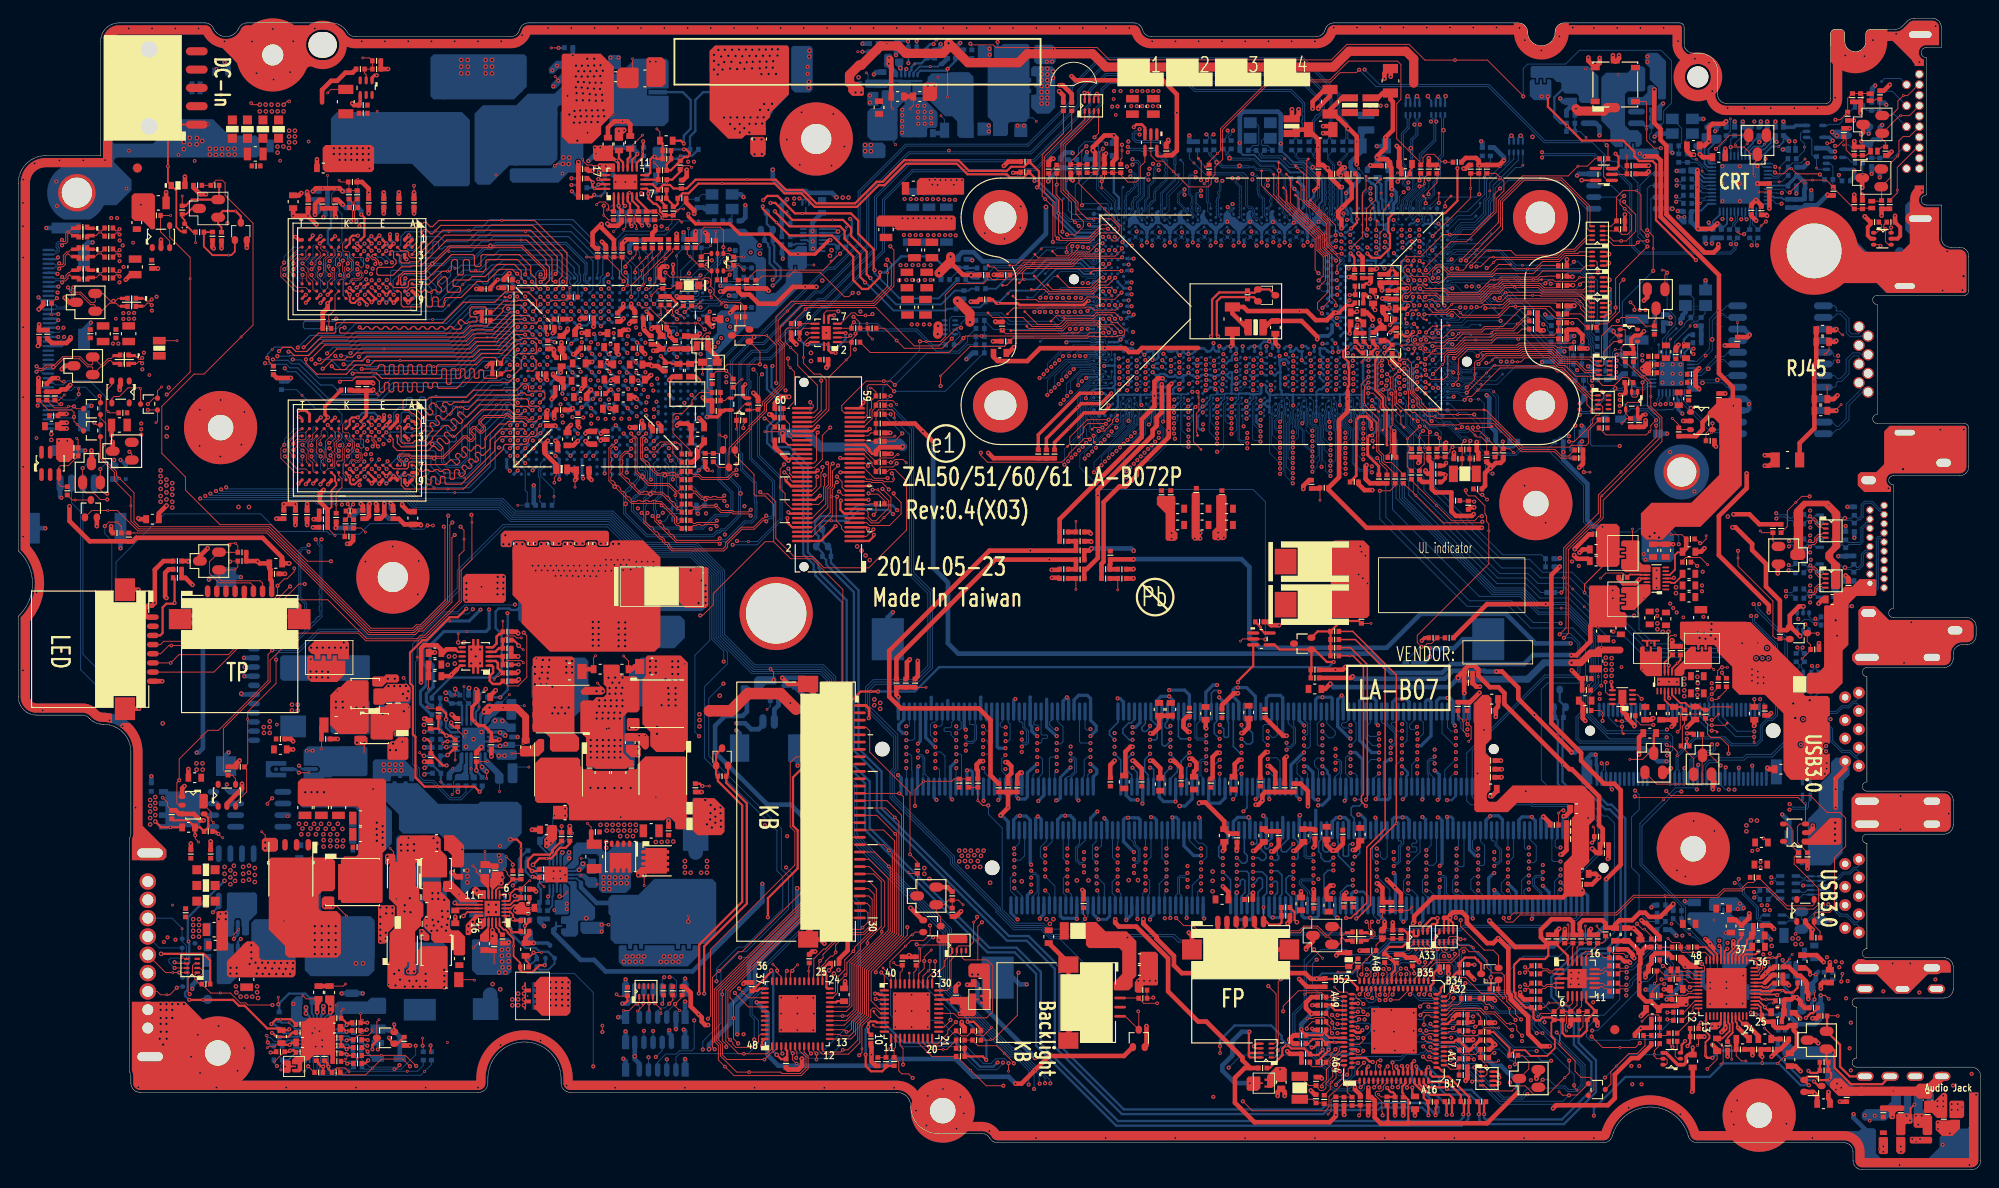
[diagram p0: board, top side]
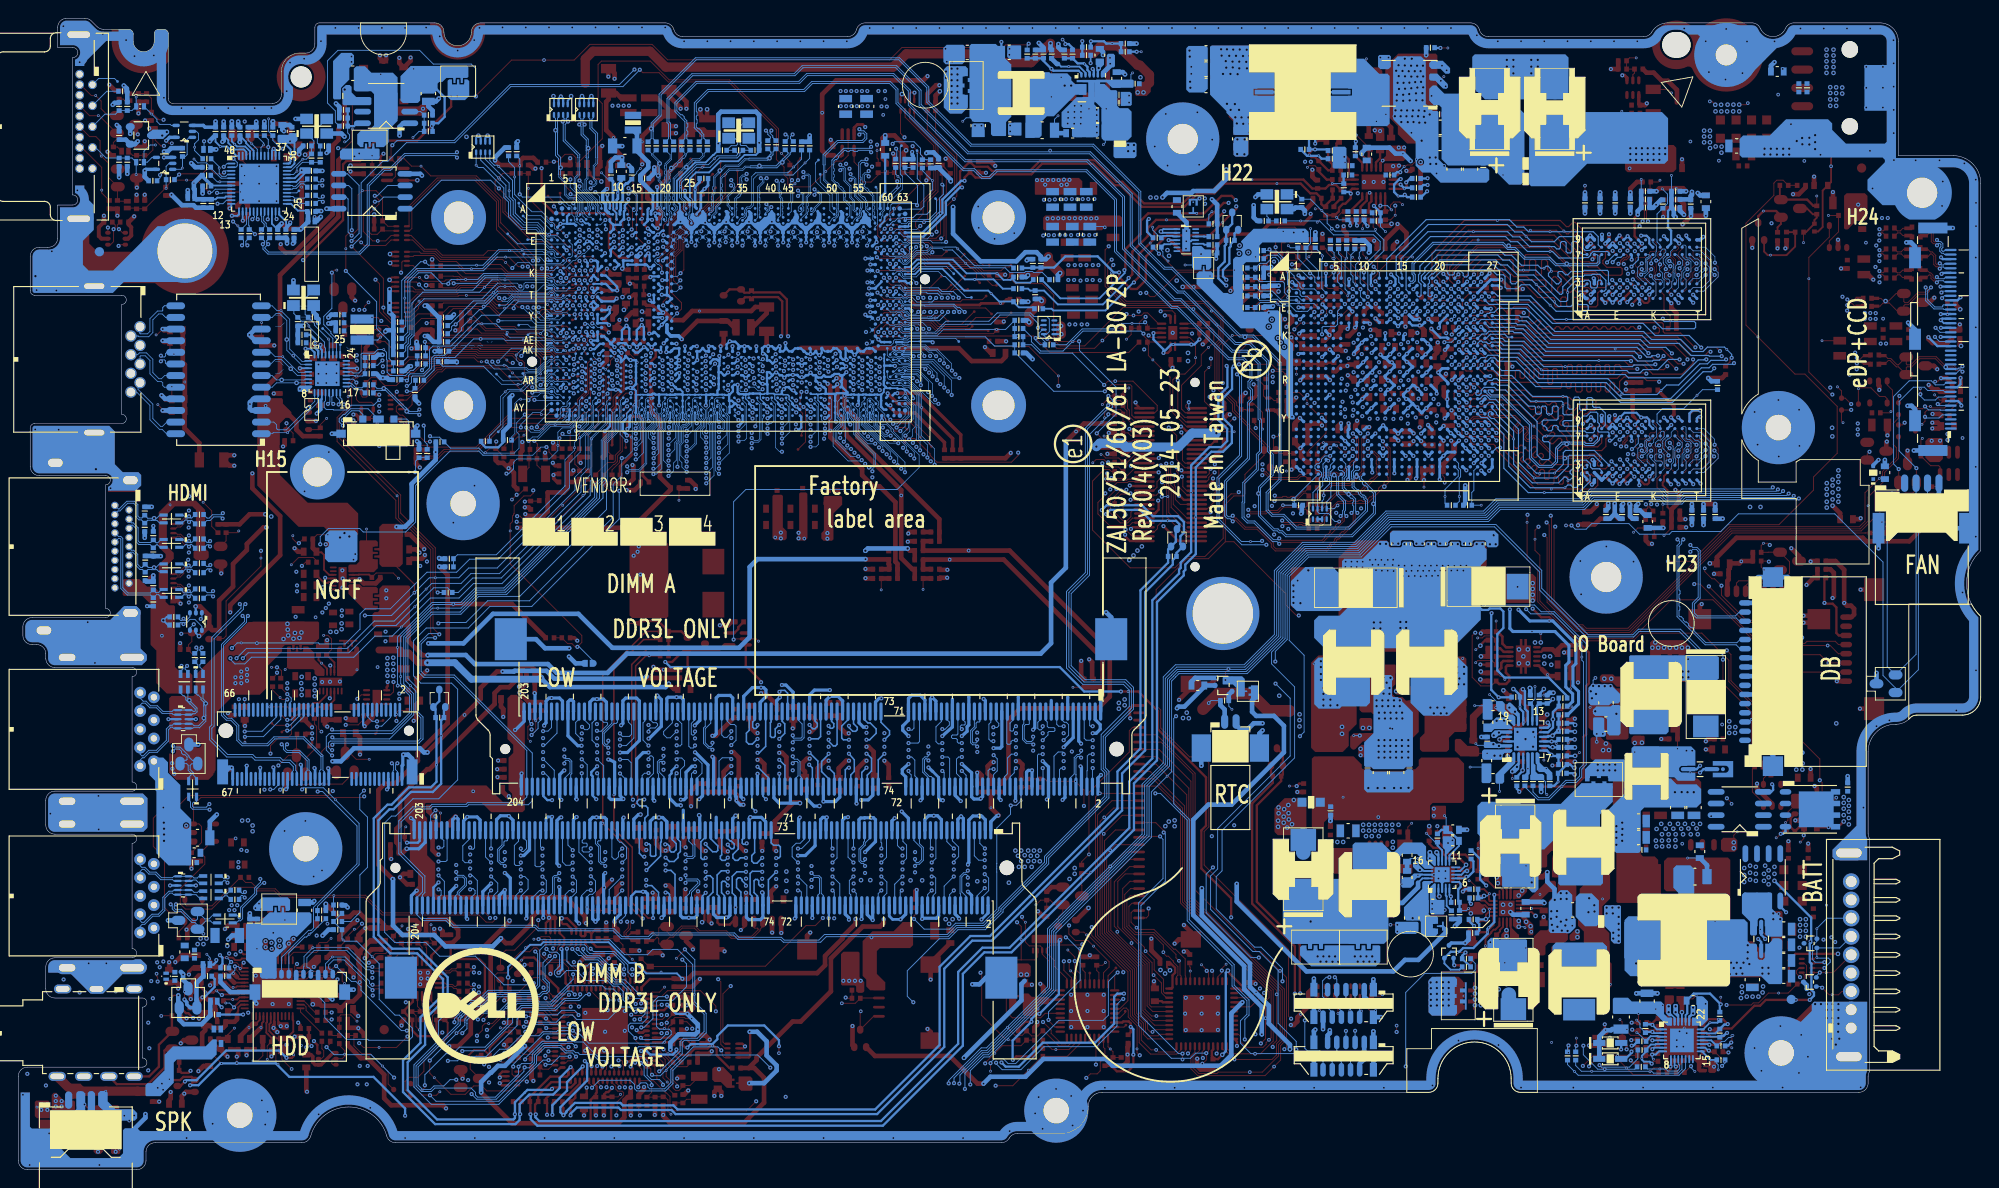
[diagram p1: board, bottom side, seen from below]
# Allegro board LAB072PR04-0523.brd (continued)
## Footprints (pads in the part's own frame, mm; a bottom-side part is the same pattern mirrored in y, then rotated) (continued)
IP4292CZ10-TBR_XSON10_2P5X1
  oval 0.254x0.889 smd: 1(0,0)
  oval 0.254x0.838 smd: 2(0.5,-0.025) 3(1,-0.025) 4(1.5,-0.025) 5(2,-0.025) 6(2,1.125) 7(1.5,1.125) 8(1,1.125) 9(0.5,1.125) 10(0,1.125)
ISL95813HRZ-T_QFN20_3X4
  oval 0.254x0.889 smd: 1(0,0) 2(0.5,0) 3(1,0) 4(1.5,0) 5(2,0) 6(2.5,0) 11(2.5,3.1) 12(2,3.1) 13(1.5,3.1) 14(1,3.1) 15(0.5,3.1) 16(0,3.1)
  oval 0.889x0.254 smd: 7(3.3,0.8) 8(3.3,1.3) 9(3.3,1.8) 10(3.3,2.3) 17(-0.8,2.3) 18(-0.8,1.8) 19(-0.8,1.3) 20(-0.8,0.8)
  rect 2.642x1.651 smd: 21(1.25,1.55)
IT6513FN_QFN48_6X6
  oval 0.203x0.914 smd: 1(0,0) 2(0.4,0) 3(0.8,0) 4(1.2,0) 5(1.6,0) 6(2,0) 7(2.4,0) 8(2.8,0) 9(3.2,0) 10(3.6,0) 11(4,0) 12(4.4,0) 25(4.4,6.075) 26(4,6.075) 27(3.6,6.075) 28(3.2,6.075) 29(2.8,6.075) 30(2.4,6.075) 31(2,6.075) 32(1.6,6.075) 33(1.2,6.075) 34(0.8,6.075) 35(0.4,6.075) 36(0,6.075)
  oval 0.914x0.203 smd: 13(5.237,0.837) 14(5.237,1.237) 15(5.237,1.638) 16(5.237,2.038) 17(5.237,2.437) 18(5.237,2.837) 19(5.237,3.237) 20(5.237,3.638) 21(5.237,4.038) 22(5.237,4.437) 23(5.237,4.837) 24(5.237,5.237) 37(-0.837,5.237) 38(-0.837,4.837) 39(-0.837,4.437) 40(-0.837,4.038) 41(-0.837,3.638) 42(-0.837,3.237) 43(-0.837,2.837) 44(-0.837,2.437) 45(-0.837,2.038) 46(-0.837,1.638) 47(-0.837,1.237) 48(-0.837,0.837)
  rect 4.369x4.369 smd: 49(2.2,3.038)
J-L_TNBNRAC80015008_8P
  round 1.245 hole 0.94: 1(0,0) 2(1.02,-1) 3(2.04,0) 4(3.06,-1) 5(4.08,0) 6(5.1,-1) 7(6.12,0) 8(7.14,-1)
  oval 1.372x2.972 hole 0.61x2.21: 9(-4.43,-5) 10(11.57,-5)
JUMP_43X39
  custom 0.191x0.191 smd: 1(0,0) 2(0.914,0)
JUMP_43X79
  custom 0.188x0.188 smd: 1(0,0) 2(1.1,0)
JUMP_43X118
  custom 0.187x0.187 smd: 1(0,0) 2(1.1,0)
KC_FBMA-L11-201209-221LMA30_2P
  rect 0.838x1.397 smd: 1(0,0) 2(1.65,0)
L2N7002WT1G_SC-70-3
  oval 0.711x0.889 smd: 1(0,0) 2(-0.65,-1.9) 3(0.65,-1.9)
L_5X5X3_M_2P
  rect 2.159x2.794 smd: 1(0,0) 2(4.35,0)
L_7X7X3_M_2P
  rect 2.362x3.505 smd: 1(0,0) 2(6.05,0)
L_10X10X4_M_2P
  rect 3.81x3.988 smd: 1(0,0) 2(9.2,0)
LOTES_APCI0019-P009A_67P
  round 1.092 hole 1.092 unplated: (-0.75,-5.275)
  round 1.6 hole 1.6 unplated: (19.25,-5.275)
  oval 0.305x1.549 smd: 1(0,0) 2(0.25,-7.55) 3(0.5,0) 4(0.75,-7.55) 5(1,0) 6(1.25,-7.55) 7(1.5,0) 8(1.75,-7.55) 9(2,0) 10(2.25,-7.55) 11(2.5,0) 12(2.75,-7.55) 13(3,0) 14(3.25,-7.55) 15(3.5,0) 16(3.75,-7.55) 17(4,0) 18(4.25,-7.55) 19(4.5,0) 20(4.75,-7.55) 21(5,0) 22(5.25,-7.55) 23(5.5,0) 24(7.75,-7.55) 25(8,0) 26(8.25,-7.55) 27(8.5,0) 28(8.75,-7.55) 29(9,0) 30(9.25,-7.55) 31(9.5,0) 32(9.75,-7.55) 33(10,0) 34(10.25,-7.55) 35(10.5,0) 36(10.75,-7.55) 37(11,0) 38(11.25,-7.55) 39(11.5,0) 40(11.75,-7.55) 41(12,0) 42(12.25,-7.55) 43(12.5,0) 44(12.75,-7.55) 45(13,0) 46(13.25,-7.55) 47(13.5,0) 48(13.75,-7.55) 49(14,0) 50(14.25,-7.55) 51(14.5,0) 52(14.75,-7.55) 53(15,0) 54(15.25,-7.55) 55(15.5,0) 56(15.75,-7.55) 57(16,0) 58(16.25,-7.55) 59(16.5,0) 60(16.75,-7.55) 61(17,0) 62(17.25,-7.55) 63(17.5,0) 64(17.75,-7.55) 65(18,0) 66(18.25,-7.55) 67(18.5,0)
  rect 1.194x2.743 smd: 68(-1.1,-0.775) 69(19.6,-0.775)
MC74VHC1G08DFT2G_SC70-5
  oval 0.381x0.711 smd: 1(0,0) 2(0.65,0) 3(1.3,0) 4(1.3,1.9) 5(0,1.9)
MDS1525URH_SO8
  oval 0.635x1.854 smd: 1(0,0) 2(1.27,0) 3(2.54,0) 4(3.81,0) 5(3.81,5.165) 6(2.54,5.165) 7(1.27,5.165) 8(0,5.165)
MDU1511RH_POWERDFN56-8-5
  oval 0.61x1.27 smd: 1(0,0) 2(1.27,0) 3(2.54,0) 4(3.81,0)
  custom 1.105x1.105 smd: 5(1.905,3.715)
MDU1516URH_POWERDFN56-8-5
  oval 0.61x1.27 smd: 1(0,0) 2(1.27,0) 3(2.54,0) 4(3.81,0)
  custom 1.105x1.105 smd: 5(1.905,3.715)
MDV1526URH_PDFN33-8-5
  oval 0.406x0.991 smd: 1(0,0) 2(0.66,0) 3(1.32,0) 4(1.98,0)
  custom 0.559x0.559 smd: 5(0.99,2.248)
MDV1528URH_PDFN33-8-5
  oval 0.406x0.61 smd: 1(0,0) 2(0.65,0) 3(1.3,0) 4(1.95,0)
  custom 0.65x0.65 smd: 5(0.975,1.475)
MEC5085-LZY_DQFN132_11X11
  oval 0.279x0.711 smd: A1(0,0) A2(0.5,0) A3(1,0) A4(1.5,0) A5(2,0) A6(2.5,0) A7(3,0) A8(3.5,0) A9(4,0) A10(4.5,0) A11(5,0) A12(5.5,0) A13(6,0) A14(6.5,0) A15(7,0) A16(7.5,0) A33(7.5,10.9) A34(7,10.9) A35(6.5,10.9) A36(6,10.9) A37(5.5,10.9) A38(5,10.9) A39(4.5,10.9) A40(4,10.9) A41(3.5,10.9) A42(3,10.9) A43(2.5,10.9) A44(2,10.9) A45(1.5,10.9) A46(1,10.9) A47(0.5,10.9) A48(0,10.9)
  oval 0.711x0.279 smd: A17(9.2,1.7) A18(9.2,2.2) A19(9.2,2.7) A20(9.2,3.2) A21(9.2,3.7) A22(9.2,4.2) A23(9.2,4.7) A24(9.2,5.2) A25(9.2,5.7) A26(9.2,6.2) A27(9.2,6.7) A28(9.2,7.2) A29(9.2,7.7) A30(9.2,8.2) A31(9.2,8.7) A32(9.2,9.2) A49(-1.7,9.2) A50(-1.7,8.7) A51(-1.7,8.2) A52(-1.7,7.7) A53(-1.7,7.2) A54(-1.7,6.7) A55(-1.7,6.2) A56(-1.7,5.7) A57(-1.7,5.2) A58(-1.7,4.7) A59(-1.7,4.2) A60(-1.7,3.7) A61(-1.7,3.2) A62(-1.7,2.7) A63(-1.7,2.2) A64(-1.7,1.7)
  oval 0.305x0.61 smd: B1(-0.25,0.85) B2(0.25,0.85) B3(0.75,0.85) B4(1.25,0.85) B5(1.75,0.85) B6(2.25,0.85) B7(2.75,0.85) B8(3.25,0.85) B9(3.75,0.85) B10(4.25,0.85) B11(4.75,0.85) B12(5.25,0.85) B13(5.75,0.85) B14(6.25,0.85) B15(6.75,0.85) B16(7.25,0.85) B17(7.75,0.85) B35(7.75,10.05) B36(7.25,10.05) B37(6.75,10.05) B38(6.25,10.05) B39(5.75,10.05) B40(5.25,10.05) B41(4.75,10.05) B42(4.25,10.05) B43(3.75,10.05) B44(3.25,10.05) B45(2.75,10.05) B46(2.25,10.05) B47(1.75,10.05) B48(1.25,10.05) B49(0.75,10.05) B50(0.25,10.05) B51(-0.25,10.05)
  oval 0.61x0.305 smd: B18(8.35,1.45) B19(8.35,1.95) B20(8.35,2.45) B21(8.35,2.95) B22(8.35,3.45) B23(8.35,3.95) B24(8.35,4.45) B25(8.35,4.95) B26(8.35,5.45) B27(8.35,5.95) B28(8.35,6.45) B29(8.35,6.95) B30(8.35,7.45) B31(8.35,7.95) B32(8.35,8.45) B33(8.35,8.95) B34(8.35,9.45) B52(-0.85,9.45) B53(-0.85,8.95) B54(-0.85,8.45) B55(-0.85,7.95) B56(-0.85,7.45) B57(-0.85,6.95) B58(-0.85,6.45) B59(-0.85,5.95) B60(-0.85,5.45) B61(-0.85,4.95) B62(-0.85,4.45) B63(-0.85,3.95) B64(-0.85,3.45) B65(-0.85,2.95) B66(-0.85,2.45) B67(-0.85,1.95) B68(-0.85,1.45)
  rect 5.004x5.004 smd: C1(3.75,5.45)
MMST3904-7-F_SOT323-3
  oval 0.711x0.889 smd: 1(0,0) 2(0.65,1.9) 3(-0.65,1.9)
MURAT_BLM15AG102SN1D_2P
  rect 0.457x0.508 smd: 1(0,0) 2(0.85,0)
MURAT_BLM15AG121SN1D_L0402_2P
  rect 0.457x0.711 smd: 1(0,0) 2(0.85,0)
MURAT_BLM15BB221SN1D_2P
  rect 0.508x0.762 smd: 1(0,0) 2(0.75,0)
MURAT_BLM15BB470SN1D_2P
  rect 0.508x0.762 smd: 1(0,0) 2(0.75,0)
MURAT_BLM15PD600SN1D_2P
  rect 0.508x0.762 smd: 1(0,0) 2(0.75,0)
MURAT_BLM15PX330SN1D_2P
  rect 0.508x0.762 smd: 1(0,0) 2(0.75,0)
MURAT_BLM18PG300SN1D_2P
  rect 0.66x1.041 smd: 1(0,0) 2(1.2,0)
MURAT_DLW21HN900HQ2L_4P
  rect 0.889x0.356 smd: 1(0,0) 2(1.7,0) 3(1.7,0.85) 4(0,0.85)
MURAT_DLW21SN670HQ2L_4P
  rect 0.889x0.406 smd: 1(0,0) 2(1.7,0) 3(1.7,0.8) 4(0,0.8)
MURAT_LQM2MPN2R2NG0L_2P
  rect 0.787x1.803 smd: 1(0,0) 2(1.6,0)
PANAS_ETQP3W2R2WFN_2P
  rect 2.362x3.505 smd: 1(0,0) 2(-6.05,0)
PI3EQX6741STZDEX_TQFN20_4X4
  oval 0.254x1.143 smd: 1(0,0) 2(0.5,0) 3(1,0) 4(1.5,0) 5(2,0) 11(2,3.851) 12(1.5,3.851) 13(1,3.851) 14(0.5,3.851) 15(0,3.851)
  oval 1.143x0.254 smd: 6(2.925,0.925) 7(2.925,1.425) 8(2.925,1.925) 9(2.925,2.425) 10(2.925,2.925) 16(-0.925,2.925) 17(-0.925,2.425) 18(-0.925,1.925) 19(-0.925,1.425) 20(-0.925,0.925)
  rect 2.108x2.108 smd: 21(1,1.925)
PJDLC05C_SOT23-3
  oval 1.016x1.524 smd: 1(0,0) 2(0.965,2.083) 3(-0.965,2.083)
R0402_0OHM
  rect 0.508x0.559 smd: 1(0,0) 2(0.914,0)
R0603_0OHM
  rect 0.635x0.889 smd: 1(0,0) 2(1.397,0)
R0805_0OHM
  rect 0.813x1.397 smd: 1(0,0) 2(1.702,0)
R_0402
  rect 0.508x0.559 smd: 1(0,0) 2(0.914,0)
R_0603
  rect 0.635x0.889 smd: 1(0,0) 2(1.397,0)
R_0805
  rect 0.813x1.397 smd: 1(0,0) 2(1.702,0)
R_1206
  rect 1.016x1.651 smd: 1(0,0) 2(2.667,0)
R_1206_4P-D
  custom 0.445x0.445 smd: 1(0,0) 4(5.004,0)
  custom 0.114x0.114 smd: 2(1.194,0) 3(3.81,0)
RB751S40T1G_SOD523-2
  rect 0.406x0.406 smd: 1(0,0) 2(1.4,0)
RB751V-40_SOD323-2
  rect 0.787x0.889 smd: 1(0,0) 2(2.14,0)
RP_0804_8P4R
  oval 0.66x0.254 smd: 1(0,0) 2(0,-0.5) 3(0,-1) 4(0,-1.5) 5(1.15,-1.5) 6(1.15,-1) 7(1.15,-0.5) 8(1.15,0)
RT8813AGQW_WQFN24_4X4
  oval 0.254x1.041 smd: 1(0,0) 2(0.5,0) 3(1,0) 4(1.5,0) 5(2,0) 6(2.5,0) 13(2.5,3.95) 14(2,3.95) 15(1.5,3.95) 16(1,3.95) 17(0.5,3.95) 18(0,3.95)
  oval 1.041x0.254 smd: 7(3.225,0.725) 8(3.225,1.225) 9(3.225,1.725) 10(3.225,2.225) 11(3.225,2.725) 12(3.225,3.225) 19(-0.725,3.225) 20(-0.725,2.725) 21(-0.725,2.225) 22(-0.725,1.725) 23(-0.725,1.225) 24(-0.725,0.725)
  rect 2.515x2.515 smd: 25(1.25,1.975)
RTL8106E-CG_QFN32_4X4
  oval 0.203x0.838 smd: 1(0,0) 2(0.4,0) 3(0.8,0) 4(1.2,0) 5(1.6,0) 6(2,0) 7(2.4,0) 8(2.8,0) 17(2.8,4.15) 18(2.4,4.15) 19(2,4.15) 20(1.6,4.15) 21(1.2,4.15) 22(0.8,4.15) 23(0.4,4.15) 24(0,4.15)
  oval 0.838x0.203 smd: 9(3.475,0.675) 10(3.475,1.075) 11(3.475,1.475) 12(3.475,1.875) 13(3.475,2.275) 14(3.475,2.675) 15(3.475,3.075) 16(3.475,3.475) 25(-0.675,3.475) 26(-0.675,3.075) 27(-0.675,2.675) 28(-0.675,2.275) 29(-0.675,1.875) 30(-0.675,1.475) 31(-0.675,1.075) 32(-0.675,0.675)
  rect 2.692x2.692 smd: 33(1.4,2.075)
SAMTE_BSH-030-01-L-D-A_60P
  round 1.016 hole 1.016 unplated: (-2.81,5.53) (17.316,5.53)
  oval 0.279x2.261 smd: 1(0,0) 2(0,5.728) 3(0.5,0) 4(0.5,5.728) 5(1,0) 6(1,5.728) 7(1.5,0) 8(1.5,5.728) 9(2,0) 10(2,5.728) 11(2.5,0) 12(2.5,5.728) 13(3,0) 14(3,5.728) 15(3.5,0) 16(3.5,5.728) 17(4,0) 18(4,5.728) 19(4.5,0) 20(4.5,5.728) 21(5,0) 22(5,5.728) 23(5.5,0) 24(5.5,5.728) 25(6,0) 26(6,5.728) 27(6.5,0) 28(6.5,5.728) 29(7,0) 30(7,5.728) 31(7.5,0) 32(7.5,5.728) 33(8,0) 34(8,5.728) 35(8.5,0) 36(8.5,5.728) 37(9,0) 38(9,5.728) 39(9.5,0) 40(9.5,5.728) 41(10,0) 42(10,5.728) 43(10.5,0) 44(10.5,5.728) 45(11,0) 46(11,5.728) 47(11.5,0) 48(11.5,5.728) 49(12,0) 50(12,5.728) 51(12.5,0) 52(12.5,5.728) 53(13,0) 54(13,5.728) 55(13.5,0) 56(13.5,5.728) 57(14,0) 58(14,5.728) 59(14.5,0) 60(14.5,5.728)
SDMK0340L-7-F_SOD323-2
  rect 1.346x0.66 smd: 1(0,0) 2(2.4,0)
SHORTPADS
  custom 0.19x0.19 smd: 1(-0.483,0) 2(0.483,0)
SI3457CDV-T1-GE3_TSOP6
  oval 0.508x1.422 smd: 1(0,0) 2(0.95,0) 3(1.9,0) 4(1.9,2.44) 5(0.95,2.44) 6(0,2.44)
SINGA_2SJ3080-001111F_6P
  oval 0.991x1.905 hole 0.61x1.499: 1(0,0) 2(-9.55,5.5) 3(0,7.8) 4(-9.55,8.4) 5(-9.55,0) 6(-9.55,2.75) 7(0,4.1)
SIR472DP-T1-GE3_POWERPAK8-5
  oval 0.61x1.27 smd: 1(0,0) 2(1.27,0) 3(2.54,0) 4(3.81,0)
  custom 1.105x1.105 smd: 5(1.905,3.36)
SIRA06DP-T1-GE_POWERPAKSO-8-5
  oval 0.61x1.27 smd: 1(0,0) 2(1.27,0) 3(2.54,0) 4(3.81,0)
  custom 1.105x1.105 smd: 5(1.905,3.715)
SIS412DN-T1-GE3_POWERPAK8-5
  oval 0.406x0.991 smd: 1(0,0) 2(0.66,0) 3(1.32,0) 4(1.98,0)
  custom 0.559x0.559 smd: 5(0.99,2.247)
SW_SMT1-05-A_4P
  rect 0.61x0.991 smd: 1(0,0) 2(0,-4.4) 3(3.7,0) 4(3.7,-4.4)
  rect 0.457x0.991 smd: 5(-0.675,-2.2) 6(4.375,-2.2)
SW_SSAL120100_3P
  rect 0.787x0.787 smd: 1(0,0) 3(3.4,0)
  rect 1.194x0.787 smd: 2(1.7,0)
  rect 1.041x0.889 smd: 4(-2.375,-1.6) 5(5.775,-1.6)
SY6288C20AAC_SOT23-5
  oval 0.559x0.787 smd: 1(0,0) 2(0.95,0) 3(1.9,0) 4(1.9,2.4) 5(0,2.4)
SY6288D20AAC_SOT23-5
  oval 0.559x0.787 smd: 1(0,0) 2(0.95,0) 3(1.9,0) 4(1.9,2.4) 5(0,2.4)
SY8206DQNC_QFN10_3X3
  oval 0.254x0.61 smd: 1(0,0) 2(0.45,0) 3(0.9,0) 4(1.35,0) 5(1.8,0) 6(2.25,0)
  rect 1.168x0.254 smd: 7(2.19,-0.675)
  rect 0.914x2.007 smd: 8(2.065,-2)
  custom 0.482x0.482 smd: 9(1.077,-1.775)
  rect 0.813x1.168 smd: 10(0.137,-1.587)
TAI-T_HCB1608KF-121T3_L0603_2P
  rect 0.991x0.787 smd: 1(0,0) 2(1.6,0)
TAI-T_HCB2012KF-121T50_2P
  rect 0.991x0.991 smd: 1(0,0) 2(2,0)
TAIMA_IH-115-F_24P
  oval 0.762x2.057 smd: 1(0,0) 2(1.27,0) 3(2.54,0) 4(3.81,0) 5(5.08,0) 6(6.35,0) 7(7.62,0) 8(8.89,0) 9(10.16,0) 10(11.43,0) 11(12.7,0) 12(13.97,0) 13(13.97,9.365) 14(12.7,9.365) 15(11.43,9.365) 16(10.16,9.365) 17(8.89,9.365) 18(7.62,9.365) 19(6.35,9.365) 20(5.08,9.365) 21(3.81,9.365) 22(2.54,9.365) 23(1.27,9.365) 24(0,9.365)
TAITW_PUBAU6-09FLBS1NN4H0_9P
  round 1.295 hole 0.711: 1(0,0) 2(-2.5,0) 3(-4.5,0) 4(-7,0) 5(-7.5,-1.5) 6(-5.5,-1.5) 7(-3.5,-1.5) 8(-1.5,-1.5) 9(0.5,-1.5)
  oval 1.397x3.2 hole 0.787x2.591: 10(4.35,-2.38) 12(-11.35,-2.38)
  oval 1.397x2.388 hole 0.787x1.803: 11(4.35,-9.48) 13(-11.35,-9.48)
TPC12
  round 0.305 smd: 1(0,0)
TPS22966DPUR_SON14_2X3
  oval 0.203x0.762 smd: 1(0,0) 2(0.4,0) 3(0.8,0) 4(1.2,0) 5(1.6,0) 6(2,0) 7(2.4,0) 8(2.4,2.05) 9(2,2.05) 10(1.6,2.05) 11(1.2,2.05) 12(0.8,2.05) 13(0.4,2.05) 14(0,2.05)
  rect 2.489x0.889 smd: 15(1.2,1.025)
TPS22967DSGR_SON8_2X2
  oval 0.254x0.787 smd: 1(0,0) 2(0.5,0) 3(1,0) 4(1.5,0) 5(1.5,2.2) 6(1,2.2) 7(0.5,2.2) 8(0,2.2)
  rect 1.6x0.889 smd: 9(0.75,1.1)
TPS51212DSCR_SON10_3X3
  oval 0.279x0.838 smd: 1(0,0) 2(0.5,0) 3(1,0) 4(1.5,0) 5(2,0) 6(2,2.95) 7(1.5,2.95) 8(1,2.95) 9(0.5,2.95) 10(0,2.95)
  custom 0.413x0.413 smd: 11(1,1.475)
TPS51285BRUKR_QFN20_3X3
  oval 0.203x1.016 smd: 1(0,0) 2(0.4,0) 3(0.8,0) 4(1.2,0) 5(1.6,0) 11(1.6,2.975) 12(1.2,2.975) 13(0.8,2.975) 14(0.4,2.975) 15(0,2.975)
  oval 1.016x0.203 smd: 6(2.288,0.688) 7(2.288,1.088) 8(2.288,1.488) 9(2.288,1.888) 10(2.288,2.288) 16(-0.688,2.288) 17(-0.688,1.888) 18(-0.688,1.488) 19(-0.688,1.088) 20(-0.688,0.688)
  rect 1.702x1.702 smd: 21(0.8,1.488)
TVNST52302AB0_SOT523-3
  oval 0.508x0.559 smd: 1(0,0) 2(-0.5,-1.4) 3(0.5,-1.4)
W25Q64FVSSIQ_SO8
  oval 0.635x1.676 smd: 1(0,0) 2(1.27,0) 3(2.54,0) 4(3.81,0) 5(3.81,7.25) 6(2.54,7.25) 7(1.27,7.25) 8(0,7.25)
Y_7V25000014_4P
  rect 1.397x1.194 smd: 1(0,0) 2(2.2,0) 3(2.2,1.7) 4(0,1.7)
Y_9H03220008_2P
  rect 0.991x1.803 smd: 1(0,0) 2(2.5,0)
Y_Q13FC135000040_2P
  rect 0.991x1.803 smd: 1(0,0) 2(2.5,0)
Y_X1E000021042600_4P
  rect 1.397x1.143 smd: 1(0,0) 2(2.2,0) 3(2.2,1.6) 4(0,1.6)
Y_X3G024000DC1H_4P
  rect 1.397x1.194 smd: 1(0,0) 2(2.2,0) 3(2.2,1.7) 4(0,1.7)

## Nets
0.675V_DDR_VTT_ON: PR202.1 QD2.2 R2347.2 R2351.2 U2303.4
1.35V_B+: PC201.1 PC206.1 PC208.1 PC212.1 PL201.2 PQ200.5 PR208.1
3/5V_B+: PC105.1 PC112.1 PC113.1 PC114.1 PC115.1 PL102.2 PL103.2 PQ101.5 PQ103.5 PU100.12
3V3_MAIN_EN: PR608.2 RV185.1 RV188.2 UV1.A3
3V3_MAIN_EN_R: RV185.2 UV15.3
3V_DSW: PJP512.2 U2304.8 U2304.9
3V_EN: PD101.2 PR100.1 PU100.6
3VALW_PCH: PJP513.2 U2304.13 U2304.14
3VS: PJP511.2 U2301.13 U2301.14
3VS_GATE: C2322.1 R2318.2 U2301.3
5V_EN: PD101.3 PR101.1 PU100.20
5VS: PJP510.2 U2301.8 U2301.9
5VS_GATE: C2309.1 R2313.2 U2301.5
+0.675VS: CD24.1 CD25.1 CD26.1 CD27.1 CD28.1 CD29.1 CD54.1 CD55.1 CD56.1 CD57.1 CD58.1 CD59.1 JDIMM1.203 JDIMM1.204 JDIMM2.203 JDIMM2.204 PJP203.2 R2314.1
+0.675VSP: PC205.1 PC211.1 PJP203.1 PU200.2 PU200.20
+1.05V_LDO_3V: PC312.1 PR304.1 PU300.5
+1.05V_PEX_VDD: CV16.1 CV36.1 CV63.1 CV65.1 CV135.1 CV205.1 CV211.1 LV8.1 LV10.1 LV26.1 PJP31.1 UV1.AA10 UV1.AA12 UV1.AA13 UV1.AA14 UV1.AA15 UV1.AA16 UV1.AA18 UV1.AA19 UV1.AA20 UV1.AA21 UV1.AA22 UV1.AB22 UV1.AB23 UV1.AC23 UV1.AC24 UV1.AD24 UV1.AD25 UV1.AE25 UV1.AE26 UV1.AE27 UV1.AF26 UV1.AF27
+1.05V_PEX_VDD_UV15: CV139.1 PJP31.2 UV15.13 UV15.14
+1.05V_PGOOD: PR308.2 PU300.2
+1.05VS: C43.1 C44.1 C50.1 C53.1 C57.1 C60.1 C61.1 C62.1 C66.1 C67.1 C76.1 C87.1 C88.1 CC14.1 CC15.1 CC28.1 CE50.1 JXDP.43 JXDP.44 L1.1 L2.1 L3.1 L4.1 L5.1 PC548.2 PJP300.2 PR500.1 PR504.1 R245.1 R252.1 R253.2 R256.1 R267.1 R2353.1 RC58.1 RC60.1 RC130.2 RC363.1 RC365.2 RC366.2 RE70.1 RP44.5 RP44.6 RP44.7 RP44.8 RP48.1 RP48.2 RP48.3 UC1.AC22 UC1.AE8 UC1.AE9 UC1.AE22 UC1.AE23 UC1.AF9 UC1.AF22 UC1.AG8 UC1.AG13 UC1.AG14 UC1.AG16 UC1.AG17 UC1.H11 UC1.H15 UC1.J11 UC1.J17 UC1.K9 UC1.L10 UC1.M9 UC1.N8 UC1.P9 UC1.R21 UC1.T21 UE5.B51 UV15.1 UV15.2
+1.5VS: PJP401.2 RA8.1 UC1.J15
+1.05VS_APLLOPI: C69.1 C70.1 L3.2 R267.2 UC1.AA21 UC1.W21
+1.05VS_ASATA3PLL: C63.1 C65.1 L2.2 RC126.2 RC131.2 UC1.B11
+1.05VS_AUSB3PLL: C58.1 C59.1 L1.2 RC91.1 UC1.B18 UC1.B27
+1.05VSP: PC307.1 PC308.1 PC309.1 PC310.1 PC311.1 PJP300.1 PL301.2 PR305.1
+1.5VSP: PC403.1 PC404.1 PJP401.1 PR400.1 PU400.3 PU400.4
+1.8V_VGA: CV361.1 LV14.1 LV15.1 LV21.1 UV6.38 UV6.39
+1.8V_VGA_IVDD: CV336.1 CV337.1 CV343.1 CV355.1 CV359.1 LV15.2 UV6.12 UV6.14 UV6.24 UV6.44 UV6.46
+1.8V_VGA_PVCC: CV351.1 CV352.1 CV353.1 CV354.1 LV14.2 UV6.22 UV6.25 UV6.31 UV6.32
+1.8V_VGA_VDD: CV338.1 CV339.1 CV341.2 CV360.1 LV21.2 UV6.7 UV6.10
+1.35V: C35.1 C36.1 C37.1 C38.1 C39.1 C40.2 C41.1 C42.1 C43.2 C45.1 C72.1 C74.1 CD4.1 CD5.1 CD6.1 CD7.1 CD8.1 CD9.1 CD10.1 CD11.1 CD12.1 CD13.1 CD14.1 CD15.1 CD16.1 CD17.1 CD18.1 CD19.1 CD20.1 CD23.1 CD35.1 CD36.1 CD37.1 CD38.1 CD39.1 CD40.1 CD41.1 CD42.1 CD43.1 CD44.1 CD45.1 CD46.1 CD47.1 CD48.1 CD49.1 CD50.1 CD51.1 CD62.2 JDIMM1.75 JDIMM1.76 JDIMM1.81 JDIMM1.82 JDIMM1.87 JDIMM1.88 JDIMM1.93 JDIMM1.94 JDIMM1.99 JDIMM1.100 JDIMM1.105 JDIMM1.106 JDIMM1.111 JDIMM1.112 JDIMM1.117 JDIMM1.118 JDIMM1.123 JDIMM1.124 JDIMM2.75 JDIMM2.76 JDIMM2.81 JDIMM2.82 JDIMM2.87 JDIMM2.88 JDIMM2.93 JDIMM2.94 JDIMM2.99 JDIMM2.100 JDIMM2.105 JDIMM2.106 JDIMM2.111 JDIMM2.112 JDIMM2.117 JDIMM2.118 JDIMM2.123 JDIMM2.124 PJP200.2 PJP201.2 QD2.1 RC14.1 RC15.1 RC16.1 RD3.1 U2303.5 UC1.AH26 UC1.AJ31 UC1.AJ33 UC1.AJ37 UC1.AN33 UC1.AP43 UC1.AR48 UC1.AY35 UC1.AY40 UC1.AY44 UC1.AY50
+1.35VGPUP: PC1008.1 PJP1000.1 PL1001.2 PR1006.2
+1.35VP: PC214.1 PC299.1 PJP200.1 PJP201.1 PL200.1 PR207.2 PU200.5 PU200.19
+1.35VS_VGA: CV15.1 CV24.1 CV39.1 CV42.1 CV43.1 CV47.1 CV131.1 CV132.1 CV136.1 CV143.1 CV151.1 CV158.1 CV161.1 CV163.1 CV165.1 CV168.1 CV170.1 CV172.1 CV173.1 CV174.1 CV178.1 CV179.1 CV180.1 CV181.1 CV183.1 CV184.1 CV186.1 CV187.1 CV196.1 CV197.1 CV203.1 CV204.1 CV208.1 CV209.1 CV210.1 CV215.1 PJP1000.2 RV42.2 RV46.2 RV130.2 RV139.1 RV144.1 RV149.1 RV150.1 UV1.B26 UV1.C25 UV1.E23 UV1.E26 UV1.F14 UV1.F21 UV1.G13 UV1.G14 UV1.G15 UV1.G16 UV1.G18 UV1.G19 UV1.G20 UV1.G21 UV1.H24 UV1.H26 UV1.J21 UV1.K21 UV1.L22 UV1.L24 UV1.L26 UV1.M21 UV1.N21 UV1.R21 UV1.T21 UV1.V21 UV1.W21 UV17.A1 UV17.A8 UV17.B2 UV17.C1 UV17.C9 UV17.D2 UV17.D9 UV17.E9 UV17.F1 UV17.G7 UV17.H2 UV17.H9 UV17.K2 UV17.K8 UV17.N1 UV17.N9 UV17.R1 UV17.R9 UV18.A1 UV18.A8 UV18.B2 UV18.C1 UV18.C9 UV18.D2 UV18.D9 UV18.E9 UV18.F1 UV18.G7 UV18.H2 UV18.H9 UV18.K2 UV18.K8 UV18.N1 UV18.N9 UV18.R1 UV18.R9 UV19.A1 UV19.A8 UV19.B2 UV19.C1 UV19.C9 UV19.D2 UV19.D9 UV19.E9 UV19.F1 UV19.G7 UV19.H2 UV19.H9 UV19.K2 UV19.K8 UV19.N1 UV19.N9 UV19.R1 UV19.R9 UV20.A1 UV20.A8 UV20.B2 UV20.C1 UV20.C9 UV20.D2 UV20.D9 UV20.E9 UV20.F1 UV20.G7 UV20.H2 UV20.H9 UV20.K2 UV20.K8 UV20.N1 UV20.N9 UV20.R1 UV20.R9
+3.3V_ALW_DEG: JDEG.1 RE76.2
+3.3V_BIO: CS28.1 JFP.6 RS39.2
+3.3V_RUN_GFX: CV30.1 CV40.1 CV64.1 CV68.1 CV129.1 CV130.1 CV159.1 CV160.1 CV164.1 CV198.1 CV199.1 PJP30.2 PR600.2 PR621.1 RPV3.1 RPV3.2 RPV3.3 RPV3.4 RV47.2 RV49.2 RV51.1 RV94.2 RV97.2 RV98.2 RV103.1 RV104.2 RV122.2 RV123.2 RV124.2 RV125.2 RV188.1 RV189.1 RV190.1 RV191.2 RV192.2 RV195.1 RV253.2 UV1.AA8 UV1.AA9 UV1.AB8 UV1.G8 UV1.G9 UV1.G10 UV1.G12 UV14.5
+3.3V_RUN_GFX_UV15: CV142.2 PJP30.1 UV15.8 UV15.9
+3V_DSW: C1313.1 C2328.1 C2329.1 PJP512.1 RC32.1 RC34.1 RC39.1 RC153.1 UC1.AH10
+3V_DSW_GATE: C2325.1 R2451.2 U2304.5
+3VA: CA57.1 CA58.1 CA59.1 CA60.1 CA77.1 RA10.2 RA1120.2 RA1125.2 RA1130.1 UA1.1 UA1.9 UA1.36
+3VALW: C2311.1 C2313.1 C2315.1 C2316.1 C2317.1 C2318.1 C5254.1 C5255.1 C5256.1 CC41.1 CE4.1 CE42.1 CL39.1 CX7.1 CZ49.1 JLED.3 PJP14.1 PJP15.1 PJP100.2 PJP400.1 PR2.1 PR4.2 PR310.2 QX5.3 RL41.2 RX30.2 U2301.1 U2301.2 U2304.1 U2304.2 U2304.4 U2304.6 U2304.7 U2412.4 U2412.24 U2412.37 UC6.5 UL2.5 UM1.1 UM1.2 UM1.4 UV15.6 UV15.7 UX1.5
+3VALW_1099: CE3.1 CE10.1 PJP14.2 RE13.1 RE14.1 RE35.1 RE89.2 RE279.2 RPE9.5 RPE9.6 RPE9.7 RPE9.8 UE4.8 UE4.28
+3VALW_5085: CE14.1 CE17.1 CE38.1 CE40.1 CE41.1 CE43.1 CE44.1 CE46.1 CE63.1 CE64.1 PJP15.2 RE25.1 RE38.1 RE39.1 RE45.1 RE65.1 RE69.1 RE72.1 RE74.1 RE75.1 RE76.1 RE79.1 RE81.1 RPE3.7 RPE3.8 RPE5.8 RPE6.7 RPE6.8 RPE7.5 RPE7.6 RPE7.7 RPE7.8 UE5.A11 UE5.A22 UE5.A26 UE5.A41 UE5.A52 UE5.A58 UE5.B3 UE5.B35
+3VALW_PCH: C78.1 C81.1 C2310.1 C2312.1 PJP513.1 R264.1 R2329.1 R2330.1 R2527.2 R2528.2 RC9.1 RC27.1 RC28.1 RC29.1 RC64.2 RC103.2 RC105.2 RC109.2 RC117.2 RC120.1 RC127.1 RP40.5 RP40.6 RP40.7 RP40.8 RP55.5 RP55.6 RP55.7 RP55.8 UC1.AA9 UC1.AC9 UC1.AE20 UC1.AE21
+3VALW_PCH_GATE: C2314.1 R416.2 U2304.3
+3VALWP: PC101.1 PC102.1 PC116.1 PJP100.1 PL100.1 PR109.1 PR115.2
+3VLP: PC109.1 PJP12.1 PU100.3 RE57.2
+3VS: C44.2 C68.1 C71.1 C73.1 C82.1 C2323.1 C2324.1 C2327.1 CC11.1 CC13.1 CD30.1 CD31.1 CD60.1 CD61.1 CD62.1 CI50.1 CS27.1 CS29.1 CX10.1 JDIMM1.199 JDIMM2.199 JIO.6 JLPDE.1 JLPDE.2 PJP511.1 PR308.1 PR519.1 PR624.2 PR1000.1 Q327.2 QC1.2 QC1.5 QV5.2 QX4.2 QX4.5 R246.2 R2331.1 R2332.1 R2334.1 R2335.1 R2340.1 R2341.1 R2342.1 R2343.1 R2344.1 R2345.1 RA1125.1 RC36.1 RC75.1 RC95.1 RC98.1 RC102.1 RC106.1 RC108.1 RC111.1 RC116.2 RC118.1 RC119.1 RC121.1 RC362.1 RC370.1 RC372.2 RC373.1 RD12.2 RE48.1 RE50.1 RE67.1 RL33.1 RM7.1 RN5.2 RP37.5 RP37.6 RP37.7 RP37.8 RP43.1 RP43.2 RP43.3 RP43.4 RP51.5 RP51.8 RP52.5 RP52.6 RP52.7 RP52.8 RP53.5 RP53.6 RP53.7 RP53.8 RP60.1 RP60.2 RP60.3 RP60.4 RPE3.5 RPE3.6 RS19.1 RS21.1 RS22.1 RS24.1 RS30.1 RS36.1 RS39.1 RS41.1 RS43.1 RV18.2 RV214.1 RX12.1 RX13.1 U2302.8 UC1.K14 UC1.K16 UC1.T9 UC1.U8 UC1.V8 UC1.W9 UC1.Y8 UC3.5 UC4.14 UC5.5 US2.10 US2.20
+3VS_CAM: CX20.1 JEDP.12 QX5.1
+3VS_TP: CE68.1 JTP.8 R246.1 R2521.1 R2522.1
+3VS_VGA: CV340.1 CV356.1 CV357.1 CV358.1 QV89.2 QV89.5 RV161.1 RV162.1 RV214.2 RV215.2 RV516.1 RV517.1 RV518.1 UV6.13 UV6.35 UV6.36 UV6.48
+3VS_WLAN_NGFF: CM3.2 CM4.1 CM5.1 CM6.1 CM7.1 JNGFF.2 JNGFF.4 JNGFF.64 JNGFF.66 RM7.2 UM1.7 UM1.8
+5V_HDD: CS5.1 CS6.1 CS7.1 JHDD.1 JHDD.2 PJP13.1
+5V_PVDD: CA53.1 CA54.1 CA55.1 CA56.1 RA1110.2 UA1.41 UA1.46
+5V_USB_PWR1: CI1.1 CI2.1 CI40.1 JUSB1.1 UI3.1
+5V_USB_PWR2: CI8.1 CI9.1 CI43.1 JUSB2.1 UI2.1
+5V_USB_PWR3: CI48.1 CI49.1 JIO.1 JIO.2 JIO.3 JIO.4 UI4.1
+5VA: CA51.1 CA71.1 RA1111.2 UA1.26
+5VALW: C2305.1 C2306.1 CI6.1 CI12.1 CI44.1 CZ51.1 JLED.1 PC204.2 PC400.1 PC1006.1 PJP101.2 PJP103.2 PR7.2 PR206.1 PU200.12 PU400.6 PU1000.7 R10.1 R2347.1 U2301.4 U2301.6 U2301.7 UI2.5 UI3.5 UI4.5 UV15.4
+5VALWP: PC107.1 PC108.2 PC117.1 PJP101.1 PJP103.1 PL101.1 PR104.2 PU100.14
+5VS: C7.1 C2307.1 C2308.1 C5261.1 CX51.1 CZ50.1 D1.1 F1.1 FX1.2 JFAN.1 PC528.1 PJP13.2 PJP510.1 PR623.2 PU501.12 Q330.3 Q2416.2 R990.2 RA1110.1 RA1111.1 RX28.2 RX31.2 UV4.1 UX3.5
+5VS_KBL: C5262.1 C5263.1 F1.2 JKBBL.1
+5VS_TOUCH: CX6.1 CX49.1 CX50.1 JEDP.19 RX28.1 UX3.1
+VCC_PWR_SRC: PC516.1 PC517.1 PC518.1 PC519.1 PC521.1 PC524.1 PC532.1 PC534.1 PL501.1 PL504.1 PQ501.1
+VCCHDA: C77.1 RC127.2 UC1.AH14
+VCCIO_OUT: R245.2 UC1.A59
+VCCIOA_OUT: RC71.1 UC1.E20
+VCCRTCEXT: C52.1 UC1.AE7
GND: C7.2 C35.2 C36.2 C37.2 C38.2 C39.2 C41.2 C42.2 C45.2 C50.2 C51.2 C52.2 C53.2 C54.2 C55.2 C56.2 C57.2 C58.2 C59.2 C60.2 C61.2 C62.2 C63.2 C64.2 C65.2 C66.2 C67.2 C68.2 C69.2 C70.2 C71.2 C72.2 C73.2 C74.2 C76.2 C77.2 C78.2 C80.2 C81.2 C82.2 C83.2 C84.2 C85.2 C86.2 C87.2 C88.2 C1160.2 C2305.2 C2306.2 C2307.2 C2308.2 C2309.2 C2310.2 C2311.2 C2312.2 C2313.2 C2314.2 C2315.2 C2316.2 C2317.2 C2318.2 C2322.2 C2323.2 C2324.2 C2325.2 C2326.2 C2327.2 C2328.2 C2329.2 C5212.2 C5254.2 C5255.2 C5256.2 C5259.2 C5261.2 C5262.2 C5263.2 C5291.2 C5292.2 C5293.2 CA21.2 CA22.2 CA25.1 CA26.2 CA29.2 CA30.2 CA31.2 CA32.2 CA38.2 CA40.2 CA53.2 CA54.2 CA55.2 CA56.2 CA57.2 CA58.2 CA59.2 CA60.2 CA64.1 CA69.2 CA76.2 CA77.2 CC1.1 CC2.1 CC3.1 CC4.1 CC5.2 CC6.1 CC7.1 CC11.2 CC13.2 CC14.2 CC15.2 CC16.2 CC17.2 CC26.2 CC27.2 CC28.2 CC29.2 CC31.2 CC33.2 CC34.2 CC35.2 CC41.2 CC42.2 CD1.2 CD2.2 CD3.2 CD4.2 CD5.2 CD6.2 CD7.2 CD8.2 CD9.2 CD10.2 CD11.2 CD12.2 CD13.2 CD14.2 CD15.2 CD16.2 CD17.2 CD18.2 CD19.2 CD20.2 CD21.2 CD22.2 CD23.2 CD24.2 CD25.2 CD26.2 CD27.2 CD28.2 CD29.2 CD30.2 CD31.2 CD32.2 CD33.2 CD34.2 CD35.2 CD36.2 CD37.2 CD38.2 CD39.2 CD40.2 CD41.2 CD42.2 CD43.2 CD44.2 CD45.2 CD46.2 CD47.2 CD48.2 CD49.2 CD50.2 CD51.2 CD52.2 CD53.2 CD54.2 CD55.2 CD56.2 CD57.2 CD58.2 CD59.2 CD60.2 CD61.2 CD64.2 CE3.2 CE4.2 CE10.2 CE13.2 CE14.2 CE17.2 CE21.2 CE24.2 CE38.2 CE40.2 CE41.2 CE42.2 CE43.2 CE44.2 CE45.2 CE46.2 CE49.2 CE50.2 CE52.2 CE53.2 CE54.2 CE55.2 CE59.2 CE61.2 CE62.2 CE63.2 CE64.2 CE65.2 CE68.2 CI1.2 CI2.2 CI6.2 CI8.2 CI9.2 CI12.2 CI13.2 CI15.2 CI17.2 CI26.2 CI40.2 CI43.2 CI44.2 CI46.2 CI47.2 CI48.2 CI49.2 CI50.2 CL15.2 CL19.2 CL20.2 CL21.2 CL22.2 CL24.2 CL25.2 CL26.2 CL33.2 CL34.2 CL35.2 CL36.1 CL37.1 CL39.2 CL41.1 CL42.2 CL43.2 CL44.2 CL45.2 CM3.1 CM4.2 CM5.2 CM6.2 CM7.2 CM8.2 CMOS1.1 CS5.2 CS6.2 CS7.2 CS27.2 CS28.2 CS29.2 CV15.2 CV16.2 CV24.2 CV30.2 CV32.2 CV33.2 CV34.2 CV35.2 CV36.2 CV39.2 CV40.2 CV42.2 CV43.2 CV45.2 CV46.2 CV47.2 CV48.2 CV49.2 CV50.2 CV51.2 CV52.2 CV53.2 CV54.2 CV55.2 CV56.2 CV57.2 CV58.2 CV59.2 CV60.2 CV61.2 CV62.2 CV63.2 CV64.2 CV65.2 CV68.2 CV112.2 CV129.2 CV130.2 CV131.2 CV132.2 CV133.2 CV134.2 CV135.2 CV136.2 CV139.2 CV140.2 CV141.2 CV142.1 CV143.2 CV151.2 CV158.2 CV159.2 CV160.2 CV161.2 CV163.2 CV164.2 CV165.2 CV168.2 CV170.2 CV172.2 CV173.2 CV174.2 CV178.2 CV179.2 CV180.2 CV181.2 CV183.2 CV184.2 CV186.2 CV187.2 CV196.2 CV197.2 CV198.2 CV199.2 CV203.2 CV204.2 CV205.2 CV208.2 CV209.2 CV210.2 CV211.2 CV215.2 CV216.2 CV217.2 CV218.2 CV326.2 CV334.2 CV335.2 CV336.2 CV337.2 CV338.2 CV339.2 CV340.2 CV343.2 CV344.1 CV345.2 CV351.2 CV352.2 CV353.2 CV354.2 CV355.2 CV356.2 CV357.2 CV358.2 CV359.2 CV360.2 CV361.2 CX2.2 CX3.2 CX5.2 CX6.2 CX7.2 CX8.2 CX10.2 CX11.2 CX20.2 CX21.2 CX22.2 CX23.2 CX24.2 CX25.2 CX26.2 CX27.2 CX28.2 CX29.2 CX30.2 CX31.2 CX49.2 CX50.2 CX51.2 CZ49.2 CZ50.2 CZ51.2 D1.2 DA10.1 DA12.2 DA13.1 DA14.2 DE1.1 DE2.2 DE3.1 DI1.3 DI1.8 DI2.1 DI4.3 DI4.8 DI5.1 DS1.1 DV5.1 DV6.1 DX2.1 DX3.1 DX4.1 H1.1(TP-1) H3.1(TP-1) H4.1(TP-1) H5.1(TP-1) H6.1(TP-1) H7.1(TP-1) H8.1(TP-1) H9.1(TP-1) H10.1(TP-1) H11.1(TP-1) H14.1(TP-1) H15.1(TP-1) H17.1(TP-1) H19.1(TP-1) H22.1(TP-1) H23.1(TP-1) H24.1(TP-1) JBATT.1 JBATT.2 JBATT.4 JBATT.10 JBATT.11 JCRT.5 JCRT.6 JCRT.7 JCRT.8 JCRT.10 JCRT.16 JCRT.17 JDEG.10 JDEG.11 JDEG.12 JDEG.13 JDEG.14 JDIMM1.2 JDIMM1.3 JDIMM1.8 JDIMM1.9 JDIMM1.11 JDIMM1.13 JDIMM1.14 JDIMM1.19 JDIMM1.20 JDIMM1.25 JDIMM1.26 JDIMM1.28 JDIMM1.31 JDIMM1.32 JDIMM1.37 JDIMM1.38 JDIMM1.43 JDIMM1.44 JDIMM1.46 JDIMM1.48 JDIMM1.49 JDIMM1.54 JDIMM1.55 JDIMM1.60 JDIMM1.61 JDIMM1.63 JDIMM1.65 JDIMM1.66 JDIMM1.71 JDIMM1.72 JDIMM1.127 JDIMM1.128 JDIMM1.133 JDIMM1.134 JDIMM1.136 JDIMM1.138 JDIMM1.139 JDIMM1.144 JDIMM1.145 JDIMM1.150 JDIMM1.151 JDIMM1.153 JDIMM1.155 JDIMM1.156 JDIMM1.161 JDIMM1.162 JDIMM1.167 JDIMM1.168 JDIMM1.170 JDIMM1.172 JDIMM1.173 JDIMM1.178 JDIMM1.179 JDIMM1.184 JDIMM1.185 JDIMM1.187 JDIMM1.189 JDIMM1.190 JDIMM1.195 JDIMM1.196 JDIMM1.205 JDIMM1.206 JDIMM2.2 JDIMM2.3 JDIMM2.8 JDIMM2.9 JDIMM2.11 JDIMM2.13 JDIMM2.14 JDIMM2.19 JDIMM2.20 JDIMM2.25 JDIMM2.26 JDIMM2.28 JDIMM2.31 JDIMM2.32 JDIMM2.37 JDIMM2.38 JDIMM2.43 JDIMM2.44 JDIMM2.46 JDIMM2.48 JDIMM2.49 JDIMM2.54 JDIMM2.55 JDIMM2.60 JDIMM2.61 JDIMM2.63 JDIMM2.65 JDIMM2.66 JDIMM2.71 JDIMM2.72 JDIMM2.127 JDIMM2.128 JDIMM2.133 JDIMM2.134 JDIMM2.136 JDIMM2.138 JDIMM2.139 JDIMM2.144 JDIMM2.145 JDIMM2.150 JDIMM2.151 JDIMM2.153 JDIMM2.155 JDIMM2.156 JDIMM2.161 JDIMM2.162 JDIMM2.167 JDIMM2.168 JDIMM2.170 JDIMM2.172 JDIMM2.173 JDIMM2.178 JDIMM2.179 JDIMM2.184 JDIMM2.185 JDIMM2.187 JDIMM2.189 JDIMM2.190 JDIMM2.195 JDIMM2.196 JDIMM2.205 JDIMM2.206 JEDP.7 JEDP.10 JEDP.21 JEDP.23 JEDP.24 JEDP.25 JEDP.26 JEDP.29 JEDP.32 JEDP.35 JEDP.38 JEDP.41 JEDP.42 JEDP.43 JEDP.44 JEDP.45 JFAN.4 JFAN.5 JFAN.6 JFP.1 JFP.2 JFP.5 JFP.7 JFP.8 JHDD.5 JHDD.8 JHDD.11 JHDD.12 JHDMI.2 JHDMI.5 JHDMI.8 JHDMI.11 JHDMI.17 JHDMI.20 JHDMI.21 JHDMI.22 JHDMI.23 JHP.7 JIO.8 JIO.9 JIO.10 JIO.13 JIO.16 JIO.17 JIO.18 JKB.1 JKB.31 JKB.32 JKBBL.5 JKBBL.6 JLAN.9 JLAN.10 JLED.8 JLED.9 JLED.10 JLPDE.9 JLPDE.11 JLPDE.12 JLPDE.13 JLPDE.14 JNGFF.1 JNGFF.7 JNGFF.18 JNGFF.25 JNGFF.31 JNGFF.37 JNGFF.43 JNGFF.49 JNGFF.55 JNGFF.61 JNGFF.67 JNGFF.68 JNGFF.69 JRTC.2 JRTC.3 JRTC.4 JSPK.5 JSPK.6 JTAG1.2 JTP.5 JTP.9 JTP.10 JUSB1.4 JUSB1.7 JUSB1.10 JUSB1.11 JUSB1.12 JUSB1.13 JUSB2.4 JUSB2.7 JUSB2.10 JUSB2.11 JUSB2.12 JUSB2.13 JXDP.1 JXDP.2 JXDP.7 JXDP.8 JXDP.13 JXDP.14 JXDP.19 JXDP.20 JXDP.25 JXDP.26 JXDP.31 JXDP.32 JXDP.37 JXDP.38 JXDP.49 JXDP.50 JXDP.59 PC1.2 PC2.1 PC3.2 PC5.2 PC11.2 PC16.2 PC17.2 PC18.2 PC100.2 PC101.2 PC103.2 PC105.2 PC106.2 PC107.2 PC109.2 PC111.2 PC112.2 PC113.2 PC114.2 PC115.2 PC116.2 PC117.2 PC201.2 PC202.2 PC203.2 PC204.1 PC205.2 PC206.2 PC207.2 PC208.2 PC209.2 PC210.2 PC211.2 PC212.2 PC214.2 PC299.2 PC300.2 PC301.2 PC303.2 PC304.2 PC305.2 PC306.2 PC308.2 PC309.2 PC310.2 PC311.2 PC312.2 PC313.2 PC400.2 PC401.2 PC402.2 PC404.2 PC500.1 PC510.2 PC515.2 PC516.2 PC517.2 PC518.2 PC519.2 PC520.2 PC521.2 PC524.2 PC526.2 PC527.2 PC528.2 PC531.2 PC532.2 PC533.2 PC534.2 PC541.1 PC546.1 PC548.1 PC600.2 PC601.2 PC602.2 PC603.2 PC604.2 PC608.2 PC610.2 PC612.2 PC613.2 PC614.2 PC616.1 PC618.2 PC619.2 PC620.2 PC621.2 PC622.2 PC623.2 PC625.2 PC626.2 PC627.2 PC702.2 PC703.2 PC704.2 PC705.2 PC706.2 PC707.2 PC708.2 PC709.2 PC710.2 PC711.2 PC716.2 PC717.2 PC720.2 PC721.2 PC722.2 PC723.2 PC724.2 PC725.2 PC730.2 PC731.2 PC732.2 PC734.2 PC748.1 PC751.2 PC752.2 PC901.2 PC902.2 PC903.2 PC904.2 PC905.2 PC906.2 PC907.2 PC908.2 PC909.2 PC910.2 PC911.2 PC912.2 PC913.2 PC914.2 PC915.2 PC916.2 PC917.2 PC918.2 PC919.2 PC920.2 PC921.2 PC922.2 PC923.2 PC924.2 PC925.2 PC926.2 PC927.2 PC928.2 PC929.2 PC930.2 PC931.2 PC932.2 PC933.2 PC934.2 PC935.2 PC936.2 PC937.2 PC938.2 PC939.2 PC940.2 PC941.2 PC942.2 PC949.2 PC950.2 PC951.2 PC952.2 PC953.2 PC1000.2 PC1001.2 PC1002.2 PC1003.2 PC1005.2 PC1006.2 PC1008.2 PC1009.2 PD1.1 PD2.1 PD3.2 PD101.1 PH500.1 PH600.2 PJP701.2 PL6.2 PL7.2 PQ2.3 PQ3.1 PQ3.4 PQ102.1 PQ102.2 PQ102.3 PQ104.1 PQ104.2 PQ104.3 PQ201.1 PQ201.2 PQ201.3 PQ501.8 PQ601.1 PQ601.2 PQ601.3 PQ603.1 PQ603.2 PQ603.3 PQ705.1 PQ705.2 PQ705.3 PQ708.6 PQ1001.1 PQ1001.2 PQ1001.3 PR8.1 PR11.2 PR13.2 PR16.2 PR105.2 PR106.2 PR107.1 PR108.2 PR114.2 PR204.2 PR301.2 PR306.2 PR307.2 PR401.2 PR403.2 PR507.2 PR512.2 PR521.1 PR528.1 PR558.2 PR614.1 PR615.2 PR741.2 PR1002.1 PR1005.2 PR1007.2 PU100.21 PU200.1 PU200.3 PU200.14 PU200.21 PU300.9 PU400.1 PU501.21 PU600.22 PU600.25 PU700.22 PU1000.11 Q8.3 Q9.3 Q10.3 Q2307.3 QA7.3 QE11.3 QX1.3 QX3.3 R2.2 R16.2 R159.2 R255.1 R2338.2 R2351.1 R2484.2 R2495.2 R2517.1 R2523.2 R2524.2 R2525.2 R2526.2 RA19.2 RA81.1 RA1113.1 RA1114.2 RA1115.2 RA1116.2 RA1117.2 RC2.2 RC20.2 RC21.2 RC22.2 RC23.2 RC24.2 RC25.2 RC66.2 RC68.2 RC69.2 RC70.2 RC80.2 RC84.1 RC87.1 RC89.2 RC90.2 RC92.1 RC101.2 RC129.1 RC132.2 RC133.1 RC134.2 RC135.2 RC183.2 RC191.2 RC368.1 RC369.1 RC371.2 RC374.2 RD6.1 RD7.1 RD13.2 RE24.2 RE55.1 RE56.1 RE63.2 RE66.2 RE77.2 RE78.2 RE82.1 RE87.1 RE90.2 RE280.2 RL27.1 RL30.2 RL31.1 RM8.2 RP51.6 RP51.7 RPE6.5 RPE6.6 RPE10.5 RPE10.6 RPE10.7 RPE10.8 RS25.2 RS32.2 RS33.2 RS35.2 RS38.2 RS40.2 RS42.2 RV20.2 RV23.2 RV25.2 RV31.2 RV32.2 RV33.2 RV34.2 RV39.2 RV41.1 RV43.2 RV44.2 RV45.1 RV48.2 RV59.1 RV92.2 RV93.2 RV95.2 RV96.2 RV99.1 RV107.2 RV108.2 RV110.2 RV112.2 RV114.2 RV117.2 RV118.2 RV119.2 RV126.1 RV127.1 RV128.1 RV129.1 RV132.2 RV142.2 RV143.2 RV148.2 RV152.2 RV155.2 RV156.2 RV157.1 RV160.2 RV169.2 RV187.2 RV510.2 RV511.2 RV512.2 RV513.2 RV514.2 RV515.2 RX9.2 RX26.2 RX29.2 SW1.3 SW1.5 SW1.6 SW3.4 SW3.5 U2301.11 U2301.15 U2302.4 U2303.3 U2304.11 U2304.15 U2412.48 U2412.49 UA1.49 UC1.A11 UC1.A14 UC1.A18 UC1.A24 UC1.A28 UC1.A32 UC1.A36 UC1.A40 UC1.A44 UC1.A48 UC1.A52 UC1.A56 UC1.AA1 UC1.AA58 UC1.AB7 UC1.AB10 UC1.AB20 UC1.AB22 UC1.AC61 UC1.AD3 UC1.AD21 UC1.AD63 UC1.AE5 UC1.AE10 UC1.AE58 UC1.AF11 UC1.AF12 UC1.AF14 UC1.AF15 UC1.AF17 UC1.AF18 UC1.AG1 UC1.AG11 UC1.AG21 UC1.AG23 UC1.AG60 UC1.AG61 UC1.AG62 UC1.AG63 UC1.AH16 UC1.AH17 UC1.AH19 UC1.AH20 UC1.AH22 UC1.AH24 UC1.AH28 UC1.AH30 UC1.AH32 UC1.AH34 UC1.AH36 UC1.AH38 UC1.AH40 UC1.AH42 UC1.AH44 UC1.AH46 UC1.AH49 UC1.AH51 UC1.AH53 UC1.AH55 UC1.AH57 UC1.AJ13 UC1.AJ14 UC1.AJ23 UC1.AJ25 UC1.AJ27 UC1.AJ29 UC1.AJ35 UC1.AJ39 UC1.AJ41 UC1.AJ43 UC1.AJ45 UC1.AJ47 UC1.AJ50 UC1.AJ52 UC1.AJ54 UC1.AJ56 UC1.AJ58 UC1.AJ60 UC1.AJ63 UC1.AK3 UC1.AK23 UC1.AK52 UC1.AL10 UC1.AL13 UC1.AL17 UC1.AL20 UC1.AL22 UC1.AL23 UC1.AL26 UC1.AL29 UC1.AL31 UC1.AL33 UC1.AL36 UC1.AL39 UC1.AL40 UC1.AL45 UC1.AL46 UC1.AL51 UC1.AL52 UC1.AL54 UC1.AL57 UC1.AL60 UC1.AL61 UC1.AM1 UC1.AM17 UC1.AM23 UC1.AM31 UC1.AM52 UC1.AN7 UC1.AN17 UC1.AN23 UC1.AN31 UC1.AN32 UC1.AN35 UC1.AN36 UC1.AN39 UC1.AN40 UC1.AN42 UC1.AN43 UC1.AN45 UC1.AN46 UC1.AN48 UC1.AN49 UC1.AN51 UC1.AN52 UC1.AN60 UC1.AN63 UC1.AP3 UC1.AP10 UC1.AP17 UC1.AP20 UC1.AP22 UC1.AP23 UC1.AP26 UC1.AP29 UC1.AP31 UC1.AP38 UC1.AP39 UC1.AP48 UC1.AP52 UC1.AP54 UC1.AP57 UC1.AR5 UC1.AR11 UC1.AR15 UC1.AR17 UC1.AR23 UC1.AR31 UC1.AR33 UC1.AR39 UC1.AR43 UC1.AR49 UC1.AR52 UC1.AT13 UC1.AT35 UC1.AT37 UC1.AT40 UC1.AT42 UC1.AT43 UC1.AT46 UC1.AT49 UC1.AT61 UC1.AT62 UC1.AT63 UC1.AU1 UC1.AU16 UC1.AU18 UC1.AU20 UC1.AU22 UC1.AU24 UC1.AU26 UC1.AU28 UC1.AU30 UC1.AU33 UC1.AU51 UC1.AU53 UC1.AU55 UC1.AU57 UC1.AU59 UC1.AV8 UC1.AV14 UC1.AV16 UC1.AV20 UC1.AV24 UC1.AV28 UC1.AV33 UC1.AV34 UC1.AV36 UC1.AV39 UC1.AV41 UC1.AV43 UC1.AV46 UC1.AV49 UC1.AV51 UC1.AV55 UC1.AV59 UC1.AW4 UC1.AW16 UC1.AW24 UC1.AW33 UC1.AW35 UC1.AW37 UC1.AW40 UC1.AW42 UC1.AW44 UC1.AW47 UC1.AW50 UC1.AW51 UC1.AW59 UC1.AW60 UC1.AY4 UC1.AY6 UC1.AY11 UC1.AY16 UC1.AY18 UC1.AY22 UC1.AY24 UC1.AY26 UC1.AY30 UC1.AY33 UC1.AY51 UC1.AY53 UC1.AY57 UC1.AY59 UC1.B4 UC1.B20 UC1.B24 UC1.B26 UC1.B28 UC1.B32 UC1.B36 UC1.B40 UC1.B44 UC1.B48 UC1.B52 UC1.B56 UC1.B60 UC1.C11 UC1.C14 UC1.C18 UC1.C20 UC1.C25 UC1.C27 UC1.C38 UC1.C39 UC1.C57 UC1.D2 UC1.D5 UC1.D8 UC1.D12 UC1.D14 UC1.D18 UC1.D21 UC1.D23 UC1.D25 UC1.D26 UC1.D27 UC1.D29 UC1.D30 UC1.D31 UC1.D33 UC1.D34 UC1.D35 UC1.D37 UC1.D38 UC1.D39 UC1.D41 UC1.D42 UC1.D43 UC1.D45 UC1.D46 UC1.D47 UC1.D49 UC1.D50 UC1.D51 UC1.D53 UC1.D54 UC1.D55 UC1.D57 UC1.D59 UC1.D62 UC1.D63 UC1.E11 UC1.E17 UC1.F20 UC1.F26 UC1.F30 UC1.F34 UC1.F38 UC1.F42 UC1.F46 UC1.F50 UC1.F54 UC1.F58 UC1.F61 UC1.G3 UC1.G5 UC1.G6 UC1.G8 UC1.G18 UC1.G22 UC1.H13 UC1.H17 UC1.H57 UC1.J10 UC1.J22 UC1.J59 UC1.J63 UC1.K1 UC1.K12 UC1.L7 UC1.L13 UC1.L15 UC1.L17 UC1.L18 UC1.L20 UC1.L58 UC1.L61 UC1.M22 UC1.N3 UC1.N10 UC1.N21 UC1.P22 UC1.P59 UC1.P62 UC1.P63 UC1.R8 UC1.R10 UC1.R22 UC1.T1 UC1.T58 UC1.U9 UC1.U20 UC1.U22 UC1.U61 UC1.V3 UC1.V7 UC1.V10 UC1.V23 UC1.V58 UC1.W20 UC1.W22 UC1.Y10 UC1.Y59 UC1.Y63 UC3.3 UC4.7 UC4.15 UC5.3 UC6.3 UE4.41 UE5.B11 UE5.B18 UE5.B54 UE5.B60 UE5.B66 UE5.C1 UI2.2 UI3.2 UI4.2 UL1.33 UL2.2 UM1.5 UM1.9 US2.3 US2.13 US2.21 UV1.A2 UV1.A26 UV1.AA7 UV1.AB7 UV1.AB11 UV1.AB14 UV1.AB17 UV1.AB20 UV1.AB24 UV1.AC2 UV1.AC5 UV1.AC8 UV1.AC22 UV1.AC26 UV1.AD12 UV1.AD13 UV1.AD15 UV1.AD16 UV1.AD18 UV1.AD19 UV1.AD21 UV1.AD22 UV1.AE11 UV1.AE14 UV1.AE17 UV1.AE20 UV1.AF1 UV1.AF5 UV1.AF8 UV1.AF11 UV1.AF14 UV1.AF17 UV1.AF20 UV1.AF23 UV1.AG2 UV1.AG26 UV1.B1 UV1.B5 UV1.B8 UV1.B11 UV1.B14 UV1.B17 UV1.B20 UV1.B23 UV1.B27 UV1.E2 UV1.E5 UV1.E8 UV1.E11 UV1.E14 UV1.E17 UV1.E20 UV1.E22 UV1.E25 UV1.H2 UV1.H5 UV1.H23 UV1.H25 UV1.K11 UV1.K13 UV1.K15 UV1.K17 UV1.L2 UV1.L5 UV1.L10 UV1.L12 UV1.L14 UV1.L16 UV1.L18 UV1.L23 UV1.L25 UV1.M11 UV1.M13 UV1.M15 UV1.M17 UV1.N10 UV1.N12 UV1.N14 UV1.N16 UV1.N18 UV1.P2 UV1.P5 UV1.P11 UV1.P13 UV1.P15 UV1.P17 UV1.P23 UV1.P26 UV1.R10 UV1.R12 UV1.R14 UV1.R16 UV1.R18 UV1.T11 UV1.T13 UV1.T15 UV1.T17 UV1.U2 UV1.U5 UV1.U10 UV1.U12 UV1.U14 UV1.U16 UV1.U18 UV1.U23 UV1.U26 UV1.V11 UV1.V13 UV1.V15 UV1.V17 UV1.Y2 UV1.Y5 UV1.Y23 UV1.Y26 UV3.3 UV4.2 UV5.3 UV6.49 UV14.3 UV15.11 UV15.15 UV17.A9 UV17.B1 UV17.B3 UV17.B9 UV17.D1 UV17.D8 UV17.E1 UV17.E2 UV17.E8 UV17.F9 UV17.G1 UV17.G8 UV17.G9 UV17.J2 UV17.J8 UV17.M1 UV17.M9 UV17.P1 UV17.P9 UV17.T1 UV17.T9 UV18.A9 UV18.B1 UV18.B3 UV18.B9 UV18.D1 UV18.D8 UV18.E1 UV18.E2 UV18.E8 UV18.F9 UV18.G1 UV18.G8 UV18.G9 UV18.J2 UV18.J8 UV18.M1 UV18.M9 UV18.P1 UV18.P9 UV18.T1 UV18.T9 UV19.A9 UV19.B1 UV19.B3 UV19.B9 UV19.D1 UV19.D8 UV19.E1 UV19.E2 UV19.E8 UV19.F9 UV19.G1 UV19.G8 UV19.G9 UV19.J2 UV19.J8 UV19.M1 UV19.M9 UV19.P1 UV19.P9 UV19.T1 UV19.T9 UV20.A9 UV20.B1 UV20.B3 UV20.B9 UV20.D1 UV20.D8 UV20.E1 UV20.E2 UV20.E8 UV20.F9 UV20.G1 UV20.G8 UV20.G9 UV20.J2 UV20.J8 UV20.M1 UV20.M9 UV20.P1 UV20.P9 UV20.T1 UV20.T9 UX1.2 UX3.2 YL2.2 YL2.4 YV1.2 YV1.4 YV3.2 YV3.4
GNDA: CA23.1 CA33.2 CA39.2 CA51.2 CA61.2 CA62.1 CA63.1 CA71.2 CA74.2 CA75.2 QA6.1 QA6.4 RA83.2 RA84.2 RA1114.1 RA1115.1 RA1116.1 RA1117.1 RA1128.2 RA1129.1 UA1.25 UA1.38
GNDA_CHG: PC718.2 PC719.2 PC726.1 PC728.2 PC729.2 PC745.1 PC747.2 PC750.1 PJP701.1 PQ709.3 PR715.2 PR729.2 PR732.2 PR740.1 PU700.29
VCCSENSE: PC541.2 PC545.1 PR533.1 PR537.1 R1.2 UC1.E63
VDD_1.35V: PC209.1 PR205.1 PR206.2 PU200.11
VSSSENSE: PC545.2 PC546.2 PU501.8 R2.1 UC1.E62
6513_27M_IN: CV345.1 RV210.1 UV6.34 YV3.1
6513_27M_OUT: RV159.1 RV210.2 UV6.33
+1.35DGPU_B+: PC1000.1 PC1001.1 PC1002.1 PC1003.1 PL1000.1 PQ1000.5
+CHGRTC: DC1.3 PJP12.2
+CODEC_AVDD2: CA61.1 RA8.2 UA1.40
+CORE_PLLVDD: CV46.1 CV134.1 LV10.2 UV1.L6
+CPU_CORE: C40.1 PC901.1 PC902.1 PC903.1 PC904.1 PC905.1 PC906.1 PC907.1 PC908.1 PC909.1 PC910.1 PC911.1 PC912.1 PC913.1 PC914.1 PC915.1 PC916.1 PC917.1 PC918.1 PC919.1 PC920.1 PC921.1 PC922.1 PC923.1 PL502.4 R1.1 UC1.AB57 UC1.AD57 UC1.AG57 UC1.C24 UC1.C28 UC1.C32 UC1.C36 UC1.C40 UC1.C44 UC1.C48 UC1.C52 UC1.C56 UC1.E23 UC1.E25 UC1.E27 UC1.E29 UC1.E31 UC1.E33 UC1.E35 UC1.E37 UC1.E39 UC1.E41 UC1.E43 UC1.E45 UC1.E47 UC1.E49 UC1.E51 UC1.E53 UC1.E55 UC1.E57 UC1.F24 UC1.F28 UC1.F32 UC1.F36 UC1.F40 UC1.F44 UC1.F48 UC1.F52 UC1.F56 UC1.F59 UC1.G23 UC1.G25 UC1.G27 UC1.G29 UC1.G31 UC1.G33 UC1.G35 UC1.G37 UC1.G39 UC1.G41 UC1.G43 UC1.G45 UC1.G47 UC1.G49 UC1.G51 UC1.G53 UC1.G55 UC1.G57 UC1.H23 UC1.J23 UC1.K23 UC1.K57 UC1.L22 UC1.M23 UC1.M57 UC1.P57 UC1.U57 UC1.W57
+CRT_VCC: CV50.1 JCRT.9 RV35.1 RV36.1 RV37.1 RV38.1 UV3.5 UV4.3 UV5.5
+DC_IN: PC16.1 PC17.1 PC18.1 PC700.1 PD703.2 PL4.2 PL5.2 PQ701.5 PR9.1 PR10.1 PR12.1 PR16.1 PR739.1
+DC_IN_SS: PC701.1 PQ701.1 PQ701.2 PQ701.3 PQ702.1 PQ702.2 PQ702.3 PQ708.4 PR730.1
+DCIN: PC748.2 PR708.2 PU700.28
+DCIN_JACK: JDCIN.4 JDCIN.5 PC5.1 PC9.1 PC10.1 PL4.1 PL5.1
+DIMM1_VREF_DQ: CD1.1 CD2.1 JDIMM1.1 RD1.2
+DIMM2_VREF_DQ: CD32.1 CD33.1 JDIMM2.1 RD8.2
+FB_PLLAVDD: CV32.1 CV45.1 CV48.1 CV133.1 LV26.2 UV1.F16 UV1.H22 UV1.P22
+FBA_VREF_CA0: CV326.1 RV110.1 RV139.2 UV17.M8 UV18.M8
+FBA_VREF_CA1: CV216.1 RV142.1 RV149.2 UV19.M8 UV20.M8
+FBA_VREF_DQ0: CV334.1 RV112.1 RV144.2 UV17.H1 UV18.H1
+FBA_VREF_DQ1: CV217.1 RV143.1 RV150.2 UV19.H1 UV20.H1
+GPU_CORE: PC610.1 PC613.1 PC623.1 PC924.1 PC925.1 PC926.1 PC927.1 PC928.1 PC929.1 PC930.1 PC931.1 PC932.1 PC933.1 PC934.1 PC935.1 PC936.1 PC937.1 PC938.1 PC939.1 PC940.1 PC941.1 PC942.1 PC949.1 PC950.1 PC951.1 PC952.1 PC953.1 PL601.2 PL602.2 PR617.1 UV1.K10 UV1.K12 UV1.K14 UV1.K16 UV1.K18 UV1.L11 UV1.L13 UV1.L15 UV1.L17 UV1.M10 UV1.M12 UV1.M14 UV1.M16 UV1.M18 UV1.N11 UV1.N13 UV1.N15 UV1.N17 UV1.P10 UV1.P12 UV1.P14 UV1.P16 UV1.P18 UV1.R11 UV1.R13 UV1.R15 UV1.R17 UV1.T10 UV1.T12 UV1.T14 UV1.T16 UV1.T18 UV1.U11 UV1.U13 UV1.U15 UV1.U17 UV1.V10 UV1.V12 UV1.V14 UV1.V16 UV1.V18
+INV_PWR_SRC: CX5.1 CX31.1 JEDP.1 JEDP.2 QX2.1 QX2.2 QX2.5 QX2.6
+LAN_IO: CL15.1 CL19.1 CL21.1 CL43.1 CL44.1 CL45.1 R11.1 UL1.11 UL1.23 UL1.32 UL2.1
+LAN_VDD: CL20.1 CL22.1 CL24.1 CL25.1 CL26.1 CL34.1 CL35.1 L18.1 UL1.3 UL1.8 UL1.22 UL1.30
+LCDVDD: LX1.1 UX1.1
+LCDVDD_CONN: CX2.1 CX3.1 CX8.1 CX11.1 JEDP.16 JEDP.17 LX1.2
+MIC2-VREFO: RA53.2 RA1109.2 UA1.29
+PBATT: PC3.1 PD702.2 PL1.1 PL2.1 PL8.1 PQ703.5 PQ703.6 PQ703.7 PQ703.8 PR723.2
+PCH_VCC1P05: C83.1 C84.1 L4.2 UC1.J18 UC1.K19
+PCH_VCCACLKPLL: C85.1 C86.1 L5.2 RC13.2 UC1.A20
+PCH_VCCDSW: C1313.2 R265.1 UC1.AG19 UC1.AG20
+PCH_VCCDSW_R: C64.1 R265.2
+PLLVDD: CV33.1 CV49.1 CV112.1 LV8.2 UV1.M6
+PWR_SRC_AC: PL700.1 PR702.4
+RTC_CELL_VBAT: CE65.1 RE32.2 UE5.B64
+RTCBATT: JRTC.1 RC10.2
+RTCVCC: C54.1 C55.1 C56.1 CC26.1 DC1.1 R2337.2 RA5.1 RC1.1 RC5.1 RC6.1 RC7.1 RE31.1 RE32.1 RPE5.5 RPE5.6 RPE5.7 UC1.AG10
+SDC_IN: PQ702.5 PQ702.6 PQ702.7 PQ702.8 PR702.1
+SM_VREF_CA: CC8.1 RC17.2 UC1.AP49
+SM_VREF_CA_DIMM: RC14.2 RC17.1 RC20.1 RD4.2 RD10.2
+SM_VREF_DQ0: CC10.1 RC19.2 UC1.AR51
+SM_VREF_DQ0_DIMM1: RC16.2 RC19.1 RC22.1 RD1.1
+SM_VREF_DQ1: CC9.1 RC18.2 UC1.AP51
+SM_VREF_DQ1_DIMM2: RC15.2 RC18.1 RC21.1 RD8.1
+V_DAC: CL41.2 TL2.3 TL2.4 TL2.9 TL2.10
+VDISPLAY_VCC: CX21.1 CX22.1 FX1.1 JHDMI.18 RX16.2 RX17.2
+VR_CAP: CE45.1 UE5.B12
-DCIN_JACK: JDCIN.2 JDCIN.3 PC9.2 PC10.2 PL6.1 PL7.1
A_EM: RS30.2 RS32.1 US2.9
A_EQ: RS21.2 RS25.1 US2.17
A_EQ2: RS24.2 RS33.1 US2.18
AC_DIS: PQ708.5 PQ709.2 PR741.1 UE5.A10
AC_PRESENT: RC32.2 UC1.AJ8 UE5.A54
ACAV_IN: PR714.1 RE278.2 UE5.A64
ACAV_IN_NB: RE278.1 UE5.B20
ACDET: PC750.2 PQ709.1 PR739.2 PR740.2 PU700.6
ALERT#: PR506.2 PU501.19
ALW_PWRGD_3V_5V: PR110.1 UE5.A1
ALWON: PR102.1 R2451.1 UE5.A60
AUD_HP_NB_SENSE: CA75.1 DA13.2 JHP.6 QA7.2 RA1128.1 UE4.2
AUD_HP_OUT_L_CN: CA39.1 DA10.3 JHP.1 LA8.1
AUD_HP_OUT_R_CN: CA33.1 DA10.2 JHP.2 LA9.1
AUX_EN_WOWL: RM8.1 UE4.6 UM1.3
B+: CX4.1 PC515.1 PC533.1 PC716.1 PC717.1 PC723.1 PC724.1 PC725.1 PC730.1 PC731.1 PC732.1 PL102.1 PL103.1 PL201.1 PL302.1 PL501.2 PL504.2 PL600.2 PL603.2 PL701.2 PL1000.2 PR710.1 QX2.4 RX2.1
B+_1.05V: PC303.1 PC304.1 PC305.1 PC306.1 PL302.2 PU300.8
B_EM: RS35.1 RS36.2 US2.8
B_EQ: RS19.2 RS38.1 US2.19
BAT1_LED#: JLED.5 UE5.B1
BAT2_LED#: JLED.6 UE5.A55
BAT_ALERT: JBATT.3 PD1.2
BAT_B+: PC720.1 PC721.1 PC752.1 PQ703.1 PQ703.2 PQ703.3 PR710.4
BATDRV#: PQ703.4 PR704.2
BATT_PRS: JBATT.5 PD1.3 PRP1.8
BBS_BIT: RC119.2 UC1.L8
BC_CLK_ECE1099: UE4.33 UE5.A43
BC_CLK_ECE1117: U2412.33 UE5.A20
BC_DAT_ECE1099: RE39.2 UE4.32 UE5.B45
BC_DAT_ECE1117: RPE5.1 U2412.34 UE5.B21
BC_INT#_ECE1099: UE4.34 UE5.A42
BC_INT#_ECE1117: U2412.32 UE5.A19
BEEP: DA8.2 UE5.B19
BIA_PWM_EC: DV1.2 UE5.B25
BKLGT_DET: R2517.2 R2518.1 U2412.39
BKLT_PWM: QE11.2 U2412.40
BLUE: CV56.1 DV6.2 JCRT.3 LV18.2
BLUE_CRT: CV53.1 CV60.1 LV18.1 RV34.1 UV6.8
BOARD_ID: CE54.1 RE79.2 UE5.B10
BOOT_1.35V: PR200.2 PU200.18
BQ24777_REGN: PC751.1 PR706.2 PR713.1 PR725.1 PU700.24
BREATH_LED#: JLED.7 UE5.B57
BST_1.05V: PR303.1 PU300.6
BST_1.35V: PC200.1 PR200.1
BST_3V: PR103.2 PU100.9
BST_5V: PR111.1 PU100.17
BST_+1.35DGPU: PR1001.1 PU1000.10
BT_RADIO_DIS#: JNGFF.46 RE13.2 UE4.12
CAM_MIC_CBL_DET#: JEDP.20 RP60.5 UC1.F4
CAP_LED#: Q327.3 U2412.41
CAPS_LED: JKB.4 R944.2
CBL_LOOP_BACK: JEDP.6 RX29.1
CFD_PWRBTN#_XDP: JXDP.41 RC49.2
CFG0: JXDP.9 RC183.1 UC1.AC60
CFG1: JXDP.11 UC1.AC62
CFG2: JXDP.15 UC1.AC63
CFG3: JXDP.17 RC56.2 UC1.AA63
CFG3_R: JXDP.60 RC56.1
CFG4: JXDP.27 RC191.1 UC1.AA60
CFG5: JXDP.29 UC1.Y62
CFG6: JXDP.33 UC1.Y61
CFG7: JXDP.35 UC1.Y60
CFG8: JXDP.10 UC1.V62
CFG9: JXDP.12 UC1.V61
CFG10: JXDP.16 UC1.V60
CFG11: JXDP.18 UC1.U60
CFG12: JXDP.28 UC1.T63
CFG13: JXDP.30 UC1.T62
CFG14: JXDP.34 UC1.T61
CFG15: JXDP.36 UC1.T60
CFG16: JXDP.6 UC1.AA62
CFG17: JXDP.4 UC1.AA61
CFG18: JXDP.24 UC1.U63
CFG19: JXDP.22 UC1.U62
CFG_RCOMP: RC132.1 UC1.V63
CHAGER_SRC: PC702.1 PC703.1 PC704.1 PC705.1 PC706.1 PC707.1 PC708.1 PC709.1 PC710.1 PC711.1 PC734.1 PL700.2 PQ704.5
CHARGER_SMBCLK: PR721.1 RPE3.2 UE5.B50
CHARGER_SMBDAT: PR719.1 RPE3.1 UE5.A47
CHG_BTS: PR712.1 PU700.25
CHG_BTS_C: PC712.1 PR712.2
CHG_LGATE: PQ705.4 PU700.23
CHG_SNUB: PC722.1 PR711.1
CHG_SW: PC712.2 PL701.1 PQ704.1 PQ704.2 PQ704.3 PQ705.5 PR711.2 PU700.27
CHG_UGATE: PQ704.4 PU700.26
CLK_BIASREF: RC13.1 UC1.C26
CLK_DDC2_CRT: JCRT.15 QV89.3 RV36.2
CLK_DDC2_CRT_R: QV89.4 RV163.2 RV517.2 UV6.23
CLK_PCI_LPDEBUG: JLPDE.10 R2339.1
CLK_PCI_MEC: R2336.1 RE80.1 UE5.A29
CLK_PCIE_GFX: UC1.B39 UV1.AE8
CLK_PCIE_GFX#: UC1.A39 UV1.AD8
CLK_PCIE_LAN: UC1.B42 UL1.15
CLK_PCIE_LAN#: UC1.C41 UL1.16
CLK_PCIE_WLAN: JNGFF.39 UC1.C37
CLK_PCIE_WLAN#: JNGFF.41 UC1.B38
CLK_SMB: JBATT.7 PD2.3 PRP1.6
CLK_TP_SIO: DE1.3 JTP.6 R2522.2 UE5.A37
CLKA0: RV145.1 RV146.1 UV1.D24 UV17.J7 UV18.J7
CLKA0#: RV145.2 RV147.1 UV1.D25 UV17.K7 UV18.K7
CLKA0_C: CV335.1 RV146.2 RV147.2
CLKA1: RV151.1 RV153.1 UV1.N22 UV19.J7 UV20.J7
CLKA1#: RV151.2 RV154.1 UV1.M22 UV19.K7 UV20.K7
CLKA1_C: CV218.1 RV153.2 RV154.2
CLKOUT_LPC0: R2336.2 UC1.AN15
CLKOUT_LPC1: R2339.2 UC1.AP15
CLKRUN#: RC36.2 UC1.V5 UE5.A32
COMP: PC531.1 PR539.1 PU501.6
CPPE#: RC108.2 UC1.J1
CPU_DPB_AUX: RP51.2 UC1.B5
CPU_DPB_AUX#: RP51.1 UC1.C5
CPU_DPB_CTRLCLK: QX4.1 RP52.2 UC1.B9
CPU_DPB_CTRLCLK_R: JHDMI.15 QX4.6 RX16.1
CPU_DPB_CTRLDAT: QX4.4 RP52.1 UC1.C9
CPU_DPB_CTRLDAT_R: JHDMI.16 QX4.3 RX17.1
CPU_DPC_AUX: CV349.1 RP51.3 UC1.A6 UV6.18
CPU_DPC_AUX#: CV350.1 RP51.4 UC1.B6 UV6.17
CPU_DPC_CTRLCLK: RP52.3 UC1.D9
CPU_DPC_CTRLDAT: RP52.4 UC1.D11
CPU_EDP_HPD: JEDP.31 RC89.1 UC1.D6
CPU_ID: RE279.1 RE280.1 UE4.11
CPU_PWR_DEBUG#: R253.1 R255.2 RC50.1 UC1.H59
CPU_PWR_DEBUG#_R: JXDP.45 RC50.2
CPUSB#: RC111.2 UC1.K3
CS1: PR105.1 PU100.1
CS2: PR108.1 PU100.5
CS_1.35V: PR205.2 PU200.13
CSSN_1: PR702.3 PR705.1
CSSP_1: PR702.2 PR738.1
DAT_DDC2_CRT: JCRT.12 QV89.6 RV35.2
DAT_DDC2_CRT_R: QV89.1 RV164.2 RV516.2 UV6.21
DAT_SMB: JBATT.6 PD2.2 PRP1.7
DAT_TP_SIO: DE1.2 JTP.7 R2521.2 UE5.B40
DC_TEST_A3_B3: UC1.A3 UC1.B3
DC_TEST_A4: T168.1(TP-1) UC1.A4
DC_TEST_A60: T169.1(TP-1) UC1.A60
DC_TEST_A61_B61: UC1.A61 UC1.B61
DC_TEST_A62: T170.1(TP-1) UC1.A62
DC_TEST_AV1: T171.1(TP-1) UC1.AV1
DC_TEST_AW1: T172.1(TP-1) UC1.AW1
DC_TEST_AW63: T173.1(TP-1) UC1.AW63
DC_TEST_AY2_AW2: UC1.AW2 UC1.AY2
DC_TEST_AY3_AW3: UC1.AW3 UC1.AY3
DC_TEST_AY60: T166.1(TP-1) UC1.AY60
DC_TEST_AY61_AW61: UC1.AW61 UC1.AY61
DC_TEST_AY62_AW62: UC1.AW62 UC1.AY62
DC_TEST_B62_B63: UC1.B62 UC1.B63
DC_TEST_C1_C2: UC1.C1 UC1.C2
DDI1_LANE_N0: CX18.2 UC1.C54
DDI1_LANE_N1: CX16.2 UC1.B58
DDI1_LANE_N2: CX14.2 UC1.B55
DDI1_LANE_N3: CX12.2 UC1.A57
DDI1_LANE_P0: CX19.2 UC1.C55
DDI1_LANE_P1: CX17.2 UC1.C58
DDI1_LANE_P2: CX15.2 UC1.A55
DDI1_LANE_P3: CX13.2 UC1.B57
DDI2_LANE_N0: CV346.1 UC1.C51
DDI2_LANE_N1: CV348.1 UC1.C53
DDI2_LANE_P0: CV342.1 UC1.C50
DDI2_LANE_P1: CV347.1 UC1.B54
DDR3_DRAMRST#: CD3.1 CD34.1 JDIMM1.30 JDIMM2.30 RD5.1
DDR3_DRAMRST#_CPU: CC35.1 RD3.2 RD5.2 UC1.AV15
DDR_A_BS0: JDIMM1.109 UC1.AU35
DDR_A_BS1: JDIMM1.108 UC1.AV35
DDR_A_BS2: JDIMM1.79 UC1.AY41
DDR_A_CAS#: JDIMM1.115 UC1.AU34
DDR_A_D0: JDIMM1.5 UC1.AH63
DDR_A_D1: JDIMM1.7 UC1.AH62
DDR_A_D2: JDIMM1.15 UC1.AK63
DDR_A_D3: JDIMM1.17 UC1.AK62
DDR_A_D4: JDIMM1.4 UC1.AH61
DDR_A_D5: JDIMM1.6 UC1.AH60
DDR_A_D6: JDIMM1.16 UC1.AK61
DDR_A_D7: JDIMM1.18 UC1.AK60
DDR_A_D8: JDIMM1.21 UC1.AM63
DDR_A_D9: JDIMM1.23 UC1.AM62
DDR_A_D10: JDIMM1.33 UC1.AP63
DDR_A_D11: JDIMM1.35 UC1.AP62
DDR_A_D12: JDIMM1.22 UC1.AM61
DDR_A_D13: JDIMM1.24 UC1.AM60
DDR_A_D14: JDIMM1.34 UC1.AP61
DDR_A_D15: JDIMM1.36 UC1.AP60
DDR_A_D16: JDIMM1.39 UC1.AY58
DDR_A_D17: JDIMM1.41 UC1.AW58
DDR_A_D18: JDIMM1.51 UC1.AY56
DDR_A_D19: JDIMM1.53 UC1.AW56
DDR_A_D20: JDIMM1.40 UC1.AV58
DDR_A_D21: JDIMM1.42 UC1.AU58
DDR_A_D22: JDIMM1.50 UC1.AV56
DDR_A_D23: JDIMM1.52 UC1.AU56
DDR_A_D24: JDIMM1.57 UC1.AY54
DDR_A_D25: JDIMM1.59 UC1.AW54
DDR_A_D26: JDIMM1.67 UC1.AY52
DDR_A_D27: JDIMM1.69 UC1.AW52
DDR_A_D28: JDIMM1.56 UC1.AV54
DDR_A_D29: JDIMM1.58 UC1.AU54
DDR_A_D30: JDIMM1.68 UC1.AV52
DDR_A_D31: JDIMM1.70 UC1.AU52
DDR_A_D32: JDIMM1.129 UC1.AY31
DDR_A_D33: JDIMM1.131 UC1.AW31
DDR_A_D34: JDIMM1.141 UC1.AY29
DDR_A_D35: JDIMM1.143 UC1.AW29
DDR_A_D36: JDIMM1.130 UC1.AV31
DDR_A_D37: JDIMM1.132 UC1.AU31
DDR_A_D38: JDIMM1.140 UC1.AV29
DDR_A_D39: JDIMM1.142 UC1.AU29
DDR_A_D40: JDIMM1.147 UC1.AY27
DDR_A_D41: JDIMM1.149 UC1.AW27
DDR_A_D42: JDIMM1.157 UC1.AY25
DDR_A_D43: JDIMM1.159 UC1.AW25
DDR_A_D44: JDIMM1.146 UC1.AV27
DDR_A_D45: JDIMM1.148 UC1.AU27
DDR_A_D46: JDIMM1.158 UC1.AV25
DDR_A_D47: JDIMM1.160 UC1.AU25
DDR_A_D48: JDIMM1.163 UC1.AY23
DDR_A_D49: JDIMM1.165 UC1.AW23
DDR_A_D50: JDIMM1.175 UC1.AY21
DDR_A_D51: JDIMM1.177 UC1.AW21
DDR_A_D52: JDIMM1.164 UC1.AV23
DDR_A_D53: JDIMM1.166 UC1.AU23
DDR_A_D54: JDIMM1.174 UC1.AV21
DDR_A_D55: JDIMM1.176 UC1.AU21
DDR_A_D56: JDIMM1.181 UC1.AY19
DDR_A_D57: JDIMM1.183 UC1.AW19
DDR_A_D58: JDIMM1.191 UC1.AY17
DDR_A_D59: JDIMM1.193 UC1.AW17
DDR_A_D60: JDIMM1.180 UC1.AV19
DDR_A_D61: JDIMM1.182 UC1.AU19
DDR_A_D62: JDIMM1.192 UC1.AV17
DDR_A_D63: JDIMM1.194 UC1.AU17
DDR_A_DQS0: JDIMM1.12 UC1.AJ62
DDR_A_DQS1: JDIMM1.29 UC1.AN61
DDR_A_DQS2: JDIMM1.47 UC1.AW57
DDR_A_DQS3: JDIMM1.64 UC1.AW53
DDR_A_DQS4: JDIMM1.137 UC1.AV30
DDR_A_DQS5: JDIMM1.154 UC1.AW26
DDR_A_DQS6: JDIMM1.171 UC1.AV22
DDR_A_DQS7: JDIMM1.188 UC1.AW18
DDR_A_DQS#0: JDIMM1.10 UC1.AJ61
DDR_A_DQS#1: JDIMM1.27 UC1.AN62
DDR_A_DQS#2: JDIMM1.45 UC1.AV57
DDR_A_DQS#3: JDIMM1.62 UC1.AV53
DDR_A_DQS#4: JDIMM1.135 UC1.AW30
DDR_A_DQS#5: JDIMM1.152 UC1.AV26
DDR_A_DQS#6: JDIMM1.169 UC1.AW22
DDR_A_DQS#7: JDIMM1.186 UC1.AV18
DDR_A_MA0: JDIMM1.98 UC1.AU36
DDR_A_MA1: JDIMM1.97 UC1.AY37
DDR_A_MA2: JDIMM1.96 UC1.AR38
DDR_A_MA3: JDIMM1.95 UC1.AP36
DDR_A_MA4: JDIMM1.92 UC1.AU39
DDR_A_MA5: JDIMM1.91 UC1.AR36
DDR_A_MA6: JDIMM1.90 UC1.AV40
DDR_A_MA7: JDIMM1.86 UC1.AW39
DDR_A_MA8: JDIMM1.89 UC1.AY39
DDR_A_MA9: JDIMM1.85 UC1.AU40
DDR_A_MA10: JDIMM1.107 UC1.AP35
DDR_A_MA11: JDIMM1.84 UC1.AW41
DDR_A_MA12: JDIMM1.83 UC1.AU41
DDR_A_MA13: JDIMM1.119 UC1.AR35
DDR_A_MA14: JDIMM1.80 UC1.AV42
DDR_A_MA15: JDIMM1.78 UC1.AU42
DDR_A_RAS#: JDIMM1.110 UC1.AY34
DDR_A_WE#: JDIMM1.113 UC1.AW34
DDR_B_BS0: JDIMM2.109 UC1.AL35
DDR_B_BS1: JDIMM2.108 UC1.AM36
DDR_B_BS2: JDIMM2.79 UC1.AU49
DDR_B_CAS#: JDIMM2.115 UC1.AM33
DDR_B_D0: JDIMM2.33 UC1.AP58
DDR_B_D1: JDIMM2.35 UC1.AR58
DDR_B_D2: JDIMM2.23 UC1.AM57
DDR_B_D3: JDIMM2.21 UC1.AK57
DDR_B_D4: JDIMM2.22 UC1.AL58
DDR_B_D5: JDIMM2.24 UC1.AK58
DDR_B_D6: JDIMM2.34 UC1.AR57
DDR_B_D7: JDIMM2.36 UC1.AN57
DDR_B_D8: JDIMM2.41 UC1.AP55
DDR_B_D9: JDIMM2.42 UC1.AR55
DDR_B_D10: JDIMM2.52 UC1.AM54
DDR_B_D11: JDIMM2.50 UC1.AK54
DDR_B_D12: JDIMM2.39 UC1.AL55
DDR_B_D13: JDIMM2.40 UC1.AK55
DDR_B_D14: JDIMM2.51 UC1.AR54
DDR_B_D15: JDIMM2.53 UC1.AN54
DDR_B_D16: JDIMM2.6 UC1.AK40
DDR_B_D17: JDIMM2.7 UC1.AK42
DDR_B_D18: JDIMM2.17 UC1.AM43
DDR_B_D19: JDIMM2.16 UC1.AM45
DDR_B_D20: JDIMM2.18 UC1.AK45
DDR_B_D21: JDIMM2.15 UC1.AK43
DDR_B_D22: JDIMM2.4 UC1.AM40
DDR_B_D23: JDIMM2.5 UC1.AM42
DDR_B_D24: JDIMM2.69 UC1.AM46
DDR_B_D25: JDIMM2.59 UC1.AK46
DDR_B_D26: JDIMM2.58 UC1.AM49
DDR_B_D27: JDIMM2.67 UC1.AK49
DDR_B_D28: JDIMM2.70 UC1.AM48
DDR_B_D29: JDIMM2.68 UC1.AK48
DDR_B_D30: JDIMM2.56 UC1.AM51
DDR_B_D31: JDIMM2.57 UC1.AK51
DDR_B_D32: JDIMM2.129 UC1.AM29
DDR_B_D33: JDIMM2.130 UC1.AK29
DDR_B_D34: JDIMM2.132 UC1.AL28
DDR_B_D35: JDIMM2.131 UC1.AK28
DDR_B_D36: JDIMM2.141 UC1.AR29
DDR_B_D37: JDIMM2.142 UC1.AN29
DDR_B_D38: JDIMM2.143 UC1.AR28
DDR_B_D39: JDIMM2.140 UC1.AP28
DDR_B_D40: JDIMM2.147 UC1.AN26
DDR_B_D41: JDIMM2.148 UC1.AR26
DDR_B_D42: JDIMM2.159 UC1.AR25
DDR_B_D43: JDIMM2.157 UC1.AP25
DDR_B_D44: JDIMM2.146 UC1.AK26
DDR_B_D45: JDIMM2.149 UC1.AM26
DDR_B_D46: JDIMM2.160 UC1.AK25
DDR_B_D47: JDIMM2.158 UC1.AL25
DDR_B_D48: JDIMM2.174 UC1.AR21
DDR_B_D49: JDIMM2.165 UC1.AR22
DDR_B_D50: JDIMM2.175 UC1.AL21
DDR_B_D51: JDIMM2.164 UC1.AM22
DDR_B_D52: JDIMM2.163 UC1.AN22
DDR_B_D53: JDIMM2.177 UC1.AP21
DDR_B_D54: JDIMM2.176 UC1.AK21
DDR_B_D55: JDIMM2.166 UC1.AK22
DDR_B_D56: JDIMM2.180 UC1.AN20
DDR_B_D57: JDIMM2.182 UC1.AR20
DDR_B_D58: JDIMM2.191 UC1.AK18
DDR_B_D59: JDIMM2.193 UC1.AL18
DDR_B_D60: JDIMM2.192 UC1.AK20
DDR_B_D61: JDIMM2.194 UC1.AM20
DDR_B_D62: JDIMM2.183 UC1.AR18
DDR_B_D63: JDIMM2.181 UC1.AP18
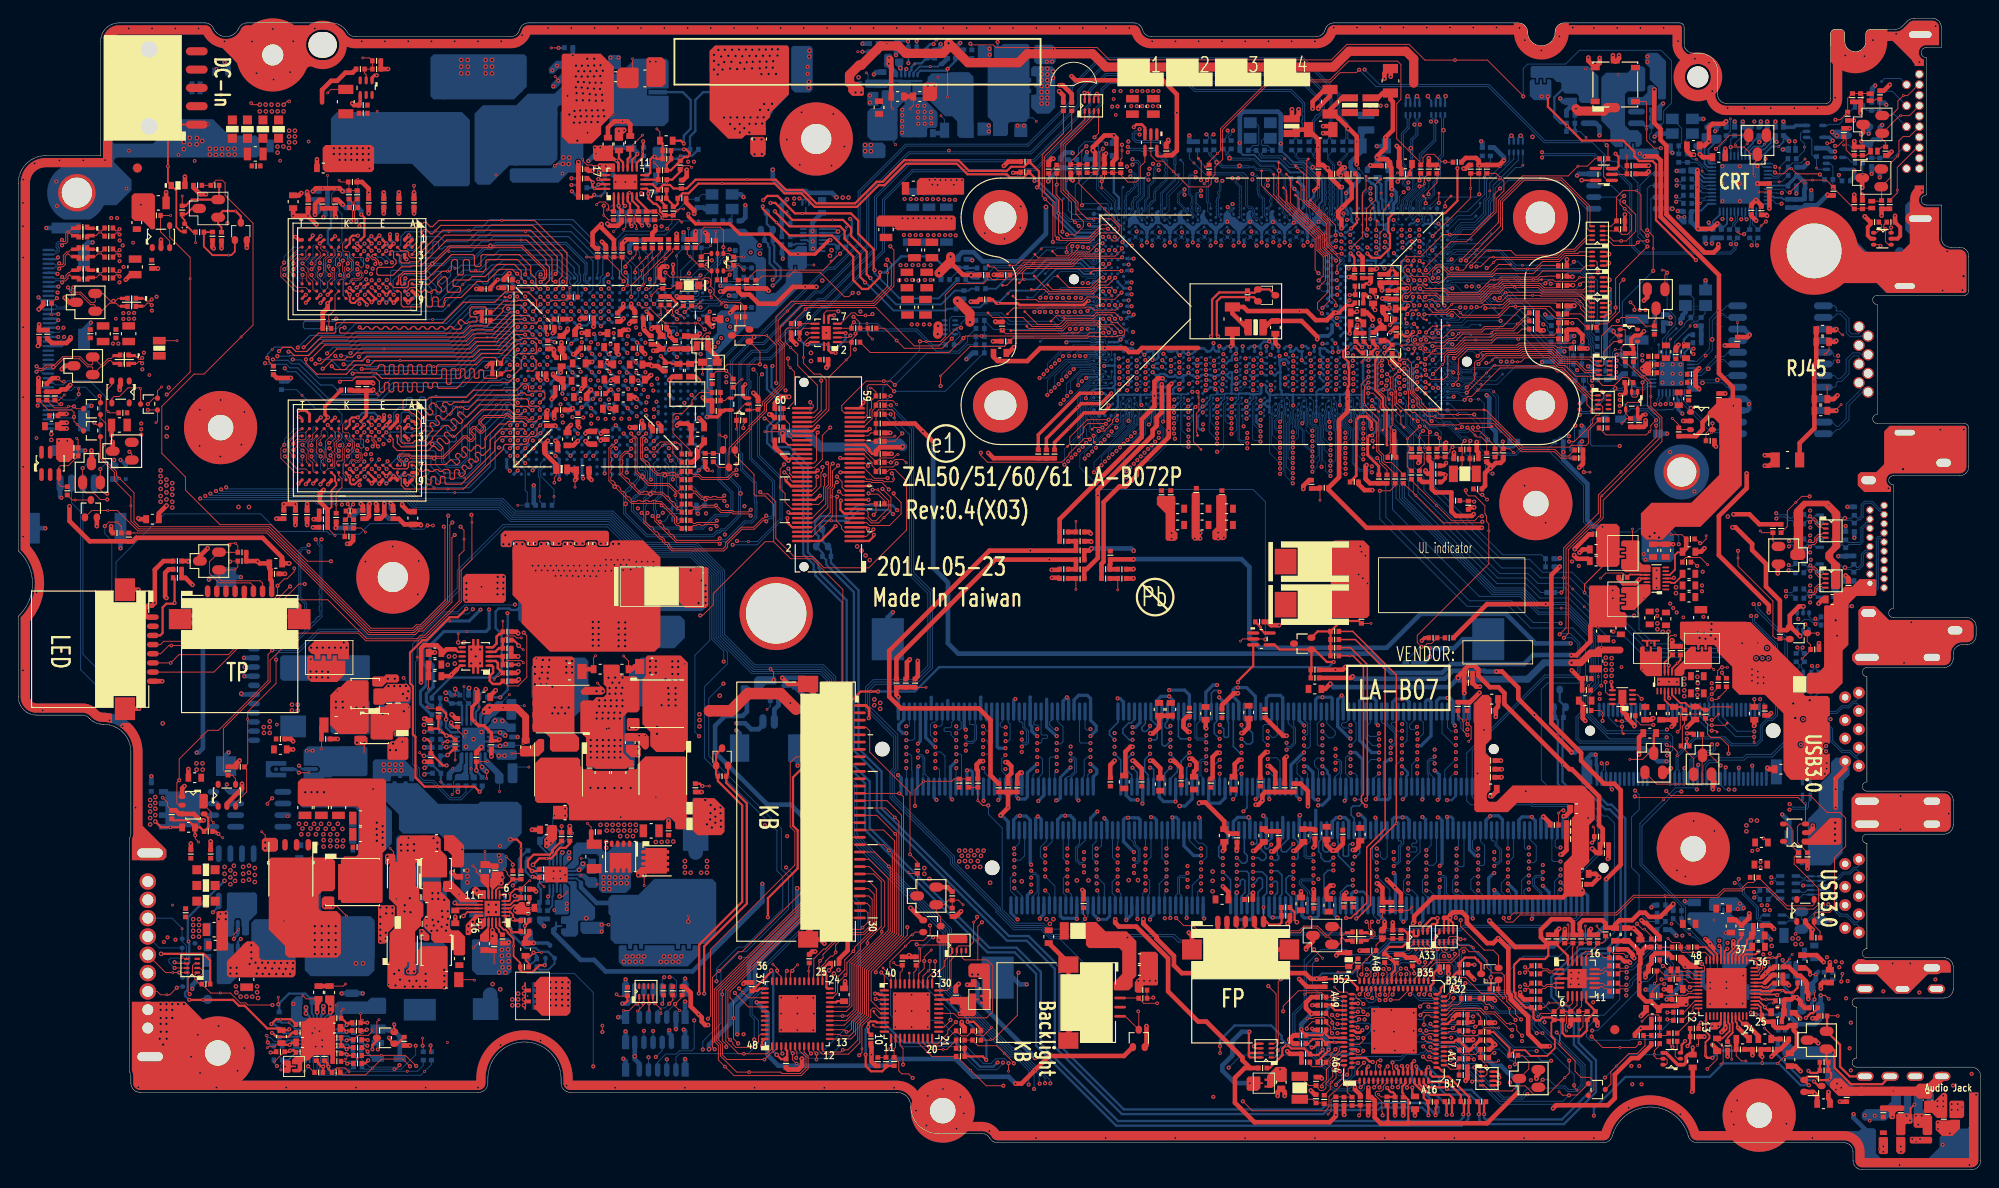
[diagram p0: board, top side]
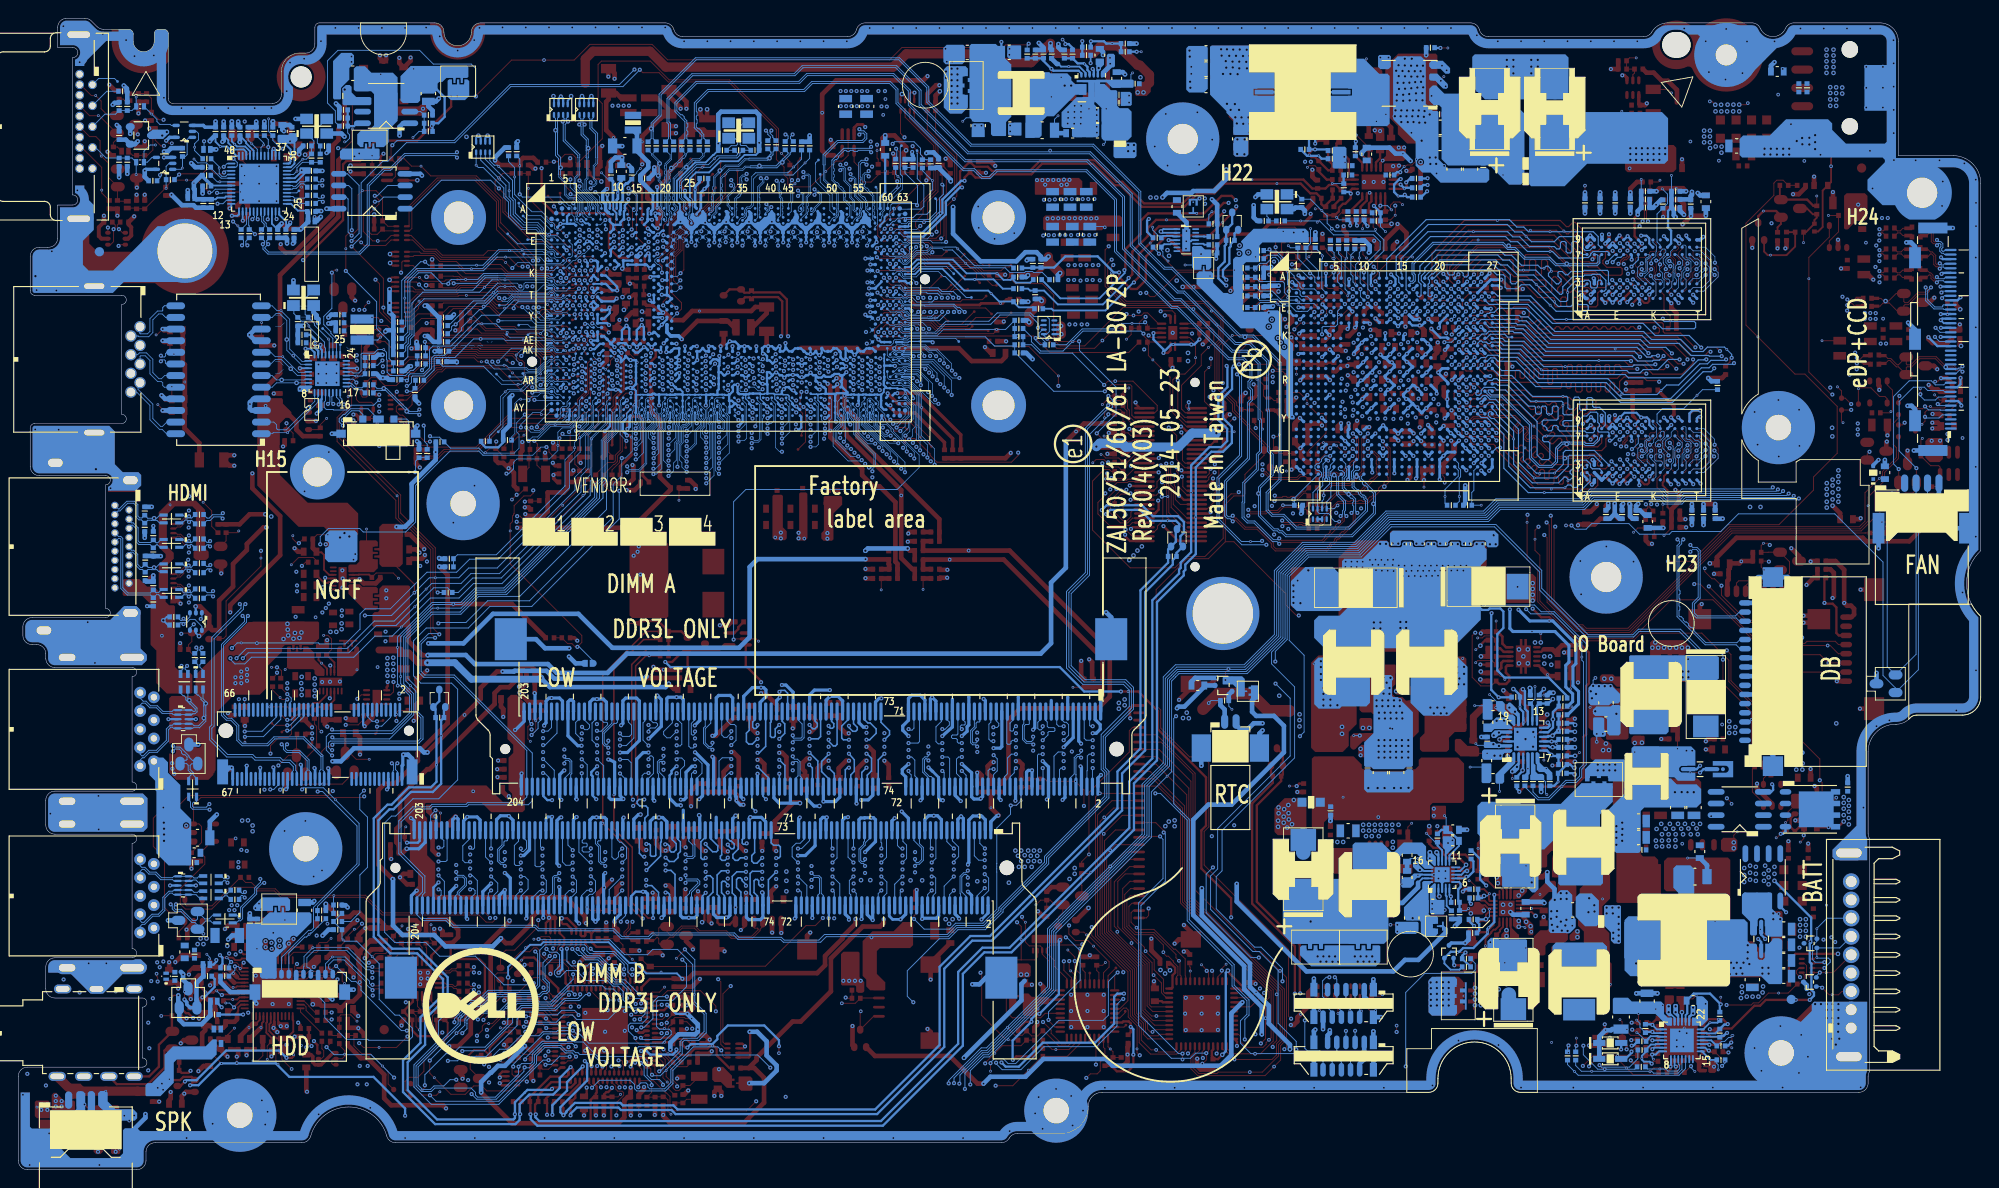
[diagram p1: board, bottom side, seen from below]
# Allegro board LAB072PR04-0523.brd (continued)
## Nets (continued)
DDR_B_DQS0: JDIMM2.29 UC1.AN58
DDR_B_DQS1: JDIMM2.47 UC1.AN55
DDR_B_DQS2: JDIMM2.12 UC1.AL42
DDR_B_DQS3: JDIMM2.64 UC1.AL49
DDR_B_DQS4: JDIMM2.137 UC1.AM28
DDR_B_DQS5: JDIMM2.154 UC1.AM25
DDR_B_DQS6: JDIMM2.171 UC1.AM21
DDR_B_DQS7: JDIMM2.188 UC1.AM18
DDR_B_DQS#0: JDIMM2.27 UC1.AM58
DDR_B_DQS#1: JDIMM2.45 UC1.AM55
DDR_B_DQS#2: JDIMM2.10 UC1.AL43
DDR_B_DQS#3: JDIMM2.62 UC1.AL48
DDR_B_DQS#4: JDIMM2.135 UC1.AN28
DDR_B_DQS#5: JDIMM2.152 UC1.AN25
DDR_B_DQS#6: JDIMM2.169 UC1.AN21
DDR_B_DQS#7: JDIMM2.186 UC1.AN18
DDR_B_MA0: JDIMM2.98 UC1.AP40
DDR_B_MA1: JDIMM2.97 UC1.AR40
DDR_B_MA2: JDIMM2.96 UC1.AP42
DDR_B_MA3: JDIMM2.95 UC1.AR42
DDR_B_MA4: JDIMM2.92 UC1.AR45
DDR_B_MA5: JDIMM2.91 UC1.AP45
DDR_B_MA6: JDIMM2.90 UC1.AW46
DDR_B_MA7: JDIMM2.86 UC1.AY46
DDR_B_MA8: JDIMM2.89 UC1.AY47
DDR_B_MA9: JDIMM2.85 UC1.AU46
DDR_B_MA10: JDIMM2.107 UC1.AK36
DDR_B_MA11: JDIMM2.84 UC1.AV47
DDR_B_MA12: JDIMM2.83 UC1.AU47
DDR_B_MA13: JDIMM2.119 UC1.AK33
DDR_B_MA14: JDIMM2.80 UC1.AR46
DDR_B_MA15: JDIMM2.78 UC1.AP46
DDR_B_RAS#: JDIMM2.110 UC1.AM35
DDR_B_WE#: JDIMM2.113 UC1.AK35
DDR_CKE0_DIMMA: JDIMM1.73 UC1.AU43
DDR_CKE1_DIMMA: JDIMM1.74 UC1.AW43
DDR_CKE2_DIMMB: JDIMM2.73 UC1.AY49
DDR_CKE3_DIMMB: JDIMM2.74 UC1.AU50
DDR_CS0_DIMMA#: JDIMM1.114 UC1.AP33
DDR_CS1_DIMMA#: JDIMM1.121 UC1.AR32
DDR_CS2_DIMMB#: JDIMM2.114 UC1.AM32
DDR_CS3_DIMMB#: JDIMM2.121 UC1.AK32
DDR_PG_CTRL: U2303.2 UC1.AV61
DDR_XDP_SMBCLK_R1: JXDP.53 RC54.2
DDR_XDP_SMBDAT_R1: JXDP.51 RC53.2
DDR_XDP_WLAN_TP_SMBCLK: JDIMM1.202 JDIMM2.202 QC1.1 R2332.2 RC54.1
DDR_XDP_WLAN_TP_SMBDAT: JDIMM1.200 JDIMM2.200 QC1.4 R2331.2 RC53.1
DEW1: RS42.1 RS43.2 US2.16
DEW2_REXT: RS40.1 RS41.2 US2.6
DGPU_CORE_EN: RC369.2 UC1.R5
DGPU_HOLD_RST#: RV45.2 UC1.Y3 UV14.1
DGPU_PEX_RST#: QV78.2 RV40.1 RV208.2 RV252.2
DGPU_PEX_RST_R#: RV40.2 UV1.AC7
DGPU_PWR_EN: RC368.2 RC370.2 RV193.1 UC1.L3
DGPU_PWROK: PR1000.2 PU1000.1 QV88.2 RP43.6 UC1.P4 UE4.20
DH_1.35V: PQ200.4 PU200.17
DISPOFF#: DV2.1 JEDP.4 RX9.1
DL_1.35V: PQ201.4 PU200.15
DP_HPD: Q2416.1 R2495.1 UV6.40
DPB_HPD: QV5.3 RV18.1 UC1.C8
DPC_HPD: Q2416.3 RC84.2 UC1.A8
DSWODVREN: R2337.1 R2338.1 UC1.AW7
EC_MUTE#: CA76.1 RA6.1 RA10.1 RC38.1 UE4.3
EDP_AUX: C4321.2 UC1.B45
EDP_AUX#: C4322.2 UC1.A45
EDP_AUX#_C: JEDP.33 LX10.3 RX37.2
EDP_AUX#_R: C4322.1 LX10.4 RX37.1
EDP_AUX_C: JEDP.34 LX10.2 RX36.2
EDP_AUX_R: C4321.1 LX10.1 RX36.1
EDP_BIA_PWM: DV1.3 RC72.2 RC75.2 RC81.1
EDP_BKLCTL: RC81.2 UC1.B8
EDP_COMP: RC71.2 UC1.D20
EDP_DISP_UTIL: RC72.1 UC1.A43
EDP_TX0: C4312.2 UC1.B46
EDP_TX0#: C4311.2 UC1.C45
EDP_TX0#_C: JEDP.39 LX8.3 RX33.2
EDP_TX0#_R: C4311.1 LX8.4 RX33.1
EDP_TX0_C: JEDP.40 LX8.2 RX32.2
EDP_TX0_R: C4312.1 LX8.1 RX32.1
EDP_TX1: C4314.2 UC1.B47
EDP_TX1#: C4313.2 UC1.A47
EDP_TX1#_C: JEDP.36 LX9.3 RX35.2
EDP_TX1#_R: C4313.1 LX9.4 RX35.1
EDP_TX1_C: JEDP.37 LX9.2 RX34.2
EDP_TX1_R: C4314.1 LX9.1 RX34.1
EN_0.675VSP: PC203.1 PR202.2 PU200.7
EN_1.35V: PC202.1 PR201.2 PU200.8
EN_+1.35DGPU: PC1005.1 PR1003.2 PU1000.3
EN_INVPWR: QX1.2 RE55.2 UE5.A25
ENVDD_PCH: DV7.3 RC87.2 UC1.C6 UE5.A7
ENVDD_R: DV7.1 UX1.4
EXPRESS_DET#: T100.1(TP-1) UE4.40
FAN1_PWM: RE48.2 RE58.1 UE5.A24
FAN1_TACH: CE24.1 DE3.3 JFAN.2 RE50.2 UE5.B22
FB_1.35V: PR204.1 PR207.1 PU200.6
FB_3V: PC102.2 PR107.2 PR109.2 PU100.4
FB_5V: PC108.1 PR104.1 PR106.1 PU100.2
FB_+1.35DGPU: PR1006.1 PR1007.1 PU1000.4
FB_CLAMP_GPU: RV48.1 UV1.F3
FBA_CMD0: UV1.C27 UV17.L2 UV18.L2
FBA_CMD1: T110.1(TP-1) UV1.C26
FBA_CMD2: RV132.1 UV1.E24 UV17.K1 UV18.K1
FBA_CMD3: RV118.1 UV1.F24 UV17.K9 UV18.K9
FBA_CMD4: UV1.D27 UV17.T7 UV18.T7 UV19.T7 UV20.T7
FBA_CMD5: RV114.1 UV1.D26 UV17.T2 UV18.T2 UV19.T2 UV20.T2
FBA_CMD6: UV1.F25 UV17.R3 UV18.R3 UV19.R3 UV20.R3
FBA_CMD7: UV1.F26 UV17.R2 UV18.R2 UV19.R2 UV20.R2
FBA_CMD8: UV1.F23 UV17.P3 UV18.P3 UV19.P3 UV20.P3
FBA_CMD9: UV1.G22 UV17.N3 UV18.N3 UV19.N3 UV20.N3
FBA_CMD10: UV1.G23 UV17.P8 UV18.P8 UV19.P8 UV20.P8
FBA_CMD11: UV1.G24 UV17.P7 UV18.P7 UV19.P7 UV20.P7
FBA_CMD12: UV1.F27 UV17.M2 UV18.M2 UV19.M2 UV20.M2
FBA_CMD13: UV1.G25 UV17.L3 UV18.L3 UV19.L3 UV20.L3
FBA_CMD14: UV1.G27 UV17.M7 UV18.M7 UV19.M7 UV20.M7
FBA_CMD15: UV1.G26 UV17.K3 UV18.K3 UV19.K3 UV20.K3
FBA_CMD16: UV1.M24 UV19.L2 UV20.L2
FBA_CMD17: T183.1(TP-1) UV1.M23
FBA_CMD18: RV117.1 UV1.K24 UV19.K1 UV20.K1
FBA_CMD19: RV119.1 UV1.K23 UV19.K9 UV20.K9
FBA_CMD20: UV1.M27 UV17.T3 UV18.T3 UV19.T3 UV20.T3
FBA_CMD21: UV1.M26 UV17.T8 UV18.T8 UV19.T8 UV20.T8
FBA_CMD22: UV1.M25 UV17.R8 UV18.R8 UV19.R8 UV20.R8
FBA_CMD23: UV1.K26 UV17.R7 UV18.R7 UV19.R7 UV20.R7
FBA_CMD24: UV1.K22 UV17.P2 UV18.P2 UV19.P2 UV20.P2
FBA_CMD25: UV1.J23 UV17.N2 UV18.N2 UV19.N2 UV20.N2
FBA_CMD26: UV1.J25 UV17.M3 UV18.M3 UV19.M3 UV20.M3
FBA_CMD27: UV1.J24 UV17.N8 UV18.N8 UV19.N8 UV20.N8
FBA_CMD28: UV1.K27 UV17.N7 UV18.N7 UV19.N7 UV20.N7
FBA_CMD29: UV1.K25 UV17.L7 UV18.L7 UV19.L7 UV20.L7
FBA_CMD30: UV1.J27 UV17.J3 UV18.J3 UV19.J3 UV20.J3
FBA_CMD31: T184.1(TP-1) UV1.J26
FBA_D0: UV1.E18 UV18.H3
FBA_D1: UV1.F18 UV18.E3
FBA_D2: UV1.E16 UV18.G2
FBA_D3: UV1.F17 UV18.F2
FBA_D4: UV1.D20 UV18.F7
FBA_D5: UV1.D21 UV18.H7
FBA_D6: UV1.F20 UV18.F8
FBA_D7: UV1.E21 UV18.H8
FBA_D8: UV1.E15 UV17.G2
FBA_D9: UV1.D15 UV17.H3
FBA_D10: UV1.F15 UV17.F2
FBA_D11: UV1.F13 UV17.E3
FBA_D12: UV1.C13 UV17.H7
FBA_D13: UV1.B13 UV17.F7
FBA_D14: UV1.E13 UV17.H8
FBA_D15: UV1.D13 UV17.F8
FBA_D16: UV1.B15 UV17.B8
FBA_D17: UV1.C16 UV17.D7
FBA_D18: UV1.A13 UV17.C8
FBA_D19: UV1.A15 UV17.A7
FBA_D20: UV1.B18 UV17.C2
FBA_D21: UV1.A18 UV17.C3
FBA_D22: UV1.A19 UV17.A2
FBA_D23: UV1.C19 UV17.A3
FBA_D24: UV1.B24 UV18.B8
FBA_D25: UV1.C23 UV18.D7
FBA_D26: UV1.A25 UV18.C8
FBA_D27: UV1.A24 UV18.A7
FBA_D28: UV1.A21 UV18.C2
FBA_D29: UV1.B21 UV18.C3
FBA_D30: UV1.C20 UV18.A2
FBA_D31: UV1.C21 UV18.A3
FBA_D32: UV1.R22 UV20.G2
FBA_D33: UV1.R24 UV20.H3
FBA_D34: UV1.T22 UV20.F2
FBA_D35: UV1.R23 UV20.E3
FBA_D36: UV1.N25 UV20.H7
FBA_D37: UV1.N26 UV20.F7
FBA_D38: UV1.N23 UV20.H8
FBA_D39: UV1.N24 UV20.F8
FBA_D40: UV1.V23 UV19.C3
FBA_D41: UV1.V22 UV19.C2
FBA_D42: UV1.T23 UV19.A3
FBA_D43: UV1.U22 UV19.A2
FBA_D44: UV1.Y24 UV19.D7
FBA_D45: UV1.AA24 UV19.A7
FBA_D46: UV1.Y22 UV19.C8
FBA_D47: UV1.AA23 UV19.B8
FBA_D48: UV1.AD27 UV19.H8
FBA_D49: UV1.AB25 UV19.F7
FBA_D50: UV1.AD26 UV19.F8
FBA_D51: UV1.AC25 UV19.H7
FBA_D52: UV1.AA27 UV19.E3
FBA_D53: UV1.AA26 UV19.F2
FBA_D54: UV1.W26 UV19.H3
FBA_D55: UV1.Y25 UV19.G2
FBA_D56: UV1.R26 UV20.D7
FBA_D57: UV1.T25 UV20.A7
FBA_D58: UV1.N27 UV20.C8
FBA_D59: UV1.R27 UV20.B8
FBA_D60: UV1.V26 UV20.C3
FBA_D61: UV1.V27 UV20.C2
FBA_D62: UV1.W27 UV20.A3
FBA_D63: UV1.W25 UV20.A2
FBA_DQM0: UV1.D19 UV18.E7
FBA_DQM1: UV1.D14 UV17.E7
FBA_DQM2: UV1.C17 UV17.D3
FBA_DQM3: UV1.C22 UV18.D3
FBA_DQM4: UV1.P24 UV20.E7
FBA_DQM5: UV1.W24 UV19.D3
FBA_DQM6: UV1.AA25 UV19.E7
FBA_DQM7: UV1.U25 UV20.D3
FBA_RN0: UV1.F19 UV18.G3
FBA_RN1: UV1.C14 UV17.G3
FBA_RN2: UV1.A16 UV17.B7
FBA_RN3: UV1.A22 UV18.B7
FBA_RN4: UV1.P25 UV20.G3
FBA_RN5: UV1.W22 UV19.B7
FBA_RN6: UV1.AB27 UV19.G3
FBA_RN7: UV1.T27 UV20.B7
FBA_WP0: UV1.E19 UV18.F3
FBA_WP1: UV1.C15 UV17.F3
FBA_WP2: UV1.B16 UV17.C7
FBA_WP3: UV1.B22 UV18.C7
FBA_WP4: UV1.R25 UV20.F3
FBA_WP5: UV1.W23 UV19.C7
FBA_WP6: UV1.AB26 UV19.F3
FBA_WP7: UV1.T26 UV20.C7
FBA_ZQ0: RV148.1 UV17.L8
FBA_ZQ1: RV152.1 UV18.L8
FBA_ZQ2: RV155.1 UV19.L8
FBA_ZQ3: RV156.1 UV20.L8
FBVREF_ALTV: RV92.1 UV1.C5
FWP#: RE81.2 RE82.2 UE5.B65
GC6_EVENT#: T177.1(TP-1) UC1.R6
GC6_EVENT#_D: RV190.2 UV1.A4
GFX_CORE_PG: PR621.2 PR1003.1 PU600.16
GFXCLK_REQ#: QV88.1 R2345.2 RV196.2 UC1.U5
GFXCLK_REQ_Q#: QV88.3 RV195.2 RV196.1 UV1.AC6
GPU_B+: PC601.1 PC602.1 PC603.1 PC604.1 PC612.1 PC618.1 PC619.1 PC620.1 PC621.1 PC627.1 PL600.1 PL603.1 PQ600.5 PQ602.5 PR611.1
GPU_CLK_27M_IN: CV34.1 UV1.C11 YV1.1
GPU_CLK_27M_OUT: RV519.2 UV1.B10
GPU_CLK_27M_OUT_R: CV35.1 RV519.1 YV1.3
GPU_COMP: PC616.2 PU600.12
GPU_DSBL/ISEN1: PC626.1 PR623.1 PU600.15 PU600.21
GPU_EN: PC608.1 PR608.1 PU600.3
GPU_FB: PC615.2 PR616.2 PR617.2 PU600.11
GPU_FBRTN: PC606.2 PC607.2 PC615.1 PR610.2 PR612.2 PR614.2 PU600.10
GPU_GC6_FB_EN: T176.1(TP-1) UC1.L6
GPU_HOT#: DV3.2 RV104.1 UV1.D7
GPU_JTAG_TCK: RPV3.7 UV1.AE5
GPU_JTAG_TDI: RPV3.6 UV1.AE6
GPU_JTAG_TDO: RPV3.5 UV1.AF6
GPU_JTAG_TMS: RPV3.8 UV1.AD6
GPU_JTAG_TRST#: RV108.1 UV1.AG4
GPU_PEX_RST_HOLD#: RV189.2 UV1.C4
GPU_PSI: PR605.1 PU600.4
GPU_PWM_VID: PR601.2 UV1.E7
GPU_PWR_LEVEL: DV3.1 UE4.22
GPU_REFADJ: PR604.2 PU600.6
GPU_REFIN: PC606.1 PR603.1 PR607.1 PU600.7
GPU_SMBCLK: QV14.3 RPE3.4 RV30.2 UE5.B49
GPU_SMBCLK_R: QV14.4 RV30.1 RV191.1 UV1.D9
GPU_SMBDAT: QV14.6 RPE3.3 RV26.2 UE5.B48
GPU_SMBDAT_R: QV14.1 RV26.1 RV192.1 UV1.D8
GPU_TESTMODE: RV107.1 UV1.AD9
GPU_TON: PR611.2 PU600.9
GPU_TSNS/ISEN3: PC622.1 PH600.1 PR620.2 PU600.13
GPU_VDD_SENSE: PR616.1 UV1.F2
GPU_VID: PR600.1 PR601.1 PU600.5
GPU_VREF: PC600.1 PR602.1 PR620.1 PU600.8
GPU_VSS_SENSE: PR612.1 UV1.F1
GREEN: CV55.1 DV5.2 JCRT.2 LV17.2
GREEN_CRT: CV52.1 CV61.1 LV17.1 RV33.1 UV6.9
H_CATERR#: RC58.2 UC1.K61
H_CPU_SVIDALRT#: R254.1 UC1.L62
H_CPU_SVIDCLK: C5212.1 R248.2 UC1.N63
H_CPU_SVIDDATA: R256.2 R257.1 UC1.L63
H_CPUPWRGD: CC27.1 RC48.1 RC66.1 UC1.C61
H_PROCHOT#: CA26.1 PC510.1 PR510.1 PR717.1 RC60.2 RC67.1 UE5.A46
H_PROCHOT#_R: RC67.2 UC1.K63
H_THERMTRIP#: QE9.3 R2353.2 R2355.2
H_THERMTRIP#_R: R2355.1 UC1.D60
H_VCCST_PWRGD: CC42.1 RC114.1 RC365.1 UC1.B59 UC6.4
H_VCCST_PWRGD_XDP: JXDP.39 RC48.2 RC114.2
H_VR_READY: PR519.2 PU501.2 R251.1 RC363.2 RC364.1
HDA_SPKR: DA8.3 RC121.2 UC1.V2
HDD_DET#: JHDD.3 RP37.1 UC1.U1
HDD_DEVSLP: RN5.1 RS8.1 UC1.L2
HDMI_HPLUG: JHDMI.19 QV5.1 RV20.1
HOST_ALERT1_R_N: RC120.2 UC1.AD6
HOST_DEBUG_TX: JDEG.8 RE74.2 UE5.B44
HPOUT-L: RA55.1 UA1.32
HPOUT-R: RA56.1 UA1.33
HSYNC: RV170.1 UV6.4
HSYNC_CONN: CV59.1 JCRT.13 LV19.2 RV38.2
HSYNC_CRT: LV19.1 UV5.4
HSYNC_R: RV170.2 UV5.2
I2C0_SCL: RP53.4 UC1.F3
I2C0_SDA: RP53.3 UC1.F2
I2C1_SCL_TCH_PAD: RP53.2 UC1.F1
I2C1_SDA_TCH_PAD: RP53.1 UC1.G4
I_ADP: PR716.1 UE5.A12
I_BATT: PR718.1 RE64.2
I_SYS: PR720.1 UE5.A57
ILMT_1.05V: PR304.2 PR306.1 PU300.3
IMON: PC500.2 PR521.2 PU501.3
INT-SPK-L+: RA1124.1 UA1.42
INT-SPK-L-: RA1123.1 UA1.43
INT-SPK-R+: RA1122.1 UA1.45
INT-SPK-R-: RA1121.1 UA1.44
INTRUDER#: RC7.2 UC1.AU6
IRQ_SERIRQ: RC102.2 UC1.T4 UE5.A28
ISOLATEB: R2360.2 RL30.1 RL33.2 UL1.20
ISPSCL: RV163.1 UV6.1 UV6.15
ISPSDA: RV164.1 UV6.2 UV6.16
ISUMN: PC529.1 PC530.1 PH501.1 PL502.3 PR535.2 PR545.2 PR549.1
ISUMP: PC529.2 PC530.2 PR536.2 PR549.2 PR551.2 PR558.1 PU501.10
IT6511_AUX#_C: CV350.2 UV6.19
IT6511_AUX_C: CV349.2 UV6.20
IT6511_N0_C: CV346.2 UV6.27
IT6511_N1_C: CV348.2 UV6.30
IT6511_P0_C: CV342.2 UV6.26
IT6511_P1_C: CV347.2 UV6.29
JACK_SENSE#: QA7.1 UA1.13
JCRT-11: JCRT.11 T87.1(TP-1)
JHDD_P10: JHDD.4 RS8.2
JTAG_CLK: JDEG.4 RPE7.3 UE5.B56
JTAG_RST#: CE59.1 JTAG1.1 RE65.2 RE66.1 UE5.B47
JTAG_TDI: JDEG.2 RPE7.1 UE5.A51
JTAG_TDO: JDEG.5 RPE7.4 UE5.B55
JTAG_TMS: JDEG.3 RPE7.2 UE5.A53
KB_BL_PWM#: JKBBL.4 QE11.1
KB_DET#: JKB.30 RC103.1 UC1.AT3
KSI0: JKB.22 U2412.18
KSI1: JKB.24 U2412.20
KSI2: JKB.26 U2412.23
KSI3: JKB.23 U2412.19
KSI4: JKB.27 U2412.25
KSI5: JKB.25 U2412.22
KSI6: JKB.28 U2412.26
KSI7: JKB.29 U2412.27
KSO00: JKB.13 U2412.11
KSO01: JKB.15 U2412.13
KSO02: JKB.14 U2412.12
KSO03: JKB.16 U2412.14
KSO04: JKB.20 U2412.16
KSO05: JKB.21 U2412.17
KSO06: JKB.18 U2412.15
KSO11: JKB.19 U2412.5
KSO12: JKB.17 U2412.10
KSO13: JKB.7 U2412.7
KSO14: JKB.5 U2412.6
KSO15: JKB.6 U2412.8
KSO16: JKB.12 U2412.9
KSO17: JKB.9 U2412.3
KSO18: JKB.8 U2412.2
KSO19: JKB.10 U2412.1
KSO20: JKB.11 U2412.47
LAN_CLKREQ#: R2340.2 UC1.AD1 UL1.12
LAN_DISABLE#_R: R2360.1 UE4.1
LAN_EN: RL27.2 UE5.B37 UL2.4
LAN_WAKE#: R2363.1 RC153.2 UC1.AN5 UE5.B27
LAN_WAKE#_R: R2363.2 R2532.2 UL1.21
LCD_CBL_DET#: JEDP.22 RC106.2 UC1.J3
LCD_TST: JEDP.8 RPE10.3 UE5.A38
LCD_VCC_TEST_EN: DV7.2 UE5.A39
LG_+1.35DGPU: PQ1001.4 PU1000.6
LGATE: PQ501.4 PU501.16
LID_CL#: JLED.4 RE26.1
LID_CL_SIO#: CE13.1 RE25.2 RE26.2 UE5.A21
LINE1-L: CA67.1 UA1.22
LINE1-R: CA68.1 UA1.21
LINE1-VREFO-L: RA165.1 UA1.31
LINE1-VREFO-R: RA166.1 UA1.30
LINE-IN-L: LA8.2 RA55.2 RA80.2 RA83.1 RA165.2
LINE-IN-R: LA9.2 RA56.2 RA82.2 RA84.1 RA166.2
LPC_LAD0: JLPDE.3 UC1.AU14 UE5.A30
LPC_LAD1: JLPDE.4 UC1.AW12 UE5.B32
LPC_LAD2: JLPDE.5 UC1.AY12 UE5.A31
LPC_LAD3: JLPDE.6 UC1.AW11 UE5.B33
LPC_LFRAME#: JLPDE.7 UC1.AV12 UE5.B31
LX_1.05V: PC302.2 PL301.1 PR302.1 PU300.10
LX_3V: PC104.1 PL100.2 PQ101.1 PQ101.2 PQ101.3 PQ102.5 PR113.1 PU100.8
LX_5V: PC110.2 PL101.2 PQ103.1 PQ103.2 PQ103.3 PQ104.5 PR112.1 PU100.18
M_CLK_DDR0: JDIMM1.101 UC1.AV37
M_CLK_DDR1: JDIMM1.102 UC1.AY36
M_CLK_DDR2: JDIMM2.101 UC1.AN38
M_CLK_DDR3: JDIMM2.102 UC1.AL38
M_CLK_DDR#0: JDIMM1.103 UC1.AU37
M_CLK_DDR#1: JDIMM1.104 UC1.AW36
M_CLK_DDR#2: JDIMM2.103 UC1.AM38
M_CLK_DDR#3: JDIMM2.104 UC1.AK38
M_ID2#: CV57.1 JCRT.4
M_ODT: CD64.1 QD2.3 R2348.1 R2349.1 R2350.1 R2352.1
M_ODT0: JDIMM1.116 R2348.2
M_ODT1: JDIMM1.120 R2349.2
M_ODT2: JDIMM2.116 R2350.2
M_ODT3: JDIMM2.120 R2352.2
MCT0: RL19.1 TL2.22
MCT1: RL20.1 TL2.21
MCT2: RL39.1 TL2.16
MCT3: RL40.1 TL2.15
MDI0+: TL2.12 UL1.1
MDI0-: TL2.11 UL1.2
MDI1+: TL2.8 UL1.4
MDI1-: TL2.7 UL1.5
MDI2+: TL2.6 UL1.6
MDI2-: TL2.5 UL1.7
MDI3+: TL2.2 UL1.9
MDI3-: TL2.1 UL1.10
MDO0+: JLAN.1 TL2.13
MDO0-: JLAN.2 TL2.14
MDO1+: JLAN.3 TL2.17
MDO1-: JLAN.6 TL2.18
MDO2+: JLAN.4 TL2.19
MDO2-: JLAN.5 TL2.20
MDO3+: JLAN.7 TL2.23
MDO3-: JLAN.8 TL2.24
ME_EN: RC8.1 SW3.2
ME_FWP_EC: SW3.3 UE5.B46
ME_RESET#: RC80.1 RC95.2 UC5.2
ME_SUS_PWR_ACK: RC27.2 RC42.1 UE5.A8
ME_SUS_PWR_ACK_R: RC42.2 UC1.AV4
MEC_XTAL1: CE62.1 UE5.A61 YE1.1
MEC_XTAL2: CE53.1 RE62.2 YE1.2
MEC_XTAL2_R: RE62.1 UE5.A62
MEM_SMBCLK: QC1.6 RP40.1 UC1.AP2
MEM_SMBDATA: QC1.3 RP40.2 UC1.AH1
MIC1-L: CA74.1 UA1.19
MIC_CLK: CA22.1 DX4.3 JEDP.11 LA1.2
MIC_CLK_C: LA1.1 UA1.3
MIC_DATA: DX4.2 JEDP.9 UA1.2
MSCLK: JDEG.6 RE72.2 UE5.B43
MSDATA: JDEG.7 RE75.2 RPE6.3 UE5.A40
MULTI_STRAP_REF0_GND: RV93.1 UV1.F6
MULTI_STRAP_REF1_GND: RV95.1 UV1.F4
MULTI_STRAP_REF2_GND: RV96.1 UV1.F5
NB_PSID: JDCIN.1 PD3.1 PL3.2
NTC: PR525.2 PU501.5
NVVDD_PSI: PR605.2 RV125.1 UV1.B4
PANEL_BKEN_EC: DV2.2 UE4.5
PANEL_BKLEN: DV2.3 UC1.A9
PBAT_PRES#: PR2.2 PR728.1 PRP1.1 UE5.A49
PBAT_SMBCLK: PRP1.3 RE45.2 UE5.A56
PBAT_SMBDAT: PRP1.2 RE38.2 UE5.B59
PBATT+_C: JBATT.8 JBATT.9 PC1.1 PC2.2 PL1.2 PL2.2 PL8.2
PC_BEEP: DA8.1 RA19.1 RA79.2
PCH_ALW_ON: R416.1 RPE10.4 UE5.A34
PCH_AZ_BITCLK: R2359.2 UC1.AW8
PCH_AZ_CODEC_BITCLK: CC5.1 R2359.1 RA1112.1 UA1.6
PCH_AZ_CODEC_RST#: R2358.1 UA1.11
PCH_AZ_CODEC_SDIN0: RA130.1 UC1.AY10
PCH_AZ_CODEC_SDOUT: R2356.1 UA1.5
PCH_AZ_CODEC_SYNC: R2357.1 UA1.10
PCH_AZ_RST#: R2358.2 UC1.AU8
PCH_AZ_SDOUT: R2356.2 RC8.2 UC1.AU11
PCH_AZ_SYNC: R2357.2 UC1.AV11
PCH_BATLOW#: RC39.2 UC1.AN4
PCH_CPU_ID: RC373.2 RC374.1 UC1.E4
PCH_DPWROK: UC1.AV5 UE5.A36
PCH_GPIO10: T27.1(TP-1) UC1.AM2
PCH_GPIO12: RC117.1 T182.1(TP-1) UC1.AM7
PCH_GPIO14: T126.1(TP-1) UC1.AH4
PCH_GPIO25: T127.1(TP-1) UC1.AM4
PCH_GPIO34: RP37.4 UC1.V1
PCH_GPIO36: RP43.7 UC1.V6
PCH_GPIO37: RP37.3 UC1.AC1
PCH_GPIO47: T174.1(TP-1) UC1.AB6
PCH_GPIO48: T124.1(TP-1) UC1.U4
PCH_GPIO66: RC118.2 UC1.D3
PCH_GPIO73: R2330.2 UC1.AU4
PCH_GPIO76: RC116.1 UC1.P1
PCH_GPIO77: RP60.8 UC1.U6
PCH_GPIO79: RP60.6 UC1.N4
PCH_GPIO80: RP43.5 UC1.N2
PCH_GPIO85: T175.1(TP-1) UC1.N6
PCH_GPIO87: T4931.1(TP-1) UC1.R7
PCH_GPIO90: T179.1(TP-1) UC1.K2
PCH_GPIO93: T180.1(TP-1) UC1.J2
PCH_GPIO94: T181.1(TP-1) UC1.G1
PCH_INTVRMEN: RC1.2 RC2.1 UC1.AV7
PCH_JTAG_JTAGX: RC59.2 RC62.2 RC130.1 UC1.AE63
PCH_JTAG_RST#: RC57.2 UC1.AU62
PCH_JTAG_TCK: JXDP.55 RC65.2 RC135.1 UC1.AE62
PCH_JTAG_TDI: RC44.1 RP48.8 UC1.AD61
PCH_JTAG_TDO: RC43.1 RC63.2 RP48.7 UC1.AE61
PCH_JTAG_TMS: RC46.1 RP48.6 UC1.AD62
PCH_OPI_COMP: RC101.1 UC1.AW15
PCH_PCIE_RCOMP: RC91.2 UC1.A27
PCH_PCIE_WAKE#: RC97.2 RE274.2 UE5.A44
PCH_PCIE_WAKE#_R: RC34.2 RC97.1 UC1.AJ5
PCH_PLTRST#: CC33.1 UC1.AG7 UC3.1 UC3.2
PCH_PLTRST#_EC: JLPDE.8 R159.1 RC51.1 RC367.1 RM6.2 UC3.4 UE5.B30 UL1.19
PCH_RSMRST#: RC41.1 RPE6.4 UE5.A45
PCH_RSMRST#_R: RC41.2 RC92.2 UC1.AW6
PCH_RTCRST#: CC4.2 CMOS1.2 RC6.2 UC1.AU7
PCH_RTCX1: CC1.2 RC4.1 UC1.AW5 YC1.1
PCH_RTCX2: CC2.2 RC4.2 UC1.AY5 YC1.2
PCH_SMB_ALERT#: R2329.2 UC1.AN2
PCH_SPI_CLK: R2333.2 UC1.AA3
PCH_SPI_CLK_R: C2326.1 R2333.1 U2302.6
PCH_SPI_CS0#: U2302.1 UC1.Y7
PCH_SPI_HOLD1#: R2335.2 RP39.4 U2302.7
PCH_SPI_HOLD#: RP39.5 UC1.AF1
PCH_SPI_MISO: RP39.7 UC1.AA4
PCH_SPI_MISO_1: RP39.2 U2302.2
PCH_SPI_MOSI: RP39.8 UC1.AA2
PCH_SPI_MOSI_1: RP39.1 U2302.5
PCH_SPI_WP1#: R2334.2 RP39.3 U2302.3
PCH_SPI_WP#: RP39.6 UC1.Y6
PCIE_PRX_LANTX_N3: CL31.1 UC1.G11
PCIE_PRX_LANTX_N3_C: CL31.2 UL1.18
PCIE_PRX_LANTX_P3: CL30.1 UC1.F11
PCIE_PRX_LANTX_P3_C: CL30.2 UL1.17
PCIE_PRX_WLANTX_N4: JNGFF.35 UC1.F13
PCIE_PRX_WLANTX_P4: JNGFF.33 UC1.G13
PCIE_PTX_LANRX_N3: CC32.1 UL1.14
PCIE_PTX_LANRX_N3_C: CC32.2 UC1.C29
PCIE_PTX_LANRX_P3: CC40.1 UL1.13
PCIE_PTX_LANRX_P3_C: CC40.2 UC1.B30
PCIE_PTX_WLANRX_N4: CM1.1 UC1.B29
PCIE_PTX_WLANRX_N4_C: CM1.2 JNGFF.29
PCIE_PTX_WLANRX_P4: CM2.1 UC1.A29
PCIE_PTX_WLANRX_P4_C: CM2.2 JNGFF.27
PCIE_WAKE#: JNGFF.47 R2532.1 RE274.1 RE275.1
PCIE_WAKE#_R: RE35.2 RE275.2 UE4.18
PECI_EC: DE2.1 RE61.2 UC1.N62
PECI_EC_R: RE61.1 UE5.A48
PEG_CRX_GTX_C_N0: CV189.1 UV1.AB9
PEG_CRX_GTX_C_N1: CV191.1 UV1.AC10
PEG_CRX_GTX_C_N2: CV193.1 UV1.AC11
PEG_CRX_GTX_C_N3: CV195.1 UV1.AB12
PEG_CRX_GTX_C_P0: CV188.1 UV1.AC9
PEG_CRX_GTX_C_P1: CV190.1 UV1.AB10
PEG_CRX_GTX_C_P2: CV192.1 UV1.AD11
PEG_CRX_GTX_C_P3: CV194.1 UV1.AC12
PEG_CRX_GTX_N0: CV189.2 UC1.F10
PEG_CRX_GTX_N1: CV191.2 UC1.F8
PEG_CRX_GTX_N2: CV193.2 UC1.H10
PEG_CRX_GTX_N3: CV195.2 UC1.E6
PEG_CRX_GTX_P0: CV188.2 UC1.E10
PEG_CRX_GTX_P1: CV190.2 UC1.E8
PEG_CRX_GTX_P2: CV192.2 UC1.G10
PEG_CRX_GTX_P3: CV194.2 UC1.F6
PEG_CTX_GRX_N0: CC18.2 UV1.AG7
PEG_CTX_GRX_N0_C: CC18.1 UC1.C23
PEG_CTX_GRX_N1: CC20.2 UV1.AE7
PEG_CTX_GRX_N1_C: CC20.1 UC1.B23
PEG_CTX_GRX_N2: CC22.2 UV1.AF9
PEG_CTX_GRX_N2_C: CC22.1 UC1.B21
PEG_CTX_GRX_N3: CC24.2 UV1.AG10
PEG_CTX_GRX_N3_C: CC24.1 UC1.B22
PEG_CTX_GRX_P0: CC19.2 UV1.AG6
PEG_CTX_GRX_P0_C: CC19.1 UC1.C22
PEG_CTX_GRX_P1: CC21.2 UV1.AF7
PEG_CTX_GRX_P1_C: CC21.1 UC1.A23
PEG_CTX_GRX_P2: CC23.2 UV1.AE9
PEG_CTX_GRX_P2_C: CC23.1 UC1.C21
PEG_CTX_GRX_P3: CC25.2 UV1.AG9
PEG_CTX_GRX_P3_C: CC25.1 UC1.A21
PEX_TSTCLK_OUT: RV24.2 UV1.AF22
PEX_TSTCLK_OUT#: RV24.1 UV1.AE22
PHASE: PC525.2 PQ501.3 PU501.15
PLT_RST#_R: JNGFF.44 RM6.1
PLTRST_GPU#: RC367.2 UV14.2
PM_APWROK_R: RC55.2 UC1.AB5
POWER_SW#_MB: CE21.1 RE33.2 SW1.2
POWER_SW_IN#: CE49.1 RE31.2 RE33.1 UE5.B67
PROC_OPI_RCOMP: RC134.1 UC1.AY15
PS_ID: PR4.1 PR5.2 UE5.B24
PWR_SRC_ON: CX4.2 QX2.3 RX2.2 RX3.1
RED: CV54.1 DV5.3 JCRT.1 LV16.2
RED_CRT: CV51.1 CV62.1 LV16.1 RV32.1 UV6.11
REM_DIODE1_N: CE47.1 CE48.2 CE58.1 QE3.3 QE7.1 QE7.2 UE5.B13
REM_DIODE1_P: CE47.2 CE48.1 CE58.2 QE3.1 QE3.2 QE7.3 UE5.A13
REM_DIODE2_N: CE69.2 CE70.1 QE12.3 UE5.B14
REM_DIODE2_P: CE69.1 CE70.2 QE12.1 QE12.2 UE5.A14
REM_DIODE3_N: CE39.1 CE66.2 QE10.3 UE5.A15
REM_DIODE3_P: CE39.2 CE66.1 QE10.1 QE10.2 UE5.B16
REM_DIODE4_N: CE51.1 CE60.1 QE8.3 UE5.A16
REM_DIODE4_P: CE51.2 CE60.2 QE8.1 QE8.2 UE5.B17
RESET_OUT#: CC34.1 RC47.1 RC55.1 RE56.2 UC6.2 UE5.B39
RESET_OUT#_R: RC47.2 UC1.AY7
RF_+1.35DGPU: PR1005.1 PU1000.5
RING2: LA11.2 RA1109.1 UA1.17
RING2_L: CA40.1 DA14.1 JHP.3 LA11.1
ROM_SCLK_GPU: RV122.1 RV128.2 UV1.C12
ROM_SI_GPU: RV59.2 RV123.1 UV1.B12
ROM_SO_GPU: RV124.1 RV129.2 UV1.A12
RSVD_AL1: T136.1(TP-1) UC1.AL1
RSVD_AM11: T137.1(TP-1) UC1.AM11
RSVD_AP7: T139.1(TP-1) UC1.AP7
RSVD_AT2: T128.1(TP-1) UC1.AT2
RSVD_AU10: T141.1(TP-1) UC1.AU10
RSVD_AU15: T142.1(TP-1) UC1.AU15
RSVD_AU44: T132.1(TP-1) UC1.AU44
RSVD_AV44: T134.1(TP-1) UC1.AV44
RSVD_AW14: T144.1(TP-1) UC1.AW14
RSVD_AY14: T145.1(TP-1) UC1.AY14
RSVD_D15: T135.1(TP-1) UC1.D15
RSVD_F22: T138.1(TP-1) UC1.F22
RSVD_H22: T140.1(TP-1) UC1.H22
RSVD_J21: T143.1(TP-1) UC1.J21
RSVD_N23: T129.1(TP-1) UC1.N23
RSVD_R23: T130.1(TP-1) UC1.R23
RSVD_T23: T131.1(TP-1) UC1.T23
RSVD_U10: T133.1(TP-1) UC1.U10
RUN_ON: PR300.2 PR402.1 Q8.2 R16.1 R2313.1 R2318.1 RPE10.1 UE5.B9
RUNPWROK: CC29.1 Q10.1 RE67.2 UC4.1 UC4.4 UC4.10 UC4.13 UE5.B26
SATA_ACT#: RP37.2 UC1.U3
SATA_IREF: RC126.1 UC1.A12
SATA_PRX_DTX_N0: CS31.2 JHDD.9
SATA_PRX_DTX_N0_C: CS33.1 UC1.J5
SATA_PRX_DTX_N0_R: CS31.1 US2.12
SATA_PRX_DTX_N0_RC: CS33.2 US2.4
SATA_PRX_DTX_P0: CS34.2 JHDD.10
SATA_PRX_DTX_P0_C: CS35.1 UC1.H5
SATA_PRX_DTX_P0_R: CS34.1 US2.11
SATA_PRX_DTX_P0_RC: CS35.2 US2.5
SATA_PTX_DRX_N0: CS32.2 JHDD.7
SATA_PTX_DRX_N0_C: CS36.1 UC1.B15
SATA_PTX_DRX_N0_R: CS36.2 US2.2
SATA_PTX_DRX_N0_RC: CS32.1 US2.14
SATA_PTX_DRX_P0: CS30.2 JHDD.6
SATA_PTX_DRX_P0_C: CS37.1 UC1.A15
SATA_PTX_DRX_P0_R: CS37.2 US2.1
SATA_PTX_DRX_P0_RC: CS30.1 US2.15
SATA_RCOMP: RC131.1 UC1.C12
SCLK_CPU: PR504.2 PR508.2 PU501.20
SDA_CPU: PR500.2 PR505.2 PU501.18
SIO_EXT_SCI#: RC98.2 UC1.N5 UE5.A33
SIO_EXT_SMI#: RC105.1 UC1.AG5 UE5.A6
SIO_EXT_WAKE#: RC109.1 UC1.AU2 UE5.B5
SIO_PWRBTN#: RC49.1 UC1.AL7 UE5.B58
SIO_RCIN#: RP43.8 UC1.V4 UE5.A27
SIO_SLP_A#: T4935.1(TP-1) UC1.AL5
SIO_SLP_S0#: T4939.1(TP-1) UC1.AF3
SIO_SLP_S3#: T4932.1(TP-1) UC1.AT4 UE5.A35
SIO_SLP_S4#: T4934.1(TP-1) UC1.AJ6 UE5.B36
SIO_SLP_S5#: T4933.1(TP-1) UC1.AP5 UE5.A18
SIO_SLP_SUS#: UC1.AP4 UE5.B52
SIO_SLP_WLAN#: UC1.AM5 UE4.39
SLEEVE: LA10.2 QA6.3 RA53.1 UA1.18
SLEEVE_L: CA38.1 DA12.1 JHP.4 LA10.1
SM_RCOMP0: RC68.1 UC1.AU60
SM_RCOMP1: RC69.1 UC1.AV60
SM_RCOMP2: RC70.1 UC1.AU61
SMART_DET#: T32.1(TP-1) UE4.9
SMB_ADDR: RE87.2 UE4.35
SML0CLK: R2527.1 UC1.AN1
SML0DATA: R2528.1 UC1.AK1
SML1_SMBCLK: RP40.3 UC1.AU3 UE5.B6
SML1_SMBDATA: RP40.4 UC1.AH3 UE5.A5
SNB_1.05V: PC301.1 PR302.2
SPK_L1-_CONN: CA30.1 JSPK.3 RA1123.2
SPK_L2+_CONN: CA29.1 JSPK.4 RA1124.2
SPK_R1-_CONN: CA32.1 JSPK.1 RA1121.2
SPK_R2+_CONN: CA31.1 JSPK.2 RA1122.2
SRTCRST#: CC3.2 RC5.2 UC1.AV6
STRAP0: RV49.1 RV157.2 UV1.D1
STRAP1: RV47.1 RV126.2 UV1.D2
STRAP2: RV94.1 RV127.2 UV1.E4
STRAP3: RV41.2 RV97.1 UV1.E3
STRAP4: RV98.1 RV99.2 UV1.D3
SUS_ON: PR201.1 RPE10.2 UE5.B23
SUS_STAT#/LPCPD#: RC29.2 UC1.AG4
SUSACK#: RC28.2 RC37.1 UE5.A23
SUSACK#_R: RC37.2 UC1.AK2
SUSCLK: RC107.2 RM5.2
SUSCLK_NGFF: JNGFF.42 RM5.1
SUSCLK_R: RC107.1 UC1.AE6
SUSP#: Q8.1 Q10.2 Q2307.2 QX5.2 R10.2
SW_1.35V: PC200.2 PL200.2 PQ200.1 PQ200.2 PQ200.3 PQ201.5 PR203.1 PU200.16
SW_+1.35DGPU: PC1004.2 PL1001.1 PQ1000.1 PQ1000.2 PQ1000.3 PQ1001.5 PR1004.1 PU1000.8
SW_CPU2: PL502.1 PQ501.5 PQ501.6 PQ501.7 PR534.1
SYS_PEX_RST_MON#: RV51.2 RV520.2 UV1.E9
SYS_PEX_RST_MON#_R: RV187.1 RV208.1 RV520.1 UV14.4
SYS_PWROK: CC31.1 RC40.1 RC52.1 UE5.B7
SYS_PWROK_R: RC40.2 UC1.AG2
SYS_PWROK_XDP: CC16.1 JXDP.47 RC52.2 RC64.1
SYS_RESET#: RC78.2 UC1.AC3 UC5.4
TDI_IREF: RC133.2 UC1.B12
TDI_XDP: JXDP.56 RC44.2 RC45.1
TDI_XDP_R: RC45.2 RC63.1 UC4.5
TDO_XDP: JXDP.52 RC43.2 RC62.1 RP44.4 UC4.2
THERMATRIP2#: CE61.1 QE9.1 RE69.2 UE5.B34
THERMATRIP3#: QV78.1 RPE6.1 RV140.2 UE5.A2
THERMATRIP_GPU#: QV78.3 RV103.2 RV140.1 UV1.A6
THSEL_STRAP: RE78.1 UE5.B29
TMDS_L_TX0N: CX25.1 JHDMI.9 LX3.3
TMDS_L_TX0P: CX26.1 JHDMI.7 LX3.2
TMDS_L_TX1N: CX27.1 JHDMI.6 LX4.3
TMDS_L_TX1P: CX28.1 JHDMI.4 LX4.2
TMDS_L_TX2N: CX29.1 JHDMI.3 LX5.3
TMDS_L_TX2P: CX30.1 JHDMI.1 LX5.2
TMDS_L_TXCN: CX23.1 JHDMI.12 LX2.3
TMDS_L_TXCP: CX24.1 JHDMI.10 LX2.2
TMDS_TX0N: CX14.1 LX3.4 RP59.4
TMDS_TX0P: CX15.1 LX3.1 RP59.3
TMDS_TX1N: CX16.1 LX4.4 RP58.4
TMDS_TX1P: CX17.1 LX4.1 RP58.3
TMDS_TX2N: CX18.1 LX5.4 RP58.2
TMDS_TX2P: CX19.1 LX5.1 RP58.1
TMDS_TXCN: CX12.1 LX2.4 RP59.2
TMDS_TXCP: CX13.1 LX2.1 RP59.1
TMS_XDP: JXDP.58 RC46.2 UC4.9
TON_1.35V: PR208.2 PU200.9
TOUCH_PANEL_INTR#: JEDP.30 RC372.1 UC1.P3
TOUCH_SCREEN_PD#: T101.1(TP-1) UE4.36
TP_DC_TEST_B2: T167.1(TP-1) UC1.B2
TRIP_+1.35DGPU: PR1002.2 PU1000.2
TRST#_XDP: JXDP.54 UC4.12
TS_EN: RP60.7 UC1.N7 UX3.4
U2_BOOT1: PR606.1 PU600.1
U2_BOOT2: PR618.1 PU600.18
U2_LGATE1: PQ601.4 PR615.1 PU600.23
U2_LGATE2: PQ603.4 PU600.20
U2_PHASE1: PC605.2 PL601.1 PQ600.1 PQ600.2 PQ600.3 PQ601.5 PR613.1 PU600.24
U2_PHASE2: PC617.2 PL602.1 PQ602.1 PQ602.2 PQ602.3 PQ603.5 PR622.1 PU600.19
U2_UGATE1: PR609.1 PU600.2
U2_UGATE2: PR619.1 PU600.17
UG_3V: PQ101.4 PU100.10
UG_5V: PQ103.4 PU100.16
UG_+1.35DGPU: PQ1000.4 PU1000.9
UGATE: PR513.1 PU501.14
USB3RN1_JUSB1: LI1.1 UC1.G20
USB3RN1_JUSB1_R: DI1.1 DI1.10 JUSB1.5 LI1.2
USB3RN2_JUSB2: LI4.1 UC1.E18
USB3RN2_JUSB2_R: DI4.1 DI4.10 JUSB2.5 LI4.2
USB3RP1_JUSB1: LI1.4 UC1.H20
USB3RP1_JUSB1_R: DI1.2 DI1.9 JUSB1.6 LI1.3
USB3RP2_JUSB2: LI4.4 UC1.F18
USB3RP2_JUSB2_R: DI4.2 DI4.9 JUSB2.6 LI4.3
USB3TN1_JUSB1: CI3.2 UC1.C33
USB3TN1_JUSB1_C: CI3.1 LI3.1
USB3TN1_JUSB1_R: DI1.4 DI1.7 JUSB1.8 LI3.2
USB3TN2_JUSB2: CI10.2 UC1.B33
USB3TN2_JUSB2_C: CI10.1 LI6.1
USB3TN2_JUSB2_R: DI4.4 DI4.7 JUSB2.8 LI6.2
USB3TP1_JUSB1: CI4.2 UC1.B34
USB3TP1_JUSB1_C: CI4.1 LI3.4
USB3TP1_JUSB1_R: DI1.5 DI1.6 JUSB1.9 LI3.3
USB3TP2_JUSB2: CI11.2 UC1.A33
USB3TP2_JUSB2_C: CI11.1 LI6.4
USB3TP2_JUSB2_R: DI4.5 DI4.6 JUSB2.9 LI6.3
USB20_BIO_N3: L12.1 RS26.1 UC1.AR10
USB20_BIO_N3_R: DS1.3 JFP.4 L12.2 RS26.2
USB20_BIO_P3: L12.4 RS27.1 UC1.AT10
USB20_BIO_P3_R: DS1.2 JFP.3 L12.3 RS27.2
USB20_CAM_N7: LX6.4 RX21.1 UC1.AR13
USB20_CAM_N7_R: DX3.2 JEDP.13 LX6.3 RX21.2
USB20_CAM_P7: LX6.1 RX22.1 UC1.AP13
USB20_CAM_P7_R: DX3.3 JEDP.14 LX6.2 RX22.2
USB20_CR_N6: JIO.12 UC1.AP11
USB20_CR_P6: JIO.11 UC1.AN11
USB20_JUSB1_N0: LI2.4 UC1.AN8
USB20_JUSB1_N0_R: DI2.2 JUSB1.2 LI2.3
USB20_JUSB1_P0: LI2.1 UC1.AM8
USB20_JUSB1_P0_R: DI2.3 JUSB1.3 LI2.2
USB20_JUSB2_N1: LI5.4 UC1.AR7
USB20_JUSB2_N1_R: DI5.2 JUSB2.2 LI5.3
USB20_JUSB2_P1: LI5.1 UC1.AT7
USB20_JUSB2_P1_R: DI5.3 JUSB2.3 LI5.2
USB20_JUSB3_N2: JIO.15 UC1.AR8
USB20_JUSB3_P2: JIO.14 UC1.AP8
USB20_MINI1_N4: JNGFF.5 UC1.AM15
USB20_MINI1_P4: JNGFF.3 UC1.AL15
USB20_TOUCH_N5: LX7.4 RX24.1 UC1.AM13
USB20_TOUCH_N5_R: DX2.2 JEDP.28 LX7.3 RX24.2
USB20_TOUCH_P5: LX7.1 RX23.1 UC1.AN13
USB20_TOUCH_P5_R: DX2.3 JEDP.27 LX7.2 RX23.2
USB_DB_DET#: T102.1(TP-1) UE4.7
USB_OC0#: CI15.1 RP55.1 UC1.AL3 UI3.3
USB_OC1#: CI17.1 RP55.2 UC1.AT1 UI2.3
USB_OC2#: CI47.1 RP55.3 UC1.AH2 UI4.3
USB_OC3#: RP55.4 UC1.AV3
USB_PWR_EN1#: CI13.1 RPE9.2 UE4.30 UI3.4
USB_PWR_EN2#: CI46.1 RPE9.1 UE4.31 UI4.4
USB_PWR_EN3#: CI26.1 RPE9.3 UE4.25 UI2.4
USBRBIAS: RC90.1 UC1.AJ10 UC1.AJ11
VCI_IN1#: RPE5.3 UE5.A63
VCI_IN2#: RPE5.4 UE5.B63
VCI_IN3#: RPE5.2 UE5.B68
VGA_ID: RE89.1 RE90.1 UE4.19
VL: PC106.1 PU100.13
VR12.5_VR_ON_R: R250.2 UC1.F60
VR_HOT#_1: PR510.2 PU501.4
VR_ON: C80.1 PR511.1 R250.1 RC364.2
VR_ON_1: PR511.2 PU501.1
VR_READY_R: R251.2 UC1.C59
VR_SVID_ALRT#: PR506.1 R252.2 R254.2
VR_SVID_CLK: PR508.1 R248.1
VR_SVID_DAT: PR505.1 R257.2
VSET_5085: CE55.1 RE77.1 UE5.A17
VSYNC: RV171.1 UV6.3
VSYNC_CONN: CV58.1 JCRT.14 LV20.2 RV37.2
VSYNC_CRT: LV20.1 UV3.4
VSYNC_R: RV171.2 UV3.2
VTTREF_1.35V: PC210.1 PU200.4
WLAN_CLKREQ#: JNGFF.45 R2342.2 UC1.N1
WLAN_LAN_DISBL: Q9.2 UL1.26
WLAN_LAN_DISBL#: Q9.1 R11.2 UE4.13
WLAN_WIGIG60GHZ_DIS#: JNGFF.48 RE14.2 UE4.17
XDP_DBRESET#: CC17.1 JXDP.48 RC78.1 RC362.2 UC5.1
XDP_OBS0_R: JXDP.21 UC1.J60
XDP_OBS1_R: JXDP.23 UC1.H60
XDP_PRDY#: JXDP.5 UC1.J62
XDP_PREQ#: JXDP.3 RP44.3 UC1.K62
XDP_RST#_R: JXDP.46 RC51.2
XDP_TCLK: JXDP.57 RC59.1 RC65.1 RC371.1 UC1.E60
XDP_TDI: RP44.2 UC1.F63 UC4.6
XDP_TDO: RC366.1 UC1.F62 UC4.3
XDP_TMS: RP44.1 UC1.E61 UC4.8
XDP_TRST#: RC57.1 RC129.2 UC1.E59 UC4.11
XTAL24_IN: CC6.2 RC12.2 UC1.A25 YC2.3
XTAL24_OUT: CC7.2 RC12.1 UC1.B25 YC2.1
XTALOUTBUFF: RV39.1 UV1.C10
XTALSSIN: RV23.1 UV1.A10
XTLI: CL36.2 UL1.29 YL2.1
XTLO: CL37.2 UL1.28 YL2.3
N71037: RA130.2 UA1.8
N71249: CA62.2 RA1129.2 UA1.27
N71261: CA63.2 UA1.39
N71273: CA64.2 UA1.7
N71383: CA24.1 UA1.37
N71395: CA24.2 UA1.35
N71399: CA25.2 UA1.34
N71447: CA23.2 UA1.28
N71593: CA65.1 UA1.12
N76526: RA1113.2 UA1.4
N3691692: PC1004.1 PR1001.2
N3691782: PC1009.1 PR1004.2
N15534060: PC746.2 PC747.1 PR705.2 PU700.1
N15534062: PC745.2 PC746.1 PR738.2 PU700.2
N15534082: PC726.2 PC727.1 PR710.2 PU700.20
N15534214: PR730.2 PU700.3
N15534246: PR713.2 PR714.2 PR715.1 PU700.5
N15534264: PC718.1 PR716.2 PU700.7
N15534266: PC719.1 PR718.2 PU700.8
N15534276: PR720.2 PR732.1 PU700.9
N15534316: PR717.2 PU700.10
N15534326: PR725.2 PR729.1 PU700.16
N15534338: PR728.2 PU700.15
N15534350: PR704.1 PU700.18
N16995670: PC607.1 PR602.2 PR603.2 PR604.1
N17002494: PC614.1 PR613.2
N17002564: PC625.1 PR622.2
N17002616: PC617.1 PR618.2
N17002633: PC605.1 PR606.2
N17092107: PR607.2 PR610.1
N17145436: PC307.2 PR309.1
N17209372: PR731.2 PU700.4
N17438484: CA21.1 RA1112.2
N17493058: JNGFF.36 T4927.1(TP-1)
N17493084: JNGFF.40 T4929.1(TP-1)
N17493086: JNGFF.38 T4928.1(TP-1)
N17493091: JNGFF.6 T3861.1(TP-1)
N17493111: JNGFF.16 T3862.1(TP-1)
N17607640: PC300.1 PR300.1 PR301.1 PU300.1
N17607658: PC313.1 PR310.1 PU300.7
N17607660: PR305.2 PR307.1 PR309.2 PU300.4
N17850379: C5259.1 U2412.21
N17850383: R2484.1 U2412.28
N17951580: RE24.1 UE4.38
N17955062: RE64.1 UE5.B61
N17955064: CE52.1 RE80.2
N17955068: QE9.2 RE70.2
N17955070: RE57.1 RE63.1 UE5.A59
N18087789: RV42.1 UV1.D22
N18087791: RV44.1 UV1.C24
N18087793: RV43.1 UV1.B25
N18094610: CL42.1 L18.2 UL1.24
N18094620: CL33.1 RL19.2 RL20.2 RL39.2 RL40.2
N18094850: RL31.2 UL1.31
N18095026: T94.1(TP-1) UL1.27
N18095028: T95.1(TP-1) UL1.25
N18096585: RV46.1 UV1.F22
N18097114: RV130.1 UV1.J22
N18127046: JKBBL.2 R2518.2
N18131448: C5291.1 U2304.10
N18135480: RC38.2 UA1.47
N18264318: PQ501.2 PR513.2
N18265058: PC110.1 PR111.2
N18272632: CV341.1 UV6.6
N18272698: RV160.1 UV6.5
N18272737: RV161.2 UV6.43
N18272741: RV162.2 UV6.42
N18274085: RV169.1 UV3.1 UV5.1
N18287656: JDIMM1.197 RD6.2
N18287658: JDIMM1.201 RD7.2
N18289776: CD21.1 CD22.1 JDIMM1.126 RD4.1
N18291638: JDIMM2.197 RD13.1
N18291647: JDIMM2.201 RD12.1
N18292747: PQ1.2 PQ2.1 PR7.1
N18293676: CD52.1 CD53.1 JDIMM2.126 RD10.1
N18297343: PC100.1 PR100.2 PR101.2 PR102.2
N18299507: PQ102.4 PU100.11
N18300498: PQ104.4 PU100.15
N18346513: C1160.1 Q327.1 Q330.2 R990.1
N18346584: Q330.1 R944.1
N18421110: PR110.2 PR115.1 PU100.7
N18454857: CA65.2 CA69.1 RA79.1 RA81.2
N18525878: PQ600.4 PR609.2
N18526201: PQ602.4 PR619.2
N18626460: DA13.3 JHP.5 RA1120.1
N18628488: RA1130.2 UA1.20
N18659385: PC302.1 PR303.2
N18675947: PC700.2 PC701.2 PQ702.4 PQ708.3 PR731.1 PR737.2
N18774013: R2341.2 UC1.U2
N18774065: R2343.2 UC1.Y5
N18774118: R2344.2 UC1.T2
N18838006: RV31.1 UV1.D10
N18868218: T96.1(TP-1) UV1.D23
N18923200: DC1.2 RC10.1
N19163204: QX3.2 RX13.2
N19365430: PC520.1 PR534.2
N19373700: PC522.2 PR537.2 PR543.1 PU501.7
N19373709: PC527.1 PR543.2
N19505504: T117.1(TP-1) UC1.AD4
N19636370: QA6.2 RA6.2
N19793702: C5292.1 U2301.12
N19793725: C5293.1 U2301.10
N19794620: QA6.5 QA6.6 RA5.2
N19883960: PR624.1 PU600.14
N20088578: PR719.2 PU700.11
N20088579: PR721.2 PU700.12
N20173262: RV215.1 UV6.45
N20267138: PC526.1 PR539.2
N20270870: PQ701.4 PR737.1
N20335974: RL41.1 UL2.3
N20382121: T4930.1(TP-1) UV6.28
N20424725: PC727.2 PC728.1 PR710.3 PU700.19
N20451836: RV518.2 UV6.37
N20469401: PQ708.1 PQ708.2
N20526852: DV1.1 JEDP.5 RX26.1
N20526883: QX1.1 RX3.2
N20527415: RX30.1 UX1.3
N20613673: PR706.1 PU700.21
N20614981: PD702.1 PD703.1 PR708.1
N20617538: PQ3.5 PQ3.6 PR10.2 PR11.1
N20617570: PC11.1 PQ3.2 PR9.2 PR13.1
N20617589: PQ3.3 PR12.2
N20641621: QV14.2 QV14.5 RV252.1 RV253.1
N20665046: CM8.1 UM1.6
N20693027: RS22.2 US2.7
N20735659: RC9.2 SW3.1
N20757845: DE3.2 JFAN.3 RE58.2
N20803831: CV344.2 RV159.2 YV3.3
N20931556: PC729.1 PR723.1 PU700.17
N21289444: PC403.2 PR400.2 PR401.1 PU400.2
N21493914: CV140.1 UV15.12
N21493916: CV141.1 UV15.10
N22407138: RV515.1 UV1.B9
N22407258: RV514.1 UV1.A9
N22407318: RV513.1 UV1.C8
N22407379: RV512.1 UV1.C9
N22407441: RV511.1 UV1.A7
N22407504: RV510.1 UV1.B7
N22671400: RV193.2 UV15.5
N22753389: PC525.1 PR538.2
N22753454: PH500.2 PR525.1 PR528.2
N22753537: PL502.2 PR536.1
N22753594: PR507.1 PU501.17
N22753687: PC522.1 PR533.2
N22753760: PC523.1 PR535.1 PU501.9
N22753762: PC523.2 PR545.1
N22753790: PH501.2 PR551.1
N22878624: PL3.1 PQ1.1 PR3.1 PR6.2
N22878630: PQ1.3 PR3.2 PR5.1
N22878645: PQ2.2 PR6.1 PR8.2
N22892968: PR538.1 PU501.13
N22894348: PR512.1 PU501.11
N43510017: RV25.1 UV1.AF25
N47415217: PC104.2 PR103.1
N47415258: PC103.1 PR113.2
N47415272: PC111.1 PR112.2
N47445410: PR114.1 PU100.19
N47894294: CC8.2 RC23.1
N47894380: CC9.2 RC24.1
N47894401: CC10.2 RC25.1
N47938591: T118.1(TP-1) UC1.AN10
N47938593: T119.1(TP-1) UC1.AM10
N47938689: T120.1(TP-1) UC1.E15
N47938710: T121.1(TP-1) UC1.E13
N47964855: T153.1(TP-1) UC1.L60
N47964866: T154.1(TP-1) UC1.N60
N47964871: T155.1(TP-1) UC1.W23
N47964873: T156.1(TP-1) UC1.Y22
N47964879: T157.1(TP-1) UC1.AV62
N47964884: T158.1(TP-1) UC1.D58
N47965485: T146.1(TP-1) UC1.AV63
N47965487: T147.1(TP-1) UC1.AU63
N47965493: T159.1(TP-1) UC1.A5
N47965495: T148.1(TP-1) UC1.C63
N47965502: T161.1(TP-1) UC1.E1
N47965509: T149.1(TP-1) UC1.C62
N47965511: T163.1(TP-1) UC1.D1
N47965522: T150.1(TP-1) UC1.B43
N47965524: T164.1(TP-1) UC1.J20
N47965529: T151.1(TP-1) UC1.A51
N47965534: T152.1(TP-1) UC1.B51
N47965536: T165.1(TP-1) UC1.H18
N55200533: QX3.1 RP58.5 RP58.6 RP58.7 RP58.8 RP59.5 RP59.6 RP59.7 RP59.8
N55201771: JHDMI.13 RX12.2
N60531222: R2523.1 UC1.C35
N60531228: R2524.1 UC1.C34
N60531230: R2525.1 UC1.AK8
N60531232: R2526.1 UC1.AL8
N60754677: T111.1(TP-1) UC1.H61
N60754679: T112.1(TP-1) UC1.H62
N60754681: T113.1(TP-1) UC1.K59
N60754683: T114.1(TP-1) UC1.H63
N60754685: T115.1(TP-1) UC1.K60
N60754687: T116.1(TP-1) UC1.J61
N60931942: T97.1(TP-1) UC1.AF2
N60931944: T99.1(TP-1) UC1.AF4
N60931946: T98.1(TP-1) UC1.AD2
N61580896: Q2307.1 R2314.2
N63469524: CA68.2 RA82.1
N63469526: CA67.2 RA80.1
N63642793: C51.1 R264.2 UC1.AH11
N63643467: T53.1(TP-1) UC1.J13
N63643476: T55.1(TP-1) UC1.AH13
N63643505: T56.1(TP-1) UC1.AB8
N63643514: T58.1(TP-1) UC1.AD10
N63643523: T59.1(TP-1) UC1.AD8
N63656577: T38.1(TP-1) UC1.AB23
N63657072: T39.1(TP-1) UC1.P60
N63657081: T40.1(TP-1) UC1.P61
N63657090: T41.1(TP-1) UC1.N59
N63657099: T42.1(TP-1) UC1.N61
N63657120: T43.1(TP-1) UC1.T59
N63657126: T44.1(TP-1) UC1.AD60
N63657135: T45.1(TP-1) UC1.AD59
N63657146: T46.1(TP-1) UC1.AA59
N63657155: T47.1(TP-1) UC1.AE60
N63657164: T48.1(TP-1) UC1.AC59
N63657173: T49.1(TP-1) UC1.AG58
N63657182: T50.1(TP-1) UC1.U59
N63657191: T51.1(TP-1) UC1.V59
N72585933: PC207.1 PR203.2
N104716789: PC401.1 PJP400.2 PU400.5 PU400.9
N104716883: PC402.1 PR402.2 PR403.1 PU400.8
N205274341: RX31.1 UX3.3

Pads without a net: DV6 3; FD1 1; FD2 1; FD3 1; FD4 1; JDEG 9; JDIMM1 77 122 125 198; JDIMM2 77 122 125 198; JEDP 3 15 18; JHDMI 14; JIO 5 7; JKB 2 3; JKBBL 3; JLED 2; JNGFF 8 9 10 11 12 13 14 15 17 19 20 21 22 23 24 26 28 30 32 34 50 51 52 53 54 56 57 58 59 60 62 63 65; JTP 1 2 3 4; JXDP 40 42; PRP1 4 5; PU200 10; PU400 7; PU700 13 14; RP48 4 5; RPE6 2; RPE9 4; SW1 1 4; U2303 1; U2304 12; U2412 29 30 31 35 36 38 42 43 44 45 46; UA1 14 15 16 23 24 48; UC1 A17 A31 A35 A37 A41 A49 A53 AA23 AB21 AC2 AC4 AC20 AC58 AD5 AD7 AD23 AE59 AF20 AG3 AG6 AJ7 AK4 AL2 AL4 AL11 AL32 AM3 AN3 AP1 AP32 AT5 AU12 AV2 AV10 AV50 AW10 AW49 AY8 AY42 AY43 B14 B17 B31 B35 B37 B41 B49 B50 B53 C3 C4 C15 C17 C30 C31 C42 C43 C46 C47 C49 D17 D61 E2 E3 E5 F5 F15 F17 G2 G15 G17 H6 H8 J4 J6 J8 J58 K4 K10 K18 K21 L1 L4 L5 L11 L59 M20 M21 N58 P2 P20 R20 T3 U7 V21 Y1 Y2 Y4 Y20; UC6 1; UE4 4 10 14 15 16 21 23 24 26 27 29 37; UE5 A3 A4 A9 A50 B2 B4 B8 B15 B28 B38 B41 B42 B53 B62; UV1 AA1 AA2 AA3 AA4 AA5 AA6 AB1 AB2 AB3 AB4 AB5 AB6 AB13 AB15 AB16 AB18 AB19 AB21 AC3 AC4 AC13 AC14 AC15 AC16 AC17 AC18 AC19 AC20 AC21 AD1 AD2 AD3 AD4 AD5 AD7 AD10 AD14 AD17 AD20 AD23 AE1 AE2 AE3 AE4 AE10 AE12 AE13 AE15 AE16 AE18 AE19 AE21 AE23 AE24 AF2 AF3 AF4 AF10 AF12 AF13 AF15 AF16 AF18 AF19 AF21 AF24 AG3 AG12 AG13 AG15 AG16 AG18 AG19 AG21 AG22 AG24 AG25 B2 B3 B6 B19 C1 C2 C3 C6 C7 C18 D4 D5 D6 D11 D12 D16 D17 D18 E6 E10 E12 F7 F8 F9 F10 F11 F12 G1 G2 G3 G4 G5 G6 G7 H3 H4 H6 J1 J2 J3 J4 J5 J6 J7 K1 K2 K3 K4 K5 K6 K7 L3 L4 M1 M2 M3 M4 M5 M7 N1 N2 N3 N4 N5 N6 N7 P3 P4 P6 R1 R2 R3 R4 R5 R6 R7 T1 T2 T3 T4 T5 T6 T7 T24 U3 U4 U6 U24 V1 V2 V3 V4 V5 V6 V7 V24 V25 W1 W2 W3 W4 W5 W6 W7 Y3 Y4 Y6; UV6 41 47; UV17 J1 J9 L1 L9; UV18 J1 J9 L1 L9; UV19 J1 J9 L1 L9; UV20 J1 J9 L1 L9; YC2 2 4

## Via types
v1: diameter 0.305, hole 0.152, TOP to BOTTOM, 674 vias
v2: diameter 0.457, hole 0.203, TOP to BOTTOM, 3979 vias
v3: diameter 0.406, hole 0.203, TOP to BOTTOM, 174 vias
v4: diameter 0.508, hole 0.254, TOP to BOTTOM, 1191 vias
v5: diameter 0.508, hole 0.203, TOP to BOTTOM, 2 vias

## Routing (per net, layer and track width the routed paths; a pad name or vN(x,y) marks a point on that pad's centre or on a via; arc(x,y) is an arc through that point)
0.675V_DDR_VTT_ON: length 131.4
  TOP w0.254: v2(143.72,55.45) 142.97,55.45 141.61,56.81 QD2.2 ; R2347.2 R2351.2 141.28,54.67 QD2.2 ; v2(81.89,27.56) 81.89,29.64 85.15,32.9 85.15,37.06 84.64,37.57 84.64,42.85 89.89,48.1 89.89,50.08 92.03,52.22 v1(93.16,52.22) v2(93.93,52.22) ; U2303.4 137.29,57.32 137.8,56.81 QD2.2
  IN1 w0.254: v2(54.03,31.04) 54.89,30.18 54.89,27.99 59.01,23.88 77.55,23.88 78.13,24.46 78.8,24.46 v2(81.89,27.56)
  BOTTOM w0.254: v2(143.72,55.45) 143.16,54.89 100.61,54.89 97.95,52.22 v2(93.93,52.22) ; PR202.1 55.6,34.85 54.69,33.94 54.69,31.7 v2(54.03,31.04)
1.35V_B+: length 12.2
  TOP w0.508: v4(60.25,37.52) PR208.1
  IN2 w0.508: v4(60.25,37.52) 61.27,38.53 67.87,38.53 69.65,36.76 v4(69.65,35.79)
  vias: v1(69.66,40.68) v4(70.29,35.79) v4(70.92,35.84) v4(71.56,35.84)
3/5V_B+: length 10
  TOP w0.203: v4(47.68,29.14) 47.88,28.94 PU100.12
  IN3 w0.381: v4(42.85,28.12) 44.43,28.12 45.19,28.88 47.43,28.88 v4(47.68,29.14)
  BOTTOM w0.508: v4(47.68,29.14) 47.79,29.25 PC105.1
  vias: v1(41.3,29.57) v4(42.22,28.88) v4(42.19,28.2) v4(42.78,29.64)
3V3_MAIN_EN: length 120
  TOP w0.254: v2(48.95,61.27) 48.02,60.34 47.13,60.34 44.63,57.84 44.17,57.84 42.8,56.47 42.8,53.11 43.11,52.81 43.11,47.55 43.39,47.27 43.39,42.83 44.38,41.84 v1(45.76,41.84) 49.84,41.84 v2(50.41,41.26)
  IN1 w0.254: v2(48.95,61.27) 49.69,62 53.4,62 55.59,64.19 68.57,64.19 70,65.62 70,68.6 70.91,69.51 70.91,74.07 70.01,74.97 70.01,79.1 70.44,79.53 70.44,84.89 71.59,86.04 71.59,88.02 70.74,88.87 70.74,89.05 70.03,89.77 70.03,94.9 72.76,97.63 72.76,98.16 73.08,98.48 73.51,98.48 73.92,98.88 73.92,99.42 75.87,101.37 77.3,101.37 77.7,100.97 v2(77.7,100.51)
  IN3 w0.254: v2(90.89,103.84) 87.25,103.84 85.06,101.65 80.79,101.65 79.65,100.51 v2(77.7,100.51)
  BOTTOM w0.102: UV1.A3 73.37,97.37 74.35,98.35 75.39,98.35 76.24,99.2 76.24,99.62 76.94,100.32 77.51,100.32 v2(77.7,100.51) 77.83,100.38 RV188.2
  BOTTOM w0.254: RV185.1 91.08,102.43 91.08,103.65 v2(90.89,103.84) ; PR608.2 50.68,41.6 50.41,41.33 v2(50.41,41.26)
3V3_MAIN_EN_R: length 3.4
  BOTTOM w0.102: v1(90.47,102.94) 90.47,102.63 89.62,101.78 RV185.2
  BOTTOM w0.203: UV15.3 88.24,101.93 88.29,101.98 89.31,101.98 RV185.2
3V_DSW: length 1.4
  TOP w0.102: 176.36,68.57 v1(176.36,69.97)
3V_EN: length 13.9
  TOP w0.203: PU100.6 v2(53.14,30.03)
  BOTTOM w0.203: PR100.1 56.95,21.85 57.92,21.85 58.59,22.52 PD101.2
  BOTTOM w0.254: PD101.2 57.89,23.8 56.95,23.8 56.54,24.21 55.43,24.21 53.88,25.76 53.88,26.3 v1(53.76,26.42) 53.14,27.04 v2(53.14,30.03)
3VALW_PCH:
  vias: v1(177.63,62.4)
3VS:
  vias: v1(177.4,54.6)
3VS_GATE: length 6.3
  TOP w0.102: R2318.2 181.58,49.73 181.58,48.14 v3(181.28,47.84)
  TOP w0.203: U2301.3 179.87,51.3 180.64,50.54 C2322.1
  TOP w0.254: C2322.1 181.72,50.54 182.05,50.21 R2318.2
5V_EN: length 10.2
  TOP w0.203: PR101.1 54.84,22.58 54.11,23.32 v1(54.11,24.45) 54.11,25.23 53.47,25.87 53.47,25.96 53.22,26.22 53.03,26.22 52.58,26.66 PU100.20
  TOP w0.254: PR101.1 54.84,21.82 55.07,21.59 56.2,21.59 56.94,22.33 v2(57.51,22.33)
  BOTTOM w0.254: PD101.3 57.59,22.41 v2(57.51,22.33)
5VS: length 1.1
  TOP w0.102: 184.37,55.12 184.75,55.12 v1(185.25,54.62)
5VS_GATE: length 7.5
  TOP w0.102: v1(186.95,50.55) 184.99,50.55 184.64,50.2 R2313.2
  TOP w0.203: C2309.1 182.55,50.57 182.14,50.98 181.56,50.98 180.67,51.87 U2301.5
  TOP w0.254: C2309.1 183.7,50.57 184,50.27 184.26,50.27 R2313.2
+0.675VS: length 145.5
  TOP w0.508: v2(177.07,45.34) 177.07,47.21 R2314.1 ; v2(152.38,26.93) 152.49,27.04 152.49,27.67 154.57,29.75 168.76,29.75 169.63,30.61
  IN1 w0.508: v2(81.28,31.22) 82.92,29.58 95.24,29.58 97.03,27.79 100.59,27.79 103.84,24.54 130.13,24.54 130.56,24.97 132.28,24.97 134.19,26.88 135.65,26.88 136.77,25.75 151.2,25.75 v2(152.38,26.93)
  IN2 w0.508: v2(177.07,45.34) 177.07,42.7 174.93,40.57 173.66,40.57 v2(171.51,38.41)
  BOTTOM w0.254: 58.45,26.24 58.45,26.29 58.75,26.6 PJP203.2
  BOTTOM w0.305: JDIMM2.203 171.15,38.11 171.38,38.34 171.44,38.34 v2(171.51,38.41)
  BOTTOM w0.356: JDIMM2.204 171.45,29.93 170.9,30.48 v2(170.87,30.48) ; JDIMM1.203 159.14,50.04 159.14,48.97 160.08,48.03 v2(160.13,48.03) ; JDIMM1.204 159.45,43.25 v2(159.42,43.28)
  BOTTOM w0.508: 58.45,26.24 58.45,25.91 61.45,22.91 62.91,22.91 64.16,21.66 73.66,21.66 81.28,29.28 v2(81.28,31.22)
  vias: v3(164.7,41.33)
+0.675VSP: length 6.2
  TOP w0.102: v4(59.14,29.85) 59.48,29.85 v1(59.94,30.3)
  IN3 w0.254: v4(62.06,27.47) 62.06,28.12 60.33,29.85 v4(59.14,29.85)
  BOTTOM w0.203: PU200.2 59.24,29.96 v4(59.14,29.85)
+1.05V_LDO_3V: length 6.8
  IN1 w0.254: v2(100.01,122.94) 99.12,122.05 97.59,122.05 96.75,121.21 96.75,120.7 96.37,120.32 v4(96.36,120.32)
  BOTTOM w0.102: v3(100.31,123.42) 100.01,123.12 v2(100.01,122.94)
  BOTTOM w0.254: PR304.1 99.22,122.52 99.64,122.94 v2(100.01,122.94)
+1.05V_PEX_VDD: length 26.3
  TOP w0.102: v3(58.56,75.03) 58.56,75.59 58.76,75.79 LV26.1
  TOP w0.508: v2(63.66,80.39) 63.91,80.65 CV205.1 ; CV65.1 60,80.95 v2(60.38,81.33) ; LV26.1 58.76,77 57.52,78.25 CV16.1 57.52,79.29 v2(57.85,79.62) ; CV135.1 62.17,80.63 v2(61.95,80.42) ; CV211.1 58.65,81.26 v2(58.68,81.23) ; LV8.1 76.36,88.72 75.33,89.75 LV10.1 75.32,89.98 v2(75.32,90.9) ; CV63.1 67.39,81.05 66.86,81.05 v2(66.81,81.1)
  BOTTOM w0.305: v2(53.7,76.33) 53.36,76.67 UV1.AF27 UV1.AE27 ; UV1.AA19 60.38,81.24 v2(60.38,81.33) ; UV1.AA16 62.34,80.81 v2(61.95,80.42) ; UV1.AE25 54.98,77.57 v2(55.38,77.17) ; UV1.AF26 54.54,77.14 v2(54.54,77.17) 54.16,77.54 UV1.AE26 ; UV1.AA15 63.24,80.81 v2(63.66,80.39) 64.06,80.8 UV1.AA14 ; UV1.AD24 55.84,78.37 v2(56.27,78.79) 56.61,79.14 UV1.AC23 ; UV1.AA18 61.14,80.42 v2(61.14,80.4) ; UV1.AA10 67.09,81.1 v2(66.81,81.1) ; UV1.AC24 55.76,79.18 v2(55.38,78.79) 54.96,78.38 UV1.AD25 ; UV1.AB22 57.84,80.44 v2(57.89,80.44) 58.26,80.82 UV1.AA21 ; UV1.AA20 59.04,80.87 v2(58.68,81.23) ; UV1.AA22 57.4,80.8 v2(57.05,80.44) 56.68,80.07 UV1.AB23 ; UV1.AA13 64.9,80.93 v2(65.28,81.31) 65.7,80.89 UV1.AA12
  vias: v2(55.36,77.97) v2(56.21,79.63) v2(76.1,89.87) v2(76.46,90.35) v2(76.79,90.83) v2(84.74,105.49) v2(84.76,106.07) v2(85.35,106.07)
+1.05V_PEX_VDD_UV15: length 1.5
  BOTTOM w0.102: CV139.1 84.33,104.29 v1(83.99,104.64)
+1.05V_PGOOD: length 4.6
  BOTTOM w0.203: PU300.2 97.8,119.57 97.8,119.81 98.47,120.47 v1(99.64,120.47) 100.47,120.47 100.77,120.77 100.81,120.77
  BOTTOM w0.508: PR308.2 101.51,121.34 100.94,120.77 100.81,120.77
+1.5VS: length 146.9
  TOP w0.254: v2(183.29,99.34) 178.92,103.71 178.92,109.79 178.55,110.16 177.08,110.16 176.57,110.67 176.57,111.17 175.34,112.4 170.82,112.4 v3(169.23,113.98) 167.11,116.11 v2(167.11,117.22) ; v2(147.39,100.06) 147.85,99.6 148.8,99.6 149.86,100.66 149.86,102.21 149.69,102.39 149.69,103.89 150.27,104.47 155.88,104.47 157.23,105.82 v2(157.23,109.37)
  TOP w0.508: RA8.1 191.44,26.67 v2(191.83,26.29)
  IN1 w0.254: v2(166.45,117.22) 166.45,112.87 162.95,109.37 160.11,109.37 159.59,109.9 157.75,109.9 v2(157.23,109.37)
  IN2 w0.254: v2(191.83,26.29) 192.07,26.54 192.11,26.54 196.37,30.79 196.37,35.98 197.26,36.87 197.26,39.91 197.72,40.36 197.72,41.05 195.46,43.31 195.46,45.04 194.01,46.48 194.01,48.49 193.15,49.35 193.15,51.97 192.13,52.99 192.13,62.51 191.09,63.55 191.09,67.11 190.53,67.67 190.53,72.38 184.12,78.79 184.12,92.26 185.39,93.53 185.39,97.91 183.93,99.37 183.32,99.37 v2(183.29,99.34)
  BOTTOM w0.254: v2(147.39,100.06) 147.7,99.75 147.8,99.75 UC1.J15
+1.05VS: length 322.1
  TOP w0.203: C61.1 147.02,90.43 v2(147.6,89.84) ; RP44.6 117.51,117.13 v4(117.86,117.48) 118.01,117.32 RP44.5 ; C66.1 152.26,109.39 152.02,109.15 C67.1 151.49,108.23 151.01,108.23 v4(150.7,107.93) ; RP44.7 117.01,117.54 116.9,117.66 116.51,117.66 v2(116.49,117.63) 116.51,117.6 RP44.8 ; v2(145.47,95.53) 145.5,95.56 C76.1 146.08,96.45 C88.1 ; CC15.1 84.09,79.16 JXDP.44 ; v4(160.89,21.01) 160.89,19.87 RE70.1 ; v2(146.82,89.82) 146.77,89.82 C62.1
  TOP w0.254: CE50.1 142.83,20.83 145.39,20.83 146.3,19.93 UE5.B51
  TOP w0.279: JXDP.43 92.5,79.16 92.97,78.69 92.97,78.51 93.3,78.18 CC14.1
  TOP w0.305: C53.1 150.55,97.94 v2(150.09,98.4)
  TOP w0.381: v4(148.24,93.91) 148.01,94.13 C44.1 ; C57.1 149.66,97.97 v2(150.09,98.4) ; C60.1 146.16,93.63 v4(146.26,93.73)
  TOP w0.508: v2(141.91,90.71) 141.91,90.99 140.2,92.7 C43.1 136.9,92.7 136.2,92 R267.1 L3.1 ; v4(146.43,100.05) 146.87,99.62 C87.1 ; CE50.1 142.71,20.84 v2(141.85,20.84) 141.22,20.84 140.59,21.47 127.12,21.47 126.26,22.33 126.26,23.34 124.36,25.23 124.36,25.41 122.91,26.86 v4(122.91,27.37) ; RC363.1 117.66,111.08 v4(117.4,111.33) 117.4,111.69 118.67,112.96 v4(119.69,112.96) 119.97,112.68 119.97,110.47 119.56,110.06 RC365.2 ; v4(139.88,115.81) 139.88,115.24 139.41,114.77 L5.1 139.15,114.8 v4(139.15,115.81) ; v4(83.49,80.44) 83.57,80.37 CC15.1 ; v4(96.61,78.97) 96.54,78.89 94.12,78.89 93.7,78.48 CC14.1 ; v4(113.72,117.78) 114.18,117.32 RC366.2 ; R253.2 104.12,97.72 v4(104.09,97.69) 104.04,97.74 103.2,97.74 101.86,99.09 101.86,99.19 ; PR500.1 PR504.1 PC548.2 v4(61.19,110.05) ; C57.1 C50.1
  TOP w1.016: v4(103.97,92.56) 103.97,93.53 v4(102.59,94.9) ; v4(100.45,91.25) 100.45,91.37 100.49,91.4 v4(100.49,92.15) ; v4(100.59,97.92) 101.86,99.19 v4(101.86,99.72)
  IN1 w0.508: v4(112.27,105.15) 112.27,107.7 v4(112.53,107.95) 113.49,107.95 114.58,109.04 115.8,109.04 117.4,110.64 v4(117.4,111.33) ; v4(96.61,78.97) 97.64,77.94 97.64,72.49 97.21,72.06 97.21,57.43 95.15,55.37 95.15,49.56 92.64,47.04 92.64,44.76 93.21,44.19 93.21,41.26 98.3,36.17 99.22,36.17 106.02,29.36 121.92,29.36 122.91,28.37 v4(122.91,27.37)
  IN1 w1.016: v4(100.49,92.15) 101.48,92.15 102.21,92.89 103.64,92.89 v4(103.97,92.56) ; v4(102.59,94.9) 102.59,95.91 v4(100.59,97.92)
  IN2 w1.016: v4(100.45,91.25) 99.76,91.25 99.6,91.42 96.37,91.42 85.4,80.44 v4(83.49,80.44)
  IN3 w0.508: v4(61.19,110.05) 61.92,110.77 64.11,110.77 64.95,111.61 70.26,111.61 71.1,110.77 72.93,110.77 73.28,111.13 74.45,111.13 74.96,110.62 79.18,110.62 80.58,109.21 v4(82.43,109.21) ; v4(119.69,112.96) 117.86,114.78 v4(117.86,117.48)
  BOTTOM w0.203: RP48.2 100.74,91.75 100.49,92 v4(100.49,92.15) 100.58,92.25 RP48.3 ; v2(147.6,89.84) 147.63,89.84 148.05,90.26 UC1.AG14 ; UV15.1 89.3,102.73 v4(89.56,102.47) 89.42,102.33 UV15.2 ; v4(160.89,21.01) 160.89,22.15 158.47,24.56 157.31,24.56 157.03,24.84 149.91,24.84 147.65,22.58 146.94,22.58 145.8,21.44 142.45,21.44 v2(141.85,20.84) ; RP48.1 v4(100.45,91.25)
  BOTTOM w0.254: v2(151.82,99.29) 151.27,99.29 UC1.K9 UC1.M9 150.66,98.62 UC1.L10 ; v2(151.87,97.13) 151.8,97.21 151.8,97.39 151.55,97.63 151.55,97.66 ; v2(151.73,91.5) 151.55,91.33 UC1.AE8 ; 151.55,97.66 UC1.P9 ; 151.55,97.66 UC1.N8 ; v2(143.9,90.25) 143.53,90.61 UC1.AF22 ; UC1.AG13 148.78,90.27 148.13,90.27 UC1.AG14 ; 146.82,89.85 146.84,89.88 146.84,89.88 147.16,90.2 UC1.AG16 ; 146.82,89.85 v2(146.82,89.82) ; 146.82,89.85 146.82,89.88 146.5,90.2 UC1.AG17 ; v2(147.38,100.74) 147.5,100.74 UC1.H15 ; UC1.AG8 151.56,90.08 151.84,90.36 v2(151.84,90.55) UC1.AF9 UC1.AE9 ; UC1.R21 144.45,96.69 v2(144.08,96.32) 144.45,95.94 UC1.T21 ; v2(149.25,100.74) 149.41,100.74 UC1.H11 149.66,100.35 149.66,99.83 UC1.J11
  BOTTOM w0.406: v2(141.91,90.71) 142.27,91.06 UC1.AE23 143.13,91.06 UC1.AE22 UC1.AC22
  BOTTOM w0.508: v4(101.86,99.72) 102.14,99.44 RC60.1 102.67,99.72 103.15,100.21 104.37,100.21 105.36,99.21 109.27,99.21 112.27,102.22 v4(112.27,105.15) ; v4(104.09,97.69) 104.29,97.49 R256.1 ; v4(82.43,109.21) 82.43,108.21 83.75,106.89 86.03,106.89 86.24,106.68 88.9,106.68 v4(89.39,106.2) ; RC58.1 100.82,97.72 100.61,97.92 v4(100.59,97.92) ; v4(103.97,92.56) 104.17,92.76 RC130.2 ; UC1.J17 146.72,99.77 v4(146.43,100.05) ; R252.1 102.8,95.1 v4(102.59,94.9) ; v4(112.53,107.95) 112.53,108.1 113.72,109.3 113.72,109.45 CC28.1 114.18,109.45 114.23,109.4 R2353.1 ; R245.1 v4(119.69,112.96)
  BOTTOM w1.016: v4(96.61,78.97) 96.24,79.34 93.82,79.34 93.4,78.92 87.66,78.92 86.14,80.44 v4(83.49,80.44)
  vias: v2(147.68,116.21) v2(148.26,116.21) v2(148.85,116.21) v2(149.48,116.21) v3(101.67,111.31) v4(90.07,106.17) v4(90.71,106.17) v4(111.8,120.25) v4(111.8,119.62) v4(111.8,118.98) v4(111.8,118.35) v4(111.8,117.71) v4(111.8,117.08) v4(111.8,116.44) v4(112.43,120.25) v4(112.43,119.62) v4(112.43,118.98) v4(112.43,118.35) v4(112.43,117.71) v4(112.43,117.08) v4(112.43,116.44) v4(113.05,119.94) v4(113.03,119.24)
+1.05VS_APLLOPI: length 19.3
  TOP w0.381: C69.1 145.75,94.39 145.09,94.39 144.3,93.6 v2(143.94,93.6)
  TOP w0.508: L3.2 R267.2 134.17,92 132.64,93.53 C70.1 133.88,94.22 134.32,93.78 v1(139.98,93.78) 140.77,93.78 141.77,92.78 142.95,92.78 143.76,93.6 v2(143.94,93.6)
  BOTTOM w0.254: UC1.AA21 144.04,93.5 v2(143.94,93.6) 144.45,94.11 UC1.W21
+1.05VS_ASATA3PLL: length 21.8
  TOP w0.508: L2.2 148.56,117.06 149.09,117.59 C65.1 149.92,116.89 150.17,116.64 150.17,113.54 v1(149.37,112.74) 149.37,111.58 149,111.22 148.99,111.22 148.44,110.67 v2(148.44,110.54) 148.62,110.37 149.53,110.37 149.86,110.04 C63.1 149.86,109.58 150.02,109.43 150.02,107.16 v2(150.07,107.11)
  BOTTOM w0.203: UC1.B11 149.73,104.34 149.91,104.53
  BOTTOM w0.381: 149.91,104.53 149.96,104.53 150.24,104.81 150.24,105.47 150.55,105.79 150.55,106.73 150.17,107.11 v2(150.07,107.11)
  BOTTOM w0.508: RC126.2 148.44,109.79 v2(148.44,110.54) 149.17,110.54 149.66,110.05 RC131.2
+1.05VS_AUSB3PLL: length 21.7
  IN3 w0.381: v2(139.42,107.12) 139.42,107.14 140.01,107.72 142.83,107.72 143.9,106.66 v2(145.06,106.66)
  BOTTOM w0.203: UC1.B27 140.3,104.41 139.93,104.78 139.93,104.93 139.83,105.03
  BOTTOM w0.305: UC1.B18 145.27,104.68 145.06,104.88 v2(145.06,106.66) ; RC91.1 139.04,107.5 v2(139.42,107.12) 139.83,106.71 139.83,105.03
  BOTTOM w0.508: L1.2 146.8,113.11 C59.1 146.8,111.27 145.57,110.04 145.57,109.45 146.44,108.59 C58.1 146.44,108.03 v2(145.06,106.66)
+1.5VSP: length 6.4
  BOTTOM w0.254: PR400.1 PC403.1 168.52,114.29 167.82,114.99 167.82,117.12 169.08,118.38
  vias: v1(171.21,120.23)
+1.05VSP: length 14.1
  IN3 w0.254: v2(106.99,123.17) 106.99,123.17 105.4,123.17 104.59,122.35 99.06,122.35 v2(98.16,123.26)
  BOTTOM w0.102: PC308.1 110.84,114.89 v1(111.22,114.51)
  BOTTOM w0.254: PC307.1 PR305.1 v2(98.16,123.26) ; PC310.1 v2(106.99,123.17)
+1.8V_VGA: length 5.9
  TOP w0.102: v2(181.35,104.07) v3(182.03,104.07)
  TOP w0.508: CV361.1 v2(186.49,111.5)
  BOTTOM w0.102: v2(194.11,112.32) 194.11,111.5 LV15.1
  BOTTOM w0.203: UV6.39 186.69,111.3 v2(186.49,111.5) 186.48,111.5 186.29,111.31 UV6.38
  BOTTOM w0.508: LV14.1 181.79,103.62 v2(181.35,104.07) ; v2(195.88,106.98) LV21.1
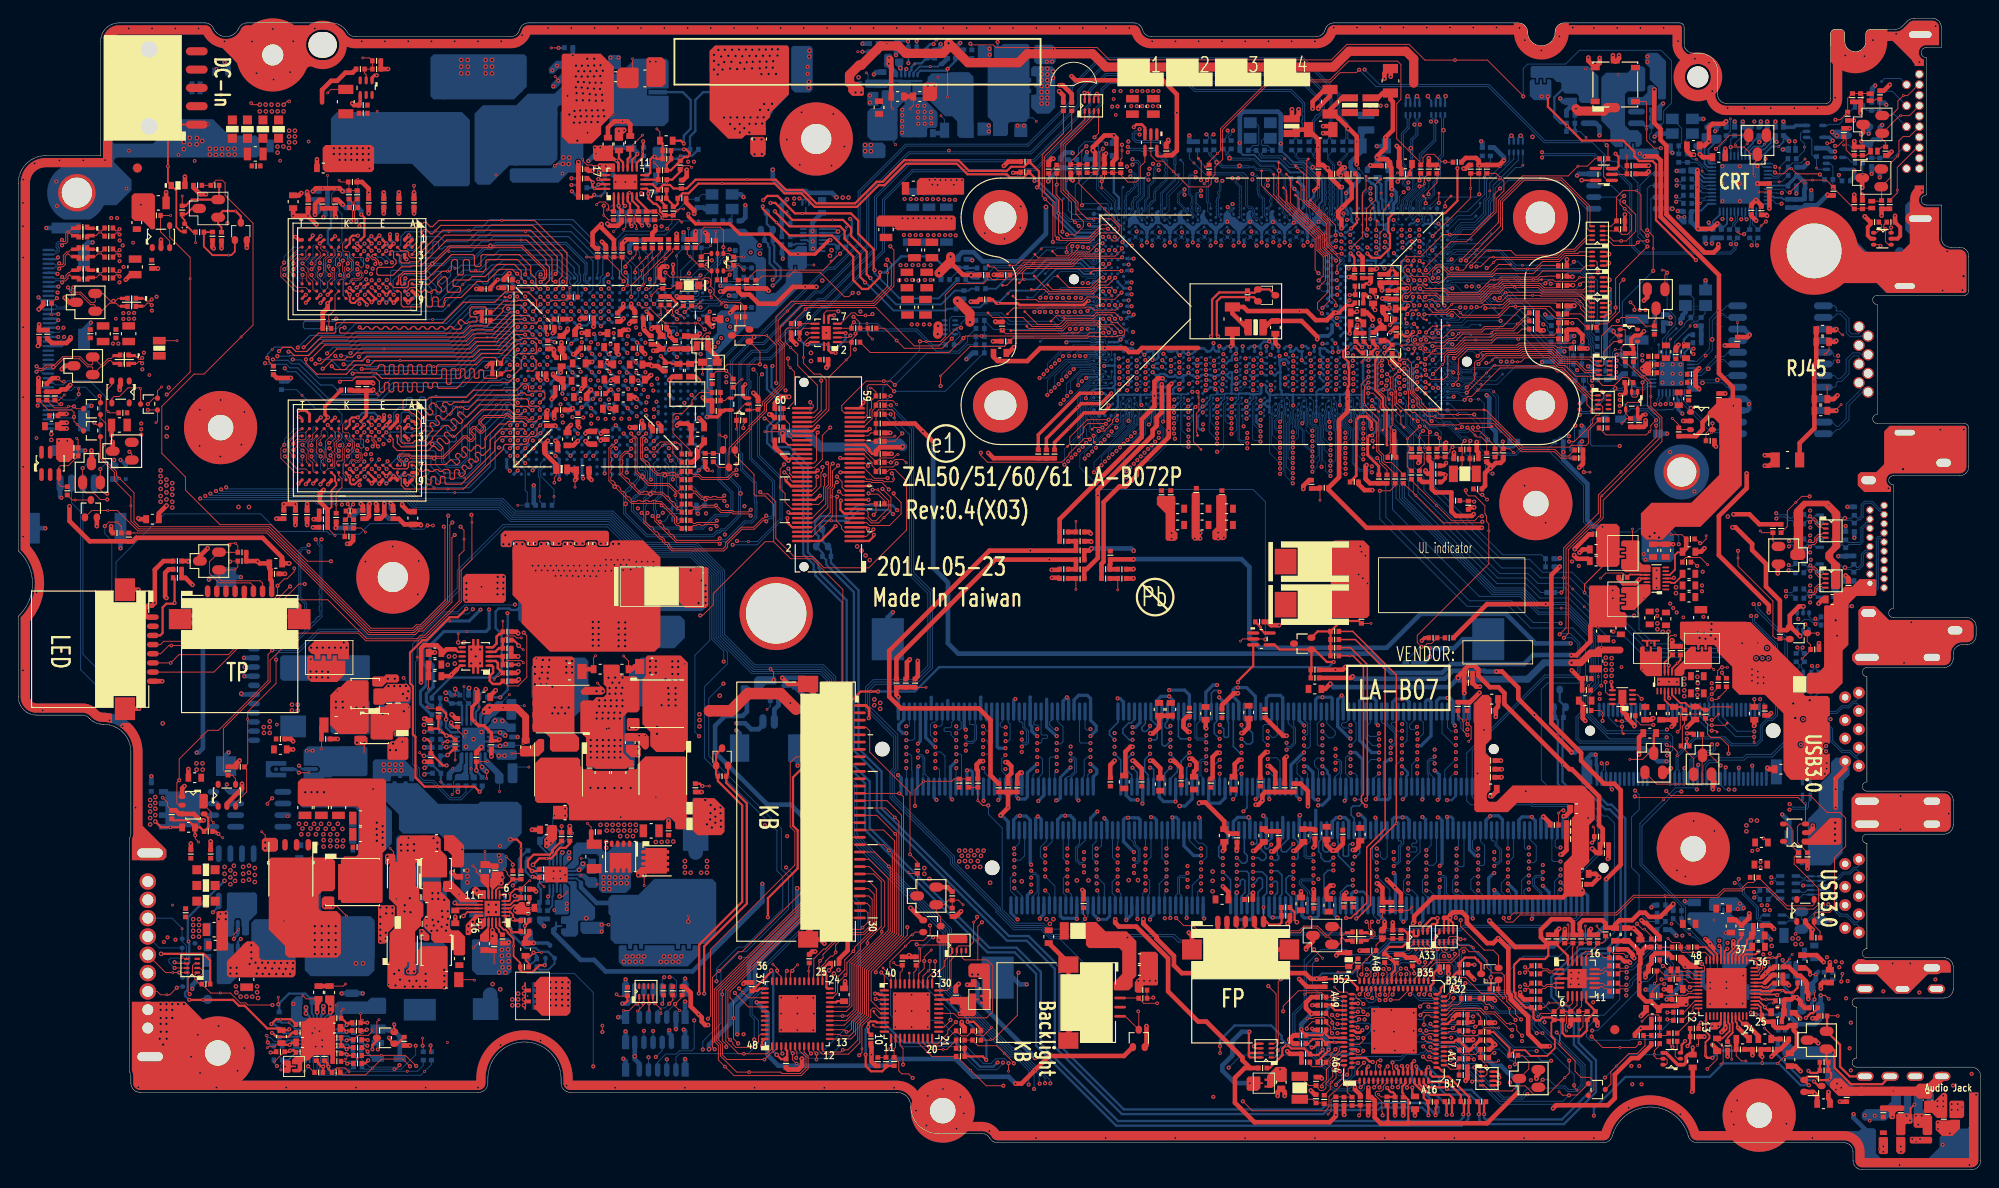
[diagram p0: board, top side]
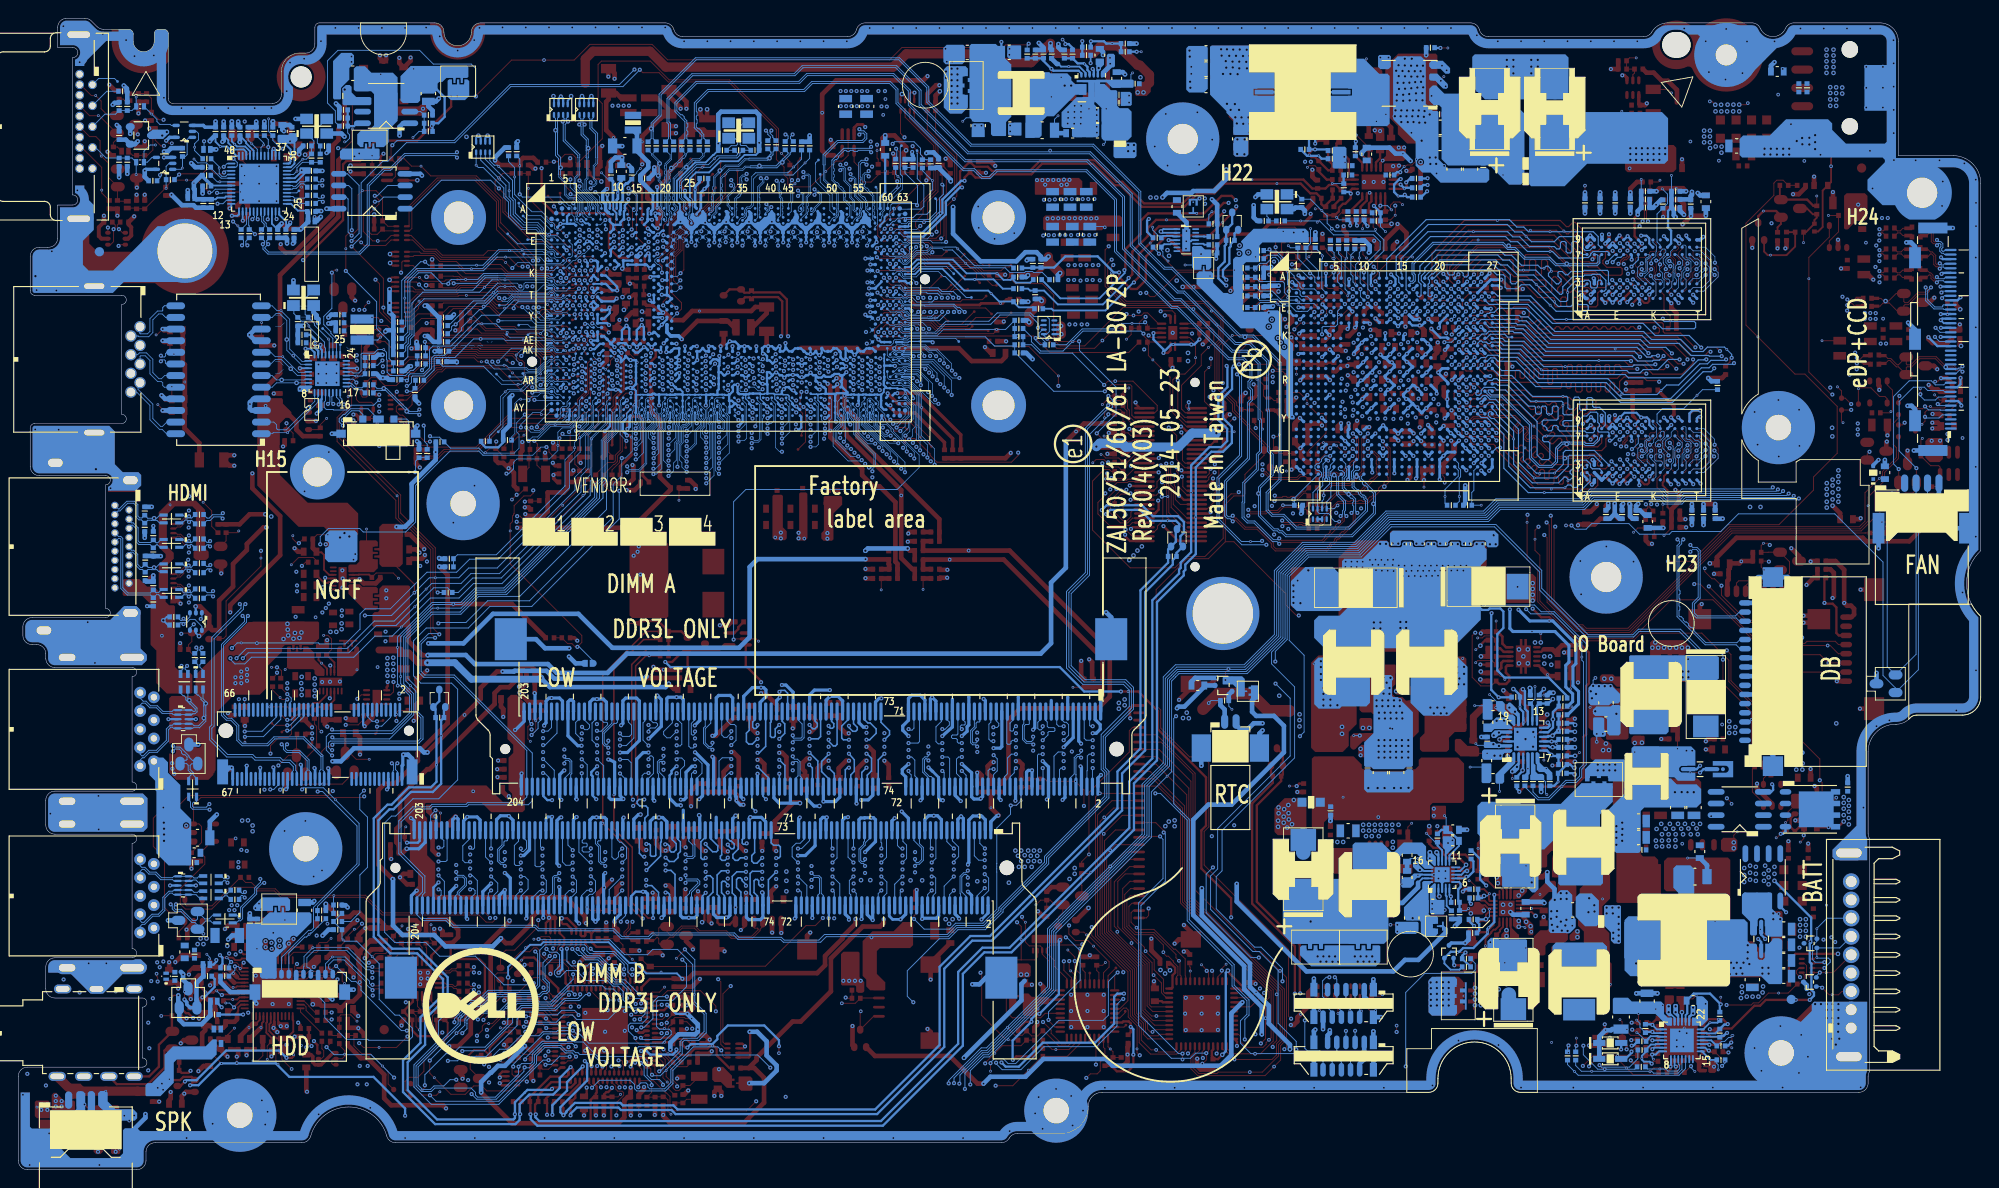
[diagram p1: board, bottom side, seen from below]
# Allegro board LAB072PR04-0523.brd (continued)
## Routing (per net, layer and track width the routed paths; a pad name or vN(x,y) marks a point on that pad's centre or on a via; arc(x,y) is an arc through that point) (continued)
+1.8V_VGA_IVDD: length 17.4
  TOP w0.102: v1(190.15,106.78) CV337.1
  TOP w0.508: v2(191.32,105) 191.32,105 CV337.1 ; CV359.1 189.35,104.17 v2(189.87,103.65)
  BOTTOM w0.203: UV6.24 185.89,104.3 185.14,103.56 185.14,102.71 CV355.1 ; v2(189.87,103.65) 189.89,103.67 UV6.14 ; UV6.46 189.49,111.15 189.76,111.42 190.75,111.42 191.46,112.13 191.46,112.44 CV336.1 ; 190.19,112.92 189.51,112.24 189.51,112.11 188.69,111.29 UV6.44 ; UV6.12 191.13,105.18 v2(191.32,105)
  BOTTOM w0.381: v2(184.69,103.45) 184.69,103.32 185.17,102.84 CV355.1
  BOTTOM w0.508: v2(192.09,112.26) 191.96,112.39 CV336.1 ; v2(190.21,112.23) 190.19,112.26 CV343.1 ; v2(192.78,111.43) LV15.2
+1.8V_VGA_PVCC: length 22.2
  TOP w0.508: v2(183.44,109.16) v1(183.44,107.32) 183.44,102.84 v2(183.52,102.76) 185.04,102.76 v2(185.63,103.34)
  BOTTOM w0.203: UV6.31 184.03,107.89 CV354.1 ; CV352.1 186.69,103.32 UV6.22 ; CV353.1 182.93,104.74 183.85,104.74 184.6,105.49 UV6.25 ; 183.39,109.09 184.19,108.29 UV6.32
  BOTTOM w0.508: CV352.1 186.06,102.91 v2(185.63,103.34) ; CV351.1 183.59,102.68 v2(183.52,102.76) 182.75,103.53 LV14.2 182.75,104.56 CV353.1
+1.8V_VGA_VDD: length 10.9
  BOTTOM w0.203: CV360.1 193.29,107.49 UV6.7 ; CV339.1 192.84,105.99 192.66,106.16 191.85,106.16 191.72,106.29 UV6.10
  BOTTOM w0.381: CV360.1 193.35,107.56 194.29,108.5 CV341.2
  BOTTOM w0.508: CV339.1 CV338.1 194.96,105.99 LV21.2 195.13,107.05 195.14,107.05 195.22,107.13 v1(195.22,107.75) 194.36,108.6 CV341.2
+1.35V: length 136.3
  TOP w0.254: U2303.5 136.17,58.62 135.74,59.04 135.74,59.25 CD23.1
  TOP w0.508: C43.2 137.34,90.26 v2(137.67,89.93) ; CD43.1 136.31,36.96 CD40.1 ; CD45.1 141.55,37.2 CD41.1 ; 128.9,89.75 122.76,89.75 122.31,89.3 121.34,89.3 120.92,89.72 v3(118.7,89.72) 111.64,89.72 110.24,88.32 106.99,88.32 106.54,88.76 C40.2 ; RC16.1 RC15.1 117.01,67.62 v4(117.24,67.85) ; v4(129,40.03) 129.08,40.11 129.7,40.11 131.75,38.05 CD44.1 132.25,36.71 CD39.1
  BOTTOM w0.254: UC1.AH26 140.69,89.93 v2(140.27,89.93) ; JDIMM2.124 147.45,29.86 146.95,30.36 v2(146.15,30.36) ; v2(133.77,89.93) UC1.AJ37 ; UC1.AR48 127.01,85.2 v2(126.85,85.2) ; UC1.AN33 136.2,86.77 135.93,87.04 v2(135.8,87.04) ; v2(135.72,81.23) 135.55,81.4 135.52,81.4 135.26,81.65 135.26,82.33 135.29,82.36 UC1.AY35 ; v2(137.67,89.93) UC1.AJ31 ; UC1.AY40 132.29,82.21 132.38,82.21 132.4,82.19 132.43,82.19 v2(132.54,82.07) ; UC1.AY44 128.86,82.23 128.86,81.06 129.09,80.84 v2(129.42,80.84) ; v2(136.37,89.93) UC1.AJ33 ; v2(126.27,82.09) 126.11,82.09 UC1.AY50 ; UC1.AP43 130.11,86.25 v2(129.78,86.25)
  BOTTOM w0.356: JDIMM1.76 121.05,40.89 121.54,40.39 v2(122.31,40.39) ; v4(133.12,30.27) 133.12,30.28 133.05,30.2 133.05,28.87 JDIMM2.76 133.05,27.57 133.31,27.31 134.59,27.31 134.85,27.57 JDIMM2.82 ; v2(121.74,48.34) 122.07,48.34 122.55,48.81 JDIMM1.81 ; JDIMM2.93 138.15,38.49 ; v2(120.11,51.47) 120.35,51.47 120.75,51.08 JDIMM1.75 ; JDIMM2.88 136.65,27.78 136.89,27.54 v2(137.06,27.54) 138.09,27.54 138.45,27.9 138.45,28.87 JDIMM2.94 ; JDIMM1.105 129.75,52.15 130.53,52.93 v2(130.97,52.93) ; v2(125.74,52.38) 125.74,52.38 127.42,52.38 127.95,51.85 JDIMM1.99 ; 129.99,40.03 131.27,40.03 131.85,40.61 JDIMM1.112 ; 129.99,40.03 130.05,40.09 JDIMM1.106 ; 129.99,40.03 v4(129,40.03) ; v4(146.42,38.79) 146.65,38.79 147.15,38.28 JDIMM2.123 ; JDIMM1.123 135.15,51.7 134.2,52.65 v2(133.25,52.65) 132.97,52.65 132.72,52.4 132.72,51.67 133.35,51.04 133.35,50.04 JDIMM1.117 ; v2(122.81,39.98) 122.85,40.01 JDIMM1.82 ; JDIMM2.106 142.05,27.75 141.82,27.52 v2(141.15,27.52) 140.48,27.52 140.25,27.75 JDIMM2.100 ; JDIMM1.94 126.45,40.22 v2(126.43,40.21) 125.13,40.21 124.65,40.69 JDIMM1.88 ; JDIMM1.118 133.65,43.23 v2(133.64,43.24) ; JDIMM2.111 143.55,38.01 144,38.46 v4(144.4,38.46) 144.95,38.46 145.35,38.07 JDIMM2.117 ; JDIMM1.87 124.35,51.18 124.34,51.19 124.84,51.7 v2(125.73,51.7) 126.15,51.28 JDIMM1.93 ; JDIMM1.124 135.45,40.73 v2(135.18,40.47) ; JDIMM2.112 143.85,27.77 v4(144.11,27.51) ; JDIMM2.118 145.65,30.12 145.89,30.36 v2(146.15,30.36) ; v2(131.2,51.59) 131.55,51.24 JDIMM1.111 ; v4(140.01,38.71) 139.95,38.65 JDIMM2.99 ; v4(136.03,38.66) 136.35,38.34 JDIMM2.87 ; JDIMM2.81 134.55,38.35 v4(134.42,38.48) 133.22,38.48 132.75,38.01 JDIMM2.75 ; v4(126.88,39.72) 126.88,39.72 127.46,39.72 128.25,40.5 JDIMM1.100 ; 141.75,39.27 JDIMM2.105
  BOTTOM w0.508: v4(121.85,67.6) 121.84,67.6 121.6,67.85 v4(117.24,67.85)
  vias: v4(66.16,22.72) v4(66.48,23.29) v4(66.79,22.72) v4(67.11,23.29) v4(67.43,22.72) v4(67.75,23.29) v4(68.06,22.72) v4(68.38,23.29) v4(70.18,22.71) v4(70.54,23.29) v4(70.82,22.71) v4(71.18,23.29) v4(71.49,22.72) v4(71.81,23.29) v4(72.13,22.72) v4(72.45,23.29) v4(102.8,34.85) v4(102.8,33.68) v4(103.08,34.28) v4(103.43,34.85) v4(103.43,33.71) v4(103.69,33.07) v4(103.78,34.28) v4(104.07,34.85) v4(104.07,33.71) v4(104.45,34.34) v4(104.45,33.07) v4(104.83,34.85) v4(104.83,33.71) v4(105.08,33.07) v4(105.18,34.28) v4(105.47,34.85) v4(106.18,31.35) v4(109.63,31.5) v4(115.65,31.6) v4(116.92,31.6) v4(121.31,31.63) v4(122.33,31.63) v4(130.48,32.57) v4(130.48,31.55) v4(130.48,30.41)
+1.35VGPUP: length 28.4
  TOP w0.102: v4(54.67,57.23) 55.1,56.8 v1(55.16,56.8)
  TOP w0.254: v4(54.67,57.23) 54.67,57.29 54.12,57.84 PR1006.2
  IN1 w0.254: v2(31.96,55.76) 31.37,56.34 31.37,57.18 32.37,58.17 43.18,58.17 44.23,59.22 50.15,59.22 51.2,58.17 52.42,58.17 53.16,57.43 54.47,57.43 v4(54.67,57.23)
  vias: v4(31.93,54.41) v4(31.93,53.77) v4(32.57,54.41) v4(32.57,53.77) v4(33.2,54.41) v4(33.2,53.77) v4(33.84,54.37) v4(33.84,53.73)
+1.35VP: length 24.9
  TOP w0.102: v4(73.21,27.1) v1(73.21,27.71)
  IN3 w0.254: v2(57.88,29.84) 58.58,30.53 61.7,30.53 65.13,27.1 v4(73.21,27.1)
  BOTTOM w0.203: 61.47,31.35 61,31.82 PU200.19 ; PU200.5 58.04,30 v2(57.88,29.84) 57.88,29.23 PR207.2
  BOTTOM w0.508: 61.47,31.35 61.47,30.84 63.17,29.14 64.57,29.14
+1.35VS_VGA: length 129.5
  TOP w0.229: UV18.H9 37.24,95.15 36.75,94.66 36.41,94.66 36.21,94.86 v2(36.21,95.57) 35.84,95.95 UV18.K8 ; v2(37.09,82.16) 36.47,82.16 36.2,81.89 36.2,81.33 UV19.K2 ; UV18.K2 36.21,101.15 36.21,101.72 36.5,102.01 v2(37.11,102.01) ; UV19.H9 37.24,75.34 36.75,74.85 36.41,74.85 36.22,75.04 36.22,75.67 v2(36.18,75.71) 35.81,76.09 UV19.K8
  TOP w0.254: UV18.E9 39.81,95.05 v2(39.43,94.67) ; v2(38.08,94.46) 38.08,94.57 37.49,95.15 UV18.H9 ; UV18.H2 37.4,100.75 v2(37.01,101.14) ; UV19.F1 39.01,81.76 v2(39.41,82.16) ; v2(37.78,96.43) 38.11,96.75 UV18.G7 ; UV19.H2 37.41,80.99 v2(37.78,81.36) ; v2(41.01,94.67) 40.61,95.07 UV18.D9 ; UV19.N9 33.01,74.94 v2(33.01,74.86) ; v2(39.45,102.03) 39.44,102.03 39.01,101.6 UV18.F1 ; v2(33.84,82.16) 33.83,82.16 UV19.N1 ; UV19.R9 31.81,75.28 v2(31.41,74.87) ; UV18.N9 33.41,95.06 v2(33.01,94.66) ; v2(31.41,94.69) 31.81,95.09 UV18.R9 ; UV18.N1 33.35,101.55 32.95,101.15 32.95,101.16 v2(32.94,101.16) ; v2(32.17,102.03) 32.17,101.91 UV18.R1 ; v2(37.78,76.51) UV19.G7
  TOP w0.305: UV19.A1 43.18,81.74 v2(43.46,81.46) ; v2(30.64,82.92) 31.41,82.92 31.81,82.52 UV19.R1
  TOP w0.381: UV19.C9 41.39,75.34 v2(41,75.73) 40.61,75.34 UV19.D9 ; UV18.C1 41.38,101.59 v2(41.38,102.11) ; v2(42.6,81.32) 42.6,81.33 42.21,80.94 UV19.B2 ; CV168.1 51.57,96.4 v2(52.38,97.21) ; v2(33.84,82.16) 33.51,82.49 33.51,83.37 RV150.1 ; UV18.D2 40.62,100.75 v2(41.01,101.15) ; UV19.A8 43.41,76.14 v2(43.55,76) ; UV18.C9 41.41,95.07 v2(41.01,94.67) ; CV24.1 64.33,91.32 v2(63.56,91.32) ; UV18.A8 43.04,95.95 43.44,95.55 v2(43.55,95.55) ; v2(39.45,74.89) 39.64,75.08 39.64,75.17 UV19.E9 ; UV18.A1 43.01,101.55 v2(42.6,101.15) 42.21,100.76 UV18.B2 ; v2(41.41,82.35) UV19.C1 UV19.D2
  TOP w0.508: CV43.1 59.26,87.64 v2(59.26,87.07) ; v2(35.42,106.86) 35.09,107.19 v1(33.28,107.19) 32.52,107.19 v2(32.19,106.86) ; CV209.1 39.17,72.62 v2(39.07,72.72) ; v2(60.35,92.92) 60.33,92.89 RV46.2 ; v2(31.65,104.17) 31.65,104.98 CV187.1 ; v2(31.65,104.17) 31.65,104.15 v2(32.57,103.24) ; v2(31.65,104.17) 31.63,104.19 v2(30.03,104.19) CV42.1 ; CV186.1 CV179.1 34.6,104.17 v2(34.7,104.07) ; CV180.1 37.65,72.49 v2(37.42,72.72) ; CV131.1 v2(39.93,104.45) ; CV204.1 v2(29.01,72.7) v2(30.28,72.7) CV210.1 ; CV47.1 59.4,91.05 60.02,91.67 v2(60.02,91.85) ; CV165.1 58.53,88.95 v2(58.53,89.54) 58.42,89.64 RV130.2 ; CV184.1 v2(43.24,104.45) ; v2(41.94,72.7) 41.94,72.54 42.61,71.87 CV15.1 ; RV149.1 v2(32.19,70.16) ; CV163.1 58.55,82.76 v2(58.55,82.04) ; CV143.1 v2(41.58,104.45) ; CV161.1 58.65,84.53 v2(58.28,84.16) ; CV197.1 40.95,72.52 v2(40.7,72.77) ; v2(61.29,92.2) 60.82,91.73 CV39.1 ; CV172.1 v2(38.28,104.45) ; CV170.1 v2(31.55,72.7)
  BOTTOM w0.229: v2(39.41,82.16) 38.91,82.67 37.61,82.67 37.11,82.16 v2(37.09,82.16) 36.46,82.16 36.21,81.9 36.21,81.34 UV19.K2 ; v2(37.11,102.01) 36.5,102.01 36.21,101.72 36.21,101.15 UV18.K2 ; UV19.K8 35.81,76.09 v2(36.18,75.71) ; v2(36.21,95.57) 35.84,95.95 UV18.K8
  BOTTOM w0.254: v2(43.55,76) 43.01,75.46 UV20.A1 ; UV1.J21 58.3,90.88 59.06,90.88 v2(60.02,91.85) ; v2(59.21,91.92) 59.1,92.03 UV1.G20 58.26,93.31 UV1.F21 ; v2(57.05,94.52) 56.65,94.12 UV1.E23 ; v2(63.63,92.99) 63.97,93.33 UV1.F14 ; UV19.N9 33.01,74.94 v2(33.01,74.86) ; UV18.R9 31.81,95.09 v2(31.41,94.69) ; v2(32.94,101.16) 32.95,101.16 32.95,101.15 33.35,101.55 UV18.N1 ; UV17.E9 39.81,101.67 v2(39.45,102.03) ; v2(64.49,92.89) 64.86,92.53 UV1.G13 ; v2(33.01,94.66) 33.41,95.06 UV18.N9 ; v2(37.78,96.43) 37.41,96.05 UV17.H2 ; v2(60.35,92.92) 59.97,92.53 UV1.G19 ; v2(41.01,95.56) 40.62,95.95 UV17.D2 ; v2(42.6,81.32) 42.98,80.94 UV20.A8 ; UV20.F1 39.23,75.12 39.23,75.11 v2(39.45,74.89) ; UV1.G16 62.1,92.2 v2(61.29,92.2) 61.07,92.2 UV1.G18 ; UV20.H9 v2(37.78,81.36) ; v2(33.84,82.16) 33.83,82.16 UV19.N1 ; v2(32.17,102.03) 32.17,101.89 31.83,101.55 UV18.R1 ; v2(39.43,94.67) 39.43,94.8 39.07,95.15 UV17.F1 ; UV19.R1 31.81,82.6 31.49,82.92 v2(30.64,82.92) ; UV1.V21 58.28,83.42 v2(58.28,84.16) 58.28,84.95 UV1.T21 ; v2(37.01,101.14) 37.41,101.55 UV17.H9 ; v2(38.13,79.59) 38.13,80.06 UV20.G7 ; UV18.C9 41.41,95.07 v2(41.01,94.67) ; v2(37.78,76.51) UV20.H2 ; v2(38.13,99.39) 38.13,99.87 UV17.G7 ; v2(31.41,74.87) 31.41,74.94 UV19.R9 ; UV1.G15 63.26,92.53 v2(63.66,92.13) 64.06,92.53 UV1.G14
  BOTTOM w0.305: UV1.H24 55.76,91.64 v2(56.14,92.02) ; v2(52.38,97.21) 53.52,97.21 UV1.B26 UV1.C25 ; v2(56.18,89.57) 55.76,89.15 UV1.L24 ; v2(58.55,82.04) 58.2,82.39 UV1.W21 ; v2(53.52,94.03) 54.08,94.03 UV1.E26 ; v2(54.58,92.05) 54.16,91.63 UV1.H26 ; v2(54.57,89.57) 54.16,89.16 UV1.L26 ; UV1.N21 58.83,87.51 v2(59.26,87.07) 59.26,87.01 58.2,85.95 UV1.R21 ; UV1.K21 58.2,89.86 v2(58.53,89.54)
  BOTTOM w0.381: UV17.A1 43.15,95.15 43.55,95.56 v2(43.55,95.55) ; UV20.D2 40.61,76.12 v2(41,75.73) 41.39,75.34 UV19.C9 UV20.B2 ; v2(39.41,82.16) 39.81,81.76 UV20.E9 ; UV17.B2 42.21,95.95 42.6,95.56 v2(42.6,95.58) ; v2(41.38,102.11) 41.38,101.59 UV18.C1 ; UV17.D9 40.61,101.55 v2(41.01,101.15) ; UV17.A8 42.99,100.75 v2(42.6,101.15) ; v2(40.57,82.29) 40.61,82.25 UV20.D9 ; v2(41.41,82.35) UV19.C1
  BOTTOM w0.508: CV131.1 v2(39.93,104.45) ; CV209.1 39.2,72.04 39.2,72.6 v2(39.07,72.72) ; CV204.1 v2(29.01,72.7) ; CV187.1 31.65,104.98 v2(31.65,104.17) ; RV139.1 v2(32.19,106.86) ; CV158.1 36.69,71.49 37.22,72.01 CV180.1 37.65,72.49 v2(37.42,72.72) ; CV172.1 v2(38.28,104.45) ; CV42.1 v2(30.03,104.19) ; CV210.1 v2(30.28,72.7) ; CV197.1 40.7,72.27 v2(40.7,72.77) ; CV143.1 v2(41.58,104.45) ; CV184.1 v2(43.24,104.45) ; v2(31.55,72.7) CV170.1 ; RV144.1 v2(35.42,106.86)
  vias: v2(57.81,88.75) v4(32,57.01) v4(32.63,57.01) v4(33.27,57.01) v4(33.96,57.01) v4(34.6,57.01) v4(35.23,57.01) v4(35.55,57.58) v4(35.87,57.01)
+3.3V_ALW_DEG: length 5
  TOP w0.102: v3(65.36,19.15) 65.56,18.95 66.5,18.95 RE76.2
  TOP w0.254: v2(65.99,18.14) 66.25,18.14 66.55,18.44 RE76.2
  BOTTOM w0.508: v2(65.99,18.14) 66.59,18.14 67.35,18.9 JDEG.1
+3.3V_BIO: length 5.4
  TOP w0.127: JFP.6 136.04,27.11 v3(136.04,28.65)
  TOP w0.254: RS39.2 CS28.1 138.02,26.99 137.8,26.77 136.67,26.77 136.34,27.1 JFP.6
+3.3V_RUN_GFX: length 136.3
  TOP w0.102: v2(75.29,76.46) 75.44,76.3 v1(75.86,76.3)
  TOP w0.381: v2(75.24,82.22) 76.38,82.22 76.71,82.55 CV129.1 77.07,82.86 77.18,82.97 UV14.5
  TOP w0.508: v2(75.29,76.46) 75.05,76.7 RV195.1 ; v2(74.02,102.44) 73.97,102.39 RV192.2 RV191.2 ; v2(69.07,81.51) 69.07,81.22 69.32,80.96 CV64.1 ; CV199.1 65.79,92.64 v2(66.12,92.97) ; CV159.1 CV160.1 73.12,81.49 72.17,81.49 v2(71.96,81.28) ; v2(69.18,91.82) 69.35,92 CV30.1 69.91,91.62 70.29,91.24 CV130.1 ; v2(75.85,92.05) 75.3,92.6 CV164.1 ; v2(77.78,93.6) 78.34,94.16 RV103.1 ; RV124.2 66.43,101.6 v2(66.27,101.45) 65.97,101.15 RV122.2 ; CV68.1 68.3,92.97 68.3,92.03 v2(68.36,91.98) 68.36,91.72 69.02,91.06 CV198.1 ; CV40.1 67.03,92.69 v2(66.73,92.38) ; RV253.2 75.29,102.11 v2(75.05,102.35) ; RV123.2 64.19,100.92 v2(63.76,101.35) ; v2(70.9,98.61) 70.87,98.63 70.38,98.63 70.08,98.33 70.08,97.49 RV104.2
  IN1 w0.254: v2(72.78,83.75) 72.47,83.44 72.47,78.18 72.01,77.72 72.01,69.05 71.1,68.15 71.1,65.16 69.03,63.09 56.75,63.09 54.5,60.84 53.49,60.84 v2(53.44,60.78)
  IN1 w0.508: v2(75.29,76.46) 75.29,75.59 74.74,75.05 74.74,73.01 75.14,72.62 v2(75.14,71.68) ; v2(66.27,101.45) 66.2,101.37 63.78,101.37 v2(63.76,101.35)
  IN2 w0.254: v2(52.66,51.59) 52.56,51.49 49.25,51.49 47.96,50.19 47.96,41.33 v4(48.02,41.26)
  IN2 w0.508: v2(66.27,101.45) 65.43,100.61 65.43,94.15 65.89,93.69 66.64,93.69 v2(68.36,91.98) 69.02,91.98 v2(69.18,91.82) 69.38,92.03 72.29,92.03 73.36,90.96 73.36,89.31 75.49,87.18 75.49,82.48 v2(75.24,82.22) ; v2(75.29,76.46) 75.42,76.33 75.42,71.96 v2(75.14,71.68)
  BOTTOM w0.254: v2(66.73,92.38) 66.88,92.53 UV1.G10 ; UV1.G8 69.02,91.98 v2(69.18,91.82) ; v2(66.12,92.97) 65.7,92.55 UV1.G12 ; PR621.1 51.27,51.59 v2(52.66,51.59) 53.47,52.4 53.47,60.71 53.44,60.74 v2(53.44,60.78) ; RPV3.2 RPV3.3 ; v2(68.36,91.98) 68.18,92.15 UV1.G9
  BOTTOM w0.305: v2(67.77,80.42) 68.03,80.67 68.04,80.67 68.17,80.81 UV1.AA9 ; UV1.AB8 69.03,80.01 69.13,80.11 69.13,80.77 69.03,80.87 UV1.AA8 69.02,81.47 v2(69.07,81.51)
  BOTTOM w0.508: RV125.2 RV190.1 73.72,102.14 v2(74.02,102.44) ; PR600.2 v4(48.02,41.26)
  vias: v2(77.35,86.62) v2(77.35,86.01)
+3.3V_RUN_GFX_UV15: length 1.1
  BOTTOM w0.102: 85.78,98.81 v1(86.92,98.81)
+3V_DSW: length 60.1
  TOP w0.127: v3(171.12,63.02) 171.12,63.93 173.09,65.9 C2328.1
  TOP w0.508: RC39.1 RC34.1 169.3,91.75 170.3,91.75 170.88,91.16 v2(170.88,90.41)
  IN1 w0.508: 155.38,92 158.81,92 161.32,89.49 161.32,87.89 162.36,86.85 162.36,81.74 164.7,79.4 167.77,79.4 v2(168.8,78.37) ; v2(150.96,89.05) 150.96,91.62 151.29,91.95
  IN2 w0.508: v2(170.88,90.41) 170.88,89.98 169.69,88.79 169.69,82.18 168.42,80.91 168.42,78.75 v2(168.8,78.37)
  BOTTOM w0.254: v2(150.96,89.05) 150.5,89.51 UC1.AH10
  BOTTOM w0.508: RC32.1 168.79,78.39 v2(168.8,78.37) 168.8,77.53 171.43,74.9 171.43,70.93 172.15,70.21 v2(173.08,70.21) ; v2(170.88,90.41) 170.88,90.16 170.82,90.1 RC153.1
+3V_DSW_GATE: length 7.2
  TOP w0.102: v1(180.59,69.36) 181.75,69.36 R2451.2
  TOP w0.203: C2325.1 181.76,67.43 181.28,67.43 181,67.14 181,65.53 180.44,64.97 U2304.5
  TOP w0.508: R2451.2 182.22,67.89 C2325.1
+3VA: length 52.1
  TOP w0.203: UA1.36 189.88,22.02 189.98,22.13 189.98,22.41 v2(189.78,22.61) ; UA1.9 182.96,18.82
  TOP w0.254: 182.96,18.82 182.5,18.82 182.27,18.6 ; 181.69,18.6 v4(182.22,18.06)
  TOP w0.508: CA57.1 175.96,25 CA77.1 RA1125.2 ; CA57.1 177.79,24.31 RA10.2 ; CA57.1 177.22,22.47 177.09,22.34 v3(177.09,20.49) 177.09,19.1 177.82,18.38 178.39,18.38 CA59.1 179.6,17.91 181.28,17.91 181.5,18.13 181.5,18.48 CA60.1 ; v2(196.02,16.54) 196.47,16.54 196.7,16.77 RA1120.2 ; RA1130.1 v2(186.75,12.37)
  IN1 w0.508: v2(196.02,16.54) 196.02,16.14 195.55,15.67 188.14,15.67 187.67,16.14 ; 187.67,16.14 187.67,15.1 186.75,14.18 v2(186.75,12.37) ; 187.67,16.14 187.15,16.66 183.62,16.66 v4(182.22,18.06)
  IN3 w0.254: v2(189.78,22.61) 189.58,22.41 188.57,22.41 188.32,22.66 185.35,22.66 184.4,21.71 182.55,21.71 v2(182.11,22.15) 181.79,21.83 181.79,18.49 v4(182.22,18.06)
+3VALW: length 334.3
  TOP w0.203: C5254.1 88.9,22.38 88.9,22.1 v4(88.57,21.77) ; v2(180.88,64.65) 180.8,64.57 U2304.4
  TOP w0.254: U2412.24 88.43,19.78 88.29,19.92 88.29,21.24 88.02,21.52 88.02,22.05 88.5,22.53 C5254.1 ; JLED.3 15.5,58.35 15.77,58.61 15.77,61.41 16.17,61.81 16.98,61.81 v2(17.07,61.9) 17.07,64.49 CZ49.1 ; U2412.4 83.86,13.13 84,12.98 84,12.42 83.88,12.3 C5256.1 83.34,12.07 v4(82.86,12.55) ; UC6.5 124.39,110.8 124.52,110.67 125.02,110.67 125.15,110.8 CC41.1 ; U2412.37 80.97,19.78 80.73,19.53 C5255.1 80.52,19.92 80.55,19.92 82.25,21.62 v4(82.25,21.74) ; v4(15.6,23.57) 20.25,23.57 20.96,22.86 PR2.1
  TOP w0.508: PR4.2 19.14,107.27 19.87,106.54 v2(20.5,106.54) ; v2(115.07,119.43) 115.52,118.98 125.05,118.98 126.57,117.45 v3(126.57,115.43) 126.57,111.31 126.06,110.8 CC41.1 ; v2(177.68,110.67) 179,110.67 179.43,110.24 179.43,104.08 185.81,97.7 185.81,86.97 187.32,85.46 187.32,83.94 ; RL41.2 183.3,80.11 184.01,80.83 184.01,81.65 UL2.5
  IN1 w0.508: v2(177.16,110.99) 177.16,112.11 176.1,113.16 173.84,113.16 168.58,118.42 152.71,118.42 150.12,121.01 145.62,121.01 144.84,120.22 115.85,120.22 v2(115.07,119.43) ; v4(89.61,21.81) 91.12,23.32 96.52,23.32 97.05,22.8 98.01,22.8 98.66,22.15 100.74,22.15 101.58,21.31 v4(104.22,21.31) ; v2(13.43,81.5) 13.43,83.91 20.41,90.9 20.41,105.93 20.48,106 20.5,106 v2(20.5,106.54)
  IN2 w0.254: v4(15.6,23.57) 15.4,23.78 15.4,28.35 17.07,30.03 17.07,36.73 16.74,37.06 16.74,44.71 15.45,46 15.45,48.41 v4(15.78,48.74)
  IN2 w0.508: v2(137.85,10.98) 133.13,10.98 132.19,10.04 116.74,10.04 114.56,12.22 v4(111.08,12.22)
  IN2 w1.016: 82.66,75.49 82.2,75.95 82.2,80.77 86.12,84.69 87.64,84.69 89.36,86.4 89.36,87.78 87.3,89.84 87.3,89.87 87.23,89.94 87.23,92.15 85.88,93.5 85.88,96.7 87.69,98.5 88.12,98.5 88.12,98.55 88.42,98.86
  IN3 w0.508: v4(91.8,119.31) 92.36,118.75 96.82,118.75 98.91,120.84 108.67,120.84 110.51,122.68 113.82,122.68 115.07,121.44 v2(115.07,119.43)
  BOTTOM w0.254: v4(82.86,12.55) 82.48,12.93 82.48,21.52 v4(82.25,21.74)
  BOTTOM w0.508: 104.45,20.63 104.8,20.27 104.8,18.49 v4(111.08,12.22)
  vias: v2(13.43,80.86) v2(13.43,80.28) v2(177.59,67.24) v2(177.78,66.63) v3(175.15,54.89) v3(187.38,83.43) v4(39.93,44.25) v4(39.93,43.61) v4(40.57,44.25) v4(40.57,43.61) v4(41.2,44.25) v4(41.2,43.61) v4(41.84,44.25) v4(41.84,43.61) v4(88.07,38.15) v4(88.07,37.52) v4(88.68,99.81) v4(88.7,38.03) v4(88.85,100.43) v4(89.08,37.52) v4(89.11,21.42) v4(91.65,68.07) v4(92.13,67.62) v4(92.56,67.08) v4(93.02,66.58) v4(93.53,51.36) v4(93.53,50.73) v4(94.16,50.98) v4(94.16,50.35) v4(104.86,21.31) v4(173.44,55.92) v4(173.43,55.25) v4(173.44,54.57) v4(173.44,53.91) v4(174.07,55.87) v4(174.08,55.21) v4(174.08,54.58) v4(174.07,53.94) v4(178.24,69.15) v4(178.77,69.53) v4(179.25,69.04) v4(181.11,63.6) v4(181.11,62.97)
+3VALW_1099: length 48.3
  TOP w0.254: CE3.1 92.87,15.01 v2(92.87,15.59) 92.87,15.98 93.08,16.19 93.67,16.19 93.79,16.07 UE4.8 ; v2(103.71,16.16) 104.4,16.16 105.16,15.39 RE89.2 ; v2(92.57,12.56) 92.57,11.33 93.16,10.75 94.38,10.75 94.8,11.17 RE279.2 95.67,11.34 RE13.1 ; CE10.1 102.4,18.57 UE4.28 ; v2(105.74,11.99) 105.36,12.37 RE14.1 RE35.1
  IN1 w0.254: v2(92.57,12.56) 92.57,12.37 92.89,12.05 94.05,12.05 94.38,12.38 97.73,12.38 98.63,11.49 105.24,11.49 v2(105.74,11.99)
  BOTTOM w0.254: v2(92.87,15.59) 92.83,15.59 92.57,15.34 v2(92.57,12.56) ; v2(105.74,11.99) 105.77,12.02 105.77,14.1 v2(103.71,16.16) 103.71,16.46 103.15,17.02 v2(102.85,17.02) 100.72,19.15 100.72,25 100.61,25.1 v2(100.59,25.1)
  vias: v1(102.99,17.55)
+3VALW_5085: length 207.9
  TOP w0.203: v2(155.07,24.11) 155.07,24.23 154.74,24.56 154.74,25.33 155.26,25.85 RPE5.8
  TOP w0.254: 134.45,12.75 134.45,12.4 134.59,12.26 RPE6.8 ; 134.45,12.75 134.45,12.76 RPE6.7 ; 134.45,12.75 134.45,15.01 v2(134.5,15.06) ; v2(143.16,13.11) 143.16,13.01 141.96,11.81 RE81.1 ; v2(140.16,15.34) 140.16,15.22 140.38,15 140.38,14.98 CE17.1 140.68,14.7 142.43,14.7 142.88,15.14 142.88,14.76 143.22,14.42 144.85,14.42 UE5.A58 ; CE44.1 154.61,21.47 154.61,20.37 154.3,20.06 UE5.B35 ; 149.64,5.2 149.64,6.94 RE79.1 ; CE38.1 142.93,18.01 v2(143.51,18.01) 143.51,17.76 143.85,17.42 144.84,17.42 UE5.A52 ; UE5.A11 151.55,9.43 151.21,9.1 151.21,8.41 151.31,8.31 CE43.1 151.57,7.93 151.87,7.62 151.87,5.17 ; RE69.1 159.06,22.41 v2(159.08,22.38) ; CE40.1 150.4,22.43 150.4,21.74 150.05,21.39 UE5.A41 ; UE5.A22 155.75,13.92 156.82,13.92 157.05,14.15 CE14.1 ; v2(156.75,16.51) 156.15,15.92 UE5.A26 ; UE5.B3 147.3,11.07 v2(147.5,11.28) ; 151.79,25.78 151.98,25.97 RPE3.8 152.46,25.61 152.56,25.5 152.84,25.5 152.95,25.62 RPE3.7 ; 151.79,25.78 151.79,24.89 151.24,24.34 149.76,24.34 149.28,23.85 RE39.1 ; 151.79,25.78 151.41,26.16 RE65.1
  TOP w0.305: CE14.1 157.41,14.1 158.35,13.16 RE25.1
  TOP w0.381: CE63.1 159.69,14.15 v2(159.06,13.52) 158.6,13.06 RE25.1 ; CE40.1 150.4,22.58 v2(149.89,23.09) 149.43,23.55 RE39.1 ; 142.88,15.14 CE64.1
  TOP w0.508: RE38.1 141.28,18.85 140.69,18.26 140.69,17.63 v2(141.3,17.02) 141.36,17.07 RE45.1 ; v2(163.83,8.44) 160.47,5.07 151.97,5.07 151.87,5.17 151.74,5.04 149.79,5.04 149.64,5.2 149.47,5.03 148.87,5.03 148.19,5.72 148.19,7.57 147.83,7.93 CE46.1 147.5,8.4 147.5,8.4 v2(147.5,8.97) ; RE74.1 72.8,19.99 73.46,19.33 73.46,17.83 v1(74.32,16.97) 74.67,16.63 74.67,16.18 75.05,15.8 v2(75.37,15.8) ; v2(156.75,16.51) 156.75,16.54 157.15,16.94 CE41.1 ; CE44.1 155.3,21.59 v2(155.38,21.52)
  IN1 w0.508: v2(159.06,13.52) 158.3,13.52 158.02,13.8 155.95,13.8 155.58,14.18 155.58,15.34 v2(156.75,16.51) ; v2(160.38,20.6) 159.97,21.01 159.97,21.49 v2(159.08,22.38) ; v2(75.37,15.8) 76.04,15.8 76.62,16.38 81.72,16.38 82.07,16.03 87.15,16.03 87.82,16.7 99.67,16.7 100.87,15.5 103.92,15.5 104.93,16.51 114.9,16.51 115.78,15.63 121.92,15.63 122.48,15.06 126.65,15.06 126.95,15.37 134.19,15.37 v2(134.5,15.06) 135.06,15.62 135.93,15.62 136.25,15.31 140.12,15.31 v2(140.16,15.34)
  IN2 w0.508: v2(143.16,13.11) 143.16,12.96 145.14,10.98 147.2,10.98 v2(147.5,11.28) v2(147.5,8.97)
  IN3 w0.508: v2(149.89,23.09) 150.3,23.09 150.8,22.58 152.18,22.58 152.71,22.05 154.84,22.05 v2(155.38,21.52) 155.86,22 157.59,22 157.97,22.38 v2(159.08,22.38) ; v2(160.38,20.6) 160.38,19.92 157,16.54 156.77,16.54 v2(156.75,16.51)
  BOTTOM w0.254: v2(155.38,21.52) 154.97,21.92 154.97,24.01 v2(155.07,24.11) ; v2(141.3,17.02) 142.52,17.02 v2(143.51,18.01)
  BOTTOM w0.508: v2(163.83,8.44) 163.83,9.58 162.82,10.59 162.74,10.59 161.99,11.34 161.23,11.34 v2(159.06,13.52) ; v2(134.5,15.06) 133.68,15.06 132.64,14.02 132.64,12.47 131.55,11.38 131.55,10.82 132.92,9.45 v2(134.55,9.45) ; v2(141.3,17.02) 140.16,15.88 v2(140.16,15.34) 140.16,15.06 140.44,14.79 142.24,14.79 143.16,13.87 v2(143.16,13.11)
+3VALW_PCH: length 131.4
  TOP w0.305: C81.1 150.37,92.77 v2(149.86,92.26)
  TOP w0.381: v2(148.72,92.81) 148.72,92.56 149.05,92.23 R264.1 ; v2(145.47,91.32) 145.47,92.34 C78.1
  TOP w0.508: v2(160.84,76.61) 160.84,76.89 160.43,77.29 R2330.1 ; v2(160.84,76.61) 160.76,76.61 160.25,76.1 160.25,74.7 RC103.2 ; v2(160.84,76.61) 161.42,77.19 161.95,77.19 162.23,77.47 RC27.1 ; R264.1 148.65,91.94 148.15,91.44 RC127.1 ; v2(99.95,79.5) v3(98.84,80.62) 97.97,81.49 RC64.2 ; 171.99,59.6 171.76,59.37 171.76,57.71 170.24,56.19 v2(169.68,56.19) ; R2528.2 170.59,89.69 v2(171.44,89.69) ; v2(166.65,91.67) 166.23,91.67 166.09,91.81 RC105.2 RC29.1 RC120.1
  BOTTOM w0.254: RC109.2 161.42,79.43 161.95,78.89 163.35,78.89 163.83,79.38 R2527.2 ; UC1.AE21 144.86,91.46 UC1.AE20 145.11,91.32 v2(145.47,91.32) ; v2(149.86,92.26) 150.06,92.46 UC1.AC9 UC1.AA9
  BOTTOM w0.508: RC109.2 161.42,80.59 160.71,81.3 160.71,84.3 v2(160.43,84.58) ; v2(166.49,88.2) 166.5,88.2 166.55,88.25 R2329.1 ; v2(169.68,56.19) 169.65,56.21 165.51,56.21 164.52,55.22 156.54,55.22 155.57,54.26 150.02,54.26 147.91,56.36 102.7,56.36 101.57,57.5 101.57,64.12 99.95,65.74 v2(99.95,79.5) ; v2(170.84,79.56) 170.62,79.33 RC28.1
  vias: v2(169.75,66.42) v2(170.49,65.94) v2(174.2,63.27) v2(174.2,62.41) v2(174.57,87.75) v2(174.57,87.11) v2(174.97,83.43) v2(174.97,82.79)
+3VALW_PCH_GATE: length 5.8
  TOP w0.102: R416.2 181.81,66.51 182.17,66.87 183.77,66.87 v1(184.57,66.07)
  TOP w0.203: U2304.3 180.5,64.17 180.58,64.09 180.98,64.09 181.82,64.93 C2314.1
+3VALWP: length 13.8
  TOP w0.254: v2(55.68,29.03) 55.83,29.19 PR109.1 ; v4(53.76,36.07) 54.47,36.07 54.92,35.63 v1(54.92,35.09) PR115.2
  IN2 w0.254: v2(52.63,35.36) 53.32,35.36 55,33.68 55,32.13 55.68,31.45 v2(55.68,29.03)
  BOTTOM w0.254: v2(55.68,29.03) 55.83,29.19 PC102.1
+3VLP: length 152.1
  TOP w0.127: v2(131.3,13.49) v3(131.3,12.73)
  TOP w0.203: PU100.3 53.81,28.54 54.16,28.88 54.72,28.88 PC109.1
  TOP w0.254: v2(141.3,13.34) 141.53,13.34 RE57.2
  IN1 w0.254: v2(79.24,14.79) 81.08,14.79 82.25,13.62 90.02,13.62 90.97,14.58 98.2,14.58 99.4,13.38 104.21,13.38 105.35,14.52 112.44,14.52 113.56,13.4 130.37,13.4 130.46,13.49 v2(131.3,13.49)
  IN3 w1.016: 77.68,14.85 73.49,14.85 72.81,14.18 60.35,14.18 56.37,18.16 56.37,22.46 57.33,23.42 57.33,25.3 56.52,26.11 56.52,27.46 56.62,27.56
  BOTTOM w0.254: v2(141.3,13.34) 140.92,13.72 138.56,13.72 138.03,14.25 138.03,14.61 136.88,15.75 132.9,15.75 131.3,14.15 v2(131.3,13.49)
  BOTTOM w0.508: v2(78.54,14.79) 78.55,14.8 78.55,17.79 80.47,19.71 80.47,22.25 86.03,27.82 86.03,38.22 84.38,39.87 81.84,39.87 76.13,45.58 76.13,48.48 77.21,49.56 79.15,49.56 79.61,50.01 79.61,51.23 79.3,51.54
  vias: v4(54.28,28.3) v4(55.71,27.99)
+3VS: length 793.7
  TOP w0.203: UC5.5 170.82,108.05 v4(170.81,108.07) ; RP60.2 173.56,99.24 v4(173.78,99.02) 173.5,98.74 RP60.1 ; 173.83,94.66 173.83,94.39 173.6,94.16 RP37.7 ; 173.83,94.66 v4(173.84,94.67) ; 173.83,94.66 RP37.8 ; C44.2 148.01,95.68 v4(148.39,95.3) ; RP43.2 173.56,96.45 v4(173.84,96.16) 173.63,95.95 RP43.1 ; RP37.6 173.84,93.66 v4(173.84,93.65) 173.35,93.16 RP37.5 ; RP43.3 173.61,96.95 v4(173.84,97.18) 173.57,97.45 RP43.4 ; RE48.1 161.17,15.04 162.92,13.29 RE67.1 163.48,13.06 164.62,13.06 165.26,12.42 167.03,12.42 167.87,13.26 167.87,14.2 167.49,14.58 167.49,16.06 RS22.1 RS36.1 168.71,16.36 ; v4(174.29,91.56) 174.29,91.44 174.62,91.11 QC1.2 ; RP60.3 173.53,99.74 v4(173.79,100) 173.55,100.24 RP60.4
  TOP w0.254: CS29.1 168.08,24.59 169.28,23.38 169.28,22.81 US2.20 ; RS39.1 139.44,28.13 139.44,27.28 v4(139.69,27.03) ; CI50.1 167.16,23.37 166.81,23.01 164.06,23.01 163.43,22.38 163.43,19.43 163.57,19.29 163.57,18.81 164.67,17.71 RS41.1 165.35,17.71 165.54,17.52 165.54,16.56 165.79,16.31 166.23,16.31 166.55,16.63 167.53,16.63 RS22.1 ; 168.71,16.36 168.71,14.92 169.05,14.58 170.74,14.58 171.38,15.22 171.38,16.33 RS30.1 171.4,16.37 172.29,17.26 CS27.1 172.29,17.35 171.29,18.35 171.29,18.95 US2.10 ; RPE3.6 153.45,26.48 154.44,27.46 v4(155.05,27.46) 155.05,26.98 154.89,26.82 154.49,26.82 153.95,26.29 RPE3.5
  TOP w0.381: C68.1 C71.1 150.78,96.24 151.69,96.24 v2(151.72,96.27) ; v4(148.42,98.42) 148.3,98.3 C73.1 ; v2(177.79,82.48) 177.52,82.48 CC11.1 176.92,82.22 UC3.5 ; RC36.1 169.19,96.6 v4(169.85,96.6) ; R2334.1 R2335.1 v4(175.52,104.32) ; v2(151.85,94.36) 151.52,94.03 C82.1 ; R2345.1 169.23,97.53 v4(169.8,97.53) ; RC119.1 169.17,99.39 v4(169.19,99.42) ; QC1.5 177.16,91.11 v4(177.6,91.56)
  TOP w0.432: R2331.1 176.46,89.78 176.2,90.03 176.2,90.73 176.59,91.11 QC1.5
  TOP w0.508: v4(178.11,109.65) RC95.1 ; v4(64.37,103.3) 64.57,103.1 65.52,103.1 65.92,103.49 PR519.1 ; QV5.2 193.54,60.52 194.54,61.52 v4(195.03,61.52) ; QV5.2 193.68,59.25 v4(194.66,58.27) ; QV5.2 193.22,58.93 RV18.2 192.46,62.16 190.94,63.69 190.94,66.17 189.43,67.67 189.43,68.34 187.62,70.16 v4(187.29,70.16) ; v4(180.8,29.02) 179.39,27.61 178.2,27.61 177.74,28.07 177.14,28.07 176.32,27.24 174.95,27.24 174.46,26.76 RA1125.1 174.43,26.43 RS21.1 173.42,26.9 173.08,27.24 170.96,27.24 170.59,26.88 170.59,26.2 170.74,26.05 RS24.1 RS19.1 169.85,27.02 169.51,27.36 167.49,27.36 166.35,26.22 166.35,25.39 167,24.74 CI50.1 ; v4(160.74,27.21) 160.74,27.13 163.55,24.31 166.73,24.31 CI50.1 ; CD31.1 157.97,54.59 158.42,55.04 159.08,55.04 159.28,54.85 159.3,54.85 159.52,54.62 159.52,53.95 160.77,52.69 161.73,52.69 162.36,52.06 162.36,50.85 169.47,43.74 169.73,43.74 172.7,40.77 172.7,37.62 173.11,37.21 RD12.2 173.11,35.77 CD60.1 CD61.1 172.42,34.6 v4(171.96,35.05) ; CD31.1 CD30.1 157.97,52.07 v2(157.99,52.05) ; CD31.1 157.64,54.19 157.31,53.85 v4(157.31,53.7) ; CS29.1 CI50.1 ; Q327.2 98.82,27.25 v4(97.48,28.59) ; v4(2.24,93.97) 2.72,94.45 RC372.2 ; RX12.1 RX13.1 190.22,70.49 189.13,71.58 v4(187.41,71.58) ; v4(183.06,110.85) 182.74,110.85 182.3,111.29 RV214.1 ; v4(76.71,95.91) 77.06,95.91 77.39,96.24 RC370.1 78.67,95.94 79.02,95.58 79.89,95.58 80.89,94.58 82.8,94.58 84.63,96.42 v3(85.97,96.42) v4(87.19,96.42) ; v4(54.67,53.55) 54.49,53.37 PR1000.1 ; v2(176.55,23.1) 176.37,23.28 176.37,23.5 175.8,24.07 RS43.1 ; R2332.1 R2331.1 ; RC75.1 158.13,110.5 159.25,110.5 159.57,110.19 RC373.1 RC98.1 161.8,109.73 v2(162.31,110.24) ; RC362.1 82.66,83.72 83.34,84.41 v4(84.21,84.41) ; v4(169.98,94.36) 169.97,94.35 R2343.1 ; v4(5.59,72.44) 5.59,70.84 7.8,68.63 RE50.1 12.5,68.63 12.88,69.01 26.69,69.01 28.82,66.88 R246.2 v4(29.6,66.22) ; CD62.1 142.78,52.5 v4(143.34,53.06) ; v4(2.15,89.97) 2.28,90.1 CX10.1
  TOP w0.762: v4(169.7,55.37) 170.69,55.37 171.72,56.4 RM7.1 172.69,56.76 175,56.76
  TOP w1.016: 91.05,118.48 90.82,118.71 90.82,119.58 91.88,120.64 92.12,120.64 94.21,122.74 96.14,122.74 96.96,121.92 100.99,121.92 101.66,122.58 101.66,122.99 ; 101.66,122.99 v4(101.63,123.02) ; 101.66,122.99 102.04,122.61 102.06,122.61 103.76,120.91 109.28,120.91 110.24,121.87 117.38,121.87 118.83,120.42 143.67,120.42 145.39,122.15 151.62,122.15 152.46,121.31 152.46,118.67
  IN1 w0.508: v2(169.98,91.05) 169.66,91.05 168.91,90.3 v2(168.91,89.37) ; v4(76.64,51.77) 82.71,51.77 88.42,57.48 88.42,68.99 85.37,72.04 85.37,80.91 84.21,82.08 v4(84.21,84.41) 84.64,84.84 84.64,86.58 86.38,88.32 v4(86.61,88.32) ; v4(160.74,27.21) 159.79,27.21 158.86,26.27 156.23,26.27 v4(155.05,27.46) 154.35,28.15 143.39,28.15 141.99,26.75 139.97,26.75 v4(139.69,27.03) 139.17,27.55 138.35,27.55 137.63,26.84 136.58,26.84 135.86,27.56 133.15,27.56 132.29,26.7 127.8,26.7 126.49,25.38 104.22,25.38 101.01,28.59 v4(97.48,28.59) 95.33,30.74 v4(85.09,30.74) ; v4(5.59,72.44) 4.25,72.44 2.47,74.22 2.47,80.57 2.85,80.95 2.85,89.27 v4(2.15,89.97) 2.15,91.11 2.9,91.86 2.9,93.31 v4(2.24,93.97) ; v4(49.25,52.61) 49.25,52.66 49.74,53.14 54.26,53.14 v4(54.67,53.55)
  IN1 w1.016: 91.88,116.7 91.88,115.75 91.43,115.31 91.43,110.14 83.34,102.05 82.11,102.05 81.63,101.56 ; v4(154,117.25) v4(152.81,117.25) v4(151.79,117.25) ; v4(87.19,96.42) 87.1,96.33 87.1,89.7 v4(86.61,89.21) v4(86.61,88.32)
  IN2 w0.508: v4(177.6,91.56) 175.82,89.78 175.82,87.43 174.87,86.48 v2(174.57,86.48) ; v4(169.98,94.36) 169.98,96.47 v4(169.85,96.6) ; v4(180.8,29.02) 176.55,24.77 v2(176.55,23.1) ; v4(29.6,66.22) 27.28,66.22 23.04,61.98 23.04,53.32 v4(24.36,52) ; v4(64.37,103.3) 64.44,103.23 65.59,103.23 68.99,99.83 68.99,98.7 71.32,96.36 73.86,96.36 75.05,95.17 75.97,95.17 v4(76.71,95.91) ; v4(194.66,58.27) 193.45,58.27 192.82,57.63 192.82,54.92 195.74,52 195.74,47.93 195.38,47.58 195.38,46.13 196.5,45.01 197.87,45.01 198.23,44.66 198.23,40.08 197.77,39.63 197.77,36.65 196.88,35.77 196.88,30.58 192.61,26.32 192.61,25.43 191.62,24.44 v4(191.57,24.44)
  IN3 w0.508: 55.94,60.45 55.94,57.56 55.66,57.28 55.66,54.54 v4(54.67,53.55) ; 55.94,60.45 57.43,61.95 70.93,61.95 73.24,59.64 73.24,56.19 76.03,53.41 76.03,52.4 76.64,51.79 v4(76.64,51.77) ; 55.94,60.45 54.67,59.19 46.8,59.19 45.1,57.48 37.6,57.48 34.96,60.12 27.11,60.12 25.46,58.47 25.46,53.09 v4(24.36,52) ; v4(67.35,12.39) 67.35,12.74 67.9,13.29 73.18,13.29 73.85,13.96 75.05,13.96 75.47,13.54 v4(75.47,13.16) ; v4(191.57,24.44) 190.96,24.44 186.71,28.69 181.13,28.69 v4(180.8,29.02)
  IN3 w1.016: 86.67,97.14 85.18,98.63 82.45,98.63 v4(81.03,100.05)
  BOTTOM w0.203: QX4.2 195,61.11 195.03,61.14 v4(195.03,61.52) ; RP53.7 163.88,112.67 v4(164.14,112.93) 164.38,112.69 RP53.8 ; RP52.6 152.08,116.96 v4(151.79,117.25) 151.58,117.03 RP52.5 ; RP53.6 163.38,112.67 v4(163.12,112.93) 162.88,112.69 RP53.5 ; v4(155.93,117.25) 155.87,117.19 RP51.8 ; QX4.5 195,58.61 v4(194.66,58.27) ; v4(154,117.25) 154,117.12 154.37,116.75 RP51.5 ; RP52.7 152.58,117.02 v4(152.81,117.25) 153.08,116.98 RP52.8
  BOTTOM w0.254: 151.55,93.92 151.55,94.07 v2(151.85,94.36) 151.85,94.55 UC1.V8 151.55,94.81 UC1.W9 151.55,93.92 ; 151.55,93.92 UC1.Y8 ; v2(151.72,96.27) 151.72,96.19 151.55,96.03 UC1.U8 151.11,96.24 UC1.T9 ; v4(148.42,98.42) 148.3,98.54 UC1.K14 UC1.K16
  BOTTOM w0.356: v4(171.96,35.05) 170.64,35.05 169.95,35.75 JDIMM2.199 ; JDIMM1.199 157.95,52.01 v2(157.99,52.05)
  BOTTOM w0.508: v2(169.98,91.05) 169.68,91.05 169.04,90.41 R2341.1 RC102.1 R2344.1 C2327.1 168.46,93.08 169.73,94.36 v4(169.98,94.36) ; JLPDE.1 v4(67.35,12.39) 67.35,12.07 67.85,11.57 JLPDE.2 ; v4(101.63,123.02) 101.63,122.42 PR308.1 ; v4(173.84,96.16) v4(173.84,94.67) v4(173.84,93.65) 173.42,93.23 RC106.1 RC108.1 ; RC118.1 161.24,111.64 162.31,110.57 v2(162.31,110.24) ; v4(174.29,91.56) 174.16,91.68 RC108.1 ; v4(157.31,53.7) 156.32,52.71 143.69,52.71 v4(143.34,53.06) ; RC121.1 173.92,86.29 174.11,86.48 v2(174.57,86.48) 174.81,86.48 175.26,86.93 RL33.1 ; RC108.1 RC111.1 R2342.1 RC116.2 ; v4(180.71,104.96) U2302.8 ; PR624.2 49.2,52.55 v4(49.25,52.61) ; JIO.6 24.46,51.9 v4(24.36,52) ; RN5.2 v4(180.8,29.02) ; v2(168.91,89.37) 168.89,89.4 R2340.1 ; v4(85.09,30.74) 85.09,27.77 79.84,22.52 79.84,19.98 77.78,17.92 77.78,15.97 75.47,13.65 v4(75.47,13.16)
  BOTTOM w0.762: v4(157.31,53.7) 157.43,53.57 164.9,53.57 166.7,55.37 v4(169.7,55.37)
  vias: v2(158.22,96.47) v2(158.81,96.47) v4(80.98,100.94) v4(87.84,97.11) v4(91.47,117.66) v4(92.1,117.66) v4(165.43,112.8) v4(179.07,59.67) v4(179.07,59.03) v4(179.66,58.74) v4(180.29,58.74) v4(186.77,71.34)
+3VS_CAM: length 15.2
  TOP w0.127: v3(4.98,86.07) 4.72,86.07 v2(4.34,86.45)
  TOP w0.508: v2(10.25,79.52) 10.32,79.45 QX5.1 ; CX20.1 3.72,86.45 v2(4.34,86.45)
  IN2 w0.508: v2(10.25,79.52) 9.53,79.52 8.95,80.1 8.95,83.49 6,86.44 4.35,86.44 v2(4.34,86.45)
  BOTTOM w0.254: JEDP.12 3.28,86.44 4.34,86.44 v2(4.34,86.45)
+3VS_TP: length 6.7
  TOP w0.508: JTP.8 27.68,64.3 27.54,64.44 CE68.1 27.54,65.56 27.42,65.67 R246.1 26.37,66.22 v3(26.15,66.44) 26.12,66.47 R2521.1 R2522.1
+3VS_VGA: length 28.6
  TOP w0.432: RV517.1 205.6,102.94 205.6,101.97 205.31,101.68 QV89.5 ; QV89.2 202.4,101.68 202.06,102.02 202.06,102.94 202.35,103.23 RV516.1
  TOP w0.508: v2(191.06,104.18) 190.96,104.28 CV356.1 ; RV516.1 201.74,104.1 v2(201.74,104.12) ; v2(186.58,114.49) 186.31,114.23 185.09,114.23 184.71,113.85 v2(184.71,112.32) 184.26,111.86 183.7,111.86 ; v2(205.05,104.18) RV517.1
  BOTTOM w0.203: CV358.1 192.85,112.27 v1(192.33,111.75) 191.58,111.75 190.56,110.73 UV6.48 ; UV6.13 190.29,104.36 190.46,104.18 v2(191.06,104.18) ; CV340.1 185.55,112.33 184.65,111.43 184.65,110.1 184.86,109.89 UV6.36 ; UV6.35 185.05,109.49 184.62,109.49 184.23,109.87 184.23,112.79 184.38,112.95
  BOTTOM w0.508: v2(186.58,114.49) 186.58,114.47 186.59,114.45 RV518.1 ; RV215.2 191.07,114.48 v2(191.06,114.48) ; v2(193.48,112.32) 193.48,112.37 192.9,112.95 CV358.1 ; RV161.1 RV162.1 v2(188.41,114.47)
+3VS_WLAN_NGFF: length 0.9
  TOP w0.102: v2(189.67,51.39) CM6.1
  vias: v2(172.78,52) v2(172.78,51.41) v2(190.3,51.39) v3(172.95,52.86)
+5V_HDD:
  vias: v3(186.54,25.87)
+5V_PVDD: length 6.1
  TOP w0.203: UA1.41 187.22,23.46 187.86,24.11 187.86,24.92 188.27,25.33 CA54.1 ; CA56.1 184.33,24.31 185.22,23.42 UA1.46
  vias: v1(185.27,27.27)
+5V_USB_PWR1: length 5.5
  TOP w0.508: v2(198.56,39.55) v3(198.56,41.56) 198.56,42.73 199.59,43.76 JUSB1.1
  vias: v4(198.51,37.9) v4(198.48,37.24) v4(198.48,36.6) v4(198.48,35.92)
+5V_USB_PWR2:
  vias: v3(194.17,25.76) v4(193.84,25.25) v4(194.17,24.64) v4(194.48,25.25) v4(194.81,24.64)
+5V_USB_PWR3:
  vias: v3(28.25,48.62) v4(26.81,48.34) v4(26.84,47.7) v4(27.45,48.34) v4(27.47,48.97) v4(27.47,47.7)
+5VA: length 11.7
  TOP w0.102: RA1111.2 193.21,12.37 192.97,12.37 v1(192.19,11.6)
  TOP w0.203: 190.5,16.94 190.43,17.02 190.43,17.3 190.36,17.36 190.36,17.74 190.09,18.02 UA1.26
  TOP w0.508: RA1111.2 194.31,13.48 194.31,14.89 193.98,15.22 CA71.1 193.45,15.74 193.21,15.5 192.03,15.5 191.75,15.78 CA51.1 190.77,16.16 190.5,16.42 190.5,16.94
+5VALW: length 316.8
  TOP w0.203: v2(180.37,51.49) 180.27,51.59 U2301.4
  TOP w0.254: PU1000.7 48.01,56.56 47.74,56.83
  TOP w0.381: v2(73.21,104.4) 73.21,104.09 73.99,103.3 77.72,103.3 78.83,102.19 82.15,102.19 84.33,100 v3(85.18,100) 87.05,100 88.57,101.53 v2(88.73,101.53) ; v2(182.3,47.65) 182.94,47.65 R10.1
  TOP w0.508: v2(191.25,60.87) 191.25,61.65 185.79,67.11 185.79,71.39 188.83,74.42 v2(188.83,76.05) ; v2(169.7,45.58) 169.7,45.61 v3(165.64,49.67) 163.89,51.42 163.89,52.63 162.11,54.41 v2(161.48,54.41) ; PR7.2 v2(22.2,100.63) ; v2(145.77,53.88) 145.61,53.71 R2347.1 ; v4(178.74,117.97) 178.74,114.33 179.42,113.65 179.42,112.47 180.06,111.83 180.06,104.34 184.24,100.17 185.22,100.17 185.73,100.68 v2(185.73,101.08) ; CZ51.1 15.87,66.47 14.91,65.52 v2(14.91,61.9) 14.61,61.6 14.16,61.6 13.83,61.27 13.83,60.63 14.12,60.35 JLED.1 ; 47.74,56.83 46.8,56.83 46.41,56.44 PC1006.1 46.22,56.78 45.72,57.28 44.33,57.28 44,56.95 v2(44,53.22)
  IN1 w0.508: v2(188.83,76.05) 188.83,77.66 185.83,80.66 185.83,91.51 186.88,92.56 186.88,99.93 v2(185.73,101.08) ; v2(19.54,58.12) 18.7,58.12 v2(14.91,61.9) 14.91,62.11 16.18,63.38 16.51,63.38 19.23,66.09 19.23,75.75 15.17,79.81 15.17,82.48 22.15,89.46 22.15,99.9 22.2,99.95 v2(22.2,100.63) 22.19,100.64 22.19,104.56 23.63,106 57.31,106 63.83,99.47 70.51,99.47 72.45,101.4 72.93,101.4 73.41,101.88 73.41,103.89 73.21,104.09 v2(73.21,104.4)
  IN2 w0.508: v2(191.25,60.87) 189.39,59.02 188.64,59.02 v4(183.44,53.82)
  IN3 w0.508: v2(44,53.22) 44,51.87 45.29,50.57 45.29,42.09 48.77,38.61 56.09,38.61 57.71,36.98 v2(57.71,35.97)
  BOTTOM w0.102: 177.46,116.83 PU400.6
  BOTTOM w0.203: UV15.4 v2(88.73,101.53)
  BOTTOM w0.508: v2(19.54,58.12) 20.17,57.48 20.17,46.03 19.69,45.54 v2(19.49,45.54) ; v2(145.77,53.88) 146.03,53.62 155.83,53.62 156.7,54.49 160.18,54.49 160.25,54.41 v2(161.48,54.41) ; v2(169.7,45.58) 170.08,45.58 170.53,46.03 177.73,46.03 179.15,44.6 v2(180.07,44.6)
  vias: v2(57.71,35.36) v3(58.2,35.68) v4(19.46,44.38) v4(19.49,43.69) v4(20.12,44.38) v4(20.15,43.69) v4(58.12,20.47) v4(58.12,19.84) v4(58.12,19.2) v4(58.12,18.57) v4(58.12,17.93) v4(58.75,20.47) v4(58.75,19.84) v4(58.75,19.2) v4(58.75,18.57) v4(58.75,17.93) v4(59.44,20.47) v4(59.41,19.84) v4(59.41,19.2) v4(59.41,18.57) v4(59.41,17.93) v4(60.1,20.45) v4(60.08,19.81) v4(60.08,19.18) v4(60.08,18.54) v4(60.08,17.91) v4(182.02,53.65) v4(182.02,52.99) v4(182.02,52.35) v4(182.02,51.72) v4(183.44,52.48) v4(183.44,51.84) v4(183.49,53.14) v4(188.8,37.59) v4(188.8,36.96) v4(189.31,38.15) v4(189.95,38.13)
+5VALWP: length 25.5
  TOP w0.203: PU100.14 49.06,28.14 v4(48.63,27.71)
  TOP w0.254: v2(55.35,26.62) 55.81,27.08 PR104.2
  IN3 w0.254: v4(52.66,19.7) 53.29,19.7 54.92,21.33 54.92,26.19 v2(55.35,26.62)
  IN3 w0.508: v4(48.63,27.71) 48.72,27.8 50.77,27.8 51.34,27.23 52.51,27.23 54.28,25.45 54.28,21.52 53.27,20.5 52.05,20.5 v4(51.82,20.27)
  BOTTOM w0.254: PC108.2 55.91,27.18 v2(55.35,26.62)
  vias: v1(46.88,13.9) v4(53.98,18.6) v4(53.98,17.96) v4(54.61,19.23) v4(54.61,18.6) v4(54.61,17.96) v4(55.25,19.87) v4(55.25,19.23) v4(55.25,18.6) v4(55.25,17.96)
+5VS: length 225
  TOP w0.203: v2(67.62,110.92) 67.62,110.85 67.07,110.3 PU501.12
  TOP w0.508: Q330.3 101.53,30.86 R990.2 ; v4(52.15,52.35) 51.55,51.75 PR623.2 ; RA1111.1 194.16,11.32 v2(194.72,10.76) ; CZ50.1 16.43,65.57 16.04,65.19 16.04,62.58 v2(16.18,62.44)
  TOP w1.27: 84.97,50.29 83.27,52 79.73,52 77.86,50.12 75.53,50.12 75.52,50.1
  IN1 w0.508: v4(16.23,81.03) 16.23,82.15 22.85,88.76 v2(22.85,103.37) ; v2(16.18,62.44) 16.59,62.44 20.04,65.89 20.04,68.37 v4(24.06,72.38)
  IN2 w0.254: v4(52.15,52.35) 53.01,53.22 53.01,58.8
  IN2 w0.508: v2(13.39,105.4) 15.42,103.37 v2(22.85,103.37) 26.6,103.37 31.08,107.85 58.13,107.85 59.17,108.89 61.02,108.89 v2(62.29,110.16)
  IN2 w1.016: v4(16.21,80.09) 18.27,78.03 18.27,73.41 19.26,72.42 24.02,72.42 v4(24.06,72.38) ; v4(25.2,72.38) 25.16,72.42
  IN2 w1.27: 74.43,50.75 74.43,58.73 71.63,61.52 57.33,61.52 55.88,60.07 54.28,60.07 53.01,58.8 44.71,58.8 43.82,57.91 37.04,57.91 35.3,59.65 35.3,62.32 25.24,72.38 v4(25.2,72.38)
  IN3 w0.508: 192.36,27.71 192.74,27.33 192.74,24.92 194.34,23.32 194.34,20.07 194.9,19.51 194.9,18.29 193.98,17.38 193.98,15.8 194.75,15.04 194.75,10.78 v2(194.72,10.76)
  BOTTOM w0.508: v2(67.62,110.92) 67.62,111.09 PC528.1 64.59,111.62 63.94,110.97 63.1,110.97 v2(62.29,110.16)
  vias: v2(187.85,28.46) v2(188.1,29.06) v2(188.5,28.56) v2(189.41,54.66) v2(189.41,54.03) v2(189.41,53.39) v2(189.67,114.48) v2(190.05,54.41) v2(190.05,53.77) v2(190.05,53.14) v2(190.48,28.88) v2(190.68,53.77) v2(190.68,53.14) v2(190.78,28.35) v2(191.09,28.88) v2(191.37,28.35) v2(197.36,43.23) v2(197.59,44.4) v2(197.57,43.79) v3(188.33,57.51) v4(74.41,49.74) v4(74.43,49.1) v4(74.43,48.41) v4(86.52,49.3) v4(86.75,49.91) v4(87.15,49.33) v4(98.99,32.95) v4(98.99,32.31) v4(99.55,31.75) v4(112.32,27.36) v4(112.7,26.85) v4(113.09,27.36) v4(183.47,58.67) v4(183.69,58.07) v4(184.18,58.63) v4(184.33,57.99) v4(184.92,58.35) v4(184.99,59.62) v4(184.97,58.98) v4(185.42,57.97) v4(198.18,113.34) v4(198.67,112.94)
+5VS_KBL:
  vias: v3(121.19,25.36)
+5VS_TOUCH: length 6
  TOP w0.508: v2(5.71,90.92) 5.71,90.73 5.26,90.29 3.66,90.29 CX6.1
  BOTTOM w0.254: JEDP.19 4.74,89.95 v2(5.71,90.92)
  vias: v2(10.15,103.94) v2(10.79,103.94) v3(12.54,101.25)
+VCC_PWR_SRC:
  vias: v1(52.19,108.64)
+VCCHDA: length 4
  TOP w0.102: v1(146.78,88.18) 146.78,88.28 147.71,89.21 C77.1
  TOP w0.254: C77.1 147.83,89.23 148.4,89.8 v2(148.49,89.8)
  TOP w0.381: RC127.2 148.01,90.29 v2(148.49,89.8)
  BOTTOM w0.254: v2(148.49,89.8) 148.46,89.8 148.43,89.78 148.34,89.78 148.07,89.51 UC1.AH14
+VCCIO_OUT: length 6
  BOTTOM w0.254: R245.2 v1(119.69,109.07) 119.69,106.73 120.24,106.18 UC1.A59
+VCCIOA_OUT: length 7.2
  TOP w0.254: RC71.1 146.26,108.56 v3(146.26,103.86) 146.26,103.43 v2(145.62,102.8)
  BOTTOM w0.254: UC1.E20 144.97,102.37 145.15,102.37 145.62,102.85 v2(145.62,102.8)
+VCCRTCEXT: length 2.8
  TOP w0.254: v2(152.38,91.5) 152.38,91.47 151.95,91.04 v1(151.95,91.02) 151.93,91.01 151.44,91.01 151.19,91.26 150.78,91.26 C52.1
  BOTTOM w0.254: UC1.AE7 152.2,91.33 v2(152.38,91.5)
GND: length 2096.9
  TOP w0.102: v2(43.24,106.73) v3(43.24,107.47) ; v3(58.61,109.64) 58.83,109.85 v4(59.49,109.85) ; v2(63.73,26.75) v3(64.48,26.75)
  TOP w0.203: v2(180.32,55.07) 180.27,55.02 U2301.11
  TOP w0.254: v2(36.2,96.29) 36.54,95.95 UV18.J8 ; v2(174.5,110.96) 174.83,110.63 174.83,109.58 174.61,109.35 UC5.3 ; v2(93.02,80.9) 92.78,80.66 JXDP.49 ; v2(84.13,77.45) 84.35,77.66 JXDP.38 ; UV19.P9 v2(32.21,74.94) ; v2(92.97,74.73) 92.9,74.66 JXDP.25 ; v2(33.8,94.63) 34.21,95.04 UV18.M9 ; US2.13 US2.21 US2.3 ; v2(89.87,73.08) 89.82,73.03 89.82,72.09 90.1,71.81 90.1,71.79 90.23,71.66 JXDP.13 ; UV19.G8 UV19.F9 ; v2(135.46,26.18) 135.05,26.59 JFP.5 ; UV19.E2 v2(40.21,81.34) ; JXDP.20 85.64,73.15 87.05,73.15 87.51,73.61 v2(87.58,73.61) ; JXDP.1 92.95,68.66 93.48,69.19 v2(93.48,69.34) ; UE5.B11 151.3,11.19 v2(151.16,11.33) ; UV18.D8 v2(40.21,95.55) UV18.E8 ; UV18.P9 32.61,95.16 v2(33.01,95.56) ; UV18.G8 UV18.F9 ; JXDP.14 85.64,71.66 84.28,71.66 v2(84.13,71.81) ; v2(146.04,89.85) 146.68,89.21 C77.2 ; JXDP.2 87.67,68.66 v2(89.29,70.28) ; UV18.J2 36.77,100.75 37.04,100.48 v2(37.04,100.43) ; UV19.T1 31.01,81.94 30.73,82.22 v2(30.64,82.22) ; JXDP.32 85.64,76.15 87.1,76.15 v2(87.33,76.38) ; UV19.G1 v2(38.61,81.34) ; RPE10.5 161.56,9.21 v2(161.8,9.45) 161.7,9.45 161.44,9.71 RPE10.6 ; UV19.J2 v2(37.01,81.34) ; UC4.7 88.52,93.17 88.65,93.3 v2(89.13,93.3) ; v2(87.38,81.16) 87.28,81.16 86.79,80.66 JXDP.50 ; v2(174.05,53.27) 174.05,52.8 174.15,52.69 UM1.5 ; UV18.E1 v2(40.21,101.15) UV18.E2 ; JXDP.8 84.55,70.16 84.03,70.69 v2(84.03,71.17) ; U2412.48 81.26,13.98 v2(81.26,13.52) ; UV19.M1 v2(34.61,82.14) ; UV18.G1 v2(38.61,101.15) ; RPE6.5 135.3,13.76 v2(135.01,13.46) 135.21,13.26 RPE6.6 ; UV19.J8 v2(36.21,76.54) ; v2(89.79,77.73) 89.86,77.66 JXDP.37 ; JXDP.7 92.66,70.16 v2(92.84,69.98) ; UV19.E8 v2(40.21,75.74) UV19.D8 ; JXDP.19 v2(92.88,73.16) ; v2(133.25,53.24) 133.25,53.37 134.92,55.04 U2303.3 ; U2304.11 177.2,64.57 v2(177.12,64.49) ; RPE10.7 161.66,10.21 v2(161.8,10.07) 161.8,10.42 161.51,10.71 RPE10.8 ; v2(38.61,74.94) UV19.G9 ; v2(92.33,83.8) 92.33,83.64 91.85,83.16 JXDP.59 ; UV19.P1 32.63,81.74 v2(33.05,82.16) ; JXDP.31 v2(89.82,76.16) ; R16.2 182.3,46.55 v2(182.3,47.07) ; UE5.B66 146.08,12.17 146.11,12.19 147.25,12.19 147.63,11.81 147.93,11.81 v2(147.98,11.76) ; UV19.B1 42.21,81.83 v2(42.57,82.2) ; UE5.B18 155.15,11.17 155.52,10.8 v2(155.68,10.8) ; UV18.T9 v2(31.42,95.56) ; UV18.G9 v2(38.61,94.75) ; UV19.T9 v2(30.61,74.94) ; UV18.M1 v2(34.61,101.95) ; UV18.P1 v2(33.01,101.95)
  TOP w0.305: UV18.F9 39.01,95.15 v2(38.61,94.75) ; v2(71.91,94.5) 71.91,94.67 71.23,95.35 RV96.2 ; v2(146.36,18.16) 146.33,18.16 146.33,18.17 UE5.B54 ; v2(147.59,96.77) 147.22,96.77 C88.2 ; v2(121.87,113.87) 122.15,114.15 122.74,114.15 123.09,113.8 UC6.3 ; v2(83.88,75.49) 83.88,75.21 84.42,74.66 JXDP.26 ; v2(92.92,49.3) 92.96,49.34 92.96,50.35 92.6,50.7 JKB.1 ; UE5.B60 145.98,15.17 146.17,14.98 146.58,14.98 v2(146.84,15.24) ; v2(71.53,98.86) 71.54,98.85 v2(71.54,97.91)
  TOP w0.356: v2(39.16,119.52) 38.92,119.52 38.65,119.26 PQ3.1
  TOP w0.381: C55.2 155.75,76.89 156,77.14 v2(156,77.21) ; 42.6,94.73 42.6,94.74 UV18.A9 ; 42.6,94.73 42.21,95.12 UV18.B9 ; 42.6,94.73 v2(42.6,94.7) ; UV19.B3 42.23,80.14 v2(42.62,79.75) ; v2(64.75,85.2) 64.65,85.2 64.22,84.76 PC927.2 ; v2(79.43,85.78) 79.18,85.52 79.18,84.51 79.42,84.27 UV14.3 ; UV18.B1 42.21,101.58 v2(42.66,102.03) ; UV19.E1 39.96,81.89 v2(39.96,82.41) ; CE38.2 v2(141.36,17.96) ; UV18.T1 30.64,101.55 v2(30.31,101.88) ; CV48.2 56.75,86.46 57.03,86.18 v2(57.05,86.21) ; C62.2 146.13,91.67 146.28,91.82 v2(146.28,92.26) ; v2(51.16,87.71) 51.52,88.06 RV117.2 RV119.2 ; UV19.F9 39.01,75.34 v2(38.61,74.94) ; CE41.2 158.32,16.08 ; 158.32,16.08 RE55.1 ; 158.32,16.08 158.69,16.08 158.73,16.12 158.89,16.12 v2(158.93,16.16) ; CC33.2 175.62,85.84 175.62,85.14 175.62,85.14 UC3.3 175.62,84.94 175.33,84.65 v2(174.97,84.65) ; CA60.2 v2(180.09,18.6) ; RV118.2 RV132.2 49.99,93.65 v2(49.92,93.58) ; v2(33.84,74.86) 34.21,75.23 UV19.M9 ; v2(42.41,99.43) 42.21,99.63 UV18.B3 ; PR11.2 37.35,116.4 PQ3.4 ; v2(141.36,15.39) 141.48,15.27 CE64.2 ; CC4.1 153.65,58.09 v2(153.33,57.77) ; C56.2 155.53,75.11 155.91,75.49 155.91,75.85 v2(155.93,75.87) 155.93,75.85 155.78,76 C54.2 ; v2(149.89,91.44) 149.89,91.46 150.37,91.95 C52.2 ; C69.2 146.94,95.56 C76.2 147.22,95.56 147.5,95.28 v2(147.65,95.28) ; v2(146.28,92.84) 146.55,92.84 C78.2 ; v2(68.64,93.73) 69.17,93.19 CV68.2 ; UV19.D1 40.61,81.74 v2(40.21,81.34) ; C73.2 C87.2 ; v2(40.61,102.16) UV18.D1 ; UV19.B9 42.21,75.08 v2(42.47,74.82) 42.99,75.34 UV19.A9
  TOP w0.457: v2(176.1,22.61) 175.98,22.74 175.47,22.74 175.05,23.15 RS42.2 ; v2(179.77,19.69) 180.42,19.69 CA64.1 ; C2317.2 180.79,68.32 v2(180.81,68.3) ; CV62.2 v2(200.55,114.59)
  TOP w0.508: RC371.2 115.09,117.48 114.13,118.44 v2(113.77,118.44) ; RD6.1 RD7.1 158.6,51.06 v2(159.64,52.1) ; RV20.2 v2(196.73,57.51) ; v2(156.27,21.39) 156.21,21.44 CE44.2 ; v2(115.07,15.37) 115.06,15.37 114.72,15.04 JKBBL.5 ; v2(64.59,83.17) 64.66,83.11 PC941.2 ; v2(106.58,97.74) 107.4,97.74 R255.1 ; CZ51.2 18.53,66.47 v2(18.58,66.42) ; v2(142.55,113.97) 143.25,113.97 C86.2 143.25,113.21 v2(142.55,113.21) ; v2(178.11,109.02) 178.11,108.99 177.88,108.77 RC80.2 ; v2(147.93,74.22) 147.07,74.22 146.41,74.88 RC134.2 ; PC926.2 61.14,81.23 v2(61.29,81.08) ; CV46.2 74.2,91.05 v2(74.46,91.31) ; CD39.2 133.15,35.11 133.12,35.08 v2(133.12,34.82) ; CV42.2 30.66,106.42 v2(30.92,106.67) ; CV361.2 184.05,110.57 v2(183.72,110.9) ; CD42.2 144.71,35.59 143.96,34.84 v2(143.68,34.84) 143.55,34.84 142.93,35.46 CD48.2 ; RV59.1 63.12,100.59 62.74,100.97 62.74,102.31 v2(63.71,103.28) 63.71,102.9 65.08,101.53 RV128.1 ; JLED.8 v2(15.72,53.35) ; v2(149.79,94.16) 149.66,94.03 C82.2 149.09,93.59 149.46,93.22 C81.2 ; v2(88.07,24.69) 87.61,25.15 JKB.31 86.3,25.97 v2(87.05,26.72) ; PC939.2 62.09,84.7 v2(62.57,85.18) ; v2(203.57,104.19) CV56.2 CV57.2 ; v2(142.04,115.88) 142.04,116 143.31,117.27 C84.2 142.74,117.97 141.41,116.64 v2(141.41,115.88) ; v2(159.06,72.34) 158.65,72.34 CC3.1 ; CE45.2 v2(152.59,5.93) ; v2(59.75,39.42) 59.3,39.42 PC604.2 59.21,38.66 v2(59.75,38.66) ; Q8.3 185.3,42.34 185.14,42.19 v2(185.14,41.56) ; v2(139.93,20.83) 140.78,19.98 CE50.2 ; CE3.2 93.15,13.46 93.21,13.4 v2(93.21,12.58) 93.21,11.8 93.67,11.34 RE280.2 ; v4(47.36,49.71) 47.79,49.28 PC616.1 ; PR11.2 36.67,116.27 v2(36.48,116.46) ; v2(38.76,85.88) 38.66,85.98 CV217.2 RV143.2 ; PC725.2 13.21,71.05 v2(13.11,71.15) ; RE24.2 97.16,23.24 v2(97.34,23.42) 97.51,23.24 RE87.1 ; PC1006.2 44.87,56.49 v2(45.52,56.49) ; v2(87.58,51.31) 86.3,52.59 JKB.32 84.12,53.05 v2(83.45,53.72) ; v2(107.84,44.51) 108.05,44.51 108.49,44.07 108.49,43.28 108.13,42.93 CD33.2 ; CS27.2 172.3,16.36 172.53,16.13 v2(172.53,15.75) ; v2(151.29,5.93) 151.31,5.96 CE43.2 ; CV164.2 v2(76,92.89) ; PR1007.2 PC1005.2 v4(54.6,56.06) ; C60.2 147.35,93.63 147.96,93.02 147.96,92.86 v2(147.98,92.84) ; v2(133.64,47.69) 133.8,47.69 134.42,48.31 CD20.2 ; UI2.2 195.25,26.98 v2(196.02,26.22) 195.94,26.14 CI17.2 ; CV112.2 71.47,86.6 v2(71.1,86.24) ; v2(195.48,32.88) CI15.2 CI13.2 ; v2(24.19,44.69) 23.79,44.3 CI47.2 23.78,44.01 CI46.2 ; v2(81.97,95.99) 81.72,96.24 RC369.1 RC368.1 ; CC16.2 v2(95.26,80.48) ; RC22.2 113.7,65.51 v2(112.9,65.51) ; CX50.2 v2(15.26,98.43) ; v2(118.83,110.97) 118.67,110.82 CC42.2 ; v2(60.63,89.05) 60.79,89.05 61.45,89.72 PC929.2 ; v2(19.36,60.51) 18.07,60.51 JTP.10 18.06,59.74 v2(19.36,59.74) ; DE2.2 144.28,23.69 v2(144,23.41) ; UM1.9 175.25,50.08 RM8.2 175.75,49.35 176.56,48.54 v2(176.56,48.44) ; v2(164.08,19.36) 164.08,19.04 164.52,18.6 RS40.2 ; C2309.2 183.16,49.17 v2(182.31,48.31) ; v2(132.47,89.93) 132.64,90.11 C70.2 ; C80.2 114.99,108.26 v2(115.19,108.05) ; v2(62.69,88.22) 62.12,88.22 PC928.2 ; v2(196.68,61.83) 197.13,62.28 CX22.2 ; CA76.2 179.33,25.47 177.86,26.94 177.65,26.94 v2(177.35,27.24) ; JFP.8 137.44,24.05 v2(137.24,23.85) ; C67.2 151.11,109.3 150.87,109.54 C66.2 150.87,111.55 v2(150.6,111.81) ; v2(114.72,20.77) JKBBL.6 114.72,22.61 C5261.2 ; v2(64.75,86.2) 64.83,86.29 PC940.2 ; QX1.3 v2(8.58,70.28) ; C2317.2 C2315.2 ; CA58.2 180.24,23.62 178.85,23.62 178.41,23.19 CA22.2 178.41,22.53 178.1,22.21 RA1113.1 177.77,21.38 v2(177.77,21.01) ; v2(201.45,107.27) 201.45,107.27 DV6.1 ; v2(24.44,61.65) 24.68,61.89 JTP.5 ; CV129.2 RV187.2 75.11,84 v2(74.78,84.33) ; PC931.2 68.08,89.49 v2(68.48,89.08) ; CD19.2 132.9,43.04 132.9,44.3 133.36,44.77 v2(133.64,44.77) ; v2(177.6,94.92) 177.97,95.29 Q9.3 ; v2(141.21,8.65) 141.65,8.21 CE53.2 ; CD53.2 CD52.2 149.04,29.22 149.04,30.78 148.55,31.26 v2(148.42,31.26) ; PR1005.2 54.44,58.75 v2(54.61,58.58) ; v2(171.2,49.02) 170.92,49.3 CM8.2 170.92,50.8 CM4.2 ; v2(180.66,57.84) 180.71,57.79 C5292.2 C5293.2 ; C5254.2 89.67,23 90.61,23.95 v2(90.61,25.23) ; v2(155.99,79.4) 155.88,79.3 CC34.2 ; CV161.2 59.57,85.78 59.36,85.98 CV43.2 58.87,86.35 58.42,86.79 v2(58.42,86.92) ; v2(2.2,86.48) CX20.2 2.2,84.98 RX9.2 ; CV218.2 36.58,68.71 36.22,68.35 v2(35.92,68.35) ; v2(32.41,104.29) 32.41,105.44 32.9,105.92 CV186.2 ; RC132.2 105.01,95.05 C5212.2 v2(104.07,94.8) ; CX7.2 v2(10.19,80.2) ; CV197.2 41.56,71.1 42.18,70.47 CV15.2 43.91,70.47 v2(44,70.39) ; RC24.2 117,69.65 v2(117.17,69.48) ; v2(146.04,9.03) 146.04,8.77 146.61,8.19 CE21.2 ; CE62.2 142.27,10.11 v2(142.42,9.96) ; CD38.2 CD37.2 144.85,29.6 144.85,30.01 v2(145.09,30.25) ; CV198.2 69.79,90.15 CV130.2 70.02,89.65 69.8,89.44 v2(69.37,89.44) ; PR114.2 53.47,24.74 v2(53.57,24.84) ; CS28.2 138.93,27.17 v2(138.66,26.9) ; v4(50.6,46.15) 50.05,45.6 PC608.2 ; v2(64.34,88.18) 64.55,87.96 PC924.2 ; CD46.2 132.2,30.34 v2(131.6,30.94) ; v2(125.87,44.67) 126.23,44.67 126.42,44.48 126.45,44.48 127.05,43.87 127.05,42.93 CD6.2 ; v2(168.49,34.42) 168.66,34.42 169.14,34.9 CD56.2 CD55.2 CD54.2 ; v2(105.4,44.62) 105.08,44.62 104.7,44.25 104.7,43.74 104.83,43.61 CD3.2 ; v2(159.69,52.76) 159.29,52.76 158.88,53.16 CD30.2 CD31.2 ; RV114.2 28.25,86.46 v2(29.77,86.46) ; UI4.2 22.79,39.97 24.44,41.62 v2(24.44,42.15) ; CD58.2 172.32,32.31 v2(172.7,31.93) 172.7,31.93 171.94,31.17 CD57.2 ; C1160.2 102.44,27.66 v2(103,28.22) ; CV165.2 59.69,88.93 59.36,89.26 CV47.2 59.34,89.68 59.34,90.32 v2(59.31,90.35) ; CV168.2 v2(50.03,96.19) ; v2(131.26,45.53) 130.95,45.53 130.48,45.06 130.48,42.86 CD7.2 ; CV40.2 67.37,93.8 66.97,94.2 v2(66.97,94.57) ; v2(112.93,64.65) 113.69,64.65 RC25.2 ; CV52.2 RV33.2 200.58,112.32 v2(200.59,112.32) ; PC3.2 v2(21.01,35.87) ; CV32.2 62.35,75.61 v2(62.63,75.33) ; RL27.1 185.3,79.16 v2(185.48,78.98) ; v2(189.64,48.47) 189.64,48.49 189.67,48.52 CM6.2 ; CV135.2 62.31,79.24 v2(61.97,79.58) ; CE13.2 160.76,13.13 161.27,13.64 v2(161.33,13.64) 161.35,13.64 160.84,14.15 CE63.2 ; CI50.2 CS29.2 168.05,26.04 v2(168.33,26.32) ; JLED.10 v2(13.12,63.35) ; v2(44.34,49.25) 44.56,49.25 44.72,49.09 PR614.1 ; v2(152.96,77.19) 153.09,77.32 R2338.2 RC92.1 ; v2(65.59,89.03) 65.4,89.22 PC952.2 ; v4(54.61,54.41) 54.46,54.26 PR1002.1 ; PC1.2 v2(18.85,35.61) ; RV48.2 RV95.2 72.09,95.25 v2(71.94,95.4) ; CE24.2 10.14,69.74 v2(10.14,70.28) ; v2(138.36,8.05) 138.36,8.5 CE42.2 137.6,8.5 v2(137.6,8.05) ; v2(20.69,67.87) 19.84,67.02 DE1.1 ; v2(11.74,97.21) 12.29,97.75 CX49.2 ; CV131.2 v2(39.93,106.73) ; CX51.2 v2(16.15,106.77) ; v2(113.09,110.42) 112.91,110.42 112.58,110.09 RC129.1 ; CV204.2 v2(28.2,71.1) ; CE14.2 158.88,14.15 158.93,14.2 v2(158.93,14.2) ; C63.2 147.78,109.65 v2(147.73,109.7) ; PR8.1 21.22,100.75 v2(21.34,100.62) ; v2(162.05,42.88) 162.02,42.85 CD27.2 ; v2(53.65,97.9) 53.06,97.31 RV43.2 ; CV159.2 74.92,79.39 v2(74.33,78.8) 74.25,78.71 74.25,77.88 73.64,77.27 RV107.2 ; CC13.2 88.47,87.84 88.29,87.66 v2(88.29,87.58) ; RC90.2 150.32,78.01 v2(150.32,80.65) ; v4(47.35,32.49) 47.85,31.99 PC103.2 ; CV179.2 34.93,105.92 v2(35.46,105.39) ; CD2.2 98.28,53.9 v2(98.28,55.57) ; PQ2.3 v2(24.96,100.69) ; RE90.2 103.38,15.55 103.08,15.85 v2(103.08,16.13) ; v2(190.81,76.89) 191.32,76.89 CL33.2 191.44,78.03 v2(190.81,78.03) ; v2(2.28,92.32) CX10.2 CX6.2 ; QX3.3 192.23,66.07 v2(192.23,65.13) ; CI49.2 v2(30.03,45.9) ; v2(159.06,20.78) 158.37,21.47 CE61.2 ; v2(123.26,15.69) 123.26,13.58 QE11.3 ; v2(127.88,25.9) 128.23,25.55 JFP.7 ; C2328.2 171.44,66.73 170.31,66.73 169.98,67.06 v2(169.98,67.13) ; PC106.2 v2(47.74,27.61) ; v2(62.84,92.08) 62.87,92.1 CV133.2 ; v2(177.79,81.84) 177.79,81.33 177.59,81.13 CC11.2 R159.2 ; v2(199.65,64.9) 199.95,64.59 CX21.2 ; RD13.2 167.36,37.85 166.66,38.56 v2(166.61,38.56) ; CD1.2 97.08,53.72 97.08,55.41 v2(97.41,55.74) ; RS38.2 168.97,25.68 v2(168.97,26.29) ; CV335.2 37.55,107.88 38.28,107.14 v2(38.28,106.73) CV172.2 ; v2(61.52,85.28) 61.84,85.6 PC938.2 ; v4(80.32,84.84) 80.83,84.33 RV45.1 ; v2(196.65,13.81) 196.31,14.15 DA13.1 ; PC612.2 v4(44.34,44.55) ; v2(147.59,96.77) 147.76,96.94 C73.2 ; v2(129.79,48.2) 129.72,48.26 CD14.2 ; v2(5.07,95.24) 5.58,94.73 DX2.1 ; RV152.2 33.25,93.58 33.8,94.12 v2(33.8,94.63) ; JFP.1 131.05,25.87 v2(131.04,25.86) ; v2(56.33,24.75) PC100.2 55.4,24.78 55.4,25.3 55.81,25.71 PR105.2 ; v2(87.06,23.83) 86.75,23.83 R2484.2 ; CD40.2 137.72,35.36 137.13,34.77 v2(136.89,34.77) ; v2(69.14,86.77) 69.07,86.77 68.58,86.29 PC930.2 ; RV93.2 70.24,95.38 71.07,95.38 RV96.2 ; PR13.2 PC11.2 v2(40.4,120.21) ; v2(169.73,54.54) 170.62,53.65 CM3.1 170.86,53.58 CM5.2 ; RV155.2 34.73,70.14 v2(34.68,70.09) ; CC15.2 82.66,78.92 v2(84.13,77.45) ; C5256.2 84.09,10.94 85.22,10.94 85.63,11.34 85.63,12.09 v2(85.6,12.12) ; v2(71.91,102.21) 71.94,102.19 RV512.2 ; v2(123.67,47.66) 123.99,47.66 124.64,48.31 CD12.2 CD13.2 ; CD21.2 137.34,42.17 137.34,43.44 136.69,44.09 v2(136.51,44.09) ; CV210.2 v2(30.28,70.41) ; v2(82.04,82.48) 82.25,82.48 82.61,82.13 CC17.2 ; CA57.2 177.22,25.63 v2(176.48,26.37) 176.46,26.39 CA77.2 ; v2(56.57,30.38) 56.32,30.63 PR108.2 ; PC1009.2 v2(34.9,47.04) ; v2(139.3,34.82) 139.49,34.82 140.39,35.71 CD45.2 ; v2(131.6,34.8) 131.75,34.95 CD44.2 ; v2(138.56,45.1) 138.36,44.89 138.36,42.17 CD22.2 ; v2(60.57,83.17) 60.38,82.98 CV163.2 ; v2(149.25,119.15) 149.25,119.75 149.76,120.26 C65.2 149.94,120.23 v2(149.94,119.38) ; v2(160.81,40.79) 160.99,40.79 161.54,41.34 CD29.2 ; v2(105.97,78.29) 106.56,77.7 RC70.2 RC68.2 RC69.2 ; C2308.2 191.24,43.74 v2(191.09,43.89) ; v2(141.5,35.2) 141.67,35.37 141.67,36.16 CD41.2 ; v2(171.54,121.47) 171.54,121.11 SW1.3 172.78,120.87 v2(172.78,121.43) ; CD59.2 169.54,39.11 169.04,38.61 v2(168.84,38.61) ; C51.2 150.09,88.37 150.58,87.88 v2(150.88,87.88) ; C5259.2 90.33,19.9 v2(90.33,20.58) ; R2351.1 v3(143.9,54.6) 144.7,54.6 v2(145.01,54.92) ; v2(58.4,91.37) 58.55,91.52 CV45.2 ; v2(61.55,91.39) 62.21,91.39 62.22,91.38 CV39.2 ; v2(102.75,20.3) 102.42,19.97 CE10.2 ; CV24.2 65.78,91.39 66.11,91.72 v2(66.68,91.72) ; v2(174.89,121.72) 174.89,121.38 174.55,121.04 SW1.6 174.44,121.04 174.22,121.26 v2(174.22,121.72) ; v2(121.84,65.62) 121.81,65.59 RC20.2 ; v2(63.63,79.63) 63.73,79.73 CV205.2 ; v2(144.86,5.99) 144.84,6.01 CE49.2 ; v2(32.26,71.05) RV142.2 CV216.2 ; R2525.2 R2526.2 170.95,77.11 v2(170.54,76.7) ; v2(136.51,45.61) 136.29,45.61 135.69,45.01 135.69,42.8 CD8.2 ; v2(200.09,113.73) CV61.2 ; QA7.3 196.08,8.5 v2(196.27,8.31) 196.54,8.04 RA1116.2 ; CV359.2 189.35,105.4 v2(189.86,105.91) 190.43,105.34 CV356.2 ; CV180.2 38.08,71.1 38.31,71.33 38.31,72.65 v2(38.38,72.72) ; v2(61.13,79.58) 61.12,79.58 60.65,79.11 CV65.2 ; v2(184.22,67.87) 183.84,67.49 C2325.2 ; RA1115.2 182.94,8.59 v2(182.86,8.51) ; CC41.2 125.4,112.04 125.63,112.27 v2(125.63,112.47) ; JTAG1.2 149.27,26.43 v2(149.27,27.07) ; C64.2 141.03,75.31 140.39,74.68 v2(140.39,74.35) ; RV39.2 RV23.2 ; RV23.2 69.27,102.26 69.6,102.59 v2(69.6,103.05) ; RV23.2 RV129.1 ; v2(145.8,34.92) 146.04,34.92 146.43,35.3 146.43,35.75 CD47.2 ; v2(134.9,30.25) 134.88,30.22 CD35.2 ; PQ708.6 17.9,41.65 v2(18.15,41.9) ; v2(197.25,22.67) 196.49,23.43 RA1114.2 ; RC87.1 RC84.1 v2(154.11,110.47) ; CD16.2 120.96,43.17 120.96,45.65 121.5,46.19 v2(121.73,46.19) ; CD34.2 116.39,30.41 v2(116.25,30.55) ; v2(19.03,63.87) 18.25,64.65 CZ49.2 CZ50.2 ; v2(69.89,81.54) 70.24,81.19 CV64.2 ; v2(109.63,43.36) 109.45,43.36 109.15,43.06 109.15,42.17 CD32.2 ; CV337.2 190.01,107.7 v2(190,107.69) ; v2(107.67,109.63) 108.14,110.1 R2.2 ; v2(39.98,72.75) 39.98,71.5 39.58,71.1 CV209.2 ; v2(5.26,82.54) 4.51,82.54 CX31.2 ; RS25.2 RS33.2 171.66,26.14 v2(171.81,26.29) ; v2(204.46,118.49) 203.81,117.85 CV54.2 ; CA53.2 187.65,27.29 CA54.2 189.11,27.51 v2(189.11,27.99) ; PC953.2 67.36,84.38 v2(67.57,84.18) ; RV32.2 CV51.2 v2(201.27,115.37) ; RE78.2 v2(161.35,16.06) ; v2(127.94,44.89) 128.25,44.89 128.71,44.43 128.71,43.74 128.45,43.49 CD18.2 ; C71.2 C68.2 149.61,95.15 v2(149.03,95.15) ; PC548.1 62.29,109.1 v2(62.74,109.1) ; v2(201.48,106.48) CV53.2 ; v2(4.75,87.43) 5.12,87.8 DX3.1 ; CV55.2 204.26,110.78 v2(204.65,111.18) ; v2(127.95,47.82) 127.81,47.82 127.31,48.31 127.31,49.08 127.74,49.51 CD10.2 ; v2(158.13,9.69) 158.13,9.77 158.32,9.96 RE77.2 CE55.2 ; RE82.1 CE65.2 140.16,12.65 138.92,12.65 v2(138.64,12.94) ; v2(30.03,46.79) 29.77,47.04 CI48.2 ; CD36.2 141.54,29.48 141.54,30.58 v2(141.5,30.63) ; v2(58.68,79.62) 58.92,79.38 CV16.2 ; v2(161.32,18.49) 161.12,18.7 160.63,18.7 CE52.2 ; v2(157.9,109.34) 158.11,109.34 158.5,109.73 RC374.2 ; PC541.1 72.95,105.64 73.84,104.75 v2(73.84,104.4) ; C62.2 C61.2 ; v2(196.05,37.58) 196.05,37.23 195.64,36.81 UI3.2 ; CI44.2 v2(18.58,43.77) ; JLED.9 v2(13.19,50.35) ; v2(177.12,64.49) 176.66,64.04 175.35,64.04 174.86,64.53 C5291.2 ; CC29.2 84.44,90.7 84.99,90.15 v2(84.99,90.15) ; RS32.2 RS35.2 169.6,15.8 v2(169.45,15.65) ; v2(119.78,44.67) 119.31,44.2 119.31,42.8 CD4.2 ; RC191.2 v2(106.48,90.48) ; CV199.2 66.1,94.19 v2(66.1,94.57) ; RC183.2 106.79,92.59 v2(106.74,92.64) ; CV49.2 70.44,87.23 69.88,87.78 v2(69.19,87.78) 69.04,87.94 PC925.2 ; CD28.2 161.66,50.57 161.42,50.33 CD24.2 v2(161.42,49.46) ; v2(73.02,109.21) 73.02,108.45 72.65,108.08 PC546.1 ; v2(145.34,97.49) 145.9,97.49 C83.2 ; CD5.2 122.74,43.79 121.86,44.67 v2(121.73,44.67) ; JFP.2 132.05,25.91 v2(132.04,25.9) ; v2(134.9,34.82) 135.08,34.82 136.06,35.79 136.08,35.79 CD43.2 ; CV160.2 74.92,81.55 v2(74.38,82.1) ; v2(5.29,81.59) 4.69,81.59 CX5.2 4.56,80.95 v2(5.29,80.95) ; CA59.2 177.83,17.34 v2(177.27,16.78) ; v2(68.13,81.79) 68.13,81.51 68.33,81.31 CV63.2 ; RA19.2 176.64,14.84 v2(177.26,15.46) 177.29,15.5 178.36,15.5 CA69.2 RA81.1 ; v2(186.44,90.02) CL41.1 ; CL39.2 v2(186.49,84.77) ; UX3.2 v2(15.59,101.56) ; v2(121.84,64.6) 121.81,64.57 RC23.2 ; v2(123.65,44.67) 123.95,44.67 124.77,43.84 CD17.2 ; PC724.2 v2(32.63,110.35) ; UL2.2 v2(181.88,81.78) ; PD3.2 v2(18.2,108.46) ; CE46.2 147.5,6.21 147.48,6.18 v2(147.48,5.93) ; CA38.2 v2(199.01,7.43) ; v2(11.08,85.17) 11.08,85.6 11.17,85.69 UX1.2 ; CV33.2 73.97,86.6 v2(74.35,86.22) ; CE68.2 v2(29.14,65.08) ; v2(165.87,9.93) 165.87,10.21 166.07,10.42 Q10.3 ; v2(148.98,96.04) 148.98,96.34 148.77,96.55 C50.2 C57.2 C53.2 ; PR741.2 v2(42.79,13.57) ; v2(178.63,49.3) 178.54,49.3 178.38,49.14 C2318.2 ; JTP.9 30.68,61.57 v2(30.48,61.78) ; CD26.2 v2(162.08,43.74) ; C5263.2 C5262.2 ; v2(156.85,78.31) 156.85,77.68 CC2.1 ; v2(79.23,20.3) 79.38,20.45 C5255.2 ; v2(140.69,24.06) 140.69,24.21 141.44,24.96 DS1.1 ; v2(144.91,109.45) 144.71,109.45 144.28,109.02 C85.2 ; PC201.2 v2(71.05,38.09) ; v2(57.81,82.93) 57.71,82.83 CV211.2 ; RV44.2 v2(52.44,96.32) ; v2(180.54,43.84) 180.1,43.4 Q2307.3 ; CE40.2 151.31,23.5 151.64,23.17 RE56.1 152.56,23.17 v2(153.06,22.66) ; RE63.2 139.3,13.77 v2(138.87,14.2) 139.35,14.68 CE17.2 ; CE59.2 v2(146.55,23.93) ; CC14.2 v2(95.41,78.18) ; CV134.2 71.68,90.55 71.15,91.09 v2(71.15,91.16) 71.15,91.54 70.82,91.87 CV30.2 ; RA1117.2 v2(197.92,22.66) ; v2(137.75,59.46) 136.87,59.46 136.5,59.83 CD23.2 ; v2(140.14,30.41) CD49.2 ; v2(5.68,85.71) 5.19,85.22 4.69,85.22 4.44,84.97 RX29.2 RX26.2 ; v2(133.25,52.03) 132.81,52.03 131.5,50.73 CD11.2 ; v2(143.68,31.03) 143.33,31.03 142.93,30.63 142.93,29.83 CD50.2 ; DV5.1 201.55,113.29 v2(201.35,113.08) ; v2(173.66,33.94) 173.74,34.01 CD61.2 CD60.2 ; CD9.2 138.19,47.39 v2(138.56,47.39) ; CV187.2 31.68,106.35 31.55,106.48 v2(31.55,106.8) ; CM7.2 191.27,49.63 v2(191.49,49.86) ; PC626.2 v4(51.68,45.14) ; CV170.2 v2(31.55,70.41) ; CV143.2 v2(41.58,106.73) ; CE4.2 104.21,20.2 v2(103.66,20.2) ; CD25.2 v2(161.98,44.68) ; PH600.2 v2(74.67,41.25) ; v2(200.59,106.48) RV34.2 ; CC1.1 159.52,78.34 159.34,78.51 v2(159.34,79.48) ; CV60.2 197.74,106.4 v2(197.67,106.48) ; v2(147.3,76.96) 147.2,76.86 147.2,75.44 147.67,74.97 RC101.2 CC35.2 ; v2(180.65,48.39) 180.9,48.64 C2322.2 C2316.2 ; DX4.1 v2(7.99,78.54) ; v2(170.57,67.39) 170.92,67.74 C2329.2 ; v2(117.22,68.59) 117.17,68.63 RC21.2 ; PC204.1 v2(56.12,37.12) ; RE66.2 v2(150.17,27) ; v2(150.42,5.93) CE54.2 ; CV184.2 v2(43.24,106.73)
  TOP w1.016: SW1.5 174.48,115.99 173.59,115.99 173.22,115.62 170.44,115.62 v2(170.18,115.88)
  VCC w0.203: JCRT.17 209.6,104.79 ; JCRT.17 206,103.87 ; JCRT.17 209.6,103.87 ; JCRT.17 206,102.96 ; JCRT.17 209.6,102.96 ; JCRT.17 207.8,104.79 ; JCRT.17 207.8,102.96 ; JCRT.17 206,104.79 ; 107.3,81.51 H7.1 ; H7.1 107.3,85.49 ; H7.1 109.45,83.5 ; H7.1 109.45,85.49 ; H7.1 109.45,81.51 ; H7.1 105.15,83.5 ; H7.1 105.15,85.49 ; H7.1 105.15,81.51 ; 193.72,97.87 H14.1 ; H14.1 198.68,97.87 ; H14.1 196.2,96.92 ; H14.1 196.2,103.78 ; H14.1 199.63,100.35 ; H14.1 193.72,102.83 ; H14.1 192.77,100.35 ; H14.1 198.68,102.83 ; H4.1 23.14,11.41 ; H4.1 21.8,14.58 ; H4.1 20.46,11.41 ; H4.1 21.8,10.92 ; H4.1 23.63,12.75 ; H4.1 20.46,14.09 ; H4.1 19.97,12.75 ; H4.1 23.14,14.09 ; 200.26,29.9 JUSB2.7 ; JUSB2.7 201.09,29.07 ; JUSB2.7 201.09,30.72 ; JUSB2.7 200.45,30.53 ; JUSB2.7 200.45,29.26 ; JUSB1.13 210.44,55.95 ; JUSB1.13 207.7,55.95 ; JUSB1.13 210.44,56.82 ; JUSB1.13 207.7,56.82 ; JUSB1.13 209.07,56.82 ; JHDMI.2 202.88,72.05 ; JHDMI.2 201.71,72.05 ; JHDMI.2 202.76,71.59 ; JHDMI.2 202.3,72.64 ; JHDMI.2 201.84,72.51 ; JHDMI.2 202.76,72.51 ; JHDMI.2 201.84,71.59 ; 200.87,59.87 JHDMI.22 ; JHDMI.22 202.15,61.73 ; JHDMI.22 203.43,60.8 ; JHDMI.22 203.43,59.87 ; JHDMI.22 200.87,61.73 ; JHDMI.22 203.43,61.73 ; JHDMI.22 202.15,59.87 ; JHDMI.22 200.87,60.8 ; H5.1 85.49,58.06 ; H5.1 80.11,63.44 ; H5.1 86.53,60.75 ; H5.1 82.8,64.48 ; H5.1 85.49,63.44 ; H5.1 79.07,60.75 ; H5.1 80.11,58.06 ; H5.1 82.8,57.02 ; 13.07,15.47 JBATT.1 ; JBATT.1 15.23,15.47 ; JBATT.1 13.34,16.28 ; JBATT.1 14.96,14.66 ; JBATT.1 14.15,14.39 ; JBATT.1 13.34,14.66 ; JBATT.1 14.96,16.28 ; JLAN.10 207.76,80.5 ; JLAN.10 207.76,79.64 ; JLAN.10 204.44,80.5 ; JLAN.10 204.44,79.64 ; JLAN.10 206.1,79.64 ; JLAN.9 206.1,97.36 ; JLAN.9 207.76,96.5 ; JLAN.9 204.44,97.36 ; JLAN.9 204.44,96.5 ; JLAN.9 207.76,97.36 ; 207.04,109.34 JCRT.5 ; JCRT.5 207.18,109.86 ; JCRT.5 207.18,108.82 ; JCRT.5 207.7,108.68 ; 207.04,117.36 JCRT.7 ; JCRT.7 207.18,116.84 ; JCRT.7 207.18,117.87 ; JUSB1.4 199.59,52.42 ; JUSB1.4 199.59,50.77 ; JUSB1.4 198.76,51.6 ; JUSB1.4 198.95,50.96 ; JUSB1.4 198.95,52.23 ; JUSB1.4 200.22,50.96 ; JHDMI.20 202.15,76.23 ; JHDMI.20 200.87,75.3 ; JHDMI.20 202.15,74.37 ; JHDMI.20 203.43,76.23 ; JHDMI.20 200.87,74.37 ; JHDMI.20 203.43,74.37 ; JHDMI.20 200.87,76.23 ; JHDMI.20 203.43,75.3 ; JHDMI.8 202.76,69.51 ; JHDMI.8 201.71,69.05 ; JHDMI.8 201.84,69.51 ; JHDMI.8 202.76,68.59 ; JHDMI.8 201.84,68.59 ; JHDMI.8 202.88,69.05 ; JHDMI.11 204.31,68.01 ; JHDMI.11 203.26,67.55 ; JHDMI.11 204.31,67.09 ; JHDMI.11 203.39,67.09 ; JHDMI.11 203.39,68.01 ; JHDMI.11 204.43,67.55 ; JBATT.11 16.28,13.32 ; JBATT.11 16.28,11.37 ; JBATT.11 14.4,13.32 ; JBATT.11 12.52,12.35 ; JBATT.11 16.28,12.35 ; JBATT.11 12.52,11.37 ; JBATT.11 12.52,13.32 ; JBATT.11 14.4,11.37 ; H1.1 28.97,122.92 ; H1.1 27.8,123.34 ; H1.1 28.97,120.58 ; H1.1 29.39,121.75 ; H1.1 26.63,120.58 ; H1.1 27.8,120.16 ; H1.1 26.21,121.75 ; H1.1 26.63,122.92 ; 199.59,32.57 JUSB2.4 ; JUSB2.4 198.76,33.4 ; JUSB2.4 198.95,34.03 ; JUSB2.4 198.95,32.76 ; JUSB2.4 200.22,32.76 ; JUSB2.4 199.59,34.22 ; 211.6,57.97 JHDMI.23 ; JHDMI.23 210.32,57.97 ; JHDMI.23 211.6,59.83 ; JHDMI.23 210.32,58.9 ; JHDMI.23 212.88,57.97 ; JHDMI.23 212.88,58.9 ; JHDMI.23 212.88,59.83 ; JHDMI.23 210.32,59.83 ; JUSB1.10 203.75,39.37 ; JUSB1.10 200.19,41.12 ; JUSB1.10 203.75,40.25 ; JUSB1.10 200.19,40.25 ; JUSB1.10 200.19,39.37 ; JUSB1.10 201.97,39.37 ; 200.19,37.75 JUSB2.12 ; JUSB2.12 203.75,37.75 ; JUSB2.12 203.75,38.62 ; JUSB2.12 200.19,36.87 ; JUSB2.12 200.19,38.62 ; JUSB2.12 201.97,38.62 ; 203.39,65.01 JHDMI.17 ; JHDMI.17 204.31,65.01 ; JHDMI.17 203.39,64.09 ; JHDMI.17 204.43,64.55 ; JHDMI.17 203.26,64.55 ; JHDMI.17 204.31,64.09 ; 207.18,114.55 JCRT.8 ; JCRT.8 207.04,115.07 ; JCRT.8 207.18,115.58 ; 207.18,111 JCRT.10 ; JCRT.10 207.04,110.49 ; JCRT.10 207.18,109.97 ; 200.45,47.46 JUSB1.7 ; JUSB1.7 200.45,48.73 ; JUSB1.7 201.09,48.92 ; JUSB1.7 200.26,48.1 ; JUSB1.7 201.09,47.27 ; 14.4,33.62 JBATT.10 ; JBATT.10 12.52,35.57 ; JBATT.10 12.52,34.6 ; JBATT.10 16.28,34.6 ; JBATT.10 14.4,35.57 ; JBATT.10 12.52,33.62 ; JBATT.10 16.28,33.62 ; JHDMI.5 204.43,70.55 ; JHDMI.5 204.31,71.01 ; JHDMI.5 203.39,71.01 ; JHDMI.5 204.31,70.09 ; JHDMI.5 203.39,70.09 ; JHDMI.5 203.26,70.55 ; 210.44,22.05 JUSB2.11 210.44,22.48 ; 99.66,7.79 H8.1 ; H8.1 102.34,5.11 ; H8.1 99.66,5.11 ; H8.1 101,4.62 ; H8.1 101,8.28 ; H8.1 99.17,6.45 ; H8.1 102.34,7.79 ; H8.1 102.83,6.45 ; 13.07,21.47 JBATT.4 ; JBATT.4 14.96,20.66 ; JBATT.4 15.23,21.47 ; JBATT.4 14.96,22.28 ; JBATT.4 13.34,20.66 ; JBATT.4 13.34,22.28 ; JUSB1.12 203.75,55.95 ; JUSB1.12 200.19,56.82 ; JUSB1.12 201.97,56.82 ; JUSB1.12 200.19,55.07 ; JUSB1.12 200.19,55.95 ; JUSB1.12 203.75,56.82 ; 200.19,22.05 JUSB2.10 ; JUSB2.10 200.19,22.92 ; JUSB2.10 200.19,21.61 ; JCRT.16 209.6,123.97 ; JCRT.16 207.8,124.88 ; JCRT.16 207.8,123.06 ; JCRT.16 209.6,123.06 ; JCRT.16 206,123.06 ; JCRT.16 206,123.97 ; JCRT.16 209.6,124.88 ; 209.07,78.13 JHDMI.21 ; JHDMI.21 211.63,76.27 ; JHDMI.21 211.63,77.2 ; JHDMI.21 210.35,78.13 ; JHDMI.21 211.63,78.13 ; JHDMI.21 209.07,76.27 ; JHDMI.21 210.35,76.27 ; JHDMI.21 209.07,77.2 ; H19.1 191.54,4.61 ; H19.1 188.86,7.29 ; H19.1 190.2,4.12 ; H19.1 191.54,7.29 ; H19.1 188.86,4.61 ; H19.1 190.2,7.78 ; H19.1 188.37,5.95 ; H19.1 192.03,5.95 ; 210.44,38.62 JUSB2.13 ; JUSB2.13 210.44,37.75 ; JUSB2.13 209.07,38.62 ; JUSB2.13 207.7,38.62 ; JUSB2.13 207.7,37.75 ; 209.07,39.37 JUSB1.11 ; JUSB1.11 210.44,39.37 ; JUSB1.11 207.7,40.25 ; JUSB1.11 210.44,40.25 ; JUSB1.11 207.7,39.37 ; 207.18,119.13 JCRT.6 ; JCRT.6 207.04,119.65 ; JCRT.6 207.18,120.16 ; JCRT.6 207.7,120.31 ; JBATT.2 14.96,18.28 ; JBATT.2 13.07,17.47 ; JBATT.2 14.96,16.66 ; JBATT.2 13.34,18.28 ; JBATT.2 13.34,16.66 ; JBATT.2 15.23,17.47
  BOTTOM w0.076: 156.72,84.33 v2(156.82,84.43) ; 140.98,106.2 140.75,105.96 140.75,104.37
  BOTTOM w0.102: v3(42.09,53.71) 42.35,53.46 v4(42.35,52.83) ; v3(95.7,102.92) 95.79,103.01 PC903.2
  BOTTOM w0.127: UC1.AV41 131.39,83.81 131.76,84.18 131.76,84.66 131.78,84.68 ; v2(41.95,47.59) v3(41.95,46.73) ; 115.97,90.46 117.09,90.46 117.17,90.38 117.83,90.38 UC1.AG63 ; 133.33,84.73 133.33,84.18 132.97,83.81 UC1.AV39 ; UC1.AV49 127.03,84.03 127.03,84.54 127.19,84.7 ; 134.93,84.66 134.93,84.2 134.54,83.81 UC1.AV36
  BOTTOM w0.152: UC1.AT42 130.85,84.64 130.33,84.64 130.18,84.49 130.18,84.13 129.82,83.76 UC1.AV43 ; v2(146.96,81.52) UC1.AY16
  BOTTOM w0.178: UC1.AU16 146.44,84.63 146.42,84.65 146.14,84.65 146.12,84.63 UC1.AU18 ; v2(116.67,86.46) 116.72,86.51 116.93,86.51 117.02,86.6 UC1.AN63 ; v2(143.23,81.69) 143.23,82.02 143.18,82.08 143.18,82.68 UC1.AY22 ; v2(116.58,88.84) 116.78,89.03 UC1.AJ63 ; UC1.AJ60 119.79,88.62 119.81,88.61 119.81,88.32 119.79,88.3 UC1.AL60 119.79,87.33 119.81,87.31 119.81,87.03 119.79,87.01 UC1.AN60 ; 133.3,84.7 132.93,84.7 132.86,84.77 UC1.AT40 131.87,84.77 131.78,84.68 131.07,84.68 UC1.AT42 ; UC1.AY53 123.81,82.06 123.77,82.01 123.77,81.62 123.52,81.38 v2(123.51,81.38) ; UC1.AW33 136.69,83.93 UC1.AV33 ; UC1.AT46 127.76,84.7 126.71,84.7 126.67,84.74 UC1.AT49 ; v2(116.64,84.25) 116.64,84.48 117.3,85.14 UC1.AT63 117.63,85.25 117.79,85.25 117.82,85.29 118.32,85.29 UC1.AT62 118.38,85.35 UC1.AT61 ; v2(145.54,81.76) 145.6,81.83 UC1.AY18 ; v2(140.28,81.52) 140.28,81.54 140.47,81.74 UC1.AY26 ; UC1.AV51 UC1.AW51 UC1.AY51 125.16,81.8 125.12,81.76 125.12,81.71 v2(125.06,81.71) ; v2(141.76,81.79) 141.82,81.85 UC1.AY24 UC1.AW24 UC1.AV24 UC1.AU24 141.31,84.63 141.29,84.65 141,84.65 140.99,84.63 UC1.AU26 140.06,84.63 140.04,84.65 139.76,84.65 139.74,84.63 UC1.AU28 ; UC1.AY30 138.04,81.88 137.85,81.69 v2(137.85,81.69) ; UC1.AY57 121.38,81.82 121.29,81.73 v2(121.29,81.79)
  BOTTOM w0.203: v2(118.5,101.88) 118.47,101.88 118.47,101.86 UC1.F61 ; v2(152.9,103.68) 152.76,103.68 152.43,103.35 152.13,103.35 UC1.D8 ; UC1.AU59 119.84,84.93 119.84,85.23 119.61,85.47 119.49,85.35 UC1.AT61 ; UV15.11 86.16,101.53 86.29,101.4 v2(86.8,101.4) ; PU200.14 59.24,34.46 v4(59.44,34.65) ; v2(118.51,92.94) 118.81,92.64 UC1.AC61 ; 142.09,85.23 141.82,84.96 141.82,84.64 UC1.AU24 ; v2(144.51,102.12) 144.49,102.12 144.05,102.56 UC1.D21 ; CC6.1 133.46,111.19 133.82,110.83 135.06,110.83 135.74,110.14 137.71,110.14 138.93,108.92 140.36,108.92 141.03,108.26 141.03,106.24 140.98,106.2 ; UC1.AK3 154.53,88.5 v2(154.53,88.44) ; v2(4.37,92.79) 4.03,92.45 JEDP.24 ; 115.97,90.46 114.6,90.46 v2(114.5,90.36) ; UC1.AU16 146.92,85.07 147.08,85.23 147.37,85.23 v2(147.53,85.39) ; UC1.AN40 131.7,87.07 v2(131.6,87.07) 131.5,87.07 UC1.AN42 ; 138.02,84.66 137.51,84.66 137.5,84.65 137.22,84.65 137.17,84.6 136.83,84.6 UC1.AU33 ; UC1.R10 UC1.R8 ; UC1.B48 UC1.A48 ; UC1.A24 142.12,105.43 142.45,105.76 142.45,108.01 140.45,110.01 139.31,110.01 138.49,110.83 138.44,110.83 CC7.1 ; UC1.AU1 156.72,84.33 ; UC1.B60 119.49,104.33 119.77,104.05 119.77,103.61 120.24,103.13 UC1.D59 ; 125.97,89.37 126.29,89.37 UC1.AH49 ; v2(155.16,103.31) 154.45,103.31
  BOTTOM w0.229: UC1.AU22 143.55,84.63 143.58,84.66 144.36,84.66 UC1.AU20 UC1.AV20 v2(144.39,83.49) ; UC1.AU53 123.43,84.63 123.39,84.67 123.09,84.67 123.05,84.63 UC1.AU55 122.14,84.63 122.1,84.67 121.8,84.67 121.76,84.63 UC1.AU57 121.22,84.63 121.21,84.63 120.88,84.63 120.85,84.66 120.54,84.66 120.51,84.63 UC1.AU59
  BOTTOM w0.239: v2(71.51,75.39) 71.51,76.76 UV1.AF5
  BOTTOM w0.249: UV1.B5 71.54,96.59 v2(71.54,97.91)
  BOTTOM w0.254: UC1.G8 151.96,101.39 v2(152.24,101.39) 152.57,101.07 UC1.G6 ; UV17.D1 40.61,95.09 v2(40.21,94.69) 39.81,95.09 UV17.E1 ; v2(33.84,74.86) 34.21,75.23 UV19.M9 ; UC1.AH42 130.19,89.37 UC1.AJ43 129.54,89.7 UC1.AH44 128.89,89.7 UC1.AJ45 128.51,89.37 128.24,89.1 128.21,89.1 128.19,89.09 v2(127.85,89.09) ; UC1.AH42 130.58,89.76 v2(130.58,90.28) ; UC1.AH42 130.84,89.37 UC1.AJ41 131.17,89.36 131.17,89.9 v2(131.22,89.94) 131.26,89.98 131.68,89.56 UC1.AH40 132.05,89.93 v2(132.47,89.93) ; JEDP.38 4.14,99.45 v2(4.34,99.65) ; v2(138.35,101.28) 138.36,101.28 UC1.F30 UC1.D30 ; DI4.3 v2(197.82,31.04) ; 123.87,88.43 v2(123.92,88.43) ; 123.87,88.43 123.91,88.47 124.31,88.47 UC1.AK52 124.56,89.27 UC1.AJ52 124.99,89.7 UC1.AH51 125.64,89.37 UC1.AJ50 125.97,89.37 ; 123.87,88.43 123.83,88.43 123.83,88.48 123.91,88.56 123.91,88.58 124.01,88.68 UC1.AH53 123.69,89.37 UC1.AJ54 123.36,89.33 v2(123.02,88.99) 123.01,88.99 123,88.99 123.02,88.99 122.71,89.3 UC1.AH55 122.39,89.37 UC1.AJ56 121.74,89.7 UC1.AH57 121.09,89.7 UC1.AJ58 ; UC1.AP57 121.56,86.12 v2(121.23,85.79) ; UC1.U9 151.11,95.28 UC1.V10 149.34,94.84 v2(149.03,95.15) ; v2(139.29,83.48) 139.26,83.51 UC1.AV28 UC1.AU28 138.8,84.63 138.76,84.68 138.46,84.68 138.41,84.63 UC1.AU30 138.02,84.66 138.02,85.09 137.88,85.23 UC1.AR31 UC1.AP31 UC1.AN31 ; UC1.AY11 149.77,81.2 v2(150.32,80.65) ; v2(133.34,101.28) 133.34,101.28 UC1.F38 UC1.D38 ; UV18.M9 34.21,95.04 v2(33.8,94.63) ; v2(31.42,95.56) UV18.T9 ; UC1.AH49 126.63,89.68 126.63,89.2 v2(126.88,88.95) 126.92,88.95 127.26,89.3 UC1.AJ47 127.55,89.09 v2(127.85,89.09) ; v2(74.53,94.18) 74.03,94.18 UV1.E2 ; v2(152.8,87.18) 152.68,87.18 UC1.AN7 ; UC1.H17 146.57,100.71 v2(146.36,100.71) 146.33,100.74 146.24,100.74 UC1.G18 ; v2(144.05,93.02) 144.12,93.09 UC1.AB20 ; v2(144.91,86.44) 145.13,86.44 145.34,86.23 UC1.AP20 ; v2(37.04,100.43) 36.72,100.75 UV18.J2 ; UC1.AW4 154.16,82.41 UC1.AY4 154.21,81.96 v2(154.41,81.76) ; v2(147.76,106) 147.76,105.72 148.14,105.34 148.14,105.01 UC1.A14 148.11,104.78 148.23,104.66 148.23,103.8 UC1.C14 148.31,103.79 148.62,103.48 UC1.D14 UC1.D12 ; v2(140.31,85.77) 140.31,85.78 140.33,85.78 140.66,86.12 UC1.AP26 ; UV18.G1 38.21,101.59 v2(38.57,101.96) 38.98,101.55 UV17.F9 ; UC1.AH19 145.61,89.54 145.92,89.85 v2(146.04,89.85) 146.38,89.51 UC1.AH17 146.69,89.25 146.97,89.25 UC1.AH16 ; UC1.AE5 153.55,91.03 153.78,90.8 153.78,90.68 v2(153.81,90.65) ; v2(74.35,86.22) 73.96,86.61 UV1.P2 ; UV20.E1 v2(40.21,74.94) UV20.D1 ; UC1.Y63 117.07,94.06 v2(116.81,93.8) ; UC1.AP38 133.26,85.88 133.12,85.88 v2(133.07,85.83) 133.07,85.88 132.99,85.79 UC1.AR39 ; UC1.AR5 153.26,85.61 153.47,85.41 v2(153.74,85.41) ; UC1.G3 154.84,100.76 v2(154.48,100.4) ; v2(135.84,101.28) 135.85,101.28 UC1.F34 UC1.D34 ; UV1.U2 73.96,84.21 v2(73.56,84.61) ; UV19.T1 31.01,82.06 30.84,82.22 v2(30.64,82.22) ; v2(155.17,98.14) 155.17,98.13 154.85,97.8 UC1.N3 ; UC1.AL54 123.46,88.07 v2(123.14,87.74) ; v2(121.46,96.26) UC1.T58 120.76,96.29 120.11,96.94 UC1.P59 ; v2(156.6,99.42) 156.44,99.26 UC1.K1 ; v2(156.67,96.27) UC1.T1 ; UC1.AG21 144.18,89.35 v2(144.23,89.31) 144.23,89.26 144.47,89.51 UC1.AH20 ; UC1.AB22 143.53,92.87 143.95,92.45 143.95,92.43 v2(144.1,92.28) 144.1,92.26 144.45,91.9 UC1.AD21 ; UC1.AF12 149.27,90.6 UC1.AG11 ; UC1.AL22 143.36,88.07 143.04,87.75 v2(143.04,87.74) ; UC1.AT13 148.79,85.19 v2(149.11,85.19) 149.82,85.19 UC1.AR11 ; UC1.D18 145.63,103.61 UC1.C18 ; v2(118.51,98.93) 118.51,98.83 118.81,98.53 UC1.L61 ; UV18.E8 v2(40.21,95.55) ; UC1.AU55 UC1.AV55 122.59,83.62 v2(122.7,83.51) ; v2(130.83,101.28) 130.83,101.28 UC1.F42 UC1.D42 ; UC1.F58 120.66,101.76 120.66,101.33 v2(120.63,101.31) 121.05,100.89 UC1.H57 ; 135.7,83.35 136.01,83.66 UC1.AV34 ; 135.7,83.35 135.36,83.01 UC1.AW35 ; 135.7,83.35 v2(135.7,83.38) ; UC1.AR39 UC1.AP39 ; UC1.AR39 132.55,85.75 UC1.AT40 ; UC1.P62 UC1.P63 117.28,96.83 v2(116.87,96.83) ; UC1.AU51 124.99,84.8 123.98,84.8 UC1.AU53 123.81,84.9 124.38,85.47 UC1.AR52 124.44,85.59 124.44,86 UC1.AP52 124.39,86.28 124.39,86.61 UC1.AN52 ; UC1.AU51 UC1.AV51 ; UC1.AU51 125.26,84.74 UC1.AT49 126.18,84.78 126.18,85.27 UC1.AR49 126.49,85.47 v2(126.85,85.83) 126.9,85.83 127.19,86.12 UC1.AP48 UC1.AN48 ; UC1.AN52 124.26,86.77 123.93,87.1 123.93,87.1 v2(123.93,87.1) ; UC1.AN52 124.61,86.77 124.75,86.91 125.24,86.91 UC1.AN51 125.45,86.77 125.63,86.59 126.2,86.59 UC1.AN49 126.64,86.51 127.03,86.51 UC1.AN48 ; UC1.AU22 142.69,84.63 142.65,84.68 141.87,84.68 UC1.AU24 ; UC1.AW40 132.16,83.01 132.51,83.36 v2(132.59,83.36) 132.89,83.66 UC1.AV39 ; v2(156.09,40.37) 156.6,40.37 157.05,40.81 JDIMM1.196 ; v2(116.98,103.21) 117.18,103.01 UC1.D63 118.1,103.01 UC1.D62 ; v2(147.91,84.03) 148.28,83.66 UC1.AV14 ; v2(66.48,76.15) 66.48,76.7 UV1.AF11 UV1.AE11 ; v2(152.37,93.44) 152.37,93.44 152.2,93.27 UC1.AB7 ; UC1.D2 155.49,102.95 155.16,103.28 v2(155.16,103.31) ; UC1.A28 UC1.B28 ; v2(2.2,86.48) 2.21,86.46 2.21,85.78 2.54,85.45 JEDP.10 ; UC1.AN48 127.57,86.77 v2(127.85,87.04) 128.12,86.77 UC1.AN46 128.55,86.55 v2(128.81,86.55) 129.05,86.55 UC1.AN45 129.3,86.81 v2(129.77,86.81) 130.21,86.81 UC1.AN43 130.43,86.77 v2(130.7,86.49) 130.98,86.77 UC1.AN42 ; JNGFF.18 176.72,50.22 176.72,48.6 v2(176.56,48.44) ; UC1.AD63 116.85,91.81 v2(116.82,91.84) ; v2(119.81,94.43) 119.81,94.33 120.11,94.03 UC1.Y59 ; DI1.8 v2(195,49.2) ; UV1.B27 52.69,96.57 v2(52.44,96.32) ; UC1.AL20 145.15,88.07 v2(144.85,87.77) ; UC1.C18 145.65,103.8 145.65,104.87 UC1.A18 ; UC1.C18 145.22,103.79 v2(145.17,103.74) ; v2(156.62,93.31) 156.61,93.31 156.57,93.27 UC1.AA1 ; 142.52,88.72 UC1.AK23 ; 142.52,88.72 142.2,89.05 142.2,89.68 UC1.AH24 142.76,89.7 UC1.AJ23 143.03,89.43 143.16,89.29 143.54,89.29 ; 142.52,88.72 v2(142.2,88.39) 142.27,88.39 142.59,88.07 ; UC1.AV41 131.39,83.63 131.14,83.38 v2(130.98,83.38) 130.61,83.01 UC1.AW42 ; UC1.AW60 119.83,83.01 120.14,83.31 UC1.AW59 UC1.AV59 UC1.AU59 ; v2(132.47,89.93) 132.88,89.93 UC1.AH38 133.12,89.19 v2(133.05,89.12) 132.87,89.12 132.6,88.85 UC1.AL39 132.33,88.39 UC1.AL40 131.94,88.07 v2(131.62,88.39) ; v2(132.47,89.93) UC1.AJ39 ; v2(62.03,93.68) 61.58,94.12 UV1.E17 ; UC1.G22 143.56,101.22 143.79,101.45 143.95,101.45 v2(143.97,101.48) ; JDIMM2.196 169.05,28.87 169.05,30.81 v2(168.49,31.37) ; UV18.P9 32.61,95.16 v2(33.01,95.56) ; v2(36.2,96.29) 36.54,95.95 UV18.J8 ; JEDP.21 v2(4.37,90.95) ; 119.61,85.47 119.84,85.7 119.84,86.13 119.79,86.19 UC1.AN60 ; v2(64.42,97.78) 63.94,97.3 63.94,96.7 UV1.B14 ; v2(121.31,94.96) UC1.V58 ; v2(145.34,97.49) 145.27,97.56 UC1.N21 ; UC1.J59 120.11,100.13 v2(119.81,100.43) ; UC1.AR15 147.89,85.39 v2(147.53,85.39) 147.33,85.39 UC1.AR17 UC1.AP17 UC1.AN17 UC1.AM17 UC1.AL17 147.48,88.4 v2(147.5,88.43) 147.61,88.43 UC1.AJ14 148.05,88.72 UC1.AL13 148.56,88.63 148.79,88.86 UC1.AJ13 ; UC1.D12 149.39,103.19 149.39,102.77 149.31,102.69 149.39,102.69 149.72,102.37 UC1.E11 ; UC1.D12 149.79,103.58 UC1.C11 ; UV1.AF8 69.02,76.77 69.02,75.46 v2(69.11,75.37) ; UC1.D26 UC1.F26 v2(140.86,101.32) ; 143.54,89.29 v2(143.61,89.29) ; 143.54,89.29 143.61,89.36 143.61,89.76 UC1.AH22 ; UC1.AW50 125.98,83.15 125.98,83.15 126.17,83.34 v2(126.27,83.34) 126.33,83.4 126.42,83.4 126.67,83.65 UC1.AV49 ; UC1.AU16 UC1.AV16 UC1.AW16 146.92,82.72 UC1.AY16 ; UC1.AP10 150.55,86.26 v2(150.88,85.93) ; v2(137.81,88.87) 137.78,88.84 137.78,88.5 UC1.AL31 ; v2(155.15,94.39) 154.84,94.7 UC1.V3 ; v2(149.26,89.83) 149.62,90.2 UC1.AG11 ; UC1.D54 UC1.F54 123.31,101.28 v2(123.31,101.28) ; UC1.AF17 146.83,91.71 v2(146.28,92.26) 146.05,92.03 146.05,90.74 UC1.AF18 ; UC1.AM23 142.58,87.42 142.25,87.74 v2(142.2,87.74) 142.52,88.07 142.59,88.07 ; v2(125.81,101.28) 125.82,101.28 UC1.F50 UC1.D50 ; v2(143.97,99.29) 143.67,99.59 UC1.J22 ; DI4.8 v2(195,31.04) ; UC1.AL57 121.25,87.69 v2(121.21,87.69) ; v2(141.57,89.93) UC1.AJ25 ; UC1.A11 149.77,105.59 150.04,105.86 v2(150.04,106.48) ; UC1.Y10 150.09,93.89 149.81,94.16 v2(149.79,94.16) 149.79,93.55 150.41,92.93 UC1.AB10 ; UC1.AP3 154.84,85.79 155.14,85.49 v2(155.14,85.38) ; v2(4.37,92.79) 4.2,92.95 JEDP.25 ; JEDP.29 2.53,94.95 v2(2.2,95.28) ; v2(145.42,94.95) 145.44,94.95 145.47,94.92 145.47,95 145.19,94.72 UC1.W20 UC1.U20 ; v2(123.14,85.79) 123.21,85.79 UC1.AP54 ; UC1.AL31 137.98,88.39 138.1,88.51 138.48,88.51 138.78,88.21 UC1.AL29 ; UC1.AL31 137.79,88.31 137.79,87.83 UC1.AM31 UC1.AN31 ; UC1.C20 144.63,103.94 144.8,104.1 v2(144.8,104.44) 144.38,104.44 UC1.B20 ; v2(66.35,98) 66.63,97.72 66.63,96.65 UV1.B11 ; RP51.6 154.87,116.98 v2(155.12,117.22) 155.37,116.97 RP51.7 ; UC1.AW44 129.05,83.01 v2(129.4,83.36) 129.58,83.36 129.82,83.59 UC1.AV43 ; UC1.AH46 127.85,89.63 v2(127.85,89.09) ; UC1.AV34 136.44,83.33 UC1.AW33 UC1.AY33 ; UC1.AV34 136.44,83.98 UC1.AV33 136.74,84.63 UC1.AU33 136.69,84.66 136.33,85.01 136.33,85.38 UC1.AR33 136.41,85.5 136.19,85.73 v2(135.8,85.73) 135.81,85.72 135.81,84.87 UC1.AT35 135.64,84.7 135.16,84.7 135.12,84.66 134.93,84.66 134.9,84.69 134.6,84.69 134.52,84.77 UC1.AT37 133.37,84.77 133.3,84.7 ; UV18.M1 v2(34.61,101.95) ; v2(135.07,89.93) UC1.AJ35 ; v2(135.07,89.93) 135.48,89.93 UC1.AH34 135.72,90.08 136.07,90.43 136.63,90.43 v2(136.67,90.47) 137.02,90.13 UC1.AH32 ; v2(135.07,89.93) 134.65,89.93 UC1.AH36 ; v2(156.67,90.15) 156.55,90.27 UC1.AG1 ; v2(57.05,93.72) 57.46,94.14 UV1.E22 ; JEDP.7 2.48,83.95 2.11,83.58 v2(2.11,83.44) ; UC1.AE10 150.58,91.03 150.57,91.02 150.4,91.02 UC1.AF11 149.67,90.3 UC1.AG11 ; v2(58.68,94.52) 59.03,94.17 UV1.E20 ; v2(120.04,81.84) 120.04,81.85 120.08,81.88 120.08,82.33 UC1.AY59 ; UV1.B20 59.1,96.58 v2(59.53,97) ; v2(148.35,100.74) 148.43,100.74 148.75,100.42 UC1.H13 ; v2(150.96,83.97) 151.27,83.66 UC1.AV8 ; v2(152.9,81.75) 152.76,81.89 UC1.AY6 ; UC1.AW47 127.77,83.36 v2(127.82,83.36) 127.94,83.36 UC1.AV46 ; UV17.G8 v2(38.61,101.15) ; UC1.AE58 120.76,91.01 v2(120.43,90.67) 120.14,90.38 UC1.AG60 UC1.AG61 ; UC1.D46 UC1.F46 128.33,101.28 v2(128.32,101.28) ; UV19.B1 42.21,81.83 v2(42.57,82.2) 42.57,82.18 UV20.A9 ; JEDP.23 v2(4.35,91.95) ; UC1.AL46 128.53,88.07 v2(128.8,87.8) 129.07,88.07 UC1.AL45 ; v2(125.86,27.49) 125.85,27.5 125.85,28.87 JDIMM2.60 ; UC1.AN36 134.59,86.77 v2(134.92,86.44) 135.25,86.77 UC1.AN35 ; UC1.L15 UC1.L17 UC1.L18 145.77,98.84 145.34,98.42 v2(145.34,98.43) ; UC1.U22 143.43,95.53 UC1.V23 143.43,94.72 UC1.W22 ; UC1.U22 UC1.R22 ; UC1.U22 144.07,95.53 v2(144.1,95.56) ; v2(185.14,41.56) 185.14,41.53 184.98,41.7 JNGFF.43 ; 142.09,85.23 142.39,85.23 142.61,85.46 UC1.AR23 142.64,85.47 142.96,85.79 v2(143.03,85.79) 143.09,85.79 143.42,86.12 UC1.AP22 ; v2(138.4,85.77) 138.43,85.77 138.43,85.75 138.5,85.82 138.51,85.82 138.78,86.09 UC1.AP29 ; 142.59,88.07 UC1.AL23 ; v2(155.14,91.37) 155.14,91.48 154.84,91.78 UC1.AD3 ; UC1.U61 118.51,95.82 v2(118.51,95.93) ; UC1.AN31 137.64,87.09 UC1.AN32 137.19,86.77 136.88,87.07 v2(136.85,87.07) ; UC1.AG63 UC1.AG62 ; v2(33.05,82.16) 32.63,81.74 UV19.P1 ; v2(151.26,40.47) 151.65,40.85 JDIMM1.178 151.65,42.96 151.79,43.11 151.79,43.43 v2(151.16,44.06) ; v2(117.82,100.42) 117.51,100.11 UC1.J63 ; UV18.G9 v2(38.61,94.75) ; UC1.AU20 144.4,84.65 144.79,84.65 144.89,84.75 145.08,84.75 145.16,84.67 145.19,84.67 145.22,84.63 UC1.AU18 ; UC1.AW37 133.87,83.01 v2(134.17,83.31) 134.52,83.66 UC1.AV36 ; UC1.AT42 130.98,85.03 v2(130.76,85.24) 130.54,85.47 UC1.AR43 129.89,85.12 v2(129.72,85.12) 129.4,84.8 UC1.AT43 ; UV19.M1 v2(34.61,82.14) ; v2(65.05,91.37) 65.06,91.36 UV1.K13 ; v2(147.32,102.03) 146.99,102.37 UC1.E17 ; UC1.AP39 UC1.AN39 132.33,87.09 UC1.AN40 132.33,86.44 UC1.AP39 ; UC1.G5 153.54,101.1 153.22,101.42 v2(153.06,101.42) ; UV19.J2 v2(37.01,81.34) ; v2(118.63,87.78) 118.66,87.82 UC1.AL61 UC1.AL60 ; UV18.P1 v2(33.01,101.95) ; UC1.V7 152.38,95.02 v2(152.38,95.31) ; v2(56.57,30.38) 56.32,30.63 PR108.2 ; JDIMM1.150 143.25,41.84 143.25,43.06 143.03,43.28 143.03,43.55 142.53,44.06 v2(142.48,44.06) ; UC1.J10 150.63,99.77 v2(150.3,100.1) ; UC1.AH30 138.55,89.93 v2(138.97,89.93) UC1.AJ29 139.29,89.37 UC1.AH28 139.94,89.37 UC1.AJ27 140.22,89.33 v2(140.22,88.42) 140.58,88.07 UC1.AL26 ; v2(149.25,98.43) 149.19,98.43 UC1.L13 149.22,99.29 UC1.K12 ; UC1.AL10 150.69,88 150.72,88 150.74,88.02 v2(150.88,87.88) ; UC1.AN23 142.61,86.84 142.44,87.01 v2(142.18,87.01) 142.18,86.52 142.58,86.12 UC1.AP23 ; v2(144.05,97.15) 143.53,97.15 UC1.P22 UC1.M22 ; JEDP.32 v2(4.39,96.45) ; UV19.T9 v2(30.61,74.94) ; DI1.3 v2(198,49.2) ; UC1.F20 144.97,101.78 144.62,102.12 v2(144.51,102.12) ; UV19.G1 38.23,81.74 v2(38.61,82.13) 39,81.74 UV20.F9 ; UC1.AM1 156.58,87.28 v2(156.77,87.08) ; UV19.J8 v2(36.21,76.54) ; UC1.AL33 136.15,88.07 v2(135.81,88.41) ; v2(152.46,99.29) 152.2,99.04 UC1.L7 ; UC1.AL51 125.34,88.07 v2(124.99,88.41) ; UC1.N10 150.63,97.66 150.22,97.66 148.98,96.42 v2(148.98,96.04) 149.51,96.04 150.21,96.74 UC1.R10 ; UC1.AL52 124.32,88.07 123.96,87.71 123.96,87.73 v2(123.96,87.73) 123.96,87.73 124.16,87.53 124.45,87.53 UC1.AM52 ; UC1.AL36 134.47,88.07 v2(134.16,87.76) ; v2(121.31,98.86) UC1.L58 ; v2(4.28,97.84) 4.28,97.84 4.18,97.94 3.28,97.94 JEDP.35 ; UC1.AF14 148.46,91.67 v2(147.95,92.18) 147.64,91.87 UC1.AF15 ; UV19.E8 v2(40.21,75.74) ; UV19.P9 v2(32.21,74.94) ; v2(142.49,90.21) 142.99,90.21 UC1.AG23 ; UC1.B4 154.45,104.11 154.45,103.31 154.09,103.31 154.09,103.31 153.68,103.31 153.51,103.14 UC1.D5 ; UV1.B17 61.98,96.17 v2(61.98,96.17) ; JEDP.26 v2(4.36,93.45) ; UC1.B24 UC1.A24 ; v2(121.31,93.66) UC1.AA58 ; UV19.G9 v2(38.61,74.94) ; UV20.G8 v2(38.61,81.34) ; PU600.22 49.98,46.77 v4(49.73,47.02)
  BOTTOM w0.305: UV1.L2 74.49,89.15 v2(74.55,89.08) ; v2(71.12,84.64) 71.56,84.2 UV1.U5 ; UV1.AB24 55.74,80.07 v2(55.34,79.67) ; UV1.P26 53.6,86.67 v2(53.59,86.68) ; UV1.M13 65.23,88.67 v2(65.59,89.03) ; UV1.M13 64.92,88.67 v2(64.52,89.07) 64.06,89.52 UV1.L14 ; UV1.M13 64.57,88.18 v2(64.34,88.18) 64.06,87.9 UV1.N14 64.08,87.67 v2(64.57,87.18) 65.06,86.68 UV1.P13 65.06,86.52 v2(64.75,86.2) 64.6,86.2 UV1.R14 64.53,85.2 v2(64.75,85.2) 65.06,84.88 UV1.T13 ; v2(62.89,91.26) 63.06,91.1 UV1.K15 ; v2(168.84,38.61) 168.75,38.52 JDIMM2.195 ; JNGFF.67 190.97,42.68 190.97,43.78 v2(191.09,43.89) ; JNGFF.61 189.48,44.08 189.51,44.12 v2(189.44,44.12) ; v2(54.57,83.77) 54.16,84.17 UV1.U26 ; UV1.H5 71.56,91.58 v2(71.15,91.16) ; v2(66.63,85.27) 66.24,85.67 UV1.R12 ; v2(56.19,76.38) 56.58,76.77 UV1.AF23 ; UV1.V15 63.06,82.68 v2(62.57,83.17) 62.56,83.17 UV1.U16 ; UV1.AB14 64.01,80.01 v2(63.63,79.63) ; 114.5,43.49 113.85,42.84 113.85,41.84 JDIMM1.60 ; UV1.AE17 UV1.AF17 61.58,75.61 v2(61.7,75.49) ; UV1.Y23 56.14,81.29 v2(56.14,81.23) ; v2(75.23,96.94) 74.86,96.57 UV1.B1 ; UV1.B23 56.53,96.57 v2(56.11,96.99) ; UV1.P15 63.06,86.7 v2(62.67,87.1) 62.1,87.67 UV1.N16 62.61,88.22 v2(62.69,88.22) 63.06,88.59 UV1.M15 63.06,88.73 v2(62.69,89.11) 62.13,89.67 UV1.L16 ; v2(55.38,92.06) 54.96,91.64 UV1.H25 ; UV1.N18 60.06,87.55 v2(60.55,87.07) 60.95,86.67 UV1.P17 ; v2(54.56,76.35) 54.18,75.97 UV1.AG26 ; UV1.AC26 54.14,79.22 v2(53.71,78.79) ; UV1.Y2 73.99,81.71 v2(74.38,82.1) ; v2(183.54,44.22) 183.48,44.16 JNGFF.37 ; UV1.Y5 71.57,81.71 v2(71.99,82.13) ; UV1.B8 69.02,97.24 v2(69,97.27) ; UV1.H23 56.6,91.63 v2(57.02,91.21) ; UV1.P23 56.59,86.67 v2(57.05,86.21) ; UV1.AF1 74.74,76.77 v2(74.35,76.38) 73.96,75.99 UV1.AG2 ; v2(53.65,97.9) 54.16,97.38 UV1.A26 ; v2(182.04,43.87) 181.98,43.8 JNGFF.31 ; v2(71.93,78.8) 71.51,79.22 UV1.AC5 ; v2(71.91,94.5) 71.53,94.12 UV1.E5 ; v2(64.06,76.05) 64.06,76.05 UV1.AF14 UV1.AE14 ; UV1.E25 54.96,94.14 v2(55.36,94.54) ; UV1.N10 67.97,87.67 v2(67.47,88.18) 67.06,88.58 UV1.M11 ; JNGFF.55 187.97,42.68 v2(187.97,43.89) ; v2(71.1,86.24) 71.53,86.67 UV1.P5 ; v2(145.34,98.43) 144.99,98.78 UC1.L20 ; UV1.AC2 73.96,79.17 v2(74.33,78.8) ; UV1.L12 66.08,89.67 v2(66.54,89.21) ; v2(59.44,84.76) 59.44,85.04 UV1.R18 ; UV1.AD12 65.7,78.35 v2(65.31,77.95) 64.9,78.36 UV1.AD13 ; v2(53.75,81.31) 54.15,81.71 UV1.Y26 ; UV1.U16 62.57,84.18 v2(62.77,84.18) 63.06,84.47 UV1.T15 63.06,84.68 v2(62.57,85.18) 62.56,85.18 UV1.R16 61.91,85.67 v2(61.52,85.28) 61.06,84.82 UV1.T17 ; UV1.U16 61.66,83.26 v2(61.55,83.26) 61.55,83.15 UV1.V17 61.06,82.68 v2(60.57,83.17) 60.08,83.67 UV1.U18 ; UV1.AD15 63.22,78.36 v2(62.82,77.95) ; UV1.U10 68.06,83.68 v2(67.57,84.18) 67.08,84.67 UV1.T11 ; UV1.AB17 61.56,80.01 v2(61.13,79.58) ; UV1.AD22 UV1.AD21 58.29,78.37 v2(58.69,77.97) 59.09,77.57 UV1.AE20 UV1.AF20 v2(59.1,75.4) ; UV1.AB11 66.53,80.01 v2(66.13,80.41) ; v2(186.54,43.95) 186.48,43.88 JNGFF.49 ; v2(56.99,89.56) 56.57,89.15 UV1.L23 ; v2(61.98,77.95) 62.39,78.37 UV1.AD16 ; v2(56.17,83.79) 56.17,83.8 56.56,84.19 UV1.U23 ; UV1.V13 65.06,82.7 v2(64.59,83.17) 64.1,83.67 UV1.U14 ; UV1.L25 54.96,89.17 v2(55.37,89.58) ; v2(74.46,91.31) 74.14,91.63 UV1.H2 ; UV1.K17 60.85,90.67 v2(60.41,90.22) 60.06,89.88 UV1.L18 60.06,89.62 v2(60.63,89.05) 61.02,88.67 UV1.M17 ; UV1.A2 74.22,97.37 v2(74.53,97.68) ; JDIMM2.2 108.45,28.03 109.15,27.33 v2(109.17,27.33) ; UV1.AB7 69.85,80.01 v2(69.44,79.59) 69.02,79.18 UV1.AC8 ; v2(68.64,93.73) 69.02,94.12 UV1.E8 ; UV1.E11 66.56,94.17 v2(66.97,94.57) ; UV1.L5 71.95,88.76 71.96,88.76 v2(71.96,88.75) ; UV1.U12 66.08,83.67 v2(66.57,83.17) 67.06,82.68 UV1.V11 ; UV1.AC22 v2(57,79.63) ; UV1.E14 64.06,94.16 v2(63.62,93.72) ; v2(156.09,38.53) 156.54,38.53 156.75,38.33 JDIMM2.155 ; UV1.AD18 60.73,78.37 v2(60.33,77.97) 59.94,78.35 UV1.AD19 ; JNGFF.7 173.97,42.67 173.97,41.68 v2(174.12,41.53) ; UV1.R10 68.06,85.86 v2(67.72,86.2) 67.53,86.2 UV1.P11 66.68,87.05 v2(66.48,87.05) 66.48,87.26 UV1.N12 ; UV1.AB20 59.07,80.01 v2(58.68,79.62) ; JDIMM2.38 119.24,28.87 119.24,27.7 118.88,27.34 v2(118.02,27.34) ; UV1.K11 67.26,90.67 v2(67.61,90.32) 68.06,89.87 UV1.L10 68.48,89.25 v2(68.48,89.08) ; v2(69.89,81.54) 69.86,81.51 UV1.AA7 ; v2(180.54,43.84) 180.48,43.78 JNGFF.25
  BOTTOM w0.356: 165.32,38.53 164.28,38.53 163.95,38.2 JDIMM2.179 ; 165.32,38.53 165.75,38.1 JDIMM2.185 ; 165.32,38.53 v2(165.36,38.53) ; JDIMM2.153 156.15,38.47 v2(156.09,38.53) ; v2(100.19,46.15) 99.15,47.19 JDIMM1.11 ; JDIMM2.187 166.35,38.29 v2(166.61,38.56) 166.95,38.22 JDIMM2.189 ; JDIMM1.150 143.25,40.58 142.49,39.83 142.07,39.83 v2(142.02,39.78) ; JDIMM2.48 122.25,27.4 v2(122.28,27.37) ; JDIMM1.184 153.45,40.51 153.47,40.49 153.47,40.49 153.42,40.44 v2(153.39,40.44) ; JDIMM1.127 136.35,51.52 136.63,51.8 137.88,51.8 138.15,51.53 JDIMM1.133 138.15,47.6 138.36,47.39 v2(138.56,47.39) ; JDIMM2.61 126.15,38.4 v2(126.07,38.48) 126.51,38.48 126.75,38.24 JDIMM2.63 ; JDIMM2.3 108.75,38.22 109.13,38.6 109.19,38.6 109.25,38.66 ; v2(97.02,47.67) 96.63,47.67 96.2,48.1 96.2,48.61 96.75,49.16 JDIMM1.3 ; v2(117.14,44.31) 117.82,43.71 117.82,43.28 117.45,42.9 JDIMM1.72 ; v2(152.86,46.31) 153.27,46.31 154.35,47.38 JDIMM1.187 154.35,51.1 154.14,51.3 153.91,51.3 153.74,51.13 153.74,50.04 JDIMM1.185 ; v2(153.39,38.52) 153.47,38.52 153.75,38.24 JDIMM2.145 ; JDIMM2.20 113.85,27.71 114.1,27.46 115.57,27.46 v2(115.65,27.38) JDIMM2.26 ; JDIMM1.13 99.75,51.58 99.74,51.59 ; JDIMM2.19 113.55,38.24 113.97,38.66 v2(114.38,38.66) 114.94,38.66 115.35,38.25 115.35,37.07 JDIMM2.25 ; JDIMM1.26 v2(103.65,43.61) 104.06,43.61 104.25,43.42 JDIMM1.28 ; JDIMM1.25 103.35,48.24 v2(103.53,48.05) ; v2(98.35,44.05) 98.25,43.94 JDIMM1.8 ; v2(115.83,40.34) 115.65,40.52 JDIMM1.66 ; JDIMM1.155 144.75,51.63 v2(144.58,51.79) 144.15,51.36 JDIMM1.153 144.15,48.42 145.48,47.08 v2(145.55,47.08) ; JDIMM1.54 112.05,40.88 v2(111.43,40.26) ; v2(111.61,27.41) 111.61,27.49 112.05,27.92 JDIMM2.14 ; v2(117.89,39.12) 117.15,38.38 117.15,37.07 JDIMM2.31 ; JDIMM2.13 111.75,38.28 111.44,38.59 v2(111.39,38.59) 111.15,38.35 JDIMM2.11 ; v2(155.3,33.18) 155.55,33.44 JDIMM2.151 155.55,38.14 155.21,38.48 v2(155.08,38.48) ; JDIMM1.38 107.25,40.55 v2(107.07,40.37) ; v2(98.29,46.53) 98.55,46.81 JDIMM1.9 ; v2(148.66,45.56) 147.86,45.56 146.55,46.87 JDIMM1.161 146.55,51.2 146.86,51.51 148.05,51.51 148.35,51.21 JDIMM1.167 148.35,48.74 v2(148.54,48.54) ; JDIMM1.189 154.95,51.19 155.27,51.51 v2(156.14,51.51) 156.42,51.51 156.75,51.18 JDIMM1.195 156.75,48.8 156.95,48.6 v2(156.95,48.49) ; JDIMM2.144 153.45,27.21 153.13,26.89 v2(153.13,26.89) ; v2(161.25,32.4) 161.2,32.4 160.65,31.86 JDIMM2.168 ; v2(129.57,27.43) 129.45,27.55 JDIMM2.72 ; JDIMM2.37 118.95,38.09 v2(118.65,38.39) ; v2(123.75,38.51) 123.8,38.46 124.07,38.46 124.35,38.19 JDIMM2.55 ; JDIMM2.150 155.25,28.87 155.25,30.82 v2(155.3,30.87) ; JDIMM1.162 146.85,44.84 146.13,45.56 v2(145.55,45.56) ; JDIMM1.37 106.95,46.21 107.11,46.04 v2(107.85,46.04) ; JDIMM2.8 110.25,29.96 v2(110.65,30.36) ; JDIMM2.32 117.45,27.9 v2(118.02,27.34) ; JDIMM1.65 115.35,51.31 115.85,51.81 116.79,51.81 117.15,51.46 JDIMM1.71 117.15,49.09 117.77,48.46 117.77,47.99 v2(117.14,47.36) ; v2(140.49,48.52) 139.95,49.06 139.95,50.04 JDIMM1.139 ; v2(140.01,40.47) 139.65,40.83 JDIMM1.138 ; v2(129.02,38.46) 129.15,38.34 JDIMM2.71 ; v2(140.47,44.06) 140.79,44.06 141.45,43.4 JDIMM1.144 141.45,40.63 141.66,40.41 v2(142.02,40.41) ; v2(108.93,51.42) 108.75,51.23 JDIMM1.43 ; v2(123.65,27.31) 123.65,27.51 124.05,27.91 JDIMM2.54 ; 109.25,38.66 109.28,38.63 110.1,38.63 110.55,38.18 JDIMM2.9 110.55,33.53 110.65,33.44 v2(110.65,33.31) ; 109.25,38.66 v2(109.43,38.66) ; JDIMM1.170 149.25,44.5 149.82,44.8 v2(149.94,44.8) ; JDIMM2.46 121.65,27.86 v2(121.05,27.26) JDIMM2.44 ; JDIMM2.65 127.35,35.38 128.42,34.31 v2(129.22,34.31) ; JDIMM1.60 113.85,40.59 113.62,40.36 113.42,40.36 v2(113.39,40.34) ; v2(100.31,40.39) 100.05,40.65 JDIMM1.14 ; v2(155.07,40.39) 155.09,40.39 155.25,40.54 JDIMM1.190 155.25,43.15 154.79,43.6 v2(154.74,43.6) ; JDIMM2.162 158.85,27.49 v2(158.91,27.43) ; v2(121.89,34.69) 120.75,35.83 JDIMM2.43 120.75,38.23 120.96,38.44 v2(121.25,38.44) 121.93,38.44 121.95,38.41 122.37,38.41 122.55,38.23 JDIMM2.49 ; JDIMM1.136 139.05,44.21 140.43,45.58 v2(140.47,45.58) ; v2(105.47,40.29) 105.45,40.31 JDIMM1.32 ; JDIMM2.184 165.45,27.48 v2(165.36,27.38) ; JDIMM2.156 v2(157.05,27.51) ; JDIMM1.31 105.15,51.6 105.15,51.6 ; JDIMM1.156 145.05,40.44 144.99,40.38 144.99,40.36 v2(144.91,40.29) ; v2(111.32,47.36) 110.74,47.87 110.74,48.37 110.55,48.57 JDIMM1.49 110.55,51.6 110.56,51.62 ; JDIMM2.170 161.25,30.55 v2(161.25,30.55) 161.85,29.95 JDIMM2.172 ; JDIMM1.61 114.15,51.18 v2(114.56,51.59) 114.75,51.41 JDIMM1.63 ; JNGFF.1 172.48,44.12 172.41,44.19 172.39,44.19 172.39,45.27 v2(172.33,45.33) ; v2(138.56,45.1) 138.43,44.97 138.43,41.85 JDIMM1.134 ; JDIMM1.173 150.15,51.07 150.47,51.4 v2(151.19,51.4) 151.62,51.4 151.95,51.07 JDIMM1.179 ; JDIMM2.167 160.35,38.17 v2(160.8,38.62) 160.84,38.66 161.73,38.66 162.15,38.23 JDIMM2.173 ; v2(102.02,40.43) 101.85,40.61 JDIMM1.20 101.85,43.99 v2(102.48,44.62) ; v2(166.56,30.99) 167.25,30.3 JDIMM2.190 ; JDIMM2.66 v2(127.65,27.5) ; JDIMM2.178 163.65,30.36 v2(162.75,31.26) ; JDIMM1.2 96.45,42.78 v2(96.12,43.11) ; JDIMM2.139 151.95,38.19 151.66,38.48 v2(151.24,38.48) 151.23,38.47 150.35,38.47 150.15,38.27 JDIMM2.133 ; v2(136.68,40.46) 136.68,40.55 136.65,40.59 JDIMM1.128 ; JDIMM2.161 158.55,34.93 159.17,34.31 v2(159.5,34.31) ; JDIMM1.172 149.85,40.63 149.65,40.43 148.35,40.43 v2(148.29,40.49) 148.65,40.85 JDIMM1.168 ; v2(113.45,47.36) 112.35,48.35 JDIMM1.55 112.35,51.39 ; v2(149.27,27.07) 149.27,27.27 148.65,27.89 148.65,28.87 JDIMM2.128 ; v2(150.28,32.4) 150.45,32.23 JDIMM2.134 ; JDIMM1.145 141.75,51.35 141.99,51.6 v2(142.48,51.6) 143.41,51.6 143.55,51.46 JDIMM1.151 ; JDIMM1.44 109.05,40.74 v2(109.25,40.54) 109.31,40.48 110,40.48 110.25,40.73 JDIMM1.48 110.25,43.35 v2(111.32,44.31) ; 101.55,51.25 JDIMM1.19 ; v2(109.63,43.36) 109.65,43.34 JDIMM1.46 ; JDIMM2.136 151.05,27.37 v2(151.34,27.08) 151.65,27.39 JDIMM2.138 ; JDIMM2.28 v2(116.25,30.55) ; v2(114.96,43.93) 114.5,43.49 ; JDIMM2.127 148.35,38.37 v2(148.26,38.46)
  BOTTOM w0.381: UV20.D8 v2(40.21,81.34) 39.81,80.94 UV19.E2 ; UV18.B9 42.21,95.12 42.6,94.73 v2(42.6,94.7) ; v2(56.33,24.75) 57.84,24.75 PD101.1 ; UV18.T1 30.64,101.55 v2(30.31,101.88) ; UV20.B3 42.21,77.32 v2(42.41,77.52) ; UV17.B3 42.21,97.28 v2(42.28,97.35) ; v2(83.52,99.49) 83.52,100.03 CV142.1 CV141.2 ; UV5.3 194.19,114.05 194,113.86 CV358.2 ; UV18.B1 42.21,101.58 v2(42.66,102.03) 43.01,101.69 UV17.A9 ; v2(42.47,74.82) 42.21,75.08 UV19.B9 ; UV3.3 v2(198.49,110.56) ; UV18.E2 39.81,100.75 v2(40.21,101.15) UV17.D8 ; CV139.2 CV140.2 ; CX28.2 v2(199.65,70.31) ; RC66.2 116.64,110.75 116.74,110.85 v2(116.74,111.15) ; v2(200.33,61.55) CX25.2
  BOTTOM w0.406: D1.2 11.74,76.95 v2(11.17,77.52)
  BOTTOM w0.508: RC133.1 147.38,109.35 v2(147.73,109.7) ; DI5.1 v2(198.05,27.23) ; JNGFF.68 171.38,44.88 171.82,45.33 v2(172.33,45.33) ; C2327.2 167.12,93.08 v2(166.81,93.4) ; JRTC.3 78.8,47.64 v2(78.46,47.98) ; PC17.2 v2(14.53,42.98) ; CX29.2 v2(200.59,69.01) ; RC89.2 159.95,112.19 v2(159.82,112.32) ; v4(47.35,32.49) 47.35,31.45 46.56,30.66 46.56,29.49 v4(46.54,29.47) ; PR106.2 55.96,25.12 v2(56.33,24.75) ; RV108.2 74.17,72.47 74.17,71.73 v2(74.25,71.66) ; JDIMM1.205 157.84,57.94 156.85,56.95 v2(154.21,56.95) ; JIO.17 22.7,45.31 v2(22.98,45.58) ; v2(127.94,112.96) R2523.2 R2524.2 ; v2(187.52,114.48) R2495.2 ; C5212.2 v2(104.07,94.8) ; YV3.2 179.11,113.16 v2(178.77,112.83) ; v2(190.38,114.47) 190.38,114.05 CV343.2 ; CV59.2 203.46,116.51 203.88,116.51 v2(204.08,116.31) ; v2(181.61,92.46) 181.61,92.9 181.8,93.09 CL37.1 181.82,93.31 182.14,93.63 YL2.2 ; v2(168.43,66.8) 168.36,66.73 RC2.2 ; v2(8.12,101.27) 7.61,101.27 7.17,100.84 JEDP.44 ; CV42.2 30.66,106.42 v2(30.92,106.67) ; JDEG.11 v2(72.85,18.37) ; CV180.2 38.03,71.1 38.31,71.38 38.31,72.65 v2(38.38,72.72) ; RV157.1 77.88,96.45 77.78,96.55 v2(76.7,96.55) ; v2(79.24,106.23) 78.95,106.52 YV1.2 ; JDEG.10 v2(71.85,15.35) ; v2(181.18,109.09) CV354.2 ; JHDD.8 181.65,20.15 v2(180.09,18.6) ; v2(72.7,15.29) 72.85,15.14 JLPDE.12 ; v2(66.84,100.17) 66.76,100.26 66.76,100.92 67.33,101.49 RV514.2 RV515.2 ; U2302.4 170.49,108.77 v2(170.3,108.57) ; CX24.2 199.67,67.03 CX27.2 v2(198.84,67.01) ; v2(195.51,109.93) 195.07,109.49 RV160.2 ; v2(22.53,120.96) 22.92,120.58 PC5.2 ; CL25.2 180.22,93.39 v2(180.52,93.08) ; CV352.2 CV355.2 185.04,101.64 v2(185.04,101.16) ; DI2.1 v2(194.75,46.43) ; v2(102.91,123.06) 102.4,122.55 PC300.2 PR301.2 ; PC622.2 47.11,52.08 v4(46.69,52.08) ; CV210.2 v2(30.28,70.41) ; v2(197.67,106.48) 196.52,105.34 195.25,105.34 194.99,105.07 CV338.2 CV339.2 ; JEDP.45 v2(3.05,102.85) ; v2(35.32,19.26) 35.34,19.27 PC748.1 37.61,19.27 v2(37.62,19.26) ; v2(183.23,92.17) CL36.1 RL31.1 CL15.2 ; v2(148.42,111.79) 149.45,111.79 C59.2 ; v2(210.24,2.72) 210.29,2.68 JSPK.5 ; JLPDE.9 71.35,14.67 71.11,14.91 v2(71.11,15.23) ; v2(192.71,38.79) 193.48,38.03 CI1.2 ; v2(180.52,92.42) 180.22,92.42 180.14,92.5 CL24.2 CL42.2 ; JDEG.13 v2(66.35,20.79) ; C58.2 144.91,108.87 v2(144.91,109.45) ; PC313.2 93.73,119.87 v2(93.48,119.62) ; v2(183.72,110.9) 183.72,111.37 CV345.2 ; RV25.2 56.32,72.77 v2(56.32,74.73) ; v2(170.8,81.27) 170.99,81.08 SW3.5 ; v2(178.43,28.65) 178.66,28.88 179.02,28.88 CA21.2 ; CV50.2 203.38,113.85 v2(203.64,114.1) ; RV126.1 RV99.1 77.65,98.48 v2(77.53,98.61) ; CV197.2 40.52,71.1 39.98,71.63 ; v2(184.4,101.15) 184.28,101.26 CV351.2 ; CS7.2 182.22,29.19 v2(182.07,29.34) ; JLPDE.11 v2(72.85,12.08) ; v2(77.63,95.48) 77.65,95.46 78.31,95.46 RV127.1 ; v2(72.69,102.38) 72.7,102.36 RV92.2 ; v2(189.11,27.99) CS5.2 CS6.2 ; RV148.2 34.93,105.92 v2(35.46,105.39) 35.79,105.06 36.15,105.06 CV334.2 RV112.2 ; v2(115.19,111.03) 115.12,111.1 114.41,111.1 113.85,110.54 CC28.2 ; v2(199.65,64.9) CX26.2 200.44,64.24 CX23.2 ; CC31.2 171.06,84.13 v2(170.62,83.68) ; CV184.2 v2(43.24,106.73) ; CV170.2 v2(31.55,70.41) ; CV172.2 v2(38.28,106.73) ; JDIMM2.205 108.68,20.97 109.4,20.25 v2(110.16,20.25) ; v2(24.31,64.73) JIO.18 21.1,64.73 v2(20.82,64.44) ; C7.2 v2(10.47,77.52) ; RC66.2 CC27.2 ; v2(181.16,25.57) 180.51,26.22 CC5.2 ; v2(194.26,106.62) CV360.2 ; v2(180.71,111.05) 180.5,111.27 CV344.1 ; YV3.4 v2(184.11,114.76) ; CA25.1 192.31,20.47 191.23,19.4 JHDD.11 188.54,18.3 v2(188.4,18.15) ; JEDP.41 v2(7.31,78.55) ; CV326.2 32.87,104.75 v2(32.41,104.29) ; YV1.4 75.02,104.92 74.86,105.08 CV34.2 73.84,104.75 v2(73.84,104.4) ; DA10.1 195.85,20.2 196.4,20.74 196.4,21.36 196.64,21.6 ; PR401.2 169.14,115.67 169.6,116.13 PC404.2 168.77,116.68 v2(168.46,116.99) ; JRTC.2 81.35,48.57 80.89,48.11 80.07,48.11 79.42,48.76 v2(78.46,48.76) ; CV36.2 86.77,103.47 v2(86.77,102.52) ; v2(95.89,121.74) 95.89,122.07 PC312.2 ; CV35.2 79.05,103.62 79.43,104 v2(79.43,105.34) ; CC7.1 v2(137.93,112.07) 137.93,115.24 137.62,115.55 133.82,115.55 133.46,115.19 v2(133.46,112.15) CC6.1 ; CV353.2 181.86,104.7 v2(181.31,104.7) ; JDEG.12 v2(72.85,20.87) ; PU400.1 172.36,114.29 172.75,113.9 v2(172.75,112.96) ; PH500.1 60.59,122.55 v2(60.59,121.72) ; 1.71,70.06 v2(2.95,70.06) ; v2(39.98,72.75) 39.98,71.63 ; 39.98,71.63 39.45,71.1 CV209.2 ; v2(4.69,73.4) 4.56,73.53 JFAN.4 ; JDEG.14 v2(65.53,16.66) ; JFAN.6 v2(11.16,67.87) ; CV131.2 v2(39.93,106.73) ; PC402.2 PR403.2 179.33,116.08 v2(179.7,116.45) ; v2(171.51,87.75) 171.7,87.75 172.2,87.24 C2326.2 ; v2(185.38,113.43) 185.55,113.59 CV340.2 184.75,114.1 CV357.2 ; v2(84,105.98) 83.42,105.4 CV139.2 ; JSPK.6 202.3,3.88 200.51,5.67 v2(200.51,6.07) ; UV4.2 v2(202.17,113.15) ; JHDD.12 178.48,19.66 v2(177.77,19.66) ; v2(203.38,108.38) CV58.2 ; JIO.13 v2(24.57,58.9) ; SW3.4 v2(180.14,80.38) ; v2(100.77,122.94) 100.77,122.58 100.48,122.3 PR306.2 ; v2(95.56,60.89) 95,60.32 JDIMM1.206 ; v2(77.32,94.31) 77.37,94.26 78.24,94.26 RV41.1 ; v2(34.68,70.09) CV158.2 ; v4(44.35,46.12) PC600.2 ; v2(29.77,86.46) 29.42,86.11 RV156.2 ; CA26.2 104.09,99.44 v2(104.22,99.32) ; JIO.16 24.69,61.9 v2(24.44,61.65) ; DE3.1 v2(11.38,54.26) ; v2(103.59,88.52) 104.27,89.21 RC135.2 ; v2(83.45,53.72) 85.83,53.72 86.22,53.32 CC26.2 ; RV110.2 31.73,105.97 CV187.2 31.68,106.35 31.55,106.48 v2(31.55,106.8) ; RV169.2 197.71,111.57 198.07,111.2 v2(198.48,111.2) ; JRTC.4 v2(85.15,44.13) ; v2(7.99,83.43) 7.55,83.43 7.17,83.06 JEDP.42 ; JIO.9 v2(24.73,54.9) ; YL2.4 v2(184.34,97.14) ; CV204.2 v2(28.2,71.1) ; PC210.2 56.95,27.38 PR204.2 56.94,27.1 v2(57.45,26.6) ; RL30.2 175.39,88.71 175.1,89 v2(174.62,89) ; JIO.10 v2(24.66,55.9) ; v2(191.96,114.47) CV336.2 ; JIO.8 v2(24.69,53.9) ; JLPDE.14 66.35,11.86 v2(66.1,12.12) ; v2(19,19.75) 19,20.14 PD1.1 ; CI8.2 191.04,25.58 v2(191.47,25.15) ; v2(184.84,19.8) 184.46,19.8 184.05,20.22 JHDD.5 ; CV143.2 v2(41.58,106.73) ; PR615.2 v2(54.56,47.26) ; CV358.2 v2(192.85,114.48) ; CMOS1.1 153.5,55.3 v2(154.23,56.03) ; PC208.2 71.02,38.11 v2(71.05,38.09) ; v2(7.93,92.51) 7.17,91.75 JEDP.43 ; PC204.1 v2(56.12,37.12) ; v2(191.09,43.89) 191.37,43.89 191.81,43.45 JNGFF.69 ; PC105.2 51.1,27.85 v4(51.38,28.13) ; JLPDE.13 v2(66.35,15.1) ; PR307.2 v2(92.23,122.99) ; CX30.2 v2(199.83,72.39)
  vias: v2(0.54,108.13) v2(0.51,105.59) v2(0.51,103.05) v2(0.54,99.62) v2(0.54,92) v2(0.54,84.38) v2(0.54,76.76) v2(0.54,69.14) v2(0.51,54.54) v2(1.78,109.91) v2(1.99,63.05) v2(2.66,50.15) v2(4.14,107.93) v2(4.22,105.26) v2(4.5,110.24) v2(7.1,110.24) v2(9.53,123.36) v2(9.5,120.83) v2(9.5,118.29) v2(9.5,115.75) v2(9.5,113.21) v2(9.48,110.26) v2(9.97,49.08) v2(10.69,120.45) v2(10.69,118.16) v2(10.69,116) v2(11.08,101.49) v2(11.07,99.23) v2(11.05,96.92) v2(11.41,100.94) v2(11.38,48.44) v2(11.5,98.59) v2(11.47,93.55) v2(11.47,92.92) v2(12.07,124.64) v2(12.07,93.56) v2(12.07,92.93) v2(12.5,120.45) v2(12.5,118.16) v2(12.5,116) v2(12.65,93.58) v2(12.65,92.94) v2(12.81,39.55) v2(13.11,8.99) v2(13.54,87.42) v2(13.72,89.23) v2(14.61,124.64) v2(14.6,93.83) v2(15.1,95.34) v2(16.44,85.42) v2(17.15,124.64) v2(18.88,12.33) v2(19.61,14.72) v2(19.69,124.64) v2(19.84,83) v2(19.8,79.05) v2(19.8,24.25) v2(19.85,10.57) v2(21.65,8.97) v2(21.89,15.69) v2(22.1,84.06) v2(22.06,77.89) v2(22.52,123.23) v2(23.96,10.8) v2(24.38,79.19) v2(24.71,82.76) v2(24.71,13.29) v2(25.53,123.22) v2(26.03,119.76) v2(27.8,124.59) v2(27.88,119.06) v2(29.14,11.25) v2(29.27,8.97) v2(29.7,119.88) v2(30.04,123.24) v2(30.05,18.11) v2(32.39,124.64) v2(35.36,72.65) v2(36.89,8.97) v2(37.27,103.05) v2(37.52,123.24) v2(37.93,66.41) v2(37.99,98.06) v2(37.95,78.13) v2(38.54,97.84) v2(38.54,78.16) v2(38.71,98.4) v2(39.91,79.25) v2(40.06,123.24) v2(40.9,68.06) v2(41.28,47.6) v2(42.6,123.24) v2(43.74,66.47) v2(43.65,62.84) v2(44.51,8.97) v2(45.14,123.24) v2(47.68,123.24) v2(50.22,123.24) v2(50.22,8.97) v2(52.68,13.62) v2(52.76,123.24) v2(54.54,77.97) v2(55.05,123.9) v2(57.05,14.1) v2(57.88,124.69) v2(58.48,32.62) v2(58.48,31.8) v2(59.19,32.62) v2(59.24,31.8) v2(59.92,29.06) v2(59.92,28.48) v2(59.9,9.2) v2(60.42,124.69) v2(62.96,124.69) v2(63.73,26.01) v2(65.21,8.94) v2(65.26,107.88) v2(65.5,124.69) v2(66.32,107.88) v2(67.37,107.88) v2(67.7,72.23) v2(68.04,124.69) v2(68.05,106.65) v2(70.28,103.03) v2(70.41,71.74) v2(70.58,124.69) v2(72.83,8.94) v2(73.12,124.69) v2(75.65,69.98) v2(75.66,124.69) v2(77.19,69.37) v2(77.45,92.84) v2(77.44,72.49) v2(77.78,92.08) v2(78.2,124.69) v2(78.46,77.04) v2(79.33,72.47) v2(80.45,8.94) v2(80.74,124.69) v2(83.28,124.69) v2(83.34,18.8) v2(83.34,17.05) v2(83.34,15.27) v2(83.96,112.5) v2(85.12,18.77) v2(85.12,17.05) v2(85.12,15.24) v2(85.39,109.76) v2(85.58,115.48) v2(85.82,124.69) v2(86.25,120.45) v2(86.25,119.69) v2(86.82,100.59) v2(86.85,18.77) v2(86.85,15.24) v2(86.92,17.05) v2(88.07,8.94) v2(88.27,91.4) v2(88.36,124.69) v2(88.84,109.67) v2(89.03,115.31) v2(90.24,111.75) v2(90.9,124.69) v2(93.04,117.31) v2(93.04,116.55) v2(93.44,124.69) v2(95.69,8.94) v2(95.81,19.1) v2(95.83,17.33) v2(95.81,15.57) v2(95.98,124.69) v2(96.39,98.8) v2(96.55,114.54) v2(96.58,115.76) v2(96.58,115.18) v2(96.58,113.91) v2(96.56,113.27) v2(96.6,103.91) v2(97.01,98.8) v2(97.02,46.15) v2(97.02,44.62) v2(97.18,103.89) v2(97.61,92.32) v2(97.59,19.1) v2(97.59,17.33) v2(97.59,15.57) v2(97.71,98.8) v2(97.77,103.91) v2(98.07,6.45) v2(98.23,92.32) v2(98.28,116.19) v2(98.3,115.53) v2(98.3,114.9) v2(98.33,114.24) v2(98.34,98.8) v2(98.35,103.91) v2(98.52,124.69) v2(98.92,92.32) v2(98.99,116.19) v2(99.01,115.53) v2(99.01,114.9) v2(99.04,114.24) v2(98.96,103.91) v2(98.98,98.8) v2(99.22,4.83) v2(99.29,45.67) v2(99.37,19.1) v2(99.38,17.33) v2(99.37,15.57) v2(99.37,8.05) v2(99.55,108.1) v2(99.57,103.91) v2(99.56,92.32) v2(99.7,115.51) v2(99.7,114.87) v2(99.67,98.8) v2(99.75,114.26) v2(99.85,107.6) v2(100.16,108.13) v2(100.21,103.91) v2(100.19,47.67) v2(100.19,44.62) v2(100.44,107.55) v2(100.74,108.08) v2(100.79,103.91) v2(101.02,8.82) v2(101.06,124.69) v2(101.32,108.09) v2(101.38,103.91) v2(101.91,108.09) v2(101.96,103.88) v2(102.21,107.57) v2(102.52,108.08) v2(102.48,47.67) v2(102.48,46.15) v2(102.49,4.47) v2(102.93,7.93) v2(103.1,108.08) v2(103.31,6.15) v2(103.53,45.77) v2(103.6,124.69) v2(105.4,47.67) v2(105.4,46.15) v2(105.59,102.29) v2(106.04,114.04) v2(106.04,113.4) v2(106.14,124.69) v2(106.1,122.42) v2(106.13,121.77) v2(106.09,4.21) v2(107.74,101.67) v2(107.87,47.56) v2(108.68,124.69) v2(108.82,34.47) v2(108.82,33.04) v2(108.82,31.52) v2(109.17,114.02) v2(109.53,105.2) v2(109.47,102.87) v2(109.64,47.74) v2(109.63,45.62) v2(109.87,114.02) v2(110.66,31.13) v2(111.22,124.69) v2(111.18,3.46) v2(111.32,45.83) v2(112.02,86.87) v2(112.17,93.68) v2(112.19,34.31) v2(112.19,32.79) v2(112.37,121.01) v2(112.83,85.02) v2(112.86,95.23) v2(112.86,87.68) v2(112.96,121.01) v2(113.45,45.83) v2(113.45,44.31) v2(113.72,88.42) v2(113.67,85.8) v2(113.76,124.69) v2(114.23,84.08) v2(114.61,34.31) v2(114.61,32.79) v2(114.61,31.26) v2(114.71,77.37) v2(114.79,95.23) v2(114.76,93.68) v2(114.79,88.88) v2(114.89,87.05) v2(114.98,46.22) v2(115.5,78.13) v2(116.3,124.69) v2(116.29,78.95) v2(116.43,34.69) v2(116.43,32.48) v2(116.92,78.06) v2(117.14,45.83) v2(117.73,78.84) v2(117.8,34.31) v2(117.8,32.79) v2(117.8,31.26) v2(117.94,76.56) v2(118.67,79.73) v2(118.72,77.35) v2(118.84,124.69) v2(118.8,3.46) v2(119.54,78.13) v2(119.71,117.81) v2(119.78,47.68) v2(119.78,46.19) v2(120.11,34.31) v2(120.11,32.79) v2(120.11,31.26) v2(120.43,117.81) v2(120.36,78.88) v2(121.12,109.55) v2(121.09,75.62) v2(121.28,112.3) v2(121.38,124.69) v2(121.64,117.81) v2(121.57,80.09) v2(121.73,47.71) v2(121.87,77.09) v2(121.89,32.4) v2(122.23,117.81) v2(122.36,20.63) v2(122.81,117.81) v2(123.04,78.31) v2(122.99,20.63) v2(123.13,34.31) v2(123.13,32.78) v2(123.13,31.26) v2(123.4,117.81) v2(123.59,109.32) v2(123.65,46.19) v2(123.63,20.63) v2(123.83,79.1) v2(123.88,123.24) v2(123.98,117.81) v2(123.97,109.86) v2(124.26,20.63) v2(124.57,117.81) v2(124.6,79.92) v2(125.45,34.31) v2(125.45,32.79) v2(125.45,31.26) v2(125.87,47.71) v2(125.87,46.19) v2(126.01,69.53) v2(126.01,68.92) v2(126.27,82.69) v2(126.27,80.95) v2(126.42,123.24) v2(126.37,79.83) v2(126.42,3.46) v2(127.74,33.17) v2(127.74,30.88) v2(127.84,80.8) v2(127.84,79.5) v2(127.95,46.29) v2(128.96,123.24) v2(129.16,69.56) v2(129.16,68.95) v2(129.22,32.79) v2(129.22,31.26) v2(129.44,81.41) v2(129.79,45.91) v2(129.79,43.62) v2(130.97,81.54) v2(130.97,80.42) v2(130.97,79.3) v2(131.09,69.58) v2(131.09,68.95) v2(131.26,47.82) v2(131.26,46.27) v2(131.26,44.01) v2(131.5,123.24) v2(131.6,33.27) v2(131.6,31.75) v2(132.07,103.53) v2(132.54,80.95) v2(133.12,33.29) v2(133.12,31.77) v2(133.64,46.29) v2(134.04,123.24) v2(134.04,3.46) v2(134.27,80.47) v2(134.27,78.79) v2(134.57,103.52) v2(134.9,33.29) v2(134.89,31.79) v2(135.72,80.09) v2(136.5,47.14) v2(136.58,123.24) v2(136.89,33.32) v2(136.89,31.8) v2(136.89,30.27) v2(137.06,103.51) v2(137.85,80.01) v2(137.85,78.84) v2(137.85,77.7) v2(137.85,76.58) v2(139.12,123.24) v2(139.25,78.87) v2(139.25,77.75) v2(139.25,76.63) v2(139.25,75.52) v2(139.3,33.29) v2(139.3,32.53) v2(139.3,31.01) v2(139.36,103.43) v2(140.47,47.11) v2(141.38,79.58) v2(141.38,77.9) v2(141.38,76.79) v2(141.5,32.91) v2(141.66,123.24) v2(141.66,3.46) v2(142.03,31.74) v2(142.05,103.53) v2(142.47,48.57) v2(142.48,47.11) v2(142.48,45.58) v2(143.34,79.86) v2(143.36,78.59) v2(143.36,77.45) v2(143.36,76.33) v2(143.72,124.75) v2(143.68,33.32) v2(143.91,45.97) v2(143.91,43.68) v2(144.99,78.82) v2(144.99,77.14) v2(145.55,48.57) v2(145.55,44.1) v2(145.8,33.42) v2(145.8,31.65) v2(146.26,124.75) v2(146.44,65) v2(146.61,68.07) v2(146.74,67.49) v2(146.94,79.83) v2(146.94,78.13) v2(146.89,64.59) v2(147.17,67.06) v2(148.14,17.33) v2(148.14,15.17) v2(148.16,13.21) v2(148.42,34.31) v2(148.42,32.79) v2(148.67,46.99) v2(148.66,44.04) v2(148.8,124.75) v2(149.28,3.46) v2(149.94,45.49) v2(150.02,17.43) v2(150.28,34.69) v2(150.3,15.07) v2(150.4,13.01) v2(151.19,48.67) v2(151.16,47.11) v2(151.16,45.58) v2(151.34,124.75) v2(151.85,34.34) v2(151.85,32.81) v2(151.85,31.29) v2(152.46,17.13) v2(152.46,15.17) v2(152.46,13.01) v2(152.84,47.65) v2(152.84,45.58) v2(152.84,44.06) v2(153.83,34.3) v2(153.83,32.78) v2(153.83,31.25) v2(153.88,124.75) v2(154.74,45.89) v2(156.42,124.75) v2(156.9,3.46) v2(157.07,47.13) v2(157.07,45.61) v2(157.07,44.09) v2(157.13,34.3) v2(157.13,32.78) v2(157.13,31.25) v2(158.32,48.08) v2(158.96,124.75) v2(159.5,32.79) v2(159.5,31.26) v2(161.25,34.69) v2(161.5,124.75) v2(162.75,34.31) v2(162.75,32.79) v2(164.01,124.7) v2(164.04,21.49) v2(164.08,19.99) v2(164.52,3.46) v2(164.6,123.37) v2(164.56,74.7) v2(165.03,34.42) v2(165.03,32.9) v2(165.03,31.37) v2(166.4,122.23) v2(166.56,33.28) v2(166.87,70.67) v2(168.36,123.78) v2(168.51,32.79) v2(169.6,20.25) v2(169.65,21.52) v2(169.68,20.88) v2(169.84,124.74) v2(170.39,20.88) v2(170.49,21.52) v2(170.49,20.25) v2(172.14,124.7) v2(172.14,3.46) v2(174.27,58.77) v2(174.29,57.71) v2(174.68,124.7) v2(175.72,20.96) v2(175.67,19.03) v2(175.95,6.76) v2(177.22,124.7) v2(178,121.58) v2(177.99,120.99) v2(179,65.46) v2(178.97,64.57) v2(179,63.57) v2(179.05,61.09) v2(179.06,60.49) v2(179.26,53.32) v2(179.63,87.94) v2(179.63,86.98) v2(179.63,85.97) v2(179.76,124.7) v2(180.34,53.28) v2(180.47,78.37) v2(180.47,61.83) v2(180.75,87.95) v2(180.75,86.93) v2(180.75,85.92) v2(180.8,61.34) v2(181.18,60.86) v2(181.21,53.27) v2(181.22,32.68) v2(181.33,123.26) v2(181.6,87.94) v2(181.6,86.92) v2(181.59,6.05) v2(181.67,85.92) v2(181.81,25.57) v2(182.14,32.02) v2(183.04,38.09) v2(183.13,74.08) v2(183.18,121.34) v2(184.03,65.31) v2(183.95,63.81) v2(183.95,63.17) v2(184.1,60.38) v2(184.71,120.92) v2(184.84,20.44) v2(184.84,18.09) v2(185.02,53.14) v2(185.02,52.55) v2(185.08,117.79) v2(185.31,37) v2(186.19,109.59) v2(186.19,107.69) v2(186.19,105.78) v2(186.62,20.5) v2(186.62,19.82) v2(186.62,18.09) v2(186.75,115.95) v2(187.16,6.33) v2(187.42,4.93) v2(187.51,41.51) v2(187.79,7.57) v2(188.09,109.59) v2(188.09,107.69) v2(188.09,105.78) v2(188.46,21.2) v2(188.57,115.94) v2(189.44,34.81) v2(190,109.59) v2(190.03,34.93) v2(190.35,33.61) v2(190.35,33.02) v2(191.46,115.94) v2(193.17,5.02) v2(194.03,115.94) v2(195.76,71.99) v2(195.79,70.13) v2(195.76,69.27) v2(195.76,67.41) v2(195.84,66.61) v2(195.79,64.77) v2(195.76,63.81) v2(195.76,61.95) v2(196.02,3.46) v2(196.57,115.94) v2(197.6,23.21) v2(198.49,117.07) v2(198.56,22.74) v2(198.95,22.11) v2(199.23,22.65) v2(199.6,121.69) v2(201.71,121.62) v2(202.62,123.37) v2(204.32,74.42) v2(204.78,22.53) v2(204.78,5.77) v2(205.16,124.06) v2(205.54,0.51) v2(205.64,40.82) v2(205.62,37.16) v2(206.02,55.35) v2(206.71,22.53) v2(206.81,59.79) v2(207.7,120.96) v2(207.95,106.96) v2(209.48,124.89) v2(209.67,7.5) v2(209.67,6.91) v2(209.99,80.83) v2(210.24,96.01) v2(210.3,8.08) v2(210.3,7.5) v2(210.3,6.91) v2(210.74,100.31) v2(210.9,38.89) v2(212.4,96.07) v2(212.55,80.85) v2(213.16,0.51) v2(213.9,8.18) v3(10.66,92.94) v3(11.82,107.16) v3(12.09,111.28) v3(17.5,110.85) v3(18.61,24.93) v3(19.27,110.17) v3(20.73,114.19) v3(29.44,38.61) v3(32.61,35.6) v3(44.62,26.65) v3(50.6,63.65) v3(53.23,69.32) v3(53.19,69.26) v3(58.55,28.36) v3(59.45,108.8) v3(59.75,32.2) v3(60,117.27) v3(62.2,113.25) v3(64.28,48.16) v3(64.53,48.21) v3(65.33,110.21) v3(65.82,38.51) v3(66.77,106.69) v3(70.9,102.77) v3(74.63,64.34) v3(113.1,122.43) v3(119.66,116.93) v3(128.53,68.93) v3(131.7,69.05) v3(147.41,64.04) v3(180.62,26.86) v3(181.92,60.33) v3(190.66,36.18) v4(15.45,14.3) v4(15.55,18.09) v4(15.55,17.45) v4(15.55,16.56) v4(15.55,15.93) v4(15.57,15.06) v4(15.83,13.67) v4(16.18,18.09) v4(16.18,17.45) v4(16.18,16.56) v4(16.18,15.93) v4(16.21,15.06) v4(16.21,14.3) v4(16.82,18.09) v4(16.82,17.45) v4(16.82,16.56) v4(17.45,18.09) v4(18.09,112.99) v4(18.09,112.23) v4(18.09,111.46) v4(18.09,18.09) v4(18.72,112.7) v4(18.73,111.97) v4(19.11,27.36) v4(19.11,26.72) v4(19.11,26.09) v4(19.11,25.45) v4(19.51,112.68) v4(19.49,111.99) v4(19.74,27.36) v4(19.74,26.72) v4(19.74,26.09) v4(19.74,25.45) v4(20.1,112.35) v4(20.92,111.51) v4(20.92,110.87) v4(21.58,111.51) v4(21.58,110.85) v4(22.27,111.51) v4(22.27,110.87) v4(22.93,111.51) v4(22.98,110.87) v4(23.61,111.51) v4(23.64,110.87) v4(23.78,20.02) v4(23.83,19.36) v4(24.29,18.9) v4(24.92,18.9) v4(25.56,18.9) v4(26.09,20.02) v4(26.09,19.38) v4(26.19,18.75) v4(29.9,50.79) v4(29.9,50.15) v4(30.54,50.79) v4(30.54,50.15) v4(30.66,37.77) v4(30.92,36.63) v4(31.04,37.26) v4(31.42,37.77) v4(31.68,36.63) v4(31.93,37.26) v4(32.31,37.77) v4(32.52,36.63) v4(32.72,37.24) v4(33.08,37.77) v4(33.33,36.63) v4(33.35,35.99) v4(33.35,35.28) v4(33.58,37.24) v4(33.96,37.77) v4(34.09,36.63) v4(34.09,35.97) v4(34.09,35.33) v4(34.42,37.24) v4(34.83,36.63) v4(34.83,35.94) v4(34.8,35.31) v4(34.9,37.77) v4(35.41,37.21) v4(35.44,35.31) v4(35.49,35.94) v4(40.44,52.81) v4(41.08,52.81) v4(41.71,52.81) v4(42.03,51.96) v4(42.47,51.49) v4(42.6,52.25) v4(44.63,27.51) v4(45.14,26.07) v4(45.24,30.2) v4(45.24,29.57) v4(45.27,27.29) v4(45.38,26.67) v4(45.77,26.12) v4(45.88,30.2) v4(45.88,29.57) v4(45.87,27.1) v4(46.25,26.53) v4(46.28,28.25) v4(46.33,27.61) v4(46.72,26.11) v4(46.85,26.74) v4(46.92,28.22) v4(46.94,27.41) v4(48.39,121.21) v4(48.39,120.47) v4(48.39,119.74) v4(48.95,64.06) v4(48.95,63.43) v4(48.95,62.79) v4(48.95,62.16) v4(48.89,47.81) v4(48.91,46.2) v4(49.1,121.21) v4(49.1,120.47) v4(49.1,119.74) v4(49.05,32.67) v4(49.08,32.03) v4(49.05,31.37) v4(49.48,56.82) v4(49.48,55.3) v4(49.97,56.06) v4(50.45,56.82) v4(50.45,55.3) v4(50.6,47.81) v4(51.06,121.21) v4(51.06,120.47) v4(51.06,119.74) v4(51.38,28.94) v4(51.77,121.21) v4(51.77,120.47) v4(51.77,119.74) v4(52.19,28.94) v4(52.19,28.13) v4(52.38,64.75) v4(52.35,64.11) v4(52.35,63.48) v4(52.35,62.84) v4(52.51,34.32) v4(52.53,21.54) v4(52.68,33.71) v4(52.84,24.03) v4(52.84,23.37) v4(52.86,22.74) v4(52.91,22.1) v4(52.99,68.3) v4(53.01,64.75) v4(52.99,64.11) v4(52.99,63.48) v4(52.99,62.84) v4(53.22,21.52) v4(53.52,24.06) v4(53.55,23.42) v4(53.62,68.3) v4(53.57,22.76) v4(53.62,22.07) v4(55.81,68.38) v4(56.44,68.38) v4(58.42,68.38) v4(59.06,68.38) v4(59.55,110.55) v4(60.13,109.84) v4(60.2,115.24) v4(60.19,110.54) v4(60.7,114.35) v4(60.76,115.62) v4(60.84,114.99) v4(60.94,120.58) v4(60.91,119.4) v4(60.91,118.21) v4(60.99,117.58) v4(60.99,116.79) v4(60.99,68.38) v4(61.15,118.81) v4(61.08,112.38) v4(61.19,119.97) v4(61.33,114.35) v4(61.4,115.69) v4(61.55,118.19) v4(61.47,115.06) v4(61.57,120.58) v4(61.55,119.39) v4(61.7,117.55) v4(61.68,116.79) v4(61.65,68.38) v4(61.83,119.97) v4(61.78,118.79) v4(62.03,115.69) v4(61.96,114.42) v4(62.1,115.05) v4(62.16,121.34) v4(62.23,120.58) v4(62.21,119.39) v4(62.21,118.11) v4(62.42,118.72) v4(62.44,117.48) v4(62.39,116.79) v4(62.49,119.97) v4(62.54,46.92) v4(62.54,46.28) v4(62.54,45.65) v4(62.54,45.01) v4(62.6,114.41) v4(62.67,115.69) v4(62.74,115.05) v4(62.92,121.34) v4(62.92,120.6) v4(62.9,119.41) v4(62.89,118.06) v4(63.06,118.71) v4(63.1,117.4) v4(63.1,116.74) v4(63.18,120) v4(63.21,49.91) v4(63.19,49.28) v4(63.24,46.92) v4(63.24,46.28) v4(63.24,45.65) v4(63.24,45.01) v4(63.3,115.7) v4(63.3,114.42) v4(63.37,115.05) v4(63.47,51.26) v4(63.47,50.62) v4(63.61,120.63) v4(63.58,119.44) v4(63.56,118.04) v4(63.63,68.38) v4(63.61,37.67) v4(63.71,118.7) v4(63.78,117.4) v4(63.81,116.77) v4(63.85,49.91) v4(63.82,49.28) v4(63.86,120.02) v4(63.94,115.7) v4(63.87,46.92) v4(63.87,46.28) v4(63.87,45.65) v4(63.87,45.01) v4(64.01,115.05) v4(64.1,51.26) v4(64.1,50.62) v4(64.27,68.4) v4(64.29,37.67) v4(64.29,37.04) v4(64.48,53.72) v4(64.48,49.91) v4(64.46,49.28) v4(64.51,46.92) v4(64.51,46.28) v4(64.51,45.65) v4(64.51,45.01) v4(64.6,52.61) v4(64.6,51.97) v4(64.74,51.26) v4(64.74,50.62) v4(64.9,53.19) v4(64.93,37.67) v4(64.93,37.04) v4(65.12,49.91) v4(65.09,49.28) v4(65.14,46.92) v4(65.14,46.28) v4(65.14,45.65) v4(65.14,45.01) v4(65.21,53.75) v4(65.24,52) v4(65.31,52.63) v4(65.37,51.26) v4(65.37,50.62) v4(65.56,37.67) v4(65.56,37.04) v4(65.66,53.19) v4(65.73,49.28) v4(65.75,49.91) v4(65.78,46.92) v4(65.78,46.28) v4(65.78,45.65) v4(65.78,45.01) v4(65.76,36.43) v4(65.88,52) v4(66.02,53.75) v4(65.99,52.63) v4(66.01,51.26) v4(66.01,50.62) v4(66.2,37.67) v4(66.2,37.04) v4(66.53,36.43) v4(66.83,37.67) v4(66.83,37.04) v4(67.16,36.43) v4(67.47,37.67) v4(67.47,37.04) v4(72.83,33.71) v4(72.83,33.07) v4(72.83,32.44) v4(73.46,65.46) v4(73.46,32.44) v4(74.32,61.88) v4(74.6,32.44) v4(75.09,63.81) v4(75.09,63.17) v4(75.09,62.54) v4(75.09,61.9) v4(75.24,33.71) v4(75.24,33.07) v4(75.24,32.44) v4(80.42,112.52) v4(80.45,110.9) v4(81.21,112.52) v4(81.23,110.92) v4(86.44,122.23) v4(86.42,121.57) v4(86.38,118.82) v4(86.35,118.16) v4(205.92,76.51) v4(212.53,97.59)
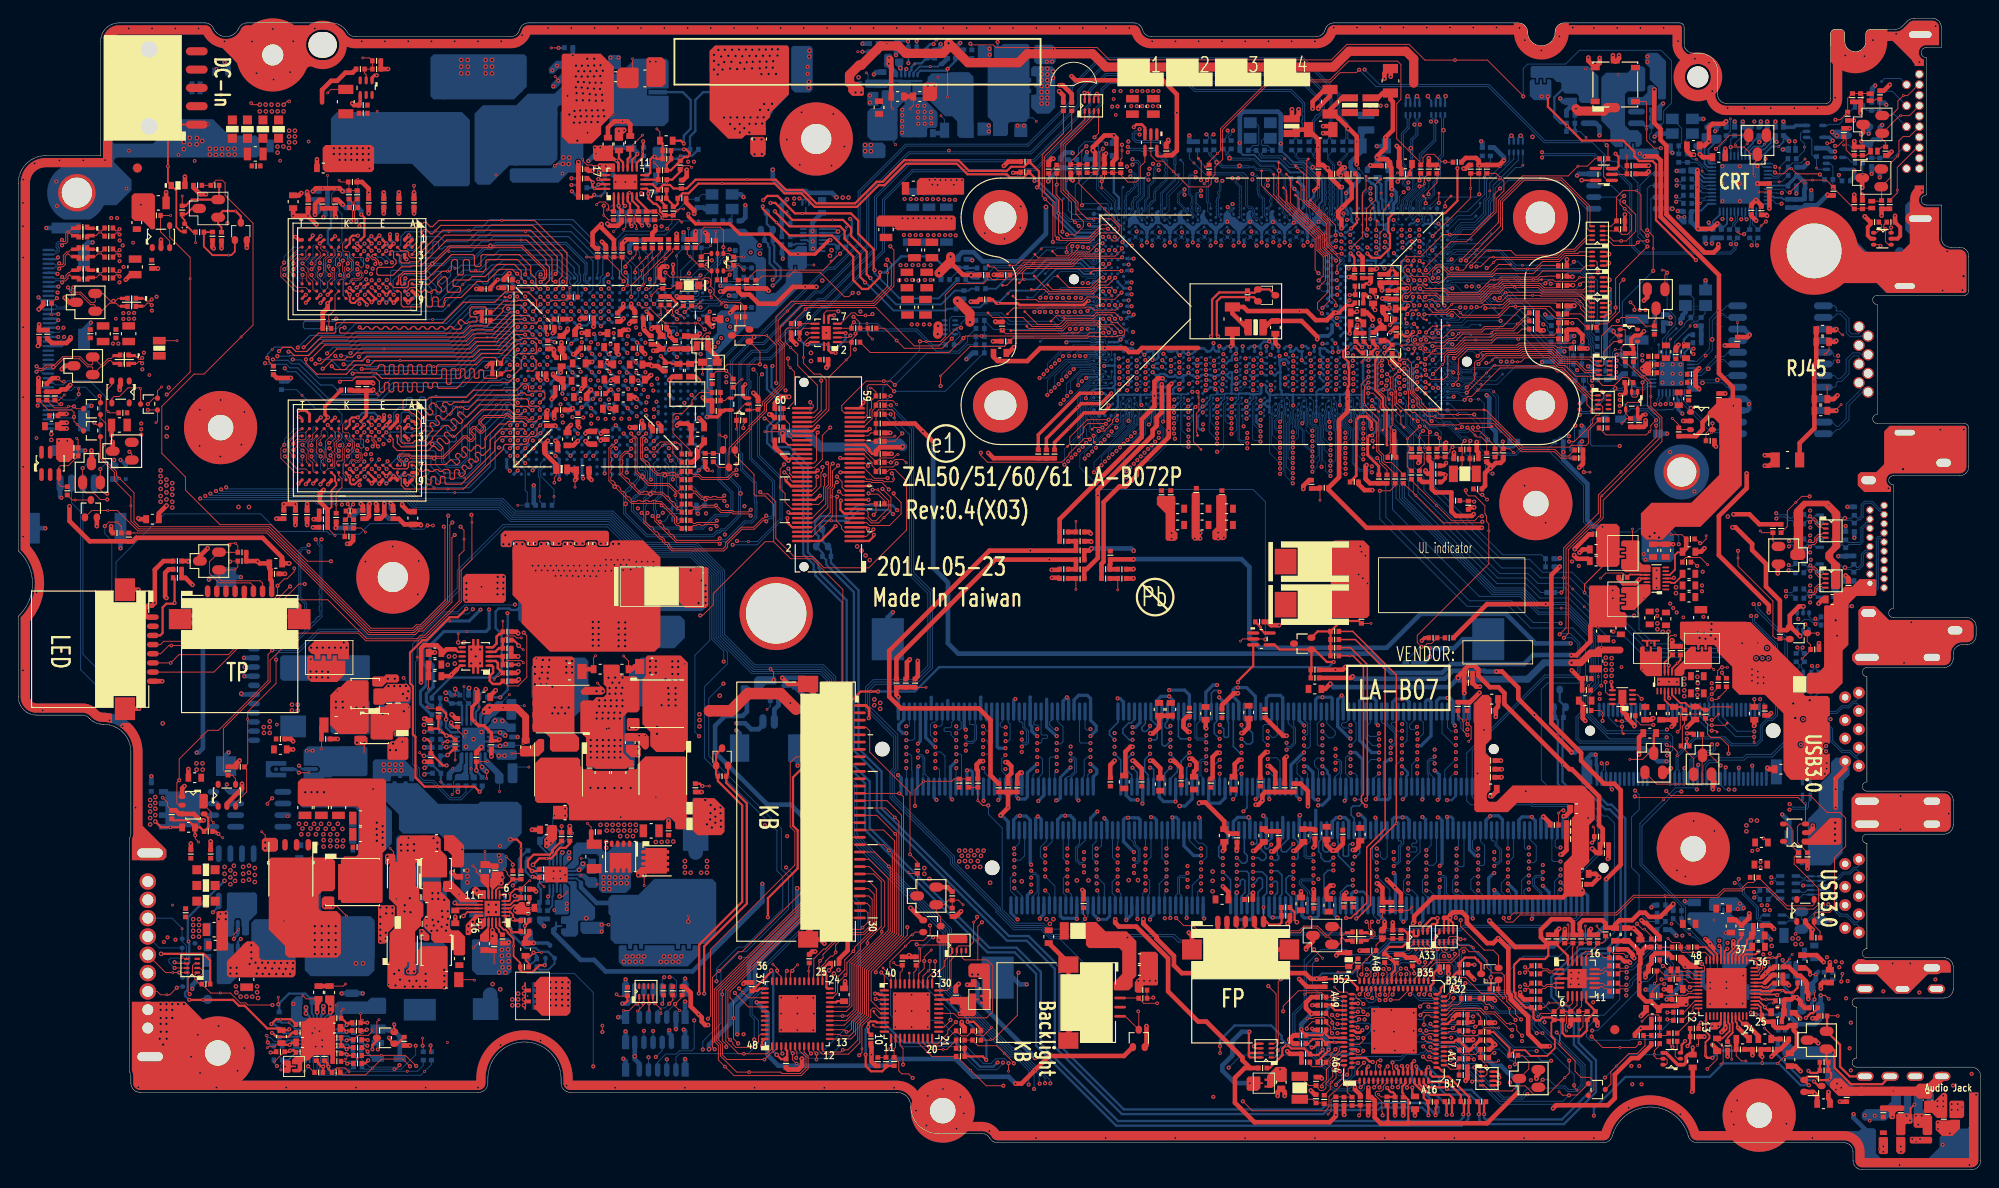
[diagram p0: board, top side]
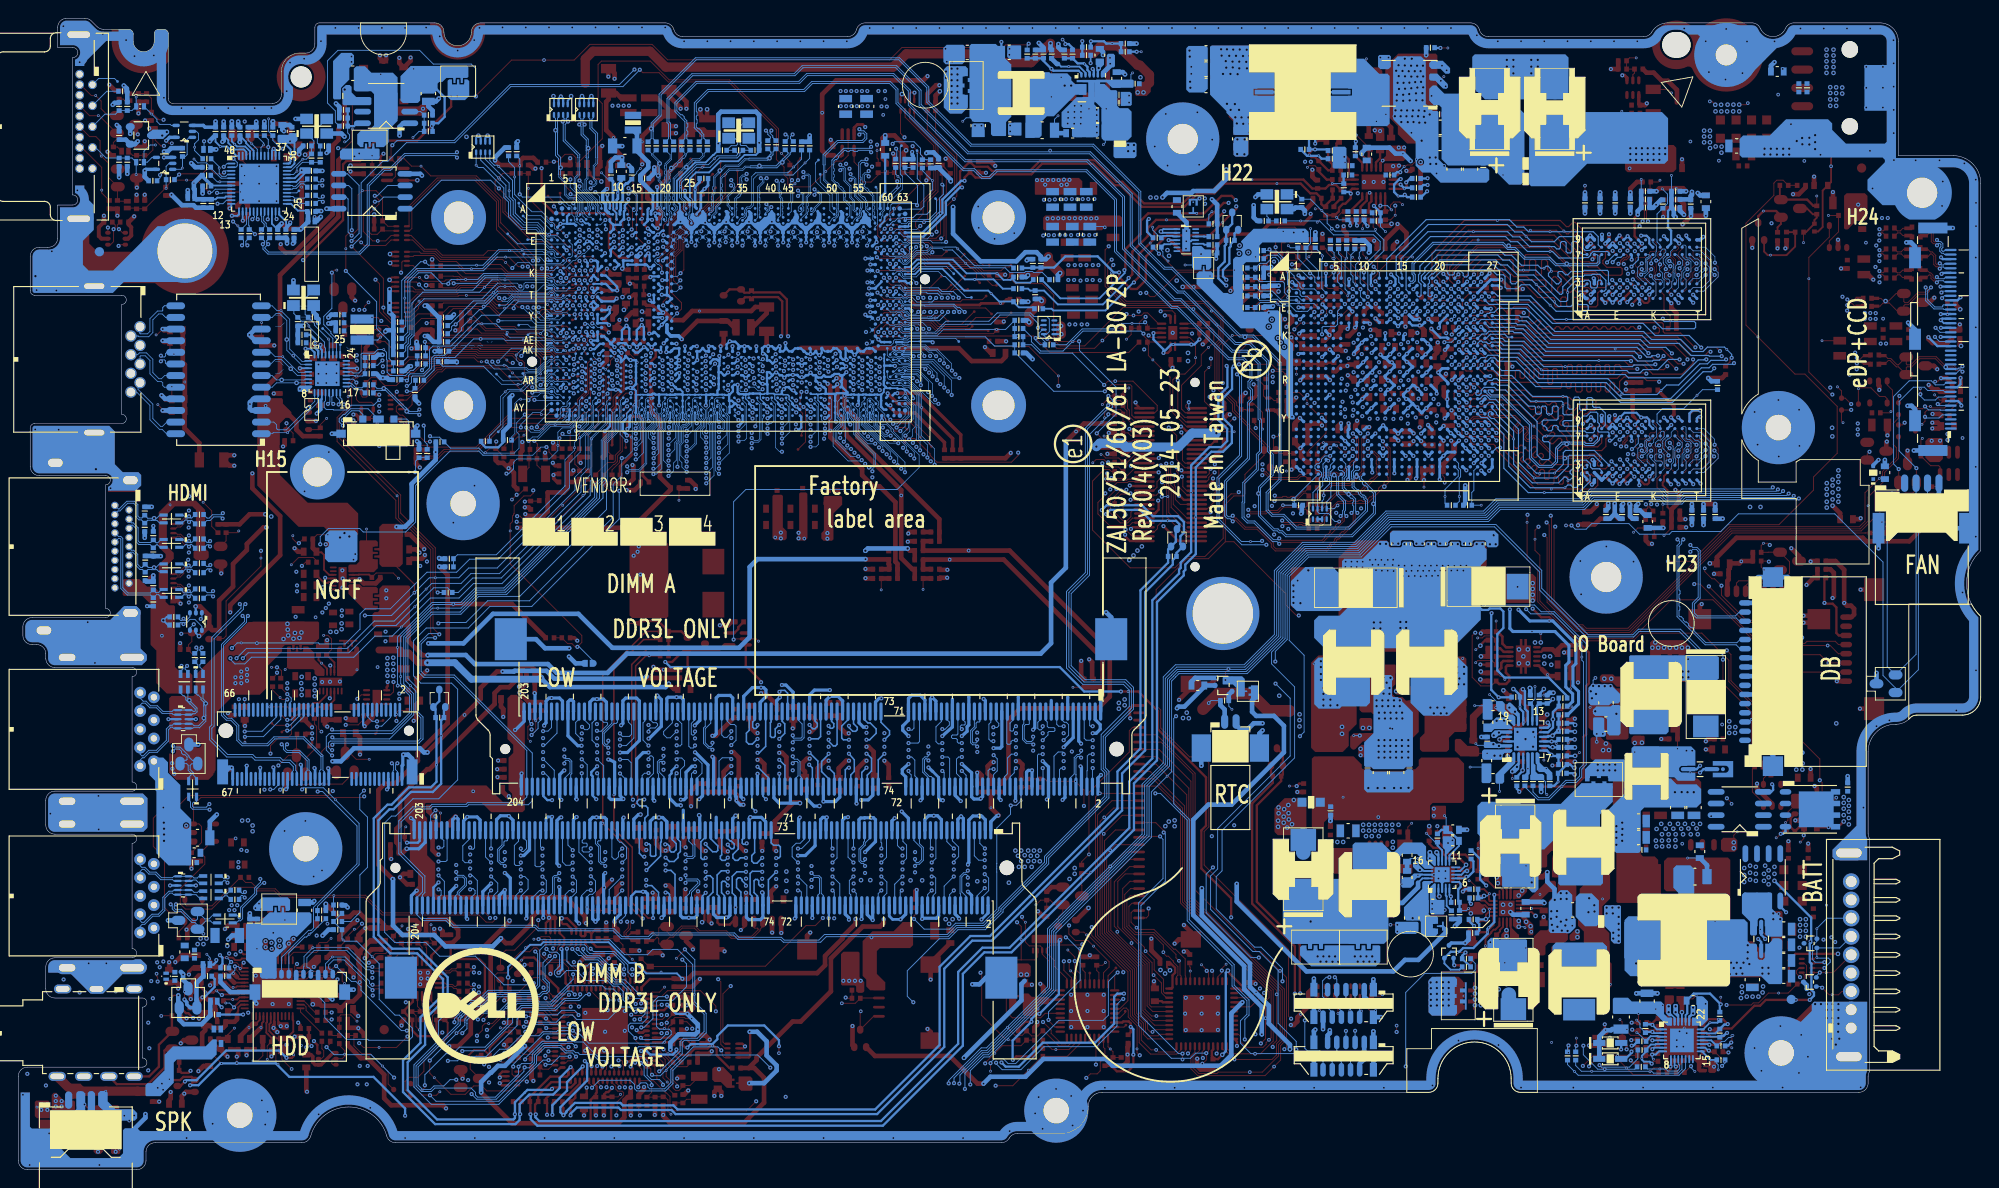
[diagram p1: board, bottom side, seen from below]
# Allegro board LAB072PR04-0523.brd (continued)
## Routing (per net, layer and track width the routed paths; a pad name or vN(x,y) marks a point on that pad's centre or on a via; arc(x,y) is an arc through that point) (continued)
GNDA: length 33.4
  TOP w0.102: CA74.2 185.6,12.07 v3(184.54,11) ; v2(195.76,21.31) v3(196.4,21.31) ; v2(190.53,12.35) v3(190.53,11.65)
  TOP w0.203: UA1.38 188.42,22.87 188.42,23.27 188.68,23.52 189.81,23.52 v2(190.12,23.84)
  TOP w0.254: CA75.2 RA1128.2 196.55,10.57 195.81,10.57 v2(195.58,10.8)
  TOP w0.381: CA51.2 192.66,16.51 192.79,16.64 192.79,17.08 CA62.1 ; QA6.4 180.01,12.77 181.31,11.47 QA6.1 181.97,11.47 182.22,11.72 182.22,12.36 182.43,12.56 RA1115.1 v2(182.94,13.36) ; RA1114.1 195.34,22.04 195.76,21.62 v2(195.76,21.31)
  TOP w0.508: v2(185.09,13.64) 185.6,13.13 CA74.2 ; RA1117.1 197.12,20.44 196.93,20.25 v2(196.93,19.78) ; RA1129.1 195.17,17.68 194.7,18.15 194.7,18.42 v2(194.29,18.82) 193.93,18.82 193.7,18.6 193.03,18.6 192.9,18.47 CA23.1 CA62.1 ; CA71.2 194.06,17.13 194.66,16.54 v2(194.66,16.5) ; RA83.2 RA84.2 190.38,12.5 v2(190.53,12.35) ; v2(197.76,8.49) 197.76,7.76 197.93,7.58 RA1116.1
  BOTTOM w0.254: CA39.2 192.96,20.82 192.96,19.95 194.09,18.82 v2(194.29,18.82) ; CA33.2 v2(189.84,16.94)
  vias: v2(189.29,17.15) v2(190.66,23.51) v2(191.37,23.61) v2(199.7,18.72) v2(200.08,13.26) v2(200.21,16.06) v2(200.21,10.85) v2(203.76,19.48) v2(207.7,19.36) v2(209.45,20.78) v2(211.38,9.2) v2(213.42,10.47)
GNDA_CHG: length 10
  TOP w0.254: PQ709.3 v2(41.07,15.87)
  IN3 w0.254: v2(41.07,15.87) 40.25,16.7 35.64,16.7 34.05,15.12 v2(32.9,15.12)
  vias: v1(32.39,15.47) v2(32.12,14.91) v2(32.49,13.44) v2(33.2,14.15) v2(33.2,13.44)
VCCSENSE: length 57.2
  TOP w0.254: v2(111.02,108) 111.02,108.36 R1.2 109.82,108.36 108.36,108.36 108.01,108.71 103.71,108.71 102.55,109.87 96.97,109.87 94.62,107.52 93.98,107.52 91.62,105.16 87.02,105.16 85.55,106.63 83.72,106.63 82.65,107.7 v1(76.89,107.7) 74.3,107.7 73.23,106.63 72.57,106.63 PC541.2 72.04,105.46 71.73,105.16 PR537.1 71.56,105.34 PR533.1 70.82,106.12 PC545.1
  BOTTOM w0.254: UC1.E63 115.6,102.34 113.44,104.5 113.44,105.95 111.38,108 v2(111.02,108)
VDD_1.35V: length 7.3
  BOTTOM w0.102: v1(58.59,38.66) 58.4,38.47 PC209.1
  BOTTOM w0.203: PU200.11 58.04,34.32 57,35.36 PR206.2
  BOTTOM w0.254: PR205.1 58.91,37.12 PC209.1 58.08,36.8 57.84,36.8 57,35.97 PR206.2
VSSSENSE: length 60.5
  TOP w0.254: v2(111.29,107.28) 111.51,107.5 111.51,109.03 R2.1 109.88,109.54 108.48,109.54 108.03,109.1 103.86,109.1 102.71,110.25 96.79,110.25 94.44,107.9 93.78,107.9 91.42,105.54 87.18,105.54 85.7,107.01 83.88,107.01 82.76,108.13 v1(79.63,108.13) 73.99,108.13 73.03,107.16 PC546.2 71.58,107.16 71.2,107.55 70.44,107.55 PC545.2 69.29,107.63 PU501.8
  BOTTOM w0.076: UC1.E62 118.03,102.3 117.64,101.91 117.28,101.91
  BOTTOM w0.254: v2(111.29,107.28) 111.52,107.28 113.06,105.74 113.06,104.35 115.5,101.91 117.28,101.91
6513_27M_IN: length 6.1
  BOTTOM w0.102: UV6.34 184.62,109.09 183.34,110.37 v1(183.32,110.37) 182.94,110.37 RV210.1 CV345.1 182.11,112.07 182.11,112.37 YV3.1
6513_27M_OUT: length 4.4
  BOTTOM w0.102: UV6.33 184.33,108.69 v1(183.96,109.06) 183.96,109.43 183.36,110.02 RV210.2 RV159.1
+1.35DGPU_B+:
  vias: v1(42.68,50.5) v4(39.81,49.79) v4(42.12,50.07)
+CHGRTC: length 1.3
  TOP w0.102: v2(82.52,53.48) 82.52,54.36 v3(82.19,54.69)
+CODEC_AVDD2: length 4.6
  TOP w0.203: CA61.1 188.87,25.05 188.87,24.67 188.33,24.14 v1(188.33,24.13) 188.19,23.99 188.19,23.97 188.16,23.94 187.62,23.4 187.62,22.88 UA1.40
  TOP w0.508: RA8.2 189.56,25.75 CA61.1
+CORE_PLLVDD: length 6
  TOP w0.102: v1(75.54,91.39) 75.15,91.39 74.72,90.96 74.72,90.56 LV10.2
  TOP w0.508: v2(71.11,89.56) 71.19,89.64 CV134.1 72.19,89.64 72.2,89.65 CV46.1 73.81,89.65 LV10.2
  BOTTOM w0.305: v2(71.11,89.56) 70.72,89.18 UV1.L6
+CPU_CORE: length 86
  TOP w0.381: v2(108.68,108.88) 109.43,108.88 R1.1
  TOP w0.508: C40.1 108.16,89.21 v2(108.79,89.84)
  BOTTOM w0.076: 124.97,101.82 UC1.G51 ; UC1.G51 v2(125.25,100.93) ; UC1.G51 124.97,101.25 ; 132.32,102.7 UC1.C40 131.8,102.7 ; 134.31,102.15 UC1.F36 ; UC1.F36 134.88,102.15 ; UC1.F36 134.31,101.58 ; UC1.F36 134.88,101.58 ; 131.68,102.1 UC1.E41 131.68,102.67 ; UC1.E33 136.7,102.1 ; UC1.E33 136.7,102.67 ; UC1.E33 136.13,102.1 ; 137.51,101.25 UC1.G31 ; UC1.G31 137.51,101.82 ; UC1.G31 v2(137.79,100.93) ; UC1.F56 122.34,101.58 ; UC1.F56 121.77,102.15 ; UC1.F56 122.34,102.15 ; UC1.F56 121.77,101.58 ; UC1.AG57 121.37,90.69 ; UC1.AG57 120.87,90.62 ; UC1.AG57 121.37,90.12 ; 131.8,101.58 UC1.F40 ; UC1.F40 132.37,101.58 ; UC1.F40 132.37,102.15 ; UC1.F40 131.8,102.15 ; UC1.G33 v2(136.41,100.93) ; UC1.G33 136.7,101.82 ; UC1.G33 136.7,101.25 ; UC1.G29 139.2,101.82 ; UC1.G29 v2(138.92,100.93) ; UC1.G29 139.2,101.25 ; 120.8,91.99 UC1.AD57 ; UC1.AD57 121.37,91.42 ; UC1.AD57 121.37,91.99 ; 132.49,102.1 UC1.E39 132.49,102.67 ; v2(140.42,100.93) 140.3,101.05 UC1.G27 ; UC1.F52 124.85,102.15 ; UC1.F52 124.85,101.58 ; UC1.F52 124.28,102.15 ; UC1.F52 124.28,101.58 ; 120.8,92.72 UC1.AB57 121.37,92.72 ; 139.32,102.15 UC1.F28 ; UC1.F28 139.89,101.58 ; UC1.F28 139.89,102.15 ; UC1.F28 139.32,101.58 ; 121.8,102.74 UC1.C56 122.31,102.74 ; 126.81,102.7 UC1.C48 127.33,102.7 ; UC1.G53 124.16,101.25 ; UC1.G53 v2(123.87,100.93) ; UC1.G53 124.16,101.82 ; 121.37,95.89 UC1.U57 121.37,95.32 ; UC1.E31 138.08,102.1 ; UC1.E31 137.51,102.1 ; UC1.E31 137.51,102.67 ; UC1.E31 137.31,102.39 v2(137.24,102.46) 137.07,102.62 UC1.C32 ; 129.29,102.7 UC1.C44 129.81,102.7 ; 141.83,101.58 UC1.F24 ; UC1.F24 142.4,102.15 ; UC1.F24 141.83,102.15 ; UC1.F24 142.4,101.58 ; 135,102.67 UC1.E35 ; UC1.E35 135,102.1 ; UC1.E35 135.57,102.1 ; 141.71,101.25 UC1.G25 141.71,101.82 ; 140.01,101.82 UC1.G27 ; UC1.G27 140.01,101.25 ; 129.98,101.25 UC1.G43 ; UC1.G43 v2(130.27,100.93) ; UC1.G43 129.98,101.82 ; UC1.E53 124.16,102.67 ; UC1.E53 124.16,102.1 ; UC1.E53 123.59,102.1 ; UC1.F48 127.36,102.15 ; UC1.F48 127.36,101.58 ; UC1.F48 126.79,102.15 ; UC1.F48 126.79,101.58 ; 126.67,102.67 UC1.E49 126.67,102.1 ; 134.19,101.82 UC1.G37 134.19,101.25 ; 142.52,101.25 UC1.G23 ; UC1.G23 142.52,101.82 ; UC1.G23 143.03,101.32 143.03,101 ; UC1.G23 143.09,101.82 ; 141.14,102.1 UC1.E25 ; UC1.E25 141.71,102.67 ; UC1.E25 141.71,102.1 ; UC1.E55 123.03,102.1 ; UC1.E55 122.46,102.67 ; UC1.E55 122.46,102.1 ; 127.48,102.67 UC1.E47 127.48,102.1 ; UC1.C32 136.82,102.7 ; UC1.C32 137.33,102.7 ; UC1.F32 137.39,102.15 ; UC1.F32 136.82,102.15 ; UC1.F32 137.39,101.58 ; UC1.F32 136.82,101.58 ; UC1.F32 137.1,101.31 v2(137.11,101.3) ; UC1.E27 140.58,102.1 ; UC1.E27 140.01,102.67 ; UC1.E27 140.01,102.1 ; UC1.M57 121.37,97.92 ; UC1.M57 121.37,98.49 ; UC1.M57 120.8,97.92 ; 124.97,102.67 UC1.E51 124.97,102.1 ; UC1.G57 121.37,101.23 v2(121.67,100.93) ; UC1.G57 121.65,101.25 ; UC1.G57 121.65,101.82 ; 142.66,98.61 142.89,98.37 UC1.M23 143.13,98.37 UC1.L22 143.13,99.19 UC1.K23 ; 141.83,102.7 UC1.C24 142.35,102.7 ; 133.62,102.1 UC1.E37 ; UC1.E37 134.19,102.1 ; UC1.E37 134.19,102.67 ; UC1.F44 129.86,101.58 ; UC1.F44 129.86,102.15 ; UC1.F44 129.29,102.15 ; UC1.F44 129.29,101.58 ; 121.37,99.22 UC1.K57 121.37,99.79 ; 142.74,100.53 UC1.H23 142.74,101.1 ; 132.49,101.82 UC1.G39 ; UC1.G39 v2(132.78,100.93) ; UC1.G39 132.49,101.25 ; UC1.G45 129.17,101.82 ; UC1.G45 v2(128.89,100.93) ; UC1.G45 129.17,101.25 ; UC1.G41 131.68,101.82 ; UC1.G41 131.68,101.25 ; UC1.G41 v2(131.4,100.93) ; UC1.G49 126.67,101.25 ; UC1.G49 v2(126.38,100.93) ; UC1.G49 126.67,101.82 ; 122.46,101.82 UC1.G55 ; UC1.G55 v2(122.75,100.93) ; UC1.G55 122.46,101.25 ; 142.52,102.67 UC1.E23 ; UC1.E23 142.52,102.1 ; UC1.E23 143.09,102.1 ; UC1.P57 121.37,97.19 ; UC1.P57 120.8,96.62 ; UC1.P57 121.37,96.62 ; UC1.P57 120.8,97.19 ; 121.37,94.02 UC1.W57 121.37,94.59 ; 134.31,102.7 UC1.C36 134.82,102.7 ; 139.32,102.7 UC1.C28 139.84,102.7 ; 129.17,102.1 UC1.E45 129.17,102.67 ; 142.74,99.71 UC1.J23 142.74,100.28 ; UC1.E29 139.2,102.1 ; UC1.E29 138.63,102.1 ; UC1.E29 139.2,102.67 ; 127.48,101.25 UC1.G47 ; UC1.G47 v2(127.76,100.93) ; UC1.G47 127.48,101.82 ; 121.65,102.67 UC1.E57 121.65,102.1 ; 142.74,98.9 UC1.K23 ; UC1.K23 142.74,99.47 ; 129.98,102.1 UC1.E43 129.98,102.67 ; 124.3,102.74 UC1.C52 124.82,102.74
  BOTTOM w0.081: v2(135.28,100.93) 135.08,101.13 135.08,101.33 UC1.G35 ; 143.03,101 UC1.H23 ; UC1.G25 141.26,101.37 141.26,100.96 v2(141.3,100.92)
  BOTTOM w0.254: UC1.G37 v2(133.9,100.93) ; UC1.AB57 121.25,93.17 121.64,93.17 v2(121.86,93.39) ; v2(121.63,96.91) UC1.P57 ; v2(121.63,98.21) UC1.M57 ; v2(119.79,101.88) 119.79,101.84 UC1.F59 ; v2(121.63,94.31) UC1.W57 ; v2(121.63,95.61) UC1.U57 ; v2(121.85,99.51) UC1.K57
  vias: v2(96.24,97.13) v2(96.83,106.02) v2(96.75,102.08) v2(97.02,97.17) v2(97.4,102.07) v2(97.5,106.01) v2(97.65,97.17) v2(98.04,102.07) v2(98.11,106.01) v2(98.35,97.11) v2(98.63,102.08) v2(98.71,106) v2(99.05,97.17) v2(99.29,106.01) v2(99.38,102.07) v2(99.69,97.17) v2(99.93,106) v2(100.02,102.07) v2(100.51,106) v2(100.61,102.08) v2(101.15,105.97) v2(101.25,102.07) v2(101.74,105.93) v2(101.83,102.07) v2(102.34,105.92) v2(102.42,102.03) v2(119.51,116.11) v2(120.1,116.13) v2(121.59,116.16) v2(121.7,90.22) v2(121.78,91.49) v2(122.2,116.16) v2(122.19,102.46) v2(122.79,116.16) v2(123.37,116.16) v2(123.96,116.16) v2(124.54,116.16) v2(124.73,102.39) v2(127.14,102.39) v2(129.75,102.41) v2(132.22,102.46) v2(134.73,102.46) v2(139.78,102.49) v3(119.91,115.2) v4(76,121.76) v4(76,121.1) v4(76,120.16) v4(76.41,119.62) v4(76.48,122.29) v4(76.51,120.69) v4(76.79,121.58) v4(76.94,120.16) v4(77.12,120.97) v4(77.09,114.91) v4(77.19,122.32) v4(77.58,121.66) v4(77.78,120.26) v4(77.82,114.92) v4(77.77,114.2) v4(77.91,121) v4(77.98,122.32) v4(78.27,113.69) v4(78.36,121.63) v4(78.54,120.21) v4(78.54,114.92) v4(78.74,122.34) v4(78.81,114.2) v4(78.83,113.29) v4(78.87,120.89) v4(79.1,121.6) v4(79.33,120.23) v4(79.29,114.91) v4(79.32,113.74) v4(79.48,122.34) v4(79.58,120.94) v4(79.89,121.66) v4(79.87,114.23) v4(79.87,113.27) v4(80,114.92) v4(80.19,122.32) v4(80.24,121) v4(80.17,120.28) v4(80.6,121.63) v4(80.57,114.23) v4(80.76,114.92) v4(80.95,122.34) v4(81,121.02) v4(81,120.28) v4(81.03,115.75) v4(81.18,119.65) v4(81.27,114.26) v4(81.36,121.66) v4(81.44,114.94) v4(81.49,116.39) v4(81.67,122.34) v4(81.74,121.02) v4(81.72,120.39) v4(81.94,115.75) v4(81.97,119.67) v4(82.1,121.66) v4(82.35,122.37) v4(82.43,120.36) v4(82.35,116.41) v4(82.48,121.07) v4(82.78,119.67) v4(82.94,121.68) v4(82.99,122.37)
+CRT_VCC: length 9.7
  TOP w0.102: v3(197.63,112.11) 197.96,112.11 v2(198.24,112.38)
  BOTTOM w0.381: UV3.5 200.45,109.26 v2(200.59,109.12) ; v2(198.24,112.38) 197.87,112.75 UV5.5
  BOTTOM w0.508: CV50.1 202.66,112.5 UV4.3 201.67,112.01 v2(201.35,112.32) ; v2(202.87,118.41) 202.54,118.08 RV35.1 202.49,117.73 RV38.1 ; RV36.1 200.59,108.43 v2(200.59,109.12) ; v2(202.49,108.77) RV37.1
+DC_IN: length 56.1
  TOP w0.102: v2(38.16,12.91) 37.72,13.34 PR739.1
  TOP w0.254: v4(14.96,38.03) 15.6,37.39 v3(16.63,37.39) PC700.1
  TOP w0.508: PR9.1 36.52,119.81 35.73,119.81 34.84,118.93 34.18,118.93 33.19,117.93 33.19,116.56
  IN1 w0.254: v2(15.9,24.87) 18.88,21.9 19.79,21.9 20.5,21.19 20.5,20.2 24.15,16.55 29.09,16.55 30.04,15.6 34.91,15.6 35.65,16.33 36.33,16.33 36.76,15.9 36.76,14.2 38.05,12.91 v2(38.16,12.91)
  IN3 w0.254: v2(15.9,24.87) 15.68,25.1 15.68,27.74 17.58,29.64 17.58,35.41 v4(14.96,38.03)
  BOTTOM w0.254: PD703.2 38.8,12.11 38.16,12.75 v2(38.16,12.91)
  vias: v3(28.6,110.2) v3(31.72,112.3) v4(14.41,40.38) v4(14.41,39.74) v4(14.41,39.11) v4(14.41,38.41) v4(14.41,37.71) v4(14.96,40.7) v4(14.96,40.06) v4(14.96,39.43) v4(14.96,38.73) v4(28.31,111.74) v4(28.33,111.08) v4(28.96,111.75) v4(29.58,113.48) v4(29.58,112.84) v4(29.58,112.21) v4(29.57,111.57) v4(30.22,113.48) v4(30.22,112.84) v4(30.22,112.21)
+DC_IN_SS: length 50
  TOP w0.102: PC701.1 16.31,39.69 16.31,40.1 v3(15.78,40.63)
  TOP w0.508: PC701.1 17.19,39.25 17.57,38.86 PQ708.4 19.16,38.86 19.87,38.15 v2(20.25,38.15)
  IN1 w0.254: v2(16.31,25.38) 16.31,25.2 19.23,22.28 19.95,22.28 21.54,20.68 21.54,19.92 24.49,16.98 29.2,16.98 30.2,15.98 34.75,15.98 35.51,16.74 36.58,16.74 37.19,16.13 37.19,14.38 38.03,13.54 v2(38.13,13.54)
  IN3 w0.254: v2(16.31,25.38) 16.31,27.09 18.24,29.02 18.24,36.34 20.06,38.15 v2(20.25,38.15)
  BOTTOM w0.254: PR730.1 37.95,13.54 v2(38.13,13.54)
+DCIN:
  vias: v1(34.74,17.95)
+DCIN_JACK: length 1.8
  TOP w0.102: v4(29,116.31) 29.37,116.68 v3(29.6,116.68) ; v4(26.38,116.32) 25.61,116.32 v3(25.44,116.49)
  vias: v3(21.63,120.22) v4(16.08,122.33) v4(16.08,121.69) v4(16.08,121.06) v4(16.08,120.42) v4(16.08,119.79) v4(16.84,122.33) v4(16.84,121.69) v4(16.84,121.06) v4(16.84,120.42) v4(16.84,119.79) v4(26.38,115.58) v4(27.02,116.32) v4(27.04,115.58) v4(27.65,116.32) v4(27.7,115.58) v4(28.34,115.58) v4(28.36,116.31) v4(28.97,115.58)
+DIMM1_VREF_DQ: length 6
  TOP w0.102: CD2.1 v1(99.18,52.68)
  TOP w0.508: v2(96.15,51.64) 95.94,51.85 RD1.2 CD1.1 CD2.1
  BOTTOM w0.381: v2(96.15,51.64) 96.15,51.59 96.15,51.59 JDIMM1.1
+DIMM2_VREF_DQ: length 7
  TOP w0.508: CD33.1 v1(108.13,39.52) 107.39,38.78 107.39,38.77 107.32,38.7 v2(107.32,38.69) ; CD33.1 RD8.2 ; CD33.1 CD32.1
  BOTTOM w0.356: v2(107.32,38.69) 107.36,38.65 107.51,38.65 108.15,38.01 JDIMM2.1
+FB_PLLAVDD: length 7.6
  TOP w0.102: v2(60.82,75.32) v1(60.82,74.55)
  TOP w0.254: CV45.1 57.64,91.37 v2(57.79,91.21)
  TOP w0.508: LV26.2 60.43,76.51 60.56,76.38 CV32.1 60.95,75.45 v2(60.82,75.32) ; v2(61.33,92.87) 61.48,93.02 CV133.1 ; v2(57.78,86.25) 57.66,86.36 CV48.1
  BOTTOM w0.305: UV1.H22 57.38,91.63 v2(56.99,92.02) ; UV1.P22 57.4,86.62 v2(57.78,86.25)
  BOTTOM w0.381: UV1.F16 62.42,93.33 61.94,92.84 61.36,92.84 v2(61.33,92.87)
+FBA_VREF_CA0: length 10.1
  TOP w0.254: v2(33.8,95.56) 34.19,95.95 UV18.M8
  BOTTOM w0.102: RV139.2 v1(33.79,108.59)
  BOTTOM w0.254: UV17.M8 34.21,100.77 33.82,101.16 33.82,102.55 34.16,102.89 34.16,104.71 CV326.1
  BOTTOM w0.508: RV139.2 RV110.1 CV326.1 33.53,104.83 33.53,104.24 v2(33.33,104.04)
+FBA_VREF_CA1: length 11.2
  TOP w0.102: RV149.2 33.79,70.08 v1(34.6,69.27)
  TOP w0.203: UV19.M8 34.6,75.75 34.6,75.18 34.75,75.04 34.75,74.75 34.22,74.22 34.22,72.37 CV216.1
  TOP w0.508: v2(33.35,74.25) 32.95,73.84 32.95,72.95 33.79,72.11 CV216.1 RV142.1 RV149.2
  BOTTOM w0.254: v2(33.81,81.34) UV20.M8
+FBA_VREF_DQ0: length 7.7
  TOP w0.254: v2(37.47,104.32) 37.81,103.98 37.81,101.95 UV18.H1
  BOTTOM w0.102: RV144.2 v1(37.09,108.16)
  BOTTOM w0.254: UV17.H1 37.27,95.01 v2(37.27,94.57)
  BOTTOM w0.508: RV144.2 RV112.1 CV334.1 37.47,104.7 v2(37.47,104.32)
+FBA_VREF_DQ1: length 7.6
  TOP w0.102: v2(38.76,85.19) 38.76,85.16 v1(39.29,84.64)
  TOP w0.254: UV19.H1 37.81,82.14
  TOP w0.381: 38.03,83.08 38.03,82.36 37.81,82.14
  TOP w0.508: CV217.1 38.64,85.07 v2(38.76,85.19) ; CV217.1 38.03,83.08 ; CV217.1 RV143.1 36.58,85.07 36.5,85.14 RV150.2
  BOTTOM w0.254: v2(37.29,74.76) 37.29,74.78 37.32,74.78 37.32,75.25 UV20.H1
+GPU_CORE: length 21.8
  BOTTOM w0.254: PR617.1 45.18,51.72 47.21,53.75 52.02,53.75 52.81,54.54 52.81,58.5 52.15,59.16 52.15,60.96 52.48,61.29 53.65,61.29 53.8,61.14 54.49,61.14 55.35,62 55.35,62.05 PC613.1
  vias: v1(69.91,82.82) v2(56.19,65.97) v2(56.52,65.43) v2(56.82,65.97) v2(57.18,65.46) v2(57.51,65.94) v2(57.84,65.43) v2(58.17,65.97) v2(58.45,65.43) v2(58.68,64.85) v2(58.78,65.97) v2(59.03,65.43) v2(59.24,83.59) v2(59.29,64.87) v2(59.41,82.35) v2(59.41,65.99) v2(59.49,81.61) v2(59.63,65.41) v2(59.77,84.18) v2(59.94,64.85) v2(60.06,65.97) v2(60.27,65.41) v2(60.53,82.2) v2(60.63,85.27) v2(60.57,64.85) v2(60.7,65.97) v2(60.91,65.41) v2(61.19,64.8) v2(61.32,65.97) v2(61.45,87.15) v2(61.42,84.2) v2(61.55,88.95) v2(61.5,65.41) v2(61.57,90.38) v2(61.73,82.15) v2(61.83,64.85) v2(62.16,65.99) v2(62.18,65.41) v2(62.51,86.24) v2(62.49,64.82) v2(62.56,90.38) v2(62.59,82.36) v2(62.59,81.49) v2(62.77,65.38) v2(62.95,65.97) v2(63.15,64.82) v2(63.33,90.17) v2(63.33,82.04) v2(63.35,86.18) v2(63.4,65.38) v2(63.53,89.03) v2(63.45,87.12) v2(63.56,85.4) v2(63.58,84.1) v2(63.58,65.99) v2(64.14,65.38) v2(64.16,81.99) v2(64.19,66.63) v2(64.24,66.04) v2(64.52,84.13) v2(64.7,90.17) v2(64.77,66.6) v2(64.79,65.42) v2(65.05,82.04) v2(65.12,66.07) v2(65.42,65.42) v2(65.47,66.6) v2(65.56,85.19) v2(65.74,88.19) v2(65.69,87.1) v2(65.82,66.07) v2(65.89,82.02) v2(66.12,66.63) v2(66.07,65.48) v2(66.35,86.18) v2(66.48,90.2) v2(66.45,66.07) v2(66.6,91.04) v2(66.73,66.6) v2(66.76,82.02) v2(66.91,65.56) v2(67.49,91.98) v2(67.52,87.07) v2(67.47,85.24) v2(67.52,83.29) v2(67.52,66.4) v2(67.54,65.79) v2(67.62,89.08) v2(67.57,82.3) v2(67.92,91.24) v2(68.11,66.41) v2(68.18,65.81) v2(68.33,85.17) v2(68.51,90.32) v2(68.51,87.1) v2(68.53,82.98) v2(68.61,83.8) v2(68.61,82.35) v2(68.64,65.23) v2(68.75,66.41) v2(68.79,84.41) v2(68.77,65.83) v2(69.07,88.62) v2(69.19,85.73) v2(69.37,85.09) v2(69.45,83.06) v2(69.45,82.22) v2(69.38,66.41) v2(69.41,65.83) v2(69.73,83.87) v2(69.8,86.39) v4(54.44,68.33) v4(55.07,68.33) v4(57.13,68.33) v4(57.76,68.33) v4(59.72,68.33) v4(60.35,68.33) v4(62.31,68.33) v4(62.77,59.82) v4(62.77,59.16) v4(62.77,58.5) v4(62.77,57.86) v4(62.77,57.23) v4(62.95,68.33) v4(63.4,59.82) v4(63.4,59.16) v4(63.4,58.5) v4(63.4,57.86) v4(63.4,57.23) v4(64.98,68.35) v4(65.61,68.35) v4(65.59,59.77) v4(65.59,59.11) v4(65.59,58.45) v4(65.59,57.81) v4(65.59,57.18) v4(66.3,59.77) v4(66.3,59.11) v4(66.3,58.45) v4(66.3,57.81) v4(66.3,57.18)
+INV_PWR_SRC:
  vias: v3(1.99,79.91) v4(3.6,80.34) v4(3.6,79.71)
+LAN_IO: length 3.9
  BOTTOM w0.203: UL1.11 181.23,84.18 181.35,84.06 ; UL1.32 182.03,89.25 182.46,89.67 v2(183.02,89.67)
  BOTTOM w0.381: v2(181.8,82.58) 181.35,83.03 181.35,84.06
  vias: v2(177.42,88.96) v2(177.44,88.37) v2(183.02,89.09) v3(184.34,88.91)
+LAN_VDD: length 7.6
  TOP w0.102: v2(176.57,93.91) 176.57,94.3 v3(176.14,94.73)
  TOP w0.508: v2(183.63,85.27) 183.25,85.65 CL22.1 CL20.1 183.25,87.15 v2(183.63,87.53) ; v2(181.39,90.08) 181.09,89.79 CL26.1
  BOTTOM w0.203: v2(181.39,90.08) 181.39,89.68 181.23,89.53 UL1.30 ; v2(177.4,87.49) 177.44,87.53 UL1.22 ; v2(183.63,87.53) UL1.3
  vias: v2(177.16,93.91) v2(177.79,93.91)
+LCDVDD:
  vias: v3(14.32,86.79)
+LCDVDD_CONN: length 1.9
  TOP w0.102: LX1.2 v1(17.34,90.54)
  vias: v2(10.34,90.22) v2(10.93,90.22)
+MIC2-VREFO: length 17.9
  TOP w0.203: UA1.29 189.67,19.23 190.26,19.23 190.34,19.14 192.09,19.14 v2(192.16,19.08)
  TOP w0.254: RA1109.2 RA53.2 182.66,13.84 182.36,13.55 v2(182.36,13.5)
  IN3 w0.254: v2(192.16,19.08) 192.16,19.04 191.41,18.29 191.41,17.54 188.19,14.33 184.99,14.33 184.59,13.92 182.78,13.92 v2(182.36,13.5)
  BOTTOM w0.102: v1(192.73,19.53) 192.27,19.08 v2(192.16,19.08)
+PBATT: length 39.6
  TOP w0.254: v2(29.6,15.34) 29.48,15.23 PR723.2 28.57,15.42 27.21,15.42 24.72,17.91 24.11,17.91 23.47,18.54 v3(20.18,18.54) v2(18.67,18.54)
  IN3 w0.254: v2(39.29,13.13) 39.29,13.02 38.69,12.42 37.6,12.42 36.38,13.64 34.6,13.64 33.61,14.63 32.67,14.63 32.44,14.4 30.54,14.4 v2(29.6,15.34)
  BOTTOM w0.254: v2(39.29,13.13) 39.27,13.15 PD702.2 ; v2(18.67,18.54) 18.22,19 18.22,19.36 18.49,19.63 18.49,22.49 18.67,22.67 18.67,24.67 18.52,24.82 18.52,27.54 v4(22.53,31.55)
  vias: v4(22.53,33.07) v4(22.53,32.31) v4(23.17,32.69) v4(23.17,31.93) v4(23.17,31.17) v4(23.55,33.2) v4(23.68,32.31) v4(23.68,31.55) v4(24.57,33.07) v4(24.57,32.31) v4(24.57,31.55) v4(25.2,33.2) v4(25.2,32.44) v4(25.2,31.68) v4(25.84,32.95) v4(25.84,32.18) v4(25.84,31.42)
+PCH_VCC1P05: length 30.5
  TOP w0.254: v2(145.56,100.08) 145.52,100.08 145.55,100.05 145.55,100.04 145.98,99.61 145.98,98.33 C83.1
  TOP w0.508: L4.2 144.62,117.06 143.31,115.75 C84.1 143.76,115.31 144.26,114.8 144.29,114.8 146.23,112.86 v1(146.23,112.26) v2(146.23,109.81)
  IN2 w0.508: v2(145.56,100.08) 145.56,99.99 144.28,98.71 143.44,98.71 142.07,100.08 142.07,102.67 144.5,105.11 145.7,105.11 146.49,105.89 146.49,109.55 v2(146.23,109.81)
  BOTTOM w0.254: UC1.J18 145.92,99.81 145.65,100.08 v2(145.56,100.08) 145.44,99.96 UC1.K19
+PCH_VCCACLKPLL: length 12.6
  TOP w0.508: L5.2 139.54,113.59 C86.1 142.04,112.51 v1(142.04,111.65) RC13.2 142.55,109.73 143.36,108.92 C85.1 143.36,108.38 144.42,107.32 v2(144.61,107.32)
  BOTTOM w0.254: 144.58,107.29 144.58,105.02 UC1.A20
  BOTTOM w0.381: 144.58,107.29 v2(144.61,107.32)
+PCH_VCCDSW: length 50.3
  TOP w0.254: 145.24,85.02 145.24,85.51 145.36,85.63 145.36,85.64 145.4,85.68 145.4,87.52 145.32,87.6 145.32,88.21 144.76,88.78 144.76,89.38 v2(145.2,89.82)
  TOP w0.508: v2(159.9,70.11) 147.3,70.11 143.13,74.27 R265.1 144.3,75.64 144.3,81.87 145.24,82.81 v1(145.24,84.18) 145.24,85.02 ; C1313.2 171.63,69.4 170.06,67.83 v2(170.06,67.77)
  IN1 w0.508: v2(170.06,67.77) 169.65,68.18 163.66,68.18 161.73,70.11 v2(159.9,70.11)
  BOTTOM w0.254: UC1.AG20 144.83,90.2 v2(145.2,89.82) 145.58,90.2 UC1.AG19
+PCH_VCCDSW_R: length 2.3
  TOP w0.102: v1(142.22,73.12) R265.2
  TOP w0.508: C64.1 142.14,74.4 R265.2
+PLLVDD: length 7.2
  TOP w0.102: v1(74.76,86.88) LV8.2
  TOP w0.254: LV8.2 73.59,88.19 CV33.1 CV112.1 71.43,88 71.29,88.14 CV49.1 70.67,88.39 v2(70.21,88.85)
  BOTTOM w0.305: UV1.M6 70.72,88.34 v2(70.21,88.85)
+PWR_SRC_AC: length 0.6
  TOP w0.102: v2(32.15,45.76) v3(31.51,45.76)
+RTC_CELL_VBAT: length 13.4
  TOP w0.254: v2(146.35,12.97) 146.16,13.17 UE5.B64 ; v2(142.5,13.13) 142.5,13.01 142.02,12.52 141.2,12.52 CE65.1 140.49,13.24 139.08,13.24 138.79,13.53 v1(138.55,13.53) 138.42,13.53 138.1,13.21 138.1,12.5 136.71,11.1 RE32.2
  BOTTOM w0.254: v2(146.35,12.97) 145.76,12.97 145.37,12.58 142.88,12.58 142.5,12.96 v2(142.5,13.13)
+RTCBATT: length 3.9
  BOTTOM w0.102: v3(84.35,50.97) 84.08,51.23 RC10.2
  BOTTOM w0.508: RC10.2 83.06,50.73 82.6,50.27 JRTC.1
+RTCVCC: length 281.1
  TOP w0.254: RPE5.5 156.76,26.94 156.42,27.28 v2(156.42,27.51) 156.26,27.35 RPE5.6 ; RPE5.7 155.76,27.49
  TOP w0.508: v2(167.67,6.69) 168.01,7.04 173.66,7.04 174.43,7.8 174.43,10.39 176.22,12.18 176.99,12.18 178.41,13.61 RA5.1 ; v2(173.5,31.74) 173.5,31.74 175.06,33.3 175.06,41.46 174.36,42.15 173.25,42.15 170.74,44.67 170.74,45.52 167.49,48.77 167.49,61.78 ; C56.1 154.44,75.08 154.44,74.35 154.82,73.97 156.57,73.97 RC5.1 156.57,71.88 157.05,71.4 158.81,71.4 v2(159.01,71.6) ; C56.1 153.39,75.11 R2337.2 ; C56.1 C54.1 ; 134.6,11.1 133.74,11.97 133.74,12.25 129.8,16.18 128.91,16.18 125.62,19.47 125.62,23.08 122.14,26.56 120.25,26.56 119.84,26.96 v2(119.84,27.35) ; 134.6,11.1 RE32.1 ; 134.6,11.1 133.99,11.1 132.92,10.04 132.92,7.32 135.06,5.18 143.27,5.18 143.95,5.86 v2(143.95,5.99) RE31.1 ; 155.76,27.49 155.78,27.51 v2(156.42,27.51) 156.42,27.79 156.75,28.12 157.74,28.12 158.27,27.59 158.27,26.95 160.48,24.74 161.14,24.74 v2(161.68,25.28) 162.79,24.16 162.79,19.33 163.06,19.06 163.06,18.6 164.96,16.69 164.96,14.85 166.32,13.49 v2(167.31,13.49) ; v2(153.76,76.37) 153.76,76.23 153.98,76 C54.1 ; C54.1 C55.1 154.41,77.17 154.11,77.47 RC7.1 ; v2(168.41,65.86) 167.49,64.95 167.49,61.78 ; 167.49,61.78 v3(166.88,61.78) 160.47,61.78 RC6.1
  IN1 w0.508: v2(159.01,71.6) 158.76,71.36 158.76,69.01 159.39,68.38 161.35,68.38 163.86,65.86 v2(168.41,65.86) ; v2(153.76,76.37) 153.73,76.41 153.73,77.9 151.19,80.44 151.19,83.06 151.59,83.47 151.59,84 152.18,84.58 152.18,88.19 151.95,88.42 151.95,89.54 v2(151.87,89.62) ; v2(119.84,27.35) 118.46,28.73 105.76,28.73 99.08,35.41 97.95,35.41 91.11,42.24 91.11,47.3 88.02,50.4 v2(87.81,50.4)
  IN2 w0.508: v2(167.67,6.69) 167.42,6.95 144.91,6.95 v2(143.95,5.99)
  IN3 w0.508: v2(167.67,6.69) 168.76,7.79 168.76,12.04 v2(167.31,13.49)
  BOTTOM w0.254: v2(151.87,89.62) 151.44,89.62 150.86,90.2 UC1.AG10
  BOTTOM w0.508: v2(168.41,65.86) 168.38,65.84 RC1.1 ; v2(87.81,50.4) 87.63,50.57 87,50.57 84.83,52.75 CC26.1 DC1.1 ; v2(173.5,31.74) 173.46,31.71 173.46,26.67 172.42,25.63 168.97,25.63 167.72,24.39 162.56,24.39 v2(161.68,25.28)
+SDC_IN: length 0.8
  TOP w0.102: v2(27.73,40.57) 27.22,40.06 v3(27.22,39.96)
+SM_VREF_CA: length 25.4
  TOP w0.508: v2(125.97,85.84) 125.68,85.55 v3(125.68,80.72) 125.68,80.01 122.2,76.53 122.2,75.85 120.98,74.63 120.3,74.63 118.57,72.9 118.57,66.4 118.34,66.17 RC17.2 118.34,65.58 118.34,64.57 CC8.1
  BOTTOM w0.254: v2(125.97,85.84) 126.25,86.12 UC1.AP49
+SM_VREF_CA_DIMM: length 125
  TOP w0.508: v2(140.9,39.7) 140.9,41.35 140.09,42.17 RD4.2 ; RD10.2 151.06,30.15 v3(150.39,30.82) v2(149.53,31.68) ; RC20.1 RC17.1 119.26,66.09 119.31,66.14 RC14.2 121.81,66.65 v2(121.84,66.68)
  IN1 w0.508: v2(140.9,39.7) 140.9,40.57 142.27,41.94 151.03,41.94 153.14,39.83 153.19,39.83 153.34,39.68 ; v2(169.6,57.48) 167.36,57.48 165.03,55.15 165.03,43.61 163.2,41.79 155.61,41.79 153.65,39.83 153.5,39.83 153.34,39.68 ; 153.34,39.68 151.57,37.9 151.57,37.01 149.53,34.98 v2(149.53,31.68)
  BOTTOM w0.508: v2(121.84,66.68) 133.64,66.68 134.5,65.83 134.5,58.16 135.65,57 149.5,57 153.21,60.71 162.54,60.71 165.76,57.48 v2(169.6,57.48)
+SM_VREF_DQ0: length 25.5
  TOP w0.508: v2(124.92,85.79) 124.92,82.72 124.36,82.16 124.36,81.23 123.93,80.8 123.93,80.21 117.94,74.21 v3(117.94,73.64) 117.94,66.8 116.72,65.59 RC19.2 CC10.1
  BOTTOM w0.254: v2(124.92,85.79) 124.95,85.77 124.95,85.77 124.96,85.76 124.96,85.76 124.97,85.75 124.97,85.75 124.98,85.74 124.98,85.71 125.23,85.47 125.38,85.47 UC1.AR51
+SM_VREF_DQ0_DIMM1: length 28.2
  TOP w0.508: RC22.1 RC19.1 115.55,65.59 115.55,66.6 RC16.2 115.52,66.63 v3(112.64,66.63) 106.73,66.63 95.94,55.84 95.94,53.6 RD1.1
+SM_VREF_DQ1: length 23.3
  TOP w0.508: v2(125,86.44) 124.49,86.44 124.13,86.08 v3(124.13,84.52) 124.13,83.34 122.74,81.94 122.74,80.01 113.77,71.05 CC9.1 RC18.2
  BOTTOM w0.254: UC1.AP51 125.32,86.12 v2(125,86.44)
+SM_VREF_DQ1_DIMM2: length 51.3
  TOP w0.508: RC18.1 RC21.1 115.55,68.63 115.55,67.62 RC15.2 v3(110.57,67.62) 106.1,67.62 95.15,56.67 95.15,51.67 96.44,50.38 104.95,50.38 106.22,49.11 106.22,43.06 RD8.1
+V_DAC: length 17.7
  TOP w0.102: CL41.2 v1(187.82,92.52)
  TOP w0.508: CL41.2 188.92,90.93 v2(189.16,91.18)
  IN1 w0.508: v2(189.09,83.62) 188.46,84.25 188.46,90.48 v2(189.16,91.18)
  BOTTOM w0.508: TL2.3 188.9,82.92 189.09,83.11 v2(189.09,83.62) 189.09,83.81 188.71,84.19 TL2.4 ; TL2.10 188.52,91.81 v2(189.16,91.18) 188.52,90.54 TL2.9
+VDISPLAY_VCC: length 1.7
  BOTTOM w0.203: RX17.2 198.18,60.38 v4(198.56,60) 198.05,59.49 RX16.2
  vias: v3(198.71,58.32)
+VR_CAP: length 4.4
  TOP w0.254: CE45.1 152.3,8.3 v2(152.3,8.97) ; v2(151.77,11.3) 151.8,11.28 UE5.B12
  IN2 w0.254: v2(152.3,8.97) 152.3,9.47 151.79,9.97 151.79,11.28 v2(151.77,11.3)
-DCIN_JACK:
  vias: v3(22.13,117.41) v4(15.13,118.19) v4(15.13,117.53) v4(15.79,118.21) v4(15.79,117.58) v4(15.79,116.88) v4(15.79,116.18) v4(16.44,118.23) v4(16.44,117.59) v4(16.44,116.89) v4(16.44,116.19)
A_EM: length 5.1
  TOP w0.102: v1(170.59,15.27) 170.95,15.62 170.95,16.82 RS30.2 RS32.1 170.49,17.54 170.79,17.84 US2.9
A_EQ: length 6
  TOP w0.102: US2.17 170.79,23.42 171.23,23.85 171.84,23.85 172.55,24.56 RS25.1 173.05,24.74 173.42,25.11 RS21.2 173.42,25.58 172.48,26.53 v1(172.48,26.63)
A_EQ2: length 5.1
  TOP w0.102: US2.18 170.29,24.29 RS24.2 RS33.1 171.2,25.2 v1(171.2,26.62)
AC_DIS: length 256
  TOP w0.102: v2(27.74,56.72) 27.28,56.26 27.28,53.41 21.86,47.98 20.71,47.98 v1(20.07,47.35) 17.58,44.86 v2(17.58,42.53) 17.33,42.28 17.33,40.06 17.58,39.81 PQ708.5 ; v2(150.74,9.01) 150.74,9.16 151.05,9.46 UE5.A10
  TOP w0.254: PR741.1 41.43,13.75 PQ709.2 41.01,13.75 40.5,14.26 v2(40.5,14.4)
  IN2 w0.127: v2(40.5,14.4) 40.5,12.31 38.92,10.72 28.19,10.72 20.31,18.6 20.31,19.67 18.15,21.83 18.15,37.16 17.58,37.73 v2(17.58,42.53)
  IN3 w0.135: v2(77.07,55.5) 77.3,55.5 79.08,53.72 79.08,46.48 80.32,45.24 80.32,25.33 80.59,25.05 80.59,21.86 82.33,20.12 87.58,20.12 88.49,19.22 92.15,19.22 95.32,16.06 100.42,16.06 100.82,15.66 103.82,15.66 104.94,16.78 115.96,16.78 118.15,14.58 125.05,14.58 125.68,13.95 133.27,13.95 134.97,12.25 141.62,12.25 142.7,11.16 142.91,11.16 144.4,9.67 145.72,9.67 145.93,9.46 150.28,9.46 v2(150.74,9.01)
  BOTTOM w0.102: v2(77.07,55.5) 77.07,56.61 75.77,57.9 75.77,64.89 73.51,67.15 67.83,67.15 64.51,70.46 52.96,70.46 47.96,65.46 47.96,63.5 42.88,58.42 38,58.42 37.4,59.03 32.8,59.03 30.48,56.72 v2(27.74,56.72)
AC_PRESENT: length 129.8
  TOP w0.102: v2(150.93,88.47) 150.98,88.52 151.77,88.52 152.2,88.09 152.2,85.24 152.28,85.17 152.28,84.87 153.04,84.1 153.04,83.62 153.84,82.82 154.93,82.82 155.27,82.48 v1(157.26,82.48) v2(159.06,82.48) ; v2(143.54,16.9) 143.54,16.91 144.03,16.42 UE5.A54
  IN1 w0.114: v2(169.42,80.11) 169.85,79.68 169.85,79.3 170.68,78.48 171.05,78.48 172.67,76.85 172.67,72.57 174.46,70.78 174.46,69.91 175.11,69.26 175.11,60.34 175.99,59.47 175.99,52.42 175.74,52.18 175.74,49.76 176.13,49.38 176.13,47.82 176.18,47.77 176.18,42.69 176.13,42.64 176.13,39.43 175.19,38.49 175.19,32.07 170.36,27.24 170.36,25.73 169.52,24.89 168.02,24.89 166.45,23.33 166.45,19.75 164.23,17.53 163.82,17.53 162.77,16.47 162.77,14.99 v2(163.17,14.58)
  IN3 w0.135: v2(163.17,14.58) 160.74,14.58 159.24,13.08 158.47,13.08 157.93,13.62 156.18,13.62 154.48,11.92 153.29,11.92 152.77,12.43 150.01,12.43 148.77,13.67 145.84,13.67 144.95,14.56 144.95,15.74 144.35,16.34 144.01,16.34 143.54,16.81 v2(143.54,16.9)
  BOTTOM w0.076: 161.67,78.26 160.23,78.26 159.69,78.79 159.69,80.32 159.95,80.57 159.95,81.59 v2(159.06,82.48) ; v2(150.93,88.47) 151.21,88.47 151.55,88.81 UC1.AJ8
  BOTTOM w0.102: 161.67,78.26 163.54,78.26 164.08,78.81 167.19,78.81 RC32.2 168.38,80 169.31,80 v2(169.42,80.11)
ACAV_IN: length 138.5
  TOP w0.102: RE278.2 158.96,12.12 v2(159.03,12.04) ; v2(143.96,9.26) 144.63,9.93 144.63,10.42 144.85,10.63 UE5.A64 ; v2(41.65,11.42) 41.65,11.36 41.27,10.98 v3(41.08,10.98)
  IN1 w0.114: v2(41.65,11.42) 42.42,10.64 46.13,10.64 51.26,15.78 59.87,15.78 65.17,10.48 92.54,10.48 92.75,10.7 130.24,10.7 132.28,8.65 134.72,8.65 135.54,9.46 137.61,9.46 138.75,10.61 138.75,10.83 138.88,10.95 141.25,10.95 141.72,10.48 141.72,10.02 142.22,9.53 143.69,9.53 v2(143.96,9.26)
  BOTTOM w0.102: v2(143.96,9.26) 143.96,9.44 144.37,9.86 145.24,9.86 145.7,10.31 145.7,11.89 146.18,12.37 151.11,12.37 152.68,13.95 153.6,13.95 153.67,14.02 157.16,14.02 159.03,12.15 v2(159.03,12.04) ; v2(41.65,11.42) 41.43,11.2 38.37,11.2 37.46,12.12 PR714.1
ACAV_IN_NB: length 4.8
  TOP w0.102: UE5.B20 154.34,12.17 v2(154.16,12.35) ; RE278.1 v2(156.8,11.46)
  BOTTOM w0.102: v2(154.16,12.35) 154.21,12.4 155.25,12.4 156.14,11.51 156.75,11.51 v2(156.8,11.46)
ACDET: length 11
  TOP w0.102: PQ709.1 39.17,16.15 v1(39.41,16.39)
  TOP w0.203: PC750.2 PR740.2 35.46,13.57 v2(35.87,13.16) 36.05,13.34 PR739.2
  TOP w0.254: v2(38.69,13.15) 38.69,13.6 39.17,14.09 PQ709.1
  IN1 w0.254: v2(38.69,13.15) 38.69,12.63 38.49,12.42 37.57,12.42 36.83,13.16 v2(35.87,13.16)
  BOTTOM w0.203: PU700.6 35.7,13.32 v2(35.87,13.16)
ALERT#: length 2.3
  TOP w0.254: v2(63.38,107.6) 63.41,107.63 PU501.19
  BOTTOM w0.254: PR506.2 63.02,107.24 v2(63.38,107.6)
ALW_PWRGD_3V_5V: length 109.9
  TOP w0.102: PR110.1 v2(54.03,33.3) 54.03,33.47 v1(53.31,34.19) ; UE5.A1 145,9.72 143.67,8.38 143.59,8.38 143.2,7.99 143.2,6.87 142.75,6.43 134.83,6.43 v2(133.79,7.47)
  IN3 w0.135: v2(133.79,7.47) 133.73,7.53 126.61,7.53 125.78,8.36 125.76,8.36 124.13,9.98 117.77,9.98 113.86,13.9 105.95,13.9 104.09,12.04 96.28,12.04 95.55,12.77 94.76,12.77 93.15,14.38 88.72,14.38 87.38,15.72 81.86,15.72 79.56,18.02 77.79,18.02 74.36,21.45 65.68,21.45 60.86,26.27 60.86,26.88 58.38,29.36 57.7,29.36 57.08,29.97 57.08,30.69 56.52,31.24 55.96,31.24 54.03,33.17 v2(54.03,33.3)
ALWON: length 208.5
  TOP w0.102: v1(184.41,69.24) 184.41,68.9 183.94,68.43 v2(183.75,68.43) 183.29,68.89 R2451.1 ; v2(142.42,9.1) 142.42,9.32 142.93,9.83 142.93,10.98 143.31,11.36 143.31,11.94 144.31,12.94 144.31,13.22 144.51,13.42 UE5.A60
  IN1 w0.114: v2(183.75,68.43) 183.75,66.96 186.95,63.76 186.95,46.62 188.5,45.07 188.5,43.68 188.75,43.43 188.75,40.29 187.63,39.18 187.63,33.9 185.44,31.7 185.44,30.69 181.77,27.03 180.92,27.03 177.5,23.61 176.47,23.61 174.81,21.95 174.81,15.77 170.52,11.48 169.13,11.48 165.41,7.76 161.47,7.76 159.07,10.16 157.92,10.16 157.4,9.64 154.29,9.64 152.46,7.81 143.58,7.81 142.47,8.92 142.47,9.07 142.42,9.12 v2(142.42,9.1) 141.79,8.46 141.79,7.59 141.21,7.01 133.58,7.01 130.14,10.45 92.85,10.45 92.64,10.24 64.95,10.24 63.91,11.28 v2(62.82,11.28)
  BOTTOM w0.102: v2(62.82,11.28) 62.82,19.36 60.74,21.44 55.6,21.44 55.22,21.82 55.22,22.53 PR102.1
AUD_HP_NB_SENSE: length 132.8
  TOP w0.254: JHP.6 203.65,9.34 200.22,9.34 198.43,11.13 198.43,13.01 198.25,13.18 DA13.2 197.57,11.91 CA75.1 RA1128.1 198.06,10.53 198.06,10.05 v1(197.9,9.88) 197.79,9.78 196.73,9.78 196.37,10.14 195.46,10.14 QA7.2 195.12,9.74 v2(195.64,9.22) ; v2(93.6,19.23) 93.93,19.23 94.09,19.07 UE4.2
  IN2 w0.254: v2(106.99,11.71) 106.99,11.48 108.54,9.93 112.95,9.93 117.81,5.07 171.31,5.07 v2(172.14,5.9)
  BOTTOM w0.254: v2(93.6,19.23) 94.34,19.23 94.67,18.9 94.67,15.95 96.75,13.87 102.47,13.87 105.08,11.25 106.53,11.25 v2(106.99,11.71) ; v2(195.64,9.22) 194.72,9.22 192.33,11.61 186.26,11.61 184.79,10.14 175.59,10.14 172.14,6.68 v2(172.14,5.9)
AUD_HP_OUT_L_CN: length 14
  TOP w0.102: v2(196.24,18.6) v1(196.24,19.45)
  IN2 w0.508: JHP.1 200.36,19.74 200.14,19.53 200.14,19.52 198.84,19.52 197.64,18.33 196.51,18.33 v2(196.24,18.6)
  BOTTOM w0.381: v2(196.24,18.6) 196.24,18.54 195.99,18.29 195.99,18.05 195.64,17.69 DA10.3
  BOTTOM w0.508: LA8.1 194.19,22.37 CA39.1 194.94,20.39 194.94,18.54 194.89,18.49 DA10.3
AUD_HP_OUT_R_CN: length 28.4
  TOP w0.127: v3(197.81,18.66) 197.78,18.66 197.4,19.04 v2(196.92,19.04)
  IN1 w0.508: v2(196.92,19.04) 197.24,18.72 197.34,18.72 197.34,16.44 197.92,15.85 197.92,11.05 199.97,9.01 206.07,9.01 JHP.2
  BOTTOM w0.508: LA9.1 193.43,18.39 CA33.1 193.43,16.84 194.38,15.89 196.31,15.89 196.82,16.4 DA10.2 196.82,17.85 196.92,17.95 v2(196.92,19.04)
AUX_EN_WOWL: length 139.3
  TOP w0.102: v2(177.36,51.42) 176.92,51.87 UM1.3 ; UE4.6 94.62,17.08 94.22,17.08 93.64,17.66 93.35,17.66 93.13,17.44 93.13,16.68 92.17,15.71 92.17,13.2 v1(92.17,13.19) 92.17,12.8 v2(91.88,12.5) ; v2(178.63,48.58) 177.26,48.58 176.66,49.18 RM8.1
  IN1 w0.114: v2(91.88,12.5) 92.69,11.69 94.26,11.69 94.64,12.07 97.6,12.07 98.5,11.18 105.74,11.18 106.74,12.17 109.05,12.17 109.72,11.5 130.88,11.5 131.65,10.72 136.86,10.72 137.81,11.67 141.56,11.67 142.03,11.2 143.31,11.2 144.67,9.84 145.31,9.84 145.62,9.53 145.62,8.79 145.88,8.53 150.93,8.53 151.21,8.81 151.21,9.17 152.09,10.05 152.9,10.05 153.21,10.37 157.1,10.37 158.34,11.61 159.34,11.61 159.72,11.99 160.88,11.99 162.34,10.54 164.32,10.54 165.07,11.3 165.07,12.23 163.86,13.44 163.86,15.61 164,15.75 164.46,15.75 164.94,16.23 164.94,16.42 167.75,19.23 167.75,22.92 168.52,23.69 170.02,23.69 172.23,25.89 172.23,27.31 176.53,31.61 176.53,37.71 178.45,39.63 178.45,48.4 v2(178.63,48.58) 178.19,49.02 178.19,50.6 v2(177.36,51.42)
B+: length 1.8
  TOP w0.508: v4(16.18,72.52) 15.36,71.69 PC725.1
  vias: v2(4.43,79.62) v2(5.35,79.61) v3(38.36,109.36) v4(15.55,76.38) v4(15.55,75.75) v4(15.55,75.11) v4(15.55,74.35) v4(15.55,73.59) v4(15.55,72.95) v4(16.18,75.36) v4(16.18,74.73) v4(16.18,73.97) v4(16.18,73.21) v4(16.82,74.98) v4(16.82,74.35) v4(16.82,73.71) v4(16.82,72.95) v4(16.82,72.32) v4(23.19,22.05) v4(23.17,21.41) v4(23.85,22.05) v4(23.85,21.41) v4(25.28,22.46) v4(25.46,24.51) v4(25.46,23.75) v4(25.48,23.07) v4(25.91,22.61) v4(26.04,21.41) v4(26.22,22.02) v4(26.65,22.61) v4(26.7,21.39) v4(26.98,22.02) v4(27.28,22.61) v4(27.41,21.36) v4(27.74,21.97) v4(28,22.58) v4(28.17,21.36) v4(28.5,21.97) v4(28.71,22.58) v4(28.93,21.36) v4(29.22,21.93) v4(29.39,22.58) v4(29.7,21.36) v4(30.03,22.58) v4(29.98,21.95) v4(34.47,111.56) v4(34.47,110.92) v4(35.11,111.56) v4(35.11,110.92) v4(35.11,110.29) v4(35.74,111.56) v4(35.74,110.92) v4(35.74,110.29) v4(36.38,111.56) v4(36.38,110.92) v4(36.38,110.29) v4(37.01,111.56) v4(37.01,110.92) v4(37.01,110.29) v4(37.65,111.56) v4(37.65,110.92) v4(37.65,110.29) v4(38.28,111.56) v4(38.28,110.92) v4(38.28,110.29) v4(39.55,28.63) v4(39.55,27.61) v4(39.55,26.85) v4(39.55,26.22) v4(39.55,25.58) v4(39.55,24.95) v4(40.15,25.88) v4(40.15,25.24) v4(40.24,28.63) v4(40.19,27.99) v4(40.62,45.83) v4(40.95,46.54) v4(40.87,28.63) v4(40.87,27.99) v4(41.25,45.82) v4(75.05,40.38) v4(75.24,37.72) v4(75.65,39.83) v4(75.62,38.94) v4(75.59,38.25) v4(75.77,37.37) v4(76.1,39.37) v4(76.15,38.56) v4(76.15,37.9) v4(76.71,39.56) v4(76.71,38.93) v4(76.76,38.11) v4(76.76,37.45) v4(92.51,111.91) v4(92.51,111.24) v4(93.15,111.91) v4(93.15,111.24)
B+_1.05V: length 1.6
  BOTTOM w0.102: v1(95.85,111.95) 95.64,112.16 PC305.1
B_EM: length 5.3
  TOP w0.102: US2.8 170.29,17.97 RS35.1 RS36.2 169.14,16.82 169.14,15.99 169.02,15.86 169.02,15.28 v1(169.16,15.14)
B_EQ: length 5.1
  TOP w0.102: US2.19 169.79,22.81 169.79,24.21 169.85,24.27 RS19.2 RS38.1 169.4,25.2 169.4,26.66 v1(169.31,26.75)
BAT1_LED#: length 179.8
  TOP w0.102: JLED.5 15.55,56.35 16.44,57.25 v3(16.72,57.25) 21.64,57.25 24.16,59.77 25.76,59.77 v2(29.7,63.71) ; UE5.B1 146.3,10.96 v2(147.02,11.69)
  IN3 w0.135: v2(29.7,63.71) 29.87,63.53 35.66,63.53 38.8,60.38 43.9,60.38 50.71,67.2 63.41,67.2 63.82,67.61 72.76,67.61 76.14,64.23 76.14,57.43 79.86,53.71 79.86,46.81 81.13,45.54 81.13,36.38 89.02,28.49 89.02,27.42 94.97,21.47 94.97,20.55 97.24,18.29 111.14,18.29 111.74,18.89 118.73,18.89 119.89,17.73 126.55,17.73 127.94,16.33 138.07,16.33 139.85,14.55 142.36,14.55 142.72,14.2 144.2,14.2 144.85,13.55 144.85,12.85 145.54,12.17 146.54,12.17 v2(147.02,11.69)
BAT2_LED#: length 177.7
  TOP w0.102: UE5.A55 v2(144.12,15.92) ; v2(31.3,63.96) 30.65,63.96 22.94,56.25 17.54,56.25 v3(16.65,55.35) JLED.6
  IN3 w0.135: v2(31.3,63.96) 35.6,63.96 38.91,60.64 43.79,60.64 47.12,63.98 47.12,67.67 48.41,68.96 65.64,68.96 66.47,68.13 72.98,68.13 76.67,64.44 76.67,57.67 80.39,53.95 80.39,47.02 82.47,44.94 82.47,43.15 83.25,42.37 83.25,37.73 82.62,37.1 82.62,36.01 89.83,28.79 89.83,27.77 97.77,19.83 99.68,19.83 100.42,19.09 110.83,19.09 111.42,19.68 126.62,19.68 127.87,18.43 134.31,18.43 134.99,17.74 138.97,17.74 140.62,16.1 142.46,16.1 142.95,15.61 143.81,15.61 v2(144.12,15.92)
BAT_ALERT: length 4.3
  TOP w0.102: v2(17.32,19.87) 16.55,19.1 v1(16.23,19.1) 15.54,19.1 15.17,19.47 JBATT.3
  BOTTOM w0.102: v2(17.32,19.87) 17.45,20 PD1.2
BAT_B+:
  vias: v3(22.08,27.93) v4(21.9,27.36) v4(22.66,27.99) v4(22.66,27.36)
BATDRV#: length 20.2
  TOP w0.102: v2(27.26,13.89) 27.26,14.01 27.18,14.09 v1(27.18,14.63)
  IN3 w0.254: v2(21.26,28.12) 21.26,27.29 21.39,27.17 21.39,19.21 26.83,13.77 27.13,13.77 v2(27.26,13.89)
  BOTTOM w0.254: v2(27.26,13.89) 27.59,13.57 27.87,13.57 PR704.2 ; PQ703.4 21.9,28.76 v2(21.26,28.12)
BATT_PRS: length 5.7
  TOP w0.102: JBATT.5 16.09,21.53 v1(16.88,21.53) v2(17.58,21.53) PRP1.8
  BOTTOM w0.102: PD1.3 17.96,21.15 v2(17.58,21.53)
BBS_BIT: length 18.4
  TOP w0.102: RC119.2 166.39,98.73 165.53,97.87 161.38,97.87 161.08,97.56 156.18,97.56 155.5,96.89 v1(155.15,96.89) 154.45,96.89 154.13,97.21 154.13,97.37 153.94,97.57 153.88,97.57 153.88,97.57 152.42,97.57 151.82,98.17 v2(151.82,98.22)
  BOTTOM w0.076: UC1.L8 151.55,98.49 v2(151.82,98.22)
BC_CLK_ECE1099: length 55.4
  TOP w0.102: UE4.33 98.84,21.13 v1(99.42,21.71) 99.58,21.87 v2(99.58,22.79) ; v2(149.07,21.34) 149.05,21.31 UE5.A43
  IN3 w0.135: v2(149.07,21.34) 148.72,21.69 148.72,22 148.39,22.33 146.04,22.33 144.99,21.27 138.83,21.27 138.15,21.95 129.89,21.95 128.27,23.57 100.26,23.57 99.58,22.9 v2(99.58,22.79)
BC_CLK_ECE1117: length 95.8
  TOP w0.102: UE5.A20 156.47,12.92 v2(156.48,12.92) ; v2(83.98,21.72) 83.86,21.6 U2412.33
  IN3 w0.135: v2(156.48,12.92) 156.37,12.92 154.23,10.78 153.24,10.78 152.72,10.26 151.12,10.26 150.81,10.57 146.4,10.57 144.33,12.64 144.33,13.33 144.07,13.59 142.5,13.59 142.06,14.03 139.63,14.03 137.89,15.78 127.23,15.78 125.86,17.15 117.14,17.15 116.26,18.02 96.23,18.02 94.96,19.3 94.96,19.8 93.95,20.8 93.1,20.8 90.35,23.55 87.67,23.55 87.55,23.68 87.55,25.03 87.42,25.16 86.62,25.16 86.49,25.03 86.49,23.04 86.36,22.91 86.01,22.91 85.88,23.04 85.88,25.07 85.75,25.2 85.37,25.2 85.25,25.07 85.25,22.81 85.12,22.68 84.75,22.68 84.62,22.81 84.62,25.2 84.5,25.33 84.13,25.33 84,25.2 84,21.74 v2(83.98,21.72)
BC_DAT_ECE1099: length 59.2
  TOP w0.102: UE4.32 99.34,20.95 100.17,21.78 v2(100.17,22.76) ; v2(149.76,21.92) 149.28,22.41 RE39.2 ; UE5.B45 149.3,19.14 v2(149.33,19.1)
  IN1 w0.114: v2(149.33,19.1) 149.33,21.01 149.76,21.44 v2(149.76,21.92)
  IN3 w0.135: v2(100.17,22.76) 100.72,23.31 128,23.31 129.62,21.69 138.04,21.69 139.32,20.41 142.01,20.41 142.6,21 145.2,21 145.3,20.9 146.74,20.9 147.07,20.58 148.16,20.58 149.33,19.41 v2(149.33,19.1)
BC_DAT_ECE1117: length 137.3
  TOP w0.102: U2412.34 83.36,21.06 82.91,21.51 v2(82.91,21.74) 82.91,21.97 v1(82.44,22.44) ; v2(153.5,13.46) 154.03,12.93 154.28,12.93 154.55,12.67 UE5.B21 ; v2(156.34,23.34) 155.93,23.75 155.73,23.75 155.5,23.98 155.5,24.26 155.26,24.5 RPE5.1
  IN3 w0.135: v2(159.74,11.25) 159.74,11.18 158.91,10.34 154.9,10.34 154.56,10 153.57,10 153.05,9.48 150.79,9.48 150.54,9.73 146.04,9.73 145.84,9.93 144.51,9.93 143.01,11.42 142.82,11.42 141.74,12.51 135.22,12.51 133.48,14.25 126.37,14.25 125.56,15.06 118.06,15.06 115.94,17.19 103.65,17.19 103.05,16.59 102.53,16.59 102.33,16.79 100.66,16.79 100.18,16.32 95.42,16.32 94.17,17.57 94.17,19.47 93.86,19.79 89.34,19.79 88.14,20.99 83.67,20.99 v2(82.91,21.74)
  BOTTOM w0.102: v2(153.5,13.46) 153.52,13.46 153.85,13.79 157.06,13.79 158.25,12.61 158.25,11.77 158.43,11.58 159.41,11.58 v2(159.74,11.25) 159.74,10.45 162.27,7.93 164.22,7.93 164.44,8.15 164.44,8.44 164.93,8.92 168.89,8.92 169.27,8.54 170.34,8.54 170.95,9.15 170.95,11.33 166.35,15.93 166.35,16.55 164.86,18.04 163.98,18.04 162.88,19.13 157.48,19.13 157.15,19.46 156.77,19.46 156.62,19.61 156.62,20.32 157.08,20.78 157.08,22.61 v2(156.34,23.34)
BC_INT#_ECE1099: length 57.9
  TOP w0.102: v2(149.15,21.92) 149.55,21.53 UE5.A42 ; UE4.34 98.34,21.35 98.97,21.98 v2(98.97,22.79) 98.97,23.23 v1(99.74,23.99)
  IN3 w0.135: v2(98.97,22.79) 100.02,23.84 128.44,23.84 130.07,22.21 138.26,22.21 138.82,21.66 144.99,21.66 145.93,22.6 148.51,22.6 149.15,21.95 v2(149.15,21.92)
BC_INT#_ECE1117: length 83
  TOP w0.102: U2412.32 84.36,21.52 v2(84.56,21.72) 84.56,21.81 v1(85.13,22.38) ; v2(156.82,12.44) 156.8,12.42 UE5.A19
  IN3 w0.135: v2(84.56,21.72) 85.37,22.53 87.25,22.53 87.99,23.27 90.23,23.27 92.99,20.51 93.88,20.51 94.7,19.69 94.7,19.18 96.12,17.76 116.15,17.76 117.03,16.87 125.66,16.87 127.03,15.5 136.83,15.5 138.56,13.77 141.48,13.77 141.86,13.39 141.86,13.16 143.07,11.95 144.65,11.95 146.31,10.29 150.72,10.29 151.01,10 152.83,10 153.35,10.52 154.34,10.52 156.26,12.44 v2(156.82,12.44)
BEEP: length 25.1
  TOP w0.102: v2(153.47,12.35) 153.93,11.89 154.36,11.89 154.58,11.67 UE5.B19 ; DA8.2 170.29,8.16 169.45,8.16 v2(169.42,8.13) 168.72,8.13 v1(168.34,8.51)
  BOTTOM w0.102: v2(169.42,8.13) 168.76,7.47 161.9,7.47 157.79,11.58 157.79,12.42 156.87,13.34 155.22,13.34 154.63,12.75 153.88,12.75 v2(153.47,12.35)
BIA_PWM_EC: length 219.4
  TOP w0.102: v2(153.17,15.24) 153.67,14.73 153.93,14.73 153.98,14.79 154,14.79 154.07,14.86 154.44,14.86 154.63,14.67 UE5.B25 ; DV1.2 8.98,82.08 9.55,81.51 9.55,79.2 9.21,78.86 9.21,77.77 10.72,76.26 10.72,75.85 v1(11.08,75.49) 12.64,73.93 12.64,70.83 13.25,70.22 27.45,70.22 38.54,59.13 43.09,59.13 43.47,59.51 43.94,59.51 46.61,62.19 46.61,70.11 v2(46.49,70.23)
  IN3 w0.135: v2(46.49,70.23) 46.63,70.09 47.55,70.09 48.19,70.73 48.76,70.73 49.15,70.33 66.17,70.33 67.07,69.44 73.52,69.44 76.27,66.69 86.2,66.69 88.5,64.39 88.5,58.16 82.11,51.77 82.11,47.15 83.78,45.48 83.78,43.7 84.56,42.91 84.56,37 89.34,32.22 89.34,31.96 92.41,28.88 92.41,27.5 98.36,21.55 101.32,21.55 101.98,22.21 127.26,22.21 129.27,20.21 134.93,20.21 135.82,19.32 142.62,19.32 143.15,19.85 144.12,19.85 145.31,18.66 146.99,18.66 147.85,17.8 148.58,17.8 149.42,16.96 149.42,16.75 150.5,15.67 152.73,15.67 v2(153.17,15.24)
BKLGT_DET: length 53.1
  TOP w0.102: R2517.2 R2518.1 123.93,18.72 v2(124.01,18.8) ; v2(78.74,19.79) v1(79.17,19.36) 79.75,18.78 U2412.39
  IN1 w0.114: v2(124.01,18.8) 118.38,18.8 117.97,19.2 102.04,19.2 100.26,20.99 95.99,20.99 94.98,22 92.69,22 90.45,19.76 88.77,19.76 87.91,20.63 80.14,20.63 79.3,19.79 v2(78.74,19.79)
BKLT_PWM: length 50.6
  TOP w0.254: U2412.40 v2(80.67,18.28)
  TOP w0.508: v2(108.94,9.4) 109.61,9.4 v1(111.08,10.88) 112.63,12.42 120.8,12.42 QE11.2
  BOTTOM w0.508: v2(108.94,9.4) 108.2,10.15 104.36,10.15 102.42,12.09 95.58,12.09 94.85,11.36 83.04,11.36 81.87,12.52 81.87,17.08 v2(80.67,18.28)
BLUE: length 11.4
  TOP w0.102: 203.57,107.31 CV56.1 203.49,105.77 LV18.2 ; 203.57,107.31 DV6.2 ; 203.57,107.31 203.57,107.32 203.53,107.36 204.53,108.35 204.53,109.9 v1(205.33,110.7) 205.47,110.84 205.47,112.37 205.92,112.83 206.61,112.83 JCRT.3
BLUE_CRT: length 13.5
  TOP w0.102: LV18.1 201.56,105.02 CV53.1 RV34.1 198.3,107.23 CV60.1 197.54,108.08 v1(196.02,108.08) 194.88,108.08 v2(193.53,106.72)
  BOTTOM w0.102: v2(193.53,106.72) 193.25,106.72 192.88,107.09 UV6.8
BOARD_ID: length 7
  TOP w0.102: v1(148.61,8.23) 148.89,7.95 RE79.2
  TOP w0.254: RE79.2 150.4,7.95 ; 150.4,7.95 CE54.1 ; 150.4,7.95 150.4,8.23 150.16,8.47 149.95,8.47 149.55,8.88 v2(149.55,8.94) ; UE5.B10 150.8,10.86 150.58,11.08 v2(150.58,11.28)
  IN2 w0.254: v2(150.58,11.28) 150.58,10.72 149.55,9.69 v2(149.55,8.94)
BOOT_1.35V:
  vias: v1(61.49,32.16)
BQ24777_REGN: length 27
  TOP w0.102: v2(28.4,18.06) v1(28.4,18.84)
  TOP w0.254: v2(27.56,12.8) 27.59,12.78 28.07,12.78 PR725.1 ; v2(38.23,11.94) 37.9,11.61 PR713.1
  IN3 w0.254: v2(38.23,11.94) 38.16,11.86 37.27,11.86 37.06,12.07 35.11,12.07 34.74,12.44 27.93,12.44 v2(27.56,12.8) 28.6,13.85 28.6,17.86 v2(28.4,18.06)
  BOTTOM w0.203: 32.06,17.07 32.24,16.89 PU700.24
  BOTTOM w0.254: PR706.2 28.5,17.96 v2(28.4,18.06) 29.57,19.23 31.36,19.23 PC751.1 32.06,18.4 32.06,17.07
BREATH_LED#: length 186.5
  TOP w0.102: JLED.7 21.36,54.35 29.26,62.24 33.81,62.24 38.06,57.99 43.57,57.99 43.95,58.37 44.41,58.37 48.16,62.12 48.16,67.11 48.7,67.64 v1(48.7,68.86) 48.7,69.84 v2(48.32,70.22) ; UE5.B57 146.08,16.67 146.25,16.84 147.35,16.84 v2(147.44,16.93)
  IN3 w0.135: v2(147.44,16.93) 147.44,17.39 147.15,17.68 146.64,17.68 146.61,17.71 145.89,17.71 144.01,19.58 143.26,19.58 142.73,19.06 135.71,19.06 134.82,19.94 129.16,19.94 127.16,21.95 102.09,21.95 101.38,21.24 98.29,21.24 92.1,27.43 92.1,28.79 89.07,31.82 89.07,32.12 84.3,36.89 84.3,42.8 83.51,43.59 83.51,45.38 81.83,47.06 81.83,54.02 77.71,58.13 77.71,64.88 73.41,69.18 66.95,69.18 66.07,70.06 48.48,70.06 v2(48.32,70.22)
BST_1.05V: length 5.1
  TOP w0.102: v1(95.53,115.86) 95.37,116.03 PR303.1
  TOP w0.508: v2(95.1,120.79) 95.37,120.53 PR303.1
  vias: v2(95.13,121.43)
BST_1.35V: length 2.3
  BOTTOM w0.102: v1(61.5,34) 62.31,34 PC200.1
  BOTTOM w0.508: PC200.1 PR200.1
BST_3V: length 2
  TOP w0.102: PR103.2 50.64,31.93 50.07,32.5 50.07,32.79 v1(49.67,33.19)
BST_5V: length 1.7
  TOP w0.102: PR111.1 50.87,25.39 v1(49.7,24.22)
BST_+1.35DGPU: length 2.8
  TOP w0.254: PU1000.10 48.33,55.06 47.93,54.66
  TOP w0.508: PR1001.1 47.17,53.9 v1(47.34,54.07) 47.93,54.66
BT_RADIO_DIS#: length 139.1
  TOP w0.102: v2(189.64,47.27) v1(189.64,46.67) ; v2(97.72,10.02) 97.27,10.47 96.52,10.47 96.19,10.8 96.19,11.76 RE13.2 95.69,13.21 95.84,13.37 UE4.12
  IN1 w0.114: v2(189.64,47.27) 189.64,47 192,44.65 192,34.82 191.53,34.36 191.53,32.87 189.67,31 188.83,31 183.85,26.02 183.85,25.32 182.48,23.95 181.02,23.95 180.1,23.02 180.1,22.03 179.76,21.69 179.28,21.69 178.68,21.1 178.68,18.43 177.75,17.51 177.75,15.22 177.5,14.96 177.07,14.96 167.09,4.98 132.21,4.98 130.61,6.58 111.03,6.58 107.4,10.21 97.91,10.21 v2(97.72,10.02)
  BOTTOM w0.102: v2(189.64,47.27) 189.62,47.3 187.62,47.3 185.73,49.19 JNGFF.46
CAM_MIC_CBL_DET#: length 368.1
  TOP w0.102: RP60.5 170.57,100.24 170.4,100.08 168.92,100.08 168.26,99.42 161.5,99.42 v1(161.16,99.08) 160.56,98.48 v2(160.43,98.48)
  IN1 w0.114: v2(160.43,98.48) 163.83,95.07 170.24,95.07 172.6,92.71 172.6,87.18 174.19,85.58 175.37,85.58 176.05,84.9 176.05,74.04 180.18,69.92 180.18,68.75 180.15,68.72 180.15,62.87 181.82,61.21 181.82,57.45 182.97,56.3 182.97,46.82 182.47,46.31 182.47,41.21 178.34,37.09 178.34,31.02 173.93,26.61 173.93,25.21 171.67,22.95 171.67,19.19 168.53,16.05 168.53,14.86 167.95,14.28 166.35,14.28 165.38,13.31 165.38,11.27 164.3,10.19 163.63,10.19 v2(162.97,9.53)
  IN3 w0.135: v2(5,90.95) 4.53,90.48 3.87,90.48 2.79,89.4 2.79,79.09 13.37,68.51 18.17,68.51 21.24,65.44 21.9,65.44 26.71,60.62 35.09,60.62 37.79,57.93 44.91,57.93 46.67,59.68 53.97,59.68 56.68,62.39 71.12,62.39 73.69,59.82 73.69,56.38 76.48,53.59 76.48,52.86 77.15,52.19 77.15,51.42 76.11,50.38 76.11,46.68 78.39,44.4 78.39,24.09 77.42,23.12 77.42,19.55 78.15,18.82 80.83,18.82 83.05,16.6 88.18,16.6 89.62,15.17 93.47,15.17 94.97,13.67 104.58,13.67 105.6,14.7 114.22,14.7 117.66,11.25 129.82,11.25 131.32,9.76 133.23,9.76 135.98,7 141.32,7 141.52,7.21 155.16,7.21 155.43,7.48 161.64,7.48 162.97,8.82 v2(162.97,9.53)
  BOTTOM w0.076: UC1.F4 154.19,101.33 153.88,101.02 153.88,99.8 154.06,99.62 154.33,99.62 154.49,99.47 154.49,99.24 154.91,98.82 158.33,98.82 158.58,99.06 159.85,99.06 v2(160.43,98.48)
  BOTTOM w0.102: v2(5,90.95) 4.5,90.45 JEDP.20
CAP_LED#: length 28.1
  TOP w0.102: v2(93.68,21.57) 93.68,21.77 97.55,25.64 v1(97.68,25.64) 97.98,25.95 Q327.3 ; U2412.41 79.76,17.78 78.29,19.26 v2(78.29,19.31)
  IN1 w0.114: v2(78.29,19.31) 79.23,19.31 80.27,20.35 87.74,20.35 88.56,19.52 90.57,19.52 92.62,21.57 v2(93.68,21.57)
CAPS_LED: length 18
  TOP w0.102: JKB.4 92.65,48.3 93.02,47.93 93.02,45.61 97.43,41.2 v3(97.43,34.43) 98.23,33.63 R944.2
CBL_LOOP_BACK: length 3.6
  TOP w0.102: v2(4.69,83.62) 4.42,83.62 RX29.1 4.46,84.05 v1(5.03,84.62)
  BOTTOM w0.102: JEDP.6 4.52,83.45 v2(4.69,83.62)
CFD_PWRBTN#_XDP: length 5.7
  TOP w0.102: v1(96.11,78.12) 95.98,78.12 95.58,77.73 94.17,77.73 RC49.2 93.71,77.29 92.33,78.66 JXDP.41
CFG0: length 51.9
  TOP w0.102: JXDP.9 92.69,70.66 92.99,70.36 95.18,70.36 96.45,71.62 96.45,72.87 95.64,73.69 v2(95.64,73.87) ; RC183.1 107.87,91.3 114.52,91.3 114.61,91.39 v1(115.21,91.39) 115.79,91.39 116.19,91.79 v2(116.19,91.84)
  IN3 w0.135: v2(95.64,73.87) 95.64,73.92 101.27,79.56 101.27,84.36 105.2,88.29 110.07,88.29 112.36,90.58 113.9,90.58 114.13,90.81 115.15,90.81 v2(116.19,91.84)
  BOTTOM w0.076: v2(116.19,91.84) 116.55,92.2 117,92.2 117.1,92.1 117.7,92.1 117.87,92.27 118.65,92.27 118.69,92.23 119.17,92.23 UC1.AC60
CFG1: length 42.8
  TOP w0.102: JXDP.11 92.67,71.16 93.2,70.64 94,70.64 v1(94.57,71.22) 95.33,71.97 95.33,73.42 94.42,74.34 v2(94.42,74.35)
  IN3 w0.135: v2(115.53,91.83) 114.78,91.09 113.95,91.09 113.72,90.86 112.27,90.86 109.96,88.55 105.09,88.55 102.88,86.34 100.41,86.34 99.83,85.75 99.83,81.07 98.66,79.9 98.66,77.89 95.5,74.73 94.8,74.73 v2(94.42,74.35)
  BOTTOM w0.076: v2(115.53,91.83) 116.07,92.37 117.07,92.37 117.17,92.27 117.63,92.27 117.92,92.56 UC1.AC62
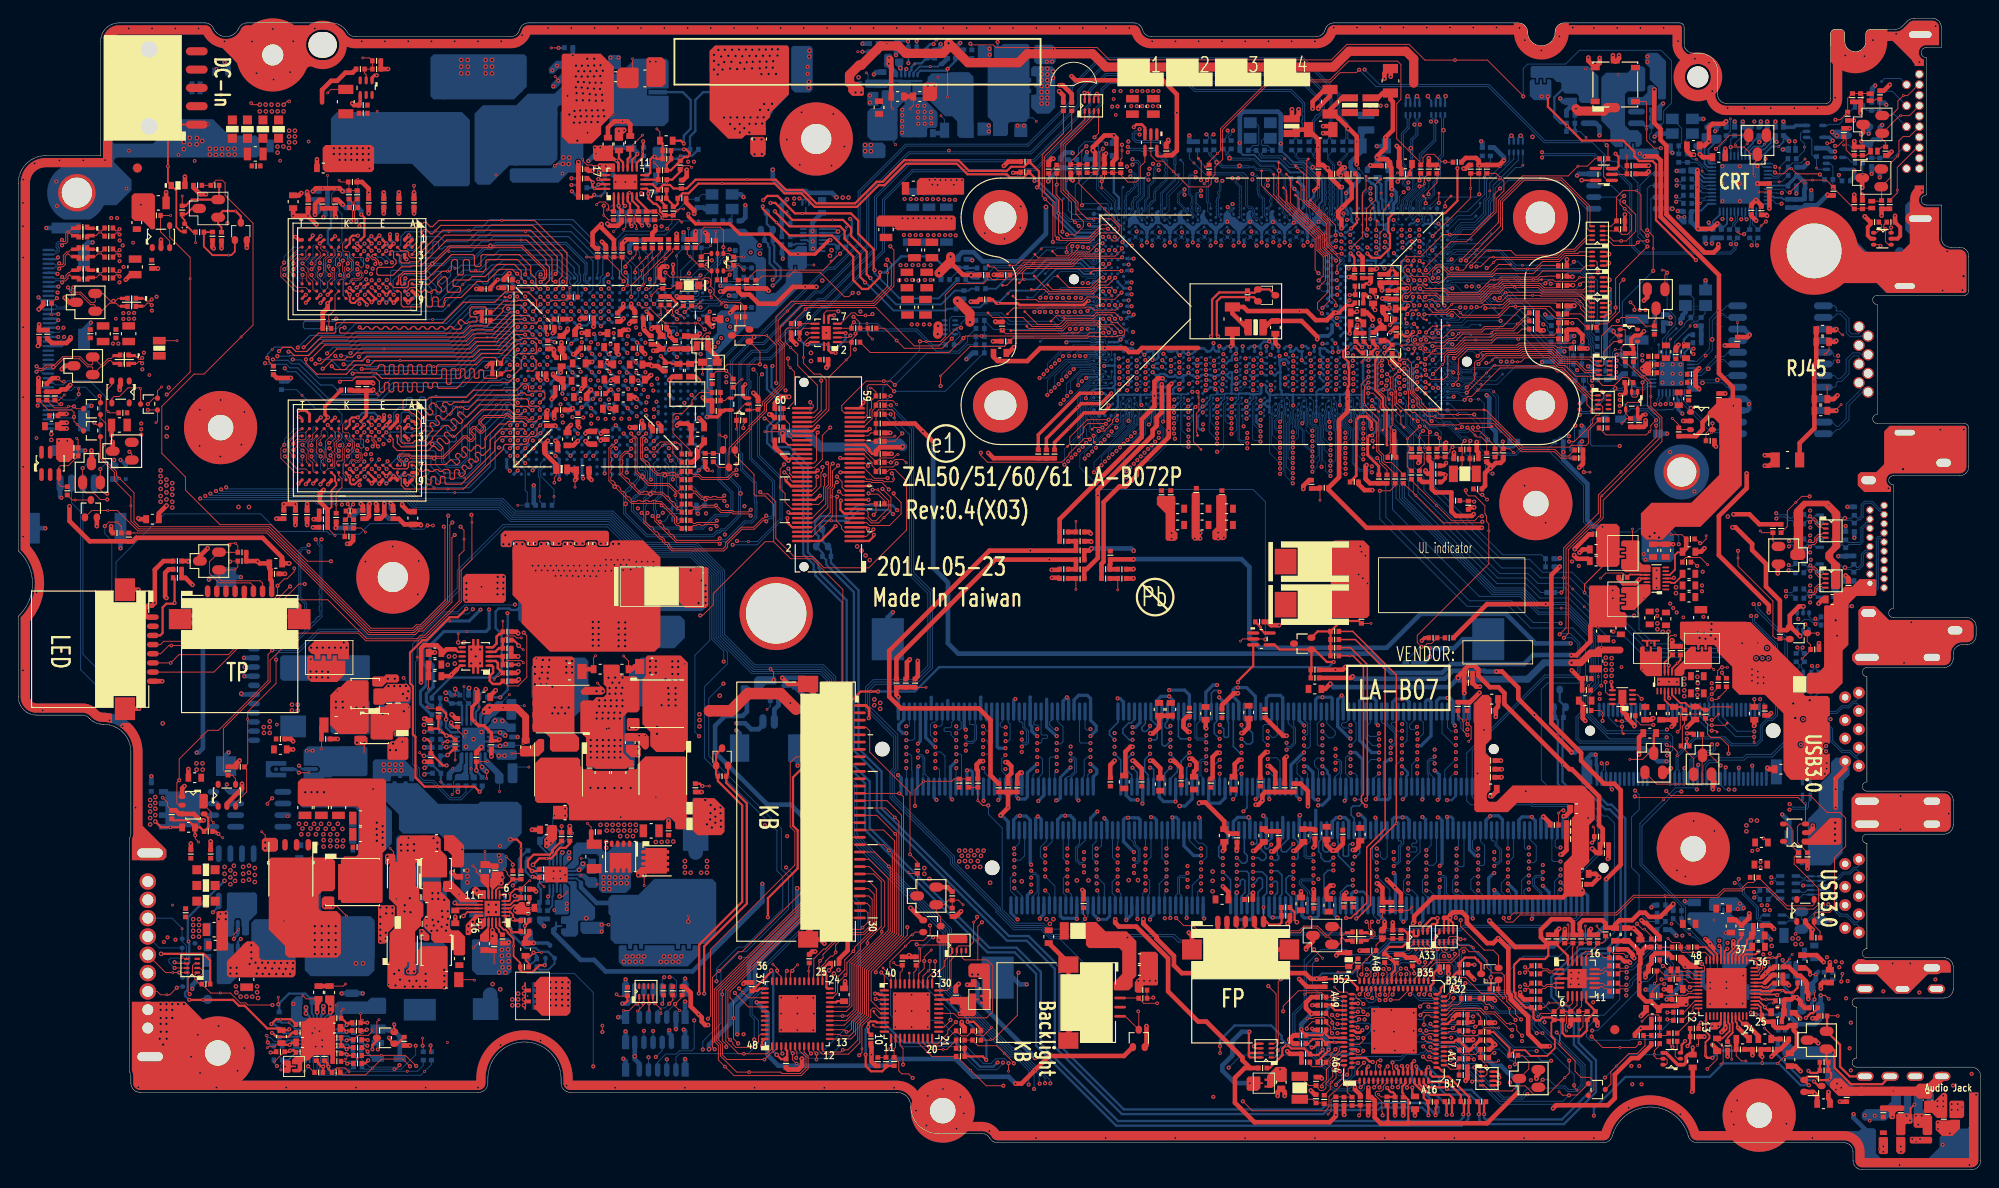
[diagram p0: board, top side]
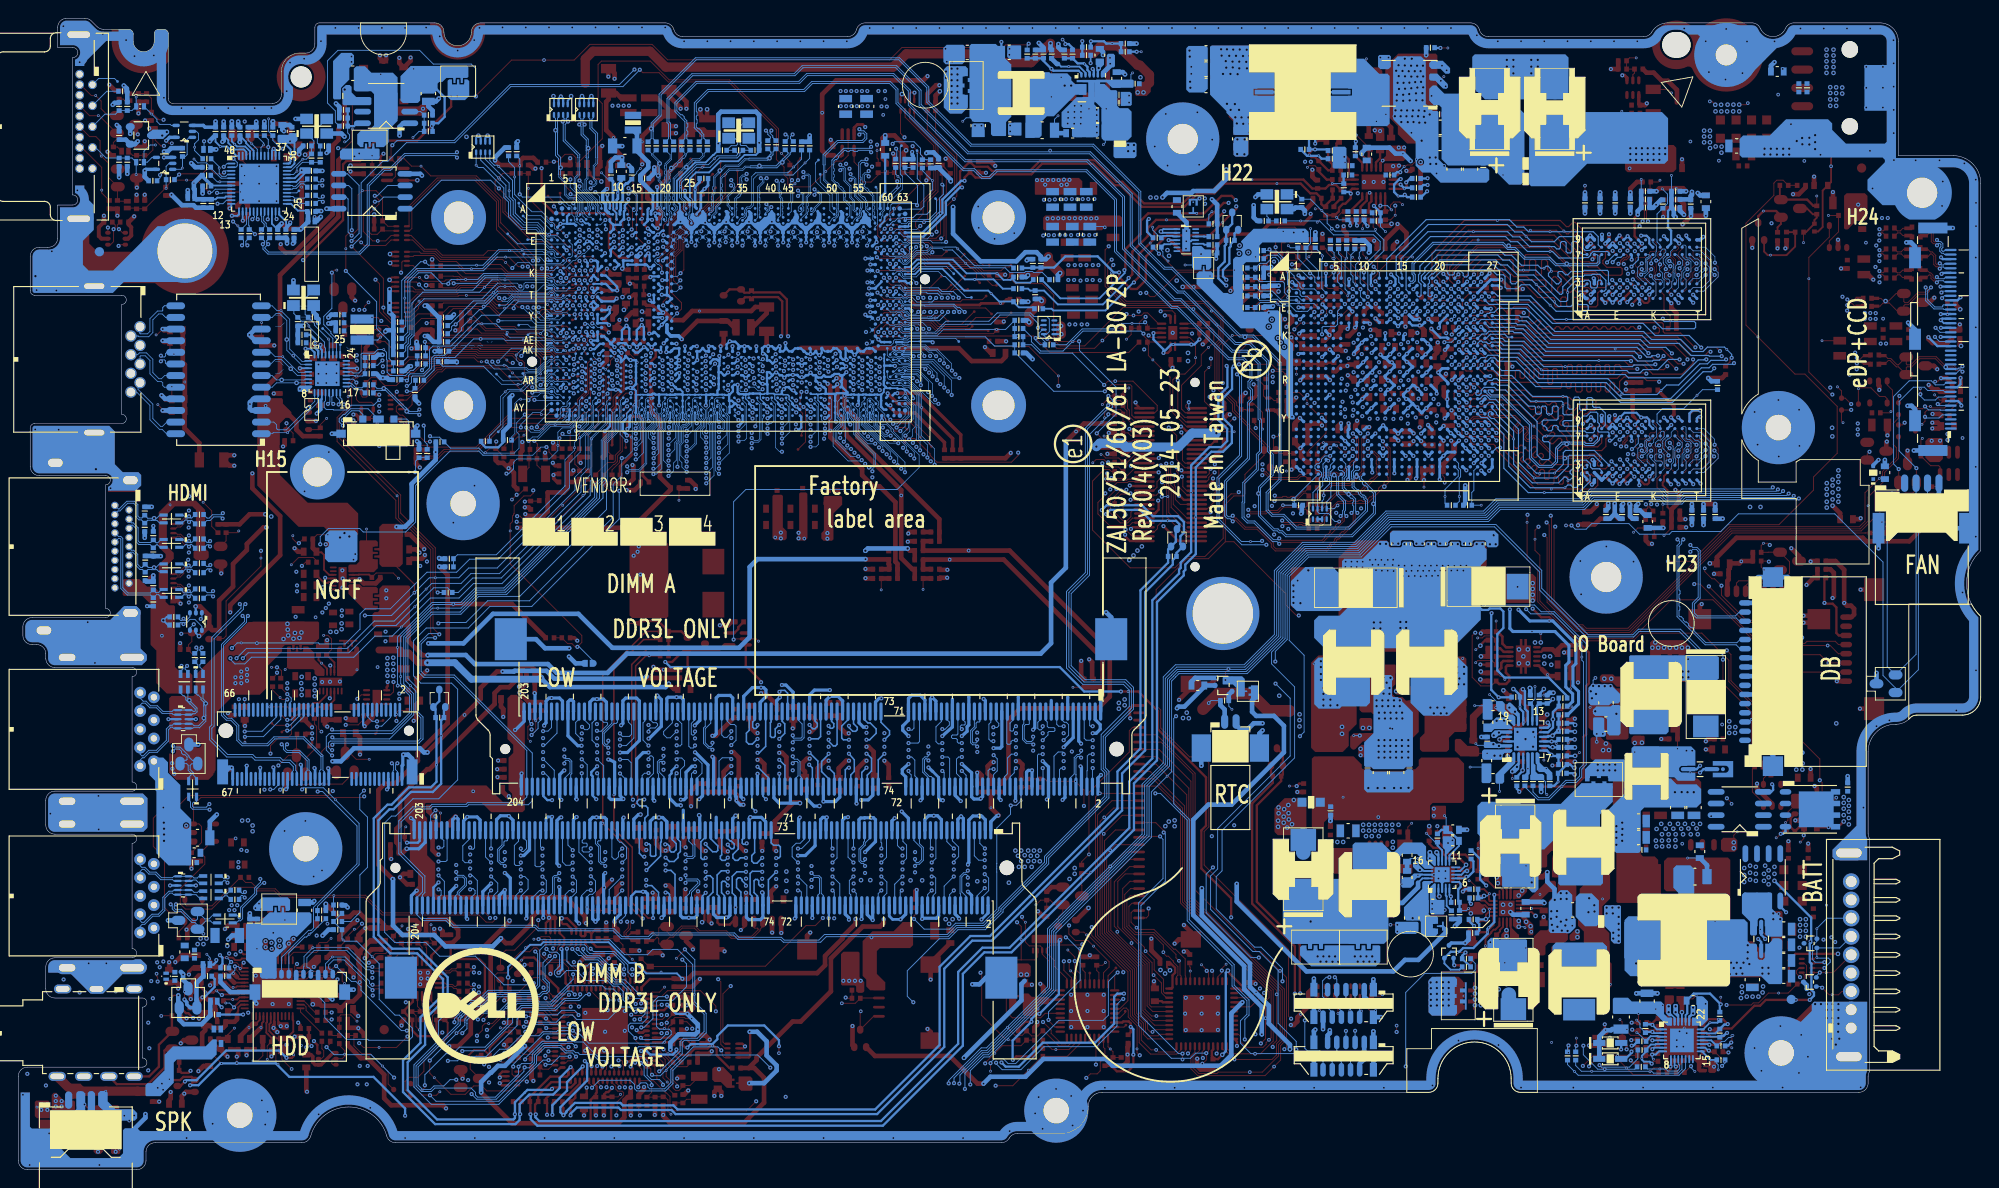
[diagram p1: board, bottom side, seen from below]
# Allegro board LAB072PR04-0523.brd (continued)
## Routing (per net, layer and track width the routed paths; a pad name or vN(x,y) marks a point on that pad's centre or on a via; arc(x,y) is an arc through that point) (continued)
CFG2: length 44
  TOP w0.102: JXDP.15 92.49,72.16 92.84,71.81 92.84,71.32 93.29,70.87 93.69,70.87 95.1,72.28 95.1,73.05 v1(93.9,74.26) v2(93.34,74.26)
  IN3 w0.135: v2(93.34,74.26) 94.09,75.01 95.41,75.01 98.4,78 98.4,80.01 99.5,81.11 99.5,85.98 100.28,86.77 102.9,86.77 104.96,88.83 109.86,88.83 112.17,91.14 113.57,91.14 113.85,91.42 114.48,91.42 v2(114.89,91.83)
  BOTTOM w0.076: v2(114.89,91.83) 115.6,92.54 117.49,92.54 UC1.AC63
CFG3: length 45.3
  TOP w0.102: v2(93.45,71.53) 93.71,71.78 RC56.2 93.02,72.73 92.96,72.66 JXDP.17
  IN3 w0.135: v2(114.12,93.69) 112.76,92.33 111.54,92.33 109.81,90.6 107.24,90.6 106.66,90.02 106.2,90.02 105.97,90.25 104.42,90.25 103.71,89.54 102.87,89.54 101.48,88.14 99.88,88.14 97.95,86.21 97.95,83.29 96.07,81.41 95.08,81.41 91.83,78.16 91.83,73.15 v2(93.45,71.53)
  BOTTOM w0.076: UC1.AA63 117.38,93.18 117.2,93.18 117.13,93.11 115.1,93.11 115.08,93.14 114.82,93.14
  BOTTOM w0.102: 114.82,93.14 114.68,93.14 v2(114.12,93.69)
CFG3_R: length 17.8
  TOP w0.102: v2(86.52,83.82) 86.85,83.49 86.85,83.29 86.72,83.16 JXDP.60 ; v2(92.89,73.87) 92.97,73.79 93.91,73.79 94.62,73.08 RC56.1
  IN1 w0.114: v2(92.89,73.87) 92.31,74.45 92.31,78.13 86.62,83.82 v2(86.52,83.82)
  BOTTOM w0.102: v2(86.52,83.82) v1(86.52,83.06)
CFG4: length 44.2
  TOP w0.102: JXDP.27 93.12,75.16 93.22,75.06 94.34,75.06 v2(95.1,74.3) ; v2(100.77,85.6) v1(100.77,86.69) 103.99,89.92 107.73,89.92 108.28,90.48 RC191.1 108.68,90.82 116.78,90.82 116.94,90.98 119.97,90.98 120.07,91.09 120.65,91.09 120.86,91.3 120.86,91.72 120.07,92.51 119.54,92.51 119.38,92.66 119.38,92.69 119.16,92.91 v2(119.16,92.93)
  IN3 w0.135: v2(95.1,74.3) 95.44,74.3 98.92,77.78 98.92,79.8 100.77,81.64 v2(100.77,85.6)
  BOTTOM w0.076: v2(119.16,92.93) 119.46,93.23 UC1.AA60
CFG5: length 39.9
  TOP w0.102: v2(95.43,76.05) 95.64,75.85 v1(95.64,75.44) 95.64,75.25 95.52,75.14 94.59,75.14 94.43,75.29 93.32,75.29 93.19,75.41 92.69,75.41 92.44,75.66 JXDP.29
  IN3 w0.135: v2(116.07,93.69) 115.21,92.84 114.3,92.84 113.19,91.72 111.89,91.72 109.58,89.41 104.55,89.41 104.12,88.98 103.13,88.98 101.68,87.53 100.16,87.53 98.84,86.21 98.84,82.63 97.67,81.46 97.67,78.13 95.58,76.05 v2(95.43,76.05)
  BOTTOM w0.076: UC1.Y62 117.92,94.06 117.63,93.77 117.32,93.77 117,93.44 116.32,93.44 v2(116.07,93.69)
CFG6: length 40.8
  TOP w0.102: v1(117.83,94.3) 117.97,94.43 v2(118.51,94.43) ; v2(94.97,75.54) 94.95,75.52 93.53,75.52 92.38,76.66 JXDP.33
  IN3 w0.135: v2(118.51,94.43) 116.58,92.5 114.44,92.5 113.39,91.44 112.02,91.44 109.71,89.13 104.88,89.13 102.85,87.1 100.18,87.1 99.17,86.08 99.17,82.55 98.14,81.53 98.14,78.1 95.58,75.54 v2(94.97,75.54)
  BOTTOM w0.076: v2(118.51,94.43) 118.51,94.34 118.81,94.04 UC1.Y61
CFG7: length 38.8
  TOP w0.102: JXDP.35 92.54,77.16 v2(92.84,76.86)
  IN3 w0.135: v2(92.84,76.86) 92.94,76.96 92.94,78.87 95.15,81.08 96.24,81.08 98.28,83.11 98.28,86.06 100.08,87.86 101.63,87.86 103.03,89.26 103.8,89.26 104.53,89.99 105.86,89.99 106.09,89.76 106.77,89.76 107.35,90.34 109.95,90.34 111.64,92.03 113.01,92.03 114.1,93.12 114.84,93.12 v2(115.42,93.69)
  BOTTOM w0.076: UC1.Y60 119.12,93.68 118.55,93.68 118.46,93.77 117.87,93.77 117.7,93.6 117.39,93.6 117.13,93.34 117.13,93.34 117.06,93.28 115.84,93.28 v2(115.42,93.69)
CFG8: length 47.3
  TOP w0.102: v2(88.98,77.12) 88.73,76.86 88.73,74.7 88.45,74.42 88.45,72.34 86.77,70.66 JXDP.10
  IN3 w0.135: v2(88.98,77.12) 89.08,77.22 89.08,78.77 89.74,79.43 90.86,79.43 94.37,82.93 95.66,82.93 96.75,84.03 96.75,86.34 99.57,89.16 101.05,89.16 102.29,90.4 103.46,90.4 104.09,91.04 105.64,91.04 106.18,91.57 109.5,91.57 111.59,93.65 v2(111.59,93.68)
  BOTTOM w0.076: 115.37,94.33 115.4,94.35 117.7,94.35 117.97,94.62 UC1.V62
  BOTTOM w0.102: v2(111.59,93.68) 112.23,94.32 115.37,94.32 115.37,94.33
CFG9: length 47.8
  TOP w0.102: JXDP.12 86.71,71.16 88.22,72.67 88.22,74.51 88.5,74.79 88.5,77.04 v2(88.37,77.17)
  IN3 w0.135: v2(88.37,77.17) 88.31,77.23 88.31,78.37 89.64,79.71 90.61,79.71 94.9,84 95.91,84 96.32,84.41 96.32,86.28 99.58,89.54 100.16,89.54 101.88,91.26 103.95,91.26 104,91.32 105.47,91.32 106.05,91.9 109.22,91.9 v2(111,93.68)
  BOTTOM w0.076: UC1.V61 118.56,95.1 118.04,95.1 117.8,94.86 117.8,94.69 117.63,94.52 114.84,94.52
  BOTTOM w0.102: v2(111,93.68) 111.05,93.68 111.56,94.19 111.82,94.19 112.16,94.52 114.84,94.52
CFG10: length 53.9
  TOP w0.102: v2(83.67,77.04) 83.67,76.96 83.24,76.53 v1(83.24,74.61) 83.24,74.37 83.77,73.84 83.77,72.9 84.51,72.16 JXDP.16
  IN3 w0.135: v2(83.67,77.04) 83.72,76.99 84.43,76.99 87.94,80.49 87.94,82.13 93.52,87.72 93.52,90.32 97,93.81 102.97,93.81 103.25,94.09 105.4,94.09 105.78,94.47 108.93,94.47 110.64,96.18 113.22,96.18 113.67,95.73 116.87,95.73 117.43,95.18 118.42,95.18 v2(119.16,94.43)
  BOTTOM w0.076: UC1.V60 119.46,94.73 v2(119.16,94.43)
CFG11: length 53.3
  TOP w0.102: v2(88.09,75.85) 88.09,74.71 87.99,74.61 87.99,73.21 87.45,72.66 JXDP.18
  IN3 w0.135: v2(88.09,75.85) 87.51,75.26 87,75.26 86.26,76 86.26,77.5 89.36,80.6 90.28,80.6 93.35,83.67 93.35,85.55 94.77,86.97 94.77,90.09 97.45,92.76 103.41,92.76 103.69,93.04 105.83,93.04 106.21,93.42 109.38,93.42 110.72,94.77 113.76,94.77 114.13,95.13 v2(114.13,95.21)
  BOTTOM w0.076: 114.82,94.76 114.92,94.76 114.93,94.75 116.23,94.75 116.76,95.28 117.14,95.28 117.32,95.1 117.7,95.1 117.87,95.27 118.65,95.27 118.69,95.23 119.17,95.23 UC1.U60
  BOTTOM w0.102: v2(114.13,95.21) 114.14,95.21 114.59,94.76 114.82,94.76
CFG12: length 47.7
  TOP w0.102: JXDP.28 84.56,75.16 84.33,75.39 84.33,75.62 83.8,76.15 v2(83.7,76.15)
  IN3 w0.135: v2(83.7,76.15) 83.73,76.13 84.46,76.13 89.23,80.9 90.2,80.9 93.02,83.72 93.02,85.75 94.47,87.2 94.47,90.16 97.33,93.02 103.3,93.02 103.58,93.3 105.72,93.3 106.1,93.69 109.26,93.69 110.77,95.2 111.64,95.2 v2(111.66,95.22)
  BOTTOM w0.076: UC1.T63 114.86,96.31
  BOTTOM w0.102: 114.86,96.31 113.87,96.31 113.47,95.91 112.25,95.91 111.66,95.33 v2(111.66,95.22)
CFG13: length 47.6
  TOP w0.102: JXDP.30 84.64,75.66 84.28,76.02 84.28,76.41 v2(84.13,76.56)
  IN3 w0.135: v2(113.49,95.23) 113.49,95.48 113.05,95.92 110.75,95.92 109.04,94.21 105.89,94.21 105.51,93.83 103.36,93.83 103.08,93.55 97.11,93.55 93.78,90.22 93.78,87.61 88.27,82.1 88.27,80.32 85.27,77.32 85.27,77.31 84.53,76.56 v2(84.13,76.56)
  BOTTOM w0.076: 115.21,95.84 117.4,95.84 117.69,95.84 UC1.T62
  BOTTOM w0.102: v2(113.49,95.23) 113.97,95.72 115.09,95.72 115.21,95.84
CFG14: length 45.8
  TOP w0.102: v2(88.7,81.05) 87.84,80.19 87.84,77.55 86.95,76.66 JXDP.34
  IN3 w0.135: v2(88.7,81.05) 88.7,81.94 94.11,87.35 94.11,90.18 97.22,93.29 103.19,93.29 103.47,93.57 105.61,93.57 106,93.95 109.15,93.95 110.86,95.66 112.02,95.66 112.26,95.41 v2(112.26,95.24)
  BOTTOM w0.076: UC1.T61 118.56,96.6 118.04,96.6 117.8,96.36 117.8,96.2 117.62,96.01 114.91,96.01
  BOTTOM w0.102: v2(112.26,95.24) 112.68,95.66 113.54,95.66 113.9,96.01 114.91,96.01
CFG15: length 47.7
  TOP w0.102: v2(119.16,95.93) 119.16,95.77 v1(119.5,95.43) ; v2(87.33,80.52) 87.2,80.39 87.2,77.45 86.92,77.16 JXDP.36
  IN3 w0.135: v2(87.33,80.52) 86.9,80.95 86.9,81.46 93.26,87.82 93.26,90.43 96.9,94.07 102.87,94.07 103.14,94.35 105.29,94.35 105.67,94.73 108.78,94.73 110.49,96.44 113.34,96.44 113.69,96.1 116.94,96.1 117.58,95.46 118.67,95.46 119.15,95.93 v2(119.16,95.93)
  BOTTOM w0.076: v2(119.16,95.93) 119.46,96.23 UC1.T60
CFG16: length 47.2
  TOP w0.102: JXDP.6 86.61,69.66 88.7,71.76 88.7,74.35 88.96,74.6 88.96,76.3 v2(89.56,76.91)
  IN3 w0.135: v2(112.82,93.68) 112.05,92.92 111.31,92.92 109.68,91.29 106.27,91.29 105.75,90.77 104.2,90.77 103.55,90.12 102.49,90.12 101.15,88.78 99.65,88.78 97.26,86.39 97.26,83.67 95.64,82.04 94.82,82.04 89.69,76.91 v2(89.56,76.91)
  BOTTOM w0.076: 114.82,92.73 117.23,92.73 117.34,92.84 117.75,92.84 118.08,93.17 118.08,93.23 118.1,93.25 118.1,93.25 UC1.AA62
  BOTTOM w0.102: v2(112.82,93.68) 113.77,92.73 114.82,92.73
CFG17: length 48.4
  TOP w0.102: v2(89.44,75.08) 89.18,74.83 89.18,74.51 88.93,74.25 88.93,71.3 86.79,69.16 JXDP.4
  IN3 w0.135: v2(89.44,75.08) 91.56,77.21 91.56,78.3 95,81.74 95.86,81.74 97.59,83.47 97.59,86.26 99.8,88.47 101.3,88.47 102.65,89.82 103.61,89.82 104.31,90.51 105.88,90.51 106.35,90.99 109.78,90.99 111.41,92.61 112.39,92.61 v2(113.47,93.69)
  BOTTOM w0.076: UC1.AA61 118.61,93.35 118.36,93.6 118.04,93.6 117.87,93.43 117.87,93.19 117.68,93.01 117.27,93.01 117.21,92.95 115,92.95
  BOTTOM w0.102: v2(113.47,93.69) 113.47,93.56 113.99,93.03 113.99,93.03 v1(114.23,93.03) 114.49,93.03 114.58,92.95 115,92.95
CFG18: length 44.5
  TOP w0.102: JXDP.24 86.74,74.16 87.18,74.6 87.18,75.59 v2(87.28,75.69)
  IN3 w0.135: v2(115.51,95.23) 115.55,95.23 115.55,95.21 114.78,94.44 110.77,94.44 109.43,93.09 106.25,93.09 105.08,91.92 103.64,91.92 103.1,92.46 102.34,92.46 99.94,90.06 99.03,90.06 93.76,84.79 93.76,83.7 90.35,80.29 89.46,80.29 86.72,77.55 86.72,76.18 87.2,75.69 v2(87.28,75.69)
  BOTTOM w0.076: UC1.U63 117.42,95.65 115.99,95.65 115.74,95.39 115.68,95.39 v2(115.51,95.23)
CFG19: length 44.7
  TOP w0.102: JXDP.22 86.7,73.66 87.69,74.65 87.69,76.1 87.86,76.28 v2(87.86,76.74)
  IN3 w0.135: v2(87.86,76.74) 87.61,76.99 87.61,78.06 89.54,79.99 90.5,79.99 94.19,83.67 94.19,84.76 99.22,89.8 100.05,89.8 101.78,91.53 103.84,91.53 103.89,91.58 105.29,91.58 105.92,92.2 108.92,92.2 110.85,94.13 115.02,94.13 v2(116.1,95.21)
  BOTTOM w0.076: UC1.U62 117.92,95.56 117.8,95.43 117.8,95.43 117.63,95.27 117.39,95.27 117.18,95.48 116.37,95.48 v2(116.1,95.21)
CFG_RCOMP: length 11.9
  TOP w0.305: RC132.1 106.43,95.05 106.86,94.62 v1(107.08,94.62) 109.2,94.62 109.38,94.44 116.39,94.44 116.84,94.89 v2(116.93,94.89)
  BOTTOM w0.076: UC1.V63 117.02,94.81 v2(116.93,94.89)
CHAGER_SRC:
  vias: v3(38.76,41.57) v4(31.35,41.23) v4(32.03,41.23) v4(32.67,41.24) v4(33.41,41.23) v4(39.15,37.21) v4(39.17,37.9) v4(39.17,36.58) v4(39.17,35.92) v4(39.81,37.52) v4(39.81,36.88) v4(39.81,36.25) v4(39.81,35.49)
CHARGER_SMBCLK: length 122.4
  TOP w0.102: v2(45.04,13.57) v1(45.04,12.78) ; v2(153.29,24.11) 152.95,24.45 RPE3.2 ; v2(146.54,19.15) 146.8,19.41 UE5.B50
  IN1 w0.114: v2(146.54,19.15) 146.37,19.15 144.99,20.54 142.88,20.54 142.24,19.9 139.69,19.9 138.95,19.17 137.22,19.17 136.99,19.4 135.23,19.4 134.72,19.9 130.75,19.9 129.42,21.24 110.42,21.24 110.24,21.06 107.76,21.06 107.04,21.77 101.74,21.77 100.29,23.22 99.45,23.22 98.97,23.7 97.67,23.7 97.44,23.93 89.52,23.93 88.28,22.68 79.41,22.68 78.16,21.44 74.35,21.44 72.59,19.69 62.08,19.69 60.79,20.98 55.6,20.98 52.19,17.57 50.66,17.57 46.66,13.57 v2(45.04,13.57)
  BOTTOM w0.102: v2(153.29,24.11) 152.81,23.62 152.8,23.62 152.32,23.14 150.97,23.14 150.17,22.34 150.17,21.74 149.16,20.73 148.12,20.73 v2(146.54,19.15) ; v2(45.04,13.57) 45.14,13.46 PR721.1
CHARGER_SMBDAT: length 121
  TOP w0.102: v2(151.87,24.13) 152.46,24.72 RPE3.1 ; v2(147.32,21.29) 147.05,21.01 UE5.A47 ; v2(44.17,13.54) v1(44.17,14.37)
  IN1 w0.114: v2(147.32,21.29) 146.7,20.67 145.91,20.67 145.32,21.26 139.78,21.26 138.42,19.9 137.51,19.9 136.94,20.47 131.32,20.47 129.77,22.02 101.83,22.02 100.39,23.46 99.55,23.46 99.07,23.94 97.77,23.94 97.54,24.17 89.42,24.17 88.18,22.93 79.31,22.93 78.06,21.68 74.25,21.68 72.49,19.93 62.34,19.93 60.93,21.33 55.61,21.33 52.09,17.81 50.56,17.81 46.75,14 44.63,14 v2(44.17,13.54)
  BOTTOM w0.102: v2(151.87,24.13) 151.57,23.83 149.29,23.83 147.81,22.35 147.81,21.59 147.5,21.29 v2(147.32,21.29) ; v2(44.17,13.54) 44.25,13.46 PR719.1
CHG_BTS: length 4.4
  TOP w0.102: PR712.1 31.45,18.66 v1(31.09,19.01)
  TOP w0.508: PR712.1 32.8,18.28 32.64,18.13 v4(32.64,17.2)
  BOTTOM w0.203: PU700.25 v4(32.64,17.2)
CHG_BTS_C: length 3.1
  TOP w0.102: PC712.1 35.53,20.06 v1(35.75,20.28)
  TOP w0.508: PC712.1 PR712.2
CHG_LGATE: length 19.3
  TOP w0.102: v1(26.6,36.91) 26.98,36.53 v4(26.98,35.74)
  TOP w0.203: v4(31.42,17.71) v4(31.42,17.07)
  IN3 w1.016: 27.61,34.14 27.61,26.96 30.92,23.65 30.92,18.87
  BOTTOM w0.203: 31.84,16.78 PU700.23 ; v4(31.42,17.07) 31.55,17.07
  vias: v4(26.98,35.11)
CHG_SNUB: length 3.7
  BOTTOM w0.102: v1(32.02,34.04) PC722.1
  BOTTOM w0.508: PC722.1 29.9,33.25 PR711.1
CHG_SW: length 4.9
  TOP w0.203: v4(34.09,17.2) v4(34.09,17.83)
  IN1 w1.016: 35.98,22.16 34.35,20.53 34.35,18.98
  BOTTOM w0.203: 34.07,17.2 v4(34.09,17.2) ; PU700.27 33.44,16.55
  vias: v1(29.02,27.15) v4(32.39,26.6) v4(32.39,25.83) v4(32.39,25.07) v4(32.39,24.31) v4(32.39,23.55) v4(33.15,26.6) v4(33.15,25.83) v4(33.15,25.07) v4(33.15,24.31) v4(33.15,23.55) v4(33.91,26.6) v4(33.91,25.83) v4(33.91,25.07) v4(33.91,24.31) v4(33.91,23.55) v4(34.68,26.6) v4(34.68,25.83) v4(34.68,25.07) v4(34.68,24.31) v4(34.68,23.55) v4(36.89,22.53) v4(37.65,22.53)
CHG_UGATE: length 14.5
  TOP w0.102: v1(35.87,27.7) 34.82,28.76 v4(34.35,28.76)
  TOP w0.203: v4(33.33,17.2) v4(33.33,17.83)
  IN3 w1.016: 34.95,28.04 36,27 36,23.04 33.46,20.5 33.4,20.5 33.4,18.84
  BOTTOM w0.203: v4(33.33,17.2) 33.04,16.91 PU700.26
  vias: v4(33.46,28.78)
CLK_BIASREF: length 6.1
  TOP w0.381: v2(141.56,106.92) v1(142.04,107.4) RC13.1
  BOTTOM w0.089: 141.04,105.33 141.03,105.31 141.03,104.66 141.13,104.56 141.13,104.17 141.19,104.1 141.19,103.93 141.16,103.9 141.16,103.89 140.99,103.71 140.98,103.71 140.86,103.6 UC1.C26
  BOTTOM w0.305: 141.04,105.33 141.04,105.76 141.56,106.28 v2(141.56,106.92)
CLK_DDC2_CRT: length 23.5
  TOP w0.102: v2(203.45,100.89) 203.31,101.03 QV89.3
  IN3 w0.135: JCRT.15 205.09,109.34 204.4,110.04 200.31,110.04 v2(198.91,108.64) 198.91,107.22 200.16,105.97 204.14,105.97 205.48,104.64 205.48,102.86 203.51,100.89 v2(203.45,100.89)
  BOTTOM w0.102: v2(198.91,108.64) 198.91,108.33 RV36.2
CLK_DDC2_CRT_R: length 31.2
  TOP w0.102: RV517.2 203.81,103.18 203.81,102.9 v2(203.99,102.72) 203.99,101.36 204.32,101.03 QV89.4
  IN3 w0.135: v2(203.99,102.72) 203.83,102.56 203.83,102.22 203.32,101.72 201.55,101.72 198.38,104.88 194.03,104.88 191.04,101.9 190.02,101.9 189.8,101.68 189.8,101.12 v2(189.96,100.96) 189.74,100.74 189.74,100.34 189.39,99.99 187.08,99.99 186.18,100.89 186.18,102.35 186.48,102.65 186.48,103.53 v2(186.18,103.83)
  BOTTOM w0.102: RV163.2 189.79,101.5 189.79,101.08 189.92,100.96 v2(189.96,100.96) ; UV6.23 186.29,103.93 v2(186.18,103.83)
CLK_PCI_LPDEBUG: length 185.9
  TOP w0.102: v2(159.95,70.77) 159.83,70.65 155.69,70.65 v1(152.71,73.64) 151.88,74.46 151.82,74.46 R2339.1
  IN3 w0.135: v2(159.95,70.77) 170.62,60.1 170.62,44.08 172.04,42.66 172.04,38.06 170.59,36.61 170.59,32.67 169.5,31.57 169.5,30.36 169.48,30.36 168.66,29.54 154,29.54 153.66,29.2 145.41,29.2 144.45,28.25 136.64,28.25 136.26,27.87 132.03,27.87 130.74,29.16 105.95,29.16 98.64,36.48 95.15,36.48 90.53,41.1 v2(90.17,41.1)
  BOTTOM w0.102: JLPDE.10 71.85,12.28 72.25,12.68 79.73,12.68 80.88,13.82 80.88,16.26 80.17,16.97 80.17,18.44 81.79,20.07 81.79,22.28 86.69,27.18 86.69,38.18 89.62,41.1 v2(90.17,41.1)
CLK_PCI_MEC: length 97.5
  TOP w0.102: R2336.1 150.42,74.7 149.86,74.14 v2(148.75,74.14) ; UE5.A29 156.05,17.42 156.65,18.01 157.28,18.01 157.66,18.39 RE80.1 157.66,19.2 157.94,19.48 v1(157.94,19.78) 157.94,20.22 v2(158.09,20.37)
  BOTTOM w0.102: v2(158.09,20.37) 158.4,20.37 158.58,20.2 161.35,20.2 164.47,23.32 168.38,23.32 169.88,24.82 173.27,24.82 174.38,25.92 174.38,37.87 173.62,38.62 173.17,38.62 171.28,40.52 168.46,40.52 166.4,42.57 166.4,52.47 167.07,53.14 170.43,53.14 171.23,53.94 171.23,57.76 169.83,59.16 165.24,59.16 162.88,61.52 158.3,61.52 148.75,71.07 v2(148.75,74.14)
CLK_PCIE_GFX: length 92.1
  IN3 w0.135: v2(68.62,77.95) 68.86,77.71 68.86,77.36 69.3,76.92 71.63,76.92 72.5,77.79 76.29,77.79 78.44,79.95 78.44,81.63 81.25,84.43 81.25,85.65 82.21,86.62 83.32,86.62 84.89,88.19 84.89,88.87 83.89,89.87 83.89,91.61 88.6,96.32 88.6,99.04 87.84,99.8 87.84,102.37 88.59,103.13 94.56,103.13 96.42,104.99 103.13,104.99 106.28,108.15 109.41,108.15 111.78,105.78 116.92,105.78 119.39,103.31 120.18,103.31 120.6,102.88 129.22,102.88 131.8,105.47 132.02,105.47 132.14,105.36 v2(132.14,105.13)
  BOTTOM w0.076: UC1.B39 132.78,104.5 132.68,104.6 132.52,104.6 132.37,104.75 132.37,104.78 132.31,104.83 132.31,104.96 v2(132.14,105.13)
  BOTTOM w0.102: UV1.AE8 69,77.57 v2(68.62,77.95)
CLK_PCIE_GFX#: length 92.1
  IN3 w0.135: v2(69.47,77.98) 69.15,77.66 69.15,77.48 69.42,77.21 71.51,77.21 72.38,78.08 76.17,78.08 78.16,80.07 78.16,81.74 80.96,84.55 80.96,85.77 82.09,86.9 83.2,86.9 84.6,88.31 84.6,88.75 83.6,89.75 83.6,91.73 88.31,96.44 88.31,98.92 87.55,99.68 87.55,102.49 88.47,103.41 94.44,103.41 96.3,105.28 103.01,105.28 106.16,108.43 109.53,108.43 111.9,106.07 117.04,106.07 119.51,103.6 120.3,103.6 120.72,103.17 129.1,103.17 131.69,105.76 132.14,105.76 132.44,105.46 v2(132.67,105.46)
  BOTTOM w0.076: v2(132.67,105.46) 132.49,105.28 132.49,105.28 132.49,104.89 132.53,104.85 132.53,104.82 132.58,104.76 132.68,104.76 132.78,104.86 UC1.A39
  BOTTOM w0.102: v2(69.47,77.98) 69.41,77.98 UV1.AD8
CLK_PCIE_LAN: length 88
  IN3 w0.135: v2(130.91,108.01) 130.97,108.07 130.97,112.88 131.1,113.02 131.1,114.21 133.5,116.61 146.96,116.61 147.45,117.1 150.6,117.1 151.5,117.99 160.3,117.99 163.04,115.25 167.15,115.25 174.17,108.23 174.17,102.44 175.78,100.83 175.78,99.03 179.32,95.49 179.32,92.06 179.19,91.94 179.19,83.8 v2(179.4,83.58)
  BOTTOM w0.076: UC1.B42 130.94,104.12 130.94,104.31 130.87,104.39 130.87,104.62 130.94,104.69 130.94,104.92 130.87,105 130.87,105.23 130.94,105.3 130.94,105.53 130.87,105.61 130.87,105.84 130.94,105.91 130.94,106.12 131.1,106.28 131.1,106.48 131.02,106.56 131.02,106.79 131.23,107 131.23,107.85 131.06,108.01 v2(130.91,108.01)
  BOTTOM w0.102: v2(179.4,83.58) 179.32,83.67 179.32,84.05 179.63,84.37 179.63,84.86 UL1.15
CLK_PCIE_LAN#: length 87.8
  IN3 w0.135: v2(131.54,108.01) 131.25,108.3 131.25,108.52 131.4,108.66 131.4,109.07 131.25,109.21 131.25,109.62 131.4,109.76 131.4,110.16 131.25,110.31 131.25,110.71 131.4,110.86 131.4,111.26 131.25,111.41 131.25,111.81 131.4,111.96 131.4,112.36 131.25,112.5 131.25,112.76 131.39,112.9 131.39,113.15 131.53,113.29 131.53,113.69 131.39,113.83 131.39,114.09 131.61,114.31 131.84,114.31 132.13,114.6 132.13,114.83 133.62,116.32 147.08,116.32 147.57,116.81 150.72,116.81 151.62,117.71 160.18,117.71 162.92,114.96 167.03,114.96 173.89,108.11 173.89,102.32 175.49,100.71 175.49,98.91 179.03,95.37 179.03,92.18 178.9,92.06 178.9,83.66 v2(178.82,83.58)
  BOTTOM w0.076: UC1.C41 131.4,103.92 131.11,104.21 131.11,106.05 131.26,106.21 131.26,106.8 131.39,106.93 131.39,107.86 v2(131.54,108.01)
  BOTTOM w0.102: v2(178.82,83.58) 179.05,83.81 179.05,84.16 179.23,84.35 UL1.16
CLK_PCIE_WLAN: length 134.8
  IN3 w0.135: v2(133.27,108.29) 133.03,108.53 133.03,108.75 133.22,108.93 133.33,108.93 133.44,108.93 133.73,109.22 133.73,109.45 134.02,109.73 134.13,109.73 134.24,109.73 134.53,110.02 134.53,110.25 134.82,110.53 134.93,110.53 135.04,110.53 135.33,110.82 135.33,111.05 135.54,111.26 135.92,111.26 136.08,111.1 136.48,111.1 136.64,111.26 137.04,111.26 137.2,111.1 137.6,111.1 137.76,111.26 138.17,111.26 138.32,111.1 138.73,111.1 138.89,111.26 139.29,111.26 139.45,111.1 139.85,111.1 140.01,111.26 143.32,111.26 146.01,113.95 150.94,113.95 152.68,115.7 159.67,115.7 161.98,113.39 166.15,113.39 172.23,107.3 172.23,99.53 174.58,97.18 174.58,96.07 175.86,94.79 175.86,93.61 176.65,92.83 176.65,85.71 176.94,85.42 176.94,78.75 177.53,78.16 177.53,74.41 179.66,72.28 179.9,72.28 181.15,71.03 184.03,71.03 186.24,68.81 186.24,68.2 189.71,64.73 189.71,61.89 v2(189.59,61.78)
  BOTTOM w0.076: UC1.C37 133.62,103.97 133.62,107.36 133.1,107.87 133.1,108.12 v2(133.27,108.29)
  BOTTOM w0.102: JNGFF.39 183.98,43.49 184.09,43.6 184.09,44.13 184.69,44.73 185.5,44.73 185.77,45 188.44,45 188.78,45.34 191.52,45.34 193.26,47.08 193.26,48.2 193.01,48.46 193.01,58 190.19,60.82 189.81,61.2 189.81,61.56 v2(189.59,61.78)
CLK_PCIE_WLAN#: length 134.8
  IN3 w0.135: v2(132.64,108.29) 132.74,108.4 132.74,108.87 135.42,111.55 143.2,111.55 145.89,114.24 150.82,114.24 152.56,115.99 159.79,115.99 162.1,113.67 166.27,113.67 172.52,107.42 172.52,99.65 174.87,97.3 174.87,96.19 176.15,94.91 176.15,93.73 176.94,92.94 176.94,85.83 177.23,85.54 177.23,78.87 177.82,78.28 177.82,74.53 179.78,72.57 180.02,72.57 181.27,71.31 184.14,71.31 186.52,68.93 186.52,68.32 190,64.85 190,61.98 v2(190.2,61.78)
  BOTTOM w0.076: UC1.B38 133.46,104.13 133.46,104.33 133.38,104.4 133.38,104.73 133.46,104.81 133.46,105.04 133.38,105.11 133.38,105.44 133.46,105.52 133.46,105.75 133.38,105.82 133.38,106.15 133.46,106.23 133.46,106.46 133.38,106.53 133.38,106.86 133.46,106.94 133.46,107.29 132.94,107.81 132.94,108.17 132.82,108.29 v2(132.64,108.29)
  BOTTOM w0.102: JNGFF.41 184.48,43.47 184.36,43.59 184.36,44.02 184.8,44.46 185.61,44.46 185.88,44.73 188.55,44.73 188.89,45.07 191.63,45.07 193.53,46.97 193.53,48.31 193.27,48.57 193.27,58.11 190.38,61.01 190.07,61.31 190.07,61.65 v2(190.2,61.78)
CLK_SMB: length 10.6
  TOP w0.102: PRP1.6 17.2,22.53 v2(17.07,22.66)
  BOTTOM w0.102: v2(17.07,22.66) 18.09,22.66 18.37,22.94 18.37,24.46 17.9,24.93 PD2.3 v1(17.9,26.32) 17.9,26.35 16.78,27.47 JBATT.7
CLK_TP_SIO: length 184.4
  TOP w0.102: v2(23.04,68.23) 23.23,68.42 v1(23.73,68.42) 23.98,68.16 R2522.2 23.23,67.43 23.22,67.44 DE1.3 20.88,66.4 20.88,65.14 21.93,64.09 25.36,64.09 25.68,63.77 JTP.6 ; v2(151.62,21.97) 152.07,21.52 152.07,21.31 152.05,21.28 UE5.A37
  IN1 w0.114: v2(23.04,68.23) 22.6,67.78 22.6,62.52 26.64,58.49 43.06,58.49 44.1,59.53 50.28,59.53 51.33,58.49 52.56,58.49 53.3,57.75 55.37,57.75 55.9,58.27 55.9,58.93 57.74,60.77 73.04,60.77 74.13,59.67 74.13,51.6 75.12,50.6 75.12,47.71 78.63,44.2 78.63,31.82 84.18,26.27 92.7,26.27 93.41,25.55 98.82,25.55 99.95,24.42 100.84,24.42 102.27,22.99 130.42,22.99 131.18,22.23 144.81,22.23 145.72,23.14 149.05,23.14 149.48,23.57 150.02,23.57 v2(151.62,21.97)
CLKA0: length 49.2
  TOP w0.076: UV18.J7 36.55,96.75 36.4,96.9 36.4,97.05 36.51,97.16 37.33,97.16 37.66,97.48 37.66,97.89 37.4,98.15 37.24,98.15 v2(37.03,98.35)
  TOP w0.112: v2(36.35,103.58) 36.52,103.76 36.52,104.73 RV145.1 36.46,105.37 36.46,105.68 RV146.1
  IN1 w0.076: 37.49,93.5 37.48,93.51 37.48,93.58 37.35,93.71 37.2,93.86 37.16,93.86 35.64,95.38 35.64,96.52 35.95,96.83 36.43,96.83 36.57,96.97 36.57,97.78 37.03,98.25 v2(37.03,98.35)
  IN1 w0.14: v2(37.03,98.35) 37.37,98.35 37.47,98.45 37.47,99.27 37.16,99.57 36.66,99.57 36.33,99.9 36.33,102.65 36.53,102.85 36.53,103.41 v2(36.35,103.58) ; 37.49,93.5 38.87,92.13 39.51,92.13 39.65,91.99 39.65,90.53 39.93,90.25 40.34,90.25 40.62,90.53 40.62,91.99 40.76,92.13 40.96,92.13 41.09,91.99 41.09,90.53 41.38,90.25 41.79,90.25 42.07,90.53 42.07,91.99 42.21,92.13 50.73,92.13 53.12,94.52 54.72,94.52 55.2,95 55.2,95.19 v2(55.38,95.37)
  BOTTOM w0.076: v2(37.03,98.35) 37.03,98.19 36.9,98.06 36.72,98.06 36.56,98.22 36.56,99.07 36.64,99.15 36.64,99.45 36.45,99.65 36.35,99.65 36.23,99.77 36.23,99.9 36.28,99.95 UV17.J7
  BOTTOM w0.112: v2(55.38,95.37) 55.38,95.25 55.66,94.97 UV1.D24
CLKA0#: length 49.8
  TOP w0.076: UV18.K7 36.17,96.75 36.24,96.81 36.24,97.12 36.44,97.32 37.27,97.32 37.5,97.55 37.5,97.82 37.33,97.98 37.2,97.98 37.1,97.88 v2(37.1,97.76)
  TOP w0.112: v2(36.94,103.58) 36.74,103.78 36.74,104.73 RV145.2 36.67,105.5 36.67,105.68 RV147.1
  IN1 w0.076: v2(37.1,97.76) 37,97.85 36.87,97.85 36.73,97.72 36.73,96.9 36.5,96.66 36.01,96.66 35.81,96.45 35.81,95.45 37.23,94.03 37.26,94.03 37.47,93.82 37.6,93.69 37.66,93.69 37.67,93.68
  IN1 w0.14: 37.67,93.68 38.97,92.38 39.61,92.38 39.9,92.1 39.9,90.64 40.04,90.5 40.23,90.5 40.37,90.64 40.37,92.1 40.66,92.38 41.06,92.38 41.35,92.1 41.35,90.64 41.49,90.5 41.68,90.5 41.82,90.64 41.82,92.1 42.1,92.38 50.62,92.38 53.01,94.77 54.61,94.77 54.94,95.1 54.94,95.71 54.81,95.84 54.63,95.84 54.5,95.71 v2(54.5,95.37) ; v2(36.94,103.58) 36.78,103.43 36.78,102.75 36.58,102.54 36.58,100.01 36.76,99.82 37.27,99.82 37.72,99.37 37.72,98.35 37.14,97.76 v2(37.1,97.76)
  BOTTOM w0.076: v2(37.1,97.76) 36.96,97.89 36.65,97.89 36.39,98.15 36.39,99.14 36.48,99.22 36.48,99.38 36.38,99.48 36.28,99.48 36.06,99.7 36.06,99.81 35.92,99.95 UV17.K7
  BOTTOM w0.112: UV1.D25 54.9,94.97 v2(54.5,95.37)
CLKA0_C: length 2.9
  TOP w0.102: RV147.2 RV146.2 36.12,107.8 CV335.1 35.23,107.88 v1(35.04,108.07)
CLKA1: length 53.5
  TOP w0.076: UV19.J7 36.39,77.16 36.39,77.31 36.49,77.41 36.69,77.41 36.83,77.27 37.22,77.27 37.59,77.64 37.59,78.11 37.37,78.32 37.25,78.32 v2(37.03,78.54)
  TOP w0.112: RV153.1 36.08,71.33 36.08,71.65 RV151.1 36.15,72.29 36.15,72.5 36,72.65 v2(36,72.7)
  IN1 w0.076: 37.22,83.44 37.26,83.4 37.26,83.08 36.49,82.32 36.49,80.3 37.48,79.31 37.48,78.42 37.33,78.27 37.14,78.27 37.03,78.38 v2(37.03,78.54)
  IN1 w0.14: v2(36,72.7) 36.17,72.87 36.17,73.33 35.46,74.04 35.46,76.76 36.5,77.8 36.5,78.03 37.01,78.54 v2(37.03,78.54) ; v2(56.96,87.93) 57.11,87.93 57.31,87.73 57.31,87.56 56.95,87.2 54.44,87.2 54.23,87.4 52,87.4 49.25,84.66 43.84,84.66 43.57,84.94 43.57,85.81 43.26,86.11 42.67,86.11 42.37,85.81 42.37,84.51 42.22,84.36 41.87,84.36 41.73,84.49 41.73,85.82 41.44,86.11 41.04,86.11 40.75,85.82 40.75,84.49 40.61,84.36 40.42,84.36 40.28,84.49 40.28,85.75 39.99,86.03 39.59,86.03 39.3,85.75 39.3,84.49 39.16,84.36 37.75,84.36 37.22,83.82 37.22,83.44
  BOTTOM w0.076: v2(37.03,78.54) 37.03,78.43 36.91,78.31 36.75,78.31 36.54,78.52 36.54,78.8 36.69,78.95 36.69,79.59 36.5,79.79 36.31,79.79 36.19,79.91 36.19,80.03 36.3,80.14 UV20.J7
  BOTTOM w0.112: v2(56.96,87.93) 56.99,87.93 UV1.N22
CLKA1#: length 52.7
  TOP w0.076: UV19.K7 35.97,76.94 36.22,77.19 36.22,77.38 36.42,77.57 36.76,77.57 36.9,77.43 37.15,77.43 37.42,77.71 37.42,78.04 37.3,78.16 37.17,78.16 37.03,78.02 v2(37.03,77.9)
  TOP w0.112: RV154.1 36.29,71.33 36.29,71.52 RV151.2 36.36,72.28 36.36,72.45 v2(36.58,72.67)
  IN1 w0.076: 37.47,83.44 37.42,83.4 37.42,83.02 36.66,82.25 36.66,80.37 37.64,79.38 37.64,78.35 37.4,78.11 37.23,78.11 v2(37.03,77.9)
  IN1 w0.14: v2(36.58,72.67) 36.43,72.82 36.43,73.43 35.72,74.14 35.72,76.66 36.97,77.9 v2(37.03,77.9) ; 37.47,83.44 37.47,83.72 37.85,84.1 39.27,84.1 39.56,84.39 39.56,85.64 39.69,85.78 39.89,85.78 40.03,85.64 40.03,84.39 40.31,84.1 40.72,84.1 41,84.39 41,85.72 41.14,85.85 41.34,85.85 41.47,85.72 41.47,84.39 41.76,84.1 42.32,84.1 42.63,84.4 42.63,85.7 42.78,85.85 43.16,85.85 43.31,85.7 43.31,84.83 43.74,84.41 49.36,84.41 52.1,87.15 54.13,87.15 54.33,86.95 57.06,86.95 57.56,87.45 57.56,87.68 v2(57.78,87.9)
  BOTTOM w0.076: v2(37.03,77.9) 36.79,78.15 36.68,78.15 36.38,78.45 36.38,78.86 36.53,79.01 36.53,79.52 36.43,79.62 36.24,79.62 36.03,79.84 36.03,80 35.89,80.14 UV20.K7
  BOTTOM w0.112: UV1.M22 57.4,88.28 v2(57.78,87.9)
CLKA1_C: length 3.3
  TOP w0.102: v1(37.93,69.62) 37.47,70.08 RV154.2 RV153.2 35.67,70 CV218.1
CLKOUT_LPC0: length 13.1
  TOP w0.102: R2336.2 150.42,75.95 149.36,77.02 149.26,77.02 148.95,77.33 148.95,77.94 148.42,78.47 148.42,81.55 146.71,83.25 146.71,85.79 v2(147.51,86.59)
  BOTTOM w0.076: UC1.AN15 147.51,86.58 v2(147.51,86.59)
CLKOUT_LPC1: length 12.9
  TOP w0.102: v2(147.51,85.98) 147.5,85.98 147.08,85.56 v1(147.08,83.56) 148.65,81.99 148.65,78.56 149.18,78.03 149.18,77.42 149.36,77.24 150.02,77.24 151.31,75.95 R2339.2
  BOTTOM w0.076: UC1.AP15 147.55,85.93 v2(147.51,85.98)
CLKRUN#: length 128
  TOP w0.102: v2(153.68,95.31) 153.86,95.5 154.88,95.5 155.28,95.1 159.74,95.1 160.83,96.19 161.65,96.19 162.26,96.8 166.25,96.8 166.73,96.32 168,96.32 RC36.2 ; UE5.A32 155.93,18.92 156.37,19.35 156.37,19.82 156.95,20.4 156.98,20.4 157.56,20.98 158.12,20.98 159.85,19.26 161.24,19.26 v1(162.92,17.58) 162.92,17.02 v2(163.58,16.36)
  IN1 w0.114: v2(163.58,16.36) 163.58,16.41 164.22,17.05 164.43,17.05 167.01,19.62 167.01,23.2 168.22,24.41 169.72,24.41 170.84,25.53 170.84,27.04 175.67,31.87 175.67,38.29 177.73,40.35 177.73,47.13 177.46,47.4 177.46,49.07 176.46,50.06 176.46,51.88 176.71,52.12 176.71,59.77 175.84,60.64 175.84,69.56 175.19,70.21 175.19,71.11 173.4,72.9 173.4,77.15 171.64,78.91 171.64,81.52 171.23,81.92 170.34,81.92 170.02,82.24 170.02,85.61 165.57,90.06 164.31,90.06 163.4,90.96 161.29,90.96 158.86,93.4 157.71,93.4 155.8,95.31 v2(153.68,95.31)
  BOTTOM w0.076: v2(153.68,95.31) 153.5,95.14 UC1.V5
COMP: length 6.6
  TOP w0.102: PC531.1 69.7,104.65 70.21,104.14 70.21,103.92 70.36,103.76 72.2,103.76 v1(72.48,103.48)
  TOP w0.254: PC531.1 PR539.1 68.64,104.93 67.57,105.99 PU501.6
CPPE#: length 23.1
  BOTTOM w0.076: 162.03,100.06 161.78,100.31 157.12,100.31 156.95,100.13 156.26,100.13 UC1.J1
  BOTTOM w0.102: 162.03,100.06 163.68,98.41 170.87,98.41 172.18,97.11 v1(172.18,95.19) 172.18,93.64 172.08,93.54 172.08,92.12 RC108.2
CPU_DPB_AUX: length 13.1
  BOTTOM w0.076: UC1.B5 153,104.26 153.14,104.12 153.23,104.12 153.31,104.19 153.31,104.51 153.1,104.71 153.1,105.74 153.55,106.19 154.22,106.19 154.56,106.53 154.56,107.86 155.19,108.49 155.19,108.67 155.15,108.72 155.15,108.74
  BOTTOM w0.102: 155.15,108.74 v4(155.15,109.44) 155.15,110.57 155.49,110.91 155.49,113.25 155.48,113.26 155.48,113.79 155.49,113.81 155.49,114.85 155.37,114.96 RP51.2
CPU_DPB_AUX#: length 13
  BOTTOM w0.076: UC1.C5 153.37,104.02 153.47,104.12 153.47,104.57 153.26,104.78 153.26,105.67 153.62,106.02 154.28,106.02 154.73,106.46 154.73,107.79 155.36,108.42 155.36,108.67 155.4,108.72 155.4,108.72
  BOTTOM w0.102: RP51.1 155.87,114.98 155.71,114.81 v4(155.71,113.53) 155.71,110.76 155.38,110.43 155.38,108.75 155.4,108.72
CPU_DPB_CTRLCLK: length 99
  IN3 w0.135: v2(152.53,114.15) 152.7,114.32 152.7,114.74 153.12,115.16 159.31,115.16 162.41,112.06 166.71,112.06 168.98,109.78 168.98,108.77 171.7,106.06 171.7,98.15 173.28,96.56 173.28,96.07 173.7,95.65 174.08,95.65 175.19,94.54 175.19,93.27 176.13,92.33 176.13,85.5 176.42,85.21 176.42,78.46 177,77.88 177,74.2 179.44,71.76 179.68,71.76 180.94,70.5 183.82,70.5 185.68,68.64 185.68,68 188.85,64.82 188.85,60.75 188.85,60.75 188.85,60.21 188.85,60.21 188.85,60.17 189.69,59.34 194.25,59.34 194.64,59.73 194.64,59.97 v2(194.47,60.15)
  BOTTOM w0.076: UC1.B9 150.6,104.34 150.97,104.72 150.97,105.32 151.15,105.5 151.15,105.91 152.33,107.09 152.33,108.05 152.16,108.22 152.16,110.48 152.12,110.53 152.12,110.57
  BOTTOM w0.102: v2(194.47,60.15) 194.34,60.28 194.34,60.82 QX4.1 ; 152.12,110.57 152.13,110.59 v4(152.13,111.56) 152.13,112.54 152.7,113.11 152.7,113.98 v2(152.53,114.15) 152.71,114.33 152.71,114.76 152.58,114.89 RP52.2
CPU_DPB_CTRLCLK_R: length 14.5
  IN3 w0.135: JHDMI.15 203.17,64.87 203.17,63.47 202.75,63.05 200.43,63.05 197.14,59.76 196.52,59.76 v2(196.35,59.59)
  BOTTOM w0.102: RX16.1 196.93,59.49 196.68,59.74 196.5,59.74 v2(196.35,59.59) 196.16,59.78 195.95,59.78 195.63,60.1 195.1,60.1 194.35,59.35 QX4.6
CPU_DPB_CTRLDAT: length 99.3
  IN3 w0.135: v2(153.12,114.15) 152.95,114.32 152.95,114.64 153.22,114.92 159.21,114.92 162.31,111.81 166.61,111.81 168.74,109.68 168.74,108.67 171.45,105.96 171.45,98.05 173.04,96.46 173.04,95.96 173.59,95.41 173.98,95.41 174.94,94.44 174.94,93.17 175.89,92.23 175.89,85.4 176.18,85.11 176.18,78.36 176.76,77.78 176.76,74.09 179.34,71.52 179.58,71.52 180.84,70.26 183.72,70.26 185.43,68.54 185.43,67.9 188.61,64.72 188.61,60.85 188.61,60.85 188.61,60.11 188.61,60.11 188.61,60.07 189.59,59.09 194.35,59.09 194.82,59.57 v2(195.23,59.57)
  BOTTOM w0.076: 152.38,110.57 152.38,110.53 152.33,110.48 152.33,108.29 152.49,108.12 152.49,107.03 151.31,105.84 151.31,105.43 151.14,105.25 151.14,104.65 150.79,104.3 UC1.C9
  BOTTOM w0.102: 152.38,110.57 152.35,110.6 152.35,111.28 152.36,111.29 152.36,111.82 152.35,111.84 152.35,112.45 152.91,113.02 152.91,113.95 v2(153.12,114.15) 152.93,114.34 152.93,114.77 153.08,114.92 RP52.1 ; v2(195.23,59.57) 195.65,59.14 QX4.4
CPU_DPB_CTRLDAT_R: length 12.2
  IN3 w0.135: JHDMI.16 202.3,65.05 202.92,64.43 202.92,63.57 202.65,63.29 200.32,63.29 197.04,60 196.52,60 v2(196.35,60.17)
  BOTTOM w0.102: QX4.3 195.65,60.39 196.04,60 196.17,60 v2(196.35,60.17) 196.55,59.97 196.65,59.97 196.96,60.28 RX17.1
CPU_DPC_AUX: length 62.1
  IN3 w0.114: v2(187.1,101.08) 187.29,101.27 187.29,101.98 188.46,103.15 188.46,103.58 v2(188.24,103.8)
  IN3 w0.135: v2(166.48,111.13) 166.44,111.13 166.1,110.79 163.85,110.79 163.68,110.95 163.68,110.96 162.35,110.96 159.33,113.98 158.43,113.98 158.24,114.18 157.84,114.18 157.65,113.98 157.25,113.98 157.05,114.18 156.65,114.18 156.46,113.98 156.06,113.98 155.87,114.18 155.46,114.18 155.27,113.98 154.83,113.98 154.74,114.07 154.74,114.3 v2(154.92,114.48)
  BOTTOM w0.076: UC1.A6 152.39,104.76 152.3,104.68 152.18,104.68 152.06,104.8 152.06,105.12 152.19,105.24 152.19,105.68 153.66,107.15 153.66,108.31 153.49,108.48 153.25,108.72 153.25,110.53 153.28,110.56 153.28,110.57
  BOTTOM w0.102: CV349.1 187.26,101.45 187.26,101.25 v2(187.1,101.08) 187.46,100.73 187.46,100.64 187.04,100.22 177.14,100.22 176.28,101.08 176.28,107.55 174.46,109.36 173.83,109.36 172.22,110.97 166.63,110.97 v2(166.48,111.13) ; UV6.18 188.29,104.23 188.38,104.14 188.38,103.94 v2(188.24,103.8) ; 153.28,110.57 153.28,110.78 153.64,111.14 153.64,111.14 154.87,112.37 154.87,114.43 v2(154.92,114.48) 154.77,114.63 154.77,114.83 154.87,114.94 RP51.3
CPU_DPC_AUX#: length 62.2
  IN3 w0.114: v2(188.83,103.8) 188.66,103.64 188.66,103.06 187.49,101.89 187.49,101.27 v2(187.68,101.08)
  IN3 w0.135: v2(166.48,110.54) 163.75,110.54 163.57,110.72 162.25,110.72 159.22,113.74 154.73,113.74 154.5,113.97 154.5,114.31 v2(154.33,114.48)
  BOTTOM w0.076: 153.06,110.57 153.06,110.56 153.09,110.53 153.09,108.65 153.37,108.36 153.5,108.24 153.5,107.22 152.02,105.74 152.02,105.31 151.9,105.18 151.9,104.73 152.02,104.6 UC1.B6
  BOTTOM w0.102: v2(166.48,110.54) 166.69,110.76 172.13,110.76 173.74,109.15 174.37,109.15 176.06,107.46 176.06,100.99 177.06,100 187.13,100 187.67,100.55 187.67,101.07 v2(187.68,101.08) 187.48,101.29 187.48,101.41 CV350.1 ; v2(188.83,103.8) 188.6,104.03 188.6,104.14 188.69,104.23 UV6.17 ; RP51.4 154.37,114.97 154.55,114.8 154.55,114.7 v2(154.33,114.48) 154.65,114.16 154.65,112.46 153.42,111.23 153.42,111.23 153.06,110.87 153.06,110.57
CPU_DPC_CTRLCLK: length 16.2
  IN3 w0.135: v2(151.87,107.83) 151.87,107.72 151.71,107.56 151.03,107.56 150.51,107.04 150.51,105.79 150.93,105.37 150.93,103.61 150.75,103.43 150.56,103.43 v2(150.26,103.73)
  BOTTOM w0.076: 151.32,110.57 151.32,110.56 151.3,110.53 151.3,109.95 151.59,109.65 151.59,108.16 151.36,107.93 151.36,107.73 151.55,107.55 151.69,107.55 151.87,107.72 v2(151.87,107.83) ; UC1.D9 150.78,103.2 v2(150.26,103.73)
  BOTTOM w0.102: 151.32,110.57 151.32,113.1 151.95,113.72 151.95,114.76 152.08,114.89 RP52.3
CPU_DPC_CTRLDAT: length 15.8
  IN3 w0.135: v2(151.87,107.17) 151.72,107.32 151.13,107.32 150.75,106.94 150.75,105.89 151.17,105.47 151.17,103.51 150.85,103.18 150.56,103.18 150.2,102.82 v2(150.2,102.71)
  BOTTOM w0.076: v2(150.2,102.71) 150.23,102.71 150.23,102.72 150.23,103.15 150.28,103.2 UC1.D11 ; v2(151.87,107.17) 151.65,107.38 151.48,107.38 151.19,107.66 151.19,108 151.43,108.23 151.43,109.59 151.13,109.88 151.13,110.54 151.11,110.56 151.11,110.57
  BOTTOM w0.102: 151.11,110.57 151.11,113.19 151.73,113.81 151.73,114.75 151.58,114.9 RP52.4
CPU_EDP_HPD: length 366.4
  IN1 w0.114: v2(159.62,106.53) 159.62,103.64 164.57,98.68 172.9,98.68 173.37,98.21 175.43,98.21 176.1,97.54 176.1,93.7 176.19,93.62 176.19,87.94 177.05,87.07 177.88,87.07 178.73,86.23 178.73,85.36 179.66,84.43 180.7,84.43 181.23,83.9 181.23,81.19 185.11,77.31 185.11,66.36 187.43,64.03 187.43,46.82 188.98,45.27 188.98,43.88 189.67,43.2 189.67,40.52 188.12,38.98 188.12,33.61 185.92,31.41 185.92,30.49 181.97,26.55 181.12,26.55 176.39,21.82 176.39,18.7 175.29,17.6 175.29,15.57 170.72,11 169.33,11 165.61,7.28 157.66,7.28 157.62,7.32 142.21,7.32 141.41,6.53 133.28,6.53 129.83,9.97 113.94,9.97 112.97,8.99 112.53,8.99 112.17,9.35 v2(112.17,9.45)
  IN3 w0.135: v2(22.15,74.3) 21.91,74.54 19.68,74.54 15.06,79.17 15.06,81.67 15.95,82.56 15.95,83.86 13.2,86.6 11.46,86.6 4.94,93.12 4.94,93.72 4.64,94.02 4.64,95.44 v2(4.29,95.8)
  BOTTOM w0.076: UC1.D6 153.01,103.2 153.31,103.5 153.49,103.5 153.66,103.67 153.66,104.06 153.92,104.32 153.92,105.12 154.12,105.33 154.27,105.33 155.15,106.2
  BOTTOM w0.102: RC89.1 159.62,110.39 v1(159.62,109.65) v2(159.62,106.53) 159.31,106.23 155.17,106.23 155.15,106.2 ; JEDP.31 4.14,95.95 v2(4.29,95.8) ; v2(22.15,74.3) 22.36,74.09 32.54,74.09 33.02,73.61 34.19,73.61 34.69,74.12 42.57,74.12 43.64,73.05 52.85,73.05 54.2,71.71 64.88,71.71 68.3,68.29 73.99,68.29 76.92,65.36 76.92,58.38 80.4,54.89 87.85,54.89 89.08,53.66 89.08,44.3 91.34,42.04 91.34,36.61 101.73,26.22 101.73,19.87 108.6,13 109.17,13 112.17,10.01 v2(112.17,9.45)
CPU_ID: length 3.2
  TOP w0.102: RE280.1 RE279.1 94.8,12.88 v1(95.1,13.18) 95.34,13.42 UE4.11
CPU_PWR_DEBUG#: length 45.2
  TOP w0.102: v2(96.58,80.42) 95.71,79.56 RC50.1 ; v2(98.51,90.48) 98.53,90.45 v1(99.18,90.45) 100.73,90.45 101.27,90.99 101.27,95.53 102.52,96.78 105.47,96.78 105.92,97.23 R253.1 106.43,97.21 107.83,97.21 R255.2 108.8,97.72 109.97,98.88 115.09,98.88 115.98,99.77 119.84,99.77 120.58,100.51 v2(120.58,100.64)
  BOTTOM w0.076: v2(120.58,100.64) 120.37,100.84 UC1.H59
  BOTTOM w0.102: v2(98.51,90.48) 98.51,90.35 98.45,90.3 98.45,89.46 94.47,85.47 94.47,82.53 v2(96.58,80.42)
CPU_PWR_DEBUG#_R: length 4.7
  TOP w0.102: v1(95.78,80.13) 95.67,80.02 94.17,80.02 RC50.2 92.72,79.56 92.61,79.66 JXDP.45
CPUSB#: length 25.1
  BOTTOM w0.076: 162.03,99.67 v1(161.15,99.67) 157.38,99.67 157,99.29 157,99.27 156.72,98.98 155.16,98.98 UC1.K3
  BOTTOM w0.102: RC111.2 171.85,91.45 171.85,97.11 170.78,98.19 163.58,98.19 162.1,99.67 162.03,99.67
CS1: length 3.1
  TOP w0.254: PU100.1 53.24,27.71 53.24,26.72 53.85,26.11 53.85,26.02 v1(53.92,25.96) 53.94,25.94 54.79,25.94 PR105.1
CS2: length 3.9
  TOP w0.102: v1(55.88,31.56) 55.8,31.56 54.92,30.69 PR108.1
  TOP w0.203: PU100.5 53.56,29.34 53.73,29.5 53.73,30.1 54.26,30.63 PR108.1
CS_1.35V: length 3.9
  BOTTOM w0.102: v1(60.57,36.74) 59.59,35.76 PR205.2
  BOTTOM w0.203: PU200.13 58.84,34.9 59.35,35.41 PR205.2
CSSN_1: length 64.8
  TOP w0.102: v1(37.39,17.05) PR705.1
  TOP w0.254: PR705.1 v2(38.13,16.06)
  IN3 w0.254: v2(38.13,16.06) 38.23,15.95 39.2,15.95 39.87,15.29 39.87,14.24 40.31,13.8 40.31,12.32 38.36,10.37 27.49,10.37 26.04,11.82 26.04,13.31 20.45,18.89 20.45,27.49 20.12,27.82 20.12,36.38 27.61,43.87 30.41,43.87 v2(30.66,44.12)
  BOTTOM w0.254: v2(30.66,44.12) 31.04,43.74 PR702.3
CSSP_1: length 62.1
  TOP w0.102: v2(30.66,43.36) v1(31.74,43.36)
  TOP w0.254: v2(38.08,15.29) 37.98,15.19 PR738.1
  IN3 w0.254: v2(38.08,15.29) 38.08,15.32 38.18,15.42 38.99,15.42 39.49,14.92 39.49,14.09 39.81,13.77 39.81,12.4 38.16,10.75 27.65,10.75 26.42,11.97 26.42,13.47 20.83,19.05 20.83,27.74 20.5,28.07 20.5,36.12 27.87,43.49 30.54,43.49 v2(30.66,43.36)
  BOTTOM w0.254: v2(30.66,43.36) 30.28,43.74 PR702.2
DAT_DDC2_CRT: length 26.5
  TOP w0.102: QV89.6 v2(204.61,102.9)
  IN3 w0.135: JCRT.12 206.3,115.37 202.37,111.43 200.72,111.43 198.18,108.89 198.18,107.05 200.02,105.21 203.7,105.21 204.27,104.64 204.27,103.24 v2(204.61,102.9)
  BOTTOM w0.102: JCRT.12 204.73,117.78 RV35.2
DAT_DDC2_CRT_R: length 29
  TOP w0.102: RV516.2 203.59,103.18 203.59,102.9 v2(203.41,102.72) 203.01,102.33 QV89.1
  IN3 w0.135: v2(187.15,103.8) 186.75,103.4 186.75,102.54 186.49,102.29 186.49,100.95 187.13,100.32 189.35,100.32 189.48,100.45 189.48,100.85 v2(189.37,100.96) 189.53,101.12 189.53,101.79 189.91,102.16 190.94,102.16 193.92,105.15 198.49,105.15 201.66,101.98 203.21,101.98 203.56,102.33 203.56,102.56 v2(203.41,102.72)
  BOTTOM w0.102: v2(187.15,103.8) 187.09,103.86 UV6.21 ; v2(189.37,100.96) 189.4,100.96 189.54,101.1 189.54,101.4 RV164.2
DAT_SMB: length 9.4
  TOP w0.102: PRP1.7 v2(17.08,22.03)
  BOTTOM w0.102: JBATT.6 15.4,24.22 PD2.2 v1(17.9,23.17) 17.84,23.1 16.63,23.1 16.44,22.91 16.44,22.67 v2(17.08,22.03)
DAT_TP_SIO: length 185.9
  TOP w0.102: v2(23.14,66.41) 23.21,66.47 R2521.2 23.98,65.83 v1(23.66,65.51) DE1.2 21.92,64.58 22.19,64.32 26.43,64.32 26.68,64.06 JTP.7 ; UE5.B40 151.8,19.49 150.85,18.54 v2(149.94,18.54)
  IN1 w0.114: v2(149.94,18.54) 150.14,18.54 150.6,19 150.6,19.69 152.07,21.16 152.07,22.18 151.54,22.71 151.34,22.71 150.21,23.84 149.29,23.84 148.93,23.48 145.72,23.48 144.71,22.47 131.28,22.47 130.52,23.23 102.71,23.23 101.27,24.67 100.05,24.67 98.92,25.8 93.51,25.8 91.9,27.41 83.38,27.41 78.87,31.92 78.87,44.3 75.37,47.81 75.37,50.7 74.37,51.7 74.37,59.77 73.14,61.01 57.64,61.01 55.66,59.03 55.66,58.37 55.27,57.99 53.4,57.99 52.66,58.73 51.43,58.73 50.38,59.77 44,59.77 42.96,58.73 26.74,58.73 23.14,62.32 v2(23.14,66.41)
DC_TEST_A3_B3: length 0.7
  BOTTOM w0.081: UC1.B3 155,104.46 UC1.A3
DC_TEST_A4: length 2.3
  TOP w0.102: v2(155.2,105.59) 155.2,106.64 T168.1
  BOTTOM w0.076: UC1.A4 154.36,104.99 154.97,105.59 v2(155.2,105.59)
DC_TEST_A60: length 7.7
  BOTTOM w0.076: 117.81,108.49 117.81,107.09 119.41,105.48 UC1.A60
  BOTTOM w0.102: T169.1 118.04,111.71 118.04,108.74 117.81,108.51 117.81,108.49
DC_TEST_A61_B61: length 0.7
  BOTTOM w0.076: UC1.B61 118.75,104.4 UC1.A61
DC_TEST_A62: length 9.2
  BOTTOM w0.076: UC1.A62 118.02,104.91 117.2,104.91
  BOTTOM w0.102: 117.2,104.91 115.76,104.91 115.47,105.2 115.47,107.52 116.18,108.23 116.18,110.97 116.21,111 T170.1
DC_TEST_AV1: length 6.2
  TOP w0.102: v2(159.49,81.07) 160.88,81.07 T171.1
  BOTTOM w0.076: v2(159.49,81.07) 159.49,81.38 158.2,82.68 157.38,82.68 156.39,83.67 UC1.AV1
DC_TEST_AW1: length 3.2
  TOP w0.102: T172.1 157.56,80.93 v2(157.74,81.11)
  BOTTOM w0.076: v2(157.74,81.11) 157.74,81.35 UC1.AW1
DC_TEST_AW63: length 6.2
  TOP w0.102: v2(118.83,81.46) 118.8,81.49 116.82,81.49 116.4,81.07 116.4,80.56 T173.1
  BOTTOM w0.076: v2(118.83,81.46) 118.39,81.46 117.51,82.34 UC1.AW63
DC_TEST_AY2_AW2: length 0.7
  BOTTOM w0.076: UC1.AY2 155.48,82.47 UC1.AW2
DC_TEST_AY3_AW3: length 0.7
  BOTTOM w0.076: UC1.AW3 154.87,82.96 UC1.AY3
DC_TEST_AY60: length 6.7
  TOP w0.102: v2(119.13,81.92) 116.79,81.92 114.88,80 114.88,79.24 T166.1
  BOTTOM w0.076: UC1.AY60 119.39,82.18 v2(119.13,81.92)
DC_TEST_AY61_AW61: length 0.7
  BOTTOM w0.076: UC1.AW61 118.73,82.93 UC1.AY61
DC_TEST_AY62_AW62: length 0.7
  BOTTOM w0.076: UC1.AY62 118.08,82.92 UC1.AW62
DC_TEST_B62_B63: length 0.7
  BOTTOM w0.076: UC1.B63 118.03,104.39 UC1.B62
DC_TEST_C1_C2: length 0.7
  BOTTOM w0.081: UC1.C2 156.02,103.73 UC1.C1
DDI1_LANE_N0: length 118.9
  IN3 w0.135: v2(192.08,71.12) 191.92,71.28 188.35,71.28 184.77,74.86 184.77,77.43 180.93,81.28 180.93,82.78 182.11,83.96 182.11,90.49 180.95,91.65 180.95,93.25 180.61,93.59 180.61,100.56 175.88,105.29 175.88,108.55 167.9,116.54 163.64,116.54 160.9,119.28 150.83,119.28 149.98,118.43 146.38,118.43 145.85,117.9 132.75,117.9 129.07,114.22 129.07,111.38 126.02,108.32 123.66,108.32 v2(123.47,108.13)
  BOTTOM w0.076: UC1.C54 123.04,103.81 122.81,104.04 122.63,104.04 122.48,104.19 122.45,104.29 122.45,104.42 122.48,104.48 122.49,104.49 122.51,104.57 122.51,104.8 122.46,104.9 122.36,105.11 122.36,105.62 123.05,106.32 123.05,108.15 123.17,108.26 123.34,108.26 v2(123.47,108.13)
  BOTTOM w0.102: CX18.2 193.79,70.91 193.44,70.91 193.04,71.3 192.26,71.3 v2(192.08,71.12)
DDI1_LANE_N1: length 127.9
  IN3 w0.135: v2(193.45,68.07) 193.22,68.3 192.83,68.3 192.57,68.56 192.57,69 193.84,70.27 193.84,72.72 193,73.56 188.36,73.56 186.52,75.4 186.52,78.93 184.23,81.22 184.23,90.5 186.02,92.29 186.02,97.34 177.41,105.94 177.41,109.74 174.01,113.15 174.01,113.76 169.34,118.43 163.94,118.43 161.56,120.8 145.77,120.8 144.39,119.42 131.49,119.42 124.16,112.09 124.16,111.46 124.06,111.36 124.06,110.57 123.5,110.01 123.5,109.84 122.37,108.71 121.72,108.71 121.57,108.56 v2(121.49,108.49)
  BOTTOM w0.076: UC1.B58 120.85,104.01 120.92,104.08 120.92,104.24 120.83,104.33 120.83,104.56 120.92,104.64 120.92,104.87 120.83,104.96 120.83,105.19 120.92,105.28 120.92,105.51 120.83,105.6 120.83,105.83 120.92,105.91 120.92,106.37 121.07,106.52 121.07,106.66 121.23,106.82 121.38,106.82 121.48,106.92 121.48,107.05 121.64,107.21 121.76,107.21 121.96,107.41 121.96,107.57 121.86,107.67 121.86,107.9 121.96,108 121.96,108.61 121.86,108.71 121.57,108.71 121.47,108.61 121.47,108.51 v2(121.49,108.49)
  BOTTOM w0.102: CX16.2 193.78,68.25 193.63,68.25 v2(193.45,68.07)
DDI1_LANE_N2: length 130.3
  IN3 w0.135: v2(193.12,62.61) 192.91,62.83 192.56,62.83 191.39,64 191.39,69.03 192.94,70.58 192.94,72.21 192.42,72.74 187.98,72.74 185.61,75.1 185.61,77.8 182.88,80.53 182.88,88.17 183.47,88.75 183.47,90.97 185.26,92.76 185.26,96.91 184.44,97.73 183.66,97.73 182.39,99 182.39,99.88 176.65,105.62 176.65,109.43 173.22,112.85 173.22,113.45 169.01,117.67 163.61,117.67 161.23,120.04 149.37,120.04 148.64,119.32 145.71,119.32 145.05,118.66 132.34,118.66 127.46,113.78 127.46,111.41 125.41,109.36 124.78,109.36 v2(124.59,109.17)
  BOTTOM w0.076: UC1.B55 122.75,104.51 122.85,104.61 123,104.61 123.21,104.82 123.21,105.8 123.59,106.18 123.59,107.39 124.2,108 124.2,109.31 124.27,109.39 124.38,109.39 v2(124.59,109.17)
  BOTTOM w0.102: v2(193.12,62.61) 193.27,62.76 193.81,62.76 CX14.2
DDI1_LANE_N3: length 132.7
  IN3 w0.135: v2(121.72,109.77) 121.72,109.78 121.91,109.97 122.33,109.97 122.68,110.32 122.68,110.4 123.12,110.83 123.12,112.18 131.12,120.18 143.93,120.18 145.32,121.57 161.88,121.57 164.26,119.19 169.77,119.19 178.1,110.85 178.1,110.3 178.87,109.53 178.87,105.58 186.79,97.65 186.79,91.82 184.99,90.02 184.99,82.37 187.28,80.09 187.28,76.11 188.71,74.68 193.31,74.68 194.75,73.24 194.75,67.68 194.11,67.05 193.21,67.05 192.72,66.56 192.72,65.92 192.97,65.67 193.19,65.67 v2(193.4,65.46)
  BOTTOM w0.076: 122.21,110.02 122.42,109.81 122.42,108.46 122.33,108.37 122.33,108.14 122.42,108.05 122.42,107.82 122.33,107.73 122.33,107.5 122.42,107.41 122.42,107.18 122.33,107.09 122.33,106.86 122.42,106.77 122.42,106.55 122.14,106.27 122.08,106.27 122.02,106.27 121.86,106.11 121.86,106.05 121.86,105.99 121.68,105.82 121.68,105.65 121.59,105.56 121.59,105.28 121.68,105.19 121.68,104.95 121.56,104.83 121.42,104.83 121.37,104.88 UC1.A57
  BOTTOM w0.102: v2(193.4,65.46) 193.55,65.61 193.76,65.61 CX12.2 ; 122.21,110.02 121.98,110.02 v2(121.72,109.77)
DDI1_LANE_P0: length 118.8
  IN3 w0.135: v2(192.05,71.71) 191.87,71.52 188.45,71.52 185.02,74.96 185.02,77.54 181.17,81.38 181.17,82.68 182.35,83.86 182.35,90.59 181.19,91.75 181.19,93.36 180.85,93.69 180.85,100.66 176.13,105.39 176.13,108.65 168,116.78 163.74,116.78 161,119.52 150.73,119.52 149.87,118.67 146.28,118.67 145.75,118.14 132.65,118.14 128.83,114.33 128.83,111.48 125.92,108.56 123.64,108.56 v2(123.47,108.74)
  BOTTOM w0.076: v2(123.47,108.74) 123.47,108.63 123.26,108.43 123.1,108.43 122.89,108.22 122.89,106.39 122.19,105.69 122.19,105.08 122.26,104.93 122.28,104.9 122.35,104.76 122.35,104.76 122.35,104.6 122.32,104.54 122.32,104.53 122.3,104.48 122.29,104.45 122.29,104.26 122.33,104.11 122.36,104.08 122.57,103.86 122.72,103.86 122.79,103.8 122.79,103.73 UC1.C55
  BOTTOM w0.102: v2(192.05,71.71) 192.23,71.53 193.18,71.53 193.43,71.28 193.54,71.16 193.77,71.16 CX19.2
DDI1_LANE_P1: length 128.2
  IN3 w0.135: v2(193.45,68.66) 193.34,68.54 192.93,68.54 192.82,68.66 192.82,68.9 194.1,70.18 194.1,72.81 193.11,73.8 188.46,73.8 186.76,75.5 186.76,79.03 184.47,81.32 184.47,90.4 186.26,92.19 186.26,97.44 177.65,106.04 177.65,109.84 174.25,113.25 174.25,113.86 169.44,118.67 164.04,118.67 161.66,121.05 145.67,121.05 144.29,119.66 131.39,119.66 123.92,112.19 123.92,111.56 123.81,111.46 123.81,110.67 123.26,110.11 123.26,109.95 122.27,108.96 121.61,108.96 v2(121.49,109.07)
  BOTTOM w0.076: v2(121.49,109.07) 121.68,108.88 121.92,108.88 122.13,108.68 122.13,107.34 121.09,106.3 121.09,103.84 120.8,103.55 UC1.C58
  BOTTOM w0.102: CX17.2 193.78,68.51 193.6,68.51 v2(193.45,68.66)
DDI1_LANE_P2: length 130.2
  IN3 w0.135: v2(124.59,109.76) 124.74,109.6 125.31,109.6 127.21,111.51 127.21,113.88 132.24,118.9 144.95,118.9 145.61,119.56 148.54,119.56 149.27,120.29 161.33,120.29 163.71,117.91 169.11,117.91 173.46,113.55 173.46,112.96 176.89,109.53 176.89,105.72 182.63,99.98 182.63,99.1 183.76,97.97 184.54,97.97 185.5,97.01 185.5,92.66 183.71,90.87 183.71,88.65 183.13,88.06 183.13,80.63 185.86,77.9 185.86,75.2 188.08,72.98 192.52,72.98 193.18,72.32 193.18,70.47 191.64,68.93 191.64,64.1 192.66,63.07 192.99,63.07 v2(193.12,63.2)
  BOTTOM w0.076: UC1.A55 122.75,104.84 122.81,104.78 122.93,104.78 123.04,104.89 123.04,105.87 123.42,106.25 123.42,107.46 124.01,108.04 124.01,109.35 124.21,109.55 124.39,109.55 v2(124.59,109.76)
  BOTTOM w0.102: CX15.2 193.76,63.02 193.3,63.02 v2(193.12,63.2)
DDI1_LANE_P3: length 132.8
  IN3 w0.135: v2(121.72,110.36) 121.87,110.22 122.23,110.22 122.44,110.42 122.44,110.5 122.87,110.93 122.87,112.28 131.02,120.43 143.83,120.43 145.22,121.81 161.98,121.81 164.36,119.43 169.87,119.43 178.34,110.96 178.34,110.4 179.11,109.63 179.11,105.68 187.04,97.75 187.04,91.72 185.24,89.92 185.24,82.48 187.52,80.19 187.52,76.21 188.81,74.92 193.41,74.92 194.99,73.34 194.99,67.58 194.21,66.8 193.31,66.8 192.97,66.46 192.97,66.02 193.07,65.92 193.3,65.92 v2(193.43,66.04)
  BOTTOM w0.076: 122.38,110.16 122.59,109.96 122.59,106.48 121.85,105.75 121.85,104.87 121.37,104.39 UC1.B57
  BOTTOM w0.102: v2(193.43,66.04) 193.58,65.89 193.83,65.89 CX13.2 ; v2(121.72,110.36) 121.84,110.24 122.31,110.24 122.38,110.16
DDI2_LANE_N0: length 87.8
  IN3 w0.135: v2(181.13,106.29) 181,106.16 180.27,106.16 179.89,106.54 179.89,109.93 179.1,110.71 179.1,111.29 170.2,120.2 164.74,120.2 162.36,122.57 144.78,122.57 143.4,121.19 129.8,121.19 125.16,116.55 125.16,115.77 122.86,113.48 122.67,113.48 v2(122.51,113.64)
  BOTTOM w0.076: 126.26,109.81 126.26,109.75 126.28,109.72 126.28,108.14 124.82,106.68 124.82,105.46 124.79,105.43 124.79,104.93 124.85,104.71 124.85,104.58 124.79,104.35 124.81,104.19 124.91,104.04 125.25,103.7 UC1.C51
  BOTTOM w0.102: CV346.1 181.6,106.1 181.32,106.1 v2(181.13,106.29) ; 126.26,109.81 126.26,110.76 124.84,112.18 122.11,112.18 121.7,112.6 121.7,113.14 122.03,113.47 122.33,113.47 v2(122.51,113.64)
DDI2_LANE_N1: length 92.2
  IN3 w0.135: v2(121.23,111.71) 121.38,111.56 121.59,111.56 121.78,111.75 121.78,112.46 120.89,113.35 120.89,118.24 121.7,119.05 126.01,119.05 128.91,121.95 142.94,121.95 144.33,123.33 162.68,123.33 165.05,120.96 171.8,120.96 179.72,113.03 179.72,112.4 180.19,111.93 180.19,110.7 180.7,110.19 180.7,107.98 180.81,107.87 180.98,107.87 v2(181.18,108.07)
  BOTTOM w0.076: 125.51,109.81 125.51,108.06 124.25,106.8 124.25,105.88 123.59,105.22 123.59,104.18 123.87,103.89 UC1.C53
  BOTTOM w0.102: v2(181.18,108.07) 181.37,107.88 181.6,107.88 CV348.1 ; 125.51,109.81 125.51,110.26 124.22,111.55 121.39,111.55 v2(121.23,111.71)
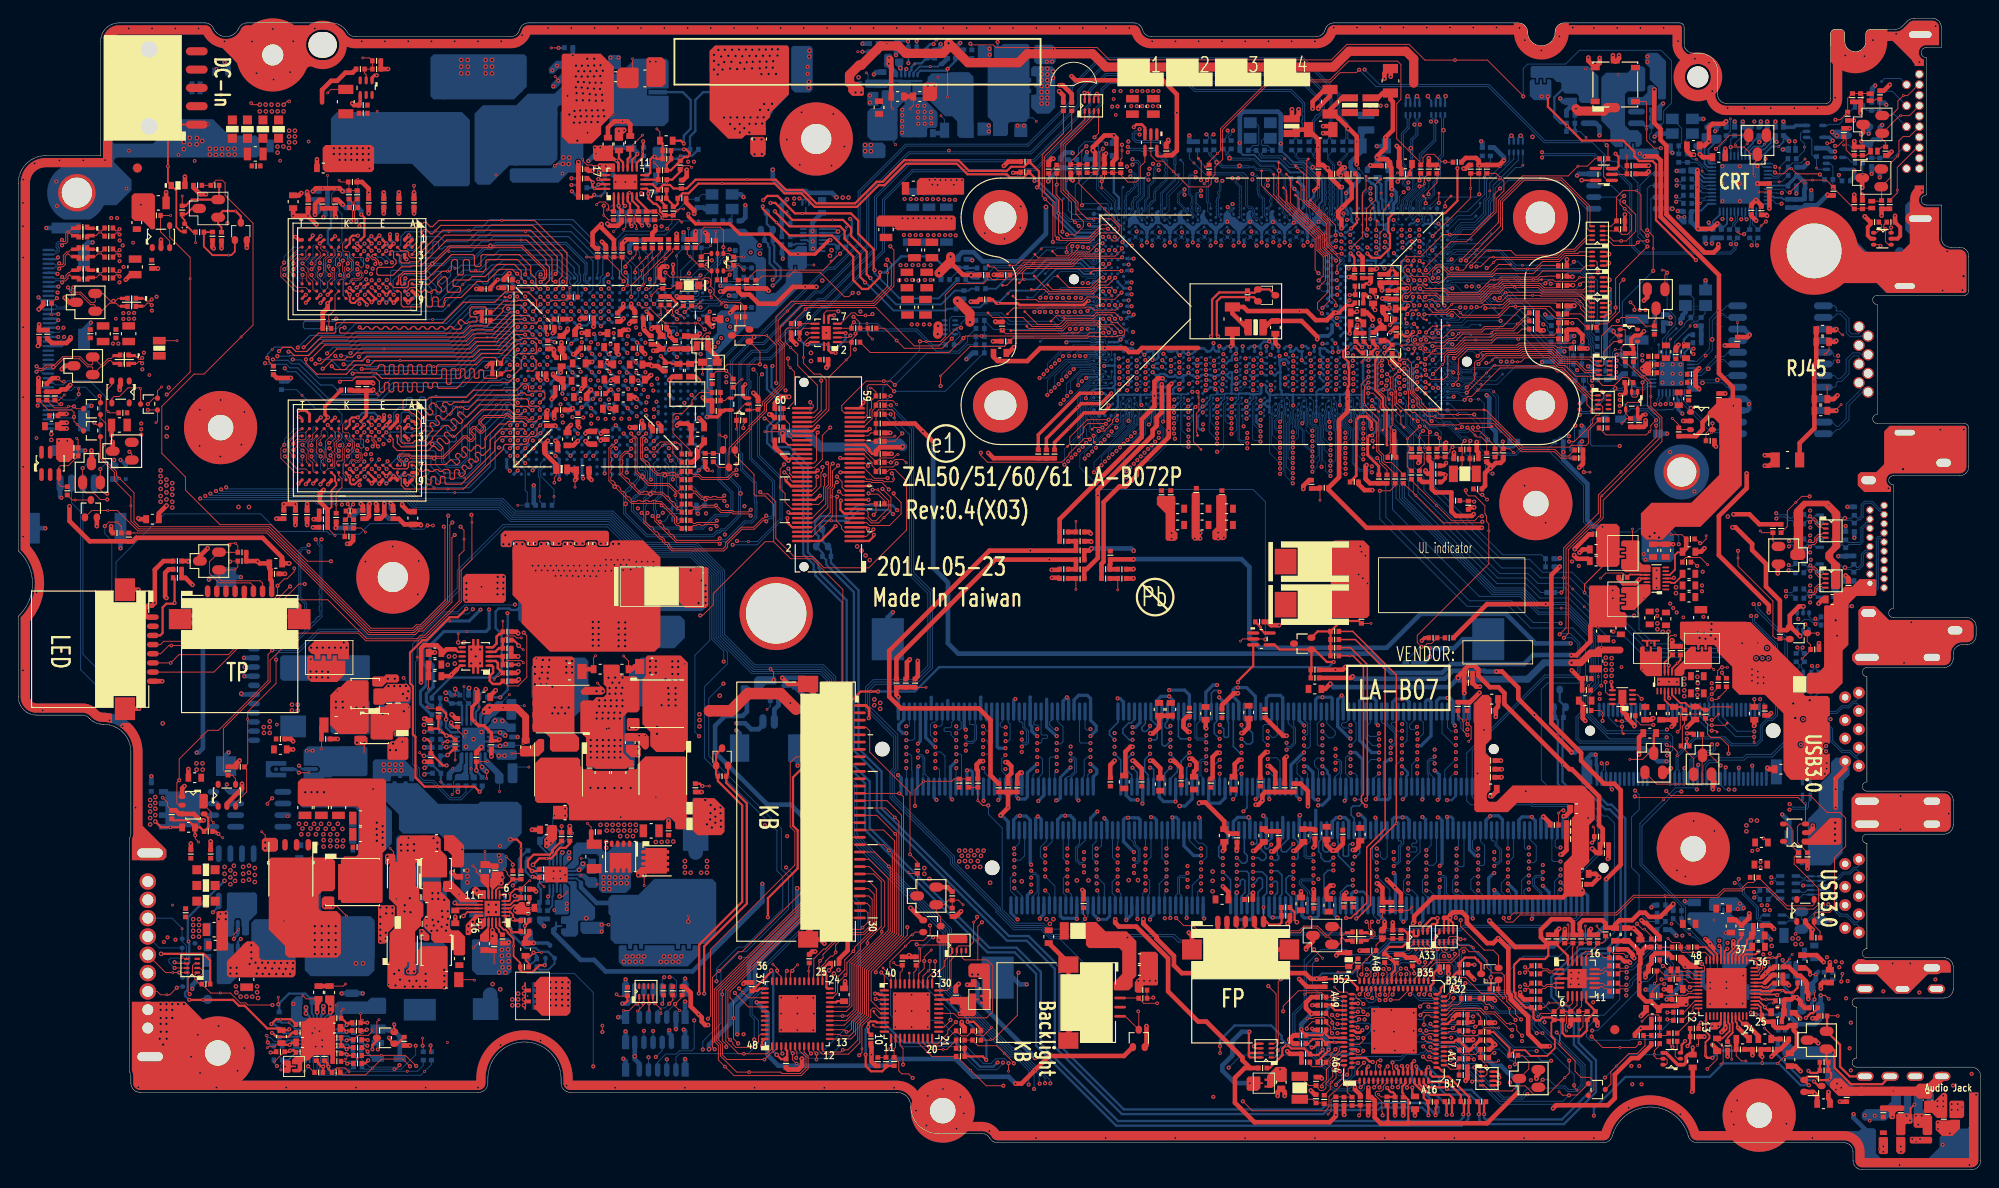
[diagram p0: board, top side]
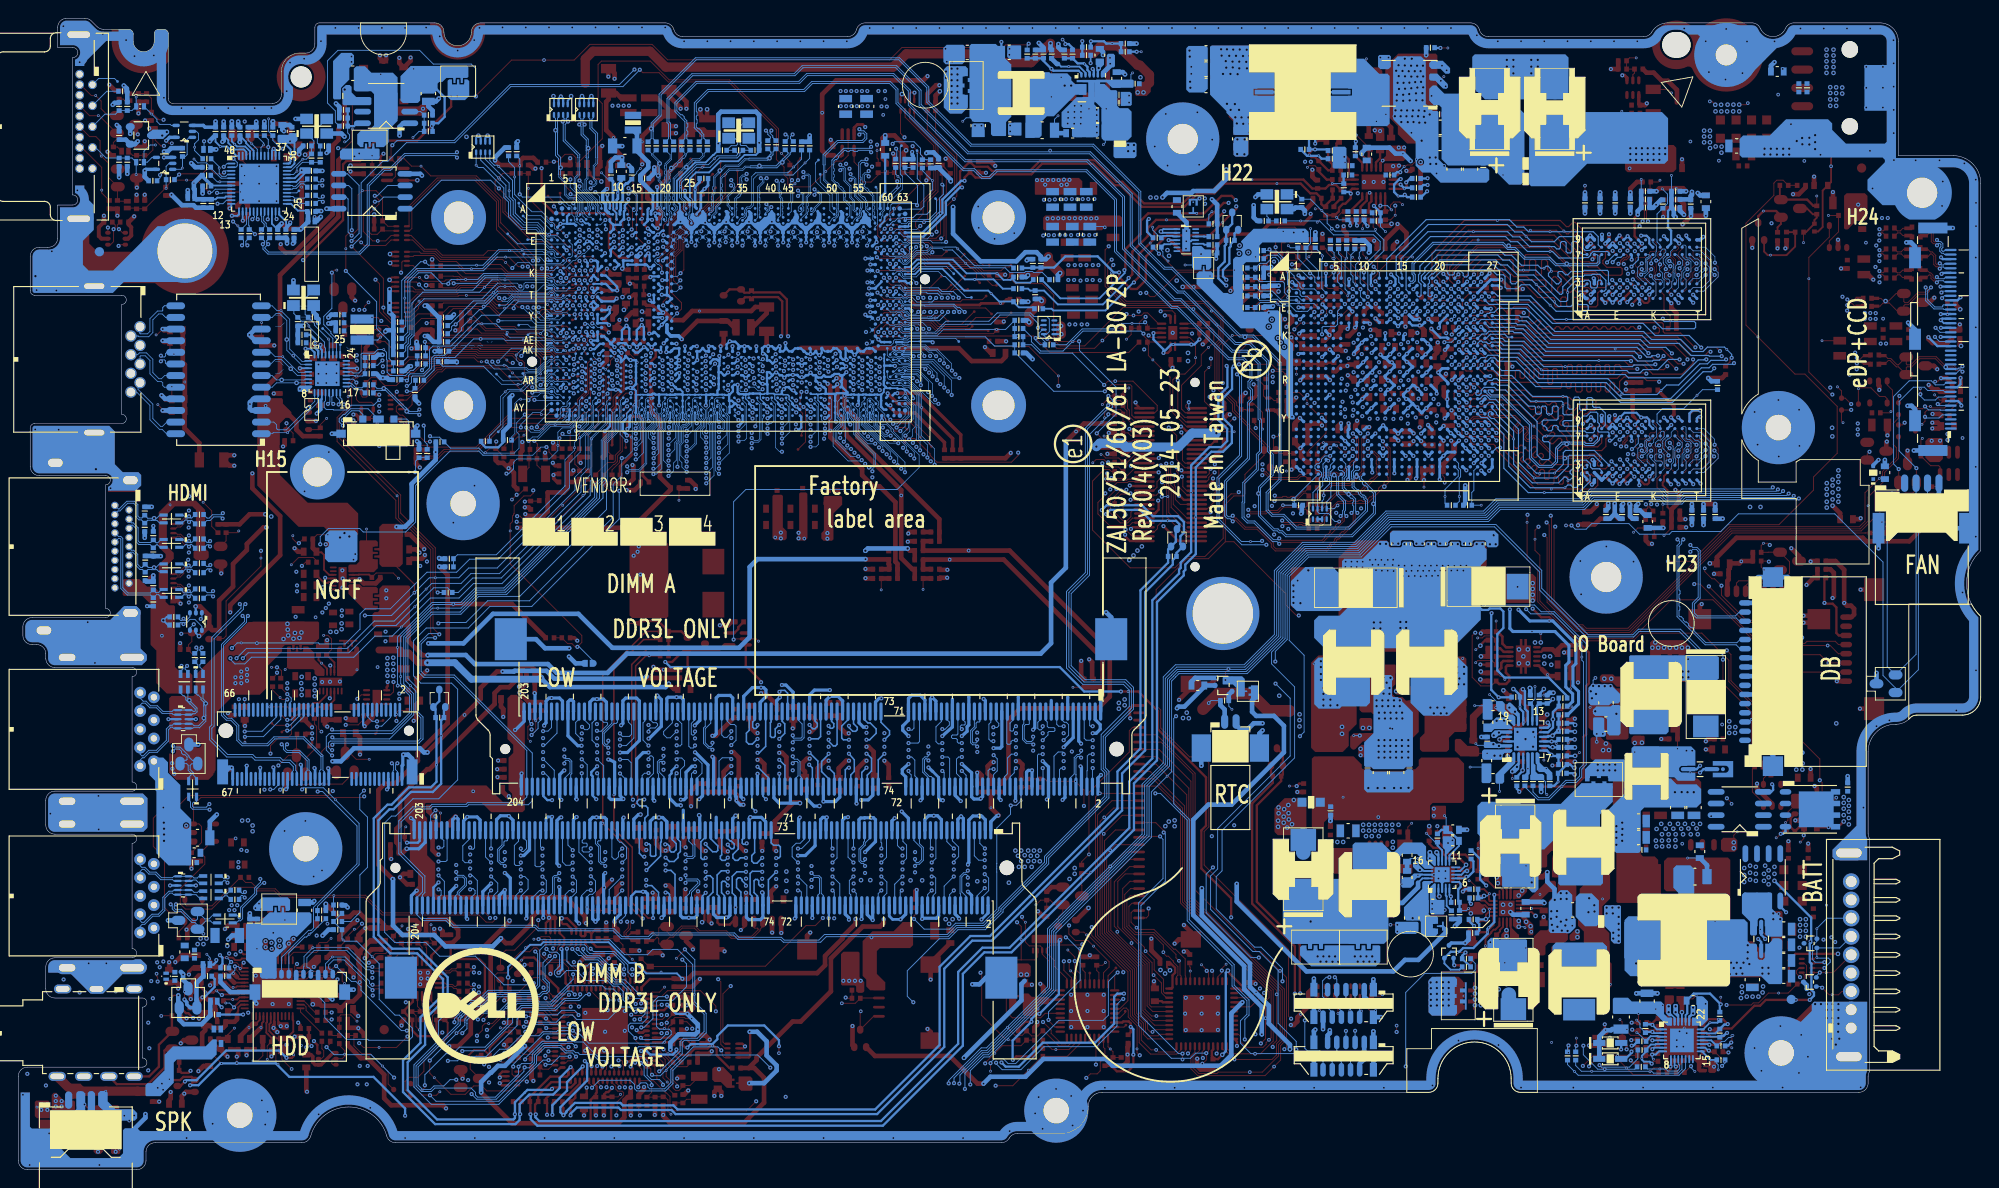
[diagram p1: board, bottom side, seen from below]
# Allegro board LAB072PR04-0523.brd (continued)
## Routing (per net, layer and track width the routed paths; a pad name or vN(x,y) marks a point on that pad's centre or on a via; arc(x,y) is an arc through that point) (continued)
DDI2_LANE_P0: length 88
  IN3 w0.135: v2(122.51,113.06) 122.69,113.24 122.97,113.24 125.4,115.67 125.4,116.45 129.9,120.94 143.5,120.94 144.89,122.33 162.26,122.33 164.64,119.95 170.1,119.95 178.86,111.19 178.86,110.61 179.64,109.83 179.64,106.44 180.17,105.92 180.92,105.92 v2(181.13,105.71)
  BOTTOM w0.076: 126.47,109.81 126.47,109.74 126.44,109.71 126.44,108.07 124.99,106.61 124.99,105.39 124.96,105.36 124.96,104.95 124.97,104.89 125.01,104.73 125.01,104.56 125.01,104.54 124.96,104.34 124.97,104.25 125.04,104.15 125.15,104.04 125.31,104 125.44,103.9 125.49,103.85 UC1.C50
  BOTTOM w0.102: 126.47,109.81 126.47,110.85 124.93,112.4 122.2,112.4 121.91,112.69 121.91,113.05 122.08,113.21 122.36,113.21 v2(122.51,113.06) ; v2(181.13,105.71) 181.27,105.85 181.6,105.85 CV342.1
DDI2_LANE_P1: length 92.1
  IN3 w0.135: v2(181.18,107.48) 181.04,107.62 180.71,107.62 180.46,107.88 180.46,110.09 179.95,110.6 179.95,111.83 179.48,112.3 179.48,112.93 171.7,120.71 164.95,120.71 162.57,123.09 144.43,123.09 143.04,121.71 129.01,121.71 126.11,118.8 121.8,118.8 121.14,118.14 121.14,113.45 122.03,112.56 122.03,111.65 121.7,111.32 121.42,111.32 v2(121.23,111.13)
  BOTTOM w0.076: 125.3,109.81 125.3,109.8 125.34,109.76 125.34,109.73 125.35,109.72 125.35,109.4 125.25,109.3 125.25,109.07 125.35,108.98 125.35,108.75 125.25,108.65 125.25,108.42 125.35,108.33 125.35,108.13 125.05,107.83 124.93,107.83 124.74,107.64 124.74,107.52 124.58,107.36 124.46,107.36 124.27,107.17 124.27,107.05 124.08,106.87 124.08,106.64 124.01,106.56 124.01,106.28 124.08,106.2 124.08,105.95 123.93,105.79 123.87,105.79 123.87,105.79 123.83,105.79 123.64,105.61 123.64,105.57 123.64,105.5 123.42,105.29 123.42,104.12 UC1.B54
  BOTTOM w0.102: CV347.1 181.6,107.62 181.32,107.62 v2(181.18,107.48) ; 125.3,109.81 125.3,110.17 125.15,110.31 125,110.31 124.78,110.53 124.78,110.68 124.13,111.33 123.97,111.33 123.85,111.22 123.63,111.22 123.51,111.33 123.21,111.33 123.09,111.22 122.73,111.22 122.62,111.33 121.43,111.33 v2(121.23,111.13)
DDR3_DRAMRST#: length 32
  TOP w0.102: v2(116.54,27.38) 116.54,27.72 116.39,27.88 CD34.1 ; RD5.1 CD3.1 v1(104.83,40.31) 105.34,39.8 105.95,39.8 v2(105.97,39.78)
  BOTTOM w0.102: JDIMM2.30 116.85,27.63 116.6,27.38 v2(116.54,27.38) 115.43,26.27 112.65,26.27 112,26.92 109,26.92 107.5,28.43 107.5,32.51 107.5,32.51 107.5,32.86 107.5,32.86 107.5,33.08 107.5,33.43 107.5,33.44 107.5,37.31 106,38.81 106,39.75 v2(105.97,39.78) 105.95,39.8 105.34,39.8 104.85,40.3 JDIMM1.30
DDR3_DRAMRST#_CPU: length 157.7
  TOP w0.102: RD5.2 RD3.2 102.24,42.67 101.99,42.42 98.91,42.42 v1(98.9,42.41) 97.97,41.48 v2(97.97,39.73) ; CC35.1 149.53,76.42 148.72,77.23 148.72,77.47 v2(148.47,77.73)
  IN3 w0.135: v2(97.97,39.73) 98.91,38.79 98.91,36.71 106.18,29.44 131.02,29.44 132.29,28.17 136,28.17 136.48,28.65 144.3,28.65 145.11,29.47 153.56,29.47 153.89,29.8 168.55,29.8 169.24,30.49 169.24,31.68 170.33,32.78 170.33,36.72 170.77,37.16 170.77,38.84 171.62,39.69 171.62,42.71 170.35,43.97 170.35,57.87 168.56,59.67 v2(168.51,59.67)
  BOTTOM w0.076: UC1.AV15 147.23,83.4 147.23,82.89 147.3,82.81 147.3,82.54 147.24,82.47 147.24,82.24 147.32,82.15 147.32,78.46 148.06,77.73 v2(148.47,77.73) 148.47,75.8 149.41,74.86 149.41,74.76
  BOTTOM w0.102: v2(168.51,59.67) 168.41,59.77 165.49,59.77 163.13,62.13 158.55,62.13 149.41,71.27 149.41,74.76
DDR_A_BS0: length 47.1
  IN1 w0.076: v2(135.72,79.53) 135.87,79.38 135.87,79.28 135.7,79.11 135.7,73.33 135.75,73.28 135.75,72.54
  IN1 w0.183: 135.75,72.54 135.75,66.74 136.15,66.34 136.15,65.48 135.79,65.12 135.79,64.87 136.15,64.51 136.15,62.31 135.7,61.85 135.54,61.85 135.37,61.68 135.37,61.04 134.68,60.34 134.21,60.34 133.97,60.11 133.97,57.01 134.31,56.67 134.31,55.68 133.77,55.13 133.77,54.45 132.5,53.18 132.5,53.13 132.32,52.96 132.32,52.24 132.44,52.12 132.62,52.12 132.8,51.95 132.8,51.54 132.62,51.36 132.23,51.36 131.84,50.97 131.84,50.75 132.02,50.56 132.38,50.56 132.57,50.38 132.57,50.02 132.38,49.83 132.02,49.83 131.84,49.65 131.84,48.37 131.71,48.24 131.71,47.66 131.84,47.53 131.84,47.02 131.66,46.84 131.47,46.84 v2(131.26,47.05)
  BOTTOM w0.076: v2(135.72,79.53) 135.59,79.66 135.05,79.66 134.83,79.88 134.83,83.61 135.24,84.02 UC1.AU35
  BOTTOM w0.17: JDIMM1.109 130.95,48.98 130.66,48.7 130.66,47.65 v2(131.26,47.05)
DDR_A_BS1: length 47.2
  IN1 w0.076: v2(135.72,80.65) 136.1,80.27 136.1,79.28 135.92,79.1 135.92,73.48 136.19,73.21 136.19,72.1
  IN1 w0.183: v2(131.26,44.77) 131.53,44.5 132.11,44.5 132.28,44.67 132.28,45.28 132.04,45.51 131.86,45.51 131.68,45.69 131.68,46.11 131.86,46.29 132.09,46.29 132.28,46.48 132.28,49.11 133,49.83 133,51.13 133.71,51.84 133.71,53.77 134.2,54.27 134.2,54.95 134.75,55.5 134.75,56.85 134.41,57.19 134.41,59.7 134.57,59.87 134.82,59.87 135.81,60.86 135.81,61.35 136.59,62.13 136.59,63.17 136.59,63.17 136.59,66.52 136.19,66.93 136.19,72.1
  BOTTOM w0.076: UC1.AV35 135,83.37 135,81.37 v2(135.72,80.65)
  BOTTOM w0.17: JDIMM1.108 130.65,44.15 v2(131.26,44.77)
DDR_A_BS2: length 45.4
  IN1 w0.076: 126.65,74.76 126.65,75.47 130.12,78.93 131.11,78.93 131.35,79.17 131.35,81.73 v2(130.97,82.11)
  IN1 w0.183: 126.65,74.76 126.65,73.68 126.18,73.21 126.18,72.73 125.56,72.11 125.56,68.44 124.84,67.72 124.84,57.88 122.36,55.4 122.36,55.04 121.45,54.14 121.45,50.08 122.2,49.33 122.2,47.42 v2(121.73,46.95)
  BOTTOM w0.076: v2(130.97,82.11) 131.23,82.36 UC1.AY41
  BOTTOM w0.17: JDIMM1.79 121.95,49.15 121.59,48.8 121.33,48.8 120.68,48.15 120.68,47.66 121.39,46.95 v2(121.73,46.95)
DDR_A_CAS#: length 47.3
  IN1 w0.076: 137.06,71.97 137.06,73.23 136.33,73.97 136.33,78.95 136.5,79.12 136.5,83.44 135.94,84.01 v2(135.72,84.01)
  IN1 w0.183: v2(133.64,45.53) 133.61,45.53 133.15,45.99 133.15,48.75 133.88,49.47 133.88,50.77 134.58,51.47 134.58,53.41 135.08,53.9 135.08,54.59 135.62,55.13 135.62,57.28 135.37,57.53 135.37,59.18 136.71,60.52 136.71,61.01 137.47,61.77 137.47,66.89 137.06,67.29 137.06,71.97
  BOTTOM w0.076: UC1.AU34 135.87,84.01 v2(135.72,84.01)
  BOTTOM w0.17: JDIMM1.115 132.75,46.23 133.45,45.53 v2(133.64,45.53)
DDR_A_D0: length 59.8
  IN1 w0.076: 109,77.82 111.54,80.36 111.54,85.27 114.13,87.86 v2(114.13,88.85)
  IN1 w0.114: v2(97.02,48.43) 97.02,48.21 97.17,48.06 97.26,48.06 97.41,47.91 97.62,47.91 97.82,48.11 97.82,49.36 99.1,50.64 99.1,51.34 101.62,53.85 101.62,54.22 101.51,54.33 101.21,54.33 101.1,54.44 101.1,54.79 101.21,54.9 101.51,54.9 101.62,55.02 101.62,55.36 101.51,55.47 101.21,55.47 101.1,55.59 101.1,55.93 101.21,56.04 101.51,56.04 101.62,56.16 101.62,56.5 101.51,56.62 101.21,56.62 101.1,56.73 101.1,57.07 101.21,57.19 101.51,57.19 101.62,57.3 101.62,57.64 101.51,57.76 101.21,57.76 101.1,57.87 101.1,58.22 101.21,58.33 101.51,58.33 101.62,58.44 101.62,58.79 101.51,58.9 101.21,58.9 101.1,59.02 101.1,59.36 101.21,59.47 101.51,59.47 101.62,59.59 101.62,59.93 101.51,60.05 101.21,60.05 101.1,60.16 101.1,60.5 101.21,60.62 101.51,60.62 101.62,60.73 101.62,61.07 101.51,61.19 101.21,61.19 101.1,61.3 101.1,61.65 101.21,61.76 101.51,61.76 101.62,61.87 101.62,67.88 102.49,68.75 102.49,69.02 105.65,72.19 105.65,74.47 109,77.82
  BOTTOM w0.076: v2(114.13,88.85) 114.2,88.85 114.64,89.29 114.95,89.29 115.24,89.58 115.24,89.58 115.41,89.75 117.47,89.75 UC1.AH63
  BOTTOM w0.102: JDIMM1.5 97.35,48.5 97.27,48.43 v2(97.02,48.43)
DDR_A_D1: length 61
  IN1 w0.076: v2(113.26,88.06) 113.24,88.04 113.24,87.53 111.31,85.6 111.31,80.65 109,78.34
  IN1 w0.114: v2(97.02,46.91) 96.81,46.91 96.6,47.12 96.6,48.69 96.8,48.9 97.18,48.9 97.45,49.17 97.45,49.52 98.73,50.8 98.73,51.49 100.72,53.47 100.72,61.87 101.25,62.4 101.25,62.65 101.14,62.77 100.83,62.77 100.72,62.88 100.72,63.22 100.83,63.34 101.14,63.34 101.25,63.45 101.25,63.8 101.14,63.91 100.83,63.91 100.72,64.02 100.72,64.37 100.83,64.48 101.14,64.48 101.25,64.6 101.25,64.94 101.14,65.05 100.83,65.05 100.72,65.17 100.72,65.51 100.83,65.62 101.14,65.62 101.25,65.74 101.25,68.03 102.12,68.9 102.12,69.17 105.28,72.34 105.28,74.63 109,78.34
  BOTTOM w0.076: UC1.AH62 117.96,89.91 117.76,89.91 117.58,90 117.31,90 117.22,89.91 115.34,89.91 115.18,89.74 115.17,89.74 114.88,89.45 114.12,89.45 113.26,88.6 v2(113.26,88.06)
  BOTTOM w0.102: JDIMM1.7 97.95,47.12 97.74,46.91 v2(97.02,46.91)
DDR_A_D2: length 58.9
  IN1 w0.076: v2(113.24,85.42) 113.24,84.65 112.89,84.31 112.89,79.16 109.43,75.7
  IN1 w0.114: v2(100.19,46.91) 100.19,46.69 100.04,46.54 99.78,46.54 99.67,46.64 99.67,47.07 99.78,47.17 99.78,47.65 99.67,47.75 99.67,48.66 100.91,49.89 100.91,50.59 103.51,53.19 103.51,61.06 103.86,61.42 103.86,61.69 103.43,62.12 103.43,65.22 103.57,65.37 104.17,65.37 104.3,65.5 104.3,65.8 104.12,65.98 103.62,65.98 103.43,66.17 103.43,67.13 103.59,67.29 104.68,67.29 104.84,67.45 104.84,67.71 104.73,67.83 104.41,67.83 104.3,67.94 104.3,68.26 104.41,68.37 104.73,68.37 104.84,68.49 104.84,68.82 106.2,70.17 106.81,70.17 107.46,70.82 107.46,73.72 109.43,75.7
  BOTTOM w0.076: UC1.AK63 117.13,88.36 116.9,88.12 114.67,88.12 113.24,86.69 v2(113.24,85.42)
  BOTTOM w0.102: JDIMM1.15 100.35,49.1 100.35,49.1 100.12,48.87 99.9,48.87 99.65,48.61 99.65,47.45 v2(100.19,46.91)
DDR_A_D3: length 59.5
  IN1 w0.076: 109.69,75.44 113.08,78.82 113.08,84.26 114.02,85.2 v2(114.02,86.24)
  IN1 w0.114: 109.69,75.44 107.83,73.57 107.83,70.67 106.97,69.8 106.35,69.8 105.21,68.66 105.21,67.03 105.1,66.92 103.93,66.92 103.8,66.79 103.8,66.48 103.93,66.35 105.1,66.35 105.21,66.23 105.21,66.01 104.7,65.5 104.7,65.12 104.59,65 103.93,65 103.81,64.89 103.81,64.55 103.93,64.43 104.59,64.43 104.7,64.32 104.7,63.97 104.59,63.86 103.93,63.86 103.81,63.75 103.81,63.4 103.93,63.29 104.59,63.29 104.7,63.17 104.7,62.83 104.59,62.72 103.93,62.72 103.81,62.6 103.81,62.26 103.93,62.15 104.59,62.15 104.7,62.03 104.7,61.73 103.88,60.91 103.88,53.04 101.28,50.43 101.28,49.74 100.64,49.1 100.64,48.19 100.51,48.06 100.33,48.06 100.19,48.2 v2(100.19,48.43)
  BOTTOM w0.076: v2(114.02,86.24) 114.02,87 114.98,87.96 116.99,87.96 117.11,88.08 117.88,88.08 UC1.AK62
  BOTTOM w0.102: JDIMM1.17 100.95,48.65 100.73,48.43 v2(100.19,48.43)
DDR_A_D4: length 61.4
  IN1 w0.076: v2(112.4,87.28) 111.76,87.28 110.88,86.39 110.88,81.26 109.1,79.48
  IN1 w0.114: 109.1,79.48 104.55,74.93 104.55,72.64 101.38,69.48 101.38,69.21 100.51,68.34 100.51,66.35 99.98,65.82 99.98,53.78 98,51.79 98,51.1 96.53,49.63 96.5,49.63 95.83,48.96 95.83,45.05 v2(97.02,43.86)
  BOTTOM w0.076: UC1.AH61 118.43,90.09 117.77,90.09 117.66,90.14 117.62,90.17 117.24,90.17 117.16,90.08 115.27,90.08 114.81,89.62 114.01,89.62 112.45,88.06 112.45,87.48 112.4,87.43 v2(112.4,87.28)
  BOTTOM w0.102: v2(97.02,43.86) 97.05,43.83 JDIMM1.4
DDR_A_D5: length 61.6
  IN1 w0.076: 109,78.86 111.08,80.94 111.08,85.96 v2(111.59,86.46)
  IN1 w0.114: 109,78.86 104.92,74.78 104.92,72.49 101.75,69.33 101.75,69.05 100.88,68.18 100.88,66.2 100.35,65.66 100.35,53.62 98.36,51.64 98.36,50.95 96.68,49.27 96.65,49.27 96.19,48.81 96.19,46.15 96.96,45.38 v2(97.02,45.38)
  BOTTOM w0.076: UC1.AH60 119.46,88.94 119.26,88.74 119.02,88.74 119,88.76 118.62,88.76 118.61,88.74 118.42,88.74 118.4,88.75 118.26,88.81 118.06,88.81 117.9,88.74 117.77,88.74 117.67,88.79 117.61,88.81 117.09,88.81 116.75,88.48 114.36,88.48 112.35,86.46 v2(111.59,86.46)
  BOTTOM w0.102: v2(97.02,45.38) 97.41,45.38 97.61,45.18 97.61,43.59 97.65,43.55 JDIMM1.6
DDR_A_D6: length 59.9
  IN1 w0.076: 109.17,75.96 112.42,79.21 v2(112.42,84.61)
  IN1 w0.114: 109.17,75.96 107.09,73.88 107.09,70.97 106.66,70.54 106.04,70.54 103.93,68.42 103.93,67.82 103.76,67.66 103.43,67.66 103.06,67.28 103.06,61.97 103.14,61.89 103.14,53.34 100.54,50.74 100.54,50.05 99.26,48.77 99.26,46.31 99.72,45.85 99.72,45.27 98.94,44.48 98.94,44.12 99.2,43.86 v2(100.19,43.86)
  BOTTOM w0.076: UC1.AK61 118.47,88.46 118.33,88.6 118.23,88.65 118.1,88.65 118.08,88.64 117.99,88.6 117.94,88.58 117.73,88.58 117.58,88.65 117.17,88.65 116.83,88.3 114.51,88.3 112.42,86.21 v2(112.42,84.61)
  BOTTOM w0.102: v2(100.19,43.86) 100.47,43.86 100.65,43.69 JDIMM1.16
DDR_A_D7: length 60.7
  IN1 w0.076: 109.95,75.18 113.26,78.48 113.26,84.21 114.51,85.45 v2(114.51,86.64)
  IN1 w0.114: v2(100.19,45.38) 100.19,45.26 100.69,44.76 100.87,44.76 101.01,44.9 101.01,45.73 100.89,45.84 100.73,45.84 100.61,45.96 100.61,46.3 100.73,46.41 100.89,46.41 101.01,46.53 101.01,46.87 100.89,46.98 100.73,46.98 100.61,47.1 100.61,47.44 100.73,47.56 100.89,47.56 101.01,47.67 101.01,48.95 101.65,49.59 101.65,50.28 104.25,52.88 104.25,60.76 105.07,61.58 105.07,65.35 105.58,65.86 105.58,68.51 106.5,69.43 107.12,69.43 108.2,70.51 108.2,73.42 109.95,75.18
  BOTTOM w0.076: UC1.AK60 119.23,88.46 118.93,88.17 118.69,88.17 118.67,88.19 118.41,88.19 118.13,87.91 117.18,87.91 117.05,87.79 115.12,87.79 114.51,87.18 v2(114.51,86.64)
  BOTTOM w0.102: v2(100.19,45.38) 100.19,45.54 100.28,45.62 100.79,45.62 101.25,45.17 JDIMM1.18
DDR_A_D8: length 53.9
  IN1 w0.076: 111.59,74.76 111.59,75.5 114.99,78.91 v2(114.99,84.91)
  IN1 w0.114: 111.59,74.76 111.59,74.36 109.93,72.7 109.93,69.8 108.33,68.2 108.33,65.89 107.91,65.47 107.91,65.33 107.8,65.22 107.61,65.22 107.5,65.11 107.5,64.76 107.61,64.65 107.8,64.65 107.91,64.53 107.91,64.19 107.8,64.08 107.61,64.08 107.5,63.96 107.5,63.62 107.61,63.51 107.8,63.51 107.91,63.39 107.91,63.05 107.8,62.93 107.61,62.93 107.5,62.82 107.5,62.48 107.61,62.36 107.8,62.36 107.91,62.25 107.91,61.98 105.98,60.04 105.98,52.17 103.37,49.57 103.37,48.52 102.93,48.07 102.93,47.53 102.48,47.08 v2(102.48,46.91)
  BOTTOM w0.076: UC1.AM63 117.33,87.28 117.27,87.21 116.12,87.21 114.94,86.04 114.94,84.97 v2(114.99,84.91)
  BOTTOM w0.102: JDIMM1.21 102.15,49.06 101.98,48.9 101.98,48.43 101.83,48.27 101.25,48.27 101.15,48.17 101.15,47.97 101.25,47.86 101.8,47.86 101.91,47.75 101.91,47.48 v2(102.48,46.91)
DDR_A_D9: length 55.1
  IN1 w0.076: 111.21,74.76 111.21,75.36 114.63,78.78 114.63,84.46 v2(114.58,84.51)
  IN1 w0.114: 111.21,74.76 111.21,74.5 109.56,72.86 109.56,69.95 107.96,68.35 107.96,68.08 107.85,67.97 107.6,67.97 107.37,67.74 107.37,67.58 107.48,67.47 107.85,67.47 107.96,67.35 107.96,67.01 107.85,66.9 107.05,66.9 106.94,66.78 106.94,66.44 107.05,66.32 107.85,66.32 107.96,66.21 107.96,66.04 107.51,65.59 107.46,65.59 107.13,65.26 107.13,65.01 107.01,64.9 106.54,64.9 106.43,64.79 106.43,64.44 106.54,64.33 107.01,64.33 107.13,64.21 107.13,63.87 107.01,63.76 106.54,63.76 106.43,63.64 106.43,63.3 106.54,63.19 107.01,63.19 107.13,63.07 107.13,62.32 107.34,62.11 107.34,61.93 105.61,60.2 105.61,52.32 103.01,49.72 103.01,48.7 102.74,48.43 v2(102.48,48.43)
  BOTTOM w0.076: UC1.AM62 117.92,87.28 117.63,87.57 117.39,87.57 117.21,87.39 116.06,87.39 114.51,85.84 114.51,84.58 v2(114.58,84.51)
  BOTTOM w0.102: v2(102.48,48.43) 102.48,48.23 102.67,48.03 102.85,48.03 103.02,48.2 103.02,48.87 102.75,49.14 102.75,49.14 JDIMM1.23
DDR_A_D10: length 53.2
  IN1 w0.076: v2(115.08,77.78) 115.08,77.23 113.48,75.63 113.48,74.76
  IN1 w0.114: 113.48,74.76 113.48,73.64 111.73,71.9 111.73,68.67 110.63,67.57 110.25,67.57 110.14,67.45 110.14,67.11 110.25,67 110.63,67 110.75,66.88 110.75,66.54 110.63,66.42 110.25,66.42 110.14,66.31 110.14,65.97 110.25,65.85 110.63,65.85 110.75,65.74 110.75,65.4 110.41,65.05 110.05,65.05 109.72,64.72 109.72,60.65 110.05,60.32 110.2,60.32 110.32,60.19 110.32,60.04 110,59.72 109.84,59.72 109.11,60.46 108.95,60.46 108.71,60.21 108.71,60.05 109.44,59.32 109.44,59.16 109.2,58.92 109.03,58.92 108.3,59.65 108.14,59.65 107.9,59.41 107.9,59.24 108.63,58.51 108.63,58.35 108.39,58.11 108.39,52.5 107.79,51.89 107.79,51.23 107.01,50.46 106.87,50.46 105.57,49.16 105.57,48.59 v2(105.4,48.43)
  BOTTOM w0.076: v2(115.08,77.78) 115.08,79.16 115.89,79.98 115.89,84.7 117.12,85.93 UC1.AP63
  BOTTOM w0.102: JDIMM1.33 105.75,49.07 106.05,48.77 106.05,48.01 105.95,47.91 105.74,47.91 105.67,47.98 105.67,48.17 v2(105.4,48.43)
DDR_A_D11: length 54.4
  IN1 w0.076: 113.85,74.76 113.85,75.62 115.85,77.62 115.85,78.54 v2(115.88,78.56)
  IN1 w0.114: 113.85,74.76 113.85,73.49 112.1,71.75 112.1,68.51 111.12,67.53 111.12,65.24 110.56,64.69 110.2,64.69 110.09,64.57 110.09,64.23 110.2,64.11 110.56,64.11 110.67,64 110.67,63.66 110.56,63.54 110.2,63.54 110.09,63.43 110.09,63.08 110.2,62.97 110.56,62.97 110.67,62.86 110.67,62.51 110.56,62.4 110.2,62.4 110.09,62.28 110.09,61.94 110.2,61.83 110.56,61.83 110.67,61.71 110.67,61.37 110.56,61.26 110.2,61.26 110.09,61.14 110.09,60.8 110.2,60.68 110.63,60.68 110.79,60.53 110.79,59.98 108.76,57.96 108.76,52.35 108.15,51.74 108.15,51.08 107.17,50.1 107.03,50.1 105.96,49.03 105.96,46.62 105.85,46.51 105.62,46.51 105.4,46.72 v2(105.4,46.91)
  BOTTOM w0.076: v2(115.88,78.56) 115.88,79.63 116.06,79.81 116.06,84.63 117.06,85.63 117.63,85.63 117.92,85.93 UC1.AP62
  BOTTOM w0.102: v2(105.4,46.91) 105.42,46.89 105.79,46.89 105.95,46.74 105.95,46.57 106.05,46.46 106.3,46.46 106.4,46.57 106.4,49.1 106.35,49.16 JDIMM1.35
DDR_A_D12: length 55.5
  IN1 w0.076: 110.42,74.76 110.42,75.39 113.44,78.41 113.44,84.15 114.89,85.6 114.89,86.31 115.29,86.72 v2(115.29,87.43)
  IN1 w0.114: v2(102.48,43.86) 101.63,44.71 101.63,48.69 102.27,49.33 102.27,50.02 104.87,52.63 104.87,60.5 105.69,61.32 105.69,65.09 106.2,65.6 106.2,67.64 108.82,70.25 108.82,73.16 110.42,74.76
  BOTTOM w0.076: UC1.AM61 118.68,87.17 118.28,87.57 117.87,87.57 117.7,87.73 117.23,87.73 117.12,87.63 115.49,87.63 v2(115.29,87.43)
  BOTTOM w0.102: v2(102.48,43.86) 102.45,43.83 JDIMM1.22
DDR_A_D13: length 56.2
  IN1 w0.076: 110.82,74.76 110.82,75.21 114.05,78.43 114.05,83.47 v2(113.87,83.64)
  IN1 w0.114: 110.82,74.76 110.82,74.64 109.19,73.01 109.19,70.1 106.57,67.48 106.57,66.29 106.91,65.94 106.91,65.59 106.6,65.27 106.39,65.27 106.06,64.94 106.06,63.15 106.39,62.82 106.56,62.82 106.76,62.61 106.76,61.87 105.24,60.35 105.24,52.47 102.64,49.87 102.64,49.18 102.01,48.55 102.01,45.85 v2(102.48,45.38)
  BOTTOM w0.076: v2(113.87,83.64) 114.37,83.64 117.11,86.38 117.61,86.38 117.77,86.31 117.9,86.31 118.06,86.38 118.27,86.38 118.32,86.36 118.4,86.32 118.42,86.31 119.26,86.31 119.46,86.51 UC1.AM60
  BOTTOM w0.102: v2(102.48,45.38) 102.93,45.38 103.05,45.27 JDIMM1.24
DDR_A_D14: length 53.9
  IN1 w0.076: 113.11,74.76 113.11,75.82 v2(114.29,77)
  IN1 w0.114: 113.11,74.76 113.11,73.8 111.37,72.05 111.37,68.82 110.48,67.94 110.1,67.94 109.77,67.61 109.77,65.3 109.35,64.88 109.35,61 109.17,60.83 108.8,60.83 107.53,59.56 107.53,59.09 107.83,58.79 108.03,58.6 108.03,52.65 107.42,52.04 107.42,51.39 106.86,50.83 106.72,50.83 104.88,48.99 104.88,45.33 104.77,45.23 104.2,45.23 104.07,45.09 104.07,44.82 104.2,44.69 104.57,44.69 v2(105.4,43.86)
  BOTTOM w0.076: v2(114.29,77) 114.29,78.73 115.73,80.17 115.73,84.77 117.18,86.22 117.58,86.22 117.68,86.17 117.73,86.14 117.94,86.14 117.99,86.17 117.99,86.17 118.08,86.21 118.1,86.22 118.23,86.22 118.33,86.17 118.58,85.93 UC1.AP61
  BOTTOM w0.102: JDIMM1.34 106.05,42.89 106.05,42.89 105.59,43.35 105.59,43.68 v2(105.4,43.86)
DDR_A_D15: length 55.2
  IN1 w0.076: 114.21,74.76 114.21,75.68 116.13,77.6 116.13,78.13 116.67,78.67 v2(116.67,79.38)
  IN1 w0.114: v2(105.4,45.38) 105.4,45.19 105.61,44.99 105.64,44.99 105.82,44.81 105.82,44.45 105.97,44.3 106.25,44.3 106.38,44.43 106.38,45.59 106.56,45.77 106.56,45.97 106.33,46.2 106.33,48.88 107.18,49.73 107.32,49.73 108.52,50.93 108.52,51.59 108.76,51.83 108.94,51.83 109.13,52.02 109.13,57.81 111.15,59.83 111.15,60.04 111.38,60.27 111.38,60.55 111.04,60.89 111.04,64.65 111.48,65.09 111.48,67.38 112.47,68.36 112.47,71.41 114.21,73.15 114.21,74.76
  BOTTOM w0.076: UC1.AP60 119.23,85.93 118.93,85.63 118.69,85.63 118.68,85.64 118.29,85.64 118.28,85.63 117.87,85.63 117.7,85.47 117.13,85.47 116.22,84.56 116.22,81.06 116.26,81.03 116.26,79.78 v2(116.67,79.38)
  BOTTOM w0.102: v2(105.4,45.38) 105.9,45.38 106.32,44.97 106.32,43.25 106.65,42.92 JDIMM1.36
DDR_A_D16: length 48.6
  IN1 w0.076: 115.57,74.76 115.57,75.9 118.09,78.41 118.09,79 117.78,79.3 117.78,79.71 119.13,81.05 v2(119.94,81.05)
  IN1 w0.114: v2(107.87,48.32) 107.87,48.35 110.14,50.62 110.14,50.92 110.49,51.27 110.49,57.25 112.51,59.27 112.51,59.48 113.52,60.49 113.52,61.23 113.41,61.34 112.51,61.34 112.4,61.45 112.4,61.8 112.51,61.91 113.41,61.91 113.52,62.03 113.52,62.37 113.41,62.48 112.51,62.48 112.4,62.6 112.4,62.94 112.51,63.05 113.41,63.05 113.52,63.17 113.52,63.51 113.41,63.63 112.51,63.63 112.4,63.74 112.4,64.08 112.51,64.2 113.41,64.2 113.52,64.31 113.52,67.46 113.83,67.76 113.83,70.85 115.57,72.59 115.57,74.76
  BOTTOM w0.076: v2(119.94,81.05) 120.24,81.05 120.58,81.4 120.58,82.24 UC1.AY58
  BOTTOM w0.102: JDIMM1.39 107.55,49.01 107.28,48.74 107.28,48.48 107.47,48.29 107.83,48.29 v2(107.87,48.32)
DDR_A_D17: length 49.6
  IN1 w0.076: 115.2,74.76 115.2,75.83 117.34,77.97 117.34,78.42 v2(117.33,78.44)
  IN1 w0.114: 115.2,74.76 115.2,72.74 113.46,71 113.46,67.91 113.16,67.61 113.16,67.19 113.04,67.08 112.59,67.08 112.48,66.97 112.48,66.62 112.59,66.51 113.04,66.51 113.16,66.39 113.16,66.07 113.02,65.93 112.67,65.93 112.49,65.75 112.49,64.69 112.03,64.24 112.03,61.3 112.36,60.97 113.01,60.97 113.14,60.84 113.14,60.62 112.14,59.63 112.14,59.42 110.12,57.4 110.12,51.42 109.77,51.07 109.77,50.78 107.73,48.74 107.59,48.74 107.32,48.47 107.32,46.61 107.5,46.43 107.7,46.43 107.87,46.6 v2(107.87,46.8)
  BOTTOM w0.076: UC1.AW58 120.41,82.72 120.41,81.62 120.2,81.41 119.58,81.41 119.05,80.88 119.05,80.67 117.35,78.97 117.35,78.46 v2(117.33,78.44)
  BOTTOM w0.102: JDIMM1.41 108.15,48.87 108.36,48.66 108.36,47.02 108.15,46.8 v2(107.87,46.8)
DDR_A_D18: length 49.3
  IN1 w0.076: v2(118.34,76.94) 118.38,76.9 118.38,76.47 117.77,75.86 117.77,74.76
  IN1 w0.114: 117.77,74.76 117.77,71.59 116.81,70.63 116.69,70.63 116.01,69.95 116.01,67.36 116.33,67.03 116.33,66.78 116.22,66.67 115.82,66.67 115.7,66.55 115.7,66.21 115.82,66.1 116.22,66.1 116.33,65.98 116.33,65.64 116.22,65.52 115.82,65.52 115.7,65.41 115.7,65.07 115.82,64.95 116.22,64.95 116.33,64.84 116.33,64.5 116.22,64.38 115.82,64.38 115.7,64.27 115.7,63.92 115.82,63.81 116.22,63.81 116.33,63.7 116.33,63.35 116.22,63.24 115.82,63.24 115.7,63.12 115.7,62.78 115.82,62.67 116.22,62.67 116.33,62.55 116.33,62.21 116.22,62.1 115.82,62.1 115.7,61.98 115.7,61.64 115.82,61.52 116.22,61.52 116.33,61.41 116.33,61.07 116.22,60.95 115.82,60.95 115.7,60.84 115.7,60.5 115.82,60.38 116.06,60.38 116.21,60.23 116.21,60.09 114.69,58.57 114.69,58.22 113.72,57.25 113.58,57.25 112.67,56.34 112.67,52.08 112.79,51.95 112.79,50.86 112.88,50.77 112.88,50.58 112.32,50.02 112.32,49.69 111.71,49.09 111.71,48.69 112.09,48.32 112.09,47.65 111.94,47.5 111.79,47.5 111.51,47.78 111.4,47.78 111.32,47.86 v2(111.32,48.12)
  BOTTOM w0.076: UC1.AY56 121.98,82.28 121.98,81.48 118.32,77.82 118.32,76.96 v2(118.34,76.94)
  BOTTOM w0.102: v2(111.32,48.12) 111.48,48.29 111.48,48.44 111.36,48.57 111.04,48.57 110.95,48.66 110.95,48.9 111.15,49.09 111.15,49.09 JDIMM1.51
DDR_A_D19: length 50.1
  IN1 w0.076: 118.14,74.76 118.14,75.83 118.47,76.16 118.47,76.3 119.13,76.96 v2(119.13,77.75)
  IN1 w0.114: 118.14,74.76 118.14,71.44 117.39,70.68 117.39,70.42 117.23,70.26 116.84,70.26 116.37,69.79 116.37,67.51 116.7,67.19 116.7,60.06 115.06,58.42 115.06,58.07 114.15,57.16 114.15,56.98 114.06,56.89 113.73,56.89 113.03,56.19 113.03,52.23 113.16,52.11 113.16,51.01 113.38,50.79 113.38,50.56 112.68,49.86 112.68,49.54 112.46,49.32 112.46,45.35 112.27,45.16 111.94,45.16 111.73,45.38 111.73,46.01 111.32,46.42 v2(111.32,46.6)
  BOTTOM w0.076: UC1.AW56 122.35,82.72 122.35,82.24 122.14,82.03 122.14,81.41 119.13,78.4 v2(119.13,77.75)
  BOTTOM w0.102: v2(111.32,46.6) 111.32,46.59 111.69,46.59 111.81,46.72 111.81,46.97 111.94,47.1 112.34,47.1 112.45,47.21 112.45,47.37 112.34,47.48 111.85,47.48 111.75,47.58 JDIMM1.53
DDR_A_D20: length 50.3
  IN1 w0.076: 115.94,74.76 115.94,75.98 118.27,78.31 v2(118.27,79.35)
  IN1 w0.114: 115.94,74.76 115.94,72.44 114.2,70.7 114.2,67.61 113.89,67.3 113.89,60.34 112.88,59.32 112.88,59.12 110.86,57.09 110.86,51.12 110.51,50.77 110.51,50.47 108.28,48.25 108.28,45.72 v2(107.84,45.28)
  BOTTOM w0.076: v2(118.27,79.35) 119.26,79.35 121.09,81.18 121.19,81.18 121.64,81.64 121.64,82.12 121.6,82.17 121.6,82.46 121.67,82.62 121.67,82.75 121.6,82.91 121.6,83.11 121.62,83.16 121.66,83.24 121.66,84.1 121.49,84.26 121.26,84.26 120.7,83.7 UC1.AV58
  BOTTOM w0.102: v2(107.84,45.28) 107.45,44.88 107.45,43.56 107.85,43.16 JDIMM1.40
DDR_A_D21: length 50.6
  IN1 w0.076: 114.84,74.76 114.84,76 116.44,77.6
  IN1 w0.107: v2(116.51,77.68) 116.44,77.6
  IN1 w0.114: 114.84,74.76 114.84,72.9 113.09,71.15 113.09,68.07 112.79,67.76 112.79,67.57 112.66,67.45 112.44,67.45 112.11,67.12 112.11,66.47 112.3,66.28 112.3,66.08 112.12,65.9 112.12,64.84 111.66,64.39 111.66,61.15 112.27,60.54 112.27,60.28 111.78,59.78 111.78,59.57 109.75,57.55 109.75,51.57 109.4,51.22 109.4,50.93 107.58,49.1 107.44,49.1 106.95,48.62 106.95,46.46 107.4,46.01 107.4,45.52 107.28,45.41 107.13,45.41 107.01,45.29 107.01,44.95 107.13,44.84 107.28,44.84 107.4,44.72 107.4,43.97 107.61,43.75 v2(107.84,43.75)
  BOTTOM w0.076: UC1.AU58 120.7,84.14 120.39,83.83 120.39,83.56 120.48,83.47 120.48,83.25 119.73,82.5 119.73,82.13 119.66,82.06 119.66,81.72 118.77,80.83 118.77,80.63 116.51,78.37 v2(116.51,77.68)
  BOTTOM w0.102: JDIMM1.42 108.45,43.57 108.28,43.75 v2(107.84,43.75)
DDR_A_D22: length 50.6
  IN1 w0.076: 117.4,74.76 117.4,76.05 v2(117.53,76.18)
  IN1 w0.114: 117.4,74.76 117.4,71.74 116.66,71 116.54,71 115.64,70.1 115.64,67.01 115.33,66.71 115.33,60.34 115.52,60.15 115.52,59.93 114.32,58.73 114.32,58.37 113.57,57.62 113.42,57.62 112.3,56.5 112.3,51.92 112.42,51.8 112.42,50.64 111.95,50.17 111.95,49.85 110.88,48.78 110.88,45.75 110.69,45.56 110.14,45.56 110.01,45.43 110.01,45.14 110.17,44.98 110.72,44.98 110.9,44.8 110.9,44.53 110.74,44.37 109.99,44.37 109.83,44.22 109.83,43.87 109.96,43.74 111.12,43.74 v2(111.32,43.55)
  BOTTOM w0.076: UC1.AV56 121.95,83.31 121.81,83.18 121.79,83.13 121.76,83.07 121.76,82.94 121.77,82.92 121.81,82.84 121.83,82.79 121.83,82.55 121.81,82.53 121.76,82.42 121.76,82.24 121.81,82.19 121.81,81.55 117.53,77.27 v2(117.53,76.18)
  BOTTOM w0.102: JDIMM1.50 110.85,43.08 v2(111.32,43.55)
DDR_A_D23: length 51.6
  IN1 w0.076: v2(119.97,78.49) 119.94,78.46 119.94,77.52 118.84,76.42 118.84,76.3 118.51,75.97 118.51,74.76
  IN1 w0.114: 118.51,74.76 118.51,71.28 117.75,70.53 117.75,70.2 117.45,69.89 117,69.89 116.74,69.64 116.74,67.66 117.07,67.34 117.07,59.91 115.43,58.27 115.43,57.92 114.52,57.01 114.52,56.66 114.38,56.52 113.88,56.52 113.4,56.04 113.4,52.38 113.53,52.26 113.53,51.16 113.83,50.86 113.83,50.49 113.14,49.8 113.14,49.47 112.83,49.16 112.83,44.96 112.83,44.17 112.6,43.94 112.32,43.94 111.32,44.95 v2(111.32,45.07)
  BOTTOM w0.076: v2(119.97,78.49) 119.94,78.51 119.94,78.98 122.31,81.34 122.31,81.96 122.51,82.17 122.51,83.15 122.23,83.43 122.23,83.53 122.24,83.54 122.24,83.78 121.95,84.07 UC1.AU56
  BOTTOM w0.102: v2(111.32,45.07) 111.67,45.07 111.9,44.84 111.9,43.27 111.45,42.82 JDIMM1.52
DDR_A_D24: length 46.9
  IN1 w0.076: v2(120.77,79.3) 120.77,79.3 120.77,79.29 120.78,79.29 120.78,78.11 119.13,76.46 119.13,74.76
  IN1 w0.114: 119.13,74.76 119.13,71.03 118.38,70.27 118.38,69.94 117.69,69.26 117.69,59.65 116.05,58.01 116.05,57.66 115.14,56.75 115.14,56.01 115.03,55.89 114.14,55.89 114.02,55.78 114.02,55.44 114.14,55.32 115.03,55.32 115.14,55.21 115.14,54.87 115.03,54.75 114.14,54.75 114.02,54.64 114.02,54.29 114.14,54.18 115.03,54.18 115.14,54.07 115.14,53.85 114.9,53.61 114.24,53.61 114.04,53.41 114.04,52.63 114.43,52.23 114.43,52.05 114.15,51.76 114.15,51.42 114.61,50.96 114.61,50.39 113.76,49.54 113.76,49.21 113.47,48.92 113.47,48.69 113.76,48.4 113.76,48.19 113.63,48.06 113.51,48.06 v2(113.45,48.12)
  BOTTOM w0.076: v2(120.77,79.3) 120.77,79.3 120.77,79.29 120.78,79.29 120.78,79.3 120.81,79.28 121.57,79.28 122.8,80.51 122.8,81.76 123.01,81.96 123.01,82.23 UC1.AY54
  BOTTOM w0.102: JDIMM1.57 112.95,49.17 112.68,48.9 112.68,48.57 113.18,48.06 113.39,48.06 v2(113.45,48.12)
DDR_A_D25: length 47.7
  IN1 w0.076: v2(121.18,79.7) 121.16,79.7 121.16,79.68 121.19,79.68 121.19,78.16 119.5,76.47 119.5,74.76
  IN1 w0.114: v2(113.45,46.6) 113.54,46.51 113.64,46.51 114.3,47.17 114.3,47.34 114.19,47.45 114.08,47.45 113.95,47.58 113.95,47.86 114.13,48.03 114.13,49.39 114.99,50.24 114.99,50.96 115.29,51.27 115.29,51.43 115.17,51.55 115.1,51.55 114.99,51.66 114.99,51.98 115.1,52.09 115.17,52.09 115.29,52.21 115.29,52.55 115.17,52.67 114.52,52.67 114.41,52.78 114.41,53.12 114.52,53.24 115.17,53.24 115.29,53.35 115.29,53.47 115.51,53.7 115.51,56.6 116.42,57.51 116.42,57.86 118.06,59.5 118.06,69.1 118.74,69.79 118.74,70.12 119.5,70.87 119.5,74.76
  BOTTOM w0.076: v2(121.18,79.7) 121.16,79.7 121.16,79.68 121.19,79.68 121.19,79.68 121.21,79.66 121.67,79.66 122.64,80.62 122.64,81.83 122.84,82.03 122.84,82.48 123.13,82.77 UC1.AW54
  BOTTOM w0.102: v2(113.45,46.6) 113.54,46.51 113.9,46.51 114.14,46.75 114.14,48.37 113.55,48.97 JDIMM1.59
DDR_A_D26: length 47.7
  IN1 w0.076: 123.42,74.76 v2(123.42,78.72)
  IN1 w0.114: v2(117.14,46.6) 117.14,46.42 117.58,45.98 117.58,45.7 117.76,45.52 118.05,45.52 118.24,45.71 118.24,46.04 117.8,46.48 117.8,48.41 118.43,49.03 118.43,50.46 118.2,50.68 118.2,52.26 118.43,52.49 118.43,55.39 119.33,56.3 119.33,56.65 121.81,59.13 121.81,63.53 121.02,64.31 121.02,67.95 121.66,68.58 121.66,68.91 122.41,69.67 122.41,73.25 123.15,73.99 123.15,74.47 123.42,74.73 123.42,74.76
  BOTTOM w0.076: UC1.AY52 124.36,82.23 124.36,81.31 124.97,80.7 124.97,79.68 124.01,78.72 v2(123.42,78.72)
  BOTTOM w0.102: v2(117.14,46.6) 116.1,46.6 115.95,46.75 JDIMM1.67
DDR_A_D27: length 48
  IN1 w0.076: v2(122.64,77.9) 122.61,77.88 122.61,74.76
  IN1 w0.114: v2(117.14,48.12) 117.34,48.12 117.43,48.21 117.43,48.44 117.17,48.69 117.17,48.83 117.34,49 117.87,49 118.06,49.18 118.06,49.39 117.94,49.5 117.64,49.5 117.53,49.62 117.53,49.91 117.64,50.02 117.94,50.02 118.06,50.14 118.06,50.3 117.83,50.53 117.83,52.42 118.06,52.64 118.06,55.55 118.96,56.45 118.96,56.8 121.44,59.28 121.44,60.11 121.33,60.22 120.77,60.22 120.65,60.34 120.65,60.68 120.77,60.79 121.33,60.79 121.44,60.91 121.44,61.25 121.33,61.36 120.77,61.36 120.65,61.48 120.65,61.82 120.77,61.94 121.33,61.94 121.44,62.05 121.44,62.39 121.33,62.51 120.77,62.51 120.65,62.62 120.65,62.97 120.77,63.08 121.33,63.08 121.44,63.19 121.44,63.37 120.65,64.16 120.65,68.1 121.29,68.74 121.29,69.07 122.04,69.82 122.04,73.4 122.61,73.96 122.61,74.76
  BOTTOM w0.076: v2(122.64,77.9) 123.47,77.9 125.15,79.58 125.15,80.79 124.52,81.42 124.52,81.98 124.78,82.23 124.78,82.42 124.73,82.52 124.73,82.53 124.7,82.58 124.7,82.94 124.63,83.01 UC1.AW52
  BOTTOM w0.102: v2(117.14,48.12) 117.03,48.01 116.75,48.01 116.55,48.22 JDIMM1.69
DDR_A_D28: length 48.5
  IN1 w0.076: 119.87,74.76 119.87,76.58 121.54,78.26 121.54,79.25 121.95,79.66 121.95,80.47 v2(121.98,80.49)
  IN1 w0.114: 119.87,74.76 119.87,70.72 119.11,69.97 119.11,69.64 118.43,68.95 118.43,59.35 116.78,57.71 116.78,57.35 115.88,56.45 115.88,53.54 115.65,53.32 115.65,51.11 115.35,50.81 115.35,50.09 114.91,49.65 114.91,49.37 114.79,49.25 114.62,49.25 114.51,49.14 114.51,48.8 114.62,48.68 114.79,48.68 114.91,48.57 114.91,48.23 114.79,48.11 114.62,48.11 114.51,48 114.51,47.65 114.62,47.54 114.79,47.54 114.91,47.43 114.91,47.25 114.2,46.54 114.2,46.09 113.96,45.85 113.96,44.85 113.82,44.71 113.59,44.71 113.45,44.85 v2(113.45,45.07)
  BOTTOM w0.076: v2(121.98,80.49) 122,80.49 122.47,80.96 122.47,81.89 122.68,82.1 122.68,82.96 123.24,83.53 UC1.AV54
  BOTTOM w0.102: JDIMM1.56 112.65,44.9 112.82,45.07 v2(113.45,45.07)
DDR_A_D29: length 48.9
  IN1 w0.076: 120.24,74.76 120.24,76.7 123.04,79.5 v2(124.21,79.5)
  IN1 w0.114: v2(113.45,43.55) 113.86,43.55 114.33,44.02 114.33,45.7 114.56,45.93 114.56,46.39 114.81,46.63 114.99,46.63 115.28,46.92 115.28,49.49 115.72,49.94 115.72,50.66 116.02,50.96 116.02,53.17 116.25,53.39 116.25,56.3 117.15,57.2 117.15,57.55 118.8,59.2 118.8,68.8 119.48,69.48 119.48,69.81 120.24,70.57 120.24,74.76
  BOTTOM w0.076: v2(124.21,79.5) 124.01,79.71 124.01,81.93 124.03,81.95 124.03,82.46 124.05,82.51 124.05,82.51 124.1,82.62 124.1,82.75 124.03,82.91 124.03,83.11 124.05,83.16 124.09,83.25 124.1,83.27 124.1,84.1 123.9,84.31 UC1.AU54
  BOTTOM w0.102: JDIMM1.58 113.25,43.34 v2(113.45,43.55)
DDR_A_D30: length 49.1
  IN1 w0.076: v2(124.62,80.51) 125,80.13 125,78.31 124.03,77.35 124.03,74.82 123.97,74.76
  IN1 w0.114: 123.97,74.76 123.52,74.31 123.52,73.84 122.78,73.09 122.78,69.51 122.03,68.76 122.03,68.43 121.39,67.79 121.39,64.47 122.18,63.68 122.18,58.98 119.7,56.5 119.7,56.15 118.79,55.24 118.79,52.34 118.57,52.11 118.57,50.83 118.79,50.61 118.79,48.88 118.17,48.25 118.17,46.64 118.5,46.3 118.64,46.17 118.64,45.64 118.9,45.37 118.9,44.87 118.58,44.55 117.66,44.55 v2(117.14,45.07)
  BOTTOM w0.076: UC1.AV52 124.38,83.31 124.24,83.18 124.22,83.13 124.19,83.07 124.19,82.94 124.2,82.92 124.24,82.84 124.24,82.84 124.27,82.79 124.27,82.58 124.24,82.53 124.19,82.42 124.19,81.82 124.17,81.8 124.17,80.95 v2(124.62,80.51)
  BOTTOM w0.102: JDIMM1.68 116.25,42.81 116.45,43.02 116.45,44.73 116.79,45.07 v2(117.14,45.07)
DDR_A_D31: length 49.3
  IN1 w0.076: v2(122.25,77.5) 122.28,77.47 122.28,74.8 122.24,74.76
  IN1 w0.114: v2(117.14,43.55) 117.03,43.44 116.82,43.44 116.72,43.54 116.72,48.9 117.16,49.34 117.16,50.06 117.46,50.36 117.46,52.57 117.69,52.79 117.69,55.7 118.59,56.6 118.59,56.96 121.07,59.44 121.07,59.69 120.91,59.85 120.62,59.85 120.29,60.18 120.29,63.12 120.54,63.37 120.54,63.76 120.29,64.01 120.29,68.25 120.92,68.89 120.92,69.22 121.68,69.97 121.68,73.55 122.24,74.12 122.24,74.76
  BOTTOM w0.076: v2(122.25,77.5) 122.35,77.41 123.74,77.41 125.38,79.04 125.38,80.8 124.69,81.49 124.69,81.91 124.94,82.16 124.94,82.46 124.92,82.51 124.87,82.62 124.87,83.92 UC1.AU52
  BOTTOM w0.102: v2(117.14,43.55) 117.14,43.41 116.85,43.12 JDIMM1.70
DDR_A_D32: length 46.5
  IN1 w0.076: 139.29,71.97 139.29,72.02 138.13,73.18 138.13,73.79 137.33,74.59 137.33,78 137.47,78.14 137.47,79.05 v2(137.85,79.43)
  IN1 w0.114: v2(136.51,46.37) 135.7,45.57 135.31,45.57 135.09,45.79 135.09,46.02 135.62,46.54 135.62,47.29 136.05,47.72 136.05,48.17 136.1,48.23 136.1,49.85 136.8,50.55 136.8,52.49 137.3,52.98 137.3,53.67 137.84,54.21 137.84,56.73 139.29,58.18 139.29,59.22 139.72,59.65 139.72,67.82 139.29,68.25 139.29,71.97
  BOTTOM w0.076: v2(137.85,79.43) 137.05,80.23 137.05,82.05 UC1.AY31
  BOTTOM w0.102: v2(136.51,46.37) 135.99,46.89 135.99,48.44 136.16,48.62 136.57,48.62 136.95,49 JDIMM1.129
DDR_A_D33: length 47.4
  IN1 w0.076: 139.65,71.97 139.65,72.16 138.34,73.48 138.34,73.84 137.49,74.68 137.49,77.93 v2(137.85,78.29)
  IN1 w0.114: v2(136.51,47.9) 136.47,47.94 136.47,48.7 136.58,48.81 137.02,48.81 137.14,48.93 137.14,49.2 137.02,49.31 136.58,49.31 136.47,49.42 136.47,49.67 136.61,49.81 137.06,49.81 137.19,49.94 137.19,50.45 137.32,50.57 137.54,50.57 137.67,50.7 137.67,50.93 137.56,51.05 137.29,51.05 137.17,51.16 137.17,51.39 137.29,51.5 137.56,51.5 137.67,51.62 137.67,51.85 137.56,51.96 137.29,51.96 137.17,52.08 137.17,52.34 137.31,52.48 138,52.48 138.11,52.59 138.11,52.94 138.01,53.04 137.77,53.04 137.67,53.14 137.67,53.44 137.79,53.57 138.08,53.57 138.21,53.7 138.21,54.31 138.33,54.42 138.47,54.42 138.59,54.54 138.59,54.88 138.47,54.99 138.33,54.99 138.21,55.11 138.21,55.45 138.33,55.57 138.47,55.57 138.59,55.68 138.59,56.02 138.47,56.14 138.33,56.14 138.21,56.25 138.21,56.58 139.66,58.02 139.66,59.06 140.09,59.5 140.09,67.97 139.65,68.41 139.65,71.97
  BOTTOM w0.076: UC1.AW31 137.36,82.81 137.16,82.61 137.07,82.43 137.07,82.37 136.89,82.19 136.89,79.25 v2(137.85,78.29)
  BOTTOM w0.102: v2(136.51,47.9) 136.51,47.7 136.99,47.22 137.29,47.22 137.55,47.48 JDIMM1.131
DDR_A_D34: length 46.5
  IN1 w0.076: v2(139.25,76.08) 139.27,76.08 139.6,75.75 139.6,74.99 139.66,74.93 139.66,74.06 140.88,72.84 141.93,72.84 142.57,72.2 142.57,71.97
  IN1 w0.114: v2(140.47,47.87) 140.38,47.78 140.21,47.78 140.07,47.92 140.07,48.7 140.1,48.73 140.1,49.01 140.59,49.5 140.59,50.24 140.67,50.33 140.67,50.65 140.59,50.73 140.59,50.94 141.03,51.38 141.03,52.4 141.13,52.5 141.13,52.96 141.34,53.16 141.76,53.16 141.89,53.29 141.89,53.52 141.76,53.65 141.63,53.65 141.5,53.78 141.5,54 141.61,54.11 141.77,54.11 141.89,54.23 141.89,54.46 141.77,54.57 141.61,54.57 141.5,54.68 141.5,54.91 141.61,55.03 141.77,55.03 141.89,55.14 141.89,55.37 141.77,55.48 141.61,55.48 141.5,55.6 141.5,55.75 142.57,56.82 142.57,56.99 142.69,57.11 142.87,57.11 142.98,57.22 142.98,57.45 142.87,57.56 142.69,57.56 142.57,57.68 142.57,57.86 143,58.29 143,62.3 143.22,62.52 143.22,62.88 143,63.09 143,66.49 143.12,66.6 143.17,66.6 143.29,66.72 143.29,66.95 143.17,67.06 143.12,67.06 143,67.18 143,67.4 143.12,67.52 143.17,67.52 143.29,67.63 143.29,67.86 143.17,67.98 143.12,67.98 143,68.09 143,68.32 143.12,68.43 143.17,68.43 143.29,68.55 143.29,68.78 143.17,68.89 143.12,68.89 143,69 143,69.18 142.57,69.61 142.57,69.75 142.68,69.86 143.1,69.86 143.23,70 143.23,70.18 143.1,70.32 142.68,70.32 142.57,70.43 142.57,71.97
  BOTTOM w0.076: UC1.AY29 138.72,81.66 138.56,81.5 138.56,76.71 139.2,76.08 v2(139.25,76.08)
  BOTTOM w0.102: JDIMM1.141 140.55,49.07 140.87,48.74 140.87,47.58 140.77,47.47 140.62,47.47 140.47,47.62 v2(140.47,47.87)
DDR_A_D35: length 47.4
  IN1 w0.076: 142.98,71.97 142.98,72.04 142.02,73 140.95,73 139.82,74.13 139.82,74.71 139.82,74.71 139.82,75 139.78,75.04 139.78,76.68 139.27,77.19 v2(139.25,77.19)
  IN1 w0.114: v2(140.47,46.33) 140.47,46.18 140.64,46 140.8,46 140.95,46.15 140.95,48.82 140.8,48.97 140.8,49.19 140.95,49.34 140.95,50.09 141.04,50.17 141.04,50.87 141.39,51.23 141.39,52.24 141.5,52.35 141.5,52.69 141.61,52.8 141.91,52.8 142.26,53.14 142.26,55.97 143.37,57.09 143.37,57.58 143.18,57.77 143.18,57.95 143.26,58.03 143.37,58.14 143.37,62.15 143.59,62.37 143.59,63.03 143.37,63.25 143.37,66.28 143.65,66.57 143.65,68.93 143.37,69.21 143.37,69.54 143.62,69.78 143.62,70.41 143.34,70.69 143.1,70.69 142.98,70.81 142.98,71.97
  BOTTOM w0.076: v2(139.25,77.19) 139.27,77.19 138.72,77.74 138.72,81.43 138.88,81.59 138.88,82.11 139.01,82.24 139.01,82.72 UC1.AW29
  BOTTOM w0.102: JDIMM1.143 141.15,46.25 140.95,46.05 140.67,46.05 140.47,46.26 v2(140.47,46.33)
DDR_A_D36: length 47.9
  IN1 w0.076: 140.39,71.97 140.39,72.06 138.73,73.72 138.73,74 138.26,74.48 138.26,76.74 v2(137.85,77.14)
  IN1 w0.114: 140.39,71.97 140.39,68.71 140.83,68.28 140.83,59.19 140.39,58.76 140.39,57.72 139.32,56.65 139.32,54.23 138.96,53.86 138.96,53.41 138.85,53.3 138.85,52.28 138.41,51.84 138.41,50.4 137.93,49.92 137.93,49.63 137.9,49.6 137.9,48.64 137.32,48.06 137.32,45.58 137.43,45.47 137.74,45.47 137.85,45.35 137.85,45.01 137.74,44.9 137.43,44.9 137.32,44.78 137.32,44.44 137.43,44.33 137.74,44.33 137.85,44.21 137.85,43.87 137.74,43.75 137.43,43.75 137,43.32 v2(136.51,43.32)
  BOTTOM w0.076: v2(137.85,77.14) 136.72,78.27 136.72,82.28 136.91,82.47 136.93,82.51 136.98,82.61 136.98,83.27 UC1.AV31
  BOTTOM w0.102: JDIMM1.130 137.25,42.83 136.75,43.32 v2(136.51,43.32)
DDR_A_D37: length 48.7
  IN1 w0.076: 140.02,71.97 140.02,72.11 138.54,73.59 138.54,73.91 137.85,74.6 v2(137.85,76)
  IN1 w0.114: v2(136.51,44.85) 136.51,44.63 136.66,44.48 136.81,44.48 136.94,44.6 136.94,48.2 137.51,48.78 137.51,49.35 137.42,49.44 137.42,49.65 137.56,49.79 137.56,50.07 138.04,50.55 138.04,52 138.48,52.44 138.48,53.45 138.59,53.56 138.59,54.02 138.96,54.38 138.96,56.18 138.8,56.33 138.76,56.37 138.76,56.6 140.03,57.87 140.03,58.91 140.46,59.34 140.46,68.12 140.02,68.56 140.02,71.97
  BOTTOM w0.076: v2(137.85,76) 137.88,76 138.23,76.35 138.23,81.73 138.26,81.76 138.26,82.46 138.28,82.51 138.28,82.51 138.33,82.62 138.33,82.75 138.26,82.91 138.26,83.11 138.28,83.16 138.32,83.25 138.33,83.27 138.33,83.45 138.32,83.47 138.32,83.85 138.33,83.86 138.33,84.12 138.15,84.31 UC1.AU31
  BOTTOM w0.102: JDIMM1.132 137.85,44.63 137.49,44.99 136.64,44.99 v2(136.51,44.85)
DDR_A_D38: length 48.1
  IN1 w0.076: v2(139.24,74.96) 139.24,74.96 139.49,74.71 139.49,73.99 140.81,72.67 141.6,72.67 142.2,72.08 142.2,71.97
  IN1 w0.114: v2(140.47,44.82) 140.47,44.73 139.96,44.22 139.6,44.22 139.37,44.46 139.37,44.69 139.55,44.87 139.55,45.97 139.7,46.12 139.7,48.85 139.73,48.88 139.73,49.17 140.22,49.65 140.22,51.09 140.66,51.53 140.66,52.55 140.76,52.66 140.76,53.11 141.13,53.48 141.13,55.9 142.2,56.97 142.2,58.01 142.63,58.44 142.63,69.03 142.2,69.46 142.2,71.97
  BOTTOM w0.076: v2(139.24,74.96) 138.39,75.81 138.39,81.66 138.42,81.69 138.42,82.42 138.47,82.53 138.5,82.58 138.5,82.79 138.47,82.84 138.43,82.93 138.42,82.94 138.42,83.07 138.45,83.13 138.47,83.18 138.53,83.23 138.53,83.57 UC1.AV29
  BOTTOM w0.102: JDIMM1.140 140.25,42.76 139.7,43.3 139.7,44.36 140.16,44.82 v2(140.47,44.82)
DDR_A_D39: length 48.4
  IN1 w0.076: 141.83,71.97 141.83,72.1 141.42,72.51 140.73,72.51 139.32,73.92 139.32,74.25 138.84,74.73 138.84,78.01 139.15,78.31 v2(139.25,78.31)
  IN1 w0.114: 141.83,71.97 141.83,69.31 142.27,68.87 142.27,58.59 141.83,58.16 141.83,57.12 140.76,56.05 140.76,53.63 140.4,53.27 140.4,52.81 140.29,52.7 140.29,51.69 139.85,51.25 139.85,49.8 139.37,49.32 139.37,49.04 139.34,49.01 139.34,46.27 139.19,46.12 139.19,45.03 138.82,44.66 138.82,43.61 139.17,43.26 140.29,43.26 v2(140.47,43.44)
  BOTTOM w0.076: UC1.AU29 138.9,84.02 138.9,83.34 139.17,83.07 139.17,82.17 139.05,82.04 139.05,81.49 138.89,81.33 138.89,78.67 v2(139.25,78.31)
  BOTTOM w0.102: JDIMM1.142 140.85,43.25 140.62,43.47 140.5,43.47 v2(140.47,43.44)
DDR_A_D40: length 48.1
  IN1 w0.076: v2(139.25,79.43) 139.5,79.43 139.96,78.97 139.96,75.1 139.99,75.07 139.99,74.2 141.02,73.17 142.11,73.17 142.96,72.32 143.31,72.32 143.6,72.02 143.6,71.97
  IN1 w0.114: v2(142.48,46.35) 142.48,46.21 141.94,45.67 141.74,45.67 141.57,45.84 141.57,46.4 141.72,46.55 141.93,46.55 142.04,46.66 142.04,46.94 141.93,47.06 141.67,47.06 141.57,47.16 141.57,49.08 141.66,49.17 141.66,50.61 142.02,50.97 142.02,51.99 142.12,52.09 142.12,52.12 142.88,52.88 142.88,55.72 143.39,56.23 143.86,56.23 143.99,56.36 143.99,61.89 144.21,62.11 144.21,63.29 143.99,63.5 143.99,66.03 144.28,66.31 144.28,70.63 143.6,71.31 143.6,71.97
  BOTTOM w0.076: UC1.AY27 139.8,82.09 139.55,81.85 139.55,81.2 139.84,80.91 139.84,80 139.27,79.43 v2(139.25,79.43)
  BOTTOM w0.102: JDIMM1.147 142.35,49.14 141.91,48.7 141.91,46.46 142.09,46.28 142.41,46.28 v2(142.48,46.35)
DDR_A_D41: length 49.1
  IN1 w0.076: 143.97,71.97 143.97,72.09 143.54,72.52 143.03,72.52 140.16,75.39 140.16,79.5 139.68,79.99 v2(139.25,79.99)
  IN1 w0.114: 143.97,71.97 143.97,71.46 144.65,70.79 144.65,70.43 144.76,70.31 144.87,70.31 144.99,70.2 144.99,69.97 144.87,69.85 144.76,69.85 144.65,69.74 144.65,65.99 144.42,65.77 144.42,63.6 144.62,63.4 144.62,62 144.36,61.74 144.36,56.02 144.21,55.86 143.55,55.86 143.25,55.56 143.25,55.11 143.34,55.03 143.66,55.03 143.77,54.92 143.77,54.64 143.67,54.54 143.39,54.54 143.25,54.4 143.25,53.69 143.39,53.55 143.59,53.55 143.79,53.35 143.79,52.88 143.53,52.62 143.14,52.62 142.7,52.18 142.7,51.98 142.9,51.78 142.9,51.43 142.55,51.08 142.55,50.37 142.37,50.19 142.19,50.19 142.04,50.04 142.04,49.68 142.17,49.56 142.42,49.56 142.52,49.46 142.52,49.15 142.42,49.05 142.06,49.05 141.94,48.93 141.94,48.52 142.12,48.34 142.12,48.11 141.94,47.93 141.94,47.6 142.04,47.5 142.32,47.5 142.48,47.65 v2(142.48,47.87)
  BOTTOM w0.076: UC1.AW27 139.8,82.77 139.5,82.48 139.5,82.03 139.39,81.92 139.39,81.12 139.65,80.86 139.65,80.39 v2(139.25,79.99)
  BOTTOM w0.102: JDIMM1.149 142.95,48.8 143.9,47.86 143.9,47.53 143.54,47.17 143.18,47.17 v2(142.48,47.87)
DDR_A_D42: length 48.3
  IN1 w0.076: 147.06,71.97 146.71,72.32 145.32,73.71 144.05,73.71 141.99,75.77 141.99,76.43 141.79,76.63 141.79,77.22 141.66,77.35 v2(141.38,77.35)
  IN1 w0.114: v2(145.55,47.85) 145.38,47.68 145.22,47.68 145.11,47.78 145.11,48.89 145.23,49 145.53,49 145.65,49.11 145.65,49.34 145.53,49.46 145.23,49.46 145.11,49.57 145.11,50 145.21,50.1 145.37,50.1 145.74,49.73 145.9,49.73 146.06,49.89 146.06,50.06 145.7,50.42 145.7,50.58 145.86,50.74 146.02,50.74 146.23,50.53 146.39,50.53 146.55,50.69 146.55,50.85 146.34,51.07 146.34,51.34 146.48,51.48 146.7,51.48 146.94,51.23 147.1,51.23 147.27,51.41 147.27,51.62 147.06,51.83 147.06,53.28 146.62,53.72 146.62,54 146.91,54.29 146.91,60.69 147.17,60.95 147.17,63.31 147.37,63.51 147.37,63.92 147.95,64.49 147.95,65.12 147.99,65.17 147.99,67.44 147.81,67.62 147.81,68.13 147.54,68.4 147.54,71.49 147.06,71.97
  BOTTOM w0.076: v2(141.38,77.35) 142.02,77.98 142.02,79.15 141.76,79.4 141.76,80.95 141.65,81.06 141.41,81.06 141.02,81.45 141.02,82.23 UC1.AY25
  BOTTOM w0.102: v2(145.55,47.85) 145.55,48.03 145.34,48.24 144.84,48.24 144.56,48.52 144.56,48.67 144.71,48.82 145.04,48.82 145.35,49.13 JDIMM1.157
DDR_A_D43: length 49.2
  IN1 w0.076: 146.7,71.97 146.7,72.04 146.16,72.57 145.22,73.51 143.99,73.51 141.38,76.12 v2(141.38,76.23)
  IN1 w0.114: v2(145.55,46.32) 145.51,46.28 145.29,46.28 145.14,46.43 145.14,46.5 144.75,46.89 144.75,50.15 145.97,51.37 145.97,51.76 146.08,51.87 146.58,51.87 146.69,51.99 146.69,52.21 146.58,52.33 146.08,52.33 145.97,52.44 145.97,52.67 146.08,52.79 146.58,52.79 146.69,52.9 146.69,53.13 146.58,53.24 146.08,53.24 145.97,53.36 145.97,53.48 146.19,53.7 146.19,54.1 146.54,54.45 146.54,60.84 146.8,61.1 146.8,63.46 147,63.66 147,64.07 147.58,64.65 147.58,65.27 147.62,65.32 147.62,67.29 147.45,67.47 147.45,67.98 147.17,68.25 147.17,71.34 146.7,71.81 146.7,71.97
  BOTTOM w0.076: UC1.AW25 141.36,82.79 141.36,82.58 141.39,82.53 141.39,82.52 141.44,82.42 141.44,82.23 141.18,81.98 141.18,81.52 141.48,81.23 141.72,81.23 141.94,81.01 141.94,79.46 142.18,79.22 142.18,77.51 141.9,77.23 141.9,76.75 v2(141.38,76.23)
  BOTTOM w0.102: JDIMM1.159 145.95,49 146.15,48.8 146.15,46.92 v2(145.55,46.32)
DDR_A_D44: length 49.2
  IN1 w0.076: v2(139.24,80.55) 139.39,80.55 140.36,79.58 140.36,75.57 143.23,72.7 143.9,72.7 144.34,72.25 144.34,71.97
  IN1 w0.114: v2(142.48,44.82) 142.48,44.58 142.61,44.45 142.8,44.45 142.9,44.55 142.9,49.6 142.73,49.77 142.73,50.03 142.92,50.22 142.92,50.93 143.26,51.27 143.26,51.93 143.19,52 143.19,52.15 143.3,52.26 143.69,52.26 144.16,52.73 144.16,53.5 143.74,53.91 143.74,54.09 144.14,54.49 144.14,55.27 144.73,55.87 144.73,61.59 144.99,61.85 144.99,63.55 144.79,63.75 144.79,65.61 145.01,65.84 145.01,69.47 145.36,69.82 145.36,70.34 145.01,70.69 145.01,70.94 144.34,71.61 144.34,71.97
  BOTTOM w0.076: v2(139.24,80.55) 139.27,80.58 139.27,80.87 139.21,80.92 139.21,81.97 139.34,82.1 139.34,82.96 139.9,83.53 UC1.AV27
  BOTTOM w0.102: v2(142.48,44.82) 142.34,44.96 141.91,44.96 141.61,44.66 141.61,44.12 142.05,43.68 JDIMM1.146
DDR_A_D45: length 50.1
  IN1 w0.076: 144.71,71.97 144.71,72.33 144.14,72.9 143.39,72.9 140.57,75.72 140.57,79.35 141.36,80.14 v2(141.38,80.14)
  IN1 w0.114: 144.71,71.97 144.71,71.77 145,71.48 145.38,71.09 145.38,70.84 145.73,70.49 145.73,69.67 145.38,69.32 145.38,65.69 145.15,65.46 145.15,63.91 145.36,63.7 145.36,61.7 145.1,61.44 145.1,55.71 144.5,55.12 144.5,54.33 144.25,54.08 144.25,53.93 144.53,53.65 144.53,52.57 144.28,52.33 144.28,52.07 144.05,51.84 143.79,51.84 143.63,51.68 143.63,51.12 143.29,50.77 143.29,50.07 143.28,50.06 143.28,44.25 143.03,44 143.03,43.74 143.54,43.23 143.54,43.06 143.41,42.93 142.65,42.93 142.48,43.1 v2(142.48,43.3)
  BOTTOM w0.076: UC1.AU27 140.56,84.31 140.75,84.12 140.75,83.24 140.69,83.11 140.69,82.91 140.76,82.75 140.76,82.62 140.69,82.46 140.69,80.75 141.3,80.14 v2(141.38,80.14)
  BOTTOM w0.102: JDIMM1.148 142.65,43.13 v2(142.48,43.3)
DDR_A_D46: length 49.7
  IN1 w0.076: v2(141.38,80.71) 141.49,80.71 141.99,80.21 141.99,76.66 142.22,76.43 142.22,75.85 144.15,73.92 145.42,73.92 146.87,72.47 147.1,72.47 147.6,71.97
  IN1 w0.114: v2(145.55,44.82) 145.55,44.6 145.65,44.5 145.9,44.5 146.02,44.62 146.02,49.33 146.43,49.74 146.43,50.05 147.64,51.26 147.64,51.77 147.43,51.98 147.43,53.43 147.1,53.76 147.1,53.96 147.27,54.14 147.27,60.53 147.53,60.79 147.53,62.62 147.75,62.83 147.75,63.7 148.31,64.27 148.31,64.97 148.36,65.01 148.36,67.6 148.18,67.77 148.18,68.28 147.91,68.56 147.91,71.66 147.6,71.97
  BOTTOM w0.076: UC1.AV25 141.15,83.42 140.9,83.18 140.85,83.07 140.85,82.94 140.86,82.92 140.9,82.84 140.93,82.79 140.93,82.58 140.85,82.42 140.85,81.23 v2(141.38,80.71)
  BOTTOM w0.102: JDIMM1.158 145.65,42.64 145.01,43.27 145.01,45.01 145.19,45.19 145.37,45.19 145.55,45.01 v2(145.55,44.82)
DDR_A_D47: length 50.6
  IN1 w0.076: 148.18,71.97 147.48,72.67 147.04,72.67 145.62,74.09 144.27,74.09 142.45,75.91 142.45,76.71 v2(142.39,76.77)
  IN1 w0.114: v2(145.55,43.32) 145.55,43.03 145.7,42.88 146.18,42.88 146.44,43.13 146.44,43.46 146.08,43.82 146.08,44.1 146.39,44.41 146.39,49.18 146.8,49.59 146.8,49.89 148.01,51.11 148.01,51.92 147.79,52.14 147.79,53.59 147.64,53.74 147.64,60.38 147.9,60.64 147.9,62.46 148.12,62.68 148.12,63.55 148.68,64.11 148.68,64.81 148.73,64.86 148.73,67.75 148.55,67.93 148.55,68.43 148.28,68.71 148.28,71.87 148.18,71.97
  BOTTOM w0.076: v2(142.39,76.77) 142.35,76.81 142.35,79.29 142.1,79.53 142.1,81.08 141.79,81.39 141.54,81.39 141.35,81.59 141.35,81.91 141.46,82.02 141.46,82.02 141.6,82.16 141.6,82.46 141.58,82.51 141.53,82.62 141.53,83.92 UC1.AU25
  BOTTOM w0.102: JDIMM1.160 146.25,43.05 146,43.3 145.57,43.3 v2(145.55,43.32)
DDR_A_D48: length 49.1
  IN1 w0.076: v2(143.39,79.15) 143.67,79.15 143.77,79.05 143.77,75.36 144.43,74.7 145.93,74.7 147.41,73.22 148.91,73.22 149.64,72.49 149.64,71.97
  IN1 w0.114: 149.64,71.97 149.64,69.27 149.91,69 149.91,68.49 150.09,68.31 150.09,65.22 150.2,65.11 150.4,64.91 150.4,64.61 150.06,64.27 150.06,63.57 149.48,62.99 149.48,62.12 149.26,61.9 149.26,60.08 149,59.82 149,54.3 149.15,54.15 149.15,52.7 149.37,52.48 149.37,50.54 148.45,49.62 148.45,49.31 147.83,48.69 147.83,48.46 147.98,48.31 147.98,48.08 147.8,47.9 147.8,47.66 147.93,47.53 147.93,47.28 147.8,47.14 147.8,46.9 147.96,46.74 147.96,46.54 147.8,46.38 147.8,46.08 147.93,45.95 148.29,45.95 v2(148.66,46.32)
  BOTTOM w0.076: v2(143.39,79.15) 142.6,79.94 142.6,81.28 142.48,81.4 142.48,82.34 UC1.AY23
  BOTTOM w0.102: v2(148.66,46.32) 147.97,46.32 147.15,47.14 JDIMM1.163
DDR_A_D49: length 50.2
  IN1 w0.076: 150,71.97 150,72.4 149.03,73.38 147.53,73.38 146,74.91 144.56,74.91 143.95,75.51 143.95,79.32 143.77,79.5 143.11,79.5 142.83,79.22 142.83,78.16 142.96,78.03 v2(143.36,78.03)
  IN1 w0.114: 150,71.97 150,69.42 150.28,69.15 150.28,68.64 150.46,68.46 150.46,65.37 150.91,64.92 150.91,64.59 150.43,64.12 150.43,63.42 149.85,62.83 149.85,61.96 149.63,61.75 149.63,59.92 149.37,59.67 149.37,54.45 149.52,54.3 149.52,52.85 149.74,52.64 149.74,50.39 148.96,49.61 148.96,48.02 148.67,47.73 v2(148.67,47.65)
  BOTTOM w0.076: v2(143.36,78.03) 143.31,78.03 142.68,78.67 142.68,79.42 142.43,79.67 142.43,81.21 142.32,81.33 142.32,82.05 142.21,82.16 142.21,82.43 142.3,82.61 142.5,82.81 UC1.AW23
  BOTTOM w0.102: JDIMM1.165 147.75,48.89 147.4,48.54 147.4,47.55 147.63,47.32 148.39,47.32 148.67,47.6 v2(148.67,47.65)
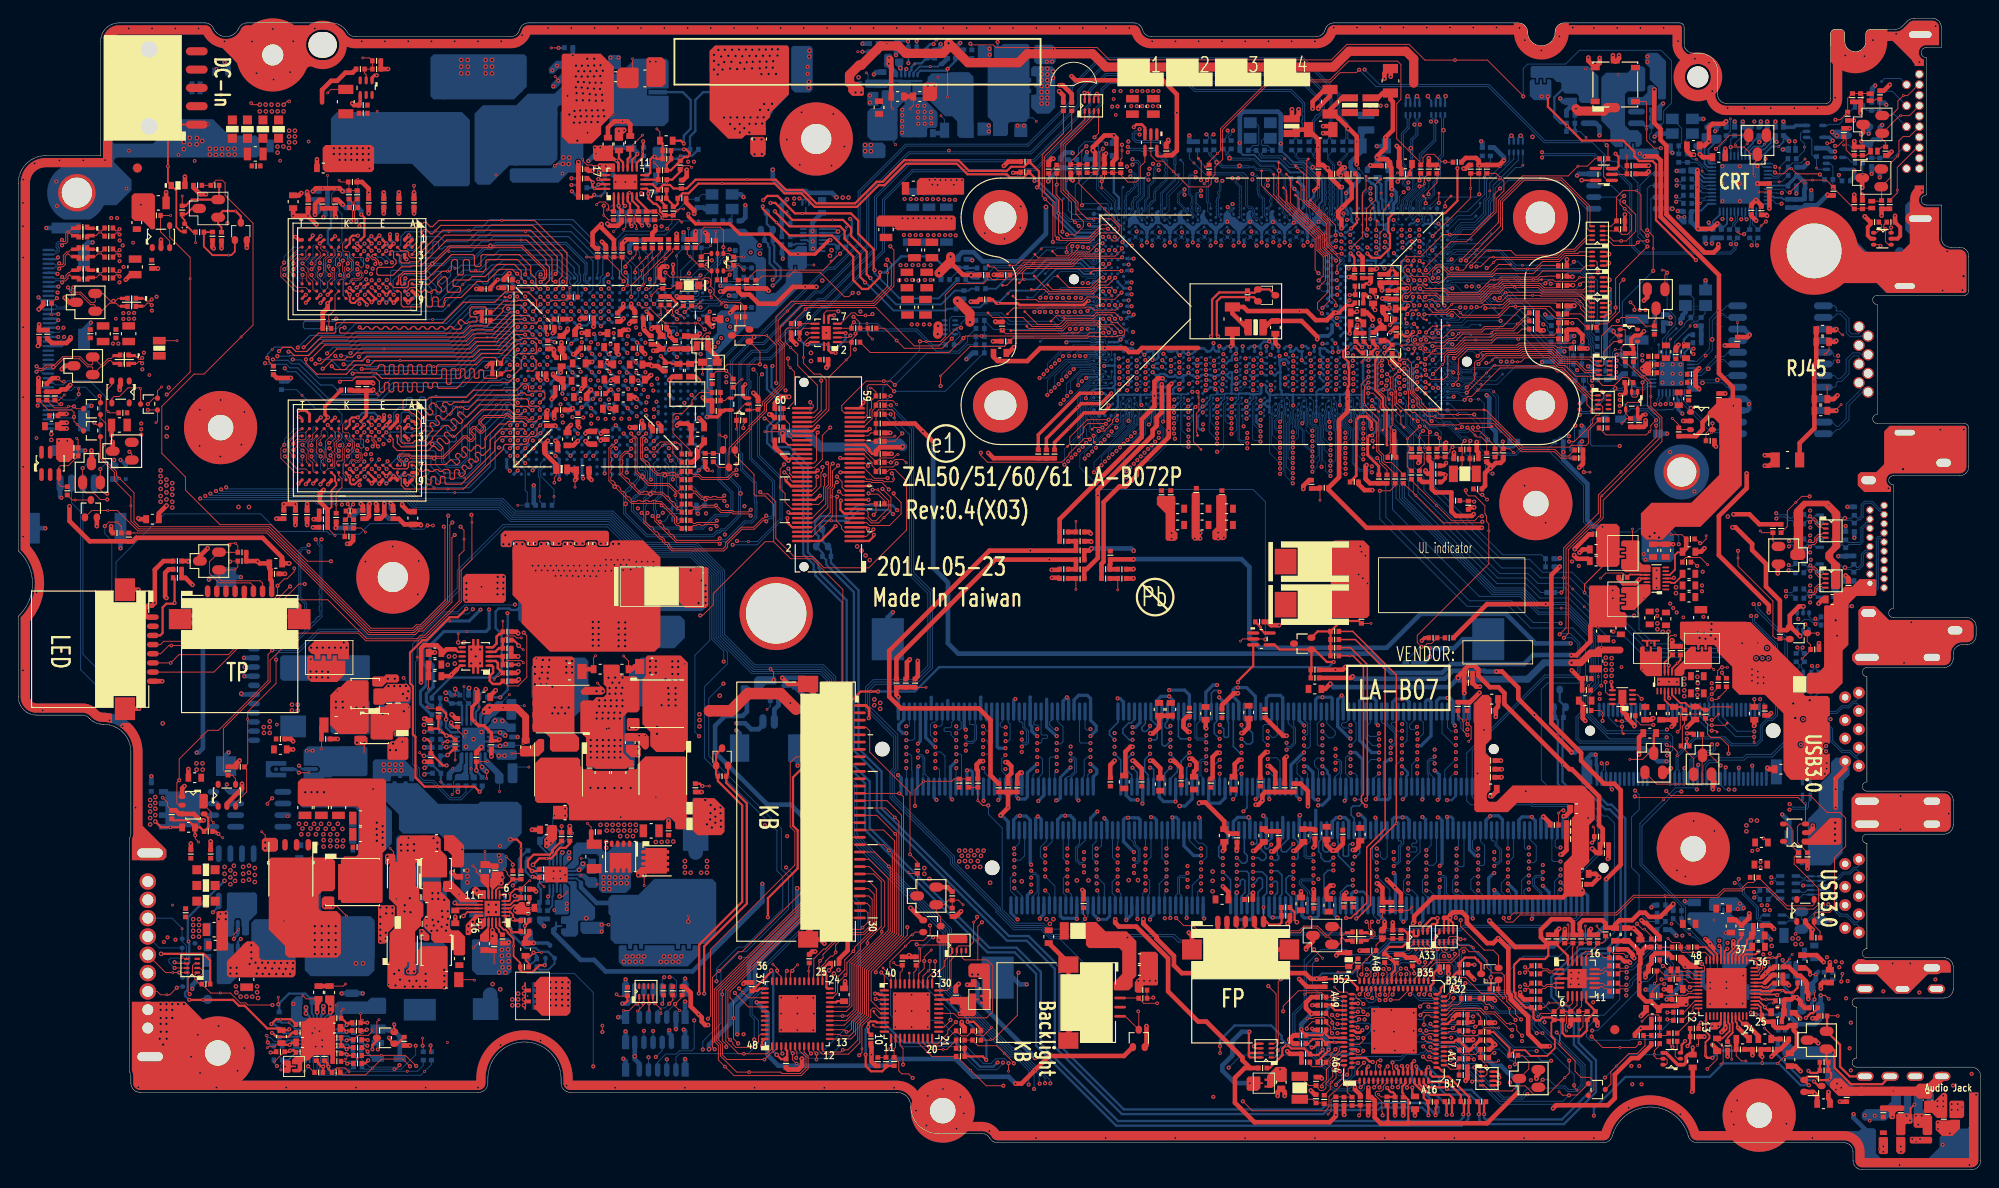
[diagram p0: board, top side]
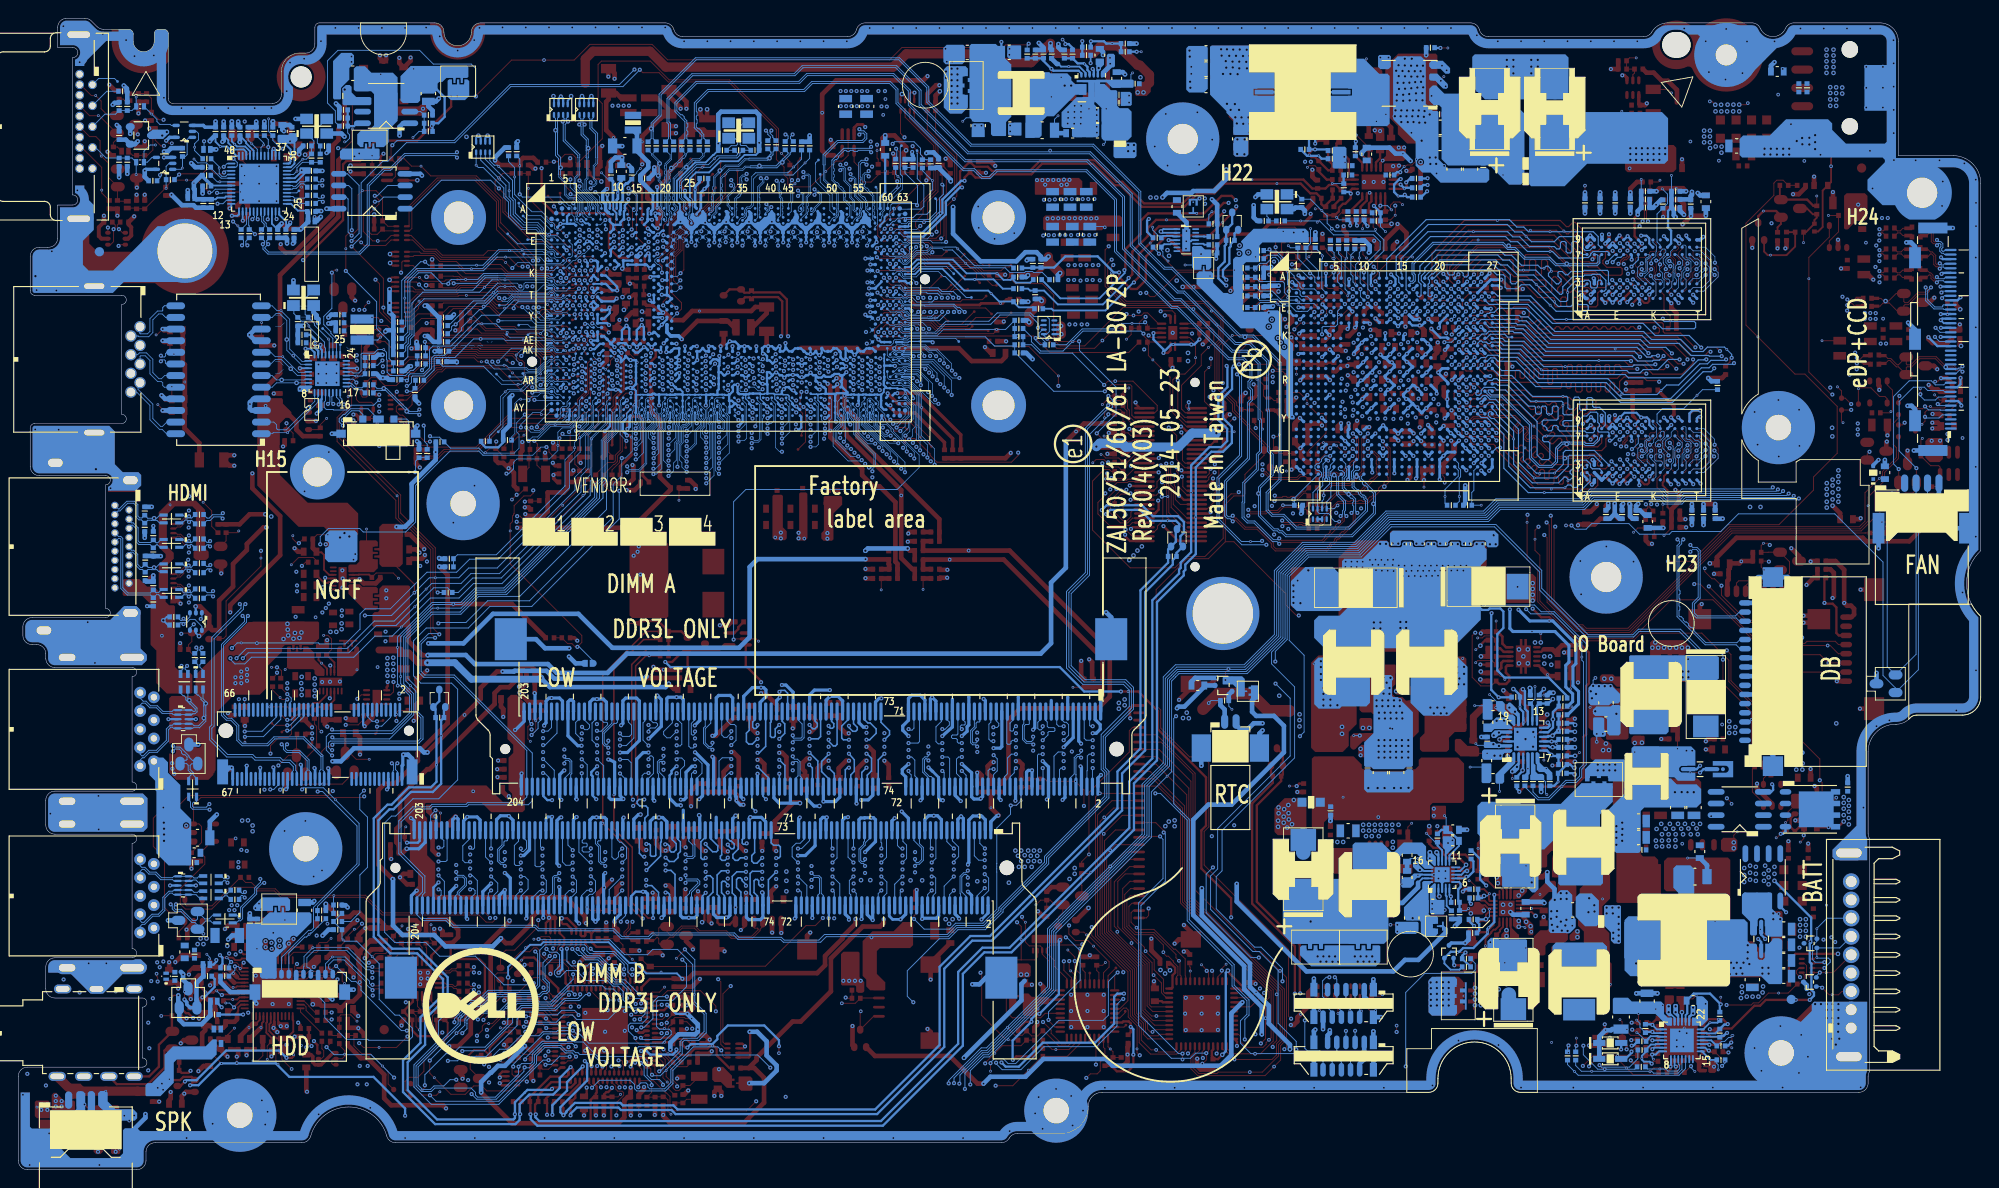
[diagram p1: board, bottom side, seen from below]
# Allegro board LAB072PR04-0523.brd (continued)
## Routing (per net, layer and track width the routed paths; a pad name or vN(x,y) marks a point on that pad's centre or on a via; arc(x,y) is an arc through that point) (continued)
DDR_A_D50: length 49.1
  IN1 w0.076: v2(145.01,76.56) 145.01,76.68 145.14,76.81 145.47,76.81 147.31,74.97 149.78,74.97 152.18,72.57 152.18,71.97
  IN1 w0.114: 152.18,71.97 152.18,70.33 152.46,70.05 152.46,69.54 152.63,69.37 152.63,66.27 153.14,65.77 153.14,63.75 152.61,63.22 152.61,62.52 152.02,61.93 152.02,61.06 151.81,60.85 151.81,59.02 151.55,58.76 151.55,55.36 151.7,55.21 151.7,54.61 151.81,54.5 152.32,54.5 152.43,54.39 152.43,54.16 152.32,54.04 151.81,54.04 151.7,53.93 151.7,53.75 151.98,53.47 152.28,53.47 152.43,53.32 152.43,53.08 152.32,52.96 152.03,52.96 151.91,52.85 151.91,52.29 152.43,51.78 152.43,51.01 151.95,50.53 151.95,50.35 152.03,50.27 152.32,50.27 152.43,50.16 152.43,49.93 152.32,49.81 152.03,49.81 151.91,49.7 151.91,49.47 151.72,49.28 151.72,47.75 151.52,47.55 151.31,47.55 151.19,47.68 v2(151.19,47.93)
  BOTTOM w0.076: v2(145.01,76.56) 144.78,76.56 144.27,77.08 144.27,80.72 144.01,80.97 144.01,81.74 143.96,81.79 143.96,82.25 UC1.AY21
  BOTTOM w0.102: v2(151.19,47.93) 151.13,47.88 150.73,47.88 150.02,48.59 150.02,48.77 150.11,48.86 150.44,48.86 150.75,49.17 JDIMM1.175
DDR_A_D51: length 50
  IN1 w0.076: 152.55,71.97 152.55,72.63 150.04,75.14 147.4,75.14 145.42,77.12 145.42,77.65 145.27,77.8 145.09,77.8 v2(144.99,77.7)
  IN1 w0.114: v2(151.16,46.35) 151.53,45.98 151.79,45.98 152.1,46.28 152.1,49.14 152.41,49.45 152.55,49.45 152.86,49.76 152.86,50.25 152.61,50.5 152.61,50.67 152.86,50.93 152.86,51.87 152.43,52.3 152.43,52.56 152.8,52.93 152.8,54.54 152.47,54.87 152.22,54.87 152.07,55.03 152.07,55.36 151.92,55.51 151.92,58.53 152.19,58.81 152.19,60.71 152.39,60.91 152.39,61.78 152.98,62.36 152.98,63.06 153.5,63.59 153.5,65.94 153.48,65.94 153,66.42 153,69.52 152.82,69.7 152.82,70.2 152.55,70.48 152.55,71.97
  BOTTOM w0.076: v2(144.99,77.7) 144.43,78.25 144.43,80.78 144.17,81.04 144.17,81.82 144.14,81.85 144.14,82.48 144.06,82.56 143.85,82.77 UC1.AW21
  BOTTOM w0.102: v2(151.16,46.35) 151.72,46.9 151.72,48.79 151.35,49.16 JDIMM1.177
DDR_A_D52: length 50.9
  IN1 w0.076: 149.27,71.97 149.27,72.33 148.54,73.05 147.34,73.05 145.9,74.5 144.33,74.5 143.36,75.47 v2(143.36,75.77)
  IN1 w0.114: v2(148.66,44.8) 148.4,44.53 147.65,44.53 147.43,44.76 147.43,44.96 147.73,45.27 147.73,45.52 147.43,45.82 147.43,48.8 148.08,49.46 148.08,49.77 149,50.69 149,52.33 148.78,52.55 148.78,54 148.63,54.15 148.63,59.97 148.89,60.23 148.89,62.05 149.11,62.27 149.11,63.14 149.69,63.72 149.69,64.42 149.89,64.62 149.89,64.89 149.72,65.06 149.72,68.16 149.54,68.34 149.54,68.84 149.27,69.12 149.27,71.97
  BOTTOM w0.076: UC1.AV23 142.11,83.27 142.11,82.61 142.04,82.47 142.04,82.09 142.15,81.98 142.15,81.26 142.27,81.15 142.27,79.6 142.51,79.36 142.51,77.48 142.81,77.19 142.81,76.33 v2(143.36,75.77)
  BOTTOM w0.102: v2(148.66,44.8) 147.79,44.8 147.45,44.45 JDIMM1.164
DDR_A_D53: length 51.6
  IN1 w0.076: v2(143.34,76.89) 142.93,76.48 142.93,75.66 144.3,74.3 145.8,74.3 147.23,72.87 148.02,72.87 148.9,71.99 148.9,71.97
  IN1 w0.114: 148.9,71.97 148.9,68.97 149.17,68.69 149.17,68.18 149.35,68.01 149.35,64.6 149.31,64.56 149.31,63.86 148.74,63.29 148.74,62.42 148.52,62.21 148.52,60.38 148.27,60.12 148.27,54 148.42,53.85 148.42,52.39 148.63,52.18 148.63,50.85 147.71,49.93 147.71,49.61 147.03,48.93 147.03,44.34 147.21,44.16 147.6,44.16 147.71,44.05 147.71,43.84 147.6,43.73 147.47,43.73 147.32,43.59 147.32,43.33 147.45,43.21 148.6,43.21 v2(148.66,43.27)
  BOTTOM w0.076: UC1.AU23 143.26,84.31 143.47,84.1 143.47,83.86 143.45,83.85 143.45,83.47 143.47,83.45 143.47,83.27 143.46,83.25 143.39,83.11 143.39,82.91 143.47,82.75 143.47,82.62 143.42,82.51 143.39,82.46 143.39,82.17 143.63,81.93 143.63,81.66 143.68,81.6 143.68,80.84 143.93,80.59 143.93,77.48 v2(143.34,76.89)
  BOTTOM w0.102: v2(148.66,43.27) 148.05,42.65 JDIMM1.166
DDR_A_D54: length 50
  IN1 w0.076: 151.81,71.97 151.81,72.41 149.41,74.81 147.22,74.81 146.05,75.97 v2(145.01,75.97)
  IN1 w0.114: v2(151.16,44.82) 151.1,44.76 150.91,44.76 150.74,44.92 150.74,47.25 150.77,47.27 150.77,48.86 151.55,49.64 151.55,50.65 151.97,51.07 151.97,51.72 151.55,52.14 151.55,53.38 151.33,53.6 151.33,55.05 151.18,55.2 151.18,58.92 151.44,59.18 151.44,61 151.66,61.22 151.66,62.08 152.24,62.67 152.24,63.37 152.77,63.9 152.77,65.61 152.26,66.12 152.26,69.21 152.09,69.39 152.09,69.9 151.81,70.17 151.81,71.97
  BOTTOM w0.076: v2(145.01,75.97) 144.68,75.97 144.1,76.56 144.1,80.66 143.84,80.91 143.84,81.67 143.79,81.72 143.79,82 143.56,82.24 143.56,82.42 143.61,82.53 143.63,82.58 143.63,82.79 143.61,82.84 143.56,82.93 143.56,82.94 143.56,83.07 143.58,83.13 143.61,83.18 143.74,83.31 UC1.AV21
  BOTTOM w0.102: v2(151.16,44.82) 150.45,44.11 JDIMM1.174
DDR_A_D55: length 51.2
  IN1 w0.076: v2(144.99,78.26) 144.96,78.26 144.61,77.9 144.61,75.87 144.99,75.49 146.28,75.49 147.15,74.63 149.2,74.63 151.44,72.39 151.44,71.97
  IN1 w0.114: 151.44,71.97 151.44,70.02 151.72,69.75 151.72,69.24 151.9,69.06 151.9,65.96 152.4,65.46 152.4,64.05 151.87,63.52 151.87,62.82 151.29,62.24 151.29,61.37 151.07,61.15 151.07,59.33 150.81,59.07 150.81,55.05 150.96,54.9 150.96,53.45 151.18,53.23 151.18,51.99 151.6,51.57 151.6,51.23 151.18,50.8 151.18,49.79 150.4,49.01 150.4,47.43 150.37,47.4 150.37,44.53 149.86,44.02 149.86,43.64 150.21,43.3 v2(151.16,43.3)
  BOTTOM w0.076: UC1.AU21 143.74,84.08 144.02,83.8 144.02,83.52 144.02,83.52 144.02,83.25 144.14,83.13 144.14,82.71 144.31,82.55 144.31,81.92 144.34,81.88 144.34,81.11 144.6,80.85 144.6,78.67 144.99,78.29 v2(144.99,78.26)
  BOTTOM w0.102: JDIMM1.176 151.05,43.18 v2(151.16,43.3)
DDR_A_D56: length 50.5
  IN1 w0.076: 153.17,72.65 153.17,72.87 150.75,75.3 147.51,75.3 145.62,77.19 145.62,79.33 145.42,79.53 145.14,79.53 v2(144.99,79.38)
  IN1 w0.114: 153.17,72.65 153.17,72.6 153.29,72.48 153.43,72.48 153.55,72.37 153.55,72.14 153.43,72.03 153.29,72.03 153.17,71.91 153.17,71.68 153.29,71.57 153.43,71.57 153.55,71.45 153.55,71.22 153.43,71.11 153.29,71.11 153.17,71 153.17,70.74 153.29,70.62 153.57,70.62 153.65,70.54 153.65,70.36 153.45,70.16 153.45,69.95 153.65,69.75 153.65,68.69 154.13,68.21 154.13,68.05 154.01,67.94 153.74,67.94 153.62,67.82 153.62,67.59 153.74,67.48 154.01,67.48 154.13,67.37 154.13,67.14 154.01,67.02 153.74,67.02 153.62,66.91 153.62,66.68 153.74,66.57 154.01,66.57 154.13,66.45 154.13,63.33 153.6,62.81 153.6,62.11 153.01,61.52 153.01,61.3 153.17,61.14 153.17,60.81 152.86,60.5 152.86,60.25 153.04,60.07 153.04,59.79 152.81,59.57 152.81,59.34 153.04,59.11 153.04,58.78 152.54,58.28 152.54,56.78 152.79,56.53 152.79,56.36 152.54,56.11 152.54,55.77 152.68,55.62 152.68,55.53 152.88,55.34 153.28,55.34 153.5,55.11 153.5,54.82 153.42,54.73 153.42,54.43 153.5,54.35 153.5,54.1 153.42,54.02 153.42,53.72 153.5,53.64 153.5,53.45 153.42,53.37 153.42,53.1 153.5,53.01 153.5,52.77 153.32,52.58 153.32,52.29 153.48,52.12 153.5,52.1 153.5,49.52 153.04,49.06 153.04,48.87 153.17,48.74 153.37,48.74 153.5,48.61 153.5,48.14 153.37,48.01 153.09,48.01 152.81,48.29 v2(152.81,48.36)
  BOTTOM w0.076: v2(144.99,79.38) 145.01,79.38 145.55,79.92 145.55,80.68 144.84,81.4 144.84,82.26 UC1.AY19
  BOTTOM w0.102: v2(152.81,48.36) 152.81,48.35 152.52,48.06 152.2,48.06 152,48.26 152,48.58 152.55,49.13 JDIMM1.181
DDR_A_D57: length 51.6
  IN1 w0.076: v2(144.99,79.94) 145.34,79.94 146.23,79.05 146.23,76.82 147.58,75.47 150.88,75.47 153.97,72.38 153.97,71.97
  IN1 w0.114: v2(152.86,46.99) 153.45,46.41 153.57,46.41 153.87,46.71 153.87,47.02 153.75,47.14 153.41,47.14 153.29,47.26 153.29,47.53 153.41,47.64 153.71,47.64 153.87,47.8 153.87,55.29 153.43,55.73 153.14,55.73 153.01,55.86 153.01,56.07 153.15,56.21 153.15,56.68 152.91,56.93 152.91,58.12 153.41,58.63 153.41,59.03 153.65,59.27 153.65,59.46 153.41,59.7 153.41,60.38 153.66,60.63 153.66,60.79 153.54,60.91 153.54,61.52 153.97,61.94 153.97,62.65 154.49,63.18 154.49,68.7 154.38,68.82 154.14,68.82 154.03,68.93 154.03,69.16 154.14,69.28 154.38,69.28 154.49,69.39 154.49,69.62 154.38,69.73 154.14,69.73 154.03,69.85 154.03,70.08 154.14,70.19 154.38,70.19 154.49,70.3 154.49,70.5 153.97,71.03 153.97,71.97
  BOTTOM w0.076: UC1.AW19 144.93,82.77 144.64,82.48 144.64,82.1 144.67,82.07 144.67,81.33 145.34,80.66 145.34,80.29 v2(144.99,79.94)
  BOTTOM w0.102: JDIMM1.183 153.15,49.21 153.5,48.86 153.5,47.63 v2(152.86,46.99)
DDR_A_D58: length 50.3
  IN1 w0.076: 156.51,72.08 156.51,72.27 151.62,77.17 148.32,77.17 147.53,77.96 147.53,78.63 147.47,78.69 147.47,78.75 v2(146.94,79.28)
  IN1 w0.114: v2(157.07,46.37) 157.07,46.19 156.77,45.9 156.6,45.9 156.49,46 156.49,47.17 156.67,47.35 156.67,47.65 156.49,47.83 156.49,48.64 156.95,49.1 156.95,49.32 156.43,49.84 156.43,50.6 156.94,51.11 156.94,51.82 156.42,52.34 156.42,52.53 156.53,52.65 156.81,52.65 156.93,52.76 156.93,53.11 156.81,53.22 156.53,53.22 156.42,53.33 156.42,53.52 156.62,53.72 156.62,54.03 156.42,54.23 156.42,54.46 156.51,54.55 156.51,61.6 157.04,62.13 157.04,71.56 156.51,72.08
  BOTTOM w0.076: v2(146.94,79.28) 146.41,79.81 146.41,81 146.24,81.17 146.24,82.32 UC1.AY17
  BOTTOM w0.102: JDIMM1.191 155.55,47.68 156.85,46.37 v2(157.07,46.37)
DDR_A_D59: length 51
  IN1 w0.076: v2(146.94,80.39) 147.04,80.39 147.32,80.11 147.32,79.4 147.98,78.74 148.49,78.74 149.52,77.71 151.43,77.71 156.77,72.37 156.8,72.37
  IN1 w0.114: v2(157.07,47.9) 157.41,48.24 157.41,49.38 156.96,49.82 156.8,49.99 156.8,50.45 157.31,50.95 157.31,51.93 157.42,52.05 157.47,52.05 157.59,52.16 157.59,52.39 157.47,52.51 157.42,52.51 157.31,52.62 157.31,53.01 157.81,53.52 157.81,53.81 157.49,54.14 157.07,54.14 156.88,54.33 156.88,54.59 156.99,54.7 157.29,54.7 157.41,54.82 157.41,55.16 157.29,55.27 156.99,55.27 156.88,55.39 156.88,55.73 156.99,55.85 157.29,55.85 157.41,55.96 157.41,56.3 157.29,56.42 156.99,56.42 156.88,56.53 156.88,56.87 156.99,56.99 157.29,56.99 157.41,57.1 157.41,57.45 157.29,57.56 156.99,57.56 156.88,57.67 156.88,58.02 156.99,58.13 157.29,58.13 157.41,58.25 157.41,58.59 157.29,58.7 156.99,58.7 156.88,58.82 156.88,59.16 156.99,59.27 157.29,59.27 157.41,59.39 157.41,59.73 157.29,59.85 156.99,59.85 156.88,59.96 156.88,60.3 156.99,60.42 157.29,60.42 157.41,60.53 157.41,60.88 157.29,60.99 156.99,60.99 156.88,61.1 156.88,61.45 156.99,61.56 157.29,61.56 157.41,61.68 157.41,71.76 156.8,72.37
  BOTTOM w0.076: UC1.AW17 146.5,82.79 146.5,82.58 146.57,82.42 146.57,82.24 146.42,82.08 146.42,81.23 146.58,81.07 146.58,80.76 v2(146.94,80.39)
  BOTTOM w0.102: JDIMM1.193 156.15,48.28 156.53,47.9 v2(157.07,47.9)
DDR_A_D60: length 52.1
  IN1 w0.076: 154.33,71.97 154.33,72.47 151.17,75.63 147.67,75.63 146.49,76.81 146.49,79.05 145.07,80.46 145.01,80.46 v2(144.98,80.49)
  IN1 w0.114: v2(152.84,44.82) 153.19,44.48 153.42,44.48 153.75,44.81 153.75,45.58 153.96,45.79 153.96,46.21 154.24,46.49 154.24,55.44 153.78,55.91 153.78,58.87 154.33,59.43 154.33,59.67 154.22,59.78 153.92,59.78 153.8,59.9 153.8,60.24 153.92,60.36 154.22,60.36 154.33,60.47 154.33,60.81 154.22,60.93 154.04,60.93 153.93,61.04 153.93,61.38 154.04,61.5 154.22,61.5 154.33,61.61 154.33,62.5 154.86,63.03 154.86,70.65 154.33,71.18 154.33,71.97
  BOTTOM w0.076: UC1.AV19 145.04,83.53 144.64,83.13 144.64,82.72 144.47,82.56 144.47,82 144.5,81.97 144.5,81.26 144.98,80.78 v2(144.98,80.49)
  BOTTOM w0.102: JDIMM1.180 152.25,44.23 v2(152.84,44.82)
DDR_A_D61: length 53.1
  IN1 w0.076: v2(146.94,77.57) 146.87,77.5 146.87,76.67 147.74,75.8 151.31,75.8 154.7,72.41 154.7,71.97
  IN1 w0.114: 154.7,71.97 154.7,71.33 155.23,70.81 155.23,62.88 154.7,62.35 154.7,58.96 154.59,58.85 154.27,58.85 154.16,58.73 154.16,58.51 154.27,58.39 154.59,58.39 154.7,58.28 154.7,58.05 154.59,57.93 154.27,57.93 154.16,57.82 154.16,57.59 154.27,57.48 154.59,57.48 154.7,57.36 154.7,56.86 154.46,56.62 154.46,56.39 154.7,56.15 154.7,55.3 154.61,55.21 154.61,46.34 154.33,46.06 154.33,45.64 154.12,45.43 154.12,44.54 153.8,44.22 153.8,44.05 154.12,43.73 154.12,43.47 153.94,43.3 v2(152.84,43.3)
  BOTTOM w0.076: UC1.AU19 145.69,84.31 145.9,84.1 145.9,83.27 145.89,83.25 145.82,83.11 145.82,82.91 145.9,82.75 145.9,82.62 145.82,82.46 145.82,82.12 145.91,82.04 145.91,81.04 146.08,80.86 146.08,78.32 146.83,77.57 v2(146.94,77.57)
  BOTTOM w0.102: JDIMM1.182 152.85,43.29 v2(152.84,43.3)
DDR_A_D62: length 51.8
  IN1 w0.076: v2(146.94,78.72) 147.15,78.72 147.32,78.54 147.32,77.93 148.26,76.99 151.41,76.99 156.14,72.26 156.14,71.97
  IN1 w0.114: 156.14,71.97 156.14,71.93 156.67,71.4 156.67,62.28 156.14,61.75 156.14,54.7 156.05,54.61 156.05,52.19 156.57,51.67 156.57,51.26 156.06,50.75 156.06,44.62 155.95,44.51 155.95,44.28 156.14,44.1 156.49,44.1 157.07,44.67 v2(157.07,44.85)
  BOTTOM w0.076: UC1.AV17 146.28,83.42 146.04,83.18 145.99,83.07 145.99,82.94 146,82.92 146.04,82.84 146.06,82.79 146.06,82.58 145.99,82.42 145.99,82.19 146.07,82.1 146.07,81.1 146.24,80.93 146.24,79.47 146.94,78.77 v2(146.94,78.72)
  BOTTOM w0.102: v2(157.07,44.85) 155.85,43.63 JDIMM1.192
DDR_A_D63: length 52.3
  IN1 w0.076: v2(146.95,80.96) 147.04,80.96 147.53,80.47 147.53,79.45 148.06,78.92 148.55,78.92 149.59,77.88 151.59,77.88 156.67,72.8 156.98,72.8 157.1,72.67
  IN1 w0.114: 157.1,72.67 157.78,72 157.78,61.52 157.64,61.38 157.64,61.2 157.78,61.06 157.78,60.38 157.61,60.21 157.61,60.05 157.78,59.88 157.78,59.24 157.63,59.09 157.63,58.89 157.78,58.74 157.78,58.09 157.62,57.93 157.62,57.76 157.78,57.6 157.78,56.95 157.64,56.81 157.64,56.6 157.78,56.46 157.78,55.81 157.64,55.67 157.64,55.45 157.78,55.31 157.78,54.37 158.18,53.96 158.18,53.37 157.87,53.05 157.87,52.76 158.4,52.22 158.4,51.88 157.78,51.25 157.78,50.9 157.26,50.38 157.26,50.05 157.78,49.53 157.78,47.67 157.61,47.5 157.61,46.95 157.78,46.79 157.78,46.24 157.59,46.05 157.59,45.56 157.78,45.37 157.78,44.81 157.56,44.59 157.56,44.2 157.78,43.98 157.78,43.68 157.42,43.32 v2(157.07,43.32)
  BOTTOM w0.076: UC1.AU17 146.57,84.02 146.57,83.27 146.66,83.17 146.66,82.62 146.71,82.51 146.74,82.46 146.74,82.17 146.58,82.02 146.58,81.32 v2(146.95,80.96)
  BOTTOM w0.102: JDIMM1.194 156.45,42.87 156.45,42.87 156.9,43.32 v2(157.07,43.32)
DDR_A_DQS0: length 60.3
  IN1 w0.076: v2(115.99,88.87) 115.79,88.67 115.79,88.25 115.42,87.89 114.89,87.89 111.97,84.97 111.97,79.63 109,76.66
  IN1 w0.114: 109,76.66 106.47,74.13 106.47,71.85 103.31,68.68 103.31,68.41 102.44,67.54 102.44,53.52 99.92,51 99.92,50.3 98.64,49.02 98.64,47.48 97.79,46.63 97.79,45.68 97.92,45.54 98.13,45.54 98.29,45.7 v2(98.29,45.77)
  BOTTOM w0.076: UC1.AJ62 118.69,89.03 118.75,89.1 118.76,89.17 118.76,89.19 118.7,89.26 118.66,89.27 118.66,89.28 118.6,89.3 118.55,89.32 118.42,89.32 118.26,89.25 118.06,89.25 118.01,89.27 117.92,89.32 117.9,89.32 117.77,89.32 117.72,89.3 117.61,89.25 115.83,89.25 115.71,89.13 115.71,89.08 115.92,88.87 v2(115.99,88.87)
  BOTTOM w0.102: v2(98.29,45.77) 98.29,45.56 98.51,45.34 98.71,45.34 99.04,45.01 99.04,43.22 99.45,42.81 JDIMM1.12
DDR_A_DQS1: length 54.7
  IN1 w0.076: 112.45,74.76 112.45,74.83 112.42,74.86 112.42,75.84 115.7,79.12 115.7,85.17 115.4,85.47 115.4,85.88 115.52,86.01 115.65,86.01 115.79,85.86 v2(115.79,85.68)
  IN1 w0.114: 112.45,74.76 112.45,74.07 110.74,72.36 110.74,69.46 109.15,67.86 109.15,65.55 108.73,65.13 108.73,61.64 106.79,59.7 106.79,51.83 104.24,49.27 104.24,46.86 103.99,46.61 103.68,46.61 v2(103.51,46.44)
  BOTTOM w0.076: UC1.AN61 118.56,86.99 118.08,86.99 117.99,87.03 117.94,87.06 117.73,87.06 117.65,87.02 117.59,86.99 117.59,86.99 116.22,86.99 115.69,86.45 115.69,86.04 115.79,85.94 v2(115.79,85.68)
  BOTTOM w0.102: v2(103.51,46.44) 103.64,46.57 104.28,46.57 104.69,46.98 104.69,48.54 104.55,48.69 JDIMM1.29
DDR_A_DQS2: length 49.8
  IN1 w0.076: v2(119.1,80.17) 119.45,80.17 119.84,79.78 119.84,79.41 116.59,76.16 116.59,74.84 116.56,74.82 116.56,74.76
  IN1 w0.114: v2(109.64,46.22) 109.42,46.43 109.15,46.43 108.92,46.66 108.92,48 109.28,48.36 109.94,48.36 110.06,48.49 110.06,49.12 111.13,50.19 111.13,50.51 111.6,50.98 111.6,51.46 111.48,51.59 111.48,56.84 113.08,58.44 113.23,58.44 113.5,58.71 113.5,59.07 114.52,60.08 114.52,67.05 114.82,67.35 114.82,70.44 116.2,71.82 116.32,71.82 116.56,72.06 116.56,74.76
  BOTTOM w0.076: v2(119.1,80.17) 119.4,80.17 119.49,80.09 119.74,80.09 120.91,81.26 120.91,81.92 121.16,82.17 121.16,82.46 121.13,82.51 121.09,82.62 121.09,82.75 121.09,82.77 121.14,82.85 121.16,82.9 121.16,83.11 121.09,83.27 121.09,83.4 121.13,83.5 121.22,83.58 121.31,83.58 121.38,83.51 UC1.AW57
  BOTTOM w0.102: JDIMM1.47 109.95,48.37 110.35,47.96 110.35,46.62 110.14,46.41 109.83,46.41 v2(109.64,46.22)
DDR_A_DQS3: length 48.3
  IN1 w0.076: v2(121.47,76.68) 121.42,76.63 121.15,76.63 121.03,76.75 120.73,76.75 120.53,76.55 120.53,75.41 120.86,75.08 120.86,74.76
  IN1 w0.114: v2(114.96,45.45) 114.96,45.21 115.06,45.11 115.35,45.11 115.9,45.66 115.9,49.24 116.34,49.68 116.34,50.4 116.65,50.7 116.65,52.91 116.87,53.13 116.87,56.04 117.78,56.94 117.78,57.3 119.42,58.94 119.42,68.54 120.1,69.23 120.1,69.56 120.86,70.31 120.86,74.76
  BOTTOM w0.076: UC1.AW53 123.63,83.33 123.59,83.29 123.59,82.9 123.57,82.85 123.52,82.75 123.52,82.62 123.54,82.56 123.59,82.46 123.59,82.14 123.34,81.89 123.34,81.77 123.14,81.57 123.14,80.33 120.92,78.11 120.92,76.93 121.21,76.63 121.42,76.63 v2(121.47,76.68)
  BOTTOM w0.102: v2(114.96,45.45) 114.96,45.2 115.08,45.09 115.35,45.09 115.59,44.85 115.59,43.41 115.05,42.87 JDIMM1.64
DDR_A_DQS4: length 47.5
  IN1 w0.076: 141.01,71.97 141.01,71.99 140.83,72.18 140.58,72.18 139.81,72.94 138.98,73.77 138.98,74.08 138.47,74.59 138.47,80.32 138.23,80.57 v2(137.85,80.57)
  IN1 w0.114: v2(138.56,45.86) 138.34,46.09 138.18,46.09 137.95,46.31 137.95,47.82 138.52,48.39 138.52,49.35 138.55,49.38 138.55,49.66 139.03,50.14 139.03,51.59 139.47,52.02 139.47,53.04 139.58,53.15 139.58,53.61 139.95,53.97 139.95,56.39 141.02,57.46 141.02,58.5 141.45,58.93 141.45,68.53 141.01,68.97 141.01,71.97
  BOTTOM w0.076: v2(137.85,80.57) 137.66,80.76 137.43,80.76 137.24,80.95 137.24,81.82 137.66,82.24 137.66,82.42 137.61,82.52 137.61,82.53 137.58,82.58 137.58,82.79 137.66,82.94 137.66,83.07 137.61,83.17 137.58,83.23 137.58,83.44 137.65,83.58 137.65,83.59 137.72,83.66 137.81,83.75 137.96,83.75 138.04,83.83 UC1.AV30
  BOTTOM w0.102: JDIMM1.137 139.35,48.43 139.54,48.24 139.54,46.55 139.03,46.04 138.74,46.04 v2(138.56,45.86)
DDR_A_DQS5: length 49.3
  IN1 w0.076: 145.76,71.97 145.76,71.99 144.65,73.11 143.5,73.11 140.79,75.83 140.79,78.53 141.03,78.78 141.22,78.78 141.38,78.95 v2(141.38,79.02)
  IN1 w0.114: v2(143.91,45.2) 143.91,44.94 144,44.86 144.15,44.86 144.36,45.07 144.36,46.12 143.93,46.55 143.93,50.49 145.15,51.71 145.15,54.21 145.72,54.79 145.72,61.18 145.98,61.44 145.98,63.96 145.78,64.16 145.78,65.2 146,65.43 146,69.06 146.35,69.41 146.35,71 145.83,71.52 145.83,71.9 145.76,71.97
  BOTTOM w0.076: UC1.AW26 140.44,83.37 140.35,83.37 140.25,83.27 140.25,82.91 140.22,82.83 140.19,82.77 140.18,82.75 140.18,82.62 140.2,82.56 140.25,82.46 140.25,82.05 139.96,81.77 139.88,81.69 139.88,81.34 140.47,80.75 140.47,79.34 141.04,78.78 141.22,78.78 141.38,78.95 v2(141.38,79.02)
  BOTTOM w0.102: JDIMM1.154 144.45,43.22 144.58,43.35 144.58,44.55 144.35,44.78 144.1,44.78 143.84,45.04 143.84,45.14 v2(143.91,45.2)
DDR_A_DQS6: length 50.2
  IN1 w0.076: 150.63,71.97 150.63,72.13 149.14,73.62 147.57,73.62 146.09,75.1 144.9,75.1 144.27,75.73 144.27,79.89 143.74,80.42 v2(143.34,80.42)
  IN1 w0.114: 150.63,71.97 150.63,69.68 150.9,69.41 150.9,68.9 151.08,68.72 151.08,65.63 151.58,65.12 151.58,64.39 151.05,63.86 151.05,63.16 150.47,62.58 150.47,61.71 150.25,61.49 150.25,59.67 149.99,59.41 149.99,54.71 150.14,54.56 150.14,53.11 150.36,52.89 150.36,50.13 149.58,49.35 149.58,47.73 149.25,47.4 149.25,46.59 149.46,46.38 149.65,46.38 v2(149.94,46.09)
  BOTTOM w0.076: v2(143.34,80.42) 143.15,80.61 142.98,80.61 142.78,80.81 142.78,81.36 142.69,81.45 142.69,82.11 142.79,82.21 142.79,82.42 142.72,82.59 142.72,82.79 142.77,82.9 142.78,82.91 142.79,82.95 142.79,83.6 UC1.AV22
  BOTTOM w0.102: v2(149.94,46.09) 150.12,46.27 150.31,46.27 150.58,46.54 150.58,47.74 149.55,48.77 JDIMM1.171
DDR_A_DQS7: length 51.6
  IN1 w0.076: v2(147.88,76.82) 147.88,76.64 147.99,76.53 151.24,76.53 155.52,72.24 155.52,71.97
  IN1 w0.114: 155.52,71.97 155.52,71.67 156.05,71.14 156.05,62.54 155.52,62.01 155.52,54.96 155.43,54.87 155.43,44.86 155.13,44.56 154.94,44.56 v2(154.74,44.37)
  BOTTOM w0.076: UC1.AW18 145.57,83.37 145.45,83.37 145.39,83.3 145.39,82.91 145.34,82.81 145.31,82.72 145.31,82.63 145.34,82.56 145.39,82.46 145.39,82.16 145.17,81.94 145.17,81.54 145.9,80.8 145.9,77.17 146.61,76.46 147.66,76.46 147.88,76.68 v2(147.88,76.82)
  BOTTOM w0.102: v2(154.74,44.37) 154.74,44.55 154.58,44.71 154.29,44.71 154.12,44.54 154.12,43.34 154.65,42.82 JDIMM1.188
DDR_A_DQS#0: length 60.4
  IN1 w0.076: 109,76.94 109.04,76.94 111.8,79.7 111.8,85.03 114.82,88.05 115.35,88.05 115.63,88.32 115.63,88.65 v2(115.4,88.87)
  IN1 w0.114: v2(98.29,45) 98.29,45.18 98.12,45.35 97.84,45.35 97.59,45.6 97.59,46.71 98.44,47.56 98.44,49.11 99.72,50.38 99.72,51.08 102.24,53.6 102.24,67.62 103.11,68.49 103.11,68.76 106.28,71.93 106.28,74.22 109,76.94
  BOTTOM w0.076: UC1.AJ61 119.14,89.13 118.86,89.41 118.75,89.41 118.73,89.43 118.72,89.43 118.59,89.49 118.38,89.49 118.33,89.46 118.23,89.42 118.1,89.42 117.94,89.49 117.73,89.49 117.59,89.42 117.57,89.41 115.76,89.41 115.53,89.18 115.53,88.99 v2(115.4,88.87)
  BOTTOM w0.102: JDIMM1.10 98.85,43.14 98.85,43.14 98.85,44.93 98.63,45.15 98.43,45.15 v2(98.29,45)
DDR_A_DQS#1: length 54.8
  IN1 w0.076: v2(116.21,86.11) 116.13,86.03 115.86,86.03 115.72,86.17 115.45,86.17 115.23,85.95 115.23,85.4 115.54,85.1 115.54,79.19 112.26,75.91 112.26,74.81 112.25,74.8 112.25,74.76
  IN1 w0.114: v2(103.53,47.29) 103.53,46.97 103.69,46.81 103.91,46.81 104.04,46.94 104.04,49.35 106.6,51.91 106.6,59.79 108.53,61.72 108.53,65.22 108.95,65.63 108.95,67.94 110.55,69.54 110.55,72.45 112.25,74.15 112.25,74.76
  BOTTOM w0.076: UC1.AN62 118.55,86.66 118.55,86.75 118.49,86.81 118.06,86.81 118,86.84 117.92,86.88 117.9,86.88 117.77,86.88 117.72,86.86 117.67,86.84 117.65,86.84 117.62,86.83 116.29,86.83 115.85,86.39 115.85,86.11 115.96,86.01 116.1,86.01 v2(116.21,86.11)
  BOTTOM w0.102: JDIMM1.27 103.95,48.69 104.02,48.62 104.35,48.62 104.5,48.47 104.5,47.06 104.21,46.76 103.71,46.76 103.53,46.95 v2(103.53,47.29)
DDR_A_DQS#2: length 50
  IN1 w0.076: v2(119.45,80.63) 119.41,80.59 119.41,80.44 120.01,79.85 120.01,79.34 116.76,76.09 116.76,74.78 116.76,74.78 116.76,74.76
  IN1 w0.114: 116.76,74.76 116.76,71.98 116.4,71.62 116.28,71.62 115.02,70.36 115.02,67.27 114.71,66.96 114.71,60 113.7,58.98 113.7,58.63 113.31,58.24 113.17,58.24 111.68,56.75 111.68,51.67 111.8,51.54 111.8,50.9 111.32,50.43 111.32,50.11 110.25,49.04 110.25,48.4 110.02,48.17 109.36,48.17 109.12,47.92 109.12,46.74 109.23,46.63 109.55,46.63 109.64,46.72 v2(109.64,46.98)
  BOTTOM w0.076: UC1.AV57 121.38,83.83 121.3,83.75 121.15,83.75 121.06,83.66 121,83.6 120.92,83.44 120.92,83.23 120.95,83.17 120.99,83.07 120.99,82.94 120.92,82.79 120.92,82.58 120.94,82.53 120.95,82.53 120.98,82.44 120.99,82.42 120.99,82.24 120.75,81.99 120.75,81.33 119.67,80.25 119.55,80.25 119.45,80.36 v2(119.45,80.63)
  BOTTOM w0.102: JDIMM1.45 109.35,48.95 109.4,48.9 109.63,48.9 109.76,48.77 109.76,48.29 110.16,47.88 110.16,46.71 110.07,46.61 109.76,46.61 109.64,46.74 v2(109.64,46.98)
DDR_A_DQS#3: length 48.4
  IN1 w0.076: v2(121.09,76.28) 121.09,76.47 120.96,76.59 120.8,76.59 120.7,76.49 120.7,75.48 121.05,75.12 121.05,74.76
  IN1 w0.114: 121.05,74.76 121.05,70.23 120.3,69.48 120.3,69.15 119.61,68.46 119.61,58.86 117.97,57.21 117.97,56.86 117.07,55.96 117.07,53.05 116.84,52.83 116.84,50.62 116.54,50.32 116.54,49.6 116.1,49.16 116.1,45.58 115.43,44.92 115.19,44.92 v2(114.96,44.69)
  BOTTOM w0.076: v2(121.09,76.28) 121.09,76.53 120.76,76.86 120.76,78.18 122.97,80.4 122.97,81.64 123.17,81.83 123.17,81.96 123.42,82.21 123.42,82.42 123.38,82.52 123.35,82.58 123.35,82.79 123.42,82.94 123.42,83.43 123.53,83.54 123.53,83.71 UC1.AV53
  BOTTOM w0.102: JDIMM1.62 114.45,42.73 114.66,42.94 114.85,42.94 115.39,43.49 115.39,44.76 115.27,44.88 115.16,44.88 v2(114.96,44.69)
DDR_A_DQS#4: length 47.5
  IN1 w0.076: v2(137.85,81.13) 137.85,81.08 138.19,80.74 138.29,80.74 138.64,80.39 138.64,74.66 139.15,74.15 139.15,73.84 139.93,73.05 140.64,72.34 140.9,72.34 141.21,72.03 141.21,71.97
  IN1 w0.114: v2(138.56,46.63) 138.56,46.38 138.46,46.28 138.26,46.28 138.15,46.39 138.15,47.74 138.71,48.3 138.71,49.26 138.74,49.29 138.74,49.58 139.23,50.06 139.23,51.5 139.67,51.94 139.67,52.96 139.77,53.07 139.77,53.52 140.14,53.89 140.14,56.31 141.21,57.38 141.21,58.42 141.64,58.85 141.64,68.61 141.21,69.05 141.21,71.97
  BOTTOM w0.076: UC1.AW30 138.08,83.38 138.08,83.52 138.02,83.58 137.88,83.58 137.8,83.5 137.75,83.4 137.75,83.27 137.82,83.11 137.82,82.9 137.8,82.85 137.76,82.77 137.75,82.75 137.75,82.62 137.77,82.56 137.82,82.46 137.82,82.17 137.41,81.75 137.41,81.01 137.49,80.93 137.72,80.93 137.85,81.05 v2(137.85,81.13)
  BOTTOM w0.102: JDIMM1.135 138.75,48.76 139.35,48.16 139.35,46.63 138.95,46.23 138.69,46.23 138.56,46.35 v2(138.56,46.63)
DDR_A_DQS#5: length 49.4
  IN1 w0.076: 146.02,71.97 144.71,73.28 143.57,73.28 140.95,75.9 140.95,78.46 141.1,78.62 141.23,78.62 v2(141.38,78.46)
  IN1 w0.114: v2(143.91,44.44) 144.01,44.44 144.56,44.99 144.56,46.2 144.12,46.63 144.12,50.41 145.34,51.63 145.34,54.13 145.92,54.71 145.92,61.1 146.17,61.36 146.17,64.04 145.97,64.25 145.97,65.12 146.2,65.35 146.2,68.98 146.55,69.33 146.55,71.08 146.07,71.56 146.07,71.92 146.02,71.97
  BOTTOM w0.076: v2(141.38,78.46) 141.23,78.62 140.97,78.62 140.31,79.27 140.31,80.69 139.72,81.27 139.72,81.75 139.85,81.88 140.09,82.12 140.09,82.42 140.01,82.58 140.01,82.79 140.09,82.94 140.09,83.34 140.25,83.5 140.25,83.76 UC1.AV26
  BOTTOM w0.102: v2(143.91,44.44) 144.05,44.58 144.28,44.58 144.39,44.47 144.39,43.45 143.85,42.9 JDIMM1.152
DDR_A_DQS#6: length 50.2
  IN1 w0.076: v2(143.31,81.12) 143.31,80.96 143.58,80.69 143.7,80.69 144.43,79.96 144.43,75.8 144.96,75.27 146.16,75.27 147.63,73.79 149.2,73.79 150.82,72.17 150.82,71.97
  IN1 w0.114: 150.82,71.97 150.82,69.76 151.1,69.49 151.1,68.98 151.27,68.8 151.27,65.71 151.78,65.2 151.78,64.31 151.25,63.78 151.25,63.08 150.66,62.49 150.66,61.63 150.45,61.41 150.45,59.59 150.19,59.33 150.19,54.79 150.34,54.64 150.34,53.19 150.56,52.97 150.56,50.05 149.78,49.27 149.78,47.65 149.45,47.32 149.45,46.67 149.54,46.58 149.67,46.58 v2(149.94,46.85)
  BOTTOM w0.076: v2(143.31,81.12) 143.32,81.12 143.41,81.03 143.41,80.9 143.29,80.77 143.04,80.77 142.94,80.88 142.94,81.43 142.86,81.52 142.86,82.04 142.96,82.14 142.96,82.46 142.88,82.62 142.88,82.75 142.92,82.83 142.98,82.89 142.98,83.28 143.03,83.33 UC1.AW22
  BOTTOM w0.102: JDIMM1.169 148.95,48.88 149.08,48.74 149.31,48.74 150.39,47.67 150.39,46.61 150.23,46.46 150.07,46.46 149.86,46.66 149.86,46.81 149.9,46.85 v2(149.94,46.85)
DDR_A_DQS#7: length 51.7
  IN1 w0.076: 155.33,71.97 155.33,72.2 151.17,76.36 148.07,76.36 v2(147.88,76.17)
  IN1 w0.114: v2(154.74,45.13) 154.74,44.91 154.89,44.76 155.05,44.76 155.23,44.94 155.23,54.95 155.33,55.04 155.33,62.09 155.85,62.62 155.85,71.06 155.33,71.59 155.33,71.97
  BOTTOM w0.076: v2(147.88,76.17) 147.75,76.3 146.55,76.3 145.74,77.1 145.74,80.73 145,81.47 145,82.01 145.22,82.23 145.22,82.42 145.19,82.49 145.15,82.59 145.14,82.76 145.22,82.94 145.22,83.37 145.6,83.76 UC1.AV18
  BOTTOM w0.102: JDIMM1.186 154.05,43.14 153.93,43.26 153.93,44.62 154.21,44.9 154.63,44.9 154.74,45.02 v2(154.74,45.13)
DDR_A_MA0: length 45.9
  IN1 w0.076: 132.78,74.76 133.48,75.46 133.48,79.53 133.86,79.91 133.86,80.65 134.24,81.03 134.24,81.37 133.8,81.81 133.8,83.58 v2(134.17,83.94)
  IN1 w0.183: 132.78,74.76 132.47,74.45 132.47,67.94 130.74,66.21 130.74,61.64 130.13,61.02 130.13,55.68 128.28,53.83 128.28,50.24 128.43,50.09 128.43,44.66 v2(127.99,44.23)
  BOTTOM w0.076: UC1.AU36 134.53,84.31 v2(134.17,83.94)
  BOTTOM w0.17: v2(127.99,44.23) 127.65,43.88 JDIMM1.98
DDR_A_MA1: length 46.1
  IN1 w0.076: v2(133.88,81.19) 133.65,81.19 133.59,81.13 133.59,80.09 133.59,80.09 133.59,79.87 133.3,79.59 133.3,75.9 132.59,75.19
  IN1 w0.183: v2(127.95,48.58) 127.84,48.69 127.84,49.04 127.97,49.17 127.97,49.66 127.84,49.79 127.84,50 127.54,50.3 127.54,50.52 127.84,50.83 127.84,51.11 127.66,51.3 127.35,51.3 127.18,51.46 127.18,51.85 127.36,52.03 127.66,52.03 127.84,52.21 127.84,52.58 127.66,52.76 127.36,52.76 127.18,52.94 127.18,53.31 127.36,53.49 127.66,53.49 127.84,53.67 127.84,54.01 129.69,55.86 129.69,61.2 130.31,61.82 130.31,62.16 130.12,62.35 129.83,62.35 129.65,62.53 129.65,62.89 129.83,63.08 130.12,63.08 130.31,63.26 130.31,63.63 130.12,63.81 129.83,63.81 129.65,63.99 129.65,64.36 129.83,64.54 130.12,64.54 130.31,64.72 130.31,65 129.77,65.53 129.77,65.86 132.03,68.12 132.03,70.41 131.85,70.59 131.22,70.59 130.99,70.83 130.99,71.22 131.17,71.4 131.88,71.4 132.03,71.55 132.03,72.06 131.91,72.19 131.68,72.19 131.47,72.39 131.47,72.72 131.7,72.95 131.85,72.95 132.03,73.13 132.03,74.63 132.59,75.19
  BOTTOM w0.076: v2(133.88,81.19) 133.79,81.28 133.79,82.28 UC1.AY37
  BOTTOM w0.17: JDIMM1.97 127.35,48.99 127.11,48.75 127.11,48.41 127.36,48.16 127.61,48.16 127.95,48.51 v2(127.95,48.58)
DDR_A_MA2: length 49.2
  IN1 w0.076: v2(133.99,85.86) 133.99,85.46 133.32,84.79 133.32,81.77 133.25,81.7 133.25,80 132.9,79.65 132.9,76.76 131.16,75.02 131.16,74.76
  IN1 w0.183: 131.16,74.76 131.16,73.64 130.6,73.08 130.6,72.07 130.11,71.58 130.11,70.47 130.49,70.09 130.49,67.82 128.77,66.09 128.77,56.25 126.29,53.77 126.29,50.32 126.97,49.64 126.97,47.27 127.46,46.78 127.46,46.03 v2(127.95,45.54)
  BOTTOM w0.076: v2(133.99,85.86) 133.99,85.86 133.6,85.47 UC1.AR38
  BOTTOM w0.17: v2(127.95,45.54) 127.05,44.63 JDIMM1.96
DDR_A_MA3: length 49
  IN1 w0.076: v2(134.01,86.48) 134.37,86.11 134.37,85.57 133.49,84.69 133.49,81.7 133.42,81.64 133.42,80.02 133.42,80.02 133.42,79.94 133.13,79.64 133.13,76.34 132.36,75.57
  IN1 w0.183: v2(127.95,47.05) 127.81,47.05 127.4,47.46 127.4,49.82 126.72,50.5 126.72,53.59 129.2,56.06 129.2,65.91 131.55,68.26 131.55,69.83 131.22,70.16 131.04,70.16 130.55,70.65 130.55,71.4 131.04,71.89 131.04,72.9 131.6,73.46 131.6,74.81 132.36,75.57
  BOTTOM w0.076: UC1.AP36 134.36,86.12 v2(134.01,86.48)
  BOTTOM w0.17: v2(127.95,47.05) 127,47.05 126.75,47.31 JDIMM1.95
DDR_A_MA4: length 48.1
  IN1 w0.076: 130.72,74.76 130.72,75.22 132.72,77.22 132.72,79.7 133.07,80.06 133.07,81.75 133.16,81.84 133.16,83.57 v2(132.55,84.18)
  IN1 w0.183: v2(125.87,45.43) 126.53,46.09 126.53,49.46 125.84,50.15 125.84,50.95 125.25,51.54 125.25,52.53 125.85,53.13 125.85,53.95 128.33,56.43 128.33,66.27 130.06,68 130.06,69.91 129.68,70.29 129.68,71.76 130.16,72.25 130.16,73.27 130.72,73.82 130.72,74.76
  BOTTOM w0.076: v2(132.55,84.18) 132.68,84.31 UC1.AU39
  BOTTOM w0.17: v2(125.87,45.43) 125.87,45.35 126.64,44.59 126.64,43.48 125.85,42.69 JDIMM1.92
DDR_A_MA5: length 46.9
  IN1 w0.076: 130.28,74.76 130.28,75.27 132.52,77.5 132.52,79.73 132.9,80.11 132.9,81.81 132.99,81.9 132.99,83.5 132.72,83.77 132.32,83.77 132.11,83.98 132.11,85.01 132.34,85.24 v2(133.08,85.24)
  IN1 w0.183: v2(125.87,48.48) 125.98,48.48 126.09,48.59 126.09,49.27 125.4,49.97 125.4,50.77 124.81,51.36 124.81,52.71 125.41,53.31 125.41,54.13 127.89,56.61 127.89,66.45 129.62,68.18 129.62,69.73 129.24,70.11 129.24,71.94 129.73,72.43 129.73,73.45 130.28,74 130.28,74.76
  BOTTOM w0.076: v2(133.08,85.24) 133.25,85.07 133.58,85.07 133.98,85.47 UC1.AR36
  BOTTOM w0.17: v2(125.87,48.48) 125.87,48.4 125.68,48.21 125.45,48.21 125.3,48.36 125.3,48.72 125.55,48.96 JDIMM1.91
DDR_A_MA6: length 47.1
  IN1 w0.076: v2(132.54,81.51) 132.54,81.5 132.13,81.09 132.13,78.23 129.41,75.51 129.41,74.76
  IN1 w0.183: 129.41,74.76 129.41,74.37 128.85,73.81 128.85,72.79 128.37,72.31 128.37,70.03 128.25,69.91 128.25,68.05 127.02,66.82 127.02,56.97 124.54,54.49 124.54,53.67 123.94,53.07 123.94,51 124.53,50.41 124.53,49.61 124.97,49.16 124.97,46.71 125.42,46.25 125.42,44.48 125.87,44.03 v2(125.87,43.9)
  BOTTOM w0.076: v2(132.54,81.51) 132.52,81.49 132.16,81.49 131.85,81.8 131.85,83.37 UC1.AV40
  BOTTOM w0.17: JDIMM1.90 125.25,43.28 v2(125.87,43.9)
DDR_A_MA7: length 46.6
  IN1 w0.076: 128.97,74.76 129,74.78 129,75.48 131.96,78.44 131.96,82.11 v2(132.56,82.71)
  IN1 w0.183: v2(123.65,43.9) 124.97,45.23 124.97,46.09 124.46,46.59 124.46,49.05 124.09,49.43 124.09,50.23 123.5,50.81 123.5,53.25 124.1,53.85 124.1,54.67 126.58,57.15 126.58,67 127.81,68.23 127.81,70.09 127.93,70.21 127.93,72.49 128.42,72.97 128.42,73.99 128.97,74.55 128.97,74.76
  BOTTOM w0.076: UC1.AW39 132.86,83.01 v2(132.56,82.71)
  BOTTOM w0.17: JDIMM1.86 124.05,43.68 123.82,43.9 v2(123.65,43.9)
DDR_A_MA8: length 45.7
  IN1 w0.076: v2(132.54,80.37) 132.31,80.14 132.31,78.03 129.85,75.57 129.85,74.76
  IN1 w0.183: v2(125.87,46.95) 125.87,46.88 125.73,46.74 125.56,46.74 125.4,46.89 125.4,48.64 125.63,48.87 125.63,49.12 124.96,49.79 124.96,50.59 124.38,51.18 124.38,52.89 124.98,53.49 124.98,54.31 127.46,56.79 127.46,66.64 128.99,68.16 128.99,68.46 128.69,68.76 128.69,69.73 128.8,69.85 128.8,72.12 129.29,72.61 129.29,73.63 129.85,74.19 129.85,74.76
  BOTTOM w0.076: UC1.AY39 132.97,82.13 133.08,82.02 133.08,80.77 132.67,80.37 v2(132.54,80.37)
  BOTTOM w0.17: v2(125.87,46.95) 125.87,46.8 125.35,46.28 125.12,46.28 124.95,46.46 JDIMM1.89
DDR_A_MA9: length 47.3
  IN1 w0.076: v2(130.97,78.41) 130.59,78.41 128.2,76.02 128.2,75.01 127.95,74.76
  IN1 w0.183: v2(123.65,46.95) 123.49,46.79 123.24,46.79 123.09,46.93 123.09,49.68 122.33,50.44 122.33,53.78 123.23,54.68 123.23,55.03 125.71,57.51 125.71,67.36 126.94,68.59 126.94,70.53 126.44,71.03 126.44,71.76 127.06,72.37 127.06,72.85 127.54,73.34 127.54,74.35 127.95,74.76
  BOTTOM w0.076: v2(130.97,78.41) 131.22,78.41 131.68,78.88 131.68,83.63 132.09,84.04 UC1.AU40
  BOTTOM w0.17: v2(123.65,46.95) 124.25,46.95 124.44,47.13 124.44,48.46 123.75,49.15 JDIMM1.85
DDR_A_MA10: length 47.1
  IN1 w0.076: v2(134.91,85.78) 134.12,84.99 134.12,84.58 134.6,84.1 134.6,83.11 135.18,82.53 135.18,74.2 134.88,73.89 134.88,73.41
  IN1 w0.183: v2(131.24,52.19) 131.24,52.57 131.42,52.75 131.42,53.29 131.62,53.49 131.62,53.62 132.87,54.87 132.87,55.47 133.44,56.04 133.44,56.31 133.1,56.65 133.1,61.03 133.28,61.22 134.31,61.22 134.5,61.4 134.5,61.77 134.31,61.95 133.28,61.95 133.1,62.13 133.1,62.5 133.28,62.68 134.31,62.68 134.5,62.86 134.5,63.23 134.31,63.41 133.28,63.41 133.1,63.59 133.1,63.96 133.28,64.14 134.31,64.14 134.5,64.33 134.5,64.69 134.31,64.87 133.28,64.87 133.1,65.06 133.1,65.25 134.88,67.04 134.88,73.41
  BOTTOM w0.076: v2(134.91,85.78) 135.25,86.12 UC1.AP35
  BOTTOM w0.17: v2(131.24,52.19) 131.08,52.35 130.66,52.35 130.35,52.04 JDIMM1.107
DDR_A_MA11: length 47.6
  IN1 w0.076: v2(130.99,82.72) 131.55,82.17 131.55,79.07 131.25,78.77 130.46,78.77 127.74,76.05 127.74,75.17 127.33,74.76
  IN1 w0.183: 127.33,74.76 127.11,74.53 127.11,73.52 126.62,73.03 126.62,72.55 126,71.94 126,70.85 126.5,70.35 126.5,68.77 125.27,67.54 125.27,57.69 122.79,55.22 122.79,54.86 121.89,53.96 121.89,50.26 122.65,49.5 122.65,46.43 v2(123.65,45.43)
  BOTTOM w0.076: v2(130.99,82.72) 131.28,83.01 UC1.AW41
  BOTTOM w0.17: JDIMM1.84 123.45,43.12 123.07,43.5 123.07,44.76 v2(123.65,45.43)
DDR_A_MA12: length 46.4
  IN1 w0.076: v2(130.99,84.12) 131.75,83.36 131.75,78.62 128.57,75.43 128.57,74.79 128.54,74.76
  IN1 w0.183: 128.54,74.76 128.54,74.73 127.98,74.17 127.98,73.16 127.49,72.67 127.49,71.94 127.31,71.76 127.06,71.76 126.88,71.58 126.88,71.21 127.06,71.03 127.31,71.03 127.49,70.84 127.49,70.39 127.38,70.27 127.38,68.41 126.15,67.18 126.15,57.33 123.67,54.85 123.67,54.03 123.46,53.82 122.99,53.82 122.76,53.6 122.76,53.27 123.07,52.96 123.07,52.61 122.76,52.3 122.76,51.97 123.07,51.67 123.07,51.34 122.76,51.03 122.76,50.62 122.94,50.45 123.25,50.45 123.65,50.05 123.65,49.24 124.03,48.87 124.03,48.51 123.91,48.39 123.74,48.39 v2(123.65,48.48)
  BOTTOM w0.076: UC1.AU41 131.26,84.12 v2(130.99,84.12)
  BOTTOM w0.17: JDIMM1.83 123.15,48.72 122.74,48.31 122.74,48.06 122.91,47.88 123.24,47.88 123.65,48.3 v2(123.65,48.48)
DDR_A_MA13: length 47.3
  IN1 w0.076: v2(134.9,85.13) 135.12,85.13 136.68,83.57 136.68,79 136.53,78.84 136.53,74.22 137.5,73.25 137.5,71.97
  IN1 w0.183: 137.5,71.97 137.5,67.47 137.9,67.07 137.9,61.59 137.7,61.38 137.7,61.11 137.9,60.91 137.9,60.43 137.65,60.17 136.98,60.17 136.79,59.98 136.79,59.72 137.42,59.09 137.42,58.83 137.11,58.52 136.85,58.52 136.24,59.13 135.99,59.13 135.8,58.95 135.8,57.71 136.06,57.46 136.06,54.95 135.51,54.41 135.51,53.72 135.02,53.23 135.02,51.29 134.31,50.59 134.31,48.97 134.26,48.91 134.26,48.46 134.07,48.26 133.84,48.26 133.64,48.46 v2(133.64,48.58)
  BOTTOM w0.076: UC1.AR35 135.55,85.33 135.55,85.06 135.47,84.98 135.07,84.98 134.92,85.13 v2(134.9,85.13)
  BOTTOM w0.17: JDIMM1.119 133.95,49.12 134.17,48.9 134.17,48.34 134.01,48.19 133.81,48.19 133.64,48.36 v2(133.64,48.58)
DDR_A_MA14: length 47.4
  IN1 w0.076: 125.75,74.76 125.75,75.59 130.31,80.14 130.31,80.6 130.69,80.98 v2(130.97,80.98)
  IN1 w0.183: 125.75,74.76 125.75,74.02 125.31,73.57 125.31,73.1 124.68,72.47 124.68,68.81 123.96,68.08 123.96,58.24 121.48,55.76 121.48,55.41 120.58,54.5 120.58,45.06 v2(121.73,43.9)
  BOTTOM w0.076: v2(130.97,80.98) 130.94,80.98 130.27,81.64 130.27,83.37 UC1.AV42
  BOTTOM w0.17: v2(121.73,43.9) 122.25,43.39 JDIMM1.80
DDR_A_MA15: length 48.3
  IN1 w0.076: v2(130.97,79.86) 130.41,79.86 126.19,75.64 126.19,74.76
  IN1 w0.183: 126.19,74.76 126.19,73.84 125.74,73.39 125.74,72.92 125.12,72.29 125.12,68.62 124.4,67.9 124.4,58.06 121.92,55.58 121.92,55.22 121.01,54.32 121.01,46.14 v2(121.73,45.43)
  BOTTOM w0.076: UC1.AU42 130.52,84.06 130.11,83.65 130.11,80.58 130.83,79.86 v2(130.97,79.86)
  BOTTOM w0.17: JDIMM1.78 121.65,43.09 121.19,43.55 121.19,44.94 121.68,45.43 v2(121.73,45.43)
DDR_A_RAS#: length 46.3
  IN1 w0.076: v2(135.72,81.88) 135.93,81.88 136.27,81.54 136.27,79.15 136.12,79 136.12,73.71 136.63,73.21 136.63,71.97
  IN1 w0.183: 136.63,71.97 136.63,67.11 137.03,66.71 137.03,61.95 136.24,61.16 136.24,60.68 134.93,59.36 134.93,57.35 135.18,57.1 135.18,55.32 134.64,54.77 134.64,54.08 134.15,53.59 134.15,51.65 133.44,50.95 133.44,49.65 132.71,48.93 132.71,46.28 132.54,46.1 132.54,45.67 133.13,45.09 133.13,44.6 132.74,44.22 132.74,43.89 133.05,43.59 133.05,43.26 132.85,43.06 132.52,43.06 132.21,43.36 131.98,43.36 131.68,43.06 131.45,43.06 v2(131.26,43.24)
  BOTTOM w0.076: v2(135.72,81.88) 136.12,82.28 UC1.AY34
  BOTTOM w0.17: v2(131.26,43.24) 131.25,43.23 JDIMM1.110
DDR_A_WE#: length 47.1
  IN1 w0.076: v2(135.72,82.65) 135.59,82.78 135.46,82.78 135.36,82.68 135.36,73.02 135.32,72.98
  IN1 w0.183: 135.32,72.98 135.32,66.56 135.71,66.17 135.71,65.66 135.56,65.51 135.34,65.51 134.78,66.06 134.52,66.06 134.24,65.78 134.24,65.56 134.93,64.87 134.93,64.68 135.12,64.5 135.53,64.5 135.72,64.32 135.72,63.95 135.53,63.77 135.12,63.77 134.93,63.59 134.93,63.22 135.12,63.04 135.53,63.04 135.72,62.86 135.72,62.49 135.53,62.31 135.12,62.31 134.93,62.12 134.93,61.22 134.5,60.78 133.79,60.78 133.53,60.53 133.53,56.83 133.87,56.49 133.87,55.86 133.33,55.31 133.33,54.63 132.06,53.36 132.06,53.31 131.86,53.11 131.86,52.57 131.69,52.4 131.69,51.44 131.22,50.97 131.22,50.69 131.34,50.57 131.34,48.66 v2(131.26,48.58)
  BOTTOM w0.076: UC1.AW34 136.12,82.74 136.03,82.65 v2(135.72,82.65)
  BOTTOM w0.17: v2(131.26,48.58) 131.71,48.13 131.71,47.35 131.84,47.21 132.1,47.21 132.23,47.35 132.23,48.83 132.15,48.92 JDIMM1.113
DDR_B_BS0: length 76.6
  IN3 w0.076: 134.88,73.49 134.88,74.74 134.64,74.98 134.64,84.01 133.64,85.01 133.64,87.79 134.09,88.24 134.65,88.24 134.92,87.97 v2(134.92,87.75)
  IN3 w0.183: 134.88,73.49 134.88,64.41 135.05,64.24 135.99,64.24 136.18,64.06 136.18,58.69 135.56,58.07 135.56,57.71 135.94,57.33 136.31,57.33 136.71,57.72 136.71,58.12 137.06,58.47 137.49,58.47 137.65,58.32 137.65,57.61 137.19,57.15 137.19,56.95 137.36,56.78 137.67,56.78 137.93,56.78 138.84,57.68 139.12,57.68 139.36,57.45 139.36,57.17 138.45,56.26 138.45,56 138.71,55.74 138.96,55.74 139.87,56.65 140.13,56.65 140.39,56.39 140.39,56.13 139.48,55.22 139.48,54.97 139.76,54.69 140.04,54.69 140.9,55.55 141.25,55.55 141.51,55.3 141.51,54.97 140.26,53.72 140.26,53.36 141.16,52.47 141.16,50.9 141.43,50.63 141.43,42.89 142.58,41.74 142.58,41.1 142.9,40.78 142.9,37.3 142.73,37.13 142.73,36.43 143.62,35.54 v2(143.72,35.54)
  BOTTOM w0.076: v2(134.92,87.75) 135.33,87.75 135.41,87.84 UC1.AL35
  BOTTOM w0.17: v2(143.72,35.54) 143.46,35.54 143.24,35.31 143.24,34.88 143.06,34.7 142.78,34.7 142.52,34.95 142.52,35.61 142.95,36.04 JDIMM2.109
DDR_B_BS1: length 76.8
  IN3 w0.076: 135.32,73.49 135.32,74.65 135.01,74.96 135.01,78.99 134.83,79.17 134.83,84.08 134.09,84.81 134.09,85.45 134.36,85.72 134.36,87.07 134.3,87.14 v2(134.17,87.14)
  IN3 w0.183: v2(143.68,32.68) 144.16,33.17 144.16,35.9 143.93,36.13 143.93,36.13 143.65,36.13 143.17,36.61 143.17,36.95 143.34,37.12 143.34,40.96 143.02,41.28 143.02,41.92 141.87,43.07 141.87,48.85 142.05,49.03 142.9,49.03 143.08,49.21 143.08,49.53 142.91,49.71 142.08,49.71 141.87,49.92 141.87,50.3 142.04,50.47 143.39,50.47 143.59,50.68 143.59,51.06 143.41,51.23 142.75,51.23 142.67,51.15 141.79,51.15 141.6,51.34 141.6,52.01 143.21,53.62 143.21,53.9 142.9,54.21 142.6,54.21 141.48,53.09 141.16,53.09 140.88,53.37 140.88,53.72 142.02,54.86 142.02,55.41 141.43,55.99 141.05,55.99 140.85,56.19 140.85,56.58 140.34,57.09 139.97,57.09 139.79,57.27 139.79,57.63 139.3,58.12 138.28,58.12 138.08,58.32 138.08,58.5 137.68,58.91 136.8,58.91 136.62,59.1 136.62,64.51 136.38,64.75 135.56,64.75 135.32,64.99 135.32,73.49
  BOTTOM w0.076: UC1.AM36 134.31,87.42 134.17,87.28 v2(134.17,87.14)
  BOTTOM w0.17: v2(143.68,32.68) 143.67,32.69 143.09,32.69 142.65,32.25 JDIMM2.108
DDR_B_BS2: length 72.4
  IN3 w0.076: 124.46,73.49 124.46,73.53 124.77,73.84 125.4,73.84 125.53,73.97 125.86,73.97 126.38,74.49 126.74,74.49 127.08,74.83 127.08,80.51 126.98,80.61 126.98,84.1 126.8,84.28 126.47,84.28 v2(126.29,84.1)
  IN3 w0.183: 124.46,73.49 124.46,73.24 124.69,73.01 124.69,72.66 124.46,72.43 124.46,72.07 124.69,71.84 124.69,71.52 124.46,71.29 124.46,70.97 124.69,70.74 124.69,70.43 124.46,70.2 124.46,69.89 124.69,69.66 124.69,69.31 124.46,69.08 124.46,68.81 124.69,68.58 124.69,68.29 124.5,68.1 124.13,68.1 123.89,67.86 123.89,57.82 124.13,57.58 124.13,57.29 123.89,57.05 123.89,56.37 124.11,56.15 124.11,55.86 123.89,55.64 123.89,54.65 124.08,54.45 124.74,54.45 124.92,54.28 124.92,53.5 125.1,53.32 126.05,53.32 126.97,52.39 126.98,52.39 126.98,52.08 126.62,51.72 126.62,51.3 126.88,51.04 127.22,50.7 127.9,50.7 128.12,50.48 128.12,50.19 127.88,49.95 127.88,49.28 128.47,48.69 129.05,48.69 129.34,48.41 129.34,48.1 129.16,47.92 128.58,47.92 128.4,47.74 128.4,47.37 128.58,47.19 129.16,47.19 129.34,47 129.34,46.64 129.16,46.46 128.58,46.46 128.4,46.27 128.4,45.91 128.58,45.72 129.16,45.72 129.34,45.54 129.34,45.18 129.16,44.99 128.58,44.99 128.4,44.81 128.4,44.44 128.58,44.26 129.16,44.26 129.34,44.08 129.34,43.79 128.99,43.44 128.99,43.18 129.21,42.95 129.68,42.95 130.4,42.24 130.4,42 131.3,41.1 131.3,40.47 131.1,40.27 131.1,39.01 131.45,38.66 131.45,37.71 131.39,37.65 131.39,35.88 131.58,35.68 131.97,35.68 132.68,34.97 132.68,34.53 132.48,34.34 132.48,33.87 132.64,33.71 132.95,33.71 133.12,33.89 v2(133.12,34.06)
  BOTTOM w0.076: v2(126.29,84.1) 126.5,84.31 UC1.AU49
  BOTTOM w0.17: JDIMM2.79 133.95,34.64 134.27,34.32 134.27,33.71 134.04,33.48 133.7,33.48 v2(133.12,34.06)
DDR_B_CAS#: length 76.7
  IN3 w0.076: v2(135.81,87.7) 135.72,87.78 135.54,87.78 135.44,87.69 135.44,84.82 136.15,84.11 136.15,74.78 137.07,73.86 137.07,73.49
  IN3 w0.183: 137.07,73.49 137.07,66.15 137.93,65.3 137.93,63.81 138.11,63.63 138.33,63.63 138.51,63.45 138.51,63.08 138.33,62.9 138.11,62.9 137.93,62.72 137.93,62.35 138.11,62.17 138.33,62.17 138.51,61.99 138.51,61.62 138.33,61.44 138.11,61.44 137.93,61.25 137.93,60.96 138.1,60.78 138.46,60.78 139.07,60.17 139.07,59.59 139.23,59.43 139.85,59.43 143.31,55.97 143.83,55.97 144.16,55.64 144.16,54.8 144.52,54.44 144.52,53.88 144.72,53.68 144.72,52.91 145.23,52.39 145.47,52.16 145.47,51.43 144.9,50.86 144.9,50.09 144.56,49.75 144.56,49.55 144.68,49.43 145.19,49.43 145.37,49.25 145.37,49.02 145.02,48.68 144.4,48.68 143.88,48.15 143.88,47.95 144.01,47.82 144.91,47.82 145.09,47.64 145.09,47.27 144.91,47.09 143.99,47.09 143.8,46.9 143.8,46.71 144.59,45.92 144.86,45.92 145.09,45.69 145.09,45.27 144.91,45.09 144.54,45.09 144.4,44.96 144.4,44.49 144.54,44.36 144.91,44.36 145.09,44.18 145.09,43.81 144.91,43.63 144.54,43.63 143.94,43.03 143.94,42.85 144.09,42.7 145.19,42.7 145.34,42.55 145.34,42.14 145.19,41.99 144.78,41.99 144.65,41.85 144.65,40.93 144.81,40.77 145.06,40.77 145.36,40.47 145.36,40.22 145.52,40.06 145.75,40.06 146,39.81 146,39.5 145.83,39.32 145.34,39.32 145.22,39.19 145.22,39 145.95,38.26 145.95,38 145.77,37.82 145.04,37.82 144.73,37.51 144.73,37.19 144.92,37 145.58,37 145.74,36.84 145.74,36.47 145.48,36.2 145.48,35.88 v2(145.78,35.57)
  BOTTOM w0.076: v2(135.81,87.7) 136.09,87.42 UC1.AM33
  BOTTOM w0.17: v2(145.78,35.57) 145.47,35.57 145.34,35.45 145.34,34.34 145.23,34.23 144.86,34.23 144.75,34.34 JDIMM2.115
DDR_B_D0: length 69.4
  IN3 w0.076: 112.3,74.13 112.3,74.83 113.84,76.37 114.37,76.37 119.52,81.52 119.52,82.11 120.03,82.62 120.03,84.85 119.92,84.97 119.92,85.4 v2(120.31,85.79)
  IN3 w0.114: 112.3,74.13 110.97,72.8 110.85,72.8 107.02,68.96 107.02,63.04 107.85,62.21 107.85,52.48 107.73,52.37 107.73,50.64 108.23,50.14 109.33,50.14 109.63,49.84 109.63,48.85 109.18,48.39 109.18,44.42 111.99,41.61 112.28,41.61 113.12,40.77 113.57,40.77 114.2,40.13 114.2,39.46 114.87,38.79 114.87,38.33 116.87,36.32 116.87,35.96 117,35.83 117.24,35.83 117.38,35.69 117.38,35.32 117.24,35.19 117,35.19 116.87,35.05 116.87,34.47 117.79,33.55 v2(117.8,33.55)
  BOTTOM w0.076: UC1.AP58 120.59,85.98 120.49,85.98 v2(120.31,85.79)
  BOTTOM w0.102: v2(117.8,33.55) 117.35,34 117.35,35.45 117.75,35.85 JDIMM2.33
DDR_B_D1: length 68.8
  IN3 w0.076: 112.57,73.85 112.57,74.86 113.91,76.21 114.44,76.21 119.69,81.46 119.69,82.04 120.2,82.55 120.2,85.06 v2(120.28,85.14)
  IN3 w0.114: 112.57,73.85 111.13,72.41 111.01,72.41 107.41,68.8 107.41,63.29 108.23,62.46 108.23,52.32 108.12,52.21 108.12,51.08 108.63,50.57 109.68,50.57 110.11,50.14 110.11,48.78 110.25,48.64 110.72,48.64 110.85,48.51 110.85,48.24 110.72,48.1 110.25,48.1 110.11,47.97 110.11,47.7 110.25,47.56 110.72,47.56 110.85,47.43 110.85,47.16 110.72,47.03 110.25,47.03 110.11,46.89 110.11,46.62 110.25,46.49 110.72,46.49 110.85,46.35 110.85,46.08 110.72,45.95 110.25,45.95 110.11,45.81 110.11,45.55 110.25,45.41 110.72,45.41 110.85,45.28 110.85,45.01 110.72,44.87 110.25,44.87 110.11,44.74 110.11,44.04 112.15,42 112.44,42 113.28,41.16 113.73,41.16 114.59,40.3 114.59,39.62 115.26,38.95 115.26,38.49 117.8,35.94 v2(117.8,35.07)
  BOTTOM w0.076: v2(120.28,85.14) 120.61,85.47 UC1.AR58
  BOTTOM w0.102: v2(117.8,35.07) 118.02,35.07 118.35,35.4 JDIMM2.35
DDR_B_D2: length 71.9
  IN3 w0.076: v2(121.22,87.11) 120.76,87.57 120.76,87.75 120.44,88.06 120.14,88.06 118.45,86.37 118.45,86.32 117.21,85.07 117.21,81.75 112.37,76.91
  IN3 w0.114: 112.37,76.91 110.22,74.76 110.1,74.76 105.06,69.72 105.06,69.4 104.92,69.26 104.81,69.26 104.68,69.13 104.68,68.86 104.81,68.73 104.92,68.73 105.06,68.59 105.06,68.32 104.92,68.19 104.81,68.19 104.68,68.05 104.68,67.78 104.81,67.65 104.92,67.65 105.06,67.51 105.06,67.25 104.92,67.11 104.81,67.11 104.68,66.98 104.68,66.71 104.81,66.57 104.92,66.57 105.06,66.44 105.06,66.17 104.92,66.03 104.81,66.03 104.68,65.9 104.68,65.63 104.81,65.5 104.92,65.5 105.06,65.36 105.06,65.09 104.92,64.96 104.81,64.96 104.68,64.82 104.68,64.55 104.81,64.42 104.92,64.42 105.06,64.28 105.06,64.01 104.92,63.88 104.81,63.88 104.68,63.75 104.68,63.48 104.81,63.34 104.92,63.34 105.06,63.21 105.06,62.18 105.85,61.39 105.85,49.84 106.67,49.02 106.67,41.88 106.96,41.6 107.71,41.6 108.3,41.01 109.42,41.01 109.78,40.64 109.78,40.16 110.05,39.89 110.6,39.89 111.08,39.41 111.75,39.41 112.23,38.92 112.23,38.24 114.61,35.87 v2(114.61,35.07)
  BOTTOM w0.076: v2(121.22,87.11) 121.53,87.42 UC1.AM57
  BOTTOM w0.102: v2(114.61,35.07) 114.75,35.22 JDIMM2.23
DDR_B_D3: length 72.7
  IN3 w0.076: 112.5,77.6 117.02,82.12 117.02,85.12 118.24,86.34 118.24,86.39 120.08,88.23 121.02,88.23 121.21,88.42 v2(121.21,88.34)
  IN3 w0.114: v2(114.61,33.55) 114.15,34 114.15,35.77 111.84,38.08 111.84,38.76 111.59,39.02 110.92,39.02 110.44,39.5 109.25,39.5 107.54,41.21 106.79,41.21 106.29,41.72 106.29,48.86 105.44,49.7 105.44,61.17 104.25,62.36 104.25,69.46 109.94,75.15 110.05,75.15 112.5,77.6
  BOTTOM w0.076: UC1.AK57 121.51,88.72 121.21,88.42 v2(121.21,88.34)
  BOTTOM w0.102: v2(114.61,33.55) 114.15,34 JDIMM2.21
DDR_B_D4: length 71.8
  IN3 w0.076: v2(120.29,87.71) 120.12,87.71 117.38,84.97 117.38,81.36 112.38,76.36
  IN3 w0.114: v2(114.61,32.02) 115.17,32.59 115.17,35.85 112.62,38.4 112.62,39.08 111.91,39.79 111.24,39.79 109.64,41.39 108.47,41.39 107.88,41.99 107.3,41.99 107.06,42.22 107.06,49.18 106.25,49.99 106.25,61.65 105.49,62.41 105.49,69.6 110.26,74.37 110.39,74.37 112.38,76.36
  BOTTOM w0.076: v2(120.29,87.71) 120.3,87.71 120.66,88.07 UC1.AL58
  BOTTOM w0.102: JDIMM2.22 114.45,29.95 114.17,30.23 114.17,31.85 114.35,32.02 v2(114.61,32.02)
DDR_B_D5: length 73
  IN3 w0.076: v2(120.22,88.6) 120.22,88.6 118.01,86.4 118.01,86.34 116.23,84.56 116.23,81.89 112.35,78.01
  IN3 w0.114: v2(114.61,30.5) 113.75,31.36 113.75,35.63 110.28,39.09 109.07,39.09 107.34,40.82 106.63,40.82 105.9,41.56 105.9,48.69 105.03,49.56 105.03,60.78 103.76,62.05 103.76,69.52 109.78,75.53 109.88,75.53 112.35,78.01
  BOTTOM w0.076: UC1.AK58 120.59,88.57 120.25,88.57 v2(120.22,88.6)
  BOTTOM w0.102: v2(114.61,30.5) 115.05,30.06 JDIMM2.24
DDR_B_D6: length 69.6
  IN3 w0.076: 113.24,73.62 116.1,76.48 116.29,76.48 120.71,80.9 120.71,84.68 v2(121.15,85.12)
  IN3 w0.114: v2(117.88,30.5) 118,30.38 118.43,30.38 118.66,30.61 118.66,30.99 118.79,31.13 119.5,31.13 119.64,31.26 119.64,31.58 119.5,31.72 118.79,31.72 118.66,31.85 118.66,36.19 116.03,38.81 116.03,39.28 115.37,39.94 115.37,40.62 114.05,41.94 113.6,41.94 112.73,42.81 112.73,48.65 109.09,52.28 109.09,62.82 108.18,63.73 108.18,68.48 111.34,71.63 111.45,71.63 113.24,73.42 113.24,73.62
  BOTTOM w0.076: v2(121.15,85.12) 121.5,85.47 UC1.AR57
  BOTTOM w0.102: JDIMM2.34 118.05,30.33 v2(117.88,30.5)
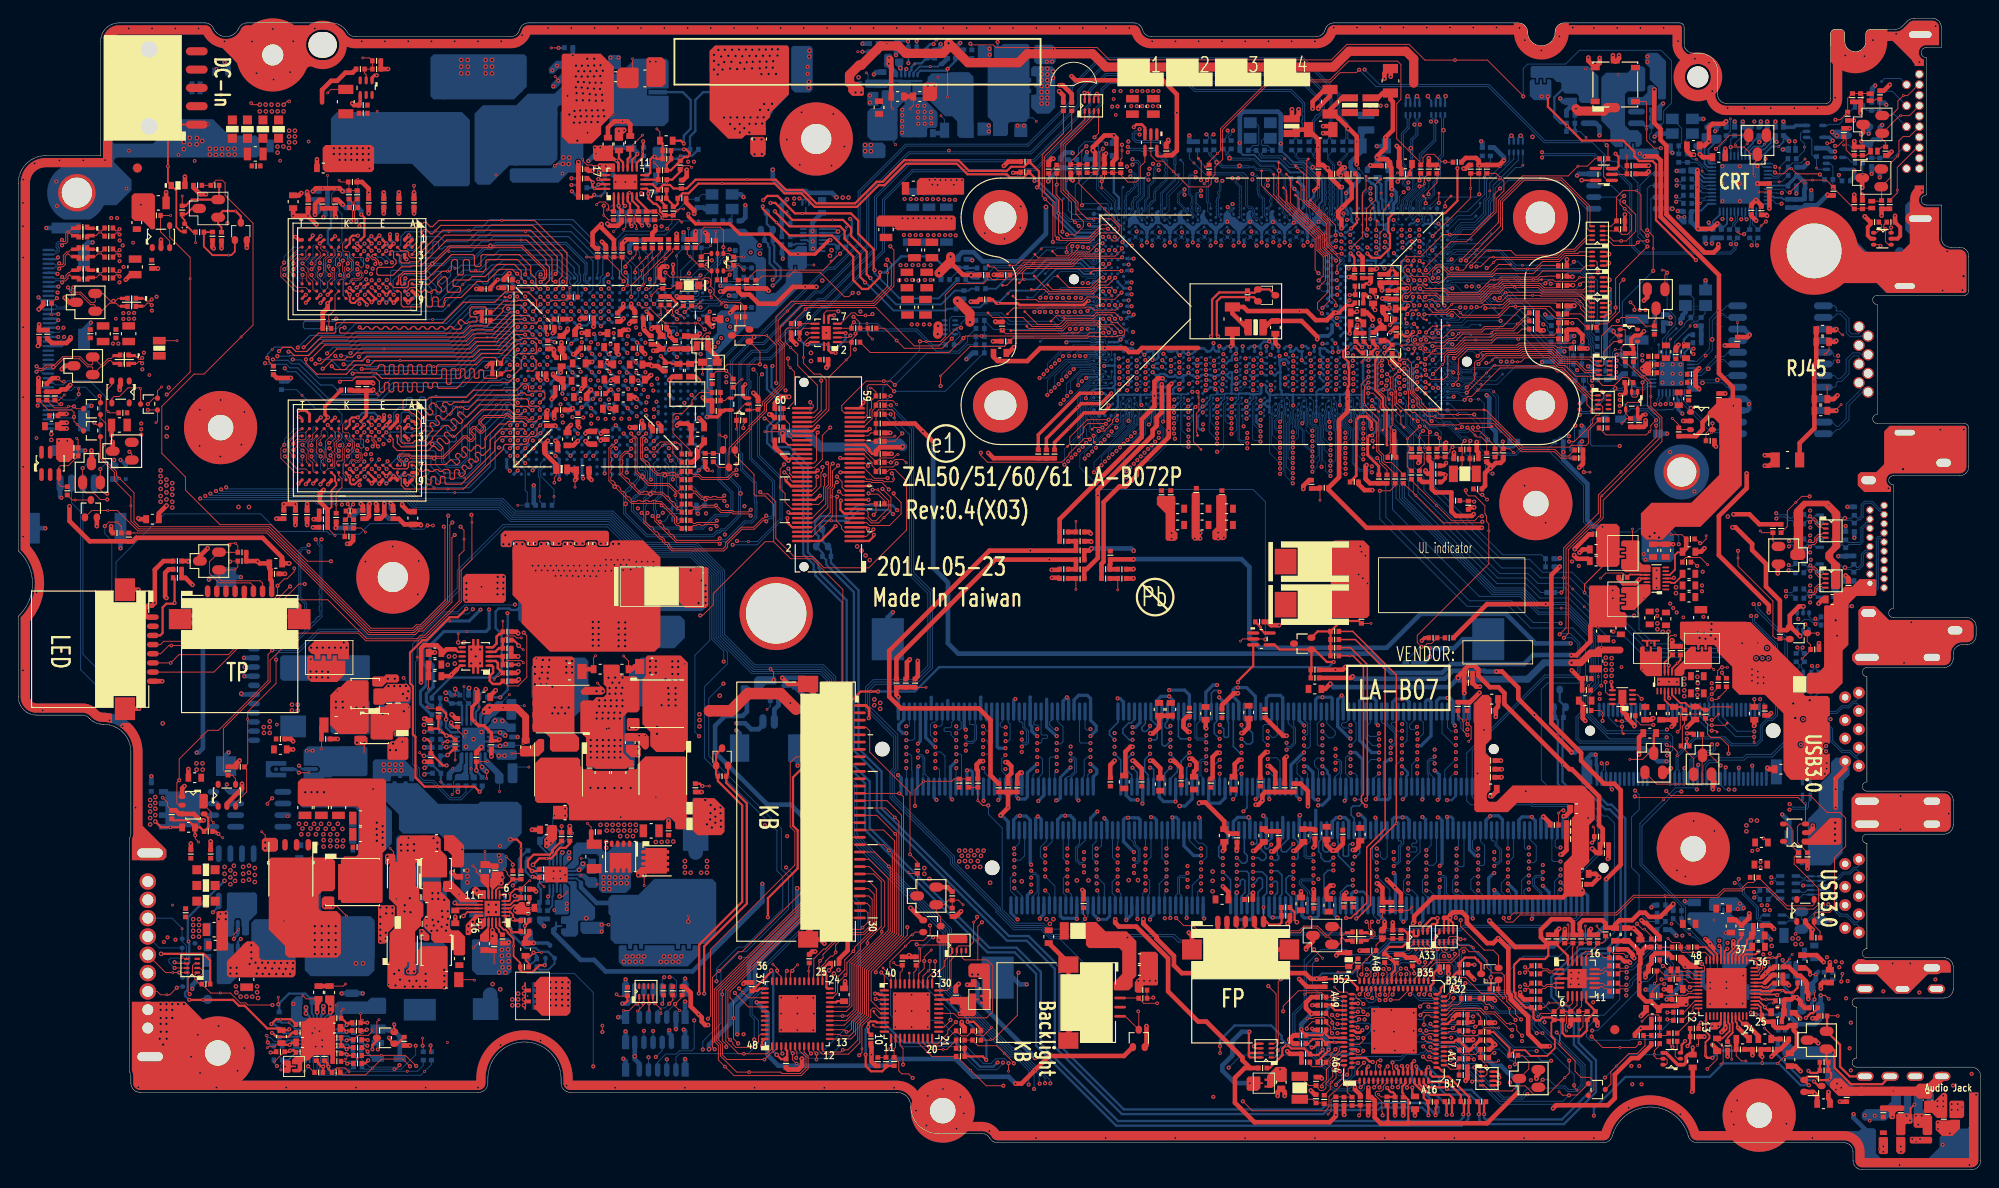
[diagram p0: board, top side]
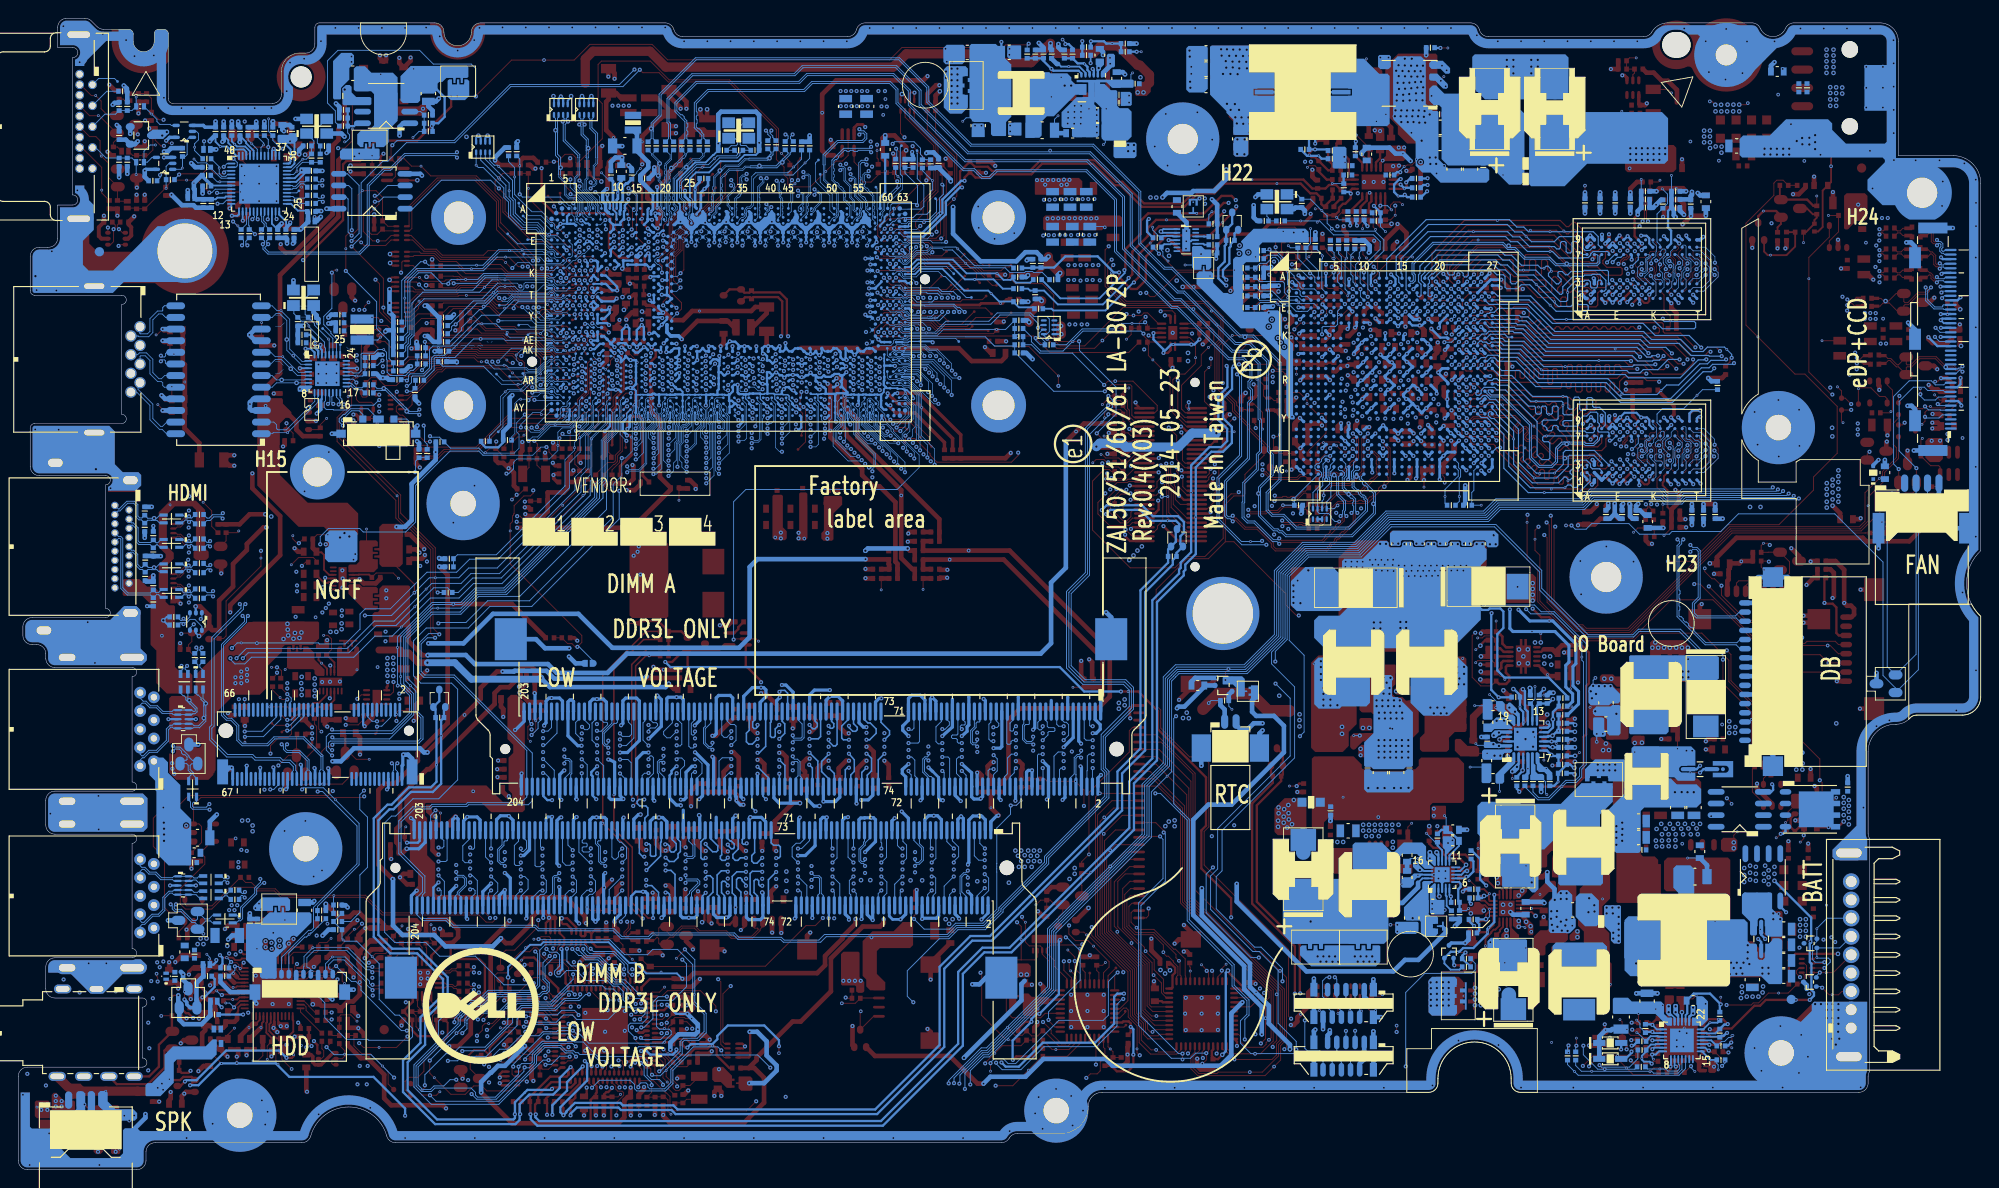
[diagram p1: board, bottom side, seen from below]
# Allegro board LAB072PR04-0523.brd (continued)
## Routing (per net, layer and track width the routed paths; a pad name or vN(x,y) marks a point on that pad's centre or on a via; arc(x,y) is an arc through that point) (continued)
DDR_B_D7: length 71.3
  IN3 w0.076: 112.88,73.61 112.88,74.09 116.06,77.27 116.84,77.27 120.54,80.97 120.54,84.88 120.65,84.99 120.65,85.64 120.66,85.65 120.66,85.84 121.23,86.41 v2(121.23,86.44)
  IN3 w0.114: 112.88,73.61 111.29,72.02 111.18,72.02 107.79,68.64 107.79,63.51 108.64,62.66 108.64,52.17 108.51,52.05 108.51,51.24 108.76,50.99 109.82,50.99 110.74,50.07 110.74,49.88 110.64,49.78 110.64,49.59 110.88,49.35 111.07,49.35 111.17,49.45 111.37,49.45 111.58,49.23 111.58,49.04 111.48,48.94 111.48,48.75 111.7,48.53 111.94,48.53 112.04,48.64 112.18,48.64 112.34,48.47 112.34,42.64 113.44,41.55 113.89,41.55 114.98,40.46 114.98,39.78 115.65,39.12 115.65,38.65 118.27,36.03 118.27,32.16 118.13,32.02 v2(117.8,32.02)
  BOTTOM w0.076: UC1.AN57 121.56,86.77 v2(121.23,86.44)
  BOTTOM w0.102: v2(117.8,32.02) 118.65,31.17 JDIMM2.36
DDR_B_D8: length 67.3
  IN3 w0.076: v2(122.19,85.79) 122.19,85.67 121.99,85.48 121.99,85.48 121.83,85.32 121.83,81.21 114.81,74.2 114.81,74.17 114.66,74.02
  IN3 w0.114: 114.66,74.02 114.66,72.83 112.04,70.21 112.04,70.2 110.55,68.71 110.55,67.54 110.44,67.43 109.77,67.43 109.61,67.27 109.61,66.93 109.74,66.79 110.41,66.79 110.55,66.66 110.55,66.26 110.44,66.15 109.77,66.15 109.61,65.99 109.61,65.65 109.74,65.51 110.41,65.51 110.55,65.38 110.55,65.06 110.41,64.92 109.74,64.92 109.61,64.79 109.61,64.42 109.74,64.28 110.41,64.28 110.55,64.15 110.55,52.84 115.41,47.97 115.41,42.58 117.48,40.52 117.48,40.19 119.26,38.4 119.26,37.59 120.11,36.74 v2(120.11,35.07)
  BOTTOM w0.076: UC1.AP55 122.7,86.12 122.79,86.02 122.79,85.89 122.67,85.77 122.22,85.77 v2(122.19,85.79)
  BOTTOM w0.102: v2(120.11,35.07) 120.07,35.11 120.07,35.67 120.15,35.75 JDIMM2.41
DDR_B_D9: length 66.6
  IN3 w0.076: v2(122.2,85.17) 122,84.97 122,81.15 115.07,74.22 115.07,74.07
  IN3 w0.114: 115.07,74.07 115.07,72.63 110.99,68.55 110.99,52.95 115.8,48.13 115.8,42.74 117.87,40.68 117.87,40.35 119.87,38.35 119.87,37.8 120.55,37.11 120.55,33.04 120.69,32.91 121.03,32.91 121.16,32.77 121.16,32.4 121.03,32.27 120.69,32.27 120.55,32.13 120.55,30.94 v2(120.11,30.5)
  BOTTOM w0.076: v2(122.2,85.17) 122.2,85.17 122.2,85.19 122.48,85.47 UC1.AR55
  BOTTOM w0.102: JDIMM2.42 120.45,30.16 v2(120.11,30.5)
DDR_B_D10: length 69.7
  IN3 w0.076: 117.35,74.07 117.35,74.39 123.02,80.05 123.02,80.9 122.84,81.07 122.84,82.55 123.45,83.16 123.45,84.66 123.67,84.89 123.67,86.6 123.18,87.09 v2(123.14,87.09)
  IN3 w0.114: 117.35,74.07 117.35,71.75 113.85,68.24 113.85,54.04 115.77,52.11 115.77,51.65 118.9,48.52 118.9,42.89 120.26,41.54 120.26,41.22 122.93,38.54 122.93,36.55 123.99,35.49 123.99,33.32 124.4,32.91 124.4,31.66 124.21,31.47 123.71,31.47 v2(123.16,32.02)
  BOTTOM w0.076: UC1.AM54 123.46,87.42 v2(123.14,87.09)
  BOTTOM w0.102: v2(123.16,32.02) 123.61,31.58 123.61,30.18 123.45,30.02 JDIMM2.52
DDR_B_D11: length 70.4
  IN3 w0.076: v2(123.13,88.43) 123.5,88.06 123.5,87 123.84,86.67 123.84,84.77 123.61,84.55 123.61,83.09 123,82.48 123,81.14 123.18,80.96 123.18,79.98 117.74,74.54 117.74,74.07
  IN3 w0.114: v2(123.16,30.5) 123.23,30.43 124.03,30.43 124.79,31.19 124.79,33.26 124.38,33.66 124.38,35.65 123.32,36.71 123.32,37.34 123.52,37.54 123.52,37.88 123.32,38.08 123.32,38.71 121.8,40.23 121.8,40.67 119.31,43.16 119.31,48.66 116.16,51.81 116.16,52.27 114.33,54.1 114.33,68.18 117.74,71.59 117.74,74.07
  BOTTOM w0.076: v2(123.13,88.43) 123.12,88.43 123.41,88.72 UC1.AK54
  BOTTOM w0.102: v2(123.16,30.5) 122.85,30.19 JDIMM2.50
DDR_B_D12: length 69.6
  IN3 w0.076: 114.27,73.49 114.27,73.91 121.67,81.3 121.67,85.45 121.79,85.58 121.79,87.77 121.92,87.9 122.06,87.9 122.19,87.77 v2(122.19,87.74)
  IN3 w0.114: 114.27,73.49 114.27,72.99 111.88,70.6 111.76,70.6 109.21,68.05 109.21,64.22 110.14,63.3 110.14,52.69 114.48,48.35 114.48,47.64 114.62,47.51 114.88,47.51 115.02,47.37 115.02,47 114.86,46.84 114.59,46.84 114.48,46.73 114.48,42.96 117.07,40.38 117.07,39.24 119.69,36.61 119.69,33.97 v2(120.11,33.55)
  BOTTOM w0.076: v2(122.19,87.74) 122.51,88.07 UC1.AL55
  BOTTOM w0.102: JDIMM2.39 119.55,34.11 v2(120.11,33.55)
DDR_B_D13: length 70.7
  IN3 w0.076: 113.88,73.49 113.88,73.77 120.88,80.77 120.88,84.27 121.5,84.89 121.5,85.52 121.63,85.65 121.63,87.84 v2(122.18,88.39)
  IN3 w0.114: 113.88,73.49 113.88,73.15 111.72,70.99 111.6,70.99 108.83,68.21 108.83,64.03 109.73,63.12 109.73,52.55 114.09,48.19 114.09,42.8 116.68,40.22 116.68,39.08 119.3,36.45 119.3,32.84 v2(120.11,32.02)
  BOTTOM w0.076: v2(122.18,88.39) 122.51,88.72 UC1.AK55
  BOTTOM w0.102: v2(120.11,32.02) 119.51,31.42 119.51,30.2 119.85,29.86 JDIMM2.40
DDR_B_D14: length 67.8
  IN3 w0.076: 116.53,74 116.53,74.03 122.69,80.19 122.69,80.76 122.51,80.94 122.51,82.78 123.12,83.39 123.12,85.12 v2(123.15,85.16)
  IN3 w0.114: v2(123.16,35.07) 122.52,35.07 122.15,35.44 122.15,38.22 119.44,40.94 119.44,41.26 117.61,43.09 117.61,48.71 114.99,51.33 114.99,51.79 112.45,54.33 112.45,54.76 112.58,54.9 112.8,54.9 112.93,55.03 112.93,55.3 112.8,55.44 112.58,55.44 112.45,55.57 112.45,55.84 112.58,55.97 112.8,55.97 112.93,56.11 112.93,56.38 112.8,56.51 112.58,56.51 112.45,56.65 112.45,56.92 112.58,57.05 112.8,57.05 112.93,57.19 112.93,57.46 112.8,57.59 112.58,57.59 112.45,57.72 112.45,57.99 112.58,58.13 112.8,58.13 112.93,58.26 112.93,58.53 112.8,58.67 112.58,58.67 112.45,58.8 112.45,59.07 112.58,59.21 112.8,59.21 112.93,59.34 112.93,59.61 112.8,59.74 112.58,59.74 112.45,59.88 112.45,60.15 112.58,60.28 112.8,60.28 112.93,60.42 112.93,60.69 112.8,60.82 112.58,60.82 112.45,60.96 112.45,61.22 112.58,61.36 112.8,61.36 112.93,61.49 112.93,61.76 112.8,61.9 112.58,61.9 112.45,62.03 112.45,62.3 112.58,62.44 112.8,62.44 112.93,62.57 112.93,62.84 112.8,62.97 112.58,62.97 112.45,63.11 112.45,63.38 112.58,63.51 112.8,63.51 112.93,63.65 112.93,63.92 112.8,64.05 112.58,64.05 112.45,64.19 112.45,67.94 116.53,72.02 116.53,74
  BOTTOM w0.076: UC1.AR54 123.46,85.47 v2(123.15,85.16)
  BOTTOM w0.102: v2(123.16,35.07) 123.15,35.08 JDIMM2.51
DDR_B_D15: length 68.9
  IN3 w0.076: 116.94,74.04 116.94,74.21 122.85,80.12 122.85,80.83 122.67,81.01 122.67,82.71 123.28,83.32 123.28,84.77 123.51,85 123.51,85.93 123.14,86.3 v2(123.14,86.44)
  IN3 w0.114: 116.94,74.04 116.94,71.88 113.42,68.36 113.42,67.82 113.28,67.69 113.17,67.69 113.03,67.55 113.03,67.28 113.17,67.15 113.28,67.15 113.42,67.01 113.42,66.74 113.28,66.61 113.17,66.61 113.03,66.48 113.03,66.21 113.17,66.07 113.28,66.07 113.42,65.94 113.42,53.92 115.38,51.95 115.38,51.49 118.5,48.37 118.5,46.68 118.36,46.55 118.15,46.55 118.01,46.41 118.01,46.07 118.15,45.93 118.36,45.93 118.5,45.8 118.5,45.43 118.36,45.29 118.15,45.29 118.01,45.16 118.01,44.74 118.15,44.6 118.36,44.6 118.5,44.47 118.5,44.02 118.39,43.91 118.17,43.91 118.01,43.75 118.01,43.41 118.17,43.25 118.39,43.25 118.5,43.14 118.5,42.75 119.87,41.38 119.87,41.06 122.54,38.38 122.54,36.39 123.59,35.34 123.59,33.98 v2(123.16,33.55)
  BOTTOM w0.076: UC1.AN54 123.46,86.77 v2(123.14,86.44)
  BOTTOM w0.102: v2(123.16,33.55) 123.75,34.14 JDIMM2.53
DDR_B_D16: length 92
  IN3 w0.076: 111.94,84.71 115.4,88.17 116.44,88.17 118.83,90.55 119.77,90.55 120.25,91.04 120.68,91.04 120.78,90.93 121.5,90.93 121.62,91.05 129.28,91.05 131.26,89.07 v2(131.66,89.07)
  IN3 w0.114: 111.94,84.71 111.94,84.69 110.9,83.64 110.9,82.07 108.97,80.14 108.26,80.14 108.22,80.1 108.03,80.1 108,80.1 107.76,79.86 106.1,79.86 98.74,72.5 98.74,45.28 99.32,44.71 99.32,40.16 104.17,35.31 105.67,35.31 107.83,33.15 107.83,31.74 v2(108.82,30.75)
  BOTTOM w0.076: v2(131.66,89.07) 132.01,88.72 UC1.AK40
  BOTTOM w0.102: JDIMM2.6 109.65,29.92 v2(108.82,30.75)
DDR_B_D17: length 91.7
  IN3 w0.076: v2(130.63,88.37) 130.47,88.53 130.47,88.83 128.75,90.56 122.55,90.56 121.81,89.82 121.43,89.82 121.29,89.96 119.03,89.96 112.16,83.1
  IN3 w0.114: v2(108.82,33.8) 109.33,33.29 109.33,32.62 109.48,32.46 109.86,32.46 110.04,32.64 110.04,33.64 109.39,34.29 109.39,35.17 109.05,35.51 107.11,35.51 106.02,36.6 104.53,36.6 101.2,39.93 101.2,41.76 101.01,41.95 101.01,49.68 100.99,49.68 100.03,50.65 100.03,70.48 108.47,78.92 108.79,78.92 112.07,82.19 112.07,83 112.16,83.1
  BOTTOM w0.076: v2(130.63,88.37) 130.66,88.4 130.69,88.4 131.02,88.72 UC1.AK42
  BOTTOM w0.102: JDIMM2.7 109.95,34.28 109.47,33.8 v2(108.82,33.8)
DDR_B_D18: length 89.8
  IN3 w0.076: 112.11,79.8 115.7,83.39 115.7,84.73 117.23,86.26 117.23,87.14 119.39,89.3 120.67,89.3 120.84,89.14 122.06,89.14 122.82,89.89 128.1,89.89 129.33,88.66 129.33,87.77 v2(129.75,87.35)
  IN3 w0.114: v2(112.19,35.07) 112,34.88 111.56,34.88 111.35,35.09 111.35,36.01 109.94,37.43 107.93,37.43 106.79,38.57 105.26,38.57 104.09,39.74 104.09,48.31 103.53,48.87 103.53,53.55 103.4,53.68 102.15,53.68 102.01,53.81 102.01,54.16 102.15,54.3 103.43,54.3 103.53,54.4 103.53,54.75 103.4,54.88 102.15,54.88 102.01,55.02 102.01,55.29 102.17,55.45 103.43,55.45 103.53,55.55 103.53,55.9 103.4,56.04 102.15,56.04 102.01,56.17 102.01,69.78 109.19,76.95 109.26,76.95 112.11,79.8
  BOTTOM w0.076: v2(129.75,87.35) 129.81,87.42 UC1.AM43
  BOTTOM w0.102: JDIMM2.17 112.95,35.83 v2(112.19,35.07)
DDR_B_D19: length 88.9
  IN3 w0.076: v2(128.8,87.15) 128.41,87.54 128.41,89.12 128.01,89.51 123,89.51 122.25,88.76 120.57,88.76 120.37,88.96 120.08,88.96 119.87,88.75 119.87,88.49 117.56,86.18 117.56,86.12 116.06,84.62 116.06,82.63 112.35,78.92
  IN3 w0.114: v2(112.19,30.5) 113.03,31.34 113.03,35.43 110.23,38.23 108.94,38.23 107.49,39.68 106.5,39.68 106.17,39.35 105.58,39.35 104.87,40.06 104.87,48.63 104.35,49.15 104.35,59.21 104.21,59.34 103.14,59.34 103,59.47 103,59.82 103.13,59.95 104.24,59.95 104.37,60.08 104.37,60.49 104.25,60.62 103.09,60.62 103,60.7 103,69.67 109.51,76.18 109.61,76.18 112.35,78.92
  BOTTOM w0.076: UC1.AM45 129.07,87.42 v2(128.8,87.15)
  BOTTOM w0.102: v2(112.19,30.5) 112.65,30.04 JDIMM2.16
DDR_B_D20: length 89.5
  IN3 w0.076: v2(128.81,88.45) 128.81,88.95 128.06,89.7 122.89,89.7 122.15,88.96 120.73,88.96 120.55,89.14 119.45,89.14 117.39,87.08 117.39,86.19 115.88,84.68 115.88,83.01 112.34,79.47
  IN3 w0.114: v2(112.19,32.02) 112.19,32.1 112.63,32.54 112.63,35.29 110.09,37.82 108.79,37.82 107.41,39.2 106.57,39.2 106.33,38.96 105.42,38.96 104.48,39.9 104.48,48.47 103.94,49.01 103.94,56.27 103.78,56.43 102.96,56.43 102.85,56.54 102.85,56.94 102.98,57.07 103.64,57.07 103.76,57.2 103.76,57.58 103.66,57.69 102.75,57.69 102.59,57.85 102.59,58.12 102.75,58.27 103.56,58.27 103.71,58.43 103.71,58.7 103.55,58.86 102.73,58.86 102.59,59 102.59,69.81 109.35,76.57 109.44,76.57 112.34,79.47
  BOTTOM w0.076: UC1.AK45 129.08,88.72 v2(128.81,88.45)
  BOTTOM w0.102: JDIMM2.18 113.25,30.97 v2(112.19,32.02)
DDR_B_D21: length 91.2
  IN3 w0.076: v2(129.75,88.5) 129.73,88.5 128.17,90.06 122.75,90.06 122.01,89.31 121.04,89.31 120.88,89.47 119.32,89.47 117.02,87.17 117.02,86.29 115.52,84.79 115.52,83.77 111.84,80.09 111.77,80.09 111.76,80.08
  IN3 w0.114: v2(112.19,33.55) 112.19,33.66 110.9,34.95 110.9,35.91 109.78,37.04 107.77,37.04 106.63,38.18 105.1,38.18 103.33,39.95 103.33,41.76 102.98,42.11 102.98,50.95 102.87,51.06 102.26,51.06 102.16,51.16 102.16,51.57 102.26,51.67 102.99,51.67 103.13,51.8 103.13,52.07 102.99,52.21 101.64,52.21 101.5,52.34 101.5,52.61 101.64,52.75 102.99,52.75 103.13,52.88 103.13,53.15 102.99,53.29 101.64,53.29 101.5,53.42 101.5,69.82 111.76,80.08
  BOTTOM w0.076: v2(129.75,88.5) 129.97,88.72 UC1.AK43
  BOTTOM w0.102: v2(112.19,33.55) 112.19,33.67 111.67,34.2 111.67,35.23 112.35,35.92 JDIMM2.15
DDR_B_D22: length 91.1
  IN3 w0.076: v2(131.62,87.73) 131.26,88.09 131.26,88.66 129.03,90.89 121.69,90.89 121.53,90.73 121.18,90.73 120.74,90.29 118.84,90.29 113.34,84.79 113.11,84.79 112.23,83.91
  IN3 w0.114: v2(108.82,32.28) 108.31,32.78 108.31,33.22 105.7,35.82 104.2,35.82 99.72,40.31 99.72,49.52 99.13,50.11 99.13,71.37 105.34,77.57 106.02,77.57 108.17,79.72 108.47,79.72 108.49,79.73 108.89,79.73 111.29,82.13 111.29,82.97 112.23,83.91
  BOTTOM w0.076: UC1.AM40 131.93,87.42 v2(131.62,87.73)
  BOTTOM w0.102: v2(108.82,32.28) 108.39,31.85 108.39,30.47 109.05,29.81 JDIMM2.4
DDR_B_D23: length 90.8
  IN3 w0.076: 112.22,83.54 112.37,83.54 118.96,90.13 120.81,90.13 121.25,90.57 121.6,90.57 121.75,90.72 128.82,90.72 130.98,88.55 130.98,87.46 v2(130.75,87.23)
  IN3 w0.114: v2(108.79,35.08) 108.79,35.05 108.18,34.44 107.63,34.44 105.86,36.21 104.36,36.21 100.81,39.77 100.81,41.6 100.62,41.78 100.62,49.17 99.52,50.27 99.52,70.52 100.03,71.03 100.03,71.22 99.94,71.3 99.94,71.49 100.13,71.68 100.32,71.68 100.41,71.6 100.6,71.6 100.79,71.79 100.79,71.98 100.7,72.06 100.7,72.25 100.89,72.44 101.08,72.44 101.17,72.36 101.36,72.36 101.55,72.55 101.55,72.74 101.47,72.82 101.47,73.02 101.66,73.21 101.85,73.21 101.93,73.12 102.12,73.12 102.31,73.31 102.31,73.5 102.23,73.59 102.23,73.78 102.42,73.97 102.61,73.97 102.69,73.88 102.88,73.88 103.07,74.07 103.07,74.26 102.99,74.35 102.99,74.54 103.18,74.73 103.37,74.73 103.45,74.65 103.64,74.65 103.84,74.84 103.84,75.03 103.75,75.11 103.75,75.3 103.94,75.49 104.13,75.49 104.22,75.41 104.41,75.41 104.6,75.6 104.6,75.79 104.51,75.87 104.51,76.06 104.7,76.25 104.89,76.25 104.98,76.17 105.17,76.17 105.36,76.36 105.36,76.55 105.28,76.63 105.28,76.83 105.47,77.02 105.66,77.02 105.74,76.93 105.93,76.93 108.33,79.33 108.8,79.33 111.68,82.2 111.68,83 112.22,83.54
  BOTTOM w0.076: v2(130.75,87.23) 130.94,87.42 UC1.AM42
  BOTTOM w0.102: JDIMM2.5 109.35,35.64 v2(108.79,35.08)
DDR_B_D24: length 71.9
  IN3 w0.076: v2(127.85,87.68) 127.47,87.31 127.47,86.83 127.32,86.68 127.32,85.11 127.02,84.81 126.72,84.81 126.62,84.91 126.05,84.91 125.41,84.28 125.41,82.94 125.75,82.6 125.75,80.88 125.66,80.79 125.66,78.5 121.84,74.67 121.84,74.07
  IN3 w0.114: v2(129.22,33.55) 128.63,34.13 128.63,37.23 128.17,37.69 128.17,38.82 128.39,39.05 128.39,39.46 128.17,39.69 128.17,40.23 127.63,40.76 127.63,40.76 125.86,42.53 125.86,42.54 124.92,43.47 124.92,49.29 123.57,50.64 123.57,50.97 121.16,53.38 121.16,60.87 121.03,61.01 120.2,61.01 120.07,61.14 120.07,61.49 120.2,61.62 121.03,61.62 121.16,61.75 121.16,62.05 121,62.21 120.18,62.21 120.07,62.32 120.07,62.69 120.2,62.82 121.03,62.82 121.16,62.96 121.16,63.3 120.98,63.49 120.15,63.49 120.07,63.57 120.07,66.05 121,66.98 121,69.12 121.84,69.96 121.84,74.07
  BOTTOM w0.076: v2(127.85,87.68) 127.85,87.56 128.08,87.33 128.25,87.33 UC1.AM46
  BOTTOM w0.102: JDIMM2.69 128.55,36.07 128.97,35.65 129.42,35.65 129.85,35.22 129.85,34.19 v2(129.22,33.55)
DDR_B_D25: length 71.8
  IN3 w0.076: v2(127.91,88.5) 127.87,88.5 127.46,88.9 127.46,89.18 127.31,89.33 126.04,89.33 125.48,88.78 125.48,88.39 125.14,88.05 124.8,88.05 124.54,87.79 124.54,86.99 124.53,86.98 124.53,86.97 124.18,86.62 124.18,84.39 124.03,84.23 124.03,80.89 123.93,80.79 123.93,80.27 118.77,75.11 118.77,74.07
  IN3 w0.114: v2(125.45,35.07) 125.51,35.13 125.51,35.99 124.57,36.92 124.57,39.02 123.82,39.77 123.82,40.15 120.63,43.34 120.63,49.24 117.46,52.41 117.46,52.43 116.87,53.02 116.87,57.32 116.74,57.45 116.41,57.45 116.31,57.55 116.31,57.94 116.44,58.07 116.76,58.07 116.87,58.18 116.87,58.62 116.74,58.76 116.14,58.76 116.01,58.89 116.01,59.24 116.14,59.37 116.74,59.37 116.87,59.51 116.87,59.88 116.74,60.01 116.14,60.01 116.01,60.15 116.01,60.52 116.17,60.68 116.76,60.68 116.87,60.79 116.87,61.16 116.74,61.29 116.14,61.29 115.96,61.48 115.96,67.95 117.02,69.01 117.34,69.01 117.83,69.51 117.83,70.22 118.77,71.16 118.77,74.07
  BOTTOM w0.076: UC1.AK46 128.14,88.72 v2(127.91,88.5)
  BOTTOM w0.102: v2(125.45,35.07) 125.55,35.18 JDIMM2.59
DDR_B_D26: length 69.4
  IN3 w0.076: v2(125.89,87.16) 125.89,86.75 125.28,86.14 125.28,85.6 124.54,84.86 124.54,84.23 124.36,84.05 124.36,80.76 124.26,80.66 124.26,80.06 119.56,75.36 119.56,74.07
  IN3 w0.114: v2(125.45,30.5) 126.32,31.37 126.32,36.37 125.87,36.82 125.87,37.03 125.74,37.16 125.51,37.16 125.38,37.3 125.38,37.56 125.51,37.7 125.74,37.7 125.87,37.83 125.87,38.08 125.64,38.31 125.64,39.11 124.64,40.11 124.64,40.43 122.25,42.82 122.25,48.72 121.32,49.65 121.32,49.98 120.25,51.05 119.93,51.05 119.69,51.3 119.69,51.62 117.76,53.54 117.76,62.36 117.62,62.5 117,62.5 116.87,62.63 116.87,62.9 117,63.04 117.62,63.04 117.76,63.17 117.76,63.63 116.77,64.62 116.77,66.02 118.67,67.92 118.67,69.96 119.56,70.85 119.56,74.07
  BOTTOM w0.076: v2(125.89,87.16) 126.15,87.42 UC1.AM49
  BOTTOM w0.102: v2(125.45,30.5) 125.25,30.3 JDIMM2.58
DDR_B_D27: length 68.8
  IN3 w0.076: v2(125.92,88.43) 126.06,88.58 127.1,88.58 127.54,88.14 127.99,88.14 128.22,87.92 128.22,86.91 127.49,86.18 127.49,85.04 127.09,84.64 126.63,84.64 126.54,84.74 126.1,84.74 125.57,84.21 125.57,83.01 125.91,82.67 125.91,80.81 125.82,80.72 125.82,78.2 122.22,74.6 122.22,74.04
  IN3 w0.114: v2(129.22,35.07) 129.04,35.25 129.04,37.37 128.55,37.85 128.55,38.66 128.84,38.95 128.84,39.56 128.55,39.85 128.55,40.39 127.79,41.15 127.79,41.15 126.24,42.7 126.24,42.7 125.31,43.63 125.31,49.45 123.96,50.8 123.96,51.13 121.62,53.47 121.62,63.79 121.48,63.92 120.64,63.92 120.5,64.05 120.5,64.48 120.64,64.61 121.23,64.61 121.37,64.75 121.37,65.12 121.23,65.25 120.64,65.25 120.5,65.39 120.5,65.81 121.39,66.7 121.39,68.96 122.22,69.8 122.22,74.04
  BOTTOM w0.076: v2(125.92,88.43) 126.2,88.72 UC1.AK49
  BOTTOM w0.102: v2(129.22,35.07) 128.82,35.07 127.95,35.94 JDIMM2.67
DDR_B_D28: length 70.9
  IN3 w0.076: 121.06,74.07 121.06,74.45 125.33,78.72 125.33,80.93 125.42,81.02 125.42,82.46 125.07,82.81 125.07,84.42 126.33,85.67 126.33,86.05 126.33,86.05 126.33,86.26 126.86,86.79 v2(126.86,87.04)
  IN3 w0.114: v2(129.22,30.5) 128.6,30.5 128.39,30.71 128.39,33.16 127.85,33.71 127.85,36.91 127.39,37.37 127.39,39.88 124.14,43.12 124.14,48.97 122.8,50.32 122.8,50.65 120.32,53.12 120.32,56.31 120.19,56.45 119.44,56.45 119.33,56.55 119.33,56.93 119.46,57.06 120.21,57.06 120.32,57.17 120.32,57.51 120.19,57.65 119.41,57.65 119.26,57.8 119.26,58.1 119.39,58.24 120.19,58.24 120.32,58.37 120.32,58.69 120.19,58.83 119.44,58.83 119.26,59.01 119.26,66.42 120.2,67.36 120.2,69.42 121.06,70.28 121.06,74.07
  BOTTOM w0.076: v2(126.86,87.04) 126.88,87.06 126.88,87.07 127.23,87.42 UC1.AM48
  BOTTOM w0.102: JDIMM2.70 128.85,30.33 129.02,30.5 v2(129.22,30.5)
DDR_B_D29: length 70.4
  IN3 w0.076: 121.45,74.07 121.45,74.56 125.49,78.61 125.49,80.86 125.58,80.95 125.58,82.53 125.24,82.87 125.24,84.34 126.5,85.6 126.5,85.68 126.5,85.68 126.5,85.98 126.5,85.98 126.5,86.1 127.31,86.9 127.31,87.74 v2(126.84,88.21)
  IN3 w0.114: v2(129.22,32.02) 129.22,32.16 128.78,32.59 128.78,33.43 128.24,33.97 128.24,37.07 127.78,37.53 127.78,40.05 124.53,43.29 124.53,49.13 123.18,50.48 123.18,50.81 120.76,53.24 120.76,59.12 120.6,59.28 119.77,59.28 119.66,59.39 119.66,59.76 119.8,59.9 120.62,59.9 120.76,60.03 120.76,60.43 120.62,60.56 119.8,60.56 119.66,60.7 119.66,66.19 120.61,67.14 120.61,69.28 121.45,70.12 121.45,74.07
  BOTTOM w0.076: v2(126.84,88.21) 127.31,88.68 UC1.AK48
  BOTTOM w0.102: v2(129.22,32.02) 128.25,31.06 JDIMM2.68
DDR_B_D30: length 67.8
  IN3 w0.076: 119.16,74 119.16,75.26 124.1,80.2 124.1,80.72 124.2,80.83 124.2,84.17 124.36,84.33 124.36,86.56 124.71,86.9 124.71,87.45 v2(124.95,87.69)
  IN3 w0.114: v2(125.45,32.02) 125.89,32.47 125.89,36.15 124.99,37.05 124.99,37.73 125.25,37.99 125.25,38.89 124.21,39.94 124.21,40.31 121.26,43.26 121.26,49.16 120.94,49.49 120.94,49.82 120.09,50.66 119.77,50.66 119.3,51.14 119.3,51.45 117.28,53.48 117.28,61.36 116.36,62.27 116.36,66.17 118.24,68.05 118.24,70.08 119.16,71 119.16,74
  BOTTOM w0.076: v2(124.95,87.69) 125.22,87.42 UC1.AM51
  BOTTOM w0.102: JDIMM2.56 124.65,31.23 v2(125.45,32.02)
DDR_B_D31: length 67.9
  IN3 w0.076: 118.38,74 118.38,74.95 123.77,80.33 123.77,80.86 123.87,80.96 123.87,84.47 124.01,84.61 124.01,86.68 124.37,87.04 124.37,87.05 124.37,87.05 124.37,88.38 v2(125.11,89.12)
  IN3 w0.114: v2(125.45,33.55) 125.44,33.55 125.02,33.96 125.02,35.92 124.18,36.76 124.18,38.86 123.25,39.8 123.25,40.18 120.22,43.2 120.22,48.66 117.07,51.81 117.07,52.27 115.52,53.82 115.52,68.46 118.38,71.32 118.38,74
  BOTTOM w0.076: UC1.AK51 125.4,88.82 v2(125.11,89.12)
  BOTTOM w0.102: v2(125.45,33.55) 124.95,34.04 JDIMM2.57
DDR_B_D32: length 67.4
  IN3 w0.076: 139.71,72.47 139.71,73.02 137.32,75.41 137.32,84.04 137.49,84.22 137.49,85.2 137.37,85.33 137.37,86.98 137.68,87.29 137.68,87.43 v2(138.27,88.03)
  IN3 w0.114: v2(148.42,33.55) 148.42,33.54 148.26,33.38 148.11,33.38 148,33.49 148,36.85 149.13,37.98 149.13,40.81 148.24,41.71 148.24,47.82 148.53,48.11 148.73,48.11 149.06,48.44 149.06,49.91 149.15,49.99 149.15,53.69 148.52,54.31 148.3,54.54 148.07,54.76 148.07,57.34 146.28,59.13 145.68,59.73 144.8,59.73 143.67,60.86 141.53,63 141.53,64.24 140.59,65.18 140.59,66.45 139.71,67.32 139.71,72.47
  BOTTOM w0.076: UC1.AM29 138.78,87.52 v2(138.27,88.03)
  BOTTOM w0.102: JDIMM2.129 148.95,36.02 148.69,35.76 148.5,35.76 147.95,35.21 147.95,34.02 v2(148.42,33.55)
DDR_B_D33: length 69
  IN3 w0.076: v2(138.48,89.06) 138.48,88.87 137.52,87.91 137.52,87.36 137.21,87.05 137.21,85.26 137.33,85.13 137.33,84.29 137.06,84.02 137.06,75.41 139.32,73.15 139.32,72.85
  IN3 w0.114: v2(148.42,30.5) 147.8,30.5 147.59,30.71 147.59,37.1 148.72,38.23 148.72,40.67 147.85,41.55 147.85,49 148.32,49.46 148.32,49.71 148.76,50.15 148.76,53.53 148.02,54.26 147.68,54.6 147.68,57.18 145.52,59.34 144.64,59.34 143.72,60.26 141.14,62.84 141.14,64.08 140.2,65.02 140.2,66.29 139.32,67.16 139.32,72.85
  BOTTOM w0.076: UC1.AK29 138.82,88.72 138.5,89.04 138.5,89.06 v2(138.48,89.06)
  BOTTOM w0.102: JDIMM2.130 149.25,29.67 v2(148.42,30.5)
DDR_B_D34: length 68.1
  IN3 w0.076: 140.49,72.57 140.49,72.98 139.68,73.79 139.43,73.79 138.4,74.82 138.4,81.96 137.88,82.48 137.88,85.29 137.7,85.46 137.7,86.83 137.72,86.86 137.72,86.86 138.19,87.33 138.47,87.33 138.84,87.7 138.84,87.86 139.3,88.32 v2(139.3,88.32)
  IN3 w0.114: v2(148.42,32.02) 148.96,32.56 148.96,36.41 149.91,37.36 149.91,41.28 149.84,41.35 149.84,44.25 149.48,44.6 149.48,47.55 149.84,47.91 149.84,49.58 149.93,49.67 149.93,54.01 149.55,54.38 149.55,54.55 149.46,54.64 149.27,54.82 149.27,54.83 148.85,55.25 148.85,57.66 146,60.51 145.12,60.51 144.22,61.41 142.3,63.32 142.3,64.56 141.36,65.5 141.36,66.77 140.49,67.64 140.49,72.57
  BOTTOM w0.076: UC1.AL28 139.67,88.07 139.42,88.32 v2(139.3,88.32)
  BOTTOM w0.102: v2(148.42,32.02) 149.85,30.6 JDIMM2.132
DDR_B_D35: length 68
  IN3 w0.076: 140.1,72.54 140.1,72.89 138.24,74.75 138.24,81.89 137.7,82.43 137.7,85.23 137.54,85.39 137.54,86.9 137.56,86.93 137.56,86.93 137.6,86.97 137.6,86.98 138.13,87.51 138.32,87.51 138.68,87.87 138.68,88.37 139.22,88.92 v2(139.28,88.92)
  IN3 w0.114: v2(148.42,35.07) 148.42,35.56 148.57,35.71 148.57,36.1 148.39,36.28 148.39,36.55 149.52,37.68 149.52,40.97 148.63,41.87 148.63,42.28 148.81,42.46 149.3,42.46 149.43,42.59 149.43,42.86 149.3,43 149.23,43 149.09,43.13 149.09,43.4 149.23,43.54 149.3,43.54 149.43,43.67 149.43,43.94 149.3,44.08 149.23,44.08 149.09,44.21 149.09,47.71 149.45,48.07 149.45,49.74 149.54,49.83 149.54,53.85 149.5,53.89 148.57,54.81 148.46,54.92 148.46,57.5 145.84,60.12 144.96,60.12 143.94,61.14 142.85,62.23 141.92,63.16 141.92,64.4 140.97,65.34 140.97,66.61 140.1,67.48 140.1,72.54
  BOTTOM w0.076: UC1.AK28 139.48,88.72 v2(139.28,88.92)
  BOTTOM w0.102: JDIMM2.131 149.55,34.16 149.31,33.91 149.1,33.91 148.83,34.18 148.83,34.66 v2(148.42,35.07)
DDR_B_D36: length 65.4
  IN3 w0.076: 142.73,72.52 142.73,73.34 142.58,73.49 142.58,73.89 141.61,74.86 140.89,74.86 140.04,75.72 140.04,80.77 139.45,81.35 139.45,82.07 138.82,82.71 138.82,85.19 139.27,85.65 v2(139.27,85.82)
  IN3 w0.114: 142.73,72.52 142.73,68.57 143.6,67.7 143.6,66.43 144.54,65.49 144.54,64.25 146.05,62.74 146.93,62.74 151.09,58.59 151.09,56.18 151.79,55.47 151.79,55.31 152.16,54.94 152.16,54.26 152.3,54.12 152.37,54.12 152.51,53.99 152.51,53.72 152.37,53.59 152.3,53.59 152.16,53.45 152.16,53.18 152.3,53.05 152.37,53.05 152.51,52.91 152.51,52.64 152.37,52.51 152.3,52.51 152.16,52.37 152.16,52.14 152.42,51.89 152.42,50.82 152.16,50.57 152.16,49.5 152.39,49.28 152.39,42.76 152.08,42.45 152.08,42.27 152.21,42.15 152.21,41.38 152.47,41.12 152.47,39.98 152.22,39.73 152.22,39.26 152.47,39.01 152.47,37.86 152.21,37.59 152.21,37.38 152.34,37.25 152.42,37.25 152.56,37.11 152.56,36.84 152.42,36.71 152.34,36.71 152.21,36.57 152.21,36 152.05,35.84 151.73,35.84 151.39,35.5 151.39,35.31 151.6,35.1 v2(151.85,35.1)
  BOTTOM w0.076: v2(139.27,85.82) 138.92,85.47 UC1.AR29
  BOTTOM w0.102: v2(151.85,35.1) 151.85,34.9 152.05,34.7 152.66,34.7 152.79,34.83 152.79,35.16 152.69,35.26 152.35,35.26 152.25,35.36 152.25,35.56 152.35,35.66 152.69,35.66 152.79,35.77 152.79,35.96 152.55,36.2 JDIMM2.141
DDR_B_D37: length 67.1
  IN3 w0.076: 141.95,72.54 141.95,73.57 140.99,74.53 140.75,74.53 139.66,75.63 139.66,80.68 138.98,81.35 138.98,82.07 138.47,82.59 138.47,85.31 138.75,85.59 138.75,86.11 v2(138.39,86.47)
  IN3 w0.114: 141.95,72.54 141.95,68.25 142.82,67.37 142.82,66.11 143.76,65.17 143.76,63.93 145.73,61.97 146.61,61.97 150.31,58.26 150.31,55.85 150.73,55.43 150.73,55.43 151.01,55.15 151.01,54.99 151.39,54.62 151.39,51.82 151.64,51.56 151.64,51.15 151.39,50.89 151.39,49.18 151.61,48.95 151.61,43.08 151.3,42.77 151.3,41.95 151.43,41.82 151.43,41.06 151.68,40.81 151.68,40.29 151.43,40.04 151.43,38.95 151.69,38.69 151.69,38.18 151.43,37.91 151.43,36.64 150.49,35.7 150.49,35.09 151.01,34.57 151.01,31.27 151.75,30.53 v2(151.85,30.53)
  BOTTOM w0.076: v2(138.39,86.47) 138.39,86.68 138.49,86.77 UC1.AN29
  BOTTOM w0.102: JDIMM2.142 152.85,29.94 152.27,30.53 v2(151.85,30.53)
DDR_B_D38: length 65.2
  IN3 w0.076: 143.12,72.47 143.12,73.19 142.74,73.56 142.74,73.96 141.68,75.03 140.96,75.03 140.21,75.78 140.21,80.82 139.68,81.36 139.68,83.67 138.99,84.36 138.99,85.04 139.09,85.14 v2(139.27,85.14)
  IN3 w0.114: v2(151.85,33.57) 151.94,33.48 152.1,33.48 152.3,33.68 152.3,35.54 152.59,35.84 152.59,36.33 152.95,36.68 152.95,37.27 152.79,37.43 152.79,37.62 152.86,37.7 152.86,39.17 152.66,39.37 152.66,39.58 152.86,39.78 152.86,41.28 152.59,41.54 152.59,42.31 153.29,43 153.29,48.65 153.1,48.84 152.89,48.84 152.78,48.95 152.78,49.44 152.55,49.66 152.55,50.41 152.89,50.75 152.89,54.15 152.55,54.49 152.55,55.1 152.18,55.47 152.18,55.64 151.48,56.34 151.48,58.75 147.09,63.13 146.21,63.13 144.93,64.41 144.93,65.65 143.99,66.59 143.99,67.86 143.12,68.73 143.12,72.47
  BOTTOM w0.076: UC1.AR28 139.6,85.47 v2(139.27,85.14)
  BOTTOM w0.102: v2(151.85,33.57) 152.04,33.57 153.15,34.68 JDIMM2.143
DDR_B_D39: length 67
  IN3 w0.076: v2(139.25,86.45) 139.25,86.3 138.92,85.97 138.92,85.52 138.64,85.25 138.64,82.65 139.25,82.04 139.25,81.32 139.83,80.74 139.83,75.69 140.82,74.7 141.06,74.7 142.34,73.42 142.34,72.47
  IN3 w0.114: v2(151.85,32.05) 151.41,32.49 151.41,34.71 150.93,35.2 150.93,35.59 151.82,36.48 151.82,37.75 152.08,38.02 152.08,38.85 151.83,39.1 151.83,39.89 152.08,40.14 152.08,40.96 151.82,41.22 151.82,41.98 151.69,42.11 151.69,42.61 152,42.92 152,49.12 151.77,49.34 151.77,50.73 152.03,50.98 152.03,51.73 151.77,51.98 151.77,54.78 151.4,55.15 151.4,55.31 150.7,56.02 150.7,58.43 146.77,62.35 145.89,62.35 144.15,64.09 144.15,65.33 143.21,66.27 143.21,67.53 142.34,68.41 142.34,72.47
  BOTTOM w0.076: UC1.AP28 139.65,86.12 139.32,86.45 v2(139.25,86.45)
  BOTTOM w0.102: v2(151.85,32.05) 151.34,31.54 151.34,30.41 151.67,30.07 151.97,30.07 152.25,29.8 JDIMM2.140
DDR_B_D40: length 67.2
  IN3 w0.076: v2(140.29,86.44) 139.96,86.11 139.96,84.58 140.84,83.71 140.84,76.03 141.34,75.53 141.88,75.53 143.24,74.17 143.24,73.77 143.54,73.46 144.05,73.46 144.54,72.97 144.54,72.47
  IN3 w0.114: v2(153.83,34.9) 153.88,34.9 154.33,34.44 154.57,34.44 154.68,34.55 154.68,34.96 154.13,35.51 154.13,35.74 154.68,36.28 154.68,36.55 154.41,36.82 154.41,37.09 154.68,37.36 154.68,37.63 154.61,37.7 154.61,39.21 154.75,39.34 155.01,39.34 155.15,39.48 155.15,39.75 155.01,39.88 154.75,39.88 154.61,40.01 154.61,40.92 154.82,41.12 155.18,41.12 155.4,41.34 155.4,42.15 154.71,42.84 154.71,43.07 154.82,43.18 155.12,43.18 155.4,43.46 155.4,44.41 155.2,44.61 155.2,44.95 155.4,45.14 155.4,45.49 155.2,45.68 155.2,46.02 155.4,46.22 155.4,46.64 155.26,46.78 154.85,46.78 154.72,46.91 154.72,47.18 154.85,47.31 155.26,47.31 155.4,47.45 155.4,47.69 155.05,48.03 155.05,48.9 154.31,49.63 154.31,51 154.32,51 154.32,54.74 153.97,55.08 153.97,55.69 153.6,56.06 153.6,56.22 152.9,56.93 152.9,59.34 146.57,65.66 146.57,66.45 145.46,67.56 145.46,68.39 145.41,68.44 145.41,68.45 144.54,69.32 144.54,72.47
  BOTTOM w0.076: v2(140.29,86.44) 140.62,86.77 UC1.AN26
  BOTTOM w0.102: JDIMM2.147 154.35,35.45 153.83,34.93 v2(153.83,34.9)
DDR_B_D41: length 66.4
  IN3 w0.076: 144.92,72.47 144.92,73.11 144.41,73.63 143.61,73.63 143.41,73.83 143.41,74.24 141.95,75.69 141.41,75.69 141,76.1 141,83.82 140.31,84.51 v2(140.31,85.11)
  IN3 w0.114: v2(153.83,30.49) 154.15,30.49 154.27,30.61 154.27,30.74 154.38,30.84 154.63,30.84 154.74,30.95 154.74,31.29 154.63,31.4 154.38,31.4 154.27,31.5 154.27,33.37 155.07,34.17 155.07,37.76 155.58,38.27 155.58,40.97 155.79,41.18 155.79,47.85 155.44,48.2 155.44,49.06 154.87,49.62 154.87,56 154.34,56.53 153.97,56.53 153.75,56.74 153.75,57.95 153.28,58.42 153.28,59.5 146.96,65.83 146.96,66.61 145.85,67.72 145.85,68.55 144.92,69.48 144.92,72.47
  BOTTOM w0.076: UC1.AR26 140.68,85.47 140.32,85.11 v2(140.31,85.11)
  BOTTOM w0.102: v2(153.83,30.49) 154.2,30.5 154.65,30.05 JDIMM2.148
DDR_B_D42: length 65.4
  IN3 w0.076: 146.38,72.47 146.38,72.65 144.78,74.25 144.49,74.25 143.78,74.95 143.39,74.95 142.74,75.6 142.74,81.34 141.6,82.48 141.6,84.06 141.27,84.39 v2(141.27,85.14)
  IN3 w0.114: v2(157.13,33.54) 157.08,33.48 156.77,33.48 156.66,33.59 156.66,37.22 157.35,37.91 157.35,41.08 157.25,41.19 157.25,42.88 157.51,43.15 157.51,48.53 156.9,49.14 156.9,49.66 156.33,50.23 156.33,51.11 156.56,51.34 156.56,51.69 156.33,51.92 156.33,56.91 155.21,58.03 155.21,58.55 155.03,58.74 154.75,59.02 154.75,60.1 148.42,66.43 148.42,68.05 146.38,70.08 146.38,72.47
  BOTTOM w0.076: UC1.AR25 141.59,85.47 v2(141.27,85.14)
  BOTTOM w0.102: JDIMM2.159 157.95,33.23 157.81,33.1 157.38,33.1 157.13,33.35 v2(157.13,33.54)
DDR_B_D43: length 67
  IN3 w0.076: v2(141.27,85.79) 141.62,85.44 141.62,84.32 141.79,84.15 141.79,82.6 142.92,81.47 142.92,75.66 143.46,75.12 143.85,75.12 144.56,74.41 144.87,74.41 146.77,72.51 146.77,72.47
  IN3 w0.114: 146.77,72.47 146.77,70.25 148.81,68.21 148.81,66.59 155.07,60.33 155.13,60.26 155.13,59.19 155.3,59.02 155.6,58.71 155.6,58.19 156.72,57.07 156.72,53.27 156.85,53.13 157.91,53.13 158.04,53 158.04,52.73 157.91,52.6 156.85,52.6 156.72,52.46 156.72,52.08 156.95,51.85 157.59,51.85 157.82,51.63 157.9,51.63 158.04,51.48 158.04,51.31 157.87,51.13 156.9,51.13 156.72,50.95 156.72,50.68 156.87,50.52 157.89,50.52 157.99,50.42 157.99,50.07 157.84,49.91 157.45,49.91 157.29,49.75 157.29,49.3 157.9,48.69 157.9,42.99 157.63,42.72 157.63,41.35 157.78,41.21 157.78,37.79 157.05,37.06 157.05,35.15 v2(157.13,35.06)
  BOTTOM w0.076: UC1.AP25 141.31,85.79 v2(141.27,85.79)
  BOTTOM w0.102: v2(157.13,35.06) 157.35,35.28 JDIMM2.157
DDR_B_D44: length 69.4
  IN3 w0.076: 143.76,72.47 143.76,72.78 142.91,73.63 142.91,74.03 141.74,75.19 141.2,75.19 140.39,76.01 140.39,80.9 139.88,81.41 139.88,84.14 139.63,84.4 139.63,86.87 139.79,87.04 139.79,87.29 140.72,88.22 140.72,88.74 v2(141.1,89.12)
  IN3 w0.114: 143.76,72.47 143.76,69 144.63,68.12 144.63,66.86 145.57,65.92 145.57,64.68 146.48,63.77 147.36,63.77 152.12,59.01 152.12,56.6 152.82,55.9 152.82,55.74 153.19,55.36 153.19,54.76 153.54,54.42 153.54,49.31 153.93,48.91 153.93,42.74 153.82,42.63 153.82,38.34 153.62,38.15 153.62,36.45 153.24,36.06 153.24,35.57 153.01,35.34 153.01,32.84 v2(153.83,32.01)
  BOTTOM w0.076: v2(141.1,89.12) 140.7,88.72 UC1.AK26
  BOTTOM w0.102: v2(153.83,32.01) 153.42,31.6 153.42,30.3 154.05,29.67 JDIMM2.146
DDR_B_D45: length 68.4
  IN3 w0.076: 144.15,72.47 144.15,72.89 143.74,73.3 143.48,73.3 143.07,73.7 143.07,74.1 141.81,75.36 141.27,75.36 140.67,75.96 140.67,83.6 139.79,84.48 139.79,86.71 v2(140.22,87.14)
  IN3 w0.114: 144.15,72.47 144.15,69.16 145.02,68.28 145.02,67.02 145.96,66.08 145.96,64.84 146.64,64.16 147.52,64.16 151.24,60.44 152.51,59.18 152.51,56.77 153.21,56.06 153.21,55.9 153.58,55.53 153.58,54.92 153.93,54.58 153.93,49.47 154.32,49.07 154.32,42.58 154.21,42.47 154.21,42.28 154.34,42.14 154.86,42.14 155,42.01 155,41.74 154.86,41.6 154.34,41.6 154.21,41.47 154.21,38.18 154.01,37.98 154.01,36.29 153.63,35.9 153.63,35.41 153.39,35.18 153.39,33.5 153.5,33.4 153.7,33.4 v2(153.83,33.54)
  BOTTOM w0.076: UC1.AM26 140.5,87.42 v2(140.22,87.14)
  BOTTOM w0.102: v2(153.83,33.54) 154.12,33.25 154.59,33.25 154.95,33.61 JDIMM2.149
DDR_B_D46: length 69.3
  IN3 w0.076: v2(141.19,88.39) 141.8,87.79 141.8,86.02 142,85.82 142,84.54 142.47,84.07 142.47,83.26 143.94,81.8 143.94,75.61 144.59,74.96 145.09,74.96 147.55,72.5 147.55,72.47
  IN3 w0.114: 147.55,72.47 147.55,70.57 149.58,68.54 149.58,66.91 155.91,60.59 155.91,59.51 156.38,59.03 156.38,58.51 157.5,57.39 157.5,54.84 158.84,53.5 158.84,49.31 159.19,48.96 159.19,47.17 158.68,46.65 158.68,42.66 158.55,42.54 158.55,37.44 157.97,36.85 157.97,32 157.6,31.63 157.6,30.95 v2(157.13,30.49)
  BOTTOM w0.076: UC1.AK25 141.52,88.72 v2(141.19,88.39)
  BOTTOM w0.102: JDIMM2.160 158.25,29.69 157.45,30.49 v2(157.13,30.49)
DDR_B_D47: length 68.7
  IN3 w0.076: v2(141.25,87.77) 141.63,87.39 141.63,85.96 141.81,85.78 141.81,84.44 142.22,84.03 142.22,83.24 143.74,81.71 143.74,75.46 144.63,74.58 145.06,74.58 147.16,72.48 147.16,72.47
  IN3 w0.114: 147.16,72.47 147.16,70.41 149.19,68.37 149.19,66.75 155.52,60.42 155.52,59.35 155.58,59.29 155.99,58.87 155.99,58.35 157.11,57.23 157.11,54.68 158.45,53.34 158.45,49.15 158.8,48.8 158.8,47.33 158.29,46.82 158.29,42.82 158.02,42.56 158.02,41.51 158.17,41.37 158.17,37.6 157.56,37 157.56,32.14 157.43,32.01 v2(157.13,32.01)
  BOTTOM w0.076: UC1.AL25 141.55,88.07 v2(141.25,87.77)
  BOTTOM w0.102: JDIMM2.158 157.65,29.77 157.35,30.07 156.97,30.07 156.71,30.33 156.71,31.59 v2(157.13,32.01)
DDR_B_D48: length 68
  IN3 w0.076: 150.89,72.47 150.89,72.87 149.09,74.66 147.48,74.66 145.73,76.41 145.73,76.81 145.73,81 145.11,81.61 145.11,82.46 144.82,82.75 144.82,84.05 144.33,84.54 144.33,84.83 143.95,85.21 143.95,85.19 v2(143.95,85.19)
  IN3 w0.114: v2(162.75,32.02) 162.58,31.85 162.39,31.85 161.9,32.34 161.9,35.99 162.08,36.17 162.08,40.48 163.57,41.97 163.57,51.24 162.74,52.07 162.74,55.22 160.77,57.2 160.77,58.75 159.65,59.86 159.65,60.4 159.18,60.87 159.18,61.94 152.85,68.27 152.85,69.89 150.89,71.86 150.89,72.47
  BOTTOM w0.076: v2(143.95,85.19) 144.22,85.47 UC1.AR21
  BOTTOM w0.102: v2(162.75,32.02) 162.02,31.3 162.02,30.39 162.45,29.96 JDIMM2.174
DDR_B_D49: length 68.5
  IN3 w0.076: 149.36,72.47 149.11,72.72 149,72.72 148.23,73.49 147.49,73.49 145.36,75.62 144.87,75.62 144.6,75.89 144.6,82.24 143.31,83.52 143.31,84.32 142.99,84.64 v2(142.99,85.12)
  IN3 w0.114: 149.36,72.47 149.36,71.32 150.48,70.19 151.39,69.29 151.39,67.66 157.65,61.41 157.72,61.34 157.72,60.25 158.19,59.77 158.19,59.26 159.31,58.14 159.31,55.64 159.72,55.22 160.59,55.22 161.06,54.75 161.06,53.83 161.28,53.62 161.28,51.46 161.12,51.3 161.12,51.16 161.21,51.07 161.68,51.07 162.04,50.71 162.11,50.64 162.11,50.12 161.88,49.89 161.88,49.23 161.71,49.06 161.71,47.38 161.52,47.18 161.52,46.84 162.08,46.28 162.08,45.49 161.04,44.45 161.04,42.47 160.36,41.79 160.36,36.69 159.92,36.25 159.92,33.65 159.75,33.48 159.56,33.48 v2(159.5,33.55)
  BOTTOM w0.076: v2(142.99,85.12) 143.34,85.47 UC1.AR22
  BOTTOM w0.102: JDIMM2.165 159.75,35.87 160.2,35.42 160.2,33.38 160.05,33.23 159.64,33.23 159.5,33.37 v2(159.5,33.55)
DDR_B_D50: length 71.1
  IN3 w0.076: 151.66,72.47 151.66,73.01 149.67,75 147.61,75 146.06,76.55 146.06,81.98 145.15,82.89 145.15,84.19 144.66,84.68 144.66,85.31 144.38,85.59 144.38,87.36 v2(144,87.74)
  IN3 w0.114: 151.66,72.47 151.66,72.18 153.63,70.21 153.63,68.59 159.96,62.26 159.96,61.19 160.46,60.7 160.46,60.17 161.54,59.09 161.54,57.52 163.52,55.55 163.52,54.47 163.66,54.33 164.26,54.33 164.39,54.2 164.39,53.93 164.26,53.8 163.66,53.8 163.52,53.66 163.52,53.39 163.66,53.26 164.26,53.26 164.39,53.12 164.39,52.85 164.26,52.72 163.66,52.72 163.52,52.58 163.52,52.39 163.73,52.17 164.35,51.56 164.35,41.65 163.61,40.91 163.61,40.72 163.97,40.36 163.97,40.17 163.78,39.98 163.59,39.98 163.23,40.34 163.04,40.34 162.86,40.16 162.86,39.67 162.99,39.53 163.39,39.53 163.5,39.42 163.5,39.13 163.37,39 162.99,39 162.86,38.86 162.86,38.63 163.51,37.98 163.51,36.33 162.75,35.57 v2(162.75,35.07)
  BOTTOM w0.076: v2(144,87.74) 144.32,88.07 UC1.AL21
  BOTTOM w0.102: JDIMM2.175 162.75,35.07 v2(162.75,35.07)
DDR_B_D51: length 70.7
  IN3 w0.076: v2(143.04,87.09) 142.45,86.5 142.45,84.69 142.92,84.22 142.92,83.4 144.27,82.06 144.27,75.75 144.73,75.29 145.23,75.29 147.35,73.16 148.09,73.16 148.58,72.67 148.58,72.47
  IN3 w0.114: 148.58,72.47 148.58,71 150.61,68.96 150.61,67.34 156.94,61.01 156.94,59.93 157.41,59.45 157.41,58.94 158.53,57.82 158.53,55.27 160.51,53.29 160.51,51.79 159.87,51.15 159.87,49.74 160.22,49.39 160.22,49.08 160.94,48.37 160.94,47.7 160.22,46.98 160.22,46.74 159.71,46.23 159.71,44.13 160.26,43.58 160.26,42.79 159.58,42.11 159.58,37.01 159.03,36.46 159.03,31.96 159.16,31.83 159.3,31.83 v2(159.5,32.02)
  BOTTOM w0.076: UC1.AM22 143.37,87.42 v2(143.04,87.09)
  BOTTOM w0.102: v2(159.5,32.02) 159.07,32.02 158.7,31.66 158.7,30.66 159.45,29.92 JDIMM2.164
DDR_B_D52: length 69.8
  IN3 w0.076: v2(143.01,86.43) 142.62,86.04 142.62,84.76 143.09,84.3 143.09,83.51 144.43,82.17 144.43,75.82 144.8,75.45 145.29,75.45 147.42,73.32 148.16,73.32 148.97,72.52
  IN3 w0.114: v2(159.5,35.07) 159.44,35.13 159.44,35.51 159.53,35.61 159.53,36.03 159.44,36.12 159.44,36.32 159.97,36.85 159.97,41.95 160.65,42.63 160.65,43.74 160.1,44.3 160.1,44.57 160.23,44.7 160.68,44.7 160.81,44.84 160.81,45.11 160.68,45.24 160.23,45.24 160.1,45.38 160.1,46.07 160.61,46.58 160.61,46.82 161.33,47.54 161.33,48.53 160.61,49.25 160.61,49.55 160.33,49.82 160.33,50.01 160.47,50.14 161.52,50.14 161.65,50.27 161.65,50.54 161.52,50.68 160.39,50.68 160.26,50.81 160.26,50.99 160.89,51.63 160.89,53.46 160.51,53.84 160.51,54.03 160.68,54.2 160.68,54.58 160.43,54.83 160.05,54.83 159.91,54.69 159.66,54.69 158.92,55.43 158.92,57.98 157.8,59.1 157.8,59.61 157.33,60.09 157.33,61.17 151,67.5 151,69.12 148.97,71.16 148.97,72.52
  BOTTOM w0.076: v2(143.01,86.43) 143.34,86.77 UC1.AN22
  BOTTOM w0.102: JDIMM2.163 159.15,36.19 158.88,35.92 158.88,35.08 159.21,34.75 159.36,34.75 159.5,34.88 v2(159.5,35.07)
DDR_B_D53: length 68.9
  IN3 w0.076: 151.27,72.47 151.27,73.04 149.48,74.83 147.55,74.83 145.89,76.48 145.89,81.91 144.99,82.82 144.99,84.12 144.49,84.61 144.49,85.15 144.01,85.64 v2(144.01,85.81)
  IN3 w0.114: v2(162.75,33.55) 162.47,33.55 162.31,33.71 162.31,35.85 162.47,36.01 162.47,36.22 162.6,36.36 162.96,36.36 163.1,36.49 163.1,36.76 162.96,36.9 162.6,36.9 162.47,37.03 162.47,37.3 162.6,37.44 162.96,37.44 163.1,37.57 163.1,37.84 162.96,37.97 162.6,37.97 162.47,38.11 162.47,40.32 163.96,41.81 163.96,51.4 163.46,51.9 163.13,52.23 163.13,55.38 161.15,57.36 161.15,58.91 160.04,60.02 160.04,60.56 159.57,61.03 159.57,62.1 153.24,68.43 153.24,70.05 151.27,72.02 151.27,72.47
  BOTTOM w0.076: UC1.AP21 144.32,86.12 v2(144.01,85.81)
  BOTTOM w0.102: JDIMM2.177 163.35,34.15 v2(162.75,33.55)
DDR_B_D54: length 71.4
  IN3 w0.076: v2(144.02,88.39) 144.4,88.01 144.4,87.66 144.56,87.51 144.56,85.64 144.93,85.27 144.93,84.65 145.32,84.25 145.32,82.95 146.22,82.05 146.22,76.62 147.68,75.16 149.99,75.16 152.05,73.1 152.05,72.54
  IN3 w0.114: v2(162.75,30.5) 163.28,31.03 163.28,35.55 163.9,36.17 163.9,39.14 164.36,39.61 164.36,41.12 164.79,41.54 164.79,51.67 164.74,51.72 164.44,52.02 164.44,52.35 164.78,52.69 164.78,54.36 164.42,54.72 164.06,54.72 163.91,54.88 163.91,55.71 163.7,55.92 161.93,57.68 161.93,59.25 160.84,60.34 160.84,60.86 160.35,61.36 160.35,62.42 154.02,68.75 154.02,70.37 152.05,72.34 152.05,72.54
  BOTTOM w0.076: v2(144.02,88.39) 144.35,88.72 UC1.AK21
  BOTTOM w0.102: JDIMM2.176 163.05,30.2 v2(162.75,30.5)
DDR_B_D55: length 71.7
  IN3 w0.076: v2(143.04,88.39) 143.04,88.25 142.69,87.89 142.69,86.97 142.29,86.57 142.29,84.55 142.68,84.16 142.68,83.39 144.1,81.97 144.1,75.68 144.66,75.12 145.16,75.12 147.29,72.99 148,72.99 148.19,72.8 148.19,72.47
  IN3 w0.114: v2(159.5,30.5) 159.18,30.81 158.55,30.81 158.32,31.04 158.32,31.45 158.63,31.75 158.63,36.61 159.2,37.17 159.2,42.27 159.87,42.95 159.87,43.42 159.32,43.97 159.32,46.39 159.83,46.9 159.83,47.14 160.55,47.86 160.55,48.21 159.83,48.92 159.83,49.22 159.48,49.58 159.48,51.31 160.12,51.95 160.12,53.13 158.14,55.11 158.14,57.66 157.03,58.78 157.03,59.29 156.55,59.77 156.55,60.85 150.23,67.18 150.23,68.8 148.19,70.83 148.19,72.47
  BOTTOM w0.076: v2(143.04,88.39) 143.37,88.72 UC1.AK22
  BOTTOM w0.102: v2(159.5,30.5) 160.05,29.95 JDIMM2.166
DDR_B_D56: length 71
  IN3 w0.076: v2(144.95,87.1) 144.97,87.1 145.32,86.74 145.32,84.73 145.67,84.38 145.67,83.07 146.58,82.16 146.58,76.73 147.81,75.5 150.35,75.5 153.31,72.54
  IN3 w0.114: 153.31,72.54 154.59,71.26 155.1,70.75 155.1,69.12 161.38,62.85 161.38,61.78 161.88,61.28 161.88,60.76 162.96,59.68 162.96,58.11 164.42,56.65 164.94,56.13 164.94,55.71 165.82,54.83 165.82,41.11 165.39,40.69 165.39,39.18 164.93,38.71 164.93,35.74 164.31,35.12 164.31,32.04 164.47,31.88 164.78,31.88 v2(165.03,32.14)
  BOTTOM w0.076: v2(144.95,87.1) 145.28,86.77 UC1.AN20
  BOTTOM w0.102: JDIMM2.180 164.25,31.58 164.8,32.14 v2(165.03,32.14)
DDR_B_D57: length 69.9
  IN3 w0.076: 152.83,72.47 152.63,72.67 152.63,72.75 150.04,75.34 147.74,75.34 146.41,76.67 146.41,82.09 145.5,83 145.5,84.3 145.12,84.69 145.12,85.35 144.92,85.55 v2(144.92,85.82)
  IN3 w0.114: v2(165.03,30.61) 164.91,30.74 164.04,30.74 163.92,30.86 163.92,31.1 164.22,31.4 164.22,31.58 163.92,31.88 163.92,35.28 164.54,35.9 164.54,38.87 165.01,39.34 165.01,40.85 165.43,41.27 165.43,54.67 164.55,55.55 164.55,55.97 164.15,56.38 162.57,57.95 162.57,59.51 161.49,60.6 161.49,61.12 160.99,61.62 160.99,62.69 154.66,69.02 154.66,70.64 152.83,72.47
  BOTTOM w0.076: UC1.AR20 145.26,85.47 v2(144.92,85.82)
  BOTTOM w0.102: v2(165.03,30.61) 164.94,30.71 164.72,30.71 164.49,30.48 164.49,30.15 164.85,29.8 JDIMM2.182
DDR_B_D58: length 72
  IN3 w0.076: v2(145.83,88.95) 146.16,88.62 146.16,88.32 146.95,87.53 146.95,83.43 147.49,82.88 147.56,82.88 147.71,82.73 148.13,82.73 149.74,81.12 149.74,79.58 155.73,73.58 156.53,73.58 157.64,72.47
  IN3 w0.114: 157.64,72.47 158.12,72 158.12,70.4 164.39,64.13 164.39,63.76 164.64,63.51 165.18,63.51 165.49,63.2 165.49,62.71 165.66,62.54 166.14,62.54 166.42,62.27 166.42,61.65 165.99,61.22 165.99,60.5 166.42,60.07 166.42,59.03 168.86,56.59 168.86,40.01 169.32,39.55 169.32,37.63 168.94,37.25 168.94,36.47 168.76,36.29 168.76,35.59 168.94,35.41 168.94,34.27 168.49,33.82 v2(168.49,33.66)
  BOTTOM w0.076: v2(145.83,88.95) 146.06,88.72 UC1.AK18
  BOTTOM w0.102: v2(168.49,33.66) 167.7,33.66 167.55,33.81 JDIMM2.191
DDR_B_D59: length 71.6
  IN3 w0.076: 157.09,72.47 156.16,73.41 155.45,73.41 149.53,79.33 149.53,81.09 148.07,82.55 147.65,82.55 147.49,82.72 147.42,82.72 146.78,83.36 146.78,87.29 146,88.07 146,88.17 v2(145.8,88.37)
  IN3 w0.114: v2(168.49,35.18) 168.37,35.3 168.37,36.45 168.55,36.63 168.55,37.12 168.37,37.3 168.37,37.51 168.51,37.64 168.78,37.64 168.91,37.77 168.91,38.04 168.78,38.18 168.51,38.18 168.37,38.31 168.37,39.64 168.47,39.74 168.47,55.89 168.33,56.03 168.33,56.22 168.4,56.29 168.4,56.48 168.2,56.67 168.01,56.67 167.95,56.6 167.76,56.6 167.57,56.8 167.57,57.22 167,57.79 166.7,58.09 165.59,59.2 165.59,59.35 165.72,59.49 165.88,59.49 166.02,59.62 166.02,59.89 165.88,60.02 165.72,60.02 165.59,60.16 165.59,60.76 165.38,60.97 165.38,61.16 165.99,61.77 165.99,61.96 165.8,62.15 165.61,62.15 165,61.54 164.81,61.54 164.52,61.83 164.52,62.24 165.02,62.74 165.02,62.93 164.83,63.12 164.64,63.12 164.29,62.77 164.1,62.77 164,62.87 164,63.96 157.73,70.24 157.73,71.83 157.09,72.47
  BOTTOM w0.076: v2(145.8,88.37) 145.99,88.37 UC1.AL18
  BOTTOM w0.102: JDIMM2.193 168.15,36.19 167.91,35.95 167.91,35.3 168.08,35.13 168.44,35.13 v2(168.49,35.18)
DDR_B_D60: length 73.2
  IN3 w0.076: 157.92,72.75 156.77,73.89 155.66,73.89 149.92,79.64 149.92,81.18 148.18,82.91 147.83,82.91 147.11,83.63 147.11,87.6 146.36,88.35 146.36,88.92 145.98,89.31 145.39,89.31 v2(145.27,89.18)
  IN3 w0.114: v2(168.49,32.14) 168.97,32.61 168.97,33.74 169.33,34.11 169.33,36.71 169.71,37.09 169.71,39.8 169.24,40.26 169.24,56.87 166.81,59.31 166.81,62.44 158.53,70.72 158.53,72.14 157.92,72.75
  BOTTOM w0.076: UC1.AK20 145.27,88.79 v2(145.27,89.18)
  BOTTOM w0.102: JDIMM2.192 167.85,31.5 v2(168.49,32.14)
DDR_B_D61: length 71.7
  IN3 w0.076: 156.5,72.52 155.81,73.21 155.18,73.21 149.36,79.03 149.36,81.03 148.02,82.37 147.6,82.37 147.42,82.55 147.35,82.55 146.61,83.29 146.61,86.94 v2(145.77,87.78)
  IN3 w0.114: 156.5,72.52 157.34,71.67 157.34,70.08 163.61,63.8 163.61,62.71 164.11,62.21 164.11,61.69 165.2,60.6 165.2,59.04 166.43,57.81 167.18,57.06 167.18,56.63 168.08,55.73 168.08,39.9 167.98,39.81 167.98,32.15 167.06,31.23 167.06,30.86 167.21,30.71 167.54,30.71 167.85,31.02 168.09,31.02 v2(168.49,30.61)
  BOTTOM w0.076: UC1.AM20 145.4,87.42 v2(145.77,87.78)
  BOTTOM w0.102: v2(168.49,30.61) 168.33,30.61 168.21,30.48 168.21,30 168.45,29.75 JDIMM2.194
DDR_B_D62: length 68.3
  IN3 w0.076: v2(145.84,85.08) 146,84.93 146,83.21 147.15,82.06 147.22,82.06 148.34,80.93 148.34,78.61 154.43,72.52
  IN3 w0.114: v2(165.03,33.66) 165.03,33.52 165.46,33.1 165.46,32.67 165.56,32.57 165.71,32.57 166.07,32.92 166.07,33.39 166.41,33.73 166.41,38.17 166.17,38.4 166.17,38.76 166.41,39 166.41,40.45 166.61,40.65 166.61,55.14 165.72,56.03 165.72,56.46 165.25,56.92 163.74,58.43 163.74,60 162.65,61.09 162.65,61.61 162.15,62.1 162.15,63.17 155.88,69.45 155.88,71.07 155.14,71.8 154.43,72.52
  BOTTOM w0.076: v2(145.84,85.08) 146.23,85.47 UC1.AR18
  BOTTOM w0.102: v2(165.03,33.66) 165.16,33.53 165.59,33.53 165.84,33.78 165.84,35.37 165.15,36.06 JDIMM2.183
DDR_B_D63: length 69.4
  IN3 w0.076: 153.88,72.52 149.24,77.16 148.19,77.16 147.48,77.87 147.48,81.55 147.15,81.89 147.08,81.89 145.83,83.14 145.83,84.45 145.49,84.8 145.49,85.88 145.6,85.99 145.8,85.99 145.85,85.94 v2(145.85,85.78)
  IN3 w0.114: 153.88,72.52 154.87,71.53 155.49,70.91 155.49,69.28 161.77,63.01 161.77,61.94 162.26,61.44 162.26,60.92 163.35,59.84 163.35,58.27 164.7,56.92 165.33,56.29 165.33,55.87 166.22,54.98 166.22,40.81 166.02,40.61 166.02,39.16 165.78,38.92 165.78,38.24 166.02,38 166.02,37.72 165.88,37.59 165.47,37.59 165.33,37.45 165.33,37.18 165.47,37.05 165.88,37.05 166.02,36.92 166.02,36.65 165.88,36.51 165.47,36.51 165.33,36.38 165.33,36.11 165.47,35.97 165.88,35.97 166.02,35.84 166.02,33.89 165.92,33.79 165.61,33.79 165.46,33.94 165.46,34.76 v2(165.03,35.18)
  BOTTOM w0.076: UC1.AP18 146.19,86.12 145.85,85.78 v2(145.85,85.78)
  BOTTOM w0.102: v2(165.03,35.18) 164.85,35 164.7,35 164.55,35.15 JDIMM2.181
DDR_B_DQS0: length 70.6
  IN3 w0.076: v2(120.28,86.44) 120.28,86.66 120.16,86.78 119.91,86.78 119.44,86.31 119.44,85.45 118.98,84.99 118.98,84.28 118.57,83.87 118.57,81.82 113.87,77.12 113.87,77.09 111.88,75.1 111.88,74.64 111.83,74.58 111.68,74.43 111.68,74.41 111.66,74.4
  IN3 w0.114: v2(116.43,33.93) 116.43,33.9 116.23,33.7 116.11,33.7 116.01,33.81 116.01,36.27 113.54,38.74 113.54,39.35 112,40.89 111.43,40.89 110.09,42.24 108.87,42.24 108.54,42.57 108.54,48.9 107.09,50.35 107.09,62 106.33,62.77 106.33,69.24 110.57,73.48 110.75,73.48 111.66,74.4
  BOTTOM w0.076: v2(120.28,86.44) 120.3,86.46 120.79,86.46 120.88,86.55 120.88,86.69 120.8,86.77 UC1.AN58
  BOTTOM w0.102: JDIMM2.29 116.55,35.95 115.71,35.12 115.71,33.87 116.02,33.56 116.3,33.56 116.43,33.69 v2(116.43,33.93)
DDR_B_DQS1: length 68.1
  IN3 w0.076: v2(122.19,86.44) 122.19,86.52 122.33,86.67 122.43,86.67 122.56,86.54 122.56,84.99 122.16,84.59 122.16,80.82 122.36,80.62 122.36,80.34 115.78,73.76 115.78,73.72 115.76,73.7
  IN3 w0.114: 115.76,73.7 115.7,73.65 115.7,72.37 111.62,68.28 111.62,68.04 111.62,53.24 116.45,48.41 116.45,43.07 118.55,40.97 118.55,40.59 120.59,38.55 120.59,38.05 121.26,37.37 121.26,33.61 121.48,33.39 121.69,33.39 121.89,33.18 v2(121.89,33.17)
  BOTTOM w0.076: UC1.AN55 122.51,86.77 v2(122.19,86.44)
  BOTTOM w0.102: JDIMM2.47 121.95,35.88 122.06,35.77 122.06,35.51 122.55,35.03 122.55,33.7 122.31,33.45 122.08,33.45 121.89,33.27 v2(121.89,33.17)
DDR_B_DQS2: length 90.5
  IN3 w0.076: v2(130.63,87.8) 130.27,88.16 130.27,88.75 128.63,90.39 122.61,90.39 121.87,89.64 121.26,89.64 121.11,89.8 119.11,89.8 112.35,83.04 112.35,81.81 108.95,78.41 108.89,78.41 108.84,78.36 108.75,78.27 108.65,78.17 108.63,78.17 108.62,78.16
  IN3 w0.114: 108.62,78.16 100.67,70.21 100.67,50.95 101.69,49.93 101.69,42.21 102.44,41.46 102.44,39.63 104.78,37.29 106.28,37.29 107.36,36.2 109.35,36.2 110.07,35.49 110.07,34.52 111.34,33.25 111.34,32.7 111.07,32.43 110.89,32.43 v2(110.66,32.66)
  BOTTOM w0.076: UC1.AL42 130.82,88.07 130.63,87.87 v2(130.63,87.8)
  BOTTOM w0.102: v2(110.66,32.66) 110.9,32.43 111.13,32.43 111.51,32.05 111.51,30.17 111.45,30.11 JDIMM2.12
DDR_B_DQS3: length 69.4
  IN3 w0.076: v2(125.94,87.77) 126.27,87.44 126.27,86.89 125.44,86.07 125.44,85.53 124.71,84.79 124.71,83.53 124.53,83.35 124.53,81.16 124.99,80.71 124.99,78.88 120.23,74.13 120.23,73.31
  IN3 w0.114: v2(127.74,31.64) 127.72,31.64 127.49,31.88 127.23,31.88 127.01,32.11 127.01,36.58 126.5,37.08 126.5,38.88 126.28,39.11 126.28,39.39 125.71,39.95 125.71,40.26 122.95,43.03 122.95,48.92 121.96,49.91 121.96,50.24 118.4,53.79 118.4,63.9 117.4,64.9 117.4,65.74 119.34,67.68 119.34,69.49 119.34,69.49 119.34,69.73 120.23,70.62 120.23,73.31
  BOTTOM w0.076: UC1.AL49 126.24,88.07 v2(125.94,87.77)
  BOTTOM w0.102: v2(127.74,31.64) 127.47,31.92 126.99,31.92 126.86,31.79 126.86,30.16 127.05,29.98 JDIMM2.64
DDR_B_DQS4: length 67.3
  IN3 w0.076: 141.12,72.47 141.12,72.8 139.96,73.97 139.49,73.97 138.63,74.83 138.63,81.96 138.05,82.54 138.05,85.35 137.87,85.53 137.87,86.7 138.28,87.12 138.5,87.12 138.92,87.54 139.1,87.54 v2(139.29,87.73)
  IN3 w0.114: 141.12,72.47 141.12,67.9 142,67.03 142,65.76 142.94,64.82 142.94,63.59 145.39,61.14 146.27,61.14 149.48,57.92 149.48,55.51 149.91,55.09 150.18,54.81 150.18,54.65 150.56,54.27 150.56,49.04 150.47,48.95 150.47,41.61 150.6,41.48 150.6,36.98 149.66,36.04 149.66,33.66 149.94,33.38 150.06,33.38 v2(150.28,33.17)
  BOTTOM w0.076: UC1.AM28 139.63,87.42 139.32,87.73 v2(139.29,87.73)
  BOTTOM w0.102: v2(150.28,33.17) 150.49,33.38 150.73,33.38 150.99,33.64 150.99,35.25 151.35,35.61 JDIMM2.137
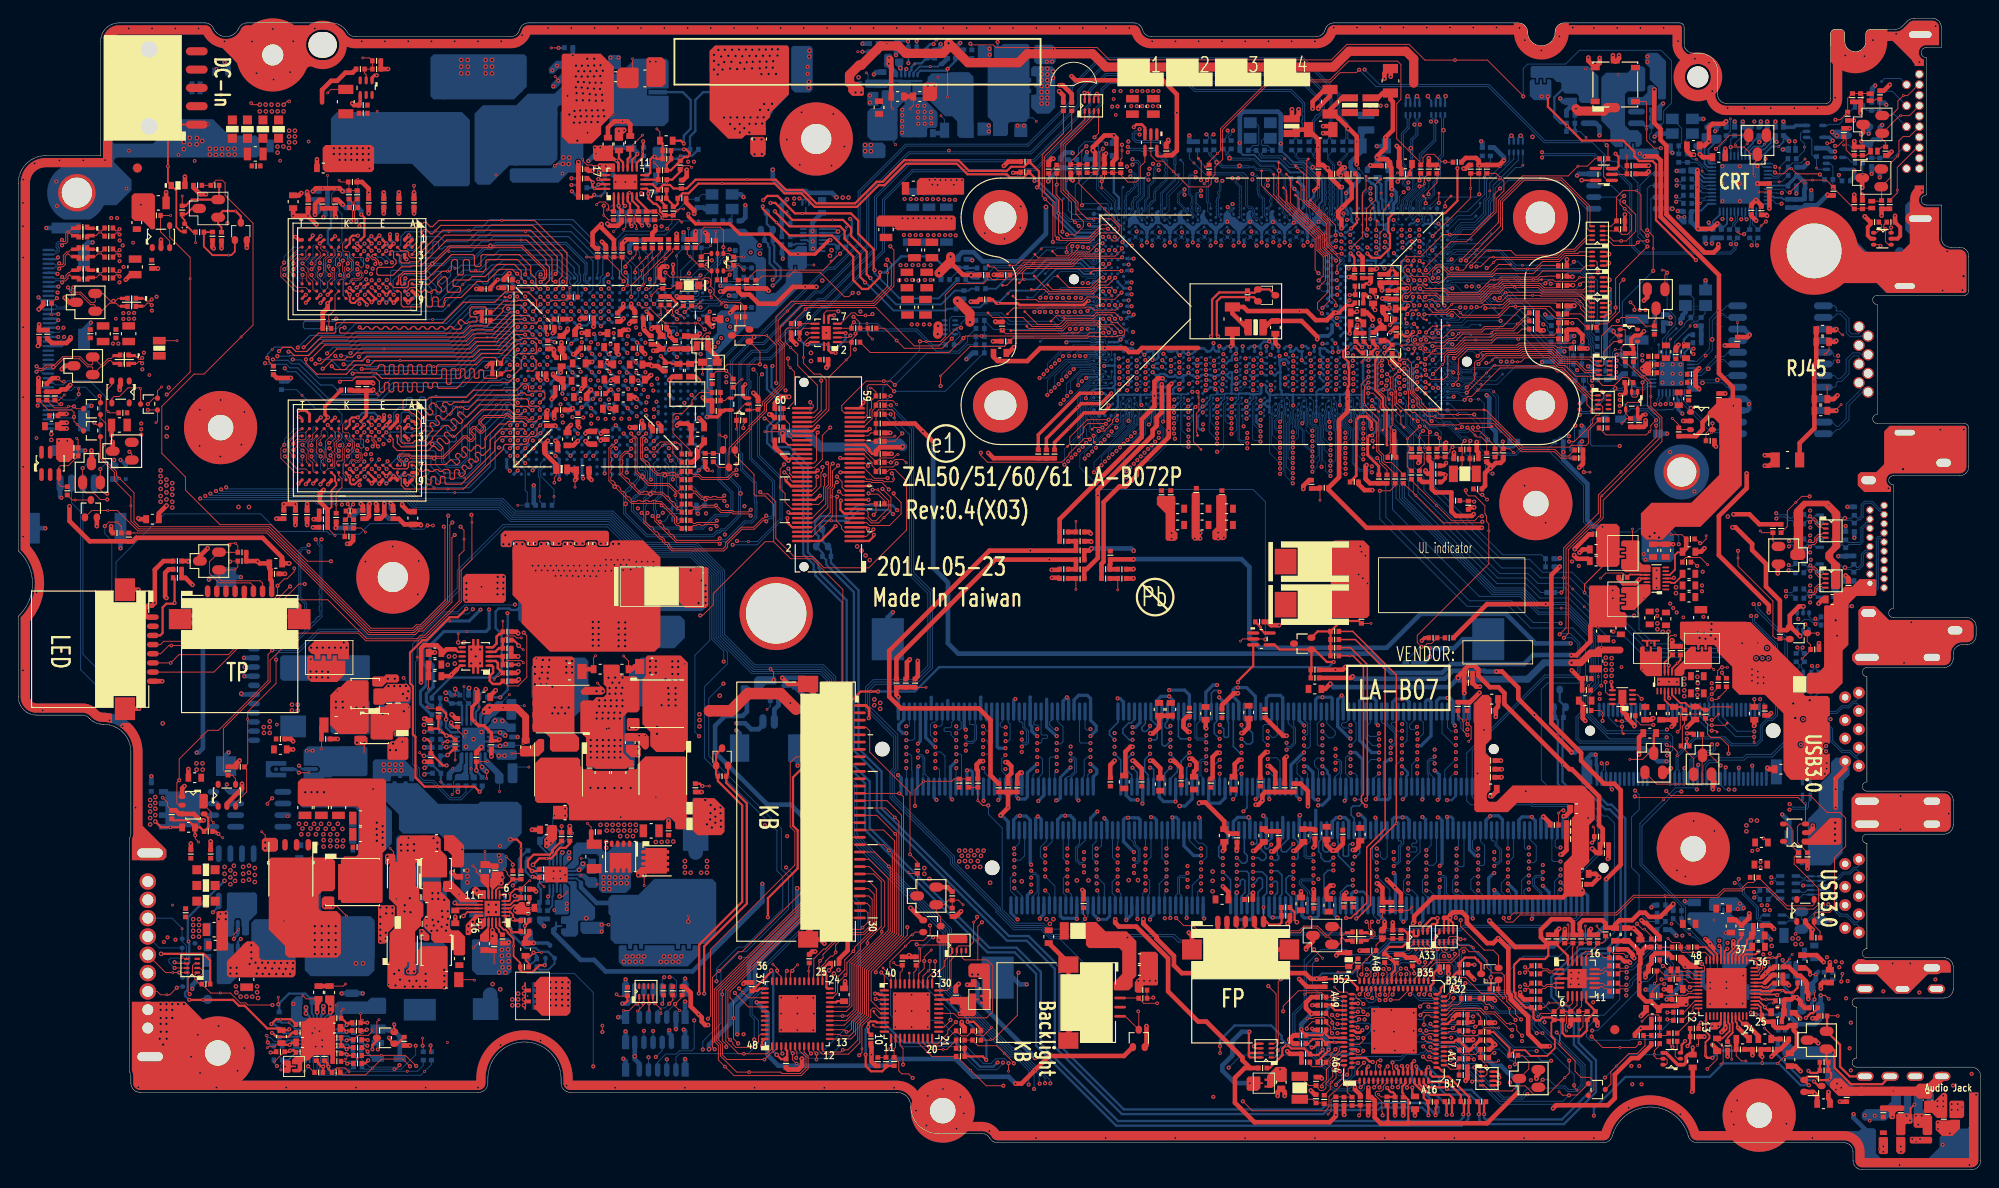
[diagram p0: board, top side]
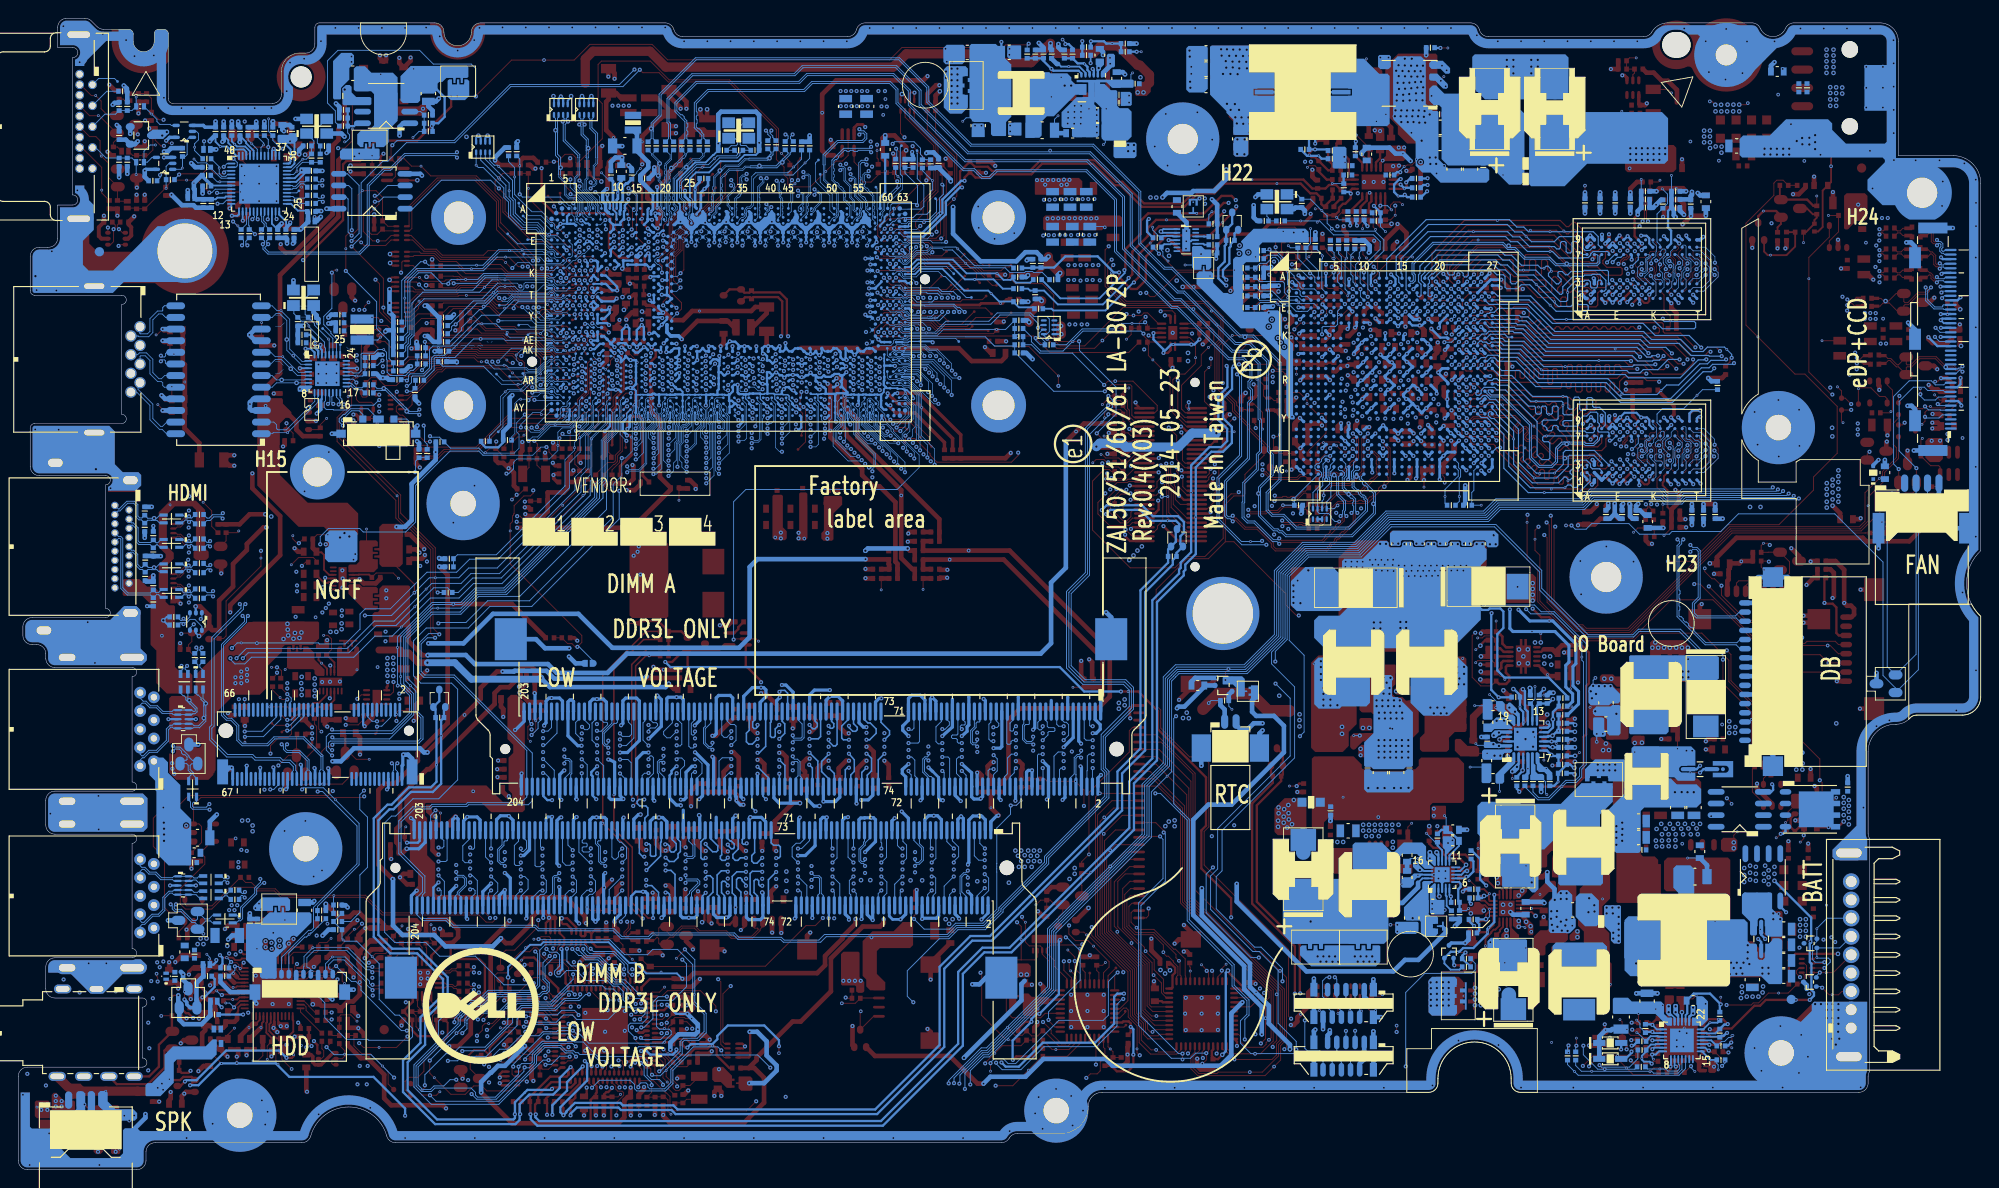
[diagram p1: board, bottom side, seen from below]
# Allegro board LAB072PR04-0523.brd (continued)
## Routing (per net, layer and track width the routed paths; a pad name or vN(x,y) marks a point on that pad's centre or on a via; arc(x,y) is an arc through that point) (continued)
DDR_B_DQS5: length 67.6
  IN3 w0.076: 145.56,72.47 145.56,72.91 144.6,73.87 144.4,73.87 143.66,74.61 143.26,74.61 141.85,76.02 141.85,80.87 141.22,81.5 141.22,83.88 140.71,84.39 140.71,86.66 140.88,86.83 141.09,86.83 141.25,86.99 v2(141.25,87.09)
  IN3 w0.114: v2(155.3,32.39) 155.49,32.21 155.68,32.21 155.78,32.31 155.78,37.52 156.52,38.25 156.52,40.74 156.42,40.85 156.42,48.11 156.07,48.46 156.07,49.32 155.5,49.89 155.5,56.57 154.39,57.68 154.39,58.21 153.92,58.68 153.92,59.76 147.59,66.09 147.59,67.71 145.56,69.74 145.56,72.47
  BOTTOM w0.076: UC1.AM25 141.57,87.42 v2(141.25,87.09)
  BOTTOM w0.102: v2(155.3,32.39) 155.51,32.2 155.57,32.13 155.83,32.13 156.04,31.93 156.04,30.2 156.45,29.79 JDIMM2.154
DDR_B_DQS6: length 69.6
  IN3 w0.076: v2(143.99,87.12) 143.82,86.96 143.65,86.96 143.43,86.74 143.43,84.6 143.51,84.52 143.51,83.6 144.78,82.32 144.78,81.46 145.4,80.84 145.4,76.94 145.4,75.82 147.56,73.66 148.3,73.66 148.57,73.39 148.88,73.08 149.69,73.08 150.02,72.75 150.02,72.47
  IN3 w0.114: v2(161.25,33.17) 161.03,33.39 160.86,33.39 160.62,33.63 160.62,35.87 161.25,36.51 161.25,40.82 162.74,42.32 162.74,50.9 161.92,51.72 161.92,54.88 159.94,56.86 159.94,58.41 158.82,59.52 158.82,60.06 158.64,60.24 158.35,60.53 158.35,61.6 152.02,67.93 152.02,69.55 150.02,71.55 150.02,72.47
  BOTTOM w0.076: v2(143.99,87.12) 144.28,87.42 UC1.AM21
  BOTTOM w0.102: v2(161.25,33.17) 161.45,33.37 161.71,33.37 162.06,33.71 162.06,34.97 161.55,35.47 JDIMM2.171
DDR_B_DQS7: length 70.6
  IN3 w0.076: v2(145.87,87.02) 145.87,86.9 146.02,86.76 146.25,86.76 146.45,86.56 146.45,83.23 147.29,82.39 147.35,82.39 147.82,81.91 148.24,81.91 148.68,81.47 148.68,78.78 154.42,73.05 155.07,73.05 155.37,72.75 155.65,72.47
  IN3 w0.114: v2(166.56,31.75) 166.77,31.96 166.89,31.96 167.24,32.31 167.24,40.11 167.43,40.3 167.43,55.48 166.55,56.37 166.55,56.8 165.84,57.51 164.57,58.78 164.57,60.34 163.48,61.43 163.48,61.95 162.98,62.45 162.98,63.54 162.18,64.35 156.71,69.81 156.71,71.41 155.65,72.47
  BOTTOM w0.076: v2(145.87,87.02) 145.87,87.22 146.07,87.42 UC1.AM18
  BOTTOM w0.102: JDIMM2.188 166.65,29.89 166.65,29.89 166.44,30.11 166.44,30.31 165.64,31.11 165.64,31.75 165.84,31.96 166.48,31.96 166.56,31.88 v2(166.56,31.75)
DDR_B_DQS#0: length 70.8
  IN3 w0.076: 111.52,74.54 111.54,74.55 111.56,74.55 111.63,74.63 111.71,74.7 111.72,74.71 111.72,75.17 113.71,77.15 113.71,77.19 118.41,81.88 118.41,83.94 118.81,84.35 118.81,85.06 119.27,85.52 119.27,86.38 119.84,86.95 120.15,86.95 v2(120.32,87.11)
  IN3 w0.114: v2(116.43,33.17) 116.43,33.41 116.34,33.5 116.03,33.5 115.81,33.73 115.81,36.19 113.35,38.66 113.35,39.27 111.91,40.7 111.35,40.7 110.01,42.04 108.79,42.04 108.34,42.49 108.34,48.82 106.9,50.26 106.9,61.92 106.13,62.68 106.13,69.32 110.49,73.68 110.67,73.68 111.52,74.54
  BOTTOM w0.076: UC1.AM58 120.61,87.42 120.32,87.13 v2(120.32,87.11)
  BOTTOM w0.102: v2(116.43,33.17) 116.43,33.26 116.32,33.37 115.94,33.37 115.52,33.79 115.52,35.19 115.95,35.62 JDIMM2.27
DDR_B_DQS#1: length 68.3
  IN3 w0.076: 115.92,73.58 115.94,73.6 115.94,73.69 122.52,80.27 122.52,80.69 122.33,80.89 122.33,84.52 122.72,84.92 122.72,86.61 122.5,86.83 122.28,86.83 122.19,86.93 v2(122.19,87.09)
  IN3 w0.114: 115.92,73.58 115.91,73.56 115.91,72.3 111.81,68.2 111.81,68.12 111.82,68.12 111.82,67.96 111.82,53.32 116.64,48.49 116.64,43.15 118.74,41.05 118.74,40.67 120.78,38.63 120.78,38.13 121.46,37.45 121.46,33.69 121.57,33.58 121.85,33.58 121.95,33.68 121.95,33.87 v2(121.89,33.93)
  BOTTOM w0.076: UC1.AM55 122.51,87.42 v2(122.19,87.09)
  BOTTOM w0.102: JDIMM2.45 121.35,36.21 121.87,35.69 121.87,35.44 122.36,34.95 122.36,33.78 122.23,33.65 121.96,33.65 121.85,33.76 121.85,33.89 v2(121.89,33.93)
DDR_B_DQS#2: length 90.7
  IN3 w0.076: v2(129.75,87.91) 129.9,87.76 130.03,87.76 130.1,87.84 130.1,88.68 128.56,90.22 122.68,90.22 121.94,89.48 121.19,89.48 121.04,89.63 119.17,89.63 112.51,82.97 112.51,81.74 109.01,78.24 108.96,78.24 108.77,78.05 108.77,78.03 108.75,78.02
  IN3 w0.114: 108.75,78.02 100.87,70.13 100.87,51.03 101.88,50.01 101.88,42.29 102.64,41.54 102.64,39.71 104.86,37.49 106.36,37.49 107.44,36.4 109.43,36.4 110.26,35.57 110.26,34.6 111.53,33.33 111.53,32.62 111.15,32.23 110.7,32.23 110.6,32.13 110.6,31.96 v2(110.66,31.9)
  BOTTOM w0.076: UC1.AL43 130.17,88.14 129.98,88.14 v2(129.75,87.91)
  BOTTOM w0.102: v2(110.66,31.9) 110.66,32.1 110.8,32.23 111.05,32.23 111.32,31.97 111.32,30.34 110.85,29.87 JDIMM2.10
DDR_B_DQS#3: length 69.5
  IN3 w0.076: v2(126.86,87.62) 126.66,87.62 126.44,87.39 126.44,86.83 125.61,86 125.61,85.46 124.87,84.72 124.87,83.46 124.69,83.28 124.69,81.23 125.15,80.77 125.15,78.81 120.43,74.09 120.43,73.31
  IN3 w0.114: v2(127.74,32.4) 127.44,32.1 127.29,32.1 127.2,32.19 127.2,36.66 126.7,37.16 126.7,38.96 126.47,39.19 126.47,39.47 125.91,40.03 125.91,40.34 123.14,43.11 123.14,49 122.15,49.99 122.15,50.32 118.6,53.88 118.6,63.98 117.6,64.98 117.6,65.66 119.54,67.59 119.54,69.57 119.54,69.57 119.54,69.65 120.43,70.54 120.43,73.31
  BOTTOM w0.076: UC1.AL48 127.28,88.05 v2(126.86,87.62)
  BOTTOM w0.102: v2(127.74,32.4) 127.45,32.11 126.91,32.11 126.67,31.87 126.67,30.18 126.45,29.95 JDIMM2.62
DDR_B_DQS#4: length 67.3
  IN3 w0.076: v2(139.29,87.08) 139.29,87.29 139.2,87.38 138.99,87.38 138.57,86.95 138.35,86.95 138.03,86.64 138.03,85.6 138.22,85.41 138.22,82.61 138.8,82.03 138.8,74.89 139.56,74.13 140.02,74.13 141.32,72.84 141.32,72.47
  IN3 w0.114: 141.32,72.47 141.32,67.99 142.19,67.11 142.19,65.85 143.13,64.9 143.13,63.67 145.47,61.33 146.35,61.33 149.68,58 149.68,55.59 150.1,55.17 150.38,54.89 150.38,54.73 150.75,54.35 150.75,48.96 150.67,48.87 150.67,41.69 150.8,41.56 150.8,36.9 149.86,35.96 149.86,33.74 150.02,33.58 150.19,33.58 150.35,33.73 150.35,33.86 v2(150.28,33.93)
  BOTTOM w0.076: UC1.AN28 139.6,86.77 v2(139.29,87.08)
  BOTTOM w0.102: JDIMM2.135 150.75,35.98 150.81,35.92 151.02,35.92 151.1,35.83 151.1,35.63 150.8,35.33 150.8,33.72 150.65,33.57 150.36,33.57 150.22,33.71 150.22,33.87 v2(150.28,33.93)
DDR_B_DQS#5: length 67.6
  IN3 w0.076: v2(141.26,86.44) 141.26,86.56 141.15,86.67 140.95,86.67 140.87,86.59 140.87,84.45 141.38,83.95 141.38,81.57 142.02,80.93 142.02,76.09 143.32,74.79 143.71,74.79 144.47,74.03 144.67,74.03 145.75,72.95 145.75,72.47
  IN3 w0.114: 145.75,72.47 145.75,69.82 147.78,67.79 147.78,66.17 154.11,59.84 154.11,58.76 154.56,58.32 154.58,58.29 154.58,57.77 155.7,56.65 155.7,49.97 156.27,49.4 156.27,48.54 156.61,48.19 156.61,40.93 156.72,40.82 156.72,38.17 155.98,37.43 155.98,32.23 155.76,32.01 155.49,32.01 155.3,31.83 v2(155.3,31.63)
  BOTTOM w0.076: UC1.AN25 141.64,86.54 141.54,86.44 v2(141.26,86.44)
  BOTTOM w0.102: v2(155.3,31.63) 155.3,31.84 155.4,31.94 155.75,31.94 155.85,31.85 155.85,30.05 155.85,30.05 JDIMM2.152
DDR_B_DQS#6: length 69.6
  IN3 w0.076: 150.21,72.47 150.21,72.78 149.76,73.24 148.94,73.24 148.68,73.5 148.37,73.82 147.63,73.82 145.56,75.89 145.56,76.74 145.56,76.74 145.56,76.88 145.56,76.88 145.56,80.91 144.95,81.52 144.95,82.39 143.67,83.67 143.67,84.59 143.59,84.67 143.59,86.67 143.72,86.79 143.84,86.79 143.98,86.66 v2(143.98,86.48)
  IN3 w0.114: v2(161.25,33.93) 161.27,33.91 161.27,33.68 161.17,33.58 160.94,33.58 160.81,33.71 160.81,35.79 161.45,36.43 161.45,40.74 162.94,42.23 162.94,50.98 162.11,51.8 162.11,54.96 160.13,56.94 160.13,58.49 159.02,59.6 159.02,60.14 158.55,60.61 158.55,61.68 152.22,68.01 152.22,69.63 150.21,71.63 150.21,72.47
  BOTTOM w0.076: UC1.AN21 144.27,86.77 v2(143.98,86.48)
  BOTTOM w0.102: v2(161.25,33.93) 161.19,33.87 161.19,33.73 161.37,33.56 161.63,33.56 161.87,33.79 161.87,34.89 161.35,35.41 161.35,35.79 161.22,35.92 161.03,35.92 160.95,35.99 160.95,35.99 JDIMM2.169
DDR_B_DQS#7: length 70.6
  IN3 w0.076: v2(145.85,86.36) 145.85,86.51 145.93,86.59 146.18,86.59 146.28,86.49 146.28,83.16 147.22,82.22 147.28,82.22 147.76,81.75 148.17,81.75 148.52,81.4 148.52,78.71 154.35,72.88 155,72.88 155.39,72.5 155.39,72.47
  IN3 w0.114: v2(166.56,32.52) 166.56,32.28 166.68,32.16 166.81,32.16 167.04,32.39 167.04,40.19 167.24,40.39 167.24,55.4 166.35,56.29 166.35,56.72 165.7,57.37 164.37,58.7 164.37,60.26 163.29,61.35 163.29,61.87 162.79,62.37 162.79,63.46 162.01,64.23 156.51,69.73 156.51,71.33 155.39,72.46 155.39,72.47
  BOTTOM w0.076: v2(145.85,86.36) 145.85,86.49 146.13,86.77 UC1.AN18
  BOTTOM w0.102: JDIMM2.186 166.05,29.82 166.05,29.82 166.25,30.02 166.25,30.23 165.45,31.03 165.45,31.83 165.76,32.15 166.39,32.15 166.56,32.32 v2(166.56,32.52)
DDR_B_MA0: length 62
  IN3 w0.076: 132.04,73.49 132.04,79.55 131.68,79.91 131.68,84.67 131.91,84.9 131.91,86.1 v2(131.59,86.41)
  IN3 w0.183: v2(139.3,30.25) 139.3,30.28 139.76,30.73 139.76,38.23 139.53,38.46 139.53,40.84 138.33,42.04 138.33,44.7 138.12,44.92 138.12,49.95 136.76,51.31 136.76,52.56 132.04,57.29 132.04,73.49
  BOTTOM w0.076: UC1.AP40 131.89,86.12 v2(131.59,86.41)
  BOTTOM w0.17: JDIMM2.98 139.65,29.9 v2(139.3,30.25)
DDR_B_MA1: length 61.9
  IN3 w0.076: v2(131.56,85.79) 131.34,85.79 131.14,85.6 131.14,84.86 130.49,84.2 130.49,75.02 131.16,74.34 131.16,73.49
  IN3 w0.183: v2(139.3,34.06) 139.18,33.94 138.92,33.94 138.79,34.06 138.79,37.96 138.49,38.26 138.49,40.65 137.46,41.68 137.46,42.07 137.27,42.26 136.94,42.26 135.97,43.23 135.97,47.99 136.48,48.5 136.48,49.6 135.99,50.09 135.99,50.84 135.89,50.94 135.89,52.2 135.56,52.53 131.16,56.92 131.16,68.24 130.64,68.76 130.64,69.77 131.16,70.29 131.16,73.49
  BOTTOM w0.076: v2(131.56,85.79) 131.88,85.47 UC1.AR40
  BOTTOM w0.17: JDIMM2.97 139.35,36.29 139.82,35.82 139.82,34.05 139.65,33.89 139.47,33.89 v2(139.3,34.06)
DDR_B_MA2: length 64.6
  IN3 w0.076: 130.73,73.49 130.73,74.36 130.26,74.83 130.26,85.33 v2(130.78,85.85)
  IN3 w0.183: 130.73,73.49 130.73,70.47 130.2,69.95 130.2,68.58 130.73,68.06 130.73,56.74 135.12,52.35 135.45,52.02 135.45,50.76 135.55,50.66 135.55,49.91 136.04,49.42 136.04,48.68 135.53,48.17 135.53,43.05 137.02,41.56 137.02,41.49 138.05,40.47 138.05,38.08 138.31,37.82 138.35,37.78 138.35,33.88 138.84,33.39 138.84,32.46 138.56,32.18 138.56,31.85 138.87,31.55 139.2,31.55 139.3,31.65 v2(139.3,31.77)
  BOTTOM w0.076: UC1.AP42 131.05,86.12 v2(130.78,85.85)
  BOTTOM w0.17: v2(139.3,31.77) 139.3,31.98 139.17,32.11 138.82,32.11 138.51,31.8 138.51,30.31 139.05,29.77 JDIMM2.96
DDR_B_MA3: length 64.1
  IN3 w0.076: v2(131.52,85.1) 131.4,84.99 131.4,79.73 131.63,79.5 131.63,73.49
  IN3 w0.183: 131.63,73.49 131.6,73.46 131.6,57.11 136,52.71 136.32,52.38 136.32,51.12 136.43,51.02 136.43,50.27 136.66,50.04 137.41,50.04 137.68,49.77 137.68,49.54 137.5,49.36 137.12,49.36 136.94,49.17 136.94,48.81 137.12,48.62 137.5,48.62 137.68,48.44 137.68,48.08 137.5,47.89 137.12,47.89 136.94,47.71 136.94,47.34 137.12,47.16 137.5,47.16 137.68,46.98 137.68,46.61 137.5,46.43 137.12,46.43 136.94,46.25 136.94,45.88 137.12,45.7 137.5,45.7 137.68,45.52 137.68,45.07 137.52,44.91 137.16,44.91 136.99,44.73 136.99,44.36 137.17,44.17 137.72,44.17 137.9,44 137.9,43.59 137.74,43.43 137.17,43.43 136.99,43.25 136.99,42.88 137.17,42.7 137.74,42.7 137.9,42.54 137.9,41.86 139.09,40.66 139.09,40.36 138.92,40.19 138.92,39.82 139.09,39.65 139.09,39.21 138.92,39.05 138.92,38.44 139.25,38.12 139.25,35.63 v2(139.3,35.58)
  BOTTOM w0.076: v2(131.52,85.1) 131.2,85.43 UC1.AR42
  BOTTOM w0.17: JDIMM2.95 138.75,36.15 137.98,35.37 137.98,34.88 138.13,34.72 138.54,34.72 139.3,35.49 v2(139.3,35.58)
DDR_B_MA4: length 68.8
  IN3 w0.076: v2(129.75,85.7) 129.75,85.68 130.08,85.35 130.08,84.03 130.04,83.99 130.04,74.75 130.29,74.51 130.29,73.49
  IN3 w0.183: v2(136.89,32.56) 137.25,32.56 137.37,32.44 137.37,31.71 137.53,31.55 137.9,31.55 138.1,31.75 138.1,32.41 138.4,32.71 138.4,33.21 137.92,33.7 137.92,37.6 137.61,37.9 137.61,40.29 136.59,41.31 136.59,41.38 135.1,42.87 135.1,48.35 135.6,48.86 135.6,49.24 135.12,49.73 135.12,50.48 135.01,50.58 135.01,51.84 134.69,52.17 134.14,52.71 133.86,52.71 133.7,52.54 133.7,51.85 133.39,51.54 133.05,51.54 132.8,51.79 132.8,54.06 130.29,56.56 130.29,67.88 129.77,68.4 129.77,70.13 130.29,70.65 130.29,73.49
  BOTTOM w0.076: UC1.AR45 129.5,85.7 v2(129.75,85.7)
  BOTTOM w0.17: JDIMM2.92 137.85,29.87 138.05,30.07 138.05,32.18 137.6,32.64 136.97,32.64 v2(136.89,32.56)
DDR_B_MA5: length 67.5
  IN3 w0.076: 129.85,73.49 129.85,74.44 129.64,74.65 129.64,80.5 129.86,80.73 129.86,84.13 129.24,84.75 129.24,85.19 128.81,85.63 v2(128.81,85.97)
  IN3 w0.183: 129.85,73.49 129.85,70.89 128.71,69.74 128.71,68.76 128.97,68.5 129.05,68.5 129.85,67.69 129.85,56.38 130.34,55.89 130.34,55.64 130.23,55.53 130.23,55.27 130.49,55.01 130.75,55.01 130.86,55.12 131.12,55.12 131.37,54.86 131.37,54.6 131.27,54.49 131.27,54.24 131.53,53.98 131.78,53.98 131.89,54.08 132.15,54.08 132.36,53.88 132.36,53.44 132.17,53.25 132.17,52.83 132.36,52.64 132.36,52.3 132.17,52.11 132.17,51.71 132.92,50.95 133.43,50.95 134.24,51.76 134.47,51.76 134.58,51.66 134.58,50.4 134.68,50.3 134.68,49.54 135.03,49.2 135.03,48.9 134.66,48.54 134.66,47.65 134.54,47.53 134.54,47.13 134.66,47.01 134.66,46.51 134.54,46.39 134.54,45.96 134.66,45.84 134.66,45.47 134.54,45.35 134.54,44.88 134.66,44.76 134.66,44.38 134.54,44.26 134.54,43.77 134.66,43.65 134.66,43.36 134.54,43.24 134.54,42.8 136.15,41.19 136.15,40.21 136.37,39.99 137,39.99 137.17,39.82 137.17,37.72 137.48,37.41 137.48,36.65 137.25,36.42 137.25,36.07 137.48,35.83 137.48,35.47 137.32,35.31 137.32,35.03 137.48,34.87 137.48,33.89 137.33,33.73 137.06,33.73 136.89,33.91 v2(136.89,34.08)
  BOTTOM w0.076: UC1.AP45 128.96,86.12 v2(128.81,85.97)
  BOTTOM w0.17: JDIMM2.91 137.55,34.39 137.7,34.24 137.7,33.96 137.52,33.78 137.19,33.78 v2(136.89,34.08)
DDR_B_MA6: length 71.7
  IN3 w0.076: v2(127.83,82.75) 127.49,82.41 127.49,81.95 127.7,81.75 128.19,81.75 128.87,81.07 128.87,80.47 128.98,80.36 128.98,73.49
  IN3 w0.183: v2(136.89,31.03) 137,31.14 137.19,31.14 137.34,30.99 137.34,30.51 137.52,30.33 137.9,30.33 138.08,30.51 138.08,31.04 138.28,31.24 138.54,31.24 138.79,30.99 138.79,30.08 138.49,29.78 138.19,29.78 138.11,29.69 136.71,29.69 136.35,30.05 136.35,36.76 136.48,36.89 136.48,37.18 136.3,37.36 136.3,38 136.12,38.18 135.72,38.18 135.54,38.36 135.54,39.19 135.34,39.4 134.98,39.4 134.73,39.65 134.73,41.38 133.56,42.55 133.56,42.69 133.18,43.07 133.18,48.75 133.79,49.36 133.79,49.86 133.57,50.08 132.56,50.08 132.25,50.39 131.71,50.93 130.99,50.93 130.74,51.18 130.74,52.54 130.53,52.75 130.53,53.74 129.36,54.91 129.36,55.64 128.98,56.02 128.98,57.01 128.79,57.2 128.23,57.2 127.79,57.64 127.79,67.14 128.3,67.66 128.3,67.93 127.83,68.4 127.83,70.1 128.98,71.25 128.98,73.49
  BOTTOM w0.076: v2(127.83,82.75) 127.84,82.75 128.1,83.01 UC1.AW46
  BOTTOM w0.17: JDIMM2.90 137.25,29.93 137.57,30.25 137.57,31.37 137.44,31.5 137.22,31.5 136.89,31.17 v2(136.89,31.03)
DDR_B_MA7: length 72.2
  IN3 w0.076: v2(127.84,81.38) 128.31,81.38 128.54,81.16 128.54,73.49
  IN3 w0.183: 128.54,73.49 128.54,73.03 128.36,72.85 127.06,72.85 126.88,72.66 126.88,72.3 127.06,72.11 128.36,72.11 128.54,71.93 128.54,71.43 128.23,71.12 127.96,71.12 127.54,71.55 127.18,71.55 126.97,71.34 126.97,71.08 127.4,70.65 127.4,68.22 127.69,67.93 127.69,67.67 127.17,67.14 127.06,67.14 126.88,66.96 126.88,66.59 127.06,66.41 127.17,66.41 127.35,66.23 127.35,65.86 127.17,65.68 127.06,65.68 126.88,65.5 126.88,65.13 127.06,64.95 127.17,64.95 127.35,64.77 127.35,64.4 127.17,64.22 127.06,64.22 126.88,64.03 126.88,63.67 127.06,63.49 127.17,63.49 127.35,63.3 127.35,62.94 127.17,62.75 127.06,62.75 126.88,62.57 126.88,62.21 127.06,62.02 127.17,62.02 127.35,61.84 127.35,61.47 127.17,61.29 127.06,61.29 126.88,61.11 126.88,60.74 127.06,60.56 127.17,60.56 127.35,60.38 127.35,60.01 127.17,59.83 127.06,59.83 126.88,59.64 126.88,59.28 127.06,59.1 127.17,59.1 127.35,58.91 127.35,57.46 128.04,56.76 128.36,56.76 128.54,56.58 128.54,55.84 128.92,55.46 128.92,54.73 130.09,53.56 130.09,52.57 130.3,52.36 130.3,50.73 130.6,50.44 131.59,50.44 131.93,50.09 132.11,49.91 132.38,49.64 132.86,49.64 133.05,49.46 133.05,49.24 132.74,48.93 132.74,42.89 133.12,42.51 133.12,42.37 134.29,41.2 134.29,39.47 134.8,38.96 134.95,38.96 135.1,38.81 135.1,38.43 134.57,37.9 134.57,37.59 134.78,37.39 135.67,37.39 135.91,37.14 135.91,33.7 135.46,33.25 135.46,32.94 135.91,32.49 135.91,31.98 135.77,31.83 135.49,31.83 134.9,32.41 v2(134.9,32.53)
  BOTTOM w0.076: UC1.AY46 128.24,81.78 v2(127.84,81.38)
  BOTTOM w0.17: JDIMM2.86 136.05,29.87 136.4,30.22 136.4,32.03 135.9,32.53 v2(134.9,32.53)
DDR_B_MA8: length 70.6
  IN3 w0.076: 129.42,73.49 129.42,80.26 129.04,80.64 129.04,81.37 128.3,82.1 v2(127.85,82.1)
  IN3 w0.183: 129.42,73.49 129.42,71.07 128.27,69.92 128.27,68.58 128.79,68.06 128.87,68.06 129.42,67.51 129.42,67.33 129.23,67.15 128.41,67.15 128.22,66.96 128.22,66.6 128.41,66.41 129.23,66.41 129.42,66.23 129.42,65.87 129.23,65.68 128.41,65.68 128.22,65.5 128.22,65.13 128.41,64.95 129.23,64.95 129.42,64.77 129.42,64.4 129.23,64.22 128.41,64.22 128.22,64.04 128.22,63.67 128.41,63.49 129.23,63.49 129.42,63.31 129.42,62.94 129.23,62.76 128.41,62.76 128.22,62.57 128.22,62.21 128.41,62.03 129.23,62.03 129.42,61.84 129.42,61.48 129.23,61.29 128.41,61.29 128.22,61.11 128.22,60.75 128.41,60.56 129.23,60.56 129.42,60.38 129.42,60.01 129.23,59.83 128.41,59.83 128.22,59.65 128.22,59.28 128.41,59.1 129.23,59.1 129.42,58.92 129.42,58.55 129.23,58.37 128.41,58.37 128.22,58.19 128.22,57.82 128.41,57.64 129.23,57.64 129.42,57.45 129.42,56.2 129.8,55.82 129.8,55.09 131.73,53.16 131.73,51.53 132.74,50.52 133.66,50.52 133.76,50.62 134.01,50.62 134.14,50.49 134.14,50.22 134.22,50.14 134.22,47.83 134.1,47.71 134.1,42.62 135.67,41.06 135.67,39.83 135.99,39.5 136.53,39.5 136.74,39.3 136.74,37.54 136.86,37.41 137.04,37.23 137.04,36.84 136.81,36.6 136.81,35.58 v2(136.89,35.5)
  BOTTOM w0.076: UC1.AY47 127.57,82.36 127.84,82.09 127.84,82.11 127.86,82.11 127.86,82.1 v2(127.85,82.1)
  BOTTOM w0.17: v2(136.89,35.5) 136.89,35.44 136.5,35.05 136.3,35.05 136.19,35.17 136.19,35.57 136.5,35.89 136.62,35.89 136.95,36.22 JDIMM2.89
DDR_B_MA9: length 73.4
  IN3 w0.076: v2(127.8,84.04) 127.72,84.13 127.49,84.13 127.31,83.95 127.31,80.75 127.61,80.44 128.15,80.44 128.25,80.34 128.25,73.63 128.11,73.49
  IN3 w0.183: v2(134.9,34.06) 134.9,33.91 135.11,33.71 135.28,33.71 135.48,33.9 135.48,34.56 135.35,34.68 135.35,35.12 135.48,35.25 135.48,35.65 135.21,35.92 135.21,36.17 135.48,36.44 135.48,36.74 135.26,36.95 134.27,36.95 134.14,37.09 134.14,38.1 133.95,38.29 133.95,38.52 133.79,38.69 133.58,38.69 133.33,38.94 133.33,39.3 133.84,39.8 133.84,41.03 132.68,42.19 132.68,42.33 132.47,42.54 132.33,42.54 132.15,42.73 132.15,43.07 132.3,43.22 132.3,43.6 132.15,43.76 132.15,44.16 132.3,44.32 132.3,44.63 132.15,44.79 132.15,45.17 132.3,45.33 132.3,45.73 132.15,45.89 132.15,46.27 132.3,46.42 132.3,46.8 132.15,46.96 132.15,47.3 132.3,47.45 132.3,47.84 132.15,48 132.15,48.5 132.3,48.66 132.3,49.1 131.4,50 130.22,50 129.86,50.36 129.86,52.13 129.67,52.33 129.01,52.33 128.83,52.5 128.83,52.76 129.44,53.36 129.44,53.59 129.16,53.88 128.86,53.88 128.6,53.62 128.3,53.62 128.04,53.89 128.04,54.14 128.48,54.59 128.48,55.09 128.31,55.27 128.09,55.27 127.46,54.64 127.21,54.64 126.95,54.89 126.95,55.15 127.89,56.09 127.89,56.3 127.6,56.59 127.35,56.59 126.85,56.09 126.57,56.09 126.44,56.22 126.44,56.71 126.83,57.1 126.83,57.36 126.57,57.62 126.57,57.97 126.91,58.31 126.91,58.63 126.44,59.1 126.44,59.83 126.67,60.06 126.67,60.33 126.44,60.56 126.44,61.29 126.67,61.52 126.67,61.79 126.44,62.02 126.44,62.75 126.65,62.96 126.65,63.28 126.44,63.49 126.44,64.22 126.65,64.42 126.65,64.74 126.44,64.95 126.44,67.14 126.96,67.66 126.96,70.47 126.44,70.99 126.44,72.84 126.88,73.28 127.9,73.28 128.11,73.49
  BOTTOM w0.076: UC1.AU46 128.03,84.04 v2(127.8,84.04)
  BOTTOM w0.17: v2(134.9,34.06) 135.52,34.06 135.79,33.78 136.07,33.78 136.33,34.04 136.33,34.43 135.75,35.01 JDIMM2.85
DDR_B_MA10: length 76.6
  IN3 w0.076: v2(134.07,88.6) 133.84,88.83 133.63,88.83 133.47,88.66 133.47,84.71 133.52,84.66 133.52,78.85 134.18,78.2 134.18,74.93 134.45,74.67 134.45,73.49
  IN3 w0.183: v2(143.68,34.08) 143.68,34 143.46,33.78 143.21,33.78 143.08,33.91 143.08,35.42 142.29,36.21 142.29,37.31 142.45,37.47 142.45,37.82 142.29,37.98 142.29,38.33 142.46,38.5 142.46,38.9 142.29,39.07 142.29,39.42 142.46,39.59 142.46,40.6 142.14,40.92 142.14,41.56 140.86,42.84 140.86,43.21 140.96,43.31 140.96,50.45 140.52,50.89 140.52,51.21 140.72,51.41 140.72,52.29 139.97,53.04 139.68,53.04 139.53,53.19 139.53,53.49 139.76,53.72 139.76,54.07 139.05,54.78 139.05,55.05 138.79,55.3 138.52,55.3 138,55.83 138,56.16 137.82,56.34 136.99,56.34 136.99,56.34 136.86,56.22 136.44,56.22 134.45,58.21 134.45,58.5 134.63,58.69 135.56,58.69 135.74,58.87 135.74,59.24 135.56,59.42 134.63,59.42 134.45,59.6 134.45,59.97 134.63,60.15 135.56,60.15 135.74,60.33 135.74,60.7 135.56,60.88 134.63,60.88 134.45,61.06 134.45,61.43 134.63,61.61 135.56,61.61 135.74,61.8 135.74,62.16 135.56,62.34 134.63,62.34 134.45,62.53 134.45,62.89 134.63,63.08 135.56,63.08 135.74,63.26 135.74,63.62 135.56,63.81 134.63,63.81 134.45,63.99 134.45,73.49
  BOTTOM w0.076: v2(134.07,88.6) 134.18,88.72 UC1.AK36
  BOTTOM w0.17: JDIMM2.107 142.35,36.1 142.07,35.81 142.07,34.75 142.32,34.5 142.32,34.09 142.75,33.66 143.26,33.66 v2(143.68,34.08)
DDR_B_MA11: length 72.7
  IN3 w0.076: v2(127.84,80.07) 127.84,80.08 127.41,79.65 127.41,74.69 126.88,74.16 126.52,74.16 125.85,73.49
  IN3 w0.183: 125.85,73.49 125.57,73.21 125.57,70.63 125.89,70.31 125.89,70.04 125.56,69.72 125.56,68.74 126.06,68.23 126.06,68.02 125.61,67.57 125.2,67.57 124.76,67.13 124.76,59.09 125.2,58.65 125.53,58.65 125.7,58.48 125.7,57.21 125.56,57.07 125.56,55.86 126.08,55.34 126.08,54.53 127.34,53.27 127.42,53.27 127.46,53.22 127.82,52.87 127.96,52.73 127.96,51.8 128.15,51.62 128.49,51.62 128.99,51.11 128.99,49.76 129.16,49.59 129.4,49.59 129.86,49.13 130.63,49.13 130.81,48.95 130.81,43.06 131.27,42.6 131.27,42.36 132.18,41.46 132.18,40.11 131.98,39.91 131.98,39.37 132.32,39.02 132.32,37.35 132.26,37.29 132.26,36.63 132.77,36.12 133.38,36.12 133.64,35.85 133.99,35.85 134.45,35.39 134.45,31.93 133.96,31.45 133.96,31.17 134.24,30.89 134.24,30.1 134.65,29.69 135.06,29.69 135.39,29.36 135.74,29.36 135.91,29.54 135.91,29.83 135.54,30.2 135.54,30.51 135.91,30.88 135.91,31.22 135.75,31.39 135.2,31.39 134.9,31.09 v2(134.9,31.01)
  BOTTOM w0.076: v2(127.84,80.07) 127.8,80.07 127.12,80.74 127.12,83.37 UC1.AV47
  BOTTOM w0.17: v2(134.9,31.01) 134.9,31.15 135.33,31.57 135.33,31.7 135.51,31.88 135.74,31.88 135.93,31.69 135.93,30.8 135.45,30.32 JDIMM2.84
DDR_B_MA12: length 68.9
  IN3 w0.076: v2(127.84,78.95) 127.82,78.92 127.82,74.89
  IN3 w0.183: v2(134.83,35.64) 134.83,35.68 134.73,35.78 134.73,36.38 134.58,36.52 134.33,36.52 134.1,36.29 133.82,36.29 133.56,36.55 132.95,36.55 132.7,36.81 132.7,37.11 132.88,37.29 133.56,37.29 133.7,37.43 133.7,37.88 133.53,38.06 132.92,38.06 132.76,38.22 132.76,38.47 132.89,38.61 132.89,39.07 132.47,39.5 132.47,39.78 132.69,40.01 133.2,40.01 133.4,40.21 133.4,40.85 131.71,42.55 131.71,49.08 131.22,49.56 130.04,49.56 129.43,50.17 129.43,51.7 129.24,51.89 128.83,51.89 128.4,52.32 128.4,52.91 127.6,53.7 127.52,53.7 126.52,54.71 126.52,55.52 126,56.04 126,56.89 126.14,57.03 126.14,58.77 125.82,59.09 125.38,59.09 125.2,59.27 125.2,59.64 125.38,59.82 125.82,59.82 126,60 126,60.37 125.82,60.55 125.38,60.55 125.2,60.73 125.2,61.1 125.38,61.28 125.82,61.28 126,61.46 126,61.83 125.82,62.01 125.38,62.01 125.2,62.2 125.2,62.56 125.38,62.75 125.82,62.75 126,62.93 126,63.29 125.82,63.48 125.38,63.48 125.2,63.66 125.2,64.03 125.38,64.21 125.82,64.21 126,64.39 126,64.76 125.82,64.94 125.38,64.94 125.2,65.12 125.2,65.49 125.38,65.67 125.82,65.67 126,65.85 126,66.22 125.82,66.4 125.38,66.4 125.2,66.59 125.2,66.95 125.38,67.13 125.82,67.13 126.52,67.84 126.52,70.29 126,70.81 126,73.03 126.7,73.72 127.52,73.72 127.82,74.02 127.82,74.89
  BOTTOM w0.076: UC1.AU47 127.37,84.02 126.96,83.61 126.96,79.24 127.26,78.95 v2(127.84,78.95)
  BOTTOM w0.17: JDIMM2.83 135.15,36.23 135.31,36.07 135.31,35.66 135.18,35.54 134.93,35.54 v2(134.83,35.64)
DDR_B_MA13: length 77.4
  IN3 w0.076: v2(135.75,89.13) 135.75,89.24 135.95,89.44 136.22,89.44 136.31,89.35 136.31,87.7 136.17,87.55 136.17,84.48 136.38,84.27 136.38,74.94 137.53,73.79 137.53,73.49
  IN3 w0.183: v2(146.01,40.44) 146.01,40.86 145.85,41.02 145.43,41.02 145.27,41.18 145.27,41.45 146,42.18 146,49.24 145.34,49.9 145.34,50.68 145.54,50.88 146.79,50.88 146.94,51.03 146.94,51.54 146.79,51.69 146.03,51.69 145.9,51.82 145.9,52.1 146.66,52.86 146.66,52.91 146.66,53.08 146.38,53.36 146.1,53.36 145.62,52.89 145.36,52.89 145.17,53.08 145.17,53.42 145.33,53.58 145.33,53.94 145.17,54.1 145.17,54.43 145.39,54.66 145.7,54.66 145.89,54.85 145.89,55.22 145.74,55.37 144.76,55.37 144.61,55.53 144.61,55.93 144.78,56.11 145.57,56.11 145.77,56.31 145.77,56.54 145.5,56.82 144.38,56.82 143.96,56.4 143.49,56.4 143.34,56.55 143.34,56.81 143.85,57.32 143.85,57.58 143.59,57.84 143.33,57.84 142.83,57.33 142.57,57.33 142.31,57.59 142.31,57.85 142.82,58.35 142.82,58.61 142.56,58.87 142.3,58.87 141.79,58.36 141.53,58.36 141.27,58.62 141.27,58.88 141.78,59.39 141.78,59.65 141.52,59.91 141.26,59.91 140.76,59.4 140.5,59.4 140.24,59.66 140.24,59.92 140.75,60.42 140.75,60.68 140.49,60.94 140.23,60.94 139.72,60.43 139.45,60.43 138.89,60.99 138.89,61.22 139.32,61.65 139.32,61.94 138.96,62.31 138.96,62.61 139.32,62.98 139.32,63.35 138.4,64.28 138.4,65.54 137.53,66.42 137.53,73.49
  BOTTOM w0.076: UC1.AK33 135.98,88.72 135.75,88.95 v2(135.75,89.13)
  BOTTOM w0.17: JDIMM2.119 145.95,38.39 145.62,38.72 145.62,39.51 145.84,39.73 146.51,39.73 146.79,40.01 146.79,40.24 146.59,40.44 v2(146.01,40.44)
DDR_B_MA14: length 74
  IN3 w0.076: v2(128.27,84.95) 128.19,85.04 127.99,85.04 127.14,84.19 127.14,80.68 127.25,80.58 127.25,74.76 126.81,74.32 126.45,74.32 125.93,73.8 125.59,73.8 125.28,73.49 125.23,73.49
  IN3 w0.183: 125.23,73.49 125.13,73.39 125.13,70.45 125.25,70.32 125.25,70.03 125.12,69.9 125.12,68.11 124.33,67.31 124.33,58 124.49,57.84 125.1,57.84 125.26,57.68 125.26,57.39 124.92,57.05 124.51,57.05 124.34,56.87 124.34,56.54 124.52,56.36 124.95,56.36 125.12,56.19 125.12,55.76 124.97,55.6 124.49,55.6 124.34,55.45 124.34,55.02 124.46,54.89 125.43,54.89 125.64,54.68 125.64,54.42 125.35,54.13 125.35,53.9 125.48,53.77 126.22,53.77 127.16,52.83 127.24,52.83 127.51,52.56 127.52,52.54 127.52,52.01 127.16,51.64 127.16,51.39 127.41,51.13 128.35,51.13 128.55,50.93 128.55,50.01 128.33,49.78 128.33,49.51 128.68,49.15 129.21,49.15 129.68,48.69 130.15,48.69 130.37,48.47 130.37,48.19 130.23,48.05 130.23,47.6 130.37,47.46 130.37,47.01 130.23,46.87 130.23,46.43 130.37,46.29 130.37,45.84 130.23,45.7 130.23,45.29 130.37,45.15 130.37,44.75 130.26,44.63 130.26,44.15 130.37,44.03 130.37,43.58 130.15,43.36 130.15,43.1 130.83,42.42 130.83,42.18 131.74,41.28 131.74,40.29 131.54,40.09 131.54,39.19 131.89,38.84 131.89,37.53 131.82,37.47 131.82,36.44 132.59,35.68 133.2,35.68 133.46,35.41 133.81,35.41 133.99,35.23 133.99,34.92 133.83,34.76 133.74,34.76 133.56,34.58 133.56,34.21 133.74,34.03 133.83,34.03 134.01,33.84 134.01,33.58 133.61,33.17 133.61,32.95 134.01,32.54 134.01,32.14 133.83,31.96 133.61,31.96 133.12,32.44 v2(133.12,32.53)
  BOTTOM w0.076: v2(128.27,84.95) 128.12,85.11 128.12,85.32 128.27,85.47 UC1.AR46
  BOTTOM w0.17: v2(133.12,32.53) 133.18,32.59 134.21,32.59 134.45,32.35 134.45,30.09 134.25,29.9 JDIMM2.80
DDR_B_MA15: length 74.9
  IN3 w0.076: v2(127.9,85.83) 127.9,85.83 127.68,85.62 127.68,84.98 127.16,84.46 126.14,84.46 125.94,84.25 125.94,83.95 126.17,83.72 126.39,83.72 126.81,83.3 126.81,80.54 126.92,80.44 126.92,76.57 124.02,73.67 124.02,73.49
  IN3 w0.183: v2(133.12,31.01) 133.46,31.01 133.79,30.69 133.79,29.75 133.43,29.39 132.29,29.39 131.88,29.8 131.88,30.43 132.44,30.99 132.44,31.35 132.11,31.68 132.11,32.01 132.64,32.54 132.64,33.09 132.05,33.69 132.05,34.98 131.79,35.25 131.11,35.25 130.88,35.47 130.88,37.82 130.99,37.92 130.99,38.5 130.67,38.83 130.67,40.45 130.87,40.65 130.87,40.92 129.96,41.82 129.96,42.06 129.5,42.52 129.03,42.52 128.55,43 128.55,43.57 128.38,43.74 127.76,43.74 127.45,44.06 127.45,49.85 126.18,51.12 126.18,52.57 125.87,52.88 124.8,52.88 124.48,53.2 124.48,53.81 124.27,54.02 123.66,54.02 123.45,54.23 123.45,67.26 123.45,68.04 124.02,68.6 124.02,73.49
  BOTTOM w0.076: v2(127.9,85.83) 128.19,86.12 UC1.AP46
  BOTTOM w0.17: v2(133.12,31.01) 133.37,31.01 133.51,31.14 133.51,31.55 133.66,31.7 133.86,31.7 134.01,31.55 134.01,30.27 133.65,29.9 133.65,29.9 JDIMM2.78
DDR_B_RAS#: length 78
  IN3 w0.076: 135.76,74.2 135.76,74.5 135.43,74.83 135.43,78.88 135.06,79.25 135.06,84.27 134.53,84.79 134.53,86.97 134.66,87.11 v2(134.92,87.11)
  IN3 w0.183: v2(143.68,30.27) 143.41,30 142.4,30 142.16,30.23 142.16,30.53 142.37,30.74 142.62,30.74 142.8,30.92 142.8,31.24 142.5,31.55 142.5,32.18 142.24,32.44 142.24,33.05 142.45,33.25 142.9,33.25 143.16,33 143.16,32.44 143.29,32.31 143.29,31.75 143.46,31.57 143.9,31.57 144.1,31.78 144.1,32.48 144.6,32.99 144.6,36.08 143.77,36.91 143.77,41.14 143.45,41.46 143.45,42.1 142.93,42.62 142.93,48.44 143.52,49.03 143.52,49.06 143.53,49.08 143.53,49.95 144.03,50.45 144.03,51.46 143.81,51.67 143.08,51.67 142.73,52.02 142.73,52.38 142.93,52.58 143.59,52.58 143.84,52.83 143.84,53.32 143.65,53.52 143.65,54.08 143.09,54.64 142.7,54.64 142.45,54.89 142.45,55.59 139.48,58.56 138.65,58.56 138.2,59.01 138.2,59.65 137.93,59.91 137.56,59.91 137.5,59.84 137.24,59.84 137.05,60.03 137.05,64.93 136.8,65.18 135.98,65.18 135.76,65.41 135.76,65.62 135.94,65.8 136.02,65.8 136.2,65.99 136.2,66.35 136.02,66.53 135.94,66.53 135.76,66.72 135.76,67.08 135.94,67.27 136.02,67.27 136.2,67.45 136.2,67.81 136.02,68 135.94,68 135.76,68.18 135.76,68.55 135.94,68.73 136.02,68.73 136.2,68.91 136.2,69.28 136.02,69.46 135.94,69.46 135.76,69.64 135.76,70.01 135.94,70.19 136.02,70.19 136.2,70.38 136.2,70.74 136.02,70.92 135.94,70.92 135.76,71.11 135.76,71.47 135.94,71.66 136.02,71.66 136.2,71.84 136.2,72.2 136.02,72.39 135.94,72.39 135.76,72.57 135.76,72.94 135.94,73.12 136.02,73.12 136.2,73.3 136.2,73.67 136.02,73.85 135.94,73.85 135.76,74.03 135.76,74.2
  BOTTOM w0.076: v2(134.92,87.11) 135.23,87.42 UC1.AM35
  BOTTOM w0.17: v2(143.68,30.27) 143.45,30.27 143.25,30.07 JDIMM2.110
DDR_B_WE#: length 76.3
  IN3 w0.076: 136.64,73.49 136.64,73.94 135.85,74.73 135.85,78.82 135.28,79.39 135.28,87.83 135.44,87.99 135.44,88.45 135.36,88.52 135.05,88.52 v2(134.97,88.44)
  IN3 w0.183: v2(145.77,32.72) 146,32.72 146.11,32.62 146.11,32.31 145.9,32.11 145.57,32.11 145.22,31.75 145.22,31.4 145.06,31.24 145.06,30.91 144.66,30.51 144.35,30.51 144.15,30.71 144.15,31.21 144.56,31.62 144.56,32.32 145.24,33.01 145.24,33.73 145.04,33.94 145.04,34.42 145.32,34.7 145.32,35.28 145.04,35.56 145.04,36.26 144.21,37.09 144.21,37.6 144.89,38.28 144.89,38.69 144.21,39.36 144.21,39.61 144.48,39.88 144.48,40.16 144.21,40.43 144.21,41.32 143.89,41.64 143.89,42.28 143.37,42.81 143.37,47.09 143.59,47.31 143.59,47.58 143.37,47.8 143.37,48.26 144.13,49.02 144.13,49.93 144.46,50.27 144.46,51.04 145.03,51.61 145.03,51.98 144.76,52.25 144.43,52.25 144.28,52.4 144.28,53.5 144.08,53.7 144.08,54.26 143.27,55.08 143.07,55.08 142.89,55.26 142.89,55.77 139.67,58.99 138.83,58.99 138.74,59.08 138.63,59.19 138.63,59.83 138.12,60.35 137.7,60.35 137.49,60.56 137.49,65.12 136.98,65.62 136.76,65.62 136.64,65.74 136.64,73.49
  BOTTOM w0.076: v2(134.97,88.44) 134.97,88.66 135.11,88.8 135.33,88.8 UC1.AK35
  BOTTOM w0.17: v2(145.77,32.72) 144.23,34.27 144.23,35.74 144.15,35.82 JDIMM2.113
DDR_CKE0_DIMMA: length 46.6
  IN1 w0.076: 125.06,74.76 125.06,75.3 125.06,75.3 129.82,80.06 129.82,83.7 129.51,84.01 v2(129.42,84.01)
  IN1 w0.183: v2(119.78,46.95) 119.71,46.89 119.46,46.89 119.31,47.04 119.31,47.84 119.59,48.13 119.71,48.13 119.89,48.31 119.89,51.06 119.66,51.29 119.66,51.66 119.89,51.88 119.89,54.79 120.79,55.69 120.79,56.05 123.27,58.52 123.27,68.37 123.99,69.09 123.99,72.76 124.62,73.38 124.62,73.86 125.06,74.31 125.06,74.76
  BOTTOM w0.076: UC1.AU43 129.57,84.01 v2(129.42,84.01)
  BOTTOM w0.17: v2(119.78,46.95) 119.21,47.51 119.21,47.93 120.15,48.87 JDIMM1.73
DDR_CKE1_DIMMA: length 46.8
  IN1 w0.076: 124.63,74.76 124.63,75.22 128.96,79.55 128.96,82.45 129.22,82.71 v2(129.41,82.71)
  IN1 w0.183: v2(119.78,45.43) 119.29,45.91 119.29,46.44 118.87,46.86 118.83,46.91 118.83,47.98 119.45,48.61 119.45,50.88 119.22,51.11 119.22,51.84 119.45,52.06 119.45,54.97 120.35,55.87 120.35,56.23 122.83,58.71 122.83,68.55 123.55,69.27 123.55,72.94 124.18,73.56 124.18,74.04 124.63,74.49 124.63,74.76
  BOTTOM w0.076: v2(129.41,82.71) 129.42,82.71 129.72,83.01 UC1.AW43
  BOTTOM w0.17: JDIMM1.74 120.45,44.76 v2(119.78,45.43)
DDR_CKE2_DIMMB: length 58.5
  IN3 w0.076: 123.33,73.49 123.33,74.33 126.72,77.73 126.72,80.4 126.65,80.47 126.65,81.13 v2(126.27,81.51)
  IN3 w0.183: 123.33,73.49 123.33,69.34 122.76,68.77 122.76,53.93 125.18,51.51 125.18,51.15 125.87,50.45 126.76,49.57 126.76,43.77 128.7,41.83 128.96,41.83 129.98,40.81 129.98,38.51 130.19,38.29 130.19,35.12 131.27,34.04 v2(131.6,34.04)
  BOTTOM w0.076: v2(126.27,81.51) 126.67,81.91 UC1.AY49
  BOTTOM w0.17: v2(131.6,34.04) 131.32,34.04 131.14,34.21 131.14,35.26 131.32,35.43 131.89,35.43 132.15,35.7 JDIMM2.73
DDR_CKE3_DIMMB: length 61.6
  IN3 w0.076: 122.89,73.49 122.89,74.63 125.99,77.73 125.99,80.11 v2(126.27,80.39)
  IN3 w0.183: v2(131.6,32.51) 131.6,32.52 129.72,34.39 129.72,38.14 129.54,38.33 129.54,40.37 128.31,41.6 128.31,41.6 128.07,41.84 126.32,43.59 126.32,49.39 124.63,51.08 124.63,51.41 122.33,53.71 122.33,68.95 122.89,69.52 122.89,73.49
  BOTTOM w0.076: UC1.AU50 125.56,84.12 125.56,82.08 125.81,81.82 125.81,80.85 v2(126.27,80.39)
  BOTTOM w0.17: JDIMM2.74 132.45,31.66 v2(131.6,32.51)
DDR_CS0_DIMMA#: length 48.2
  IN1 w0.076: v2(136.85,85.7) 137.22,85.34 137.22,78.12 137.16,78.07 137.16,74.52 137.92,73.77 137.92,72.98 138.63,72.27 138.63,71.97
  IN1 w0.183: 138.63,71.97 138.63,67.98 139.03,67.58 139.03,59.89 138.63,59.49 138.63,58.45 137.19,57 137.19,54.49 136.64,53.94 136.64,53.25 136.15,52.76 136.15,50.82 135.44,50.12 135.44,48.5 135.39,48.45 135.39,47.99 134.96,47.56 134.96,46.81 134.37,46.22 134.37,44.73 133.64,44.01 v2(133.64,44.01)
  BOTTOM w0.076: v2(136.85,85.7) 136.43,86.12 UC1.AP33
  BOTTOM w0.17: JDIMM1.114 132.45,42.82 v2(133.64,44.01)
DDR_CS1_DIMMA#: length 48.2
  IN1 w0.076: v2(136.86,85.12) 136.4,85.12 136.17,84.89 136.17,84.54 136.88,83.83 136.88,78.92 136.73,78.77 136.73,74.37 137.73,73.38 137.73,72.7 138.19,72.24 138.19,71.97
  IN1 w0.183: 138.19,71.97 138.19,67.76 138.59,67.35 138.59,60.07 138.2,59.67 138.2,58.63 136.75,57.18 136.75,54.67 136.2,54.12 136.2,53.44 135.71,52.94 135.71,51.01 135.01,50.3 135.01,48.68 134.95,48.63 134.95,48.17 134.52,47.74 134.52,46.99 134.37,46.84 134.12,46.84 133.9,47.05 v2(133.64,47.05)
  BOTTOM w0.076: v2(136.86,85.12) 137.19,85.12 137.32,85.24 UC1.AR32
  BOTTOM w0.17: JDIMM1.121 134.55,47.98 134.85,47.68 134.85,46.74 134.6,46.48 134.21,46.48 v2(133.64,47.05)
DDR_CS2_DIMMB#: length 67.2
  IN3 w0.076: v2(136.86,87.69) 136.5,87.32 136.5,84.64 136.83,84.3 136.83,75.31 138.66,73.49 138.66,73.45
  IN3 w0.183: v2(145.8,31.03) 145.84,31.03 146.91,32.1 146.91,37.36 147.7,38.15 147.7,40.76 147.18,41.27 147.18,49.27 147.65,49.74 147.65,49.98 148.09,50.43 148.09,53.25 147.92,53.42 147.57,53.77 147.55,53.79 147.21,54.13 147.02,54.33 147.02,56.9 145.24,58.67 144.36,58.67 143.44,59.59 140.47,62.56 140.47,63.8 139.53,64.74 139.53,66.01 138.66,66.88 138.66,73.45
  BOTTOM w0.076: v2(136.86,87.69) 137.01,87.69 137.28,87.42 137.28,87.42 UC1.AM32
  BOTTOM w0.17: JDIMM2.114 144.45,30.28 145.2,31.03 v2(145.8,31.03)
DDR_CS3_DIMMB#: length 65
  IN3 w0.076: 138.22,73.49 138.22,73.55 136.61,75.16 136.61,84.3 136.33,84.57 136.33,87.48 136.48,87.63 136.48,88.68 v2(136.81,89.01)
  IN3 w0.183: 138.22,73.49 138.22,66.7 139.09,65.83 139.09,64.56 140.03,63.62 140.03,62.38 142.64,59.78 143.13,59.28 144.18,58.24 145.06,58.24 146.58,56.72 146.58,54.14 146.69,54.03 147.26,53.46 147.61,53.11 147.66,53.07 147.66,50.61 147.21,50.17 147.21,49.92 146.75,49.45 146.75,39.44 146.92,39.27 146.92,37.99 146.44,37.5 146.44,34.42 146.2,34.18 v2(146.01,34.18)
  BOTTOM w0.076: UC1.AK32 137.1,88.72 v2(136.81,89.01)
  BOTTOM w0.17: v2(146.01,34.18) 146.17,34.18 146.55,34.56 JDIMM2.121
DDR_PG_CTRL: length 50
  TOP w0.102: v1(133.53,57.72) 133.77,57.97 U2303.2 136.18,57.97 v2(136.25,57.9)
  BOTTOM w0.076: UC1.AV61 118.36,83.94 118.3,83.99 117.4,83.99 116.76,83.35 116.76,82.06 117.16,81.66 117.16,81.02 117.83,80.34 117.83,79.92 115.98,78.07 115.98,76.69 117.91,74.76
  BOTTOM w0.102: v2(136.25,57.9) 136.25,72.95 134.92,74.28 118.38,74.28 117.91,74.76
DDR_XDP_SMBCLK_R1: length 5.7
  TOP w0.102: JXDP.53 92.41,81.66 93.02,82.27 93.02,82.95 93.21,83.14 93.21,84.01 RC54.2 93.7,84.93 93.26,85.37 v1(93.07,85.37)
DDR_XDP_SMBDAT_R1: length 6.7
  TOP w0.102: JXDP.51 92.42,81.16 93.27,82.02 93.27,82.88 93.7,83.31 RC53.2 93.7,83.71 94,84 95.53,84 v1(95.97,83.57)
DDR_XDP_WLAN_TP_SMBCLK: length 231.3
  TOP w0.102: v2(168.41,58.47) 169.09,59.16 169.09,67.82 171.59,70.32 171.98,70.32 172.85,71.19 172.85,73.44 v1(173.02,73.6) 179.34,79.92 179.34,82.06 177.98,83.42 177.98,86.03 177.53,86.48 177.34,86.48 175.58,88.24 R2332.2 175.11,88.7 175.11,89.77 175.57,90.22 175.57,91.68 175.49,91.76 QC1.1 ; RC54.1 v2(95.31,84.51)
  BOTTOM w0.102: v2(95.31,84.51) 94.87,84.08 94.87,83.26 95.13,83.01 95.48,83.01 97.59,80.9 97.59,65.08 99.62,63.05 99.62,54.92 97.97,53.27 93.53,53.27 92.79,52.53 92.79,50.4 95.86,47.32 95.86,43.81 95.48,43.42 95.48,40.7 102.06,34.12 102.06,33.49 107.04,28.5 107.04,28.24 108.83,26.44 111.83,26.44 112.82,25.45 126.13,25.45 126.74,24.84 130.81,24.84 131.12,25.15 135.77,25.15 136.25,25.63 145.06,25.63 145.47,25.22 148.53,25.22 149.39,26.09 157.6,26.09 157.99,26.47 166.95,26.47 167.69,27.21 170.2,27.21 170.85,27.85 JDIMM2.202 170.85,29.73 170.24,30.34 170.24,31.92 172.84,34.52 172.84,38.09 171.3,39.63 169.49,39.63 169.21,39.91 165.48,39.91 165.3,40.09 159.46,40.09 158.85,40.7 JDIMM1.202 158.85,45.78 166.84,53.77 170.11,53.77 170.62,54.28 170.62,57.51 169.57,58.55 168.48,58.55 v2(168.41,58.47)
DDR_XDP_WLAN_TP_SMBDAT: length 226.5
  TOP w0.102: QC1.4 176.9,89.91 176.92,89.89 176.92,88.7 R2331.2 176.46,87.68 177.44,86.71 177.63,86.71 178.36,85.97 v1(178.36,84.44) 178.36,83.37 179.57,82.16 179.57,79.52 173.16,73.11 173.16,71.17 172.08,70.09 171.71,70.09 169.35,67.73 169.35,58.57 v2(168.86,58.09) ; RC53.1 v2(95.33,83.49)
  BOTTOM w0.102: v2(95.33,83.49) 97.82,81 97.82,65.21 99.88,63.15 99.88,54.79 98.1,53.01 93.65,53.01 93.02,52.38 93.02,50.6 96.09,47.53 96.09,43.72 95.7,43.33 95.7,40.79 102.29,34.21 102.29,33.58 107.27,28.6 107.27,28.33 108.93,26.67 111.92,26.67 112.91,25.68 126.33,25.68 126.94,25.07 130.72,25.07 131.02,25.38 135.68,25.38 136.16,25.86 145.16,25.86 145.56,25.45 148.43,25.45 149.3,26.32 157.51,26.32 157.89,26.7 166.86,26.7 167.59,27.43 170.11,27.43 170.25,27.58 JDIMM2.200 170.25,30 169.98,30.27 169.98,32.07 172.58,34.67 172.58,37.96 171.15,39.4 169.4,39.4 169.12,39.68 165.39,39.68 165.21,39.86 158.68,39.86 158.25,40.29 JDIMM1.200 158.25,45.51 166.77,54.03 169.98,54.03 170.39,54.43 170.39,57.41 169.71,58.09 v2(168.86,58.09)
DEW1: length 6.5
  TOP w0.102: US2.16 171.29,23.33 171.51,23.55 172.84,23.55 173.23,23.15 RS42.1 RS43.2 174.26,23.61 175.38,23.61 v1(175.73,23.26)
DEW2_REXT: length 4.8
  TOP w0.102: US2.6 169.29,18.38 169.13,18.21 v1(167.2,18.21) 166.69,17.71 RS41.2 RS40.1
DGPU_CORE_EN: length 86.1
  TOP w0.102: v2(91.16,95.77) 90.75,95.35 90.25,95.35 87.58,98.02 84.62,98.02 v1(84.21,97.6) 81.27,97.6 80.83,97.16 RC369.2
  IN1 w0.114: v2(91.16,95.77) 91.16,96.92 94.3,100.05 100.49,100.05 102.11,98.44 109.78,98.44 112.36,101.02 112.36,101.77 113.79,103.19 114.55,103.19 115.5,104.14 121.55,104.14 122.62,105.21 129.68,105.21 130.5,106.03 134.15,106.03 134.41,105.77 138.95,105.77 143.39,101.33 143.39,100.59 144.38,99.6 146.71,99.6 147.45,98.86 150.58,98.86 151.69,97.74 153.13,97.74 v2(153.71,97.17)
  BOTTOM w0.076: UC1.R5 153.5,96.96 v2(153.71,97.17)
DGPU_HOLD_RST#: length 100.5
  TOP w0.102: UV14.1 80.27,82.97 80.33,83.03 RV45.2 81.28,83.49 81.28,83.81 83.21,85.74 83.21,89.99 82.78,90.42 82.78,93.17 84.46,94.85 93.35,94.85 93.83,95.32 93.83,95.33 94.97,96.48 v1(94.97,97.96) 94.97,98.61 v2(94.77,98.81)
  IN1 w0.114: v2(155.81,94.39) 155.81,94.39 155.32,94.87 151.52,94.87 148.99,97.4 147.68,97.4 147.11,97.97 145.14,97.97 144.72,98.39 143.37,98.39 142.6,99.16 142.6,101.04 139.48,104.17 122.6,104.17 121.66,103.23 117.7,103.23 117.21,102.75 116.21,102.75 114.13,100.66 113.64,100.66 109.86,96.88 102.65,96.88 100.31,99.21 95.99,99.21 95.58,98.81 v2(94.77,98.81)
  BOTTOM w0.076: v2(155.81,94.39) 155.86,94.34 155.86,93.88 155.71,93.73 155.09,93.73 UC1.Y3
DGPU_PEX_RST#: length 34
  TOP w0.102: RV40.1 73.41,78.56 71.53,80.44 71.53,82.35 71.76,82.58 72.51,82.58 v1(73.6,83.67) 73.6,84.04 74.45,84.89 RV208.2 75.3,85.38 75.3,87.24 75.49,87.43 76.94,87.43 77.47,87.96 v2(81.03,87.96) 81.03,89.3 QV78.2 ; v2(77.73,97.76) 77.26,97.29 RV252.2
  IN3 w0.135: v2(77.73,97.76) 77.73,97.49 79.79,95.42 79.79,89.2 v2(81.03,87.96)
DGPU_PEX_RST_R#: length 4.9
  TOP w0.102: v2(69.45,78.79) 70.13,79.48 71.73,79.48 v1(71.81,79.4) 72.02,79.4 72.5,78.93 RV40.2
  BOTTOM w0.102: v2(69.45,78.79) 69.82,79.17 UV1.AC7
DGPU_PWR_EN: length 101.4
  TOP w0.102: v2(89.78,100.04) 89.78,100.08 87.95,98.25 v1(81.54,98.25) 80.65,98.25 RC368.2 RC370.2
  IN1 w0.076: 146.1,104.19 147.01,103.28 147.6,103.28
  IN1 w0.114: 147.6,103.28 148.31,103.28 148.8,102.8 148.8,100.61 149.13,100.28 149.46,100.28 149.86,100.69 150.6,100.69 150.96,100.33 151.72,100.33 v2(152.1,100.71) ; v2(89.78,100.04) 91.91,100.04 94.94,103.07 103.36,103.07 105.88,100.55 108.91,100.55 110.25,101.89 110.25,102.64 111.83,104.22 111.83,107.88 112.72,108.77 113.68,108.77 115.82,110.9 115.82,111.57 118.09,113.85 120.71,113.85 122.67,111.88 122.67,106.61 123.35,105.93 129.38,105.93 130.2,106.76 134.45,106.76 134.71,106.49 143.79,106.49 146.1,104.19
  BOTTOM w0.076: UC1.L3 154.62,98.48 153.78,99.32 153.55,99.32 153.09,99.77 153.01,99.77 152.73,100.05 152.53,100.05 152.1,100.48 v2(152.1,100.71)
  BOTTOM w0.102: v2(89.78,100.04) 89.78,100.08 90.43,100.73 RV193.1
DGPU_PWROK: length 295.4
  TOP w0.102: 82.53,68.58 82.53,72.65 81.59,73.59 80.57,73.59 80.38,73.78 80.38,75.94 78.3,78.02 QV88.2 78.3,79.14 80.07,80.9 80.07,81.16 81.74,82.84 81.74,83.61 83.67,85.54 83.67,90.18 83.24,90.61 83.24,92.05 v1(83.46,92.26) 85.58,94.39 93.55,94.39 95.66,96.5 95.66,100.46 v2(95.27,100.85) ; 82.53,68.58 84.38,66.73 86.72,66.73 90.09,63.36 90.09,50.71 89.58,50.21 89.58,48.23 86.44,45.09 84.97,45.09 84.33,44.45 84.33,37.44 84.84,36.93 84.84,33.28 75.62,24.06 75.62,16.77 v2(75.34,16.49) ; 82.53,68.58 81.59,68.58 75.92,62.92 75.92,61.7 74.76,60.53 v2(74.5,60.53) ; RP43.6 170.89,96.95 v2(170.62,96.67) ; UE4.20 99.84,13.88 99.98,13.74 100.42,13.74 101.56,14.88 101.56,15.25 v2(102.44,16.13) ; PR1000.2 53.47,52.83 54.61,52.83 55.55,53.77 55.55,58.32 v2(55.22,58.65)
  TOP w0.279: PR1000.2 52.62,53.05 51.85,53.05 51.5,53.39 51.5,53.91 51.87,54.28 51.87,54.92 51.73,55.06 PU1000.1
  IN1 w0.114: v2(170.62,96.67) 170.21,97.08 168.51,97.08 167.97,97.61 163.54,97.61 160.76,100.4 156.52,100.4 155.82,99.7 152.89,99.7 152.46,100.13 150.85,100.13 150.5,100.48 149.95,100.48 149.54,100.08 148.98,100.08 148.59,99.7 148.16,99.7 147.88,99.98 147.88,100.76 146.41,102.24 146.41,103.53 143.69,106.25 134.61,106.25 134.35,106.52 130.3,106.52 129.48,105.69 122.42,105.69 121.38,104.65 115.33,104.65 114.35,103.67 113.58,103.67 111.88,101.97 111.88,101.22 109.58,98.92 105.21,98.92 103.06,101.07 95.48,101.07 v2(95.27,100.85) ; v2(55.22,58.65) 55.22,58.99 57.48,61.25 73.24,61.25 73.95,60.53 v2(74.5,60.53) ; v2(102.44,16.13) 102.25,15.94 101.44,15.94 101.14,16.24 101.14,17.03 100.43,17.74 95,17.74 94.53,17.27 91.44,17.27 91.44,17.28 87.78,17.28 86.97,16.47 82.25,16.47 81.85,16.87 75.7,16.87 75.34,16.51 v2(75.34,16.49)
  BOTTOM w0.076: 162.03,97.41 156.56,97.41 156.44,97.3 155.95,97.3 155.83,97.18 155.83,96.9 155.55,96.62 154.56,96.62 154.21,96.98 UC1.P4
  BOTTOM w0.102: 162.03,97.41 163.39,97.41 164.73,96.07 170.01,96.07 v2(170.62,96.67)
DH_1.35V: length 6.7
  TOP w0.102: v4(68.38,32.17) v1(68.38,31.04)
  IN3 w0.762: 66.98,32.72 66.3,33.4 v4(61.68,33.4)
  vias: v4(61.27,32.74) v4(67.75,32.17)
DISPOFF#: length 9.9
  TOP w0.102: RX9.1 3.29,82.97 5.85,82.97 6.09,82.73 v2(6.09,82.22) 6.09,81.74 v1(6.42,81.41) 7.13,80.7 DV2.1
  BOTTOM w0.102: JEDP.4 4.21,82.45 4.56,82.1 5.96,82.1 v2(6.09,82.22)
DL_1.35V: length 4.2
  IN3 w0.762: v4(64.23,35.8) 64.05,35.98 60.7,35.98 60.3,35.59
  vias: v4(60.18,34.64) v4(64.23,35.17) v5(60.18,34.01)
DP_HPD: length 8.2
  TOP w0.102: v2(187.09,111.69) 188.54,111.69 189.32,110.9 Q2416.1 190.02,110.3 189.55,109.83 189.55,108.7 v1(189.68,108.57)
  BOTTOM w0.102: UV6.40 v2(187.09,111.69) 187.09,112.52 R2495.1
DPB_HPD: length 88.2
  TOP w0.102: QV5.3 192.53,57.95 RV18.1 191.98,58.02 191.7,58.3 191.7,62.11 187.89,65.92 v1(187.89,66.8) v2(187.89,67.59)
  IN1 w0.114: v2(187.89,67.59) 187.89,73.56 186.62,74.83 186.62,78.49 184.44,80.67 184.44,81.79 185.15,82.51 185.15,91.79 186.21,92.84 186.21,97.83 180.3,103.73 174.47,103.73 168.9,109.3 163.66,109.3 162.79,108.43 154.36,108.43 v2(154.08,108.16)
  BOTTOM w0.076: UC1.C8 151.6,103.79 151.84,104.04 152.17,104.04 152.53,104.4 152.53,104.58 152.71,104.76 152.71,105.91 153.09,106.29 154.11,107.3 154.11,108.13 v2(154.08,108.16)
DPC_HPD: length 44.9
  TOP w0.102: v2(185.48,111.5) 186.96,112.98 Q2416.3 ; v2(153.09,107.4) 153.35,107.4 v1(153.65,107.7) 153.65,108.36 RC84.2
  IN1 w0.114: v2(185.48,111.5) 185.46,111.48 181.82,111.48 181.04,112.26 178.62,112.26 178.24,111.88 178.24,110.61 177.17,109.54 163.56,109.54 162.93,108.92 154.16,108.92 153.62,108.38 153.62,107.93 v2(153.09,107.4)
  BOTTOM w0.076: v2(153.09,107.4) 153.09,107.12 151.79,105.82 151.79,105.36 151.6,105.17 UC1.A8
DSWODVREN: length 8.1
  TOP w0.102: R2337.1 153.09,76.56 153.6,77.07 153.6,78.23 R2338.1 v1(153.09,79.95) 153.09,80.32 v2(153.47,80.7)
  BOTTOM w0.076: v2(153.47,80.7) 153.09,80.7 152.31,81.47 152.31,82.71 UC1.AW7
EC_MUTE#: length 124.4
  TOP w0.102: RA6.1 180.32,13.79 v2(180.73,13.39) ; RC38.1 RA10.1 178.44,25.2 CA76.1 178.36,25.25 178.36,25.58 v1(177.68,26.26) 177.46,26.26 v2(176.85,26.86) ; v2(93.68,18.65) 93.75,18.57 UE4.3
  IN1 w0.114: v2(172.06,18.29) 172.37,18.6 172.37,22.97 176.27,26.86 v2(176.85,26.86)
  IN2 w0.135: v2(107.57,11.69) 107.57,11.56 108.87,10.26 113.09,10.26 117.84,5.51 168.45,5.51 173,10.06 v2(173.35,10.06)
  IN3 w0.135: v2(173.35,10.06) 173.35,10.28 172.95,10.67 172.95,17.35 172.06,18.24 v2(172.06,18.29)
  BOTTOM w0.102: v2(180.73,13.39) 179.9,12.56 175.85,12.56 v2(173.35,10.06) ; v2(107.57,11.69) 107.57,11.58 106.91,10.92 104.86,10.92 102.34,13.44 96.63,13.44 94.37,15.7 94.37,18.06 93.78,18.65 v2(93.68,18.65)
EDP_AUX: length 135.9
  TOP w0.102: C4321.2 10.65,97.96 10.88,97.96 v2(11.06,98.15)
  IN3 w0.135: v2(129.21,106.94) 129.03,106.75 128.56,106.75 127.36,105.55 122.3,105.55 121.87,105.99 120.51,105.99 119.06,107.44 119.06,108.41 118.55,108.92 113.89,108.92 111.68,111.13 101.71,111.13 100.66,110.09 97.27,110.09 94.1,106.91 86.86,106.91 84.03,104.08 82.49,104.08 82.08,104.49 80.28,104.49 78.91,103.12 71.05,103.12 70.26,102.33 66.97,102.33 65.26,104.04 63.38,104.04 61.8,105.62 59.97,105.62 58.04,107.55 28.72,107.55 23.91,102.74 17.82,102.74 13.05,97.97 11.24,97.97 v2(11.06,98.15)
  BOTTOM w0.076: UC1.B45 128.89,104.44 128.58,104.75 128.58,105.11 128.69,105.22 128.69,105.37 128.58,105.48 128.58,106.58 128.73,106.73 129.01,106.73 v2(129.21,106.94)
EDP_AUX#: length 136
  TOP w0.102: C4322.2 10.7,97.75 10.88,97.75 v2(11.06,97.56)
  IN3 w0.135: v2(129.21,106.35) 129.06,106.51 128.66,106.51 127.46,105.31 122.2,105.31 121.77,105.75 120.41,105.75 118.81,107.34 118.81,108.31 118.45,108.67 113.79,108.67 111.58,110.88 101.81,110.88 100.77,109.84 97.37,109.84 94.2,106.67 86.96,106.67 84.13,103.84 82.39,103.84 81.98,104.24 80.38,104.24 79.01,102.87 71.15,102.87 70.36,102.08 66.87,102.08 65.16,103.8 63.28,103.8 61.7,105.37 59.87,105.37 57.94,107.3 28.82,107.3 24.01,102.5 17.92,102.5 13.15,97.73 11.23,97.73 v2(11.06,97.56)
  BOTTOM w0.076: UC1.A45 128.78,104.88 128.78,104.78 128.92,104.64 129.08,104.64 129.19,104.75 129.19,105.11 128.75,105.55 128.75,106.51 128.8,106.57 129,106.57 v2(129.21,106.35)
EDP_AUX#_C: length 4.2
  TOP w0.102: v2(4.79,96.91) 4.95,97.07 5.16,97.07 5.43,97.34 5.43,97.61 5.54,97.72 5.64,97.72 5.92,97.44 LX10.3 6.46,97.44 RX37.2
  BOTTOM w0.102: JEDP.33 3.95,96.95 4.09,97.09 4.6,97.09 v2(4.79,96.91)
EDP_AUX#_R: length 2.2
  TOP w0.102: C4322.1 9.08,97.74 8.83,97.74 8.53,97.44 LX10.4 7.72,97.44 RX37.1
EDP_AUX_C: length 4.2
  TOP w0.102: RX36.2 6.46,98.24 LX10.2 5.87,98.24 5.57,97.95 5.46,97.95 5.21,97.7 5.21,97.42 5.07,97.28 4.99,97.28 v2(4.79,97.49)
  BOTTOM w0.102: v2(4.79,97.49) 4.6,97.31 4.01,97.31 3.86,97.45 JEDP.34
EDP_AUX_R: length 2.2
  TOP w0.102: RX36.1 7.72,98.24 LX10.1 8.53,98.24 8.83,97.95 9.1,97.95 C4321.1
EDP_BIA_PWM: length 410.9
  TOP w0.102: RC75.2 155.93,110.04 155.88,110.09 v2(155.88,110.09) 155.48,110.09 154.66,110.9 153.85,110.9 153.47,110.52 153.47,109.98 RC81.1 153.22,109.98 150.6,112.6 150.6,116.44 151.06,116.89 151.06,120.7 150.68,121.08 145.35,121.08 143.29,119.03 136.69,119.03 131.35,113.69 131.35,111.33 v1(131.01,110.99) 130.1,110.09 RC72.2 ; DV1.3 8.98,84.41 v2(8.88,84.51)
  IN1 w0.114: v2(155.88,110.09) 155.65,109.86 154.18,109.86 152.56,108.23 152.56,107.24 152.89,106.91 153.32,106.91 153.65,107.24 154.08,107.24 155,108.16 162.87,108.16 163.74,109.02 168.83,109.02 174.37,103.49 180.2,103.49 185.96,97.73 185.96,92.94 184.91,91.89 184.91,82.61 184.2,81.89 184.2,79.59 186.07,77.71 186.07,66.76 188.4,64.43 188.4,47.22 190.63,44.99 190.63,39.07 191.27,38.42 191.27,35.12 189.92,33.77 189.92,33.12 183.13,26.33 183.13,25.62 182.18,24.67 180.72,24.67 177.36,21.31 177.36,18.3 176.26,17.2 176.26,15.17 171.12,10.04 169.73,10.04 165.16,5.46 148.62,5.46 147.72,6.36 146.19,6.36 145.31,5.48 132.4,5.48 130.03,7.85 130.03,8.75 129.53,9.25 114.46,9.25 113.26,8.05 111.74,8.05 v2(110.98,8.82)
  IN3 w0.135: v2(8.88,84.51) 14.56,84.51 15.42,83.64 15.42,82.77 14.54,81.89 14.54,78.94 19.04,74.44 19.05,74.44 19.47,74.02 20.8,74.02 v2(20.98,73.84)
  BOTTOM w0.102: v2(20.98,73.84) 21.19,73.64 32.35,73.64 32.83,73.15 34.38,73.15 34.88,73.66 42.38,73.66 43.45,72.6 52.63,72.6 53.98,71.25 64.69,71.25 68.11,67.83 73.8,67.83 76.46,65.17 76.46,58.19 80.24,54.41 87.69,54.41 88.19,53.9 88.19,53.89 88.62,53.46 88.62,44.08 90.86,41.85 90.86,36.44 100.98,26.33 100.98,26.28 101.27,25.99 101.27,19.68 108.41,12.55 108.98,12.55 110.98,10.55 v2(110.98,8.82)
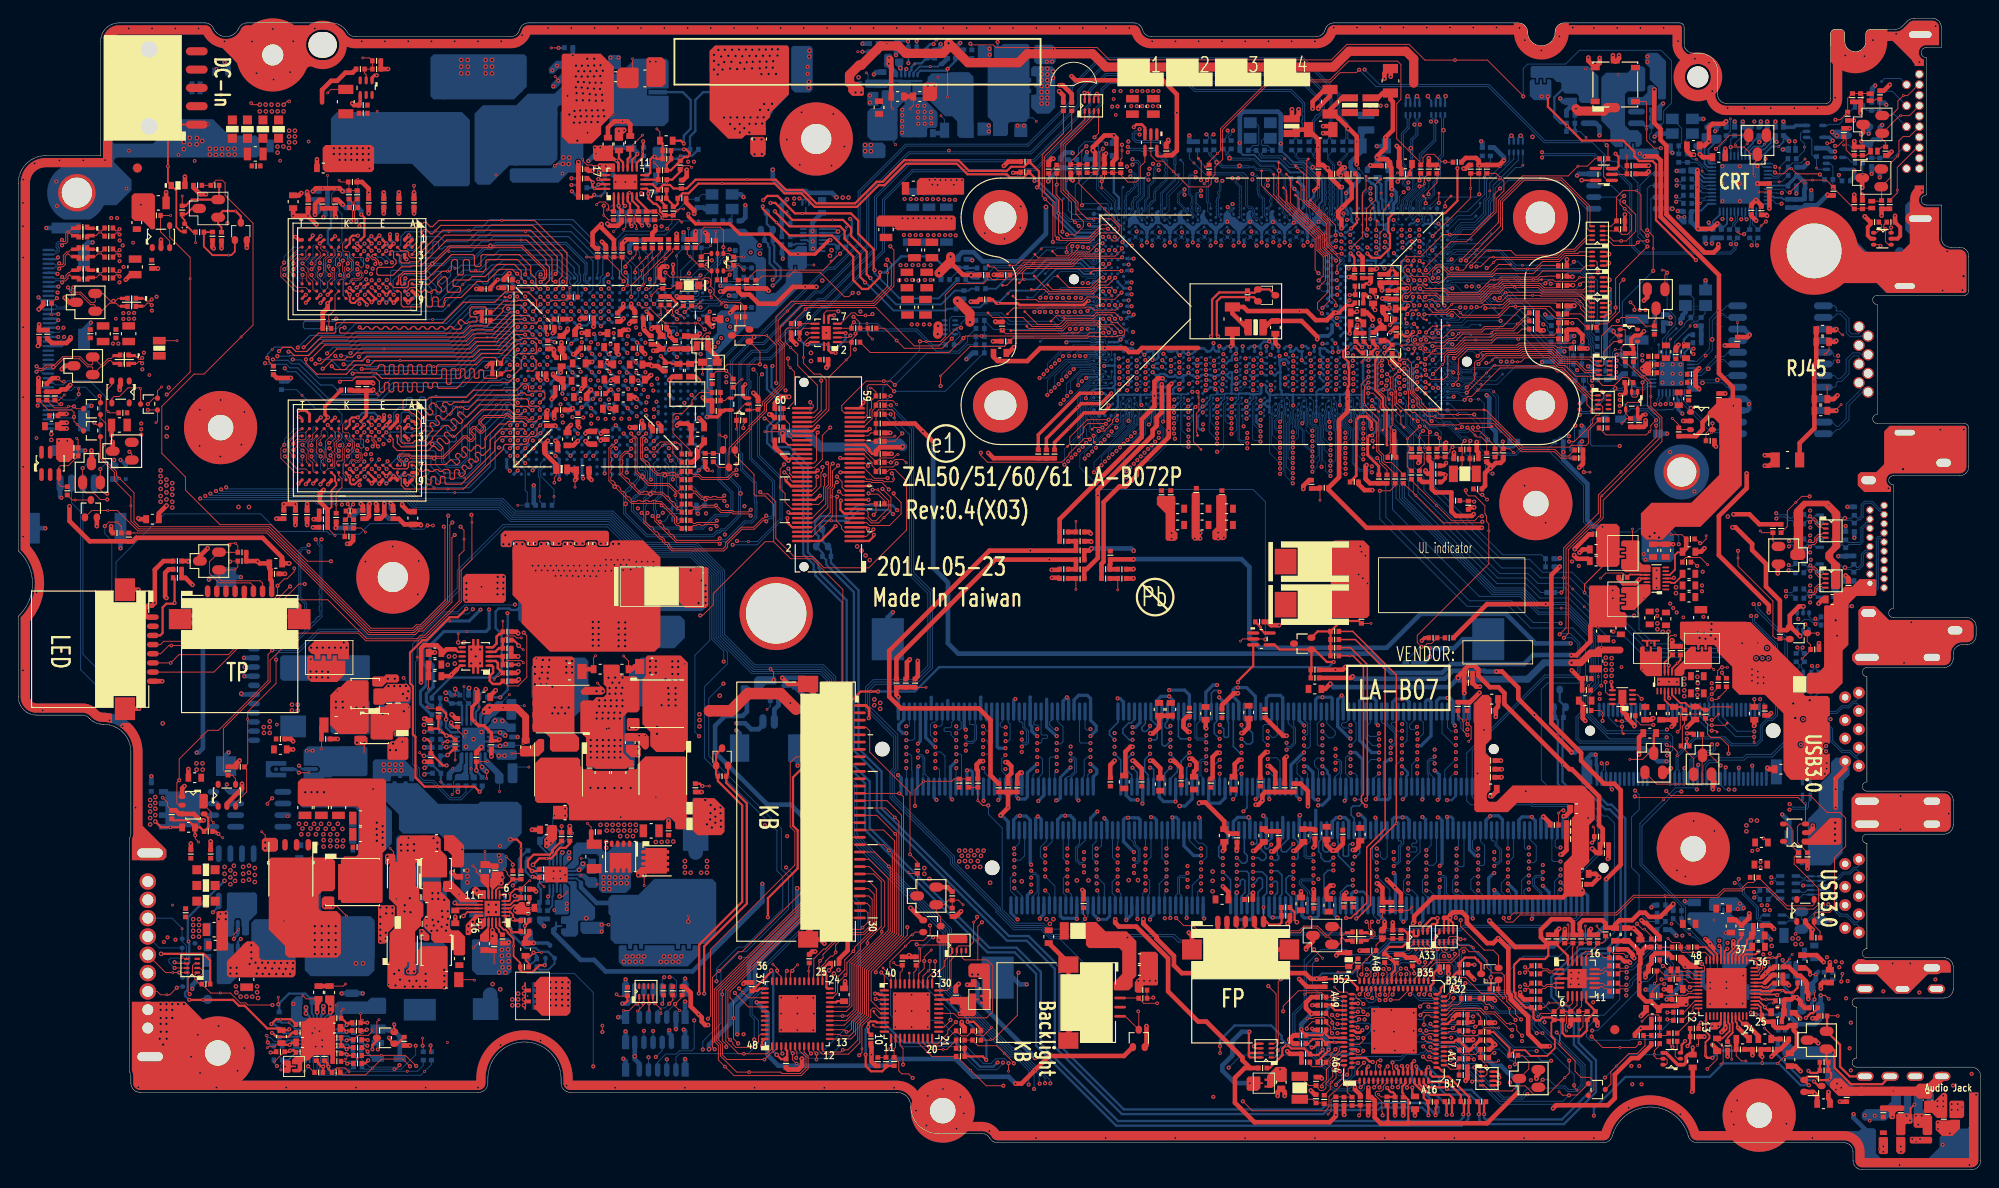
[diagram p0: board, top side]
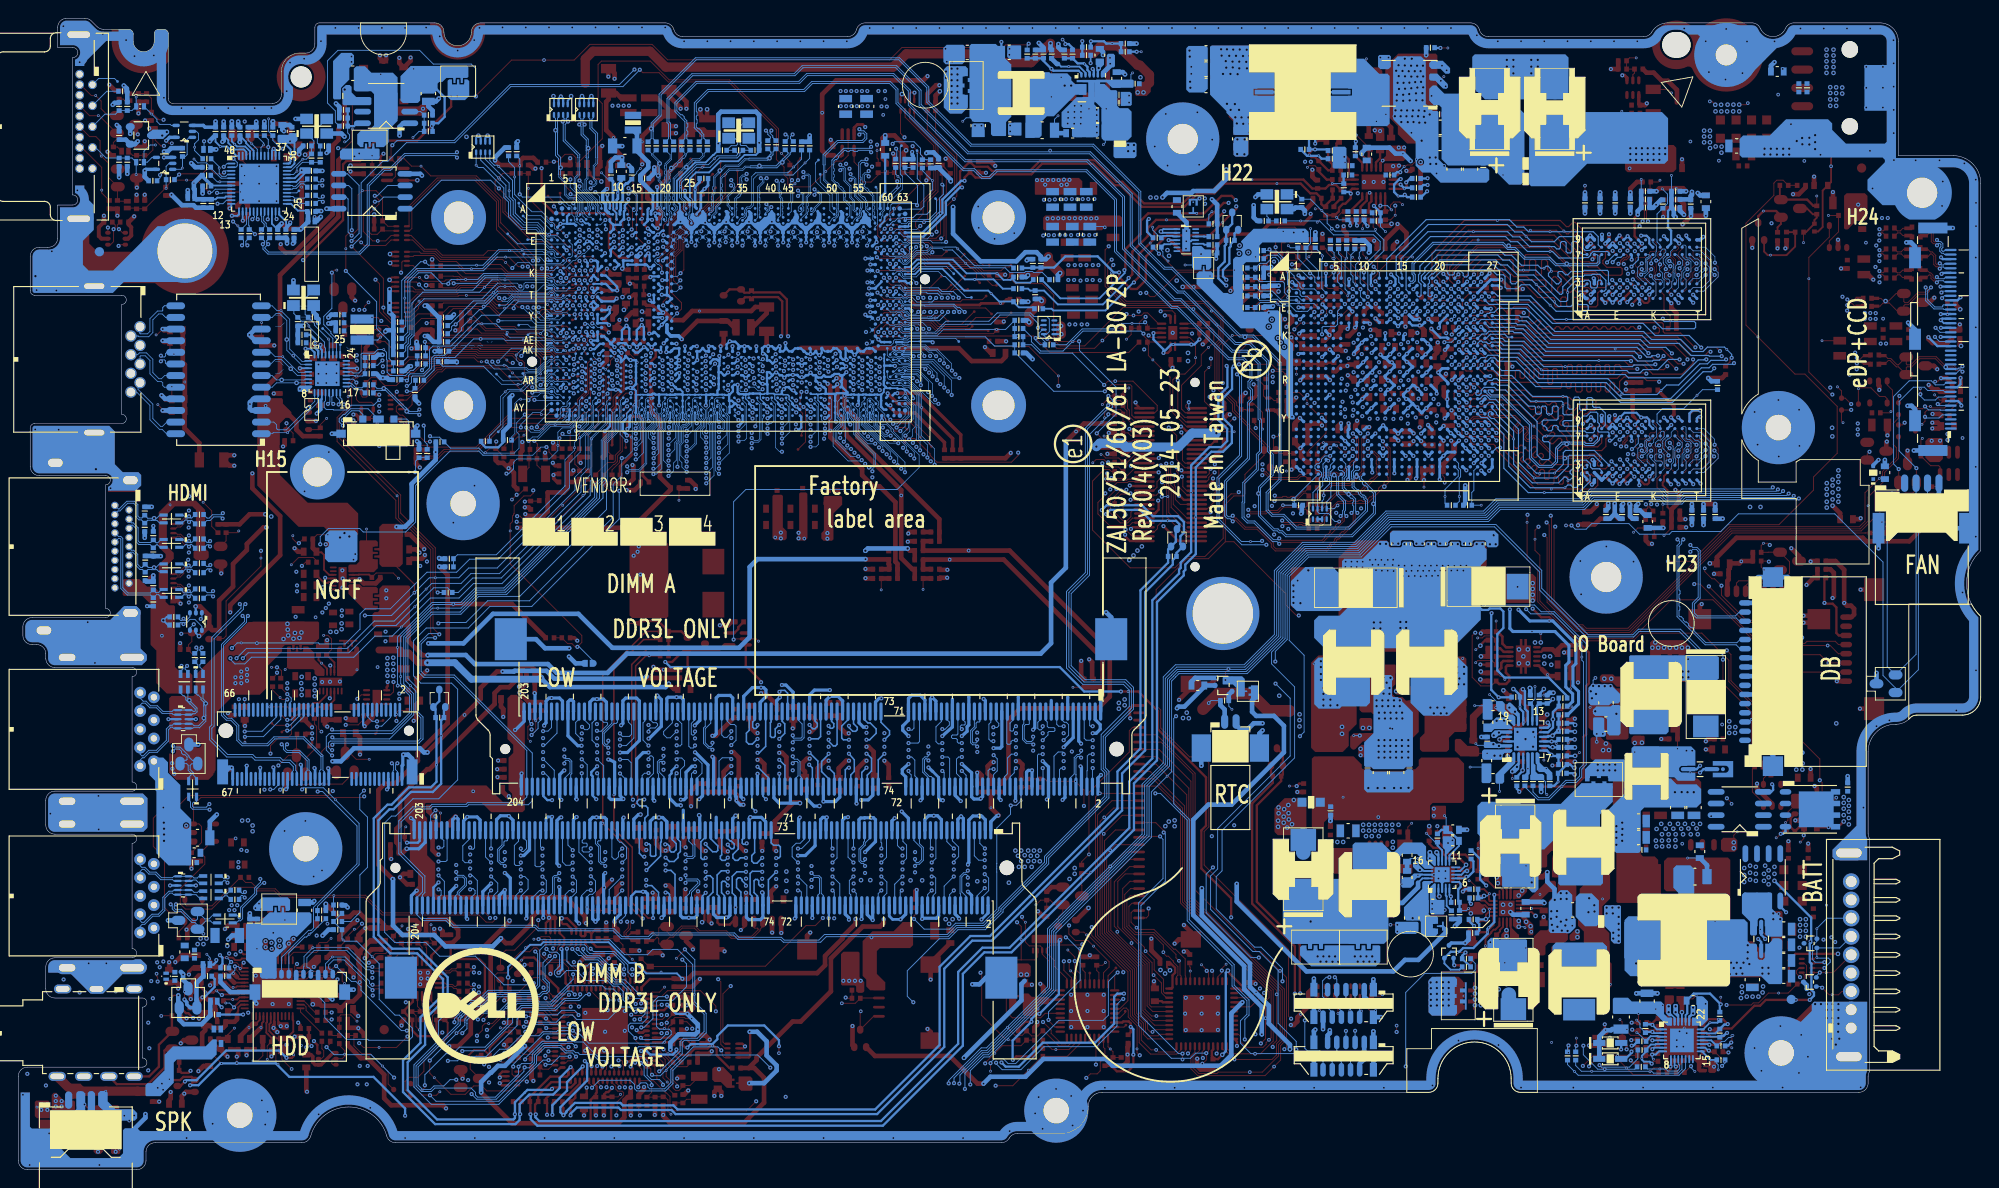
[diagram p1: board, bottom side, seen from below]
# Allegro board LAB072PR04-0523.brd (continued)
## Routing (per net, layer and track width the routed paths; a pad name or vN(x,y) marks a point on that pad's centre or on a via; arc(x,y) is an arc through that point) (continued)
EDP_BKLCTL: length 5.3
  TOP w0.102: RC81.2 153.09,108.69 v2(153.09,108.03)
  BOTTOM w0.076: UC1.B8 151.32,104.41 151.32,105.14 151.62,105.44 151.62,105.9 152.71,106.99 152.71,107.65 v2(153.09,108.03)
EDP_COMP: length 7.7
  TOP w0.508: v2(144.56,102.82) 144.56,103.74 144.2,104.09 144.2,104.65 v1(144.62,105.07) 145.67,106.12 145.67,107.62 145.14,108.16 RC71.2
  BOTTOM w0.254: v2(144.56,102.82) 144.75,102.82 UC1.D20
EDP_DISP_UTIL: length 4.6
  TOP w0.102: RC72.1 130.1,108.31 v2(129.87,108.08) 129.87,108 v1(129.54,107.67)
  BOTTOM w0.076: v2(129.87,108.08) 130,107.95 130,105.74 130.27,105.47 UC1.A43
EDP_TX0: length 136.4
  TOP w0.102: C4312.2 10.65,102.54 10.88,102.54 v2(11.06,102.72)
  IN3 w0.135: v2(128.63,108.97) 128.45,108.79 127.59,108.79 126.08,107.28 122.83,107.28 122.44,107.66 121.15,107.66 120.68,108.13 120.68,108.98 119.17,110.49 116.79,110.49 114.58,112.7 100.59,112.7 99.57,111.69 96.69,111.69 93.44,108.43 92.49,108.43 91.94,108.98 91.29,108.98 90.74,108.43 84.23,108.43 83.69,107.89 75.11,107.89 72.88,105.66 72.12,105.66 71.28,104.82 67.72,104.82 66.58,105.96 64.42,105.96 63.22,107.15 62.14,107.15 61.8,107.5 61.8,108.05 60.87,108.98 59.26,108.98 59.1,109.15 27.41,109.15 23.55,105.29 15.61,105.29 12.88,102.56 11.23,102.56 v2(11.06,102.72)
  BOTTOM w0.076: v2(128.63,108.97) 128.63,108.87 128.5,108.74 128.05,108.74 127.86,108.55 127.86,106.51 128.16,106.21 128.16,105.62 128.1,105.56 128.1,105.28 128.16,105.22 128.16,104.99 128.1,104.93 128.1,104.65 128.16,104.58 128.16,104.35 128.33,104.19 UC1.B46
EDP_TX0#: length 136.5
  TOP w0.102: v2(11.06,102.14) 10.88,102.32 10.7,102.32 C4311.2
  IN3 w0.135: v2(11.06,102.14) 11.24,102.31 12.98,102.31 15.71,105.04 23.65,105.04 27.51,108.9 59,108.9 59.16,108.74 60.77,108.74 61.56,107.95 61.56,107.39 62.04,106.91 63.12,106.91 64.32,105.72 66.48,105.72 67.62,104.57 71.38,104.57 72.22,105.41 72.98,105.41 75.21,107.65 83.79,107.65 84.33,108.19 90.84,108.19 91.39,108.74 91.84,108.74 92.38,108.19 93.54,108.19 96.79,111.44 99.67,111.44 100.69,112.46 114.48,112.46 116.69,110.25 119.07,110.25 120.44,108.88 120.44,108.03 121.05,107.42 122.34,107.42 122.72,107.04 126.18,107.04 127.69,108.55 128.47,108.55 v2(128.63,108.38)
  BOTTOM w0.076: v2(128.63,108.38) 128.44,108.57 128.11,108.57 128.02,108.48 128.02,106.58 128.33,106.28 128.33,104.42 128.89,103.86 UC1.C45
EDP_TX0#_C: length 5.8
  TOP w0.102: RX33.2 6.45,102.02 LX8.3 5.9,102.02 5.61,102.31 5.47,102.31 5.4,102.24 5.4,101.36 5.17,101.13 4.95,101.13 v2(4.77,100.96)
  BOTTOM w0.102: v2(4.77,100.96) 4.77,100.97 4.6,101.15 4.45,101.15 4.35,101.04 4.35,100.8 4.47,100.68 4.47,100.32 4.25,100.09 4.07,100.09 4.05,100.07 4.05,100.06 3.93,99.95 JEDP.39
EDP_TX0#_R: length 2.2
  TOP w0.102: RX33.1 7.66,102.02 LX8.4 8.5,102.02 8.79,102.31 9.08,102.31 C4311.1
EDP_TX0_C: length 5.8
  TOP w0.102: RX32.2 6.47,102.82 LX8.2 5.89,102.82 5.59,102.52 5.38,102.52 5.38,102.53 5.19,102.34 5.19,101.45 5.08,101.35 4.97,101.35 v2(4.77,101.55)
  BOTTOM w0.102: v2(4.77,101.55) 4.77,101.54 4.6,101.36 4.36,101.36 4.13,101.13 4.13,100.71 4.26,100.59 4.26,100.41 4.16,100.31 4.03,100.31 3.89,100.45 JEDP.40
EDP_TX0_R: length 2.2
  TOP w0.102: RX32.1 7.64,102.82 LX8.1 8.5,102.82 8.79,102.53 9.11,102.53 C4312.1
EDP_TX1: length 132.8
  TOP w0.102: v2(11.06,100.43) 10.88,100.25 10.65,100.25 C4314.2
  IN3 w0.135: v2(127.41,107.06) 127.21,106.86 126.91,106.86 126.45,106.41 122.56,106.41 122.1,106.86 120.78,106.86 119.84,107.8 119.84,108.7 118.81,109.73 114.91,109.73 112.73,111.91 100.92,111.91 99.88,110.87 96.97,110.87 93.77,107.67 84.87,107.67 83.84,106.65 81.12,106.65 80.53,106.06 80.53,105.82 78.67,103.95 70.28,103.95 70.17,103.85 67.53,103.85 66.55,104.83 63.76,104.83 62.21,106.38 60.35,106.38 58.35,108.38 28.48,108.38 24.59,104.5 16.97,104.5 12.72,100.24 11.25,100.24 v2(11.06,100.43)
  BOTTOM w0.076: v2(127.41,107.06) 127.23,106.88 126.98,106.88 126.66,106.57 126.66,105.6 127.31,104.96 127.31,104.83 127.33,104.8 127.33,104.76 UC1.B47
EDP_TX1#: length 132.7
  TOP w0.102: v2(11.06,99.85) 10.88,100.03 10.7,100.03 C4313.2
  IN3 w0.135: v2(127.41,106.48) 127.27,106.62 127.01,106.62 126.55,106.16 122.46,106.16 122,106.62 120.68,106.62 119.6,107.7 119.6,108.6 118.71,109.49 114.81,109.49 112.63,111.67 101.02,111.67 99.98,110.63 97.07,110.63 93.87,107.43 84.97,107.43 83.94,106.4 81.22,106.4 80.78,105.96 80.78,105.72 78.77,103.71 70.38,103.71 70.28,103.61 67.43,103.61 66.45,104.58 63.66,104.58 62.11,106.13 60.25,106.13 58.25,108.14 28.58,108.14 24.69,104.25 17.07,104.25 12.82,100 11.21,100 v2(11.06,99.85)
  BOTTOM w0.076: v2(127.41,106.48) 127.41,106.62 127.31,106.72 127.04,106.72 126.82,106.5 126.82,105.67 127.47,105.02 127.47,104.9 127.5,104.87 127.5,104.83 127.68,104.65 127.79,104.65 127.87,104.73 127.87,104.88 UC1.A47
EDP_TX1#_C: length 4.9
  TOP w0.102: RX35.2 6.44,99.73 LX9.3 5.76,99.73 5.47,100.02 5.38,100.02 5.13,99.77 5.13,98.86 4.88,98.62 4.68,98.62 v2(4.47,98.41)
  BOTTOM w0.102: JEDP.36 3.93,98.45 4.07,98.59 4.29,98.59 v2(4.47,98.41)
EDP_TX1#_R: length 2.2
  TOP w0.102: C4313.1 9.08,100.02 8.67,100.02 8.38,99.73 LX9.4 7.69,99.73 RX35.1
EDP_TX1_C: length 4.8
  TOP w0.102: v2(4.47,98.99) 4.63,98.83 4.79,98.83 4.91,98.95 4.91,99.85 5.29,100.24 5.5,100.24 5.79,100.53 LX9.2 6.44,100.53 RX34.2
  BOTTOM w0.102: v2(4.47,98.99) 4.29,98.81 4.07,98.81 3.93,98.95 JEDP.37
EDP_TX1_R: length 2.2
  TOP w0.102: RX34.1 7.69,100.53 LX9.1 8.41,100.53 8.7,100.24 9.1,100.24 C4314.1
EN_0.675VSP: length 5.7
  TOP w0.102: v1(57.45,30.89) 56.94,31.4 PC203.1
  TOP w0.254: v2(56.19,32) 56.41,32 56.49,31.91 PC203.1
  BOTTOM w0.203: v2(56.19,32) 56.37,31.82 PU200.7
  BOTTOM w0.254: PR202.2 55.43,33.68 55.43,32.57 56,32 v2(56.19,32)
EN_1.35V: length 8.3
  TOP w0.254: PR201.2 58.35,34.9 58.35,34.69 58.07,34.41 56.3,34.41 55.68,33.78 55.68,33.07 v5(56.13,32.62) 56.76,32.62 PC202.1
  BOTTOM w0.203: v5(56.13,32.62) 56.32,32.62 56.73,32.22 PU200.8
EN_+1.35DGPU: length 4.9
  TOP w0.102: PR1003.2 53.4,55.6 54.94,55.6 v1(55.17,55.37)
  TOP w0.279: PR1003.2 PC1005.1 PU1000.3
EN_INVPWR: length 216.6
  TOP w0.102: RE55.2 157.31,16.06 v2(156.72,15.47) 156.67,15.42 UE5.A25 ; QX1.2 8.04,72 v1(9.77,72) 10.83,72 13.06,69.76 27.26,69.76 38.35,58.68 43.28,58.68 43.66,59.06 44.13,59.06 47.15,62.08 47.15,70.41 v2(47.43,70.69)
  IN3 w0.135: v2(156.72,15.47) 156.08,15.47 154.49,17.06 153.87,17.06 153.62,16.82 153.62,16.69 153.37,16.44 150.32,16.44 148.7,18.06 147.96,18.06 146.99,19.03 146.99,19.36 146.58,19.77 144.93,19.77 144.59,20.11 143.04,20.11 142.55,19.62 137.78,19.62 136.5,20.91 128.94,20.91 127.37,22.48 101.88,22.48 101.21,21.81 98.5,21.81 97.91,22.41 97.91,24.02 84.82,37.1 84.82,43.02 84.04,43.8 84.04,45.59 82.39,47.24 82.39,51.68 88.78,58.06 88.78,64.49 86.31,66.96 76.37,66.96 73.63,69.7 67.19,69.7 66.28,70.61 49.27,70.61 48.71,71.17 47.9,71.17 v2(47.43,70.69)
ENVDD_PCH: length 383.3
  TOP w0.102: v2(154.06,106.55) 154.06,106.87 155,107.8 RC87.2 ; v1(15.65,85.5) 15.2,85.05 DV7.3 14.8,84.27 v2(14.15,83.62) ; UE5.A7 149.55,9.53 149.13,9.11 149.13,8.8 148.91,8.57 148.43,8.57 148.26,8.41 148.26,8.11 148.98,7.39 148.98,6.33 149.06,6.25 v2(149.06,5.93)
  IN1 w0.114: v2(130.56,7.95) 130.83,7.95 133,5.78 141.69,5.78 142.51,6.6 148.39,6.6 v2(149.06,5.93) 149.72,6.6 157.32,6.6 157.36,6.56 165.91,6.56 169.63,10.28 171.02,10.28 176.02,15.27 176.02,17.3 177.12,18.4 177.12,21.41 180.62,24.91 182.08,24.91 182.88,25.72 182.88,26.43 186.64,30.19 186.64,31.11 188.99,33.46 188.99,34.95 191.03,36.99 191.03,38.32 190.39,38.97 190.39,44.89 188.15,47.12 188.15,64.33 185.83,66.66 185.83,77.61 183.96,79.49 183.96,82 184.67,82.71 184.67,91.99 185.72,93.04 185.72,97.63 180.1,103.25 174.27,103.25 168.73,108.78 163.84,108.78 162.85,107.8 155.43,107.8 154.17,106.55 v2(154.06,106.55)
  IN3 w0.135: v2(14.15,83.62) 14.38,83.62 14.58,83.42 14.58,82.68 14.01,82.1 14.01,78.65 19.36,73.31 v2(19.87,73.31) ; v2(76.28,20.58) 76.28,19.92 77.91,18.29 79.67,18.29 81.93,16.03 87.53,16.03 88.92,14.64 93.26,14.64 94.87,13.03 95.66,13.03 96.35,12.35 104.02,12.35 105.83,14.16 113.99,14.16 117.7,10.45 124.06,10.45 126.64,7.87 130.48,7.87 v2(130.56,7.95)
  BOTTOM w0.076: v2(154.06,106.55) 153.96,106.44 153.53,106.44 152.91,105.82 152.91,104.65 152.72,104.46 152.72,104.15 UC1.C6
  BOTTOM w0.102: v2(76.28,20.58) 76.28,21.97 78.62,24.31 79.33,24.31 83.52,28.5 83.52,32.01 82.88,32.64 82.88,37.05 74.96,44.97 74.96,52.73 77.47,55.25 77.47,56.53 76,58 76,64.98 73.61,67.38 67.92,67.38 64.5,70.79 53.78,70.79 52.46,72.11 43.29,72.11 42.19,73.21 35.07,73.21 34.56,72.7 32.65,72.7 32.16,73.18 19.99,73.18 v2(19.87,73.31)
ENVDD_R: length 5.8
  TOP w0.102: UX1.4 10.22,84.21 10.46,84.44 11.04,84.44 11.99,85.4 13.26,85.4 v1(13.35,85.31) 13.36,85.31 13.36,83.62 DV7.1
EXPRESS_DET#: length 2.1
  TOP w0.102: UE4.40 95.34,21.18 T100.1
FAN1_PWM: length 6.7
  TOP w0.102: UE5.A24 156.19,14.92 156.34,15.06 157,15.06 157.1,15.17 RE58.1 157.99,14.63 159.34,14.63 RE48.2 160.2,15.5 v1(161.74,15.5)
FAN1_TACH: length 238.3
  TOP w0.102: UE5.B22 154.51,13.17 v2(154.28,13.39) ; v2(47.68,69.32) 47.38,69.01 47.38,61.98 44.22,58.83 43.76,58.83 43.38,58.45 38.25,58.45 27.16,69.53 12.63,69.53 12.62,69.55 RE50.2 CE24.1 11.24,70.27 v1(10.79,70.73) 9.9,70.73 v2(9.45,70.28)
  IN3 w0.135: v2(47.68,69.32) 47.85,69.48 65.88,69.48 66.71,68.65 73.2,68.65 77.19,64.66 77.19,57.91 80.93,54.17 80.93,47.22 82.99,45.16 82.99,43.37 83.78,42.58 83.78,37.51 83.19,36.93 83.19,36.18 90.38,28.99 90.38,28.01 98,20.39 99.88,20.39 100.65,19.62 110.61,19.62 111.2,20.2 120,20.2 120.86,21.06 125.99,21.06 127.99,19.05 134.55,19.05 135.33,18.27 139.18,18.27 139.94,17.52 142.36,17.52 142.42,17.58 144.49,17.58 144.91,17.17 144.91,16.52 145.47,15.96 145.47,15.1 145.75,14.83 146.56,14.83 146.57,14.82 147.13,14.82 147.76,14.19 148.99,14.19 149.16,14.02 153.12,14.02 153.19,13.95 153.75,13.95 154.16,13.54 154.16,13.52 v2(154.28,13.39)
  BOTTOM w0.102: v2(9.45,70.28) 9.45,69.46 10.22,68.7 10.22,54.96 DE3.3 7.06,56.28 JFAN.2
FB_1.35V: length 4.8
  BOTTOM w0.102: v1(55.96,28.53) 56.18,28.31 PR204.1
  BOTTOM w0.203: PU200.6 57.01,31.42 56.82,31.23
  BOTTOM w0.254: PR204.1 56.94,28.31 PR207.1 57.08,29.34 57.08,30.63 56.82,30.89 56.82,31.23
FB_3V: length 5.1
  TOP w0.203: PU100.4 53.74,28.94 54.2,29.39 54.59,29.39 PR109.2
  TOP w0.254: v4(54.26,29.9) 54.74,29.9 PR109.2
  BOTTOM w0.102: v1(53.67,30.14) 53.92,29.9 v4(54.26,29.9)
  BOTTOM w0.254: v4(54.26,29.9) 54.49,29.67 PC102.2 PR107.2
FB_5V: length 6.2
  TOP w0.203: PU100.2 53.27,28.14 53.76,28.14 54.06,27.84 v4(54.06,27.37)
  TOP w0.254: v4(54.06,27.37) 54.22,27.21 PR104.1
  BOTTOM w0.102: v1(53.67,28.45) 53.67,27.61 53.92,27.37 v4(54.06,27.37)
  BOTTOM w0.254: v4(54.06,27.37) 54.09,27.33 PC108.1 55,27.03 54.79,26.82 54.79,26.11 PR106.1
FB_+1.35DGPU: length 4.8
  TOP w0.102: PR1006.1 53.4,58.3 54.23,58.3 54.45,58.08 v1(54.96,58.08)
  TOP w0.279: PR1006.1 PR1007.1 52.51,56.95 52.12,56.56 PU1000.4
FB_CLAMP_GPU: length 2.7
  TOP w0.102: v2(72.8,93.68) 72.85,93.68 73.51,94.34 RV48.1 74.07,94.34 v1(74.5,94.77)
  BOTTOM w0.102: v2(72.8,93.68) 73.16,93.31 UV1.F3
FBA_CMD0: length 40.4
  TOP w0.076: UV18.L2 34.85,100.59 34.85,100.34 34.9,100.29 35.15,100.29 35.34,100.1 35.34,99.82 35.07,99.55 35.07,98.91 v2(35.04,98.88)
  IN1 w0.076: 34.54,94.2 34.4,94.34 34.4,96.99 34.77,97.36 34.77,97.9 35.12,98.24 35.12,98.8 v2(35.04,98.88)
  IN1 w0.114: 34.54,94.2 34.54,93.13 v2(34.73,92.94)
  BOTTOM w0.076: UV17.L2 34.59,96.37 34.59,97.21 34.76,97.38 34.76,97.92 35.11,98.27 35.11,98.81 v2(35.04,98.88)
  BOTTOM w0.127: v2(34.73,92.94) 34.73,92.79 34.57,92.64 31.3,92.64 31.14,92.48 31.14,92 31.3,91.85 34.78,91.85 35.79,92.86 v1(45.27,92.86) 46.61,92.86 49.17,95.43 52.79,95.43 53.13,95.77 UV1.C27
FBA_CMD1: length 1.2
  TOP w0.127: v2(53.71,95.35) 53.67,95.3 T110.1
  BOTTOM w0.127: UV1.C26 54.13,95.77 v2(53.71,95.35)
FBA_CMD2: length 46.5
  TOP w0.076: UV18.K1 35.42,101.16 35.42,100.49 35.62,100.29 36.06,100.29 36.19,100.16 36.19,99.63 36.6,99.22 36.6,98.37 36.05,97.82 v2(36.05,97.64)
  TOP w0.127: v2(37.29,92) 37.32,92 37.52,91.8 37.71,91.8 37.84,91.92 37.84,91.95 37.97,92.08 38.22,92.08 38.35,91.95 38.35,91.92 38.48,91.8 38.73,91.8 38.86,91.92 38.86,91.95 38.98,92.08 39.24,92.08 39.36,91.95 39.36,91.92 39.49,91.8 39.75,91.8 39.87,91.92 39.87,91.95 40,92.08 40.25,92.08 40.38,91.95 40.38,91.92 40.51,91.8 40.76,91.8 40.89,91.92 40.89,91.95 41.02,92.08 41.27,92.08 41.4,91.95 41.4,91.92 41.52,91.8 41.78,91.8 41.9,91.92 41.9,91.95 42.03,92.08 42.29,92.08 42.41,91.95 42.41,91.92 42.54,91.8 42.79,91.8 42.92,91.92 42.92,91.95 43.05,92.08 43.3,92.08 43.43,91.95 43.43,91.92 43.56,91.8 43.81,91.8 43.94,91.92 43.94,91.95 44.06,92.08 44.32,92.08 44.44,91.95 44.44,91.92 44.57,91.8 44.83,91.8 44.95,91.92 44.95,91.95 45.08,92.08 45.33,92.08 45.46,91.95 45.46,91.92 45.59,91.8 45.84,91.8 45.97,91.92 45.97,91.95 46.1,92.08 46.35,92.08 46.48,91.95 46.48,91.92 46.6,91.8 46.86,91.8 46.98,91.92 46.98,91.95 47.11,92.08 47.37,92.08 47.49,91.95 47.49,91.92 47.62,91.8 48.26,91.8 48.39,91.92 48.39,92.14 48.07,92.46 48.07,92.64 48.25,92.82 48.43,92.82 48.84,92.41 49.02,92.41 49.19,92.59 49.99,92.59 50.12,92.71 50.12,93.02 49.99,93.14 49.46,93.14 49.33,93.27 49.33,94.02 49.54,94.24 50.98,94.24 RV132.1 51.81,93.65 53.01,94.86 54.46,94.86 54.55,94.95 55.68,94.95 56.06,94.57 v2(56.18,94.57)
  IN1 w0.076: v2(36.05,97.64) 35.92,97.52 35.92,97.36 35.8,97.23 35.8,97.23 35.24,96.67 35.24,95.12 35.91,94.45 35.91,94.34
  IN1 w0.114: 35.91,94.34 35.91,93.88 36.29,93.5 36.29,93.29 36.82,92.75 36.82,91.61 37.04,91.4 37.04,90.86 37.44,90.46 37.44,90.31 37.58,90.17 37.72,90.17 37.86,90.31 37.86,91.43 v2(37.29,92)
  BOTTOM w0.076: v2(36.05,97.64) 35.88,97.48 35.88,97.32 35.48,96.92 35.48,95.48 UV17.K1
  BOTTOM w0.127: UV1.E24 55.76,94.15 v2(56.18,94.57)
FBA_CMD3: length 44.8
  TOP w0.076: v2(36,98.99) 36,98.89 35.62,98.51 35.62,98.19 35.69,98.12 35.69,97.39 35.49,97.18 35.49,95.48 UV18.K9
  TOP w0.127: v2(35.64,91.98) 35.23,91.98 35.11,91.85 35.11,91.49 35.23,91.37 48.58,91.37 49.37,92.15 51.24,92.15 51.57,92.48 RV118.1 51.97,92.76 52.94,93.73 52.94,94.09 53.28,94.42 54.91,94.42 55.36,93.97 v2(55.36,93.76)
  IN1 w0.076: v2(36,98.99) 35.55,98.53 35.55,98.22 35.52,98.19 35.52,97.85 35.52,97.85 35.52,97.55 34.81,96.85 34.81,95.13 34.81,95.13 34.81,94.94 35.22,94.53 35.22,94.36
  IN1 w0.114: v2(35.64,91.98) 35.64,90.35 35.93,90.06 35.93,89.96 35.98,89.91 35.98,89.91 36.25,89.64 36.61,89.64 36.76,89.79 36.76,90.17 36.35,90.58 36.35,91.11 36.13,91.33 36.13,92.32 35.51,92.94 35.51,93.3 35.22,93.59 35.22,94.36
  BOTTOM w0.076: v2(36,98.99) 36,99.34 35.72,99.63 35.68,99.63 35.49,99.82 35.49,100.23 35.42,100.3 35.42,100.88 35.81,101.28 UV17.K9
  BOTTOM w0.127: UV1.F24 55.76,93.36 v2(55.36,93.76)
FBA_CMD4: length 56.5
  TOP w0.076: v2(31.05,77.9) 31.01,77.87 UV19.T7 ; UV18.T7 31.01,97.68 v2(31.05,97.72)
  IN1 w0.114: v2(31.05,77.9) 31.63,78.49 31.63,79.96 31.03,80.56 31.03,80.56 30.7,80.89 30.7,81.42 30.18,81.94 30.18,85.75 30.6,86.17 30.6,89.72 v2(30.54,89.79) 30.51,89.77 30.18,89.77 30.02,89.93 30.02,90.5 30.34,90.81 30.34,91.01 30.16,91.19 29.95,91.19 29.75,90.99 29.61,90.99 29.46,91.14 29.46,91.49 29.6,91.63 29.63,91.63 29.77,91.77 29.77,92.01 29.63,92.15 29.6,92.15 29.46,92.29 29.46,92.53 29.6,92.67 29.63,92.67 29.77,92.81 29.77,93.05 29.63,93.19 29.6,93.19 29.46,93.33 29.46,95.46 29.79,95.79 29.79,96.05 30.64,96.9 30.64,97.08 31.05,97.49 v2(31.05,97.72)
  BOTTOM w0.076: v2(31.05,77.9) 30.46,78.49 30.46,79.67 30.69,79.9 30.69,80.12 30.77,80.2 30.95,80.2 UV20.T7 ; v2(31.05,97.72) 30.45,98.31 30.45,99.47 30.69,99.72 30.69,99.93 30.77,100.01 30.95,100.01 UV17.T7
  BOTTOM w0.127: UV1.D27 53.34,94.99 49.35,94.99 46.79,92.43 36.89,92.43 35.56,91.11 31.86,91.11 v2(30.54,89.79)
FBA_CMD5: length 67.9
  TOP w0.076: v2(29.09,78.54) 29.45,78.89 29.45,79.61 30.6,80.76 30.83,80.76 UV19.T2 ; UV18.T2 30.78,100.75 29.42,99.39 29.42,98.7 v2(29.07,98.35)
  TOP w0.127: v2(27.21,88.67) 27.39,88.5 27.39,88.24 RV114.1
  IN1 w0.114: v2(29.07,98.35) 28.86,98.35 27.04,96.53 27.04,88.84 v2(27.21,88.67) 27.39,88.5 27.39,81.4 29.45,79.33 29.45,78.9 v2(29.09,78.54)
  BOTTOM w0.076: v2(29.07,98.35) 28.69,97.97 28.69,97.51 30.25,95.95 UV17.T2 ; v2(29.09,78.54) 28.69,78.13 28.69,77.7 29.23,77.15 30.18,76.2 30.25,76.14 UV20.T2
  BOTTOM w0.127: UV1.D26 53.7,94.5 49.47,94.5 46.51,91.54 36.83,91.54 35.97,90.68 32.77,90.68 31.45,89.36 30.33,89.36 29.85,89.84 28,89.84 v1(27.74,89.59) 27.21,89.05 v2(27.21,88.67)
FBA_CMD6: length 61.8
  TOP w0.076: UV19.R3 31.81,79.94 31.42,79.56 30.58,79.56 30.45,79.42 30.45,79 v2(30.06,78.61) ; UV18.R3 31.81,99.75 31.42,99.37 30.58,99.37 30.45,99.24 30.45,98.74 v2(30.06,98.35)
  TOP w0.127: v2(28.48,89.41) 28.9,89.82 29.87,89.82 30.33,89.36 31.53,89.36 33.1,90.93 48.76,90.93 49.55,91.72 51.79,91.72 53.75,93.69 v2(54.54,93.69)
  IN1 w0.114: v2(30.06,78.61) 30.44,78.99 30.44,79.8 28.65,81.59 28.65,88.39 28.73,88.48 28.73,89.05 28.48,89.3 v2(28.48,89.41) 28.08,89.81 28.08,96.08 28.93,96.93 29.21,96.93 29.67,97.39 29.67,97.87 30.06,98.25 v2(30.06,98.35)
  BOTTOM w0.076: v2(30.06,98.35) 30.53,97.88 30.53,97.59 30.78,97.34 31.42,97.34 31.81,96.95 UV17.R3 ; UV20.R3 31.81,77.14 31.42,77.52 30.78,77.52 30.53,77.78 30.53,78.14 v2(30.06,78.61)
  BOTTOM w0.127: v2(54.54,93.69) 54.96,93.27 UV1.F25
FBA_CMD7: length 65.8
  TOP w0.076: UV19.R2 31.42,80.55 31.42,79.87 31.31,79.76 30.39,79.76 30.06,79.43 v2(30.06,79.3) ; UV18.R2 31.42,100.37 31.42,99.68 31.31,99.57 30.39,99.57 30.06,99.24 v2(30.06,98.99)
  IN1 w0.114: v2(30.06,98.99) 29.87,98.99 29.44,98.55 29.44,97.54 29.16,97.26 28.78,97.26 27.74,96.22 27.74,89.24 28.12,88.85 v2(28.3,88.85) 28.31,88.84 28.31,81.45 30.06,79.7 v2(30.06,79.3)
  BOTTOM w0.076: v2(30.06,98.99) 29.65,98.58 29.65,97.08 30.38,96.35 31.41,96.35 UV17.R2 ; v2(30.06,79.3) 29.68,78.92 29.68,77.24 30.38,76.54 31.41,76.54 UV20.R2
  BOTTOM w0.127: UV1.F26 53.91,93.53 53.7,93.53 53.58,93.64 53.15,93.64 52.72,94.07 49.65,94.07 46.69,91.11 37.01,91.11 36.15,90.25 32.95,90.25 31.63,88.93 29.72,88.93 29.65,88.85 v2(28.3,88.85)
FBA_CMD8: length 60.1
  TOP w0.076: UV19.P3 32.61,80.11 32.04,79.53 32.04,79.31 32.03,79.3 v2(32.03,79.12) ; v2(32.04,98.99) 32.04,99.35 32.61,99.92 UV18.P3
  TOP w0.127: v2(56.24,93.74) 56.62,94.12 56.62,94.95 55.71,95.86 53.17,95.86 52.05,94.74 48.62,94.74 46.38,92.51 34.83,92.51 34.68,92.36 34.68,91.52 34.52,91.37 32.8,91.37 31.25,89.82 v2(31.17,89.82)
  IN1 w0.114: v2(32.03,79.12) 32.03,79.17 31.96,79.25 31.96,79.26 31.91,79.31 31.91,79.98 31.04,80.85 31.04,83.21 30.95,83.31 30.95,89.59 v2(31.17,89.82) 30.89,90.1 30.89,90.94 30.13,91.71 30.13,93.72 29.84,94.01 29.84,95.34 30.13,95.63 30.13,96.09 30.84,96.8 30.84,96.97 31.43,97.56 31.43,98.38 v2(32.04,98.99)
  BOTTOM w0.076: v2(32.04,98.99) 32.04,98.89 32.42,98.51 32.42,98.31 32.65,98.08 32.65,97.38 32.75,97.28 32.75,96.89 UV17.P3 ; v2(32.03,79.12) 32.04,79.12 32.04,79.08 32.42,78.7 32.42,78.35 32.62,78.15 32.62,76.95 UV20.P3
  BOTTOM w0.127: v2(56.24,93.74) 56.56,93.41 UV1.F23
FBA_CMD9: length 57.9
  TOP w0.076: UV19.N3 33.41,80.12 33.03,79.74 33.03,79.27 v2(33,79.24) ; UV18.N3 33.41,99.93 32.95,99.47 v2(32.95,99.03)
  TOP w0.127: v2(57,92.86) 56.6,92.46 54.36,92.46 52.33,90.43 50.09,90.43 49.3,89.64 v1(39.93,89.64) 34.8,89.64 34.15,88.99 34.15,88.98 33.91,88.74 33.9,88.74 33.84,88.67 33.74,88.67 33.08,88.01 v2(32.47,88.01)
  IN1 w0.076: v2(33,79.24) 33.13,79.37 33.13,79.63 33.04,79.72 32.86,79.72 32.74,79.61 32.59,79.61 32.47,79.73 32.47,79.89 32.59,80.01 32.59,80.16 32.4,80.36
  IN1 w0.114: v2(32.95,99.03) 32.42,98.5 32.42,97.56 31.53,96.66 31.53,96.32 31.02,95.81 31.02,95.05 30.87,94.9 30.87,94.44 31.16,94.15 31.16,92.13 32.09,91.2 32.09,90.6 32.29,90.4 32.29,89.01 32.47,88.83 v2(32.47,88.01) 32.1,88.01 31.98,87.89 31.98,87.77 32.27,87.47 32.27,87.29 31.98,87 31.98,86.76 32.07,86.67 32.07,86.36 31.98,86.26 31.98,86.05 32.07,85.96 32.07,85.68 31.98,85.58 31.98,84.04 32.07,83.94 32.07,83.06 31.85,82.83 31.85,80.91 32.4,80.36
  BOTTOM w0.076: UV20.N3 33.35,76.99 33.35,77.69 33.41,77.74 33.41,78.57 33.41,78.57 33.41,78.8 33,79.2 v2(33,79.24) ; v2(32.95,99.03) 32.98,99.03 33.33,98.69 33.33,98.45 33.41,98.37 33.41,97.87 33.41,97.86 33.41,97.42 33.23,97.24 33.23,96.88 33.36,96.75 UV17.N3
  BOTTOM w0.127: v2(57,92.86) 57.4,92.47 UV1.G22
FBA_CMD10: length 65.4
  TOP w0.076: v2(31.05,98.99) 31.66,98.38 31.66,97.5 32.19,96.97 32.19,96.13 32.36,95.95 UV18.P8 ; UV19.P8 32.36,76.14 32.19,76.32 32.19,77.15 31.66,77.68 31.66,78.56 v2(31.05,79.17)
  TOP w0.127: v2(56.19,92.89) 55.79,93.29 53.97,93.29 51.97,91.29 49.73,91.29 48.94,90.5 33.3,90.5 31.73,88.93 30.15,88.93 29.75,89.33 v2(29.52,89.33)
  IN1 w0.114: v2(31.05,98.99) 30.44,98.38 30.44,97.56 30.22,97.34 30.22,97.2 28.77,95.75 28.77,90.86 29.34,90.29 29.34,89.52 v2(29.52,89.33) 29.54,89.31 29.54,87.23 29.34,87.02 29.34,81.82 29.9,81.26 29.9,81.1 30.98,80.02 30.98,79.29 30.99,79.28 30.99,79.23 v2(31.05,79.17)
  BOTTOM w0.076: UV17.P8 32.61,100.89 32.52,100.98 32.31,100.98 32.19,100.86 32.19,99.69 32.07,99.57 31.78,99.57 31.2,98.99 v2(31.05,98.99) ; UV20.P8 32.61,81.08 32.52,81.17 32.31,81.17 32.19,81.05 32.19,79.88 32.07,79.76 31.78,79.76 31.35,79.33 31.2,79.33 v2(31.05,79.17)
  BOTTOM w0.127: v2(56.19,92.89) 56.56,92.51 UV1.G23
FBA_CMD11: length 56.2
  TOP w0.076: v2(32.04,77.9) 32.04,77.72 32.61,77.15 UV19.P7 ; v2(32.04,97.72) 32.04,97.53 32.61,96.96 UV18.P7
  TOP w0.127: v2(32.03,88.5) 32.03,88.62 33.48,90.07 49.12,90.07 49.91,90.86 52.15,90.86 54.18,92.89 v2(55.31,92.89)
  IN1 w0.076: 32.31,80.16 32.31,79.64 32.62,79.33 32.62,78.48 v2(32.04,77.9)
  IN1 w0.114: v2(32.04,97.72) 31.84,97.51 31.84,97.38 31.33,96.87 31.33,96.57 30.74,95.99 30.74,95.3 30.52,95.09 30.52,94.3 30.81,94.01 30.81,91.99 31.74,91.06 31.74,90.46 31.94,90.26 31.94,88.53 32.03,88.45 31.63,88.04 31.63,83.89 31.73,83.8 31.73,83.1 31.64,83.01 31.64,80.83 32.31,80.16
  IN1 w0.14: 32.03,88.45 v2(32.03,88.5)
  BOTTOM w0.076: v2(32.04,97.72) 31.66,98.1 31.66,99.16 31.87,99.37 32.25,99.37 32.61,99.73 UV17.P7 ; v2(32.04,77.9) 31.66,78.29 31.66,79 31.65,79.01 31.65,79.33 31.66,79.34 31.66,79.34 31.87,79.56 32.25,79.56 32.61,79.92 UV20.P7
  BOTTOM w0.127: v2(55.31,92.89) 55.73,92.47 UV1.G24
FBA_CMD12: length 55.4
  TOP w0.076: UV18.M2 34.6,100.36 34.6,99.88 34.02,99.3 v2(34.02,99.25) ; v2(33.96,79.38) 33.99,79.38 34.04,79.43 34.14,79.43 34.67,79.95 34.67,80.48 UV19.M2
  IN1 w0.076: 32.21,94.08 32.21,96.36 33.41,97.56 33.41,98.74 33.92,99.25 v2(34.02,99.25)
  IN1 w0.114: v2(33.96,79.38) 33.96,79.45 33.96,79.46 33.96,79.85 32.46,81.36 32.46,82.41 33.1,83.06 33.1,86.67 33.71,87.28 33.71,88.95 33.74,88.98 v2(33.74,89.16) 33.76,89.16 33.32,89.6 33.32,90.83 33.15,90.99 33.15,91.59 32.21,92.53 32.21,94.08
  BOTTOM w0.076: UV20.M2 33.79,76.56 33.79,77.06 33.56,77.29 33.56,77.6 33.61,77.66 33.61,78.65 33.61,78.66 33.61,79 33.96,79.35 v2(33.96,79.38) ; UV17.M2 33.74,96.42 33.74,96.98 33.61,97.11 33.61,97.95 33.61,97.95 33.61,98.46 33.53,98.54 33.53,98.86 33.53,98.86 33.53,98.87 33.75,99.09 33.76,99.09 33.92,99.24 33.93,99.24 33.93,99.25 v2(34.02,99.25)
  BOTTOM w0.127: UV1.F27 53.34,93.3 50.4,93.3 50.25,93.14 49.46,93.14 47,90.68 37.19,90.68 36.33,89.82 34.4,89.82 v2(33.74,89.16)
FBA_CMD13: length 52.2
  TOP w0.076: UV18.L3 35.01,99.82 34.67,99.47 34.67,98.74 35.11,98.3 35.11,97.76 v2(35.16,97.71) ; UV19.L3 35.01,79.86 34.52,79.37 34.52,78.49 34.83,78.18 34.83,78.09 v2(35.01,77.9)
  IN1 w0.076: 34.88,94.26 34.88,94.52 34.62,94.77 34.62,96.93 35.16,97.47 v2(35.16,97.71)
  IN1 w0.114: 34.88,94.26 34.88,93.45 35.16,93.17 35.16,90.35 35.59,89.91 35.59,89.82 35.64,89.77 35.64,89.77 36.22,89.18 v2(36.3,89.18) 36.35,89.13 36.35,87.43 36.03,87.11 36.03,85.85 35.25,85.07 35.25,83.2 35.4,83.05 35.4,79.89 35.72,79.57 35.72,78.8 35.62,78.7 35.62,78.51 v2(35.01,77.9)
  BOTTOM w0.076: UV20.L3 34.92,76.94 34.79,77.07 34.79,77.27 34.92,77.4 35.48,77.4 35.61,77.52 35.61,78.04 35.48,78.17 35.14,78.17 35.01,78.04 v2(35.01,77.9) ; UV17.L3 34.92,96.75 34.79,96.88 34.79,97.08 34.92,97.21 35.48,97.21 35.61,97.34 35.61,97.67 35.57,97.71 v2(35.16,97.71)
  BOTTOM w0.127: v2(36.3,89.18) 37.37,90.25 47.18,90.25 49.64,92.71 50.42,92.71 50.58,92.86 53.34,92.86 53.34,92.86 54.58,92.86 54.96,92.47 UV1.G25
FBA_CMD14: length 49.9
  TOP w0.076: UV19.M7 34.36,77.09 34.36,77.7 34.11,77.94 34.11,78.01 v2(34.11,78.01) ; v2(34.4,98.36) 34.58,98.19 34.58,97.26 34.21,96.9 UV18.M7
  IN1 w0.076: v2(34.11,78.01) 34.11,78.01 34.11,77.99 34.6,78.48 34.6,78.77 34.75,78.92 34.75,79.26 34.78,79.28 34.78,80.06
  IN1 w0.114: v2(34.4,98.36) 34.4,98.1 34.37,98.07 34.37,97.85 34.37,97.85 34.37,97.53 34.15,97.31 34.14,97.31 33.41,96.57 33.41,92.89 34.26,92.04 34.26,91.46 34.44,91.28 34.44,90.1 34.9,89.63 34.9,89.26 v2(35.26,88.9) 35.04,88.69 35.04,87.19 34.22,86.37 34.22,80.62 34.78,80.06
  BOTTOM w0.076: UV20.M7 34.21,80.14 34.79,79.57 34.79,79.34 34.73,79.28 34.73,78.8 34.63,78.7 34.63,78.69 34.11,78.18 34.11,78.01 v2(34.11,78.01) ; UV17.M7 34.22,99.95 34.69,99.48 34.69,99.09 34.67,99.06 34.67,98.98 34.4,98.72 v2(34.4,98.36)
  BOTTOM w0.127: UV1.G27 53.33,92.43 50.76,92.43 50.6,92.28 49.82,92.28 47.36,89.82 37.55,89.82 36.48,88.75 36.05,88.75 35.92,88.88 35.89,88.9 v2(35.26,88.9)
FBA_CMD15: length 49.8
  TOP w0.076: UV18.K3 35.97,99.79 35.97,99.56 36.39,99.13 36.39,98.47 36.28,98.35 v2(36,98.35) ; v2(36,78.54) 36.28,78.54 36.45,78.7 36.45,78.78 36.52,78.86 36.52,79.34 36.31,79.56 36.16,79.56 36.1,79.62 36.08,79.62 35.81,79.89 UV19.K3
  IN1 w0.076: v2(36,98.35) 35.69,98.04 35.69,97.41 35.04,96.75 35.04,95.04 35.56,94.51 35.56,94.41
  IN1 w0.114: v2(36,78.54) 36.01,78.53 36.04,78.53 36.5,79 36.5,79.01 36.51,79.02 36.51,79.33 36.5,79.33 36.5,79.36 35.81,80.06 35.81,82.62 36,82.81 36,84.85 37.04,85.89 37.04,88.6 v2(37.22,88.78) 37.1,88.89 37.1,90.31 36.69,90.72 36.69,91.25 36.48,91.47 36.48,92.46 35.92,93.02 35.92,93.38 35.56,93.73 35.56,94.41
  BOTTOM w0.076: v2(36,98.35) 36,98.26 36.71,97.55 36.71,97.41 36.05,96.75 UV17.K3 ; UV20.K3 36.05,76.94 36.45,77.34 36.45,78.02 36,78.46 v2(36,78.54)
  BOTTOM w0.127: UV1.G26 53.7,92 50.94,92 50.78,91.85 50,91.85 47.54,89.38 37.82,89.38 v2(37.22,88.78)
FBA_CMD16: length 47.5
  TOP w0.076: v2(35.03,78.51) 34.88,78.67 34.88,78.81 34.73,78.96 34.73,79.28 35.34,79.89 35.34,80.29 35.01,80.61 UV19.L2
  TOP w0.127: v2(35.13,86.06) 35.26,86.18 36.48,86.18 36.89,86.59 38.94,86.59 39.45,86.08 39.45,85.07 39.6,84.91 39.84,84.91 40,85.07 40,85.85 40.12,85.98 40.38,85.98 40.51,85.85 40.51,85.09 40.65,84.94 40.86,84.94 41.01,85.09 41.01,85.85 41.14,85.98 41.39,85.98 41.52,85.85 41.52,85.11 41.67,84.97 41.88,84.97 42.03,85.11 42.03,85.85 42.16,85.98 42.41,85.98 42.54,85.85 42.54,85.09 42.69,84.94 42.9,84.94 43.05,85.09 43.05,85.85 43.17,85.98 43.43,85.98 43.55,85.85 43.55,85.09 43.71,84.94 44.11,84.94 44.26,85.09 44.26,85.85 44.39,85.98 44.64,85.98 44.77,85.85 44.77,85.47 44.89,85.35 45.15,85.35 45.28,85.47 45.28,85.85 45.4,85.98 45.66,85.98 45.78,85.85 45.78,85.47 45.91,85.35 47.91,85.35 48.56,86 53.61,86 54.16,86.54 54.16,86.79 54.94,87.58 54.94,88.38 v2(55.3,88.73)
  IN1 w0.114: v2(35.03,78.51) 35.25,78.73 35.3,78.73 35.51,78.94 35.51,79.48 35.19,79.8 35.19,82.3 35.19,82.3 35.19,82.78 34.9,83.07 34.9,85.83 v2(35.13,86.06)
  BOTTOM w0.076: v2(35.03,78.51) 34.59,78.07 34.59,76.56 UV20.L2
  BOTTOM w0.127: UV1.M24 55.72,88.31 v2(55.3,88.73)
FBA_CMD17: length 3
  TOP w0.127: v2(56.15,88.71) 56.26,88.71 56.57,88.39 56.57,87.58 56.21,87.23 T183.1
  BOTTOM w0.127: v2(56.15,88.71) 56.55,88.31 UV1.M23
FBA_CMD18: length 49.6
  TOP w0.076: v2(36,77.9) 36.65,78.55 36.65,78.7 36.73,78.78 36.73,79.43 36.19,79.96 36.19,80.35 36.06,80.48 35.62,80.48 35.42,80.68 35.42,81.35 UV19.K1
  TOP w0.127: v2(55.34,90.36) 55.18,90.2 54.55,90.2 52.92,88.57 52.92,88.27 RV117.1 52.07,88.7 50.8,88.7 50.02,87.91 45.85,87.91 45.7,87.76 45.7,87.02 45.55,86.87 45.32,86.87 45.17,87.02 45.17,87.78 45.04,87.91 44.73,87.91 44.61,87.78 44.61,87.02 44.48,86.9 44.23,86.9 44.1,87.02 44.1,87.79 43.98,87.91 43.71,87.91 43.59,87.79 43.59,87.02 43.46,86.9 43.21,86.9 43.08,87.02 43.08,87.79 42.96,87.91 42.7,87.91 42.57,87.79 42.57,87.02 42.45,86.9 42.19,86.9 42.07,87.02 42.07,87.79 41.94,87.91 41.68,87.91 41.56,87.79 41.56,87.02 41.43,86.9 41.18,86.9 41.05,87.02 41.05,87.81 40.95,87.91 40.64,87.91 40.54,87.81 40.54,87.02 40.42,86.9 40.16,86.9 40.03,87.02 40.03,87.76 39.88,87.91 39.48,87.91 39.32,87.76 39.32,87.58 39.2,87.45 v2(37.52,87.45)
  IN1 w0.114: v2(36,77.9) 36,77.95 36.6,78.54 36.6,78.78 36.71,78.9 36.71,79.45 36.02,80.15 36.02,82.52 36.34,82.84 36.34,84.7 37.38,85.75 37.38,87.31 v2(37.52,87.45)
  BOTTOM w0.076: UV20.K1 35.48,75.67 35.48,77.11 36,77.63 v2(36,77.9)
  BOTTOM w0.127: UV1.K24 55.71,89.99 v2(55.34,90.36)
FBA_CMD19: length 50.2
  TOP w0.076: UV19.K9 35.74,75.41 35.74,75.75 35.49,76 35.49,77.07 35.61,77.2 35.61,78.69 35.82,78.9 35.82,78.99 36,79.17 v2(36.13,79.17)
  TOP w0.127: v2(36.53,86.95) 36.61,87.02 39.12,87.02 39.72,86.43 46.14,86.43 46.26,86.56 46.26,87.36 46.39,87.48 46.65,87.48 46.77,87.36 46.77,85.9 46.9,85.78 47.16,85.78 47.28,85.9 47.28,87.38 47.38,87.48 47.69,87.48 47.79,87.38 47.79,86.56 47.91,86.43 48.17,86.43 48.3,86.56 48.3,87.36 48.42,87.48 48.68,87.48 48.8,87.36 48.8,86.56 48.93,86.43 49.18,86.43 49.31,86.56 49.31,87.36 49.44,87.48 49.7,87.48 49.82,87.36 49.82,86.56 49.95,86.43 50.2,86.43 50.33,86.56 50.33,87.23 50.45,87.35 50.71,87.35 50.84,87.23 50.84,86.56 50.96,86.43 52.22,86.43 RV119.1 52.94,86.92 53.27,87.25 53.8,87.25 54.08,87.53 54.08,88.65 54.56,89.13 56.44,89.13 56.59,89.28 56.59,90.22 56.43,90.38 v2(56.16,90.38)
  IN1 w0.114: v2(36.13,79.17) 36.13,79.44 35.6,79.97 35.6,82.79 35.7,82.89 35.7,82.95 35.69,82.96 35.69,83.21 35.59,83.31 35.59,84.92 36.4,85.74 36.4,86.82 v2(36.53,86.95)
  BOTTOM w0.076: UV20.K9 35.81,81.4 35.42,81.01 35.42,80.04 35.72,79.73 35.72,79.45 36,79.17 v2(36.13,79.17)
  BOTTOM w0.127: UV1.K23 56.56,89.99 v2(56.16,90.38)
FBA_CMD20: length 59
  TOP w0.076: v2(30.06,97.72) 29.65,98.13 29.65,99.24 30.36,99.95 UV18.T3 ; v2(30.08,77.94) 29.65,78.36 29.65,79.52 30.27,80.14 UV19.T3
  IN1 w0.114: v2(30.08,77.94) 30.64,78.5 30.64,79.98 29.63,80.99 29.63,81.07 28.99,81.7 28.99,87.41 v2(29.11,87.53) 29.11,89.18 28.99,89.3 28.99,90.15 28.43,90.71 28.43,95.94 29.1,96.61 29.28,96.61 29.93,97.26 29.93,97.58 v2(30.06,97.72)
  BOTTOM w0.076: v2(30.08,77.94) 31.01,77 UV20.T3 ; v2(30.06,97.72) 31.01,96.76 UV17.T3
  BOTTOM w0.127: UV1.M27 52.33,87.28 50.36,87.28 48.62,85.53 41.09,85.53 39.35,83.8 33.68,83.8 30.33,87.15 29.44,87.15 29.11,87.48 v2(29.11,87.53)
FBA_CMD21: length 68
  TOP w0.076: UV18.T8 30.29,95.95 28.69,97.56 28.69,98.61 29.04,98.96 v2(29.04,99.06) ; v2(29.07,79.17) 28.69,78.79 28.69,77.7 30.24,76.14 UV19.T8
  IN1 w0.114: v2(29.07,79.17) 26.95,81.29 v2(26.95,88.09) 26.7,88.34 26.7,96.73 v2(29.04,99.06)
  BOTTOM w0.076: UV17.T8 30.07,100.75 29.04,99.72 v2(29.04,99.06) ; v2(29.07,79.17) 29.07,79.78 30.23,80.94 UV20.T8
  BOTTOM w0.127: UV1.M26 53.91,88.31 53.56,88.67 53.11,88.67 52.73,88.29 50.77,88.29 48.44,85.96 40.91,85.96 39.17,84.23 33.86,84.23 30.51,87.58 29.67,87.58 29.29,87.96 27.08,87.96 v2(26.95,88.09)
FBA_CMD22: length 68.8
  TOP w0.076: v2(29.13,77.9) 30.51,76.52 31.43,76.52 UV19.R8 ; v2(29.07,97.72) 30.45,96.33 31.43,96.33 UV18.R8
  IN1 w0.114: v2(29.13,77.9) 29.67,78.44 29.67,79.61 27.82,81.46 v2(27.82,88.5) 27.82,88.67 27.39,89.11 27.39,96.39 28.71,97.72 v2(29.07,97.72)
  BOTTOM w0.076: UV20.R8 31.41,80.54 30.58,80.54 29.47,79.43 29.47,78.25 v2(29.13,77.9) ; v2(29.07,97.72) 29.45,98.1 29.45,99.22 30.58,100.35 31.41,100.35 UV17.R8
  BOTTOM w0.127: v2(27.82,88.5) 27.92,88.39 29.47,88.39 29.85,88.01 30.69,88.01 33,85.7 34.32,85.7 v1(34.93,85.09) 35.36,84.66 38.99,84.66 40.73,86.39 48.26,86.39 50.59,88.72 52.53,88.72 52.76,88.95 53.83,88.95 54.08,88.7 54.57,88.7 UV1.M25
FBA_CMD23: length 57.4
  TOP w0.076: v2(31.05,78.54) 31.45,78.13 31.45,77.29 UV19.R7 ; UV18.R7 31.45,97.11 31.45,97.94 v2(31.05,98.35)
  IN1 w0.114: v2(31.05,98.35) 30.66,97.97 30.66,97.44 30.43,97.21 30.43,97.06 29.44,96.07 29.44,95.94 29.11,95.61 29.11,91 29.68,90.43 29.68,89.78 30.04,89.42 30.04,88.56 v2(29.98,88.5) 29.98,87.1 30.26,86.81 30.26,86.31 29.84,85.89 29.84,81.8 30.38,81.26 30.38,80.92 31.43,79.87 31.43,78.92 v2(31.05,78.54)
  BOTTOM w0.076: UV17.R7 31.69,99.95 31.21,99.47 30.91,99.47 30.65,99.21 30.65,98.74 v2(31.05,98.35) ; UV20.R7 31.69,80.14 31.21,79.66 30.91,79.66 30.67,79.42 30.67,78.92 v2(31.05,78.54)
  BOTTOM w0.127: v2(29.98,88.5) 30.2,88.5 30.26,88.45 30.87,88.45 32.82,86.49 38.49,86.49 38.84,86.84 48.1,86.84 50.43,89.18 52.38,89.18 52.71,89.52 53.69,89.52 54.16,89.99 UV1.K26
FBA_CMD24: length 62.4
  TOP w0.076: UV19.P2 32.61,80.75 32.14,80.27 32.14,79.92 31.65,79.44 31.65,78.96 32.04,78.57 v2(32.04,78.54) ; v2(32.04,98.35) 32.41,98.73 32.41,98.82 32.42,98.83 32.42,99.23 32.99,99.8 32.99,100.18 32.61,100.56 UV18.P2
  TOP w0.127: v2(31.42,88.5) 31.42,88.09 32.63,86.89 35.83,86.89 36.83,87.89 38.46,87.89 38.92,88.34 49.84,88.34 50.63,89.13 52.86,89.13 54.36,90.63 54.89,90.63 55.06,90.8 56.61,90.8 v2(57,90.41)
  IN1 w0.076: 32.11,80.07 32.11,79.55 32.41,79.25 32.41,78.91 v2(32.04,78.54)
  IN1 w0.114: 32.11,80.07 31.44,80.74 31.44,81.76 31.39,81.82 31.39,83.44 31.29,83.54 31.29,88.36 v2(31.42,88.5) 31.39,88.53 31.39,89.37 31.6,89.59 31.6,90.12 31.4,90.32 31.4,90.92 30.47,91.85 30.47,93.86 30.18,94.16 30.18,95.16 30.43,95.42 30.43,96.09 31.12,96.78 31.12,96.96 31.63,97.47 31.63,97.94 v2(32.04,98.35)
  BOTTOM w0.076: UV17.P2 32.19,96.37 32.19,97.2 32.45,97.46 32.45,97.94 v2(32.04,98.35) ; v2(32.04,78.54) 32.04,78.45 32.42,78.06 32.42,77.62 32.19,77.39 32.19,76.56 UV20.P2
  BOTTOM w0.127: v2(57,90.41) 57.4,90.01 UV1.K22
FBA_CMD25: length 59.3
  TOP w0.076: v2(33.03,77.9) 32.59,78.34 32.59,79.66 33.09,80.15 33.09,80.61 UV19.N2 ; UV18.N2 33.29,100.87 33.14,100.87 33.01,100.74 33.01,100.62 33.28,100.35 33.62,100.35 33.81,100.15 33.81,99.89 33.33,99.41 33.33,98.95 33.33,98.95 33.33,98.01 v2(33.03,97.72)
  TOP w0.127: v2(33.25,87.48) 33.33,87.48 34.29,88.45 35.59,88.45 35.89,88.75 36.48,88.75 36.94,89.21 49.48,89.21 50.27,89.99 52.5,89.99 54.12,91.6 55.79,91.6 v2(56.19,91.21)
  IN1 w0.076: 31.84,94.1 32.01,94.26 32.01,96.44 33.03,97.46 v2(33.03,97.72)
  IN1 w0.114: v2(33.03,77.9) 33.58,78.46 33.58,79.75 32.25,81.08 32.25,82.62 32.76,83.12 32.76,86.81 33.25,87.3 v2(33.25,87.48) 33.25,87.58 33.33,87.66 33.33,89 32.97,89.36 32.97,90.69 32.77,90.89 32.77,91.49 31.84,92.42 31.84,94.1
  BOTTOM w0.076: UV20.N2 33.03,76.52 v2(33.03,77.9) ; v2(33.03,97.72) 33.03,96.33 UV17.N2
  BOTTOM w0.127: v2(56.19,91.21) 56.56,90.83 UV1.J23
FBA_CMD26: length 54.9
  TOP w0.076: UV18.M3 33.88,99.62 33.83,99.62 33.53,99.32 33.53,98.86 33.53,98.86 33.53,98.21 33.99,97.75 v2(33.99,97.69) ; v2(33.94,77.46) 33.94,77.53 33.61,77.85 33.61,78.65 33.56,78.71 33.56,79.56 34.13,80.14 UV19.M3
  IN1 w0.076: v2(33.94,77.46) 33.73,77.67 33.73,78.15 33.97,78.39 34.1,78.39 34.37,78.66 34.37,78.89 34.53,79.05 34.53,79.08 34.55,79.1 34.55,79.89 34.55,79.89 34.55,79.94 34.46,80.02
  IN1 w0.114: v2(33.99,97.69) 33.99,97.61 33.99,97.61 33.99,97.55 32.63,96.19 32.63,94.51 32.9,94.24 32.9,92.89 33.91,91.87 33.91,91.32 34.09,91.14 34.09,89.96 34.56,89.49 34.56,88.96 v2(34.64,88.87) 34.63,88.87 34.7,88.8 34.7,87.3 33.79,86.38 33.79,82.78 33.44,82.43 33.44,81.05 34.46,80.02
  BOTTOM w0.076: v2(33.99,97.69) 33.99,97.84 34.14,97.98 34.43,97.98 34.56,97.85 34.56,97.47 34.36,97.27 34.11,97.27 33.97,97.14 33.97,96.87 34.09,96.75 UV17.M3 ; UV20.M3 34.39,77.12 34.39,77.43 34.31,77.52 34,77.52 v2(33.94,77.46)
  BOTTOM w0.127: UV1.J25 54.48,91.27 54.02,91.27 53.72,91.57 51.11,91.57 50.96,91.42 50.18,91.42 47.69,88.93 38.08,88.93 37.47,88.32 35.87,88.32 35.78,88.41 35.11,88.41 v2(34.64,88.87)
FBA_CMD27: length 59
  TOP w0.076: UV18.N8 33.81,96.35 33.81,96.95 34.38,97.52 34.38,97.85 34.02,98.2 34.02,98.22 33.91,98.33 33.91,98.67 v2(33.91,98.67) ; v2(33.99,78.79) 33.99,78.76 34.29,78.45 34.29,78.36 34.57,78.08 34.57,76.84 34.35,76.61 33.89,76.61 UV19.N8
  TOP w0.127: v2(55.36,91.21) 54.33,91.21 52.68,89.56 50.45,89.56 49.66,88.78 38.05,88.78 37.62,88.34 36.68,88.34 35.72,87.38 34.62,87.38 v2(34.24,87.76)
  IN1 w0.076: 32.55,94.2 32.41,94.34 32.41,96.27 33.61,97.47 33.61,98.38 v2(33.91,98.67)
  IN1 w0.114: v2(33.99,78.79) 33.99,78.82 34.36,79.18 34.36,79.8 32.66,81.5 32.66,82.32 32.92,82.58 33.08,82.58 33.44,82.95 33.44,86.52 34.22,87.3 34.22,87.73 v2(34.24,87.76) 34.22,87.78 34.22,89.33 33.72,89.83 33.72,91.02 33.53,91.21 33.53,91.76 32.55,92.74 32.55,94.2
  BOTTOM w0.076: v2(33.99,78.79) 33.99,78.82 34.17,78.82 34.45,79.09 34.45,79.56 34.19,79.81 34.08,79.81 33.81,80.08 33.81,80.54 UV20.N8 ; v2(33.91,98.67) 33.99,98.67 34.4,99.09 34.4,99.41 34.18,99.63 34.07,99.63 33.89,99.82 33.89,100.28 UV17.N8
  BOTTOM w0.127: UV1.J24 55.76,90.81 v2(55.36,91.21)
FBA_CMD28: length 53
  TOP w0.076: v2(32.9,98.44) 32.82,98.37 32.82,98.14 32.65,97.97 32.65,97.56 33.41,96.79 UV18.N7 ; UV19.N7 33.12,77.23 33.12,77.45 33.41,77.74 33.41,78.36 33.23,78.54 v2(33.02,78.54)
  IN1 w0.076: 31.5,94.16 31.81,94.46 31.81,96.53 32.65,97.37 32.65,98.19 v2(32.9,98.44)
  IN1 w0.114: 31.5,94.16 31.5,92.28 32.43,91.35 32.43,90.75 32.63,90.55 32.63,89.15 32.9,88.88 v2(32.9,88.5) 32.9,87.84 32.82,87.76 32.82,87.36 32.41,86.95 32.41,83.1 32.05,82.73 32.05,81 33.38,79.67 33.38,78.7 33.22,78.54 v2(33.02,78.54)
  BOTTOM w0.076: UV17.N7 33.21,99.95 32.57,99.31 32.57,98.81 32.82,98.56 32.82,98.52 v2(32.9,98.44) ; UV20.N7 32.89,79.62 32.84,79.62 32.62,79.4 32.62,79.03 32.65,79 32.65,78.92 33.02,78.54 v2(33.02,78.54)
  BOTTOM w0.127: UV1.K27 52.68,89.99 52.3,89.61 50.26,89.61 v1(48,87.36) 47.92,87.28 38.66,87.28 38.41,87.02 37.22,87.02 36.86,87.38 35.26,87.38 34.14,88.5 v2(32.9,88.5)
FBA_CMD29: length 59.3
  TOP w0.076: v2(35.13,79.1) 35.33,79.3 35.49,79.3 35.59,79.2 35.59,78.96 35.42,78.79 35.42,78.78 35.4,78.76 35.4,77.55 35.28,77.42 34.88,77.42 34.78,77.32 34.78,77.09 34.93,76.94 UV19.L7 ; UV18.L7 35.01,96.99 35.51,97.5 35.51,98.01 35.42,98.1 35.42,98.6 35.45,98.63 v2(35.45,99.29)
  IN1 w0.076: v2(35.45,99.29) 34.89,99.29 34.67,99.06 34.67,98.7 34.78,98.58 34.78,98.2 34.57,97.99 34.57,97.45 34.19,97.07 34.19,94.26
  IN1 w0.114: v2(35.13,79.1) 34.99,79.25 34.99,80.47 34.91,80.54 34.6,80.54 34.52,80.62 34.52,80.87 34.6,80.95 34.91,80.95 34.99,81.02 34.99,81.28 34.91,81.35 34.6,81.35 34.52,81.43 34.52,81.68 34.6,81.76 34.91,81.76 34.99,81.84 34.99,82.21 34.99,82.21 34.99,82.43 34.57,82.84 34.57,86.2 34.86,86.49 35.56,86.49 35.69,86.62 35.69,86.77 35.39,87.07 35.39,87.35 35.51,87.48 35.87,87.48 36.01,87.62 36.01,87.85 35.87,87.99 35.56,87.99 v2(35.54,87.96) 35.54,88.5 35.69,88.65 35.69,89.23 35.3,89.62 35.3,89.63 35.25,89.68 35.25,89.77 34.78,90.24 34.78,91.42 34.75,91.45 34.75,92.15 34.19,92.71 34.19,94.26
  BOTTOM w0.076: UV20.L7 35.01,80.49 34.85,80.65 34.67,80.65 34.57,80.55 34.57,80.07 34.96,79.68 35.24,79.68 35.54,79.38 35.54,79.06 35.43,78.96 35.28,78.96 v2(35.13,79.1) ; UV17.L7 35.01,100.29 34.75,100.55 34.53,100.55 34.4,100.43 34.4,100.23 34.61,100.02 34.61,99.85 35.17,99.29 v2(35.45,99.29)
  BOTTOM w0.127: v2(35.54,87.96) 35.62,87.89 37.88,87.89 38.05,87.71 v1(45.39,87.71) 47.74,87.71 50.08,90.05 52.12,90.05 52.46,90.39 53.47,90.39 53.62,90.23 53.83,90.23 53.99,90.39 54.41,90.39 54.54,90.51 54.7,90.51 54.96,90.25 UV1.K25
FBA_CMD30: length 53
  TOP w0.076: UV18.J3 36.61,99.74 36.74,99.62 37.63,99.62 37.72,99.53 37.72,98.71 37.59,98.58 37.36,98.58 37.03,98.91 v2(37.03,98.99) ; UV19.J3 36.61,79.93 36.74,79.8 37.63,79.8 37.72,79.72 37.72,78.92 37.61,78.82 37.39,78.82 v2(37.09,79.12)
  IN1 w0.076: 36.25,94.39 35.44,95.2 35.44,96.59 35.88,97.04 36.12,97.04 36.4,97.32 36.4,98.36 v2(37.03,98.99)
  IN1 w0.114: 36.25,94.39 36.25,94.02 36.71,93.56 36.71,93.4 38.31,91.8 38.31,88.42 v2(38.21,88.32) 38.21,87.82 38.34,87.68 39.26,87.68 39.4,87.54 39.4,87.35 39.26,87.21 38.34,87.21 38.21,87.07 38.21,86.09 36.68,84.56 36.68,82.88 36.22,82.42 36.22,80.23 37.09,79.37 v2(37.09,79.12)
  BOTTOM w0.076: v2(37.03,98.99) 37.48,98.54 37.48,97.58 36.88,96.98 36.84,96.98 UV17.J3 ; UV20.J3 36.84,77.17 36.88,77.17 37.46,77.75 37.46,78.75 v2(37.09,79.12)
  BOTTOM w0.127: UV1.J27 52.26,90.79 51.94,90.48 49.9,90.48 47.79,88.37 v1(41.71,88.37) 38.26,88.37 v2(38.21,88.32)
FBA_CMD31: length 3.3
  BOTTOM w0.127: T184.1 51.69,90.93 52,91.24 53.57,91.24 54.03,90.79 54.03,90.79 UV1.J26
FBA_D0: length 31.8
  TOP w0.102: UV18.H3 v2(37.78,100.32)
  IN1 w0.14: v2(37.78,100.32) 37.78,100.22 38.05,99.96 40.52,99.96 41.6,98.87 42.9,98.87 43.04,99.01 43.04,99.66 43.18,99.8 43.42,99.8 43.56,99.66 43.56,99.01 43.7,98.87 49.57,98.87 51.54,100.84 57.89,100.84 60.75,97.99 60.75,95.18 60.39,94.82 v2(60.39,94.59)
  BOTTOM w0.127: UV1.E18 60.74,94.23 v2(60.39,94.59)
FBA_D1: length 32.5
  TOP w0.127: UV18.E3 40.21,100.35 v2(40.21,100.35)
  IN1 w0.14: v2(60.4,93.75) 61.14,94.49 61.14,98.35 58.16,101.34 51.48,101.34 50.33,100.19 46.91,100.19 46.77,100.05 46.77,99.56 46.64,99.42 46.39,99.42 46.25,99.56 46.25,100.05 46.11,100.19 45.7,100.19 45.56,100.05 45.56,99.53 45.42,99.39 45.18,99.39 45.04,99.53 45.04,100.05 44.9,100.19 44.66,100.19 44.52,100.05 44.52,99.53 44.38,99.39 44.14,99.39 44,99.53 44,100.05 43.86,100.19 40.83,100.19 40.68,100.35 v2(40.21,100.35)
  BOTTOM w0.127: UV1.F18 60.74,93.4 v2(60.4,93.75)
FBA_D2: length 33.9
  TOP w0.127: v2(38.59,100.38) UV18.G2
  IN1 w0.14: v2(38.59,100.38) 38.66,100.38 39.02,100.74 39.02,102.39 39.45,102.82 58.98,102.82 63.05,98.76 63.05,96.27 62.29,95.51 62.29,94.88 v2(62,94.59)
  BOTTOM w0.127: v2(62,94.59) 62.42,94.17 UV1.E16
FBA_D3: length 33.7
  TOP w0.127: v2(39.41,100.38) 39.41,100.38 39.04,100.75 UV18.F2
  IN1 w0.14: v2(39.41,100.38) 39.41,100.44 39.7,100.74 41.03,100.74 41.18,100.59 43.09,100.59 43.23,100.73 43.23,101.18 43.37,101.32 43.61,101.32 43.75,101.18 43.75,100.73 43.89,100.59 44.13,100.59 44.27,100.73 44.27,101.18 44.41,101.32 44.65,101.32 44.79,101.18 44.79,100.73 44.93,100.59 45.17,100.59 45.31,100.73 45.31,101.18 45.45,101.32 45.69,101.32 45.83,101.18 45.83,100.73 45.97,100.59 50.17,100.59 51.4,101.82 58.31,101.82 61.55,98.58 61.55,94.06 v2(61.26,93.77)
  BOTTOM w0.102: UV1.F17 61.58,93.45 v2(61.26,93.77)
FBA_D4: length 29.6
  TOP w0.127: v2(39.44,96.35) 39.03,96.75 UV18.F7
  IN1 w0.14: v2(39.44,96.35) 39.65,96.35 40.06,95.94 40.76,95.94 40.91,96.09 40.91,96.33 41.05,96.47 41.29,96.47 41.43,96.33 41.43,96.19 41.59,96.03 41.86,96.03 42,96.17 42,96.28 42.14,96.42 42.38,96.42 42.52,96.28 42.52,96.17 42.66,96.03 42.9,96.03 43.04,96.17 43.04,96.28 43.18,96.42 43.42,96.42 43.56,96.28 43.56,96.17 43.7,96.03 44.23,96.03 44.43,96.23 48.49,96.23 48.65,96.08 48.65,95.67 48.8,95.52 48.99,95.52 49.13,95.66 49.13,95.99 49.28,96.14 49.5,96.14 49.65,95.99 49.65,95.66 49.79,95.52 50.73,95.52 51.08,95.88 51.08,97.71 52.48,99.11 56.9,99.11 58.22,97.79 58.22,97.53 58.35,97.4 58.92,97.4 59.09,97.23 59.09,95.74 v2(58.7,95.35)
  BOTTOM w0.127: UV1.D20 59.09,94.97 v2(58.7,95.35)
FBA_D5: length 28.1
  TOP w0.127: v2(36.96,96.35) 36.96,96.35 37.36,96.75 UV18.H7
  IN1 w0.14: v2(57.87,95.36) 57.47,95.76 56.77,95.76 56.65,95.89 56.65,96.6 56.54,96.7 56.54,97.67 55.88,98.33 52.81,98.33 51.87,97.39 51.87,95.55 51.05,94.73 43.34,94.73 42.88,94.27 40.03,94.27 39.81,94.48 39.81,94.84 39.56,95.09 39.28,95.09 38.75,95.61 38.56,95.61 38.18,95.99 37.32,95.99 v2(36.96,96.35)
  BOTTOM w0.127: v2(57.87,95.36) 58.26,94.97 UV1.D21
FBA_D6: length 31.9
  TOP w0.127: UV18.F8 v2(38.61,96.35)
  IN1 w0.14: v2(58.68,93.72) 58.27,94.13 58.27,96.8 57.55,97.53 57.55,97.91 56.74,98.72 52.65,98.72 51.48,97.55 51.48,95.71 50.89,95.13 48.38,95.13 48.24,95.26 48.24,95.6 48.1,95.73 47.86,95.73 47.72,95.6 47.72,95.26 47.58,95.13 47.34,95.13 47.2,95.26 47.2,95.6 47.06,95.73 46.82,95.73 46.68,95.6 46.68,95.26 46.54,95.13 46.3,95.13 46.16,95.26 46.16,95.6 46.02,95.73 45.78,95.73 45.64,95.6 45.64,95.26 45.5,95.13 45.25,95.13 45.11,95.26 45.11,95.6 44.98,95.73 44.73,95.73 44.59,95.6 44.59,95.26 44.45,95.13 40.09,95.13 39.82,95.39 39.82,95.71 39.83,95.71 39.58,95.96 39.01,95.96 v2(38.61,96.35)
  BOTTOM w0.127: UV1.F20 59.07,93.33 v2(58.68,93.72)
FBA_D7: length 30.1
  TOP w0.127: v2(37.04,95.53) 37.04,95.55 37.41,95.93 UV18.H8
  IN1 w0.14: v2(57.84,93.73) 57.45,94.11 56.9,94.11 56.65,94.36 56.65,94.77 54.89,96.52 53.4,96.52 51.01,94.13 49.15,94.13 48.49,93.47 45.08,93.47 44.94,93.61 44.94,94.12 44.8,94.26 44.56,94.26 44.42,94.12 44.42,93.61 44.28,93.47 43.97,93.47 43.83,93.61 43.83,94.13 43.67,94.29 43.46,94.29 43.31,94.13 43.31,93.61 43.17,93.47 42.92,93.47 42.79,93.61 42.79,93.72 42.65,93.86 42.4,93.86 42.26,93.72 42.26,93.61 42.12,93.47 41.88,93.47 41.74,93.61 41.74,93.72 41.6,93.86 41.36,93.86 41.22,93.72 41.22,93.61 41.08,93.47 40.84,93.47 40.7,93.61 40.7,93.72 40.56,93.86 40.32,93.86 40.18,93.72 40.18,93.61 40.04,93.47 39.3,93.47 39,93.77 39,94.98 38.84,95.14 37.36,95.14 37.04,95.46 v2(37.04,95.53)
  BOTTOM w0.127: v2(57.84,93.73) 58.26,94.15 UV1.E21
FBA_D8: length 33.2
  IN3 w0.165: v2(37.86,95.55) 38.69,95.55 39.09,95.95 40.79,95.95 40.88,96.04 43.74,96.04 44.15,95.63 44.71,95.63 45.99,96.91 46.99,96.91 47.13,97.05 47.13,97.8 47.3,97.97 47.64,97.97 47.8,97.8 47.8,97.13 47.96,96.98 48.32,96.98 48.48,97.13 48.48,97.8 48.64,97.97 48.98,97.97 49.15,97.8 49.15,97.61 49.31,97.45 49.66,97.45 49.82,97.61 49.82,97.72 49.97,97.87 50.34,97.87 50.5,97.72 50.5,97.61 50.66,97.45 50.96,97.45 52.33,98.82 59.03,98.82 60.53,97.31 60.53,96.29 61.76,95.06 62.29,95.06 v2(62.81,94.54)
  BOTTOM w0.127: v2(37.86,95.55) 38.21,95.9 UV17.G2 ; v2(62.81,94.54) 63.18,94.17 UV1.E15
FBA_D9: length 32
  IN3 w0.165: v2(62.82,95.39) 62.66,95.39 62.54,95.51 61.91,95.51 60.95,96.47 60.95,97.63 59.29,99.29 51.37,99.29 51.21,99.13 51.21,98.29 51.04,98.12 50.7,98.12 50.53,98.29 50.53,99.13 50.37,99.29 50.04,99.29 49.17,98.41 46.9,98.41 44.96,96.48 41.55,96.48 41.54,96.5 40.74,96.5 40.49,96.75 38.33,96.75 38.01,97.08 v2(38.01,97.23)
  BOTTOM w0.127: v2(62.82,95.39) 63.22,94.99 UV1.D15 ; v2(38.01,97.23) 37.89,97.23 UV17.H3
FBA_D10: length 33.4
  IN3 w0.165: v2(62.84,93.72) 62.39,94.17 61.85,94.17 61.57,94.44 61.57,94.62 60,96.19 60,97.23 58.88,98.35 52.45,98.35 50.89,96.78 49.79,96.78 49.5,96.49 48.86,96.49 48.7,96.33 48.7,95.28 48.54,95.13 48.17,95.13 48.02,95.28 48.02,96.33 47.86,96.49 47.51,96.49 47.35,96.33 47.35,95.3 47.2,95.15 46.83,95.15 46.68,95.3 46.68,96.33 46.51,96.49 46.24,96.49 44.86,95.12 43.37,95.12 43.34,95.14 41.22,95.14 41.19,95.12 40.83,95.12 40.82,95.13 40.81,95.13 40.79,95.15 39.81,95.15 v2(39.44,95.52)
  BOTTOM w0.127: v2(39.44,95.52) 39.01,95.95 UV17.F2 ; UV1.F15 63.22,93.34 v2(62.84,93.72)
FBA_D11: length 36.3
  IN3 w0.076: 62.82,95.91 63.22,95.51 63.22,94.46 63.58,94.11 64.14,94.11 v2(64.51,93.75)
  IN3 w0.165: 62.82,95.91 62.63,96.1 62.63,96.69 62.31,97 62.31,97.65 60.14,99.82 49.3,99.82 49.14,99.66 49.14,99 48.97,98.83 48.63,98.83 48.46,99 48.46,99.66 48.3,99.82 47.96,99.82 47.79,99.66 47.79,99 47.63,98.83 47.28,98.83 47.12,99 47.12,99.66 46.95,99.82 46.75,99.82 45.97,99.04 45.7,99.04 45.37,98.71 45.37,98.58 45.74,98.2 45.74,97.99 45.49,97.73 45.27,97.73 44.77,98.24 44.56,98.24 44.23,97.91 44.23,97.71 44.56,97.39 44.56,97.16 44.31,96.91 44.08,96.91 43.77,97.22 43.54,97.22 43.22,96.9 41.89,96.9 41.62,97.18 v2(40.26,97.18)
  BOTTOM w0.127: UV17.E3 39.84,96.75 v2(40.26,97.18) ; UV1.F13 64.51,93.73 v2(64.51,93.75)
FBA_D12: length 34.4
  IN3 w0.076: 64.65,98.12 64.85,97.92 64.85,96.59 v2(64.51,96.24)
  IN3 w0.165: v2(38.16,98.63) 38.16,98.73 39.37,99.95 39.58,99.95 39.81,100.18 39.81,100.48 39.81,100.48 39.81,100.52 40.05,100.75 40.38,100.75 40.44,100.69 43.42,100.69 43.99,101.26 45.49,101.26 46.42,102.19 60.69,102.19 64.39,98.49 64.39,98.38 64.65,98.12
  BOTTOM w0.127: UV1.C13 64.9,95.84 v2(64.51,96.24) ; v2(38.16,98.63) 37.41,99.37 UV17.H7
FBA_D13: length 32.7
  IN3 w0.165: v2(40.21,99.11) 39.97,99.11 39.81,99.27 39.81,99.62 39.96,99.77 40.24,99.77 40.5,100.04 40.95,100.04 41.1,99.89 41.1,99.44 41.24,99.3 41.65,99.3 41.79,99.44 41.79,100.12 41.94,100.27 42.42,100.27 42.56,100.13 42.56,99.98 42.71,99.82 43.15,99.82 44.16,100.84 45.67,100.84 46.6,101.77 60.52,101.77 64.01,98.27 64.01,97.49 64.48,97.02 v2(64.48,96.95)
  BOTTOM w0.127: v2(64.48,96.95) 64.86,96.57 UV1.B13 ; UV17.F7 39.32,99.65 39.68,99.65 v2(40.21,99.11)
FBA_D14: length 36.2
  IN3 w0.165: v2(64.51,94.56) 65.33,95.39 65.33,98.73 61.04,103.02 38.94,103.02 38.1,102.19 38.1,101.42 v2(37.82,101.15)
  BOTTOM w0.127: UV17.H8 37.43,100.75 v2(37.82,101.15) ; v2(64.51,94.56) 64.9,94.17 UV1.E13
FBA_D15: length 34.8
  IN3 w0.076: 64.88,98.4 65.03,98.25 65.03,95.79 64.62,95.38 v2(64.54,95.38)
  IN3 w0.165: v2(39.43,101.2) 39.98,101.75 39.98,102.19 40.4,102.61 43.26,102.61 43.42,102.44 43.42,102.05 43.59,101.88 43.93,101.88 44.1,102.05 44.1,102.44 44.26,102.61 44.6,102.61 44.77,102.44 44.77,102.05 44.93,101.88 45.28,101.88 45.44,102.05 45.44,102.44 45.61,102.61 60.87,102.61 64.81,98.66 64.81,98.47 64.88,98.4
  BOTTOM w0.127: UV17.F8 39.01,100.8 39.43,101.22 v2(39.43,101.2) ; UV1.D13 64.9,95.02 v2(64.54,95.38)
FBA_D16: length 28.9
  BOTTOM w0.127: UV17.B8 42.36,100.75 42.71,100.4 43.21,100.4 43.44,100.63 43.44,101.65 43.69,101.91 46.03,101.91 46.59,101.35 49.07,101.35 v1(49.67,101.95) 50.14,102.42 50.9,102.42 51.72,103.23 60.36,103.23 63.86,99.73 63.86,97.74 63.58,97.46 63.58,96.92 UV1.B15
FBA_D17: length 28.5
  BOTTOM w0.127: UV1.C16 62.78,96.12 62.78,99.25 60.12,101.91 51.9,101.91 51.34,101.35 50.58,101.35 49.52,100.28 v1(47.05,100.28) 46.79,100.28 46.08,99.57 43.43,99.57 43.37,99.63 42.88,99.63 42.62,99.89 42.62,100.01 42.35,100.28 40.76,100.28 40.61,100.12 UV17.D7
FBA_D18: length 29.1
  BOTTOM w0.127: UV1.A13 64.9,99.44 60.58,103.76 51.49,103.76 50.68,102.95 49.92,102.95 49.41,102.44 v1(47.05,102.44) 42.32,102.44 41.79,101.91 41.79,101.01 41.53,100.75 UV17.C8
FBA_D19: length 28.4
  BOTTOM w0.127: UV1.A15 63.22,97.82 63.33,97.92 63.33,99.51 60.39,102.44 v1(55.43,102.44) 51.68,102.44 51.12,101.88 50.36,101.88 49.3,100.82 46.57,100.82 46.32,100.56 46.05,100.56 45.92,100.7 45.92,101.22 45.76,101.37 45.44,101.37 45.29,101.22 45.29,100.28 45.14,100.13 44.82,100.13 44.67,100.28 44.67,101.22 44.51,101.37 44.18,101.37 44.03,101.22 44.03,100.23 43.9,100.11 43.62,100.11 43.46,99.95 UV17.A7
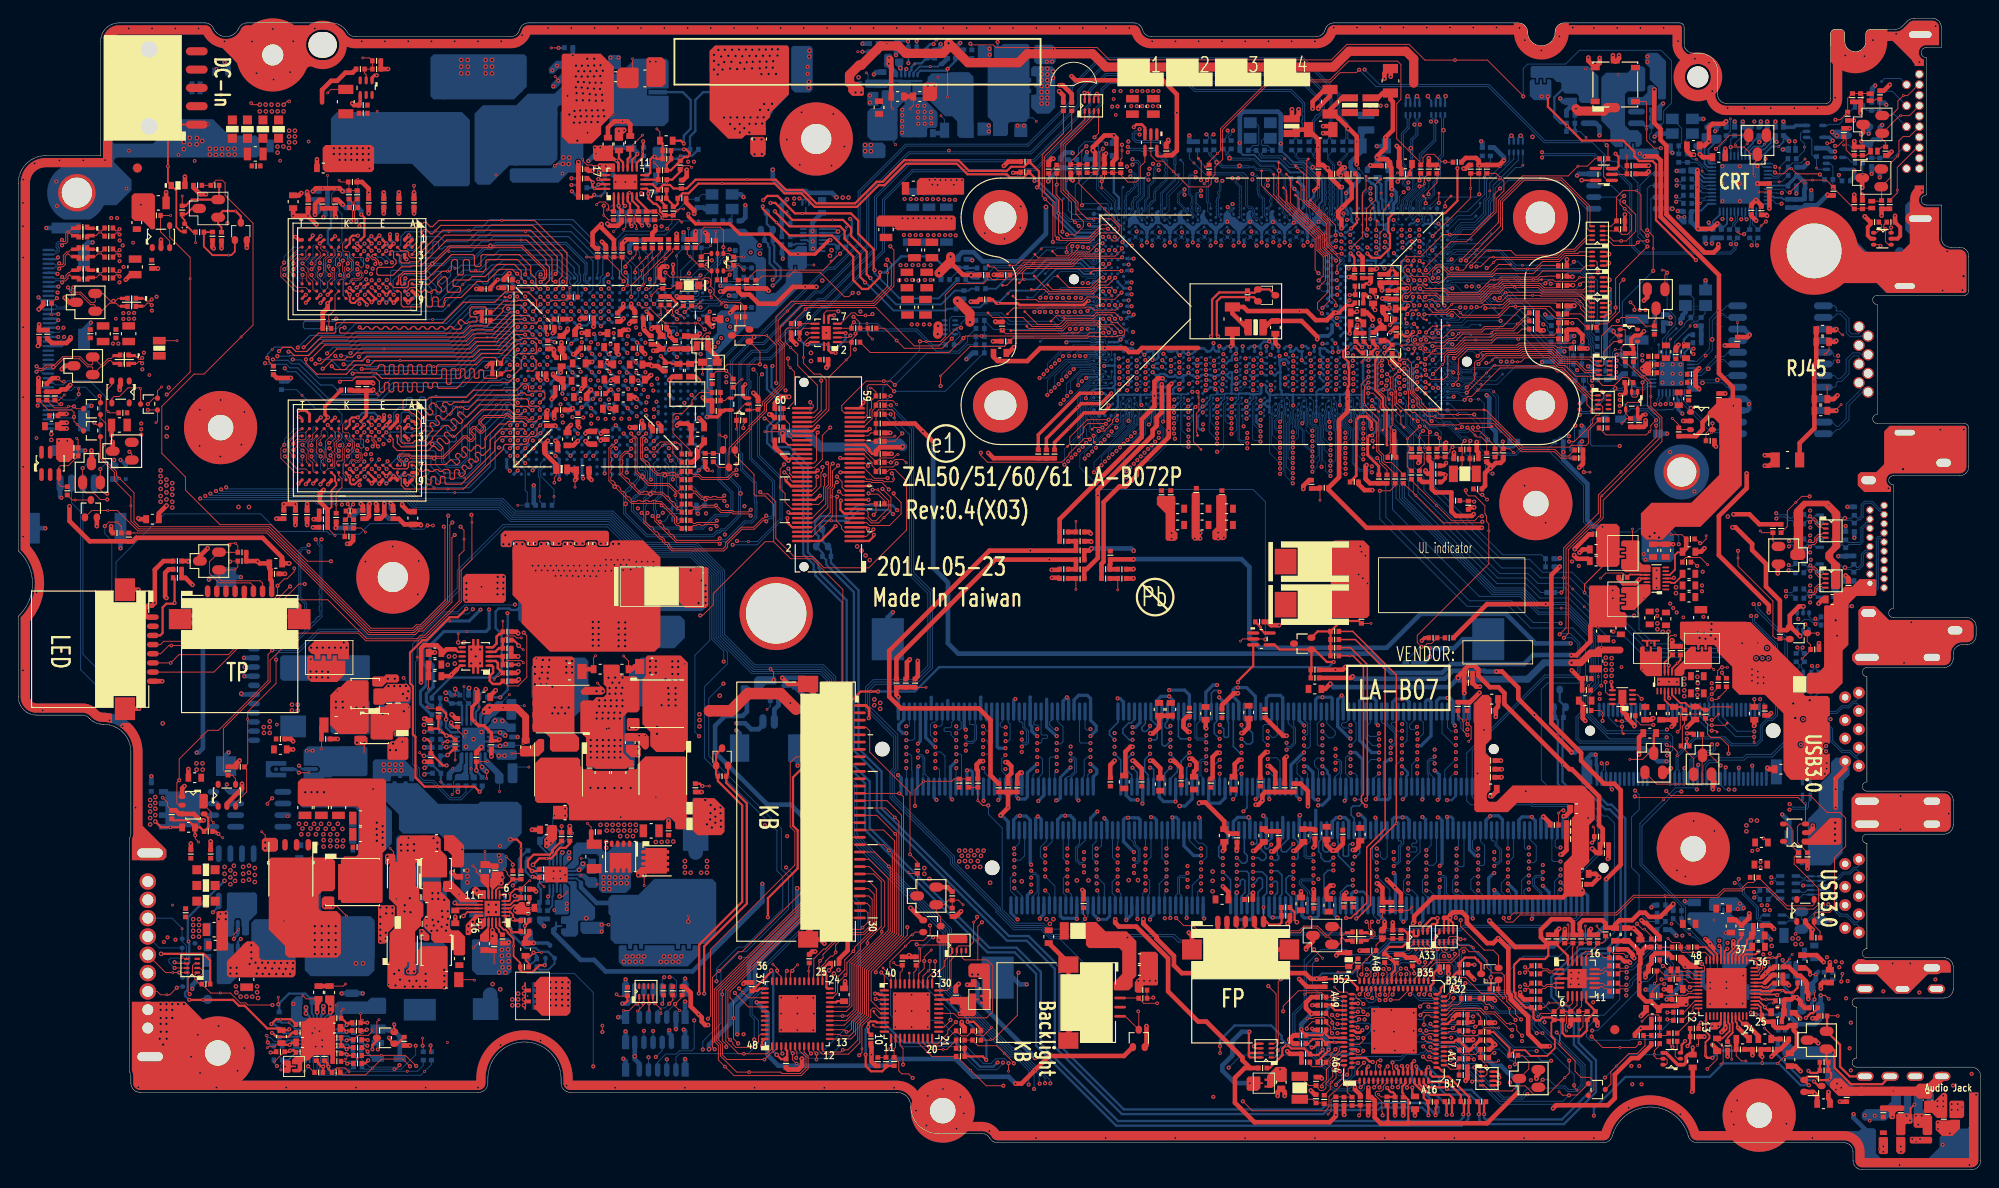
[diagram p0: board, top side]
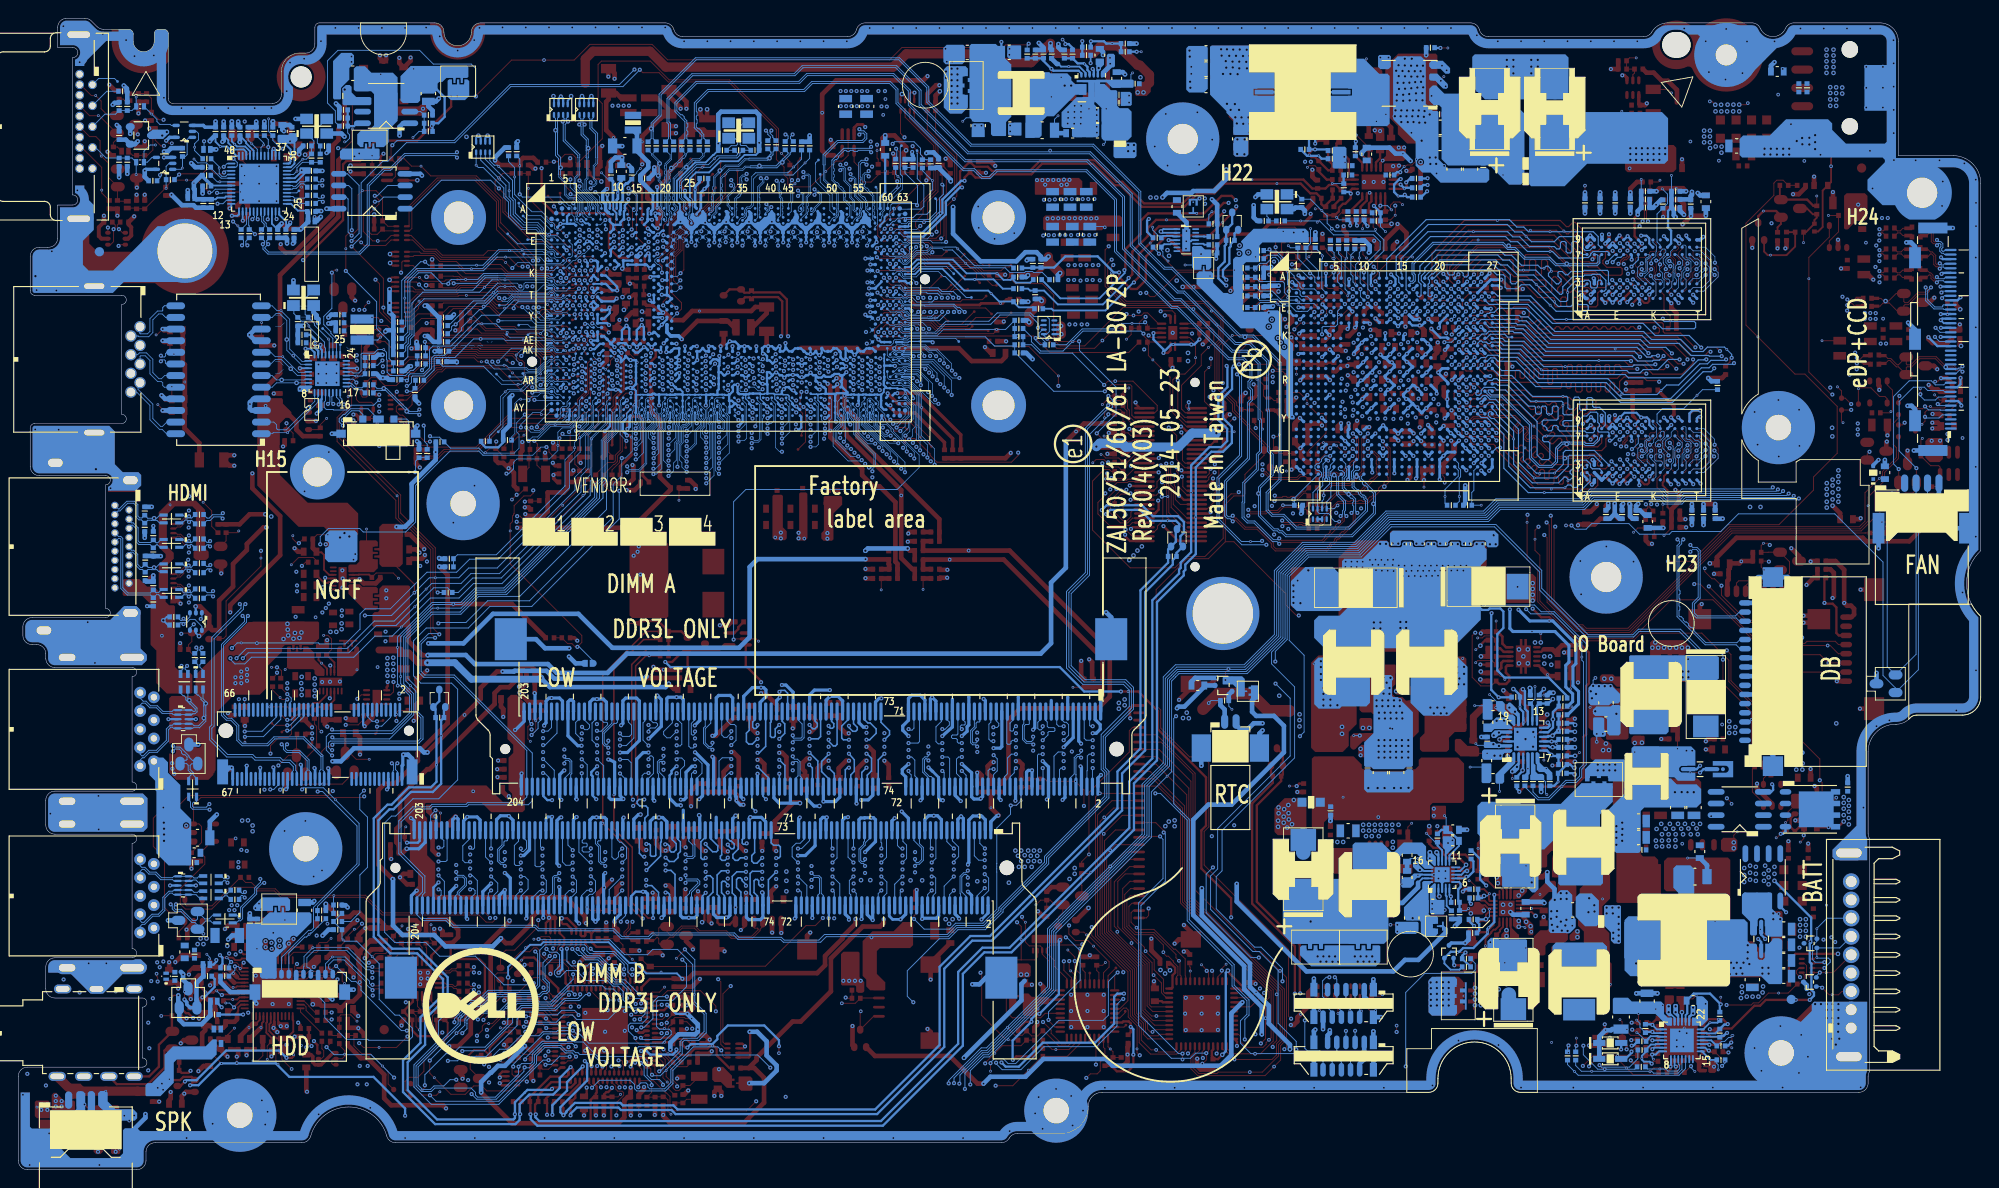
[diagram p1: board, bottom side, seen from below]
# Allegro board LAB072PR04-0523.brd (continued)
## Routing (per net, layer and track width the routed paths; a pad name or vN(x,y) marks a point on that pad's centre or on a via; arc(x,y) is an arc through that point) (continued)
FBA_D20: length 27.5
  BOTTOM w0.127: UV1.B18 60.74,96.73 60.74,96.73 61.12,97.11 61.12,97.61 60.74,98 60.74,98.46 59.3,99.9 52.76,99.9 52.2,99.34 51.49,99.34 50.4,98.25 v1(49.97,98.25) 48.61,98.25 45.97,95.61 45.8,95.61 45.66,95.75 45.66,96.44 44.53,97.56 43.41,97.56 43.27,97.71 42.52,97.71 42.44,97.79 41.6,97.79 40.95,97.13 40.95,96.13 41.13,95.95 UV17.C2
FBA_D21: length 25.6
  BOTTOM w0.127: UV17.C3 41.41,97.04 41.53,97.15 41.72,97.15 41.87,97 41.87,96.46 42.02,96.3 42.5,96.3 42.64,96.44 42.64,96.95 42.82,97.14 43.24,97.14 43.35,97.03 44.31,97.03 45.13,96.21 v1(45.13,95.81) 45.13,94.99 45.29,94.82 45.94,94.82 48.83,97.72 50.62,97.72 51.71,98.81 52.42,98.81 52.98,99.36 59.08,99.36 60.05,98.39 60.05,98.25 60.74,97.56 UV1.A18
FBA_D22: length 26
  BOTTOM w0.127: UV1.A19 59.74,97.37 58.88,98.22 58.42,98.22 58.22,98.02 58.22,97.87 58.07,97.72 57.66,97.72 57.51,97.87 57.51,98.02 57.36,98.17 56.82,98.17 56.54,97.89 56.54,97.66 56.38,97.51 56.16,97.51 55.98,97.68 55.98,98.12 55.81,98.3 53.42,98.3 52.87,97.74 52.15,97.74 51.97,97.56 51.97,96.4 51.79,96.22 50.63,96.22 50.19,96.65 49.27,96.65 v1(47.04,94.42) 46.38,93.75 43.03,93.75 42.88,93.91 42.88,94.34 43.03,94.49 43.91,94.49 44.06,94.64 44.06,95.77 43.88,95.95 UV17.A2
FBA_D23: length 25.5
  BOTTOM w0.127: UV1.C19 59.94,95.48 59.94,95.48 60.07,95.35 60.25,95.35 60.38,95.48 60.38,96.7 60.23,96.85 60.23,97.15 60.36,97.28 60.36,97.45 59.97,97.84 59.8,97.84 58.81,98.83 53.2,98.83 52.65,98.27 51.93,98.27 51.39,97.73 51.39,96.93 51.21,96.75 50.85,96.75 50.42,97.18 49.05,97.18 v1(48.57,96.7) 46.16,94.29 44.78,94.29 44.59,94.48 44.59,95.99 44.09,96.5 43.27,96.5 UV17.A3
FBA_D24: length 22.4
  TOP w0.127: UV18.B8 42.46,95.95 42.85,96.34 43.39,96.34 43.9,95.84 44.1,95.84 44.35,96.09 44.53,96.09 44.78,95.84 45.06,95.84 45.33,96.1 45.56,96.1 45.83,95.84 46.1,95.84 46.23,95.96 46.23,96.27 45.82,96.68 45.82,96.9 46.44,97.52 46.65,97.52 46.86,97.31 46.86,95.96 46.99,95.84 48.16,95.84 48.32,95.99 48.32,96.32 48.16,96.47 47.63,96.47 47.5,96.6 47.5,97.06 47.61,97.16 49.22,97.16 49.59,97.54 51,97.54 52.34,98.87 54.2,98.87 54.94,98.13 54.94,97.35 v2(55.35,96.94)
  BOTTOM w0.127: v2(55.35,96.94) 55.72,96.57 UV1.B24
FBA_D25: length 23.7
  TOP w0.127: UV18.D7 41.02,96.34 42.38,96.34 42.62,96.58 42.62,96.97 42.88,97.23 44.63,97.23 47.33,99.94 49.69,99.94 49.83,99.8 49.83,98.78 49.98,98.63 50.4,98.63 50.55,98.78 50.55,99.79 50.7,99.94 54.75,99.94 55.99,98.7 55.99,97.89 56.54,97.33 56.54,96.48 56.83,96.19 v2(57.04,96.19)
  BOTTOM w0.127: v2(57.04,96.19) 56.62,95.77 UV1.C23
FBA_D26: length 21.1
  TOP w0.127: UV18.C8 41.64,95.95 41.84,95.75 41.84,95.31 41.84,95.31 41.84,95 41.84,94.99 41.84,94.44 42.04,94.24 43.84,94.24 43.97,94.36 43.97,95.13 44.12,95.28 44.45,95.28 44.61,95.13 44.61,94.36 44.73,94.24 45.11,94.24 45.24,94.36 45.24,95.15 45.39,95.3 45.72,95.3 45.88,95.15 45.88,94.36 46,94.24 46.41,94.24 46.56,94.39 v1(46.56,94.8) 46.56,95.1 46.71,95.25 48.37,95.25 50.12,97 51.22,97 52.56,98.34 53.97,98.34 54.45,97.86 v2(54.51,97.86)
  BOTTOM w0.127: UV1.A25 54.96,97.4 v2(54.51,97.86)
FBA_D27: length 21.1
  TOP w0.127: v2(55.36,97.78) 55.45,97.87 55.45,98.48 54.53,99.41 51.24,99.41 51.08,99.25 51.08,98.37 50.78,98.07 49.42,98.07 49.3,98.2 49.3,99.24 49.14,99.39 48.77,99.39 48.62,99.24 48.62,97.84 48.49,97.72 48.11,97.72 47.98,97.84 47.98,99.28 47.86,99.41 47.56,99.41 47.32,99.17 47.32,98.3 47.15,98.12 v1(46.9,98.12) 46.27,98.12 44.85,96.7 43.06,96.7 UV18.A7
  BOTTOM w0.127: UV1.A24 55.76,97.38 v2(55.36,97.78)
FBA_D28: length 23.2
  TOP w0.127: UV18.C2 41.8,100.36 42.47,100.36 42.65,100.18 42.65,99.82 42.88,99.6 43.36,99.6 46.37,102.6 v1(49.2,102.6) 55.97,102.6 58.88,99.69 58.88,98.05 58.7,97.87 v2(58.7,97.84)
  BOTTOM w0.127: UV1.A21 58.26,97.4 v2(58.7,97.84)
FBA_D29: length 23.4
  TOP w0.127: v2(58.7,96.99) 58.4,96.99 58.3,97.08 58.3,99.51 55.74,102.07 46.59,102.07 43.68,99.15 42.79,99.15 42.68,99.04 41.86,99.04 41.69,99.21 41.69,99.85 41.58,99.95 UV18.C3
  BOTTOM w0.127: v2(58.7,96.99) 58.28,96.57 UV1.B21
FBA_D30: length 25.5
  TOP w0.127: UV18.A2 43.57,101.31 43.57,102.73 44.3,103.46 44.56,103.46 45.01,103 45.26,103 45.93,103.67 v1(52.81,103.67) 56.41,103.67 59.95,100.13 59.95,96.86 59.52,96.44 v2(59.52,96.24)
  BOTTOM w0.127: v2(59.52,96.24) 59.1,95.83 UV1.C20
FBA_D31: length 25.3
  TOP w0.127: v2(58.7,96.16) 59.09,96.55 59.09,97.26 59.41,97.58 59.41,99.91 56.19,103.14 46.15,103.14 v1(45.54,102.52) 45.23,102.21 45.05,102.21 44.57,102.69 44.35,102.69 44.12,102.46 44.12,102.24 44.6,101.76 44.6,101.58 43.01,100 UV18.A3
  BOTTOM w0.127: v2(58.7,96.16) 58.31,95.77 UV1.C21
FBA_D32: length 26.1
  IN3 w0.165: v2(56.98,85.43) 56.58,85.03 55.95,85.03 55.18,84.26 54.35,84.26 53.5,83.4 52.18,83.4 44.59,75.82 44.2,75.82 44.07,75.95 44.07,76.28 43.9,76.46 42.39,76.46 42.22,76.29 42.22,75.94 42.06,75.77 41.71,75.77 41.55,75.94 41.55,76.29 41.38,76.46 40.8,76.46 40.48,76.14 39.17,76.14 38.72,75.69 v2(37.84,75.69)
  BOTTOM w0.127: UV20.G2 38.21,76.06 v2(37.84,75.69) ; v2(56.98,85.43) 57.38,85.83 UV1.R22
FBA_D33: length 22.7
  IN3 w0.165: v2(37.8,77.35) 37.8,77.16 38.03,76.93 38.44,76.93 38.52,77.02 39.65,77.02 39.81,77.17 39.81,77.53 40.75,78.46 46,78.46 51.98,84.44 53.28,84.44 53.95,85.11 55.03,85.11 v2(55.34,85.43)
  BOTTOM w0.127: v2(55.34,85.43) 55.74,85.83 UV1.R24 ; UV20.H3 37.41,76.95 v2(37.8,77.35)
FBA_D34: length 22.8
  IN3 w0.165: v2(57,84.61) 57,84.67 56.52,84.19 55.92,84.19 55.22,83.49 55.05,83.49 54.88,83.33 54.1,83.33 53.75,82.98 52.35,82.98 44.7,75.33 40.83,75.33 40.83,75.34 39.81,75.34 v2(39.41,75.74)
  BOTTOM w0.127: v2(39.41,75.74) 39.01,76.14 UV20.F2 ; v2(57,84.61) 57.4,85.01 UV1.T22
FBA_D35: length 25.6
  IN3 w0.165: v2(40.34,77.36) 40.41,77.36 40.8,77.75 40.97,77.75 41.15,77.57 41.15,77.17 41.3,77.02 41.67,77.02 41.82,77.17 41.82,77.88 41.98,78.03 42.8,78.03 42.97,77.87 42.97,77.04 43.12,76.89 43.49,76.89 43.64,77.04 43.64,77.87 43.81,78.03 44.15,78.03 44.31,77.87 44.31,77.04 44.54,76.81 44.76,76.81 44.99,77.04 44.99,77.87 45.15,78.03 46.16,78.03 51.96,83.82 53.26,83.82 54.13,84.69 55.18,84.69 55.94,85.45 v2(56.16,85.45)
  BOTTOM w0.127: UV1.R23 56.53,85.83 v2(56.16,85.45) ; v2(40.34,77.36) 39.92,76.94 UV20.E3
FBA_D36: length 26.4
  IN3 w0.165: v2(54.52,87.91) 54.39,87.91 53.9,88.39 52.53,88.39 51.36,87.23 50.66,87.23 45.76,82.32 45.52,82.32 45.37,82.48 45.37,82.65 45.22,82.81 44.78,82.81 44.63,82.65 44.63,82.2 44.48,82.04 44.02,82.04 43.87,82.2 43.87,82.65 43.72,82.81 43.26,82.81 43.06,82.6 43.06,82.02 42.8,81.76 42.13,81.76 41.31,80.94 40.05,80.94 39.83,80.72 39.81,80.7 39.81,80.37 39.58,80.14 38.08,80.14 37.7,79.76 37.7,79.12 v2(38.11,78.7)
  BOTTOM w0.102: v2(38.11,78.7) 38.04,78.7 37.41,79.33 UV20.H7
  BOTTOM w0.127: UV1.N25 54.92,87.51 v2(54.52,87.91)
FBA_D37: length 24.6
  IN3 w0.165: v2(53.69,87.91) 53.69,87.63 52.94,86.87 52.7,86.87 52.27,87.31 52.05,87.31 51.79,87.04 51.79,86.83 52.23,86.39 52.23,86.16 51.99,85.92 50.74,85.92 50.58,86.08 50.49,86.17 50.26,86.17 50.02,85.93 50.02,85.7 50.28,85.43 50.28,85.2 50.03,84.96 49.8,84.96 49.54,85.22 49.31,85.22 49.06,84.98 49.06,84.74 49.32,84.48 49.32,84.25 49.08,84.01 48.85,84.01 48.59,84.27 48.35,84.27 48.11,84.02 48.11,83.79 48.37,83.53 48.37,83.3 48.12,83.05 47.82,83.05 47.55,83.32 47.34,83.32 45.18,81.16 44.86,81.16 44.71,81.31 44.71,81.46 44.56,81.61 44.09,81.61 43.94,81.46 43.94,80.92 43.82,80.8 41.82,80.8 41.16,80.14 40.29,80.14 39.83,79.68 39.5,79.68 v2(39.45,79.73)
  BOTTOM w0.127: v2(53.69,87.91) 54.1,87.51 UV1.N26 ; UV20.F7 39.17,79.98 39.2,79.98 v2(39.45,79.73)
FBA_D38: length 27.1
  IN3 w0.165: v2(37.01,80.56) 37.39,80.94 38.06,80.94 38.21,81.08 38.21,82.4 38.36,82.55 39.04,82.55 39.2,82.7 39.2,83.11 39.04,83.26 38.82,83.26 38.66,83.42 38.66,83.85 38.82,84 46.01,84 51.24,89.23 54.23,89.23 54.3,89.17 55.52,89.17 55.75,88.94 55.75,88.28 v2(56.15,87.88)
  BOTTOM w0.122: v2(37.01,80.56) 37.39,80.94 UV20.H8
  BOTTOM w0.127: v2(56.15,87.88) 56.52,87.51 UV1.N23
FBA_D39: length 26.2
  IN3 w0.165: v2(39.41,81.34) 39.81,81.74 41.47,81.74 42.04,82.31 42.04,82.7 41.89,82.86 39.93,82.86 39.78,83.01 39.78,83.43 39.93,83.58 42.29,83.58 42.45,83.42 42.45,83.4 42.62,83.24 42.96,83.24 43.12,83.4 43.12,83.42 43.29,83.58 43.63,83.58 43.8,83.42 43.8,83.4 43.96,83.24 44.31,83.24 44.47,83.4 44.47,83.42 44.64,83.58 46.18,83.58 51.41,88.81 54.06,88.81 54.25,88.62 54.42,88.62 55.14,87.91 v2(55.37,87.91)
  BOTTOM w0.127: UV1.N24 55.76,87.52 v2(55.37,87.91) ; UV20.F8 v2(39.41,81.34)
FBA_D40: length 22.4
  TOP w0.127: UV19.C3 41.41,79.38 41.84,78.95 43.34,78.95 43.47,79.08 44.57,79.08 45.24,79.74 45.24,79.95 46.57,81.28 46.92,81.28 47.46,80.74 47.59,80.74 47.82,80.97 47.82,81.15 47.29,81.68 47.29,81.86 47.47,82.04 47.65,82.04 48.18,81.5 48.36,81.5 48.54,81.68 48.54,81.86 48.01,82.4 48.01,82.57 48.19,82.75 48.37,82.75 48.9,82.22 49.08,82.22 50.39,83.54 v1(52.25,83.54) 54.25,83.54 54.42,83.37 55.63,83.37 56.05,82.95 v2(56.17,82.95)
  BOTTOM w0.127: UV1.V23 56.56,83.34 v2(56.17,82.95)
FBA_D41: length 23.7
  TOP w0.127: v2(56.98,82.97) 56.98,83.26 56.85,83.39 55.99,83.39 55.74,83.63 55.74,83.96 55.5,84.2 54.33,84.2 54.2,84.07 50.17,84.07 49.13,83.03 48.84,83.03 48.59,83.29 v1(48.32,83.29) 47.82,83.29 46.53,82 46.35,82 45.98,82.37 45.77,82.37 45.62,82.22 45.62,82.01 45.99,81.64 45.99,81.46 45.81,81.28 45.63,81.28 45.32,81.59 45.11,81.59 45.01,81.49 45.01,81.18 45.27,80.92 45.27,80.74 44.71,80.17 44.71,79.96 44.35,79.61 43.32,79.61 43.06,79.35 41.98,79.35 41.82,79.5 41.82,81.14 41.7,81.26 41.53,81.26 41.41,81.14 UV19.C2
  BOTTOM w0.127: v2(56.98,82.97) 57.36,83.35 UV1.V22
FBA_D42: length 23.1
  TOP w0.127: UV19.A3 43.09,80.22 43.77,80.22 44.48,80.92 44.48,82.04 43.42,83.1 43.26,83.1 43.13,83.23 43.13,83.44 43.26,83.57 43.77,83.57 44.89,82.44 45.09,82.44 45.29,82.64 45.29,82.84 44.89,83.23 44.89,83.45 45.18,83.73 45.39,83.73 v1(45.64,83.48) 46.35,82.78 46.56,82.78 46.71,82.93 46.71,83.14 46.37,83.48 46.37,83.68 46.51,83.82 46.82,83.82 47.09,83.54 47.32,83.54 47.6,83.82 49.17,83.82 49.95,84.6 54.63,84.6 54.87,84.84 55.29,84.84 55.53,84.6 56.12,84.6 v2(56.14,84.63)
  BOTTOM w0.127: v2(56.14,84.63) 56.54,85.03 UV1.T23
FBA_D43: length 23.8
  TOP w0.127: v2(56.98,83.79) 57.54,84.34 57.54,84.81 57.31,85.03 55.86,85.03 55.75,85.15 55.75,85.6 55.51,85.84 55.15,85.84 54.45,85.14 49.73,85.14 48.95,84.36 44.94,84.36 44.68,84.1 42.19,84.1 42.04,83.95 42.04,83.09 42.19,82.93 42.65,82.93 43.02,82.56 43.2,82.56 43.95,81.82 43.95,81.14 43.74,80.94 UV19.A2
  BOTTOM w0.127: v2(56.98,83.79) 57.38,84.19 UV1.U22
FBA_D44: length 22.5
  TOP w0.127: UV19.D7 41,76.55 42.45,76.55 42.62,76.72 42.62,77.17 42.75,77.29 43.63,77.29 43.92,77.01 46.7,77.01 47.21,77.52 47.32,77.52 47.84,77.01 47.98,77.01 48.21,77.25 48.21,77.43 47.77,77.87 47.77,78.05 47.95,78.23 48.13,78.23 48.57,77.79 48.75,77.79 48.93,77.97 48.93,78.15 48.49,78.59 48.49,78.77 48.67,78.95 48.85,78.95 49.29,78.51 49.47,78.51 v1(49.8,78.83) 50.09,79.12 50.27,79.12 50.61,78.78 50.81,78.78 51.01,78.98 51.01,79.88 52.57,81.44 53.28,81.44 53.55,81.71 55.14,81.71 55.36,81.49 v2(55.36,81.33)
  BOTTOM w0.127: v2(55.36,81.33) 55.73,81.71 UV1.Y24
FBA_D45: length 22.5
  TOP w0.127: v2(55.37,80.47) 55.37,80.76 55.22,80.91 52.79,80.91 51.54,79.66 51.54,78.76 50.8,78.02 50.62,78.02 50.29,78.35 50.08,78.35 49.93,78.2 49.93,77.99 50.26,77.66 50.26,77.48 50.08,77.3 49.9,77.3 49.59,77.62 49.37,77.62 49.23,77.47 49.23,77.26 49.54,76.94 49.54,76.76 49.36,76.58 49.18,76.58 48.84,76.92 48.64,76.92 48.48,76.76 48.48,76.56 48.82,76.22 48.82,76.04 48.5,75.72 48.29,75.72 48.18,75.83 v1(48.18,76) 48.18,76.33 48.03,76.48 47.8,76.48 47.65,76.33 47.65,75.51 47.55,75.4 47.26,75.4 47.15,75.51 47.15,76.3 46.97,76.48 46.51,76.48 46.3,76.27 46.04,76.27 45.85,76.46 45.55,76.46 45.36,76.27 44.96,76.27 44.77,76.46 44.46,76.46 44.27,76.27 43.91,76.27 43.7,76.48 43.24,76.94 UV19.A7
  BOTTOM w0.127: UV1.AA24 55.76,80.86 v2(55.37,80.47)
FBA_D46: length 21.1
  TOP w0.127: UV19.C8 41.41,75.89 41.84,75.47 41.84,74.75 42.25,74.34 v1(46.92,74.34) 48.63,74.34 53.02,78.73 53.02,79.04 53.2,79.22 55.45,79.22 55.73,79.51 55.73,79.76 56.05,80.08 56.43,80.08 56.67,80.32 56.67,80.95 v2(57.02,81.31)
  BOTTOM w0.127: v2(57.02,81.31) 57.4,81.69 UV1.Y22
FBA_D47: length 22.9
  TOP w0.127: UV19.B8 42.17,76.14 42.02,75.99 42.02,75.85 42.11,75.75 42.35,75.75 42.55,75.95 42.7,75.95 42.9,75.75 43.16,75.75 43.44,75.47 43.44,75.1 43.67,74.87 43.95,74.87 44.08,75 44.08,75.59 44.21,75.72 44.46,75.72 44.59,75.59 44.59,75 44.72,74.87 44.97,74.87 45.1,75 v1(45.1,75.24) 45.1,75.59 45.22,75.72 45.48,75.72 45.61,75.59 45.61,75 45.73,74.87 45.99,74.87 46.11,75 46.11,75.59 46.24,75.72 46.51,75.72 46.62,75.61 46.62,75 46.75,74.87 48.41,74.87 52.07,78.54 52.07,79.43 52.71,80.07 55.61,80.07 56.01,80.47 v2(56.17,80.47)
  BOTTOM w0.127: v2(56.17,80.47) 56.56,80.86 UV1.AA23
FBA_D48: length 19.3
  TOP w0.102: UV19.H8 37.41,76.11 v2(37.01,75.71)
  IN1 w0.14: v2(52.51,78.86) 52.23,79.13 48.97,79.13 48.03,78.2 45.83,78.2 45.65,78.01 42.04,78.01 41.83,77.8 40.03,77.8 39.81,77.57 39.81,77.17 39.73,77.09 38.43,77.09 38.28,76.94 37.6,76.94 37.34,76.68 37.34,76.04 v2(37.01,75.71)
  BOTTOM w0.127: UV1.AD27 53.36,78.37 52.87,78.86 v2(52.51,78.86)
FBA_D49: length 22.5
  TOP w0.102: UV19.F7 39.04,76.94 v2(39.41,76.56)
  IN1 w0.14: v2(39.41,76.56) 39.84,76.13 42.38,76.13 43.47,77.22 44.07,77.22 44.2,77.08 44.2,76.14 44.34,76 44.59,76 44.73,76.14 44.73,77.08 44.87,77.22 45.11,77.22 45.25,77.08 45.25,76.14 45.39,76 45.63,76 45.77,76.14 45.77,77.02 46.16,77.41 52.39,77.41 53.36,78.38 53.87,78.38 54.15,78.66 54.15,78.99 54.57,79.41 v2(54.57,79.64)
  BOTTOM w0.127: v2(54.57,79.64) 54.96,80.04 UV1.AB25
FBA_D50: length 20.7
  TOP w0.102: UV19.F8 v2(38.61,76.54)
  IN1 w0.14: v2(53.75,77.97) 52.79,77.02 46.32,77.02 46.16,76.85 46.16,75.6 45.83,75.26 45.25,75.26 45.11,75.12 45.11,74.84 44.97,74.7 44.6,74.7 44.46,74.84 44.46,75.12 44.32,75.26 43.95,75.26 43.81,75.12 43.81,74.84 43.67,74.7 43.31,74.7 43.17,74.84 43.17,75.12 43.03,75.26 40.74,75.26 40.67,75.33 39.12,75.33 38.61,75.84 v2(38.61,76.54)
  BOTTOM w0.127: UV1.AD26 54.15,78.37 v2(53.75,77.97)
FBA_D51: length 23.2
  TOP w0.102: v2(36.94,76.54) 37.33,76.94 UV19.H7
  IN1 w0.14: v2(54.55,78.82) 54.51,78.79 54.51,78.54 54.14,78.17 54.14,77.61 53.15,76.62 47.74,76.62 45.41,74.29 39.6,74.29 39.59,74.28 39.27,74.28 39.25,74.29 38.59,74.29 37.7,75.19 36.89,75.19 36.62,75.45 36.62,75.6 36.62,75.6 36.62,76.22 v2(36.94,76.54)
  BOTTOM w0.127: v2(54.55,78.82) 54.95,79.22 UV1.AC25
FBA_D52: length 21.8
  TOP w0.102: UV19.E3 v2(40.21,80.54)
  IN1 w0.14: v2(52.91,80.47) 52.35,80.47 52.17,80.29 47.68,80.29 47.54,80.15 47.54,79.44 47.4,79.3 47.16,79.3 47.02,79.44 47.02,80.15 46.88,80.29 45.96,80.29 45.82,80.43 45.82,80.69 45.68,80.83 45.44,80.83 45.3,80.69 45.3,80.43 45.16,80.29 44.92,80.29 44.78,80.43 44.78,80.69 44.64,80.83 44.4,80.83 44.26,80.69 44.26,80.43 44.12,80.29 43.85,80.29 43.71,80.43 43.71,80.71 43.57,80.85 43.33,80.85 43.19,80.71 43.19,80.29 43.04,80.14 42.82,80.14 42.67,80.29 42.67,80.71 42.53,80.85 42.29,80.85 41.98,80.55 41.58,80.55 41.43,80.39 41.43,80.09 41.58,79.94 42.02,79.94 42.15,79.8 42.15,79.53 42,79.38 41.13,79.38 40.97,79.53 40.97,80.14 40.82,80.29 40.46,80.29 v2(40.21,80.54)
  BOTTOM w0.127: UV1.AA27 52.97,80.47 v2(52.91,80.47)
FBA_D53: length 21.8
  TOP w0.102: v2(39.41,80.56) 39.04,80.94 UV19.F2
  IN1 w0.14: v2(53.75,80.49) 53.75,80.55 53.12,81.18 52.58,81.18 52.08,80.68 46.38,80.68 46.23,80.83 46.23,81.85 46.08,82 45.68,82 45.54,81.86 45.54,81.37 45.4,81.23 45.16,81.23 45.02,81.37 45.02,81.86 44.88,82 44.64,82 44.5,81.86 44.5,81.37 44.36,81.23 44.12,81.23 43.98,81.37 43.98,81.86 43.84,82 43.36,82 43.12,81.76 41.74,81.76 41.6,81.63 41.6,81.14 41.46,81 41.09,81 40.95,81.14 40.95,81.63 40.81,81.76 39.97,81.76 39.8,81.59 39.8,80.87 39.49,80.56 v2(39.41,80.56)
  BOTTOM w0.127: UV1.AA26 54.12,80.87 v2(53.75,80.49)
FBA_D54: length 23.1
  TOP w0.102: UV19.H3 v2(37.81,80.54)
  IN1 w0.14: v2(54.59,82.89) 54.43,82.73 50.08,82.73 49.91,82.56 49.91,81.97 49.76,81.82 49.54,81.82 49.39,81.97 49.39,82.56 49.25,82.7 49.01,82.7 48.87,82.56 48.87,81.94 48.72,81.79 48.5,81.79 48.35,81.94 48.35,82.56 48.21,82.7 46.53,82.7 45.98,83.25 39.11,83.25 38.22,82.37 38.22,80.95 v2(37.81,80.54)
  BOTTOM w0.127: UV1.W26 54.51,82.89 v2(54.59,82.89)
FBA_D55: length 22.6
  TOP w0.102: UV19.G2 v2(38.59,80.56)
  IN1 w0.14: v2(54.49,81.31) 53.86,81.94 52.63,81.94 51.82,81.13 47.94,81.13 47.8,81.27 47.8,82.15 47.65,82.3 47.43,82.3 47.28,82.15 47.28,81.27 47.14,81.13 46.9,81.13 46.76,81.27 46.76,81.92 45.82,82.86 39.45,82.86 39.01,82.42 39.01,80.9 38.68,80.56 v2(38.59,80.56)
  BOTTOM w0.127: UV1.Y25 54.9,81.71 v2(54.49,81.31)
FBA_D56: length 22.8
  BOTTOM w0.127: UV20.D7 40.61,80.46 40.71,80.56 41.7,80.56 41.84,80.7 41.84,81.01 41.66,81.18 41.66,81.44 41.84,81.61 41.84,82.58 41.99,82.73 42.63,82.73 43.04,82.31 43.44,82.31 43.94,81.82 43.94,81.32 44.05,81.21 45.5,81.21 45.64,81.35 45.64,81.69 45.51,81.81 44.63,81.81 44.51,81.94 44.51,82.32 44.63,82.45 45.51,82.45 45.64,82.58 45.64,83.79 45.78,83.92 v1(48.57,83.92) 49.18,83.92 51.46,86.21 52.68,86.21 52.86,86.39 53.19,86.39 53.37,86.21 53.78,86.21 54.16,85.83 UV1.R26
FBA_D57: length 22.3
  BOTTOM w0.127: UV20.A7 v1(47.43,80.14) 47.71,80.14 47.86,79.99 47.86,79.66 47.71,79.5 47.23,79.5 47.07,79.35 47.07,77.7 47.22,77.55 47.94,77.55 48.46,78.07 48.46,81.7 51.91,85.15 52.84,85.15 53.14,85.45 54.25,85.45 54.58,85.13 54.58,84.81 54.81,84.58 55.04,84.58 55.15,84.69 55.15,84.85 54.97,85.03 UV1.T25
FBA_D58: length 21.5
  BOTTOM w0.127: UV20.C8 41.01,81.34 41.01,82.64 41.63,83.26 42.27,83.26 42.4,83.39 42.4,84.2 42.52,84.33 42.9,84.33 43.03,84.2 43.03,83.09 43.18,82.93 43.67,82.93 43.82,83.09 43.82,84.23 43.97,84.38 44.33,84.38 44.47,84.24 44.47,83.21 44.62,83.06 44.95,83.06 45.1,83.21 45.1,84.33 45.23,84.46 v1(45.65,84.46) 48.96,84.46 51.24,86.74 52.6,86.74 UV1.N27
FBA_D59: length 21.9
  BOTTOM w0.127: UV1.R27 52.91,85.83 52.76,85.68 51.69,85.68 49.4,83.39 48.77,83.39 48.64,83.26 48.64,82.68 48.49,82.53 48.16,82.53 48,82.68 48,83.26 47.88,83.39 47.56,83.39 47.43,83.26 47.43,82.63 47.31,82.5 v1(47.17,82.5) 46.93,82.5 46.8,82.63 46.8,83.26 46.67,83.39 46.31,83.39 46.17,83.25 46.17,82.02 46.32,81.87 47.76,81.87 47.91,81.71 47.91,81.38 47.76,81.23 47.64,81.23 47.41,81 47.41,80.85 47.25,80.7 46.92,80.7 46.77,80.85 46.77,81.13 46.62,81.28 46.32,81.28 46.17,81.13 46.17,80.87 45.98,80.67 43.25,80.67 43.07,80.49 42.35,80.49 42.21,80.63 UV20.B8
FBA_D60: length 20.8
  BOTTOM w0.127: UV1.V26 53.71,83.81 53.28,83.81 52.89,83.41 52.89,83.27 50.5,80.88 50.5,77.28 v1(48.77,75.55) 46.34,75.55 45.07,76.81 45.07,77.88 44.93,78.02 42.26,78.02 41.41,77.17 UV20.C3
FBA_D61: length 21
  BOTTOM w0.127: UV20.C2 41.41,76.32 41.64,76.55 42.42,76.55 42.63,76.76 42.63,77.06 43.06,77.49 44.28,77.49 44.51,77.27 44.51,76.63 44.86,76.27 44.86,76.09 44.57,75.8 44.57,75.62 44.84,75.36 45.02,75.36 45.31,75.64 45.49,75.64 46.11,75.02 48.99,75.02 51.03,77.06 v1(51.03,79.81) 51.03,80.66 52.91,82.54 52.91,82.68 53.36,83.13 UV1.V27
FBA_D62: length 20.4
  BOTTOM w0.127: UV1.W27 53.36,82.66 53.49,82.78 53.66,82.78 53.79,82.66 53.79,82.36 53.47,82.04 53.17,82.04 51.57,80.44 51.57,76.84 49.21,74.48 v1(45.42,74.48) 45.12,74.78 44.79,74.78 44.53,74.51 44.14,74.51 43.75,74.9 43.75,75.12 44.04,75.41 44.04,76.26 43.97,76.33 43.97,76.76 43.78,76.96 43.61,76.96 43.46,76.81 43.46,76.71 43.31,76.56 43.1,76.56 42.96,76.71 42.96,76.88 UV20.A3
FBA_D63: length 19.6
  BOTTOM w0.127: UV1.W25 54.56,82.15 53.93,82.15 52.1,80.32 52.1,76.62 49.43,73.95 v1(47.68,73.95) 43.91,73.95 42.68,75.19 42.68,75.8 UV20.A2
FBA_DQM0: length 30.8
  TOP w0.127: UV18.E7 39.86,96.75 v2(40.26,96.35)
  IN1 w0.14: v2(59.54,95.41) 59.54,95.45 59.96,95.87 59.96,97.22 57.66,99.51 52.32,99.51 50.34,97.52 50.34,97.33 50.68,96.98 50.68,96.78 50.51,96.61 50.32,96.61 49.97,96.96 49.77,96.96 49.44,96.62 48.08,96.62 47.94,96.76 47.94,97.17 47.8,97.31 47.56,97.31 47.42,97.17 47.42,96.76 47.28,96.62 47.04,96.62 46.9,96.76 46.9,97.17 46.76,97.31 46.52,97.31 46.38,97.17 46.38,96.76 46.24,96.62 45.99,96.62 45.85,96.76 45.85,97.17 45.71,97.31 45.47,97.31 45.33,97.17 45.33,96.76 45.19,96.62 44.95,96.62 44.81,96.76 44.81,97.17 44.67,97.31 44.43,97.31 44.29,97.17 44.29,96.76 44.15,96.62 43.9,96.62 43.64,96.88 40.72,96.88 40.26,96.42 v2(40.26,96.35)
  BOTTOM w0.127: UV1.D19 59.94,95 v2(59.54,95.41)
FBA_DQM1: length 31.4
  IN3 w0.165: v2(63.66,94.54) 64.06,94.94 64.06,95.6 64.09,95.62 64.09,96.86 63.58,97.37 63.58,98.11 60.35,101.35 46.77,101.35 45.84,100.42 44.34,100.42 43.76,99.84 43.76,99.33 43.31,98.88 41.03,98.88 v2(40.82,99.09)
  BOTTOM w0.127: UV17.E7 39.98,99.95 40.82,99.11 v2(40.82,99.09) ; v2(63.66,94.54) 64.06,94.94 UV1.D14
FBA_DQM2: length 31.4
  BOTTOM w0.127: UV1.C17 61.58,95.48 61.45,95.35 61.27,95.35 61.14,95.48 61.14,96.7 61.42,96.98 61.42,97.74 61.27,97.89 61.27,98.68 59.52,100.43 52.54,100.43 51.98,99.88 51.27,99.88 50.17,98.78 48.39,98.78 48.06,98.45 v1(47.71,98.45) 47.48,98.68 47.27,98.68 46.96,98.37 46.96,98.15 47.22,97.89 47.22,97.62 46.35,96.75 46.14,96.75 45.84,97.04 45.84,97.25 46.18,97.59 46.18,98 46.08,98.1 45.72,98.1 45.37,97.74 45.11,97.74 44.75,98.1 43.46,98.1 43.34,98.22 40.8,98.22 40.67,98.1 40.67,96.81 UV17.D3
FBA_DQM3: length 30.4
  TOP w0.127: UV18.D3 40.61,100.27 40.72,100.38 40.88,100.38 41,100.27 41,99.57 41.28,99.28 41.28,98.99 40.85,98.55 39.32,98.55 39.17,98.4 39.17,97.84 39.32,97.69 40.95,97.69 41.86,98.61 42.88,98.61 42.99,98.71 43.99,98.71 46.81,101.54 v1(54.92,101.54) 55.52,101.54 57.65,99.41 57.65,98.95 58.02,98.58 58.02,97.13 57.59,96.7 57.59,96.49 v2(57.87,96.21)
  BOTTOM w0.127: UV1.C22 57.46,95.81 v2(57.87,96.21)
FBA_DQM4: length 23.7
  IN3 w0.165: v2(56.21,86.29) 56.21,86.89 56.03,87.07 54.21,87.07 54.06,86.92 54.06,86.44 53.8,86.18 52.84,86.18 52.16,85.5 51.17,85.5 48.3,82.63 47.25,82.63 45.09,80.47 45.09,79.78 44.94,79.63 44.61,79.63 44.45,79.78 44.45,80.24 44.31,80.38 43.98,80.38 43.81,80.22 43.81,79.8 43.65,79.63 43.31,79.63 43.14,79.8 43.14,80.22 42.98,80.38 41.99,80.38 41.33,79.71 40.6,79.71 v2(40.52,79.63)
  BOTTOM w0.127: v2(40.52,79.63) 40.49,79.66 40.29,79.66 UV20.E7 ; UV1.P24 55.83,86.67 v2(56.21,86.29)
FBA_DQM5: length 22.7
  TOP w0.127: UV19.D3 40.95,79.8 40.95,79 41.41,78.54 44.79,78.54 45.24,78.99 45.5,78.99 45.95,78.55 46.15,78.55 46.35,78.74 46.35,78.94 45.77,79.52 45.77,79.73 45.92,79.88 46.13,79.88 46.72,79.29 46.9,79.29 47.08,79.47 47.08,79.65 46.54,80.19 46.54,80.4 46.69,80.55 46.9,80.55 47.44,80.01 47.62,80.01 v1(48.82,81.21) 50.61,83 53.66,83 54.18,82.48 54.9,82.48 v2(55.34,82.92)
  BOTTOM w0.127: v2(55.34,82.92) 55.72,82.55 UV1.W24
FBA_DQM6: length 22.2
  TOP w0.102: UV19.E7 39.84,76.94 v2(40.24,76.54)
  IN1 w0.14: v2(40.24,76.54) 40.25,76.52 41.23,76.52 41.33,76.63 41.33,77.23 41.47,77.37 41.71,77.37 41.85,77.23 41.85,76.66 41.99,76.52 42.22,76.52 43.31,77.62 45.81,77.62 46,77.8 48.19,77.8 49.13,78.74 49.43,78.74 49.57,78.6 49.57,78.17 49.71,78.03 49.95,78.03 50.09,78.17 50.09,78.6 50.23,78.74 50.47,78.74 50.61,78.6 50.61,78.17 50.75,78.03 50.99,78.03 51.13,78.17 51.13,78.6 51.27,78.74 51.49,78.74 51.64,78.59 51.64,78.11 51.74,78.01 52.35,78.01 52.94,78.59 52.94,79.07 53.06,79.2 53.85,79.2 54.15,79.5 54.15,80.05 v2(54.57,80.47)
  BOTTOM w0.127: UV1.AA25 54.96,80.86 v2(54.57,80.47)
FBA_DQM7: length 22.6
  BOTTOM w0.127: UV1.U25 54.71,84.19 54.36,84.54 54.01,84.54 53.61,84.14 53,84.14 49.97,81.1 49.97,77.5 48.55,76.08 v1(46.56,76.08) 45.6,77.03 45.6,78.31 45.36,78.56 42.21,78.56 40.61,76.96 UV20.D3
FBA_RN0: length 30.2
  TOP w0.112: v2(38.99,98.91) 39.12,99.04 39.12,99.19 38.93,99.38 38.7,99.38 38.41,99.67 38.41,99.75 UV18.G3
  IN1 w0.14: v2(59.54,93.78) 59.54,93.91 59.15,94.3 59.15,94.73 59.39,94.97 59.65,94.97 60.2,95.53 60.2,97.57 59.01,98.76 58.93,98.84 58.93,98.84 57.74,100.03 52.15,100.03 50.35,98.22 39.45,98.22 39.12,98.55 39.12,98.79 v2(38.99,98.91)
  BOTTOM w0.112: UV1.F19 59.94,93.38 v2(59.54,93.78)
FBA_RN1: length 31.1
  IN3 w0.145: v2(63.66,96.19) 63.58,96.19 63.47,96.29 63.47,96.92 63.05,97.35 63.05,97.84 60.15,100.74 46.74,100.74 45.7,99.69 45.49,99.69 45.18,100.01 44.77,100.01 44.37,99.61 44.37,98.97 43.49,98.1 41.91,98.1 41.78,97.96 39.18,97.96 38.92,97.7 38.92,97.39 38.68,97.15 v2(38.61,97.15)
  BOTTOM w0.112: UV1.C14 64.06,95.79 v2(63.66,96.19) ; UV17.G3 38.21,96.75 v2(38.61,97.15)
FBA_RN2: length 26.1
  BOTTOM w0.112: UV1.A16 62.42,97.15 62.42,97.14 62.31,97.03 62.12,97.03 61.99,97.16 61.99,97.68 62.13,97.82 62.13,99.01 59.86,101.28 52.16,101.28 51.6,100.72 50.84,100.72 49.78,99.66 47.06,99.66 46.35,98.95 v4(45.23,98.95) 42,98.95 41.82,99.13 41.82,99.83 41.94,99.95 UV17.B7
FBA_RN3: length 21.8
  TOP w0.112: UV18.B7 42.08,96.62 41.84,96.62 41.75,96.72 41.75,97.45 42.17,97.87 44.35,97.87 47.18,100.7 51.28,100.7 51.3,100.68 51.86,100.68 51.88,100.7 55.01,100.7 55.78,99.92 56.16,99.55 57.37,98.34 57.5,98.21 57.5,97.53 57.35,97.37 56.99,97.37 56.9,97.46 56.9,97.62 v2(57.07,97.79)
  BOTTOM w0.112: v2(57.07,97.79) 57.46,97.39 UV1.A22
FBA_RN4: length 23.5
  IN3 w0.145: v2(54.55,86.23) 54.64,86.23 54.86,86.01 54.86,85.91 54.72,85.77 53.01,85.77 52.33,85.09 51.34,85.09 48.09,81.84 47.88,81.84 47.71,82.02 47.3,82.02 46.9,81.62 46.9,81.21 47.07,81.03 47.07,80.83 46.82,80.57 46.61,80.57 46.44,80.75 46.03,80.75 45.63,80.34 45.63,79.94 45.8,79.76 45.8,79.56 45.44,79.2 40.42,79.2 39.65,78.44 39.2,78.44 38.94,78.18 38.94,77.9 v2(38.61,77.57)
  BOTTOM w0.112: UV20.G3 38.61,77.34 v2(38.61,77.57) ; v2(54.55,86.23) 54.96,86.65 UV1.P25
FBA_RN5: length 22.6
  TOP w0.112: UV19.B7 42.09,77.06 42.09,77.26 41.65,77.71 41.65,77.87 41.72,77.94 42.63,77.94 42.87,77.7 v4(45.43,77.7) 46.5,77.7 48.73,79.94 48.89,79.94 49.27,79.55 49.61,79.55 49.92,79.87 49.92,80.2 49.54,80.59 49.54,80.74 49.73,80.93 49.89,80.93 50.38,80.45 50.69,80.45 51.03,80.78 51.03,81.1 50.54,81.59 50.54,81.74 50.96,82.16 53.11,82.16 53.29,82.34 53.53,82.34 53.85,82.02 55.37,82.02 55.71,81.68 56.51,81.68 v2(56.98,82.15)
  BOTTOM w0.112: UV1.W22 57.38,82.55 v2(56.98,82.15)
FBA_RN6: length 20.6
  TOP w0.112: UV19.G3 38.54,80.14 38.64,80.04 38.64,79.63 38.88,79.39 38.88,79.16 v2(38.71,79)
  IN1 w0.076: 52.13,79.53 52.13,79.53 52.18,79.57 52.29,79.57 52.62,79.9 52.82,79.9 52.89,79.83 v2(52.89,79.64)
  IN1 w0.14: 52.13,79.53 48.8,79.53 47.87,78.59 46.48,78.59 46.19,78.88 46.19,79.38 46.04,79.53 45.69,79.53 45.54,79.38 45.54,78.81 45.24,78.51 44.69,78.51 44.38,78.81 44.38,79.38 44.23,79.53 43.89,79.53 43.74,79.38 43.74,78.88 43.45,78.59 41.76,78.59 41.51,78.34 39.22,78.34 38.92,78.64 38.92,78.84 38.76,79 v2(38.71,79)
  BOTTOM w0.112: UV1.AB27 53.32,80.07 v2(52.89,79.64)
FBA_RN7: length 20.9
  BOTTOM w0.112: UV20.B7 41.97,80.14 41.86,80.04 41.86,79.81 42.36,79.31 43.12,79.31 43.27,79.46 44.93,79.46 44.95,79.48 45.51,79.48 45.53,79.46 45.79,79.46 46.45,78.81 46.45,77.38 46.9,76.92 48.2,76.92 49.09,77.81 49.09,81.44 52.26,84.61 53.47,84.61 53.8,84.94 53.8,85.09 53.73,85.17 53.5,85.17 UV1.T27
FBA_WP0: length 30.2
  TOP w0.112: v2(39.58,98.94) 39.48,98.94 39.33,99.08 39.33,99.28 39.02,99.6 38.79,99.6 38.62,99.76 38.62,99.86 38.71,99.95 UV18.F3
  IN1 w0.14: v2(59.54,94.57) 59.54,94.33 59.66,94.21 59.83,94.21 59.97,94.35 59.97,94.94 60.46,95.42 60.46,97.67 59.26,98.87 59.19,98.94 59.19,98.95 57.85,100.28 52.05,100.28 50.24,98.48 39.55,98.48 39.37,98.66 39.37,98.81 39.5,98.94 v2(39.58,98.94)
  BOTTOM w0.112: v2(59.54,94.57) 59.94,94.17 UV1.E19
FBA_WP1: length 31
  IN3 w0.145: v2(63.66,95.39) 63.66,95.5 63.22,95.94 63.22,96.82 62.8,97.25 62.8,97.74 60.05,100.49 46.84,100.49 45.8,99.45 45.39,99.45 45.07,99.76 44.87,99.76 44.61,99.51 44.61,98.87 43.59,97.85 42.02,97.85 41.88,97.71 39.28,97.71 39.16,97.6 39.16,97.4 v2(39.41,97.15)
  BOTTOM w0.112: v2(63.66,95.39) 63.29,95.77 UV1.C15 ; UV17.F3 v2(39.41,97.15)
FBA_WP2: length 26.1
  BOTTOM w0.112: UV17.C7 41.61,99.75 41.61,99.04 41.91,98.73 44.91,98.73 44.94,98.71 45.52,98.71 45.55,98.73 46.44,98.73 47.15,99.44 49.86,99.44 50.93,100.51 51.69,100.51 52.25,101.07 59.77,101.07 61.92,98.92 61.92,97.91 61.78,97.76 61.78,97.07 62.03,96.82 62.3,96.82 62.42,96.69 62.42,96.69 UV1.B16
FBA_WP3: length 21.8
  TOP w0.112: UV18.C7 41.53,96.87 41.53,97.54 42.08,98.08 44.26,98.08 47.09,100.91 v4(51.58,100.91) 55.1,100.91 55.93,100.08 56.31,99.7 57.37,98.64 57.71,98.29 57.71,97.44 57.41,97.13 57.24,97.13 v2(57.07,96.96)
  BOTTOM w0.112: v2(57.07,96.96) 57.46,96.57 UV1.B22
FBA_WP4: length 23.5
  IN3 w0.145: v2(55.38,86.27) 55.24,86.27 55.1,86.13 55.1,85.81 54.82,85.52 53.11,85.52 52.43,84.85 51.44,84.85 48.19,81.6 47.78,81.6 47.61,81.77 47.4,81.77 47.14,81.52 47.14,81.31 47.32,81.13 47.32,80.73 46.92,80.32 46.51,80.32 46.33,80.5 46.13,80.5 45.87,80.24 45.87,80.04 46.05,79.86 46.05,79.45 45.55,78.95 40.52,78.95 39.76,78.19 39.3,78.19 39.19,78.08 39.19,77.79 v2(39.41,77.57)
  BOTTOM w0.112: UV1.R25 54.96,85.85 v2(55.38,86.27) ; v2(39.41,77.57) 39.01,77.17 UV20.F3
FBA_WP5: length 22.6
  TOP w0.112: UV19.C7 41.49,76.86 41.79,76.86 41.88,76.95 41.88,77.17 41.43,77.62 41.43,77.95 41.63,78.16 42.71,78.16 42.96,77.91 45.13,77.91 45.15,77.93 45.71,77.93 45.73,77.91 46.41,77.91 48.64,80.15 48.98,80.15 49.36,79.77 49.52,79.77 49.71,79.96 49.71,80.12 49.33,80.5 49.33,80.83 49.64,81.15 49.98,81.15 50.46,80.66 50.6,80.66 50.81,80.87 50.81,81.01 50.33,81.5 50.33,81.83 50.87,82.37 53.02,82.37 53.2,82.55 53.62,82.55 53.94,82.23 55.46,82.23 55.8,81.89 55.96,81.89 v2(56.14,82.07)
  BOTTOM w0.112: UV1.W23 56.14,82.13 v2(56.14,82.07)
FBA_WP6: length 20.6
  TOP w0.112: UV19.F3 38.85,79.98 38.85,79.72 39.09,79.48 39.09,79.2 v2(39.3,79)
  IN1 w0.076: v2(53.75,79.67) 53.46,79.67 53.06,80.06 52.55,80.06 52.23,79.74 52.18,79.74 52.13,79.78 52.13,79.78
  IN1 w0.14: 52.13,79.78 48.7,79.78 47.76,78.84 46.58,78.84 46.44,78.98 46.44,79.48 46.14,79.78 45.59,79.78 45.29,79.48 45.29,78.92 45.13,78.77 44.79,78.77 44.64,78.92 44.64,79.48 44.34,79.78 43.78,79.78 43.48,79.48 43.48,78.98 43.34,78.84 41.66,78.84 41.4,78.59 39.33,78.59 39.17,78.75 39.17,78.87 v2(39.3,79)
  BOTTOM w0.112: v2(53.75,79.67) 54.14,80.07 UV1.AB26
FBA_WP7: length 20.8
  BOTTOM w0.112: UV20.C7 41.65,79.9 41.65,79.72 42.27,79.1 43.21,79.1 43.36,79.25 v4(45.23,79.25) 45.7,79.25 46.23,78.72 46.23,77.29 46.82,76.71 48.29,76.71 49.31,77.73 49.31,81.35 52.35,84.4 53.56,84.4 54.16,85 UV1.T26
FBA_ZQ0: length 7.2
  BOTTOM w0.102: v1(34.79,107.13) 34.22,106.56 34.22,105.51 RV148.1 35.36,104.37 35.36,101.32 35.01,100.97 UV17.L8
FBA_ZQ1: length 4.6
  TOP w0.102: RV152.1 33.93,92.12 v1(33.93,92.72) 33.93,93.26 34.6,93.93 34.6,95.54 UV18.L8
FBA_ZQ2: length 4.9
  TOP w0.102: RV155.1 v1(34.73,72.67) 34.73,73.9 35.37,74.54 35.37,75.45 35.01,75.81 UV19.L8
FBA_ZQ3: length 9.4
  BOTTOM w0.102: RV156.1 30.38,85.19 v1(30.99,84.58) 32.44,83.14 34.75,83.14 35.36,82.53 35.36,81.59 35.01,81.24 UV20.L8
FBVREF_ALTV: length 5.5
  BOTTOM w0.102: UV1.C5 71.52,95.77 71.99,96.24 71.99,99.44 71.91,99.52 v1(71.91,99.79) 71.91,99.9 RV92.1
FWP#: length 9.1
  TOP w0.102: v2(146.94,12.98) 146.94,12.86 146.63,12.55 146.19,12.55 146.08,12.67 UE5.B65 ; RE82.2 141.1,11.51 141.36,11.25 142.4,11.25 RE81.2 142.88,11.83 143.42,12.37 v1(143.42,12.66) v2(143.91,13.15)
  BOTTOM w0.102: v2(146.94,12.98) 146.94,13.11 146.61,13.44 144.19,13.44 v2(143.91,13.15)
GC6_EVENT#: length 1.5
  TOP w0.102: T177.1 153.66,96.64 153.15,97.14 v2(153.1,97.14)
  BOTTOM w0.076: UC1.R6 152.85,96.9 v2(153.1,97.14)
GC6_EVENT#_D: length 6.2
  BOTTOM w0.102: UV1.A4 72.36,98.19 73.72,99.54 RV190.2 73.69,100.69 73.22,101.16 v1(73.22,102.78)
GFX_CORE_PG: length 9.5
  TOP w0.254: PR1003.1 v2(54.67,55.17)
  IN3 w0.254: v4(51.06,52.49) 53.74,55.17 v2(54.67,55.17)
  BOTTOM w0.254: v4(51.06,52.49) 50.99,52.49 50.33,51.83 PR621.2 v1(50.33,50.56) 50.33,50.35 49.98,49.99 PU600.16
GFXCLK_REQ#: length 122.2
  TOP w0.102: v2(153.15,96.22) 153.38,95.99 155.79,95.99 156.22,95.56 159.55,95.56 160.64,96.65 161.46,96.65 162.07,97.26 165.97,97.26 166.25,97.54 166.83,97.54 166.88,97.59 R2345.2 ; v2(94.95,99.39) 95.38,98.96 95.38,96.54 93.46,94.62 84.89,94.62 v1(84.05,93.78) 83.01,92.74 83.01,90.52 83.44,90.08 83.44,85.64 81.51,83.71 81.51,82.93 79.84,81.26 79.84,81 77.65,78.81 QV88.1 76.56,76.7 RV196.2
  IN1 w0.114: v2(94.95,99.39) 95.01,99.46 100.41,99.46 102.75,97.12 109.76,97.12 113.54,100.9 114.01,100.9 115.42,102.31 115.42,103.25 115.8,103.63 121.73,103.63 122.5,104.41 139.59,104.41 142.84,101.16 142.84,99.28 143.49,98.63 144.78,98.63 145.04,98.88 146.54,98.88 147.78,97.64 149.66,97.64 151.49,95.81 152.73,95.81 v2(153.15,96.22)
  BOTTOM w0.076: v2(153.15,96.22) 153.5,95.87 UC1.U5
GFXCLK_REQ_Q#: length 11.7
  TOP w0.102: RV195.2 RV196.1 76.64,78.23 QV88.3 77.27,78.87 v2(77.27,80.06) 76.83,80.06 v1(76.62,80.27)
  IN3 w0.135: v2(77.27,80.06) 76.43,79.22 71.51,79.22 v2(71.07,78.79)
  BOTTOM w0.102: v2(71.07,78.79) 70.7,79.17 UV1.AC6
GPU_B+: length 24.4
  TOP w0.254: v2(46.79,44.15) 46.4,44.15 PC612.1 v1(45.08,46.61) 44.69,47 v4(44.37,47)
  IN2 w0.254: v2(46.79,44.15) 46.79,41.43 47.67,40.55 61.36,40.55 v4(62.51,41.71)
  BOTTOM w0.254: PR611.1 v4(44.37,47)
  vias: v4(63.35,41.68) v4(64.09,41.68) v4(65.13,41.68) v4(65.89,41.68) v4(66.91,41.68)
GPU_CLK_27M_IN: length 19.8
  BOTTOM w0.102: YV1.1 74.69,106.52 CV34.1 73.23,106 v1(71.98,104.75) 71.4,104.17 71.4,103.38 70.53,102.5 66.17,102.5 65.21,101.54 65.21,100.36 66.96,98.61 66.96,96.18 UV1.C11
GPU_CLK_27M_OUT: length 17.3
  BOTTOM w0.102: RV519.2 v1(74.3,103.62) 72.22,103.62 70.7,102.1 66.34,102.1 65.61,101.37 65.61,100.53 67.8,98.34 67.8,96.85 67.51,96.57 UV1.B10
GPU_CLK_27M_OUT_R: length 2.2
  BOTTOM w0.102: RV519.1 CV35.1 77.82,103.96 77.99,104.14 YV1.3
GPU_COMP: length 3.6
  TOP w0.102: v1(48.76,47.26) 48,48.02 PC616.2
  TOP w0.254: PC616.2 47.58,48.36 47.3,48.64 v4(47.3,48.82)
  BOTTOM w0.254: PU600.12 47.29,48.27 47.12,48.45 47.12,48.64 v4(47.3,48.82)
GPU_DSBL/ISEN1: length 12.8
  TOP w0.381: PR623.1 50.16,51.12 49.56,50.52 49.56,49.23 v1(49.9,48.89) 50.3,48.49 50.88,48.49 51.68,47.69 PC626.1 52.46,46.87 v4(52.57,46.98) ; v4(50.02,52.48) 50.06,52.44
  TOP w0.508: PR623.1 50.16,52.34 50.06,52.44
  BOTTOM w0.254: v4(50.02,52.48) 49.79,52.25 49.79,50.34 49.48,50.03 PU600.15 ; v4(52.57,46.98) 52.27,47.27 PU600.21
GPU_EN: length 4.6
  TOP w0.102: PC608.1 v1(51.24,44.57)
  TOP w0.254: PC608.1 v4(50.05,43.61)
  BOTTOM w0.254: PR608.1 50.68,42.92 50.05,43.55 v4(50.05,43.61) 49.98,43.68 PU600.3
GPU_FB: length 7.7
  TOP w0.102: PC615.2 44.86,50.35 v1(44.66,50.55)
  TOP w0.254: v4(46.74,49.19) 46.74,49.79 46.18,50.35 PC615.2
  BOTTOM w0.254: PU600.11 47.25,47.77 46.73,48.3 46.73,49.18 v4(46.74,49.19) 46.74,49.99 PR616.2 PR617.2
GPU_FBRTN: length 8.2
  TOP w0.254: 45.89,48.17 PC615.1 ; 45.89,48.17 v1(46.14,47.93) 46.37,47.7 46.43,47.7 46.73,47.4 v4(46.78,47.4) 47.27,47.4 PC606.2 ; 45.89,48.17 PR614.2
  BOTTOM w0.254: PR612.2 PR610.2 PC607.2 46.3,47.88 v4(46.78,47.4) 46.84,47.34 47.23,47.34 47.3,47.27 PU600.10
GPU_GC6_FB_EN: length 1.3
  TOP w0.102: T176.1 153.37,98.99 v2(153.09,99.27)
  BOTTOM w0.076: v2(153.09,99.27) 153.09,99.2 152.85,98.96 UC1.L6
GPU_HOT#: length 5.1
  TOP w0.102: v2(69.46,94.54) 69.16,94.85 v1(69.16,95.46) 69.94,96.24 RV104.1 71.3,96.24 71.63,96.57 DV3.2
  BOTTOM w0.102: UV1.D7 69.86,94.94 v2(69.46,94.54)
GPU_JTAG_TCK: length 9
  BOTTOM w0.102: UV1.AE5 71.51,77.42 71.51,77.41 71.86,77.07 71.86,76.63 71.82,76.59 71.82,75.62 71.89,75.55 71.89,74.71 72.45,74.14 RPV3.7 72.45,71.85 72.27,71.67 71.25,71.67 70.92,71.34 70.92,71.16 70.55,70.79 v3(70.1,70.79)
GPU_JTAG_TDI: length 6
  BOTTOM w0.102: RPV3.6 71.95,73.04 71.78,73.21 v3(71.78,73.65) 71.78,74.25 71.12,74.91 71.12,75.55 71.21,75.64 71.21,76.47 71.05,76.63 71.05,76.95 70.66,77.34 UV1.AE6
GPU_JTAG_TDO: length 6.3
  BOTTOM w0.102: v3(70.26,72.54) 70.61,72.2 RPV3.5 71.45,72.95 71,73.41 71,74.53 70.92,74.6 70.92,75.74 71.01,75.83 71.01,76.24 70.98,76.27 70.66,76.59 UV1.AF6
GPU_JTAG_TMS: length 8.9
  TOP w0.102: v3(71.29,77.43) 71.08,77.65 v2(71.08,77.95)
  BOTTOM w0.102: UV1.AD6 v2(71.08,77.95) 71.65,77.95 72.02,77.58 72.02,77.39 72.3,77.11 72.51,77.11 72.74,76.88 72.74,76.6 72.51,76.37 72.28,76.37 72.02,76.11 72.02,75.76 72.27,75.52 72.27,74.65 72.95,73.97 RPV3.8
GPU_JTAG_TRST#: length 5.7
  BOTTOM w0.102: v3(76.23,72.57) RV108.1 74.99,73.35 UV1.AG4
GPU_PEX_RST_HOLD#: length 8.4
  BOTTOM w0.102: RV189.2 77.96,99.88 76.82,99.88 76.46,99.52 76.46,99.07 75.01,97.61 75.01,97.41 74.38,96.78 74.38,96.45 74.12,96.19 72.79,96.19 UV1.C4
GPU_PSI:
  vias: v1(49.47,43.8)
GPU_PWM_VID: length 84
  IN1 w0.114: v2(49.66,61.22) 50.12,61.67 53.51,61.67 55.71,63.88 68.7,63.88 70.31,65.49 70.31,68.48 71.22,69.38 71.22,74.21 70.39,75.04 70.39,79.04 70.75,79.41 70.75,83.36 71.9,84.51 71.9,88.15 71.43,88.62 71.43,89.13 71.96,89.66 v2(71.96,91.24)
  BOTTOM w0.102: PR601.2 48.91,41.26 48.28,40.63 47.24,40.63 45.34,42.52 44.28,42.52 43.82,42.98 43.82,43.84 43.4,44.25 43.4,55.47 43.58,55.65 v1(43.58,55.98) 43.58,57.59 46.7,60.71 49.15,60.71 v2(49.66,61.22) ; v2(71.96,91.24) 71.96,91.98 71.86,92.08 70.51,92.08 70.26,92.33 70.26,93.77 UV1.E7
GPU_PWR_LEVEL: length 108.5
  TOP w0.102: DV3.1 74.96,96.57 v2(75.59,95.94) 75.59,95.37 v1(75.72,95.24) ; v2(101.85,16.36) 101.85,16.28 101.14,15.58 UE4.22
  IN1 w0.114: v2(75.59,95.94) 76.81,94.72 76.81,91.94 76.04,91.16 76.04,90.55 75.67,90.19 75.67,82.02 75.05,81.4 75.05,77.83 74.78,77.56 74.78,76.2 74.3,75.72 74.3,72.64 74.66,72.27 74.66,69.92 75.95,68.63 75.95,60.46 75.37,59.88 75.37,51.38 75.95,50.8 75.95,47.92 76.96,46.91 82.58,41.29 82.58,37.19 80.36,34.97 80.36,30.77 83.48,27.65 92,27.65 93.61,26.04 99.29,26.04 v2(99.95,25.38)
  BOTTOM w0.102: v2(101.85,16.36) 101.85,17.24 98.39,20.69 98.39,23.92 99.85,25.38 v2(99.95,25.38)
GPU_REFADJ:
  vias: v1(47.46,43.82)
GPU_REFIN: length 5.2
  TOP w0.102: PC606.1 v1(47.72,44.74)
  TOP w0.254: PC606.1 47.67,46.03 46.93,45.29 v4(46.91,45.29)
  BOTTOM w0.254: PU600.7 47.39,45.77 v4(46.91,45.29) 46.8,45.19 PR607.1 PR603.1
GPU_SMBCLK: length 172
  TOP w0.102: UE5.B49 147.3,19.53 147.07,19.31 147.07,18.97 147.33,18.72 147.88,18.72 v2(147.91,18.74) ; RPE3.4 153.95,24.64 v2(154.46,24.13) ; QV14.3 74.97,100.06 RV30.2 74.6,99.42 74.71,99.32 v2(75.77,99.32)
  IN3 w0.135: v2(78.52,68.67) 79.16,68.02 86.78,68.02 89.96,64.85 89.96,57.77 83.51,51.31 83.51,47.6 85.87,45.24 85.87,37.54 90.04,33.36 90.37,33.36 95.98,27.75 97.4,27.75 98.94,26.22 98.94,23.6 98.43,23.09 98.43,22.63 98.73,22.34 100.81,22.34 101.52,23.05 127.76,23.05 129.38,21.43 136.72,21.43 138,20.15 142.12,20.15 142.71,20.73 145.01,20.73 145.1,20.64 146.64,20.64 146.98,20.3 147.71,20.3 148.11,19.89 148.11,18.95 v2(147.91,18.74) ; v2(80.32,87.4) 79.27,88.45 79.27,94.83 75.77,98.33 v2(75.77,99.32)
  BOTTOM w0.102: v2(147.91,18.74) 147.91,19.7 148.48,20.27 149.35,20.27 150.63,21.56 150.63,22.15 151.08,22.61 151.89,22.61 152.25,22.25 153.98,22.25 154.46,22.74 v2(154.46,24.13) ; v2(80.32,87.4) 80.75,86.97 80.75,77.93 83.21,75.47 83.21,71.06 80.76,68.61 v1(79.77,68.61) 78.58,68.61 v2(78.52,68.67)
GPU_SMBCLK_R: length 16.2
  TOP w0.102: 74.76,98.78 RV30.1 74.32,98.78 v1(73.4,99.71) 73.08,100.03 RV191.1 ; 74.76,98.78 75.14,98.78 v2(75.24,98.88) ; 74.76,98.78 75.38,98.16 QV14.4
  IN3 w0.135: v2(75.24,98.88) 74.45,99.68 72.82,99.68 72.45,99.31 70.27,99.31 69.79,98.83 69.79,95.54 68.79,94.54 v2(68.61,94.54)
  BOTTOM w0.102: v2(68.61,94.54) 68.61,94.54 UV1.D9
GPU_SMBDAT: length 170.1
  TOP w0.102: UE5.B48 147.8,19.46 v2(147.48,19.14) ; v1(79.25,98.24) 78.71,98.78 RV26.2 ; RV26.2 77.77,99.18 v2(77.21,99.18) ; RV26.2 78.16,98.39 77.93,98.16 QV14.6 ; v2(153.88,24.11) 153.45,24.53 RPE3.3
  IN3 w0.135: v2(81.26,86.87) 81.26,87.07 79.53,88.8 79.53,94.95 76.89,97.59 76.89,98.86 v2(77.21,99.18) ; v2(78.05,68.25) 78.54,67.76 86.67,67.76 89.65,64.77 89.65,57.83 83.23,51.4 83.23,47.51 85.61,45.13 85.61,37.43 89.94,33.1 90.26,33.1 95.87,27.49 97.28,27.49 98.63,26.14 98.63,23.66 98.17,23.2 98.17,22.51 98.61,22.08 100.98,22.08 101.69,22.78 127.46,22.78 129.08,21.17 136.61,21.17 137.89,19.88 142.23,19.88 142.82,20.47 144.89,20.47 144.98,20.38 146.53,20.38 146.89,20.02 147,20.02 147.48,19.54 v2(147.48,19.14)
  BOTTOM w0.102: v2(153.88,24.11) 153.17,23.4 152.9,23.4 152.42,22.91 151.06,22.91 150.4,22.25 150.4,21.65 149.25,20.5 148.39,20.5 147.48,19.6 v2(147.48,19.14) ; v2(81.26,86.87) 80.98,86.59 80.98,78.02 83.44,75.56 83.44,70.97 80.73,68.25 v2(78.05,68.25)
GPU_SMBDAT_R: length 23
  TOP w0.102: v1(79.23,99.7) RV26.1 78.02,99.7 77.66,100.05 77.04,100.05 QV14.1 v2(77.03,100.75) 77.03,102.6 76.7,102.94 74.93,102.94 74.6,102.61 74.6,101.32 RV192.1
  IN3 w0.135: v2(77.03,100.75) 76.22,99.94 72.7,99.94 72.33,99.57 70.16,99.57 69.52,98.94 69.52,95.67 69.2,95.35 68.61,95.35 68.6,95.35 v2(68.6,95.37)
  BOTTOM w0.102: v2(68.6,95.37) 69.01,94.97 UV1.D8
GPU_TESTMODE: length 6.2
  TOP w0.102: RV107.1 71.52,78.25 71.52,79 71.26,79.25 70.55,79.25 v1(70.36,79.06) 69.69,78.39 69.08,78.39 68.72,78.74 v2(68.6,78.74)
  BOTTOM w0.102: UV1.AD9 68.23,78.37 v2(68.6,78.74)
GPU_TON: length 2.3
  TOP w0.102: v2(46.88,46.77) 46.6,46.77 v1(46.37,46.55)
  BOTTOM w0.254: PR611.2 46.35,46.77 v2(46.88,46.77) PU600.9
GPU_TSNS/ISEN3: length 57.4
  TOP w0.102: v2(74.73,41.9) v1(75.52,41.9)
  TOP w0.254: PH600.1 74.46,42.17 v2(74.73,41.9)
  IN1 w0.254: v4(46.74,51.4) 46.63,51.4 46.16,51.87 46.16,52.43 47.43,53.7 52.86,53.7 53.47,54.31 53.47,55.76 54.36,56.64 54.82,56.64 56.21,58.03 56.21,58.8 57.87,60.45 72.91,60.45 73.82,59.55 73.82,42.81 v2(74.73,41.9)
  BOTTOM w0.254: PU600.13 48.48,50.66 PR620.2 PC622.1 47.22,50.92 v4(46.74,51.4)
GPU_VDD_SENSE: length 72.1
  IN1 w0.361: v2(74.38,92.86) 74.38,93.56 74.11,93.83 73.71,93.83 72.55,92.67 72.55,92.35 73.19,91.7 73.19,88.05 72.98,87.84 72.98,84.38 73.34,84.02 73.34,83.4 73.08,83.14 73.08,77.92 72.62,77.46 72.62,68.8 71.72,67.89 71.72,64.91 69.29,62.48 57,62.48 54.73,60.2 52.16,60.2 51.44,60.92 v2(51.44,61.19)
  BOTTOM w0.254: UV1.F2 74.37,92.86 v2(74.38,92.86)
  BOTTOM w0.34: v2(51.44,61.19) 51.44,59.11 51.11,58.78 v1(49.03,58.78) 46.51,58.78 44.99,57.26 44.99,55.43 45.33,55.08 45.33,52.72 44.58,51.97 44.58,51.13 45.09,50.62 PR616.1
GPU_VID: length 2.1
  BOTTOM w0.102: PR600.1 47.55,42.38 47.55,41.12 v1(47.4,40.97)
GPU_VREF: length 15.8
  TOP w0.102: v4(47.73,52.5) v1(47.73,51.83)
  IN2 w0.254: v4(47.73,52.5) 47.73,51.03 46.09,49.39 46.09,46.82 v4(46.77,46.15) 45.58,44.97 45.58,43.93 44.82,43.17 v4(44.37,43.17)
  BOTTOM w0.254: PU600.8 47.22,46.27 47.1,46.15 v4(46.77,46.15) 46.74,46.12 PC600.1 ; v4(47.73,52.5) 47.68,52.5 48.23,51.96 PR620.1 ; v4(44.37,43.17) 44.49,43.3 PR602.1
GPU_VSS_SENSE: length 73
  IN1 w0.361: v2(50.5,61.17) 50.5,60.89 51.85,59.53 55,59.53 57.28,61.81 69.56,61.81 72.38,64.63 72.38,67.62 73.29,68.52 73.29,72.01 73.31,72.04 73.32,72.04 73.32,77.22 73.75,77.65 73.75,82.83 74.12,83.2 74.12,85.4 73.72,85.8 73.72,87.02 73.92,87.23 73.92,91.57 75.54,93.19 v2(75.54,93.7)
  BOTTOM w0.254: v2(75.54,93.7) 75.11,93.27 UV1.F1
  BOTTOM w0.34: v2(50.5,61.17) 49.27,59.93 v1(47.15,59.93) 46.75,59.93 44.23,57.41 44.23,55.27 44.55,54.95 44.55,52.85 43.94,52.24 43.94,50.87 45.12,49.68 PR612.1
GREEN: length 8.1
  TOP w0.102: LV17.2 203.12,111.24 203.58,111.7 CV55.1 204.02,111.7 204.02,112.18 203.64,112.56 DV5.2 205.55,115.12 v1(205.66,115.12) 206.61,115.12 JCRT.2
GREEN_CRT: length 16.6
  TOP w0.102: LV17.1 201.91,110.78 CV52.1 RV33.1 200.28,110.78 199.7,111.37 199.7,112.56 CV61.1 199.45,112.45 198.81,111.81 v2(198.49,111.81)
  IN3 w0.135: v2(198.49,111.81) 198.37,111.94 196.73,111.94 192.69,107.9 v2(192.69,106.69)
  BOTTOM w0.102: v2(192.69,106.69) 192.65,106.65 192.12,106.65 192.09,106.69 UV6.9
H_CATERR#: length 19.7
  BOTTOM w0.076: 112.74,100.45 113.3,100.45 113.45,100.6 114.67,100.6 115.09,100.18 116.23,100.18 117.4,99.01 117.63,99.01 117.8,99.18 117.8,99.36 118.03,99.59 118.56,99.59 UC1.K61
  BOTTOM w0.102: RC58.2 102.52,98 103.48,98 103.59,98.1 104.35,98.1 104.45,98 106.07,98 106.58,98.5 110.39,98.5 v1(110.89,99) 112.34,100.45 112.74,100.45
H_CPU_SVIDALRT#: length 14.1
  BOTTOM w0.076: UC1.L62 118.03,98.55 117.73,98.26 116.79,98.26 116.72,98.33
  BOTTOM w0.203: R254.1 106.84,96.22 107.85,97.23 v1(109.91,97.23) 110.98,97.23 112.74,99 116.04,99 116.72,98.33
H_CPU_SVIDCLK: length 16.2
  BOTTOM w0.203: R248.2 103.53,94.19 105.08,94.19 105.64,94.74 105.64,94.77 C5212.1 105.7,94.83 107.24,94.83 v1(108.12,95.7) 108.43,96.01 111.05,96.01 113.44,98.4 115.83,98.4 116.42,97.81 117.5,97.81 UC1.N63
H_CPU_SVIDDATA: length 16
  BOTTOM w0.203: R257.1 103.84,96.88 105.39,96.88 105.67,97.16 R256.2 105.98,97.18 106.76,97.18 v1(107.47,97.89) 110.8,97.89 112.3,99.39 116.21,99.39 117.02,98.58 117.49,98.58 UC1.L63
H_CPUPWRGD: length 100.3
  TOP w0.102: v2(81.06,74.01) 81.25,73.81 81.89,73.81 82.76,72.95 82.76,68.96 84.76,66.96 86.81,66.96 88.03,65.74 92.92,65.74 97.03,69.85 97.03,75.21 95.78,76.47 95.19,76.47 94.97,76.25 RC48.1
  IN3 w0.135: v2(81.06,74.01) 80.83,74.23 80.83,78.01 82.73,79.91 84.03,79.91 84.4,80.28 84.4,83.41 84.99,84 84.99,86.64 85.81,87.45 85.81,90.86 85.58,91.09 85.58,92.12 89.75,96.29 90.2,96.29 94.29,100.39 100.38,100.39 101.58,99.19 102.96,99.19 103.83,100.05 108.44,100.05 113.47,105.08 115.96,105.08 v2(116.21,105.34)
  BOTTOM w0.076: UC1.C61 119.14,104.1 119.18,104.14 119.18,104.73 119.08,104.83 119.08,105.36 119,105.44
  BOTTOM w0.102: 119,105.44 118.93,105.51 116.39,105.51 v2(116.21,105.34) 116.16,105.39 116.16,107.49 117.53,108.86 CC27.1 RC66.1
H_PROCHOT#: length 259
  TOP w0.102: v2(147.32,21.9) 147.35,21.92 147.45,21.92 147.78,21.59 147.78,21.11 147.55,20.87 UE5.A46
  TOP w0.254: v2(81.34,105.21) 81.34,104.94 v1(82.82,103.46) 84.25,102.03 88.9,102.03 91.22,99.72 91.22,97.16 92.18,96.19 92.84,96.19 94.14,97.49 v2(94.14,98) ; PR510.1 66.83,103.22 v2(67,103.05)
  IN1 w0.114: v2(43.41,13.54) 44.28,14.4 46.82,14.4 50.46,18.05 51.99,18.05 55.56,21.62 61.14,21.62 62.59,20.17 71.39,20.17 72.55,21.33 73.35,21.33 73.96,21.94 77.64,21.94 v2(78.87,23.17) 88.08,23.17 89.32,24.41 97.64,24.41 97.87,24.18 99.17,24.18 99.65,23.7 100.54,23.7 101.97,22.26 129.97,22.26 131.51,20.72 137.04,20.72 137.61,20.14 138.32,20.14 139.68,21.5 145.11,21.5 145.5,21.9 v2(147.32,21.9) ; v2(83.88,33.02) 84.46,33.59 84.46,51.56 91.03,58.14 91.03,69.82 94.21,73 95.41,73 96.45,74.04 96.45,77.59 96.14,77.89 96.14,83.53 96.74,84.13 96.74,85.78 92.24,90.27 92.24,92.75 91.55,93.45 91.55,94.35 94.14,96.94 v2(94.14,98)
  IN1 w0.254: v2(81.34,105.21) 81.31,105.18 81.03,105.18 80.32,105.89 80.32,106.11 78.81,107.62 75.18,107.62 71.16,103.61 67.69,103.61 67.13,103.05 v2(67,103.05)
  BOTTOM w0.102: PR717.1 37.8,10.98 41.84,10.98 43.41,12.55 v2(43.41,13.54) ; v2(83.88,33.02) 84.62,32.27 84.62,28.07 79.72,23.17 v2(78.87,23.17)
  BOTTOM w0.254: PC510.1 67.37,103.48 67.16,103.28 67.16,103.21 v2(67,103.05) ; v2(94.14,98) 94.72,98 96.47,99.75 100,99.75 101.22,98.53 RC60.2 CA26.1 103.61,98.48 RC67.1
H_PROCHOT#_R: length 13.4
  BOTTOM w0.076: UC1.K63 117.38,99.3 116.31,100.38 115.12,100.38 114.74,100.76 113.06,100.76
  BOTTOM w0.102: 113.06,100.76 111.95,100.76 v1(111.76,100.57) 109.92,98.73 105.92,98.73 RC67.2
H_THERMTRIP#: length 203.3
  TOP w0.102: 161.72,22.41 161.72,23.4 161.14,23.98 160.17,23.98 157.59,26.56
  TOP w0.107: QE9.3 161.72,22.41 ; 157.59,26.56 v2(157.59,27.26)
  IN1 w0.114: v2(157.59,27.26) 157.59,27.71 156.38,28.92 126.55,28.92 125.26,27.64 v2(125.26,27.46) ; v2(118.88,112.04) 119.26,111.66 119.26,109.73 116.81,107.29 115.92,107.29 113.6,104.97 113.39,104.97 110.82,102.4 110.82,101.65 109.15,99.98 105.65,99.98 103.13,102.5 95.18,102.5 91.04,98.36 87.6,98.36 86.03,96.8 86.03,92.23 84.56,90.76 84.56,87.59 83.67,86.7 83.67,85.27 v2(83.82,85.11)
  IN3 w0.135: v2(83.82,85.11) 83.76,85.05 83.76,81.92 80.19,78.36 80.19,73.97 80.9,73.26 81.99,73.26 82.38,72.87 86.88,72.87 87.19,72.56 88.74,72.56 94.21,67.08 94.21,54.87 88.93,49.58 88.93,40.82 94.75,35 98.4,35 105.49,27.92 124.81,27.92 v2(125.26,27.46)
  BOTTOM w0.102: v2(118.88,112.04) 118.65,112.27 116.54,112.27 115.83,111.56 115.83,110.87 115.63,110.67 R2355.2 R2353.2
H_THERMTRIP#_R: length 10.6
  BOTTOM w0.102: UC1.D60 119.22,103.19 119.1,103.3 119.1,103.31 118.83,103.58 118.65,103.58 118.34,103.89 118.3,103.93 117.86,103.93 117.79,104 116.62,104 116.27,104.35 115.14,104.35 114.72,104.77 114.72,106.85 114.53,107.04 v1(114.53,108.03) 115.63,109.12 R2355.1
H_VCCST_PWRGD: length 14
  TOP w0.102: v1(118.37,107.24) v2(118.37,107.95) 118.67,108.26 CC42.1 RC365.1 RC114.1 120.45,108.65 121.24,107.86 122.1,107.86 122.58,108.34 122.58,109.56 123.09,110.07 UC6.4
  BOTTOM w0.076: UC1.B59 120.24,104.52 119.91,104.85 119.91,105.84 118.37,107.39 v2(118.37,107.95)
H_VCCST_PWRGD_XDP: length 71.6
  TOP w0.102: JXDP.39 92.33,78.16 93.27,77.22 93.27,76.89 93.7,76.46 RC48.2 94.2,76.75 95.57,76.75 v2(95.97,77.14) ; v2(120.58,111.94) v1(120.58,111.31) 120.58,110.49 120.45,110.37 RC114.2
  IN1 w0.114: v2(120.58,111.94) 120.58,108.1 118.58,106.11 115.89,106.11 113.7,103.91 113.48,103.91 111.64,102.07 111.64,101.32 109.48,99.16 105.31,99.16 103.17,101.31 95.14,101.31 90.57,96.74 90.57,92.61 91.38,91.8 91.67,91.8 92,91.47 92,90.17 96.5,85.68 96.5,84.23 95.86,83.59 95.86,77.24 v2(95.97,77.14)
H_VR_READY: length 70.4
  TOP w0.102: v2(118.5,111.51) 118.17,111.18 118.17,109.37 RC363.2 117.63,108.89 RC364.1
  TOP w0.254: PR519.2 65.78,104.79 65.78,104.92 65.59,105.1 v2(65.59,105.29) 65.57,105.31 PU501.2
  IN2 w0.127: v2(73.18,110.09) 73.59,109.68 73.59,108 70.29,104.7 66.18,104.7 v2(65.59,105.29)
  IN3 w0.135: v2(118.5,111.51) 118.47,111.48 117.89,111.48 115.87,113.5 107.68,113.5 106.39,114.79 104.98,114.79 103.71,113.52 100.07,113.52 99.06,112.51 96.41,112.51 93.75,109.84 91.05,109.84 90.43,109.22 83.8,109.22 83.27,108.69 76.12,108.69 74.21,110.59 73.69,110.59 v2(73.18,110.09)
  BOTTOM w0.102: R251.1 118.55,110.54 118.42,110.67 118.42,111.43 v2(118.5,111.51) ; v2(65.59,105.29) 64.81,105.29 v1(64.36,104.83)
HDA_SPKR: length 114.6
  TOP w0.102: DA8.3 172.14,8.71 172.14,9.64 171.7,10.09 170.74,10.09 170.09,10.74 170.09,11.89 168.39,13.58 v1(168.39,13.77) 168.39,14.67 v2(168.08,14.99)
  IN1 w0.114: v2(168.08,14.99) 168.08,15.94 171.43,19.29 171.43,23.05 173.69,25.31 173.69,26.71 178.1,31.12 178.1,37.19 180.7,39.79 180.7,43.07 181.21,43.58 181.21,46.67 181.82,47.28 181.82,49.18 182.48,49.84 182.48,56.05 181.33,57.19 181.33,59.73 179.67,61.4 179.67,68.9 179.7,68.93 179.7,69.7 175.57,73.83 175.57,84.7 175.17,85.1 173.99,85.1 172.81,86.29 172.05,86.29 v2(171.95,86.18)
  BOTTOM w0.076: UC1.V2 155.73,94.77 156.01,95.05 156.32,95.05
  BOTTOM w0.102: 156.32,95.05 156.38,94.99 160.2,94.99 161.87,93.32 163.77,93.32 167.14,89.96 169.1,89.96 169.47,89.59 169.47,87.58 170.13,86.92 171.59,86.92 171.76,86.75 171.76,86.37 v2(171.95,86.18) 172.05,86.29 RC121.2
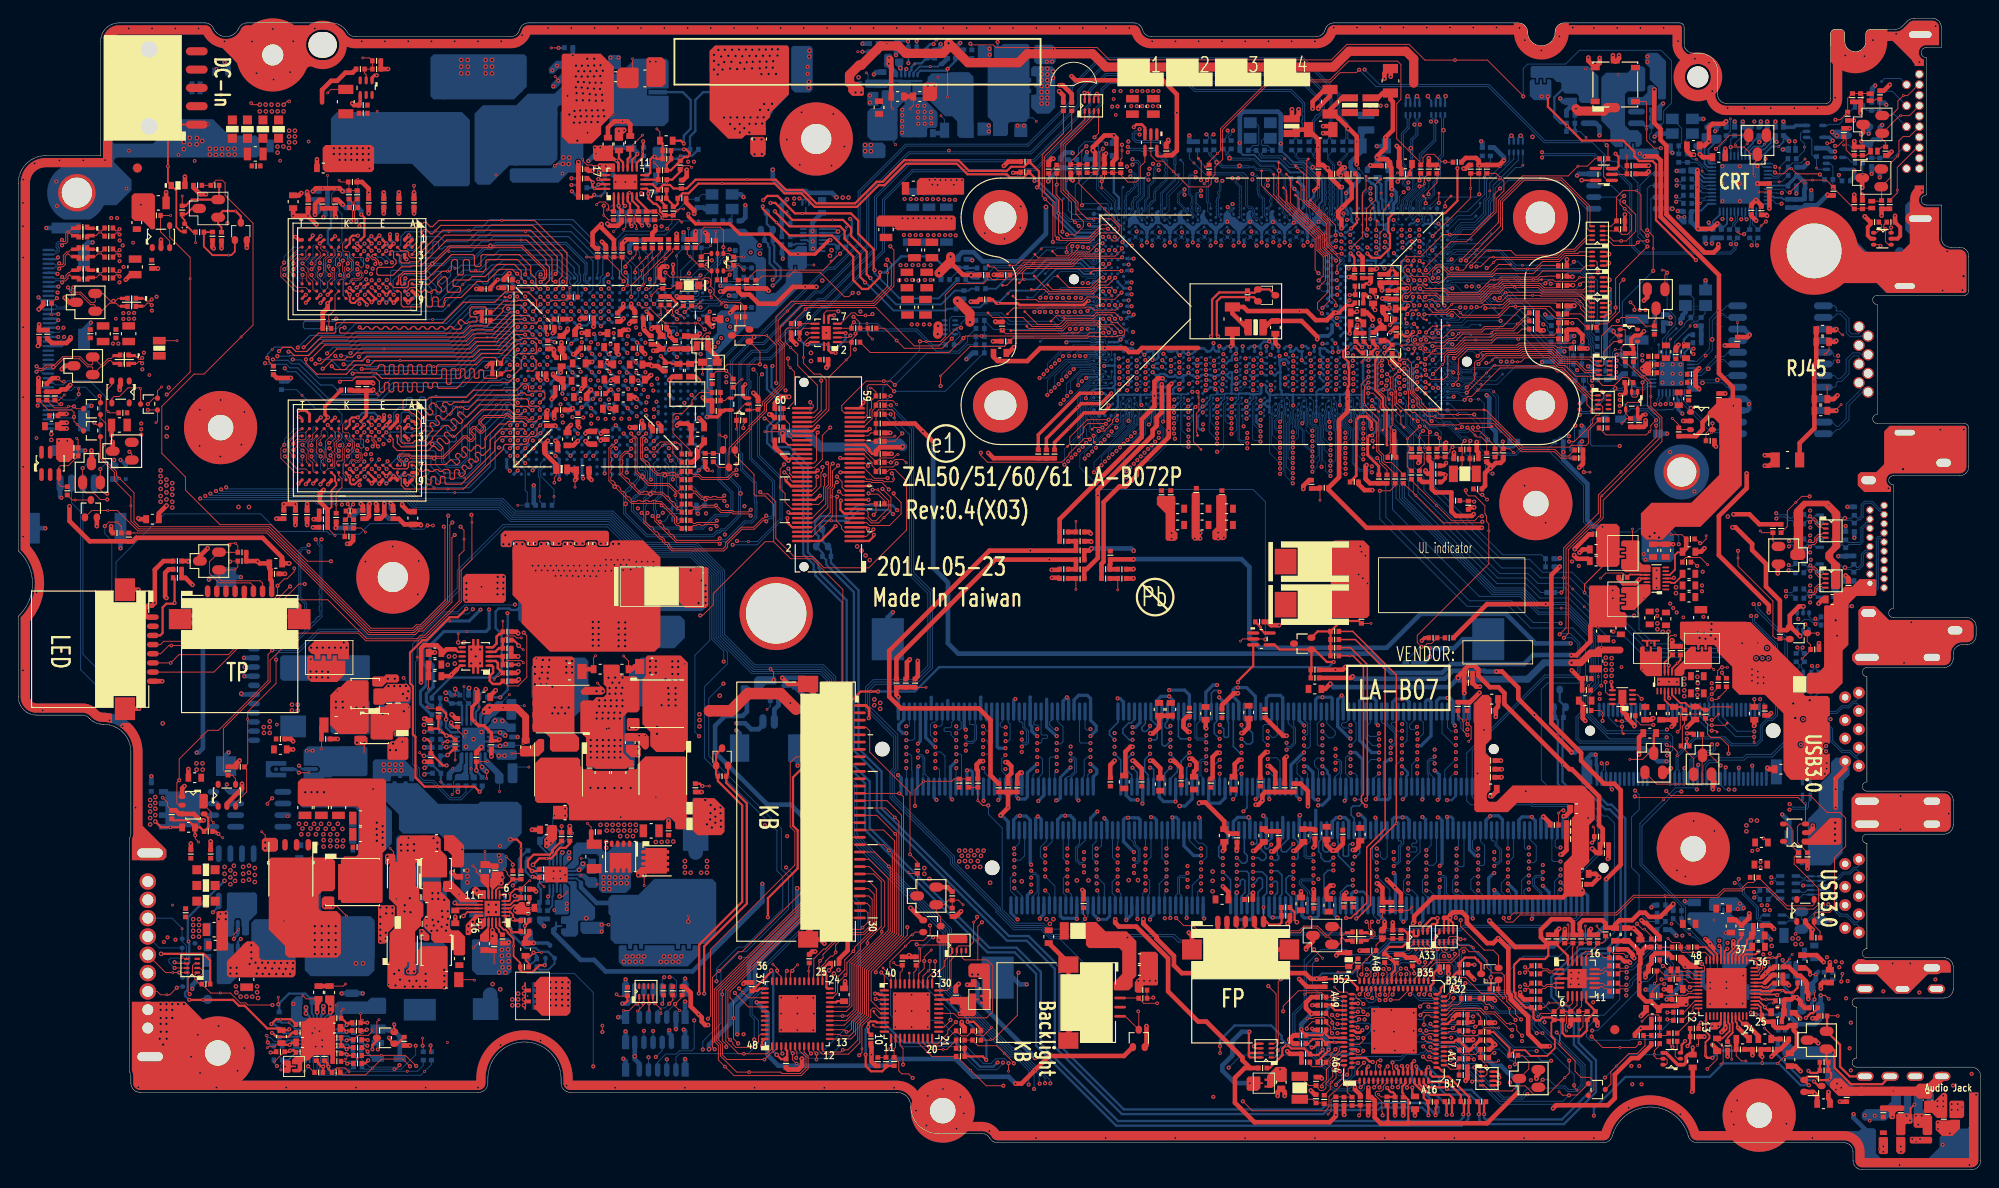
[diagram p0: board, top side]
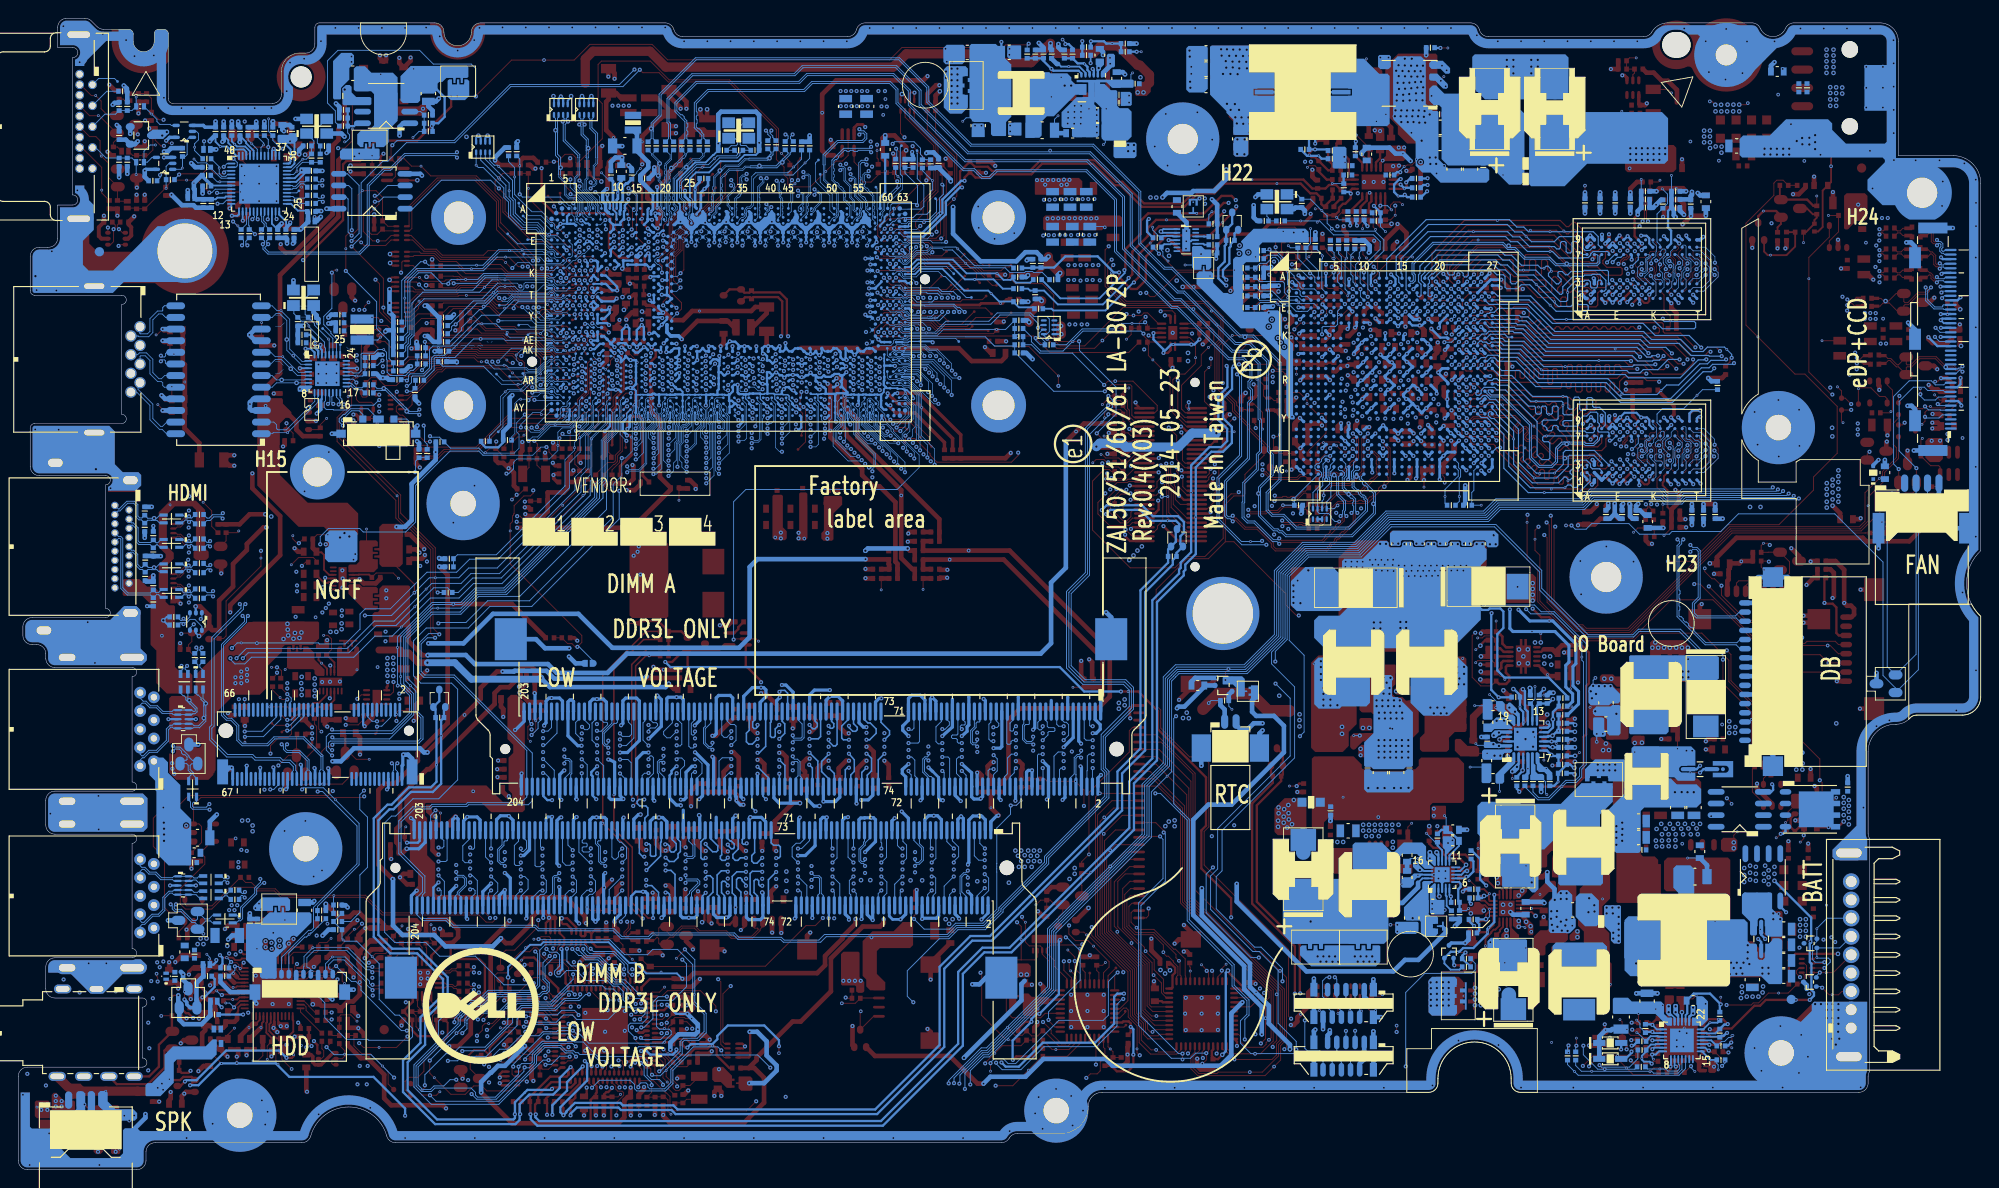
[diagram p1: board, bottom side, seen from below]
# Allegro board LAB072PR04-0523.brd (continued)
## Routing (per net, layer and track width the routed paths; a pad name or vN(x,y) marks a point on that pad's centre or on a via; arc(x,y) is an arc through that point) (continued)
HDD_DET#: length 111.2
  TOP w0.102: v2(161.86,95.2) v1(162.48,95.83) 166.25,95.83 166.45,95.63 170.79,95.63 171.77,94.66 RP37.1
  IN1 w0.114: v2(181.69,41.3) 181.69,41.3 181.45,41.54 181.45,45.63 182.73,46.92 182.73,56.14 181.57,57.29 181.57,59.83 179.91,61.5 179.91,68.81 179.94,68.84 179.94,69.81 175.81,73.94 175.81,84.8 175.27,85.34 174.09,85.34 172.36,87.08 172.36,92.61 170.49,94.48 170.17,94.8 162.27,94.8 v2(161.86,95.2)
  BOTTOM w0.076: v2(161.86,95.2) 161.47,94.81 160.98,94.81 160.4,95.39 156.27,95.39 UC1.U1
  BOTTOM w0.102: JHDD.3 185.65,23.19 182.7,26.14 182.4,26.14 182.15,26.39 182.15,28.65 177.4,33.4 177.4,37.54 181.16,41.3 v2(181.69,41.3)
HDD_DEVSLP: length 98.9
  IN1 w0.114: v2(183.39,41.53) 182.71,42.22 182.71,46.2 183.21,46.71 183.21,50.71 183.94,51.44 183.94,55.67 182.06,57.55 182.06,61.31 180.39,62.97 180.39,68.63 180.42,68.66 180.42,70.02 176.29,74.14 176.29,85 175.47,85.82 174.29,85.82 172.84,87.28 172.84,92.81 170.34,95.32 164.69,95.32 160.25,99.75 157.38,99.75 157.05,99.42 157.05,98.86 v2(156.62,98.43)
  BOTTOM w0.076: UC1.L2 155.59,98.51 155.88,98.22 156.42,98.22 v2(156.62,98.43)
  BOTTOM w0.102: RS8.1 RN5.1 181.72,28.75 177.17,33.3 177.17,37.82 v1(179.75,40.4) 181.06,41.71 183.21,41.71 v2(183.39,41.53)
HDMI_HPLUG: length 14.6
  TOP w0.102: v1(194.89,55.81) 195.81,56.73 RV20.1 195.81,57.32 195.44,57.69 QV5.1 196.52,58.6 v2(196.6,58.52)
  IN3 w0.135: JHDMI.19 203.85,63.42 202.82,62.39 200.55,62.39 199.04,60.89 199.04,59.79 197.77,58.52 v2(196.6,58.52)
HOST_ALERT1_R_N: length 16.4
  TOP w0.102: RC120.2 165.02,93.59 163.28,91.85 160.27,91.85 159.91,91.49 157.54,91.49 v1(157.36,91.32) 156.82,90.78 156.25,90.78 155.84,90.38 154.23,90.38 154.13,90.27 152.75,90.27 152.75,90.27 152.44,90.27 152.41,90.3 152.4,90.3 152.21,90.49 152.21,90.84 152.47,91.1 152.7,91.1 v2(153.09,91.49)
  BOTTOM w0.076: UC1.AD6 152.85,91.73 v2(153.09,91.49)
HOST_DEBUG_TX: length 89.8
  TOP w0.102: v2(149.36,18.52) 149.36,18.54 149.74,18.93 149.74,19.32 149.8,19.38 UE5.B44 ; v1(72.25,17.38) 71.77,17.86 v2(71.77,18.11) 72.52,18.86 RE74.2
  IN1 w0.114: v2(71.77,18.11) 71.77,18.8 72.38,19.42 72.67,19.42 74.43,21.19 78.25,21.19 79.29,22.23 87.47,22.23 88.78,20.92 89.62,20.92 91.5,22.8 95.21,22.8 96.29,21.71 100.56,21.71 101.55,20.72 113.7,20.72 114.1,20.32 121.03,20.32 121.41,19.94 130.37,19.94 130.65,19.66 134.62,19.66 135.13,19.15 136.89,19.15 137.12,18.93 139.05,18.93 139.79,19.66 142.35,19.66 142.98,20.3 144.78,20.3 146.41,18.67 147.17,18.67 147.83,18.01 148.85,18.01 v2(149.36,18.52)
  BOTTOM w0.102: JDEG.8 70.85,17.19 v2(71.77,18.11)
HPOUT-L: length 2.6
  TOP w0.203: UA1.32 190.68,20.42 190.75,20.49 190.81,20.42
  TOP w0.508: 190.81,20.42 191.65,21.26 RA55.1
HPOUT-R: length 2.8
  TOP w0.203: UA1.33 189.67,20.83 190.3,20.83 190.5,21.03
  TOP w0.508: RA56.1 191.69,21.96 191.43,21.96 v1(190.89,21.41) 190.5,21.03
HSYNC: length 3.5
  BOTTOM w0.102: UV6.4 191.53,108.69 191.73,108.49 192.16,108.49 192.45,108.78 v1(192.45,109.39) 192.45,109.53 RV170.1
HSYNC_CONN: length 6.7
  BOTTOM w0.102: JCRT.13 204.94,115.28 203.78,115.28 CV59.1 RV38.2 201.98,115.67 LV19.2 v1(201.52,117.15)
HSYNC_CRT: length 4.5
  BOTTOM w0.102: UV5.4 197.68,114.05 197.79,114.16 198.94,114.16 199.25,114.48 199.25,114.71 v1(199.83,115.29) LV19.1
HSYNC_R: length 4.1
  BOTTOM w0.102: RV170.2 195.14,111.31 v1(195.14,111.67) 195.14,112.05 194.71,112.49 194.71,113.17 194.94,113.4 UV5.2
I2C0_SCL: length 14.6
  BOTTOM w0.076: 159.37,103.74 159.06,103.43 157.62,103.43 157.01,102.82 157.01,102.61 156.43,102.03 155.66,102.03 155.61,101.98 155.46,101.98 154.95,101.47 UC1.F3
  BOTTOM w0.102: 159.37,103.74 160.1,104.47 160.1,105.91 160.41,106.22 160.41,108.05 v1(161.9,109.55) 162.06,109.7 162.39,109.7 162.88,110.19 RP53.4
I2C0_SDA: length 14.2
  BOTTOM w0.076: 159.56,103.55 159.19,103.18 157.69,103.18 157.2,102.69 157.2,102.5 156.57,101.87 155.85,101.87 UC1.F2
  BOTTOM w0.102: 159.56,103.55 160.33,104.32 160.33,105.82 160.77,106.26 v1(160.77,106.91) 160.77,107.75 163.38,110.36 RP53.3
I2C1_SCL_TCH_PAD: length 13.9
  BOTTOM w0.076: 159.75,103.36 159.31,102.92 157.76,102.92 157.41,102.57 157.41,102.42 156.54,101.55 156.14,101.55 UC1.F1
  BOTTOM w0.102: RP53.2 163.88,110.26 v1(161.81,108.19) 161.13,107.51 161.13,106.3 160.61,105.78 160.61,104.22 159.75,103.36
I2C1_SDA_TCH_PAD: length 16.9
  BOTTOM w0.076: 159.94,103.17 159.44,102.67 157.82,102.67 157.61,102.45 157.61,102.34 156.37,101.1 154.68,101.1 154.38,100.8 UC1.G4
  BOTTOM w0.102: 159.94,103.17 160.84,104.07 160.84,105.68 161.36,106.2 161.36,107.22 163.6,109.46 164.14,109.46 v1(164.38,109.7) RP53.1
I_ADP: length 126.5
  TOP w0.102: PR716.1 37.53,12.49 v1(39.67,12.49) 42.3,12.49 43.45,11.33 v2(43.46,11.33) ; UE5.A12 152.05,9.45 151.72,9.12 v2(151.72,8.95)
  IN1 w0.114: v2(132.24,11.14) 131.6,11.78 109.78,11.78 109.08,12.47 105.59,12.47 104.92,11.8 98.76,11.8 97.53,13.03 91.71,13.03 89.4,10.72 65.27,10.72 59.97,16.02 51.16,16.02 46.04,10.9 43.9,10.9 v2(43.46,11.33)
  BOTTOM w0.102: v2(151.72,8.95) 150.9,9.77 147.54,9.77 147.07,9.3 147.07,8.84 146.83,8.6 143.69,8.6 142.88,9.41 142.88,10.85 141.2,12.52 133.62,12.52 v2(132.24,11.14)
I_BATT: length 113
  TOP w0.102: v2(42.79,11.29) 42,12.08 39.67,12.08 v1(38.69,11.1) 37.95,10.37 35.44,10.37 PR718.1 ; RE64.2 141.36,16.16 140.77,15.57 v2(140.77,15.39)
  IN1 w0.114: v2(140.77,15.39) 140.38,15.79 136.39,15.79 136.03,16.14 115.89,16.14 115.01,17.02 103.51,17.02 103.08,16.59 102.7,16.59 102.51,16.78 101.74,16.78 100.53,17.99 94.86,17.99 94.4,17.53 81.23,17.53 80.81,17.11 75.34,17.11 73.99,15.76 63.72,15.76 63.22,16.26 51.06,16.26 46.92,12.12 43.62,12.12 v2(42.79,11.29)
I_SYS: length 120.6
  TOP w0.102: PR720.1 32.34,10.62 v2(31.65,11.31) ; v2(144.12,14.92) 144.12,14.92 UE5.A57
  IN1 w0.114: v2(31.65,11.31) 32.22,11.31 33.15,10.38 39.08,10.38 41.09,12.38 46.85,12.38 50.96,16.5 63.36,16.5 63.86,16 72.88,16 74.47,17.59 80.61,17.59 81.03,18.01 94.19,18.01 94.65,18.47 100.73,18.47 101.44,17.76 114.96,17.76 115.96,16.75 126.41,16.75 126.53,16.63 136.34,16.63 136.69,16.27 141.94,16.27 142.83,15.38 143.67,15.38 144.12,14.93 v2(144.12,14.92)
  BOTTOM w0.102: v1(31.23,10.73) 31.65,11.15 v2(31.65,11.31)
ILMT_1.05V: length 3.9
  BOTTOM w0.254: PR306.1 PR304.2 98.67,120.83 97.97,120.83 v1(97.9,120.76) 97.59,120.45 97.59,120.11 97.35,119.87 97.35,119.57 PU300.3
IMON: length 4.5
  TOP w0.254: v2(66.29,105.26) 66.07,105.49 PU501.3
  BOTTOM w0.102: PR521.2 65.57,103 v1(65.03,102.45)
  BOTTOM w0.254: v2(66.29,105.26) 65.57,104.54 PC500.2 PR521.2
INT-SPK-L+: length 63.4
  TOP w0.203: v2(187.38,24.31) 187.38,24.11 186.82,23.55 186.82,22.88 UA1.42
  TOP w0.508: v2(187.38,24.95) v2(187.38,24.31)
  IN1 w1.016: v2(177.35,9.32) 177.8,9.77 191.12,9.77 195.71,5.18 200.79,5.18 203.1,2.87 203.43,2.87 v2(203.76,2.54)
  IN3 w1.016: v2(177.35,9.32) v2(176.33,9.32) 175.98,9.32 174.07,11.23 174.07,22.18 179.63,27.74 186.08,27.74 187.6,26.23
  vias: v1(203.34,2.25) v2(203.76,1.96)
INT-SPK-L-: length 58.4
  TOP w0.203: v2(186.72,24.13) 186.72,24.16 186.42,23.86 UA1.43
  IN1 w1.016: v2(177.09,11.33) 177.25,11.18 191.75,11.18 196.6,6.33 199.42,6.33 200.13,7.04 203.33,7.04 203.81,6.56 203.81,5.34 205.67,3.48 v2(205.67,2.54)
  IN3 w1.016: v2(177.09,11.33) v2(176.23,11.33) 176,11.56 176,17.53 176.84,18.37 176.84,21.44 177.41,22.01 177.41,23.48 180.4,26.47 185.42,26.47
  vias: v2(186.75,24.78) v2(205.69,1.96)
INT-SPK-R+: length 52.9
  TOP w0.203: 185.22,24.18 185.22,23.93 185.62,23.53 UA1.45
  TOP w0.508: v2(184.33,25.2) v2(184.84,24.69) 184.84,24.56 185.22,24.18
  IN3 w1.016: 184.08,25.2 182.68,25.2 182.05,24.56 180.43,24.56 178.64,22.77 178.64,16.71 178.12,16.19 178.12,12.28 180.98,9.43 185.98,9.43 186.41,9.86 190.83,9.86 195.51,5.18 200.74,5.18 201.38,4.55 205.03,4.55 206.23,3.36 v2(206.91,3.36)
  vias: v1(207.34,3.04) v2(207.78,3.36)
INT-SPK-R-: length 50.4
  TOP w0.203: UA1.44 186.02,22.87 186.02,24.27 v2(185.86,24.44)
  IN3 w1.016: 210.28,5.91 210.18,6.01 209.26,6.01 208.23,7.04 200.05,7.04 199.56,6.54 196.28,6.54 191.62,11.2 185.78,11.2 185.58,11 181.74,11 179.84,12.91 179.84,14.84 181.03,16.03 181.03,22.34 181.86,23.17 182.27,23.17 182.78,23.68 185.2,23.68 185.35,23.83
  vias: v1(212.36,6.83) v2(185.86,25.02) v2(211.23,7.17) v2(211.23,6.53) v2(211.89,7.17) v2(211.89,6.53)
INTRUDER#: length 7.1
  TOP w0.102: RC7.2 154.11,80.44 v2(154.23,80.57) 154.23,80.61 v1(153.64,81.21)
  BOTTOM w0.076: UC1.AU6 153.09,84.02 153.09,83.54 153.06,83.5 153.06,82.15 153.33,81.87 153.33,81.5 154.23,80.6 v2(154.23,80.57)
IRQ_SERIRQ: length 117.2
  TOP w0.102: v2(164.29,14.63) 163.71,15.22 163.71,15.67 163.43,15.95 v1(163.01,15.95) 162.62,15.95 161.33,17.24 160.19,17.24 159.8,17.63 156.75,17.63 156.03,16.92 UE5.A28
  IN1 w0.114: v2(164.29,14.63) 164.46,14.63 165.6,15.77 165.6,16.23 168.33,18.96 168.33,21.96 169.24,22.87 169.89,22.87 172.71,25.69 172.71,27.1 177.02,31.41 177.02,37.49 178.93,39.41 178.93,47.96 179.47,48.49 179.47,51.89 178.39,52.97 178.39,55.41 177.69,56.11 177.69,61.02 177.1,61.6 177.1,63.82 177.54,64.25 177.54,64.82 176.8,65.56 176.8,70.87 174.36,73.31 174.36,77.55 172.6,79.31 172.6,83.3 170.98,84.92 170.98,86.01 166.15,90.85 166.15,91.85 v2(166.62,92.32)
  BOTTOM w0.076: 162.03,95.95 159.96,95.95 159.9,95.89 157.76,95.89 157.03,96.62 156.49,96.62 156.42,96.55 156.01,96.55 155.83,96.37 155.83,96.14 155.66,95.96 154.53,95.96 UC1.T4
  BOTTOM w0.102: RC102.2 167.06,91.73 167.06,92.06 166.93,92.19 166.74,92.19 v2(166.62,92.32) 164.29,94.64 163.36,94.64 162.06,95.95 162.03,95.95
ISOLATEB: length 3.9
  BOTTOM w0.102: UL1.20 177.68,86.73 177.63,86.68 v1(177.47,86.68) 176.77,86.68 RL33.2 R2360.2 RL30.1
ISPSCL: length 12
  TOP w0.102: v1(190.4,103.08) 190.89,103.56 v2(190.94,103.56)
  IN3 w0.135: v2(191.95,109.53) 191.7,109.53 190.69,108.52 190.69,104.66 190.63,104.59 190.63,103.87 v2(190.94,103.56)
  BOTTOM w0.102: v2(190.94,103.56) 190.06,102.68 RV163.1 189.46,103.28 189.46,104.1 189.49,104.13 UV6.15 ; v2(191.95,109.53) 191.59,109.89 UV6.1
ISPSDA: length 15
  TOP w0.102: v2(188.55,102.18) 188.11,102.18 v1(187.88,102.42)
  IN3 w0.135: v2(190.88,110.41) 190.87,110.41 190.43,109.96 190.43,104.76 190.36,104.7 190.36,103.24 189.29,102.16 188.56,102.16 v2(188.55,102.18)
  BOTTOM w0.102: v2(190.88,110.41) 190.48,110 190.48,109.64 190.63,109.49 190.64,109.49 UV6.2 ; UV6.16 189.09,104.2 189.23,104.06 189.23,103.14 189.17,103.08 RV164.1 189.05,102.68 v2(188.55,102.18)
ISUMN: length 19
  TOP w0.254: PR549.1 PC530.1 71.3,110.26 70.84,109.8 PR535.2 71.29,109.15 PR545.2 72.74,110.59 73.12,110.59 v1(73.35,110.82) 73.35,111.04 72.95,111.43 v2(72.72,111.43)
  BOTTOM w0.254: PL502.3 74.83,117.69 73.97,116.83 73.97,113.43 73.38,112.84 PH501.1 v2(72.72,111.43) 71.43,111.43 PR549.1
ISUMP: length 7.3
  TOP w0.102: v1(69.77,113.67) 70.1,113.34 PR536.2
  TOP w0.254: PU501.10 68.8,108.63 69.04,108.87 69.04,110.34 69.32,110.62 v2(69.52,110.62) 69.73,110.42 PC530.2 PR549.2 70.39,112.09 PR536.2
IT6511_AUX#_C: length 2.2
  BOTTOM w0.102: UV6.19 187.89,104.18 187.81,104.1 187.81,103.55 187.53,103.27 187.53,102.99 CV350.2
IT6511_AUX_C: length 2.3
  BOTTOM w0.102: CV349.2 187.32,103.06 187.32,103.36 187.59,103.64 187.59,104.12 187.49,104.23 UV6.20
IT6511_N0_C: length 2.4
  BOTTOM w0.102: UV6.27 184.41,106.29 184.41,106.29 184.23,106.11 183.14,106.11 CV346.2
IT6511_N1_C: length 2.6
  BOTTOM w0.102: CV348.2 182.83,108.15 183.09,107.89 183.62,107.89 184.12,107.4 184.37,107.4 184.46,107.49 UV6.30
IT6511_P0_C: length 2.4
  BOTTOM w0.102: CV342.2 182.84,105.54 v1(183.76,105.54) 184.11,105.89 UV6.26
IT6511_P1_C: length 2.6
  BOTTOM w0.102: CV347.2 183.2,107.68 183.53,107.68 184.03,107.18 184.37,107.18 184.46,107.09 UV6.29
JACK_SENSE#: length 19.4
  TOP w0.203: 184.33,13.52 184.33,13.92 184.76,14.35 184.76,14.67 184.36,15.08 184.36,16.27 184.42,16.33 UA1.13
  TOP w0.254: v2(196.19,9.63) 196.68,9.15 QA7.1 ; 184.33,13.52 v1(184.33,12.55) 184.33,12.4 184.51,12.22 v2(185.1,12.22)
  BOTTOM w0.254: v2(185.1,12.22) 185.89,13.01 191.7,13.01 194.94,9.77 196.05,9.77 v2(196.19,9.63)
JCRT-11: length 3.2
  BOTTOM w0.102: JCRT.11 205.62,119.18 203.89,119.18 T87.1
JHDD_P10: length 7.9
  BOTTOM w0.102: JHDD.4 184.84,23.67 183.11,25.41 182.92,25.41 v1(182.62,25.71) 182.47,25.85 182.36,25.85 RS8.2
JTAG_CLK: length 88.6
  TOP w0.102: RPE7.3 68.83,18.26 v2(68.91,18.18) v1(68.91,17.38) ; UE5.B56 146.28,17.17 v2(146.36,17.24)
  IN1 w0.114: v2(146.36,17.24) 146.25,17.24 145.45,18.04 145.45,18.95 144.58,19.81 143.18,19.81 142.55,19.18 139.99,19.18 139.25,18.44 136.92,18.44 136.69,18.67 134.93,18.67 134.42,19.18 129.52,19.18 129.25,19.45 102.14,19.45 100.36,21.23 96.09,21.23 95.07,22.25 92.6,22.25 90.35,20 89.01,20 87.99,21.02 78.93,21.02 77.8,19.88 73.82,19.88 72.87,18.94 72.65,18.94 72.42,18.71 72.42,17.77 72.1,17.45 69.64,17.45 v2(68.91,18.18)
  BOTTOM w0.102: JDEG.4 68.85,18.11 v2(68.91,18.18)
JTAG_RST#: length 16.4
  TOP w0.102: v2(146.74,21.32) 146.89,21.47 146.89,22.56 v1(147.32,22.99) 148.26,23.93 CE59.1 148.34,24.54 JTAG1.1 150.14,25.22 RE66.1 RE65.2 ; UE5.B47 148.3,19.29 148.34,19.25 148.34,18.93 148.72,18.55 v2(148.72,18.52)
  IN3 w0.135: v2(148.72,18.52) 149.2,18.04 150.27,18.04 150.63,18.4 150.63,19.56 150.45,19.74 149.76,19.74 148.65,20.86 147.16,20.86 146.74,21.27 v2(146.74,21.32)
JTAG_TDI: length 87.7
  TOP w0.102: RPE7.1 67.83,18.38 v2(67.59,18.14) 67.49,18.14 66.74,17.39 v1(66.11,17.39) ; v2(144.1,18.01) 144.1,18.02 144.2,17.92 UE5.A51
  IN1 w0.114: v2(144.1,18.01) 144.1,19.05 143.82,19.33 143.39,19.33 142.75,18.7 140.19,18.7 139.45,17.96 136.72,17.96 136.49,18.19 134.73,18.19 134.22,18.7 125.29,18.7 124.73,18.14 118.36,18.14 117.77,18.72 101.84,18.72 100.06,20.51 95.79,20.51 95.42,20.88 92.62,20.88 90.77,19.04 88.3,19.04 87.48,19.85 80.5,19.85 79.2,18.56 74.07,18.56 72.48,16.97 68.76,16.97 v2(67.59,18.14)
  BOTTOM w0.102: JDEG.2 67.85,17.88 v2(67.59,18.14)
JTAG_TDO: length 89.8
  TOP w0.102: UE5.B55 146.63,17.67 146.95,17.34 v2(146.95,17.25) ; RPE7.4 69.33,18.4 v2(69.55,18.19) 70.22,17.52 v1(70.22,17.06)
  IN1 w0.114: v2(69.55,18.19) 70.04,17.69 72,17.69 72.18,17.87 72.18,18.84 72.52,19.18 72.77,19.18 73.72,20.13 77.7,20.13 78.83,21.26 88.09,21.26 88.68,20.68 89.72,20.68 91.6,22.56 95.11,22.56 96.19,21.47 100.46,21.47 102.24,19.69 129.57,19.69 129.84,19.42 134.52,19.42 135.03,18.91 136.79,18.91 137.02,18.68 139.15,18.68 139.89,19.42 142.45,19.42 143.08,20.06 144.68,20.06 145.69,19.05 145.69,18.18 146.14,17.73 146.54,17.73 146.95,17.31 v2(146.95,17.25)
  BOTTOM w0.102: JDEG.5 69.35,18.39 v2(69.55,18.19)
JTAG_TMS: length 87.8
  TOP w0.102: v2(144.14,16.88) 144.16,16.91 144.84,16.91 UE5.A53 ; v1(67.64,17.31) 68.27,17.93 v2(68.27,18.19) 68.33,18.26 RPE7.2
  IN1 w0.114: v2(144.14,16.88) 144.52,17.27 144.52,18.98 143.92,19.57 143.29,19.57 142.65,18.94 140.09,18.94 139.35,18.2 136.82,18.2 136.59,18.43 134.83,18.43 134.32,18.94 125.19,18.94 124.63,18.38 118.46,18.38 117.87,18.96 101.94,18.96 100.16,20.75 95.89,20.75 95.52,21.12 92.52,21.12 90.67,19.28 88.4,19.28 87.58,20.09 80.4,20.09 79.1,18.8 73.97,18.8 72.38,17.21 69.24,17.21 v2(68.27,18.19)
  BOTTOM w0.102: JDEG.3 68.35,18.27 v2(68.27,18.19)
KB_BL_PWM#: length 4.7
  TOP w0.102: v3(122.36,17.3) 122.42,17.24 QE11.1 120.96,16.75 JKBBL.4
KB_DET#: length 156.2
  TOP w0.102: v2(90.91,28.53) 90.91,27.75 91.16,27.5 JKB.30 ; v3(160.47,73.19) v2(159.95,73.71) 159.72,73.71 159.08,74.35 RC103.1
  IN1 w0.114: v2(154.55,85.39) 154.55,82.59 155.63,81.52 155.63,79.83 155.5,79.71 155.5,75.75 156.35,74.89 158.77,74.89 v2(159.95,73.71) 160.81,73.71 161.73,72.8 161.73,71.23 164.21,68.75 169.79,68.75 171,67.54 171,65.86 170.25,65.11 170.25,58.66 170.58,58.33 170.58,53.96 167.57,50.95 167.57,36.22 167.06,35.71 167.06,30.89 163.96,27.79 163.96,27.31 162.5,25.85 159.73,25.85 158.73,24.84 157.88,24.84 157.68,24.64 155.81,24.64 155.53,24.36 155.53,23.88 155.33,23.68 151.74,23.68 150.35,25.07 135.7,25.07 133.87,23.24 131.78,23.24 131.07,23.95 103.01,23.95 99.62,27.35 96.68,27.35 95.49,28.53 v2(90.91,28.53)
  BOTTOM w0.076: v2(154.55,85.39) 154.55,85.29 154.84,85.01 UC1.AT3
KSI0: length 22.8
  TOP w0.102: JKB.22 92.95,33.9 95.04,31.82 95.04,26.14 91.3,22.4 91.3,17.5 90.59,16.78 v3(90.06,16.78) U2412.18
KSI1: length 19.8
  TOP w0.102: U2412.20 90.62,17.78 90.85,18.01 90.85,22.59 92.78,24.52 v3(92.78,24.75) 92.78,25.05 94.28,26.55 94.28,31.49 93.46,32.3 JKB.24
KSI2: length 14.9
  TOP w0.102: JKB.26 92.88,30.7 93.51,30.06 93.51,26.43 91.36,24.28 91.36,23.99 v3(91.24,23.87) 90.3,22.93 90.3,21.82 89.28,20.8 89.28,19.43 89.14,19.28 U2412.23
KSI3: length 21.1
  TOP w0.102: U2412.19 90.46,17.28 91.08,17.9 91.08,22.5 94.33,25.75 v3(94.33,25.99) 94.33,26.27 94.66,26.6 94.66,31.43 92.99,33.1 JKB.23
KSI4: length 14.1
  TOP w0.102: U2412.25 87.86,21.09 87.71,21.24 87.71,22.18 88.2,22.66 88.2,22.77 88.22,22.8 88.23,22.8 88.75,23.31 88.96,23.31 89.3,23.65 v3(89.3,23.75) 89.3,24.54 90.43,25.67 92.4,25.67 93.29,26.56 93.29,29.53 92.92,29.9 JKB.27
KSI5: length 16.3
  TOP w0.102: JKB.25 92.94,31.5 93.74,30.7 93.74,26.34 91.98,24.57 91.98,24.05 90.53,22.6 90.53,21.41 v3(90.36,21.25) 89.51,20.39 89.51,19.33 88.97,18.78 U2412.22
KSI6: length 13
  TOP w0.102: JKB.28 92.72,29.1 93.06,28.77 93.06,26.66 92.3,25.9 90.31,25.9 87.92,23.51 87.92,23.14 v3(87.6,22.81) 87.48,22.7 87.48,21.26 87.36,21.14 U2412.26
KSI7: length 12
  TOP w0.102: JKB.29 92.59,28.3 92.83,28.06 92.83,27.03 v3(92.23,26.43) 92.04,26.24 90.33,26.24 88.17,24.08 87.96,24.08 86.91,23.03 86.91,21.17 86.86,21.12 U2412.27
KSO00: length 39.4
  TOP w0.102: JKB.13 v3(96.23,41.1) 96.32,41.1 96.71,40.71 96.71,25.52 92.9,21.71 92.9,16.78 91.94,15.81 91.94,13.87 90.7,12.63 87.84,12.63 87.36,13.11 U2412.11
KSO01: length 33.1
  TOP w0.102: U2412.13 90.98,14.28 91.48,14.79 91.48,16.02 92.45,16.98 92.45,21.91 96.21,25.67 96.21,38.03 v3(95.76,38.48) 94.73,39.5 93.18,39.5 JKB.15
KSO02: length 36.6
  TOP w0.102: U2412.12 87.86,13.06 88.07,12.85 89.86,12.85 v3(90.09,13.08) 90.63,13.08 91.71,14.16 91.71,15.92 92.68,16.88 92.68,21.81 96.49,25.62 96.49,38.72 94.91,40.3 93.39,40.3 93.38,40.3 JKB.14
KSO03: length 31.2
  TOP w0.102: JKB.16 93.16,38.7 93.79,38.7 v3(95.81,36.68) 95.98,36.51 95.98,25.78 92.22,22.02 92.22,17.08 91.25,16.12 91.25,15.04 90.83,14.62 89.88,14.62 89.72,14.78 U2412.14
KSO04: length 26.5
  TOP w0.102: U2412.16 90.26,15.78 91.76,17.29 91.76,22.21 95.5,25.95 95.5,34.51 v3(95.11,34.89) 94.5,35.5 JKB.20
KSO05: length 24.5
  TOP w0.102: JKB.21 92.79,34.7 93.54,34.7 v3(95.11,33.12) 95.27,32.97 95.27,26.04 91.53,22.31 91.53,17.39 90.43,16.28 U2412.17
KSO06: length 29.4
  TOP w0.102: U2412.15 90.25,15.28 v3(90.48,15.05) 90.72,15.05 91.03,15.36 91.03,16.22 91.99,17.19 91.99,22.12 95.72,25.85 95.72,35.92 94.54,37.1 JKB.18
KSO11: length 35.6
  TOP w0.102: JKB.19 91,36.3 90.9,36.4 89.66,36.4 v2(89.66,36.4) ; U2412.5 84.36,12.98 v2(84.61,12.73) 84.61,12.46 84.57,12.42 84.57,12 84.98,11.6 v3(85.04,11.6)
  BOTTOM w0.102: v2(84.61,12.73) 85.78,12.73 86.34,12.17 88.42,12.17 92,15.75 92,29.14 89.34,31.8 89.34,36.08 v2(89.66,36.4)
KSO12: length 32.3
  TOP w0.102: U2412.10 86.86,13.02 v2(87.2,12.68) v3(87.2,12.03) ; JKB.17 90.13,37.9 89.26,37.03 v2(89.26,36.83)
  BOTTOM w0.102: v2(89.26,36.83) 89.08,36.65 89.08,31.51 91.75,28.84 91.75,16.79 87.63,12.68 v2(87.2,12.68)
KSO13: length 54.4
  TOP w0.102: JKB.7 89.77,45.9 86.29,42.42 86.29,29.61 76.31,19.63 76.31,14.06 76.71,13.66 76.71,12.43 78.48,10.66 v3(79.85,10.66) 83.29,10.66 83.44,10.51 85.42,10.51 86.06,11.14 86.06,12.3 85.36,13 U2412.7
KSO14: length 53.6
  TOP w0.102: JKB.5 90.03,47.5 85.83,43.3 85.83,30.56 79.07,23.8 78.64,23.8 v3(76.55,21.71) 75.85,21.01 75.85,13.39 v2(76.08,13.16) ; U2412.6 84.86,13.09 85.07,12.88 85.07,12.29 v2(84.98,12.2)
  IN3 w0.135: v2(84.98,12.2) 84.44,11.66 77.58,11.66 v2(76.08,13.16)
KSO15: length 56.3
  TOP w0.102: U2412.8 85.86,12.85 86.29,12.42 86.29,11.03 85.54,10.28 78.19,10.28 v3(77.2,11.26) 76.48,11.98 76.48,13.56 76.08,13.97 76.08,19.72 86.06,29.7 86.06,43.21 89.55,46.7 JKB.6
KSO16: length 45
  TOP w0.102: v2(86.61,12.69) 86.36,12.95 U2412.9 ; v2(78.64,13.79) 78.13,14.3 v3(78.13,16.55) 78.13,18.39 77.75,18.77 77.75,19.46 87.43,29.14 87.43,39.39 89.94,41.9 JKB.12
  IN3 w0.135: v2(78.64,13.79) 79.49,12.94 82.07,12.94 82.31,13.18 85.04,13.18 85.53,12.69 v2(86.61,12.69)
KSO17: length 46.3
  TOP w0.102: v2(77.35,13.4) 77.35,13.67 76.92,14.1 v3(76.92,19.15) 76.92,19.59 86.75,29.42 86.75,40.94 90.1,44.3 JKB.9 ; v2(83.48,12.68) 83.36,12.8 U2412.3
  IN3 w0.135: v2(77.35,13.4) 78.68,12.07 83.05,12.07 83.48,12.5 v2(83.48,12.68)
KSO18: length 47.2
  TOP w0.102: U2412.2 82.86,13.23 82.48,12.86 82.36,12.86 v3(81.53,12.03) 77.44,12.03 76.94,12.52 76.94,13.75 76.53,14.16 76.53,19.53 86.52,29.52 86.52,41.67 89.95,45.1 JKB.8
KSO19: length 42.3
  TOP w0.102: U2412.1 82.36,13.24 81.77,12.66 v3(79.28,12.66) 78.69,12.66 77.3,14.05 77.3,19.65 86.97,29.33 86.97,39.73 90.75,43.5 JKB.10
KSO20: length 40.6
  TOP w0.102: JKB.11 90.42,42.7 87.2,39.48 87.2,29.23 77.53,19.55 77.53,14.42 v3(77.76,14.18) 78.07,13.87 78.07,13.69 78.4,13.36 80.22,13.36 80.88,14.02 80.88,14.58 81.08,14.78 U2412.47
LAN_CLKREQ#: length 31.8
  IN1 w0.114: v2(171.95,85.6) 173.15,85.6 174.69,84.06 v2(174.97,84.06)
  BOTTOM w0.076: 161.45,91.8 156.17,91.8 UC1.AD1
  BOTTOM w0.102: v2(171.95,85.6) 171.81,85.6 171.44,85.97 171.44,86.58 171.32,86.69 170.04,86.69 169.24,87.48 169.24,88.65 168.96,88.94 167.82,88.94 R2340.2 167.17,89.4 164.19,92.38 v1(163.76,92.38) 162.2,92.38 161.61,91.8 161.45,91.8 ; UL1.12 180.83,83.98 180.98,83.83 180.98,83.25 180.75,83.02 179.99,83.02 179.94,82.97 178.57,82.97 178.05,83.49 175.57,83.49 175,84.06 v2(174.97,84.06)
LAN_DISABLE#_R: length 179.6
  TOP w0.102: UE4.1 94.62,21.21 v2(94.29,21.54) ; v2(108.18,11.64) v1(108.18,10.76)
  IN1 w0.114: v2(108.18,11.64) 108.18,11.61 108.6,11.19 130.42,11.19 131.65,9.96 137.42,9.96 138.27,10.81 138.27,11.03 138.68,11.43 141.46,11.43 142.18,10.71 143.46,10.71 144.78,9.39 144.78,9.07 145.57,8.29 152.26,8.29 154.09,10.12 157.2,10.12 157.8,10.72 159.87,10.72 161.57,9.02 163.15,9.02 163.99,9.86 164.31,9.86 167.61,13.15 167.68,13.15 169.02,14.49 169.02,15.85 170.65,17.48 171.89,17.48 172.62,18.21 172.62,22.87 175.56,25.81 176.51,25.81 178.85,28.15 178.85,36.91 182.08,40.15 183.27,40.15 184.05,40.93 184.05,44.83 183.7,45.19 183.7,50.51 184.58,51.4 184.58,55.71 182.55,57.75 182.55,64.02 181.53,65.04 181.53,66.77 181.86,67.1 181.86,69.28 176.78,74.36 176.78,85.2 174.98,87 174.98,88.02 v2(174.62,88.38)
  BOTTOM w0.102: v2(94.29,21.54) 94.31,21.54 95.31,20.55 95.31,16.87 95.86,16.31 100.72,16.31 105.44,11.58 106.25,11.58 106.79,12.12 107.75,12.12 108.18,11.69 v2(108.18,11.64) ; R2360.1 175.57,87.86 175.14,87.86 v2(174.62,88.38)
LAN_EN: length 112.3
  TOP w0.102: UE5.B37 153.3,19.43 v2(153.02,19.15) ; v2(169.98,9.22) 169.98,9.01 v1(170.3,8.69) ; RL27.2 184.38,80.43 184.78,80.83 UL2.4 185.09,81.52 v2(185.09,81.52)
  IN1 w0.114: v2(185.09,81.52) 185.09,80.7 187.1,78.69 187.1,75.1 188.88,73.32 188.88,47.42 191.76,44.55 191.76,34.92 191.29,34.46 191.29,32.97 189.59,31.27 188.75,31.27 183.61,26.13 183.61,25.42 182.38,24.19 180.92,24.19 178.44,21.71 178.44,18.53 176.74,16.84 176.74,14.97 170.99,9.22 v2(169.98,9.22)
  BOTTOM w0.102: v2(169.98,9.22) 169.98,10.37 167.67,12.68 166.91,12.68 166.2,13.39 163.4,13.39 160.93,15.86 160.93,16.47 159.47,17.93 158.05,17.93 157.75,17.63 155.81,17.63 154.74,18.7 153.29,18.7 153.02,18.97 v2(153.02,19.15)
LAN_WAKE#: length 117.4
  TOP w0.102: UE5.B27 154.54,15.67 v2(154.28,15.93) ; v2(169.98,90.41) 169.84,90.27 163.95,90.27 163.72,90.05 158.12,90.05 157.11,89.03 156.3,89.03 156.18,88.9 156.18,86.74 155.74,86.31 v1(155.49,86.31) 154.3,86.31 v2(153.8,86.81)
  IN1 w0.114: v2(153.8,86.81) 153.82,86.81 154.49,87.48 155.25,87.48 156.19,86.54 157.76,86.54 159.16,85.14 159.16,84.02 160.71,82.47 160.71,79.02 162.22,77.52 166.91,77.52 170.35,74.08 170.35,70.94 172.93,68.37 172.93,65.06 172.18,64.31 172.18,59.46 172.51,59.13 172.51,53.14 170.47,51.1 170.47,47.45 171.67,46.25 171.67,40.11 171.01,39.45 171.01,37.81 169.93,36.73 169.93,29.99 161.9,21.97 161.9,20.37 160.57,19.03 158.19,19.03 157.51,18.35 157.47,18.35 154.99,15.87 154.28,15.87 154.26,15.9 154.28,15.93 v2(154.28,15.93)
  BOTTOM w0.076: UC1.AN5 153.34,86.81 v2(153.8,86.81)
  BOTTOM w0.102: v2(169.98,90.41) 169.9,90.34 RC153.2 R2363.1
LAN_WAKE#_R: length 13.9
  BOTTOM w0.102: R2363.2 R2532.2 170.82,87.73 171.25,87.3 171.53,87.3 172.09,86.74 173.74,86.74 174.11,87.11 174.11,88.43 174.17,88.49 174.17,89.27 v1(174.48,89.58) 175.14,89.58 175.54,89.17 176.85,89.17 176.95,89.06 176.95,87.25 177.19,87.01 177.83,87.01 177.96,87.13 UL1.21
LCD_CBL_DET#: length 367.2
  IN1 w0.114: v2(111.59,9.4) 112.3,8.69 113.06,8.69 114.1,9.73 129.73,9.73 133.17,6.29 141.51,6.29 142.31,7.08 157.52,7.08 157.56,7.04 165.71,7.04 169.43,10.76 170.82,10.76 175.54,15.47 175.54,17.5 176.64,18.6 176.64,21.72 181.22,26.3 182.07,26.3 186.16,30.39 186.16,31.31 188.36,33.5 188.36,38.87 189.91,40.42 189.91,44.69 187.67,46.92 187.67,64.13 185.35,66.46 185.35,77.41 183.47,79.28 183.47,82.21 184.19,82.92 184.19,92.19 185.24,93.24 185.24,96.89 184.26,97.87 182.07,97.87 181.37,98.57 176.52,98.57 174.65,100.44 171.23,100.44 v2(169.96,99.16)
  IN3 w0.135: v2(4.93,91.95) 4.93,91.94 5.76,91.94 11.41,86.29 13.15,86.29 15.68,83.75 15.68,82.67 14.8,81.78 14.8,79.06 19.57,74.28 21.43,74.28 v2(21.59,74.12)
  BOTTOM w0.076: UC1.J3 155.19,99.62 155.63,99.62 155.81,99.8 155.81,100.1 156.01,100.31 156.6,100.31 156.8,100.51 161.9,100.51 162.03,100.38
  BOTTOM w0.102: JEDP.22 4.44,91.45 v2(4.93,91.95) ; 162.03,100.38 163.63,98.78 v1(164.33,98.78) 169.57,98.78 v2(169.96,99.16) 170.44,99.16 172.51,97.1 RC106.2 ; v2(21.59,74.12) 21.85,73.87 32.45,73.87 32.93,73.38 34.28,73.38 34.79,73.89 42.48,73.89 43.54,72.82 52.73,72.82 54.08,71.48 64.79,71.48 68.2,68.06 73.89,68.06 76.69,65.27 76.69,58.28 80.33,54.64 87.78,54.64 88.42,54 88.42,53.99 88.85,53.56 88.85,44.2 91.09,41.96 91.09,36.54 101.31,26.32 101.31,26.28 101.5,26.08 101.5,19.78 108.5,12.77 109.08,12.77 111.52,10.33 111.52,9.46 v2(111.59,9.4)
LCD_TST: length 240.6
  TOP w0.102: RPE10.3 158.93,9.71 v2(158.84,9.63) ; v2(151.64,21.36) 151.55,21.27 UE5.A38 ; v2(6.6,84.7) v1(6.6,85.3)
  IN3 w0.135: v2(6.6,84.7) 7.23,84.06 7.23,80.32 8.89,78.66 8.89,77.85 16.02,70.72 21.24,70.72 24.34,67.62 29.87,67.62 31.3,66.19 33.28,66.19 35.22,68.14 35.22,69.12 36.86,70.75 42.8,70.75 44.01,71.96 66.06,71.96 67.53,70.48 73.96,70.48 75.01,69.43 76.24,69.43 76.7,69.89 77.92,69.89 79.52,68.29 86.9,68.29 90.28,64.91 90.28,57.71 83.79,51.22 83.79,47.69 86.13,45.35 86.13,37.65 90.15,33.62 90.56,33.62 95.14,29.05 97.85,29.05 102.78,24.11 128.72,24.11 130.36,22.48 138.36,22.48 138.92,21.92 144.87,21.92 145.81,22.86 148.96,22.86 149.48,22.35 149.95,22.35 150.19,22.1 150.19,21.34 150.73,20.8 151.26,20.8 151.64,21.19 v2(151.64,21.36) 151.82,21.19 151.82,20.68 151.41,20.27 151.41,18.65 151.69,18.65 153.01,17.33 154.6,17.33 155.97,15.95 157.18,15.95 158.47,17.25 160.02,17.25 160.51,16.77 162.08,16.77 162.23,16.92 164.34,16.92 164.8,16.46 164.8,13.92 164.35,13.47 162.74,13.47 160.91,11.65 160.91,11.06 159.77,9.92 159.14,9.92 v2(158.84,9.63)
  BOTTOM w0.102: JEDP.8 3.93,84.45 4,84.38 4.63,84.38 4.94,84.06 6.15,84.06 6.6,84.51 v2(6.6,84.7)
LCD_VCC_TEST_EN: length 204.3
  TOP w0.102: v2(14.15,82.98) 14.17,82.97 DV7.2 15.2,81.75 v1(15.04,81.59) ; UE5.A39 v2(151.05,21.35)
  IN3 w0.135: v2(151.05,21.35) 150.92,21.35 150.55,21.72 150.55,22.15 150.09,22.61 149.58,22.61 149.07,23.13 145.71,23.13 144.77,22.19 139.02,22.19 138.17,23.04 130.41,23.04 129.07,24.38 102.89,24.38 97.96,29.31 95.38,29.31 90.81,33.89 90.26,33.89 86.39,37.75 86.39,45.46 84.07,47.79 84.07,51.13 90.54,57.61 90.54,65.04 87.02,68.56 79.63,68.56 78.03,70.16 77.69,70.16 75.12,72.73 66.17,72.73 65.66,72.22 43.89,72.22 42.69,71.02 36.75,71.02 34.95,69.23 34.95,68.25 33.16,66.46 31.41,66.46 29.98,67.9 24.44,67.9 21.26,71.07 16.04,71.07 11.6,75.51 11.6,80.56 14.01,82.97 14.14,82.97 v2(14.15,82.98)
LG_+1.35DGPU: length 9.3
  TOP w0.102: v4(48.06,57.58) v1(48.06,58.54)
  IN1 w0.762: v4(40.36,53.62) v4(41.13,53.62) 41.23,53.62 45.19,57.58 47.11,57.58
  vias: v4(48.7,57.58)
LGATE: length 13.8
  TOP w0.102: v1(61.65,110.35) 61.75,110.25 61.75,110.11 62.13,109.73 62.67,109.73 62.74,109.65 v2(63.56,109.65)
  IN2 w1.016: v2(65.59,121.47) 65.59,114.84 64.47,113.72 64.47,110.44
  vias: v2(64.19,109.6) v2(64.7,121.47)
LID_CL#: length 206.8
  TOP w0.102: v3(30.15,65.68) 30.15,65.32 29.36,64.54 29.08,64.54 v2(28.33,63.78) 28.33,62.74 25.58,60 24.07,60 21.55,57.48 19.21,57.48 18.98,57.71 15.89,57.71 15.53,57.35 JLED.4 ; RE26.1 160.66,12.35 161.07,12.75 v2(161.27,12.75)
  IN3 w0.135: v2(28.33,63.78) 28.88,63.23 35.59,63.23 38.7,60.12 44,60.12 50.82,66.94 63.52,66.94 63.93,67.35 72.66,67.35 75.88,64.12 75.88,57.3 79.6,53.58 79.6,46.7 80.84,45.46 80.84,25.64 83.44,23.04 83.44,21.59 83.77,21.26 87.05,21.26 88.14,22.35 90.75,22.35 93.01,20.1 93.92,20.1 94.44,19.58 94.44,17.67 95.53,16.58 100.07,16.58 100.95,17.45 116.06,17.45 117.12,16.39 125.48,16.39 127.26,14.61 133.61,14.61 133.99,14.23 137.52,14.23 138.26,13.49 139.45,13.49 140.09,12.85 141.77,12.85 142.94,11.69 144.45,11.69 146.13,10.01 150.63,10.01 150.9,9.74 152.94,9.74 153.46,10.26 154.45,10.26 155.46,11.27 156.21,11.27 156.45,11.03 158.1,11.03 158.68,11.61 159.31,11.61 160.46,12.75 v2(161.27,12.75)
LID_CL_SIO#: length 7.9
  TOP w0.102: UE5.A21 156.34,13.42 156.39,13.46 157.03,13.46 RE25.2 157.89,12.6 159.21,12.6 CE13.1 159.82,13.06 159.82,12.88 159.74,12.8 RE26.2 159.74,12.12 160.11,11.75 161.56,11.75 v1(161.73,11.91)
LINE1-L: length 3.6
  TOP w0.203: 188.45,15.93 188.02,16.35 UA1.22
  TOP w0.508: 188.45,15.93 188.8,15.93 v1(189.2,15.53) 190.11,14.62 CA67.1
LINE1-R: length 3.1
  TOP w0.203: v1(187.89,15.52) 187.79,15.62 187.79,16 187.62,16.17 187.62,16.77 UA1.21
  TOP w0.508: v1(187.89,15.52) 189.09,14.32 CA68.1
LINE1-VREFO-L: length 2.5
  TOP w0.203: UA1.31 189.67,20.03 190.5,20.03 190.63,19.9 v1(190.94,19.9) 191.15,19.9 191.62,20.37 RA165.1
LINE1-VREFO-R: length 5.7
  TOP w0.203: UA1.30 190.36,19.62
  TOP w0.254: 190.36,19.62 190.49,19.5 191.52,19.5 191.63,19.61 192.83,19.61 193.08,19.36 193.88,19.36 v1(193.93,19.41) 194.39,19.87 RA166.1
LINE-IN-L: length 18.6
  TOP w0.508: v2(193.45,20.14) 193.22,20.37 RA165.2 RA55.2 ; RA80.2 193.43,14.07 192.49,13.13 RA83.1 192.16,12.96 v2(191.55,12.35)
  IN3 w0.508: v2(191.55,12.35) 191.98,12.78 191.98,15.78 193.1,16.89 193.1,18.11 192.96,18.25 192.96,19.6 193.45,20.09 v2(193.45,20.14) 193.45,22.21 v2(192.76,22.9)
  BOTTOM w0.102: LA8.2 193.48,23.19 v1(193.81,23.52)
  BOTTOM w0.254: v2(192.76,22.9) 192.76,22.71 193.07,22.41 LA8.2
LINE-IN-R: length 18.9
  TOP w0.127: v1(193.5,23.03) 192.79,22.32 RA56.2
  TOP w0.508: v2(195.56,18.63) 195.56,19.29 195.46,19.4 195.41,19.4 195.41,20.3 RA166.2 195.3,20.58 194.7,21.19 194.39,21.19 193.43,22.15 RA56.2 ; RA82.2 RA84.1 v2(189.46,12.5)
  IN1 w0.508: v2(195.56,18.63) 195.1,18.18 192.61,18.18 v2(192.18,17.74)
  IN3 w0.508: v2(192.18,17.74) 192.18,17.24 190.94,15.99 190.94,13.97 v2(189.46,12.5)
  BOTTOM w0.254: v2(192.18,17.74) 192.66,18.22 LA9.2
LPC_LAD0: length 205.7
  TOP w0.102: v1(181.25,45.23) 181.25,45.68 180.69,46.24 180.26,46.24 v2(180.09,46.41) ; UE5.A30 156.2,17.92 156.8,18.52 v2(156.8,18.75)
  IN1 w0.114: v2(68.35,15.17) 69.2,14.32 72.99,14.32 73.64,14.96 76.74,14.96 77.47,15.7 81.3,15.7 82.58,14.42 89.69,14.42 91.29,16.02 98.1,16.02 99.66,14.45 103.84,14.45 104.9,15.52 112.88,15.52 114.09,14.32 128.9,14.32 129.24,14.66 133.69,14.66 134.23,14.12 136.12,14.12 136.61,14.62 139.03,14.62 139.65,14 142.51,14 142.53,13.98 144.64,13.98 145.22,13.41 147.32,13.41 147.96,14.05 148.29,14.05 149.05,14.81 149.05,15.39 149.68,16.02 150.56,16.02 151.41,16.87 151.41,17.39 152.27,18.24 155.66,18.24 156.16,18.75 v2(156.8,18.75)
  IN3 w0.135: v2(156.8,18.75) 157.48,19.43 157.48,20.37 158.32,21.21 159.57,21.21 163.2,24.84 169.65,24.84 171.81,27 172.55,27 178.31,32.77 178.31,45.21 179.51,46.41 v2(180.09,46.41)
  BOTTOM w0.076: 150.14,74.76 150.05,74.84 150.05,79.4 148.81,80.64 148.81,81.89 148.56,82.15 148.56,83.5 148.6,83.54 148.6,84.02 UC1.AU14
  BOTTOM w0.102: JLPDE.3 v2(68.35,15.17) ; v2(180.09,46.41) 179.91,46.59 170.63,46.59 170.18,47.03 170.18,49.44 170.74,50 170.74,52.55 171.84,53.65 171.84,58.01 169.18,60.67 166.04,60.67 164.1,62.61 159.62,62.61 150.14,72.09 150.14,74.76
LPC_LAD1: length 200.8
  TOP w0.102: v2(153.15,17.82) 153.52,18.19 154.16,18.19 154.18,18.17 UE5.B32
  IN1 w0.114: v2(68.85,12.28) 69.64,13.07 72.09,13.07 73.74,14.72 76.84,14.72 77.58,15.46 81.2,15.46 82.48,14.18 89.79,14.18 90.74,15.13 98.65,15.13 99.7,14.07 104.1,14.07 105.22,15.19 112.87,15.19 114.02,14.04 129.3,14.04 129.68,14.42 133.59,14.42 134.13,13.88 135.17,13.88 135.36,13.69 138.81,13.69 139.15,13.36 139.82,13.36 140.23,13.76 142.41,13.76 142.43,13.74 144.54,13.74 145.74,12.55 147.15,12.55 147.63,13.03 147.63,13.39 148.06,13.81 148.39,13.81 149.29,14.71 149.29,15.22 149.85,15.78 150.66,15.78 151.66,16.77 151.66,17.28 152.3,17.93 153.04,17.93 v2(153.15,17.82)
  IN3 w0.135: v2(180.12,45.24) 179.81,45.24 178.74,44.17 178.74,32.51 170.74,24.51 163.25,24.51 159.52,20.78 159.52,20.42 157.33,18.24 153.57,18.24 v2(153.15,17.82)
  BOTTOM w0.076: 151.2,74.76 150.55,75.41 150.55,79.6 149.31,80.84 149.31,82.72 UC1.AW12
  BOTTOM w0.102: JLPDE.4 v2(68.85,12.28) ; v2(180.12,45.24) 180.17,45.24 180.75,45.82 180.75,47.3 180.42,47.63 173.57,47.63 171.43,49.77 171.43,51.89 172.62,53.08 v1(172.62,53.86) 172.62,58.2 169.09,61.72 165.95,61.72 164.38,63.3 161.26,63.3 151.2,73.36 151.2,74.76
LPC_LAD2: length 197.2
  TOP w0.102: UE5.A31 156.06,18.42 156.39,18.75 156.39,19.05 157.05,19.71 157.05,19.87 v2(157.03,19.89)
  IN1 w0.114: v2(157.03,19.89) 157.01,19.87 156.49,19.87 155.1,18.48 152.17,18.48 151.17,17.49 151.17,16.97 150.46,16.26 149.57,16.26 148.81,15.49 148.81,14.91 148.19,14.29 147.86,14.29 147.22,13.65 145.58,13.65 145.01,14.23 142.87,14.23 142.85,14.24 139.75,14.24 139.13,14.86 136.51,14.86 136.01,14.37 134.33,14.37 133.79,14.9 128.87,14.9 128.59,14.62 114.27,14.62 113.12,15.76 104.8,15.76 103.9,14.86 100.88,14.86 99.48,16.26 91.19,16.26 89.59,14.66 82.68,14.66 81.4,15.94 77.37,15.94 76.64,15.2 73.54,15.2 72.89,14.56 69.94,14.56 v2(69.35,15.15)
  IN3 w0.135: v2(180.09,47.22) 179.89,47.22 177.91,45.24 177.91,32.97 172.24,27.31 171.53,27.31 169.45,25.22 163.2,25.22 159.47,21.49 158.12,21.49 157.03,20.4 v2(157.03,19.89)
  BOTTOM w0.076: 150.9,74.76 150.39,75.28 150.39,79.53 149.14,80.77 149.14,82.23 UC1.AY12
  BOTTOM w0.102: JLPDE.5 v2(69.35,15.15) ; 150.9,74.76 150.9,73.34 161.17,63.07 164.29,63.07 166.03,61.33 v1(168.57,61.33) 169.16,61.33 172.29,58.2 172.29,53.07 171.2,51.98 171.2,49.68 173.84,47.04 179.91,47.04 v2(180.09,47.22)
LPC_LAD3: length 196.9
  TOP w0.102: UE5.B33 154.67,18.67 v2(154.23,19.1)
  IN1 w0.114: v2(154.23,19.1) 153.85,18.72 152.07,18.72 150.93,17.59 150.93,17.07 150.36,16.5 149.41,16.5 148.56,15.66 148.56,15.01 148.09,14.53 147.76,14.53 147.12,13.9 145.83,13.9 145.24,14.48 143.36,14.48 141.81,16.03 136.49,16.03 136.13,16.39 115.99,16.39 114.85,17.52 101.34,17.52 100.63,18.23 94.75,18.23 94.29,17.77 81.13,17.77 80.71,17.35 74.88,17.35 v2(73.84,16.31)
  IN3 w0.135: v2(180.13,48.07) 180.12,48.07 180.12,48.08 180.08,48.04 180.08,48.03 177.59,45.54 177.59,33.24 171.96,27.61 171.3,27.61 169.3,25.61 163.2,25.61 159.36,21.77 158.02,21.77 156.73,20.48 155.51,20.48 154.27,19.24 154.27,19.14 v2(154.23,19.1)
  BOTTOM w0.076: UC1.AW11 149.48,82.72 149.48,80.91 150.72,79.67 150.72,75.53 151.43,74.81 151.43,74.76
  BOTTOM w0.102: JLPDE.6 69.85,11.75 70.73,12.63 71.87,12.63 72.23,12.98 73.56,12.98 73.84,13.26 v2(73.84,16.31) ; v2(180.13,48.07) 180.12,48.07 180.12,48.08 180.08,48.04 180.08,48.06 179.95,47.93 173.59,47.93 171.66,49.87 171.66,51.79 172.98,53.11 v1(172.98,57.04) 172.98,58.16 169.19,61.95 166.05,61.95 164.47,63.53 161.36,63.53 151.43,73.45 151.43,74.76
LPC_LFRAME#: length 203.2
  TOP w0.102: UE5.B31 154.19,17.67 v2(154.05,17.81)
  IN1 w0.114: v2(154.05,17.81) 154.05,17.8 153.64,17.39 152.95,17.39 152.76,17.58 152.29,17.58 151.9,17.18 151.9,16.67 150.76,15.54 150.05,15.54 149.53,15.02 149.53,14.61 148.91,13.99 148.91,13.36 148.28,12.73 147.68,12.73 147.25,12.31 145.64,12.31 145.27,12.68 145.27,12.68 142.31,12.68 142.08,12.91 139.26,12.91 138.71,13.45 135.7,13.45 135.25,13.01 134.66,13.01 133.49,14.18 130.13,14.18 129.67,13.72 113.68,13.72 112.56,14.84 105.23,14.84 104.08,13.69 99.53,13.69 98.33,14.89 90.84,14.89 89.89,13.93 82.38,13.93 81.1,15.22 77.68,15.22 76.94,14.48 73.85,14.48 72.19,12.82 70.16,12.82 v2(69.65,12.31)
  IN3 w0.135: v2(154.05,17.81) 154.08,17.84 157.31,17.84 159.8,20.32 159.8,20.67 163.31,24.18 171.09,24.18 179.05,32.14 179.05,42.95 180.57,44.48 180.57,45.54 180.29,45.82 v2(180.12,45.82)
  BOTTOM w0.076: UC1.AV12 148.73,83.4 148.73,82.22 148.98,81.96 148.98,80.7 150.22,79.46 150.22,75.06 150.52,74.76
  BOTTOM w0.102: JLPDE.7 70.35,13.01 v2(69.65,12.31) ; 150.52,74.76 150.52,73.36 161.04,62.84 164.19,62.84 166.13,60.9 169.27,60.9 172.06,58.11 172.06,53.37 v1(171.56,52.86) 170.97,52.28 170.97,49.91 170.41,49.35 170.41,47.13 170.72,46.81 180.31,46.81 180.52,46.6 180.52,46.13 180.22,45.82 v2(180.12,45.82)
LX_1.05V:
  vias: v1(100.46,119.31) v4(99.37,118.4) v4(100.08,118.4)
LX_3V: length 6.7
  IN3 w0.762: 52.25,32.57 49.76,35.05 46.54,35.05
  vias: v3(42.63,36.24) v4(41.81,35.49) v4(41.84,34.85) v4(42.54,35.49) v4(42.54,34.85) v4(43.24,35.55) v4(43.24,34.85) v4(45.37,36.2) v4(45.79,35.72) v4(45.79,35.05) v4(52.76,31.3) v4(52.89,31.93)
LX_5V: length 6.2
  IN1 w0.762: 51.77,24.72 51.77,24.54 47.6,20.37 47.43,20.37
  vias: v1(40.47,20.23) v4(41.08,21.39) v4(41.2,20.12) v4(41.58,21.77) v4(41.71,20.75) v4(42.22,19.99) v4(42.73,20.63) v4(43.11,19.99) v4(43.49,20.63) v4(43.87,19.99) v4(44.51,21.39) v4(44.51,20.63) v4(44.51,19.99) v4(46.53,21.83) v4(46.54,21.19) v4(46.54,20.56) v4(46.55,19.92) v4(51.81,26.15) v4(51.81,25.52)
M_CLK_DDR0: length 48.7
  IN1 w0.076: 133.62,74.67 133.68,74.74 133.68,79.48 133.92,79.72 134.17,79.72 134.27,79.82 v2(134.27,79.91)
  IN1 w0.114: 133.62,74.67 133.15,74.2 133.15,67.69 131.4,65.94 131.4,61.1 131.28,60.99 131.02,60.99 130.79,60.75 130.79,60.24 131.02,60.01 131.28,60.01 131.4,59.89 131.4,59.55 131.28,59.44 131.02,59.44 130.79,59.2 130.79,58.69 131.02,58.46 131.28,58.46 131.4,58.35 131.4,58 131.28,57.89 131.02,57.89 130.79,57.66 130.79,57.14 131.02,56.91 131.28,56.91 131.4,56.8 131.4,56.4 131.17,56.17 131.17,55.58 131.02,55.43 130.81,55.43 128.93,53.55 128.93,52.5 129.24,52.2 129.24,51.97 128.93,51.67 128.93,50.57 129.42,50.09 129.42,49.91 129.09,49.58 129.09,47.16 129.31,46.94 129.67,46.94 129.79,46.82 v2(129.79,46.67)
  BOTTOM w0.076: UC1.AV37 133.53,83.66 133.42,83.55 133.42,79.8 133.6,79.62 133.98,79.62 v2(134.27,79.91)
  BOTTOM w0.102: v2(129.79,46.67) 129.79,46.77 129.64,46.92 128.81,46.92 128.55,47.18 JDIMM1.101
M_CLK_DDR1: length 47.5
  IN1 w0.076: v2(134.18,82.03) 134.43,82.28 134.77,82.28 134.85,82.2 134.85,81.64 134.65,81.43 134.65,74.48 134.29,74.11 134.28,74.11 134.25,74.08 134.22,74.08 134.21,74.07
  IN1 w0.114: v2(129.79,45.15) 129.79,44.97 129.9,44.86 130.36,44.86 130.56,45.06 130.56,45.31 130.2,45.66 130.2,46.01 130.48,46.29 130.48,48.39 130.37,48.51 130.16,48.51 129.93,48.74 129.93,49.25 130.16,49.49 130.37,49.49 130.48,49.6 130.48,50.21 129.82,50.87 129.82,51.39 130.38,51.95 130.38,52.22 129.82,52.78 129.82,53.22 130.23,53.62 130.53,53.62 130.76,53.85 130.76,54.21 131.14,54.59 131.37,54.59 132.01,55.22 132.01,55.83 132.24,56.06 132.24,65.61 134.02,67.39 134.02,73.88 134.21,74.07
  BOTTOM w0.076: UC1.AY36 134.22,82.03 v2(134.18,82.03)
  BOTTOM w0.102: v2(129.79,45.15) 129.79,45 129.62,44.84 129.27,44.84 129,44.56 129,43 128.85,42.85 JDIMM1.102
M_CLK_DDR2: length 67.8
  IN3 w0.076: 133.79,73.94 133.79,73.95 133.77,73.97 133.77,78.08 133.24,78.61 133.24,84.4 132.62,85.02 132.62,86.54 132.71,86.63 132.89,86.63 v2(133.08,86.44)
  IN3 w0.114: v2(141.5,33.67) 141.67,33.84 142.16,33.84 142.42,34.11 142.42,35.15 141.64,35.94 141.64,39.53 141.53,39.64 141.53,40.07 141.48,40.12 141.48,41.29 140.04,42.73 140.04,48.68 140.29,48.94 140.29,50.19 139.5,50.98 139.5,51.12 140.07,51.68 140.07,52.01 139.7,52.38 139.37,52.38 138.81,51.82 138.66,51.82 138.46,52.02 138.46,52.34 138.72,52.6 138.72,52.93 138.43,53.22 138.43,53.4 138.8,53.76 138.8,54.09 138.44,54.46 138.1,54.46 137.77,54.12 137.6,54.12 137.36,54.36 137.36,54.53 137.7,54.86 137.7,55.19 137.34,55.56 137,55.56 136.67,55.22 136.5,55.22 133.79,57.94 133.79,73.94
  BOTTOM w0.076: UC1.AN38 133.28,86.77 133.08,86.57 v2(133.08,86.44)
  BOTTOM w0.102: JDIMM2.101 140.55,35.6 140.48,35.53 140.48,34.23 140.71,34 141.36,34 141.5,33.86 v2(141.5,33.67)
M_CLK_DDR3: length 68.9
  IN3 w0.076: 132.9,73.97 132.9,73.98 132.88,73.99 132.88,79.33 132.16,80.05 132.16,84.5 132.28,84.62 132.28,87.85 132.54,88.11 133.01,88.11 133.13,88 133.13,87.83 v2(133.06,87.77)
  IN3 w0.114: 132.9,73.97 132.9,57.64 137.62,52.92 137.62,51.69 139.4,49.91 139.4,49.22 139.2,49.02 139.2,42.39 140.65,40.94 140.65,40.13 140.39,39.87 140.39,39.26 140.81,38.84 140.81,38.29 140.67,38.15 140.67,37.76 140.81,37.62 140.81,37.05 140.67,36.91 140.67,36.54 140.81,36.4 140.81,35.78 140.67,35.64 140.67,35.33 140.89,35.12 140.89,34.56 140.67,34.35 140.67,33.61 141.08,33.21 141.08,32.71 140.62,32.25 140.62,31.96 140.75,31.83 141.3,31.83 141.5,32.02 v2(141.5,32.15)
  BOTTOM w0.076: UC1.AL38 133.46,88.11 133.2,88.11 133.06,87.98 v2(133.06,87.77)
  BOTTOM w0.102: v2(141.5,32.15) 141.5,31.83 141.42,31.75 140.18,31.75 139.95,31.51 139.95,31.18 140.85,30.28 JDIMM2.102
M_CLK_DDR#0: length 48.8
  IN1 w0.076: v2(134.27,79.35) 134.27,79.48 134.19,79.56 133.99,79.56 133.85,79.41 133.85,74.64 133.77,74.56 133.77,74.53 133.76,74.53
  IN1 w0.114: 133.76,74.53 133.35,74.12 133.35,67.61 131.6,65.86 131.6,61.02 131.37,60.78 131.11,60.78 130.99,60.67 130.99,60.33 131.11,60.21 131.37,60.21 131.6,59.98 131.6,59.47 131.37,59.23 131.11,59.23 130.99,59.12 130.99,58.78 131.11,58.66 131.37,58.66 131.6,58.43 131.6,57.92 131.37,57.69 131.11,57.69 130.99,57.57 130.99,57.23 131.11,57.11 131.37,57.11 131.6,56.88 131.6,56.31 131.37,56.09 131.37,55.49 131.1,55.22 130.9,55.22 129.14,53.46 129.14,52.59 129.44,52.28 129.44,51.89 129.14,51.58 129.14,50.66 129.62,50.18 129.62,49.83 129.29,49.5 129.29,47.25 129.39,47.14 129.65,47.14 129.79,47.29 v2(129.79,47.43)
  BOTTOM w0.076: v2(134.27,79.35) 134.16,79.46 133.53,79.46 133.26,79.73 133.26,83.66 133.67,84.07 UC1.AU37
  BOTTOM w0.102: v2(129.79,47.43) 129.79,47.2 129.72,47.13 128.9,47.13 128.76,47.27 128.76,48.68 129.15,49.06 JDIMM1.103
M_CLK_DDR#1: length 47.7
  IN1 w0.076: 134.36,73.93 134.36,73.93 134.36,73.95 134.81,74.41 134.81,81.37 135.02,81.57 135.02,82.27 134.84,82.44 134.27,82.44 134.18,82.52 v2(134.18,82.68)
  IN1 w0.114: v2(129.79,44.39) 129.79,44.47 129.98,44.66 130.44,44.66 130.76,44.98 130.76,45.39 130.41,45.75 130.41,45.93 130.69,46.2 130.69,48.48 130.45,48.71 130.24,48.71 130.13,48.82 130.13,49.17 130.24,49.28 130.45,49.28 130.69,49.52 130.69,50.29 130.03,50.95 130.03,51.3 130.59,51.86 130.59,52.31 130.03,52.87 130.03,53.13 130.31,53.42 130.62,53.42 130.97,53.77 130.97,54.12 131.23,54.38 131.46,54.38 132.21,55.14 132.21,55.75 132.44,55.98 132.44,65.53 134.22,67.31 134.22,73.79 134.36,73.93
  BOTTOM w0.076: UC1.AW36 134.22,82.68 v2(134.18,82.68)
  BOTTOM w0.102: JDIMM1.104 129.45,42.77 129.21,43 129.21,44.47 129.32,44.58 129.6,44.58 v2(129.79,44.39)
M_CLK_DDR#2: length 68
  IN3 w0.076: 133.58,74 133.61,74.02 133.61,78.01 133.08,78.54 133.08,84.33 132.45,84.95 132.45,86.61 132.64,86.79 132.97,86.79 133.13,86.95 133.13,87.15 v2(133.08,87.2)
  IN3 w0.114: v2(141.5,34.44) 141.89,34.05 142.08,34.05 142.22,34.19 142.22,35.07 141.43,35.86 141.43,39.45 141.33,39.55 141.33,39.98 141.28,40.03 141.28,41.2 139.83,42.65 139.83,48.77 140.09,49.02 140.09,50.1 139.3,50.89 139.3,51.21 139.86,51.77 139.86,51.93 139.62,52.17 139.46,52.17 138.9,51.61 138.58,51.61 138.25,51.94 138.25,52.43 138.51,52.68 138.51,52.85 138.23,53.13 138.23,53.48 138.59,53.85 138.59,54.01 138.35,54.25 138.19,54.25 137.85,53.92 137.52,53.92 137.16,54.28 137.16,54.61 137.49,54.95 137.49,55.11 137.25,55.35 137.09,55.35 136.75,55.02 136.42,55.02 133.58,57.85 133.58,74
  BOTTOM w0.076: v2(133.08,87.2) 133.23,87.05 133.39,87.05 133.51,87.17 UC1.AM38
  BOTTOM w0.102: v2(141.5,34.44) 141.28,34.22 140.8,34.22 140.69,34.32 140.69,35.44 141.15,35.9 JDIMM2.103
M_CLK_DDR#3: length 69
  IN3 w0.076: 132.69,74.02 132.72,74.05 132.72,79.26 132,79.98 132,84.57 132.11,84.68 132.11,87.92 132.47,88.28 132.98,88.28 133.05,88.35 v2(133.05,88.52)
  IN3 w0.114: v2(141.51,31.33) 141.51,31.52 141.41,31.62 140.66,31.62 140.41,31.87 140.41,32.33 140.87,32.79 140.87,33.12 140.47,33.53 140.47,34.43 140.68,34.64 140.68,35.03 140.47,35.25 140.47,35.72 140.6,35.86 140.6,36.31 140.47,36.45 140.47,36.99 140.6,37.13 140.6,37.53 140.47,37.67 140.47,38.24 140.6,38.38 140.6,38.75 140.18,39.17 140.18,39.95 140.44,40.21 140.44,40.86 138.99,42.31 138.99,49.1 139.19,49.3 139.19,49.83 137.42,51.6 137.42,52.83 132.69,57.56 132.69,74.02
  BOTTOM w0.076: v2(133.05,88.52) 133.18,88.39 133.33,88.39 133.53,88.6 UC1.AK38
  BOTTOM w0.102: JDIMM2.104 141.45,29.8 141.07,30.19 141.07,30.37 140.16,31.27 140.16,31.42 140.27,31.53 141.38,31.53 141.51,31.41 v2(141.51,31.33)
M_ID2#: length 7.3
  TOP w0.102: CV57.1 205.29,106.68 v1(205.29,106.99) 205.29,109.46 207.45,111.63 JCRT.4
M_ODT: length 10
  TOP w0.102: CD64.1 v1(147.79,59.67)
  TOP w0.254: R2348.1 R2349.1 R2350.1 R2352.1 ; R2352.1 144.5,59.93 146.48,59.93 CD64.1 ; R2352.1 141.96,58.79 QD2.3
M_ODT0: length 37.4
  TOP w0.17: v2(147.22,39.73) 146.74,40.21 146.74,40.79 146.96,41.01 146.96,55 145.83,56.12 v1(145.47,56.12) R2348.2
  IN1 w0.183: v2(132.72,40.47) 132.72,39.32 134.42,37.62 142.37,37.62 144.43,39.68 147.17,39.68 v2(147.22,39.73)
  BOTTOM w0.17: JDIMM1.116 133.05,41.84 133.05,40.8 v2(132.72,40.47)
M_ODT1: length 36.8
  TOP w0.17: R2349.2 145.54,57.01 147.38,55.18 147.38,40.55 v2(147.25,40.41)
  IN1 w0.183: v2(133.85,39.14) 134.78,39.14 135.82,38.1 142.02,38.1 144.86,40.95 146.82,40.95 147.25,40.52 v2(147.25,40.41)
  BOTTOM w0.17: v2(133.85,39.14) 134.25,39.54 JDIMM1.120
M_ODT2: length 37.1
  TOP w0.17: v2(145.05,27.49) 145.6,27.49 146,27.89 146.07,27.89 147.32,29.14 147.32,35.21 149.33,37.22 v1(149.33,40.95) 149.33,54.65 146.08,57.9 R2350.2
  BOTTOM w0.17: v2(145.05,27.49) 145.1,27.49 145.05,27.53 JDIMM2.116
M_ODT3: length 38.2
  TOP w0.17: v2(146.18,27.43) 146.27,27.43 147.75,28.91 147.75,35.04 v1(150.55,37.84) 150.55,54.03 145.79,58.79 R2352.2
  BOTTOM w0.17: v2(146.18,27.43) 146.25,27.5 JDIMM2.120
MCT0: length 3.3
  TOP w0.102: v1(199.15,83.56) 198.62,83.02 v2(198.62,82.92)
  TOP w0.508: RL19.1 198.58,82.88 v2(198.62,82.92)
  BOTTOM w0.508: v2(198.62,82.92) TL2.22
MCT1: length 4.4
  TOP w0.102: RL20.1 v1(197.63,85.52)
  TOP w0.508: v2(198.75,84.57) 198.33,84.15 RL20.1
  BOTTOM w0.508: TL2.21 198.37,84.19 v2(198.75,84.57)
MCT2: length 3.8
  TOP w0.102: v1(197.4,89.07) 197.83,89.5 RL39.1
  TOP w0.508: RL39.1 198.49,90.41 v2(198.62,90.54)
  BOTTOM w0.508: v2(198.62,90.54) TL2.16
MCT3: length 3.2
  TOP w0.102: v2(198.62,91.81) 199.25,91.18 v1(199.34,91.18)
  TOP w0.508: RL40.1 198.49,91.68 v2(198.62,91.81)
  BOTTOM w0.508: v2(198.62,91.81) TL2.15
MDI0+: length 9.6
  BOTTOM w0.089: TL2.12 186.67,94.35 186.15,93.83 v1(185.7,93.83) 184.75,92.88 184.75,89.63 183.4,88.28 183.14,88.28 183.08,88.33 UL1.1
MDI0-: length 9.5
  BOTTOM w0.089: TL2.11 186.67,93.08 186.24,93.51 185.83,93.51 185.07,92.75 v4(185.07,90.67) 185.07,89.5 183.53,87.96 183.14,87.96 183.11,87.93 UL1.2
MDI1+: length 6.1
  BOTTOM w0.089: TL2.8 186.81,89.27 186.33,88.79 v1(185.51,88.79) 183.78,87.07 183.13,87.07 183.07,87.13 UL1.4
MDI1-: length 6.1
  BOTTOM w0.089: TL2.7 186.81,88 186.33,88.48 185.64,88.48 v4(184.64,87.48) 183.92,86.75 183.16,86.75 183.14,86.73 UL1.5
MDI2+: length 5.4
  BOTTOM w0.089: UL1.6 183.09,86.33 183.17,86.25 v4(185.63,86.25) 186.19,86.25 186.67,86.73 TL2.6
MDI2-: length 5.3
  BOTTOM w0.089: UL1.7 183.08,85.93 183.08,85.94 v4(184,85.94) 186.19,85.94 186.67,85.46 TL2.5
MDI3+: length 8.7
  BOTTOM w0.089: TL2.2 186.48,81.65 186.19,81.36 186.19,80.95 186.05,80.81 185.11,80.81 v4(182.75,83.18) 182.01,83.92 182.01,84.39 182.03,84.42 UL1.9
MDI3-: length 8.7
  BOTTOM w0.089: TL2.1 186.67,80.38 186.55,80.49 v1(184.98,80.49) 181.69,83.78 181.69,84.39 181.63,84.45 UL1.10
MDO0+: length 6.9
  BOTTOM w0.089: TL2.13 198.44,94.35 198.61,94.18 198.61,93.85 198.68,93.78 199.19,93.78 200.02,92.95 200.02,91.56 200.28,91.29 201.05,91.29 201.13,91.36 201.13,92.05 JLAN.1
MDO0-: length 6.9
  BOTTOM w0.089: TL2.14 198.3,93.08 198.68,93.46 199.06,93.46 199.7,92.82 199.7,91.43 200.15,90.97 201.22,90.97 201.3,91.05 JLAN.2
MDO1+: length 5.9
  IN3 w0.102: JLAN.3 201.1,89.13 200.12,88.16 199.9,88.16 199.36,88.7 199.03,88.7 v2(198.82,88.9)
  BOTTOM w0.089: TL2.17 198.18,89.27 198.3,89.14 198.3,88.89 198.43,88.76 198.68,88.76 v2(198.82,88.9)
MDO1-: length 6
  IN3 w0.102: JLAN.6 200.92,86.97 199.99,87.9 199.8,87.9 199.25,88.45 198.98,88.45 v2(198.82,88.29)
  BOTTOM w0.089: TL2.18 198.24,88 198.33,88.1 198.33,88.35 198.43,88.45 198.67,88.45 v2(198.82,88.29)
MDO2+: length 7.1
  BOTTOM w0.089: JLAN.4 201.36,89.01 201.16,89.21 200.39,89.21 199.7,88.51 199.7,87.05 199.03,86.39 198.76,86.39 198.42,86.73 TL2.19
MDO2-: length 7.2
  BOTTOM w0.089: JLAN.5 201.1,88.82 201.03,88.89 200.52,88.89 200.02,88.38 200.02,86.92 199.17,86.07 198.76,86.07 198.62,85.93 198.62,85.64 198.44,85.46 TL2.20
MDO3+: length 7.7
  BOTTOM w0.089: TL2.23 198.18,81.65 198.65,81.17 198.84,81.17 199.7,82.03 199.7,83.61 201.32,85.24 201.32,85.73 JLAN.7
MDO3-: length 7.7
  BOTTOM w0.089: JLAN.8 201.47,84.93 200.02,83.48 200.02,81.9 198.97,80.86 198.68,80.86 198.21,80.38 TL2.24
ME_EN: length 29.3
  TOP w0.102: v2(168.58,63.05) 168.84,63.3 168.84,67.92 172.63,71.7 172.63,73.69 v1(175.12,76.18) 178.93,80 v2(178.93,81.27)
  BOTTOM w0.102: v2(178.93,81.27) 179.34,81.68 179.34,82.02 178.89,82.48 178.74,82.48 178.1,83.11 176.19,83.11 SW3.2 ; RC8.1 v2(168.58,63.05)
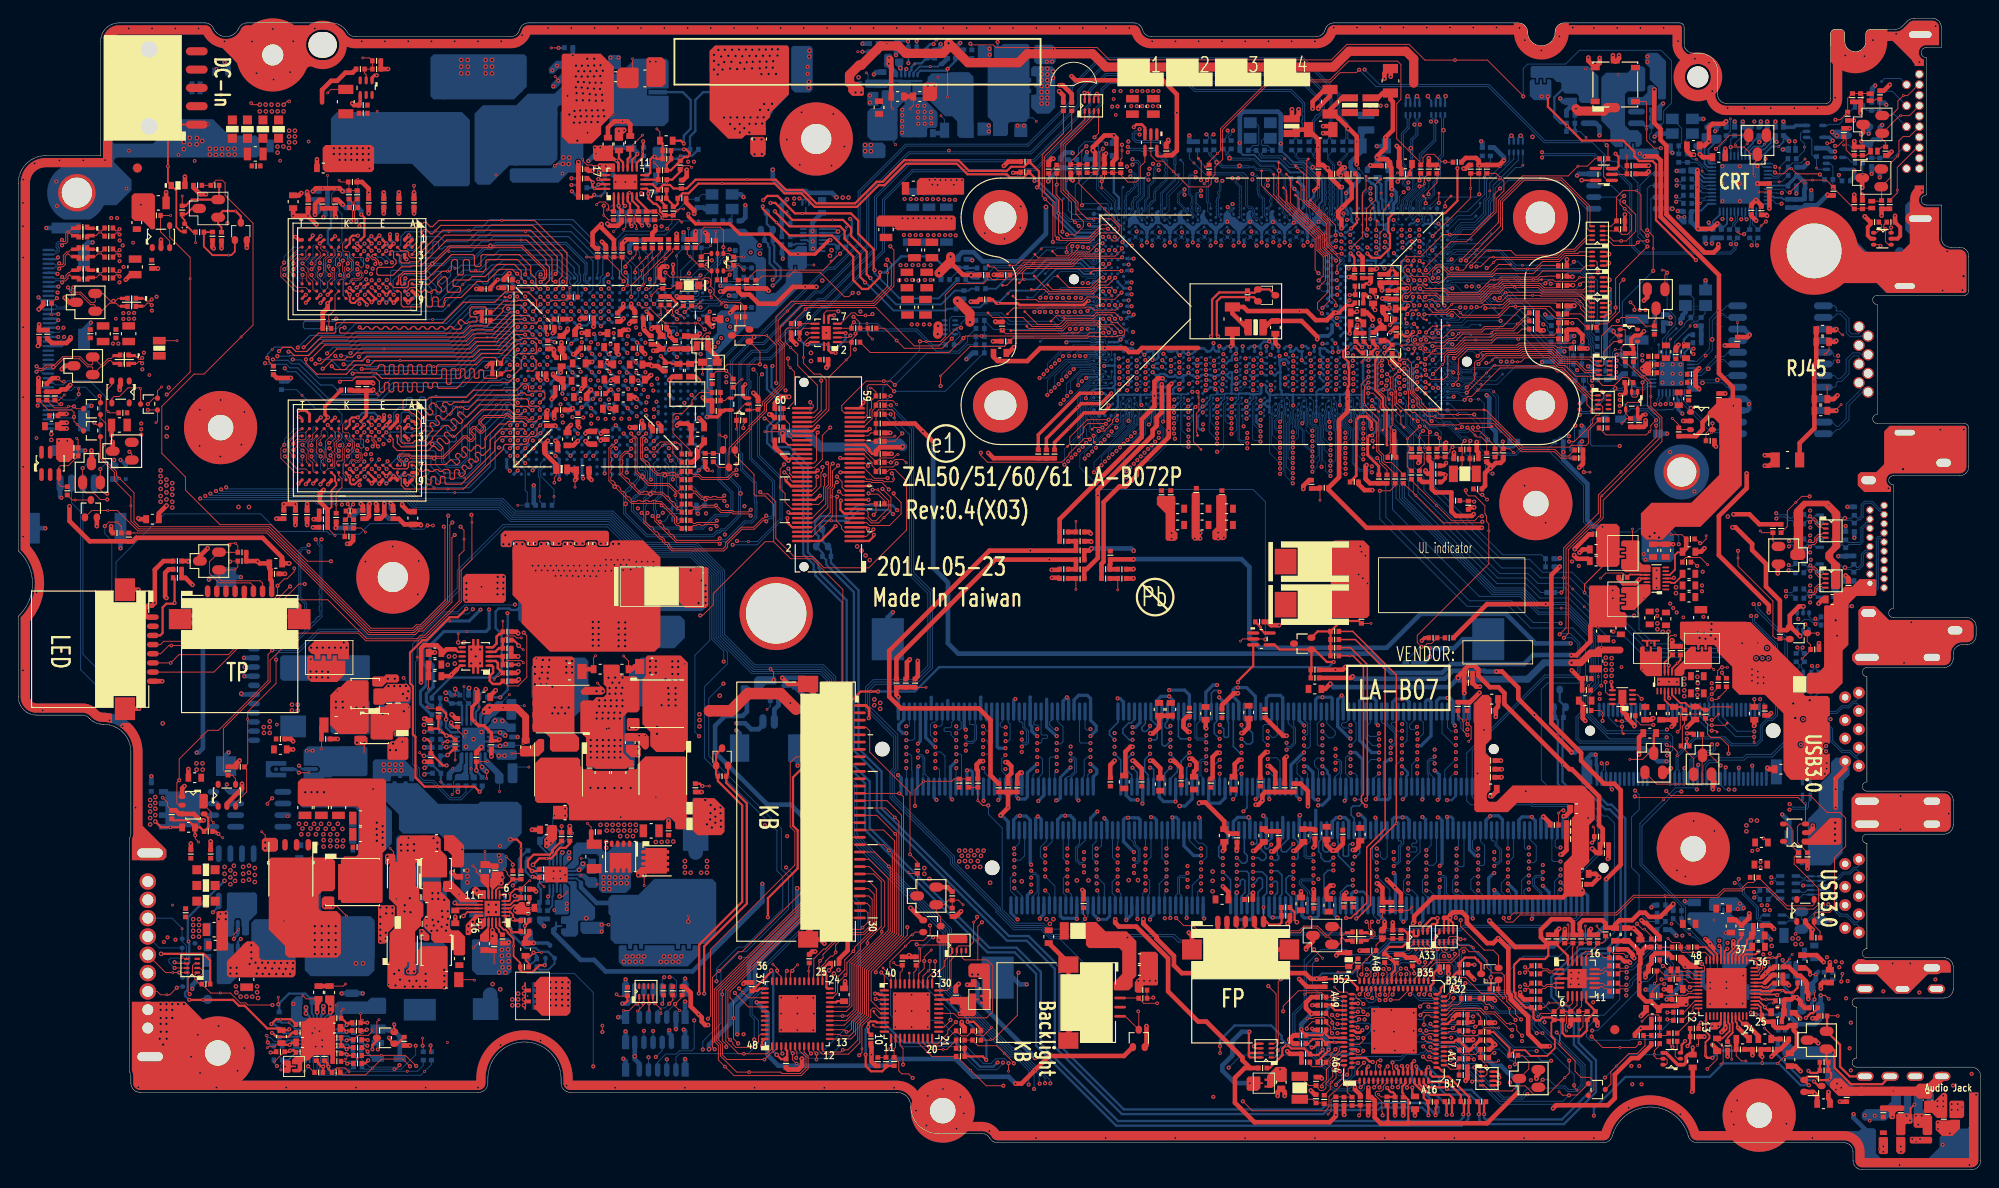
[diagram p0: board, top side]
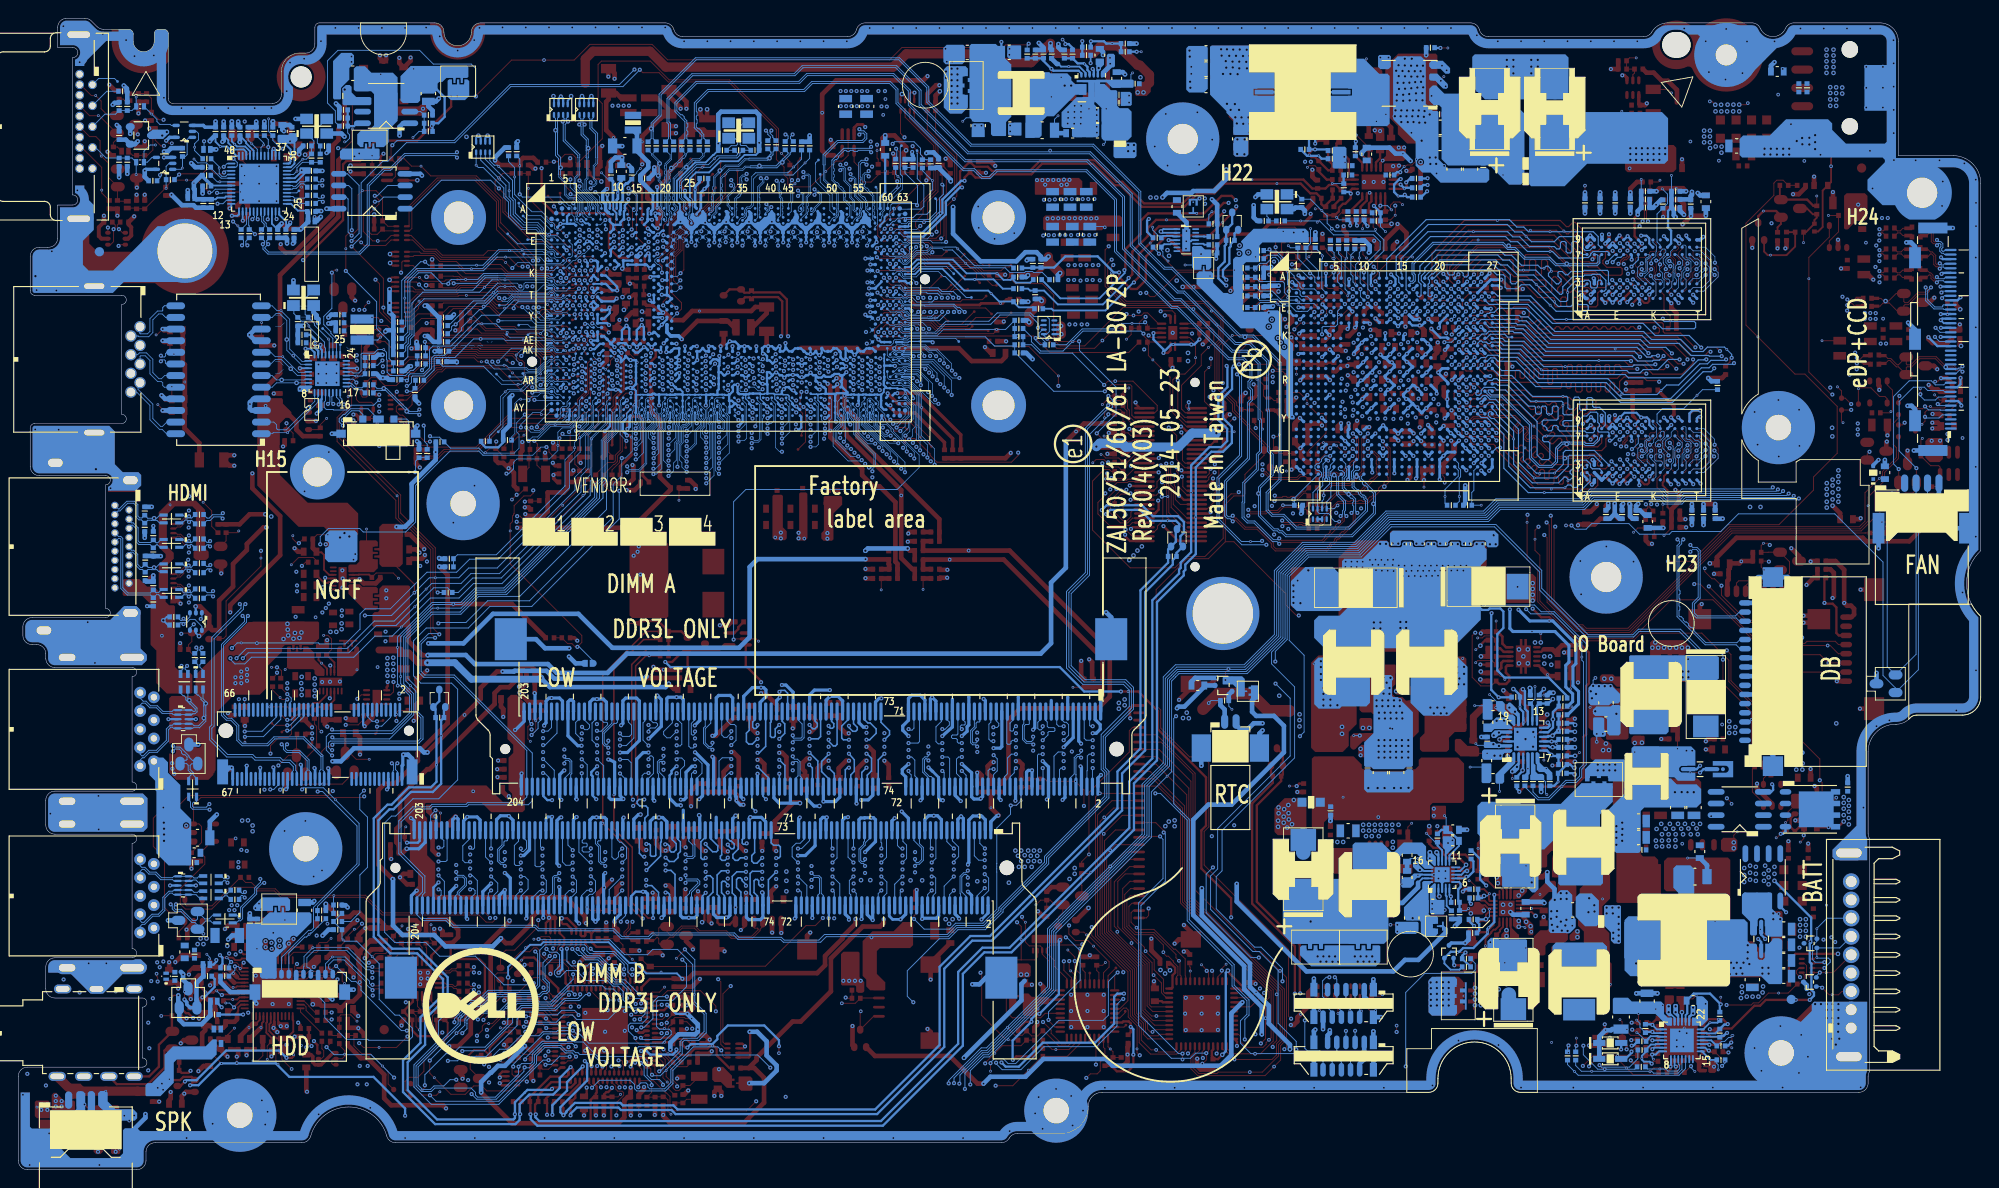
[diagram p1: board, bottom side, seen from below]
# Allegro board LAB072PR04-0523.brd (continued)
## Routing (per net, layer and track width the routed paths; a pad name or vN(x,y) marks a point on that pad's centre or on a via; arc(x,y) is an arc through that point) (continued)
ME_FWP_EC: length 103.5
  TOP w0.102: v2(165.89,14.91) v3(166.53,14.91) ; UE5.B46 148.8,19.15 v2(148.75,19.1)
  IN1 w0.114: v2(174.97,79.05) 175.33,78.69 175.33,73.73 177.77,71.29 177.77,68.57 179.42,66.91 179.42,61.3 181.09,59.63 181.09,54.04 180.78,53.72 180.78,53.06 181.58,52.26 181.58,47.39 180.97,46.78 180.97,43.68 180.46,43.17 180.46,39.91 177.74,37.19 177.74,31.1 173.44,26.8 173.44,25.39 170.95,22.9 170.95,19.15 166.71,14.91 v2(165.89,14.91)
  BOTTOM w0.102: v2(174.97,79.05) 171.95,79.05 171.76,79.24 171.76,81.78 171.96,81.98 SW3.3 ; v2(165.89,14.91) 165.87,14.91 165.38,15.39 165.38,15.97 165.38,16.35 164.63,17.1 161.74,17.1 160.44,18.39 157.86,18.39 157.56,18.09 156.16,18.09 154.15,20.09 150.58,20.09 150.22,19.74 149.38,19.74 v2(148.75,19.1)
ME_RESET#: length 3.6
  TOP w0.102: UC5.2 175.68,108.7 RC80.1 RC95.2 v1(175.75,110.75)
ME_SUS_PWR_ACK: length 101.7
  TOP w0.102: v2(162.18,79.53) 162.23,79.48 RC27.2 ; v1(163.38,78.31) 162.95,78.74 RC27.2 ; RC27.2 161.35,77.85 RC42.1 ; v2(150.13,9.01) 150.05,9.09 UE5.A8
  IN1 w0.114: v2(162.18,79.53) 163.61,79.53 164.42,78.72 167.41,78.72 168.44,77.69 170.81,77.69 171.95,76.55 171.95,72.27 173.74,70.47 173.74,69.61 174.38,68.97 174.38,64.46 173.62,63.71 173.62,60.81 175.26,59.17 175.26,52.72 175.02,52.48 175.02,49.36 174.77,49.11 174.77,48.03 175.45,47.35 175.45,42.99 175.4,42.94 175.4,39.99 174.11,38.7 174.11,37.2 172.71,35.8 172.71,34.8 171.85,33.94 171.85,31.6 172.08,31.37 172.08,29.98 169.64,27.54 169.64,26.03 169.22,25.62 167.72,25.62 165.65,23.55 165.65,19.97 163.93,18.25 163.52,18.25 162.04,16.77 162.04,15.03 159.59,12.58 158.97,12.58 157.18,10.78 156.52,10.78 155.68,11.62 153.8,11.62 153.48,11.31 153.48,10.98 152.8,10.29 150.7,10.29 150.13,9.72 v2(150.13,9.01)
ME_SUS_PWR_ACK_R: length 10.6
  TOP w0.102: RC42.2 161.35,79 v1(160.61,79.73) 159.68,80.66 159.05,80.66 158.91,80.8 v2(158.91,81.05)
  BOTTOM w0.076: v2(158.91,81.05) 158.4,80.55 157.41,80.55 156.39,81.56 155.15,81.56 154.54,82.17 154.54,82.55 154.45,82.64 154.45,83.13 154.16,83.41 UC1.AV4
MEC_XTAL1: length 8.6
  TOP w0.102: UE5.A61 144.62,12.92 143.73,12.03 143.73,11.31 143.62,11.19 v1(143.62,10.85) 143.62,10.17 142.87,9.43 142.87,8.93 142.57,8.64 142.24,8.64 141.79,9.1 CE62.1 141,9.2 YE1.1
MEC_XTAL2: length 2.9
  TOP w0.102: RE62.2 142.6,7.29 CE53.1 141.39,7.69 YE1.2
MEC_XTAL2_R: length 5.3
  TOP w0.102: UE5.A62 144.65,12.42 143.97,11.74 143.97,10.04 v1(143.5,9.58) 143.34,9.41 143.34,8.79 RE62.1
MEM_SMBCLK: length 28.6
  TOP w0.102: QC1.6 176.47,92.19 174.11,92.19 172.97,91.05 172.97,88.45 172.83,88.31 RP40.1 172.28,88.31 171.82,88.76 168.75,88.76 167.7,89.82 164.14,89.82 163.91,89.59 158.39,89.59 157.33,88.53 v1(157.33,86.92) 157.33,86.29 v2(156.75,85.7)
  BOTTOM w0.076: UC1.AP2 155.73,85.78 156.02,86.07 156.25,86.07 156.62,85.7 v2(156.75,85.7)
MEM_SMBDATA: length 22.1
  TOP w0.102: QC1.3 174.35,90.46 173.22,89.33 173.22,87.94 173.09,87.81 RP40.2 172.33,87.81 171.62,88.52 168.67,88.52 167.6,89.59 164.23,89.59 164,89.36 159.92,89.36 v2(159.44,88.88)
  BOTTOM w0.076: UC1.AH1 156.33,89.33 158.98,89.33 v2(159.44,88.88)
MIC1-L: length 6.6
  TOP w0.102: CA74.1 185.6,14.06 186.26,13.4 186.26,11.76 v1(186.02,11.52)
  TOP w0.203: CA74.1 186.17,14.34 186.97,15.14 186.97,15.9 186.82,16.05 UA1.19
MIC_CLK: length 251.1
  TOP w0.102: v2(9.71,73.84) 9.39,73.84 8.96,74.27 DX4.3 v2(8.96,76.52) ; LA1.2 180.22,21.82 179.8,22.24 v2(179.68,22.24) 179.33,22.6 CA22.1
  IN3 w0.135: v2(171.95,15.19) 168.98,15.19 168.62,15.55 167.22,15.55 165.49,13.81 165.49,13.59 164.72,12.83 163,12.83 161.57,11.4 161.57,10.47 159.87,8.77 158.04,8.77 157.11,9.7 155.17,9.7 154.82,9.35 153.83,9.35 153.27,8.79 153.06,8.79 152.78,8.51 143.2,8.51 142.94,8.77 142.94,10.21 142.63,10.52 142.43,10.52 141.36,11.6 132.78,11.6 131.7,12.68 125.99,12.68 124.9,13.77 118.06,13.77 115.69,16.13 105.21,16.13 104.09,15.01 95.44,15.01 91.89,18.57 88.14,18.57 87.25,19.46 82.08,19.46 79.95,21.59 79.95,24.79 79.67,25.06 79.67,44.98 77.8,46.85 77.8,50.24 78.44,50.88 78.44,53.45 74.98,56.91 74.98,60.72 74.65,61.04 74.32,61.04 71.68,63.68 54.51,63.68 52.53,61.7 46.86,61.7 44.38,59.22 38.32,59.22 35.21,62.32 27.94,62.32 20.47,69.79 15.28,69.79 11.23,73.84 v2(9.71,73.84)
  BOTTOM w0.102: v2(8.96,76.52) 9.52,77.08 9.52,84.45 7.81,86.16 5.39,86.16 4.94,85.71 4.03,85.71 3.79,85.95 JEDP.11 ; v2(179.68,22.24) 178.01,20.56 177.52,20.56 176.96,20 176.96,19.61 172.55,15.19 v2(171.95,15.19)
MIC_CLK_C: length 2.5
  TOP w0.102: UA1.3 183.13,21.22 182.69,21.66 v1(182.3,21.66) 181.46,21.66 LA1.1
MIC_DATA: length 259.8
  TOP w0.102: v2(171.89,14.54) 173.08,13.35 v1(174.98,13.35) 176.68,13.35 v2(177.16,13.83) ; v2(9.71,73.2) 8.95,73.2 8.25,73.9 7.42,73.9 7.03,74.3 DX4.2 v2(7.03,76.62) ; UA1.2 184.06,21.62 184.21,21.77 184.21,22.21 v2(183.95,22.47)
  IN1 w0.114: v2(177.16,13.83) 177.43,14.1 177.86,14.1 178.62,14.86 178.62,17.15 179.54,18.08 179.54,18.85 179.8,19.1 180.28,19.1 183.07,21.9 183.44,21.9 183.95,22.41 v2(183.95,22.47)
  IN3 w0.135: v2(171.89,14.54) 171.58,14.54 171.49,14.45 167.03,14.45 166.48,13.9 166.48,12.7 165.89,12.12 163.2,12.12 162.31,11.23 162.31,9.06 161.37,8.12 155.17,8.12 154.89,7.85 142.88,7.85 141.84,8.89 141.84,10.21 141.09,10.95 138.57,10.95 138.13,10.52 131.63,10.52 130.13,12.02 117.81,12.02 114.48,15.34 105.34,15.34 104.36,14.37 95.18,14.37 91.63,17.92 88.04,17.92 87.85,17.73 82.83,17.73 79.3,21.26 79.3,24.52 79.03,24.79 79.03,44.71 77.16,46.58 77.16,50.52 77.79,51.15 77.79,53.19 74.33,56.65 74.33,60.09 71.39,63.04 56.41,63.04 53.7,60.33 46.4,60.33 44.65,58.57 38.05,58.57 35.36,61.27 26.98,61.27 22.17,66.08 21.51,66.08 18.43,69.15 13.82,69.15 9.78,73.2 v2(9.71,73.2)
  BOTTOM w0.102: JEDP.9 3.93,84.95 4.08,85.1 5.8,85.1 6.15,85.46 7.35,85.46 8.91,83.91 8.91,78.5 v2(7.03,76.62)
MSCLK: length 94.9
  TOP w0.102: v2(150.14,19.13) 150.3,19.28 UE5.B43 ; v2(71.11,18.13) 71.51,18.52 RE72.2
  IN1 w0.114: v2(71.16,21.02) 71.71,21.57 73.25,21.57 73.93,22.25 77.3,22.25 78.78,23.74 83.28,23.74 85.33,25.78 92.5,25.78 93.21,25.07 98.62,25.07 99.75,23.94 100.64,23.94 102.07,22.5 130.07,22.5 131.61,20.96 137.15,20.96 137.72,20.39 138.21,20.39 139.56,21.74 145.01,21.74 145.62,22.35 149.92,22.35 150.19,22.07 150.19,19.18 v2(150.14,19.13)
  BOTTOM w0.102: v2(71.16,21.02) 71.51,21.02 71.9,20.63 71.9,18.91 v2(71.11,18.13) 70.65,17.67 70.18,17.67 69.85,17.33 JDEG.6
MSDATA: length 99.5
  TOP w0.102: RE75.2 70.49,18.25 v2(70.35,18.11) ; UE5.A40 150.55,21.44 151.03,21.92 v2(151.03,21.97) ; v2(137.94,20.8) 137.65,20.51 137.65,13.69 137.21,13.26 RPE6.3
  IN1 w0.114: v2(70.57,21.02) 71.35,21.81 73.14,21.81 73.92,22.58 77.19,22.58 78.59,23.98 83.18,23.98 85.23,26.02 92.6,26.02 93.31,25.31 98.72,25.31 99.85,24.18 100.74,24.18 102.17,22.75 130.32,22.75 131.87,21.2 137.25,21.2 137.65,20.8 v2(137.94,20.8) 138.28,20.8 139.46,21.99 144.91,21.99 145.53,22.61 150.27,22.61 150.91,21.97 v2(151.03,21.97)
  BOTTOM w0.102: v2(70.35,18.11) 70.34,18.12 70.34,19.65 JDEG.7 70.35,20.8 v2(70.57,21.02)
MULTI_STRAP_REF0_GND: length 2.8
  TOP w0.102: v1(70.16,93.4) 70.21,93.45 RV93.1 70.29,94.44 v2(71.02,93.7)
  BOTTOM w0.102: UV1.F6 71.02,93.63 v2(71.02,93.7)
MULTI_STRAP_REF1_GND: length 2.9
  TOP w0.102: v1(72.76,93.02) 72.37,93.41 72.08,93.41 71.94,93.55 v2(71.94,93.73) 71.94,93.8 72.47,94.34 RV95.1
  BOTTOM w0.102: UV1.F4 72.36,93.3 v2(71.94,93.73)
MULTI_STRAP_REF2_GND: length 2.5
  TOP w0.102: v2(71.96,92.89) v1(71.48,93.37) 71.48,94.06 RV96.1
  BOTTOM w0.102: UV1.F5 71.94,92.89 v2(71.96,92.89)
NB_PSID: length 15.5
  TOP w0.203: PL3.2 17.76,102.47 17.26,102.96 17.26,106.94 PD3.1 16.35,107.85 v3(16.35,109.59) 16.35,113.58 16.92,114.15 JDCIN.1
NTC: length 4.1
  TOP w0.102: v1(67.53,102.77) 67.53,103.16 67.29,103.41 67.29,104.19 PR525.2
  TOP w0.254: PR525.2 67.75,105.17 67.07,105.84 PU501.5
NVVDD_PSI: length 95.8
  IN1 w0.114: v2(54.26,61.72) 56.18,63.64 68.8,63.64 70.55,65.39 70.55,68.38 71.46,69.28 71.46,74.31 70.73,75.04 70.73,77.66 70.64,77.75 70.64,78.96 70.99,79.31 70.99,83.26 72.14,84.41 72.14,88.29 72.39,88.55 72.39,91.39 72.13,91.65 71.65,91.65 70.54,92.76 70.54,94.96 73.27,97.7 v2(73.27,97.91)
  BOTTOM w0.102: v1(75.65,100.92) 75.42,100.69 RV125.1 74.6,99.55 73.27,98.22 v2(73.27,97.91) 73.18,97.91 72.75,97.48 72.75,96.95 UV1.B4 ; PR605.2 49.8,41.82 48.38,40.4 47.14,40.4 45.25,42.29 44.18,42.29 43.59,42.88 43.59,43.74 43.1,44.24 43.1,57.44 46.59,60.94 48.01,60.94 48.75,61.67 54.21,61.67 v2(54.26,61.72)
PANEL_BKEN_EC: length 164.7
  TOP w0.102: UE4.5 94.05,17.58 93.17,18.46 93.17,21.64 97.12,25.59 v2(97.12,26.49) ; DV2.2 8.98,77.68 10.49,76.16 10.49,75.26 12.3,73.46 v1(12.3,72.51) 12.3,70.85 13.16,69.99 27.35,69.99 38.44,58.9 43.19,58.9 43.57,59.29 44.03,59.29 46.89,62.15 46.89,71.35 v2(46.97,71.43)
  IN3 w0.135: v2(46.97,71.43) 48.85,71.43 49.41,70.87 66.4,70.87 67.31,69.96 73.74,69.96 76.48,67.22 86.44,67.22 89.09,64.57 89.09,58.01 82.67,51.59 82.67,47.33 84.3,45.7 84.3,43.91 85.08,43.13 85.08,37.21 89.72,32.58 89.98,32.58 96.07,26.49 v2(97.12,26.49)
PANEL_BKLEN: length 364.1
  TOP w0.102: DV2.3 8.55,81.35 v2(8.31,81.59)
  IN1 w0.114: v2(151.36,106.76) 151.36,106.76 151.42,106.71 152.61,106.71 153.19,106.12 155.02,106.12 156.19,107.29 159.77,107.29 160.08,106.99 160.08,103.81 164.27,99.62 168.63,99.62 169.7,100.68 174.75,100.68 176.62,98.81 181.47,98.81 182.17,98.11 184.36,98.11 185.48,96.99 185.48,93.14 184.43,92.09 184.43,82.81 183.72,82.1 183.72,79.38 185.59,77.51 185.59,66.56 187.91,64.23 187.91,47.02 190.15,44.79 190.15,38.87 190.6,38.42 190.6,36.9 188.7,35 188.7,33.5 186.4,31.21 186.4,30.29 182.64,26.53 182.64,25.82 181.98,25.16 180.5,25.16 176.88,21.53 176.88,18.5 175.78,17.4 175.78,15.37 170.92,10.52 169.53,10.52 165.81,6.8 157.46,6.8 157.42,6.84 142.41,6.84 141.61,6.05 133.07,6.05 129.63,9.49 114.26,9.49 113.18,8.41 111.99,8.41 111.1,9.3 v2(110.39,9.3)
  IN3 w0.135: v2(20.43,73.59) 20.27,73.74 19.37,73.74 14.27,78.83 14.27,82 14.99,82.71 14.99,83.56 14.4,84.15 10.88,84.15 v2(8.31,81.59)
  BOTTOM w0.076: v2(151.36,106.76) 150.88,106.28 150.88,106.21 150.88,106.21 150.88,105.57 150.69,105.38 UC1.A9
  BOTTOM w0.102: v2(20.43,73.59) 20.6,73.41 32.26,73.41 32.74,72.93 34.47,72.93 34.98,73.43 42.29,73.43 43.38,72.34 52.56,72.34 53.88,71.02 64.6,71.02 68.02,67.6 73.7,67.6 76.23,65.08 76.23,58.09 80.14,54.18 87.59,54.18 87.96,53.81 87.96,53.8 88.4,53.37 88.4,43.46 v1(88.89,42.97) 90.61,41.25 90.61,36.3 101.05,25.86 101.05,19.59 108.31,12.32 108.89,12.32 110.39,10.81 v2(110.39,9.3)
PBAT_PRES#: length 144.8
  TOP w0.102: UE5.A49 144.11,18.92 143.48,19.55 139.87,19.55 138.19,17.87 v2(138.19,17.3) ; v2(27.77,17.99) 25.07,17.99 24.85,18.21 24.26,18.21 23.18,19.29 v1(22.08,19.29) 21.03,19.29 PR2.2 19.82,20.28 19.28,20.81 19.28,21.26 PRP1.1
  IN1 w0.114: v2(138.19,17.3) 136.69,17.3 136.29,17.71 135.17,17.71 134.7,17.24 116.16,17.24 115.16,18.24 101.64,18.24 99.86,20.02 95.59,20.02 95.22,20.4 92.82,20.4 90.97,18.56 87.79,18.56 87.11,19.24 80.56,19.24 79.4,18.07 74.27,18.07 72.68,16.49 67.51,16.49 66.91,17.08 50.86,17.08 46.65,12.87 40.89,12.87 38.88,10.86 35.17,10.86 33.95,12.08 29.01,12.08 v2(28.26,11.33)
  IN3 w0.135: v2(27.77,17.99) 28.2,17.55 28.2,14.13 27.08,13.01 27.08,12.32 28.07,11.33 v2(28.26,11.33)
  BOTTOM w0.102: v2(28.26,11.33) 27.92,11.67 PR728.1
PBAT_SMBCLK: length 144.4
  TOP w0.102: UE5.A56 v1(143.82,15.42) 143.67,15.57 143.67,15.94 v2(143.55,16.05) 143.55,16.3 142.88,16.97 RE45.2 ; PRP1.3 19.26,22.53 19.03,22.3 19.03,21.38 18.53,20.88 18.53,19.42 18.73,19.22 v2(18.73,19.17)
  IN1 w0.114: v2(143.55,16.05) 143.19,16.05 141.8,17.44 141.14,17.44 140.48,16.78 136.87,16.78 136.18,17.46 135.27,17.46 134.8,16.99 116.06,16.99 115.06,18 101.54,18 99.76,19.78 95.49,19.78 95.12,20.16 92.92,20.16 91.07,18.32 83.21,18.32 82.54,18.99 80.66,18.99 79.5,17.83 74.37,17.83 72.78,16.25 64,16.25 63.5,16.74 50.86,16.74 46.75,12.63 40.99,12.63 38.98,10.62 33.28,10.62 32.12,11.78 30.35,11.78 29.34,10.77 27.96,10.77 26.98,11.75 26.98,12.67 20.48,19.17 18.73,19.17 v2(18.73,19.17)
PBAT_SMBDAT: length 146.3
  TOP w0.102: v2(143.54,18.9) 143.49,18.85 RE38.2 142.41,19.32 140.72,19.32 v1(140.56,19.15) ; v2(19.74,21.03) 20.12,21.41 20.12,21.75 19.84,22.03 PRP1.2 ; v2(146.34,15.54) 146.21,15.67 UE5.B59
  IN1 w0.114: v2(143.54,18.9) 143.1,18.46 140.29,18.46 139.55,17.72 136.62,17.72 136.39,17.95 135.07,17.95 134.6,17.48 116.26,17.48 115.26,18.48 101.74,18.48 99.96,20.27 95.69,20.27 95.32,20.64 92.72,20.64 90.87,18.8 88.12,18.8 87.38,19.53 80.52,19.53 79.3,18.32 74.17,18.32 72.58,16.73 67.61,16.73 67.01,17.33 50.76,17.33 46.55,13.11 40.79,13.11 38.78,11.1 35.27,11.1 34.05,12.32 28.66,12.32 27.74,13.24 26.75,13.24 19.74,20.25 v2(19.74,21.03)
  BOTTOM w0.102: v2(146.34,15.54) 146.04,15.54 145.06,16.51 145.06,18.3 144.47,18.9 v2(143.54,18.9)
PBATT+_C:
  vias: v1(16.86,28.89)
PC_BEEP: length 9.2
  TOP w0.102: DA8.1 173.99,9.36 173.99,10.71 v1(174.6,11.32) 175.97,12.69 176.89,12.69 177.73,13.53 177.73,14.48 RA19.1 RA79.2
PCH_ALW_ON: length 101.2
  TOP w0.102: RPE10.4 160.14,9.21 160.75,8.6 163.21,8.6 163.76,9.15 164.65,9.15 165.56,8.23 167.14,8.23 v1(168.95,10.05) 169.45,10.54 v2(169.45,11.91) ; v2(153.79,21.34) 153.55,21.1 UE5.A34 ; R416.1 183.01,66.35 v2(183.42,65.94)
  IN1 w0.114: v2(183.42,65.94) 184.08,65.94 186.71,63.31 186.71,46.52 187.51,45.72 187.51,43.77 188.5,42.78 188.5,40.38 187.39,39.28 187.39,34.01 185.2,31.82 185.2,30.79 181.67,27.27 180.8,27.27 177.39,23.85 176.37,23.85 174.57,22.06 174.57,15.87 170.61,11.91 v2(169.45,11.91)
  BOTTOM w0.102: v2(153.79,21.34) 153.79,20.78 156.25,18.32 157.46,18.32 157.77,18.62 160.54,18.62 161.83,17.33 164.74,17.33 165.61,16.45 165.61,16.25 165.61,15.78 169.45,11.94 v2(169.45,11.91)
PCH_AZ_BITCLK: length 77.9
  IN3 w0.135: v2(176.53,60.53) 176.46,60.45 176.46,58.4 179.79,55.07 179.79,53.11 180.83,52.07 180.83,49.71 176.61,45.5 176.61,41.43 v2(176.64,41.4)
  BOTTOM w0.076: UC1.AW8 151.26,83.01 150.99,82.74 150.99,81.61 152.46,80.14 152.46,76.76 153.57,75.64 153.57,74.76
  BOTTOM w0.102: R2359.2 178.07,27.1 177.08,28.09 177.08,32.18 176.25,33.01 176.25,38.51 177.09,39.35 177.09,40.95 v2(176.64,41.4) ; 153.57,74.76 153.57,74.22 162.08,65.71 165.2,65.71 166.27,64.65 v1(168.84,64.65) 169.5,64.65 173.61,60.53 v2(176.53,60.53)
PCH_AZ_CODEC_BITCLK: length 34.3
  TOP w0.102: UA1.6 183.57,20.03 182.71,20.03 v2(182.62,19.93)
  BOTTOM w0.102: v2(182.62,19.93) 180.92,18.23 180.92,16.59 178.56,14.23 176.21,14.23 176.12,14.14 171.72,14.14 171.34,14.52 171.34,15.44 172.78,16.88 173.25,16.88 174.97,18.61 174.97,22.51 177.42,24.96 178.78,24.96 v1(178.91,25.08) 179.04,25.21 CC5.1 179.07,26.22 R2359.1 179.94,27.1 RA1112.1
PCH_AZ_CODEC_RST#: length 2.8
  TOP w0.102: R2358.1 181.87,16.31 182.96,17.4 182.96,17.78 183.2,18.02 UA1.11
PCH_AZ_CODEC_SDIN0: length 106.9
  TOP w0.102: v2(179.82,20.28) 179.27,20.28 178.54,19.55 RA130.1
  IN1 w0.114: v2(190.56,55.86) 190.56,55.78 191.24,55.09 192.95,55.09 195.93,52.12 195.93,41.38 196.14,41.17 196.14,39.02 196.55,38.6 196.55,36.32 196.14,35.9 196.14,32.45 195.43,31.74 195.43,30.89 194.1,29.56 194.1,28.25 193.11,27.26 191.33,27.26 187.22,23.14 183.79,23.14 183.36,22.72 181.53,22.72 181.33,22.51 181.33,21.52 180.09,20.28 v2(179.82,20.28)
  BOTTOM w0.076: UC1.AY10 150.52,81.85 152.15,80.21 152.15,76.53 152.92,75.76 152.92,74.76
  BOTTOM w0.102: v2(190.56,55.86) 189.48,56.94 178.48,56.94 175.49,59.92 173.33,59.92 v1(169.84,63.41) 169.22,64.04 166.02,64.04 164.95,65.1 161.83,65.1 152.92,74.01 152.92,74.76
PCH_AZ_CODEC_SDOUT: length 2.4
  TOP w0.102: R2356.1 182.15,20.8 182.53,20.42 UA1.5
PCH_AZ_CODEC_SYNC: length 2.4
  TOP w0.102: UA1.10 183.17,18.42 182.66,17.91 182.66,17.86 182,17.2 R2357.1
PCH_AZ_RST#: length 111.6
  TOP w0.102: R2358.2 180.73,16.41 v2(180.17,16.41)
  IN1 w0.114: v2(191.06,56.97) 191.06,57 191.09,56.97 192.47,56.97 196.92,52.53 196.92,41.89 197.69,41.11 197.69,36.06 197.13,35.49 197.13,32.04 196.42,31.33 196.42,30.48 195.09,29.14 195.09,27.83 193.09,25.83 191.33,25.83 187.46,21.96 185.4,21.96 183.77,20.33 183.77,19.43 183.09,18.75 181.51,18.75 181.25,18.49 181.25,17.49 v2(180.17,16.41)
  BOTTOM w0.076: UC1.AU8 151.64,83.97 151.64,83.56 151.55,83.47 151.55,81.28 153.01,79.82 153.01,78.36 154.18,77.19 154.18,74.76
  BOTTOM w0.102: v2(191.06,56.97) 191.06,56.95 190.48,57.53 v1(190.05,57.53) 181.61,57.53 181.5,57.42 178.68,57.42 177.07,59.03 177.07,60.68 176.48,61.27 173.74,61.27 169.75,65.25 166.52,65.25 165.1,66.68 161.98,66.68 154.18,74.48 154.18,74.76
PCH_AZ_SDOUT: length 107.5
  TOP w0.102: v2(179.53,20.78) 179.55,20.8 R2356.2
  IN1 w0.114: v2(189.87,55.86) 189.87,55.73 192.05,53.55 193.4,53.55 195.43,51.51 195.43,34.73 194.87,34.17 194.87,31.52 194.57,31.22 194.57,30.73 193.53,29.68 193.53,28.37 192.9,27.75 191.1,27.75 188.88,25.53 186.75,25.53 186.29,25.07 186.29,24.01 185.92,23.64 183.58,23.64 183.16,23.21 181.33,23.21 180.83,22.72 180.83,21.73 179.89,20.78 v2(179.53,20.78)
  BOTTOM w0.076: UC1.AU11 149.81,84.22 150.1,83.92 150.1,83.61 150.24,83.47 150.24,81.54 151.92,79.85 151.92,75.88 152.44,75.37 152.44,74.76
  BOTTOM w0.102: v2(189.87,55.86) 189.27,56.45 178.28,56.45 175.29,59.44 173.13,59.44 v1(171.09,61.48) 169.02,63.55 167.49,63.55 RC8.2 166.32,63.05 164.75,64.62 161.63,64.62 152.44,73.81 152.44,74.76
PCH_AZ_SYNC: length 111
  TOP w0.102: v2(180.17,17.17) 180.8,17.17 R2357.2
  IN1 w0.114: v2(180.17,17.17) 180.71,17.72 180.71,18.66 181.47,19.42 182.74,19.42 183.03,19.71 183.03,20.53 185.08,22.58 187.37,22.58 191.55,26.76 193.32,26.76 194.59,28.04 194.59,29.35 195.93,30.68 195.93,31.54 196.63,32.24 196.63,35.7 197.04,36.11 197.04,38.95 196.63,39.36 196.63,41.37 196.42,41.58 196.42,52.33 192.89,55.86 v2(191.22,55.86)
  BOTTOM w0.076: UC1.AV11 150.05,83.42 150.05,81.49 151.74,79.8 151.74,75.38 151.91,75.21 151.91,74.76
  BOTTOM w0.102: v2(191.22,55.86) 191.22,55.73 190.73,55.25 189.64,55.25 188.92,55.97 177.74,55.97 175.44,58.27 173.55,58.27 v1(172.56,59.27) 169.39,62.44 166.25,62.44 164.67,64.01 161.56,64.01 151.91,73.65 151.91,74.76
PCH_BATLOW#: length 16.4
  TOP w0.102: RC39.2 168.08,90.91 161.57,90.91 160.95,90.29 158.04,90.29 157.01,89.26 156.21,89.26 155.81,88.86 155.81,88.16 v1(155.58,87.93) v2(154.55,86.9)
  BOTTOM w0.076: v2(154.55,86.9) 154.19,86.54 UC1.AN4
PCH_CPU_ID: length 9.9
  TOP w0.102: RC373.2 RC374.1 v1(158.68,107.18) 158.68,106.12 v2(154.51,101.96)
  BOTTOM w0.076: v2(154.51,101.96) 154.19,102.29 UC1.E4
PCH_DPWROK: length 90.3
  TOP w0.102: v2(153.7,22.67) 153.7,22.38 153.12,21.8 153.12,21.45 152.55,20.88 UE5.A36
  IN1 w0.114: v2(161.07,76.02) 161.12,76.02 162.49,74.65 162.49,71.49 164.48,69.5 170.08,69.5 171.72,67.86 171.72,65.56 170.97,64.81 170.97,58.96 171.3,58.63 171.3,53.66 169.26,51.62 169.26,46.95 170.45,45.77 170.45,40.6 169.8,39.95 169.8,38.31 168.29,36.8 168.29,35.92 167.78,35.41 167.78,30.55 164.69,27.45 164.69,27.01 161.79,24.11 159.04,24.11 157.28,22.35 154.02,22.35 v2(153.7,22.67)
  BOTTOM w0.076: 160.3,76.89 160.3,77.24 159.92,77.62 156.37,77.62 155.45,78.54 v1(155.45,79.11) 155.45,80.55 154.98,81.02 154.06,81.02 153.5,81.57 153.5,81.94 153.22,82.22 153.22,83.41 UC1.AV5
  BOTTOM w0.102: 160.3,76.89 160.3,76.53 160.81,76.02 v2(161.07,76.02)
PCH_GPIO10: length 7.4
  BOTTOM w0.076: T27.1 161.42,86.16 159.44,86.16 159.19,86.41 157.79,86.41 157.65,86.55 156.78,86.55 156.35,86.98 155.86,86.98 155.57,87.28 UC1.AM2
PCH_GPIO12: length 28.6
  TOP w0.102: RC117.1 171.57,80.77 171.57,79.36 171.31,79.11 169.66,79.11 169.47,78.92 164.39,78.92 160.32,82.98 T182.1 155.38,82.98 155.21,83.15 153.89,83.15 153.29,83.75 153.29,84.12 152.47,84.95 152.47,85.24 152.39,85.32 152.39,87.38 v2(152.81,87.8)
  BOTTOM w0.076: UC1.AM7 152.57,87.56 v2(152.81,87.8)
PCH_GPIO14: length 3.4
  TOP w0.102: v2(153.75,89.66) 153.33,90.08 152.95,90.08 152.94,90.07 151.2,90.07 T126.1
  BOTTOM w0.076: UC1.AH4 154.19,89.51 154.04,89.66 v2(153.75,89.66)
PCH_GPIO25: length 7.1
  BOTTOM w0.076: T127.1 160.65,86.58 157.86,86.58 156.87,87.57 155,87.57 154.96,87.61 154.48,87.61 UC1.AM4
PCH_GPIO34: length 17.4
  TOP w0.102: RP37.4 171.58,93.16 170.68,94.05 170.68,94.27 170.06,94.88 162.9,94.88 162.11,94.1 v1(161.28,94.1) 160.29,94.1 v2(160.28,94.08)
  BOTTOM w0.102: v2(160.28,94.08) 160.28,94.31 159.8,94.8 156.17,94.8 UC1.V1
PCH_GPIO36: length 20.9
  TOP w0.102: v2(153.04,95.33) 153.06,95.33 153.52,94.87 153.88,94.87 154.06,95.05 v1(154.46,95.05) 154.64,94.87 159.83,94.87 160.93,95.96 161.74,95.96 162.35,96.57 166.15,96.57 166.64,96.09 171,96.09 171.36,96.45 RP43.7
  BOTTOM w0.076: UC1.V6 152.85,95.14 v2(153.04,95.33)
PCH_GPIO37: length 17.6
  TOP w0.102: v2(159.34,94.21) 159.82,94.21 160.1,94.49 162.18,94.49 162.81,95.11 170.36,95.11 v1(170.62,94.86) 170.97,94.5 170.97,94.25 171.56,93.66 RP37.3
  BOTTOM w0.076: v2(159.34,94.21) 157.64,92.52 UC1.AC1
PCH_GPIO47: length 1.7
  TOP w0.102: v2(152.99,93.43) 153.54,92.89 153.62,92.89 153.7,92.81 T174.1
  BOTTOM w0.076: UC1.AB6 152.85,93.29 v2(152.99,93.43)
PCH_GPIO48: length 8.2
  BOTTOM w0.076: UC1.U4 154.44,95.48 154.72,95.2 154.89,95.2 155.02,95.06 155.68,95.06 155.85,95.23 160.33,95.23 161.14,94.41 T124.1
PCH_GPIO66: length 12
  BOTTOM w0.076: UC1.D3 155.17,102.62 155.61,102.62 155.81,102.82 155.81,103.24 156.02,103.46 156.29,103.46 156.65,103.81 156.65,104.07 157.2,104.62 158.28,104.62 158.38,104.72
  BOTTOM w0.102: 158.38,104.72 160.18,106.52 v1(160.18,108.42) 160.18,109.45 160.84,110.11 RC118.2
PCH_GPIO73: length 10.6
  TOP w0.102: R2330.2 160.43,79.44 159.85,80.02 159.35,80.02 v1(159.15,80.22) v2(158.32,81.05)
  BOTTOM w0.076: v2(158.32,81.05) 158.02,80.75 157.44,80.75 156.45,81.74 155.62,81.74 155.2,82.15 155.2,82.49 155.15,82.55 155.15,83.16 154.97,83.34 154.56,83.34 154.45,83.45 154.45,83.86 154.16,84.14 UC1.AU4
PCH_GPIO76: length 22.5
  BOTTOM w0.076: 162.03,97.18 156.62,97.18 156.54,97.11 156.23,97.11 UC1.P1
  BOTTOM w0.102: 162.03,97.18 162.65,97.18 v1(163.47,96.37) 164,95.84 170.2,95.84 171.39,94.64 171.39,91.2 171.8,90.8 171.8,90.23 172.08,89.95 172.08,89.45 RC116.1
PCH_GPIO77: length 21.7
  TOP w0.102: RP60.8 171.26,98.74 170.67,98.15 166.53,98.15 165.87,97.49 161.97,97.49 161.67,97.18 v1(161.23,97.18) 160.85,97.18 159.46,95.79 156.31,95.79 155.86,96.24 153.73,96.24 153.34,96.63 152.98,96.63 152.94,96.6 152.94,96.6 152.57,96.23 v2(152.54,96.23)
  BOTTOM w0.076: v2(152.54,96.23) 152.85,95.92 UC1.U6
PCH_GPIO79: length 20.1
  TOP w0.102: v2(154.54,97.38) 154.54,98.11 155.03,98.59 155.5,98.59 156.3,97.79 160.98,97.79 161.58,98.39 v1(164.9,98.39) 165.73,98.39 166.53,99.19 168.35,99.19 169.01,99.85 171.15,99.85 171.25,99.74 RP60.6
  BOTTOM w0.076: UC1.N4 154.19,97.73 v2(154.54,97.38)
PCH_GPIO80: length 17.4
  TOP w0.102: v2(166.83,96.8) 167.21,97.18 167.69,97.18 167.84,97.03 170.16,97.03 v1(170.58,97.45) RP43.5
  BOTTOM w0.076: 162.03,97.64 156.49,97.64 156.32,97.46 155.79,97.46 UC1.N2
  BOTTOM w0.102: 162.03,97.64 163.48,97.64 164.32,96.8 v2(166.83,96.8)
PCH_GPIO85: length 11.8
  TOP w0.102: v2(153.06,98.22) 153.45,97.84 153.93,97.84 153.93,97.84 153.95,97.84 154.93,98.82 155.59,98.82 156.39,98.02 160.89,98.02 161.73,98.86 T175.1
  BOTTOM w0.076: v2(153.06,98.22) 152.85,98.01 UC1.N6
PCH_GPIO87: length 3.5
  TOP w0.102: v2(152.51,97.13) 152.04,97.59 151.8,97.59 151.36,98.03 151.36,98.5 151.64,98.78 T4931.1
  BOTTOM w0.076: v2(152.51,97.13) 152.51,97.11 152.2,96.8 UC1.R7
PCH_GPIO90: length 4
  BOTTOM w0.076: UC1.K2 155.53,99.26 155.83,99.57 156.19,99.57 156.58,99.96 159.15,99.96 T179.1
PCH_GPIO93: length 6.4
  BOTTOM w0.076: UC1.J2 155.49,100.04 155.92,100.47 156.33,100.47 156.98,101.12 158.3,101.12
  BOTTOM w0.102: T180.1 159.85,101.12 158.3,101.12
PCH_GPIO94: length 3
  BOTTOM w0.076: UC1.G1 156.37,100.76 157.18,101.58 158.42,101.58
  BOTTOM w0.102: 158.42,101.58 T181.1
PCH_INTVRMEN: length 26.7
  BOTTOM w0.076: 154.68,74.76 154.68,77.52 153.64,78.56 v1(153.64,78.86) 153.64,79.43 151.72,81.35 151.72,83.39 151.98,83.65 UC1.AV7
  BOTTOM w0.102: 154.68,74.76 154.68,74.66 162.18,67.16 166.43,67.16 RC2.1 RC1.2
PCH_JTAG_JTAGX: length 14.5
  BOTTOM w0.076: 110.93,91.77 113.33,91.77 113.97,91.13 117.44,91.13 UC1.AE63
  BOTTOM w0.102: 110.93,91.77 v1(107.52,91.77) 106.53,91.77 RC130.1 RC62.2 RC59.2
PCH_JTAG_RST#: length 73.7
  TOP w0.102: v2(105.16,78.31) 105.16,78.01 105.9,77.27 114.02,77.27 114.79,78.03 114.79,78.19 116.46,79.86 116.97,79.86 v2(117.07,79.76) ; v2(114.08,102.44) 114.08,105.79 113.47,106.4 v3(113.47,107.6) RC57.2
  IN1 w0.114: v2(92,93.73) 92,93.45 92.87,92.59 92.87,90.76 105.16,78.46 v2(105.16,78.31)
  IN3 w0.135: v2(114.08,102.44) 114.02,102.39 113.29,102.39 108.09,97.19 100.32,97.19 99.69,96.56 94.25,96.56 92,94.31 v2(92,93.73)
  BOTTOM w0.076: v2(117.07,79.76) 116.69,80.14 116.69,80.85 116.41,81.14 116.41,83.5 117.19,84.28 117.19,84.45 117.38,84.63 117.64,84.63 117.95,84.32 UC1.AU62
PCH_JTAG_TCK: length 33.7
  TOP w0.102: v2(95.69,85.02) 94.96,85.74 92.92,85.74 92.74,85.56 92.74,82.4 92.5,82.16 JXDP.55
  BOTTOM w0.076: UC1.AE62 117.94,90.84 117.73,90.84 117.6,90.78 117.4,90.78 117.21,90.97 110.93,90.97
  BOTTOM w0.102: 110.93,90.97 108.75,90.97 107.75,89.97 105.67,89.97 RC65.2 RC135.1 105.47,89.21 101.27,85.02 v2(95.69,85.02)
PCH_JTAG_TDI: length 31.1
  TOP w0.102: RC44.1 94.61,91.91 v3(95.96,90.56) 96.8,89.72 100.94,89.72 v2(101.99,90.76)
  BOTTOM w0.076: UC1.AD61 118.56,92.1 118.01,92.1 117.86,91.95 117.86,91.67 117.71,91.52 117.02,91.52 116.97,91.47 114.25,91.47 113.59,92.13
  BOTTOM w0.102: v2(101.99,90.76) 102.36,91.13 RP48.8 102.04,91.25 101.76,91.53 101.76,92.92 102.02,93.18 103.42,93.18 103.81,93.58 107.45,93.58 108.36,92.66 113.06,92.66 113.59,92.13
PCH_JTAG_TDO: length 32.1
  TOP w0.102: v2(118.54,91.41) 117.04,91.41 116.68,91.05 v3(105.22,91.05) 103.47,91.05 v2(103.26,90.83) 101.68,89.26 93.08,89.26 RC43.1
  BOTTOM w0.076: v2(118.54,91.41) 118.54,91.3 UC1.AE61
  BOTTOM w0.102: v2(103.26,90.83) 103.26,90.6 102.75,90.1 RC63.2 102.24,90.43 102.87,91.06 102.87,91.37 102.49,91.75 RP48.7
PCH_JTAG_TMS: length 39.8
  TOP w0.102: v2(103,91.95) 102.56,91.95 100.58,89.97 97.9,89.97 93.7,94.16 86.17,94.16 v3(86.01,93.99) 84.44,92.42 RC46.1
  BOTTOM w0.076: UC1.AD62 118.16,91.69 117.82,91.35 117.09,91.35 117.04,91.3 114.14,91.3 113.11,92.33 110.93,92.33
  BOTTOM w0.102: 110.93,92.33 108.16,92.33 107.14,93.35 103.91,93.35 103,92.44 v2(103,91.95) 102.7,92.25 RP48.6
PCH_OPI_COMP: length 8.6
  TOP w0.305: v2(147.91,80.19) 147.6,80.19 v1(147.43,80.01) 147.43,78.04 148.65,76.82 RC101.1
  BOTTOM w0.152: 148.06,81.94 148.06,81.97 147.93,82.1 147.93,82.59 UC1.AW15
  BOTTOM w0.305: 148.06,81.94 148.37,81.63 148.37,80.72 147.91,80.26 v2(147.91,80.19)
PCH_PCIE_RCOMP: length 3.5
  BOTTOM w0.305: RC91.2 139.96,107.88 140.46,107.38 v1(140.46,107.03) 140.46,105.14 UC1.A27
PCH_PCIE_WAKE#: length 168
  TOP w0.102: UE5.A44 148.55,20.62 148.55,21.07 148.62,21.14 148.62,21.49 v2(148.21,21.9) ; v2(109.28,21.52) 109.15,21.39 109.15,16.86 106.49,14.2 v1(106.24,14.2) 106.19,14.15 RE274.2 ; RC97.2 169.74,92.51 v2(169.79,92.46)
  IN1 w0.114: v2(109.28,21.52) 109.31,21.48 129.52,21.48 130.85,20.14 134.82,20.14 135.33,19.64 137.09,19.64 137.32,19.41 138.85,19.41 139.59,20.14 142.14,20.14 142.78,20.78 145.12,20.78 145.84,20.06 147.75,20.06 148.65,20.96 148.65,21.47 v2(148.21,21.9) ; v2(169.79,92.46) 172.01,90.23 172.01,87.62 171.23,86.83 171.23,85.02 172.84,83.4 172.84,79.41 174.6,77.65 174.6,73.41 177.04,70.97 177.04,65.66 177.78,64.92 177.78,64.15 177.34,63.72 177.34,61.7 177.93,61.12 177.93,56.21 178.63,55.51 178.63,53.07 179.71,51.99 179.71,48.39 179.18,47.86 179.18,39.31 177.26,37.39 177.26,31.31 172.95,27 172.95,25.59 169.99,22.63 169.34,22.63 168.58,21.87 168.58,18.85 166.76,17.02 v2(166.76,16.11)
  BOTTOM w0.102: v2(166.76,16.11) 166.76,16.47 164.96,18.26 164.07,18.26 162.98,19.36 158.17,19.36 157.43,20.09 157.43,23.98 156.85,24.56 152.53,24.56 152.28,24.31 152.28,23.9 151.97,23.6 149.38,23.6 148.21,22.43 v2(148.21,21.9)
PCH_PCIE_WAKE#_R: length 17.4
  TOP w0.102: RC97.1 RC34.2 167.77,91.14 161.47,91.14 160.95,90.62 v1(159.24,90.62) 158.05,90.62 156.92,89.49 156.11,89.49 155.72,89.09 154.28,89.09 v2(153.73,88.54)
  BOTTOM w0.076: UC1.AJ5 153.5,88.77 v2(153.73,88.54)
PCH_PLTRST#: length 32.1
  TOP w0.102: v2(160.38,88.11) 160.71,88.11 v1(161.03,88.43) 161.27,88.67 164.29,88.67 164.52,88.9 167.32,88.9 168.39,87.84 168.99,87.84 170.17,86.66 172.09,86.66 173.09,85.65 174.36,85.65 175.25,86.54 175.84,86.54 CC33.1 176.27,85.83 UC3.2 176.27,84.51 176.39,84.38 176.78,84.38 176.92,84.52 UC3.1
  IN1 w0.114: v2(160.38,88.11) 160.38,89.47 159.75,90.1 157.23,90.1 156.85,89.72 155.91,89.72 154.74,90.88 154.21,90.88 154.03,91.06 152.96,91.06 152.59,90.69 v2(152.59,90.64)
  BOTTOM w0.076: v2(152.59,90.64) 152.6,90.64 152.2,90.23 UC1.AG7
PCH_PLTRST#_EC: length 295.3
  TOP w0.102: v2(79.2,81) 79.2,81.38 79.38,81.56 RC367.1 ; UE5.B30 153.46,17.17 v2(153.19,16.89) ; RM6.2 186.14,54.16 v2(186.14,54.28) ; v1(175.2,81.52) 175.72,82.04 R159.1 175.62,82.57 UC3.4 175.62,83.6 175.82,83.81 177.16,83.81 177.46,84.11 v2(177.46,85.97) ; v2(81.54,82.04) 81.67,82.04 82.6,81.11 RC51.1
  IN1 w0.114: v2(177.46,85.97) 177.75,85.68 177.75,83.17 178.2,82.72 178.2,81.24 177.75,80.79 177.75,74.77 182.84,69.68 182.84,66.7 182.5,66.36 182.5,65.44 183.57,64.38 184.12,64.38 185.97,62.52 185.97,55.54 185.68,55.25 185.68,54.74 v2(186.14,54.28) 186.21,54.21 186.21,46.37 185.03,45.19 185.03,43.44 186.29,42.18 186.29,41.12 184.54,39.37 182.39,39.37 179.58,36.57 179.58,27.82 176.84,25.07 175.86,25.07 173.35,22.56 173.35,17.9 169.85,14.4 169.85,14.29 167.47,11.9 v2(167.47,11.89) ; v2(77.04,53.09) 76.51,53.62 76.51,64.95 82.88,71.33 82.88,80.7 v2(81.54,82.04) ; v2(70.85,12.05) 72.13,12.05 73.21,13.13 v2(74.78,13.13) 75.47,13.82 77.75,13.82 80.12,11.46 88.99,11.46 91.3,13.77 97.87,13.77 99.06,12.58 104.65,12.58 105.78,13.71 112.09,13.71 113.26,12.54 130.97,12.54 130.97,12.54 133.38,12.54 133.65,12.27 135.62,12.27 135.76,12.41 141.88,12.41 142.11,12.18 145.06,12.18 146.63,10.62 147.43,10.62 148.4,11.6 148.4,12.11 v2(153.19,16.89)
  IN3 w0.135: v2(79.2,81) 79.33,81 80.37,82.04 v2(81.54,82.04)
  BOTTOM w0.102: v2(177.46,85.97) 177.46,85.99 177.8,86.33 UL1.19 ; v2(153.19,16.89) 153.19,16.97 153.62,17.4 155.03,17.4 155.52,16.92 158.04,16.92 158.35,17.22 159.15,17.22 159.91,16.46 159.91,15.73 163.27,12.37 165.94,12.37 166.43,11.89 v2(167.47,11.89) ; v2(77.04,53.09) 75.44,51.49 75.44,45.19 83.37,37.26 83.37,32.84 84.14,32.07 84.14,28.44 79.53,23.83 78.82,23.83 76.76,21.77 76.76,15.99 74.78,14.01 v2(74.78,13.13) ; JLPDE.8 v2(70.85,12.05)
PCH_RSMRST#: length 105.1
  TOP w0.102: v2(159.9,71.38) 159.59,71.38 159.1,70.88 156.61,70.88 v1(154.92,72.57) 152.2,75.29 RC41.1 ; v2(148.21,21.31) 148.05,21.15 UE5.A45 ; v2(136.57,20.06) 137.42,19.2 137.42,13.95 137.23,13.76 RPE6.4
  IN1 w0.114: v2(148.21,21.31) 147.32,20.42 145.81,20.42 145.22,21.02 142.68,21.02 142.04,20.39 139.49,20.39 138.75,19.65 137.42,19.65 137.01,20.06 v2(136.57,20.06) ; v2(159.9,71.38) 159.44,70.92 159.44,69.29 159.67,69.06 161.63,69.06 162.99,67.7 168.85,67.7 169.33,67.21 169.33,59.23 170.34,58.23 170.34,54.07 167.3,51.03 167.3,38.28 166.03,37.01 166.03,30.26 163.72,27.94 163.72,27.41 162.4,26.09 159.63,26.09 159.14,25.59 154.17,25.59 v2(152.68,24.11)
  BOTTOM w0.102: v2(148.21,21.31) 148.65,21.74 148.65,22.1 148.95,22.41 149.91,22.41 150.88,23.37 152.23,23.37 152.68,23.83 v2(152.68,24.11)
PCH_RSMRST#_R: length 8.3
  TOP w0.102: v2(153.12,81.18) v1(151.76,79.82) 151.76,79.19 RC92.2 151.74,78.29 151.74,76.79 RC41.2
  BOTTOM w0.076: v2(153.12,81.18) 152.96,81.18 152.48,81.66 152.48,82.73 UC1.AW6
PCH_RTCRST#: length 41.6
  TOP w0.102: RC6.2 CC4.2 154.39,57.46 153.92,57.46 153.56,57.1 v2(153.32,57.1) 152.84,57.58 152.84,58.35 160.66,66.17 v1(160.66,69.76) 160.66,70.54 160.41,70.79 160.41,71.33 160.39,71.42 160.3,71.5 160.3,71.6 160.23,71.68 160.23,72.52 159.16,73.59 158.45,73.59 158.14,73.89 v2(158.14,74.2)
  IN1 w0.114: v2(152.35,83.95) 152.43,83.95 152.81,83.57 152.81,82.49 152.48,82.16 152.48,80.83 155.1,78.21 155.1,75.58 156.48,74.2 v2(158.14,74.2)
  BOTTOM w0.076: v2(152.35,83.95) 151.99,84.31 UC1.AU7
  BOTTOM w0.102: v2(153.32,57.1) 153.12,57.1 151.59,55.58 CMOS1.2
PCH_RTCX1: length 11.1
  TOP w0.102: v2(158.64,79.61) 158.5,79.47 RC4.1 158.6,78.56 CC1.2 158.6,76.69 YC1.1
  BOTTOM w0.076: UC1.AW5 153.58,83.01 153.88,82.71 153.88,81.74 154.25,81.37 156.33,81.37 157.67,80.02 158.22,80.02 v2(158.64,79.61)
PCH_RTCX2: length 10.2
  TOP w0.102: YC1.2 156.79,76 157.74,76.94 CC2.2 157.74,78.51 RC4.2 157.69,78.77 157.69,79.26 v2(158.03,79.61)
  BOTTOM w0.076: v2(158.03,79.61) 157.8,79.61 156.21,81.19 154.15,81.19 153.69,81.65 153.69,81.83 153.69,82.22 UC1.AY5
PCH_SMB_ALERT#: length 14.6
  BOTTOM w0.076: UC1.AN2 155.49,86.53 155.79,86.82 156.28,86.82 156.71,86.39 157.57,86.39 157.71,86.25 158.97,86.25 159.44,85.78 v1(159.8,85.78) 161.61,85.78 162.74,86.92
  BOTTOM w0.102: 162.74,86.92 163.57,87.75 168.03,87.75 R2329.2
PCH_SPI_CLK: length 26.7
  IN3 w0.135: v2(158.75,94.19) 158.75,94.36 159.54,95.15 v2(159.54,96.47)
  BOTTOM w0.076: 162.03,96.83 159.9,96.83 v2(159.54,96.47) ; UC1.AA3 154.84,93.25 155.27,92.81 156.38,92.81 156.41,92.79 157.36,92.79 v2(158.75,94.19)
  BOTTOM w0.102: 162.03,96.83 163.75,95.11 170.06,95.11 171.16,94.01 171.16,91.11 171.57,90.7 171.57,90.14 171.85,89.86 171.85,88.79 R2333.2
PCH_SPI_CLK_R: length 23.9
  TOP w0.102: v2(177.96,102.61) 177.97,102.61 178.62,101.96 v1(178.62,100.59) v2(178.62,98.16)
  BOTTOM w0.102: v2(177.96,102.61) 177.96,107.14 178.31,107.5 179.38,107.5 ; v2(178.62,98.16) 175.25,94.8 175.25,91.87 173.89,90.52 173.89,88.6 R2333.1 C2326.1
PCH_SPI_CS0#: length 34.6
  TOP w0.102: v2(161.89,107.16) 161.22,106.49 161.22,104.67 158.68,102.14 v3(156.39,102.14) 155.63,102.14 153.21,99.71 151.66,99.71 151.06,99.11 151.06,97.23 151.59,96.7 151.92,96.7 152.12,96.5 152.12,96.04 151.79,95.71 151.44,95.71 151.26,95.53 151.26,94.9 151.34,94.82 152.07,94.82 v2(152.51,94.39)
  BOTTOM w0.076: v2(152.51,94.39) 152.51,94.26 152.2,93.95 UC1.Y7
  BOTTOM w0.102: v2(161.89,107.16) 162.79,108.07 168.18,108.07 171.29,104.96 U2302.1
PCH_SPI_HOLD1#: length 17.5
  TOP w0.102: v2(177.99,102.02) 177.98,102.02 177.28,102.71 177.28,106.45 v1(176.81,106.92) 175.32,106.92 174.6,106.21 R2335.2 174.02,103.04 RP39.4
  BOTTOM w0.102: v2(177.99,102.02) 178.37,102.4 178.37,106.01 178.58,106.23 U2302.7
PCH_SPI_HOLD#: length 31.8
  TOP w0.102: v2(158.17,99.29) v1(159.35,100.47) 161.93,103.05 161.93,105.8 164.44,108.31 168.63,108.31 171.71,105.23 171.71,103.15 171.82,103.04 RP39.5
  IN3 w0.135: v2(156.72,91.26) 156.72,91.29 157.1,91.67 157.1,97.39 157.97,98.25 157.97,99.09 v2(158.17,99.29)
  BOTTOM w0.076: UC1.AF1 156.48,91.02 v2(156.72,91.26)
PCH_SPI_MISO: length 23.8
  TOP w0.102: v2(158.73,98.63) 158.75,98.66 158.75,98.73 160.4,100.38 v1(160.74,100.38) 163.08,100.38 163.58,99.88 168.07,99.88 168.73,100.54 169.99,100.54 171.49,102.04 RP39.7
  IN3 w0.135: v2(158.73,98.63) 158.73,98.45 157.48,97.2 157.48,94.24 v2(157.54,94.19)
  BOTTOM w0.076: v2(157.54,94.19) 157.51,94.21 157,94.21 156.34,93.55 154.99,93.55 154.96,93.59 154.45,93.59 154.19,93.33 UC1.AA4
PCH_SPI_MISO_1: length 11.6
  TOP w0.102: RP39.2 173.66,102.04 174.26,101.44 v3(175.12,101.44) 175.67,101.44 176.71,102.48 176.71,104.32 175.44,105.59 v2(175.44,105.72)
  BOTTOM w0.102: U2302.2 174.49,106.23 175,105.72 v2(175.44,105.72)
PCH_SPI_MOSI: length 22.3
  TOP w0.102: RP39.8 171.31,101.54 170.08,100.31 168.82,100.31 168.16,99.65 160.79,99.65 159.77,98.63 v2(159.31,98.63)
  IN3 w0.135: v2(158.12,94.16) 158.12,94.21 157.79,94.54 157.79,96.83 159.21,98.25 159.21,98.53 v2(159.31,98.63)
  BOTTOM w0.076: v2(158.12,94.16) 156.91,92.95 156.48,92.95 156.44,92.99 156.02,92.99 156.02,92.99 155.77,92.99 UC1.AA2
PCH_SPI_MOSI_1: length 14.5
  TOP w0.102: v2(177.99,101.43) 177.1,101.43 v3(176.94,101.27) 176.61,100.94 174.27,100.94 173.68,101.54 RP39.1
  BOTTOM w0.102: v2(177.99,101.43) 177.17,102.26 177.17,107.5 178.43,108.77 U2302.5
PCH_SPI_WP1#: length 11.9
  TOP w0.102: RP39.3 174.41,102.54 R2334.2 175.18,102.15 175.81,102.15 176.26,102.61 176.26,104.2 v3(175.51,104.96) 175,105.46 175,105.91 v2(175.45,106.36)
  BOTTOM w0.102: v2(175.45,106.36) 175.18,106.36 174.05,107.5 172.13,107.5
PCH_SPI_WP#: length 31.4
  TOP w0.102: v2(157.2,98.43) 157.38,98.25 157.87,98.25 158.17,98.55 158.17,98.68 162.16,102.67 162.16,105.7 164.53,108.08 168.54,108.08 171.4,105.21 171.4,102.8 171.66,102.54 RP39.6
  IN3 w0.135: v2(153.09,94.41) 153.09,94.46 153.5,94.87 154.49,94.87 156.54,96.93 156.54,97.44 157.2,98.1 v2(157.2,98.43)
  BOTTOM w0.076: v2(153.09,94.41) 152.85,94.18 UC1.Y6
PCIE_PRX_LANTX_N3: length 44.6
  IN3 w0.076: 149.03,99.16 148.99,99.12 148.88,99.12 148.8,99.2 148.8,99.61 148.89,99.7 148.89,101.54 149.04,101.69 149.21,101.69 149.33,101.58 v2(149.33,101.34)
  IN3 w0.135: 149.03,99.16 150.5,99.16 150.8,98.86 153.52,98.86 155.55,100.89 159.1,100.89 162.79,97.2 162.79,93.09 169.66,86.22 169.66,83.17 170.04,82.8 170.36,82.8 v2(170.58,83.03)
  BOTTOM w0.076: v2(149.33,101.34) 149.46,101.34 UC1.G11
  BOTTOM w0.102: CL31.1 175.21,85.33 v4(174.48,85.33) 174.17,85.33 172.01,83.17 172,83.17 171.61,82.79 170.82,82.79 v2(170.58,83.03)
PCIE_PRX_LANTX_N3_C: length 2.4
  BOTTOM w0.102: UL1.18 178.16,85.93 178.06,85.83 177.96,85.83 177.52,85.4 176.85,85.4 CL31.2
PCIE_PRX_LANTX_P3: length 44.8
  IN3 w0.076: 149.03,98.92 149.02,98.92 148.99,98.96 148.81,98.96 148.64,99.13 148.64,99.68 148.73,99.77 148.73,101.61 148.97,101.86 149.13,101.86 v2(149.31,102.03)
  IN3 w0.135: v2(170.58,82.44) 170.47,82.56 169.94,82.56 169.42,83.07 169.42,86.12 162.55,92.99 162.55,97.1 159,100.65 155.66,100.65 153.62,98.62 150.7,98.62 150.4,98.92 149.03,98.92
  BOTTOM w0.076: v2(149.31,102.03) 149.62,101.72 UC1.F11
  BOTTOM w0.102: v2(170.58,82.44) 170.72,82.58 171.72,82.58 v4(171.97,82.82) 174.25,85.1 174.74,85.1 174.76,85.12 175.33,85.12 CL30.1
PCIE_PRX_LANTX_P3_C: length 2.4
  BOTTOM w0.102: UL1.17 178.21,85.53 178.13,85.61 178.05,85.61 177.61,85.18 176.86,85.18 CL30.2
PCIE_PRX_WLANTX_N4: length 92.4
  IN3 w0.076: v2(148.35,101.99) 148.2,101.84 147.96,101.84 147.75,101.62 147.75,99.64 147.67,99.56 147.67,99.36 147.64,99.33 147.64,99.31 147.59,99.26 147.59,99.25
  IN3 w0.135: 147.59,99.25 147.59,98.27 148.18,97.68 151.11,97.68 151.21,97.57 154.03,97.57 156.34,99.89 158.68,99.89 159.76,98.81 159.76,97.28 160.41,96.62 160.41,94.8 160.87,94.34 160.87,86.87 161.76,85.98 161.76,81.71 164.47,79.01 167.09,79.01 171.41,74.68 171.41,70.39 174.55,67.25 174.55,65.86 178.72,61.7 179.39,61.7 181.22,59.87 181.22,57.33 182.91,55.64 183.79,55.64 186.16,53.27 186.16,52.96 186.06,52.86 186.06,52.46 186.16,52.36 186.16,52.02 186.06,51.92 186.06,51.52 186.16,51.42 186.16,51.08 186.06,50.98 186.06,50.58 186.16,50.48 186.16,50.14 186.08,50.06 186.08,49.62 186.16,49.54 186.16,49.2 186.06,49.1 186.06,48.7 186.16,48.6 186.16,48.26 186.06,48.16 186.06,47.76 186.16,47.66 186.16,47.32 186.06,47.22 186.06,46.82 186.17,46.72 186.17,46.22 185.82,45.88 185.51,45.88 185.39,46 185.39,46.22 v2(185.63,46.46)
  BOTTOM w0.076: UC1.F13 148.63,101.72 v2(148.35,101.99)
  BOTTOM w0.102: v2(185.63,46.46) 185.44,46.27 185.44,45.91 185.08,45.56 183.74,45.56 182.85,44.67 182.85,43.6 182.98,43.47 JNGFF.35
PCIE_PRX_WLANTX_P4: length 92.5
  IN3 w0.076: v2(148.35,101.37) 148.35,101.51 148.19,101.67 148.03,101.67 147.91,101.55 147.91,99.57 147.84,99.5 147.84,99.25
  IN3 w0.135: v2(185.04,46.46) 185.14,46.35 185.14,45.9 185.41,45.64 185.92,45.64 186.41,46.12 186.41,47.32 186.4,47.32 186.4,53.37 183.89,55.88 183.01,55.88 181.46,57.43 181.46,59.97 179.49,61.94 178.82,61.94 174.8,65.96 174.8,67.35 171.66,70.49 171.66,74.78 167.19,79.25 164.57,79.25 162.01,81.81 162.01,86.08 161.12,86.97 161.12,94.44 160.66,94.9 160.66,96.72 160,97.38 160,98.91 158.78,100.13 156.24,100.13 153.93,97.82 151.31,97.82 151.21,97.92 148.29,97.92 147.84,98.37 147.84,99.25
  BOTTOM w0.076: UC1.G13 148.66,101.07 v2(148.35,101.37)
  BOTTOM w0.102: v2(185.04,46.46) 185.22,46.28 185.22,46 184.99,45.77 183.65,45.77 182.63,44.76 182.63,43.61 182.48,43.46 JNGFF.33
PCIE_PTX_LANRX_N3: length 82.1
  IN3 w0.135: v2(130.58,113.07) 130.37,113.07 130.18,113.26 130.18,113.44 130.28,113.54 130.28,113.87 130.17,113.99 130.17,114.22 130.29,114.34 130.45,114.34 130.72,114.61 130.72,114.77 130.96,115.01 131.14,115.01 131.39,115.25 131.39,115.44 131.63,115.68 131.78,115.68 132.05,115.95 132.05,116.1 132.29,116.35 132.45,116.35 132.72,116.61 132.72,116.77 133.08,117.13 146.52,117.13 147.03,117.64 150.28,117.64 151.16,118.52 160.52,118.52 163.26,115.78 167.54,115.78 174.69,108.63 174.69,102.79 176.89,100.59 176.89,98.77 179.85,95.81 179.85,89.9 180.06,89.69 180.06,85.58 180.15,85.49 180.15,83.79 v2(179.99,83.63)
  BOTTOM w0.102: CC32.1 130.3,112.62 130.3,112.9 130.47,113.07 v2(130.58,113.07) ; UL1.14 180.03,84.55 180.14,84.44 180.14,83.78 v2(179.99,83.63)
PCIE_PTX_LANRX_N3_C: length 14.2
  BOTTOM w0.076: UC1.C29 138.64,103.96 138.64,104.19 138.24,104.59 138.24,105.19 137.71,105.72 137.71,108.35 136.76,109.3 135.31,109.3 135.01,109.61 134.42,109.61 134.39,109.64
  BOTTOM w0.102: CC32.2 130.3,111.07 130.3,110.95 130.88,110.37 130.9,110.37 131.27,109.99 131.27,109.98 131.37,109.88 131.61,109.64 v4(133.43,109.64) 134.39,109.64
PCIE_PTX_LANRX_P3: length 82.1
  IN3 w0.135: v2(129.8,113.07) 129.92,113.19 129.92,114.32 132.98,117.38 146.42,117.38 146.93,117.88 150.18,117.88 151.06,118.76 160.62,118.76 163.36,116.02 167.64,116.02 174.93,108.73 174.93,102.89 177.13,100.69 177.13,98.87 180.09,95.91 180.09,90 180.3,89.79 180.3,85.68 180.4,85.59 180.4,83.81 v2(180.57,83.63)
  BOTTOM w0.102: CC40.1 130.04,112.62 130.04,112.83 v2(129.8,113.07) ; v2(180.57,83.63) 180.36,83.85 180.36,84.42 180.43,84.5 UL1.13
PCIE_PTX_LANRX_P3_C: length 14.2
  BOTTOM w0.076: 134.42,109.42 134.44,109.44 134.94,109.44 135.24,109.14 136.69,109.14 137.03,108.8 137.03,108.69 137.22,108.51 137.32,108.51 137.54,108.29 137.54,107.7 137.47,107.63 137.47,107.35 137.54,107.28 137.54,107.05 137.47,106.98 137.47,106.7 137.54,106.63 137.54,106.4 137.47,106.33 137.47,106.05 137.54,105.98 137.54,105.65 138.08,105.12 138.08,104.52 138.43,104.17 138.43,104.09 UC1.B30
  BOTTOM w0.102: CC40.2 130.08,111.03 130.08,110.86 v4(130.93,110.02) 131.52,109.42 133.13,109.42 133.15,109.4 133.68,109.4 133.71,109.42 134.42,109.42
PCIE_PTX_WLANRX_N4: length 12.5
  BOTTOM w0.076: 134.55,110.26 134.57,110.26 134.59,110.29 134.95,110.29 135.68,109.56 137.09,109.56 137.46,109.19 137.46,109.18 137.82,108.81 137.83,108.81 138.29,108.36 138.29,106.63 138.45,106.47 138.45,104.76 138.68,104.52 138.84,104.52 138.92,104.45 UC1.B29
  BOTTOM w0.102: CM1.1 131.94,111.17 131.94,110.85 v4(132.33,110.47) 132.53,110.26 134.55,110.26
PCIE_PTX_WLANRX_N4_C: length 134.8
  IN3 w0.135: v2(189.89,60.48) 189.74,60.64 189.74,60.78 189.89,60.94 190.43,60.94 190.99,61.5 190.99,62.99 190.76,63.22 190.76,65.91 184.47,72.2 181.46,72.2 180.25,73.41 180.03,73.41 178.58,74.86 178.58,78.73 178.46,78.85 178.46,82.98 178.3,83.14 178.3,92.45 178.49,92.64 178.49,95.14 174.55,99.08 174.55,100.83 173.33,102.05 173.33,107.92 166.81,114.44 162.68,114.44 160.33,116.79 151.99,116.79 150.55,115.34 138.93,115.34 138.48,115.8 133.93,115.8 132.65,114.52 132.65,114.33 132.3,113.98 132.3,113.66 v2(132.13,113.49)
  BOTTOM w0.102: v2(189.89,60.48) 189.69,60.28 189.69,59.87 192.21,57.36 192.21,49.63 191.66,49.09 191.18,49.09 190.53,48.44 190.53,46.89 189.94,46.3 187.13,46.3 186.38,47.06 183.25,47.06 181.33,45.14 181.33,43.71 181.48,43.57 JNGFF.29 ; CM1.2 131.97,112.74 131.97,112.9 132.26,113.19 132.26,113.36 v2(132.13,113.49)
PCIE_PTX_WLANRX_P4: length 12.5
  BOTTOM w0.076: 134.55,110.48 134.57,110.48 134.59,110.45 135.02,110.45 135.75,109.72 137.16,109.72 v4(137.76,109.12) 138.45,108.43 138.45,107.42 138.54,107.33 138.54,107.05 138.45,106.97 138.45,106.69 138.61,106.53 138.61,106.34 138.69,106.27 138.69,105.99 138.61,105.91 138.61,105.68 138.69,105.61 138.69,105.33 138.61,105.25 138.61,104.83 138.73,104.71 138.9,104.71 138.97,104.78 138.97,104.94 UC1.A29
  BOTTOM w0.102: 134.55,110.48 132.65,110.48 132.3,110.82 132.28,110.82 132.16,110.94 132.16,111.13 132.19,111.15 132.19,111.15 CM2.1
PCIE_PTX_WLANRX_P4_C: length 134.9
  IN3 w0.135: v2(189.31,60.48) 189.49,60.66 189.49,60.88 189.79,61.18 190.33,61.18 190.74,61.6 190.74,62.89 190.51,63.12 190.51,65.81 184.37,71.96 181.36,71.96 180.15,73.17 179.93,73.17 178.33,74.76 178.33,78.63 178.21,78.75 178.21,82.88 178.06,83.04 178.06,92.55 178.25,92.74 178.25,95.04 174.31,98.98 174.31,100.73 173.09,101.95 173.09,107.82 166.7,114.2 162.57,114.2 160.23,116.54 152.09,116.54 150.65,115.09 141.82,115.09 141.69,114.96 141.3,114.96 141.16,115.09 140.82,115.09 140.66,114.94 140.32,114.94 140.16,115.09 139.82,115.09 139.69,114.96 139.3,114.96 139.16,115.09 138.83,115.09 138.37,115.55 137.84,115.55 137.68,115.39 137.39,115.39 137.23,115.55 136.89,115.55 136.76,115.42 136.41,115.42 136.28,115.55 135.94,115.55 135.81,115.42 135.46,115.42 135.33,115.55 134.99,115.55 134.86,115.42 134.51,115.42 134.38,115.55 134.03,115.55 133.59,115.11 133.59,114.95 133.32,114.68 133.16,114.68 132.9,114.42 132.9,114.23 132.54,113.87 132.54,113.67 v2(132.72,113.49)
  BOTTOM w0.102: CM2.2 132.23,112.69 132.23,112.79 132.52,113.08 132.52,113.29 v2(132.72,113.49) ; v2(189.31,60.48) 189.48,60.31 189.48,59.78 191.99,57.27 191.99,49.72 191.57,49.3 191.09,49.3 190.31,48.53 190.31,46.98 189.85,46.52 187.22,46.52 186.47,47.27 183.16,47.27 181.12,45.23 181.12,43.63 180.97,43.48 180.98,43.48 JNGFF.27
PCIE_WAKE#: length 176
  TOP w0.102: RE275.1 RE274.1 104.86,13.54 106.89,13.54 v1(107.71,12.71) 108.77,11.66 v2(108.77,11.61)
  IN1 w0.114: v2(186.87,41.53) 186.87,39.78 186.67,39.58 186.67,34.33 184.47,32.13 184.47,31.09 181.37,27.99 180.47,27.99 177.06,24.58 176.07,24.58 173.85,22.36 173.85,17.7 170.43,14.27 170.43,14.16 168.15,11.88 168.15,11.73 167.62,11.2 166.48,11.2 165.26,9.98 v2(165.26,9.78)
  IN2 w0.127: v2(186.87,41.53) 187.42,42.08 187.42,55.89 191.81,60.29 191.81,62.38 190.77,63.42 190.77,66.98 190.21,67.54 190.21,72.24 183.66,78.79 183.66,83.66 182.68,84.64 176.2,84.64 175.21,85.63 174.78,85.63 173.09,87.33 v2(170.3,87.33)
  IN2 w0.135: v2(165.26,9.78) 165.66,9.37 165.66,7.98 165.32,7.63 144.48,7.63 142.84,6 117.72,6 112.87,10.85 109.53,10.85 v2(108.77,11.61)
  BOTTOM w0.102: R2532.1 169.9,87.72 v2(170.3,87.33) ; JNGFF.47 185.98,42.05 186.49,41.53 v2(186.87,41.53)
PCIE_WAKE#_R: length 5.7
  TOP w0.102: UE4.18 98.84,13.89 99.61,13.12 v1(101.05,13.12) 101.44,13.12 RE275.2 RE35.2
PECI_EC: length 172.1
  TOP w0.102: v2(126.5,27.49) 127.32,26.66 128.34,26.66 132.77,22.23 141.47,22.23 141.51,22.19 DE2.1 145.51,22.19 RE61.2
  IN3 w0.135: v2(126.5,27.49) 126.5,27.54 125.48,28.55 105.69,28.55 98.38,35.87 94.72,35.87 89.52,41.07 89.52,49.18 94.82,54.49 94.82,67.31 88.98,73.15 87.43,73.15 87.08,73.5 83.3,73.5 81.85,74.96 81.85,77.86 83.3,79.32 84.27,79.32 84.99,80.04 84.99,83.16 87.13,85.3 87.13,88.52 88.9,90.3 88.9,92.05 94.98,98.12 99.88,98.12 100.13,98.38 100.82,98.38 101.41,97.78 103.43,97.78 103.85,98.2 108.26,98.2 113.19,103.13 114.93,103.13 115.7,102.36 116.62,102.36 117.61,101.37 117.61,100.87 117.33,100.59 117.33,100.18 116.28,99.13 v2(116.28,96.83)
  BOTTOM w0.076: v2(116.28,96.83) 116.79,97.34 117.7,97.34 UC1.N62
PECI_EC_R: length 4.1
  TOP w0.102: v1(144.17,21.58) 145.72,21.58 146.27,22.13 RE61.1 146.36,21.68 146.28,21.6 146.28,21.14 146.55,20.87 UE5.A48
PEG_CRX_GTX_C_N0: length 9.1
  TOP w0.102: v2(68.59,80.41) 68.57,80.41 68.34,80.18 68.24,80.18 67.97,79.91 67.97,77.65 69.78,75.85 v4(70.63,75.85) 71.67,75.85 71.86,75.66 72.2,75.66 CV189.1
  BOTTOM w0.102: v2(68.59,80.41) 68.19,80.01 UV1.AB9
PEG_CRX_GTX_C_N1: length 11.1
  TOP w0.102: v2(66.95,79.59) 66.95,79.72 67.14,79.9 67.3,79.9 67.4,79.8 67.4,76.2 67.85,75.74 67.85,75.72 68.23,75.35 68.25,75.35 68.86,74.73 71,74.73 71.82,73.9 72.18,73.9 CV191.1
  BOTTOM w0.102: UV1.AC10 67.37,79.17 v2(66.95,79.59)
PEG_CRX_GTX_C_N2: length 12.6
  TOP w0.102: CV193.1 72.18,72.13 71.95,72.13 70.3,73.78 v4(69.05,73.78) 67.86,73.78 65.74,75.9 65.74,77.93 66.27,78.46 66.68,78.46 v2(66.96,78.74)
  BOTTOM w0.102: v2(66.96,78.74) 66.54,79.16 UV1.AC11
PEG_CRX_GTX_C_N3: length 15.9
  TOP w0.102: CV195.1 72.18,70.35 71.95,70.35 71.7,70.6 71.7,71.21 70.13,72.77 66.98,72.77 v4(65.16,74.6) 64.52,75.24 64.52,78.82 64.86,79.16 65.09,79.16 65.31,79.38 v2(65.31,79.56)
  BOTTOM w0.102: UV1.AB12 65.7,79.95 v2(65.31,79.56)
PEG_CRX_GTX_C_P0: length 9.1
  TOP w0.102: CV188.1 72.11,75.87 71.96,75.87 71.67,76.16 71.23,76.16 71.14,76.08 70.81,76.08 70.72,76.16 70.36,76.16 70.26,76.06 69.87,76.06 69.52,76.4 69.52,76.56 69.28,76.8 69.13,76.8 68.92,77.01 68.92,77.17 68.68,77.41 68.52,77.41 68.19,77.74 68.19,79.82 68.33,79.96 68.48,79.96 68.59,79.85 v2(68.59,79.59)
  BOTTOM w0.102: UV1.AC9 68.29,79.17 68.59,79.48 v2(68.59,79.59)
PEG_CRX_GTX_C_P1: length 11.1
  TOP w0.102: v2(66.95,80.41) 66.95,80.3 67.14,80.11 67.39,80.11 67.61,79.89 67.61,76.29 67.78,76.12 67.78,76.12 v4(68.2,75.69) 68.95,74.94 71.09,74.94 71.91,74.12 72.14,74.12 CV190.1
  BOTTOM w0.102: UV1.AB10 67.35,80.01 v2(66.95,80.41)
PEG_CRX_GTX_C_P2: length 12.6
  TOP w0.102: v2(66.93,77.97) 66.93,78.06 66.74,78.25 66.36,78.25 65.96,77.84 65.96,77.55 66.04,77.46 66.04,77.1 65.96,77.01 65.96,76.71 66.04,76.62 66.04,76.26 65.96,76.18 65.96,75.99 66.41,75.54 66.56,75.54 66.77,75.32 66.77,75.17 66.99,74.95 67.14,74.95 67.36,74.74 67.36,74.58 67.95,73.99 68.26,73.99 68.36,74.09 68.67,74.09 68.76,74.01 69.09,74.01 69.18,74.09 69.48,74.09 69.58,73.99 70.39,73.99 70.82,73.56 70.98,73.56 71.19,73.34 71.19,73.19 71.41,72.97 71.56,72.97 71.78,72.76 71.78,72.6 72.04,72.34 72.14,72.34 CV192.1
  BOTTOM w0.102: v2(66.93,77.97) 66.84,77.97 66.54,78.27 UV1.AD11
PEG_CRX_GTX_C_P3: length 15.8
  TOP w0.102: CV194.1 72.14,70.56 72.04,70.56 71.91,70.69 71.91,71.3 70.22,72.99 69.73,72.99 69.61,73.1 69.31,73.1 69.19,72.99 68.89,72.99 68.78,73.1 68.47,73.1 68.36,72.99 68.05,72.99 67.94,73.1 67.63,73.1 67.52,72.99 67.07,72.99 66.95,73.12 66.95,73.27 66.73,73.48 66.58,73.48 66.36,73.7 66.36,73.85 66.15,74.07 65.99,74.07 65.78,74.28 65.78,74.44 65.5,74.72 65.36,74.72 65.19,74.89 65.19,75.02 64.98,75.24 64.83,75.24 64.74,75.33 64.74,75.6 64.83,75.69 64.83,76.04 64.74,76.13 64.74,76.44 64.83,76.53 64.83,76.88 64.74,76.97 64.74,77.28 64.83,77.37 64.83,77.72 64.74,77.81 64.74,78.73 64.95,78.95 65.21,78.95 65.31,78.84 v2(65.31,78.77)
  BOTTOM w0.102: v2(65.31,78.77) 65.7,79.16 UV1.AC12
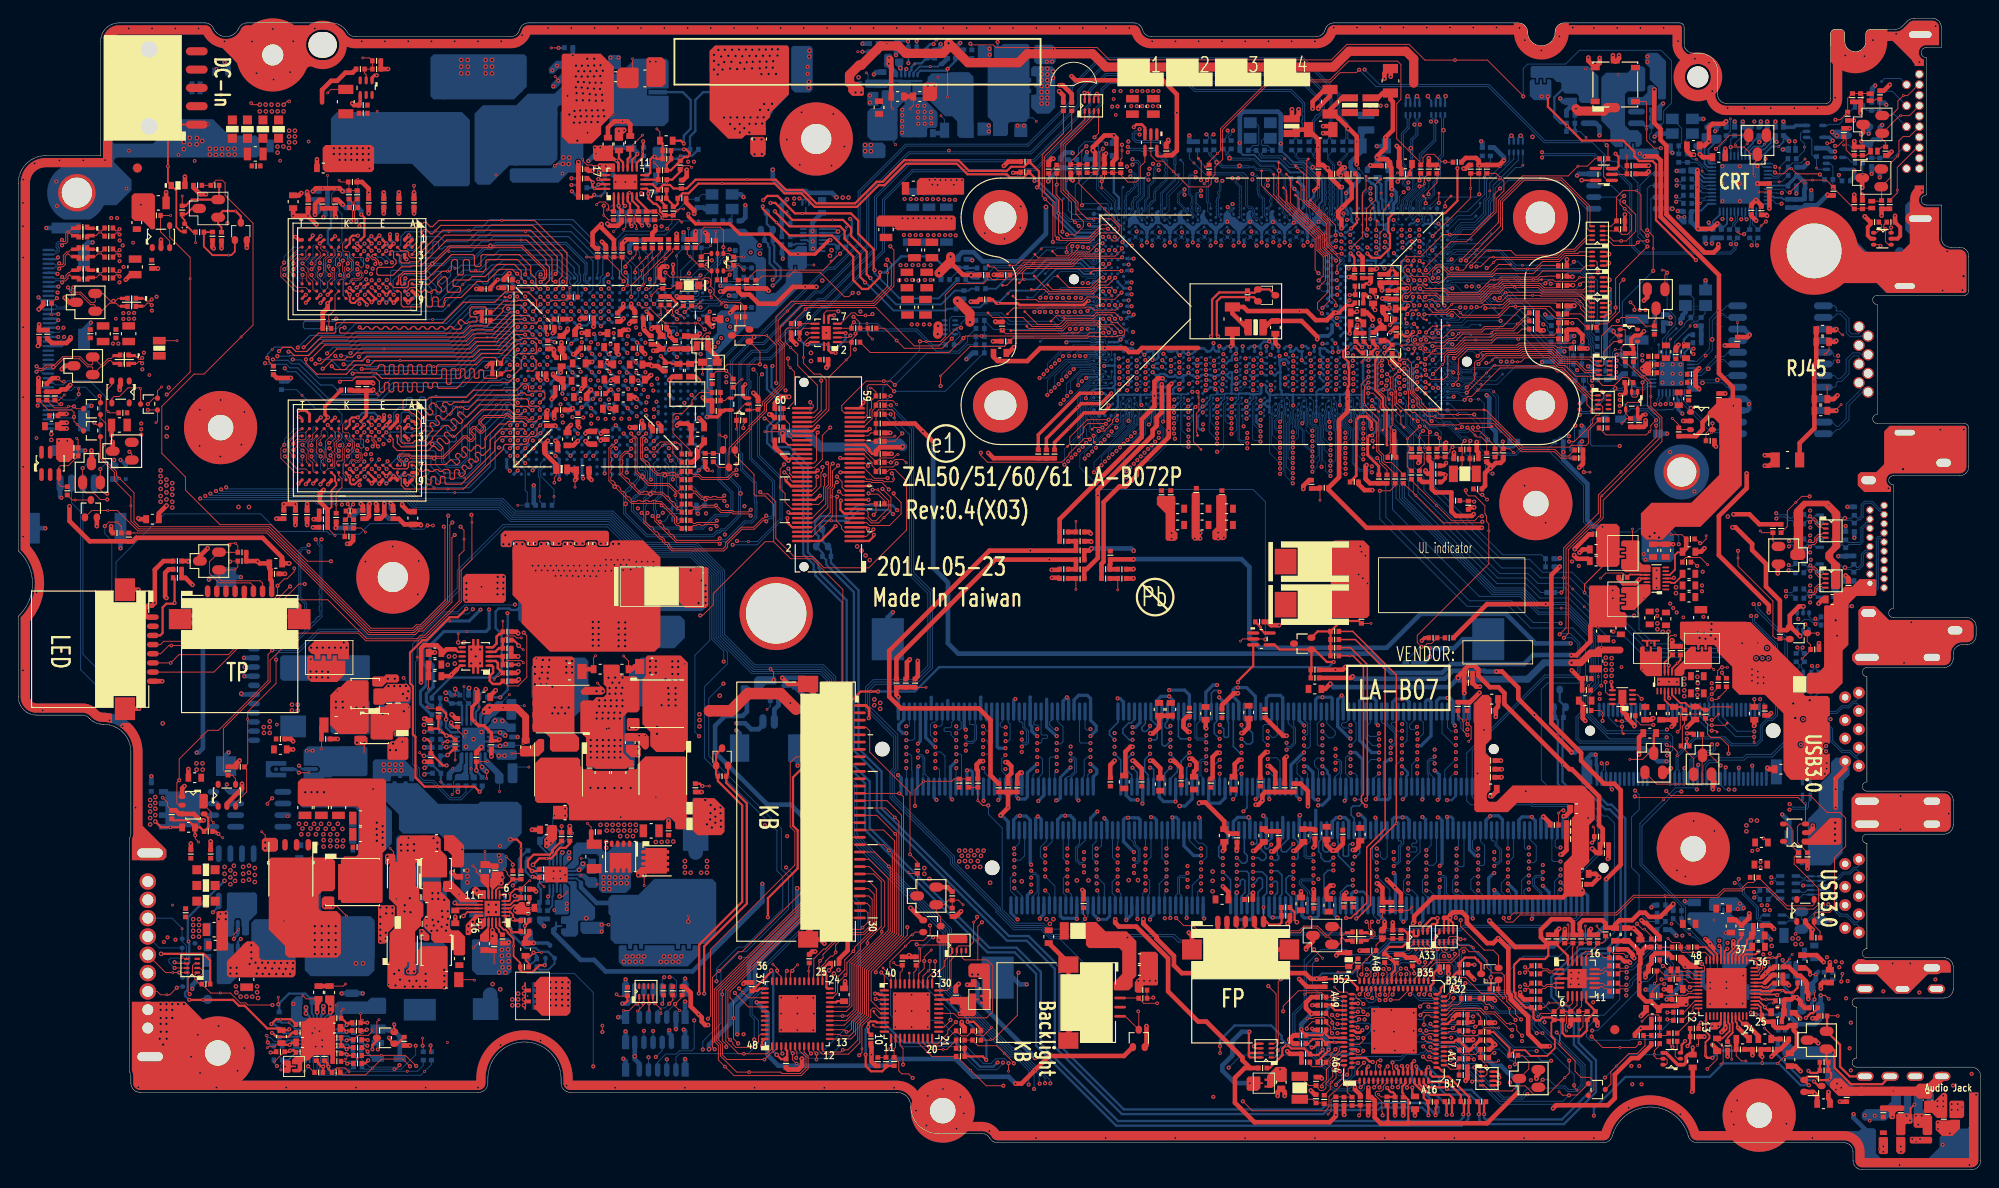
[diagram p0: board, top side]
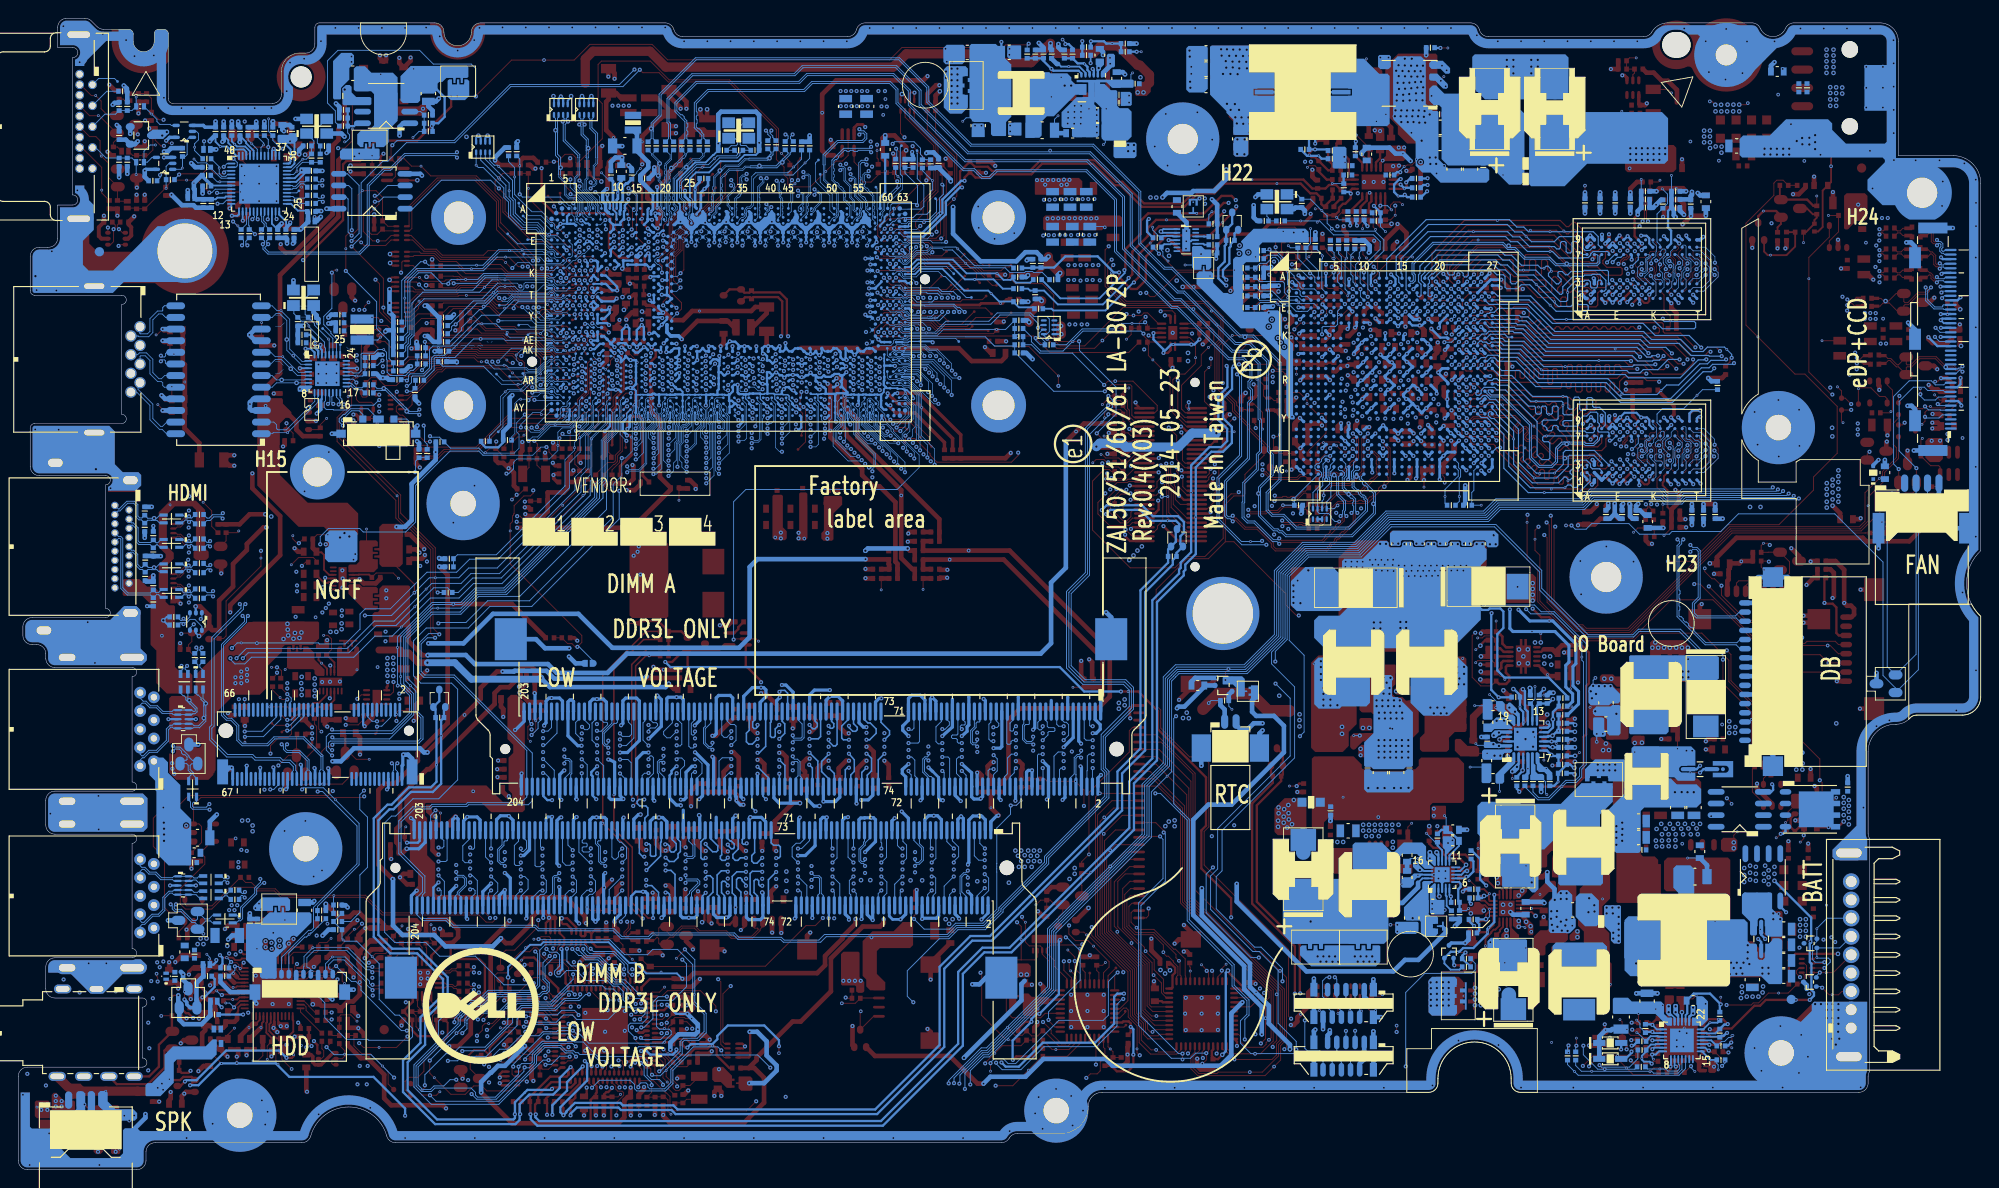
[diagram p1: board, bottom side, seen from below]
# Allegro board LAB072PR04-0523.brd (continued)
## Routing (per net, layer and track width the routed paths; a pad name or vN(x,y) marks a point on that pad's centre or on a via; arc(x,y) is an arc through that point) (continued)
PEG_CRX_GTX_N0: length 117.9
  TOP w0.102: CV189.2 73.77,75.72 74.29,75.72 74.62,75.39 77.55,75.39 78.16,76 78.35,76 v2(78.49,75.86)
  IN1 w0.089: 150.74,103.19 150.58,103.02 150.58,102.49 150.79,102.28 151.02,102.28 151.13,102.16 v2(151.13,102.03)
  IN1 w0.114: 150.74,103.19 150.74,103.19 150.74,103.97 150.57,104.14 150.22,104.14 148.47,105.89 148.47,109.36 149,109.89 149,111.79 143.59,117.2 127.31,117.2 125.48,115.37 117.36,115.37 112.09,110.1 109.06,110.1 107.93,108.97 106.79,108.97 103.03,105.21 103.02,105.21 95.1,105.21 91.7,101.81 89.3,101.81 89.09,102.01 88.34,102.01 87.44,101.11 87.44,100.07 84.71,97.34 84.71,93.61 78.92,87.82 78.92,81.56 78.69,81.33 78.69,78.27 79.13,77.83 79.13,76.35 78.88,76.09 78.69,76.09 78.49,75.9 v2(78.49,75.86)
  BOTTOM w0.076: UC1.F10 150.68,101.73 151.01,102.06 151.11,102.06 v2(151.13,102.03)
PEG_CRX_GTX_N1: length 124.2
  TOP w0.102: CV191.2 73.72,73.89 73.94,73.89 74.62,73.22 v4(75.07,73.22) 76.97,73.22 v2(77.15,73.03)
  IN1 w0.114: v2(152.02,101.98) 152.2,102.16 152.4,102.16 152.66,102.42 152.66,103.22 152.48,103.4 152.48,103.91 151.2,105.18 150.73,105.18 149.61,106.3 149.61,108.33 150.18,108.9 150.18,112.13 144.05,118.26 126.74,118.26 125.32,116.84 117.37,116.84 111.53,111 107.53,111 103.36,106.83 95.45,106.83 91.85,103.23 88.24,103.23 87.04,102.03 86.51,102.03 85.83,101.36 85.83,99.73 83.79,97.69 83.79,94.27 77.78,88.26 77.78,81.8 76.46,80.48 76.46,78.13 76.99,77.6 76.99,74.94 76.31,74.25 76.31,73.51 76.64,73.18 77,73.18 v2(77.15,73.03)
  BOTTOM w0.076: UC1.F8 151.78,101.72 152.02,101.96 v2(152.02,101.98)
PEG_CRX_GTX_N2: length 123.1
  TOP w0.102: CV193.2 73.75,72.14 74.52,72.14 74.73,72.35 76.17,72.35 76.74,71.78 77.93,71.78 78.08,71.63 79.82,71.63 v2(80.02,71.43)
  IN1 w0.114: v2(80.02,71.43) 80.02,71.43 80.24,71.66 80.42,71.66 80.65,71.88 80.65,72.47 78.82,74.3 78.82,74.86 80,76.03 80,79.87 79.86,80 79.86,81.32 79.79,81.39 79.79,85.23 80.1,85.54 80.1,86.59 79.75,86.94 79.75,87.44 85.42,93.11 85.42,97.03 88.22,99.82 88.22,100.6 88.51,100.89 91.78,100.89 95.23,104.35 103.24,104.35 106.95,108.05 108.72,108.05 109.93,109.26 112.8,109.26 118.02,114.48 125.84,114.48 127.72,116.36 142.9,116.36 146.97,112.3 146.97,108.49 146.97,108.49 146.97,105.52 149.43,103.06 149.43,102.49 149.89,102.03 149.89,101.57 150.56,100.9 151.05,100.9 v2(151.24,100.71)
  BOTTOM w0.076: v2(151.24,100.71) 150.94,100.42 UC1.H10
PEG_CRX_GTX_N3: length 132.3
  TOP w0.102: CV195.2 73.74,70.36 74.07,70.36 74.19,70.47 74.47,70.47 74.56,70.39 74.91,70.39 75,70.47 76.1,70.47 v2(76.29,70.28)
  IN1 w0.114: v2(153.06,102.67) 153.06,102.57 153.32,102.31 153.62,102.31 154,102.69 154,103.3 153.93,103.38 153.93,103.79 154,103.86 154,104.12 153.67,104.45 153.55,104.45 153.25,104.74 153.25,104.87 153.01,105.11 152.89,105.11 152.59,105.4 152.59,105.53 152.18,105.95 151.89,105.95 151.77,105.82 151.42,105.82 151.3,105.95 150.95,105.95 150.5,106.39 150.5,107.09 151.17,107.76 151.17,115.12 149.6,116.69 146.64,116.69 144.43,118.9 117.12,118.9 116.03,117.81 116.03,116.72 110.98,111.66 106,111.66 102.9,108.56 96.48,108.56 92.44,104.52 88.12,104.52 85.17,101.58 85.17,99.89 83.24,97.96 83.24,94.65 76.98,88.39 76.98,87.6 76.69,87.3 76.69,81.99 75.87,81.17 75.87,77.33 76.36,76.85 76.36,75.13 75.65,74.42 75.65,73.39 76.94,72.1 76.94,71.62 77.04,71.52 77.04,71.12 76.94,71.02 76.94,70.77 76.69,70.51 76.52,70.51 v2(76.29,70.28)
  BOTTOM w0.076: UC1.E6 152.79,102.37 153.06,102.64 v2(153.06,102.67)
PEG_CRX_GTX_P0: length 117.9
  TOP w0.102: CV188.2 73.73,75.94 74.38,75.94 74.71,75.61 77.46,75.61 78.07,76.21 78.24,76.21 v2(78.46,76.44)
  IN1 w0.089: 150.94,103.14 150.94,103.12 150.75,102.93 150.75,102.56 150.87,102.45 151.01,102.45 151.13,102.58 v2(151.13,102.67)
  IN1 w0.114: 150.94,103.14 150.94,104.05 150.65,104.35 150.3,104.35 148.68,105.97 148.68,109.27 149.2,109.8 149.2,111.87 143.67,117.4 127.22,117.4 125.4,115.57 117.28,115.57 112.01,110.3 108.97,110.3 107.84,109.17 106.7,109.17 102.94,105.41 102.94,105.41 95.02,105.41 91.62,102.01 89.38,102.01 89.18,102.21 88.26,102.21 87.24,101.2 87.24,100.15 84.51,97.42 84.51,93.7 78.72,87.9 78.72,81.65 78.49,81.42 78.49,78.18 78.93,77.74 78.93,76.43 78.79,76.3 78.61,76.3 v2(78.46,76.44)
  BOTTOM w0.076: UC1.E10 150.68,102.44 150.91,102.67 v2(151.13,102.67)
PEG_CRX_GTX_P1: length 124.3
  TOP w0.102: CV190.2 73.78,74.11 74.03,74.11 74.69,73.45 74.92,73.45 75.01,73.54 75.36,73.54 75.46,73.43 75.77,73.43 75.87,73.54 76.23,73.54 76.33,73.43 76.94,73.43 v2(77.13,73.62)
  IN1 w0.114: v2(152.05,102.64) 152.05,102.47 152.15,102.36 152.32,102.36 152.46,102.5 152.46,103.14 152.28,103.31 152.28,103.82 151.85,104.24 151.74,104.24 151.45,104.54 151.45,104.65 151.12,104.98 150.64,104.98 149.41,106.22 149.41,108.42 149.97,108.99 149.97,112.05 143.96,118.06 126.83,118.06 125.4,116.64 117.45,116.64 111.61,110.8 107.61,110.8 103.45,106.63 95.54,106.63 91.93,103.02 88.32,103.02 87.13,101.83 86.59,101.83 86.03,101.27 86.03,99.65 83.99,97.61 83.99,94.19 77.98,88.18 77.98,87.84 78.06,87.76 78.06,87.32 77.98,87.24 77.98,86.9 78.06,86.82 78.06,86.38 77.98,86.3 77.98,85.96 78.06,85.88 78.06,85.44 77.98,85.36 77.98,85.02 78.06,84.94 78.06,84.5 77.98,84.42 77.98,84.08 78.06,84 78.06,83.56 77.98,83.48 77.98,83.14 78.06,83.06 78.06,82.62 77.98,82.54 77.98,81.71 77.89,81.63 77.89,81.45 77.65,81.21 77.47,81.21 77.23,80.96 77.23,80.79 76.99,80.54 76.81,80.54 76.66,80.39 76.66,79.94 76.79,79.81 76.79,79.47 76.66,79.34 76.66,79 76.79,78.87 76.79,78.53 76.66,78.4 76.66,78.22 77.27,77.61 77.27,77.16 77.19,77.09 77.19,76.74 77.27,76.67 77.27,76.22 77.19,76.15 77.19,75.8 77.27,75.73 77.27,75.28 77.19,75.21 77.19,74.86 77.06,74.73 77.06,74.55 76.82,74.31 76.64,74.31 76.51,74.17 76.51,73.59 76.72,73.38 76.89,73.38 v2(77.13,73.62)
  BOTTOM w0.076: v2(152.05,102.64) 151.77,102.37 UC1.E8
PEG_CRX_GTX_P2: length 123.1
  TOP w0.102: v2(80.02,72.07) 80.02,72.06 79.81,71.85 78.17,71.85 78.02,72 76.83,72 76.26,72.57 74.64,72.57 74.43,72.36 73.75,72.36 CV192.2
  IN1 w0.114: v2(80.02,72.07) 80.23,71.86 80.34,71.86 80.45,71.97 80.45,72.38 78.62,74.21 78.62,74.94 79.79,76.12 79.79,79.78 79.66,79.92 79.66,81.23 79.58,81.31 79.58,85.31 79.89,85.63 79.89,86.51 79.55,86.85 79.55,87.52 85.22,93.19 85.22,97.11 88.02,99.91 88.02,100.68 88.43,101.09 91.69,101.09 95.15,104.55 103.15,104.55 106.86,108.26 108.64,108.26 109.85,109.46 112.72,109.46 117.94,114.68 125.75,114.68 127.63,116.56 142.99,116.56 147.17,112.38 147.17,108.7 147.17,105.61 149.64,103.14 149.64,102.58 150.09,102.12 150.09,101.65 150.65,101.1 150.94,101.1 151.16,101.32 v2(151.21,101.32)
  BOTTOM w0.076: UC1.G10 150.78,101.07 151.08,101.37 151.16,101.37 v2(151.21,101.32)
PEG_CRX_GTX_P3: length 132.3
  TOP w0.102: v2(76.32,70.9) 76.11,70.69 74.1,70.69 73.98,70.58 73.75,70.58 CV194.2
  IN1 w0.114: v2(76.32,70.9) 76.5,70.72 76.6,70.72 76.74,70.86 76.74,72.01 75.44,73.31 75.44,74.5 76.15,75.21 76.15,76.76 75.67,77.24 75.67,81.26 76.48,82.07 76.48,87.39 76.78,87.68 76.78,88.48 83.04,94.74 83.04,98.05 84.97,99.98 84.97,101.66 88.03,104.73 92.36,104.73 96.4,108.77 102.82,108.77 105.91,111.86 110.89,111.86 115.83,116.8 115.83,117.89 117.04,119.1 144.51,119.1 146.72,116.89 149.69,116.89 151.37,115.21 151.37,107.67 150.7,107 150.7,106.48 151.03,106.15 152.26,106.15 154.21,104.2 154.21,102.61 153.71,102.11 153.14,102.11 v2(153.06,102.03)
  BOTTOM w0.076: UC1.F6 152.67,101.72 152.99,102.03 v2(153.06,102.03)
PEG_CTX_GRX_N0: length 123.9
  TOP w0.102: v2(76.64,68.36) 76.48,68.52 71.87,68.52 69.54,70.85 69.54,71.15 v2(69.3,71.39)
  BOTTOM w0.102: v2(69.3,71.39) 69.5,71.59 69.5,71.9 69.4,72 69.4,73.04 70.15,73.79 70.15,75.69 UV1.AG7 ; v2(76.64,68.36) 76.87,68.59 77.36,68.59 79.4,70.63 80.13,70.63 80.7,71.2 80.7,72.9 80.62,72.98 80.62,75.03 79.14,76.52 79.14,78.13 78.8,78.48 78.8,81.82 78.95,81.97 78.95,88.01 80.22,89.28 81.82,89.28 87.44,94.91 88.11,94.91 93.76,100.55 93.76,106.19 97.66,110.09 110.98,110.09 117.16,116.27 117.16,117.82 118.84,119.5 128.18,119.5 129.04,118.65 140.26,118.65 142.45,116.46 142.45,115.65 142.01,115.22 141.86,115.22 141.65,115 141.65,114.85 141.36,114.56 141.36,114.31 141.25,114.21 141.25,113.9 141.36,113.79 141.36,113.49 141.25,113.38 141.25,113.08 141.36,112.97 141.36,112.61 CC18.2
PEG_CTX_GRX_N0_C: length 9.2
  BOTTOM w0.076: UC1.C23 143.06,104.07 142.98,104.14 142.98,104.37 143.06,104.44 143.06,104.59 143.25,104.78 143.25,105.31 143.17,105.39 143.17,105.64 143.25,105.72 143.25,105.94 143.18,106.01 143.18,106.29 143.25,106.35 143.25,106.58 143.18,106.64 143.18,106.92 143.25,106.99 143.25,107.21 143.18,107.28 143.18,107.56 143.25,107.62 143.25,107.85 143.18,107.91 143.18,108.19 143.25,108.26 143.25,108.48 143.18,108.55 143.18,108.83 143.25,108.89 143.25,108.96 143.17,109.04 143.09,109.04 142.71,109.42 142.71,109.5 142.64,109.56 142.6,109.56 142.6,109.56 142.57,109.56 142.38,109.75 142.38,109.79 142.38,109.79 142.38,109.85 142.22,110.01 142.15,110.01 142.15,110.01 142.12,110.01 141.93,110.2 141.93,110.24 141.93,110.3 141.77,110.46 141.7,110.46 141.7,110.46 141.67,110.46 141.48,110.65 141.48,110.69 141.48,110.75 141.39,110.84 141.39,110.99 CC18.1
PEG_CTX_GRX_N1: length 127.1
  TOP w0.102: v2(68.1,71.73) 68.34,71.49 68.34,70.65 70.12,68.87 70.27,68.87 70.36,68.79 70.36,68.63 70.7,68.29 70.85,68.29 70.94,68.2 70.94,68.05 71.42,67.58 77.07,67.58 77.5,68.01 77.5,68.38 79.08,69.95 80.42,69.95 81.41,70.94 81.58,70.94 v2(81.72,70.81)
  BOTTOM w0.102: UV1.AE7 69.37,77.08 69.37,76.63 69.3,76.56 69.3,75.74 69.54,75.5 69.54,74.51 68.29,73.27 68.29,71.92 v2(68.1,71.73) ; v2(81.72,70.81) 82,71.1 82.3,71.1 82.61,71.4 82.61,75.21 80.12,77.7 80.12,83.8 79.79,84.13 79.79,85.12 80.05,85.38 80.05,86.08 79.84,86.3 79.84,87.73 80.56,88.46 82.21,88.46 87.83,94.07 88.44,94.07 94.63,100.26 94.63,105.88 97.74,108.99 107.48,108.99 108.23,108.24 109.15,108.24 110.01,109.11 111.17,109.11 118.51,116.45 118.51,117.92 119.22,118.63 127.63,118.63 128.5,117.76 138.99,117.76 140.33,116.42 140.33,115.59 140.24,115.5 140.24,115.15 140.33,115.06 140.33,114.75 140.24,114.67 140.24,114.31 140.33,114.22 140.33,113.88 140.13,113.68 140,113.68 139.73,113.42 139.73,113.29 139.51,113.06 139.51,112.66 CC20.2
PEG_CTX_GRX_N1_C: length 9.2
  BOTTOM w0.076: CC20.1 139.48,111 139.48,110.7 139.93,110.24 140.67,110.24 v4(141.42,109.49) 142.69,108.22 142.69,105.45 142.41,105.17 142.41,104.89 142.75,104.55 142.75,104.5 UC1.B23
PEG_CTX_GRX_N2: length 128.5
  BOTTOM w0.102: UV1.AF9 67.93,76.77 67.85,76.68 67.85,76.51 67.97,76.38 68.3,76.38 68.51,76.18 68.51,76.13 68.53,76.1 68.53,75.83 68.51,75.81 68.51,75.58 68.46,75.53 68.46,74.61 68.12,74.27 67.97,74.27 67.75,74.05 67.75,73.9 67.54,73.68 67.39,73.68 67.17,73.47 67.17,73.32 67,73.14 67,71.95 68.98,69.97 74.81,69.97 76.21,71.36 77.45,71.36 78.07,71.99 78.07,73.97 76.66,75.38 76.66,88.09 79.52,90.95 v4(80.38,90.95) 80.99,90.95 88.4,98.35 89.22,98.35 91.98,101.11 91.98,106.75 97.02,111.79 110.34,111.79 115.14,116.59 115.14,118.16 118.2,121.22 140.33,121.22 144.17,117.38 144.17,115.09 145.04,114.22 145.04,114 145.03,113.98 145.03,113.44 145.04,113.42 145.04,112.61 CC22.2
PEG_CTX_GRX_N2_C: length 9
  BOTTOM w0.076: CC22.1 145.07,110.99 145.07,110.88 144.33,110.14 v4(144.33,109.9) 144.33,108.87 144.28,108.82 144.28,108.3 144.31,108.26 144.31,108.06 144.09,107.83 144.09,105.2 144.15,105.13 144.15,104.85 143.82,104.52 143.82,104.23 143.58,103.99 143.58,103.66 143.65,103.58 143.79,103.58 143.87,103.66 UC1.B21
PEG_CTX_GRX_N3: length 126.6
  BOTTOM w0.102: CC24.2 143.15,112.61 143.15,114.29 143.31,114.45 143.31,116.89 140.72,119.48 129.54,119.48 128.67,120.36 118.53,120.36 115.98,117.81 115.98,116.26 110.67,110.95 97.35,110.95 92.92,106.52 92.92,100.88 87.78,95.75 87.09,95.75 81.46,90.12 79.89,90.12 78.01,88.24 78.01,82.93 77.93,82.86 77.93,78.46 77.51,78.04 77.51,75.94 78.91,74.54 v4(78.91,73.85) 78.91,71.41 77.27,69.78 76.86,69.78 76.65,69.56 76.37,69.56 75.94,69.13 68.65,69.13 66.13,71.64 66.13,72.44 66.12,72.46 66.12,72.99 66.13,73 66.13,73.96 67.67,75.5 67.67,75.68 UV1.AG10
PEG_CTX_GRX_N3_C: length 7.4
  BOTTOM w0.076: CC24.1 143.02,111.14 143.02,110.35 143.58,109.79 143.58,105.04 143.59,105.03 143.59,104.42 UC1.B22
PEG_CTX_GRX_P0: length 123.9
  TOP w0.102: v2(69.93,71.39) 69.84,71.39 69.75,71.3 69.75,70.94 70.14,70.56 70.29,70.56 70.51,70.34 70.51,70.19 70.72,69.97 70.88,69.97 71.09,69.76 71.09,69.61 71.31,69.39 71.46,69.39 71.68,69.17 71.68,69.02 71.96,68.73 76.42,68.73 v2(76.64,68.95)
  BOTTOM w0.102: v2(76.64,68.95) 76.77,68.81 77.27,68.81 79.31,70.85 80.05,70.85 80.48,71.29 80.48,72.81 80.41,72.89 80.41,74.94 78.92,76.43 78.92,78.04 78.58,78.39 78.58,81.91 78.73,82.06 78.73,88.1 80.13,89.5 81.73,89.5 87.35,95.13 88.02,95.13 93.54,100.64 93.54,106.28 97.57,110.3 110.89,110.3 116.95,116.36 116.95,117.91 118.75,119.71 128.27,119.71 129.13,118.86 140.35,118.86 142.66,116.55 142.66,115.56 141.58,114.47 141.58,112.61 CC19.2 ; v2(69.93,71.39) 69.71,71.6 69.71,71.99 69.61,72.09 69.61,72.95 70.36,73.7 70.36,75.67 UV1.AG6
PEG_CTX_GRX_P0_C: length 9.3
  BOTTOM w0.076: CC19.1 141.55,110.99 141.55,110.91 142.8,109.67 142.8,109.66 v4(143.06,109.4) 143.41,109.04 143.41,104.71 143.22,104.52 143.22,104.02 143.34,103.9 143.34,103.33 UC1.C22
PEG_CTX_GRX_P1: length 127
  TOP w0.102: v2(68.74,71.73) 68.56,71.55 68.56,70.74 69.04,70.26 69.2,70.26 69.41,70.04 69.41,69.89 69.63,69.67 69.78,69.67 69.99,69.46 69.99,69.31 70.21,69.09 70.36,69.09 70.58,68.88 70.58,68.72 70.79,68.51 70.94,68.51 71.16,68.29 71.16,68.14 71.51,67.79 76.98,67.79 77.28,68.1 77.28,68.47 78.99,70.17 80.33,70.17 81.32,71.16 81.45,71.16 v2(81.72,71.42)
  BOTTOM w0.102: UV1.AF7 69.91,76.81 70.06,76.81 70.18,76.68 70.18,76.5 70.04,76.35 69.77,76.35 69.52,76.11 69.52,76.11 69.52,76.1 69.52,75.83 69.75,75.59 69.75,74.42 69.61,74.28 69.61,74.13 69.39,73.91 69.24,73.91 69.02,73.7 69.02,73.54 68.81,73.33 68.66,73.33 68.51,73.18 68.51,72.97 68.61,72.87 68.61,72.56 68.51,72.46 68.51,71.96 v2(68.74,71.73) ; v2(81.72,71.42) 81.83,71.31 82.21,71.31 82.39,71.49 82.39,75.12 79.9,77.61 79.9,83.71 79.57,84.04 79.57,85.21 79.84,85.47 79.84,85.99 79.62,86.21 79.62,87.82 80.47,88.67 82.12,88.67 87.74,94.29 88.35,94.29 94.42,100.35 94.42,105.97 97.65,109.21 107.57,109.21 108.32,108.46 109.06,108.46 109.92,109.32 111.08,109.32 118.29,116.54 118.29,118.01 119.13,118.85 127.72,118.85 128.59,117.97 139.08,117.97 140.54,116.51 140.54,113.79 139.72,112.97 139.72,112.56 CC21.2
PEG_CTX_GRX_P1_C: length 9.2
  BOTTOM w0.076: UC1.A23 142.95,104.88 142.83,104.75 142.78,104.75 142.57,104.96 142.57,105.1 142.85,105.38 142.85,105.92 142.93,106 142.93,106.23 142.85,106.3 142.85,106.53 142.93,106.61 142.93,106.84 142.85,106.91 142.85,108.29 141.77,109.37 141.77,109.44 141.37,109.84 141.3,109.84 140.74,110.4 140,110.4 139.64,110.76 139.64,110.99 CC21.1
PEG_CTX_GRX_P2: length 128.8
  BOTTOM w0.102: UV1.AE9 68.53,77.22 68.53,76.46 68.72,76.27 68.72,76.22 68.74,76.2 68.74,75.74 68.72,75.72 68.72,75.49 68.68,75.44 68.68,74.52 68.21,74.05 68.06,74.05 67.97,73.96 67.97,73.81 67.63,73.47 67.48,73.47 67.39,73.38 67.39,73.23 67.21,73.05 67.21,72.04 69.07,70.18 74.72,70.18 76.12,71.58 77.36,71.58 77.86,72.07 77.86,73.88 76.45,75.29 76.45,88.18 79.43,91.16 80.1,91.16 80.12,91.18 80.65,91.18 80.66,91.16 80.9,91.16 88.31,98.57 89.13,98.57 91.76,101.2 91.76,106.83 96.93,112 110.25,112 114.93,116.68 114.93,118.25 118.11,121.44 140.42,121.44 144.39,117.47 144.39,115.18 145.26,114.31 v4(145.26,113.71) 145.26,112.61 CC23.2
PEG_CTX_GRX_P2_C: length 9
  BOTTOM w0.076: CC23.1 145.24,110.99 145.24,110.82 144.54,110.12 144.54,109.6 144.49,109.55 v4(144.49,108.57) 144.49,108 144.25,107.76 144.25,105.26 144.31,105.2 144.31,104.78 143.98,104.45 143.98,104.07 144.15,103.91 144.15,103.3 UC1.C21
PEG_CTX_GRX_P3: length 126.7
  BOTTOM w0.102: UV1.AG9 68.18,75.97 67.89,75.68 67.89,75.41 67.55,75.06 67.55,74.91 67.33,74.7 67.18,74.7 66.96,74.48 66.96,74.33 66.75,74.11 66.59,74.11 66.35,73.87 v4(66.35,72.72) 66.35,71.73 68.74,69.34 75.85,69.34 76.28,69.78 76.56,69.78 76.78,69.99 77.18,69.99 78.69,71.5 78.69,73.57 78.68,73.59 78.68,74.12 78.69,74.13 78.69,74.45 77.3,75.85 77.3,78.13 77.72,78.55 77.72,82.95 77.79,83.02 77.79,88.33 79.8,90.34 81.37,90.34 87,95.96 87.69,95.96 92.7,100.97 92.7,106.61 97.26,111.17 110.58,111.17 115.76,116.35 115.76,117.9 118.44,120.58 128.76,120.58 129.63,119.7 140.81,119.7 143.53,116.98 143.53,114.37 143.36,114.2 143.36,112.6 CC25.2
PEG_CTX_GRX_P3_C: length 7.3
  BOTTOM w0.076: UC1.A21 143.74,105.11 143.74,105.66 143.82,105.73 143.82,105.96 143.74,106.04 143.74,106.27 143.82,106.34 143.82,106.57 143.74,106.65 143.74,106.87 143.82,106.95 143.82,107.18 143.74,107.26 143.74,107.48 143.82,107.56 143.82,107.79 143.74,107.87 143.74,108.09 143.82,108.17 143.82,108.4 143.74,108.48 143.74,108.7 143.82,108.78 143.82,109.01 143.74,109.08 143.74,109.31 143.82,109.39 143.82,109.62 143.74,109.69 143.74,109.86 143.18,110.42 143.18,110.85 CC25.1
PEX_TSTCLK_OUT: length 5.1
  BOTTOM w0.102: UV1.AF22 57.08,76.38 57.08,75.75 58.53,74.3 v1(58.53,73.52) 58.53,72.8 RV24.2
PEX_TSTCLK_OUT#: length 5.5
  BOTTOM w0.102: UV1.AE22 57.04,77.14 57.04,76.67 56.82,76.45 56.82,75.68 56.98,75.52 56.98,74.18 56.96,74.16 v1(56.96,73.52) 56.96,72.99 RV24.1
PHASE: length 13.9
  TOP w0.254: PU501.15 65.57,109.95 65.1,110.42
  IN1 w1.016: v2(58.35,120.07) 56.57,118.29 56.57,114.35 59.47,111.46 61.62,111.46
  vias: v1(63.12,110.97) v2(58.86,120.58) v2(63,111.64) v2(63.58,111.64)
PLT_RST#_R: length 3.6
  TOP w0.102: RM6.1 186.62,52.39 v1(185.8,51.57) 185.59,51.36 v2(185.02,51.36)
  BOTTOM w0.102: JNGFF.44 185.23,51.15 v2(185.02,51.36)
PLTRST_GPU#: length 3.5
  TOP w0.102: UV14.2 79.38,83.62 78.46,82.7 RC367.2 v1(78.46,80.89)
PM_APWROK_R: length 16.4
  TOP w0.102: v2(153.62,93.41) 156.15,93.41 156.46,93.72 156.81,93.72 157.43,93.09 161.76,93.09 162.94,94.27 v3(163.57,94.27) 167.33,94.27 168.14,93.46 RC55.2
  BOTTOM w0.076: UC1.AB5 153.5,93.3 v2(153.62,93.41)
POWER_SW#_MB: length 154.3
  TOP w0.102: v2(179.46,111.57) 178.73,111.57 177.91,112.4 v1(177.91,113.64) 177.91,116.57 177.8,116.67 SW1.2 ; RE33.2 146.31,7.01 146.33,7.04 CE21.1 146.61,6.06 146.49,5.93 v2(146.49,5.93)
  IN1 w0.114: v2(179.46,111.57) 179.43,111.55 179.43,104.94 186.45,97.93 186.45,92.74 185.39,91.69 185.39,82.41 184.68,81.69 184.68,80.77 186.86,78.59 186.86,75 188.64,73.22 188.64,47.32 191.52,44.45 191.52,35.02 191.05,34.56 191.05,33.07 189.49,31.51 188.65,31.51 183.37,26.23 183.37,25.52 182.28,24.43 180.82,24.43 178.2,21.81 178.2,18.63 176.5,16.94 176.5,15.07 171.22,9.79 169.89,9.79 165.32,5.22 147.2,5.22 v2(146.49,5.93)
POWER_SW_IN#: length 9.3
  TOP w0.102: v1(143.1,6.06) 143.43,6.39 143.43,7.61 143.77,7.95 RE31.2 144.81,7.95 CE49.1 RE33.1 145.2,8.45 v2(145.2,9.24) ; UE5.B67 146.38,11.67 v2(146.38,11.66)
  BOTTOM w0.102: v2(145.2,9.24) 145.2,9.49 146.03,10.32 146.03,11.31 v2(146.38,11.66)
PROC_OPI_RCOMP: length 11.5
  TOP w0.305: v2(147.86,80.9) 147.86,81.66 147.27,82.25 146.54,82.25 v1(146.18,81.89) 146.18,75.79 RC134.1
  BOTTOM w0.305: UC1.AY15 147.6,82.27 147.6,81.16 v2(147.86,80.9)
PS_ID: length 225.4
  TOP w0.102: v2(34.15,66.45) 31.6,66.45 27.6,70.45 22.04,70.45 18.27,74.22 18.27,75.66 15.68,78.25 15.68,83.37 19.21,86.9 20.29,86.9 v1(24.34,90.95) 25.65,92.26 25.65,103.37 22.6,106.42 22.6,107.75 22.28,108.07 21.59,108.07 PR5.2 PR4.1 ; v2(154.21,14.43) 154.47,14.17 UE5.B24
  IN3 w0.135: v2(154.21,14.43) 153.87,14.77 153.68,14.77 153.65,14.8 153.11,14.8 152.85,14.54 150.09,14.54 148.7,15.93 147.56,15.93 147.52,15.97 147.17,15.97 147.16,15.96 145.84,15.96 145.17,16.63 145.17,17.28 144.9,17.54 144.9,17.96 144.39,18.47 143.07,18.47 143,18.53 135.45,18.53 134.65,19.33 128.1,19.33 126.1,21.33 110.63,21.33 109.83,20.53 103.93,20.53 103.73,20.72 98.05,20.72 91.37,27.4 91.37,28.7 89.72,30.35 89.39,30.35 83.45,36.28 83.45,36.82 84.04,37.41 84.04,42.69 83.25,43.48 83.25,45.27 81.56,46.96 81.56,53.91 77.45,58.03 77.45,64.77 73.31,68.92 66.83,68.92 66,69.75 46.26,69.75 45.1,70.91 43.63,70.91 43.21,70.49 36.97,70.49 35.49,69 35.49,67.78 v2(34.15,66.45)
PWR_SRC_ON: length 7.5
  TOP w0.102: RX3.1 4.7,74.6 4.43,74.87 QX2.3 4.43,76.73 4.59,76.89 5.47,76.89 CX4.2 RX2.2 6.53,79.72 v1(6.38,79.87)
RED: length 9
  TOP w0.102: JCRT.1 207.61,118.5 206.42,117.31 v1(205.95,117.31) 205.35,116.72 205.35,115.88 204.6,115.13 DV5.3 203.38,115.38 CV54.1 202.94,116.93 202.77,116.76 LV16.2
RED_CRT: length 19.6
  TOP w0.102: LV16.1 202.28,117.54 CV51.1 RV32.1 199.86,117.02 CV62.1 199.03,114.67 v2(198.53,114.67)
  IN3 w0.135: v2(192.64,105.5) 192.04,106.1 192.04,108.17 198.53,114.66 v2(198.53,114.67)
  BOTTOM w0.102: v2(192.64,105.5) 192.04,105.5 191.65,105.89 UV6.11
REM_DIODE1_N: length 191.1
  TOP w0.254: v2(154.84,5.95) 154.84,6.75 154.94,6.85 CE58.1 ; v2(152.51,11.86) 152.23,11.58 152.23,11 152.3,10.93 UE5.B13 ; v2(131.08,91.02) 130.94,91.16 130.94,94.84 131.41,95.3 134.09,95.3 CE47.1 134.47,95.28 135.01,95.28 QE3.3
  IN3 w0.254: v2(95.56,71.6) 95.56,71.74 95.33,71.97 95.33,72.6 96.09,73.36 96.45,73.36 101.98,78.89 101.98,78.9 102.06,78.98 102.06,84.15 105.47,87.56 110.52,87.56 112.83,89.87 115.63,89.87 118.17,92.41 130.31,92.41 130.92,91.8 130.92,91.14 131.08,90.99 v2(131.08,91.02)
  BOTTOM w0.254: v2(152.51,11.86) 152.25,11.61 152.25,9.74 155.17,6.82 155.17,6.28 v2(154.84,5.95) 154.53,6.26 154.53,6.36 153.59,7.29 148.62,7.29 148.35,7.03 142.82,7.03 142.38,6.58 120.78,6.58 113.75,13.62 113.75,22.16 110.39,25.52 108.24,25.52 104.97,28.79 103.93,29.83 94.31,39.45 94.31,43.49 91.8,46 91.8,63.28 88.78,66.3 CE48.2 88.78,67.75 QE7.2 88.45,68.06 87.94,68.57 87.94,69.84 QE7.1 87.56,70.22 87.56,70.51 87.91,70.87 v1(88.84,70.87) 90.66,70.87 91.85,72.06 95.1,72.06 v2(95.56,71.6)
REM_DIODE1_P: length 187.6
  TOP w0.254: v2(130.3,91.02) 130.43,91.16 130.43,95.05 131.2,95.81 134.09,95.81 CE47.2 134.52,95.79 135.08,95.79 QE3.2 136.69,96.14 QE3.1 ; v2(154.07,5.93) 154.07,6.85 154.03,6.89 CE58.2 153.98,7.42 153.55,7.85 153.55,8.38 152.54,9.39 152.54,9.72 UE5.A13
  IN3 w0.254: v2(130.3,91.02) 130.3,90.99 130.41,91.09 130.41,91.57 130.03,91.95 120.83,91.95 120.83,91.95 118.37,91.95 115.78,89.36 113.04,89.36 110.73,87.05 105.68,87.05 102.57,83.94 102.57,78.77 102.49,78.69 102.49,78.68 96.66,72.85 96.3,72.85 95.84,72.39 95.84,72.18 95.98,72.04 v2(96.02,72.04)
  BOTTOM w0.254: v2(154.07,5.93) 154.07,6.1 153.38,6.78 148.83,6.78 148.56,6.52 143.03,6.52 142.59,6.07 120.57,6.07 113.24,13.41 113.24,21.95 110.18,25.01 108.03,25.01 104.61,28.43 93.81,39.23 93.81,43.28 91.29,45.79 91.29,63.07 88.27,66.09 88.27,66.58 CE48.1 87.86,67.36 QE7.3 87.18,68.06 87.45,68.34 87.43,68.36 87.43,69.19 87.05,69.57 87.05,70.72 87.7,71.38 90.45,71.38 91.64,72.57 95.49,72.57 v2(96.02,72.04)
REM_DIODE2_N: length 124.9
  TOP w0.254: CE70.1 156.05,7.24 v2(156.05,6) ; QE12.3 77.54,43.17 CE69.2 77.35,42.25 79.6,40 79.6,29.06 74.93,24.4 v2(74.93,19.23) ; v2(152.73,11.28) 152.8,11.22 UE5.B14
  IN3 w0.254: v2(156.05,6) 156.09,5.96 156.09,5.61 155.8,5.32 134.22,5.32 132.71,6.83 119.27,6.83 114.99,11.1 106.68,11.1 106.46,11.32 97.5,11.32 97.18,11 94.37,11 93.73,11.64 90.48,11.64 87.54,14.57 81.61,14.57 79.25,16.93 76.48,16.93 74.92,18.49 74.92,19.22 v2(74.93,19.23)
  BOTTOM w0.254: v2(156.05,6) 156.05,7.04 154.45,8.64 154.45,9.57 v2(152.73,11.28)
REM_DIODE2_P: length 126.6
  TOP w0.254: v2(156.63,6) 156.63,7.32 CE70.2 156.76,7.76 156.34,8.18 154.25,8.18 153.05,9.39 UE5.A14 ; QE12.1 76.24,45.38 QE12.2 76.24,43.17 CE69.1 76.43,42.45 79.09,39.79 79.09,29.27 74.39,24.57 74.39,19.29 v2(74.35,19.26)
  IN3 w0.254: v2(74.35,19.26) 74.41,19.19 74.41,18.28 76.27,16.42 79.04,16.42 81.4,14.06 87.33,14.06 90.27,11.13 93.52,11.13 94.15,10.49 97.4,10.49 97.71,10.81 106.25,10.81 106.47,10.59 114.78,10.59 119.06,6.32 132.5,6.32 134.01,4.82 156.01,4.82 156.6,5.4 156.6,5.96 v2(156.63,6)
REM_DIODE3_N: length 77.2
  TOP w0.254: v2(156.09,8.83) 155.92,8.99 154.02,8.99 153.55,9.47 UE5.A15 ; CE39.1 160.14,7.23 160.14,6.07 v2(160.15,6.06)
  BOTTOM w0.254: v2(156.09,8.83) 156.09,8.82 156.19,8.71 158.78,8.71 159.07,8.42 160.14,7.36 160.14,6.07 v2(160.15,6.06) 160.14,6.05 160.14,5.64 160.29,5.49 168.65,5.49 171.86,8.7 171.86,11.74 169.96,13.64 169.96,16.44 167.49,18.91 167.49,21.02 170.61,24.13 173.56,24.13 175.06,25.64 175.06,38.15 173.85,39.36 173.41,39.36 171.52,41.25 169.1,41.25 168.2,42.15 v1(168.2,47.4) 168.2,49.08 CE66.2 167.9,50.39 QE10.3
REM_DIODE3_P: length 81.8
  TOP w0.254: v2(154.06,11.2) 153.8,10.94 UE5.B16 ; v2(159.57,6.06) 159.63,6.12 159.63,7.23 CE39.2
  BOTTOM w0.254: v2(154.06,11.2) 155.25,10.01 155.25,8.92 155.96,8.21 158.57,8.21 158.71,8.06 159.63,7.15 159.63,6.12 v2(159.57,6.06) 159.63,6 159.63,5.43 160.08,4.98 168.86,4.98 172.37,8.49 172.37,11.95 170.46,13.86 170.46,16.65 168,19.12 168,20.8 170.82,23.62 173.77,23.62 175.57,25.43 175.57,38.36 174.07,39.87 173.62,39.87 171.73,41.76 169.32,41.76 168.71,42.36 v1(168.71,44.22) 168.71,49.28 CE66.1 168.81,50.28 QE10.2 168.41,51.18 QE10.1
REM_DIODE4_N: length 162.8
  TOP w0.254: v2(157.87,6.05) 157.94,6.12 157.94,7.1 CE60.1 157.6,8.13 156.16,9.57 154.2,9.57 UE5.A16
  IN3 w0.254: v2(82.38,87.78) 82.25,87.92 82.25,92.74 83.2,93.69 83.2,96.51 82.52,97.2 v2(82.41,97.2)
  BOTTOM w0.254: QE8.3 81.53,102.25 CE51.1 81.93,101.09 81.93,100.85 82.08,100.69 82.08,98.97 82.78,98.27 82.78,97.57 v2(82.41,97.2) ; v2(82.38,87.78) 82.4,87.77 82.4,87.74 82.3,87.64 82.3,85.47 83.29,84.48 83.29,81.88 82.33,80.92 82.33,79.58 82.99,78.92 84.26,78.92 86.26,76.92 v1(86.26,73.94) 86.26,67.45 87.41,66.3 87.41,65.72 87.58,65.55 87.58,65.11 90.5,62.19 90.5,44.92 93.02,42.4 93.02,37.32 106.09,24.25 109.07,24.25 111.71,21.6 111.71,13.75 120.15,5.31 157.48,5.31 157.9,5.73 157.9,6.01 v2(157.87,6.05)
REM_DIODE4_P: length 167
  TOP w0.254: v2(158.45,6.05) 158.45,7.38 CE60.2 158.51,7.93 156.29,10.16 154.5,10.16 154.3,10.37 UE5.B17
  IN3 w0.254: v2(81.61,87.73) 81.74,87.87 81.74,92.95 82.47,93.67 82.47,96.53 v2(82.42,96.57)
  BOTTOM w0.254: QE8.1 81.78,103.3 QE8.2 82.44,102.64 CE51.2 82.44,101.06 82.59,100.9 82.59,99.18 83.29,98.48 83.29,97.36 82.5,96.57 v2(82.42,96.57) ; v2(158.45,6.05) 158.41,6.01 158.41,5.52 157.69,4.8 119.94,4.8 111.21,13.54 111.21,21.39 108.86,23.74 105.88,23.74 92.51,37.11 92.51,42.19 90,44.71 90,61.98 87.07,64.9 87.07,65.33 86.9,65.51 86.9,66.09 85.75,67.24 v1(85.75,71.27) 85.75,76.71 84.05,78.41 82.78,78.41 81.82,79.37 81.82,81.13 82.78,82.1 82.78,84.27 81.79,85.26 81.79,87.55 v2(81.61,87.73)
RESET_OUT#: length 244.7
  TOP w0.102: UE5.B39 152.3,19.4 v2(152.05,19.15) ; RE56.2 152.33,21.92 152.51,21.74 v2(152.51,21.44) ; v2(156.7,78.92) 156.42,78.64 156.42,78.39 155.88,77.85 CC34.1 RC47.1 ; v2(177.99,100.83) 174.52,97.35 v2(174.52,94.16) 174.52,93.68 173.55,92.71 171.48,92.71 170.73,93.46 RC55.1 ; v2(146.5,120.13) 146.18,119.82 144.4,119.82 143.38,118.8 136.78,118.8 131.58,113.59 131.58,110.34 130.74,109.5 130.74,108.66 130.33,108.26 130.33,107.66 130.01,107.34 127.87,107.34 v1(126.18,109.03) 125.05,110.16 124.35,110.16 123.74,110.77 UC6.2
  IN1 w0.114: v2(174.52,94.16) 174.52,93.38 173.85,92.71 173.85,86.61 174.39,86.06 175.57,86.06 176.53,85.1 176.53,74.26 181.41,69.38 v2(181.41,68.31) 181.41,66.99 181.25,66.83 181.25,64.98 182.31,63.92 182.31,57.65 184.34,55.61 184.34,51.5 183.46,50.61 183.46,46.61 182.95,46.1 182.95,42.56 183.81,41.7 183.81,41.03 183.17,40.39 181.98,40.39 178.58,36.99 178.58,30.91 174.17,26.51 174.17,25.11 171.91,22.85 171.91,19.09 168.77,15.95 168.77,14.59 168.13,13.95 166.88,13.95 v2(165.89,12.96)
  IN3 w0.135: v2(152.51,21.44) 152.3,21.23 152.3,19.26 152.18,19.13 152.16,19.15 v2(152.05,19.15)
  BOTTOM w0.076: v2(156.7,78.92) 157.31,78.92 158.2,78.03 161.44,78.03
  BOTTOM w0.102: v2(146.5,120.13) 148.34,118.29 160.58,118.29 166.7,112.17 171.99,112.17 174.03,110.14 174.58,110.14 176.94,107.77 176.94,101.88 v2(177.99,100.83) ; 161.44,78.03 163.63,78.03 164.09,78.49 167.23,78.49 171,74.72 171,70.73 172.08,69.65 176.71,69.65 177.09,70.03 180.52,70.03 181.41,69.14 v2(181.41,68.31) ; v2(152.05,19.15) 152.41,19.15 153.06,18.49 153.17,18.49 153.2,18.47 154.65,18.47 155.72,17.4 157.84,17.4 158.15,17.71 159.36,17.71 160.39,16.68 160.39,16.07 163.49,12.98 165.87,12.98 v2(165.89,12.96)
RESET_OUT#_R: length 6.3
  TOP w0.102: RC47.2 155.26,79.01 v3(155.26,79.9) 155.26,80.05 v2(154.94,80.37)
  BOTTOM w0.076: UC1.AY7 152.13,82.24 152.13,81.4 153.34,80.19 154.77,80.19 v2(154.94,80.37)
RF_+1.35DGPU: length 3.8
  TOP w0.102: PR1005.1 v1(52.94,59.92)
  TOP w0.279: PU1000.5 51.85,57.06 52.25,57.46 52.25,58.22 52.52,58.49 52.67,58.49 PR1005.1
RING2: length 0.7
  TOP w0.254: v2(183.82,16.06) 183.57,15.8 RA1109.1
  vias: v2(185.07,15.67) v2(185.73,15.67)
RING2_L: length 22.7
  TOP w0.102: v2(199.18,20.55) 199.18,21.03 199.29,21.15 v3(199.29,21.4)
  IN2 w0.508: JHP.3 208.54,20.75 200.03,20.75 v2(199.88,20.6) 199.23,20.6 v2(199.18,20.55)
  IN3 w0.508: JHP.3 208.71,19.74 207.67,20.78 200.05,20.78 v2(199.88,20.6) 199.23,20.6 v2(199.18,20.55)
ROM_SCLK_GPU: length 5.4
  TOP w0.102: v2(66.11,96.18) v1(66.55,96.63) 66.55,97.2 65.89,97.86 65.89,99.27 65.97,99.34 RV122.1 RV128.2
  BOTTOM w0.102: UV1.C12 65.7,95.78 v2(66.11,96.18)
ROM_SI_GPU: length 6.2
  TOP w0.102: v1(62.07,99.67) RV59.2 RV123.1 65.66,98.2 65.66,97.5 66.13,97.03 v2(66.14,97.03)
  BOTTOM w0.102: UV1.B12 65.7,96.6 v2(66.14,97.03)
ROM_SO_GPU: length 5
  TOP w0.102: v2(66.32,98.62) 66.32,98.78 v1(67.12,99.58) 67.49,99.95 RV124.1 RV129.2
  BOTTOM w0.102: v2(66.32,98.62) 65.87,98.16 65.86,98.16 65.7,98.01 UV1.A12
RSVD_AL1: length 3.6
  BOTTOM w0.076: UC1.AL1 156.41,87.76 156.92,87.76 157.65,87.02 159.22,87.02 T136.1
RSVD_AM11: length 3.7
  TOP w0.102: T137.1 149.64,84.22 149.64,85.12 149.93,85.41 149.93,86.5 v2(149.54,86.89)
  BOTTOM w0.076: v2(149.54,86.89) 149.88,87.23 UC1.AM11
RSVD_AP7: length 1.1
  TOP w0.102: v2(152.8,86.57) 152.88,86.65 T139.1
  BOTTOM w0.076: v2(152.8,86.57) 152.48,86.26 UC1.AP7
RSVD_AT2: length 11.1
  BOTTOM w0.076: T128.1 161.45,81.1 161.45,84.29 160.7,85.04 159.27,85.04 158.48,85.83 158.02,85.83 157.52,85.33 156.52,85.33 156.36,85.49 155.84,85.49 155.49,85.15 UC1.AT2
RSVD_AU10: length 4.9
  TOP w0.102: v2(150.02,84.77) 150.03,84.77 150.12,84.68 150.12,83.17 151.06,82.23 151.06,81.42 T141.1
  BOTTOM w0.076: UC1.AU10 150.48,84.31 v2(150.02,84.77)
RSVD_AU15: length 5.7
  TOP w0.102: v2(147.48,84.81) 148.01,84.81 148.8,84.03 148.8,83.18 149.2,82.77 149.2,80.9 T142.1
  BOTTOM w0.076: v2(147.48,84.81) 147.46,84.79 147.46,84.33 UC1.AU15
RSVD_AU44: length 5.7
  TOP w0.102: v2(128.84,84.96) 128.99,84.81 128.99,82.88 128.71,82.6 128.71,80.57 128.83,80.44 T132.1
  BOTTOM w0.076: UC1.AU44 128.84,84.41 v2(128.84,84.96)
RSVD_AV44: length 5.6
  TOP w0.102: T134.1 128.4,79.48 128.4,83.1 v2(128.61,83.31)
  BOTTOM w0.076: v2(128.61,83.31) 128.96,83.66 UC1.AV44
RSVD_AW14: length 1.5
  TOP w0.102: T144.1 148.06,83.37 v2(147.88,83.37)
  BOTTOM w0.076: UC1.AW14 147.91,83.37 v2(147.88,83.37)
RSVD_AY14: length 4
  TOP w0.102: T145.1 148.04,79.53 v2(147.96,79.61)
  BOTTOM w0.076: UC1.AY14 148.27,82.21 148.65,81.83 148.65,80.29 v2(147.96,79.61)
RSVD_D15: length 2
  TOP w0.102: v2(147.71,103.83) 147.71,104.77 T135.1
  BOTTOM w0.076: UC1.D15 v2(147.71,103.83)
RSVD_F22: length 5.5
  TOP w0.102: T138.1 143.92,103.14 v2(143.92,102.06)
  BOTTOM w0.076: UC1.F22 143.65,101.93 143.75,102.03 143.89,102.03 v2(143.92,102.06)
RSVD_H22: length 11.9
  TOP w0.102: v2(143.95,100.8) 143.61,100.8 143.29,101.12 143.29,103.5 141.28,105.51 141.13,105.51 140.77,105.87 140.77,110.21 T140.1
  BOTTOM w0.076: v2(143.95,100.8) 143.56,100.41 UC1.H22
RSVD_J21: length 14.9
  TOP w0.102: T143.1 140.14,107.46 140.14,105.97 140.98,105.13 141.12,105.13 142.9,103.35 142.9,100.94 144.38,99.47 144.38,99.04 144.07,98.73 144.07,98.71 144.07,98.71 144.07,97.97 v2(144.07,97.97)
  BOTTOM w0.076: UC1.J21 144.05,100 144.4,99.65 144.58,99.65 144.86,99.37 144.86,99.16 144.56,98.86 144.43,98.86 144.1,98.53 144.1,98 v2(144.07,97.97)
RSVD_N23: length 14.9
  TOP w0.102: v2(142.05,97.91) 141.69,98.27 141.69,101.64 135.83,107.5 T129.1
  BOTTOM w0.076: v2(142.05,97.91) 142.4,97.56 UC1.N23
RSVD_R23: length 15.1
  TOP w0.102: v2(142.07,97.13) 142.57,97.63 142.57,99.72 141.88,100.42 141.88,101.79 137.16,106.5 137.16,108.68 T130.1
  BOTTOM w0.076: v2(142.07,97.13) 142.45,96.75 UC1.R23
RSVD_T23: length 17.2
  TOP w0.102: T131.1 137.7,106.33 142.09,101.93 142.09,100.47 142.77,99.8 142.77,99.79 142.8,99.75 142.8,97.11 v2(142.05,96.35)
  BOTTOM w0.076: v2(142.05,96.35) 142.46,95.94 UC1.T23
RSVD_U10: length 17.1
  TOP w0.102: T133.1 166.24,97.21 166.06,97.03 162.16,97.03 161.55,96.42 160.74,96.42 159.65,95.33 155.38,95.33 154.97,95.73 152.25,95.73 152.24,95.72 152.21,95.72 151.97,95.48 151.97,95.48 151.79,95.3 v2(151.67,95.3)
  BOTTOM w0.076: UC1.U10 151.1,95.79 151.59,95.3 v2(151.67,95.3)
RUN_ON: length 371.9
  TOP w0.102: v2(150.13,11.71) 150.13,10.99 150.3,10.82 UE5.B9 ; v2(186.85,45.45) 186.85,46.31 185.96,47.2 184.94,47.2 184.56,47.58 184.56,48.67 184.33,48.9 R2313.1 183.86,49.76 182.53,49.76 182.05,49.28 R2318.1 182.05,48.66 181.8,48.42 181.8,46.43 R16.1 183.05,44.88 Q8.2 ; RPE10.1 159.55,10.71 v2(159.08,11.18) ; v2(104.02,122.98) 104.14,122.85 106.53,122.85 106.82,122.56 117.86,122.56 119.21,121.21 143.46,121.21 145.15,122.9 151.96,122.9 153.67,121.19 v3(156.96,121.19) 160.5,121.19 164.42,117.27 v2(164.42,117.22)
  IN1 w0.114: v2(186.85,45.45) 187.27,45.03 187.27,43.67 188.22,42.71 188.22,40.44 187.15,39.38 187.15,34.11 184.95,31.92 184.95,30.89 181.57,27.51 180.7,27.51 177.28,24.09 176.27,24.09 174.33,22.16 174.33,15.97 170.69,12.33 169.28,12.33 168.97,12.02 168.97,11.66 165.56,8.26 v2(164.88,8.26) ; 73.92,76.37 73.92,77.04 74.81,77.93 74.81,82.53 75.39,83.11 75.39,90.25 75.8,90.65 75.8,91.26 76.57,92.04 76.57,94.02 75.14,95.46 75.14,96.24 76.08,97.19 77.95,97.19 78.24,97.47 78.24,99.29 81.79,102.85 82.94,102.85 90.73,110.64 90.73,119.46 91.47,120.2 94.47,120.2 95.08,119.59 98.78,119.59 100.96,121.76 102.8,121.76 v2(104.02,122.98) ; 73.92,76.37 73.92,76.37 73.92,76.37 ; 73.92,76.37 73.92,71.96 73.86,71.9 73.86,71.82 73.83,71.8 73.83,70.41 75.71,68.53 75.71,60.56 75.13,59.98 75.13,51.28 75.71,50.7 75.71,47.82 76.86,46.67 81.56,41.96 v2(81.56,37.62)
  IN3 w0.135: v2(150.13,11.71) 149.92,11.71 149.13,12.5 145.58,12.5 145.11,12.96 145.11,13.65 144.29,14.48 142.81,14.48 142.47,14.82 139.96,14.82 138.16,16.61 128.25,16.61 126.83,18.04 120.39,18.04 119.27,19.16 111.63,19.16 111.03,18.56 97.35,18.56 95.31,20.6 95.31,21.54 89.29,27.56 89.29,28.6 81.56,36.32 v2(81.56,37.62)
  BOTTOM w0.102: v2(104.02,122.98) 104.18,122.82 PR300.2 ; v2(150.13,11.71) 150.34,11.91 150.98,11.91 151.64,12.58 153.04,12.58 153.24,12.78 153.52,12.78 153.73,12.98 154.54,12.98 155.12,13.57 156.97,13.57 158.02,12.52 158.02,11.67 158.56,11.13 159.03,11.13 v2(159.08,11.18) 159.16,11.1 159.16,10.71 162.18,7.7 164.32,7.7 v2(164.88,8.26) ; PR402.1 179.76,114.4 179.76,115.64 180.62,116.5 180.62,121.11 179.48,122.25 170.55,122.25 169.05,120.75 164.91,120.75 164.42,120.26 v2(164.42,117.22)
RUNPWROK: length 186
  TOP w0.102: UC4.10 85.78,91.9 85.35,91.47 CC29.1 ; UE5.B26 153.85,15.17 v2(153.83,15.19) ; Q10.1 165.03,11 165.03,11.81 164.34,12.5 RE67.2 163.55,12.22 163.55,11.56 v2(163.5,11.51)
  TOP w0.254: v2(85.35,90.68) CC29.1 ; v2(86.24,90.12) 86.51,90.4 UC4.13 ; UC4.1 88.52,89.49 88.8,89.21 v2(89.29,89.21) ; v2(90.38,91.37) 90.35,91.4 UC4.4
  IN1 w0.114: v2(90.38,91.37) 90.38,89.21 93.76,85.83 93.76,73.33 90.55,70.13 90.55,58.47 82.83,50.75 82.83,37.1 80.6,34.87 80.6,30.88 83.58,27.89 95.79,27.89 96.58,27.1 98.58,27.1 99.45,26.24 100.04,26.24 102.81,23.47 130.62,23.47 131.38,22.71 141.63,22.71 v2(141.86,22.94)
  BOTTOM w0.102: v2(141.86,22.94) 141.85,22.94 141.39,22.48 141.39,19.99 142.89,18.49 144.52,18.49 144.68,18.33 144.68,15.67 144.35,15.34 143.29,15.34 143.07,15.13 143.07,14.77 144.02,13.82 152.07,13.82 153.06,14.81 153.39,14.81 153.78,15.19 v2(153.83,15.19) 153.83,15.19 155.48,15.19 155.61,15.06 157.08,15.06 157.51,14.63 159.49,14.63 160.97,13.16 161.8,13.16 163.07,11.89 163.28,11.89 163.5,11.66 v2(163.5,11.51)
  BOTTOM w0.254: v2(85.35,90.68) 85.91,90.12 v2(86.24,90.12) v1(88.22,90.12) 88.45,90.12 89.29,89.28 ; 89.29,89.28 89.29,89.59 90.38,90.68 v2(90.38,91.37) ; 89.29,89.28 v2(89.29,89.21)
SATA_ACT#: length 19
  TOP w0.102: v2(161.28,95.17) 161.65,94.8 162.03,94.8 162.73,95.49 v1(165.45,95.49) 166.26,95.49 166.35,95.4 170.7,95.4 171.25,94.85 171.25,94.6 171.7,94.16 RP37.2
  BOTTOM w0.076: v2(161.28,95.17) 161.27,95.17 161.27,95.18 160.85,95.18 160.47,95.56 156.51,95.56 156.26,95.81 156.04,95.81 155.85,95.62 155.85,95.46 155.61,95.23 155.09,95.23 UC1.U3
SATA_IREF: length 3.5
  BOTTOM w0.254: UC1.A12 149.02,105.92
  BOTTOM w0.305: RC126.1 148.52,107.98 148.9,107.6 v1(148.9,106.66) 148.9,106.04 149.02,105.92
SATA_PRX_DTX_N0: length 9.1
  TOP w0.089: CS31.2 175.06,20.07 175.57,20.07 v2(175.7,20.2)
  BOTTOM w0.089: v2(175.7,20.2) 175.89,20.2 176.04,20.34 176.04,20.59 178.68,23.23 v1(180.09,23.23) 180.84,22.48 JHDD.9
SATA_PRX_DTX_N0_C: length 128.1
  TOP w0.102: CS33.1 164.98,20.02 164.82,20.02 v2(164.62,20.22)
  IN3 w0.135: v2(164.62,20.22) 164.82,20.02 164.98,20.02 165.08,20.12 165.46,20.12 165.56,20.02 165.77,20.02 165.91,20.16 165.91,20.37 166.2,20.65 166.4,20.65 166.69,20.94 166.69,21.14 166.97,21.43 167.18,21.43 167.47,21.72 167.47,21.92 167.75,22.21 167.96,22.21 168.24,22.49 168.24,22.7 168.53,22.99 168.74,22.99 168.76,23.01 168.77,23.01 168.92,23.16 169.28,23.16 169.42,23.29 169.87,23.29 170,23.16 170.41,23.16 170.54,23.29 170.99,23.29 171.12,23.16 171.46,23.16 174.03,25.73 174.03,26.37 178.56,30.9 185.39,30.9 185.55,30.74 185.55,30.73 187.76,30.73 188.76,31.72 188.76,35.3 190.07,36.62 191.76,36.62 194.17,39.02 194.17,43.29 190.1,47.35 190.1,49.46 187.36,52.2 187.36,54.41 185.37,56.4 183.24,56.4 181.98,57.66 181.98,60.93 180.38,62.54 178.98,62.54 177.8,63.72 177.8,64.44 175.31,66.93 175.31,67.57 173.56,69.32 173.56,70.33 172.18,71.72 172.18,75.9 171.26,76.81 171.26,83.64 170.25,84.66 170.25,86.37 163.67,92.95 163.67,97.07 159.31,101.42 154.87,101.42 154.66,101.22 154.6,101.22 153.72,100.34 153.23,100.34 v2(153.09,100.2)
  BOTTOM w0.076: v2(153.09,100.2) 153.51,99.78 UC1.J5
SATA_PRX_DTX_N0_R: length 1.8
  TOP w0.089: US2.12 172.85,20.38 172.9,20.32 173.15,20.32 173.34,20.13 173.6,20.13 CS31.1
SATA_PRX_DTX_N0_RC: length 2.4
  TOP w0.102: US2.4 167.78,20.38 167.62,20.22 166.95,20.22 166.73,20 166.62,20 CS33.2
SATA_PRX_DTX_P0: length 9
  TOP w0.089: v2(175.7,19.61) 175.56,19.75 175.02,19.75 CS34.2
  BOTTOM w0.089: v2(175.7,19.61) 175.96,19.88 176.03,19.88 176.36,20.21 176.36,20.46 178.81,22.91 179.96,22.91 180.5,22.37 180.5,22.02 180.37,21.9 180.2,21.9 180.05,21.74 JHDD.10
SATA_PRX_DTX_P0_C: length 128.1
  TOP w0.102: v2(164.62,19.64) 164.79,19.8 165.02,19.8 CS35.1
  IN3 w0.135: v2(153.09,100.8) 153.31,100.58 153.62,100.58 154.5,101.46 154.56,101.46 154.77,101.67 159.41,101.67 163.91,97.17 163.91,93.05 170.49,86.47 170.49,84.76 171.51,83.75 171.51,76.92 172.42,76 172.42,71.82 173.81,70.43 173.81,69.42 175.56,67.67 175.56,67.03 178.05,64.54 178.05,63.82 179.08,62.78 180.48,62.78 182.22,61.03 182.22,57.76 183.34,56.64 185.48,56.64 187.6,54.52 187.6,52.31 190.35,49.56 190.35,47.45 194.41,43.39 194.41,38.92 191.87,36.38 190.17,36.38 189,35.2 189,31.62 187.86,30.48 185.45,30.48 185.31,30.63 185.31,30.64 185.29,30.66 178.66,30.66 174.27,26.27 174.27,25.63 171.56,22.92 169.02,22.92 168.49,22.39 168.49,22.39 165.87,19.77 164.76,19.77 v2(164.62,19.64)
  BOTTOM w0.076: v2(153.09,100.8) 153.16,100.8 UC1.H5
SATA_PRX_DTX_P0_R: length 1.9
  TOP w0.089: CS34.1 173.51,19.81 173.21,19.81 173.02,20 172.86,20 172.74,19.88 US2.11
SATA_PRX_DTX_P0_RC: length 2.4
  TOP w0.102: CS35.2 166.55,19.79 166.82,19.79 167.03,20 167.64,20 167.77,19.88 US2.5
SATA_PTX_DRX_N0: length 11.6
  TOP w0.089: v2(175.72,21.57) 175.6,21.69 175.05,21.69 CS32.2
  BOTTOM w0.089: v2(175.72,21.57) 175.99,21.83 176.39,21.83 178.49,23.93 182.09,23.93 182.87,23.15 182.87,22.15 182.78,22.06 182.65,22.06 182.44,21.85 JHDD.7
SATA_PTX_DRX_N0_C: length 150.9
  TOP w0.102: CS36.1 165.02,21.71 164.79,21.71 v2(164.62,21.54)
  IN3 w0.135: v2(164.62,21.54) 164.8,21.72 165.05,21.72 165.23,21.54 165.23,21.2 165.03,21 163.94,21 163.36,20.42 163.36,19.03 163.71,18.68 166.17,18.68 169.47,21.98 171.71,21.98 175.06,25.33 175.06,25.89 178.97,29.79 184.68,29.79 184.75,29.72 188.32,29.72 189.82,31.22 189.82,33.68 191.7,35.56 192.25,35.56 195.18,38.49 195.18,44.83 193.5,46.51 193.5,48.56 192.37,49.68 192.37,50.69 190.84,52.22 189.41,52.22 188.55,53.08 188.55,54.66 185.78,57.43 183.64,57.43 183,58.07 183,63.91 180.76,66.16 177.58,66.16 176.5,67.23 176.5,67.81 174.57,69.74 174.57,70.76 173.18,72.15 173.18,76.31 172.26,77.23 172.26,84.07 171.31,85.02 171.31,87.18 171,87.49 171,88.7 168.14,91.56 168.14,92.75 168.13,92.76 168.13,93.16 166.93,94.36 166.53,94.36 164.69,96.2 164.69,96.3 164.69,96.31 164.69,97.51 158.16,104.04 158.16,106.66 155.99,108.83 150.55,108.83 148.76,107.04 147.88,107.04 v2(147.73,107.19)
  BOTTOM w0.076: v2(147.73,107.19) 147.51,106.97 147.28,106.97 146.74,106.43 146.74,104.74 146.87,104.62 UC1.B15
SATA_PTX_DRX_N0_R: length 2.4
  TOP w0.102: CS36.2 166.58,21.72 167.01,21.72 167.24,21.49 167.66,21.49 167.77,21.38 167.77,21.38 US2.2
SATA_PTX_DRX_N0_RC: length 1.9
  TOP w0.089: US2.14 172.85,21.38 172.93,21.45 173.16,21.45 173.41,21.71 173.52,21.71 CS32.1
SATA_PTX_DRX_P0: length 11.8
  TOP w0.089: v2(175.72,22.15) 175.58,22.01 175.03,22.01 CS30.2
  BOTTOM w0.089: v2(175.72,22.15) 176.26,22.15 178.36,24.25 v1(182.22,24.25) 183.19,23.28 183.19,22.21 183.24,22.16 JHDD.6
SATA_PTX_DRX_P0_C: length 150.9
  TOP w0.102: CS37.1 164.98,21.92 164.82,21.92 v2(164.62,22.13)
  IN3 w0.135: v2(147.73,106.61) 147.92,106.79 148.86,106.79 150.65,108.59 155.88,108.59 157.91,106.56 157.91,103.94 164.44,97.41 164.44,96.2 164.45,96.2 164.45,96.1 166.42,94.12 166.83,94.12 167.89,93.06 167.89,92.66 167.9,92.65 167.9,91.46 170.75,88.6 170.75,87.39 171.07,87.07 171.07,84.91 172.02,83.97 172.02,77.13 172.94,76.21 172.94,72.05 174.32,70.66 174.32,69.64 176.25,67.71 176.25,67.13 177.47,65.91 180.66,65.91 182.76,63.81 182.76,57.97 183.53,57.19 185.68,57.19 188.3,54.56 188.3,52.98 189.3,51.98 190.74,51.98 192.13,50.58 192.13,49.58 193.26,48.46 193.26,46.41 194.93,44.73 194.93,38.59 192.15,35.81 191.6,35.81 189.57,33.78 189.57,31.32 188.22,29.96 184.85,29.96 184.78,30.04 178.87,30.04 174.82,25.99 174.82,25.43 171.61,22.22 170.32,22.22 170.17,22.38 169.76,22.38 169.6,22.22 169.37,22.22 169.12,21.97 168.91,21.97 168.63,21.69 168.63,21.48 168.34,21.19 168.14,21.19 167.85,20.91 167.85,20.7 167.56,20.42 167.36,20.42 167.07,20.13 167.07,19.92 166.79,19.64 166.58,19.64 166.29,19.35 166.29,19.15 166.07,18.92 165.8,18.92 165.69,19.03 165.25,19.03 165.14,18.92 164.8,18.92 164.67,19.05 164.41,19.05 164.27,18.92 163.81,18.92 163.61,19.13 163.61,20.32 164.04,20.75 165.13,20.75 165.48,21.1 165.48,21.64 165.15,21.96 164.78,21.96 v2(164.62,22.13)
  BOTTOM w0.076: v2(147.73,106.61) 147.53,106.81 147.35,106.81 146.91,106.36 146.91,104.81 147.06,104.65 147.22,104.65 147.27,104.7 147.27,104.91 UC1.A15
SATA_PTX_DRX_P0_R: length 2.4
  TOP w0.102: US2.1 167.86,21.88 167.68,21.71 167.33,21.71 167.1,21.94 166.59,21.94 CS37.2
SATA_PTX_DRX_P0_RC: length 1.9
  TOP w0.089: CS30.1 173.59,22.02 173.28,22.02 173.02,21.77 172.85,21.77 172.74,21.88 US2.15
SATA_RCOMP: length 6
  BOTTOM w0.076: RC131.1 149.99,108.18 v1(150.69,108.88)
  BOTTOM w0.203: 149.4,105.75 149.4,104.83 149.05,104.48 149.05,103.81 UC1.C12
  BOTTOM w0.305: 149.4,105.75 149.43,105.78 149.43,107.95 RC131.1
SCLK_CPU: length 3.8
  TOP w0.254: PR504.2 62.34,108.26 v2(62.77,107.83) 62.72,107.77 62.72,107.38 v1(62.97,107.13) PU501.20
  BOTTOM w0.254: v2(62.77,107.83) 62.34,108.26 PR504.2
SDA_CPU: length 6
  TOP w0.254: PR500.2 62.67,106.23 v2(62.92,106.48) ; v2(63.36,108.19) 63.43,108.13 PU501.18
  BOTTOM w0.254: v2(63.36,108.19) 63.49,108.19 64.09,107.6 64.09,106.78 v1(63.64,106.34) 63.06,106.34 v2(62.92,106.48) 62.67,106.23 PR500.2
SIO_EXT_SCI#: length 137.6
  TOP w0.102: v2(153.76,98.25) 153.76,98.6 156.51,101.35 158.22,101.35 161.46,104.59 161.46,106.06 162.31,106.91 162.31,107.95 v1(161.93,108.33) 161.45,108.82 RC98.2 ; v2(164.19,16.41) 164.14,16.41 163.57,16.98 163.57,17.45 162.62,18.4 162.62,18.87 162.36,19.13 162.36,21.19 162.06,21.49 161.07,21.49 160.46,22.1 160.46,22.86 159.52,23.8 158.53,23.8 158.09,24.23 157.74,24.23 157.41,23.9 157.41,23.45 156.61,22.65 154.86,22.65 154.28,22.07 154.28,21.21 154.05,20.97 UE5.A33
  IN1 w0.114: v2(164.19,16.41) 164.19,16.46 167.26,19.53 167.26,23.12 168.32,24.17 169.82,24.17 171.09,25.43 171.09,26.94 175.91,31.77 175.91,38.19 177.97,40.25 177.97,47.23 177.7,47.5 177.7,49.17 176.71,50.16 176.71,51.74 176.95,51.98 176.95,52.69 177.65,53.39 177.65,55.12 176.97,55.81 176.97,60.72 176.08,61.61 176.08,69.66 175.43,70.31 175.43,71.21 173.64,73 173.64,77.25 171.88,79.01 171.88,83 170.26,84.62 170.26,85.71 165.58,90.39 164.31,90.39 163.5,91.2 162.78,91.2 161.45,92.53 161.45,93.55 159.03,95.96 158.14,95.96 155.57,98.54 154.06,98.54 v2(153.76,98.25)
  BOTTOM w0.076: UC1.N5 153.5,97.99 v2(153.76,98.25)
SIO_EXT_SMI#: length 130.9
  TOP w0.102: UE5.A6 149.05,9.43 148.71,9.1 v2(148.71,8.99) ; v2(153.17,89.72) 153.6,89.28 154.46,89.28 v1(154.62,89.44) 154.89,89.72 156.82,89.72 158.06,90.95 160.95,90.95 161.37,91.37 163.82,91.37 164.27,91.81 RC105.1
  IN1 w0.114: v2(153.17,89.72) 153.62,90.17 154.06,90.17 154.26,90.38 154.96,90.38 156.06,89.28 156.84,89.28 157.25,89.68 159.24,89.68 159.95,88.98 159.95,86.24 161.68,84.5 161.68,79.43 162.62,78.48 167.31,78.48 168.34,77.45 170.71,77.45 171.71,76.45 171.71,72.16 173.5,70.37 173.5,69.51 174.13,68.87 174.13,64.56 173.38,63.81 173.38,60.71 175.02,59.07 175.02,52.82 174.78,52.58 174.78,49.46 174.53,49.21 174.53,47.93 175.21,47.25 175.21,43.09 175.16,43.04 175.16,40.1 173.87,38.81 173.87,37.3 172.47,35.91 172.47,34.9 171.61,34.04 171.61,31.5 171.78,31.32 171.78,30.03 169.4,27.64 169.4,26.13 169.12,25.86 167.62,25.86 163.21,21.46 163.21,18.89 161.8,17.48 161.8,15.13 159.49,12.82 158.87,12.82 157.08,11.03 156.62,11.03 155.78,11.86 153.7,11.86 153.24,11.41 153.24,11.08 152.7,10.53 150.34,10.53 148.79,8.99 v2(148.71,8.99)
  BOTTOM w0.076: UC1.AG5 153.5,90.05 v2(153.17,89.72)
SIO_EXT_WAKE#: length 111.3
  TOP w0.102: UE5.B5 148.3,11.46 148.39,11.56 148.39,11.84 148.49,11.94 v2(148.82,11.94)
  IN1 w0.114: v2(147.35,15.54) 147.35,15.54 147.35,15.54 147.36,15.54 147.36,15.55 147.35,15.55 147.35,15.57 148.43,16.65 148.88,16.65 149.21,16.98 150.16,16.98 150.45,17.27 150.45,17.79 151.32,18.66 151.32,19.39 152.32,20.39 157.17,20.39 157.89,19.66 160.75,19.66 161.66,20.58 161.66,22.07 169.69,30.09 169.69,36.83 170.77,37.91 170.77,39.55 171.43,40.21 171.43,46.15 170.23,47.35 170.23,51.2 172.27,53.24 172.27,59.03 171.94,59.36 171.94,64.41 172.69,65.16 172.69,68.26 170.11,70.84 170.11,73.98 166.81,77.28 162.12,77.28 160.47,78.92 160.47,82.37 158.79,84.05 v2(158.67,84.05)
  IN2 w0.127: v2(148.82,11.94) 148.82,13.44 147.42,14.84 147.42,15.47 147.35,15.54 147.35,15.54 v2(147.35,15.54)
  BOTTOM w0.076: UC1.AU2 155.66,84.34 155.99,84.66 156.29,84.66 156.45,84.82 157.32,84.82 157.66,84.48 158.23,84.48 v2(158.67,84.05) 158.77,84.15 v1(159.52,84.15) 159.69,84.15 160.15,83.7 160.15,80.39 160.51,80.04 RC109.1
SIO_PWRBTN#: length 232.4
  TOP w0.102: v1(97.01,77.21) 96.65,77.56 95.79,77.56 95.48,77.25 v2(95.33,77.25) 95.32,77.26 RC49.1 ; UE5.B58 146.28,16.17 146.49,16.37 v2(146.49,16.43)
  IN1 w0.114: v2(84,36.43) 83.57,36.86 83.57,51.13 90.79,58.35 90.79,69.96 94,73.17 94,75.91 v2(95.33,77.25) ; v2(152.96,88.62) 153.32,88.98 155.02,88.98 156.13,87.86 156.82,87.86 159.4,85.28 159.4,84.12 160.96,82.57 160.96,79.13 162.32,77.76 167.01,77.76 170.59,74.18 170.59,71.05 173.17,68.47 173.17,64.96 172.42,64.21 172.42,59.56 172.75,59.23 172.75,53.04 171.9,52.19 171.9,49.06 172.97,47.99 172.97,47.11 174.25,45.83 174.25,43.49 173.3,42.54 173.3,39.6 170.17,36.48 170.17,29.89 162.15,21.87 162.15,20.27 158.93,17.06 v2(158.93,16.74)
  IN3 w0.135: v2(146.49,16.43) 146.47,16.42 145.92,16.42 145.43,16.91 145.43,17.45 145.16,17.72 145.16,18.07 143.91,19.32 143.36,19.32 142.84,18.8 135.56,18.8 134.71,19.64 129.01,19.64 127.06,21.59 110.53,21.59 109.73,20.79 104.04,20.79 103.84,20.98 98.17,20.98 91.7,27.45 91.7,28.78 89.13,31.35 89.08,31.35 v2(84,36.43)
  BOTTOM w0.076: UC1.AL7 152.45,88.21 152.86,88.62 v2(152.96,88.62)
  BOTTOM w0.102: v2(158.93,16.74) 158.55,16.74 157.92,16.11 155.63,16.11 154.84,16.89 153.87,16.89 153.39,16.41 149.94,16.41 148.58,17.77 147.63,17.77 147.52,17.66 146.13,17.66 145.93,17.45 145.93,17.01 146.49,16.45 v2(146.49,16.43)
SIO_RCIN#: length 128.5
  TOP w0.102: v2(154.44,94.39) 154.95,93.87 155.96,93.87 v1(156.58,94.49) 156.74,94.64 159.93,94.64 161.02,95.73 161.84,95.73 162.44,96.34 166.06,96.34 166.54,95.86 171.17,95.86 171.26,95.95 RP43.8 ; v2(163.2,15.27) 163.12,15.34 162.9,15.34 161.24,17.01 160.06,17.01 159.67,17.4 156.98,17.4 155.99,16.42 UE5.A27
  IN1 w0.114: v2(154.44,94.39) 154.92,93.91 156.77,93.91 157.61,93.07 158.84,93.07 162.27,89.64 165.65,89.64 169.78,85.51 169.78,82.14 170.24,81.68 171.09,81.68 171.4,81.38 171.4,78.81 173.16,77.05 173.16,72.79 174.95,71 174.95,70.11 175.59,69.46 175.59,60.54 176.47,59.67 176.47,52.22 176.22,51.98 176.22,49.96 177.22,48.97 177.22,47.3 177.49,47.03 177.49,40.45 175.43,38.39 175.43,31.97 170.6,27.14 170.6,25.63 169.62,24.65 168.12,24.65 166.73,23.27 166.73,19.68 164.33,17.29 163.92,17.29 163.15,16.51 163.15,15.32 v2(163.2,15.27)
  BOTTOM w0.076: v2(154.44,94.39) 154.19,94.64 UC1.V4
SIO_SLP_A#: length 1.1
  TOP w0.102: T4935.1 153.48,88.13 v2(153.67,87.94)
  BOTTOM w0.076: v2(153.67,87.94) 153.4,88.21 UC1.AL5
SIO_SLP_S0#: length 2.7
  TOP w0.102: v2(154.49,91.37) 154.91,91.79 155.33,91.79 155.76,92.22 T4939.1
  BOTTOM w0.076: v2(154.49,91.37) 154.84,91.01 UC1.AF3
SIO_SLP_S3#: length 89.6
  TOP w0.102: v2(156.95,23.57) 156.95,23.33 156.52,22.9 154.58,22.9 T4932.1 153.34,21.67 153.34,21.34 153.05,21.04 UE5.A35
  IN1 w0.114: v2(156.95,23.57) 157.98,24.6 161.59,24.6 164.2,27.21 164.2,27.65 167.3,30.75 167.3,35.61 167.81,36.12 167.81,39.16 168.78,40.13 168.78,51.82 170.82,53.86 170.82,58.43 170.49,58.76 170.49,65.01 171.24,65.76 171.24,67.66 169.9,68.99 164.31,68.99 161.97,71.33 161.97,74.12 159.99,76.1 159.99,77.07 159.76,77.29 159.04,77.29 156.27,80.07 156.27,83.47 155.83,83.9 155.83,85.35 155.33,85.85 154.33,85.85 154.13,85.65 154.13,85.07 153.85,84.78 v2(153.72,84.78)
  BOTTOM w0.076: v2(153.72,84.78) 153.92,84.99 UC1.AT4
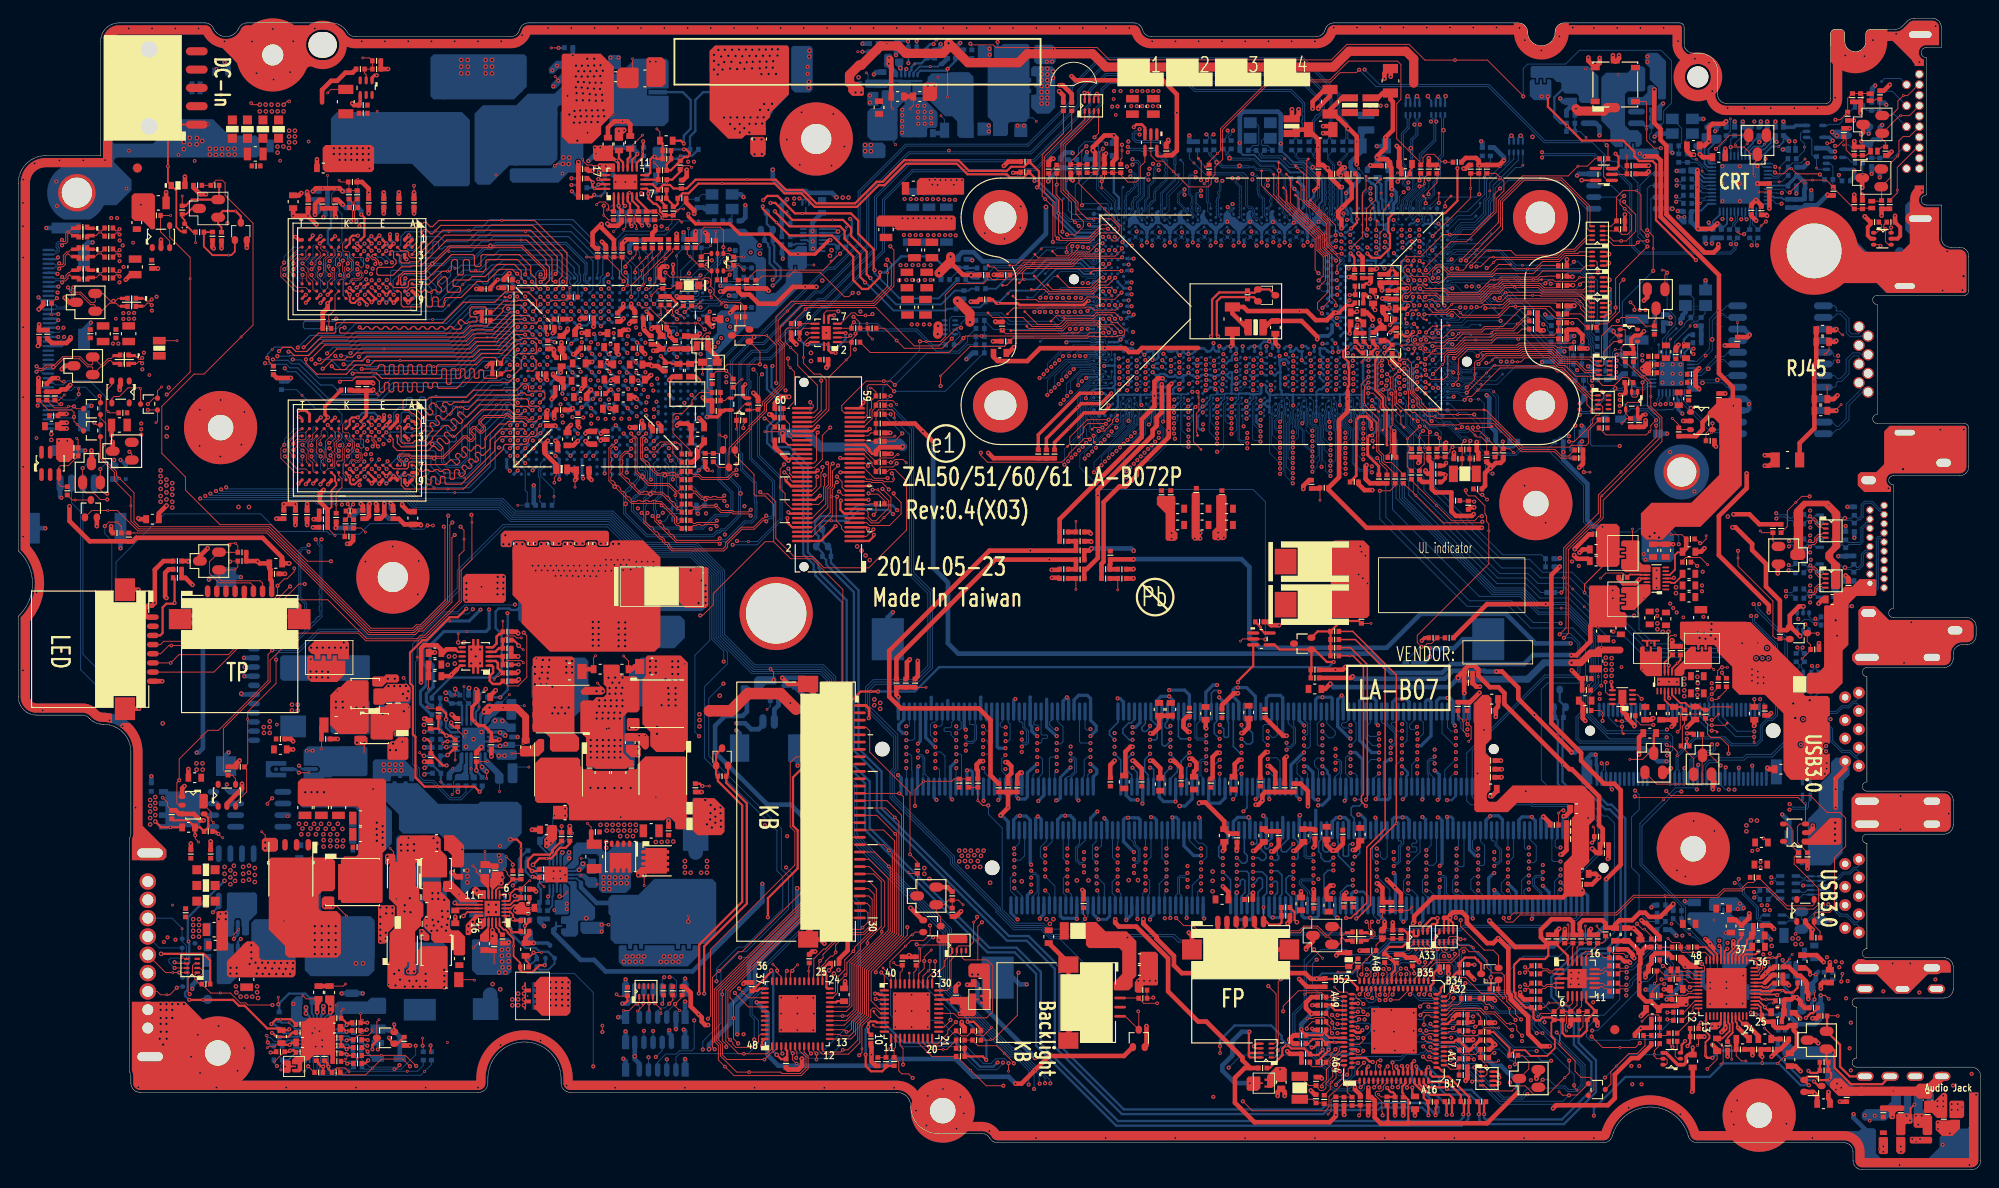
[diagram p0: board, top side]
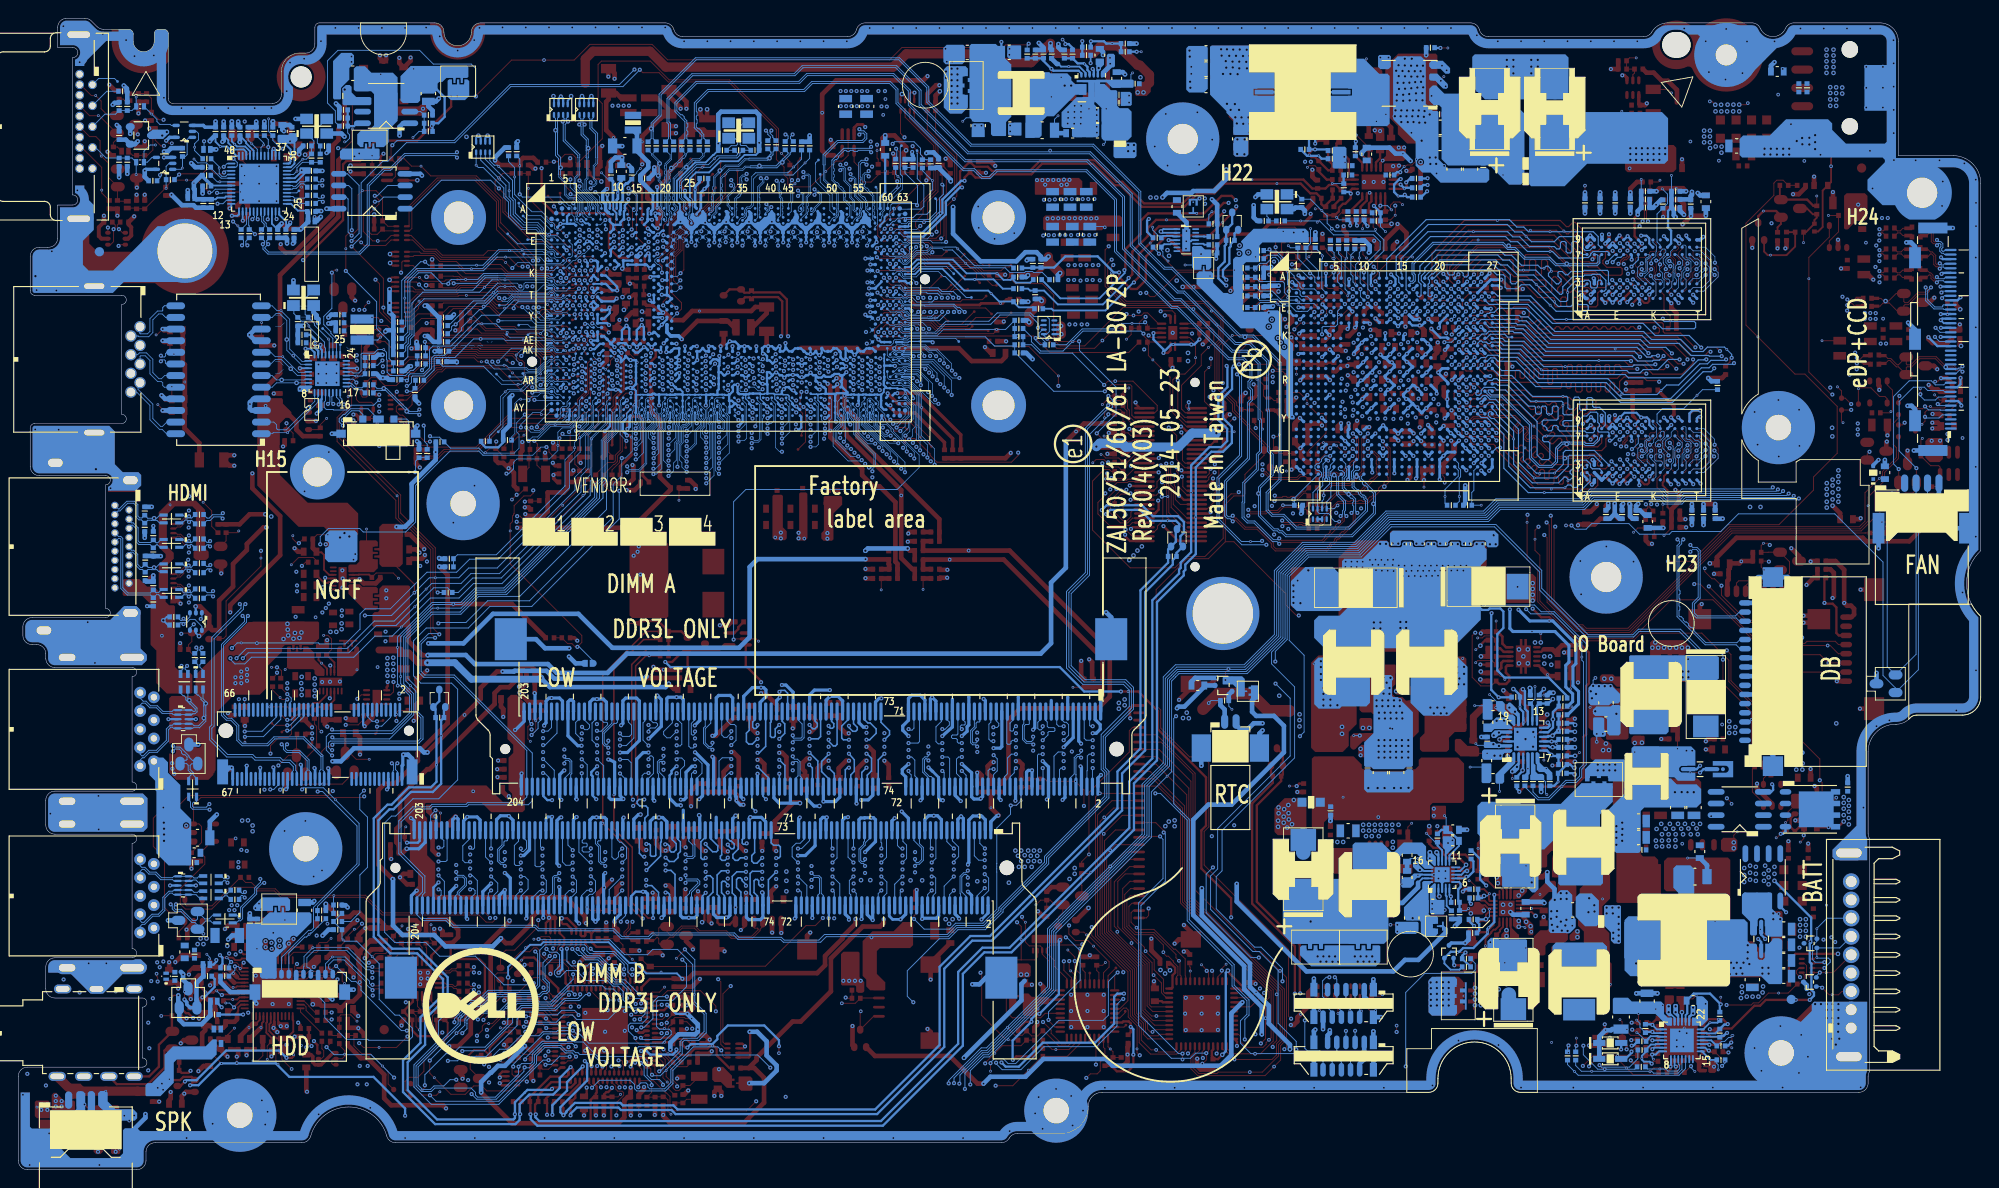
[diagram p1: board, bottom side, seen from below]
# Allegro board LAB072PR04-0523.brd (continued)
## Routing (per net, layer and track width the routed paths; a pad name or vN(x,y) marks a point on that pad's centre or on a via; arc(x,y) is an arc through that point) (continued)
SIO_SLP_S4#: length 102.8
  TOP w0.102: T4934.1 152.53,89.31 v2(152.53,89.69) ; v2(153.6,19.14) 153.8,19.33 UE5.B36
  IN1 w0.114: v2(160.37,17.64) 160.72,18 160.72,18.51 162.39,20.17 162.39,21.77 170.41,29.79 170.41,36.38 173.54,39.5 173.54,42.44 174.49,43.39 174.49,45.93 173.21,47.21 173.21,48.09 172.14,49.16 172.14,52.08 172.99,52.94 172.99,59.33 172.66,59.66 172.66,64.11 173.41,64.86 173.41,68.57 170.83,71.15 170.83,74.28 167.11,78 162.42,78 161.2,79.23 161.2,82.67 159.64,84.22 159.64,85.38 157.69,87.34 157.69,87.35 156.93,88.11 156.22,88.11 155.1,89.23 153.09,89.23 152.63,89.69 v2(152.53,89.69)
  BOTTOM w0.076: UC1.AJ6 152.84,89.12 152.53,89.44 v2(152.53,89.69)
  BOTTOM w0.102: v2(153.6,19.14) 153.98,19.51 154.41,19.51 156.06,17.86 157.65,17.86 157.96,18.16 159.85,18.16 v2(160.37,17.64)
SIO_SLP_S5#: length 127.1
  TOP w0.102: UE5.A18 156.42,11.92 v2(156.47,11.97) ; v2(153.72,86.04) 154.03,85.73 T4933.1
  IN1 w0.114: v2(157.92,23.83) 158.44,24.36 161.69,24.36 164.44,27.11 164.44,27.55 167.54,30.65 167.54,35.51 168.05,36.02 168.05,36.9 169.56,38.41 169.56,40.05 170.21,40.7 170.21,45.67 169.02,46.85 169.02,51.72 171.06,53.76 171.06,58.53 170.73,58.86 170.73,64.91 171.48,65.66 171.48,67.76 170.01,69.23 164.41,69.23 162.21,71.43 162.21,74.22 160.23,76.2 160.23,77.18 159.87,77.54 159.14,77.54 156.51,80.17 156.51,83.57 156.07,84 156.07,85.46 155.36,86.17 153.86,86.17 v2(153.72,86.04)
  BOTTOM w0.076: v2(153.72,86.04) 153.46,86.04 UC1.AP5
  BOTTOM w0.102: v2(156.47,11.97) 157.08,11.97 161.9,7.14 169.28,7.14 171.17,9.03 171.17,11.44 168.48,14.14 168.48,16.25 166.23,18.49 164.16,18.49 163.07,19.59 158.26,19.59 157.66,20.19 157.66,23.57 v2(157.92,23.83)
SIO_SLP_SUS#: length 103.2
  TOP w0.102: v1(143.79,19.94) 144.34,19.4 145.14,19.4 145.37,19.17 UE5.B52 146.03,19.17 146.14,19.05 146.14,18.84 146.38,18.6 146.5,18.6 146.94,18.16 146.94,18.11 v2(146.95,18.1)
  IN1 w0.114: v2(157.33,85.7) 157.25,85.62 157.25,83.76 157.89,83.12 159.02,83.12 159.99,82.15 159.99,78.72 161.92,76.79 166.61,76.79 169.63,73.78 169.63,70.64 172.2,68.06 172.2,65.36 171.45,64.61 171.45,59.16 171.78,58.83 171.78,53.44 169.75,51.41 169.75,47.15 170.93,45.97 170.93,40.4 170.29,39.75 170.29,38.11 169.21,37.03 169.21,30.29 161.86,22.95 158.57,22.95 156.52,20.89 152.15,20.89 150.84,19.59 150.84,18.86 150.07,18.09 149.6,18.09 149.28,17.77 147.28,17.77 v2(146.95,18.1)
  BOTTOM w0.076: v2(157.33,85.7) 156.98,86.06 156.5,86.06 156.32,86.23 155.95,86.23 155.79,86.07 155.01,86.07 154.96,86.12 154.49,86.12 UC1.AP4
SIO_SLP_WLAN#: length 157.6
  TOP w0.102: v2(99.6,26.67) 99.62,26.65 99.62,25.73 98.91,25.02 97.53,25.02 v1(96.92,24.41) 95.23,22.72 95.23,22.13 95.84,21.51 UE4.39
  IN1 w0.114: v2(99.6,26.67) 99.95,26.67 102.91,23.71 130.8,23.71 131.55,22.96 141.28,22.96 142.66,24.35 150.05,24.35 151.44,22.95 151.64,22.95 152.49,22.1 157.38,22.1 158.68,23.4 161.97,23.4 168.97,30.39 168.97,37.13 170.04,38.21 170.04,39.85 170.69,40.5 170.69,45.87 169.5,47.05 169.5,51.52 171.54,53.56 171.54,58.73 171.21,59.06 171.21,64.71 171.96,65.46 171.96,67.96 169.38,70.54 169.38,73.67 166.51,76.55 161.82,76.55 159.62,78.75 158.26,78.75 156.75,80.27 156.75,83.67 156.32,84.1 156.32,85.63 155.53,86.41 153.6,86.41 153.42,86.59 153.42,87.08 v2(153.7,87.35)
  BOTTOM w0.076: v2(153.7,87.35) 153.45,87.35 UC1.AM5
SLEEVE: length 3.1
  TOP w0.102: v1(183.46,13.57) 183.57,13.68 RA53.1
  TOP w0.254: v2(182.1,14.05) 182.1,14 181.73,13.63 181.73,12.9 QA6.3
  TOP w0.508: RA53.1 v2(184.21,14.53)
  vias: v2(186.11,15.03) v2(186.52,15.48)
SLEEVE_L: length 7.9
  TOP w1.016: 201.35,8.55 201.38,8.57 v1(204.84,8.57) 207.61,8.57 207.64,8.55 ; 208.99,9.04 210.14,10.19 JHP.4
  vias: v2(198.58,8.73) v2(198.71,9.4) v2(199.17,8.94)
SM_RCOMP0: length 10.9
  TOP w0.381: RC68.1 112.32,79.86 v1(115.71,83.24) 116.13,83.67 118.3,83.67 v2(119.42,84.79)
  BOTTOM w0.229: UC1.AU60 119.42,84.47 v2(119.42,84.79)
SM_RCOMP1: length 9.1
  TOP w0.381: v2(119.12,83.48) 119.12,83.26 118.52,82.65 116.44,82.65 v1(114.79,81) 113.21,79.43 RC69.1
  BOTTOM w0.254: UC1.AV60 119.39,83.48 v2(119.12,83.48)
SM_RCOMP2: length 11
  TOP w0.381: RC70.1 111.43,80.27 115.97,84.8 v1(117.45,84.8) v2(118.36,84.8)
  BOTTOM w0.254: UC1.AU61 118.64,84.8 v2(118.36,84.8)
SMART_DET#: length 1.3
  TOP w0.102: UE4.9 93.6,15.57 T32.1
SMB_ADDR: length 4.2
  TOP w0.102: UE4.35 97.84,21.55 98.1,21.81 RE87.2 98.56,22.79 98.56,24.06 v1(98.43,24.18)
SML0CLK: length 11.8
  BOTTOM w0.076: UC1.AN1 156.26,86.53 156.57,86.22 157.5,86.22 157.7,86.02 158.69,86.02 159.48,85.23 160.93,85.23 v1(161.21,84.95) 161.7,84.46 161.7,81.36 162.74,80.32
  BOTTOM w0.102: 162.74,80.32 162.92,80.14 R2527.1
SML0DATA: length 14.3
  TOP w0.102: v2(156.85,88.62) 157.03,88.62 158.22,89.82 163.81,89.82 164.04,90.05 167.89,90.05 168.15,89.78 v1(168.52,89.78) 169.59,89.78 R2528.1
  BOTTOM w0.076: v2(156.85,88.62) 156.7,88.77 UC1.AK1
SML1_SMBCLK: length 127.5
  TOP w0.102: UE5.B6 148.8,11.27 v2(148.73,11.33) ; RP40.3 171.25,87.31 170.26,88.29 168.58,88.29 167.51,89.36 164.33,89.36 164.1,89.13 160.34,89.13 159.6,88.39 159.37,88.39 159.11,88.14 v1(159.11,86.79) 159.11,86.32 v2(158.25,85.45)
  IN1 w0.114: v2(147.08,16.4) 147.6,16.4 148.1,16.9 148.75,16.9 149.7,17.85 150.17,17.85 151.08,18.76 151.08,19.49 152.22,20.63 157.19,20.63 157.39,20.83 158.35,20.83 159.16,20.02 160.71,20.02 161.38,20.69 161.38,22.12 169.45,30.19 169.45,36.93 170.53,38.01 170.53,39.65 171.19,40.31 171.19,46.05 169.99,47.25 169.99,51.3 172.03,53.34 172.03,58.93 171.69,59.26 171.69,64.51 172.44,65.26 172.44,68.16 169.87,70.74 169.87,73.88 166.71,77.03 162.02,77.03 160.23,78.82 160.23,82.27 159.14,83.37 157.99,83.37 157.54,83.82 157.54,84.97 157.99,85.42 158.22,85.42 v2(158.25,85.45)
  IN2 w0.127: v2(148.73,11.33) 148.81,11.33 149.29,11.81 149.29,15.03 147.91,16.4 v2(147.08,16.4)
  BOTTOM w0.076: UC1.AU3 154.91,84.34 155.25,84.68 155.59,84.68 155.81,84.9 155.81,85.18 155.96,85.33 156.29,85.33 156.45,85.17 157.97,85.17 v2(158.25,85.45)
SML1_SMBDATA: length 130
  TOP w0.102: UE5.A5 148.55,9.41 v2(148.13,8.99) ; v2(159.53,87.99) 159.53,88.01 160.43,88.9 164.19,88.9 164.42,89.13 167.41,89.13 168.48,88.06 170.17,88.06 171.15,87.08 172.17,87.08 172.45,86.81 RP40.4
  IN1 w0.114: v2(148.13,8.99) 148.53,9.4 148.72,9.4 150.1,10.77 151.85,10.77 152.2,11.13 152.2,11.58 152.07,11.71 152.07,12.02 152.96,12.91 154.46,12.91 154.92,13.36 157.83,13.36 158.14,13.06 159.39,13.06 160.48,14.15 160.48,16.65 162.97,19.14 162.97,21.56 171.54,30.13 171.54,31.22 170.9,31.87 170.9,36.18 174.92,40.2 174.92,43.14 174.97,43.19 174.97,47.15 174.29,47.83 174.29,49.34 174.53,49.59 174.53,52.68 174.78,52.92 174.78,56.42 173.77,57.43 173.77,59.23 173.14,59.86 173.14,63.91 173.89,64.66 173.89,68.77 171.47,71.2 171.47,76.35 170.61,77.21 168.24,77.21 167.21,78.24 162.52,78.24 161.44,79.33 161.44,84.29 159.53,86.19 v2(159.53,87.99)
  BOTTOM w0.076: v2(159.53,87.99) 160,88.45 v1(160,88.98) 159.44,89.54 156.54,89.54 156.26,89.82 156.02,89.82 155.78,89.58 155.78,89.4 155.61,89.23 155.1,89.23 154.85,89.48 UC1.AH3
SNB_1.05V: length 3.1
  BOTTOM w0.102: PR302.2 101.19,114.72 v1(100.8,115.1)
  BOTTOM w0.508: PR302.2 100.87,113.21 PC301.1
SPK_L1-_CONN: length 1.2
  TOP w0.203: 206.73,6.11 206.73,6.7 v3(207.17,7.13)
  vias: v2(206.3,5.9) v2(206.68,5.39)
SPK_L2+_CONN:
  vias: v2(201.73,5.92) v2(202.82,5.9) v3(202.28,5.36)
SPK_R1-_CONN:
  vias: v2(209.73,5.13) v2(209.73,4.45) v3(211.03,3.96)
SPK_R2+_CONN:
  vias: v2(207.32,5.9) v2(207.95,5.9) v3(207.57,4.92)
SRTCRST#: length 16.6
  TOP w0.102: RC5.2 157.54,73.03 CC3.2 158.45,73.05 158.97,73.05 v2(159.06,72.97)
  IN1 w0.114: v2(152.39,83.36) 151.97,82.94 151.97,80.64 154.89,77.71 154.89,75.49 156.55,73.84 157.26,73.84 158.13,72.97 v2(159.06,72.97)
  BOTTOM w0.076: v2(152.39,83.36) 152.69,83.66 UC1.AV6
STRAP0: length 6
  BOTTOM w0.102: RV49.1 RV157.2 78.77,95.96 77.4,95.96 76.4,94.97 UV1.D1
STRAP1: length 7.8
  BOTTOM w0.102: RV47.1 RV126.2 78.8,97 76.26,97 76.08,96.83 76.08,95.81 75.65,95.38 74.6,95.38 74.19,94.97 UV1.D2
STRAP2: length 8.4
  BOTTOM w0.102: RV94.1 RV127.2 78.77,94.94 77.58,94.94 77.45,95.07 76.84,95.07 76.33,94.57 75.39,94.57 75.37,94.59 72.84,94.59 UV1.E4
STRAP3: length 7.9
  BOTTOM w0.102: RV97.1 RV41.2 78.7,94.72 77.48,94.72 77.35,94.85 77.11,94.85 v1(76.79,94.53) 76.6,94.34 75.39,94.34 74.8,93.75 74.56,93.75 74.54,93.73 74.19,93.73 74.17,93.75 73.53,93.75 UV1.E3
STRAP4: length 10.6
  BOTTOM w0.102: RV98.1 RV99.2 78.74,98.99 78.04,98.99 77.38,99.65 77.04,99.65 76.69,99.3 76.69,98.97 75.74,98.02 75.74,96.69 75.21,96.17 74.58,96.17 74.35,95.94 74.35,95.55 74.17,95.38 73.58,95.38 UV1.D3
SUS_ON: length 142.8
  TOP w0.102: PR201.1 v2(59.36,37.52) ; v2(160.33,11.25) 160.46,11.13 160.46,10.44 160.22,10.21 RPE10.2 ; v2(63.81,15.04) v3(63.81,15.74) ; v2(153.47,14.38) 153.94,13.91 154.41,13.91 154.65,13.67 UE5.B23
  IN1 w0.114: v2(63.81,15.04) 63.81,14.99 67.84,10.96 89.2,10.96 91.51,13.27 97.67,13.27 98.9,12.04 104.82,12.04 105.99,13.21 111.89,13.21 113.06,12.04 132.01,12.04 133.09,10.96 136.76,10.96 137.71,11.91 141.66,11.91 142.13,11.44 144.72,11.44 146.35,9.81 148.01,9.81 149.18,10.98 149.18,11.61 150.12,12.55 151.2,12.55 153.03,14.38 v2(153.47,14.38)
  IN3 w0.135: v2(59.36,37.52) 58.78,36.93 58.78,35.28 57.41,33.91 53.95,33.91 53.57,33.53 53.57,32.72 56.34,29.95 56.73,29.95 57.59,29.09 58.16,29.09 60.48,26.77 60.48,25.45 62.92,23.01 62.92,15.93 v2(63.81,15.04)
  BOTTOM w0.102: v2(153.47,14.38) 153.57,14.38 154.03,14.84 156.98,14.84 160.33,11.49 v2(160.33,11.25)
SUS_STAT#/LPCPD#: length 12.2
  TOP w0.102: RC29.2 164.45,92.7 163.37,91.62 161.15,91.62 v1(160.99,91.45) 160.8,91.26 157.78,91.26 157.07,90.55 156.34,90.55 155.74,89.95 v2(154.5,89.95)
  BOTTOM w0.076: v2(154.5,89.95) 154.5,90 UC1.AG4
SUSACK#: length 78
  TOP w0.102: v2(156.54,14.43) 156.53,14.42 UE5.A23 ; v2(171.05,76.19) v1(171.72,76.19)
  IN1 w0.114: v2(171.05,76.19) 171.07,76.16 171.07,71.25 173.65,68.67 173.65,64.76 172.9,64.01 172.9,59.76 173.52,59.13 173.52,57.29 174.53,56.29 174.53,53.01 174.29,52.78 174.29,49.69 174.05,49.44 174.05,47.73 174.73,47.05 174.73,43.29 174.68,43.24 174.68,40.3 170.65,36.28 170.65,31.76 171.3,31.12 171.3,30.23 162.67,21.59 162.67,19.18 159.64,16.16 159.63,16.16 159.63,15 159.26,14.63 156.75,14.63 v2(156.54,14.43)
  BOTTOM w0.102: RC37.1 RC28.2 171,77.38 171,76.24 v2(171.05,76.19)
SUSACK#_R: length 23.7
  IN1 w0.114: v2(162.62,88.25) 163.12,88.76 164.2,88.76 165.22,87.75 167.14,87.75 169.54,85.35 169.54,81.84 v2(170.11,81.27)
  BOTTOM w0.076: v2(162.62,88.25) 162.55,88.19 162.55,88.18 162.23,87.86 v1(161.32,87.86) 161.08,87.86 160.83,87.61 158.89,87.61 158.68,87.4 157.74,87.4 156.93,88.22 156.65,88.22 156.38,88.48 156.03,88.48 155.74,88.77 UC1.AK2
  BOTTOM w0.102: v2(170.11,81.27) 170.01,81.17 170.01,79.52 169.73,79.24 RC37.2
SUSCLK: length 58.1
  TOP w0.102: v1(186.73,54.87) v2(186.14,54.87) 186.03,54.87 185.65,54.49 185.65,53.95 185.73,53.88 RM5.2 ; RC107.2 172.79,92.38 173.6,92.38 174.93,93.72 174.93,96.76 v2(175.38,97.21)
  IN1 w0.114: v2(186.14,54.87) 186.47,55.2 186.47,62.79 184.38,64.87 183.77,64.87 183,65.64 183,66.16 183.33,66.49 183.33,69.89 178.25,74.97 178.25,77.2 178.46,77.41 178.46,79.65 179.35,80.54 179.35,82.32 178.25,83.42 178.25,86.03 177.68,86.59 176.85,86.59 175.7,87.74 175.7,93.42 175.62,93.5 175.62,96.97 v2(175.38,97.21)
SUSCLK_NGFF: length 3.1
  TOP w0.102: v2(185.02,51.95) 184.99,51.95 185.73,52.68 RM5.1
  BOTTOM w0.102: JNGFF.42 184.72,50.23 184.72,51 184.59,51.13 184.59,51.51 v2(185.02,51.95)
SUSCLK_R: length 21.2
  TOP w0.102: RC107.1 171.33,92 170.36,92.97 167.96,92.97 166.88,94.05 164.15,94.05 162.18,92.08 160.16,92.08 159.81,91.72 156.57,91.72 155.69,90.85 v1(154.55,90.85) 154.22,90.85 154.03,91.04 153.6,91.04 v2(153.22,90.65)
  BOTTOM w0.076: UC1.AE6 152.88,91.03 153.22,90.69 v2(153.22,90.65)
SUSP#: length 290.8
  TOP w0.102: Q8.1 184.01,47.49 R10.2 ; Q8.1 184.87,45.27 v2(185.98,44.15) ; Q8.1 183.96,45.21 183.96,42.2 183.8,42.04 182.76,42.04 182.68,42.12 v1(181.16,42.12) 179,42.12 Q2307.2 ; Q10.2 166.07,9.35 v2(166.55,9.83) ; v2(12.15,78.41) 12.4,78.16 QX5.2
  IN1 w0.114: v2(166.55,9.83) 166.59,9.83 168.39,11.63 168.39,11.78 169.18,12.58 170.59,12.58 174.09,16.07 174.09,22.26 176.17,24.34 177.17,24.34 180.59,27.75 181.47,27.75 184.71,30.99 184.71,32.02 186.91,34.22 186.91,39.48 187.94,40.5 187.94,41.96 185.98,43.92 v2(185.98,44.15)
  IN3 w0.135: v2(12.15,78.41) 13.67,76.89 13.67,73.81 16.14,71.33 21.37,71.33 24.55,68.16 30.08,68.16 31.52,66.72 33.06,66.72 34.69,68.36 34.69,69.34 36.64,71.28 42.58,71.28 43.79,72.49 65.56,72.49 66.06,72.99 75.24,72.99 77.81,70.42 78.14,70.42 79.74,68.82 87.13,68.82 90.84,65.11 90.84,57.54 84.33,51.02 84.33,47.89 86.65,45.57 86.65,37.88 90.38,34.15 90.92,34.15 95.48,29.58 98.06,29.58 103,24.64 129.18,24.64 130.51,23.31 138.27,23.31 139.13,22.46 144.67,22.46 145.71,23.5 149.27,23.5 149.32,23.55 151.02,23.55 151.16,23.41 155.67,23.41 v2(155.76,23.32)
  BOTTOM w0.102: v2(155.76,23.32) 155.76,23.31 156.85,22.22 156.85,20.87 156.39,20.42 156.39,19.52 156.68,19.23 157.05,19.23 157.38,18.9 162.79,18.9 163.88,17.81 164.77,17.81 165.88,16.69 165.88,16.69 166.12,16.45 166.12,15.83 170.72,11.23 170.72,9.24 170.24,8.77 169.36,8.77 168.98,9.15 167.91,9.15 167.23,9.83 v2(166.55,9.83)
SW_1.35V:
  vias: v1(63.25,31.18) v4(63.94,31.93) v4(63.94,31.3) v4(63.94,30.66) v4(64.57,31.93) v4(64.57,31.3) v4(64.57,30.66) v4(65.21,31.93) v4(65.21,31.3) v4(65.84,31.93) v4(65.84,31.3) v4(66.48,31.93) v4(66.48,31.3)
SW_+1.35DGPU: length 13.7
  IN2 w0.762: v4(36.94,50.45) 37.7,50.45 v4(37.74,50.48) 37.74,54.12 39.22,55.6 45.76,55.6 46.22,56.06
  vias: v1(34.84,52.28) v4(34.7,51.11) v4(34.7,50.47) v4(35.44,51.11) v4(35.46,50.47) v4(47.05,56.06) v4(47.68,56.06)
SW_CPU2:
  vias: v1(64.99,115.25) v2(69.02,121.02) v2(69.65,121.02)
SYS_PEX_RST_MON#: length 18.8
  TOP w0.102: v2(67.77,94.57) 68.2,94.13 68.95,94.13 70.63,92.46 v1(74.01,92.46) 74.32,92.46 74.99,91.8 v2(74.99,91.79) ; RV51.2 76.27,87.2 77.3,87.2 v2(77.35,87.25) 78.1,86.5 RV520.2
  IN3 w0.135: v2(77.35,87.25) 77.63,87.53 77.63,91.06 77.07,91.62 75.15,91.62 v2(74.99,91.79)
  BOTTOM w0.102: UV1.E9 68.17,94.17 v2(67.77,94.57)
SYS_PEX_RST_MON#_R: length 5.1
  TOP w0.102: RV208.1 RV187.1 77.21,84 77.48,84.27 UV14.4 78.11,84.27 78.35,84.51 78.35,85.19 RV520.1 78.97,86.32 v1(79.07,86.32)
SYS_PWROK: length 225.4
  TOP w0.102: UE5.B7 149.3,10.97 v2(149.6,11.28) ; RC52.1 v2(95.31,82.51)
  IN1 w0.114: v2(171.95,85.02) 173.09,83.88 173.09,79.51 174.85,77.75 174.85,73.52 177.28,71.08 177.28,68.37 178.25,67.4 178.25,65.77 178.26,65.77 178.26,64.29 177.59,63.62 177.59,61.8 178.17,61.22 178.17,56.31 178.87,55.61 178.87,54.59 179.68,53.78 179.68,52.95 181.09,51.54 181.09,48.2 180.55,47.65 179.85,47.65 179.42,47.22 179.42,39.21 177.5,37.29 177.5,31.21 173.19,26.9 173.19,25.49 170.09,22.39 169.44,22.39 168.83,21.77 168.83,17.59 166.78,15.55 165.79,15.55 v2(164.29,14.05)
  IN3 w0.135: v2(116.62,18.29) 117.48,17.43 126.17,17.43 127.54,16.06 137.98,16.06 139.74,14.29 142.25,14.29 142.63,13.92 144.11,13.92 144.59,13.44 144.59,12.75 146.49,10.85 149.17,10.85 v2(149.6,11.28) 150.03,10.85 151.01,10.85 151.34,10.52 152.61,10.52 153.75,11.66 154.59,11.66 156.29,13.36 157.83,13.36 158.37,12.82 159.35,12.82 160.84,14.32 162.24,14.32 162.51,14.05 v2(164.29,14.05)
  BOTTOM w0.102: v2(116.62,18.29) 117.28,18.95 117.28,21.72 113.77,25.22 112.72,25.22 111.73,26.22 108.74,26.22 106.81,28.14 106.81,28.41 101.83,33.39 101.83,34.02 95.25,40.61 95.25,43.52 95.64,43.91 95.64,47.22 92.56,50.29 92.56,52.69 92.57,52.69 93.4,53.52 97.85,53.52 99.37,55.04 99.37,62.92 97.36,64.92 97.36,80.29 v1(96.01,81.65) 95.31,82.35 v2(95.31,82.51) ; v2(171.95,85.02) 171.39,85.02 CC31.1 171.01,85.4 RC40.1
SYS_PWROK_R: length 17.4
  BOTTOM w0.076: 161.45,90.73 161.33,90.73 161.15,90.55 156.01,90.55 155.73,90.27 UC1.AG2
  BOTTOM w0.102: 161.45,90.73 v3(163.89,90.73) 164.67,90.73 166.69,88.71 168.86,88.71 168.97,88.61 168.97,87.35 RC40.2
SYS_PWROK_XDP: length 7.5
  TOP w0.102: JXDP.47 92.84,80.16 93.15,80.48 CC16.1 RC64.1 RC52.2 93.71,82.72 93.98,83 95.42,83 95.72,82.69 v1(95.72,82.12)
SYS_RESET#: length 38.8
  TOP w0.102: UC5.4 172.87,109.35 172.98,109.46 172.98,110.2 RC78.2 172.24,110.42 171.43,109.6 v1(170.4,109.6) 169.33,108.54 164.34,108.54 161.7,105.89 161.7,103.42 161.69,103.42 v2(157.59,99.32)
  IN1 w0.114: v2(157.59,99.32) 157.59,99.14 160.1,96.62 160.1,95.28 161.95,93.42 v2(161.95,92.71)
  BOTTOM w0.076: UC1.AC3 155.09,92.23 157.79,92.23 158.27,92.71 161.45,92.71
  BOTTOM w0.102: 161.45,92.71 v2(161.95,92.71)
TDI_IREF: length 6
  BOTTOM w0.076: v1(146.44,109.36) 146.83,108.97 146.83,108.84 147.38,108.3 RC133.2
  BOTTOM w0.305: UC1.B12 148.67,104.73 148.59,104.8 148.59,105.64 148.37,105.87 148.37,107.34 147.98,107.72 147.83,107.72 RC133.2
TDI_XDP: length 18.2
  TOP w0.102: v1(93.32,90.71) 92.82,91.21 RC44.2 RC45.1 91.93,91.93 91.93,92.53 91.32,93.14 v2(91.24,93.14) ; v2(87.72,86.19) 87.72,82.92 86.96,82.16 JXDP.56
  IN3 w0.135: v2(91.24,93.14) 91.06,93.14 89.72,91.8 89.72,87.96 87.94,86.19 v2(87.72,86.19)
TDI_XDP_R: length 13.4
  TOP w0.102: UC4.5 91.03,91.9 RC45.2 91.04,92.31 v2(91.29,92.56)
  BOTTOM w0.102: v2(91.29,92.56) 91.42,92.43 v1(92.73,92.43) 93.86,92.43 94.47,91.82 98.17,91.82 99.9,90.1 RC63.1
TDO_XDP: length 85
  TOP w0.102: JXDP.52 86.75,81.16 88.56,82.97 88.56,86.56 v1(90.45,88.44) 90.94,88.93 90.94,90.02 91.04,90.12 RC43.2 ; UC4.2 91.02,90.4 RC43.2 ; RC43.2 91.04,90.66 91.47,91.09 v2(91.47,91.32) ; RP44.4 118.01,113.19 v2(117.58,112.75)
  IN1 w0.114: v2(91.47,91.32) 91.47,91.37 90.33,92.51 90.33,94.91 88.64,96.6 88.64,97.36 89.07,97.79 91.28,97.79 95.04,101.55 103.27,101.55 105.41,99.41 109.38,99.41 111.4,101.42 111.4,102.17 113.38,104.15 113.6,104.15 115.92,106.48 118.32,106.48 119.92,108.08 119.92,111.84 119,112.75 v2(117.58,112.75)
  BOTTOM w0.102: v2(91.47,91.32) 91.75,91.59 98.07,91.59 100.26,89.41 102.7,89.41 103.71,90.43 103.71,90.96 RC62.1
THERMATRIP2#: length 8.8
  TOP w0.254: QE9.1 159.82,22.48 v1(159.41,22.89) 159.14,23.17 158.04,23.17 157.46,22.58 RE69.2 CE61.1 157.13,21.52 155.41,19.8 155.41,19.46 155.12,19.17 UE5.B34
THERMATRIP3#: length 175.6
  TOP w0.102: v2(82.81,85.92) 82.81,90.07 v1(81.77,91.11) QV78.1 78.46,91.6 RV140.2 ; RPE6.1 137.25,12.26 137.49,12.5 137.49,12.81 137.6,12.92 v2(137.6,13.03) ; v2(146.66,9.01) 147.05,9.4 UE5.A2
  IN1 w0.114: v2(137.6,13.03) 135.68,13.03 135.41,12.77 133.86,12.77 133.59,13.04 130.77,13.04 130.77,13.05 113.47,13.05 112.31,14.2 105.58,14.2 104.45,13.07 99.27,13.07 98.08,14.26 91.1,14.26 90.14,13.31 82.12,13.31 81.21,14.23 v2(80.4,14.23)
  IN3 w0.135: v2(82.81,85.92) 82.88,85.84 82.88,84.81 82.94,84.76 82.94,82.02 79.48,78.56 79.48,75.55 79.13,75.19 79.13,74.14 80.6,72.67 81.74,72.67 82.14,72.28 86.63,72.28 86.94,71.97 88.49,71.97 93.5,66.96 93.5,55.78 88.29,50.57 88.29,49.91 v2(87.91,49.53)
  BOTTOM w0.102: v2(146.66,9.01) 146.66,9.2 146.38,9.48 145.82,9.48 145.62,9.28 145.62,9.03 145.42,8.83 143.78,8.83 143.11,9.5 143.11,10.95 140.64,13.41 137.98,13.41 v2(137.6,13.03) ; v2(87.91,49.53) 88.17,49.28 88.17,39.98 86.47,38.27 86.47,27.31 81.56,22.41 81.56,20.16 79.94,18.54 79.94,16.87 80.4,16.42 v2(80.4,14.23)
THERMATRIP_GPU#: length 14.5
  TOP w0.102: v2(70.69,98) 71.2,97.49 73.5,97.49 73.72,97.27 74.79,97.27 74.93,97.41 75.44,97.41 75.64,97.22 75.64,96.49 76,96.13 76,95.53 76.79,94.74 v1(77.02,94.74) 78.89,94.74 79.38,94.25 RV103.2 RV140.1 79.38,92.25 QV78.3
  BOTTOM w0.102: UV1.A6 70.66,97.97 v2(70.69,98)
THSEL_STRAP: length 10.2
  TOP w0.102: v1(159.47,17.02) 159.74,16.74 RE78.1 159.3,15.61 159.17,15.61 v2(159.17,15.62) ; v2(153.57,15.83) 153.57,16.66 153.8,16.89 154.12,16.89 154.35,16.67 UE5.B29
  BOTTOM w0.102: v2(153.57,15.83) 153.8,15.83 154.13,15.5 155.1,15.5 155.48,15.88 158.09,15.88 158.3,15.67 159.11,15.67 v2(159.17,15.62)
TMDS_L_TX0N: length 11.6
  BOTTOM w0.102: JHDMI.9 203.45,68.95 203.29,68.95 203.2,68.86 203.2,63.48 202.49,62.77 199.95,62.77 CX25.1 199.31,62.8 199.08,62.8 198.79,62.52 LX3.3
TMDS_L_TX0P: length 11.6
  BOTTOM w0.102: LX3.2 198.74,63.37 199.09,63.02 199.34,63.02 199.37,63.05 CX26.1 199.99,62.98 202.4,62.98 202.99,63.57 202.99,68.95 203.2,69.17 203.47,69.17 JHDMI.7
TMDS_L_TX1N: length 6.1
  BOTTOM w0.102: JHDMI.6 202.3,70.22 202.13,70.39 201.9,70.39 201.53,70.02 201.53,68.57 201.23,68.28 200,68.28 CX27.1 199.32,68.25 199.19,68.25 198.92,67.98 LX4.3
TMDS_L_TX1P: length 6.2
  BOTTOM w0.102: LX4.2 198.8,68.83 199.17,68.47 199.33,68.47 CX28.1 199.94,68.49 201.14,68.49 201.31,68.66 201.31,70.11 201.85,70.65 202.04,70.65 202.3,70.9 JHDMI.4
TMDS_L_TX2N: length 7.7
  BOTTOM w0.102: LX5.3 198.98,70.65 199.25,70.92 199.83,70.92 199.84,70.93 200.27,70.93 CX29.1 200.94,70.97 201.22,70.97 201.55,71.3 201.55,72.54 201.79,72.79 202.45,72.79 203.29,71.95 203.5,71.95 203.85,71.59 JHDMI.3
TMDS_L_TX2P: length 7.7
  BOTTOM w0.102: LX5.2 198.93,71.5 199.28,71.15 v4(199.56,71.15) 200.26,71.15 CX30.1 200.88,71.19 201.13,71.19 201.34,71.39 201.34,72.63 201.7,73 202.54,73 203.38,72.16 203.46,72.16 JHDMI.1
TMDS_L_TXCN: length 5.9
  BOTTOM w0.102: LX2.3 199.04,65.31 199.26,65.53 199.84,65.53 199.85,65.55 200.25,65.55 CX23.1 200.83,65.55 201.1,65.55 201.57,66.01 201.57,67.12 201.88,67.44 202.14,67.44 202.3,67.28 JHDMI.12
TMDS_L_TXCP: length 5.9
  BOTTOM w0.102: JHDMI.10 202.3,67.9 202.3,67.9 202.06,67.66 201.79,67.66 201.35,67.21 201.35,66.1 201.01,65.76 200.89,65.76 200.82,65.84 200.82,65.84 CX24.1 200.26,65.84 200.26,65.84 200.18,65.76 v4(199.57,65.76) 199.37,65.76 198.97,66.16 LX2.2
TMDS_TX0N: length 4.6
  TOP w0.102: RP59.4 197.16,63.57 197.01,63.72 196.76,63.72 196.49,63.45 196.49,63.09 196.2,62.8 195.99,62.8 v2(195.77,62.59)
  BOTTOM w0.102: CX14.1 195.46,62.79 195.58,62.79 v2(195.77,62.59) 195.96,62.78 196.33,62.78 196.59,62.52 LX3.4
TMDS_TX0P: length 4.7
  TOP w0.102: RP59.3 197.13,64.07 197.01,63.94 196.67,63.94 196.27,63.54 196.27,63.18 196.12,63.02 195.95,63.02 v2(195.77,63.2)
  BOTTOM w0.102: LX3.1 196.66,63.37 196.28,62.99 195.98,62.99 v2(195.77,63.2) 195.57,62.99 195.51,62.99 CX15.1
TMDS_TX1N: length 4.8
  TOP w0.102: RP58.4 197.19,69.03 197.03,69.18 196.74,69.18 196.49,68.92 196.49,68.53 196.25,68.29 196,68.29 v2(195.75,68.04)
  BOTTOM w0.102: CX16.1 195.32,68.11 195.32,68.14 195.48,68.3 195.56,68.3 195.75,68.11 v2(195.75,68.04) 195.97,68.26 196.13,68.26 196.42,67.98 LX4.4
TMDS_TX1P: length 4.6
  TOP w0.102: RP58.3 197.16,69.53 197.03,69.4 196.65,69.4 196.27,69.01 196.27,68.62 196.16,68.51 195.91,68.51 v2(195.75,68.67)
  BOTTOM w0.102: LX4.1 196.4,68.83 196.05,68.48 195.94,68.48 v2(195.75,68.67) 195.6,68.52 195.45,68.52 CX17.1
TMDS_TX2N: length 4.6
  TOP w0.102: v2(195.75,70.73) 195.97,70.95 196.17,70.95 196.3,70.82 196.3,70.56 196.67,70.2 197.04,70.2 197.21,70.03 RP58.2
  BOTTOM w0.102: CX18.1 195.46,70.92 195.56,70.92 v2(195.75,70.73) 195.97,70.96 196.17,70.96 196.48,70.65 LX5.4
TMDS_TX2P: length 4.5
  TOP w0.102: v2(195.75,71.36) 195.94,71.17 196.26,71.17 196.52,70.91 196.52,70.65 196.76,70.41 197.04,70.41 197.16,70.53 RP58.1
  BOTTOM w0.102: CX19.1 195.46,71.17 195.56,71.17 195.61,71.22 195.61,71.22 v2(195.75,71.36) 195.94,71.17 196.08,71.17 196.4,71.5 LX5.1
TMDS_TXCN: length 4.6
  TOP w0.102: v2(195.79,65.41) 195.98,65.6 196.19,65.6 196.33,65.46 196.33,65.11 196.7,64.73 197.04,64.73 197.21,64.57 RP59.2
  BOTTOM w0.102: LX2.4 196.42,65.31 196.13,65.6 195.95,65.6 195.76,65.41 v2(195.79,65.41) 195.62,65.58 195.45,65.58 CX12.1
TMDS_TXCP: length 4.6
  TOP w0.102: RP59.1 197.16,65.06 197.04,64.95 196.79,64.95 196.54,65.2 196.54,65.55 196.28,65.81 195.97,65.81 v2(195.79,65.99)
  BOTTOM w0.102: CX13.1 195.5,65.79 195.59,65.79 v2(195.79,65.99) 195.97,65.81 196.12,65.81 196.47,66.16 LX2.1
TMS_XDP: length 15.6
  TOP w0.102: UC4.9 85.37,92.4 RC46.2 85.35,92.15 85.12,91.92 84.03,91.92 83.79,91.68 83.79,90.39 v1(84.36,89.81) 85.16,89.02 85.16,87.82 87.3,85.68 87.3,83.07 86.9,82.66 JXDP.58
TON_1.35V: length 6.8
  TOP w0.254: PR208.2 60.25,35.61 59.8,35.16 59.19,35.16 58.73,34.7 58.73,34.52 58.21,34 v1(57.71,34) 56.93,34 v4(56.23,33.3)
  BOTTOM w0.203: PU200.9 56.87,32.62 56.23,33.26 v4(56.23,33.3)
TOUCH_PANEL_INTR#: length 181.8
  TOP w0.102: v2(4.22,95.19) 4.17,95.19 RC372.1 v1(3.64,93.39)
  IN1 w0.114: v2(91.8,95.73) 92.07,96 92.07,97.45 94.43,99.81 100.39,99.81 102.01,98.2 109.83,98.2 112.56,100.93 112.56,101.63 113.89,102.95 114.78,102.95 115.7,103.88 121.63,103.88 122.4,104.65 139.69,104.65 143.04,101.3 143.04,99.36 143.57,98.83 144.7,98.83 145.04,99.18 146.63,99.18 147.85,97.96 149.8,97.96 151.05,96.71 154.45,96.71 v2(155.13,97.4)
  IN2 w0.127: v2(4.22,95.19) 4.34,95.19 4.91,95.76 6.19,95.76 6.58,96.15 21.25,96.15 31.35,106.25 33.74,106.25 34.89,107.41 56.27,107.41 59.8,103.88 78.71,103.88 81.58,106.75 85.32,106.75 85.95,106.12 85.95,102.75 86.83,101.87 86.92,101.87 87.68,101.11 88.87,101.11 89.51,100.46 89.95,100.46 90.2,100.21 90.2,97.34 v2(91.8,95.73)
  BOTTOM w0.076: v2(155.13,97.4) 154.84,97.1 UC1.P3
  BOTTOM w0.102: JEDP.30 3.96,95.45 v2(4.22,95.19)
TOUCH_SCREEN_PD#: length 1.2
  TOP w0.102: T101.1 97.34,21.47 UE4.36
TP_DC_TEST_B2: length 2.2
  TOP w0.102: v2(155.88,105.21) 155.88,105.69 T167.1
  BOTTOM w0.076: v2(155.88,105.21) 155.63,104.96 UC1.B2
TRIP_+1.35DGPU: length 3.6
  TOP w0.102: 52.92,54.26 52.87,54.26 52.49,53.88 52.32,53.88 v1(51.99,53.55)
  TOP w0.279: PR1002.2 52.92,54.26 52.38,54.79 52.38,55.35 52.17,55.56 PU1000.2
TRST#_XDP: length 13.3
  TOP w0.102: JXDP.54 86.85,81.66 88.27,83.09 88.27,86.26 87.63,86.9 86.95,86.9 85.78,88.06 v1(85.78,88.69) 85.78,90.25 86.43,90.9 UC4.12
TS_EN: length 364.5
  TOP w0.102: v2(172.58,97.97) 172.58,98.16 172.5,98.25 172.5,99.11 172.36,99.24 RP60.7 ; UX3.4 16.54,101.87 18.77,99.63 v1(18.77,97.31) 18.77,87.12 16.31,84.66 v2(16.21,84.66)
  IN1 w0.114: v2(152.46,98.21) 153.08,98.83 155.3,98.83 156.62,100.15 160.66,100.15 163.45,97.36 167.77,97.36 169,96.13 170.73,96.13 172.57,97.97 v2(172.58,97.97) 175.33,97.97 175.86,97.44 175.86,93.6 175.94,93.52 175.94,87.84 176.95,86.83 177.78,86.83 178.49,86.13 178.49,85.26 179.56,84.19 180.6,84.19 180.99,83.8 180.99,79.6 178.49,77.1 178.49,75.07 184.78,68.79 184.78,66.35 187.19,63.93 187.19,46.72 188.74,45.17 188.74,43.78 189.01,43.52 189.01,40.21 187.88,39.08 187.88,33.78 185.68,31.59 185.68,30.59 181.87,26.79 181.02,26.79 176.15,21.92 176.15,18.8 175.05,17.7 175.05,15.67 170.62,11.24 169.23,11.24 165.51,7.52 157.87,7.52 157,8.38 154.84,8.38 154.44,8.79 153.78,8.79 152.56,7.57 142.11,7.57 141.31,6.77 133.48,6.77 130.04,10.21 113.54,10.21 v2(112.75,9.43)
  IN3 w0.135: v2(22.71,74.53) 22.43,74.81 19.79,74.81 15.32,79.28 15.32,81.56 16.21,82.45 v2(16.21,84.66)
  BOTTOM w0.076: v2(152.46,98.21) 152.51,98.21 152.2,97.91 UC1.N7
  BOTTOM w0.102: v2(112.75,9.43) 112.75,9.74 109.19,13.31 108.62,13.31 101.96,19.96 101.96,26.32 101.71,26.56 100.92,27.36 91.62,36.65 91.62,42.1 89.31,44.41 89.31,53.81 87.98,55.15 80.47,55.15 77.17,58.45 77.17,65.43 74.08,68.52 68.39,68.52 64.98,71.94 54.31,71.94 52.96,73.28 43.73,73.28 42.67,74.35 34.6,74.35 34.09,73.84 33.15,73.84 32.64,74.35 22.89,74.35 v2(22.71,74.53)
U2_BOOT1: length 1.4
  BOTTOM w0.102: PR606.1 v1(52.57,41.32)
U2_BOOT2: length 1.7
  BOTTOM w0.102: PR618.1 52.57,50.8 v1(53.65,51.88)
U2_LGATE1: length 16.1
  IN2 w0.762: 53.71,45.96 57.52,45.96 59.64,48.08 66.63,48.08 v4(66.79,48.25) v4(67.49,48.25)
  BOTTOM w0.102: v1(55.16,46.52) 54.98,46.34 PR615.1
  vias: v4(52.63,46.28) v4(53.24,46.47)
U2_LGATE2: length 11.2
  TOP w0.102: v4(63.86,52.25) 63.86,52.55 v1(63.28,53.14)
  IN2 w0.762: 62.16,52.25 60.89,52.25 60.35,51.71 57.43,51.71 53.78,48.06
  vias: v4(52.63,47.74) v4(53.2,47.42) v4(63.17,52.25)
U2_PHASE1: length 20.1
  IN3 w0.762: 53.52,44.58 54.06,44.05 68.56,44.05 69.78,45.27 v4(69.78,47.6) v4(69.78,48.36)
  vias: v1(72.83,55.25) v4(52.48,45.21) v4(53.12,45.21) v4(69.02,55.55) v4(69.02,54.92) v4(69.02,54.28) v4(69.65,55.55) v4(69.65,54.92) v4(69.65,54.28) v4(70.29,50.73) v4(70.72,53.57) v4(71,52.61) v4(71.05,51.97) v4(71.05,51.34) v4(71.05,50.7) v4(71.45,55.53) v4(71.45,54.89) v4(71.45,54.13) v4(71.45,53.49) v4(71.81,52.61) v4(71.81,51.97) v4(71.81,51.34) v4(71.81,50.7) v4(72.09,55.53) v4(72.09,54.89) v4(72.09,54.13) v4(72.09,53.49)
U2_PHASE2: length 8.8
  IN2 w0.762: v4(52.07,49.05) 52.07,49.86 55.55,53.34 55.55,55.17 56.06,55.68 56.57,55.68
  vias: v1(56.6,55.83) v4(52.89,49.02) v4(56.44,54.92) v4(56.44,54.16) v4(56.44,53.01) v4(56.95,53.65) v4(57.08,53.01) v4(57.21,54.92) v4(57.21,54.28) v4(57.31,55.68) v4(57.71,53.01) v4(57.84,54.28) v4(57.84,53.65) v4(58.02,55.68) v4(57.97,54.92) v4(58.35,52.76) v4(58.35,49.84) v4(58.6,50.47) v4(58.98,49.84) v4(59.36,50.47) v4(59.75,49.84) v4(59.87,55.55) v4(59.87,54.92) v4(59.87,54.28) v4(60.13,50.47) v4(60.51,55.55) v4(60.51,54.92) v4(60.51,54.28)
U2_UGATE1: length 19.2
  TOP w0.102: v2(67.75,45.27) 67.62,45.39 67.11,45.39 66.86,45.65 PR609.1 v4(67.75,45.96) ; v4(51.17,43.49) v1(51.17,42.73)
  IN2 w0.762: 52,43.55 66.79,43.55 67.75,44.5
  vias: v4(50.66,44)
U2_UGATE2: length 6.9
  TOP w0.762: v4(51.49,50.47) v1(52.98,50.47) 54.41,50.47 55.43,49.45 PR619.1
  vias: v4(50.88,50.01)
UG_3V: length 13.3
  TOP w0.102: v1(40.62,35.11) 41.01,34.72 PQ101.4
  IN3 w0.762: 41.08,33.58 49.33,33.58 50.35,32.57 50.35,30.74 v4(50.09,30.48)
  vias: v4(40.31,34.22) v4(40.31,33.58) v4(50.47,29.95)
UG_5V: length 9.3
  IN1 w0.762: 43.74,22.28 44.12,22.66 48.11,22.66 50.5,25.05 50.5,25.69
  BOTTOM w0.102: v4(50.47,26.53) 49.89,26.53 v1(49.79,26.43)
  vias: v4(42.6,21.64) v4(43.24,21.64) v4(50.47,27.17)
UG_+1.35DGPU: length 17.4
  TOP w0.102: v4(37.8,46.61) v1(37.8,45.61)
  IN2 w0.762: v4(37.8,46.61) 37.8,49.08 38.74,50.01 38.74,53.86 39.54,54.66 46.44,54.66 v4(46.92,55.15)
  vias: v4(37.01,46.64) v4(47.68,55.27)
UGATE: length 2.1
  TOP w0.254: PR513.1 65.62,110.46 66.07,110.01 PU501.14
USB3RN1_JUSB1: length 100.9
  IN3 w0.089: v2(144.56,101.37) 144.76,101.17 144.89,101.17 144.96,101.25 144.96,102.97 145.79,103.8 145.79,104.82 145.76,104.85 145.76,104.86
  IN3 w0.135: v2(196.57,55.02) 196.4,55.2 196.4,55.41 196.04,55.77 193.13,55.77 192.35,56.54 189.11,56.54 186.49,59.16 186.49,63.87 182.52,67.85 179.01,67.85 178.18,68.67 177.85,68.67 176.24,70.28 176.24,71.58 174.71,73.12 174.71,76.94 173.78,77.86 173.78,85.17 173.38,85.57 173.38,88.92 173.03,89.27 173.03,91.33 170.45,93.91 169.54,93.91 167.56,95.88 167.15,95.88 166.23,96.81 166.23,98.14 160.51,103.86 160.51,107.87 157,111.37 153.47,111.37 152.63,110.53 149.94,110.53 148.43,109.02 147.3,109.02 145.76,107.48 145.76,104.86
  BOTTOM w0.076: v2(144.56,101.37) 144.86,101.07 UC1.G20
  BOTTOM w0.102: v2(196.57,55.02) 196.4,54.84 196.4,54.71 196.67,54.44 LI1.1
USB3RN1_JUSB1_R: length 10.4
  BOTTOM w0.102: JUSB1.5 201.09,51.51 200.75,51.17 200.45,51.17 199.94,50.66 199.2,50.66 198.59,50.05 197.6,50.05 197.45,50.2 DI1.1 DI1.10 195.44,50.2 195.29,50.05 195.13,50.05 195.06,50.12 195.06,50.31 195.62,50.87 195.65,50.87 196.09,51.31 196.09,51.56 196.3,51.77 196.4,51.77 196.67,52.04 LI1.2
USB3RN2_JUSB2: length 119.7
  IN3 w0.135: v2(145.51,102.1) 145.76,101.85 146.11,101.85 146.19,101.93 146.19,102.6 146.85,103.26 146.85,107.42 147.52,108.09 148.67,108.09 150.17,109.59 156.32,109.59 158.95,106.96 158.95,104.34 165.45,97.84 165.45,96.51 166.84,95.12 167.25,95.12 169.22,93.14 170.04,93.14 172.2,90.99 172.2,88.99 172.62,88.57 172.62,84.79 173.02,84.39 173.02,77.55 173.95,76.62 173.95,72.8 175.33,71.41 175.33,70.05 177.47,67.91 177.87,67.91 178.86,66.92 179.81,66.92 179.82,66.92 181.21,66.92 183.54,64.59 184.19,64.59 185.7,63.09 185.7,58.73 189.01,55.42 191.11,55.42 194,52.53 194,49.3 196.02,47.29 196.02,38.18 191.52,33.69 191.52,33 190.83,32.31 190.83,31.93 191.03,31.73 191.32,31.73 v2(191.52,31.93)
  BOTTOM w0.076: UC1.E18 145.73,102.37 145.51,102.15 v2(145.51,102.1)
  BOTTOM w0.102: LI4.1 192.23,32.08 191.93,31.78 191.67,31.78 v2(191.52,31.93)
USB3RN2_JUSB2_R: length 8.4
  BOTTOM w0.102: LI4.2 194.63,32.08 194.85,31.85 195.2,31.85 195.39,32.04 DI4.10 DI4.1 197.4,32.04 197.55,31.89 198.75,31.89 199.36,32.5 200.04,32.5 200.56,33.02 200.92,33.02 201.09,33.19 JUSB2.5
USB3RP1_JUSB1: length 101
  IN3 w0.089: 146,104.86 146,104.85 145.97,104.81 145.97,104.61 146.08,104.5 146.08,104.23 145.97,104.12 145.97,103.73 145.14,102.9 145.14,101.17 144.96,100.99 144.63,100.99 144.53,100.9 v2(144.53,100.64)
  IN3 w0.114: 146.13,105.32 146,105.2
  IN3 w0.135: 146.13,105.32 146.13,105.67 146,105.79 146,106.14 146.11,106.24 146.11,106.63 146,106.73 146,107.38 147.4,108.78 148.53,108.78 150.04,110.29 152.73,110.29 153.57,111.13 156.9,111.13 160.26,107.76 160.26,103.76 165.99,98.04 165.99,96.71 167.05,95.64 167.46,95.64 169.44,93.66 170.35,93.66 172.79,91.23 172.79,89.17 173.14,88.82 173.14,85.47 173.54,85.07 173.54,77.76 174.46,76.84 174.46,73.02 176,71.48 176,70.18 177.75,68.43 178.08,68.43 178.91,67.6 182.42,67.6 186.25,63.77 186.25,59.06 189.01,56.3 192.25,56.3 193.03,55.53 195.94,55.53 196.15,55.31 196.15,55.21 v2(195.97,55.02) ; 146,105.2 146,104.86
  BOTTOM w0.076: UC1.H20 144.76,100.42 v2(144.53,100.64)
  BOTTOM w0.102: LI1.4 195.87,54.37 196.18,54.68 196.18,54.8 v2(195.97,55.02)
USB3RP1_JUSB1_R: length 10.4
  BOTTOM w0.102: LI1.3 195.87,51.42 v4(195.72,51.27) 194.87,50.42 194.87,50.01 195.08,49.8 195.34,49.8 195.44,49.7 DI1.9 DI1.2 197.48,49.7 197.62,49.84 198.68,49.84 199.29,50.45 200.03,50.45 200.54,50.95 200.87,50.95 201.09,50.73 JUSB1.6
USB3RP2_JUSB2: length 119.7
  IN3 w0.135: v2(191.55,31.35) 191.4,31.49 190.93,31.49 190.59,31.83 190.59,32.41 191.28,33.1 191.28,33.79 195.77,38.28 195.77,47.19 193.76,49.2 193.76,52.43 191.01,55.18 188.91,55.18 185.46,58.63 185.46,62.98 184.09,64.35 183.44,64.35 181.11,66.67 179.72,66.67 179.71,66.68 178.76,66.68 177.77,67.67 177.37,67.67 175.09,69.95 175.09,71.31 173.7,72.7 173.7,76.52 172.78,77.44 172.78,84.29 172.38,84.69 172.38,88.47 171.96,88.89 171.96,90.88 169.94,92.9 169.12,92.9 167.14,94.88 166.74,94.88 165.21,96.41 165.21,97.74 158.7,104.24 158.7,106.86 156.21,109.35 150.27,109.35 148.77,107.85 147.62,107.85 147.09,107.32 147.09,103.16 146.43,102.5 146.43,101.83 146.21,101.61 145.81,101.61 v2(145.53,101.33)
  BOTTOM w0.076: v2(145.53,101.33) 145.92,101.72 UC1.F18
  BOTTOM w0.102: LI4.4 192.25,31.28 191.96,31.56 191.76,31.56 v2(191.55,31.35)
USB3RP2_JUSB2_R: length 8.4
  BOTTOM w0.102: LI4.3 194.63,31.28 194.99,31.64 195.32,31.64 195.41,31.54 DI4.9 DI4.2 197.4,31.54 197.54,31.68 198.84,31.68 199.45,32.29 200.13,32.29 200.65,32.81 200.85,32.81 201.09,32.57 JUSB2.6
USB3TN1_JUSB1: length 110.6
  IN3 w0.135: v2(194.95,57.03) 194.8,57.18 194.8,57.48 193.73,58.55 189.36,58.55 188.09,59.82 188.09,64.46 184.89,67.67 184.89,68.25 183.39,69.74 180.62,69.74 179.37,71 179.05,71 176.23,73.82 176.23,77.58 175.66,78.15 175.66,84.89 175.37,85.18 175.37,91.47 173.35,93.5 173.35,94.77 172.52,95.59 172.52,96.07 170.73,97.85 170.73,105.57 167.71,108.6 162.54,108.6 158.12,113.02 145.88,113.02 143.04,110.18 136.76,110.18 135.17,108.59 135,108.59 v2(134.83,108.76)
  BOTTOM w0.076: v2(134.83,108.76) 134.95,108.64 135.29,108.64 135.57,108.36 135.57,106.64 136.13,106.07 136.13,104.19 136.41,103.91 UC1.C33
  BOTTOM w0.102: v2(194.95,57.03) 194.78,56.86 194.78,56.73 CI3.2
USB3TN1_JUSB1_C: length 1.6
  BOTTOM w0.102: LI3.1 195.02,54.64 194.78,54.88 194.78,55.13 CI3.1
USB3TN1_JUSB1_R: length 14.1
  BOTTOM w0.102: LI3.2 195.02,52.02 194.85,51.84 194.75,51.84 194.44,51.53 194.44,51.35 194.15,51.07 194.15,50.65 194.14,50.64 v4(194.14,49.33) 194.14,49.05 194.7,48.49 195.2,48.49 195.41,48.7 DI1.7 DI1.4 197.42,48.7 197.58,48.54 197.82,48.54 198.23,48.14 198.23,46.89 199.32,45.8 200.16,45.8 200.75,45.2 200.91,45.2 201.09,45.39 JUSB1.8
USB3TN2_JUSB2: length 136.1
  IN3 w0.135: v2(136.53,107.5) 136.68,107.65 137.11,107.65 137.42,107.95 137.57,107.95 137.88,108.26 137.88,108.41 138.06,108.59 138.29,108.59 138.42,108.46 138.81,108.46 138.94,108.59 139.28,108.59 139.41,108.46 139.81,108.46 139.93,108.59 140.28,108.59 140.41,108.46 140.8,108.46 140.93,108.59 141.27,108.59 141.4,108.46 141.79,108.46 141.92,108.59 142.29,108.59 142.47,108.41 142.78,108.41 142.96,108.59 143.24,108.59 143.46,108.81 143.66,108.81 143.95,109.1 143.95,109.3 145.75,111.1 152.18,111.1 153.01,111.94 157.37,111.94 161.19,108.12 161.19,103.91 173.55,91.56 173.55,89.49 173.9,89.14 173.9,85.79 174.3,85.39 174.3,78.09 175.23,77.17 175.23,73.33 178.57,69.99 178.95,69.99 180.21,68.73 182.39,68.73 187.09,64.04 187.09,59.39 188.96,57.52 192.83,57.52 194.06,56.29 196.65,56.29 197.21,55.73 197.21,53.52 196.68,52.99 196.68,50.57 196.53,50.42 196.53,37.44 193.25,34.16 193.25,31.85 191.49,30.09 189.88,30.09 v2(189.64,30.33)
  BOTTOM w0.076: UC1.B33 136.41,104.58 136.7,104.86 136.7,105.04 136.96,105.3 136.96,106.35 136.28,107.04 136.28,107.26 136.51,107.5 v2(136.53,107.5)
  BOTTOM w0.102: v2(189.64,30.33) 189.81,30.16 189.93,30.16 190.28,30.51 CI10.2
USB3TN2_JUSB2_C: length 1.6
  BOTTOM w0.102: LI6.1 192.15,30.43 191.9,30.18 191.85,30.13 191.6,30.13 191.55,30.18 CI10.1
USB3TN2_JUSB2_R: length 10.1
  BOTTOM w0.102: JUSB2.8 201.09,27.2 200.91,27.02 200.68,27.02 199.79,27.9 199.1,27.9 198.61,28.4 198.61,29.75 197.93,30.42 197.53,30.42 197.41,30.54 DI4.4 DI4.7 195.44,30.54 195.19,30.29 194.81,30.29 194.68,30.43 LI6.2
USB3TP1_JUSB1: length 110.5
  IN3 w0.135: v2(194.37,57.03) 194.55,57.21 194.55,57.38 193.63,58.31 189.26,58.31 187.85,59.72 187.85,64.36 184.64,67.57 184.64,68.15 183.29,69.5 180.52,69.5 179.26,70.75 178.95,70.75 175.99,73.72 175.99,77.48 175.42,78.05 175.42,84.79 175.13,85.08 175.13,91.37 173.1,93.4 173.1,94.67 172.28,95.49 172.28,95.96 170.49,97.75 170.49,105.47 167.6,108.36 162.44,108.36 158.02,112.78 145.98,112.78 143.14,109.94 141.23,109.94 141.13,109.83 140.62,109.83 140.51,109.94 140.11,109.94 140,109.83 139.5,109.83 139.39,109.94 138.99,109.94 138.88,109.83 138.37,109.83 138.27,109.94 137.86,109.94 137.75,109.83 137.25,109.83 137.14,109.94 136.87,109.94 136.72,109.79 136.72,109.69 136.72,109.67 136.36,109.31 136.33,109.31 136.33,109.31 136.23,109.31 135.95,109.02 135.95,108.92 135.95,108.89 135.58,108.53 135.56,108.53 135.56,108.53 135.46,108.53 135.27,108.34 135.04,108.34 134.84,108.15 v2(134.83,108.15)
  BOTTOM w0.076: UC1.B34 135.97,104.13 135.97,104.69 135.89,104.76 135.89,105.04 135.97,105.12 135.97,105.34 135.89,105.42 135.89,105.7 135.97,105.77 135.97,106 135.82,106.15 135.72,106.15 135.52,106.34 135.52,106.45 135.4,106.57 135.4,106.99 135.34,107.06 135.34,107.33 135.4,107.4 135.4,107.63 135.34,107.69 135.34,107.97 135.4,108.04 135.4,108.3 135.22,108.47 135.04,108.47 134.83,108.26 v2(134.83,108.15)
  BOTTOM w0.102: CI4.2 194.57,56.72 194.57,56.82 v2(194.37,57.03)
USB3TP1_JUSB1_C: length 1.6
  BOTTOM w0.102: LI3.4 194.22,54.54 194.57,54.89 194.57,55.15 CI4.1
USB3TP1_JUSB1_R: length 14
  BOTTOM w0.102: LI3.3 194.22,51.44 193.92,51.14 v4(193.92,50.92) 193.92,49.63 193.91,49.62 193.91,48.97 194.61,48.27 195.28,48.27 195.36,48.2 DI1.6 DI1.5 197.43,48.2 197.55,48.33 197.73,48.33 198.01,48.05 198.01,46.8 199.23,45.58 200.07,45.58 200.66,44.99 200.84,44.99 201.09,44.74 JUSB1.9
USB3TP2_JUSB2: length 136.2
  IN3 w0.135: v2(136.52,108.09) 136.52,108.07 136.69,107.89 137.01,107.89 137.95,108.83 143.14,108.83 145.65,111.35 152.07,111.35 152.91,112.18 157.47,112.18 161.44,108.22 161.44,104.01 173.79,91.66 173.79,89.59 174.14,89.24 174.14,85.89 174.54,85.49 174.54,78.2 175.47,77.27 175.47,73.43 178.67,70.24 179.05,70.24 180.31,68.98 182.49,68.98 187.33,64.14 187.33,59.49 189.06,57.76 192.94,57.76 194.16,56.54 196.75,56.54 197.46,55.83 197.46,53.42 196.93,52.89 196.93,50.47 196.78,50.32 196.78,37.34 193.5,34.06 193.5,31.75 191.59,29.85 189.79,29.85 v2(189.67,29.72)
  BOTTOM w0.076: v2(136.52,108.09) 136.52,108.01 136.15,107.65 136.15,107.37 136.11,107.33 136.11,106.97 136.8,106.28 136.8,105.97 136.71,105.88 136.71,105.65 136.8,105.56 136.8,105.37 UC1.A33
  BOTTOM w0.102: v2(189.67,29.72) 189.89,29.95 190.02,29.95 190.28,29.7 CI11.2
USB3TP2_JUSB2_C: length 1.6
  BOTTOM w0.102: LI6.4 192.15,29.63 191.86,29.91 191.58,29.91 CI11.1
USB3TP2_JUSB2_R: length 10.1
  BOTTOM w0.102: JUSB2.9 201.09,26.58 200.87,26.8 200.59,26.8 199.7,27.69 199.01,27.69 198.39,28.31 198.39,29.66 197.84,30.2 197.59,30.2 197.43,30.04 DI4.5 DI4.6 195.37,30.04 195.37,30.04 194.99,30.04 194.57,29.63 LI6.3
USB20_BIO_N3: length 101.7
  TOP w0.102: RS26.1 146.77,25.88 L12.1 147.43,25.88 147.57,25.74 147.57,25.73 147.77,25.53 147.86,25.53 148.01,25.68 148.01,25.85 147.54,26.32 147.54,26.84 v2(147.3,27.08)
  IN3 w0.076: 154.03,79.64 154.02,79.64 154.01,79.63 153.97,79.67 153.71,79.67 152.48,80.9 152.48,81.31 150.25,83.54 150.25,84.46 150.39,84.6 150.39,84.83 150.58,85.03 150.85,85.03 150.94,85.11 v2(150.94,85.3)
  IN3 w0.135: v2(147.3,27.08) 147.44,27.22 147.44,27.59 147.77,27.92 154.49,27.92 154.82,28.25 169.61,28.25 171.9,30.53 171.9,33.36 174.74,36.2 174.74,41.73 174.87,41.86 174.87,45.41 174.39,45.9 174.39,51.18 172.68,52.89 172.68,61.82 169.04,65.46 169.04,67.75 168.62,68.18 165.45,68.18 162.3,71.33 162.3,75.9 159.45,78.75 157.79,78.75 156.52,80.02 155.78,80.02 155.4,79.64 154.03,79.64
  BOTTOM w0.076: v2(150.94,85.3) 150.63,85.61 UC1.AR10
USB20_BIO_N3_R: length 16.3
  TOP w0.102: RS26.2 145.69,25.88 L12.2 144.99,25.88 144.68,25.56 144.54,25.56 144.43,25.68 144.43,26.39 144.28,26.55 DS1.3 143.53,25.99 143.16,25.62 142.94,25.62 141.95,26.61 140.45,26.61 139.93,26.09 137.02,26.09 136.43,25.49 134.28,25.49 133.57,26.2 133.57,26.3 133.66,26.38 133.93,26.38 134.05,26.5 JFP.4
USB20_BIO_P3: length 101.8
  TOP w0.102: RS27.1 146.77,25.03 L12.4 147.45,25.03 147.73,25.31 147.95,25.31 148.23,25.59 148.23,25.94 147.76,26.41 147.76,26.95 v2(147.88,27.08)
  IN3 w0.076: v2(150.97,84.69) 150.79,84.86 150.65,84.86 150.55,84.76 150.55,84.53 150.41,84.39 150.41,83.61 152.65,81.38 152.65,80.97 153.77,79.84 153.97,79.84 154.01,79.88
  IN3 w0.135: 154.01,79.88 155.3,79.88 155.68,80.26 156.62,80.26 157.89,78.99 159.55,78.99 162.54,76 162.54,71.43 165.55,68.42 168.72,68.42 169.29,67.86 169.29,65.56 172.93,61.92 172.93,52.99 174.63,51.28 174.63,46 175.11,45.52 175.11,41.76 174.98,41.63 174.98,36.1 172.14,33.25 172.14,30.43 169.71,28 154.92,28 154.59,27.67 147.87,27.67 147.68,27.49 147.68,27.28 v2(147.88,27.08)
  BOTTOM w0.076: v2(150.97,84.69) 150.97,84.67 150.68,84.96 UC1.AT10
USB20_BIO_P3_R: length 16.1
  TOP w0.102: JFP.3 133.05,26.57 133.36,26.26 133.36,26.11 134.19,25.28 136.52,25.28 137.11,25.87 140.02,25.87 140.54,26.39 141.86,26.39 142.85,25.4 143.22,25.4 143.53,25.1 DS1.2 144.3,24.61 144.43,24.74 144.43,25.23 144.54,25.35 144.65,25.35 144.97,25.03 L12.3 145.69,25.03 RS27.2
USB20_CAM_N7: length 174.2
  TOP w0.102: RX21.1 12.13,88.06 LX6.4 12.94,88.06 13.14,88.25 13.35,88.25 v2(13.53,88.08)
  IN3 w0.076: v2(148.93,85.93) 148.93,86.1 148.75,86.29 148.52,86.29 148.35,86.46 148.35,88.59 147.96,88.97 147.96,90.24 147.75,90.45 146.84,90.45 146.82,90.44 146.81,90.44
  IN3 w0.135: 146.81,90.44 144.78,90.44 143.9,91.33 143.89,91.33 143.16,92.05 143.16,94.4 142.51,95.05 142.51,103.77 141.1,105.18 134.27,105.18 133.09,106.36 131.35,106.36 128.68,103.7 121.11,103.7 120.6,104.2 119.72,104.2 117.3,106.62 113.44,106.62 113,107.06 112.32,107.06 111.62,107.77 111.62,108.06 110.37,109.31 108.36,109.31 108,108.95 105.69,108.95 103.57,106.83 96.63,106.83 95.56,105.77 95.56,105.29 94.34,104.07 91.88,104.07 91.47,104.47 87,104.47 84.75,102.22 80.55,102.22 79.57,101.25 76.74,101.25 75.95,100.46 70.29,100.46 69.19,99.37 65.87,99.37 64.29,100.94 64.29,101.42 63.88,101.84 63.02,101.84 61.17,103.7 59.23,103.7 57.45,105.47 44.71,105.47 44.33,105.09 36.22,105.09 35.77,104.64 35.15,104.64 34.88,104.9 29.65,104.9 29.14,104.4 29.14,103.62 17.04,91.52 17.04,90.63 14.64,88.23 13.68,88.23 v2(13.53,88.08)
  BOTTOM w0.076: UC1.AR13 148.61,85.61 v2(148.93,85.93)
USB20_CAM_N7_R: length 13.2
  TOP w0.102: RX21.2 11.03,88.06 LX6.3 10.41,88.06 10.09,88.38 9.91,88.38 9.21,87.68 8.98,87.68 DX3.2 8.13,87.59 8.03,87.69 7.54,87.69 6.66,88.57 4.94,88.57 4.03,87.66 v4(3.83,87.66) 3.07,87.66 2.71,87.3 2.14,87.3 v2(2,87.16)
  BOTTOM w0.102: v2(2,87.16) 2.19,87.35 2.3,87.35 2.69,86.95 JEDP.13
USB20_CAM_P7: length 174.3
  TOP w0.102: v2(13.53,88.66) 13.38,88.51 13.17,88.51 12.77,88.91 LX6.1 12.12,88.91 RX22.1
  IN3 w0.076: 146.81,90.68 146.82,90.68 146.87,90.63 146.89,90.63 146.9,90.62 147.82,90.62 148.12,90.31 148.12,89.04 148.51,88.66 148.51,86.53 148.59,86.45 148.76,86.45 v2(148.98,86.67)
  IN3 w0.135: 146.81,90.68 144.89,90.68 144,91.57 143.99,91.57 143.4,92.15 143.4,94.5 142.75,95.15 142.75,103.88 141.2,105.43 134.37,105.43 133.19,106.61 131.25,106.61 128.58,103.94 121.21,103.94 120.71,104.45 119.82,104.45 117.4,106.86 113.54,106.86 113.1,107.3 112.42,107.3 111.86,107.87 111.86,108.16 110.47,109.56 108.26,109.56 107.9,109.2 105.59,109.2 103.47,107.08 96.52,107.08 95.32,105.87 95.32,105.39 94.24,104.31 91.98,104.31 91.57,104.72 86.9,104.72 84.65,102.47 80.45,102.47 79.47,101.49 76.64,101.49 75.85,100.7 70.19,100.7 69.09,99.61 65.97,99.61 64.54,101.04 64.54,101.53 63.98,102.08 63.12,102.08 61.27,103.94 59.33,103.94 57.55,105.72 44.61,105.72 44.23,105.34 36.12,105.34 35.67,104.88 35.25,104.88 34.98,105.15 29.55,105.15 28.89,104.5 28.89,103.72 16.79,91.62 16.79,90.73 14.54,88.47 13.72,88.47 v2(13.53,88.66)
  BOTTOM w0.076: UC1.AP13 v2(148.98,86.67)
USB20_CAM_P7_R: length 13.1
  TOP w0.102: v2(2,87.74) 2.22,87.52 2.62,87.52 2.98,87.87 3.55,87.87 3.56,87.89 3.95,87.89 4.85,88.79 6.75,88.79 7.63,87.91 8.03,87.91 8.13,88.01 DX3.3 9,87.9 9.12,87.9 9.71,88.49 9.71,88.49 9.82,88.6 10.14,88.6 10.45,88.91 LX6.2 11.05,88.91 RX22.2
  BOTTOM w0.102: v2(2,87.74) 2.17,87.56 2.39,87.56 2.5,87.45 JEDP.14
USB20_CR_N6: length 277.5
  IN3 w0.076: v2(149.44,85.63) 149.44,85.63 149.66,85.85 149.84,85.85 149.93,85.77 149.93,85.51 149.48,85.07 149.48,83.57 151.91,81.14 151.91,79.92 153.06,78.77 153.97,78.77 154.01,78.73 154.03,78.73
  IN3 w0.135: 154.03,78.73 154.56,78.73 155.66,77.63 159.43,77.63 160.09,76.98 160.09,75.54 161.52,74.1 161.52,71.02 168.24,64.3 169.08,64.3 171.92,61.46 171.92,51.07 173.57,49.43 173.57,45.62 174.11,45.08 174.11,43.42 172.55,41.87 172.55,37.84 171.13,36.43 171.13,32.03 170.02,30.91 170.02,29.93 169.11,29.02 154.23,29.02 153.89,28.68 146.2,28.68 145.48,27.97 145.48,27.26 145.15,26.93 142.55,26.93 142.09,26.47 136.44,26.47 135.93,26.98 127.75,26.98 127.16,26.38 104.17,26.38 99.37,31.18 97.69,31.18 88.33,40.54 88.33,46.34 86.06,48.62 86.06,50.55 92.64,57.13 92.64,66.3 88.56,70.38 80.47,70.38 78.25,72.59 78.25,73.59 77.17,74.67 64.8,74.67 64.43,74.3 42.88,74.3 42.63,74.04 35.46,74.04 32.87,71.45 32.87,70.11 32.7,69.94 32.7,69.05 v2(32.49,68.84)
  BOTTOM w0.076: v2(149.44,85.63) 149.62,85.63 UC1.AP11
  BOTTOM w0.102: v2(32.49,68.84) 32.67,68.66 32.67,68.35 32.96,68.06 32.96,63.32 32.85,63.21 32.85,62.9 32.96,62.79 32.96,62.42 32.87,62.33 32.87,61.98 32.96,61.89 32.96,61.58 32.87,61.49 32.87,61.14 32.96,61.05 32.96,60.49 32.87,60.4 32.71,60.4 32.5,60.18 32.5,60.03 32.28,59.81 32.13,59.81 31.92,59.6 31.92,59.45 31.7,59.23 31.55,59.23 31.33,59.02 31.33,58.86 30.03,57.56 26.63,57.56 26.29,57.9 JIO.12
USB20_CR_P6: length 277.7
  IN3 w0.076: 154.03,78.97 154.01,78.97 153.97,78.93 153.13,78.93 152.07,79.99 152.07,81.21 149.65,83.64 149.65,85 150.1,85.45 150.1,85.84 149.91,86.02 149.72,86.02 v2(149.53,86.21)
  IN3 w0.135: 154.03,78.97 154.66,78.97 155.76,77.87 159.53,77.87 160.33,77.08 160.33,75.64 161.77,74.21 161.77,71.12 168.34,64.54 169.18,64.54 172.17,61.56 172.17,51.17 173.81,49.53 173.81,45.72 174.35,45.18 174.35,43.32 172.8,41.77 172.8,37.74 171.38,36.32 171.38,31.93 170.26,30.81 170.26,29.83 169.21,28.78 154.33,28.78 153.99,28.44 146.3,28.44 145.72,27.86 145.72,27.15 145.25,26.68 142.65,26.68 142.19,26.23 136.34,26.23 135.83,26.73 127.85,26.73 127.26,26.14 104.07,26.14 99.27,30.94 97.59,30.94 88.09,40.44 88.09,46.24 85.82,48.52 85.82,50.65 92.39,57.23 92.39,66.2 88.46,70.13 80.37,70.13 78.01,72.49 78.01,73.48 77.07,74.42 64.9,74.42 64.53,74.06 42.98,74.06 42.73,73.8 35.56,73.8 33.12,71.35 33.12,70.01 32.95,69.84 32.95,69.01 v2(33.13,68.84)
  BOTTOM w0.076: UC1.AN11 149.89,86.58 149.52,86.22 v2(149.53,86.21)
  BOTTOM w0.102: v2(33.13,68.84) 32.88,68.59 32.88,68.44 33.18,68.15 33.18,60.4 30.1,57.33 26.73,57.33 26.3,56.9 JIO.11
USB20_JUSB1_N0: length 81.8
  IN3 w0.076: v2(151.44,86.26) 151.68,86.5 151.96,86.5 152.34,86.88 152.34,88.61 152.76,89.03 153.13,89.03 153.17,88.99 153.19,88.99
  IN3 w0.135: 153.19,88.99 155.11,88.99 155.76,88.34 155.76,83.82 156.27,83.31 159.06,83.31 164.23,78.14 166.87,78.14 170.65,74.37 170.65,70.07 173.73,67 173.73,65.57 175.97,63.33 175.97,62.99 178.04,60.91 178.04,58.87 179.3,57.61 179.77,57.61 182.51,54.87 183.48,54.87 184.21,54.14 184.21,44.47 186.66,42.01 190.18,42.01 192.7,39.49 193.33,39.49 v2(193.5,39.32)
  BOTTOM w0.076: v2(151.44,86.26) 151.77,86.58 UC1.AN8
  BOTTOM w0.102: v2(193.5,39.32) 193.55,39.37 195.36,39.37 195.58,39.6 195.58,40.16 195.78,40.36 LI2.4
USB20_JUSB1_N0_R: length 11.1
  IN3 w0.135: JUSB1.2 199.59,47.79 199.38,48 198.49,48 198.32,47.83 198.32,46.14 198.05,45.87 197.68,45.87 v2(197.51,45.7)
  BOTTOM w0.102: v2(197.51,45.7) 197.51,45.73 197.3,45.94 196.82,45.94 196.57,45.69 196.57,45.51 196.38,45.32 196.2,45.32 195.97,45.09 195.97,44.81 196.07,44.71 196.37,44.71 DI2.2 196.02,44.35 195.84,44.17 195.84,43.61 195.52,43.3 195.52,43.12 195.78,42.86 LI2.3
USB20_JUSB1_P0: length 81.8
  IN3 w0.076: 153.19,89.23 153.17,89.23 153.13,89.19 152.7,89.19 152.18,88.67 152.18,86.95 151.9,86.67 151.68,86.67 v2(151.44,86.91)
  IN3 w0.135: v2(193.53,39.93) 193.33,39.74 192.8,39.74 190.29,42.26 186.76,42.26 184.45,44.57 184.45,54.24 183.58,55.11 182.62,55.11 179.87,57.85 179.4,57.85 178.29,58.97 178.29,61.02 176.21,63.09 176.21,63.43 173.97,65.68 173.97,67.1 170.9,70.17 170.9,74.47 166.98,78.39 164.33,78.39 159.16,83.56 156.37,83.56 156,83.92 156,88.44 155.21,89.23 153.19,89.23
  BOTTOM w0.076: v2(151.44,86.91) 151.77,87.23 UC1.AM8
  BOTTOM w0.102: LI2.1 194.93,40.19 194.99,40.13 195.26,40.13 195.37,40.02 195.37,39.69 195.27,39.59 193.87,39.59 v2(193.53,39.93)
USB20_JUSB1_P0_R: length 11.2
  IN3 w0.135: JUSB1.3 199.59,48.49 199.35,48.24 198.38,48.24 198.07,47.93 198.07,46.25 197.94,46.12 197.68,46.12 v2(197.51,46.29)
  BOTTOM w0.102: v2(197.51,46.29) 197.38,46.15 196.73,46.15 195.75,45.18 195.75,45.07 195.36,44.68 195.13,44.68 DI2.3 194.82,44.33 195.46,44.33 195.62,44.16 195.62,43.7 195.3,43.39 195.3,43.13 194.93,42.76 LI2.2
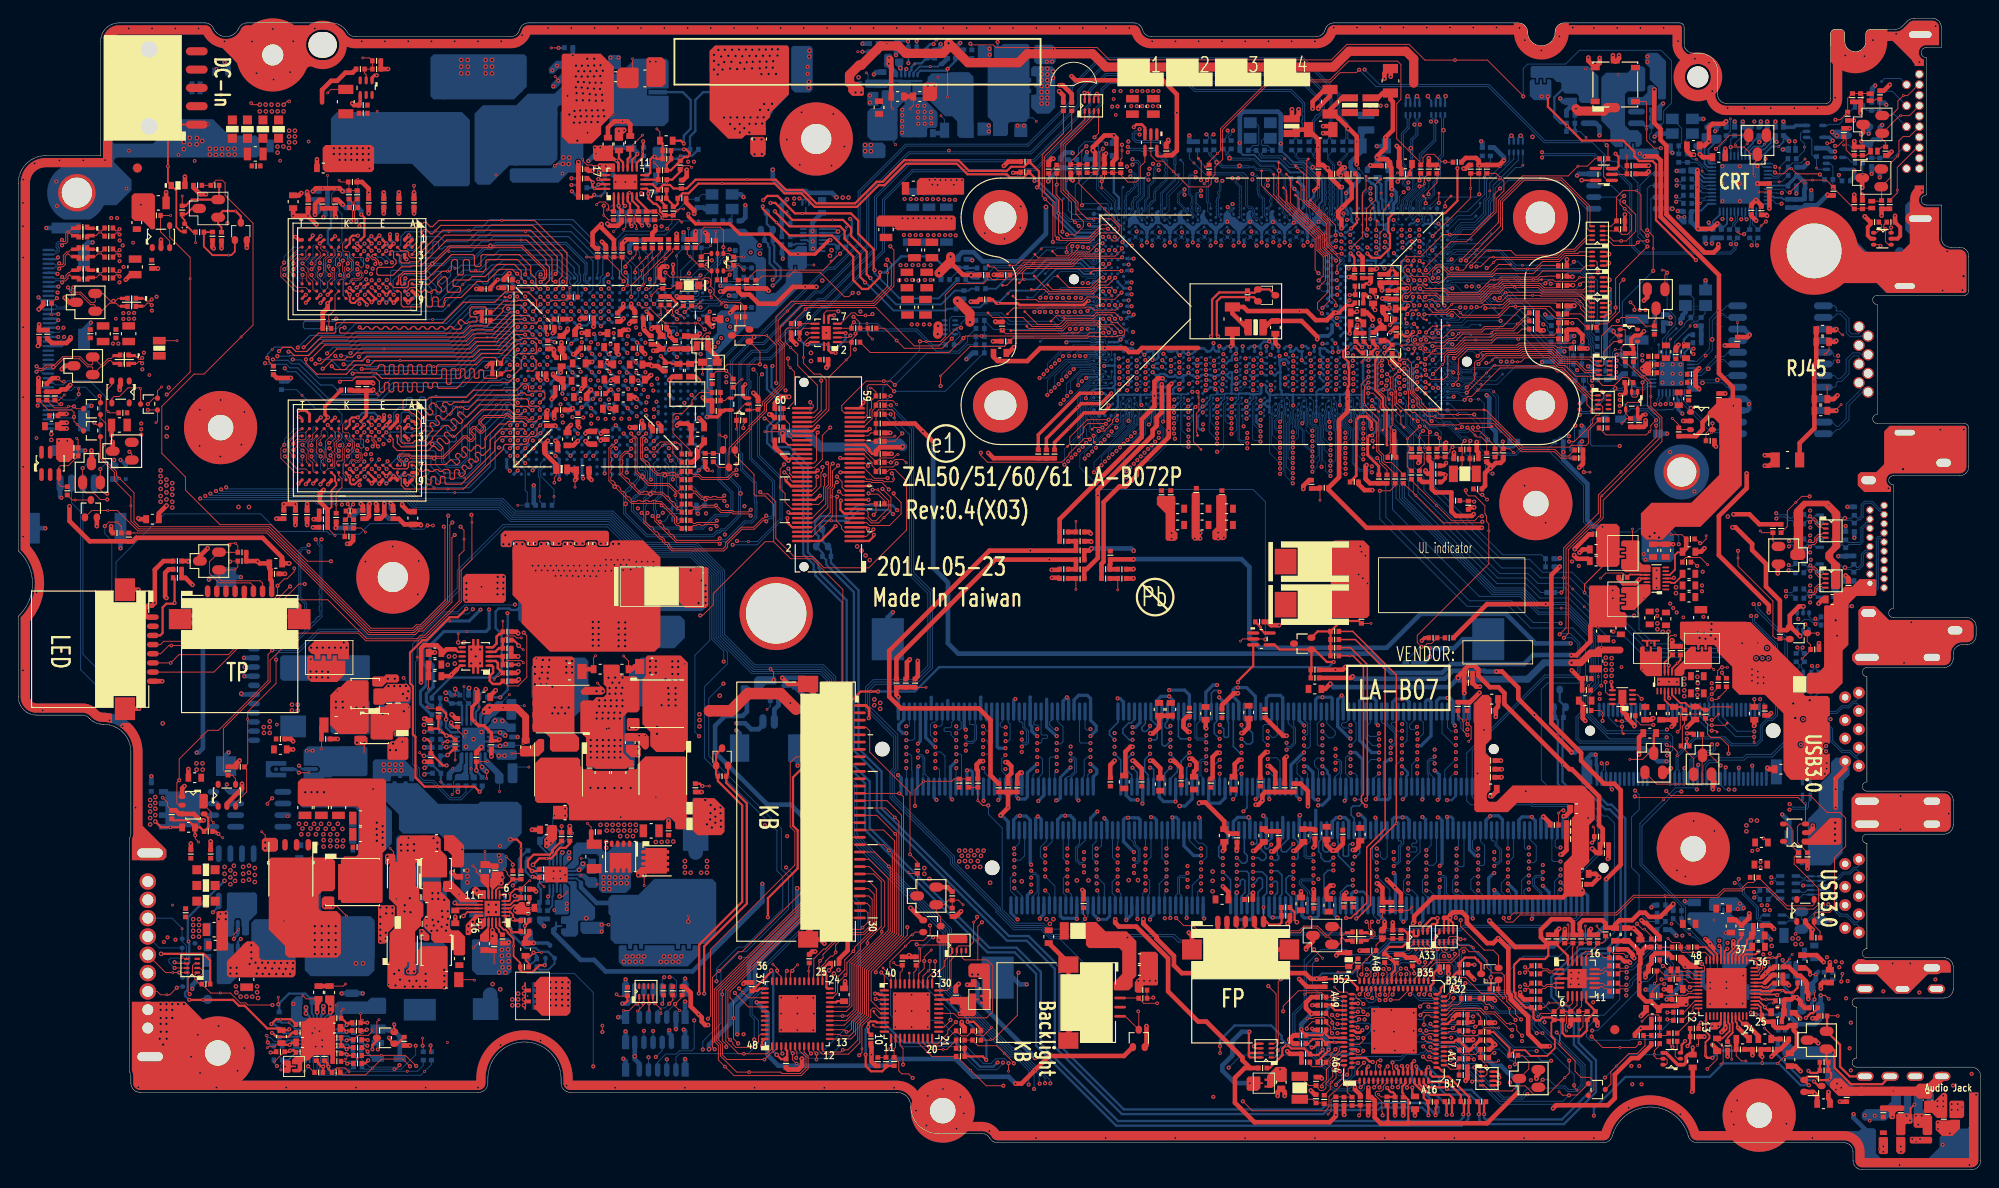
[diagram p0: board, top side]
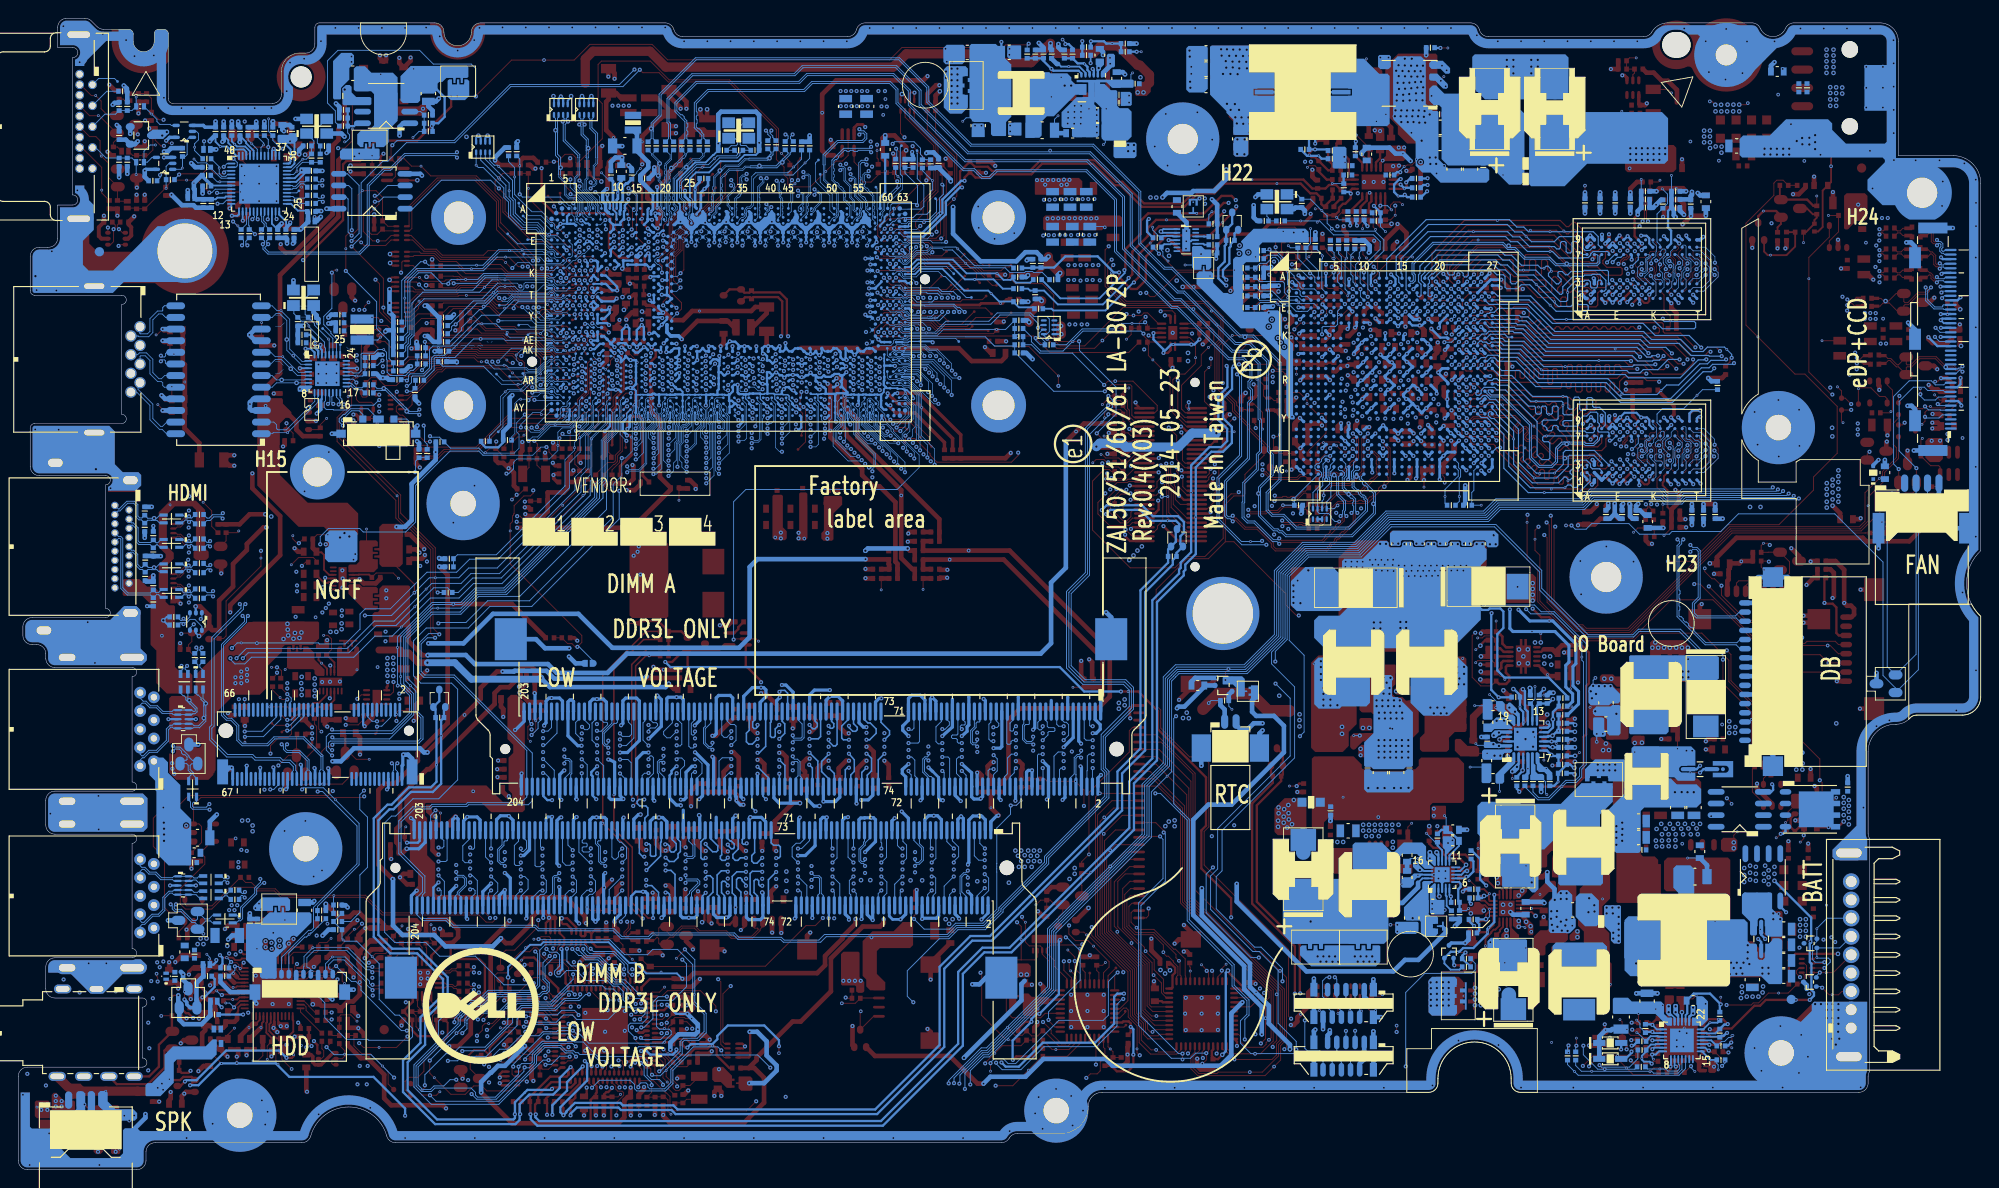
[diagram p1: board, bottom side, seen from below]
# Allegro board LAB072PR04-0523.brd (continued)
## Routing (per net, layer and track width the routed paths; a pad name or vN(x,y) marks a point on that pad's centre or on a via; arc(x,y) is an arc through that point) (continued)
USB20_JUSB2_N1: length 81.3
  IN3 w0.076: v2(152.84,86) 152.84,86 152.3,85.46 152.3,84.75 153.84,83.21 153.84,83.16 153.86,83.14
  IN3 w0.135: 153.86,83.14 154.31,82.69 155.55,82.69 155.91,82.33 157.54,82.33 158.18,81.69 159.53,81.69 161.28,79.94 161.28,79.28 163.17,77.38 166.56,77.38 169.89,74.05 169.89,69.75 172.96,66.68 172.96,65.21 174.98,63.19 174.98,62.87 177.2,60.65 177.2,58.6 180.1,55.7 180.33,55.7 181.93,54.1 182.5,54.1 182.74,53.87 182.74,42.97 187.16,38.55 187.16,31.84 187.53,31.47 v2(187.53,31.32)
  BOTTOM w0.076: UC1.AR7 152.45,85.61 v2(152.84,86)
  BOTTOM w0.102: v2(187.53,31.32) 187.71,31.32 188.36,30.67 188.36,30.11 189.89,28.58 189.89,27.41 190.12,27.18 190.35,27.18 190.57,26.96 LI5.4
USB20_JUSB2_N1_R: length 10.7
  IN3 w0.135: v2(197.76,28.98) 197.62,29.12 197.62,29.77 197.76,29.91 199,29.91 199.59,29.32 JUSB2.2
  BOTTOM w0.102: LI5.3 193.19,26.96 193.4,27.17 193.92,27.17 DI5.2 194.82,26.72 195.1,27 195.43,27 195.93,27.5 196.65,28.22 197.32,28.22 197.58,28.47 197.58,28.81 v2(197.76,28.98)
USB20_JUSB2_P1: length 81.3
  IN3 w0.076: 154.03,83.31 154.02,83.33 153.96,83.33 152.47,84.82 152.47,85.39 152.68,85.6 152.81,85.6 152.91,85.5 152.91,85.32 v2(152.84,85.24)
  IN3 w0.135: 154.03,83.31 154.41,82.93 155.66,82.93 156.01,82.58 157.64,82.58 158.28,81.93 159.63,81.93 161.52,80.04 161.52,79.38 163.28,77.62 166.66,77.62 170.14,74.15 170.14,69.85 173.21,66.78 173.21,65.31 175.23,63.29 175.23,62.97 177.45,60.75 177.45,58.7 180.2,55.95 180.43,55.95 182.03,54.35 182.6,54.35 182.99,53.97 182.99,43.07 187.41,38.65 187.41,31.94 187.6,31.75 v2(187.96,31.75)
  BOTTOM w0.076: UC1.AT7 152.54,84.96 152.84,85.25 v2(152.84,85.24)
  BOTTOM w0.102: v2(187.96,31.75) 187.94,31.73 187.94,31.4 188.57,30.76 188.57,30.2 190.11,28.67 190.11,27.5 190.21,27.4 190.29,27.4 190.39,27.5 190.39,27.69 190.51,27.81 LI5.1
USB20_JUSB2_P1_R: length 10.7
  IN3 w0.135: v2(197.17,28.98) 197.38,29.19 197.38,29.87 197.65,30.15 198.85,30.15 JUSB2.3
  BOTTOM w0.102: LI5.2 193.14,27.81 193.57,27.38 194.01,27.38 DI5.3 194.82,27.38 194.99,27.22 195.34,27.22 196.56,28.44 197.24,28.44 197.36,28.56 197.36,28.79 v2(197.17,28.98)
USB20_JUSB3_N2: length 279.9
  IN3 w0.076: v2(151.53,84.85) 151.44,84.94 151.44,85.14 151.53,85.23 151.75,85.23 151.92,85.06 151.92,84.64 151.53,84.24 151.53,84.09 151.44,84 151.44,83.78 151.53,83.69 151.53,83.35 151.69,83.19 151.81,83.19 151.97,83.03 151.97,82.91 152.13,82.75 152.26,82.75 152.42,82.58 152.42,82.46 152.56,82.32 152.93,82.32 153.4,81.85 153.4,81.42 153.73,81.09 153.98,81.09 154.02,81.05 154.03,81.05
  IN3 w0.135: 154.03,81.05 156.65,81.05 157.52,80.17 159.29,80.17 162.84,76.62 166.25,76.62 169.13,73.74 169.13,69.43 172,66.56 172,63.66 175.15,60.5 175.15,58.41 178.48,55.08 178.48,51.76 177.54,50.81 177.54,47.68 175.71,45.85 175.71,33.15 169.58,27.02 166.07,27.02 165.74,26.69 162.16,26.69 162.16,26.68 154.58,26.68 154.11,26.22 150.09,26.22 149.52,25.64 147.43,25.64 146.91,26.16 143.14,26.16 142.69,25.71 135.55,25.71 135.25,25.4 127.3,25.4 127.1,25.61 103.86,25.61 99.05,30.42 97.35,30.42 87.57,40.2 87.57,45.94 85.2,48.31 85.2,50.78 91.83,57.41 91.83,65.99 88.23,69.59 80.16,69.59 77.82,71.94 77.39,71.94 75.57,73.75 65.36,73.75 65,73.4 43.4,73.4 42.19,72.19 35.24,72.19 33.72,70.66 33.72,68.62 32.99,67.89 31.88,67.89 31.72,68.05 v2(31.72,68.23)
  BOTTOM w0.076: UC1.AR8 151.84,85.16 v2(151.53,84.85)
  BOTTOM w0.102: JIO.15 26.38,60.9 26.8,60.48 30.95,60.48 31.28,60.81 31.28,61.79 30.65,62.42 30.65,67.63 30.99,67.97 31.46,67.97 v2(31.72,68.23)
USB20_JUSB3_P2: length 279.9
  IN3 w0.076: v2(151.42,85.59) 151.42,85.59 151.62,85.4 151.82,85.4 152.09,85.13 152.09,84.57 151.69,84.17 151.69,83.54 152.75,82.49 153,82.49 153.57,81.92 153.57,81.49 153.8,81.26 153.98,81.26 154.02,81.3 154.03,81.3
  IN3 w0.135: v2(31.72,67.49) 31.88,67.64 33.09,67.64 33.96,68.52 33.96,70.56 35.35,71.95 42.29,71.95 43.5,73.15 65.1,73.15 65.46,73.51 75.47,73.51 77.28,71.69 77.72,71.69 80.06,69.34 88.13,69.34 91.58,65.89 91.58,57.51 84.95,50.88 84.95,48.21 87.33,45.84 87.33,40.1 97.25,30.18 98.95,30.18 103.76,25.36 126.99,25.36 127.2,25.16 135.35,25.16 135.65,25.46 142.79,25.46 143.25,25.92 146.8,25.92 147.32,25.4 149.62,25.4 150.19,25.97 154.21,25.97 154.68,26.44 162.4,26.44 162.4,26.44 165.84,26.44 166.17,26.77 169.68,26.77 175.95,33.05 175.95,45.75 177.78,47.58 177.78,50.71 178.72,51.66 178.72,55.18 175.4,58.51 175.4,60.6 172.24,63.76 172.24,66.66 169.37,69.53 169.37,73.84 166.35,76.86 162.95,76.86 159.39,80.42 157.63,80.42 156.75,81.3 154.03,81.3
  BOTTOM w0.076: v2(151.42,85.59) 151.76,85.93 UC1.AP8
  BOTTOM w0.102: JIO.14 26.35,59.9 26.71,60.26 31.04,60.26 31.5,60.72 31.5,61.88 30.87,62.51 30.87,67.54 31.08,67.75 31.46,67.75 v2(31.72,67.49)
USB20_MINI1_N4: length 63.7
  IN3 w0.076: 154.03,77.66 154.01,77.66 153.97,77.7 152.83,77.7 151.2,79.33 151.2,80.86 149.04,83.02 149.04,84.34 147.95,85.43 147.95,87.29 147.87,87.37 147.72,87.37 v2(147.52,87.17)
  IN3 w0.135: 154.03,77.66 154.26,77.66 155.17,76.75 155.17,75.53 156.08,74.62 159.75,74.62 160.75,73.63 160.75,70.71 167.92,63.53 168.71,63.53 171.13,61.1 171.13,49.99 172.73,48.39 172.73,47.68 171.38,46.32 171.38,44.05 172.21,43.21 172.96,43.21 173.46,43.72 173.46,44.26 v2(173.59,44.39)
  BOTTOM w0.076: v2(147.52,87.17) 147.59,87.23 UC1.AM15
  BOTTOM w0.102: v2(173.59,44.39) 173.4,44.2 173.4,43.6 173.48,43.52 JNGFF.5
USB20_MINI1_P4: length 63.5
  IN3 w0.076: v2(147.5,87.79) 147.5,87.78 147.76,87.53 147.94,87.53 148.11,87.36 148.11,85.5 149.2,84.41 149.2,83.09 151.36,80.93 151.36,79.4 152.9,77.86 153.97,77.86 154.01,77.9 154.03,77.9
  IN3 w0.135: 154.03,77.9 154.36,77.9 155.41,76.85 155.41,75.64 156.18,74.87 159.85,74.87 160.99,73.73 160.99,70.81 168.02,63.78 168.81,63.78 171.38,61.21 171.38,50.09 172.98,48.49 172.98,47.58 171.63,46.23 171.63,44.14 172.32,43.46 172.86,43.46 173.22,43.82 173.22,44.16 v2(172.99,44.39)
  BOTTOM w0.076: v2(147.5,87.79) 147.56,87.73 147.85,87.73 UC1.AL15
  BOTTOM w0.102: JNGFF.3 172.98,43.48 173.18,43.69 173.18,44.19 v2(172.99,44.39)
USB20_TOUCH_N5: length 171.8
  TOP w0.102: v2(14.57,94.43) 14.36,94.64 14.09,94.64 13.76,94.31 LX7.4 12.87,94.31 RX24.1
  IN3 w0.135: v2(14.57,94.43) 14.57,94.44 14.8,94.67 15.38,94.67 15.78,95.06 15.78,95.22 15.94,95.39 15.94,95.79 15.78,95.95 15.78,96.36 15.94,96.52 15.94,96.92 15.78,97.09 15.78,97.5 16.01,97.73 16.22,97.73 16.51,98.02 16.51,98.23 16.8,98.52 17.01,98.52 17.3,98.8 17.3,99.02 19.53,101.26 23.91,101.26 28.54,105.89 43.59,105.89 44.16,106.46 57.59,106.46 59.45,104.6 61.36,104.6 63.35,102.6 64.21,102.6 65.13,101.68 65.13,101.53 66.04,100.61 69.3,100.61 69.91,101.22 75.38,101.22 76.24,102.08 79.32,102.08 80.24,103.01 84.42,103.01 86.64,105.23 91.88,105.23 92.28,104.83 93.96,104.83 94.8,105.67 94.8,106.15 97.73,109.08 101.35,109.08 102.36,110.09 111.27,110.09 113.97,107.38 117.68,107.38 120.08,104.99 121.14,104.99 121.67,104.46 128.37,104.46 131.03,107.12 133.57,107.12 134.62,106.07 141.66,106.07 143.27,104.46 143.27,95.37 143.76,94.88 144.11,94.88 144.56,94.43 144.56,93 146.21,91.35 148.73,91.35 149.85,90.23 149.85,87.93 149.48,87.57 149.23,87.57 v2(148.97,87.84)
  BOTTOM w0.076: UC1.AM13 148.78,87.56 148.97,87.75 v2(148.97,87.84)
USB20_TOUCH_N5_R: length 13.1
  TOP w0.102: v2(5.43,96.36) 5.59,96.2 5.59,95.96 5.94,95.62 6.73,95.62 7.88,94.48 8.27,94.48 8.4,94.35 DX2.2 9.1,93.77 9.99,94.66 10.11,94.66 10.13,94.64 10.67,94.64 11,94.31 LX7.3 11.9,94.31 RX24.2
  BOTTOM w0.102: JEDP.28 4.08,94.45 4.14,94.39 4.14,94.29 4.21,94.22 5.01,94.22 5.8,95.01 5.8,96 5.44,96.36 v2(5.43,96.36)
USB20_TOUCH_P5: length 171.9
  TOP w0.102: RX23.1 12.85,95.16 LX7.1 13.7,95.16 14,94.86 14.39,94.86 v2(14.57,95.04)
  IN3 w0.135: v2(14.57,95.04) 14.7,94.91 15.28,94.91 15.54,95.16 15.54,97.6 19.43,101.5 23.8,101.5 28.44,106.14 43.49,106.14 44.06,106.71 57.69,106.71 59.55,104.84 61.46,104.84 63.45,102.85 64.31,102.85 65.37,101.78 65.37,101.63 66.15,100.86 69.19,100.86 69.8,101.47 75.28,101.47 76.14,102.33 79.22,102.33 80.14,103.25 84.32,103.25 86.54,105.48 91.98,105.48 92.38,105.07 93.86,105.07 94.55,105.77 94.55,106.25 97.63,109.32 101.25,109.32 102.25,110.33 111.37,110.33 114.08,107.62 117.78,107.62 120.18,105.23 121.25,105.23 121.77,104.7 128.26,104.7 130.93,107.37 133.67,107.37 134.73,106.32 141.76,106.32 143.51,104.56 143.51,95.47 143.86,95.12 144.21,95.12 144.8,94.53 144.8,93.1 146.31,91.59 148.83,91.59 150.09,90.34 150.09,87.83 149.58,87.33 149.05,87.33 v2(148.99,87.27)
  BOTTOM w0.076: UC1.AN13 148.92,87.27 v2(148.99,87.27)
USB20_TOUCH_P5_R: length 13.1
  TOP w0.102: RX23.2 11.91,95.16 LX7.2 10.9,95.16 10.61,94.87 v4(10.39,94.87) 10.06,94.87 9.24,95.7 DX2.3 8.4,94.82 8.27,94.69 7.97,94.69 6.82,95.84 6.02,95.84 5.81,96.05 5.81,96.19 5.97,96.36 v2(6.02,96.36)
  BOTTOM w0.102: v2(6.02,96.36) 6.01,96.35 6.01,94.92 5.1,94.01 4.06,94.01 4,93.95 JEDP.27
USB_DB_DET#: length 1.5
  TOP w0.102: UE4.7 94.05,16.58 93.46,17.16 T102.1
USB_OC0#: length 102.3
  TOP w0.102: v2(176.61,40.77) 176.74,40.64 194.45,40.64 195.25,39.84 UI3.3 194.66,37.76 194.38,37.48 194.38,35.73 CI15.1 ; RP55.1 171.78,84.56 168.74,87.6 168.3,87.6 167.22,88.67 164.61,88.67 164.17,88.23 v1(163.81,88.23) 163.26,88.23 v2(163.22,88.27)
  IN1 w0.114: v2(163.22,88.27) 163.99,87.51 167.04,87.51 169.28,85.26 169.28,80.98 170.17,80.09 170.17,79.33 170.78,78.72 171.15,78.72 172.91,76.95 172.91,72.68 174.71,70.89 174.71,70.01 175.35,69.36 175.35,60.44 176.23,59.57 176.23,52.32 175.98,52.08 175.98,49.86 176.98,48.87 176.98,47.67 176.42,47.11 176.42,43.35 177.06,42.71 177.06,41.21 v2(176.61,40.77)
  BOTTOM w0.076: 162.74,87.79 162.41,87.45 158.96,87.45 158.71,87.2 157.71,87.2 156.92,87.99 156.65,87.99 156.32,88.32 155.86,88.32 155.73,88.45 155.3,88.45 UC1.AL3
  BOTTOM w0.102: 162.74,87.79 v2(163.22,88.27)
USB_OC1#: length 105.6
  TOP w0.102: v2(180.04,41.35) 180.52,40.87 195.78,40.87 197.63,39.02 199.03,39.02 199.65,38.4 199.65,35.31 198.43,34.09 198.43,28.63 197.92,28.12 196.39,28.12 196.2,27.93 UI2.3 196.2,26.66 196.85,26.01 CI17.1 ; v2(158.25,84.86) v1(160.41,87.02) 161.18,87.8 167.78,87.8 168.21,87.37 168.65,87.37 171.95,84.06 RP55.2 173.03,84.06 173.22,84.25 173.22,84.79 v2(173.05,84.97)
  IN1 w0.114: v2(173.05,84.97) 173.33,84.69 173.33,79.61 175.09,77.85 175.09,73.62 177.52,71.19 177.52,68.47 178.54,67.45 178.54,64.23 177.86,63.54 177.86,61.88 178.41,61.32 178.41,56.41 179.11,55.71 179.11,54.69 179.93,53.88 179.93,53.05 181.33,51.64 181.33,47.49 180.53,46.69 180.53,44.48 179.86,43.8 179.86,41.53 v2(180.04,41.35)
  BOTTOM w0.076: UC1.AT1 157.38,84.99 157.51,84.86 v2(158.25,84.86)
USB_OC2#: length 326.2
  TOP w0.102: UI4.3 23.74,40.06 24.95,41.26 24.95,43.75 CI47.1 25.06,44.35 v1(25.06,49.18) 25.06,50.01 28.16,53.11 v2(28.16,55.7) ; RP55.3 172.85,83.56 173.11,83.3 173.11,82.81 172.71,82.41 172.39,82.41 172.01,82.03 172.01,81.54 170,79.53 v2(169.42,79.53)
  IN1 w0.114: v2(162.97,11.23) 162.53,11.67 162.53,16.57 163.72,17.77 164.13,17.77 166.17,19.81 166.17,23.39 167.92,25.14 169.42,25.14 170.12,25.83 170.12,27.34 174.95,32.17 174.95,38.59 175.89,39.53 175.89,42.74 175.94,42.79 175.94,47.63 175.89,47.68 175.89,49.28 175.5,49.66 175.5,52.28 175.74,52.52 175.74,59.37 174.87,60.24 174.87,69.16 174.22,69.81 174.22,70.68 172.43,72.47 172.43,76.75 170.96,78.22 170.55,78.22 169.42,79.35 v2(169.42,79.53) 168.76,80.19 164.65,80.19 162.8,82.04 162.8,87.25 161.98,88.06 v2(161.98,88.27)
  IN3 w0.135: v2(162.97,11.23) 163.55,10.64 163.55,8.79 161.98,7.22 155.54,7.22 155.26,6.94 141.77,6.94 141.57,6.74 135.87,6.74 133.12,9.49 130.75,9.49 129.29,10.95 117.58,10.95 114.1,14.43 105.72,14.43 104.68,13.39 94.88,13.39 93.37,14.9 89.24,14.9 87.81,16.33 82.01,16.33 79.79,18.56 78.03,18.56 77.16,19.43 77.16,23.22 78.08,24.15 78.08,41.79 74.38,45.49 v2(74.38,47.35)
  BOTTOM w0.076: UC1.AH2 155.95,89.98 156.33,89.98 156.59,89.72 160.53,89.72 v2(161.98,88.27)
  BOTTOM w0.102: v2(74.38,47.35) 73.92,47.81 73.92,56.18 75.54,57.81 75.54,64.79 73.42,66.92 67.68,66.92 64.39,70.21 53.12,70.21 48.19,65.28 48.19,63.3 43.08,58.19 37.91,58.19 37.33,58.78 32.92,58.78 30.64,56.49 28.45,56.49 28.16,56.2 v2(28.16,55.7)
USB_OC3#: length 21.7
  TOP w0.102: RP55.4 171.87,83.06 171.38,83.56 171.38,84.31 168.55,87.14 168.11,87.14 167.68,87.57 161.89,87.57 v1(159.47,85.15) 158.78,84.46 158.4,84.46 v2(158.02,84.08)
  BOTTOM w0.076: UC1.AV3 155.14,84 157.94,84 v2(158.02,84.08)
USB_PWR_EN1#: length 122
  TOP w0.102: v2(104.74,27.61) 104.74,27.4 v1(104.37,27.03) 104.37,24.87 103.94,24.44 102.75,24.44 102.54,24.23 RPE9.2 102.54,23.54 101.78,22.79 101.78,19.87 101.49,19.58 UE4.30 ; v2(162.28,27.5) 162.28,27.33 162.58,27.04 163.29,27.04 164.06,27.82 174.64,27.82 176.57,29.75 185.71,29.75 186.41,30.44 188.33,30.44 188.72,30.83 190.9,30.83 193.27,28.46 196.14,28.46 196.7,29.02 196.7,30.7 194.02,33.38 194.02,34.15 CI13.1 193.78,35.33 193.78,37.25 193.27,37.76 UI3.4
  IN1 w0.114: v2(162.28,27.5) 162.2,27.5 160.2,29.49 125.49,29.49 124.65,28.66 124.65,27.23 123.89,26.47 115.39,26.47 114,27.86 106.9,27.86 105.59,26.55 105,26.55 104.73,26.82 104.73,27.59 v2(104.74,27.61)
USB_PWR_EN2#: length 152.3
  TOP w0.102: v2(49.51,71.53) 49.56,71.48 v1(49.56,70.7) 49.56,66.66 48.39,65.49 48.39,62.03 44.51,58.14 44.04,58.14 43.66,57.76 37.97,57.76 37.13,58.6 30.47,58.6 27.51,55.64 27.51,53.31 22.41,48.21 22.41,43.6 CI46.1 23.37,43.09 23.74,42.73 UI4.4 ; UE4.31 99.84,20.87 101.17,22.2 101.17,22.8 102.04,23.68 RPE9.1 102.04,24.08 101.58,24.54 98.22,24.54 v2(98.15,24.61)
  IN3 w0.135: v2(98.15,24.61) 98.15,26.23 97.15,27.23 95.76,27.23 90.15,32.84 89.83,32.84 85.35,37.32 85.35,43.24 84.56,44.02 84.56,45.81 82.95,47.42 82.95,51.5 89.39,57.93 89.39,64.66 86.55,67.49 76.58,67.49 73.85,70.22 67.43,70.22 66.3,71.35 49.69,71.35 v2(49.51,71.53)
USB_PWR_EN3#: length 119.1
  TOP w0.102: 104.83,22.91 v1(104.83,25.14) 104.83,26.57 v2(105.28,27.02) ; 104.83,22.91 103.37,22.91 103.04,23.25 RPE9.3 ; 104.83,22.91 105.85,22.91 106.46,22.3 106.46,17.25 105.8,16.59 102.7,16.59 102.21,17.08 100.57,17.08 UE4.25 ; v2(162.87,27.49) 162.87,27.53 163.38,28.04 174.55,28.04 176.48,29.97 185.61,29.97 186.31,30.67 188.23,30.67 188.93,31.37 189.56,31.37 CI26.1 193.23,28.82 196.02,28.82 196.2,29 UI2.4
  IN1 w0.114: v2(162.87,27.49) 162.87,27.56 160.6,29.83 125.49,29.83 124.41,28.76 124.41,27.33 123.8,26.72 115.68,26.72 114.18,28.22 106.48,28.22 v2(105.28,27.02)
USBRBIAS: length 13.3
  TOP w0.102: v2(149.01,88.4) 148.85,88.24 148.53,87.92 148.53,85.24 149.41,84.36 149.41,83.43 150.11,82.73 v1(150.11,81.99) 150.11,81.3 149.89,81.08 149.89,78.34 149.61,78.06 RC90.1
  BOTTOM w0.076: v2(149.01,88.4) 149.47,88.86 UC1.AJ11 UC1.AJ10
VCI_IN1#: length 37.7
  TOP w0.102: v2(144.38,10.75) 144.23,10.9 144.23,11.53 144.61,11.92 UE5.A63 ; v1(158.07,25.17) v2(157.56,25.17) 157.28,25.45 156.39,25.45 156.26,25.32 RPE5.3
  BOTTOM w0.102: v2(144.38,10.75) 144.25,10.87 144.15,10.87 142.09,12.93 142.09,14 141.74,14.35 140.21,14.35 139.48,15.09 139.48,16.98 140.72,18.22 140.72,22.41 142.37,24.06 145.09,24.06 145.66,23.48 148.15,23.48 149.79,25.12 157.51,25.12 v2(157.56,25.17)
VCI_IN2#: length 28.3
  TOP w0.102: v1(158.98,24.25) 158.77,24.46 157.47,24.46 157.18,24.75 157.18,25.01 156.98,25.2 156.84,25.2 156.76,25.12 RPE5.4 156.76,24.17 v2(156.7,24.11) ; v2(146.97,14.38) 146.94,14.35 146.94,14.1 146.51,13.67 UE5.B63
  BOTTOM w0.102: v2(156.7,24.11) 156.34,23.75 155.55,23.75 155.27,23.47 155.27,22.23 155.81,21.7 155.81,21.31 155.55,21.06 155.2,21.06 154.51,21.74 153.42,21.74 152.33,20.65 150.05,20.65 149.44,20.05 148.89,20.05 148.32,19.48 148.32,18.55 148.04,18.26 147.55,18.26 147.12,18.7 146.08,18.7 145.7,18.32 145.7,16.51 146.21,16 147.53,16 147.76,15.77 147.76,15.36 147.73,15.33 147.73,15.14 v2(146.97,14.38)
VCI_IN3#: length 37.5
  TOP w0.102: v2(155.99,24.16) 155.76,24.38 RPE5.2 ; v2(145.17,10.37) 145.29,10.49 145.29,11 145.46,11.17 UE5.B68 ; v1(142.5,23.09) 141.57,24.02 v2(141.57,24.07)
  IN3 w0.135: v2(141.57,24.07) 142.13,23.51 143.35,23.51 144.2,24.36 146.73,24.36 147.27,23.81 151.13,23.81 151.27,23.68 155.25,23.68 155.73,24.16 v2(155.99,24.16)
  BOTTOM w0.102: v2(145.17,10.37) 145.06,10.26 144.25,10.26 141.86,12.65 141.86,13.9 141.64,14.12 140.06,14.12 139.25,14.94 139.25,17.07 140.49,18.32 140.49,22.94 141.57,24.02 v2(141.57,24.07)
VGA_ID: length 9.3
  TOP w0.102: UE4.19 99.34,13.87 99.7,13.52 100.72,13.52 102.37,15.17 RE90.1 103.03,14.61 103.69,14.61 RE89.1 104.25,15.14 104.7,14.68 105.5,14.68 106.32,15.5 v1(106.32,15.55)
VL: length 2.6
  TOP w0.203: PC106.1 47.97,28.54 v1(49.06,28.54) PU100.13
VR12.5_VR_ON_R: length 11.1
  TOP w0.102: v2(119.13,101.9) 119.6,101.42 119.92,101.42 120.5,102.01 120.5,103.08 v1(118.65,104.93) 115.88,107.7 R250.2
  BOTTOM w0.076: v2(119.13,101.9) 119.13,101.85 UC1.F60
VR_HOT#_1: length 4
  TOP w0.102: v1(66.11,102.69) 66.37,102.96 66.37,104.19 PR510.2
  TOP w0.254: PR510.2 66.83,105.51 66.57,105.77 PU501.4
VR_ON: length 67.9
  TOP w0.102: v2(116.69,111.79) 115.04,110.14 115.04,109.83 C80.1 R250.1 116.23,109.78 116.26,109.81 RC364.2 ; PR511.1 64.47,103.74 v1(63.96,104.24) v2(63.96,105.29)
  IN2 w0.127: v2(73.82,110.09) 73.85,110.05 73.85,107.89 70.41,104.45 64.8,104.45 v2(63.96,105.29)
  IN3 w0.135: v2(73.82,110.09) 75.49,108.41 83.36,108.41 83.91,108.96 90.54,108.96 91.16,109.58 93.86,109.58 96.52,112.24 99.17,112.24 100.18,113.26 103.81,113.26 105.08,114.53 106.28,114.53 107.57,113.24 115.24,113.24 v2(116.69,111.79)
VR_ON_1: length 4.3
  TOP w0.102: PR511.2 64.79,104.65 64.48,104.96 64.48,105.34 64.13,105.69 63.47,105.69 v1(63.17,105.4)
  TOP w0.254: PU501.1 65.07,104.69 PR511.2
VR_READY_R: length 6.9
  BOTTOM w0.076: v1(118.29,108.49) 118.01,108.21 118.01,107.39 119.74,105.66 119.74,104.78 119.95,104.57 119.95,104.21 120.11,104.05 120.11,103.81 UC1.C59
  BOTTOM w0.102: R251.2 118.55,108.74 v1(118.29,108.49)
VR_SVID_ALRT#: length 58
  TOP w0.254: v2(82.17,105.59) 82.7,105.59 84.56,103.74 v1(88.96,103.74) 90.1,103.74 90.99,102.85 90.99,101.97 92.69,100.27 92.69,97.79 v2(93.1,97.39)
  IN1 w0.254: v2(82.17,105.59) 82.17,106.27 79.28,109.16 74.67,109.16 70.59,105.08 66.97,105.08 66.48,104.59 62.91,104.59 61.4,106.1 61.4,106.95 60.8,107.55 v2(60.43,107.55)
  BOTTOM w0.203: v2(93.1,97.39) 93.1,97.31 95.9,94.5 100.82,94.5 102.34,96.01 R252.2 103.86,96.01 104.07,96.22 R254.2
  BOTTOM w0.254: v2(60.43,107.55) 60.89,107.55 PR506.1
VR_SVID_CLK: length 56.2
  TOP w0.254: v2(82.66,104.68) 82.66,104.63 84.26,103.02 89.78,103.02 90.28,102.53 90.28,101.68 v1(90.74,101.21) 91.98,99.97 91.98,97.5 92.51,96.96 v2(92.51,96.9)
  IN1 w0.254: v2(82.66,104.68) 82.88,104.9 82.88,106.56 79.57,109.87 74.36,109.87 70.34,105.84 62.66,105.84 62.11,106.39 62.11,107.25 61.1,108.26 60.79,108.26 60.76,108.28 v2(60.43,108.28)
  BOTTOM w0.203: v2(92.51,96.9) 92.57,96.9 95.63,93.84 101.32,93.84 101.52,94.03 R248.1
  BOTTOM w0.254: PR508.1 60.41,108.26 v2(60.43,108.28)
VR_SVID_DAT: length 55.9
  TOP w0.254: v2(81.39,105.89) 81.84,106.35 82.95,106.35 84.85,104.45 v1(85.65,104.45) 90.96,104.45 91.77,103.64 91.77,102.21 93.45,100.52 93.45,98.35 v2(93.55,98.25)
  IN1 w0.254: v2(60.48,106.86) 60.48,105.99 61.03,105.44 62.6,103.88 66.95,103.88 67.39,104.32 70.86,104.32 74.99,108.45 78.99,108.45 81.39,106.05 v2(81.39,105.89)
  BOTTOM w0.203: R257.2 100.55,95.16 96.28,95.16 93.53,97.92 93.53,98.22 v2(93.55,98.25)
  BOTTOM w0.254: PR505.1 61.12,106.23 v2(60.48,106.86)
VSET_5085: length 2.8
  TOP w0.102: RE77.1 CE55.1 157.36,11.23 157.1,10.98 156.47,10.98 156.03,11.42 UE5.A17
VSYNC: length 7.1
  TOP w0.102: v1(193.73,109.34) 193.48,109.34 192.9,108.77 192.07,108.77 v2(191.93,108.91)
  TOP w0.107: v2(196.83,108.69) 196.75,108.77 194.3,108.77 v1(193.73,109.34)
  BOTTOM w0.102: RV171.1 197.34,108.18 v2(196.83,108.69) ; v2(191.93,108.91) 191.75,109.09 UV6.3
VSYNC_CONN: length 6.8
  BOTTOM w0.102: JCRT.14 205.94,111.63 204.8,110.49 CV58.1 RV37.2 201.98,110.49 LV20.2 v1(201.52,108.68)
VSYNC_CRT: length 4.3
  BOTTOM w0.102: UV3.4 199.79,110.56 200.31,110.04 LV20.1 200.67,111.23 199.99,111.91 v1(199.42,111.91)
VSYNC_R: length 3.3
  BOTTOM w0.102: v1(198.25,107.18) RV171.2 198.25,109.58 197.92,109.91 UV3.2
VTTREF_1.35V: length 2.7
  BOTTOM w0.203: PU200.4 58.44,29.94 58.35,29.85 58.35,28.81 PC210.1
WLAN_CLKREQ#: length 93.4
  IN1 w0.114: v2(167.43,96.76) 168.63,95.56 174.11,95.56 175.38,94.29 175.38,93.4 175.46,93.32 175.46,87.22 177.26,85.43 177.26,74.56 182.34,69.48 182.34,66.9 182.01,66.57 182.01,65.24 183.03,64.22 183.03,57.95 185.13,55.84 185.13,54.08 185.72,53.49 185.72,51.12 184.18,49.58 184.18,45.39 184.54,45.04 184.54,42.76 v2(185.79,41.51)
  BOTTOM w0.076: UC1.N1 156.24,97.87 162.03,97.87
  BOTTOM w0.102: JNGFF.45 185.48,41.82 v2(185.79,41.51) ; 162.03,97.87 163.58,97.87 164.21,97.23 v1(165.52,97.23) 167.1,97.23 167.43,96.91 v2(167.43,96.76) 168.09,96.76 169.28,97.96 170.68,97.96 171.62,97.02 171.62,91.3 172.03,90.89 172.03,90.39 R2342.2
WLAN_LAN_DISBL: length 12.5
  TOP w0.102: v1(179.61,98.25) 179.86,98.25 v2(180.14,97.97) 179.9,97.73 Q9.2
  BOTTOM w0.102: UL1.26 179.63,90.74 180.25,91.35 180.25,91.52 181.03,92.31 181.03,93.18 180.14,94.07 v2(180.14,97.97)
WLAN_LAN_DISBL#: length 181.2
  TOP w0.102: Q9.1 178.93,92.89 178.74,92.7 R11.2 177.78,92.14 176.84,93.08 v1(175.76,93.08) 175.12,93.08 v2(174.74,92.7) ; UE4.13 96.34,13.56 96.66,13.24 v2(96.66,11.48)
  IN1 w0.114: v2(174.74,92.7) 175.22,92.22 175.22,87.1 177.02,85.3 177.02,74.46 182.1,69.38 182.1,67 181.77,66.67 181.77,65.14 182.79,64.12 182.79,57.85 184.89,55.74 184.89,53.98 185.48,53.39 185.48,51.22 183.94,49.68 183.94,45.29 184.29,44.93 184.29,40.83 183.37,39.91 182.18,39.91 179.09,36.81 179.09,28.03 176.62,25.57 175.66,25.57 172.86,22.77 172.86,18.11 169.35,14.6 169.35,14.48 167.52,12.66 167.49,12.66 164.31,9.48 164.13,9.48 163.31,8.66 161.59,8.66 159.81,10.44 157.86,10.44 157.3,9.88 154.19,9.88 152.36,8.05 145.46,8.05 144.54,8.97 144.54,9.29 143.36,10.47 142.08,10.47 141.36,11.19 138.78,11.19 138.51,10.93 138.51,10.71 137.51,9.71 135.44,9.71 134.62,8.89 132.38,8.89 130.34,10.94 97.21,10.94 v2(96.66,11.48)
WLAN_WIGIG60GHZ_DIS#: length 135.6
  TOP w0.102: v2(107.62,9.17) 105.74,9.17 v1(104.05,10.87) 102.54,12.37 RE14.2 99.8,12.37 98.34,13.83 UE4.17
  IN1 w0.114: v2(189.67,47.86) 190.1,47.42 190.1,46.89 192.24,44.75 192.24,34.72 191.77,34.26 191.77,32.77 189.77,30.76 188.93,30.76 185.32,27.15 185.32,24.49 185.02,24.18 183.43,24.18 182.95,23.71 181.12,23.71 180.34,22.92 180.34,21.93 179.86,21.45 179.38,21.45 178.92,21 178.92,18.33 177.99,17.41 177.99,15.12 177.6,14.72 177.17,14.72 167.19,4.74 132.11,4.74 130.51,6.34 110.46,6.34 v2(107.62,9.17)
  BOTTOM w0.102: v2(189.66,47.86) 189.67,47.86 189.64,47.88 187.77,47.88 186.22,49.42 186.22,50.22 JNGFF.48
XDP_DBRESET#: length 137.5
  TOP w0.102: v2(84.1,88.59) 84.1,87.84 v1(84.33,87.61) 84.79,87.15 84.79,83.9 84.03,83.14 RC362.2 CC17.1 84.26,81.44 84.26,80.55 84.64,80.16 JXDP.48 ; UC5.1 173.62,108.05 173.21,108.46 173.21,109.95 RC78.1 173.68,111.75 v2(173.54,111.89)
  IN1 w0.114: v2(147.08,120.16) 147.08,120 146.51,119.43 145.19,119.43 144.9,119.73 116.78,119.73 115.21,118.15 115.21,117.06 110.65,112.5 105.67,112.5 102.49,109.32 95.59,109.32 91.48,105.22 87.62,105.22 81.61,99.21 80.83,99.21 80.01,100.03 v2(80.01,100.18)
  IN3 w0.135: v2(80.01,100.18) 80.01,99.98 82.06,97.93 83.28,97.93 83.9,97.31 83.9,93.4 82.96,92.46 82.96,89.73 v2(84.1,88.59)
  BOTTOM w0.102: v2(147.08,120.16) 148.72,118.52 160.68,118.52 166.8,112.4 173.03,112.4 v2(173.54,111.89)
XDP_OBS0_R: length 62.1
  TOP w0.102: v2(89.67,74.07) 90.07,73.66 JXDP.21
  IN3 w0.135: v2(89.67,74.07) 89.38,74.36 83.66,74.36 82.72,75.3 82.72,77.52 83.66,78.47 84.67,78.47 85.88,79.68 85.88,82.15 92.13,88.39 92.13,90.48 96.84,95.19 100.17,95.19 100.86,95.88 108.75,95.88 112.62,99.75 113.42,99.75 115.02,101.35 116.08,101.35 116.31,101.12 v2(116.31,100.76)
  BOTTOM w0.076: UC1.J60 119.17,99.72 118.69,99.72 118.65,99.76 118.63,99.76 118.63,99.76 117.97,99.76 117.97,99.76 117.87,99.76 117.7,99.59 117.33,99.59 116.79,100.13 116.79,100.21 116.29,100.71 116.29,100.74 v2(116.31,100.76)
XDP_OBS1_R: length 61.9
  TOP w0.102: v2(89.44,75.69) 90,75.14 90,74.53 90.36,74.16 JXDP.23
  IN3 w0.135: v2(119.16,100.43) 119.16,100.42 117.91,99.16 117.91,97.13 117.15,96.37 113.79,96.37 113.45,96.71 110.38,96.71 108.67,94.99 105.09,94.99 104.86,95.23 103.65,95.23 102.76,94.33 96.79,94.33 93,90.54 93,87.93 86.47,81.4 86.47,79.45 84.95,77.94 83.88,77.94 83.24,77.31 83.24,75.52 83.88,74.88 87.99,74.88 88.8,75.69 v2(89.44,75.69)
  BOTTOM w0.076: UC1.H60 119.46,100.73 v2(119.16,100.43)
XDP_PRDY#: length 65.8
  TOP w0.102: v2(89.46,73.51) 89.36,73.41 89.36,70.87 89.95,70.28 89.95,70 90.29,69.66 JXDP.5
  IN3 w0.135: v2(89.46,73.51) 88.88,74.1 83.55,74.1 82.44,75.21 82.44,77.61 83.55,78.73 84.52,78.73 85.6,79.81 85.6,82.3 91.83,88.52 91.83,90.63 96.65,95.46 100.06,95.46 100.75,96.14 108.64,96.14 112.51,100.01 113.31,100.01 114.91,101.61 116.19,101.61 116.74,101.06 116.74,100.84 v2(116.9,100.69)
  BOTTOM w0.076: UC1.J62 117.92,100.05 117.65,99.77 117.38,99.77 117.05,100.11 117.05,100.54 v2(116.9,100.69)
  BOTTOM w0.102: v2(89.46,73.51) v1(88.82,73.51)
XDP_PREQ#: length 91.1
  TOP w0.102: JXDP.3 92.66,69.16 v2(93.43,69.93) ; RP44.3 117.51,114.97 114.38,111.83 114.38,107.06 115.78,105.66 115.78,104.83 116.76,103.85 v1(117.48,103.85) 119.37,103.85 120.27,102.95 120.27,102.62 119.97,102.31 118.13,102.31 117.08,101.27 114.96,101.27 114.53,100.84 v2(114.53,100.21)
  IN3 w0.135: v2(114.53,100.21) 113.82,99.49 112.73,99.49 108.86,95.62 100.97,95.62 100.24,94.9 96.98,94.9 92.46,90.38 92.46,88.27 86.16,81.97 86.16,79.53 84.84,78.2 83.77,78.2 82.98,77.42 82.98,75.41 83.77,74.62 89.75,74.62 93.43,70.94 v2(93.43,69.93)
  BOTTOM w0.076: UC1.K62 117.97,99.11 117.7,98.84 117.34,98.84 116.18,100 114.74,100 v2(114.53,100.21)
XDP_RST#_R: length 5.1
  TOP w0.102: v1(81.56,80.6) 82.99,80.6 83.5,81.11 RC51.2 84.03,80.65 84.03,80.29 84.66,79.66 JXDP.46
XDP_TCLK: length 78.6
  TOP w0.102: v2(119.05,102.76) 118.25,102.76 116.99,101.5 113.77,101.5 v2(113.57,101.7) 113.26,102.01 113.26,105.6 112.09,106.77 112.09,110.64 115.09,113.64 RC371.1 ; v2(95.76,85.7) 95.34,86.12 v3(94.56,86.12) 92.62,86.12 89.97,83.47 89.97,82.93 90.24,82.66 JXDP.57
  IN1 w0.114: v2(91.39,89.59) 91.52,89.59 95.41,85.7 v2(95.76,85.7)
  IN3 w0.135: v2(91.39,89.59) 91.39,89.66 91.42,89.69 91.42,90.65 92.87,92.1 92.87,94.34 94.39,95.86 94.39,95.88 94.5,95.99 99.86,95.99 100.53,96.67 108.33,96.67 112.2,100.54 112.99,100.54 113.57,101.11 v2(113.57,101.7)
  BOTTOM w0.076: UC1.E60 119.46,102.35 119.05,102.76 119.05,102.76 v2(119.05,102.76)
  BOTTOM w0.102: RC59.1 RC65.1 103.71,90.1 102.79,89.18 99.24,89.18 v2(95.76,85.7)
XDP_TDI: length 49.7
  TOP w0.102: v2(114.58,102.14) 114.61,102.11 115.48,102.11 116.36,102.99 116.36,103.56 115.55,104.37 115.55,105.56 114.15,106.96 114.15,111.93 117.01,114.79 RP44.2 ; v2(93.32,93.45) 93.17,93.3 v3(92.56,93.3) 91.7,93.3 91.42,93.58 91.01,93.58 89.83,92.4 UC4.6
  IN3 w0.135: v2(114.58,102.14) 114.58,101.75 113.1,100.27 112.3,100.27 108.44,96.41 100.64,96.41 99.96,95.72 95.6,95.72 v2(93.32,93.45)
  BOTTOM w0.076: v2(114.58,102.14) 114.58,102.16 115.1,101.65 117.42,101.65 117.51,101.56 UC1.F63
XDP_TDO: length 50.1
  TOP w0.102: v2(90.91,91.11) 90.7,90.9 UC4.3 ; RC366.1 114.18,113.16 111.87,110.85 111.87,106.33 v3(112.18,106.01) 113.03,105.16 v2(113.03,101.32)
  IN3 w0.135: v2(90.91,91.11) 90.96,91.16 90.96,91.49 92.46,92.99 92.46,94.34 94.38,96.26 99.75,96.26 100.42,96.93 108.21,96.93 109.78,98.5 109.78,98.52 112.59,101.32 v2(113.03,101.32)
  BOTTOM w0.076: 113.51,101.22 114.48,101.22 114.74,101.48 117.15,101.48 117.35,101.27 117.73,101.27 118.01,101.55 UC1.F62
  BOTTOM w0.102: v2(113.03,101.32) 113.14,101.22 113.51,101.22
XDP_TMS: length 52.5
  TOP w0.102: UC4.8 88.02,93.5 88.32,93.8 89.54,93.8 v2(89.59,93.75) ; RP44.1 116.51,114.67 113.92,112.08 113.92,106.81 115.07,105.67 115.07,103.86 v3(115.45,103.48) v2(115.85,103.08)
  IN3 w0.135: v2(115.85,103.08) 115.17,103.76 112.98,103.76 108.01,98.79 103.6,98.79 103.34,98.53 101.5,98.53 100.21,99.82 94.47,99.82 89.59,94.95 v2(89.59,93.75)
  BOTTOM w0.076: v2(115.85,103.08) 116.26,102.67 118.48,102.67 UC1.E61
XDP_TRST#: length 58.6
  TOP w0.102: UC4.11 86.24,91.4 v2(86.16,91.32) ; RC57.1 113.16,109.43 113.16,109.4 RC129.2 112.58,108.54 113.01,108.1 113.01,106.53 113.64,105.9 v3(113.64,104.46) 113.64,102.21 114.13,101.73 116.9,101.73 118.37,103.2 119.21,103.2 119.64,102.77 v2(119.74,102.77)
  IN3 w0.135: v2(119.74,102.77) 119.74,102.64 119.44,102.34 118.67,102.34 116.69,104.32 113.16,104.32 108.59,99.75 103.89,99.75 103.03,98.88 101.52,98.88 100.27,100.13 94.4,100.13 90.21,95.94 89.77,95.94 86.16,92.33 v2(86.16,91.32)
  BOTTOM w0.076: UC1.E59 120.11,102.4 v2(119.74,102.77)
XTAL24_IN: length 16.7
  BOTTOM w0.076: UC1.A25 141.55,105.11 141.55,105.79 141.94,106.17 141.94,106.33
  BOTTOM w0.102: 141.94,106.33 141.94,107.81 140.28,109.48 v1(139.68,109.48) 138.83,109.48 137.81,110.5 135.87,110.5 135.56,110.8 135.56,111.01 RC12.2 CC6.2 134.9,111.86 135.44,111.86 135.53,111.95 135.53,113.98 135.16,114.35 YC2.3
XTAL24_OUT: length 15.8
  BOTTOM w0.076: 142.15,106.31 142.15,106.14 141.72,105.71 141.72,104.86 141.43,104.57 UC1.B25
  BOTTOM w0.102: 142.15,106.31 142.15,107.93 140.31,109.77 139.01,109.77 v1(138.37,110.4) 138.05,110.73 135.97,110.73 135.8,110.89 135.8,110.99 RC12.1 CC7.2 136.51,111.84 135.97,111.84 135.81,112 135.81,112.34 136.11,112.65 YC2.1
XTALOUTBUFF: length 7.3
  TOP w0.102: v2(66.96,95.33) 66.96,96.57 68.1,97.72 v1(68.1,98.2) 70.16,100.26 RV39.1
  BOTTOM w0.102: UV1.C10 67.38,95.75 v2(66.96,95.33)
XTALSSIN: length 4.1
  TOP w0.102: RV23.1 69.27,100.28 v1(68.64,99.65) 67.39,98.4 v2(67.39,98)
  BOTTOM w0.102: UV1.A10 67.38,97.99 v2(67.39,98)
XTLI: length 7
  BOTTOM w0.102: YL2.1 184.29,94.33 184.29,93.51 CL36.2 183.39,92.61 183.02,92.61 182.66,92.24 v1(182.66,92.14) 182.66,92.09 180.95,90.39 180.95,89.84 180.83,89.72 UL1.29
XTLO: length 8.5
  BOTTOM w0.102: YL2.3 183.06,95.16 183.06,93.42 CL37.2 182.05,92.41 182.05,92.24 v1(180.52,90.72) 180.43,90.63 UL1.28
N71037: length 4.2
  TOP w0.102: UA1.8 183.57,19.23 182.37,19.23 182.2,19.05 179.47,19.05 RA130.2
N71249: length 10.7
  TOP w0.203: CA62.2 191.36,17.2 v2(190.83,17.73) 190.83,17.76 190.17,18.42 UA1.27
  TOP w0.254: v2(195.3,16.58) 195.83,17.1 196.08,17.1 196.59,17.6 RA1129.2
  IN1 w0.508: v2(190.83,17.73) 191.7,16.86 193.11,16.86 193.53,17.27 194.85,17.27 195.3,16.82 v2(195.3,16.58)
  BOTTOM w0.102: v1(191.74,18.2) 191.3,18.2 v2(190.83,17.73)
N71261: length 2.3
  TOP w0.203: CA63.2 189.07,23.98 188.7,23.98 188.02,23.3 UA1.39
N71273: length 1.9
  TOP w0.102: UA1.7 183,19.62 182.81,19.43 182.48,19.43 182.17,19.74 CA64.2
N71383: length 5.5
  TOP w0.203: v2(192.37,23.43) 192.09,23.15 v1(191.67,23.15) 190.97,23.15 190.71,22.89 190.15,22.89 189.97,23.07 189.4,23.07 189.21,22.87 UA1.37
  BOTTOM w0.254: v2(192.37,23.43) 192.09,23.15 192.09,22.47 192.31,22.25 CA24.1
N71395: length 3.6
  TOP w0.102: UA1.35 190.03,21.62 190.03,21.62 190.3,21.9 190.3,22.38 190.53,22.61 191.08,22.61 v2(191.15,22.68)
  BOTTOM w0.102: CA24.2 191.39,22.44 v2(191.15,22.68) 191.15,22.71 v1(191.58,23.14)
N71399: length 3.7
  TOP w0.102: UA1.34 190.09,21.22 190.25,21.39 190.25,21.52 190.56,21.83 190.56,22.02 v2(190.73,22.2)
  BOTTOM w0.102: v1(190.15,21.96) 190.39,22.2 v2(190.73,22.2) 190.73,21.8 CA25.2
N71447: length 2.5
  TOP w0.203: UA1.28 190.24,18.82 190.47,18.6 v1(190.97,18.6) 191.84,18.6 CA23.2
N71593: length 3.7
  TOP w0.102: UA1.12 183.57,17.22 181.26,14.91 CA65.1
N76526: length 6.4
  TOP w0.102: v1(178.76,20.33) 179.01,20.59 RA1113.2 179.38,21.71 179.85,21.24 182.47,21.24 182.88,20.82 UA1.4
N3691692: length 2.7
  TOP w0.102: v1(44.82,52.52) PR1001.2
  TOP w0.508: PR1001.2 PC1004.1
N3691782: length 2.7
  TOP w0.102: PC1009.1 v1(33.13,45.98)
  TOP w0.508: PC1009.1 33.13,48.3 PR1004.2
N15534060: length 5
  TOP w0.102: v1(35.5,17.54) 35.26,17.3 PC747.1
  TOP w0.254: PC747.1 35.34,16.54 35.87,16 v2(35.87,15.81) 36.12,16.06 PR705.2
  BOTTOM w0.203: v2(35.87,15.81) 35.38,15.32 PU700.1
  BOTTOM w0.254: v2(35.87,15.81) 35.94,15.88 PC746.2
N15534062: length 5.3
  TOP w0.254: PC745.2 35.45,15.47 v2(35.87,15.05) 36.01,15.19 PR738.2
  BOTTOM w0.102: PC746.1 37.23,15.56 37.23,15.98 v1(37.58,16.33)
  BOTTOM w0.203: v2(35.87,15.05) 35.74,14.92 PU700.2
  BOTTOM w0.254: v2(35.87,15.05) 36.54,15.05 PC746.1
N15534082: length 21.5
  TOP w0.254: v2(27.64,15.9) 28.17,16.44 v1(28.63,16.44) 29.76,16.44 PC726.2
  IN3 w0.254: v2(24.31,25.2) 24.12,25.01 24.12,24.34 22.27,22.49 22.27,19.83 26.55,15.55 27.28,15.55 v2(27.64,15.9)
  BOTTOM w0.203: PU700.20 29.99,14.92 29.95,14.89 28.99,14.89 PC727.1
  BOTTOM w0.254: PR710.2 23.98,24.87 v2(24.31,25.2) ; PC727.1 28.02,15.85 27.69,15.85 v2(27.64,15.9)
N15534214: length 3.6
  BOTTOM w0.102: v1(37.57,14.96) 37.51,14.9 37.43,14.9 PR730.2
  BOTTOM w0.203: PR730.2 36.31,14.26 36.31,14.33 36.06,14.58 35.29,14.58 35.23,14.52 PU700.3
N15534246: length 6.1
  TOP w0.102: PR715.1 35.69,11.84 v2(35.95,11.58) 35.97,11.61 PR713.2
  BOTTOM w0.203: PU700.5 35.48,13.72 35.54,13.67 36.03,13.67 36.54,13.16 PR714.2 36.54,12.92 37.02,12.44 v1(37.02,12.16) 37.02,12.03 36.8,11.8 36.16,11.8 v2(35.95,11.58)
N15534264: length 3.4
  TOP w0.203: 35.89,12.58 35.77,12.7 PC718.1 ; 35.9,12.58 36,12.47 PR716.2 ; 35.9,12.58 v2(35.9,12.58)
  BOTTOM w0.102: v2(35.9,12.58) 35.9,12.21 v1(35.75,12.07)
  BOTTOM w0.203: v2(35.9,12.58) 35.89,12.58 35.89,12.6 35.87,12.58 35.51,12.58 35.16,12.92 PU700.7
N15534266: length 4.7
  TOP w0.102: v1(36.14,10.7) 35.72,11.11 34.76,11.11 PR718.2
  TOP w0.254: PR718.2 33.89,11 v2(33.89,11.25) 33.79,11.36 33.79,11.58 PC719.1
  BOTTOM w0.203: PU700.8 33.84,12.07 33.84,11.31 v2(33.89,11.25)
N15534276: length 2.6
  TOP w0.254: PR720.2 33.3,10.64 v2(33.3,11.25) 33.13,11.25 32.77,11.61 32.77,11.74 PR732.1
  BOTTOM w0.203: v2(33.3,11.25) 33.33,11.23 33.44,11.34 PU700.9
N15534316: length 5.1
  BOTTOM w0.102: PR717.2 36.4,11 v1(35.04,11) 34.4,11 34.17,10.77 33.15,10.77 32.88,11.04 32.88,11.39 33.04,11.55 PU700.10
N15534326: length 4.1
  TOP w0.102: PR725.2 29.06,12.88 v1(27.96,11.78)
  TOP w0.254: PR725.2 29.57,12.88 v2(29.7,13.01) 29.72,13.03 30.12,13.03 PR729.1
  BOTTOM w0.203: v2(29.7,13.01) 29.7,12.93 30.09,13.32 PU700.16
N15534338: length 3.3
  BOTTOM w0.102: PR728.2 28.83,11.61 28.68,11.46 v1(28.68,10.9)
  BOTTOM w0.203: PU700.15 30.45,12.92 29.52,11.99 PR728.2
N15534350: length 4.2
  BOTTOM w0.102: v1(27.08,14.66) 27.3,14.44 27.54,14.44 27.97,14.01 28.3,14.01 28.8,13.52 PR704.1
  BOTTOM w0.203: PR704.1 29.44,14.12 PU700.18
N16995670: length 9.7
  IN1 w0.254: v4(44.34,47.83) 44.95,47.22 44.95,44.31 44.53,43.89 v4(44.39,43.89)
  BOTTOM w0.254: v4(44.39,43.89) 44.49,43.89 44.85,44.25 PR603.2 PR602.2 v1(46.17,42.36) 46.6,41.92 PR604.1 ; PC607.1 44.39,47.88 v4(44.34,47.83)
N17002494: length 3
  TOP w0.102: v1(66.13,56.1) 66.67,55.56 PC614.1
  TOP w0.508: PC614.1 67.03,54.66 67.33,54.96 PR613.2
N17002564: length 2.9
  TOP w0.102: PC625.1 62.86,55.93 v1(63.06,56.14)
  TOP w0.508: PC625.1 61.84,54.66 PR622.2
N17002616: length 1.3
  BOTTOM w0.102: PR618.2 v1(55.29,50.68)
N17002633: length 1.8
  BOTTOM w0.102: PC605.1 v1(55.78,43.97)
N17092107: length 6.7
  TOP w0.102: v1(43.84,45.56) 44.2,45.2 v4(44.31,45.2)
  IN2 w0.254: v4(44.31,48.58) 44.39,48.58 45.27,47.7 45.27,46.15 v4(44.31,45.2)
  BOTTOM w0.254: PR607.2 44.33,45.19 v4(44.31,45.2) ; PR610.1 44.49,48.76 v4(44.31,48.58)
N17145436: length 8
  IN3 w0.254: v2(92.22,122.1) 92.35,122.23 96.13,122.23 97.24,121.12 v2(97.24,120.86)
  BOTTOM w0.102: v2(92.22,122.1) v1(91.71,122.1)
  BOTTOM w0.203: v2(97.24,120.86) PC307.2
  BOTTOM w0.254: PR309.1 v2(92.22,122.1)
N17209372: length 4.6
  TOP w0.102: v1(38.65,15.32) 38.65,15.09 38.23,14.67 37.08,14.67 PR731.2
  TOP w0.203: v2(35.87,14.12) 35.95,14.2 PR731.2
  BOTTOM w0.203: PU700.4 v2(35.87,14.12)
N17438484: length 2
  BOTTOM w0.102: RA1112.2 CA21.1 179.96,29.9 v1(179.93,29.94)
N17493058: length 3.8
  TOP w0.102: T4927.1 185.45,47.96 v2(185.02,47.96)
  BOTTOM w0.102: JNGFF.36 183.23,49.47 184.74,47.96 v2(185.02,47.96)
N17493084: length 2.7
  TOP w0.102: v2(185.02,49.13) 185.12,49.13 T4929.1
  BOTTOM w0.102: JNGFF.40 184.23,49.49 184.59,49.13 v2(185.02,49.13)
N17493086: length 4.2
  TOP w0.102: v2(185.02,48.54) 186.48,48.54 T4928.1
  BOTTOM w0.102: JNGFF.38 183.73,49.53 184.71,48.54 v2(185.02,48.54)
N17493091: length 3.6
  TOP w0.102: T3861.1 175.21,47.78 v2(175.21,48.39)
  BOTTOM w0.102: JNGFF.6 173.73,49.41 174.69,48.44 175.16,48.44 v2(175.21,48.39)
N17493111: length 2.7
  TOP w0.102: T3862.1 174.63,49 175.19,49 v2(175.21,48.97)
  BOTTOM w0.102: JNGFF.16 176.23,49.45 175.75,48.97 v2(175.21,48.97)
N17607640: length 10
  TOP w0.102: v2(101.53,120.23) v1(101.53,117.17)
  BOTTOM w0.203: 98.56,120.03 98.25,119.73 PU300.1
  BOTTOM w0.254: PR300.1 PR301.1 PC300.1 102.4,121.1 v2(101.53,120.23) 101.32,120.03 98.56,120.03
N17607658: length 1.3
  BOTTOM w0.102: PR310.1 92.84,119.61 v1(92.66,119.79)
N17607660: length 9.5
  IN3 w0.254: v2(97.21,123.24) 97.82,122.63 97.82,120.61 97.43,120.22 v2(97.02,120.22)
  BOTTOM w0.254: PR309.2 PR307.1 v1(94.9,122.99) 95.53,122.99 95.79,123.24 v2(97.21,123.24) 97.22,123.24 97.24,123.22 PR305.2 ; PU300.4 96.9,119.57 96.9,120.1 v2(97.02,120.22)
N17850379: length 1.6
  TOP w0.254: C5259.1 89.48,18.4 89.35,18.28 U2412.21
N17850383: length 2
  TOP w0.102: R2484.1 86.42,22.18 86.36,22.12 v1(86.36,21.69) U2412.28
N17951580: length 3.2
  TOP w0.102: UE4.38 96.34,21.52 96.58,21.76 RE24.1 95.93,22.33 v1(95.64,22.62)
N17955062: length 8
  TOP w0.102: v1(140.83,16.5) 141.5,16.5 141.61,16.61 142.66,16.61 142.88,16.4 RE64.1 142.88,15.95 143.03,15.8 143.16,15.8 143.39,15.57 143.39,15.05 v2(143.53,14.91) ; v2(146.38,14.4) 146.23,14.4 145.97,14.67 UE5.B61
  BOTTOM w0.102: v2(143.53,14.91) 144.21,14.23 146.21,14.23 v2(146.38,14.4)
N17955064: length 2.9
  TOP w0.102: v1(161.04,17.72) 160.71,18.05 160.37,18.05 CE52.1 RE80.2
N17955068: length 2.3
  TOP w0.102: v1(162.26,18.75) 161.68,19.33 RE70.2 161.68,20.12 161.72,20.16 QE9.2
N17955070: length 4.7
  TOP w0.203: RE57.1 142.88,13.81 142.41,14.28 141.44,14.28 140.94,13.77 RE63.1
  TOP w0.254: UE5.A59 144.84,13.92 v1(143.81,13.92) 143.03,13.92 RE57.1
N18087789: length 4.3
  TOP w0.102: v1(60.25,96.34) 60.18,96.27 RV42.1 59.85,94.97 59.29,94.97 59.24,94.92 58.22,94.92 v2(57.87,94.57)
  BOTTOM w0.102: UV1.D22 v2(57.87,94.57)
N18087791: length 2.8
  TOP w0.102: RV44.1 56.03,96.32 v2(56.18,96.17)
  BOTTOM w0.102: UV1.C24 55.78,95.77 v2(56.18,96.17)
N18087793: length 1.3
  TOP w0.102: v2(54.6,96.98) 54.21,96.98 RV43.1
  BOTTOM w0.102: v2(54.6,96.98) 54.96,96.61 UV1.B25
N18094610: length 2.2
  BOTTOM w0.102: L18.2 175.13,90.61 v1(174.81,90.93)
N18094620: length 14.9
  TOP w0.508: RL40.2 RL39.2 196.44,88.17 196.21,87.94 v1(196.21,86.03) 196.21,84.18 RL20.2 RL19.2 196.23,80.98 194.62,79.36 CL33.1
N18094850: length 3
  BOTTOM w0.254: UL1.31 181.63,89.43 181.97,89.76 v1(181.97,90.24) 181.97,90.65 182.5,91.19 RL31.2
N18095026: length 3.4
  BOTTOM w0.102: UL1.27 180.03,90.79 181.12,91.87 T94.1
N18095028: length 1.1
  BOTTOM w0.102: UL1.25 179.23,90.08 T95.1
N18096585: length 1.8
  TOP w0.102: RV46.1 58.46,92.83 v2(57.84,92.83) 57.84,92.84 v1(57.48,93.19)
  BOTTOM w0.102: v2(57.84,92.83) 57.46,93.2 UV1.F22
N18097114: length 2.2
  TOP w0.102: v2(58.6,90.38) 58.42,90.55 RV130.1
  BOTTOM w0.102: v2(58.6,90.38) 57.82,90.38 UV1.J22
N18127046: length 4.3
  TOP w0.102: v3(124.43,18.18) 122.95,18.18 R2518.2 122.38,18.75 JKBBL.2
N18131448: length 5.6
  TOP w0.102: C5291.1 175.3,65.17 173.44,65.17 v1(172.86,64.59)
  TOP w0.203: C5291.1 176.08,65 177.19,65 177.22,64.97 U2304.10
N18135480: length 6.2
  TOP w0.102: v1(180.23,25.26) 180.69,24.81 181.49,24.81 181.61,24.68 RC38.2 181.61,23.93 181.8,23.74 184.32,23.74 184.82,23.24 UA1.47
N18264318: length 11
  TOP w0.102: v2(58.98,118.93) 58.98,119.05 v1(58.65,119.38)
  IN1 w1.016: 58.48,118.29 58.48,114.61 59.75,113.34 64.7,113.34
  vias: v2(58.45,118.32) v2(65.62,113.44) v2(66.2,113.52)
N18265058: length 2.4
  TOP w0.102: PC110.1 v1(52,22.6)
  TOP w0.508: PR111.2 51.44,23.99 51.53,23.9 PC110.1
N18272632: length 2.5
  BOTTOM w0.102: UV6.6 v1(192.38,107.89) 192.66,107.89 CV341.1
N18272698: length 5
  BOTTOM w0.102: UV6.5 192.25,108.29 193.37,109.42 RV160.1 193.84,109.96 194.78,109.96 v1(195.2,110.38)
N18272737: length 2.6
  BOTTOM w0.102: UV6.43 188.29,111.44 v1(188.89,112.04) 189.3,112.45 RV161.2
N18272741: length 2.7
  BOTTOM w0.102: UV6.42 187.89,111.63 v1(187.6,111.93) 187.6,112.13 RV162.2
N18274085: length 5.3
  BOTTOM w0.102: UV3.1 196.62,109.26 v1(196.48,109.39) 196.46,109.41 RV169.1 196.16,110.66 195.95,110.86 195.95,112.51 195.71,112.75 UV5.1
N18287656: length 6.1
  TOP w0.102: RD6.2 157.28,49.61 v1(157.87,49.02) 157.87,47.93 v2(158.32,47.47)
  BOTTOM w0.102: v2(158.32,47.47) 157.61,48.19 157.61,48.82 157.35,49.09 JDIMM1.197
N18287658: length 5.3
  TOP w0.102: RD7.2 158.3,49.23 158.2,49.13 158.2,48.8 v2(158.32,48.67) 158.44,48.67 158.73,48.38 158.73,47.06 v1(158.46,46.79)
  BOTTOM w0.102: JDIMM1.201 158.55,48.89 v2(158.32,48.67)
N18289776: length 7.7
  TOP w0.508: RD4.1 CD22.1 CD21.1 136.25,41.25 135.92,40.92 v1(135.92,40.31) 135.47,39.86 v2(135.18,39.86)
  BOTTOM w0.356: v2(135.18,39.86) 135.54,39.86 135.97,40.29 135.97,40.72 136.05,40.8 JDIMM1.126
N18291638: length 4.4
  TOP w0.102: RD13.1 v1(168.28,38.95) 168.57,39.25 v2(168.81,39.25)
  BOTTOM w0.102: v2(168.81,39.25) 169.35,38.71 JDIMM2.197
N18291647: length 4.5
  TOP w0.102: v1(172.06,37.44) 172.19,37.31 RD12.1
  TOP w0.254: v2(171.94,35.71) 172.19,35.97 RD12.1
  BOTTOM w0.254: JDIMM2.201 170.55,35.91 170.74,35.71 v2(171.94,35.71)
N18292747: length 5.6
  TOP w0.203: PQ1.2 21.83,103.28 22.2,102.92 PR7.1
  TOP w0.254: PQ2.1 24.31,104.13 v1(23.74,104.7) 22.34,104.7 21.83,104.19 PQ1.2
N18293676: length 6.8
  TOP w0.102: v1(152.26,28.69) 151.87,28.3 RD10.1 CD53.1 CD52.1 149.03,27.54 v2(148.57,27.08)
  BOTTOM w0.102: v2(148.57,27.08) 148.57,27.23 148.05,27.75 JDIMM2.126
N18297343: length 5.4
  TOP w0.102: v2(56.29,23.73) v1(57.15,23.73)
  TOP w0.203: PR101.2 55.76,22.56 55.43,22.89 PC100.1 55.97,23.36 56.29,23.68 v2(56.29,23.73)
  BOTTOM w0.203: PR102.2 56.65,23.03 56.15,22.53 56.07,22.53 55.73,22.19 PR100.2
  BOTTOM w0.254: PR102.2 56.65,23.37 v2(56.29,23.73)
N18299507:
  vias: v1(48.15,30.08)
N18300498: length 4.5
  IN1 w0.762: 44.63,24.82 47.35,24.82 48.61,26.08
  vias: v3(49.1,25.99) v4(44.06,26.02) v4(44.06,25.39) v4(49.18,26.6) v4(49.66,27.08)
N18346513: length 6.8
  TOP w0.102: Q327.1 100.77,27.61 100.28,28.09 Q330.2 101.15,28.93 101.66,29.44 R990.1 ; R990.1 102.71,29.44 v1(103.22,28.93) ; R990.1 C1160.1
N18346584: length 3.5
  TOP w0.102: Q330.1 98.2,31.04 98.23,31.07 R944.1 97.35,32.36 v1(97.22,32.49)
N18421110: length 5.2
  TOP w0.102: PR110.2 53.97,31.73 53.42,32.27 53.42,32.48 v1(53.09,32.81)
  TOP w0.203: PU100.7 52.18,30.03 52.18,30.51 52.48,30.81 53.12,30.81 PR110.2 PR115.1
N18454857: length 5.5
  TOP w0.102: CA65.2 180.06,14.66 RA79.1 CA69.1 RA81.2 179.33,16.74 179.16,16.91 178.08,16.91 v1(177.4,16.22)
N18525878: length 0.7
  BOTTOM w0.102: v2(67.84,47.41) v1(68.51,47.41)
N18526201: length 1.5
  TOP w0.102: PR619.2 v1(53.92,45.47)
N18626460: length 10.6
  TOP w0.102: v3(198.78,16.79) 198.81,16.82 197.62,16.82
  TOP w0.254: 197.62,16.82 RA1120.1 197.62,15.17 DA13.3 199.04,13.64 199.04,11.25 200.1,10.19 JHP.5
N18628488: length 5.2
  TOP w0.102: v1(187.2,12.05) 187.2,13.52 RA1130.2
  TOP w0.203: RA1130.2 186.75,14.4 187.15,14.81 187.15,14.82 187.3,14.97 187.3,16.03 187.22,16.12 UA1.20
N18659385: length 2.5
  TOP w0.102: v1(97.43,115.86) 97.78,116.22 PC302.1
  TOP w0.508: PR303.2 PC302.1
N18675947: length 57.8
  TOP w0.102: v2(19.33,36.53) 19.33,36.16 v1(19.71,35.78)
  TOP w0.254: PC701.2 16.93,38.15 18.53,38.15 PC700.2 ; PC700.2 19.3,36.57 v2(19.33,36.53) ; PC700.2 19.85,37.39 PR737.2 20.76,37.4 20.76,38.41 PQ708.3 ; v2(38.18,14.15) 38.13,14.2 PR731.1
  IN1 w0.254: v2(38.18,14.15) 37.6,14.73 37.6,16.33 36.81,17.12 35.36,17.12 34.59,16.36 30.36,16.36 29.36,17.36 24.65,17.36 21.95,20.05 21.95,20.82 20.08,22.68 19.36,22.68 17.29,24.76 17.29,25.01 v2(17.17,25.12)
  IN3 w0.254: v2(17.17,25.12) 17.17,26.7 19.33,28.86 v2(19.33,36.53) 20.04,37.23 20.28,37.23 22,38.95 22,41.3 v2(22.79,42.09)
  BOTTOM w0.254: v2(22.79,42.09) 22.68,41.98 22.68,41.47 22.89,41.26 PQ702.4
N18774013: length 14.7
  BOTTOM w0.076: UC1.U2 155.51,95.52 155.97,95.98 156.33,95.98 156.58,95.72 161.95,95.72 162.03,95.65
  BOTTOM w0.102: R2341.2 167.25,90.41 165.98,91.68 165.98,91.96 v1(164.95,92.99) 163.99,93.96 163.72,93.96 162.03,95.65
N18774065: length 16.4
  TOP w0.102: R2343.2 167.95,94.66 163,94.66 161.66,93.32 157.81,93.32 v1(157.54,93.6) 157.19,93.94 156.36,93.94 156.06,93.64 154.55,93.64 v2(153.8,94.39)
  BOTTOM w0.076: v2(153.8,94.39) 153.5,94.09 UC1.Y5
N18774118: length 14.8
  BOTTOM w0.076: 162.03,96.31 161.89,96.45 v1(161.23,96.45) 160.15,96.45 159.77,96.07 159.31,96.07 159.16,96.22 159.16,96.75 159.01,96.9 156.54,96.9 156.35,96.71 155.95,96.71 155.95,96.72 155.5,96.27 UC1.T2
  BOTTOM w0.102: R2344.2 167.38,92.19 164.69,94.88 163.45,94.88 162.03,96.31
N18838006: length 7.2
  TOP w0.102: v2(67.77,96.17) v1(68.33,96.73) 68.33,97.61 71.05,100.33 RV31.1
  BOTTOM w0.102: v2(67.77,96.17) 67.77,95.36 UV1.D10
N18868218: length 1.2
  TOP w0.102: T96.1 57.04,95.34 v2(57.04,95.35)
  BOTTOM w0.102: UV1.D23 56.66,94.97 v2(57.04,95.35)
N18923200: length 2.2
  BOTTOM w0.102: RC10.1 82.15,50.62 v1(81.81,50.28)
  BOTTOM w0.508: DC1.2 82.15,51.89 RC10.1
N19163204: length 3.2
  TOP w0.102: v1(190.31,69.76) 190.5,69.57 RX13.2 191.7,68.68 QX3.2
N19365430: length 2.1
  TOP w0.102: 67.11,119.18 v1(67.11,121.33)
N19373700: length 7.4
  TOP w0.102: v1(72.7,104.94) 72.27,104.94 71.57,104.24 PR537.2
  TOP w0.254: PU501.7 68.67,107.13 68.83,106.97 v2(68.83,106.61) 68.83,106.09 69.42,105.49 69.68,105.49 70.11,105.06 70.11,104.68 70.54,104.24 PC522.2 PR537.2
  BOTTOM w0.254: v2(68.83,106.61) 69,106.78 PR543.1
N19373709: length 2.2
  BOTTOM w0.102: v1(70.84,107.7) PR543.2
  BOTTOM w0.254: PR543.2 69.6,107.71 PC527.1
N19505504: length 2
  TOP w0.102: T117.1 154.49,92.13 v2(153.8,91.44)
  BOTTOM w0.076: v2(153.8,91.44) 154.17,91.81 UC1.AD4
N19636370: length 2.4
  TOP w0.102: QA6.2 181.28,12.12 181.03,12.37 181.03,13.01 181.23,13.21 RA6.2
N19793702: length 5.2
  TOP w0.102: v1(181.04,58.36) 180.57,58.36 180.18,57.97 180.18,56.8 180.71,56.26 C5292.1
  TOP w0.203: C5292.1 179.86,55.39 179.86,54.91 179.87,54.9 U2301.12
N19793725: length 2.3
  TOP w0.203: U2301.10 180.67,54.73 v1(181.26,55.32) 181.6,55.66 C5293.1
N19794620: length 4.1
  TOP w0.102: QA6.6 180.01,11.47 180.14,11.6 180.14,11.99 180.01,12.12 QA6.5 179.01,12.12 178.74,12.38 v1(178.74,12.61) 178.74,13.01 179.33,13.59 RA5.2
N19883960: length 4.1
  BOTTOM w0.102: v1(48.7,52.77) 48.7,51.41 PR624.1
  BOTTOM w0.254: PR624.1 48.98,50.68 PU600.14
N20088578: length 13.8
  BOTTOM w0.102: PR719.2 44.25,11.38 43.62,10.75 v1(42.5,10.75) 35.95,10.75 35.74,10.54 33.06,10.54 32.64,10.96 PU700.11
N20088579: length 15.2
  BOTTOM w0.102: PR721.2 45.14,11.48 v1(44.38,10.73) 43.97,10.31 32.96,10.31 32.24,11.03 PU700.12
N20173262: length 3.6
  BOTTOM w0.203: RV215.1 191.07,112.31 v1(190.76,112) 190.52,111.75 189.62,111.75 189.09,111.22 UV6.45
N20267138: length 2.8
  TOP w0.254: PR539.2 68.64,103.35 68.89,103.1 v2(68.89,103.13)
  BOTTOM w0.102: PC526.1 70.1,103.74 v1(70.38,104.02)
  BOTTOM w0.254: v2(68.89,103.13) 68.89,103.48 PC526.1
N20270870: length 2.6
  TOP w0.102: v2(21.85,36.68) 22.28,36.25 v1(22.34,36.25)
  TOP w0.254: v2(21.85,36.68) 21.58,36.95 PR737.1
  BOTTOM w0.254: PQ701.4 21.33,36.95 21.59,36.68 v2(21.85,36.68)
N20335974: length 2.7
  TOP w0.102: UL2.3 181.61,80.83 RL41.1 181.41,81.36 v1(180.71,82.06)
N20382121: length 1.4
  BOTTOM w0.102: UV6.28 183.97,106.69 T4930.1
N20424725: length 23
  TOP w0.102: v2(23.55,25.2) 23.55,25.71 v1(24.08,26.24)
  TOP w0.254: PC728.1 29.96,14.98 29.49,14.51 28.2,14.51 27.77,14.94 v2(27.72,14.94)
  IN3 w0.254: v2(23.55,25.2) 23.74,25.01 23.74,24.5 21.89,22.65 21.89,19.62 26.34,15.17 27.49,15.17 v2(27.72,14.94)
  BOTTOM w0.203: PC727.2 28.57,14.52 PU700.19
  BOTTOM w0.254: v2(23.55,25.2) 23.55,25.22 23.98,25.66 PR710.3 ; PC727.2 28.33,14.63 28.07,14.63 27.77,14.94 v2(27.72,14.94)
N20451836: length 4.5
  BOTTOM w0.102: UV6.37 185.89,111.72 186.59,112.42 RV518.2 187.05,113.4 v1(187.05,114.77)
N20469401: length 2.3
  TOP w0.102: v1(21.33,37.9) 21.06,38.17 21.06,39.07 20.32,39.81 PQ708.2
N20526852: length 7.5
  TOP w0.102: RX26.1 3.95,83.2 5.33,83.2 v1(5.49,83.37) v2(6.09,83.37) 6.34,83.11 DV1.1
  BOTTOM w0.102: JEDP.5 4.4,82.95 4.44,82.98 5.71,82.98 v2(6.09,83.37)
N20526883: length 2.8
  TOP w0.102: QX1.1 v1(6.21,73.14) 5.9,73.14 RX3.2
N20527415: length 4.9
  TOP w0.102: RX30.1 9.94,82.67 v1(9.81,82.79) 9.64,82.96 9.64,85.14 10.22,85.72 UX1.3
N20613673: length 2.5
  BOTTOM w0.203: PU700.21 30.31,15.32 v1(29.58,16.06) 28.74,16.06 PR706.1
N20614981: length 5.2
  BOTTOM w0.508: PD703.1 PD702.1 41.67,14.54 v1(40.97,15.24) 40.97,15.23 40.38,15.23 40.25,15.36 PR708.1
N20617538:
  vias: v1(39.21,115.6)
N20617570: length 4.3
  TOP w0.102: PQ3.2 38,119.59 37.82,119.76 PR9.2 PC11.1 PR13.1 38.37,121.43 v1(37.63,121.43)
N20617589: length 2.2
  TOP w0.102: PR12.2 34.17,117.99 v1(33.79,117.6)
N20641621: length 5.4
  TOP w0.102: v1(76.2,102.48) RV253.1 76.38,101.28 QV14.2 QV14.5 76.38,97.22 RV252.1
N20665046: length 8.7
  TOP w0.102: UM1.6 173.73,51.87 173.41,52.18 v2(173.41,53.27) ; CM8.1 172.86,50.15 173.09,49.93 v1(173.09,49.72) v2(173.09,49.01)
  IN1 w0.114: v2(173.09,49.01) 173.09,49.73 173.47,50.11 173.47,53.21 v2(173.41,53.27)
N20693027: length 5.1
  TOP w0.102: v1(166.04,16.75) 166.36,17.07 167.56,17.07 167.75,17.26 167.75,17.27 RS22.2 167.89,17.27 168.5,17.88 169.5,17.88 169.79,18.18 US2.7
N20735659: length 10.9
  TOP w0.102: RC9.2 173.46,80.25 177.86,80.25 v1(178.2,80.59) 178.36,80.75 178.36,81.28 v2(178.93,81.85)
  BOTTOM w0.102: v2(178.93,81.85) 178.93,81.96 178.01,82.88 177.16,82.88 176.76,82.49 SW3.1
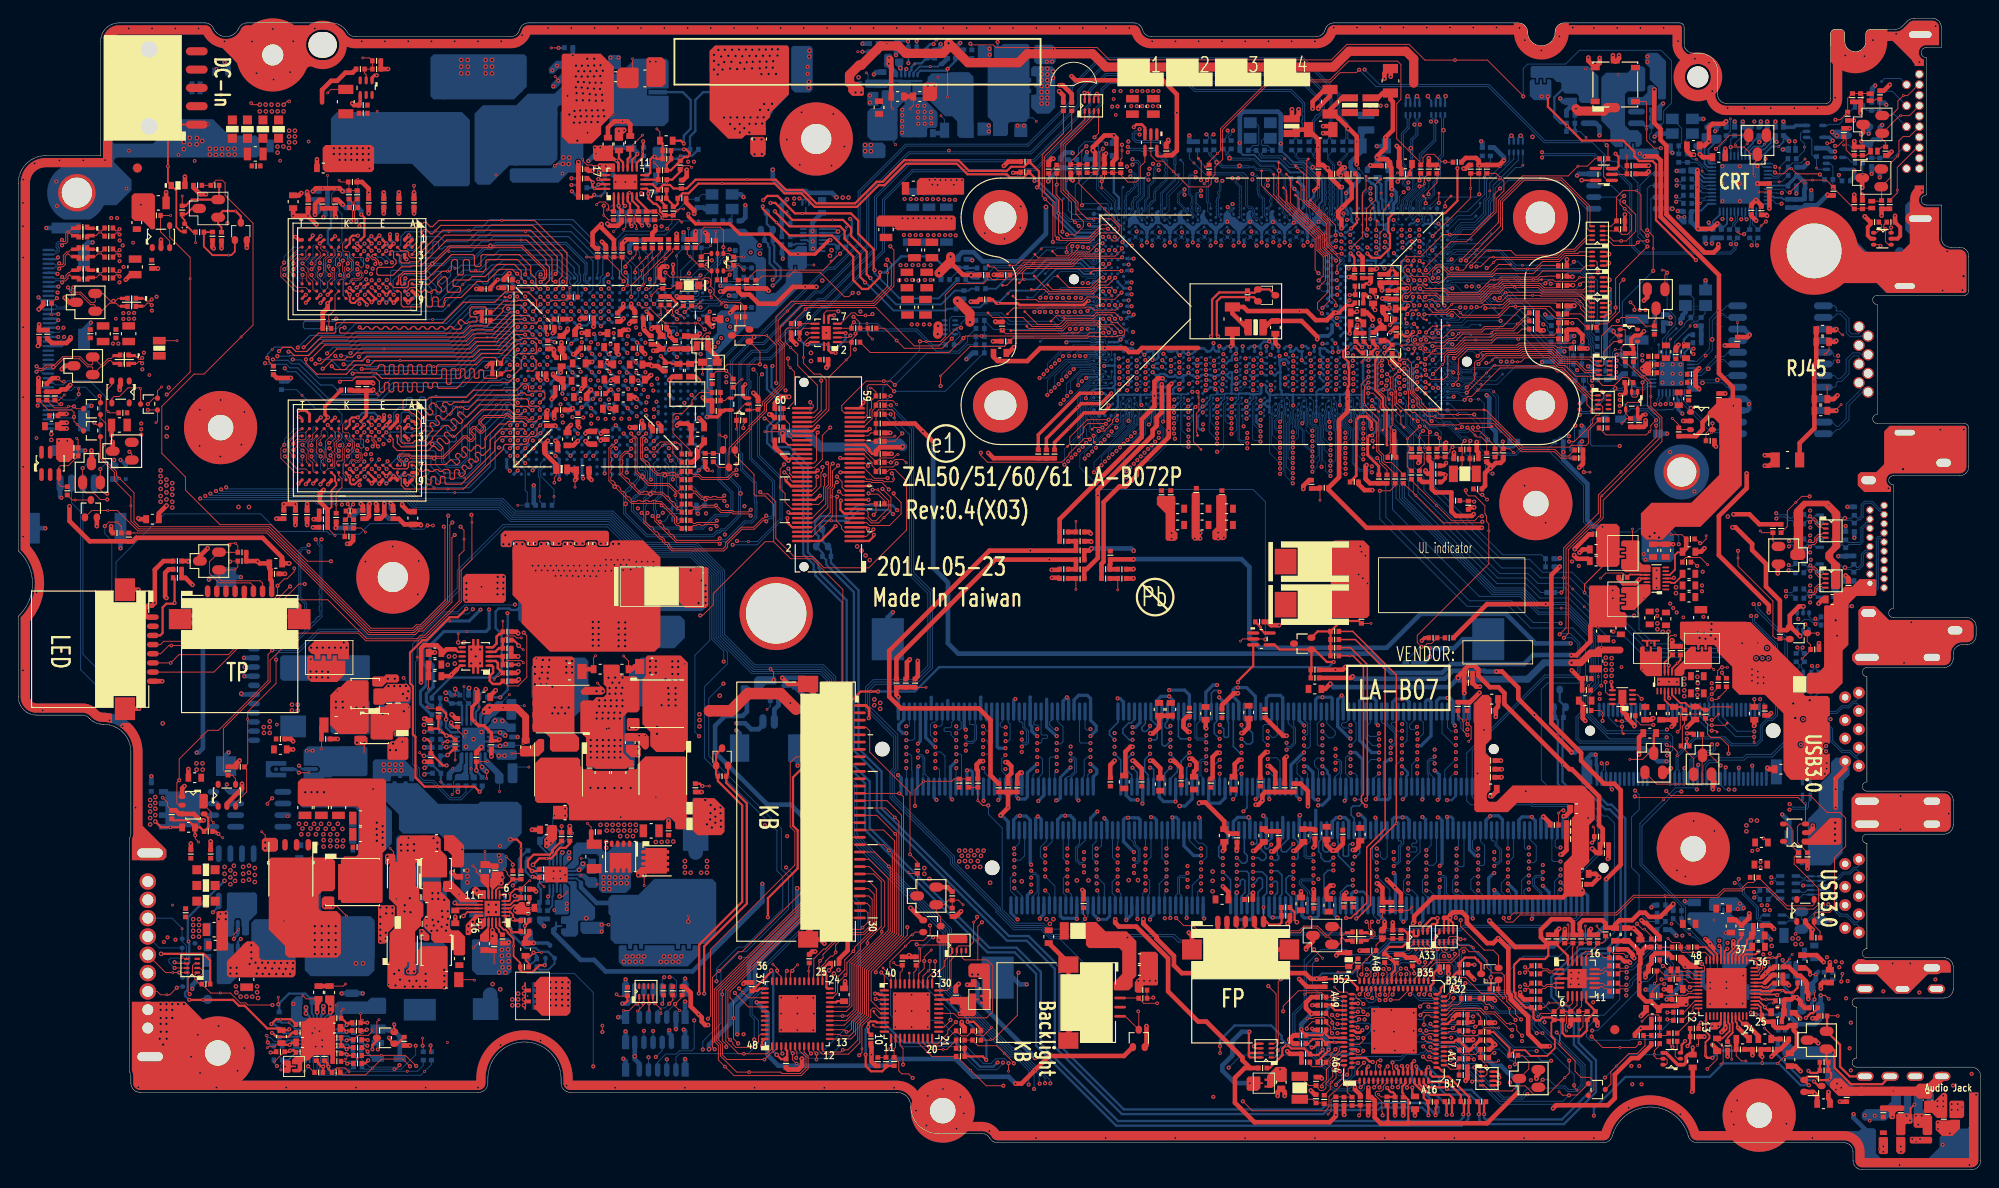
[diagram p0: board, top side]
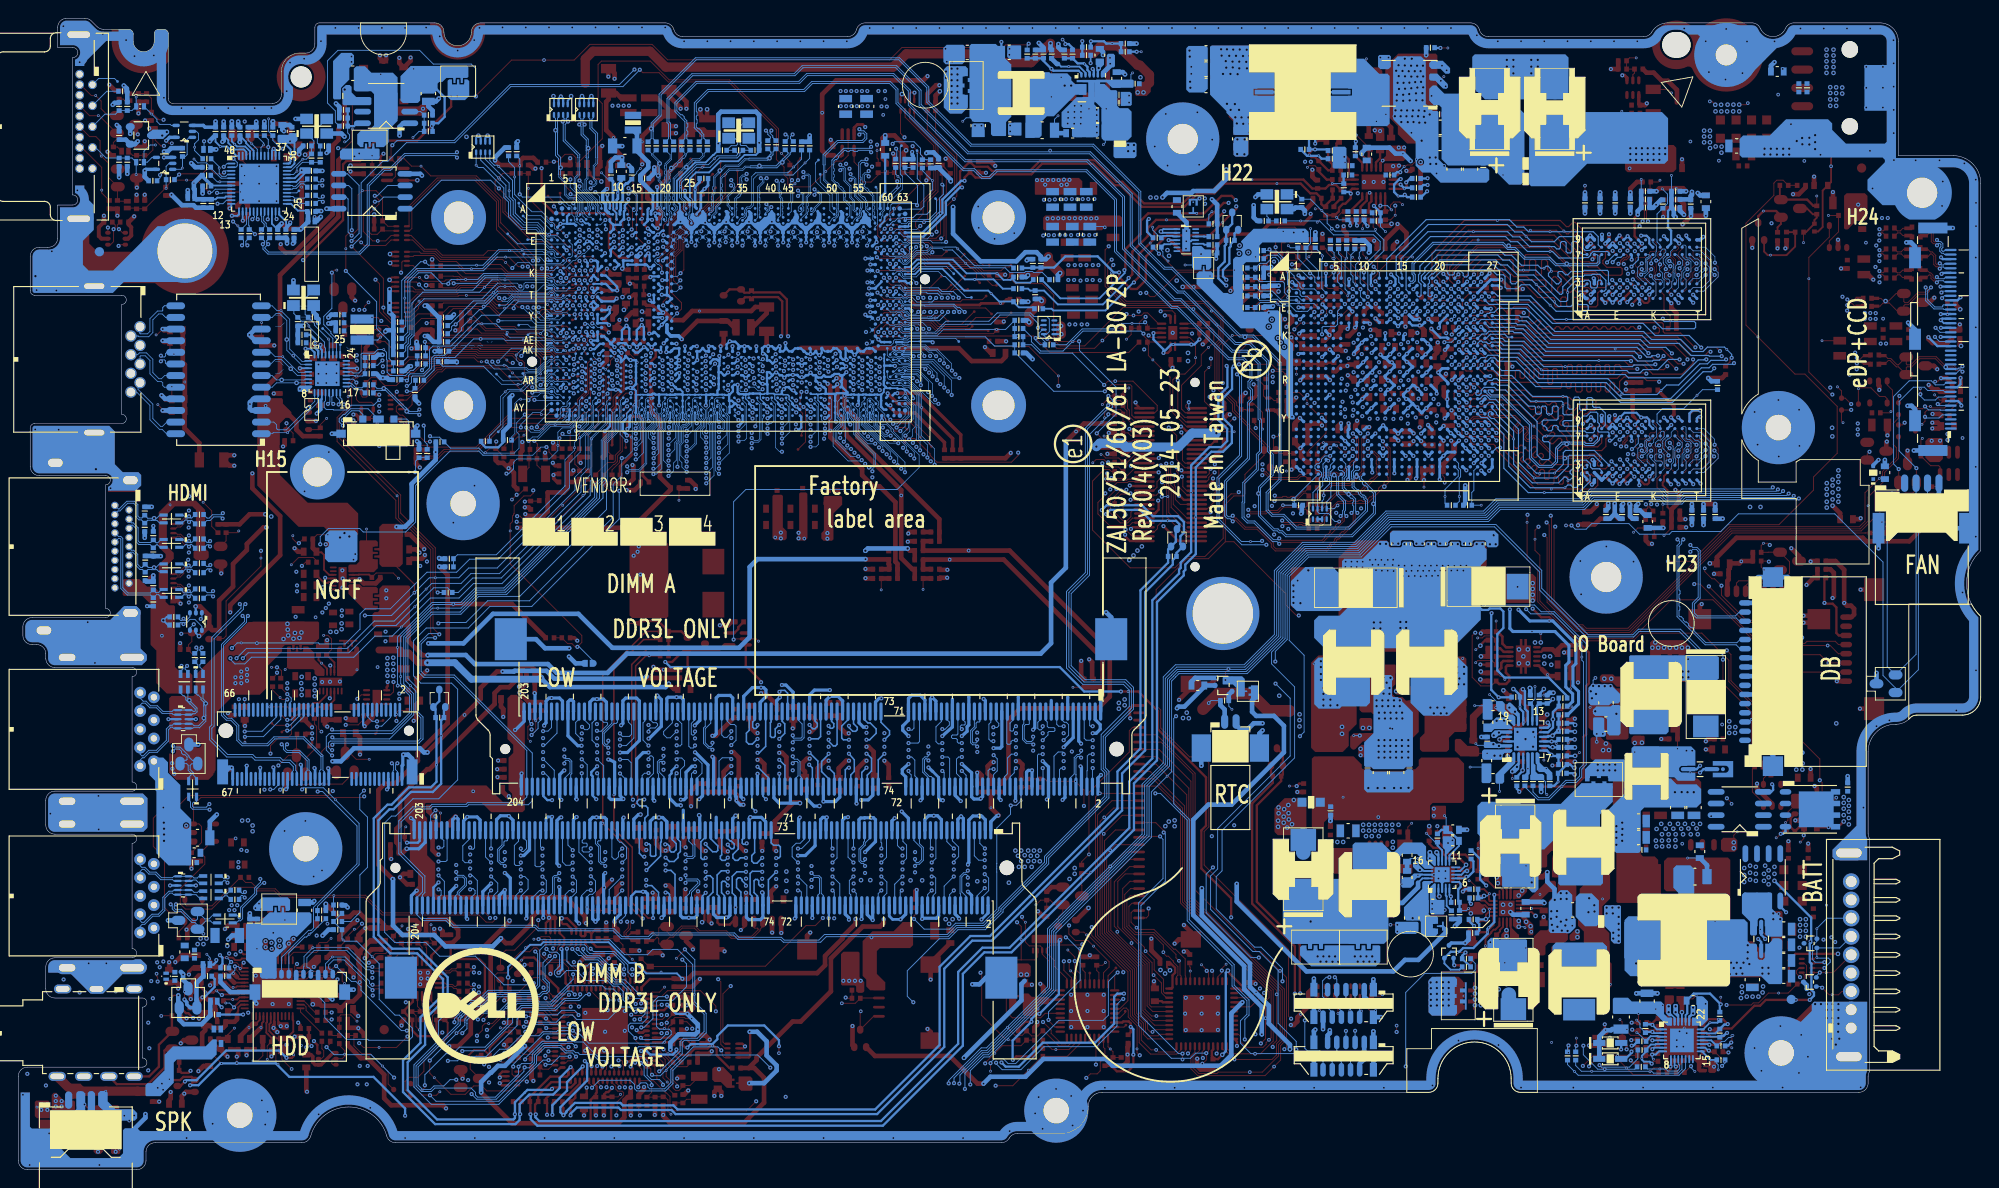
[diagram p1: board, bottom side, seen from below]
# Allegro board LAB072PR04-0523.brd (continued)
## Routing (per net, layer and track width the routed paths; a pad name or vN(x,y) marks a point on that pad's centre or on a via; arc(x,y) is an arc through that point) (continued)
N20757845: length 234.7
  TOP w0.102: v2(159.01,15.05) 158.89,15.17 RE58.2 ; v2(44.71,70.36) v3(45.31,70.36)
  IN3 w0.135: v2(159.01,15.05) 159.01,15.04 156.09,15.04 154.71,13.66 154.71,13.21 154.37,12.88 153.32,12.88 152.44,13.76 149.05,13.76 148.88,13.93 145.95,13.93 145.21,14.67 145.21,15.85 144.64,16.41 144.64,17.06 144.38,17.32 142.71,17.32 141.75,16.36 140.73,16.36 139.07,18.01 135.21,18.01 134.52,18.7 127.97,18.7 126.72,19.94 111.31,19.94 110.72,19.36 100.54,19.36 99.78,20.11 97.89,20.11 90.1,27.91 90.1,28.9 82.88,36.11 82.88,36.99 83.51,37.62 83.51,42.48 82.73,43.26 82.73,45.05 80.65,47.13 80.65,54.07 76.93,57.79 76.93,64.55 73.09,68.39 66.59,68.39 65.76,69.22 48.24,69.22 47.86,68.84 46.23,68.84 v2(44.71,70.36)
  BOTTOM w0.102: v2(44.71,70.36) 44.3,69.95 43.11,69.95 42.5,70.56 38.43,70.56 37.28,69.41 34.01,69.41 33.72,69.7 28.4,69.7 26.47,71.63 15.94,71.63 10.67,66.36 10.67,53.98 9.3,52.61 DE3.2 6.81,54.6 6.81,71.85 5.81,72.85 JFAN.3
N20803831: length 4.4
  BOTTOM w0.102: YV3.3 181.73,113.74 181.73,112.13 CV344.2 RV159.2
N20931556: length 4.5
  TOP w0.102: v1(27.2,13.31) 27.31,13.43 27.97,13.43 28.38,13.83 PR723.1
  TOP w0.254: PR723.1 28.95,13.64 v2(29.65,13.64) 29.9,13.9 PC729.1
  BOTTOM w0.203: PU700.17 29.73,13.72 v2(29.65,13.64)
N21289444: length 5
  BOTTOM w0.102: PC403.2 PR401.1 170.44,115.56 PU400.2 ; v1(171.29,112.73) 170.62,113.4 PR400.2
  BOTTOM w0.254: PR400.2 PC403.2
N21493914: length 1.4
  BOTTOM w0.203: UV15.12 84.86,101.93 84.84,101.91 CV140.1
N21493916: length 1.5
  BOTTOM w0.203: CV141.1 84.81,101.02 84.92,101.13 UV15.10
N22407138: length 4.5
  BOTTOM w0.102: RV515.1 68.38,100.33 68.81,99.9 68.81,97.82 68.58,97.59 68.58,96.95 68.2,96.57 UV1.B9
N22407258: length 3.6
  BOTTOM w0.102: RV514.1 67.89,100.18 v1(67.89,99.58) 67.89,99.25 68.29,98.85 68.29,97.47 68.19,97.37 UV1.A9
N22407318: length 5.1
  BOTTOM w0.102: UV1.C8 69.45,96.19 69.45,99.38 v1(69.27,99.56) RV513.1
N22407379: length 6.9
  TOP w0.102: v2(68.61,96.19) 68.93,96.19 69.65,96.91 69.65,98.55 70.21,99.11 70.36,99.11 v1(70.78,99.53) 71.51,100.26 71.51,100.54 71.66,100.69 RV512.1
  BOTTOM w0.102: UV1.C9 68.19,95.77 v2(68.61,96.19)
N22407441: length 3.3
  BOTTOM w0.102: UV1.A7 69.85,97.38 69.85,99.72 70.16,100.03 RV511.1
N22407504: length 4.6
  BOTTOM w0.102: RV510.1 70.64,100.17 v1(70.64,99.53) 70.64,98.95 70.08,98.39 70.08,97.89 70.26,97.72 70.26,96.96 UV1.B7
N22671400: length 3.7
  BOTTOM w0.102: v1(88.79,99.24) 89.35,99.8 89.35,100.26 89.51,100.42 RV193.2
  BOTTOM w0.203: UV15.5 88.47,101.13 88.53,101.07 89.21,101.07 RV193.2
N22753389: length 5.2
  TOP w0.508: PR538.2 66.86,114.17 66.53,114.49 v1(66.02,114.49) 65.09,114.49 64.42,113.82 PC525.1
N22753454: length 34.7
  TOP w0.102: v2(59.03,122.51) v1(58.21,122.51)
  TOP w0.254: v2(68.15,103.12) 67.75,103.52 PR525.1
  IN1 w0.254: v2(59.03,122.51) 57.74,122.51 54.54,119.31 54.54,110.93 62.93,102.54 64.67,102.54 64.98,102.85 66.1,102.85 66.4,102.54 67.57,102.54 v2(68.15,103.12)
  BOTTOM w0.254: PR528.2 68.23,103.2 v2(68.15,103.12) ; PH500.2 59.64,122.51 v2(59.03,122.51)
N22753537: length 10.4
  TOP w0.254: PR536.1 72.39,112.38 v2(72.71,112.07)
  BOTTOM w0.254: PL502.2 72.6,117.69 73.46,116.83 73.46,113.69 72.71,112.94 v2(72.71,112.07)
N22753594: length 2.6
  TOP w0.254: PU501.17 63.73,108.63 v2(63.42,108.94)
  BOTTOM w0.102: v1(62.98,109.55) 63.42,109.12 v2(63.42,108.94)
  BOTTOM w0.254: v2(63.42,108.94) 63.43,108.94 63.43,108.96 63.77,108.96 PR507.1
N22753687: length 1.3
  TOP w0.254: PC522.1 70.67,105.31 PR533.2
N22753760: length 3.6
  TOP w0.102: v1(69.45,110.01) 69.92,109.53 PR535.1
  TOP w0.254: PR535.1 69.92,109.14 69.92,108.13 ; 69.92,108.13 PU501.9 ; 69.92,108.13 PC523.1
N22753762: length 3.6
  TOP w0.102: PR545.1 72.33,109.26 72.72,109.65 73.38,109.65 v1(73.56,109.48)
  TOP w0.254: PR545.1 72.32,109.01 71.44,108.13 PC523.2
N22753790: length 3.4
  BOTTOM w0.254: PR551.1 72.01,110.42 v1(72.33,110.73) 73.6,110.73 PH501.2
N22878624: length 6
  TOP w0.102: PR6.2 v1(19.36,101.24)
  TOP w0.203: PQ1.1 18.97,104.98 18.34,104.35 PR3.1 17.91,103.98 18.17,103.72 PL3.1 19.09,102.4 PR6.2
N22878630: length 6.9
  TOP w0.102: PR3.2 v1(17.91,106.34)
  TOP w0.203: PQ1.3 21.94,106.06 PR5.1
  TOP w0.254: PQ1.3 18.96,105.95 18.28,105.27 PR3.2
N22878645: length 7.7
  TOP w0.203: PR8.2 21.2,102.4 PR6.1 20.27,100.83 21.21,99.89 v1(22.97,99.89) 23.27,99.89 23.66,100.28 PQ2.2
N22892968: length 4.2
  TOP w0.102: v1(68.2,112.99) 66.86,111.65 PR538.1
  TOP w0.254: PU501.13 66.57,110.38 66.86,110.67 PR538.1
N22894348: length 3.9
  TOP w0.254: v2(68.27,112.31) 68.27,111.69 68.26,111.69 68.22,111.65 v1(68.22,111.17) 68.22,110.61 67.57,109.96 PU501.11
  BOTTOM w0.254: v2(68.27,112.31) 68.32,112.26 PR512.1
N43510017: length 5.5
  BOTTOM w0.102: UV1.AF25 55.38,76.36 55.38,74.19 55.6,73.96 RV25.1 v1(54.56,72.57)
N47415217: length 1.4
  TOP w0.102: PR103.1 v1(50.98,34.76)
N47415258:
  vias: v3(48.49,34.98)
N47415272: length 1.7
  TOP w0.102: PR112.2 49.79,20.75 v1(49.84,20.7)
N47445410: length 1.7
  TOP w0.203: PR114.1 52.52,26.02 52.52,26.19 52.18,26.53 PU100.19
N47894294: length 2.1
  TOP w0.102: v1(120.12,63.32) RC23.1
  TOP w0.508: RC23.1 CC8.2
N47894380: length 2
  TOP w0.102: v1(115.55,70.82) RC24.1
  TOP w0.508: RC24.1 CC9.2
N47894401: length 2.1
  TOP w0.102: v1(115.55,63.38) CC10.2
  TOP w0.508: CC10.2 RC25.1
N47938591: length 6.3
  TOP w0.102: v2(150.88,86.58) 150.59,86.58 150.45,86.44 150.45,85.21 150.59,85.07 150.59,83.77 T118.1
  BOTTOM w0.076: v2(150.88,86.58) 150.55,86.91 UC1.AN10
N47938593: length 5.6
  TOP w0.102: T119.1 150.4,83.49 150.4,84.99 150.19,85.19 150.19,86.62 150.81,87.23 v2(150.88,87.23)
  BOTTOM w0.076: v2(150.88,87.23) 150.55,87.56 UC1.AM10
N47938689: length 6.8
  TOP w0.102: T120.1 148.26,107.61 148.26,105.89 147.3,104.93 147.3,102.78 v2(147.39,102.69)
  BOTTOM w0.076: v2(147.39,102.69) 147.75,102.37 UC1.E15
N47938710: length 1.6
  TOP w0.102: v2(148.35,102.63) 148.35,103.51 T121.1
  BOTTOM w0.076: v2(148.35,102.63) 148.37,102.61 148.37,102.6 148.6,102.37 UC1.E13
N47964855: length 8
  BOTTOM w0.076: UC1.L60 119.16,98.21 118.69,98.21 118.64,98.26 117.97,98.26 117.8,98.09 116.55,98.09 116.01,98.63 112.97,98.63 T153.1
N47964866: length 8
  TOP w0.102: T154.1 113,96.11 117.19,96.11 118.03,96.95 118.75,96.95 v2(119.21,97.42)
  BOTTOM w0.076: UC1.N60 119.46,97.67 v2(119.21,97.42)
N47964871: length 17.5
  TOP w0.102: T155.1 138.98,108.28 138.98,105.6 142.52,102.06 142.52,100.66 142.71,100.47 142.71,100.46 143.26,99.91 143.26,94.9 v2(142.49,94.13)
  BOTTOM w0.076: UC1.W23 142.67,94.31 v2(142.49,94.13)
N47964873: length 14.5
  TOP w0.102: T156.1 139.92,106.05 139.92,104.94 142.71,102.15 142.71,100.74 142.9,100.55 142.9,100.54 143.51,99.93 143.51,95.23 143.95,94.79 v2(143.95,94.4)
  BOTTOM w0.076: v2(143.95,94.4) 143.53,93.98 UC1.Y22
N47964879: length 5.1
  TOP w0.102: v2(118.44,81.05) 117.5,81.05 T157.1
  BOTTOM w0.076: UC1.AV62 117.82,83.32 117.34,83.32 117.11,83.09 117.11,82.44 118.05,81.5 118.05,81.45 v2(118.44,81.05)
N47964884: length 4.8
  BOTTOM w0.076: UC1.D58 120.8,102.95 120.52,103.24 120.52,104.78 120.58,104.84 120.58,107.18 T158.1
N47965485: length 6.7
  TOP w0.102: T146.1 119.54,81.88 119.54,81.57 118.64,80.67 v2(118.04,80.67)
  BOTTOM w0.076: UC1.AV63 117.44,83.65 116.94,83.15 116.94,82.38 117.5,81.81 117.5,81.21 v2(118.04,80.67)
N47965487: length 5.7
  TOP w0.102: v2(117.48,80.16) 117.48,79.52 T147.1
  BOTTOM w0.076: v2(117.48,80.16) 117,80.65 117,81.59 116.57,82.01 116.57,83.43 117.46,84.31 UC1.AU63
N47965493: length 1.6
  TOP w0.102: T159.1 153.76,106.1 v2(153.76,105.56)
  BOTTOM w0.076: UC1.A5 153.59,105.38 v2(153.76,105.56)
N47965495: length 5.3
  BOTTOM w0.076: 116.06,103.77 116.08,103.75 116.81,103.75 116.83,103.76 117.42,103.76 UC1.C63
  BOTTOM w0.102: 116.06,103.77 116.04,103.79 114.91,103.79 114.09,104.61 114.09,105.96 T148.1
N47965502: length 3.9
  BOTTOM w0.076: 159.09,104.01 158.89,103.81 157.41,103.81 156.14,102.54 UC1.E1
  BOTTOM w0.102: 159.09,104.01 T161.1
N47965509: length 8.1
  BOTTOM w0.076: 115.85,103.56 116.83,103.56 116.83,103.56 117.13,103.56 117.13,103.56 117.15,103.56 117.38,103.33 117.89,103.33 UC1.C62
  BOTTOM w0.102: 115.85,103.56 114.82,103.56 113.75,104.63 113.75,106.12 113.34,106.53 T149.1
N47965511: length 4.8
  BOTTOM w0.076: 158.8,104.31 158.68,104.19 157.28,104.19 156.21,103.12 UC1.D1
  BOTTOM w0.102: 158.8,104.31 159.69,105.21 159.69,105.54 T163.1
N47965522: length 6.7
  TOP w0.102: v2(129.21,108.08) 129.24,108.1 129.24,110.15 T150.1
  BOTTOM w0.076: v2(129.21,108.08) 129.79,107.51 129.79,105.72 129.95,105.55 129.95,104.65 UC1.B43
N47965524: length 12.6
  TOP w0.102: v2(144.58,100.04) 144.08,100.04 143.1,101.03 143.1,103.43 141.2,105.32 141.05,105.32 140.44,105.93 140.44,108.75 T164.1
  BOTTOM w0.076: UC1.J20 144.86,99.77 v2(144.58,100.04)
N47965529: length 4.4
  BOTTOM w0.076: T151.1 126.79,107.86 125.48,106.56 125.48,105.21 UC1.A51
N47965534: length 7
  BOTTOM w0.076: 127.31,109.81 127.31,107.95 125.73,106.38 125.73,104.75 125.32,104.34 UC1.B51
  BOTTOM w0.102: T152.1 127.31,109.95 127.31,109.81
N47965536: length 9.1
  TOP w0.102: T165.1 147.25,107.1 146.87,106.72 146.87,101.91 145.7,100.74 145.6,100.74 145.57,100.71 145.57,100.72 v2(145.56,100.72)
  BOTTOM w0.076: UC1.H18 145.82,100.42 145.57,100.67 145.57,100.72 v2(145.56,100.72)
N55200533:
  vias: v1(197.82,72.61)
N55201771: length 20.8
  TOP w0.102: RX12.2 193.27,70.26 193.27,71.96 v1(194.21,72.89) 194.85,73.54 v2(195.71,73.54)
  IN1 w0.114: JHDMI.13 203.33,66.55 203.08,66.8 203.08,72.35 202.71,72.72 201.38,72.72 200.44,71.78 197.46,71.78 v2(195.71,73.54)
N60531222: length 13.2
  BOTTOM w0.076: 130.53,108.64 130.53,108.65 133.64,108.65 134.09,108.2 134.09,105.32 134.42,104.99 134.72,104.99 134.83,104.88 134.89,104.71 134.89,104.61 134.84,104.48 134.83,104.45 134.83,104.26 134.87,104.11 134.97,103.96 UC1.C35
  BOTTOM w0.102: R2523.1 127.94,110.45 v1(128.45,109.95) 129.76,108.64 130.53,108.64
N60531228: length 13.2
  BOTTOM w0.076: 134.04,108.7 134.27,108.46 134.27,105.39 134.51,105.15 134.79,105.15 134.97,104.97 135.05,104.74 135.05,104.57 135.03,104.49 135.01,104.48 134.99,104.42 134.99,104.29 135.02,104.19 135.23,103.98 135.41,103.98 135.58,103.81 UC1.C34
  BOTTOM w0.102: R2524.1 128.83,110.37 v1(129.68,109.51) 130.32,108.88 133.85,108.88 134.04,108.7
N60531230: length 25.6
  TOP w0.102: R2525.1 169.37,77.94 168.62,77.94 167.89,78.67 164.32,78.67 160.91,82.07 154.97,82.07 v1(154.75,82.29) 153.97,82.29 152.81,83.44 152.81,84.06 152.09,84.79 152.09,85.09 152.01,85.16 152.01,87.49 151.41,88.09 v2(151.41,88.11)
  BOTTOM w0.076: v2(151.41,88.11) 151.52,88.22 151.52,88.22 UC1.AK8
N60531232: length 25.9
  TOP w0.102: R2526.1 168.52,77.71 167.82,78.41 164.24,78.41 161.13,81.52 157.57,81.52 157.4,81.35 v1(155.74,81.35) 154.18,81.35 153.69,81.84 153.45,81.84 152.58,82.7 152.28,82.7 151.9,83.09 151.9,85.01 151.82,85.08 151.82,87.18 151.41,87.59 v2(151.41,87.48)
  BOTTOM w0.076: UC1.AL8 151.81,87.88 151.76,87.84 151.41,87.53 v2(151.41,87.48)
N60754677: length 11.6
  TOP w0.102: v2(118.46,101.18) 117.97,101.18 117.02,100.23 115.79,100.23 114.9,99.34 109.52,99.34 108.94,98.77 T111.1
  BOTTOM w0.076: v2(118.46,101.18) 118.8,100.84 UC1.H61
N60754679: length 6.6
  TOP w0.102: T112.1 113.49,99.8 114.71,99.8 115.12,100.21 115.12,100.84 v2(115.14,100.87)
  BOTTOM w0.076: UC1.H62 117.88,101.09 117.29,101.09 117.07,101.31 115.56,101.31 115.12,100.87 v2(115.14,100.87)
N60754681: length 15
  TOP w0.102: v2(120.6,99.65) 120.49,99.54 116.07,99.54 115.18,98.66 110.06,98.66 107.99,96.59 T113.1
  BOTTOM w0.076: UC1.K59 120.28,99.34 v2(120.6,99.65)
N60754683: length 7.6
  TOP w0.102: T114.1 111.46,99.57 114.81,99.57 115.73,100.49 v2(115.73,100.81)
  BOTTOM w0.076: v2(115.73,100.81) 116.06,101.15 117,101.15 117.23,100.92 117.4,100.92 UC1.H63
N60754685: length 11.6
  TOP w0.102: v2(119.17,98.94) 118.66,98.43 110.15,98.43 109.72,97.99 109.72,97.22 T115.1
  BOTTOM w0.076: v2(119.17,98.94) 119.46,99.23 UC1.K60
N60754687: length 14.3
  TOP w0.102: v2(118.5,100.4) 118.5,100.36 118.14,100 115.88,100 114.99,99.11 109.87,99.11 108.93,98.17 107.04,98.17 106.63,98.59 106.13,98.59 T116.1
  BOTTOM w0.076: v2(118.5,100.4) 118.81,100.09 UC1.J61
N60931942: length 3.7
  BOTTOM w0.076: UC1.AF2 155.49,91.15 155.82,91.49 156.26,91.49 156.39,91.62 157.03,91.62 157.28,91.37 158.53,91.37 T97.1
N60931944: length 7.3
  BOTTOM w0.076: T99.1 160.67,90.86 156.82,90.86 156.68,90.72 155.94,90.72 155.79,90.56 155,90.56 154.93,90.63 154.54,90.63 UC1.AF4
N60931946: length 4.5
  BOTTOM w0.076: UC1.AD2 155.78,92.06 156.36,92.06 156.39,92.03 158.45,92.03 158.72,92.29 159.68,92.29 T98.1
N61580896: length 5.2
  TOP w0.102: Q2307.1 178.13,45.48 177.47,44.82 v1(176.06,44.82)
  TOP w0.254: R2314.2 178.68,47.42 Q2307.1
N63469524: length 3.1
  TOP w0.102: RA82.1 187.68,12.45 188.26,11.88 v1(188.75,11.88)
  TOP w0.508: RA82.1 187.68,13.86 187.7,13.87 CA68.2
N63469526: length 2.5
  TOP w0.127: CA67.2 191.51,14.73 v1(190.78,15.46)
  TOP w0.508: RA80.1 CA67.2
N63642793: length 5.2
  TOP w0.102: v2(149.26,89.2) 149.26,88.81 149.7,88.37 149.7,87.95 v1(150.23,87.42)
  TOP w0.254: R264.2 149.62,90.54 C51.1 149.7,89.68 149.7,89.64 v2(149.26,89.2)
  BOTTOM w0.254: v2(149.26,89.2) 149.36,89.2 UC1.AH11
N63643467: length 6.4
  TOP w0.102: T53.1 149.14,104.79 149.14,102.67 148.76,102.29 148.76,100.5 v2(148.35,100.09)
  BOTTOM w0.254: UC1.J13 148.68,99.77 v2(148.35,100.09)
N63643476: length 11.2
  TOP w0.254: v2(148.49,89.21) 148.45,89.17 148.45,88.61 148.26,88.42 148.26,85.13 149.1,84.28 149.1,83.3 149.51,82.9 149.51,79.17 T55.1
  BOTTOM w0.254: UC1.AH13 148.86,89.5 148.57,89.21 v2(148.49,89.21)
N63643505: length 1.7
  TOP w0.102: T56.1 152.16,93.87 v2(151.74,93.45)
  BOTTOM w0.076: v2(151.74,93.45) 151.55,93.26 UC1.AB8
N63643514: length 1.8
  TOP w0.102: T58.1 151.53,92.6 v2(151.69,92.43)
  BOTTOM w0.076: v2(151.69,92.43) 151.54,92.43 151.09,91.98 UC1.AD10
N63643523: length 1.7
  TOP w0.102: T59.1 152.87,91.99 v2(152.48,92.38)
  BOTTOM w0.102: v2(152.48,92.38) 152.18,92.38 151.77,91.98 UC1.AD8
N63656577: length 17.5
  TOP w0.102: v2(142.42,93.53) 141.94,94.01 141.94,94.68 143.07,95.81 143.07,99.75 142.96,99.86 142.96,99.88 142.3,100.54 142.3,102.01 138.57,105.73 138.57,106.89 T38.1
  BOTTOM w0.076: v2(142.42,93.53) 143.03,92.92 UC1.AB23
N63657072: length 10.7
  TOP w0.102: v2(119.83,97.42) 119.04,96.62 118.02,96.62 117.28,95.88 112.71,95.88 T39.1
  BOTTOM w0.076: UC1.P60 119.46,97.05 v2(119.83,97.42)
N63657081: length 6.5
  TOP w0.102: T40.1 114.79,96.34 117.09,96.34 118.18,97.43 v2(118.51,97.43)
  BOTTOM w0.076: v2(118.51,97.43) 118.81,97.13 UC1.P61
N63657090: length 4
  TOP w0.102: T41.1 117.44,98.2 120.48,98.2 v2(120.52,98.15)
  BOTTOM w0.076: UC1.N59 120.21,97.84 v2(120.52,98.15)
N63657099: length 10.4
  BOTTOM w0.076: UC1.N61 118.65,97.84 118.4,98.1 118.04,98.1 117.82,97.88 117.82,97.69 117.63,97.51 116.29,97.51 115.7,98.1 113.87,98.1 113.33,97.55
  BOTTOM w0.102: 113.33,97.55 113.13,97.55 110.84,95.26 T42.1
N63657120: length 10.3
  TOP w0.102: v2(119.81,95.93) 119.4,96.34 118.06,96.34 117.37,95.66 112.59,95.66 112.11,96.14 T43.1
  BOTTOM w0.076: UC1.T59 120.11,96.23 v2(119.81,95.93)
N63657126: length 11.9
  TOP w0.102: T44.1 114.11,91.63 114.74,92.26 117.8,92.26 118.23,91.82 118.74,91.82 v2(119.13,91.42)
  BOTTOM w0.076: v2(119.13,91.42) 119.46,91.75 UC1.AD60
N63657135: length 16.4
  TOP w0.102: T45.1 106.46,93.07 109.78,93.07 110.76,92.09 113.92,92.09 114.55,92.71 117.99,92.71 118.42,92.28 119.66,92.28 v2(120.44,91.5)
  BOTTOM w0.076: UC1.AD59 120.11,91.83 v2(120.44,91.5)
N63657146: length 8.9
  TOP w0.102: T46.1 113.4,93.26 117.45,93.26 117.79,93.6 119.8,93.6 v2(120.46,92.94)
  BOTTOM w0.076: UC1.AA59 120.15,93.35 120.46,93.04 v2(120.46,92.94)
N63657155: length 11
  TOP w0.102: T47.1 110.43,91.86 114.02,91.86 114.64,92.48 117.89,92.48 118.32,92.05 119.17,92.05 v2(119.81,91.41)
  BOTTOM w0.076: v2(119.81,91.41) 119.46,91.07 UC1.AE60
N63657164: length 11.6
  TOP w0.102: T48.1 111.36,92.32 113.75,92.32 114.38,92.94 117.45,92.94 117.89,93.37 119.38,93.37 v2(119.81,92.94)
  BOTTOM w0.076: v2(119.81,92.94) 120.11,92.64 UC1.AC59
N63657173: length 9.4
  BOTTOM w0.076: UC1.AG58 120.4,90.03 119.04,90.03 118.79,90.28 118.79,90.51 118.63,90.68 117.77,90.68 117.72,90.65 117.7,90.64 117.67,90.61 117.24,90.61 117.07,90.78 111.98,90.78 T49.1
N63657182: length 13.3
  TOP w0.102: T50.1 109.06,95.02 111.23,95.02 111.46,94.8 116.23,94.8 116.24,94.8 116.27,94.8 116.5,95.04 116.5,95.06 116.77,95.33 117.87,95.33 118.14,95.06 119.8,95.06 v2(120.53,95.79)
  BOTTOM w0.076: v2(120.53,95.79) 120.26,95.52 UC1.U59
N63657191: length 13.6
  TOP w0.102: v2(120.46,94.43) 120.45,94.43 119.89,93.88 117.53,93.88 117.21,94.2 116.64,94.2 116.55,94.11 108.72,94.11 T51.1
  BOTTOM w0.076: v2(120.46,94.43) 120.46,94.5 120.11,94.85 UC1.V59
N72585933: length 2.6
  TOP w0.102: v1(62.17,37.84) 62.59,37.42 PC207.1
  TOP w0.508: PR203.2 62.59,35.88 PC207.1
N104716789:
  vias: v1(174.81,119.64)
N104716883: length 5.6
  BOTTOM w0.102: PR402.2 178.41,113.24 178.21,113.03 178.21,112.64 178.59,112.26 v1(178.74,112.26)
  BOTTOM w0.254: PR403.1 PC402.1 PR402.2 177.73,113.97 177.41,114.29 PU400.8
N205274341: length 5
  TOP w0.102: UX3.3 16.54,101.43 15.54,102.43 RX31.1 v1(16.64,104.22)

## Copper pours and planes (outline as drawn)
1.35V_B+ on TOP: 68.94,35.69 68.94,32.39 69.19,32.13 71.61,32.13 71.86,32.39 71.86,36.45 71.35,36.96 70.72,36.96 70.46,37.21 70.46,37.85 70.34,37.98 69.7,37.98 69.45,37.72 69.45,36.2
1.35V_B+ on BOTTOM: 69.32,35.82 69.57,35.56 71.61,35.56 71.67,35.63 71.95,35.63 72.19,35.87 72.19,37.77 72.8,38.38 72.8,41.19 72.47,41.52 69.57,41.52 69.32,41.26
3/5V_B+ on TOP (solid shape): 43.41,33.15 43.41,31.07 43.81,30.67 43.81,29.45 44.25,29.01 44.25,27.74 44,27.49 44,26.65 43.36,26.01 43.36,23.74 43.04,23.42 40.82,23.42 40.57,23.68 40.57,25.85 41.15,26.43 41.16,26.43 41.33,26.61 41.33,28.76 40.49,29.59 40.49,33.07 40.59,33.17 43.39,33.17
3/5V_B+ on BOTTOM (solid shape): 44.25,29.77 44.25,27.61 43.24,26.6 41.97,26.6 41.71,26.85 41.71,29.39 42.5,30.18 43.84,30.18
3V_DSW on TOP (solid shape): 177.14,68.61 177.14,66.42 177.47,66.09 178.21,66.09 178.34,65.97 178.34,65.33 178.26,65.25 175.56,65.25 175.11,65.7 175.11,66.68 175.67,66.68 175.67,67.26 175.11,67.26 175.11,67.47 175.67,67.47 175.67,68.07 175.11,68.07 175.11,68.55 175.3,68.73 177.02,68.73
3VALW_PCH on TOP (solid shape): 178.33,63.81 178.33,62.89 176.56,61.12 175.28,61.12 175.12,61.28 175.12,61.6 175.67,61.6 175.67,62.16 175.12,62.16 175.12,62.41 175.67,62.41 175.67,62.96 175.12,62.96 175.12,63.47 175.3,63.65 176.82,63.65 177.1,63.94 178.21,63.94
3VS on TOP (solid shape): 177.69,56.6 178.24,56.6 178.24,57.15 178.48,57.15 178.48,56.59 179.04,56.59 179.04,57.15 179.39,57.15 179.58,56.96 179.58,53.98 179.51,53.9 177.88,53.9 177.17,54.61 177.17,57 177.32,57.15 177.69,57.15
5VS on TOP (solid shape): 183.27,56.6 183.83,56.6 183.83,57.15 184.07,57.15 184.07,56.6 184.63,56.6 184.63,57.15 184.95,57.15 185.04,57.06 185.04,54.87 184.84,54.66 182.17,54.66 182.03,54.52 182.03,54.17 181.86,53.99 181.8,53.96 181.76,53.93 181.03,53.93 180.95,54 180.95,54.63 181.4,55.08 181.46,55.12 181.5,55.18 182.04,55.72 182.04,56.43 182.75,57.15 183.27,57.15
+0.675VS on TOP (solid shape): 160.96,51.49 160.96,47.04 160.33,46.41 160.33,45.52 160.84,45.01 160.84,41.46 160.46,41.07 160.46,40.93 160.45,40.92 160.43,40.79 160.45,40.66 160.46,40.66 160.46,40.44 160.71,40.19 161.47,40.19 163.25,41.96 170.95,41.96 172.23,40.69 172.23,38.24 171.63,37.64 171.63,35.9 171.62,35.88 171.58,35.71 171.62,35.55 171.63,35.53 171.63,35.24 171.62,35.23 171.58,35.05 171.62,34.88 171.63,34.87 171.63,33.58 170.74,32.69 170.74,30.99 170.95,30.79 170.95,30.76 170.97,30.76 171.15,30.58 171.15,30.08 170.9,29.82 169.12,29.82 168.84,30.1 168.84,30.54 168.85,30.61 168.84,30.68 168.84,31.3 168.85,31.37 168.84,31.45 168.84,32.06 168.85,32.14 168.84,32.21 168.84,32.66 168.84,32.67 168.86,32.79 168.84,32.92 168.84,32.93 168.84,33.45 169.73,34.34 169.73,38.41 169.98,38.66 169.98,38.85 169.98,40 169.92,40 169.85,40.06 163.76,40.06 162.74,39.04 159.31,39.04 159.06,39.3 159.06,50.97 159.91,51.83 159.95,51.87 160.58,51.87
+0.675VS on BOTTOM: 58.45,27.21 59.03,27.21 59.16,27.08 59.16,26.06 59.03,25.94 58.2,25.94 58.04,26.09 58.04,26.8
+0.675VSP on BOTTOM (solid shape): 61.02,31.39 61.02,30.66 63.01,28.66 63.01,27.48 62.74,27.21 61.31,27.21 61.17,27.07 61.17,25.73 60.89,25.45 59.62,25.45 59.29,25.78 59.29,26.34 59.85,26.34 59.85,26.85 59.29,26.85 59.29,27.54 59.44,27.69 60.09,27.69 60.31,27.9 60.31,31.02 59.9,31.43 59.9,31.51 59.92,31.52 60.88,31.52
+1.05V_LDO_3V on BOTTOM (solid shape): 96.68,120.67 96.63,120.62 96.63,119.99 96.58,119.94 96.58,119.37 96.53,119.31 96.38,119.31 96.33,119.37 96.33,119.98 96.11,120.19 96.11,120.36 95.79,120.67 95.79,121.33 96.68,121.33
+1.05V_PEX_VDD on BOTTOM: 88.96,106.1 88.96,105.59 88.7,105.34 87.18,105.34 86.92,105.08 84.61,105.08 84.46,105.23 84.46,106.25 84.66,106.45 85.91,106.45 86.08,106.28 88.78,106.28
+1.05V_PEX_VDD on BOTTOM: 53.14,76 53.65,76 54.67,77.02 55.05,77.02 55.17,76.89 55.68,76.89 57.46,78.67 57.46,78.79 57.84,79.17 57.97,79.17 58.35,79.56 58.35,79.68 59.11,80.44 60.63,80.44 61.02,80.06 61.4,80.06 61.52,80.19 61.9,80.19 62.03,80.06 65.46,80.06 66.1,80.7 67.24,80.7 67.37,80.57 67.49,80.57 67.75,80.83 67.75,80.95 66.98,81.71 66.6,81.71 66.35,81.46 59.75,81.46 59.49,81.71 57.84,81.71 56.57,80.44 56.44,80.44 56.06,80.06 56.06,79.94 54.16,78.03 53.14,78.03 52.76,77.65 52.76,76.38
+1.05V_PEX_VDD on IN2: 85.27,106.48 85.65,106.1 85.65,103.02 84.26,101.63 84.26,98.73 80.38,94.86 80.38,91.56 77.45,88.62 75.82,88.62 74.69,89.75 74.69,89.77 74.5,89.96 74.5,90.76 75.01,91.26 75.7,91.26 76.32,91.89 76.32,92.7 76.89,93.27 76.89,95.43 77.27,95.81 77.27,96.67 80.75,100.15 80.75,102.08 83.11,104.45 83.11,105.72 83.88,106.48
+1.05V_PEX_VDD on IN3: 53.51,75.12 52.89,75.75 52.89,76.81 57.31,81.23 57.31,83.52 60.53,86.74 63.63,86.74 68.28,91.39 68.28,91.42 68.41,91.54 69.37,91.54 69.5,91.67 73.77,91.67 74.05,91.39 76.59,91.39 76.6,91.38 77.03,91.38 77.37,91.04 77.37,89.94 70.43,83 70.04,83 70.03,82.98 69.02,82.98 68,81.97 68,81.84 66.96,80.8 65.94,80.8 65.76,80.62 65.76,80.24 66.53,79.48 66.53,77.4 66.37,77.24 66.37,77.22 65.56,76.41 63.83,76.41 63.3,75.87 59.01,75.87 58.26,75.12
+1.05V_PEX_VDD_UV15 on BOTTOM: 86.54,104.83 86.67,104.7 86.67,103.43 86.16,102.92 86.16,102.29 86.03,102.16 85.27,102.16 84.64,102.8 84,102.8 83.88,102.92 83.88,103.81 84.89,104.83
+1.5VS on BOTTOM (solid shape): 165.67,118.53 166.22,118.53 166.22,119.08 166.47,119.08 166.47,118.53 167.02,118.53 167.02,119.08 167.34,119.08 167.5,118.93 167.5,117.18 167.14,116.82 165.59,116.82 165.13,117.27 165.13,118.89 165.33,119.08 165.67,119.08
+1.05VS on BOTTOM (solid shape): 113.29,120.17 113.29,116 112.62,115.33 111.32,115.33 110.65,116 110.65,117.4 111.22,117.4 111.22,119.43 110.65,119.43 110.65,120.27 110.92,120.53 112.92,120.53
+1.05VS on TOP: 104.99,109.91 106.79,109.91 108.06,111.18 110.67,111.18 112.93,113.44 112.93,118.54 113.4,119.01 113.4,120.32 113.23,120.49 110.76,120.49 110.1,119.83 110.1,116.73 106.35,112.98 105.56,112.98 104.75,113.79 98.25,113.79 97.44,112.98 96.78,112.98 96.74,112.94 95.76,112.94 92.94,110.13 91.92,110.13 88.78,106.99 88.78,105.97 88.93,105.82 90.71,105.82 93.48,108.59 94.22,108.59 96.67,111.05 103.85,111.05
+1.05VS on TOP: 144.56,116.49 149.53,116.49 149.79,116.23 149.79,115.22 149.51,114.94 144.66,114.94 144.4,115.19 144.4,116.33
+1.05VS on BOTTOM: 90.15,103.61 90.15,102.6 89.73,102.19 87.51,102.19 87.38,102.31 87.38,102.95 88.42,103.99 88.42,104.8 89.08,105.46 89.08,106.48 89.34,106.73 90.89,106.73 91.09,106.53 91.09,104.55
+1.05VS on BOTTOM: 144.84,114.48 150.42,114.48 150.68,114.73 150.68,116.39 150.42,116.64 144.96,116.64 144.71,116.39 144.71,114.61
+1.05VS on IN1: 143.18,89.59 148.14,89.59 148.26,89.72 148.26,90.73 147.76,91.24 143.44,91.24 142.93,90.73 142.93,89.84
+1.05VS on VCC: 142.3,89.97 142.3,90.2 141.89,90.6 141.64,90.6 140.64,91.6 140.64,94.41 142.53,94.41 143.69,95.58 143.69,109.76 136.56,116.89 113.49,116.89 112.6,116 111.67,116 111.56,116.11 111.56,123.98 121.66,123.98 121.7,123.9 122.53,122.87 123.8,122.48 141.8,122.48 143.02,122.84 143.86,123.79 143.9,123.88 143.94,123.98 161.85,123.98 161.85,123.4 161.85,123.4 161.85,110.9 157.54,106.58 157.54,93.4 145.87,93.4 144.45,91.98 144.45,90.1 143.21,90.1 143.08,89.97
+1.05VS on IN3: 150.93,90.3 151.9,90.3 152.07,90.48 152.07,91.75 151.82,92 151.57,92 151.31,92.26 151.31,92.51 151.57,92.76 151.57,93.02 151.26,93.32 151.26,94.49 149.05,96.7 148.26,96.7 147.88,96.32 147.25,96.32 147.12,96.45 145.55,96.45 145.17,96.07 145.17,95.48 145.34,95.3 145.62,95.3 145.8,95.13 145.8,94.74 145.34,94.29 145.34,93.53 145.6,93.27 149.41,93.27 150.3,92.38 150.3,90.93
+1.05VS on IN3: 91.04,101.83 94.21,101.83 94.8,102.42 95.43,102.42 96.21,101.64 101.54,101.64 102.67,100.51 102.67,99.62 102.43,99.38 101.66,99.38 101.55,99.48 101.53,99.48 100.39,100.62 100.37,100.62 100.36,100.64 90.35,100.64 88.83,102.16 88.83,102.54 89.21,102.92 89.95,102.92
+1.05VSP on BOTTOM (solid shape): 110.48,122.74 110.48,114.92 109.97,114.42 108.32,114.42 108.13,114.23 108.13,113.08 107.94,112.89 106.54,112.89 106.48,112.96 106.48,114.42 105.91,114.99 105.91,120.7 106.61,121.4 106.61,122.74 107.39,122.74 107.61,122.95 110.27,122.95
+1.5VSP on BOTTOM (solid shape): 172.65,119.43 172.65,116.77 172.39,116.51 170.74,116.51 170.49,116.77 170.49,117.27 170.24,117.53 168.99,117.53 168.61,117.91 168.58,117.91 168.58,118.63 168.41,118.8 168.06,118.8 167.63,119.24 166.87,119.24 166.87,118.69 166.63,118.69 166.63,119.24 166.07,119.24 166.07,118.69 165.83,118.69 165.83,119.24 165.35,119.24 165.22,119.36 165.22,120.4 165.38,120.55 171.53,120.55
+1.8V_VGA on IN1: 196.02,106.67 196.45,107.1 196.45,113.28 195.57,114.16 186.4,114.16 185.71,113.47 185.71,110.51 181.05,105.85 181.05,103.91 181.36,103.6 181.7,103.6 187.81,109.71 187.81,112.24 188.5,112.93 193.56,112.93 193.85,112.65 193.85,107.33 194.5,106.67
+1.8V_VGA_IVDD on IN1: 189.91,112.5 192.37,112.5 193.18,111.7 193.18,104.62 191.66,103.1 184.42,103.1 184.19,103.34 184.19,104.99 184.55,105.36 190.12,105.36 190.35,105.59 190.35,111.44 189.7,112.09 189.7,112.29
+1.35V on BOTTOM (solid shape): 66.46,23.95 67.23,23.95 67.23,24.51 67.65,24.51 67.65,23.96 68.42,23.96 68.42,24.51 71.69,24.51 71.69,23.95 72.46,23.95 72.46,24.51 72.88,24.51 72.88,23.95 73.65,23.95 73.65,24.51 74.16,24.51 74.37,24.3 74.37,23.43 73.14,22.2 66.07,22.2 65.59,22.68 65.59,24.38 65.73,24.51 66.46,24.51
+1.35V on TOP: outline of 96 points within 99.13,27.3 147.13,91.75 ; 7 cut-outs
+1.35V on BOTTOM: 140.9,39.17 141.41,39.68 141.91,39.68 142.55,39.04 144.84,39.04 145.09,38.79 145.09,38.41 144.96,38.28 134.75,38.28 134.73,38.25 134.37,38.25 134.19,38.43 134.19,38.66 134.7,39.17
+1.35V on VCC: 65.71,22.41 65.71,31.68 75.6,31.68 79.03,35.11 107.35,35.11 108.62,36.38 148.77,36.38 148.77,28.73 148.41,28.37 80.85,28.37 74.88,22.41
+1.35VGPUP on TOP (solid shape): 32.18,56.07 32.18,55.77 32.37,55.58 33.14,55.58 33.14,56.13 33.59,56.13 33.59,55.58 34.34,55.58 34.34,56.13 34.79,56.13 34.79,55.58 35.74,55.58 35.74,54.16 34.85,53.27 31.98,53.27 31.55,53.7 31.55,56.01 31.7,56.16 32.08,56.16
+1.35VGPUP on BOTTOM (solid shape): 38.41,56.06 38.41,53.65 38.16,53.39 28.88,53.39 28.63,53.65 28.63,55.93 28.88,56.19 38.28,56.19
+1.35VP on BOTTOM (solid shape): 76.26,31.32 76.26,25.73 75.19,24.66 73.5,24.66 73.5,24.11 73.05,24.11 73.05,24.66 72.29,24.66 72.29,24.11 71.85,24.11 71.85,24.66 69.11,24.66 69.1,24.65 68.26,24.65 68.26,24.11 67.82,24.11 67.82,24.67 67.06,24.67 67.06,24.11 66.62,24.11 66.62,24.66 65.18,24.66 64.7,25.15 64.7,27.74 64.47,27.97 64.47,29.64 64.85,30.03 67.75,30.03 69.49,31.76 75.81,31.76
+1.35VS_VGA on TOP (solid shape): 36.12,57.58 36.12,55.73 34.94,55.73 34.94,56.29 34.19,56.29 34.19,55.74 33.74,55.74 33.74,56.29 32.99,56.29 32.99,55.74 32.47,55.74 32.43,55.78 32.43,56.16 32.27,56.31 32.06,56.31 31.68,56.7 31.68,57.08 32.44,57.84 35.87,57.84
+1.35VS_VGA on TOP: 60.57,94.88 60.81,94.64 61.4,94.64 62.79,96.04 62.79,96.07 62.84,96.07 63.29,96.51 63.75,96.51 63.94,96.32 63.94,93.59 63.69,93.35 63.43,93.35 63.25,93.17 63.25,91.14 63.48,90.91 64.7,90.91 65.05,91.26 65.05,93.75 65.51,94.21 65.51,97.89 64.75,98.66 62.59,98.66 60.57,96.64
+1.35VS_VGA on BOTTOM: 59.03,89.74 59.03,87.76 59.54,87.25 59.54,86.97 58.75,86.18 58.75,82.37 58.93,82.2 58.93,81.87 58.83,81.76 58.32,81.76 57.64,82.45 57.64,82.7 57.48,82.86 57.48,83.09 57.74,83.34 57.74,84.15 57.71,84.18 57.71,85.7 57.97,85.96 57.97,87.78 58.13,87.95 57.21,88.88 57.21,88.9 57.08,89.03 57.08,89.13 58.07,90.12 58.4,90.12 58.6,89.92 58.86,89.92
+1.35VS_VGA on BOTTOM: 59.36,91.06 59.8,91.06 60.56,91.82 62.18,91.82 62.39,91.62 62.41,91.62 62.46,91.57 63.22,91.57 63.3,91.49 63.3,91.39 63.58,91.11 63.94,91.11 65.13,92.31 65.13,92.79 64.42,93.5 63.71,93.5 63.31,93.11 63.3,93.12 62.62,93.12 62.03,92.53 61.22,92.53 60.56,93.19 60.15,93.19 60.01,93.06 58.44,93.06 58.09,92.71 58.09,92.1 58.31,91.89 58.54,91.89
+1.35VS_VGA on VCC: 31.91,56.7 29.9,58.71 29.9,73.18 26.22,76.87 26.22,97.18 33.76,104.78 35.11,106.12 35.11,106.88 35.97,107.75 58.75,107.75 62.79,103.71 62.79,103.07 65.33,100.53 65.33,91.22 65.23,91.11 60.02,91.11 59.62,90.71 59.62,87.03 58.6,86.01 58.6,84.11 58.48,83.98 58.48,83.26 58.88,82.86 59.51,82.86 59.62,82.75 59.62,80.17 56.44,76.99 56.44,76.23 49.97,69.75 49.97,56.7
+3.3V_RUN_GFX on BOTTOM (solid shape): outline of 388 points within 73.43,81.93 85.68,102.78
+3.3V_RUN_GFX on TOP: 75.62,85.51 77.27,85.51 77.58,85.82 77.58,86.71 77.45,86.84 76.91,86.84 76.2,86.14 75.57,86.14 75.53,86.09 75.53,85.6
+3.3V_RUN_GFX on BOTTOM: 71.38,71.47 71.21,71.3 71.21,70.92 71.33,70.8 74.61,70.8 75.4,71.59 75.4,71.85 75.24,72.01 74.97,72.01 74.43,71.47
+3.3V_RUN_GFX on IN3: 70.98,80.33 76.01,80.33 79.05,83.37 79.05,93.27 78.41,93.91 76.97,93.91 73.94,96.93 73.92,96.93 73.49,97.36 73.05,97.36 72.06,98.35 71.68,98.35 71.05,98.99 70.54,98.99 70.16,98.61 70.16,94.54 69.02,93.4 65.84,93.4 65.59,93.14 65.59,92.51 66.1,92 67.24,92 67.62,92.38 69.52,92.38 69.91,92 75.37,92 75.54,91.82 77.17,91.82 77.83,91.16 77.83,87.12 77.6,86.9 76.99,86.9 74.19,84.09 72.29,84.09 70.93,82.73 69.55,82.73 67.31,80.49 67.31,76.94 68.36,75.9 75.8,75.9 76.13,76.23 76.13,76.94 75.8,77.27 72.57,77.27 71.89,76.58 69.24,76.58 68.51,77.32 68.51,78.79 69.07,79.35 69.07,79.73 69.45,80.11 70.77,80.11
+3.3V_RUN_GFX_UV15 on BOTTOM (solid shape): 86.16,100.76 86.16,98.52 85.91,98.28 85.14,98.28 85.14,98.83 84.64,98.83 84.64,98.28 84.31,98.28 84.06,98.53 84.06,100.43 84.14,100.51 84.76,100.51 85.15,100.89 86.03,100.89
+3V_DSW on TOP (solid shape): 174.96,70.19 174.96,67.88 175.51,67.88 175.51,67.65 174.96,67.65 174.96,67.09 175.51,67.09 175.51,66.85 174.95,66.85 174.95,66.13 174.66,65.84 172.72,65.84 172.39,66.17 172.39,69.09 172.35,69.13 172.36,69.14 172.36,70 172.9,70.54 174.61,70.54
+3V_DSW on IN1: 151.44,93.14 154.61,93.14 155.88,91.87 155.88,91.62 155.63,91.37 151.31,91.37 151.06,91.62 151.06,92.76
+3VA on TOP (solid shape): 182.48,18.82 182.48,17.99 182.3,17.81 181.39,17.81 181.23,17.96 181.23,18.8 181.31,18.87 182.42,18.87
+3VA on TOP (solid shape): 182.81,22.6 183.18,22.6 183.65,22.13 183.96,22.13 184.01,22.07 184.01,21.97 183.96,21.92 182,21.92 181.8,22.11 181.8,22.2 181.33,22.67 181.33,23.42 181.39,23.47 181.93,23.47
+3VALW on TOP (solid shape): 138.59,11 138.59,9.83 138.33,9.58 137.65,9.58 137.01,8.94 136.5,8.94 136.43,9.02 136.43,10.26 137.39,11.23 138.36,11.23
+3VALW on TOP (solid shape): 106.15,22.33 106.15,17.63 106.05,17.53 105.47,17.53 105.36,17.63 105.36,20.8 105.16,21.01 103.97,21.01 103.8,21.17 103.8,21.48 103.79,21.49 103.79,22.25 104.07,22.53 105.95,22.53
+3VALW on TOP (solid shape): 188.3,84.05 188.3,74.73 183.78,70.21 181.03,70.21 179.62,68.8 177.86,68.8 177.27,69.4 177.27,71.68 178.43,72.84 182.77,72.84 185.82,75.89 185.82,78.79 185.86,78.83 185.86,79.14 185.82,79.18 185.82,81.49 185.2,82.11 184.77,82.11 184.56,82.32 184.56,82.75 185.51,83.7 185.51,84.17 185.61,84.27 188.08,84.27
+3VALW on BOTTOM (solid shape): 43.24,43.74 43.24,42.41 42.73,42.41 42.73,42.92 42.66,42.98 40.7,42.98 40.7,42.47 40.63,42.41 38.98,42.41 38.73,42.66 38.73,44.57 38.98,44.82 42.16,44.82
+3VALW on BOTTOM (solid shape): 175.73,111.52 176.29,111.52 176.29,112.08 176.53,112.08 176.53,111.53 178.97,111.53 179.26,111.23 179.26,110.5 179.08,110.32 175.06,110.32 174.92,110.46 174.92,111.43 175.02,111.53 175.49,111.53 175.49,112.08 175.73,112.08
+3VALW on BOTTOM (solid shape): 180.9,69.31 180.9,68.76 180.87,68.69 180.8,68.66 180.45,68.3 180.8,67.95 180.87,67.92 180.9,67.85 180.9,66.73 180.52,66.35 177.6,66.35 177.35,66.6 177.35,69.54 177.62,69.81 180.4,69.81
+3VALW on IN1 (solid shape): 90.99,22.91 89.26,21.19 88.78,21.19 88.32,21.64 88.32,21.9 89.46,23.04 90.86,23.04
+3VALW on IN2 (solid shape): 89.36,100.28 89.36,98.88 88.96,98.48 88.02,98.48 87.56,98.94 87.56,99.88 88.51,100.83 88.82,100.83
+3VALW on TOP: 179.73,65.14 180.49,65.14 180.75,65.4 180.75,67.3 180.49,67.56 177.47,67.56 177.33,67.41 177.33,66.65 177.7,66.29 179.35,66.29 179.6,66.03 179.6,65.27
+3VALW on TOP: 178.63,52.68 179.48,52.68 179.57,52.59 179.57,51.25 180,50.82 180,50.05 179.83,49.87 177.27,49.87 176.97,50.17 176.08,50.17 175.93,50.32 175.93,51.39 176.03,51.49 176.92,51.49 177.06,51.63 177.06,52.08 176.91,52.23 176.02,52.23 175.94,52.32 175.94,52.8 175.46,53.27 174.58,53.27 174.19,53.67 173.28,53.67 173.16,53.79 173.16,56.11 173.25,56.2 174.31,56.2 174.62,55.89 175.41,55.89
+3VALW on TOP: 182.14,62.03 182.27,62.16 182.27,64.19 182.14,64.32 181.57,64.32 181.08,63.83 180.37,63.83 180.32,63.88 179.68,63.88 179.61,63.81 179.61,63.25 180.83,62.03
+3VALW on TOP: 12.76,83.37 13.9,82.22 13.9,79.13 13.66,78.89 11.67,78.89 11.49,79.08 11.49,84.38 11.65,84.54 12.54,84.54 12.76,84.33
+3VALW on BOTTOM: 92.26,119.37 92.26,118.23 92.13,118.1 90.86,118.1 90.61,118.35 90.61,119.24 90.86,119.5 92.13,119.5
+3VALW on BOTTOM: 104.07,21.64 104.96,21.64 105.08,21.52 105.08,20.88 104.7,20.5 104.2,20.5 103.94,20.75 103.94,21.52
+3VALW on BOTTOM: 88.07,38.79 88.96,38.79 89.59,38.15 89.59,36.88 88.83,36.12 88.83,31.42 90.99,29.26 90.99,21.9 88.96,19.87 82.48,19.87 81.97,20.37 81.97,21.77 86.8,26.6 86.8,37.52
+3VALW on BOTTOM: 88.62,100.81 88.68,100.76 88.98,100.76 89.11,100.64 89.11,99.86 88.82,99.57 87.63,99.57 87.43,99.77 87.43,100.74 87.51,100.81
+3VALW on IN1: 91.85,68.4 93.25,68.4 93.58,68.07 93.58,53.77 94.52,52.83 94.52,50.27 94.09,49.84 91.98,49.84 91.52,50.29 91.5,50.29 91.5,68.05
+3VALW on VCC: 48.8,31.04 47.66,32.18 41.56,32.18 41.2,32.54 41.2,39.66 39.55,41.31 39.55,49.86 41.31,51.62 94.44,51.62 95.05,51 95.05,44.52 97.49,42.09 160.82,42.09 161.6,42.87 161.6,44.91 162.49,45.79 162.49,65.08 173.52,65.08 177.09,68.65 177.09,70.54 185.09,70.54 185.09,66.71 174.3,55.91 174.3,48.55 162.64,36.88 108.41,36.88 107.14,35.61 78.82,35.61 75.39,32.18 60.02,32.18 59.39,31.55 58.33,31.55 57.69,32.18 50.37,32.18 49.23,31.04
+3VALW on IN2: 91.42,66.07 89.77,67.72 88.09,67.72 84.87,70.94 84.87,72.32 84.23,72.95 82.71,72.95 80.45,75.21 80.45,75.8 81.74,77.09 82.41,76.42 82.41,76.37 83.74,75.05 85.18,75.05 87.3,72.93 87.3,71.48 88.88,69.9 88.88,69.88 90.76,69.88 93.4,67.24 93.4,66.35 93.12,66.07
+3VALW on IN2: 18.51,56.91 24.12,51.3 28.15,51.3 29.86,49.58 32.57,49.58 36.81,45.34 41.91,45.34 42.22,45.04 42.22,42.47 41.94,42.19 30.13,42.19 25.91,46.41 18.32,46.41 16.82,47.91 16.82,47.93 16.79,47.96 15.27,47.96 14.91,48.31 14.91,69.53 12.55,71.89 12.55,81.87 12.87,82.2 14.65,82.2 14.98,81.87 14.98,72.93 18.51,69.39
+3VALW_1099 on TOP (solid shape): 103.69,25.53 103.69,24.79 103.64,24.74 101.81,24.74 101.78,24.72 100.46,24.72 100.31,24.87 100.31,25.5 100.46,25.66 103.56,25.66
+3VALW_1099 on TOP (solid shape): 104.65,19.13 104.65,16.97 104.45,16.77 102.8,16.77 102.7,16.87 102.7,17.12 102.87,17.3 102.87,17.91 102.72,18.06 101.93,18.06 101.78,18.21 101.78,18.75 101.91,18.87 103.66,18.87 104.04,19.26 104.53,19.26
+3VALW_5085 on TOP (solid shape): 135.72,10.11 135.72,8.92 135.41,8.61 134.34,8.61 134.19,8.77 134.19,9.96 134.42,10.19 135.64,10.19
+3VALW_5085 on TOP: 66.17,19.59 66.04,19.71 66.04,20.7 66.15,20.8 72.76,20.8 72.98,20.59 72.98,19.79 72.78,19.59
+3VALW_PCH on TOP (solid shape): 174.96,63.44 174.96,62.81 175.51,62.81 175.51,62.56 174.96,62.56 174.96,62.01 175.51,62.01 175.51,61.76 174.96,61.76 174.96,61.05 175.12,60.9 175.48,60.9 175.71,60.67 175.71,59.41 175.54,59.24 174.14,59.24 174.14,59.24 171.89,59.24 171.6,59.52 171.6,63.68 171.73,63.81 174.6,63.81
+3VALW_PCH on TOP: 173.28,82.98 173.41,83.11 173.41,84.8 173.55,84.94 174.39,84.94 174.39,84.94 174.91,84.94 175.19,84.66 175.19,82.65 174.76,82.22 174.76,80.99 174.4,80.63 173.41,80.63 173.28,80.76
+3VALW_PCH on TOP: 173.47,86.64 173.41,86.7 173.41,88.37 173.47,88.44 174.12,88.44 174.52,88.04 174.72,88.04 174.85,87.91 174.85,87.12 174.37,86.64
+3VALW_PCH on BOTTOM: 173.79,62.16 173.66,62.28 173.66,63.07 171.33,65.41 170.29,65.41 169.98,65.71 169.35,65.71 169.09,65.97 169.09,66.47 169.35,66.73 171.68,66.73 174.81,63.6 174.81,62.28 174.68,62.16
+3VALW_PCH on VCC: 162.49,65.59 162.49,71.53 160.46,73.56 160.46,77.12 160.08,77.5 160.08,79.79 159.55,80.32 153.7,80.32 153.2,80.83 151.29,80.83 148.77,83.34 148.77,89.19 148.37,89.59 145.19,89.59 144.96,89.82 144.96,91.77 146.08,92.89 164.24,92.89 166.28,94.92 173.43,94.92 173.94,94.41 174.32,94.41 176.59,92.15 176.59,68.87 173.3,65.59
+3VALW_PCH_GATE on TOP: 181.41,64.57 182.14,64.57 182.27,64.7 182.27,66.73 182.14,66.86 181.63,66.86 181.38,66.6 181.38,64.6
+3VALWP on BOTTOM (solid shape): 45.88,39.96 50.25,39.96 50.47,40.19 54.54,40.19 54.99,39.73 54.99,36.71 53.26,34.98 47.68,34.98 45.97,36.69 42.03,36.69 41.58,37.14 41.58,38.79 40.19,40.19 40.19,42.22 43.62,42.22
+3VLP on TOP (solid shape): 55.23,29.24 55.31,29.2 55.33,29.11 55.45,28.77 55.81,28.7 55.9,28.69 55.95,28.61 55.95,28.03 55.96,28.03 55.99,27.97 55.88,27.87 54.41,27.87 54.16,28.12 54.16,28.63 54.77,29.24
+3VLP on BOTTOM (solid shape): 79.73,52.86 79.73,51.44 79.63,51.34 79,51.34 78.92,51.41 78.92,52.86 78.97,52.91 79.68,52.91
+3VLP on IN3 (solid shape): 79.49,15.14 79.49,14.52 79.24,14.28 77.55,14.28 77.31,14.52 77.31,15.28 77.44,15.41 79.22,15.41
+3VLP on IN3 (solid shape): 57.26,28.42 57.26,27.41 57,27.15 54.89,27.15 54.18,27.87 54.03,27.87 53.78,28.12 53.78,28.5 53.93,28.65 57.03,28.65
+3VS on TOP (solid shape): 92.38,118.16 92.38,117.4 92.26,117.27 91.11,117.27 90.67,117.72 90.67,118.54 90.92,118.8 91.75,118.8
+3VS on IN1 (solid shape): 92.38,117.91 92.38,116.51 92.26,116.39 91.37,116.39 91.18,116.58 91.18,117.91 91.37,118.1 92.19,118.1
+3VS on TOP: 158.93,116 162.62,112.32 165.54,112.32 166.04,112.83 166.04,114.35 161.09,119.31 151.95,119.31 151.32,118.68 151.32,116.66 151.99,116
+3VS on TOP: 88.07,90.48 88.19,90.35 88.19,88.95 87.94,88.7 87.94,88.16 87.75,87.97 86.63,87.97 86.16,88.45 86.16,89.33 86.8,89.97 87.38,89.97 87.63,90.22 87.63,90.32 87.79,90.48
+3VS on TOP: 179.66,57.3 179.85,57.48 179.85,58.21 180.11,58.47 180.41,58.47 180.8,58.87 180.8,59.72 180.57,59.95 176.23,59.95 175.86,59.58 175.86,58.22 174.55,56.91 174.55,56.32 174.76,56.11 176.04,56.11 177,57.07 177.23,57.3 177.84,57.3 177.84,56.75 178.09,56.75 178.09,57.3 178.64,57.3 178.64,56.75 178.89,56.75 178.89,57.3
+3VS on BOTTOM: 182.94,58.98 186.62,58.98 188.02,60.38 188.02,71.68 187.76,71.94 184.71,71.94 184.46,71.68 184.46,62.79 184.21,62.54 178.74,62.54 177.98,61.78 177.98,58.73 178.24,58.47 182.43,58.47
+3VS on IN1: 86.42,89.72 86.92,89.72 87.18,89.46 87.18,87.94 86.92,87.68 85.91,87.68 85.65,87.94 85.65,88.95
+3VS on IN1: 81.46,100.67 81.46,99.86 81.26,99.65 80.69,99.65 80.45,99.9 80.45,101.12 81.4,102.08 81.65,102.08 82.11,101.62 82.11,101.32
+3VS on IN1: 87.63,97.59 87.94,97.59 88.27,97.26 88.27,96.78 87.56,96.07 86.97,96.07 86.64,96.4 86.64,96.6
+3VS on VCC: 177.09,71.05 177.09,92.36 174.53,94.92 174.15,94.92 173.64,95.43 166.07,95.43 164.03,93.4 158.04,93.4 158.04,106.37 162.36,110.69 162.36,113.21 188.29,113.21 187.76,112.68 187.76,71.53 187.27,71.05
+3VS on IN2: 150.44,98.87 151.46,97.84 155.96,97.84 156.19,97.61 159.8,97.61 160.08,97.34 160.08,95.3 159.74,94.97 157.22,94.97 156.4,94.16 156.4,94.15 156.09,93.83 151.46,93.83 150.75,94.54 147.58,94.54 146.97,95.15 146.97,98.58 147.26,98.87
+3VS on IN3: 86.67,97.46 87.94,97.46 88.07,97.34 88.07,96.57 87.43,95.94 86.81,95.94 86.26,96.49 86.26,97.05
+3VS on IN3: 80.57,99.88 80.57,101.02 80.83,101.27 81.08,101.27 81.34,101.02 81.34,100.51 81.59,100.26 81.59,99.75 81.34,99.49 80.95,99.49
+3VS_VGA on BOTTOM (solid shape): 184.91,113.02 185.98,113.02 186.08,112.92 186.08,112.3 185.84,112.06 184.28,112.06 183.9,112.44 183.9,113.15 183.95,113.2 184.74,113.2
+3VS_VGA on IN2: 190.94,103.7 190.44,104.19 190.44,111.05 189.36,112.14 185.76,112.14 185.39,112.51 185.39,114.45 185.78,114.85 185.92,114.85 186.28,114.77 186.65,114.75 193.31,114.75 193.35,114.7 202.29,114.7 205.49,111.5 205.49,103.51 204.71,102.72 200.84,102.72 199.36,104.19 194.51,104.19 194.02,103.7
+3VS_WLAN_NGFF on TOP: 171.67,55.27 171.42,55.01 171.42,50.87 171.52,50.76 172.87,50.76 172.9,50.73 174.49,50.73 174.55,50.79 174.55,51.46 174.5,51.5 173.87,51.5 173.17,52.21 173.17,53.1 173.03,53.24 173.03,55.18 172.94,55.27
+3VS_WLAN_NGFF on TOP: 188.9,50.09 191.19,50.09 191.32,50.22 191.32,51.11 190.81,51.62 188.9,51.62 188.78,51.49 188.78,50.22
+3VS_WLAN_NGFF on BOTTOM: 190.17,49.33 190.81,49.33 191.06,49.58 191.06,52.5 190.81,52.76 189.16,52.76 188.9,53.01 188.9,54.92 188.27,55.55 177.12,55.55 174.35,52.78 173.02,52.78 172.21,51.96 172.21,49.91 172.72,49.4 173.24,49.4 173.38,49.53 173.38,50.98 173.54,51.14 174.62,51.14 176.75,53.27 185.09,53.27 187.13,51.23 189.79,51.23 190.17,50.85
+5V_HDD on BOTTOM (solid shape): outline of 247 points within 182.36,20.86 189.53,28.66
+5V_PVDD on TOP: 187.51,25.58 187.74,25.35 187.74,24.41 187.84,24.31 188.09,24.31 188.65,24.87 188.65,25.96 188.52,26.09 187.89,26.09 187.51,26.47 186.75,26.47 186.36,26.85 186.36,26.87 186.05,27.18 186.05,28.85 185.89,29.02 183.18,29.02 182.68,28.52 182.68,25.35 182.96,25.07 182.96,24.06 183.09,23.93 184.38,23.93 184.81,23.5 184.89,23.5 185.12,23.27 185.12,22.49 185.18,22.43 185.26,22.43 185.32,22.49 185.32,23.46 183.92,24.86 183.92,25.4 184.1,25.58
+5V_USB_PWR1 on TOP (solid shape): 199.19,38.23 199.19,35.69 198.99,35.49 195.04,35.49 194.84,35.68 194.84,36.02 194.99,36.16 195.69,36.16 197.94,38.41 199.01,38.41
+5V_USB_PWR1 on BOTTOM (solid shape): 200.08,44.63 200.08,43.11 199.45,42.47 199.45,41.46 199.32,41.33 199.32,34.56 197.98,33.23 195.62,33.23 195.51,33.34 195.51,37.61 195.7,37.61 195.7,37.55 195.71,37.5 195.72,37.45 195.75,37.4 195.78,37.36 195.81,37.32 195.85,37.29 195.9,37.26 195.95,37.24 196,37.23 196.05,37.22 196.11,37.23 196.16,37.24 196.21,37.26 196.26,37.29 196.3,37.32 196.33,37.36 196.36,37.4 196.39,37.45 196.4,37.5 196.41,37.55 196.41,37.61 196.4,37.66 196.39,37.71 196.36,37.76 196.33,37.8 196.3,37.84 196.26,37.88 196.21,37.9 196.16,37.92 196.11,37.93 196.05,37.94 196,37.93 195.95,37.92 195.9,37.9 195.85,37.88 195.81,37.84 195.78,37.8 195.75,37.76 195.72,37.71 195.71,37.66 195.7,37.61 195.51,37.61 195.51,38.28 196.69,39.46 196.69,42 198.05,43.36 198.05,44.5 198.56,45.01 199.7,45.01
+5V_USB_PWR2 on TOP: 193.72,27.49 194.5,27.49 194.66,27.32 194.66,26.17 195.14,25.69 195.14,24.62 194.85,24.33 193.98,24.33 193.56,24.75 193.56,27.33
+5V_USB_PWR2 on BOTTOM: 194.11,25.71 195.46,25.71 195.46,25.73 196.04,26.32 196.04,26.34 196.14,26.44 196.14,26.47 198.3,26.47 198.63,26.8 198.66,26.8 198.81,26.95 199.52,26.95 200.26,26.22 200.26,25.25 199.19,24.18 199.19,24.18 198.75,23.74 194.82,23.74 194.64,23.92 192.47,23.92 192.16,24.23 192.16,26.39 193.68,26.39 193.86,26.22 193.86,25.96
+5V_USB_PWR2 on IN3: 193.35,25.96 197.54,25.96 198.68,27.1 199.83,27.1 200.33,26.6 200.33,25.33 199.19,24.18 196.27,24.18 195.64,23.55 194.75,23.55 193.22,25.07 193.22,25.83
+5V_USB_PWR3 on TOP: 28.5,39.18 26.46,37.14 22.55,37.14 21.31,38.39 21.31,40.07 21.42,40.19 22.03,40.19 22.16,40.05 22.16,39.54 22.56,39.15 24.09,39.15 25.34,40.39 25.34,48.68 26.19,49.53 28.2,49.53 28.5,49.22
+5V_USB_PWR3 on BOTTOM: 25.16,46.55 27.58,46.55 27.83,46.8 27.83,50.03 27.63,50.23 25.29,50.23 25.04,49.98 25.04,46.67
+5VALW on TOP (solid shape): 58.86,37.52 58.86,36.12 57.84,35.11 57.59,35.11 57.46,35.23 57.46,36.12 57.71,36.38 57.71,37.39 57.97,37.65 58.73,37.65
+5VALW on TOP (solid shape): 59.56,21.07 59.94,21.07 60.33,20.68 60.33,17.19 59.95,16.82 57.21,16.82 56.54,17.48 56.54,20.58 57.04,21.07 59.55,21.07
+5VALW on BOTTOM (solid shape): 58.78,36.37 58.78,35.19 58.55,34.95 58.55,33.25 58.49,33.2 58.39,33.2 58.34,33.25 58.34,34.42 57.48,35.28 57.48,36.07 57.84,36.42 58.73,36.42
+5VALW on BOTTOM (solid shape): 178.99,118.09 178.99,116.39 178.86,116.26 175.95,116.26 175.82,116.39 175.82,117.02 175.95,117.15 177.47,117.15 177.98,117.66 177.98,118.26 178.19,118.47 178.62,118.47
+5VALW on BOTTOM (solid shape): 59.56,21.07 59.94,21.07 60.33,20.68 60.33,17.19 59.95,16.82 57.46,16.82 57.21,17.07 57.21,17.9 57.27,17.96 57.59,17.96 57.46,18.09 57.46,20.18 57.21,20.18 57.21,20.82 57.46,21.07 59.55,21.07
+5VALW on TOP: 193.59,29.09 192.13,30.56 192.13,32 191.69,32.44 190.94,32.44 190.76,32.62 190.76,34.2 190.56,34.4 190.56,36.25 190.3,36.5 188.7,36.5 188.32,36.88 188.32,38.18 188.55,38.41 190.71,38.41 192.48,36.63 192.77,36.63 193.25,36.15 193.25,35.59 192.91,35.25 192.91,34.16 194.96,32.12 194.96,29.27 194.77,29.09
+5VALW on TOP: 19.63,41.79 19.63,42.85 19.15,43.33 19.15,45.55 19.44,45.84 21.81,45.84 22.15,45.5 22.15,41.76 22,41.62 19.81,41.62
+5VALW on TOP: 180.9,52.63 180.9,52 181.54,51.36 183.44,51.36 183.67,51.59 183.67,53.34 183.62,53.39 183.62,54.23 183.44,54.41 182.43,54.41 182.3,54.28 182.3,54.13 181.72,53.55 181.72,52.89 181.54,52.71 180.98,52.71
+5VALW on VCC: 107.15,4.22 106.33,4.95 105.27,5.22 104.45,5.22 104.45,7.65 102.4,9.71 96.29,9.71 96.14,9.72 96,9.72 60.57,9.72 60.57,9.95 59.84,12.63 57.84,14.57 57.84,21.41 58.33,21.9 75.09,21.9 81.06,27.87 110.29,27.87 110.29,25.22 110.82,24.69 128.09,24.69 131.01,21.77 148.88,21.77 151.42,24.31 159.42,24.31 179.63,44.52 179.63,53.03 180.75,54.16 186.64,54.16 188.9,51.89 188.9,46.56 193.1,42.37 193.1,31.15 192.1,30.15 187.75,30.15 187.15,29.55 187.15,27.7 187.76,27.09 187.76,26.62 189.59,24.79 189.59,24.44 188.65,23.5 188.65,17.81 188.54,17.71 184.1,17.71 180.9,14.51 180.9,12.88 176.1,12.88 175.06,11.84 175.06,7.08 173.79,5.82 172.99,4.22
+5VALW on IN2: 30.05,41.84 44.12,41.84 46.23,39.73 57.03,39.73 62.29,34.47 62.29,28.25 61.52,27.49 61.52,17.58 61.14,17.2 56.19,17.2 55.94,17.45 55.94,20.5 57.33,21.9 57.33,32.82 53.78,36.38 41.58,36.38 39.68,38.28 23.42,38.28 20.5,41.2 18.72,41.2 18.09,41.84 18.09,45.68 18.42,46.01 25.87,46.01
+5VALWP on TOP: 55.63,17.2 53.9,17.2 53.65,17.45 53.65,20.37 54.16,20.88 55.45,20.88 55.45,20.86 55.83,20.47 55.83,17.4
+5VALWP on BOTTOM: 46.98,19.42 48.32,20.75 56.44,20.75 56.7,20.5 56.7,16.44 55.94,15.67 55.17,15.67 52.89,13.39 46.16,13.39 45.52,14.02 43.04,14.02 41.52,15.55 41.52,19.04 41.9,19.42
+5VS on TOP (solid shape): 14.93,106.37 14.93,102.8 14.83,102.7 14.51,102.7 13.6,103.61 12.7,103.61 12.37,103.95 12.37,106.35 12.66,106.64 14.65,106.64
+5VS on TOP (solid shape): outline of 361 points within 181.54,42.57 197.92,59.87
+5VS on BOTTOM (solid shape): 199.76,113.6 199.88,113.44 200.06,113.38 200.33,113.1 200.33,112.83 200.08,112.58 198.56,112.58 197.92,113.22 197.92,113.46 198.06,113.6
+5VS on BOTTOM (solid shape): 188.72,28.79 188.72,28.46 188.52,28.26 186.57,28.26 186.57,28.82 186.02,28.82 186.02,28.26 185.77,28.26 185.77,28.82 185.21,28.82 185.21,28.26 184.83,28.26 184.71,28.38 184.71,29.48 184.97,29.75 187.76,29.75
+5VS on IN2 (solid shape): 75.02,50.83 75.02,48.31 74.85,48.14 74.01,48.14 73.83,48.31 73.83,50.8 74.03,51.01 74.85,51.01
+5VS on TOP: 75.75,50.73 73.97,50.73 73.72,50.47 73.72,48.06 73.84,47.93 75.11,47.93 75.62,48.44 75.62,49.33 75.87,49.58 75.87,50.6
+5VS on TOP: 191.15,112.18 191.97,113 197.23,113 197.59,112.64 198.83,112.64 199,112.82 199,113.46 197.79,114.67 189.53,114.67 189.4,114.54 189.4,113.96 190.44,112.92 190.44,112.52 190.79,112.18
+5VS on TOP: 191.62,28.16 191.62,28.98 191.2,29.4 186.53,29.4 186.34,29.21 186.34,28.05 186.52,27.87 191.33,27.87
+5VS on TOP: 85.15,50.98 86.03,50.98 87.3,49.71 87.3,49.33 87.05,49.08 85.78,49.08 84.89,49.96 84.89,50.73
+5VS on TOP: 115.75,24.44 115.24,23.93 113.72,23.93 113.47,24.18 113.47,25.2 113.34,25.33 107.5,25.33 102.93,29.9 99.5,29.9 98.73,30.66 98.73,33.07 98.86,33.2 99.5,33.2 100,32.69 100,32.57 100.64,31.93 103.31,31.93 106.61,28.63 115.24,28.63 115.75,28.12
+5VS on BOTTOM: 7.93,76.13 12.5,76.13 15.55,79.17 15.55,81.21 15.68,81.33 16.69,81.33 16.82,81.21 16.82,78.67 12.88,74.73 9.58,74.73 8.69,73.84 7.93,73.84 7.68,74.09 7.68,75.87
+5VS on IN1: 16.62,79.94 16.39,79.71 15.96,79.71 15.73,79.94 15.73,81.26 15.83,81.36 16.49,81.36 16.62,81.23
+5VS on IN1: 85.27,50.73 86.29,50.73 87.43,49.58 87.43,42.85 96.45,33.84 98.61,33.84 100,32.44 100,31.42 99.62,31.04 96.07,31.04 85.65,41.46 85.65,49.2 85.02,49.84 85.02,50.47
+5VS on IN1: 191.83,53.14 192.84,53.14 195.13,50.85 195.13,34.6 194.49,33.96 194.49,31.17 191.27,27.94 190.12,27.94 189.67,27.49 187.94,27.49 187.94,27.49 187.67,27.49 187.41,27.75 187.41,28.86 189,30.44 189.19,30.44 191.95,33.2 191.95,45.9 189.16,48.69 189.16,51.11 188.9,51.36 188.9,54.92 189.16,55.17 189.79,55.17
+5VS on IN1: 23.83,72.8 25.4,72.8 25.56,72.65 25.56,72.14 25.43,72.01 23.83,72.01 23.63,72.21 23.63,72.6
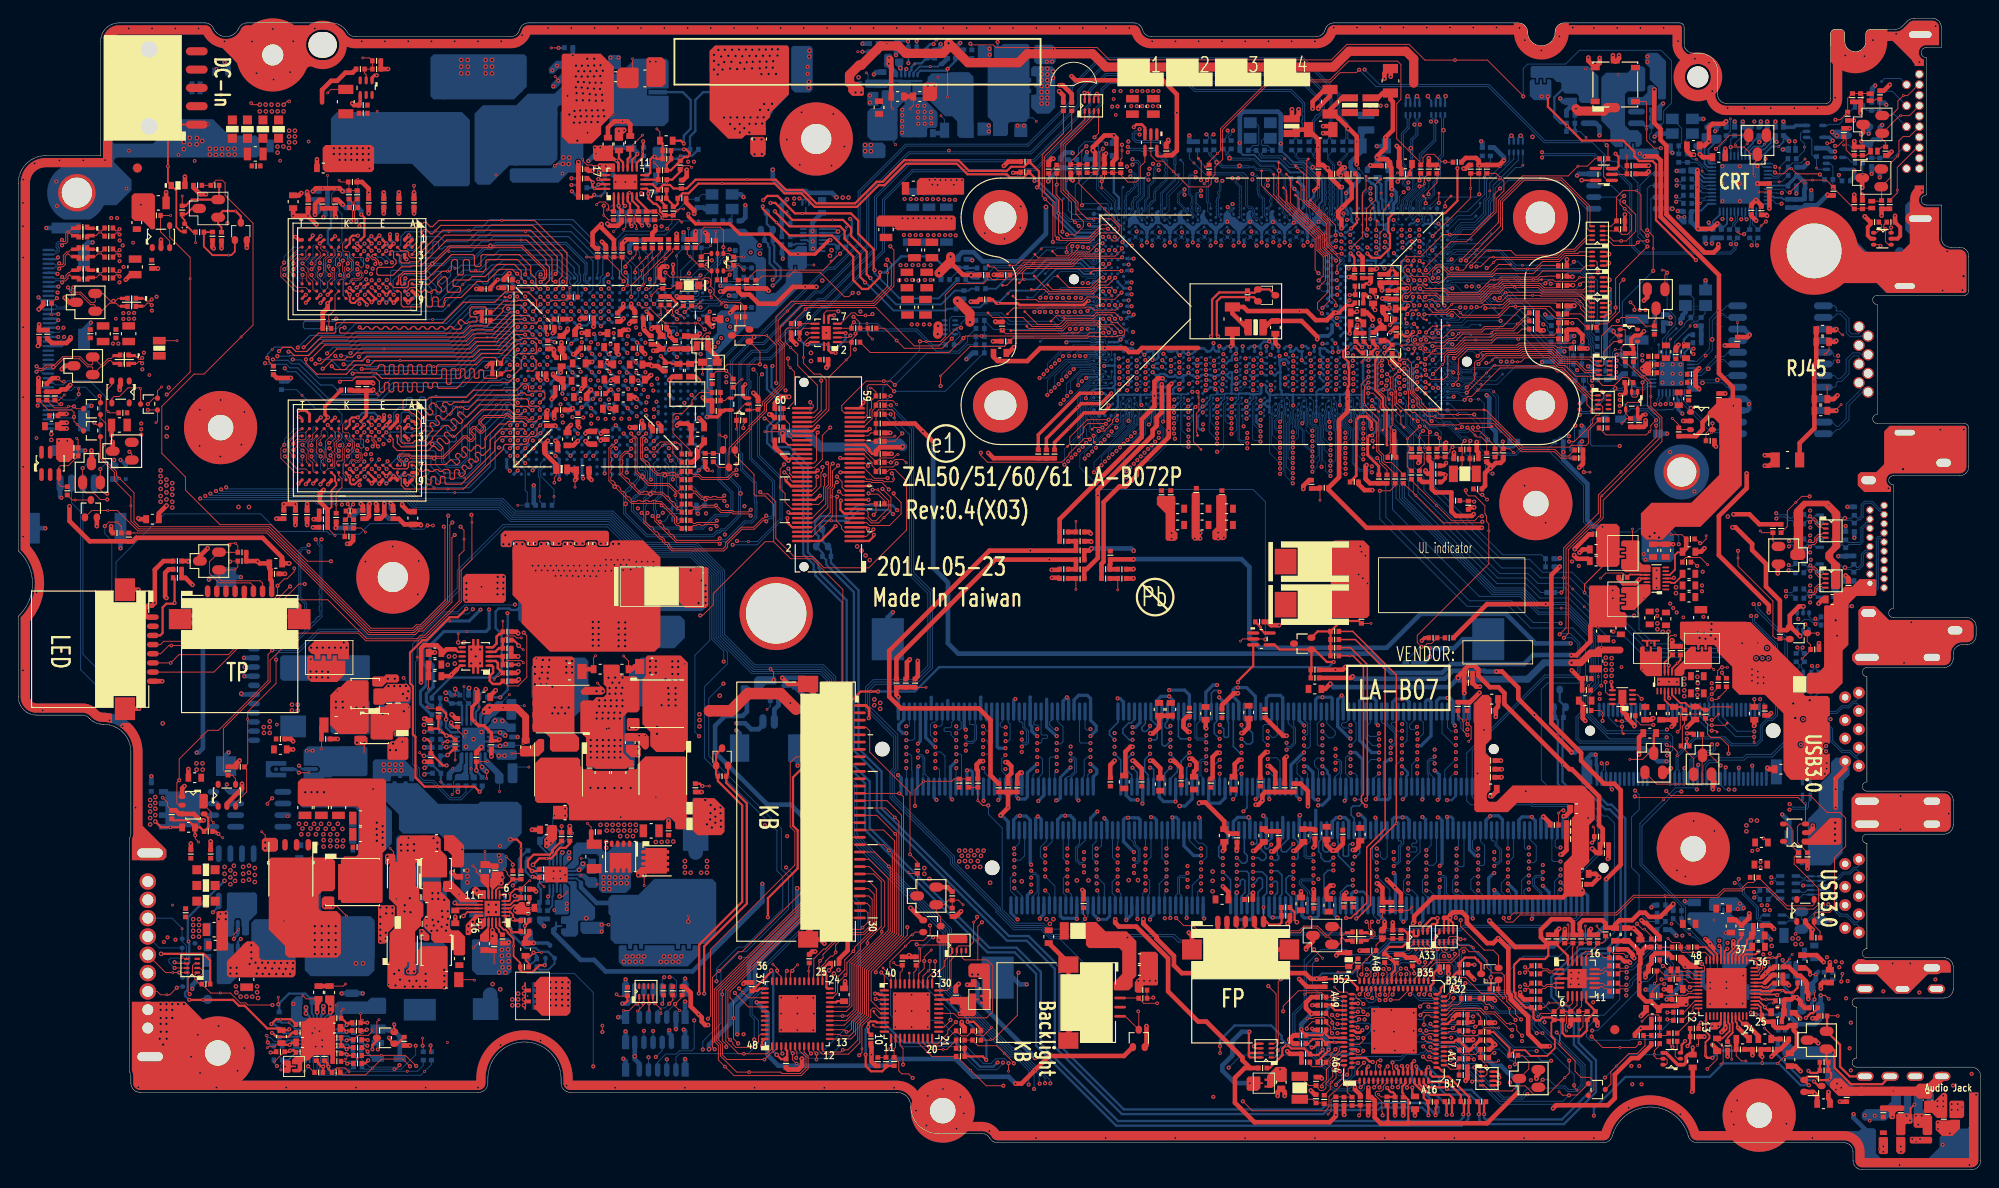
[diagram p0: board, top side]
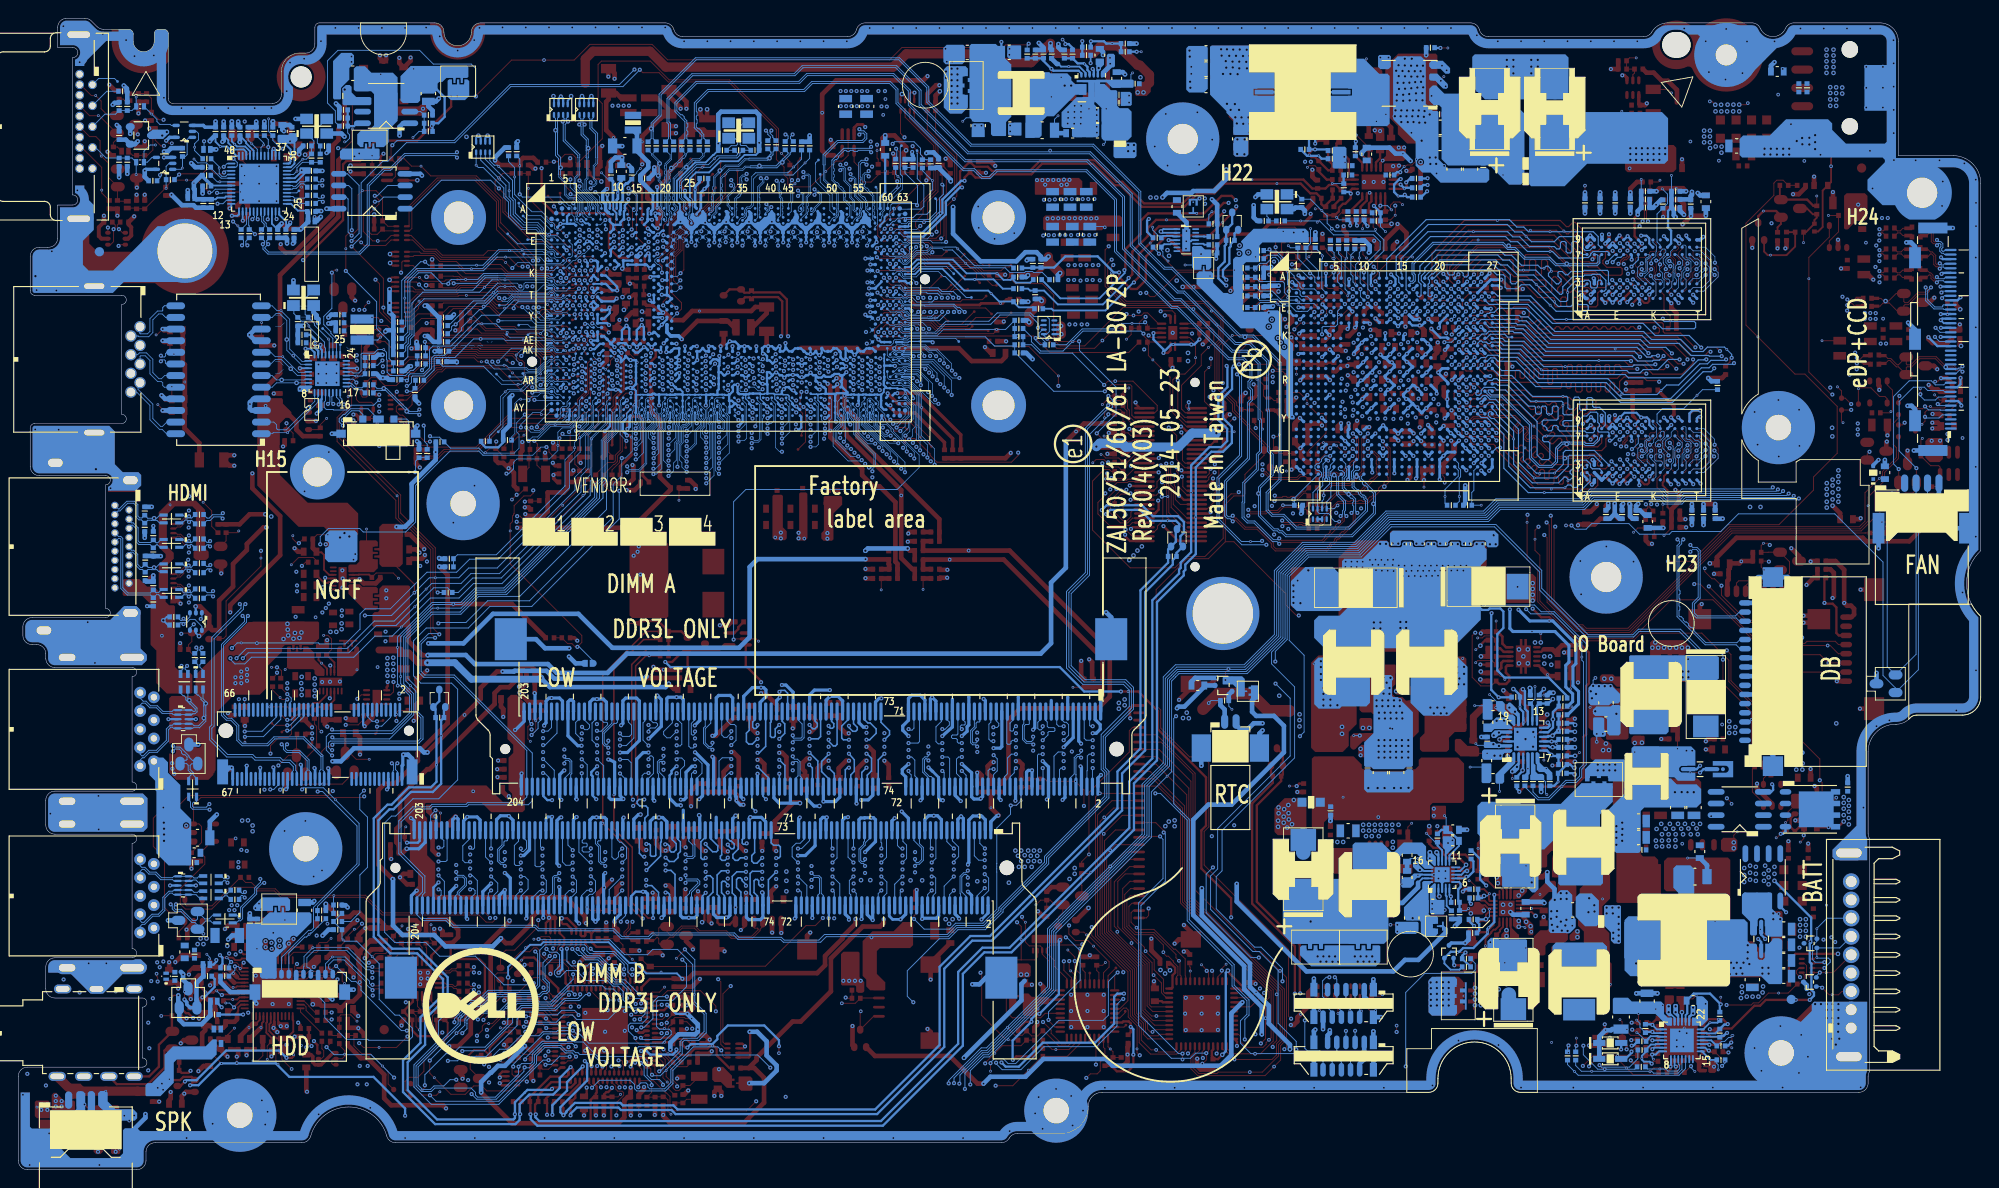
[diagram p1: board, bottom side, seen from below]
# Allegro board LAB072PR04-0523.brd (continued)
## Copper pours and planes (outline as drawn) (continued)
+5VS on VCC: 131.22,22.28 128.3,25.2 111.03,25.2 110.8,25.43 110.8,27.87 148.62,27.87 149.28,28.52 149.28,36.38 162.85,36.38 174.81,48.33 174.81,55.7 185.6,66.5 185.6,70.54 187.49,70.54 188.27,71.32 188.27,112.47 189.41,113.61 189.41,115.18 192.21,115.18 192.21,66.33 191.44,65.56 191.44,64.72 192.21,63.96 192.21,55.19 193.24,54.16 197.69,54.16 197.79,54.05 197.79,50.32 197.16,49.69 197.16,48.72 197.79,48.08 197.79,32.42 197.03,31.65 197.03,30.68 197.79,29.92 197.79,28.1 196.14,26.45 196.14,22.79 193.45,22.79 191.65,24.59 190.26,24.59 190.15,24.7 190.15,24.95 188.27,26.83 188.27,27.31 187.67,27.91 187.67,29.35 187.97,29.64 192.31,29.64 193.6,30.94 193.6,42.58 189.41,46.77 189.41,52.1 186.85,54.66 180.54,54.66 179.13,53.24 179.13,44.74 159.21,24.82 151.21,24.82 148.67,22.28
+5VS on IN2: 23.68,71.55 23.42,71.81 23.42,72.82 23.68,73.08 25.58,73.08 25.84,72.82 25.84,71.81 25.58,71.55
+5VS on IN2: 16.62,81.51 16.79,81.33 16.79,80.01 16.51,79.73 15.85,79.73 15.55,80.04 15.55,81.33 15.73,81.51
+5VS on IN3: 191.95,29.26 194.11,31.42 194.11,34.22 197.16,37.26 197.16,44.93 197.36,45.14 197.67,45.14 199.45,43.36 199.45,35.28 197.95,33.78 197.95,31.85 197.44,31.35 197.44,30.82 193.98,27.36 188.5,27.36 188.19,27.66 188.19,27.76 187.4,28.56 187.4,28.99 187.67,29.26
+5VS_KBL on TOP (solid shape): 118.77,26.04 121.09,26.04 122.15,24.97 122.15,21.16 121.76,20.77 121.76,20.02 121.33,19.59 119.79,19.59 119.68,19.7 119.68,20.46 120.6,21.39 120.6,23.87 120.26,24.21 116.96,24.21 116.64,24.53 116.64,26.96 116.73,27.05 117.76,27.05
+5VS_TOUCH on IN1 (solid shape): 11.01,104.18 11.01,103.49 10.52,102.99 10.52,96.44 6.97,92.88 6.97,90.56 6.76,90.36 5.6,90.36 5.45,90.51 5.45,93.34 9.13,97.02 9.13,103.84 9.6,104.31 10.88,104.31
+5VS_TOUCH on TOP: 15.08,101.42 15.08,99.27 14.74,98.93 12.02,98.93 11.73,99.22 11.73,102.79 11.11,103.41 10.05,103.41 9.95,103.51 9.95,104.28 10.11,104.43 11.63,104.43 12.91,103.15 13.35,103.15
+VCC_PWR_SRC on BOTTOM (solid shape): 60.25,118.04 60.25,116.77 59.75,116.26 59.16,116.26 58.91,116 58.91,110.38 58.21,109.68 53.63,109.68 51.53,107.58 50.24,107.58 49.85,107.97 49.85,115.34 50.76,116.26 54.41,116.26 55.68,117.53 58.6,117.53 59.49,118.42 59.87,118.42
GND on TOP (solid shape): 53.27,64.82 53.27,62.16 53.01,61.9 48.82,61.9 48.57,62.16 48.57,64.7 48.95,65.08 53.01,65.08
GND on TOP (solid shape): 60,39.6 60,38.41 59.85,38.25 58.48,38.25 58.42,38.31 58.42,39.7 58.48,39.75 59.85,39.75
GND on TOP (solid shape): 75.39,65.67 75.39,61.61 75.14,61.36 72.85,61.36 72.09,62.12 72.09,65.55 72.34,65.8 75.26,65.8
GND on TOP (solid shape): 81.64,112.58 81.64,110.87 81.39,110.62 80.32,110.62 79.96,110.97 79.96,112.63 80.14,112.8 81.41,112.8
GND on TOP (solid shape): 103.34,108.16 103.34,106.55 103.27,106.48 98.29,106.48 98.16,106.61 98.16,107.97 98.51,108.32 103.18,108.32
GND on TOP (solid shape): 147.62,68.08 147.62,60.54 147.33,60.25 143.57,60.25 143.39,60.42 143.39,68.34 143.77,68.72 146.98,68.72
GND on TOP (solid shape): 29.77,11.81 29.77,11.37 30.33,11.37 30.33,11.19 29.77,11.19 29.77,10.71 29.63,10.57 29.05,10.57 28.89,10.73 28.89,11.83 28.99,11.94 29.65,11.94
GND on TOP (solid shape): 65.06,120.47 65.06,115.35 63.68,113.97 63.68,113.08 62.67,112.07 60.13,112.07 59.36,112.83 59.36,121.72 59.54,121.9 63.63,121.9
GND on TOP (solid shape): 102.43,103.99 102.43,102.73 102.29,102.59 96.02,102.59 95.61,102.99 93.94,102.99 93.76,103.17 93.76,103.93 94.04,104.21 102.2,104.21
GND on TOP (solid shape): 60.03,32.89 60.03,31.53 59.88,31.38 58,31.38 57.99,31.37 57.69,31.37 57.46,31.6 57.46,32.97 57.61,33.12 59.8,33.12
GND on TOP (solid shape): 132.01,73.59 132.01,69.01 131.75,68.76 130.63,68.76 130.45,68.94 130.45,69.75 130.87,70.18 130.87,72.57 130.87,72.58 130.87,73.59 130.99,73.71 131.88,73.71
GND on TOP (solid shape): 129.09,73.84 129.09,69.9 129.08,69.9 129.23,69.75 129.23,68.82 129.12,68.72 128.43,68.72 128.18,68.97 128.18,72.57 128.19,72.58 128.19,73.83 128.33,73.97 128.96,73.97
GND on TOP (solid shape): 124.52,23.55 124.52,20.25 124.39,20.12 122.99,20.12 122.86,19.99 122.86,19.48 122.74,19.36 122.1,19.36 121.98,19.48 121.98,20.5 122.48,21.01 122.48,23.68 122.61,23.8 124.26,23.8
GND on TOP (solid shape): 210.75,8.18 210.75,5.8 210.59,5.64 209.63,5.64 209.06,6.2 208.3,6.2 208.21,6.3 208.21,7.43 208.32,7.54 209.4,7.54 210.25,8.39 210.54,8.39
GND on TOP (solid shape): 206.05,6.91 206.05,6.53 205.92,6.4 205.29,6.4 205.03,6.15 205.03,5.64 204.91,5.51 204.53,5.51 204.4,5.64 204.4,6.28 204.27,6.4 203.51,6.4 203.38,6.53 203.38,6.91 203.51,7.04 205.92,7.04
GND on TOP (solid shape): 42.85,52.68 42.85,51.36 42.6,51.11 40.25,51.11 39.93,50.79 38.92,50.79 38.79,50.92 38.79,52.44 38.92,52.57 39.86,52.57 40.35,53.06 42.47,53.06
GND on TOP (solid shape): 126.42,73.46 126.42,72.95 126.45,72.93 126.45,72.62 126.44,72.62 126.39,72.57 126.39,69.86 126.39,69.81 126.42,69.77 126.66,69.53 126.66,68.93 126.42,68.68 125.51,68.68 125.33,68.86 125.33,71.68 124.39,72.63 124.39,73.46 124.52,73.59 126.29,73.59
GND on TOP (solid shape): 46.21,31.35 46.21,30.36 47.17,29.39 47.17,26.34 47.36,26.15 48.12,26.15 48.82,25.45 48.82,23.55 48.7,23.42 47.68,23.42 47.55,23.55 47.55,24.44 47.22,24.77 45.47,24.77 45.11,25.12 45.11,25.73 44.25,26.6 44.25,27.36 44.63,27.74 44.63,29.06 44.17,29.52 44.17,31.35 44.3,31.47 46.08,31.47
GND on TOP (solid shape): 65.71,55.04 65.71,54.28 66.1,53.9 67.49,53.9 67.87,53.52 67.87,50.22 67.62,49.96 66.6,49.96 66.1,49.46 66.1,45.52 66.86,44.76 67.11,44.76 67.26,44.6 67.26,44.07 67.19,44 66.65,44 66.45,43.79 63,43.79 62.79,44 62.16,44 62.03,44.12 62.03,47.17 61.4,47.81 61.4,50.98 61.65,51.23 62.79,51.23 63.17,51.62 63.94,51.62 64.25,51.93 64.25,52.69 63.94,53.01 63.94,55.17 65.59,55.17
GND on TOP (solid shape): 201.59,22.99 201.77,22.92 201.97,22.89 210.4,22.89 210.93,22.67 211.15,22.15 211.15,21.52 208.79,21.52 206.53,19.26 205.11,19.26 202.85,21.52 200.7,21.52 200.37,21.85 200.37,22.35 201.02,22.99
GND on TOP (solid shape): 210.4,41.09 210.93,40.87 211.15,40.35 211.15,37.65 210.93,37.12 210.4,36.9 200.74,36.9 200.29,37.35 200.29,40.59 200.79,41.09
GND on TOP (solid shape): 12.19,48.79 13.21,47.37 13.57,45.65 13.57,37.56 16.19,34.95 16.19,34.14 15.84,33.8 15.51,33.8 15.51,33.79 12.4,33.79 12.4,36.12 12.52,36.41 12.55,36.72 12.55,45.65 12.18,47.17 11.14,48.33 11.14,48.58 11.36,48.79
GND on TOP (solid shape): 212.6,81.24 212.77,81.17 212.85,81 212.85,76.8 212.63,76.27 212.1,76.06 204.85,76.06 204.11,75.43 204.6,74.59 204.6,74.02 201.68,74.02 200.97,74.73 200.97,75.88 201.28,76.19 202.98,76.19 203.86,77.06 203.86,80.65 204.45,81.24
GND on TOP (solid shape): 64.52,69.62 64.52,68.28 64.37,68.13 63.5,68.13 63.35,68.28 63.35,68.63 63.22,68.76 62.06,68.76 61.92,68.62 61.92,68.25 61.8,68.13 60.89,68.13 60.74,68.28 60.74,68.63 60.61,68.76 59.49,68.76 59.34,68.61 59.34,68.25 59.21,68.13 58.32,68.13 58.17,68.28 58.17,68.58 58.02,68.73 56.87,68.73 56.7,68.56 56.7,68.25 56.57,68.13 55.71,68.13 55.55,68.28 55.55,68.51 55.3,68.76 54.11,68.76 53.93,68.58 53.93,68.2 53.75,68.02 52.84,68.02 52.71,68.15 52.71,69.4 53.09,69.78 64.37,69.78
GND on TOP (solid shape): 204.36,60.05 212.9,60.05 213.43,59.83 213.64,59.3 213.64,58.35 213.43,57.82 212.9,57.61 212.4,57.61 211.51,57.24 211.15,56.35 211.15,55.85 210.93,55.32 210.4,55.1 200.9,55.1 200.36,55.64 200.36,56.24 201.04,56.92 201.04,61.1 201.5,61.55 202.85,61.55
GND on TOP (solid shape): 208.2,106.95 208.2,106.95 208.2,106.67 207.66,105.78 208.46,105.11 209.85,105.11 209.85,101.75 210.25,100.82 211.21,100.5 212.1,100.5 212.57,100.33 212.83,99.91 212.84,99.83 212.85,99.75 212.85,96 212.77,95.83 212.6,95.76 204.14,95.76 203.07,96.83 195,96.83 193.48,98.35 193.48,102.54 194.62,103.69 198.3,103.69 201.73,100.26 205.75,100.26 206.65,101.15 206.65,105.55 206.72,105.63 206.76,106.47 207.19,107.19 207.19,107.5 208.2,107.5
GND on TOP (solid shape): 20.5,16.06 20.5,14.15 19.61,13.26 19.61,11.99 20.5,11.1 20.5,9.72 50.03,9.72 50.03,9.95 55.3,15.22 60.57,9.95 60.57,9.72 96,9.72 97.96,8.91 98.77,6.95 98.91,6.28 99.3,5.71 99.44,5.56 100.79,4.67 102.31,5.22 105.27,5.22 106.33,4.95 107.15,4.22 172.99,4.22 178.3,8.12 183.61,4.22 188.31,4.22 188.54,3.99 192.13,3.99 192.36,4.22 199.45,4.22 201.06,3.56 201.72,1.95 201.72,1.27 213.13,1.27 213.13,8.44 214.15,8.44 214.15,1 213.93,0.47 213.4,0.26 201.45,0.26 200.92,0.47 200.71,1 200.71,1.95 200.34,2.84 199.45,3.21 183.41,3.21 182.96,3.36 182.69,3.75 178.3,7.11 173.91,3.75 173.64,3.36 173.19,3.21 107,3.21 106.63,3.31 105.9,4.04 105.27,4.21 100.5,4.21 98.56,5.01 97.76,6.95 97.24,8.19 96,8.71 60.3,8.71 59.77,8.92 59.56,9.45 59.56,9.95 55.3,14.21 51.05,9.95 51.05,9.45 50.83,8.92 50.3,8.71 20.84,8.71 20.84,8.7 13.3,8.7 12.77,8.92 12.55,9.45 12.55,10.18 12.52,10.49 12.4,10.78 12.4,18.34 18.22,18.34
GND on TOP (solid shape): outline of 1466 points within 0.25,48.77 209.85,125.75
GND on BOTTOM (solid shape): 12.7,115.65 10.2,115.65 10.2,120.65 12.7,120.65
GND on BOTTOM (solid shape): 63.97,26.98 63.97,25.91 63.81,25.75 61.7,25.75 61.42,26.03 61.42,26.95 61.55,27.08 63.88,27.08
GND on BOTTOM (solid shape): 81.64,112.55 81.64,110.85 81.44,110.64 80.22,110.64 80.01,110.85 80.01,112.68 80.14,112.8 81.39,112.8
GND on BOTTOM (solid shape): 93.95,116.19 92.87,116.19 92.75,116.32 92.75,117.52 92.94,117.71 93.95,117.71
GND on BOTTOM (solid shape): 106.35,122.67 106.35,121.53 106.1,121.27 104.89,121.27 104.83,121.34 104.83,122.74 104.89,122.8 106.23,122.8
GND on BOTTOM (solid shape): 106.27,114.22 106.27,113.08 106.14,112.95 104.81,112.95 104.81,114.35 106.14,114.35
GND on BOTTOM (solid shape): 110.23,114.15 110.23,112.81 108.84,112.81 108.84,114.15 108.96,114.27 110.11,114.27
GND on BOTTOM (solid shape): 42.35,49.3 42.35,47.55 42.07,47.27 41.13,47.27 40.95,47.45 40.95,47.91 41.13,48.08 41.13,49.25 41.25,49.38 42.27,49.38
GND on BOTTOM (solid shape): 47.2,29.22 47.2,26.06 46.97,25.83 44.89,25.83 44.25,26.47 44.25,27.36 44.63,27.74 44.63,30.03 45.14,30.53 45.89,30.53
GND on BOTTOM (solid shape): 113.33,122.5 113.33,120.98 113.08,120.73 111.26,120.73 110.98,121.01 110.98,122.69 111.16,122.87 112.97,122.87
GND on BOTTOM (solid shape): 55.56,121.54 55.56,119.97 55.55,119.97 55.55,118.29 54.16,116.89 45.37,116.89 45.03,117.23 45.03,121.47 45.38,121.82 55.28,121.82
GND on BOTTOM (solid shape): 59.64,31.41 59.1,31.41 58.97,31.28 58.97,30.33 58.91,30.26 58.78,30.26 58.72,30.33 58.72,31.28 58.59,31.41 58.04,31.41 58.04,33.02 59.64,33.02
GND on BOTTOM (solid shape): 73.35,65.83 73.8,65.83 75.37,64.26 75.37,61.65 74.73,61.01 70.03,61.01 69.52,61.52 69.52,64.57 70.79,65.84 73.33,65.84
GND on BOTTOM (solid shape): 86.8,122.48 86.8,117.96 86.48,117.64 84.85,117.64 84.45,118.04 84.45,122.54 84.64,122.74 86.54,122.74
GND on BOTTOM (solid shape): 53.4,34.19 53.4,33.09 52.28,31.97 52.28,30.98 52.21,30.91 49.65,30.91 49.01,30.28 48.68,30.28 48.32,30.65 48.32,34.34 48.57,34.6 52.99,34.6
GND on BOTTOM (solid shape): 53.9,24.95 53.9,21.64 53.52,21.26 50.09,21.26 49.56,21.8 49.56,25.03 49.66,25.14 52.6,25.14 52.79,25.33 53.52,25.33
GND on BOTTOM (solid shape): 180.01,121.08 180.01,117.02 179.89,116.89 179.22,116.89 179.14,116.98 179.14,118.15 178.24,119.05 178.24,120.32 177.73,120.83 177.73,121.72 177.98,121.97 179.13,121.97
GND on BOTTOM (solid shape): 42.86,52.63 42.86,50.99 42.6,50.73 40.59,50.73 40.39,50.93 39.6,50.93 39.4,51.13 39.4,51.97 40.44,53.01 42.47,53.01
GND on BOTTOM (solid shape): 60.18,30.83 60.18,28.04 60,27.87 58.7,27.87 58.6,27.96 58.6,29.44 58.63,29.47 59.08,29.47 59.14,29.47 59.2,29.47 59.39,29.47 59.54,29.63 59.54,31.21 59.61,31.28 59.73,31.28
GND on BOTTOM (solid shape): 31.05,18.92 31.05,18.02 30.99,17.96 30.99,16.82 31.2,16.61 31.49,16.61 31.55,16.56 31.55,15.79 31.49,15.73 30.43,15.73 29.8,16.36 29.8,18.39 30.32,18.91 30.4,18.91 30.42,18.93 31.03,18.93
GND on BOTTOM (solid shape): 66.35,53.77 66.35,47.68 67.37,46.66 67.37,44.12 67.24,44 66.6,44 66.35,43.74 63.05,43.74 62.79,44 62.16,44 62.03,44.12 62.03,49.96 63.68,51.62 64.19,51.62 64.32,51.74 64.32,53.39 64.19,53.52 64.19,53.77 64.44,54.03 66.1,54.03
GND on BOTTOM (solid shape): 98.78,118.77 97.51,118.77 97.51,117.14 98.78,117.14 100.43,115.49 100.43,113.97 100.24,113.78 99.41,113.78 99.29,113.65 99.29,112.89 99.16,112.76 96.49,112.76 96.3,112.95 96.3,115.81 96.85,116.36 96.85,119.02 98.78,119.02
GND on BOTTOM (solid shape): 201.61,22.98 201.79,22.91 201.97,22.89 210.4,22.89 210.93,22.67 211.15,22.15 211.15,21.52 208.79,21.52 206.51,19.23 205.13,19.23 202.85,21.52 200.87,21.52 200.37,22.01 200.37,22.34 201.01,22.98
GND on BOTTOM (solid shape): 210.4,41.09 210.93,40.87 211.15,40.35 211.15,37.65 210.93,37.12 210.4,36.9 200.74,36.9 200.29,37.35 200.29,40.59 200.79,41.09
GND on BOTTOM (solid shape): 64.55,69.5 64.55,68.28 64.42,68.15 63.48,68.15 63.35,68.28 63.35,68.63 63.22,68.76 62.03,68.76 61.9,68.63 61.9,68.33 61.7,68.13 61.68,68.15 60.91,68.15 60.76,68.3 60.76,68.63 60.63,68.76 59.49,68.76 59.34,68.61 59.34,68.23 59.24,68.13 58.35,68.13 58.2,68.28 58.2,68.53 57.97,68.76 56.9,68.76 56.75,68.61 56.75,68.23 56.65,68.13 55.63,68.13 55.53,68.23 55.53,68.61 55.4,68.73 54.18,68.73 54,68.56 54,68.15 53.83,67.97 52.91,67.97 52.68,68.2 52.68,69.37 53.12,69.8 64.24,69.8
GND on BOTTOM (solid shape): 212.6,81.24 212.77,81.17 212.85,81 212.85,76.8 212.63,76.27 212.1,76.06 204.85,76.06 204.11,75.43 204.6,74.59 204.6,74.16 201.54,74.16 200.97,74.73 200.97,75.87 201.28,76.18 202.99,76.18 203.86,77.06 203.86,80.64 204.46,81.24
GND on BOTTOM (solid shape): 64.19,121.12 64.19,114.74 61.74,112.29 61.74,109.65 60.99,108.9 60.11,108.9 59,107.79 54,107.79 53.69,108.1 53.69,109.17 53.9,109.37 58.24,109.37 58.92,110.05 60.81,110.05 60.81,109.99 60.83,109.94 60.85,109.89 60.87,109.84 60.91,109.79 60.95,109.75 60.99,109.72 61.04,109.7 61.1,109.68 61.15,109.67 61.21,109.67 61.26,109.67 61.32,109.69 61.37,109.71 61.42,109.74 61.46,109.77 61.5,109.81 61.53,109.86 61.55,109.91 61.57,109.96 61.57,110.02 61.57,110.08 61.57,110.13 61.55,110.18 61.53,110.23 61.5,110.28 61.46,110.32 61.42,110.36 61.37,110.39 61.32,110.41 61.26,110.42 61.21,110.43 61.15,110.43 61.1,110.42 61.04,110.4 60.99,110.37 60.95,110.34 60.91,110.3 60.87,110.26 60.85,110.21 60.83,110.16 60.81,110.1 60.81,110.05 58.92,110.05 59.24,110.37 59.24,115.5 59.38,115.64 59.86,115.64 60.64,116.42 60.64,121.08 61.16,121.61 63.7,121.61
GND on BOTTOM (solid shape): 204.36,60.05 212.9,60.05 213.43,59.83 213.64,59.3 213.64,58.35 213.43,57.82 212.9,57.61 212.4,57.61 211.51,57.24 211.15,56.35 211.15,55.85 210.93,55.32 210.4,55.1 200.9,55.1 200.36,55.64 200.36,56.24 201.04,56.92 201.04,61.1 201.5,61.55 202.85,61.55
GND on BOTTOM (solid shape): 208.2,107.13 208.2,107.13 208.2,106.67 207.66,105.78 208.46,105.11 209.85,105.11 209.85,101.75 210.25,100.82 211.21,100.5 212.1,100.5 212.63,100.28 212.85,99.75 212.85,98.58 212.85,96 212.77,95.83 212.6,95.76 204.07,95.76 202.87,96.95 195.64,96.95 193.22,99.37 193.22,101.4 195.13,103.3 198.05,103.3 198.3,103.05 199.19,103.05 204.05,98.2 206.72,98.2 207.34,98.82 207.34,101.46 206.15,102.64 206.15,105.36 206.69,105.9 206.81,106.6 207.19,107.19 207.19,107.5 208.2,107.5
GND on BOTTOM (solid shape): outline of 93 points within 12.4,0.26 214.15,18.34
GND on BOTTOM (solid shape): outline of 381 points within 121.17,102.15 142.94,104.84
GND on BOTTOM (solid shape): outline of 219 points within 0.25,33.79 209.85,125.5
GND on IN1 (solid shape): 201.61,22.98 201.79,22.91 201.97,22.89 210.4,22.89 210.93,22.67 211.15,22.15 211.15,21.52 200.8,21.52 200.37,21.94 200.37,22.35 201.01,22.98
GND on IN1 (solid shape): 210.4,41.09 210.93,40.87 211.15,40.35 211.15,37.65 210.93,37.12 210.4,36.9 200.74,36.9 200.29,37.35 200.29,40.59 200.79,41.09
GND on IN1 (solid shape): 212.6,81.24 212.77,81.17 212.85,81 212.85,76.8 212.63,76.27 212.1,76.06 204.85,76.06 204.11,75.43 204.6,74.59 204.6,74.02 201.8,74.02 200.97,74.85 200.97,75.87 201.28,76.18 202.98,76.18 203.86,77.06 203.86,80.64 204.47,81.24
GND on IN1 (solid shape): 204.36,60.05 212.9,60.05 213.43,59.83 213.64,59.3 213.64,58.35 213.43,57.82 212.9,57.61 212.4,57.61 211.51,57.24 211.15,56.35 211.15,55.85 210.93,55.32 210.4,55.1 200.9,55.1 200.36,55.64 200.36,56.24 201.04,56.92 201.04,61.1 201.5,61.55 202.85,61.55
GND on IN1 (solid shape): 208.2,107.1 208.2,107.1 208.2,106.67 207.66,105.78 208.46,105.11 209.85,105.11 209.85,101.75 210.25,100.82 211.21,100.5 212.1,100.5 212.63,100.28 212.85,99.75 212.85,99.07 212.85,96 212.77,95.83 212.6,95.76 204.07,95.76 202.87,96.95 194.11,96.95 192.97,98.1 192.97,101.78 194.75,103.56 198.43,103.56 201.99,100 204.99,100 205.06,100.07 205.2,100.07 206.36,101.23 206.36,105.96 206.73,106.32 206.9,106.79 207.19,107.19 207.19,107.5 208.2,107.5
GND on IN1 (solid shape): 20.54,16.02 22.39,16.02 28.69,9.72 50.03,9.72 50.03,9.95 55.3,15.22 60.57,9.95 60.57,9.72 96,9.72 96.65,9.64 97.25,9.42 101.86,9.42 106.31,4.97 106.78,4.65 107.15,4.22 172.99,4.22 176.75,7.9 181.89,6.81 186,6.81 187.76,8.57 190.97,8.57 195.32,4.22 199.45,4.22 201.06,3.56 201.72,1.95 201.72,1.27 213.13,1.27 213.13,8.44 214.15,8.44 214.15,1 213.93,0.47 213.4,0.26 201.45,0.26 200.92,0.47 200.71,1 200.71,1.95 200.34,2.84 199.45,3.21 183.41,3.21 182.96,3.36 182.69,3.75 178.3,7.11 173.91,3.75 173.64,3.36 173.19,3.21 107,3.21 106.63,3.31 105.9,4.04 105.27,4.21 100.5,4.21 98.56,5.01 97.76,6.95 97.24,8.19 96,8.71 60.3,8.71 59.77,8.92 59.56,9.45 59.56,9.95 55.3,14.21 51.05,9.95 51.05,9.45 50.83,8.92 50.3,8.71 20.84,8.71 20.84,8.7 13.3,8.7 12.77,8.92 12.55,9.45 12.55,10.18 12.52,10.49 12.4,10.78 12.4,18.34 12.99,18.34 12.99,18.35 18.21,18.35
GND on IN1 (solid shape): outline of 202 points within 0.25,33.76 209.85,125.5
GND on VCC (solid shape): outline of 4129 points within 191.95,21.52 213.64,81.24
GND on IN2 (solid shape): 201.61,22.98 201.79,22.91 201.97,22.89 210.4,22.89 210.93,22.67 211.15,22.15 211.15,21.52 200.8,21.52 200.37,21.94 200.37,22.34 201.01,22.98
GND on IN2 (solid shape): 210.4,41.09 210.93,40.87 211.15,40.35 211.15,37.65 210.93,37.12 210.4,36.9 200.74,36.9 200.29,37.35 200.29,40.59 200.79,41.09
GND on IN2 (solid shape): 212.6,81.24 212.77,81.17 212.85,81 212.85,76.8 212.63,76.27 212.1,76.06 204.85,76.06 204.11,75.43 204.6,74.59 204.6,74.02 201.8,74.02 200.97,74.85 200.97,75.87 201.28,76.18 202.98,76.18 203.86,77.06 203.86,80.64 204.47,81.24
GND on IN2 (solid shape): 204.36,60.05 212.9,60.05 213.43,59.83 213.64,59.3 213.64,58.35 213.43,57.82 212.9,57.61 212.4,57.61 211.51,57.24 211.15,56.35 211.15,55.85 210.93,55.32 210.4,55.1 200.9,55.1 200.36,55.64 200.36,56.24 201.04,56.92 201.04,61.1 201.5,61.55 202.85,61.55
GND on IN2 (solid shape): 208.2,107.13 208.2,107.13 208.2,106.67 207.66,105.78 208.46,105.11 209.85,105.11 209.85,101.75 210.25,100.82 211.21,100.5 212.1,100.5 212.63,100.28 212.85,99.75 212.85,99.32 212.85,96 212.77,95.83 212.6,95.76 204.07,95.76 202.87,96.95 194.11,96.95 192.97,98.1 192.97,101.78 194.75,103.56 198.43,103.56 201.99,100 204.99,100 206.17,101.18 206.17,105.77 206.73,106.32 206.9,106.79 207.19,107.19 207.19,107.5 208.2,107.5
GND on IN2 (solid shape): 20.62,15.94 22.47,15.94 28.69,9.72 50.03,9.72 50.03,9.95 55.3,15.22 60.57,9.95 60.57,9.72 96,9.72 96.65,9.64 97.25,9.42 101.86,9.42 106.31,4.97 106.78,4.65 107.15,4.22 172.99,4.22 176.75,7.9 181.89,6.81 186,6.81 187.76,8.57 190.97,8.57 195.32,4.22 199.45,4.22 201.06,3.56 201.72,1.95 201.72,1.27 213.13,1.27 213.13,8.44 214.15,8.44 214.15,1 213.93,0.47 213.4,0.26 201.45,0.26 200.92,0.47 200.71,1 200.71,1.95 200.34,2.84 199.45,3.21 183.41,3.21 182.96,3.36 182.69,3.75 178.3,7.11 173.91,3.75 173.64,3.36 173.19,3.21 107,3.21 106.63,3.31 105.9,4.04 105.27,4.21 100.5,4.21 98.56,5.01 97.76,6.95 97.24,8.19 96,8.71 60.3,8.71 59.77,8.92 59.56,9.45 59.56,9.95 55.3,14.21 51.05,9.95 51.05,9.45 50.83,8.92 50.3,8.71 20.84,8.71 20.84,8.7 13.3,8.7 12.77,8.92 12.55,9.45 12.55,10.18 12.52,10.49 12.4,10.78 12.4,18.34 12.91,18.34 12.91,18.35 18.21,18.35
GND on IN2 (solid shape): outline of 198 points within 0.25,33.79 209.85,125.5
GND on IN3 (solid shape): 201.6,22.99 201.78,22.92 201.97,22.89 210.4,22.89 210.93,22.67 211.15,22.15 211.15,21.52 200.61,21.52 200.32,21.81 200.32,22.29 201.02,22.99
GND on IN3 (solid shape): 210.4,41.09 210.93,40.87 211.15,40.35 211.15,37.65 210.93,37.12 210.4,36.9 200.74,36.9 200.29,37.35 200.29,40.59 200.79,41.09
GND on IN3 (solid shape): 212.6,81.24 212.77,81.17 212.85,81 212.85,76.8 212.63,76.27 212.1,76.06 204.85,76.06 204.11,75.43 204.6,74.59 204.6,74.02 201.8,74.02 200.97,74.85 200.97,75.87 201.28,76.18 202.98,76.18 203.86,77.06 203.86,80.64 204.47,81.24
GND on IN3 (solid shape): 204.36,60.05 212.9,60.05 213.43,59.83 213.64,59.3 213.64,58.35 213.43,57.82 212.9,57.61 212.4,57.61 211.51,57.24 211.15,56.35 211.15,55.85 210.93,55.32 210.4,55.1 200.9,55.1 200.36,55.64 200.36,56.24 201.04,56.92 201.04,61.1 201.5,61.55 202.85,61.55
GND on IN3 (solid shape): 208.2,107.1 208.2,107.1 208.2,106.67 207.66,105.78 208.46,105.11 209.85,105.11 209.85,101.75 210.25,100.82 211.21,100.5 212.1,100.5 212.63,100.28 212.85,99.75 212.85,97.94 212.85,96 212.77,95.83 212.6,95.76 204.07,95.76 202.87,96.95 194.62,96.95 192.84,98.73 192.84,101.65 194.87,103.69 198.43,103.69 201.85,100.27 204.64,100.27 206.15,101.77 206.15,106.46 207.19,107.5 208.2,107.5
GND on IN3 (solid shape): 20.54,16.02 22.33,16.02 25.21,13.14 25.21,11.57 27.06,9.72 50.03,9.72 50.03,9.95 55.3,15.22 60.57,9.95 60.57,9.72 96,9.72 96.73,9.62 97.42,9.33 101.93,9.33 106.28,4.98 106.77,4.66 107.15,4.22 172.99,4.22 176.58,7.85 181.62,7.02 183.8,7.02 185.11,8.33 190.95,8.33 195.07,4.22 199.45,4.22 201.06,3.56 201.72,1.95 201.72,1.27 213.13,1.27 213.13,8.44 214.15,8.44 214.15,1 213.93,0.47 213.4,0.26 201.45,0.26 200.92,0.47 200.71,1 200.71,1.95 200.34,2.84 199.45,3.21 183.41,3.21 182.96,3.36 182.69,3.75 178.3,7.11 173.91,3.75 173.64,3.36 173.19,3.21 107,3.21 106.63,3.31 105.9,4.04 105.27,4.21 100.5,4.21 98.56,5.01 97.76,6.95 97.24,8.19 96,8.71 60.3,8.71 59.77,8.92 59.56,9.45 59.56,9.95 55.3,14.21 51.05,9.95 51.05,9.45 50.83,8.92 50.3,8.71 20.84,8.71 20.84,8.7 13.3,8.7 12.77,8.92 12.55,9.45 12.55,10.18 12.52,10.49 12.4,10.78 12.4,18.34 18.22,18.34
GND on IN3 (solid shape): outline of 198 points within 0.25,33.79 209.85,125.5
GND on TOP: 60,29.39 60.13,29.26 60.13,27.49 59.75,27.1 57.08,27.1 56.06,28.12 56.06,29.01 56.44,29.39
GND on TOP: 13.01,91.79 12.72,91.49 7.53,91.49 7.4,91.62 7.4,92.74 7.62,92.96 9.83,92.96 10.68,93.81 12.83,93.81 13.01,93.63
GND on TOP: 36.76,34.47 36.89,34.6 36.89,35.74 37.01,35.87 37.01,39.3 36.89,39.42 29.14,39.42 28.76,39.04 28.76,34.85 29.14,34.47
GND on TOP: 182.17,23.93 182.68,23.93 182.81,24.06 182.81,24.95 182.43,25.33 182.43,27.36 182.3,27.49 180.6,27.49 180.41,27.29 180.41,25.59 180.9,25.1 181.65,25.1 182.05,24.7 182.05,24.06
GND on TOP: 182.97,65.71 182.82,65.57 182.82,62.14 182.94,62.03 184.23,62.03 184.36,62.16 184.36,65.59 184.23,65.71
GND on TOP: 17.66,110.18 17.66,113.07 17.89,113.3 25.49,113.3 25.8,112.99 25.8,109.29 25.62,109.11 18.73,109.11
GND on TOP: 119.37,116.58 124.71,116.58 124.77,116.64 124.77,117.91 124.64,118.04 119.31,118.04 119.18,117.91 119.18,116.77
GND on TOP: 21.26,24.06 21.14,23.93 18.33,23.93 17.88,24.39 17.88,27.8 18.07,27.99 20.79,27.99 21.26,27.52
GND on TOP: 63.15,36.71 63.15,37.7 63.4,37.95 68.61,37.95 68.74,37.82 68.74,36.17 67.72,35.16 65.36,35.16 65.23,35.28 65.23,36.25 64.95,36.53 63.33,36.53
GND on TOP: 183.98,54.16 184.74,54.16 185.12,53.77 185.12,52.02 184.56,51.46 183.87,51.46 183.8,51.54 183.8,53.98
GND on TOP: 92.77,116.33 92.77,117.41 92.95,117.6 94.42,117.6 94.75,117.27 94.75,116.39 94.44,116.08 93.02,116.08
GND on TOP: 190.1,34.55 188.95,34.55 188.8,34.7 188.8,36.18 188.96,36.34 190.13,36.34 190.32,36.15 190.32,34.76
GND on TOP: 189.01,31.55 189.46,31.55 189.59,31.68 189.59,32.23 189.69,32.34 190.5,32.34 190.61,32.44 190.61,33.99 190.53,34.06 189.18,34.06 188.78,33.66 188.78,31.78
GND on TOP: 96.3,94.05 99.75,94.05 100.06,93.75 100.06,92.9 99.81,92.65 99.81,92.2 99.7,92.09 96.42,92.09 96.04,92.47 96.04,93.78
GND on TOP: 177.22,61.52 177.98,62.28 180.34,62.28 181.04,61.59 184.54,61.59 184.64,61.49 184.64,60.3 184.47,60.12 177.73,60.12 177.22,60.63
GND on TOP: 70.45,103.52 71.18,102.8 72.19,102.8 72.32,102.67 72.32,101.4 72.19,101.27 68.13,101.27 68,101.4 68,102.03 68.64,102.67 69.14,102.67 69.27,102.8 69.27,103.24 69.14,103.37 69.14,103.94 69.27,104.07 69.76,104.07 70.3,103.52
GND on TOP: 100.13,98.67 100.13,97.74 100,97.61 96.32,97.61 96.07,97.87 96.07,99.88 96.24,100.05 100.49,100.05 100.6,99.94 100.6,99.14
GND on TOP: 172.56,57.47 172.33,57.71 172.33,58.89 172.48,59.04 175.49,59.04 175.6,58.94 175.6,58.21 174.86,57.47
GND on TOP: 180.77,88.95 182.63,88.95 182.81,88.76 182.81,84.64 182.72,84.55 179.25,84.55 178.73,85.08 178.73,88.48 178.73,88.56 178.73,89.09 178.84,89.19 180.52,89.19
GND on TOP, BOTTOM: 23.68,20.37 26.09,20.37 26.47,19.99 26.47,18.6 26.22,18.34 23.8,18.34 23.42,18.72 23.42,20.12
GND on BOTTOM: 65.59,111.05 66.98,111.05 67.37,110.67 67.87,110.67 68,110.8 68,110.95 68.08,111.03 69,111.03 69.14,110.89 69.14,106.29 69.46,105.97 69.46,104.26 69.4,104.19 66.98,104.19 66.86,104.07 66.86,103.45 66.73,103.32 66.28,103.32 66.22,103.38 66.22,104.7 66.6,105.08 66.6,105.59 66.1,106.1 65,106.1 64.7,106.4 64.7,110.16
GND on BOTTOM: 30.54,39.3 36.76,39.3 37.01,39.04 37.01,34.72 36.78,34.5 30.59,34.5 30.1,34.98 30.1,38.86
GND on BOTTOM: 103.31,108.26 103.14,108.42 98.04,108.42 96.89,107.27 96.89,106.55 97.03,106.41 103.12,106.41 103.31,106.6
GND on BOTTOM: 28.88,51.11 31.42,51.11 31.68,50.85 31.68,47.3 31.55,47.17 28.76,47.17 28.63,47.3 28.63,50.85
GND on BOTTOM: 48.59,65.38 52.89,65.38 53.27,65 53.27,62.16 52.89,61.78 48.95,61.78 48.29,62.44 48.29,65.08
GND on BOTTOM: 68.94,36.43 68.53,36.02 65.26,36.02 64.99,36.29 63.8,36.29 63.2,36.88 63.2,39.36 63.56,39.72 68.66,39.72 68.94,39.44
GND on BOTTOM: 198.78,21.2 199.52,21.94 199.52,23.02 199.07,23.47 195,23.47 194.87,23.35 194.87,22.14 195.18,21.82 196.17,21.82 196.8,21.2
GND on BOTTOM: 18.85,27.49 18.98,27.61 20.69,27.61 21.17,27.13 21.17,20.45 21.12,20.4 20.25,20.4 20.11,20.55 20.11,21.27 18.99,22.39 18.99,24.82 18.85,24.96
GND on BOTTOM: 191.83,39.04 192.84,39.04 195.19,36.69 195.19,33.24 194.49,32.54 189.51,32.54 188.9,33.15 188.9,36.12
GND on BOTTOM: 96.19,99.14 100,99.14 100.13,99.01 100.13,97.74 100,97.61 96.32,97.61 96.07,97.87 96.07,99.01
GND on BOTTOM: 124.71,116.58 124.72,116.59 124.77,116.59 124.97,116.79 124.97,117.99 124.79,118.16 119.26,118.16 119.03,117.93 119.03,116.79 119.24,116.58
GND on BOTTOM: 99.29,52.5 114.79,52.5 115.04,52.25 115.04,51.44 114.81,51.21 99.29,51.21 99.06,51.44 99.06,52.28
GND on BOTTOM: 119.44,104.7 119.56,104.7 119.82,104.45 119.82,104.19 119.94,104.07 119.94,103.69 120.45,103.18 120.45,102.8 120.58,102.67 120.58,102.54 121.09,102.03 121.09,101.32 120.83,101.07 120.53,101.07 120.32,101.27 120.32,102.54 120.07,102.8 120.07,102.92 119.31,103.69 119.31,104.57
GND on BOTTOM: 73,101.35 72.24,101.35 72.05,101.16 69.05,101.16 68.99,101.22 68.99,101.72 69.02,101.74 71.01,101.74 71.99,102.72 72.83,102.72 73.04,102.5 73.04,101.39
GND on BOTTOM: 169.73,18.6 174.26,18.6 174.36,18.7 174.36,23.21 174.28,23.29 170.87,23.29 169.35,21.77 169.35,18.98
GND on BOTTOM: 96.55,102.54 102.67,102.54 102.8,102.67 102.8,103.56 102.16,104.19 96.5,104.19 96.32,104.02 96.32,102.77
GND on BOTTOM: 75.62,32.31 75.37,32.06 72.7,32.06 72.45,32.31 72.45,37.09 72.71,37.35 75.26,37.35 75.62,37
GND on GND1: outline of 345 points within 0.25,0.26 214.15,125.5
GND on IN1: 93.02,118.42 94.92,118.42 96.07,117.27 99.5,117.27 101.15,115.62 101.15,112.96 100.39,112.19 95.94,112.19 93.65,114.48 93.15,114.48 92.64,114.99 92.64,118.04
GND on VCC: outline of 765 points within 0.25,0.25 214.15,125.5
GND on IN2: outline of 304 points within 97.85,28.63 169.85,91.37
GND on IN3: 196.27,14.79 197.67,14.79 197.92,14.53 197.92,9.2 197.03,8.31 197.03,7.98 196.88,7.83 196.24,7.83 196.02,8.05 196.02,8.16 196.03,8.17 196.03,8.68 196.02,8.69 196.02,10.72 195.38,11.36 195.38,13.9
GND on GND2: outline of 327 points within 0.25,0.26 214.15,125.5
GNDA on IN2 (solid shape): outline of 866 points within 181.41,7.93 200.59,22.28
GNDA on TOP: 191.08,26.1 190.24,26.1 190,25.85 190,24.27 189.88,24.15 189.88,23.49 190.2,23.16 190.62,23.16 190.83,23.38 191.54,23.38 191.66,23.49 191.66,23.7 191.14,24.21 191.14,26.04
GNDA on TOP: 189.19,17.73 190.05,17.73 190.11,17.66 190.11,16.83 189.96,16.69 189.34,16.69 189.05,16.97 189.05,17.6
GNDA on GND1: 195.24,9.19 192.18,12.25 181.9,12.25 181.41,12.73 181.41,14.3 184.31,17.2 188.76,17.2 189.16,17.6 189.16,20.65 189.26,20.75 191.04,20.75 191.44,21.16 191.44,22.26 189.9,23.8 188.93,23.8 188.4,23.27 188.4,22.64 188.29,22.53 187.74,22.53 187.63,22.64 187.63,24.46 189.14,25.96 189.56,25.96 189.57,25.95 191.14,25.95 191.77,25.32 191.77,23.75 193.24,22.28 196.29,22.28 197.56,21.01 211.15,21.01 211.15,19.75 210.93,19.22 210.4,19.01 200.85,19.01 200.11,18.38 200.59,17.54 200.59,12.41 200.11,11.57 200.85,10.95 213.4,10.95 213.93,10.73 214.15,10.2 214.15,8.94 210.05,8.94 208.84,7.74 207.57,7.74 207.25,8.05 197.73,8.05 196.6,9.19
GNDA on VCC: 196.38,8.05 192.18,12.25 181.9,12.25 181.41,12.73 181.41,14.3 184.31,17.2 188.76,17.2 189.16,17.6 189.16,23.25 189.97,24.06 191.46,24.06 193.24,22.28 196.29,22.28 197.56,21.01 211.13,21.01 211.15,20.99 211.15,19.75 210.93,19.22 210.4,19 200.85,19 200.11,18.38 200.6,17.54 200.6,12.41 200.11,11.57 200.85,10.95 213.4,10.95 213.93,10.73 214.15,10.2 214.15,8.94 209.48,8.94 208.59,8.05
GNDA on GND2: 192.18,12.25 181.9,12.25 181.41,12.73 181.41,14.3 184.31,17.2 188.76,17.2 189.16,17.6 189.16,23.25 189.98,24.07 191.45,24.07 193.24,22.28 194.28,22.28 194.59,21.97 194.59,19.18 195.3,18.48 196.34,18.48 196.78,18.93 196.78,19.93 197.86,21.01 198.84,21.01 199.04,21.21 200.06,21.21 200.26,21.01 211.15,21.01 211.15,19.75 210.93,19.22 210.4,19.01 200.85,19.01 200.11,18.38 200.59,17.54 200.59,12.41 200.11,11.57 200.85,10.95 213.4,10.95 213.93,10.73 214.15,10.2 214.15,8.94 209.35,8.94 208.97,9.32 204.4,9.32 203.13,8.05 197.74,8.05 196.6,9.19 195.24,9.19
GNDA_CHG on TOP (solid shape): 34.6,16.81 34.6,11.58 34.12,11.58 34.09,11.6 34.09,12.52 32.31,12.52 31.69,11.9 31.26,11.9 31.02,11.66 31.02,10.87 30.76,10.62 30.03,10.62 29.9,10.75 29.9,11 30.54,11 30.54,11.51 29.9,11.51 29.9,12.02 30.28,12.4 30.79,12.4 30.92,12.52 30.92,16.08 31.04,16.21 31.3,16.21 31.68,16.59 33.86,16.59 34.09,16.82 34.6,16.82
(no net) on TOP: 54.41,27.87 55.88,27.87 55.99,27.97 55.99,29.03 55.78,29.24 54.77,29.24 54.16,28.63 54.16,28.12
(no net) on BOTTOM: 52.68,50.01 52.57,50.01 51.04,48.48 50.93,48.48 50.86,48.56 50.86,49.46 51.11,49.71 51.43,49.71 52,50.28 52,50.92 52.26,51.18 52.84,51.18 52.96,51.06 52.96,50.29
(no net) on IN3: 57.03,28.65 57.26,28.42 57.26,27.41 57,27.15 54.89,27.15 54.18,27.87 54.03,27.87 53.78,28.12 53.78,28.5 53.93,28.65
+1.35DGPU_B+ on TOP (solid shape): 42.85,50.62 42.85,48.29 42.55,47.98 41.15,47.98 40.92,47.75 40.92,47.04 40.86,46.98 38.66,46.98 38.47,47.17 38.47,49.9 39.11,50.54 40,50.54 40.42,50.95 42.52,50.95
+1.35DGPU_B+ on BOTTOM (solid shape): 40.42,50.6 41.99,50.6 42.37,50.22 42.37,49.81 42.12,49.56 41.18,49.56 40.82,49.2 40.82,47.68 40.57,47.42 39.55,47.42 39.35,47.63 39.35,50.62 39.48,50.75 40.26,50.75
+CHGRTC on BOTTOM (solid shape): 82.83,53.72 82.83,53.04 82.78,53 81.7,53 81.34,52.63 81.34,51.74 81.26,51.67 80.5,51.67 80.4,51.77 80.4,53.6 80.7,53.9 82.65,53.9
+CPU_CORE on TOP (solid shape): 84.19,122.58 84.19,117.46 82.16,115.43 82.16,114.99 81.65,114.48 81.65,113.07 81.56,112.98 79.46,112.98 79.07,112.6 77.56,112.6 77.56,112.59 75.52,114.63 75.52,122.19 76.12,122.79 83.99,122.79
+CPU_CORE on BOTTOM (solid shape): 84.19,122.61 84.19,117.4 82.41,115.62 82.41,115.43 81.65,114.67 81.65,113.27 81.39,113.01 78.39,113.01 78.38,112.99 76.76,114.61 76.76,117.3 79.44,117.3 79.44,118.09 76.76,118.09 76.76,118.81 75.52,120.06 75.52,122.2 76.1,122.79 84.01,122.79
+CPU_CORE on TOP: 96.44,104.57 102.54,104.57 102.8,104.83 102.8,105.72 102.29,106.23 97.79,106.23 97.51,106.5 97.51,107.85 97.32,108.04 96.4,108.04 96.12,107.76 96.12,104.89
+CPU_CORE on TOP: 102.42,102.29 102.8,101.91 102.8,100.89 102.54,100.64 96.17,100.64 95.51,101.29 94,101.29 93.87,101.42 93.87,102.49 94.03,102.65 95.6,102.65 95.96,102.29
+CPU_CORE on TOP: 96.04,97.36 99.88,97.36 100.13,97.11 100.13,94.66 99.97,94.5 96.16,94.5 95.94,94.72 95.94,97.26
+CPU_CORE on TOP, BOTTOM: 119.44,116.39 124.64,116.39 124.77,116.26 124.77,114.86 124.64,114.73 119.44,114.73 119.18,114.99 119.18,116.13
+CPU_CORE on BOTTOM: 96.63,104.57 102.54,104.57 102.8,104.83 102.8,105.72 102.29,106.23 96.68,106.23 96.37,105.92 96.37,104.83
+CPU_CORE on BOTTOM: outline of 565 points within 120.48,90.1 143.43,103.13
+CPU_CORE on BOTTOM: 96.55,102.29 102.42,102.29 102.8,101.91 102.8,100.89 102.54,100.64 96.55,100.64 96.37,100.81 96.37,102.11
+CPU_CORE on BOTTOM: 96.24,97.39 99.93,97.39 100.18,97.13 100.18,96.24 99.93,95.99 96.37,95.99 95.99,96.37 95.99,97.13
+CPU_CORE on VCC: 108.36,89.59 108.24,89.72 85.38,89.72 75.37,99.73 75.37,123.98 111.05,123.98 111.05,123.72 111.05,123.72 111.05,115.9 111.46,115.5 112.81,115.5 113.7,116.39 136.35,116.39 143.18,109.55 143.18,95.79 142.32,94.92 129.49,94.92 124.28,89.72 109.17,89.72 109.04,89.59
+CPU_CORE on IN2: 141.53,111.04 141.53,96.27 140.48,95.21 129.56,95.21 127.04,92.7 117.86,92.7 117.28,92.13 97.72,92.13 86.16,103.69 86.16,106.23 85.4,106.99 79.43,106.99 75.75,110.67 75.75,122.2 76.15,122.6 110.32,122.6 111.05,121.87 111.05,115.9 111.46,115.49 112.81,115.49 113.7,116.39 136.19,116.39
+CRT_VCC on IN1: 200.59,115.07 200.59,118.16 200.84,118.42 204.39,118.42 204.4,118.39 204.67,118.2 204.98,118.32 205.05,118.35 205.13,118.32 205.29,118.16 205.29,113.77 205.82,113.24 207.98,113.24 208.18,113.03 208.18,112.55 207.93,112.3 205.39,112.3 205.29,112.19 205.29,101.53 204.78,101.02 203,101.02 202.11,101.91 202.11,104.57 197.79,108.89 197.79,112.28
+DC_IN on TOP: 29.52,116.06 30.24,116.77 35.44,116.77 36.39,115.83 37.37,115.83 37.52,115.68 37.52,113.74 37.11,113.32 34.2,113.32 29.9,109.02 26.44,109.02 26.11,109.35 26.11,113.06 26.34,113.29 28.93,113.29 29.52,113.88
+DC_IN on BOTTOM: 26.73,110.54 26.47,110.8 26.47,113.27 26.97,113.77 30.36,113.77 30.72,113.41 30.72,110.96 30.3,110.54
+DC_IN on BOTTOM: 14.28,41.71 19.69,41.71 19.87,41.53 19.87,37.26 19.74,37.14 17.84,37.14 17.33,36.63 15.1,36.63 14.15,37.58 14.15,41.58
+DC_IN on VCC: outline of 120 points within 1.27,34.22 30.6,123.98
+DC_IN_SS on BOTTOM: 22.79,37.14 22.01,37.91 20.14,37.91 20.04,38.01 20.04,41.38 20.38,41.71 22.08,41.71 22.53,41.26 22.53,40.95 22.79,40.69 24.44,40.69 24.69,40.44 24.69,37.26 24.57,37.14
+DCIN on BOTTOM (solid shape): 40.19,18.65 40.19,18.22 40.19,18.22 40.19,17.11 40.09,17.01 35.53,17.01 34.26,15.73 33.8,15.73 33.74,15.79 33.74,16.56 33.8,16.62 34.2,16.62 34.6,17.02 34.6,18.06 34.91,18.37 38.12,18.37 38.54,18.79 40.06,18.79
+DCIN_JACK on IN1 (solid shape): 21,121.9 22.48,121.9 27.33,117.05 28.83,117.05 29.46,116.42 29.46,115.11 29.02,114.68 21.96,114.68 17.79,118.84 16.2,118.84 15.62,119.42 15.62,120.98 22.18,120.98 22.18,120.93 22.19,120.88 22.2,120.83 22.23,120.78 22.26,120.73 22.29,120.7 22.33,120.66 22.38,120.64 22.43,120.62 22.48,120.6 22.53,120.6 22.59,120.6 22.64,120.62 22.69,120.64 22.74,120.66 22.78,120.7 22.81,120.73 22.84,120.78 22.87,120.83 22.88,120.88 22.89,120.93 22.89,120.98 22.88,121.04 22.87,121.09 22.84,121.14 22.81,121.18 22.78,121.22 22.74,121.25 22.69,121.28 22.64,121.3 22.59,121.31 22.53,121.31 22.48,121.31 22.43,121.3 22.38,121.28 22.33,121.25 22.29,121.22 22.26,121.18 22.23,121.14 22.2,121.09 22.19,121.04 22.18,120.98 15.62,120.98 15.62,122.44 15.92,122.75 20.16,122.75
+DCIN_JACK on TOP: 26.16,116.64 27.81,116.64 27.82,116.64 29.11,116.64 29.22,116.52 29.22,114.32 28.94,114.03 26.28,114.03 25.95,114.37 25.95,116.44
+DCIN_JACK on TOP: 21.54,119.15 21.84,119.44 21.84,121.37 20.56,122.65 15.88,122.65 15.88,122.64 15.6,122.36 15.6,119.56 16.01,119.15
+DCIN_JACK on BOTTOM: 21.16,122.35 17.67,122.35 17.31,122.71 15.9,122.71 15.57,122.38 15.57,119.39 15.95,119.01 16.99,119.01 17.71,118.29 20.25,118.29 21.01,117.53 21.01,115.62 22.2,114.43 29.11,114.43 29.41,114.73 29.41,116.37 29.07,116.71 25.85,116.71 25.05,117.51 24.2,117.51 22.28,119.43 22.28,121.24
+DCIN_JACK on IN3: 21.93,114.71 17.83,118.8 16.21,118.8 15.48,119.53 15.48,122.42 15.71,122.66 19.93,122.66 20.68,121.91 22.46,121.91 27.24,117.13 28.83,117.13 29.34,116.63 29.34,115.1 28.95,114.71
+FB_PLLAVDD on IN1: 56.7,92.38 58.22,92.38 59.28,93.44 59.29,93.42 61.5,93.42 62.06,92.86 62.06,91.11 61.8,90.86 60.63,90.86 60.18,90.4 60.18,86.01 59.52,85.35 59.44,85.35 58.98,84.89 58.98,82.35 59.12,82.21 59.12,82.08 59.11,82.07 59.11,81.46 59.24,81.33 59.62,81.33 60,80.95 60,77.52 61.27,76.25 61.27,75.11 61.02,74.86 58.6,74.86 56.7,76.76 56.7,79.05 57.33,79.68 57.33,86.67 58.3,87.63 58.3,88.88 57.33,89.84 57.33,91.37 57.08,91.62 56.82,91.62 56.57,91.87 56.57,92.26
+FBA_VREF_CA0 on IN3: 33.08,104.45 33.86,104.45 34.4,103.91 34.4,100.18 33.71,99.49 33.71,97.59 34.47,96.83 34.47,95.43 34.09,95.05 32.19,95.05 31.93,95.3 31.93,96.83 31.55,97.21 31.55,102.92
+FBA_VREF_CA1 on IN3: 34.5,81.71 34.73,81.49 34.73,74.22 34.35,73.84 32.82,73.84 32.67,73.99 32.67,74.3 32.92,74.55 33.18,74.55 33.2,74.58 33.2,75.16 32.52,75.85 32.52,77.29 32.41,77.4 32.41,81.41 32.72,81.71
+FBA_VREF_DQ0 on IN3: 38.54,103.3 38.03,102.8 38.03,102.54 37.7,102.21 37.7,101.42 37.52,101.25 37.52,95.35 37.77,95.1 37.77,94.06 37.49,93.78 36.12,93.78 35.49,94.41 35.49,97.46 35.74,97.72 35.74,103.69 36.63,104.57 37.9,104.57 38.54,103.94
+FBA_VREF_DQ1 on IN3: 36.68,80.57 36.63,80.52 36.68,80.47 36.68,77.09 36.69,77.08 36.69,75.38 36.89,75.19 37.47,75.19 37.65,75.01 37.65,74.63 37.53,74.51 35.58,74.51 35.36,74.73 35.36,83.06 37.8,85.5 39.04,85.5 39.25,85.3 39.25,84.97 36.68,82.4
+GPU_CORE on TOP (solid shape): 70.16,66.86 70.16,57.2 69.52,56.57 58.09,56.57 55,59.67 55,61.75 53.98,62.77 53.98,68 54.08,68.1 54.08,68.51 54.21,68.63 55.17,68.63 55.43,68.38 55.43,68.2 55.63,68 56.77,68 56.9,68.13 56.9,68.48 57,68.58 57.92,68.58 58.04,68.46 58.04,68.15 58.2,68 59.39,68 59.47,68.07 59.47,68.48 59.59,68.61 60.48,68.61 60.61,68.48 60.61,68.2 60.81,68 61.95,68 62.06,68.1 62.06,68.38 62.29,68.61 63.05,68.61 63.15,68.51 63.15,68.23 63.38,68 64.44,68 64.65,68.2 64.65,68.48 64.9,68.73 68.28,68.73
+GPU_CORE on BOTTOM (solid shape): 65.87,68.46 65.87,68.39 67.52,66.74 67.61,66.74 67.62,66.73 69.52,66.73 69.78,66.47 69.78,65.46 69.14,64.82 69.14,61.39 70.03,60.51 72.32,60.51 72.83,60 72.83,58.09 71.68,56.95 57.74,56.95 54.61,60.07 54.61,66.02 53.98,66.65 53.98,67.77 54.18,67.97 54.18,68.51 54.26,68.58 55.22,68.58 55.38,68.43 55.38,68.18 55.55,68 56.8,68 56.95,68.15 56.95,68.48 57.05,68.58 57.89,68.58 58.04,68.43 58.04,68.18 58.25,67.97 59.34,67.97 59.47,68.1 59.47,68.46 59.59,68.58 60.48,68.58 60.61,68.46 60.61,68.2 60.81,68 61.88,68 62.06,68.18 62.06,68.43 62.21,68.58 63.05,68.58 63.22,68.4 63.22,68.13 63.38,67.97 64.52,67.97 64.67,68.13 64.67,68.48 64.88,68.68 65.64,68.68
+GPU_CORE on TOP: 67.86,91.89 67.91,91.84 67.91,91.49 68.74,90.67 68.74,89.77 69.04,89.47 69.04,89.33 69.4,88.96 69.4,88.45 69.27,88.32 68.89,88.32 68.76,88.19 68.76,87.81 69.02,87.56 69.02,87.51 69.27,87.51 70.13,86.64 70.13,82.5 69.63,81.99 68.41,81.99 68.34,82.06 68,81.71 63.5,81.71 63.02,81.23 62.26,81.23 61.52,81.97 60.76,81.97 60.51,81.71 60.18,81.71 59.82,81.36 59.29,81.36 59.11,81.54 59.11,82.48 59.16,82.53 59.16,83.31 59.01,83.47 59.01,84.3 59.64,84.94 59.64,90.3 60.13,90.78 66.22,90.78 66.25,90.81 66.25,91.19 66.4,91.34 66.88,91.34 67.06,91.52 67.06,92.13 67.21,92.28 67.8,92.28 67.86,92.22
+GPU_CORE on BOTTOM: 62.92,90.48 63.3,90.48 63.81,90.99 64.44,90.99 64.95,90.48 65.33,90.48 66.2,91.34 66.81,91.34 66.98,91.52 66.98,92 67.19,92.2 67.66,92.2 67.9,91.96 67.9,91.88 68.18,91.61 68.44,91.61 69.02,91.04 69.02,89.16 69.37,88.8 69.37,88.47 68.9,88 68.91,87.99 68.91,87.58 69.17,87.58 70.13,86.62 70.13,86.29 69.87,86.02 69.69,86.02 69.65,85.98 69.65,84.91 70.03,84.53 70.03,83.26 69.65,82.88 69.65,82.73 69.7,82.68 69.7,82.15 69.57,82.02 68.98,82.02 68.97,82.03 68.37,82.03 68.27,82.13 67.84,82.13 67.54,81.84 66.48,81.84 66.35,81.71 63.28,81.71 63.1,81.54 63.02,81.54 62.69,81.21 62.44,81.21 62.34,81.31 62.34,81.46 62.08,81.71 60,81.71 59.64,81.36 59.26,81.36 59.11,81.51 59.11,82.35 58.93,82.53 58.93,86.03 59.62,86.72 59.62,87.3 59.49,87.43 59.49,90.05 59.75,90.3 59.75,90.86 60.05,91.16 62.23,91.16
+GPU_CORE on IN1: 62.08,90.86 65.21,90.86 66.1,91.75 66.96,91.75 67.09,91.87 67.09,92.26 67.19,92.36 67.85,92.36 67.97,92.23 67.97,91.9 69.65,90.22 69.65,88.39 70.01,88.04 70.01,82.17 69.65,81.82 69.65,74.81 70.49,73.97 70.49,70.07 69.71,69.29 69.71,68.19 70.16,67.74 70.16,65.59 68.38,63.81 57.59,63.81 56.94,64.45 56.15,64.45 54.44,66.17 54.44,73.56 55.35,74.48 61.52,74.48 61.9,74.86 61.9,76.13 60.25,77.78 60.25,78.36 60.15,78.46 60.15,81.61 60,81.46 59.36,81.46 59.24,81.59 59.24,82.1 59.11,82.22 59.11,82.48 59.25,82.62 59.24,82.63 59.24,84.51 60.38,85.65 60.38,89.61 60.74,89.97 60.74,90.32 61.02,90.6 61.83,90.6
+GPU_CORE on VCC: 50.47,52.12 50.47,69.54 56.95,76.02 56.95,76.78 60.13,79.96 60.13,82.96 59.72,83.37 59.09,83.37 58.98,83.47 58.98,83.77 59.11,83.89 59.11,85.8 60.13,86.82 60.13,90.5 60.23,90.6 65.44,90.6 65.84,91.01 65.84,92.38 70.31,92.38 70.82,91.87 72.72,91.87 76.38,88.21 76.38,52.12
+GPU_CORE on IN2: 65.97,91.87 66.88,91.87 67.06,92.05 67.06,92.31 67.24,92.48 67.75,92.48 67.92,92.31 67.92,91.9 67.95,91.87 69.65,91.87 73.08,88.45 73.08,63.43 72.52,62.87 54.39,62.87 54.11,63.15 54.11,75.16 54.96,76.01 55.69,76.01 59.24,79.56 59.24,85.78 60.13,86.67 60.13,90.6 60.38,90.86 64.95,90.86
+INV_PWR_SRC on TOP: 3.74,75.36 3.61,75.24 1.96,75.24 1.71,75.49 1.71,82.51 1.93,82.73 3.61,82.73 3.74,82.61
+INV_PWR_SRC on BOTTOM: 4.62,79.7 4.62,81.26 4.31,81.57 2.66,81.57 2.4,81.32 2.4,79.82 2.86,79.36 4.28,79.36
+LAN_IO on TOP: 183.95,84.94 183.95,87.87 182.79,89.04 182.79,89.19 182.71,89.27 181.91,89.27 181.76,89.42 181.76,90.26 181.52,90.5 181.11,90.5 180.57,89.96 180.57,89.56 180.41,89.4 178.73,89.4 178.54,89.22 178.54,88.61 178.41,88.48 177.84,88.48 177.52,88.16 177.29,88.16 177.19,88.26 177.19,90.05 177.47,90.33 177.47,90.54 178.62,91.68 179.21,91.68 179.46,91.94 182.3,91.94 185.37,88.87 185.37,83.93 183.76,82.32 181.35,82.32 180.96,82.72 180.96,84.14 181.15,84.33 183.34,84.33
+LAN_IO on BOTTOM: 181.93,89.37 181.93,88.66 182,88.59 182.11,88.59 182.39,88.88 183.11,88.88 183.35,89.13 183.35,90.64 183.23,90.76 182.55,90.76 182.44,90.65 182.44,89.88
+LAN_IO on BOTTOM: 178.95,88.05 179,88 179,87.87 178.95,87.82 177.69,87.82 177.56,87.95 177.31,87.95 177.16,88.1 177.16,89.06 177.3,89.19 177.57,89.19 177.66,89.11 177.66,88.39 177.99,88.05
+LAN_VDD on TOP (solid shape): 178.41,88.19 178.41,86.82 178.36,86.76 177.85,86.76 177.65,86.96 177.56,86.96 177.16,87.37 177.16,87.62 177.58,88.04 177.69,88.12 177.76,88.23 177.81,88.27 178.33,88.27
+LAN_VDD on BOTTOM (solid shape): 183.87,85.45 183.87,85.04 183.8,84.97 182.78,84.97 182.29,85.46 182.29,85.57 182.35,85.64 183.68,85.64
+LAN_VDD on BOTTOM: 179.25,92.36 179.25,93.92 179.05,94.12 176.28,94.12 175.57,93.41 175.57,92.42 175.82,92.17 179.06,92.17
+LAN_VDD on IN1: 181.64,96.44 182.2,95.89 182.2,95.23 183.93,93.49 183.93,84.4 183.67,84.13 182.85,84.13 182.34,84.64 182.34,88.13 182.12,88.35 179.49,88.35 178.39,87.25 177.17,87.25 176.36,88.06 176.36,95.98 176.82,96.44
+LCDVDD on TOP: 11.99,85.65 11.74,85.91 11.74,86.81 11.9,86.98 13.77,86.98 14.35,87.56 14.35,89.33 14.67,89.64 16.36,89.64 16.61,89.4 16.61,86.32 16.21,85.92 15.34,85.92 15.07,85.65
+LCDVDD_CONN on TOP: 7.74,89.92 16.28,89.92 16.44,90.08 16.44,91.02 16.25,91.2 7.55,91.2 7.43,91.08 7.43,90.23
+LCDVDD_CONN on BOTTOM: 2.67,88.32 2.59,88.41 2.59,88.99 2.67,89.08 8.4,89.08 9.84,90.51 11.14,90.51 11.25,90.4 11.25,89.46 9.5,87.7 5.09,87.7 4.47,88.32
+PBATT on TOP: 20.5,34.06 20.5,28.96 20.71,28.75 25.6,28.75 26.22,29.37 26.22,35.36 25.84,35.74 22.03,35.74 21.52,35.23 21.52,34.47 21.39,34.34 20.79,34.34
+PBATT on BOTTOM: 20.76,35.74 26.09,35.74 26.47,35.36 26.47,31.3 25.96,30.79 20.38,30.79 20.38,35.36
+PWR_SRC_AC on BOTTOM (solid shape): 37.72,46.24 37.8,46.23 37.88,46.24 37.95,46.24 38.16,46.03 38.16,43.17 37.96,42.98 33.58,42.98 33.08,42.47 31.3,42.47 31.17,42.6 31.17,43.36 32.69,43.36 32.95,43.61 32.95,43.87 32.69,44.12 31.17,44.12 31.17,45.77 31.63,46.24
+SDC_IN on BOTTOM: 30.15,44.88 30.15,41.84 29.84,41.52 29.84,37.07 29.65,36.88 25.46,36.88 25.2,37.14 25.2,43.11 26.98,44.88
+VDISPLAY_VCC on TOP (solid shape): 203,64.38 203,62.79 202.87,62.66 200.84,62.66 199.95,61.78 199.95,57.33 199.32,56.7 199.32,53.14 198.18,52 195.51,52 195.38,52.12 195.38,54.03 195.64,54.28 196.65,54.28 197.29,54.92 197.29,61.52 197.41,61.65 197.92,61.65 198.3,62.03 198.3,62.92 198.43,63.05 198.94,63.05 199.57,63.68 200.33,63.68 201.16,64.51 202.87,64.51
-DCIN_JACK on TOP: 14.94,118.67 14.57,118.3 14.57,116.01 14.9,115.68 19.98,115.68 21.74,113.92 25.31,113.92 25.59,114.19 25.59,115.28 22.2,118.67
-DCIN_JACK on BOTTOM: 17.28,118.04 20.12,118.04 20.63,117.53 20.63,115.12 20.55,115.04 16.69,115.04 16.69,115.04 15.26,115.04 14.77,115.54 14.77,118.45 14.96,118.65 16.67,118.65
B+ on TOP (solid shape): 77.16,39.47 77.16,36.9 76.8,36.54 74.19,36.54 73.67,37.06 73.67,40.39 73.85,40.58 76.05,40.58
B+ on TOP (solid shape): 6.05,79.58 6.05,77.78 5.55,77.28 4.47,77.28 4.13,77.62 4.13,79.8 4.25,79.91 5.72,79.91
B+ on TOP (solid shape): 41.14,28.76 41.14,26.66 40.4,25.92 40.4,25.03 40.06,24.69 39.43,24.69 39.3,24.82 39.3,28.76 39.43,28.88 41.01,28.88
B+ on TOP (solid shape): 42.63,47.08 42.63,44.93 42.45,44.76 40.47,44.76 40.31,44.91 40.31,46.41 40.7,46.79 41.08,46.79 41.52,47.23 42.47,47.23
B+ on TOP (solid shape): 38.87,111.64 38.87,109.22 38.59,108.94 33.58,108.94 33.25,109.27 33.25,111.61 33.56,111.91 38.59,111.91
B+ on TOP (solid shape): 26.34,24.31 26.34,23.17 26.6,22.91 30.15,22.91 30.28,22.79 30.28,21.26 30.03,21.01 23.04,21.01 22.79,21.26 22.79,22.79 24.95,24.95 25.71,24.95
B+ on BOTTOM (solid shape): 94.75,111.85 94.75,110.65 94.58,110.48 92.45,110.48 92.23,110.7 92.23,112.05 92.36,112.18 94.42,112.18
B+ on BOTTOM (solid shape): 41.14,28.76 41.14,26.66 40.4,25.92 40.4,25.03 40.06,24.69 39.43,24.69 39.3,24.82 39.3,28.76 39.43,28.88 41.01,28.88
B+ on BOTTOM (solid shape): 49.34,114.64 49.34,107.63 49.11,107.41 45.45,107.41 43,109.86 34.55,109.86 34.15,110.25 34.15,114.84 34.82,115.51 48.47,115.51
B+ on BOTTOM (solid shape): 30.31,26.82 30.31,21.44 30,21.14 24.01,21.14 23.13,20.26 21.82,20.26 21.68,20.4 21.68,25.05 21.86,25.23 22.61,25.23 23.15,24.69 23.55,24.69 23.55,23.17 23.8,22.91 24.19,22.91 24.44,23.17 24.44,24.56 24.57,24.69 25.2,24.69 25.46,24.95 25.46,26.98 25.84,27.36 29.77,27.36
B+ on TOP: 93.15,115.88 94.54,115.88 94.92,115.5 94.92,112.5 93.41,110.99 92.35,110.99 92.19,111.15 92.19,111.94 92.77,112.51 92.77,115.5
B+ on BOTTOM: 75.7,37.14 76.9,37.14 77.12,37.36 77.12,39.51 75.79,40.83 73.59,40.83 73.31,40.55 73.31,37.78 73.6,37.49 75.34,37.49
B+ on IN1: 22.15,20.75 15.55,27.36 15.55,33.2 16.44,34.09 16.44,35.23 14.15,37.52 14.15,47.92 10.49,51.58 6.06,51.58 4.75,52.89 4.75,68.51 6.28,70.03 6.28,72.7 5.01,73.97 5.01,75.36 3.87,76.51 3.87,86.79 7.31,90.24 7.31,92.45 12.2,97.34 12.2,110.5 13.9,112.19 39.17,112.19 39.55,111.81 39.55,108.13 38.28,106.86 20.07,106.86 19.83,106.62 19.83,91.71 12.5,84.38 12.5,79.69 17.17,75.02 17.17,67.72 14.28,64.82 14.28,61.65 18.47,57.46 21.9,57.46 23.68,55.68 26.6,55.68 34.08,48.2 42.77,48.2 43.83,47.13 43.83,44.19 44.78,43.23 52.63,43.23 53.93,44.53 71.28,44.53 75.25,40.55 76.06,40.55 77.04,39.57 77.04,34.56 76.57,34.09 72.83,34.09 70.79,32.06 60.13,32.06 59.36,32.82 46.79,32.82 44.31,30.34 42.92,30.34 41.33,28.76 41.33,24.82 40.95,24.44 36.76,24.44 33.08,20.75
B+ on VCC: 23.02,20.88 22.79,21.11 22.79,22.43 23.17,22.81 23.17,26.24 23.55,26.62 23.55,28.86 23.17,29.24 23.17,33.71 25.81,33.71 26.47,34.36 26.47,49.31 15.3,60.48 15.3,101.93 21.5,108.13 27.28,108.13 31.15,112 31.15,116.32 31.47,116.64 38.43,116.64 39.17,115.9 39.17,108.26 35.76,108.26 34.6,107.09 34.6,106.33 33.4,105.13 25.78,97.46 25.71,76.66 29.39,72.97 29.39,58.49 31.7,56.19 49.97,56.19 49.97,52.12 41.1,52.12 39.04,50.07 39.04,41.1 40.7,39.44 40.7,32.33 41.2,31.82 41.2,22 40.08,20.88
B+ on IN3: 33.84,109.53 33.2,110.16 33.2,112.78 39.65,119.23 52.68,119.23 56.61,123.16 68.26,123.16 71.23,120.2 90.33,120.2 92.21,118.32 93.98,118.32 96.05,116.25 96.05,115.23 95.31,114.48 95.31,112.07 93.65,110.42 92.07,110.42 91.81,110.67 91.81,112.44 87.48,116.77 73.26,116.77 71.89,115.39 66.91,115.39 64.38,112.87 58.59,112.87 56.09,115.37 44.51,115.37 38.66,109.53
B+_1.05V on BOTTOM (solid shape): 96.64,116.53 96.05,115.94 96.05,112.64 95.79,112.38 93.21,112.38 92.77,112.83 92.77,115.56 93.15,115.94 94.08,115.94 94.33,116.19 94.33,117.78 94.46,117.91 95.04,117.91 95.73,118.59 96.64,118.59
BAT_B+ on TOP (solid shape): 22.92,28.12 22.92,24.06 22.79,23.93 21.77,23.93 21.65,24.06 21.65,28.12 21.77,28.25 22.79,28.25
BAT_B+ on BOTTOM (solid shape): 26.09,30.03 26.09,27.99 25.2,27.1 25.2,25.71 25.07,25.58 24.57,25.58 24.44,25.71 24.44,27.23 24.19,27.49 23.8,27.49 23.55,27.23 23.55,25.71 23.3,25.45 21.77,25.45 21.65,25.58 21.65,27.49 21.77,27.61 21.9,27.61 22.79,28.5 22.79,30.15 22.92,30.28 25.84,30.28
BOOT_1.35V on BOTTOM (solid shape): 62.34,31.96 62.51,31.96 62.53,31.94 63.06,31.94 63.3,31.7 63.3,30.91 63.17,30.79 62.29,30.79 61.9,31.17 61.9,31.55 61.57,31.88 61.32,31.88 61.08,32.12 59.92,32.12 59.86,32.18 59.86,32.25 59.93,32.32 60.91,32.32 60.95,32.36 61.93,32.36
BST_1.05V on TOP (solid shape): 95.64,121.44 95.64,119.93 95.58,119.88 95.2,119.88 95.13,119.95 95.13,120.39 94.85,120.66 94.85,121.53 94.97,121.66 95.42,121.66
BST_1.05V on BOTTOM (solid shape): 95.48,121.74 95.48,120.58 96.12,119.93 96.12,119.39 96.05,119.31 95.71,119.31 95.53,119.49 95.53,119.75 94.9,120.38 94.71,120.38 94.59,120.51 94.59,121.72 94.74,121.88 95.33,121.88
BST_3V on TOP (solid shape): 51.43,32.25 51.43,30.79 51.49,30.72 51.49,29.58 51.43,29.52 51.36,29.52 51.24,29.64 51.24,30.72 50.47,31.49 50.47,32.25 50.54,32.31 51.36,32.31
